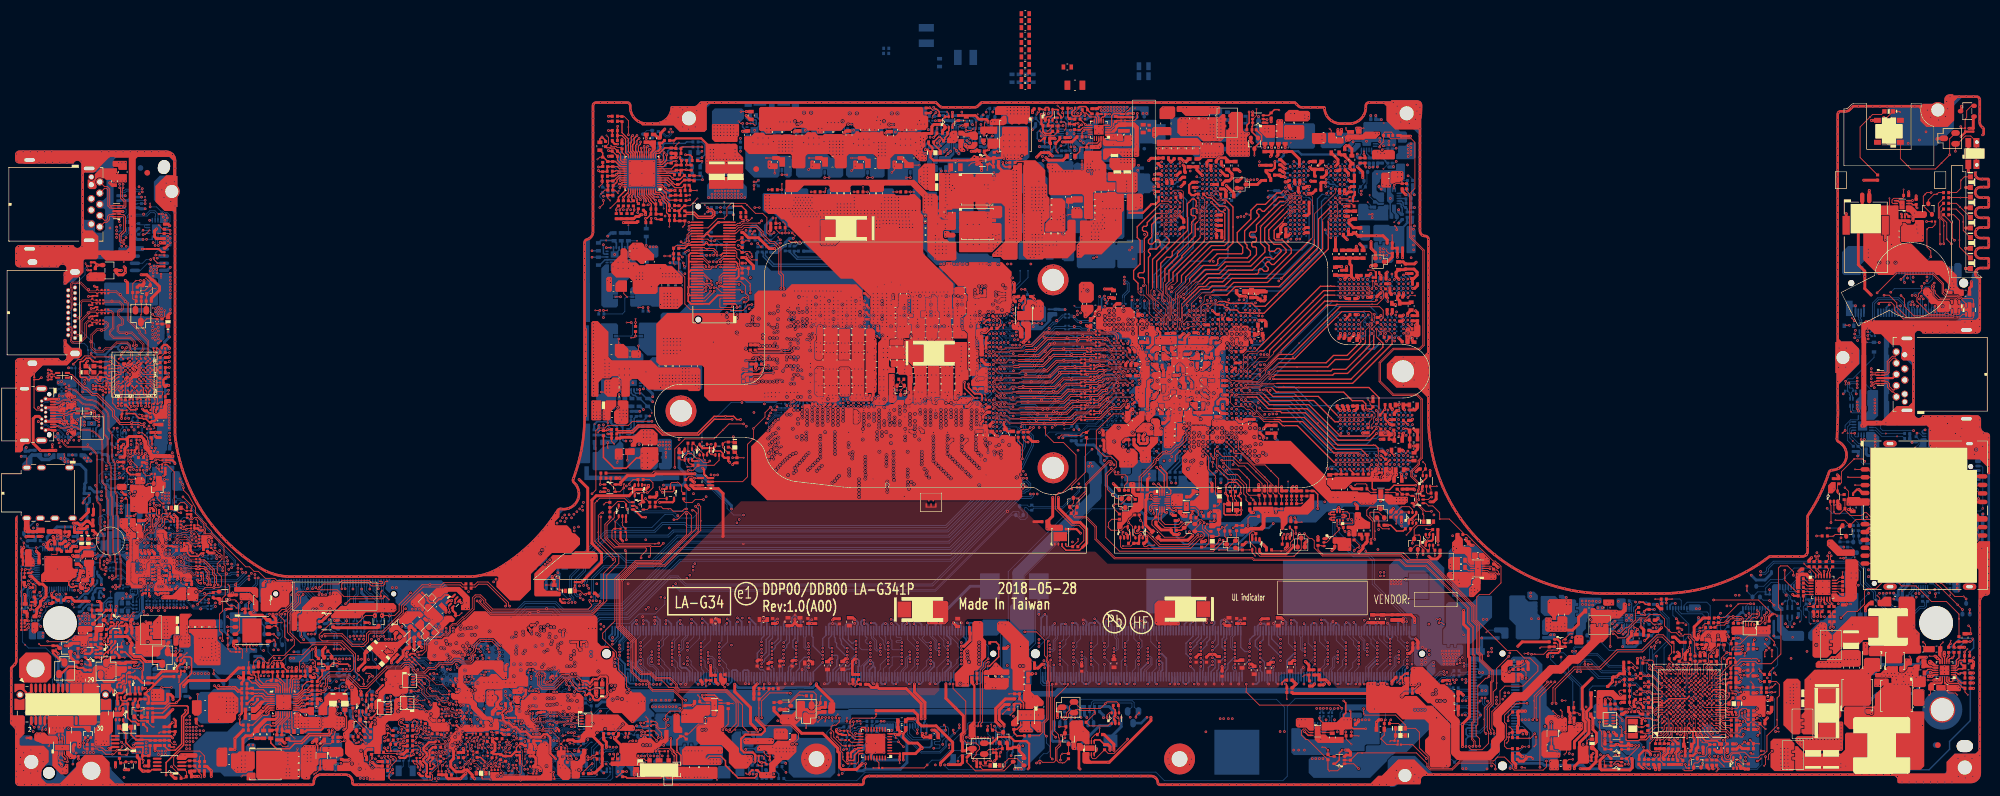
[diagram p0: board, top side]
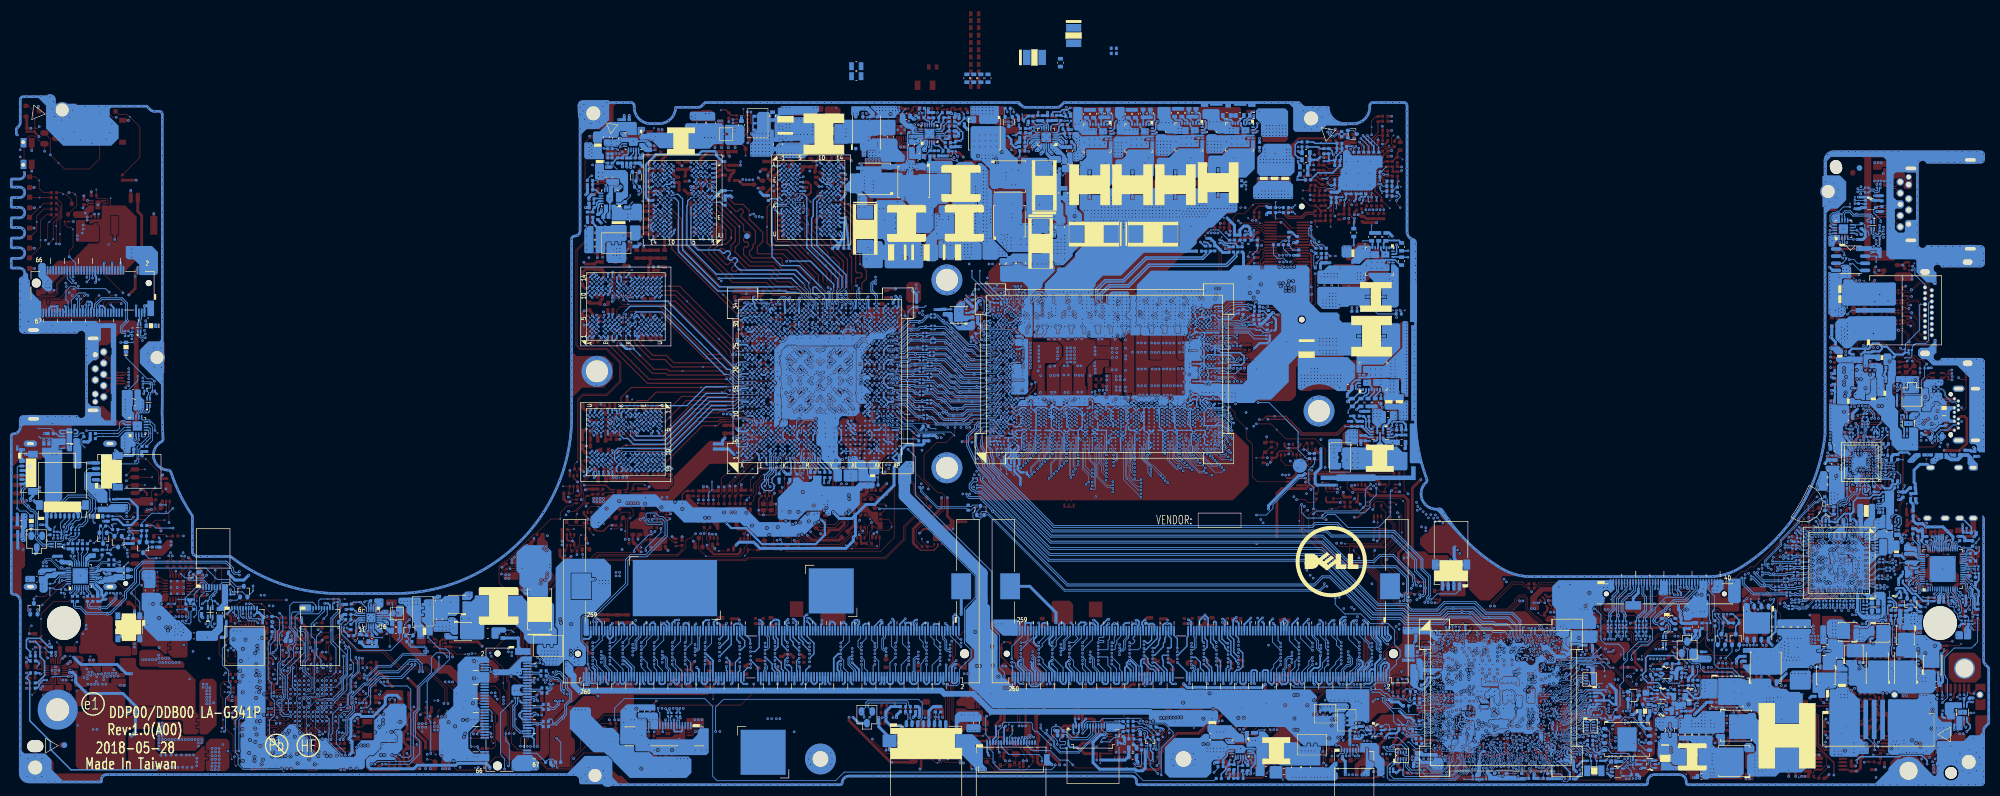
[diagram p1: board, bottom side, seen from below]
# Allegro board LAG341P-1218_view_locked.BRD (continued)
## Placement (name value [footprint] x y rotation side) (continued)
T20  -  [TPC12]  77.86 69.33 180 bottom
T39  -  [TPC12]  174.4 126.55 0 top
T40  -  [TPC12]  173.39 127.36 0 top
T41  -  [TPC12]  173.16 125.81 0 top
T42  -  [TPC12]  174.29 125.24 0 top
T43  -  [TPC12]  135.05 125.9 0 top
T44  -  [TPC12]  135.19 127.26 0 top
T45  -  [TPC12]  136.36 151.48 0 top
T46  -  [TPC12]  170.68 141.56 0 top
T47  -  [TPC12]  172.59 143.86 0 top
T48  -  [TPC12]  136.5 149.88 0 top
T49  -  [TPC12]  138.35 151.15 0 top
T50  -  [TPC12]  167.5 148.13 0 top
T51  -  [TPC12]  165.93 134.73 0 top
T52  -  [TPC12]  157.14 146.38 0 top
T53  -  [TPC12]  160.37 135.4 0 top
T57  -  [TPC12]  171.63 148.98 0 top
T58  -  [TPC12]  177.98 148.42 180 bottom
T59  -  [TPC12]  176.17 150.56 0 top
T60  -  [TPC12]  174.71 148.38 0 top
T61  -  [TPC12]  171.97 126.27 0 top
T62  -  [TPC12]  171.93 127.56 0 top
T63  -  [TPC12]  131.08 152.93 180 bottom
T64  -  [TPC12]  136.35 148.56 0 top
T65  -  [TPC12]  140.96 149.01 0 top
T66  -  [TPC12]  138.68 147.29 0 top
T67  -  [TPC12]  139.74 146.31 0 top
T82  -  [TPC12]  139.59 148.68 0 top
T83  -  [TPC12]  154.81 131.58 0 top
T84  -  [TPC12]  171.4 136.56 0 top
T85  -  [TPC12]  177.7 158.59 180 bottom
T86  -  [TPC12]  172.91 122.41 180 bottom
T87  -  [TPC12]  133.81 126.38 0 top
T88  -  [TPC12]  133.86 125.09 0 top
T89  -  [TPC12]  179.1 158.59 180 bottom
T90  -  [TPC12]  173.89 123.23 180 bottom
T91  -  [TPC12]  66.57 87.33 180 bottom
T92  -  [TPC12]  67.98 88.24 180 bottom
T94  -  [TPC12]  66.09 89.51 180 bottom
T121  -  [TPC12]  88.06 76.46 0 top
T124  -  [TPC12]  79.9 71.7 0 top
T185  -  [TPC12]  17.46 119.85 0 bottom
T191  -  [TPC12]  22.73 119.21 0 bottom
T192  -  [TPC12]  22.56 120.5 0 bottom
T193  -  [TPC12]  19.89 125.7 180 top
T194  -  [TPC12]  20.57 123.59 180 top
T196  -  [TPC12]  29.07 111.19 0 top
T197  -  [TPC12]  27.76 111.49 0 top
T198  -  [TPC12]  26.45 111.56 0 top
T199  -  [TPC12]  30.94 109.44 0 top
T201  -  [TPC12]  182.22 129.24 180 bottom
T202  -  [TPC12]  184.06 129.44 180 bottom
T203  -  [TPC12]  190.2 133.04 180 bottom
T204  -  [TPC12]  189.6 131.81 180 bottom
T205  -  [TPC12]  214.86 128.54 0 top
T210  -  [TPC12]  210.62 112.79 0 top
T4936  -  [TPC12]  25.07 135.23 0 top
T4937  -  [TPC12]  23.71 135.76 0 top
T4943  -  [TPC12]  67.22 91.56 180 bottom
T4944  -  [TPC12]  67.22 90.25 180 bottom
T4945  -  [TPC12]  82.07 72.32 0 top
T4947  -  [TPC12]  80.12 78.26 0 top
T4948  -  [TPC12]  294.32 80.37 180 bottom
T4949  -  [TPC12]  101.78 76.21 180 bottom
T4950  -  [TPC12]  90.17 87.04 0 top
T4951  -  [TPC12]  91.49 87.23 0 top
T4952  -  [TPC12]  95.61 87.41 0 top
T4953  -  [TPC12]  91.94 84.22 0 top
T4954  -  [TPC12]  90.68 84.56 0 top
T4955  -  [TPC12]  79.2 85.92 0 top
T4956  -  [TPC12]  80.49 85.97 0 top
T4957  -  [TPC12]  83.26 87.29 0 top
T4958  -  [TPC12]  81.79 86.76 0 top
T4959  -  [TPC12]  90.22 80.28 0 top
T4960  -  [TPC12]  91.08 81.26 0 top
T4961  -  [TPC12]  101.5 74.69 180 bottom
T4962  -  [TPC12]  80.39 83.29 0 top
T4963  -  [TPC12]  80.31 84.6 0 top
T4964  -  [TPC12]  90.73 85.87 0 top
T4965  -  [TPC12]  152.49 136.37 0 top
T4966  -  [TPC12]  152.65 146.61 0 top
T4967  -  [TPC12]  147.6 134.68 0 top
T4968  -  [TPC12]  145.67 135.03 0 top
T4969  -  [TPC12]  149.43 134.75 0 top
T4970  -  [TPC12]  146.82 135.74 0 top
T4971  -  [TPC12]  137.67 148.15 0 top
T4972  -  [TPC12]  134.49 149.03 0 top
T4973  -  [TPC12]  209.47 127.53 0 top
T4974  -  [TPC12]  209.03 123.04 180 bottom
T4975  -  [TPC12]  211.51 130.19 0 top
T4976  -  [TPC12]  208 124.62 0 top
T4977  -  [TPC12]  209.11 121.63 180 bottom
T4978  -  [TPC12]  209.47 129.16 0 top
T4979  -  [TPC12]  211.63 126 0 top
T4980  -  [TPC12]  205.3 124.71 0 top
T4982  -  [TPC12]  296.35 75.34 0 top
T4988  -  [TPC12]  85.55 77.73 0 top
T4989  -  [TPC12]  86.45 75.16 0 top
T4991  -  [TPC12]  197.02 146.11 0 top
T4992  -  [TPC12]  195.64 146.23 0 top
T4993  -  [TPC12]  198.12 135.17 0 top
T4994  -  [TPC12]  199.44 144.65 0 top
T4995  -  [TPC12]  208.04 126.51 0 top
T4996  -  [TPC12]  207.77 128.83 0 top
T5003  -  [TPC12]  86.86 80.18 90 top
T5004  -  [TPC12]  85.67 79.43 0 top
T5990  -  [TPC12]  74 86.84 0 top
T5991  -  [TPC12]  89.59 72.99 0 top
T5992  -  [TPC12]  89.41 78.08 0 top
T5994  -  [TPC12]  65.13 103.32 0 top
T5995  -  [TPC12]  63.8 103.32 0 top
T5996  -  [TPC12]  311.45 89.93 0 top
T5997  -  [TPC12]  310.18 89.93 0 top
T5998  -  [TPC12]  310.18 92.22 0 top
T5999  -  [TPC12]  311.71 87.9 0 top
T6000  -  [TPC12]  296.34 78.44 180 bottom
T6002  -  [TPC12]  85.52 73.81 0 top
T6003  -  [TPC12]  269.16 73.93 0 top
T6004  -  [TPC12]  273.86 80.41 0 top
TV3  -  [TPC12]  232.63 176.79 0 top
TV4  -  [TPC12]  206.13 177.12 0 top
TV5  -  [TPC12]  247.95 154.17 0 top
TV6  -  [TPC12]  246.29 126.07 0 top
U32  -  [NPCT750JAAYX_QFN32_5X5]  154.49 72.69 180 top
U33  -  [SLG4U41821VTR_STQFN20_2X3]  201.85 118.79 0 top
UA1  -  [ALC3266-CG_QFN56_7X7]  9 101.97 90 bottom
UA3  -  [APE8937GN2_DFN8_2X2]  3.6 78.93 180 bottom
UA4  -  [EM5209VF_DFN14_3X2]  6.05 72.74 0 top
UC1  -  [74AUP1G07GW_TSSOP5]  122.61 120.4 90 top
UE2  -  [AH1806-W-7_SC59-3]  345.01 186.97 90 top
UE3  -  [MEC5105_WFBGA_169P]  291.92 77.26 90 top
UE5  -  [74AUP1G07SE-7_SOT353-5]  304.58 70.06 0 top
UE6  -  [APE8937GN2_DFN8_2X2]  189.37 72.53 0 top
UE7  -  [74AUP1G07SE-7_SOT353-5]  120.69 125.81 0 top
UF1  -  [LNG2DMTR_LGA12_2X2]  235.13 114.19 180 top
UH1  -  [CFL-H_BGA_1440P-T]  175.85 126.93 270 bottom
UH2  -  [CNP-H_BGA_874P-T]  96.83 93.91 180 bottom
UH7  -  [MC74VHC1G08DFT2G_SC70-5]  65.2 70 270 bottom
UH8  -  [W25Q256FVEIG_WSON8]  66.54 77.11 270 bottom
UH14  -  [MC74VHC1G08DFT2G_SC70-5]  57.53 70.13 90 bottom
UI1  -  [TPS2546RTER_QFN16_3X3]  24.8 164.46 180 bottom
UI2  -  [TPS2546RTER_QFN16_3X3]  328.33 129.41 180 bottom
UI3  -  [PS8713BTQFN24GTR2_TQFN24_4X4]  318.44 103.48 270 top
UI4  -  [MC74VHC1G32DFT2G_SC70-5]  19.23 170.45 270 bottom
UI5  -  [MC74VHC1G32DFT2G_SC70-5]  322.48 118.45 0 top
UM1  -  [PS175HDMBGA64GTR2-A0_TFBGA_64P]  22.92 137.3 180 top
UM2  -  [W25X20CLSNIG_SO8]  25.37 162.45 270 bottom
UN3  -  [APE8937GN2_DFN8_2X2]  335.7 169.55 90 top
UR1  -  [RTS5242-GR_QFN32_4X4]  339.14 102.24 90 bottom
UT1  -  [ALPINE-RIDGE_BGA_337P]  19.74 111.65 270 bottom
UT2  -  [W25Q80DVZPIG_WSON8]  37.39 98.85 0 bottom
UT4  -  [TPS65982_BGA_96P]  18.38 122.07 0 bottom
UT5  -  [W25Q80DVZPIG_WSON8]  38.07 96.46 270 top
UV16  -  [AP2330W-7_SC59-3]  16.87 158.64 270 top
UV18  -  [N15P-GT_BGA_908P]  219.8 125.29 90 bottom
UV19  -  [MC74VHC1G08DFT2G_SC70-5]  224.38 111.02 0 top
UV20  -  [TC7SH08FU_SSOP5]  195.54 111.12 0 top
UV23  -  [H5GQ1H24AFR-T2L_BGA_170P]  225.38 164.77 0 bottom
UV24  -  [H5GQ1H24AFR-T2L_BGA_170P]  212.92 177.57 180 bottom
UV25  -  [H5GQ1H24AFR-T2L_BGA_170P]  234.28 133.3 270 bottom
UV26  -  [H5GQ1H24AFR-T2L_BGA_170P]  247.08 147.03 90 bottom
UV28  -  [MC74VHC1G08DFT2G_SC70-5]  170.02 178.8 270 top
UV29  -  [TC7SH08FU_SSOP5]  220.28 110.82 180 top
UZ1  -  [EM5209VF_DFN14_3X2]  260.15 104.41 90 top
UZ4  -  [APE8937GN2_DFN8_2X2]  54.2 73.44 180 top
UZ5  -  [APE8937GN2_DFN8_2X2]  338.56 128.11 90 bottom
UZ6  -  [MC74VHC1G32DFT2G_SC70-5]  234.49 71.52 90 top
UZ8  -  [SY6288C20AAC_SOT23-5]  53.08 97.11 270 top
UZ9  -  [TPS22961DNYR_WSON8]  180.12 149.77 90 bottom
UZ12  -  [MC74VHC1G08DFT2G_SC70-5]  116.12 119.96 180 top
UZ15  -  [TPS22961DNYR_WSON8]  179.33 151.96 180 top
UZ16  -  [TPS22961DNYR_WSON8]  183.86 109.92 0 top
UZ19  -  [MC74VHC1G08DFT2G_SC70-5]  118.02 124.93 0 top
UZ20  -  [MC74VHC1G08DFT2G_SC70-5]  110.43 120.47 180 top
UZ21  -  [MC74VHC1G08DFT2G_SC70-5]  108.77 117.4 270 top
UZ22  -  [MC74VHC1G08DFT2G_SC70-5]  123.48 125.81 0 top
UZ23  -  [MC74VHC1G08DFT2G_SC70-5]  103.75 120.56 270 top
UZ24  -  [APE8937GN2_DFN8_2X2]  206.16 117.37 270 top
UZ25  -  [APE8937GN2_DFN8_2X2]  11.75 132.51 0 bottom
UZ26  -  [MC74VHC1G08DFT2G_SC70-5]  106.28 114.92 0 top
UZ29  -  [APE8937GN2_DFN8_2X2]  124.38 80.66 90 top
UZ30  -  [APE8937GN2_DFN8_2X2]  242.96 118.14 90 top
UZ31  -  [MC74VHC1G08DFT2G_SC70-5]  249.41 117.22 90 top
UZ32  -  [APE8937GN2_DFN8_2X2]  273.22 77.38 180 top
UZ33  -  [APE8937GN2_DFN8_2X2]  229.52 77.41 270 top
YE1  -  [Y_CM7V-12520_2P]  286.69 75.86 90 top
YH1  -  [Y_CM31532768DZFT_2P]  67.13 69.61 0 bottom
YH2  -  [Y_8Y24000034_4P]  103.34 83.65 90 top
YM1  -  [Y_8Y24000034_4P]  11.5 140.51 0 top
YT1  -  [Y_8Y24000034_4P]  18.97 99.46 270 bottom
YV1  -  [Y_8Y24000034_4P]  216.21 117.08 180 top

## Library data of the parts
ADP100 = ACES_50290-00701-001_7P-T
BAT100 = ACES_50290-01201-P01_12P-T
C2 C4 C135 C280 C1031 C1080 C3003 C3004 C3319 CA1 CA3 CA5 CA8 CA10 CA12 CA16 CA17 CA19 CA23 CA24 CA26 CA28 CA32-CA38 CA40 CA120-CA122 CA124-CA127 CA130 CD3324 CD3325 CE75 CE84 CE85 CH200 CH203-CH205 CH207 CH3320-CH3324 CH3329 CH3331-CH3333 CM1 CM3-CM8 CM10-CM22 CM24-CM26 CM28-CM33 CM35 CM37-CM41 CM45 CM46 CM50 CT25 CT141-CT143 CT145 CT163 CT174-CT187 CV818-CV849 CV857 CV858 CV925 CV928 CV987 CV990 CZ100 CZ101 CZ2157 PC218 PC221 PC502 PC505 PC902 PC1601 PC2004-PC2009 PC2029-PC2038 PC2042-PC2085 = C_0201
C3 C267 C1033 C1079 C3005 C3320 C3321 CA2 CA4 CA6 CA7 CA9 CA11 CA13-CA15 CA18 CA20 CA21 CA25 CA27 CA29-CA31 CA39 CA41-CA45 CA77 CA78 CA119 CA128 CA129 CA131 CD3326-CD3328 CE2 CE72-CE74 CE77-CE82 CE1501 CE3319 CE3321-CE3323 CH92 CH201 CH202 CH206 CH3327 CH3334 CI3-CI8 CI16 CI20-CI22 CM2 CM9 CM23 CM27 CM34 CM43 CM44 CT144 CT146 CT151 CT152 CT158-CT160 CT189 CV499 CV794 CV796 CV817 CV850-CV856 CV859 CV860 CV862 CV865 CV866 CV871 CV874-CV877 CV885-CV894 CV898-CV906 CV917-CV923 CV926 CV927 CV929-CV936 CV948-CV957 CV969-CV986 CV988 CV989 CV991-CV998 CV1010-CV1019 CV1031-CV1048 CV1050 CV1051 CZ96-CZ99 CZ104-CZ106 CZ588 CZ1501 CZ2155 CZ2156 PC106-PC110 PC114 PC115 PC200 PC204-PC210 PC212-PC217 PC219 PC222 PC223 PC401-PC405 PC407 PC408 PC415 PC416 PC418 PC500 PC501 PC506 PC511 PC512 PC603 PC604 PC609 PC612-PC614 PC700 PC701 PC704-PC707 PC709-PC716 PC725 PC800 PC801 PC804-PC806 PC810 PC900 PC901 PC905 PC906 PC911 PC912 PC1003-PC1005 PC1015 PC1017 PC1018 PC1030-PC1041 PC1045 PC1046 PC1049 PC1050 PC1054 PC1055 PC1100-PC1131 PC1133-PC1137 PC1205-PC1207 PC1209 PC1222 PC1225 PC1226 PC1233 PC1234 PC1251 PC1252 PC1258 PC1262 PC1263 PC1269 PC1501 PC1504 PC1508 PC1510 PC1511 PC1515-PC1518 PC1520 PC1522 PC1531 PC1532 PC1600 PC1603 PC1605 PC1606 PC1611 PC1612 PC1701 PC1702 PC1704 PC1709 PC1710 PC1714 PC1800 PC1802 PC1804 PC1910-PC1912 PC1923-PC1925 PC1927 PC1928 PC1932-PC1945 = C_0402
CD1-CD4 CD12 CD16-CD18 CD69 CD74-CD79 = C_0402: room: DIMMA
CD5-CD10 CD13-CD15 CD70-CD73 = C_0603: room: DIMMA
CD11 = C_EEFSS0D221R: room: DIMMA
CD19-CD22 CD29-CD32 CD34 CD35 CD80-CD83 = C_0402: room: DIMMB
CD23-CD28 CD84-CD90 = C_0603: room: DIMMB
CD33 = C_EEFSS0D221R: room: DIMMB
CD36 = C_0603: room: NGFF SSD
CD37-CD46 CD51 CD53 = C_0402: room: NGFF SSD
CE11 = C_0201: room: TPM
CE15 CE16 = C_0201: room: LID
CE17 CE18 CE20 CE23-CE27 CE29-CE39 CE42 CE44 CE48 CE51 CE70 CE71 = C_0402: room: EC5085
CE19 CE22 CE40 = C_0603: room: EC5085
CE41 CE45-CE47 CE49 CE50 CE52 CE68 CE69 = C_0402: room: THERMAL
CE43 = C_0201: room: EC5085
CE65 = C_0402: room: TOUCH PAD
CE66 CE67 = C_0402: room: FAN
CE76 CE83 CT147-CT150 CT153 CT157 CT164 CT165 CT188 CV798 CV861 CV863 CV864 CV867-CV870 CV872 CV873 CV878-CV884 CV895-CV897 CV907 CV924 CV937-CV947 CV958-CV968 CV999-CV1009 CV1020-CV1030 CZ2154 PC201 PC202 PC211 PC220 PC335 PC400 PC406 PC409-PC411 PC414 PC417 PC419 PC503 PC504 PC513 PC600-PC602 PC605-PC607 PC610 PC611 PC615 PC702 PC703 PC708 PC723 PC724 PC802 PC803 PC807-PC809 PC903 PC904 PC913 PC1006-PC1014 PC1016 PC1022-PC1029 PC1047 PC1048 PC1051-PC1053 PC1056-PC1070 PC1132 PC1208 PC1210 PC1216 PC1217 PC1227-PC1230 PC1257 PC1259-PC1261 PC1268 PC1270-PC1272 PC1502 PC1503 PC1507 PC1512-PC1514 PC1519 PC1521 PC1523-PC1528 PC1602 PC1604 PC1607-PC1610 PC1613 PC1705-PC1708 PC1713 PC1715-PC1717 PC1801 PC1803 PC1900-PC1908 PC1913-PC1922 PC1926 PC1929-PC1931 PC2000 PC2003 PC2010 PC2012-PC2018 PC2021-PC2027 PC2039-PC2041 PC2086-PC2153 = C_0603
CF1 = C_0603: room: HDD FFS
CF2 = C_0402: room: HDD FFS
CH3 CH100 CH101 CH174 CH175 CH197 CZ47 CZ49 CZ82 CZ86 CZ88 = C_0402: room: CPU
CH5-CH36 = C_0201: room: CPU
CH44 CH196 = C_0201: room: RTC
CH45-CH48 CH50 CH51 CH70 CH80 CH82 CH179 CH180 CH183 CH187-CH192 = C_0201: room: PCH
CH52 CH53 CH176-CH178 CH181 CH182 CH184 CH198 = C_0402: room: PCH
CH102-CH128 = C_0402: room: CPU_DECAP
CH129-CH132 CH134 CH135 = C_0603: room: CPU_DECAP
CH133 = C_0201: room: CPU_DECAP
CH136 CH138 = C_0805: room: CPU_DECAP
CI1 CI13 = C_0402: room: USB1
CI2 CI19 = C_0402: room: USB2
CI9 CI10 = C_0201: room: USB1
CI11 = C_0805: room: USB1
CI12 = C_0603: room: USB1
CI17 = C_0805: room: USB2
CI18 = C_0603: room: USB2
CLRP1 = SHORTPADS: User Part Number: PART#; room: PCH
CN1 CN6 = C_0603: room: NGFF WLAN
CN2 CN7 CN8 CN22 = C_0402: room: NGFF WLAN
CN9 CN20 CN21 = C_0201: room: NGFF WLAN
CR1 CR2 CR5 CR8 CR11 CR15 = C_0201: room: CARD READER
CR3 CR7 CR9 CR10 CR12 CR13 CR16 CR18 = C_0402: room: CARD READER
CR4 CR6 CR14 CR17 = C_0603: room: CARD READER
CS12-CS14 = C_0402: room: HDD
CS15 = C_0603: room: HDD
CS17-CS20 = C_0201: room: HDD
CT1-CT8 CT17-CT24 CT26 CT29-CT44 CT47 CT50 CT52 CT62-CT68 CT71 CT72 CT74 CT80-CT86 CT93 CT94 CT99-CT103 CT107 CT108 = C_0201: room: THUNBERBOLT
CT53-CT56 CT95-CT98 CT120-CT123 = C_0402: room: THUNBERBOLT
CT88-CT90 = C_0603: room: THUNBERBOLT
CV156 CV168 CV169 = C_0402: room: EDP
CV157 = C_0603: room: EDP
CV158-CV167 = C_0201: room: EDP
CV178 CV180-CV182 = C_0201: room: HDMI
CV179 = C_0402: room: HDMI
CV183 CV184 = C_0402: room: CAMERA
CZ4 CZ6 CZ8 CZ9 CZ11 CZ12 = C_0603: room: 3V_5V_DC_DC
CZ18-CZ20 = C_0402: room: PCH_DC_DC
CZ26 CZ29 CZ31 = C_0402: room: CAMERA_CR_DC_DC
CZ28 = C_0402: room: CPU_DC_DC
CZ37 CZ39 = C_0603: room: HDD_DC_DC
CZ41 = C_0201: room: EDP_DC_DC
CZ43 CZ44 = C_0402: room: EDP_DC_DC
CZ45 CZ46 = C_0402: room: HDD_DC_DC
D18 D74 = ESD101-B1-02ELS_TSSLP-2-4-2
D123 D124 D323 D324 = ESD8011MUT5G_X3DFN2-2
D125 D126 DT175-DT182 = AZ5B25-01F_DFN0603P2Y2
D321 DA56 DA57 DH1 DH2 DI1 DI14-DI16 DT28 DT29 DV14 DV15 DZ59 = RB751S40T1G_SOD523-2
D322 DA7 DA14 PD100 = AZ5125-01HPR7G_SOD523-2
DA2-DA5 DA9 = AZ5123-01FPR7G_DFN1006P2X2
DE4 DE5 = PESD5V0U2BT_SOT23-3: room: TOUCH PAD
DE7 DE8 = RB751S40T1G_SOD523-2: room: FAN
DE9 PD101 PD102 = TVNST52302AB0_SOT523-3
DI3 = AZ5125-02SPR7G_SOT23-3
DI7 = AZ1045-04F_DFN2510P10E-10-9: room: USB1
DI9 = AZ1045-04F_DFN2510P10E-10-9: room: USB2
DI12 DV13 DV16 = BAT54CW-7-F_SOT323-3
DI13 DI17 DT12-DT27 MD3 MD4 = ESD108-B1-CSP0201_WLL-2-1-2
DL1 = AZ5125-02SPR7G_SOT23-3: room: BATTERY LED
DN1 DN2 = RB751S40T1G_SOD523-2: room: NGFF WLAN
DN3 = BAT54CW-7-F_SOT323-3: room: NGFF WLAN
DT10 = PESD24VS2UT_SOT23-3
DT174 = BZT52C15LP-7_DFN1006-2
DV1 DV2 = BAT54CW-7-F_SOT323-3: room: EDP
DV7 = BAT54CW-7-F_SOT323-3: room: EDP_DC_DC
DV12 = IP4220CZ6_SC-74-6
FD1-FD4 = FIDUCIAL_C40M80: room: ETY-ROOM
FD5 FD6 = FIDUCIAL_C40M80
H1 H2 = H_2P3: room: ETY-ROOM
H5 H45 H46 = H_3P9
H9 H10 = H_2P5: room: ETY-ROOM
H11 = H_2P1N: room: ETY-ROOM
H12 = H_6P0N: room: ETY-ROOM
H16 = H_3P9: room: ETY-ROOM
H17 = H_2P1X2P5N: room: ETY-ROOM
H23-H25 = EMIST_SUL-12A2M_1P: room: ETY-ROOM
H37 H38 = H_3P2
H39 H40 = H_2P5
H41 H42 = H_2P8
H43 H49 = H_2P3
H47 = H_6P0N
H48 = H_4P1
H50 = CLIP_C6-PM
H54 H55 = CLIP_C5P5-NPM
H59 = H_2P9X2P1N
JAPS = ACES_50506-01841-P01_18P: room: CPU
JAUDIO = ACES_88028-3010M_30P
JCR = T-SOL_156-1051902601_19P-T: room: CARD READER
JDEG1 JLPDE1 = ACES_50521-01041-P01_10P: room: EC5085
JDIMM1 = BELLW_SD-80886-1021_260P-T: room: DIMMA
JDIMM2 = BELLW_SD-80886-1021_260P-T: room: DIMMB
JEDP1 = ACES_59003-04006-001_40P: room: EDP
JFAN1 JFAN2 = ACES_50224-00401-001_4P: room: FAN
JFP = ACES_50521-00841-P01_8P-T
JHDD = J-L_UCNR2234B020-0_20P: room: HDD
JHDMI1 = ACON_HMRB9-AK120C_19P: room: HDMI
JHP1 = YUQIU_PJ567-F07J1BE-C_6P
JKB = E-T_6710K-Y15M-31L_15P: room: ETY-ROOM
JNGFF1 = CONCR_213AAAA32FA_67P: room: NGFF WLAN
JNGFF2 = CONCR_213MAAA32FA_67P-T: room: NGFF SSD
JRTC = E-T_3806K-F02N-03R_2P: room: RTC
JSPI1 = ACES_50521-01041-P01_10P
JTAG1 = SHORTPADS: User Part Number: PART#; room: EC5085
JTP = ACES_51524-0080N-001_8P: room: TOUCH PAD
JTS = ACES_50208-00601-P01_6P
JTS1 = ACES_50208-00801-003_8P
JUSB1 = TAIWI_USB019-107CRL-TWD_10P-T: room: USB1
JUSB2 = TAIWI_USB019-107CRL-TWD_10P-T: room: USB2
JUSBC1 = JAE_DX07S024XJ2_24P-T: room: THUNBERBOLT
JXDP = SAMTE_BSH-030-01-L-D-A_60P: room: CPU
LA1 LA3 = MURAT_BLM15PX600SN1D_2P
LA2 = MURAT_BLM21PG600SN1D_L0805_2P
LA4 = MURAT_BLM15BB220SN1D_2P
LA5-LA8 = MURAT_BLM15AX700SN1D_2P
LED1-LED5 = LED_LTW-270TLA_2P: room: BATTERY LED
LED6 = LED_HT-F196BP5_2P
LH1-LH4 = MURAT_BLM15PX221SN1D_2P
LI1 = INPAQ_MCM1012B900F06BP_4P
LI2 = INPAQ_MCM1012B900F06BP_4P: room: USB2
LI5 = INPAQ_MCM1012B900F06BP_4P: room: USB1
LM1-LM5 LT14 LV23 = CHILI_PBY160808T-300Y-N_2P
LN1 = INPAQ_MCM1012B900F06BP_4P: room: NGFF WLAN
LT1 = MAG_MLV-YT10NR68N-M1L_2P: room: THUNBERBOLT
LT12 LT13 ML17 = CHILI_CMMI21T-900Y-N_4P
LV22 = INPAQ_MCM1012B900F06BP_4P: room: CAMERA
LV24 = KC_FBMA-L11-160808300LMA25T_2P
PC203 PC507-PC510 PC717 PC719 PC721 PC722 PC907-PC910 PC1000 PC1001 PC1042 PC1043 PC1203 PC1204 PC1223 PC1224 PC1231 PC1232 PC1254 PC1256 PC1264 PC1265 PC1505 PC1509 PC1700 PC1703 PC1711 PC1712 = C_0805
PC412 PC413 PC456 PC718 PC1019-PC1021 PC1529 PC1530 PC2020 = C_B2
PC420 PC1202 PC1909 = C_D
PC608 = C_D1
PC1211 PC1214 = C_B3
PC2001 PC2002 PC2019 = C_D2E
PC2011 PC2028 = C_EEFSS0D221R
PD200 PD201 = PDS1040-13_POWERDI5-3
PD202 PD1900 PD1902 = RB751V-40_SOD323-2
PD203 PD204 = RB520SM-30T2R_EMD2-2
PD1903 = BAT54CW_SOT323-3
PD1904 = SMF22A-SOD123FL-2-S
PH1100-PH1104 PR100-PR106 PR108 PR111 PR112 PR200-PR209 PR211 PR212 PR217 PR219 PR220 PR222 PR224-PR237 PR240 PR241 PR244-PR249 PR251 PR254 PR255 PR257 PR259 PR261 PR263 PR265 PR267 PR270 PR273 PR274 PR276 PR277 PR279 PR280 PR282 PR283 PR285 PR326 PR401-PR406 PR410 PR428 PR500 PR503 PR504 PR507 PR601 PR604 PR605 PR607 PR609 PR610 PR704 PR705 PR707 PR711 PR715 PR804-PR809 PR818 PR819 PR839 PR840 PR904-PR909 PR951 PR1000-PR1002 PR1004-PR1008 PR1011 PR1013 PR1014 PR1016 PR1019 PR1022 PR1023 PR1100 PR1103-PR1107 PR1109 PR1111-PR1113 PR1115-PR1117 PR1119 PR1120 PR1122 PR1123 PR1127 PR1131 PR1134-PR1146 PR1148 PR1149 PR1153 PR1154 PR1157-PR1171 PR1174-PR1176 PR1202 PR1206 PR1253 PR1257 PR1500-PR1502 PR1505 PR1507-PR1509 PR1511 PR1514-PR1516 PR1519 PR1521 PR1522 PR1603-PR1606 PR1608 PR1643 PR1702 PR1800 PR1803 PR1804 PR1904 PR1906 PR1908 PR1911 PR1912 PR1918 PR1920 PR1923-PR1927 PR1931 PR1934-PR1936 PR1938 PR1942 PR1943 R3 R5831 R5832 R5842 R5843 RA19-RA21 RA27-RA31 RA51 RA52 RA75 RA93 RA95 RA100-RA103 RC183 RC184 RC5835 RD59 RD100 RD101 RE94-RE96 RE99 RE110 RE111 RE126 RE136 RE137 RE142 RE143 RE145 RE183 RE255 RE273-RE275 RE283-RE286 RE290-RE301 RE303 RE306 RE307 RE309-RE311 RE322 RE323 RF5 RH42 RH539 RH544 RH546-RH551 RH557 RH561-RH567 RH571-RH573 RH576 RH597 RH599 RH1943 RH1958 RH5835-RH5838 RH5842 RH5856 RH5859-RH5861 RH5864 RH5865 RH5867 RH5868 RH5875 RH5876 RH5879 RH5880 RH5884 RI15-RI24 RI26-RI28 RI30 RI31 RI34-RI36 RI46 RL1-RL5 RM1-RM4 RM11-RM13 RM19 RM20 RM27 RM1834 RT191 RT242 RT1095 RT1133-RT1136 RT1139 RT5839 RT5840 RV8 RV11 RV12 RV103 RV111 RV112 RV325 RV326 RV550-RV554 RV557 RV561-RV564 RV566 RV567 RV570-RV582 RV587 RV589-RV594 RV600-RV602 RV605-RV608 RV613-RV620 RV623-RV625 RV631-RV636 RV639-RV657 RV1080 RV1082-RV1084 RV1086 RV1112 RV1128 RV1130-RV1133 RV1350 RV1807-RV1811 RV1833-RV1842 RV1844 RZ71 RZ72 RZ81 RZ82 RZ84 RZ86 RZ87 RZ106 RZ1133 RZ1141 RZ1142 RZ1149 RZ1153 RZ1951 RZ1952 RZ1954-RZ1958 RZ1964-RZ1966 = R_0402
PJP200 PJP400 PJP402 PJP403 PJP500 PJP600 PJP603 PJP701 PJP702 PJP801 PJP1600 = JUMP_43X118
PJP601 PJP900 = JUMP_43X39
PJP602 PJP1604 = JUMP_43X79
PJP1302 PJP1303 = JUMP_43X79: room: PCH
PL104 = MURAT_BLM15AG102SN1D_2P
PL105-PL108 PL200 PL201 PL402 PL403 PL500 PL601 PL777 PL801 PL900 PL1000 PL1001 PL1200 PL1201 PL1204 PL1501 PL1502 PL1600 PL1700 PL1701 PL1703 = TAI-T_HCB2012KF-121T50_2P
PL400 = CYNTE_PCMB063T-3R3MS_2P
PL401 = CYNTE_PCMB103T-2R2MS_2P
PL501 PL800 PL901 = CYNTE_PCMB053T-1R0MS_2P
PL600 = CYNTE_PCMB063T-1R0MS_2P
PL700 = L_7X7X3_M_2P
PL1002 PL1003 PL1500 = MAG_MMD-06DZIR22MEM2L_2P
PL1202 PL1203 PL1251 PL1252 PL1702 = L_7X7X4_M
PL1601 = L_2P5X2X1P2_F_2P
PL1704 = MAG_MMD05CZR47M_4P
PL1900 = MAGLA_MMD-05CZ-1R0M-M7L_2P
PL1901 = MAG_MMD-10DZ-1R0M-X1A_2P
PQ100 = FDV301N-G_SOT23-3
PQ101 QE15 = MMBT3904WH_SOT323-3
PQ200 PQ201 PQ207-PQ209 = FDMC6679AZ_MLP8-5
PQ202 PQ210 PQ211 = AO3409_SOT23-3
PQ203 PQ212-PQ216 QE18 QV3 QZ14 QZ15 QZ17 = DMN65D8LDW-7_SOT363-6
PQ204-PQ206 PQ217 PQ224 PQ225 PQ1906 QRTC1 = DMN65D8LW-7_SOT323-3
PQ219 QH3 QH5 = 2N7002KDW_SOT363-6
PQ220 PQ221 PQ223 PQ227 Q5 = DMN66D0LDW-7_SOT363-6
PQ222 PQ226 = SI1303DL-T1-E3_SOT323-3
PQ400 = AON7408L_DFN8-5
PQ401 PQ1900 PQ1902 PQ1904 = AON6380_DFN5X6-8-5
PQ402 = AON7506_DFN3X3-8-5
PQ403 = AON6796_DFN5X6-8-5
PQ600 = AON7406L_DFN8-5
PQ601 = AON7534_DFN3X3-8-5
PQ700 = AON6962_DFN5X6D-8-7
PQ701 = 2N7002DW-7-F_SOT363-6
PQ1000-PQ1003 PQ1007 PQ1008 PQ1500 PQ1501 = Q_N_DFN56-8-5
PQ1901 PQ1903 = AON6232A_DFN5X6-8-5
PQ1905 = AON7405_DFN8-5
PR210 PR213-PR216 PR218 PR221 PR223 PR238 PR239 PR242 PR243 PR250 PR252 PR253 PR256 PR258 PR260 PR262 PR268 PR269 PR272 PR278 PR284 PR400 PR407-PR409 PR415 PR501 PR521 PR606 PR608 PR651 PR717 PR802 PR803 PR838 PR841 PR900 PR902 PR903 PR910 PR952 PR1003 PR1017 PR1018 PR1021 PR1108 PR1110 PR1118 PR1124-PR1126 PR1130 PR1132 PR1172 PR1173 PR1503 PR1517 PR1518 PR1520 PR1600 PR1602 PR1607 PR1651 PR1801 PR1851 PR1909 PR1913 PR1917 PR1919 PR1921 PR1922 PR1928-PR1930 PR1932 PR1933 PR1937 PR1939-PR1941 PR1950 RA94 RD58 RE108 RE109 RE112 RE116 RE117 RE122 RE138 RE139 RE287 RE288 RE305 RH540-RH543 RH577-RH579 RI25 RI32 RI33 RI37-RI40 RT190 RT243 RV110 RZ91 = R0402_0OHM
PR266 PR289 RI45 = R0805_0OHM
PR271 PR275 PR288 PR290 PR295 PR505 PR506 PR508 PR701 PR703 PR708-PR710 PR712 PR713 PR718 R276 R277 R5841 RA4 RA6 RA7 RA12-RA17 RA57 RA68 RA82 RA96-RA99 RE100 RE101 RE113-RE115 RE125 RE321 RH200 RH545 RH552-RH555 RH568-RH570 RH590 RH1145 RH1146 RH1152 RH5832-RH5834 RH5840 RH5841 RH5844-RH5850 RH5853-RH5855 RH5857 RH5858 RH5869-RH5871 RH5881-RH5883 RH5889-RH5895 RM5-RM7 RM9 RM10 RM14 RM16-RM18 RM21 RM24-RM26 RM28 RM102 RM103 RM1145 RR41-RR45 RT164 RT167-RT171 RT183 RT186-RT189 RT194 RT199 RT202 RT207-RT209 RT226 RT227 RT232 RT233 RT245 RT429-RT432 RT435 RT437 RT1093 RT1141-RT1145 RT5836-RT5838 RT5842 RT5843 RT5847-RT5850 RT5855-RT5857 RV530-RV541 RV621 RV622 RV626-RV630 RV637 RV638 RV1095 RV1098 RZ1150 RZ1151 RZ1953 = R_0201
PR411 PR412 PR600 PR603 PR700 PR706 PR800 PR801 PR1010 PR1012 PR1015 PR1101 PR1147 PR1150-PR1152 PR1155 PR1156 PR1200 PR1201 PR1204 PR1205 PR1251 PR1252 PR1255 PR1256 PR1510 PR1513 PR1700 PR1701 PR1704 PR1705 PR1805 PR1901 PR1902 PR1905 PR1914 R281 RA73 RE304 RH585 RH1957 RH5866 RT1092 RV597 RV658 RV1068 = R_0603
PR413 PR414 PR502 PR602 PR702 PR901 PR1009 PR1020 PR1203 PR1207 PR1254 PR1258 PR1512 PR1601 PR1703 PR1706 PR1915 PR1916 = R_1206
PR1900 PR1910 = R_1206_4P-D
PR1903 RA2 RA18 RA74 RE104 RE105 RE129 RE141 RM15 RT113 RT241 RZ1136 RZ1138 RZ1148 RZ1960 = R0603_0OHM
PR1907 RI14 = R_0805
PT201 PT202 T124 T185 T191-T194 T196-T199 T201-T205 T210 T4936 T4937 T4943-T4945 T4947-T4980 T4982 T4988 T4989 T4991-T4996 T5003 T5004 T5990-T5992 T5994-T6000 T6002-T6004 TV3-TV6 = TPC12
PU200 PU203 = LM393DGKR_VSSOP8
PU201 PU202 PU1901 UV20 UV29 = TC7SH08FU_SSOP5
PU204 = RT9069-33GB_SOT23-5
PU400 = TPS51285BRUKR_QFN20_3X3
PU500 = SY8288RAC_QFN20_3X3
PU600 = G5616ARZ1U_TQFN20_3X3
PU700 = RT8812AGQW_WQFN20_3X3-S
PU800 = NB681AGD-Z_QFN13_2X3-SVR
PU900 PU1600 = SY8286RAC_QFN20_3X3
PU1001 PU1501 = RT8816AGQW_WQFN20_3X3
PU1100 = NCP81215MNTXG_QFN52_6X6
PU1200 PU1201 PU1251 PU1252 PU1700 PU1701 = NCP302035MNTXG_PQFN33_5X5
PU1800 = RT9059GQW_WDFN10_3X3
PU1900 = ISL88738HRTZ-T_TQFN32_4X4
Q4 Q6 QE20 QI10 QR1 QR104 QR105 QV89 QZ18 = L2N7002WT1G_SC-70-3
QE2 = DMN65D8LDW-7_SOT363-6: room: TOUCH PAD
QE4 = DMN65D8LDW-7_SOT363-6: room: EC5085
QE5-QE12 = MMBT3904WH_SOT323-3: room: THERMAL
QE13 = L2N7002WT1G_SC-70-3: room: TOUCH PAD
QF1 = DMN65D8LDW-7_SOT363-6: room: HDD FFS
QH1 QRTC = LP2301ALT1G_SOT23-3
QH4 = DMN65D8LDW-7_SOT363-6: room: PCH
QV11 = SI3457BDV-T1-E3_TSOP6: room: EDP
QV12 = L2N7002WT1G_SC-70-3: room: EDP
QV21 = DMN63D8LDW-7_SOT363-6
QV91 QV98 QV101-QV103 QV105 = 2N7002W-T-R7_SOT323-3
QZ6 = DMN65D8LDW-7_SOT363-6: room: GPU
QZ9 = DMG2301U-7_SOT23-3
RC5831-RC5834 = R_0201: signal model: R_0402_15_0402_5%
RD1-RD3 RD35 = R_0402: room: DIMMA
RD4 RD6 RD39 = R_0402: room: DIMMB
RD5 RD38 RD40 = R0402_0OHM: room: DIMMB
RD7-RD10 = R_0402: room: NGFF SSD
RD28-RD31 = R0402_0OHM: room: DIMMA
RE3 = R_0402: room: PWR LED
RE7 RE9 RE87 = R_0402: room: TOUCH PAD
RE16 = R0603_0OHM: room: EC5085
RE19-RE27 RE30-RE36 RE38 RE41 RE43-RE45 RE48 RE50 RE52 RE54-RE56 RE59-RE65 RE67 RE68 RE70 RE89 RE90 = R_0402: room: EC5085
RE39 RE51 = R0402_0OHM: room: EC5085
RE58 RE66 RE69 = R_0402: room: THERMAL
RE71 RE72 = R_0402: room: EC23017
RE81-RE84 = R_0201: room: FAN
RE86 = R_0201: room: TPM
RE133 RE313 RH580 RH581 RH586 RH5872 RH5873 RT176-RT178 RT181 RT182 RT184 RT185 RT195 RT200 RT201 RT244 RT433 RT5841 RT5844-RT5846 RV520-RV529 RV1843 = R0201_0OHM
RF1 = R0603_0OHM: room: HDD FFS
RF2-RF4 = R_0402: room: HDD FFS
RH2 RH24 RH59 RH148-RH150 RH156 RH158 RH165 RZ50 = R_0201: room: CPU
RH5 RH6 RH30 RH95 RH97 RH98 RH100 RH145 RH151-RH155 RH163 RH164 RH167 RH183-RH189 RH191 RH192 RH197 RH201 RH203 RH206 RH207 RH209-RH212 RH456 RH466 RH469 RH472 RH474 RH475 RH479-RH485 RH488-RH490 RH492-RH498 RH519 RH525 RH530 RZ59 RZ61 = R_0402: room: CPU
RH8 RH12 RH190 RH198 RH202 RH204 RH465 RH470 RH471 RH477 RH478 RH491 RZ60 = R0402_0OHM: room: CPU
RH67 = R_0402: room: RTC
RH70 RH71 RH77 RH82 RH85 RH109 RH119 RH120 RH130 RH309 RH383 RH453 RH503-RH506 RH510 RH515 RH518 RH523 RH524 RH527 RH528 RH533 RH535 RH537 = R_0402: room: PCH
RH72 RH74 RH75 RH78 RH83 RH84 RH91 RH108 RH110 RH146 RH147 RH401 RH423 RH428 RH454 RH458-RH463 RH487 RH501 RH502 RH508 RH511-RH513 RH516 RH529 RH531 RH536 = R_0201: room: PCH
RH96 = R0201_0OHM: room: PCH
RH133 = R0402_0OHM: room: PCH
RH168 = R_0201: signal model: R_0402_15_0402_5%; room: PCH
RH5839 = R_0201: signal model: R_0402_0_0402_5%
RI4-RI8 = R_0402: room: USB1
RI9-RI13 = R_0402: room: USB2
RN1 = R_0201: room: NGFF WLAN
RN33 = R_0402: room: NGFF WLAN
RP1 RP2 RP4 RP8 RP15 RP22 RP23 = RP_0804_8P4R: room: PCH
RP19 RP20 = RP_0804_8P4R: room: EC5085
RR1 RR9 = R_0201: room: CARD READER
RR2-RR5 RR7 RR8 = R0402_0OHM: room: CARD READER
RR6 = R_0402: room: CARD READER
RR10 = R0201_0OHM: room: CARD READER
RT1 RT2 RT5 RT10 = R_0402: room: THUNBERBOLT
RT3 RT4 RT6-RT9 RT12 RT15-RT18 RT21-RT23 RT25 RT33-RT45 RT107 = R_0201: room: THUNBERBOLT
RT46 = R_0603: room: THUNBERBOLT
RT5832-RT5835 = R0201_0OHM: signal model: R_0201_0_0201_5%
RV107 RV109 RV114 RV119 RV120 RV135 = R_0402: room: EDP
RV113 = R0201_0OHM: room: EDP
RV399 = R_0402: room: GPU
RZ18 = R0603_0OHM: room: PCH_DC_DC
RZ28 = R0603_0OHM: room: CAMERA_CR_DC_DC
RZ32 = R_0402: room: CAMERA_CR_DC_DC
RZ37 = R0603_0OHM: room: EDP_DC_DC
RZ38-RZ40 = R_0402: room: EDP_DC_DC
RZ41 = R_0402: room: PCH_DC_DC
RZ43 = R_0402: room: AUDIO_DC_DC
RZ46 = R_0402: room: HDD_DC_DC
RZ58 = R0201_0OHM: room: CPU
SW1 = SW_SKRBAAE010_4P: room: PWR LED
SW2 = SW_NTC311-EA1T-A160T_4P: room: BATTERY LED
SW4 = SW_SSAL120100_3P: room: PCH
SW_BOT = SW_SKRBAAE010_4P
T2 T4 T8 T17 T20 T91 T92 T94 T121 = TPC12: room: PCH
T39-T53 T57-T67 T82-T90 = TPC12: room: CPU
U32 = NPCT750JAAYX_QFN32_5X5
U33 = SLG4U41821VTR_STQFN20_2X3
UA1 = ALC3266-CG_QFN56_7X7
UA3 UZ24 UZ25 UZ29 UZ30 UZ32 UZ33 = APE8937GN2_DFN8_2X2
UA4 = EM5209VF_DFN14_3X2
UC1 = 74AUP1G07GW_TSSOP5: room: CPU
UE2 = AH1806-W-7_SC59-3: room: LID
UE3 = MEC5105_WFBGA_169P: room: EC5085
UE5 UE7 = 74AUP1G07SE-7_SOT353-5
UE6 = APE8937GN2_DFN8_2X2: room: TOUCH PAD
UF1 = LNG2DMTR_LGA12_2X2: room: HDD FFS
UH1 = CFL-H_BGA_1440P-T: room: CPU
UH2 = CNP-H_BGA_874P-T: room: PCH
UH7 UH14 = MC74VHC1G08DFT2G_SC70-5: room: PCH
UH8 = W25Q256FVEIG_WSON8: room: PCH
UI1 = TPS2546RTER_QFN16_3X3: room: USB1
UI2 = TPS2546RTER_QFN16_3X3: room: USB2
UI3 = PS8713BTQFN24GTR2_TQFN24_4X4: room: USB2
UI4 UI5 UZ6 = MC74VHC1G32DFT2G_SC70-5
UM1 = PS175HDMBGA64GTR2-A0_TFBGA_64P
UM2 = W25X20CLSNIG_SO8
UN3 = APE8937GN2_DFN8_2X2: room: NGFF WLAN
UR1 = RTS5242-GR_QFN32_4X4: room: CARD READER
UT1 = ALPINE-RIDGE_BGA_337P: room: THUNBERBOLT
UT2 = W25Q80DVZPIG_WSON8
UT4 = TPS65982_BGA_96P
UT5 = W25Q80DVZPIG_WSON8: room: THUNBERBOLT
UV16 = AP2330W-7_SC59-3: room: HDMI
UV18 = N15P-GT_BGA_908P
UV19 UV28 UZ19-UZ23 UZ26 UZ31 = MC74VHC1G08DFT2G_SC70-5
UV23-UV26 = H5GQ1H24AFR-T2L_BGA_170P
UZ1 = EM5209VF_DFN14_3X2: room: 3V_5V_DC_DC
UZ4 = APE8937GN2_DFN8_2X2: room: PCH_DC_DC
UZ5 = APE8937GN2_DFN8_2X2: room: CAMERA_CR_DC_DC
UZ8 = SY6288C20AAC_SOT23-5: room: EDP_DC_DC
UZ9 UZ16 = TPS22961DNYR_WSON8: room: CPU
UZ12 = MC74VHC1G08DFT2G_SC70-5: room: CPU
UZ15 = TPS22961DNYR_WSON8: room: CPU_DC_DC
YE1 = Y_CM7V-12520_2P: room: EC5085
YH1 = Y_CM31532768DZFT_2P: room: PCH
YH2 = Y_8Y24000034_4P: room: PCH
YM1 = Y_8Y24000034_4P
YT1 = Y_8Y24000034_4P: room: THUNBERBOLT
YV1 = Y_8Y24000034_4P: room: GPU

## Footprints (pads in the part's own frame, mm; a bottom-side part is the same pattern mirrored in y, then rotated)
2N7002DW-7-F_SOT363-6
  oval 0.432x0.61 smd: 1(0,0) 2(0.65,0) 3(1.3,0) 4(1.3,1.9) 5(0.65,1.9) 6(0,1.9)
2N7002KDW_SOT363-6
  oval 0.356x0.889 smd: 1(0,0) 2(0.65,0) 3(1.3,0) 4(1.3,1.6) 5(0.65,1.6) 6(0,1.6)
2N7002W-T-R7_SOT323-3
  oval 0.813x0.914 smd: 1(0,0) 2(0.65,1.6) 3(-0.65,1.6)
74AUP1G07GW_TSSOP5
  oval 0.381x1.346 smd: 1(0,0) 2(0.65,0) 3(1.3,0) 4(1.3,1.79) 5(0,1.79)
74AUP1G07SE-7_SOT353-5
  oval 0.432x0.61 smd: 1(0,0) 2(0.65,0) 3(1.3,0) 4(1.3,1.9) 5(0,1.9)
ACES_50208-00601-P01_6P
  oval 0.508x0.991 smd: 1(0,0) 2(-0.8,0) 3(-1.6,0) 4(-2.4,0) 5(-3.2,0) 6(-4,0)
  rect 1.194x1.702 smd: 7(-5.3,-1.95) 8(1.3,-1.95)
ACES_50208-00801-003_8P
  oval 0.508x0.991 smd: 1(0,0) 2(-0.8,0) 3(-1.6,0) 4(-2.4,0) 5(-3.2,0) 6(-4,0) 7(-4.8,0) 8(-5.6,0)
  rect 1.194x1.702 smd: 9(1.3,-1.95) 10(-6.9,-1.95)
ACES_50224-00401-001_4P
  oval 0.61x1.549 smd: 1(0,0) 2(1,0) 3(2,0) 4(3,0)
  rect 1.194x1.803 smd: 5(4.3,-3.875) 6(-1.3,-3.875)
ACES_50290-00701-001_7P-T
  rect 0.838x7.01 smd: 1(0,0) 2(1.5,0) 3(3,0) 4(4.5,0) 5(6,0) 6(7.5,0) 7(9,0)
ACES_50290-01201-P01_12P-T
  rect 0.838x7.01 smd: 1(0,0) 2(1.5,0) 3(3,0) 4(4.5,0) 5(6,0) 6(7.5,0) 7(9,0) 8(10.5,0) 9(12,0) 10(13.5,0) 11(15,0) 12(16.5,0)
ACES_50506-01841-P01_18P
  oval 0.305x0.889 smd: 1(0,0) 2(0.5,0) 3(1,0) 4(1.5,0) 5(2,0) 6(2.5,0) 7(3,0) 8(3.5,0) 9(4,0) 10(4.5,0) 11(5,0) 12(5.5,0) 13(6,0) 14(6.5,0) 15(7,0) 16(7.5,0) 17(8,0) 18(8.5,0)
  rect 0.991x2.007 smd: 19(-2.1,-3.05) 20(10.6,-3.05)
ACES_50521-00841-P01_8P-T
  oval 0.305x1.092 smd: 1(0,0) 2(-0.5,0) 3(-1,0) 4(-1.5,0) 5(-2,0) 6(-2.5,0) 7(-3,0) 8(-3.5,0)
  rect 0.406x0.787 smd: 9(-4.5,-2.65) 10(1,-2.65)
ACES_50521-01041-P01_10P
  oval 0.305x0.787 smd: 1(0,0) 2(0.5,0) 3(1,0) 4(1.5,0) 5(2,0) 6(2.5,0) 7(3,0) 8(3.5,0) 9(4,0) 10(4.5,0)
  rect 0.406x0.787 smd: 11(-1,-2.5) 12(5.5,-2.5)
ACES_51524-0080N-001_8P
  oval 0.61x1.295 smd: 1(0,0) 2(1,0) 3(2,0) 4(3,0) 5(4,0) 6(5,0) 7(6,0) 8(7,0)
  rect 2.489x2.21 smd: 9(10,-3.05) 10(-3,-3.05)
ACES_59003-04006-001_40P
  round 0.889 hole 0.889 unplated: (-20.25,2.125) (0.75,2.125)
  oval 0.254x1.143 smd: 1(0,0) 2(-0.5,0) 3(-1,0) 4(-1.5,0) 5(-2,0) 6(-2.5,0) 7(-3,0) 8(-3.5,0) 9(-4,0) 10(-4.5,0) 11(-5,0) 12(-5.5,0) 13(-6,0) 14(-6.5,0) 15(-7,0) 16(-7.5,0) 17(-8,0) 18(-8.5,0) 19(-9,0) 20(-9.5,0) 21(-10,0) 22(-10.5,0) 23(-11,0) 24(-11.5,0) 25(-12,0) 26(-12.5,0) 27(-13,0) 28(-13.5,0) 29(-14,0) 30(-14.5,0) 31(-15,0) 32(-15.5,0) 33(-16,0) 34(-16.5,0) 35(-17,0) 36(-17.5,0) 37(-18,0) 38(-18.5,0) 39(-19,0) 40(-19.5,0)
  rect 1.499x2.997 smd: 41(-22,2.125) 42(2.5,2.125)
  rect 2.794x1.499 smd: 43(-15.45,4.175) 44(-4.05,4.175)
ACES_88028-3010M_30P
  oval 0.508x1.6 smd: 1(0,0) 2(0,-5.8) 3(0.8,0) 4(0.8,-5.8) 5(1.6,0) 6(1.6,-5.8) 7(2.4,0) 8(2.4,-5.8) 9(3.2,0) 10(3.2,-5.8) 11(4,0) 12(4,-5.8) 13(4.8,0) 14(4.8,-5.8) 15(5.6,0) 16(5.6,-5.8) 17(6.4,0) 18(6.4,-5.8) 19(7.2,0) 20(7.2,-5.8) 21(8,0) 22(8,-5.8) 23(8.8,0) 24(8.8,-5.8) 25(9.6,0) 26(9.6,-5.8) 27(10.4,0) 28(10.4,-5.8) 29(11.2,0) 30(11.2,-5.8)
  custom 0.375x0.375 smd: 31(-2.1,0) 32(13.3,0)
  rect 1.803x1.499 smd: 33(-2.1,-5.8) 34(13.3,-5.8)
  custom 0.451x0.451 smd: 35(-2.1,-2.9) 36(13.3,-2.9)
  round 1.245 hole 0.838: 37(-2,-1.2) 38(13.2,-1.2)
ACON_HMRB9-AK120C_19P
  round 0.762 hole 0.508: 1(0,0) 2(-0.5,-1.2) 3(-1,0) 4(-1.5,-1.2) 5(-2,0) 6(-2.5,-1.2) 7(-3,0) 8(-3.5,-1.2) 9(-4,0) 10(-4.5,-1.2) 11(-5,0) 12(-5.5,-1.2) 13(-6,0) 14(-6.5,-1.2) 15(-7,0) 16(-7.5,-1.2) 17(-8,0) 18(-8.5,-1.2) 19(-9,0)
  oval 1.6x2.311 hole 0.991x1.702: 20(-11.75,0) 21(-13.5,-7.57) 22(4.5,-7.57) 23(2.75,0)
AH1806-W-7_SC59-3
  oval 0.787x0.991 smd: 1(0,0) 2(-0.95,-2.4) 3(0.95,-2.4)
ALC3266-CG_QFN56_7X7
  oval 0.889x0.203 smd: 1(0,0) 2(0,-0.4) 3(0,-0.8) 4(0,-1.2) 5(0,-1.6) 6(0,-2) 7(0,-2.4) 8(0,-2.8) 9(0,-3.2) 10(0,-3.6) 11(0,-4) 12(0,-4.4) 13(0,-4.8) 14(0,-5.2) 29(7.1,-5.2) 30(7.1,-4.8) 31(7.1,-4.4) 32(7.1,-4) 33(7.1,-3.6) 34(7.1,-3.2) 35(7.1,-2.8) 36(7.1,-2.4) 37(7.1,-2) 38(7.1,-1.6) 39(7.1,-1.2) 40(7.1,-0.8) 41(7.1,-0.4) 42(7.1,0)
  oval 0.203x0.889 smd: 15(0.95,-6.15) 16(1.35,-6.15) 17(1.75,-6.15) 18(2.15,-6.15) 19(2.55,-6.15) 20(2.95,-6.15) 21(3.35,-6.15) 22(3.75,-6.15) 23(4.15,-6.15) 24(4.55,-6.15) 25(4.95,-6.15) 26(5.35,-6.15) 27(5.75,-6.15) 28(6.15,-6.15) 43(6.15,0.95) 44(5.75,0.95) 45(5.35,0.95) 46(4.95,0.95) 47(4.55,0.95) 48(4.15,0.95) 49(3.75,0.95) 50(3.35,0.95) 51(2.95,0.95) 52(2.55,0.95) 53(2.15,0.95) 54(1.75,0.95) 55(1.35,0.95) 56(0.95,0.95)
  rect 4.597x4.597 smd: 57(3.55,-2.6)
ALPINE-RIDGE_BGA_337P
  round 0.254 smd: A1(0,0) A23(10.12,0) AA2(0.46,-9.2) AA22(9.66,-9.2) AB2(0.46,-9.66) AB3(0.92,-9.66) AB4(1.38,-9.66) AB5(1.84,-9.66) AB6(2.3,-9.66) AB7(2.76,-9.66) AB8(3.22,-9.66) AB9(3.68,-9.66) AB10(4.14,-9.66) AB11(4.6,-9.66) AB12(5.06,-9.66) AB13(5.52,-9.66) AB14(5.98,-9.66) AB15(6.44,-9.66) AB16(6.9,-9.66) AB17(7.36,-9.66) AB18(7.82,-9.66) AB19(8.28,-9.66) AB20(8.74,-9.66) AB21(9.2,-9.66) AB22(9.66,-9.66) AC1(0,-10.12) AC23(10.12,-10.12) B2(0.46,-0.46) B3(0.92,-0.46) B4(1.38,-0.46) B5(1.84,-0.46) B6(2.3,-0.46) B7(2.76,-0.46) B8(3.22,-0.46) B9(3.68,-0.46) B10(4.14,-0.46) B11(4.6,-0.46) B12(5.06,-0.46) B13(5.52,-0.46) B14(5.98,-0.46) B15(6.44,-0.46) B16(6.9,-0.46) B17(7.36,-0.46) B18(7.82,-0.46) B19(8.28,-0.46) B20(8.74,-0.46) B21(9.2,-0.46) B22(9.66,-0.46) C2(0.46,-0.92) C22(9.66,-0.92) D2(0.46,-1.38) D4(1.16,-1.16) D5(1.81,-1.16) D6(2.46,-1.16) D8(3.11,-1.16) D9(3.76,-1.16) D11(4.41,-1.16) D12(5.06,-1.16) D13(5.71,-1.16) D15(6.36,-1.16) D16(7.01,-1.16) D18(7.66,-1.16) D19(8.31,-1.16) D20(8.96,-1.16) D22(9.66,-1.38) E2(0.46,-1.84) E4(1.16,-1.81) E5(1.81,-1.81) E6(2.46,-1.81) E8(3.11,-1.81) E9(3.76,-1.81) E11(4.41,-1.81) E12(5.06,-1.81) E13(5.71,-1.81) E15(6.36,-1.81) E16(7.01,-1.81) E18(7.66,-1.81) E19(8.31,-1.81) E20(8.96,-1.81) E22(9.66,-1.84) F2(0.46,-2.3) F4(1.16,-2.46) F5(1.81,-2.46) F6(2.46,-2.46) F8(3.11,-2.46) F9(3.76,-2.46) F11(4.41,-2.46) F12(5.06,-2.46) F13(5.71,-2.46) F15(6.36,-2.46) F16(7.01,-2.46) F18(7.66,-2.46) F19(8.31,-2.46) F20(8.96,-2.46) F22(9.66,-2.3) G2(0.46,-2.76) G22(9.66,-2.76) H2(0.46,-3.22) H4(1.16,-3.11) H5(1.81,-3.11) H6(2.46,-3.11) H8(3.11,-3.11) H9(3.76,-3.11) H11(4.41,-3.11) H12(5.06,-3.11) H13(5.71,-3.11) H15(6.36,-3.11) H16(7.01,-3.11) H18(7.66,-3.11) H19(8.31,-3.11) H20(8.96,-3.11) H22(9.66,-3.22) J2(0.46,-3.68) J4(1.16,-3.76) J5(1.81,-3.76) J6(2.46,-3.76) J8(3.11,-3.76) J9(3.76,-3.76) J11(4.41,-3.76) J12(5.06,-3.76) J13(5.71,-3.76) J15(6.36,-3.76) J16(7.01,-3.76) J18(7.66,-3.76) J19(8.31,-3.76) J20(8.96,-3.76) J22(9.66,-3.68) K2(0.46,-4.14) K22(9.66,-4.14) L2(0.46,-4.6) L4(1.16,-4.41) L5(1.81,-4.41) L6(2.46,-4.41) L8(3.11,-4.41) L9(3.76,-4.41) L11(4.41,-4.41) L12(5.06,-4.41) L13(5.71,-4.41) L15(6.36,-4.41) L16(7.01,-4.41) L18(7.66,-4.41) L19(8.31,-4.41) L20(8.96,-4.41) L22(9.66,-4.6) M2(0.46,-5.06) M4(1.16,-5.06) M5(1.81,-5.06) M6(2.46,-5.06) M8(3.11,-5.06) M9(3.76,-5.06) M11(4.41,-5.06) M12(5.06,-5.06) M13(5.71,-5.06) M15(6.36,-5.06) M16(7.01,-5.06) M18(7.66,-5.06) M19(8.31,-5.06) M20(8.96,-5.06) M22(9.66,-5.06) N2(0.46,-5.52) N4(1.16,-5.71) N5(1.81,-5.71) N6(2.46,-5.71) N8(3.11,-5.71) N9(3.76,-5.71) N11(4.41,-5.71) N12(5.06,-5.71) N13(5.71,-5.71) N15(6.36,-5.71) N16(7.01,-5.71) N18(7.66,-5.71) N19(8.31,-5.71) N20(8.96,-5.71) N22(9.66,-5.52) P2(0.46,-5.98) P22(9.66,-5.98) R2(0.46,-6.44) R4(1.16,-6.36) R5(1.81,-6.36) R6(2.46,-6.36) R8(3.11,-6.36) R9(3.76,-6.36) R11(4.41,-6.36) R12(5.06,-6.36) R13(5.71,-6.36) R15(6.36,-6.36) R16(7.01,-6.36) R18(7.66,-6.36) R19(8.31,-6.36) R20(8.96,-6.36) R22(9.66,-6.44) T2(0.46,-6.9) T4(1.16,-7.01) T5(1.81,-7.01) T6(2.46,-7.01) T8(3.11,-7.01) T9(3.76,-7.01) T11(4.41,-7.01) T12(5.06,-7.01) T13(5.71,-7.01) T15(6.36,-7.01) T16(7.01,-7.01) T18(7.66,-7.01) T19(8.31,-7.01) T20(8.96,-7.01) T22(9.66,-6.9) U2(0.46,-7.36) U22(9.66,-7.36) V2(0.46,-7.82) V4(1.16,-7.66) V5(1.81,-7.66) V6(2.46,-7.66) V8(3.11,-7.66) V9(3.76,-7.66) V11(4.41,-7.66) V12(5.06,-7.66) V13(5.71,-7.66) V15(6.36,-7.66) V16(7.01,-7.66) V18(7.66,-7.66) V19(8.31,-7.66) V20(8.96,-7.66) V22(9.66,-7.82) W2(0.46,-8.28) W4(1.16,-8.31) W5(1.81,-8.31) W6(2.46,-8.31) W8(3.11,-8.31) W9(3.76,-8.31) W11(4.41,-8.31) W12(5.06,-8.31) W13(5.71,-8.31) W15(6.36,-8.31) W16(7.01,-8.31) W18(7.66,-8.31) W19(8.31,-8.31) W20(8.96,-8.31) W22(9.66,-8.28) Y2(0.46,-8.74) Y4(1.16,-8.96) Y5(1.81,-8.96) Y6(2.46,-8.96) Y8(3.11,-8.96) Y9(3.76,-8.96) Y11(4.41,-8.96) Y12(5.06,-8.96) Y13(5.71,-8.96) Y15(6.36,-8.96) Y16(7.01,-8.96) Y18(7.66,-8.96) Y19(8.31,-8.96) Y20(8.96,-8.96) Y22(9.66,-8.74)
  oval 0.178x0.33 smd: A2(0.46,0) A3(0.92,0) A4(1.38,0) A5(1.84,0) A6(2.3,0) A7(2.76,0) A8(3.22,0) A9(3.68,0) A10(4.14,0) A11(4.6,0) A12(5.06,0) A13(5.52,0) A14(5.98,0) A15(6.44,0) A16(6.9,0) A17(7.36,0) A18(7.82,0) A19(8.28,0) A20(8.74,0) A21(9.2,0) A22(9.66,0) AC2(0.46,-10.12) AC3(0.92,-10.12) AC4(1.38,-10.12) AC5(1.84,-10.12) AC6(2.3,-10.12) AC7(2.76,-10.12) AC8(3.22,-10.12) AC9(3.68,-10.12) AC10(4.14,-10.12) AC11(4.6,-10.12) AC12(5.06,-10.12) AC13(5.52,-10.12) AC14(5.98,-10.12) AC15(6.44,-10.12) AC16(6.9,-10.12) AC17(7.36,-10.12) AC18(7.82,-10.12) AC19(8.28,-10.12) AC20(8.74,-10.12) AC21(9.2,-10.12) AC22(9.66,-10.12)
  oval 0.33x0.178 smd: AA1(0,-9.2) AA23(10.12,-9.2) AB1(0,-9.66) AB23(10.12,-9.66) B1(0,-0.46) B23(10.12,-0.46) C1(0,-0.92) C23(10.12,-0.92) D1(0,-1.38) D23(10.12,-1.38) E1(0,-1.84) E23(10.12,-1.84) F1(0,-2.3) F23(10.12,-2.3) G1(0,-2.76) G23(10.12,-2.76) H1(0,-3.22) H23(10.12,-3.22) J1(0,-3.68) J23(10.12,-3.68) K1(0,-4.14) K23(10.12,-4.14) L1(0,-4.6) L23(10.12,-4.6) M1(0,-5.06) M23(10.12,-5.06) N1(0,-5.52) N23(10.12,-5.52) P1(0,-5.98) P23(10.12,-5.98) R1(0,-6.44) R23(10.12,-6.44) T1(0,-6.9) T23(10.12,-6.9) U1(0,-7.36) U23(10.12,-7.36) V1(0,-7.82) V23(10.12,-7.82) W1(0,-8.28) W23(10.12,-8.28) Y1(0,-8.74) Y23(10.12,-8.74)
AO3409_SOT23-3
  oval 1.016x1.524 smd: 1(0,0) 2(0.965,2.083) 3(-0.965,2.083)
AON6232A_DFN5X6-8-5
  oval 0.61x1.27 smd: 1(0,0) 2(1.27,0) 3(2.54,0) 4(3.81,0)
  custom 1.105x1.105 smd: 5(1.905,3.715)
AON6380_DFN5X6-8-5
  oval 0.508x0.838 smd: 1(0,0) 2(1.27,0) 3(2.54,0) 4(3.81,0)
  custom 1.15x1.15 smd: 5(1.905,3.69)
AON6796_DFN5X6-8-5
  oval 0.508x0.66 smd: 1(0,0) 2(1.27,0) 3(2.54,0) 4(3.81,0)
  custom 1.15x1.15 smd: 5(1.905,2.755)
AON6962_DFN5X6D-8-7
  oval 0.66x0.635 smd: 1(0,0) 3(3.81,5.67) 4(2.54,5.67) 5(1.27,5.67) 6(0,5.67)
  custom 0.485x0.485 smd: 2(1.905,0.655)
  rect 3.988x2.667 smd: 7(1.905,3.63)
AON7405_DFN8-5
  oval 0.406x0.991 smd: 1(0,0) 2(0.66,0) 3(1.32,0) 4(1.98,0)
  custom 0.559x0.559 smd: 5(0.99,2.247)
AON7406L_DFN8-5
  oval 0.406x0.991 smd: 1(0,0) 2(0.66,0) 3(1.32,0) 4(1.98,0)
  custom 0.559x0.559 smd: 5(0.99,2.247)
AON7408L_DFN8-5
  oval 0.406x0.991 smd: 1(0,0) 2(0.66,0) 3(1.32,0) 4(1.98,0)
  custom 0.559x0.559 smd: 5(0.99,2.247)
AON7506_DFN3X3-8-5
  oval 0.406x0.991 smd: 1(0,0) 2(0.66,0) 3(1.32,0) 4(1.98,0)
  custom 0.559x0.559 smd: 5(0.99,2.247)
AON7534_DFN3X3-8-5
  oval 0.406x0.991 smd: 1(0,0) 2(0.66,0) 3(1.32,0) 4(1.98,0)
  custom 0.559x0.559 smd: 5(0.99,2.247)
AP2330W-7_SC59-3
  oval 0.787x0.991 smd: 1(0,0) 2(-0.95,-2.4) 3(0.95,-2.4)
APE8937GN2_DFN8_2X2
  oval 0.254x0.787 smd: 1(0,0) 2(0.5,0) 3(1,0) 4(1.5,0) 5(1.5,2.2) 6(1,2.2) 7(0.5,2.2) 8(0,2.2)
  rect 1.6x0.889 smd: 9(0.75,1.1)
AZ5B25-01F_DFN0603P2Y2
  rect 0.305x0.356 smd: 1(0,0) 2(0.4,0)
AZ1045-04F_DFN2510P10E-10-9
  oval 0.254x0.686 smd: 1(0,0) 2(0.5,0) 4(1.5,0) 5(2,0) 6(2,0.875) 7(1.5,0.875) 8(0.5,0.875) 9(0,0.875)
  oval 0.381x1.549 smd: 3(1,0.437)
AZ5123-01FPR7G_DFN1006P2X2
  rect 0.559x0.61 smd: 1(0,0) 2(0.85,0)
AZ5125-01HPR7G_SOD523-2
  rect 0.61x0.787 smd: 1(0,0) 2(1.5,0)
AZ5125-02SPR7G_SOT23-3
  oval 1.016x1.524 smd: 1(0,0) 2(0.965,2.083) 3(-0.965,2.083)
BAT54CW-7-F_SOT323-3
  oval 0.711x0.889 smd: 1(0,0) 2(-0.65,-1.9) 3(0.65,-1.9)
BAT54CW_SOT323-3
  oval 0.711x0.889 smd: 1(0,0) 2(-0.65,-1.9) 3(0.65,-1.9)
BELLW_SD-80886-1021_260P-T
  round 1.092 hole 1.092 unplated: (-67.775,-4.1)
  round 1.6 hole 1.6 unplated: (1.025,-4.1)
  oval 0.305x1.753 smd: 1(0,0) 2(-0.25,-8.2) 3(-0.5,0) 4(-0.75,-8.2) 5(-1,0) 6(-1.25,-8.2) 7(-1.5,0) 8(-1.75,-8.2) 9(-2,0) 10(-2.25,-8.2) 11(-2.5,0) 12(-2.75,-8.2) 13(-3,0) 14(-3.25,-8.2) 15(-3.5,0) 16(-3.75,-8.2) 17(-4,0) 18(-4.25,-8.2) 19(-4.5,0) 20(-4.75,-8.2) 21(-5,0) 22(-5.25,-8.2) 23(-5.5,0) 24(-5.75,-8.2) 25(-6,0) 26(-6.25,-8.2) 27(-6.5,0) 28(-6.75,-8.2) 29(-7,0) 30(-7.25,-8.2) 31(-7.5,0) 32(-7.75,-8.2) 33(-8,0) 34(-8.25,-8.2) 35(-8.5,0) 36(-8.75,-8.2) 37(-9,0) 38(-9.25,-8.2) 39(-9.5,0) 40(-9.75,-8.2) 41(-10,0) 42(-10.25,-8.2) 43(-10.5,0) 44(-10.75,-8.2) 45(-11,0) 46(-11.25,-8.2) 47(-11.5,0) 48(-11.75,-8.2) 49(-12,0) 50(-12.25,-8.2) 51(-12.5,0) 52(-12.75,-8.2) 53(-13,0) 54(-13.25,-8.2) 55(-13.5,0) 56(-13.75,-8.2) 57(-14,0) 58(-14.25,-8.2) 59(-14.5,0) 60(-14.75,-8.2) 61(-15,0) 62(-15.25,-8.2) 63(-15.5,0) 64(-15.75,-8.2) 65(-16,0) 66(-16.25,-8.2) 67(-16.5,0) 68(-16.75,-8.2) 69(-17,0) 70(-17.25,-8.2) 71(-17.5,0) 72(-17.75,-8.2) 73(-18,0) 74(-18.25,-8.2) 75(-18.5,0) 76(-18.75,-8.2) 77(-19,0) 78(-19.25,-8.2) 79(-19.5,0) 80(-19.75,-8.2) 81(-20,0) 82(-20.25,-8.2) 83(-20.5,0) 84(-20.75,-8.2) 85(-21,0) 86(-21.25,-8.2) 87(-21.5,0) 88(-21.75,-8.2) 89(-22,0) 90(-22.25,-8.2) 91(-22.5,0) 92(-22.75,-8.2) 93(-23,0) 94(-23.25,-8.2) 95(-23.5,0) 96(-23.75,-8.2) 97(-24,0) 98(-24.25,-8.2) 99(-24.5,0) 100(-24.75,-8.2) 101(-25,0) 102(-25.25,-8.2) 103(-25.5,0) 104(-25.75,-8.2) 105(-26,0) 106(-26.25,-8.2) 107(-26.5,0) 108(-26.75,-8.2) 109(-27,0) 110(-27.25,-8.2) 111(-27.5,0) 112(-27.75,-8.2) 113(-28,0) 114(-28.25,-8.2) 115(-28.5,0) 116(-28.75,-8.2) 117(-29,0) 118(-29.25,-8.2) 119(-29.5,0) 120(-29.75,-8.2) 121(-30,0) 122(-30.25,-8.2) 123(-30.5,0) 124(-30.75,-8.2) 125(-31,0) 126(-31.25,-8.2) 127(-31.5,0) 128(-31.75,-8.2) 129(-32,0) 130(-32.25,-8.2) 131(-32.5,0) 132(-32.75,-8.2) 133(-33,0) 134(-33.25,-8.2) 135(-33.5,0) 136(-33.75,-8.2) 137(-34,0) 138(-34.25,-8.2) 139(-34.5,0) 140(-34.75,-8.2) 141(-35,0) 142(-35.25,-8.2) 143(-35.5,0) 144(-35.75,-8.2) 145(-38,0) 146(-38.25,-8.2) 147(-38.5,0) 148(-38.75,-8.2) 149(-39,0) 150(-39.25,-8.2) 151(-39.5,0) 152(-39.75,-8.2) 153(-40,0) 154(-40.25,-8.2) 155(-40.5,0) 156(-40.75,-8.2) 157(-41,0) 158(-41.25,-8.2) 159(-41.5,0) 160(-41.75,-8.2) 161(-42,0) 162(-42.25,-8.2) 163(-42.5,0) 164(-42.75,-8.2) 165(-43,0) 166(-43.25,-8.2) 167(-43.5,0) 168(-43.75,-8.2) 169(-44,0) 170(-44.25,-8.2) 171(-44.5,0) 172(-44.75,-8.2) 173(-45,0) 174(-45.25,-8.2) 175(-45.5,0) 176(-45.75,-8.2) 177(-46,0) 178(-46.25,-8.2) 179(-46.5,0) 180(-46.75,-8.2) 181(-47,0) 182(-47.25,-8.2) 183(-47.5,0) 184(-47.75,-8.2) 185(-48,0) 186(-48.25,-8.2) 187(-48.5,0) 188(-48.75,-8.2) 189(-49,0) 190(-49.25,-8.2) 191(-49.5,0) 192(-49.75,-8.2) 193(-50,0) 194(-50.25,-8.2) 195(-50.5,0) 196(-50.75,-8.2) 197(-51,0) 198(-51.25,-8.2) 199(-51.5,0) 200(-51.75,-8.2) 201(-52,0) 202(-52.25,-8.2) 203(-52.5,0) 204(-52.75,-8.2) 205(-53,0) 206(-53.25,-8.2) 207(-53.5,0) 208(-53.75,-8.2) 209(-54,0) 210(-54.25,-8.2) 211(-54.5,0) 212(-54.75,-8.2) 213(-55,0) 214(-55.25,-8.2) 215(-55.5,0) 216(-55.75,-8.2) 217(-56,0) 218(-56.25,-8.2) 219(-56.5,0) 220(-56.75,-8.2) 221(-57,0) 222(-57.25,-8.2) 223(-57.5,0) 224(-57.75,-8.2) 225(-58,0) 226(-58.25,-8.2) 227(-58.5,0) 228(-58.75,-8.2) 229(-59,0) 230(-59.25,-8.2) 231(-59.5,0) 232(-59.75,-8.2) 233(-60,0) 234(-60.25,-8.2) 235(-60.5,0) 236(-60.75,-8.2) 237(-61,0) 238(-61.25,-8.2) 239(-61.5,0) 240(-61.75,-8.2) 241(-62,0) 242(-62.25,-8.2) 243(-62.5,0) 244(-62.75,-8.2) 245(-63,0) 246(-63.25,-8.2) 247(-63.5,0) 248(-63.75,-8.2) 249(-64,0) 250(-64.25,-8.2) 251(-64.5,0) 252(-64.75,-8.2) 253(-65,0) 254(-65.25,-8.2) 255(-65.5,0) 256(-65.75,-8.2) 257(-66,0) 258(-66.25,-8.2) 259(-66.5,0) 260(-66.75,-8.2)
  rect 3.505x4.597 smd: 261(0.425,7.9) 262(-67.175,7.9)
BZT52C15LP-7_DFN1006-2
  rect 0.406x0.711 smd: 1(0,0) 2(0.7,0)
C_0201
  rect 0.381x0.356 smd: 1(0,0) 2(0.584,0)
C_0402
  rect 0.508x0.584 smd: 1(0,0) 2(0.914,0)
C_0603
  rect 0.635x0.889 smd: 1(0,0) 2(1.397,0)
C_0805
  rect 0.813x1.397 smd: 1(0,0) 2(1.702,0)
C_B2
  rect 1.346x2.692 smd: 1(0,0) 2(-2.75,0)
C_B3
  rect 1.346x2.692 smd: 1(0,0) 2(2.75,0)
C_D
  rect 2.388x2.896 smd: 1(0,0) 2(6.1,0)
C_D1
  rect 1.803x2.794 smd: 1(0,0) 2(6.5,0)
C_D2E
  rect 2.388x2.896 smd: 1(0,0) 2(6.1,0)
C_EEFSS0D221R
  rect 2.388x2.794 smd: 1(0,0) 2(6.4,0)
CFL-H_BGA_1440P-T
  round 0.406 smd: A3(-1.254,0) A37(-26.054,0) B2(-0.66,0.66) B38(-26.628,0.553) BR1(0,40.062) BR38(-26.628,40.036) BT2(-0.571,40.628) BT37(-26.037,40.628) C1(0,1.267)
  round 0.381 smd: A4(-1.971,0) A34(-24.46,0) A36(-25.272,0) B3(-1.382,0.699) B37(-25.909,0.703) BN1(0,38.614) BN38(-26.628,38.599) BP1(0,39.338) BP38(-26.628,39.31) BR2(-0.719,39.934) BR37(-25.904,39.927) BT3(-1.295,40.628) BT4(-2.019,40.628) BT35(-24.498,40.628) BT36(-25.311,40.628) C2(-0.699,1.361) C38(-26.628,1.334) D1(0,1.991) D38(-26.628,2.097)
  round 0.356 smd: A5(-2.771,0) A33(-23.66,0) B4(-2.031,0.971) B36(-25.198,0.701) BM1(0,37.814) BM38(-26.628,37.888) BN2(-0.65,38.642) BN37(-25.965,38.665) BP2(-0.828,39.28) BP37(-25.689,39.257) BR3(-1.387,39.978) BR36(-25.193,39.971) BT5(-2.819,40.628) BT34(-23.698,40.628) C37(-25.908,1.402) D3(-1.233,1.822) E1(0,2.779) E2(-0.65,2.474) E38(-26.628,2.897)
  round 0.33 smd: A6(-3.546,0) A32(-22.872,0) B5(-2.743,0.65) B34(-24.443,0.67) BK1(0,37.037) BL2(-0.65,37.438) BL38(-26.628,37.176) BM2(-0.963,38.053) BM37(-25.978,37.986) BN3(-1.3,38.701) BN36(-25.314,38.638) BP3(-1.483,39.334) BP35(-24.561,39.328) BR5(-2.166,39.984) BR34(-23.774,39.978) BR35(-24.536,39.978) BT6(-3.594,40.628) BT32(-22.923,40.628) C36(-25.145,1.388) D4(-1.894,1.655) D37(-25.603,1.985) E3(-1.3,2.474) E37(-25.978,2.604) F2(-0.65,3.16) G1(0,3.581) G38(-26.628,3.671)
  round 0.305 smd: A8(-4.318,0) A9(-5.105,0) A10(-5.893,0) A11(-6.68,0) A12(-7.468,0) A13(-8.255,0) A14(-9.042,0) A15(-9.83,0) A16(-10.617,0) A17(-11.405,0) A18(-12.192,0) A19(-12.979,0) A20(-13.767,0) A21(-14.554,0) A22(-15.342,0) A23(-16.129,0) A24(-16.916,0) A25(-17.704,0) A26(-18.491,0) A27(-19.279,0) A28(-20.066,0) A29(-20.853,0) A30(-21.844,0) AA1(0,14.019) AA2(-0.65,14.019) AA3(-1.3,14.019) AA4(-1.951,14.019) AA5(-2.601,14.019) AA6(-3.251,13.968) AA7(-3.911,14.548) AA8(-4.561,14.548) AA9(-5.212,14.548) AA10(-5.862,14.548) AA11(-6.512,14.548) AA12(-7.162,14.548) AA13(-7.813,14.548) AA14(-8.463,14.548) AA29(-20.725,14.415) AA30(-21.376,14.415) AA31(-22.077,14.415) AA32(-22.727,14.415) AA33(-23.377,14.415) AA34(-24.027,14.415) AA35(-24.678,14.415) AA36(-25.328,14.415) AA37(-25.978,14.415) AA38(-26.628,14.415) AB1(0,14.756) AB2(-0.65,14.756) AB3(-1.3,14.756) AB4(-1.951,14.756) AB5(-2.601,14.756) AB6(-3.251,14.806) AB29(-20.725,15.203) AB30(-21.376,15.203) AB31(-22.077,15.203) AB32(-22.727,15.203) AB33(-23.377,15.203) AB34(-24.027,15.203) AB35(-24.678,15.203) AB36(-25.328,15.203) AB37(-25.978,15.203) AB38(-26.628,15.203) AC1(0,15.645) AC2(-0.65,15.645) AC3(-1.3,15.645) AC4(-1.951,15.645) AC5(-2.601,15.645) AC6(-3.251,15.645) AC7(-3.911,15.463) AC8(-4.561,15.463) AC9(-5.212,15.463) AC10(-5.862,15.463) AC11(-6.512,15.463) AC12(-7.162,15.463) AC13(-7.813,15.463) AC14(-8.463,15.463) AC29(-20.725,15.99) AC30(-21.376,15.99) AC31(-22.077,15.99) AC32(-22.727,15.99) AC33(-23.377,15.99) AC34(-24.027,15.99) AC35(-24.678,15.99) AC36(-25.328,15.99) AC37(-25.978,15.99) AC38(-26.628,15.99) AD1(0,16.534) AD2(-0.65,16.534) AD3(-1.3,16.534) AD4(-1.951,16.534) AD5(-2.601,16.534) AD6(-3.251,16.483) AD7(-3.911,16.377) AD8(-4.561,16.377) AD9(-5.212,16.377) AD10(-5.862,16.377) AD11(-6.512,16.377) AD12(-7.162,16.377) AD13(-7.813,16.377) AD14(-8.463,16.377) AD29(-20.725,16.777) AD30(-21.376,16.777) AD31(-22.077,16.777) AD32(-22.727,16.777) AD33(-23.377,16.777) AD34(-24.027,16.777) AD35(-24.678,16.777) AD36(-25.328,16.777) AD37(-25.978,16.777) AD38(-26.628,16.777) AE1(0,17.27) AE2(-0.65,17.27) AE3(-1.3,17.27) AE4(-1.951,17.27) AE5(-2.601,17.27) AE6(-3.251,17.321) AE7(-3.911,17.291) AE8(-4.561,17.291) AE9(-5.212,17.291) AE10(-5.862,17.291) AE11(-6.512,17.291) AE12(-7.162,17.291) AE13(-7.813,17.291) AE14(-8.463,17.291) AE29(-20.725,17.565) AE30(-21.376,17.565) AE31(-22.077,17.565) AE32(-22.727,17.565) AE33(-23.377,17.565) AE34(-24.027,17.565) AE35(-24.678,17.565) AE36(-25.328,17.565) AE37(-25.978,17.565) AE38(-26.628,17.565) AF1(0,18.159) AF2(-0.65,18.159) AF3(-1.3,18.159) AF4(-1.951,18.159) AF5(-2.601,18.159) AF6(-3.251,18.159) AF7(-3.911,18.206) AF8(-4.561,18.206) AF9(-5.212,18.206) AF10(-5.862,18.206) AF11(-6.512,18.206) AF12(-7.162,18.206) AF13(-7.813,18.206) AF14(-8.463,18.206) AF29(-20.725,18.352) AF30(-21.376,18.352) AF31(-22.077,18.352) AF32(-22.727,18.352) AF33(-23.377,18.352) AF34(-24.027,18.352) AF35(-24.678,18.352) AF36(-25.328,18.352) AF37(-25.978,18.352) AF38(-26.628,18.352) AG1(0,19.048) AG2(-0.65,19.048) AG3(-1.3,19.048) AG4(-1.951,19.048) AG5(-2.601,19.048) AG6(-3.251,18.997) AG7(-3.911,19.12) AG8(-4.561,19.12) AG9(-5.212,19.12) AG10(-5.862,19.12) AG11(-6.512,19.12) AG12(-7.162,19.12) AG13(-7.813,19.12) AG14(-8.463,19.12) AG29(-20.725,19.14) AG30(-21.376,19.14) AG31(-22.077,19.14) AG32(-22.727,19.14) AG33(-23.377,19.14) AG34(-24.027,19.14) AG35(-24.678,19.14) AG36(-25.328,19.14) AG37(-25.978,19.14) AG38(-26.628,19.14) AH1(0,19.785) AH2(-0.65,19.785) AH3(-1.3,19.785) AH4(-1.951,19.785) AH5(-2.601,19.785) AH6(-3.251,19.836) AH7(-3.911,20.035) AH8(-4.561,20.035) AH9(-5.212,20.035) AH10(-5.862,20.035) AH11(-6.512,20.035) AH12(-7.162,20.035) AH13(-7.813,20.035) AH14(-8.463,20.035) AH29(-20.725,19.927) AH30(-21.376,19.927) AH31(-22.077,19.927) AH32(-22.727,19.927) AH33(-23.377,19.927) AH34(-24.027,19.927) AH35(-24.678,19.927) AH36(-25.328,19.927) AH37(-25.978,19.927) AH38(-26.628,19.927) AJ1(0,20.674) AJ2(-0.65,20.674) AJ3(-1.3,20.674) AJ4(-1.951,20.674) AJ5(-2.601,20.674) AJ6(-3.251,20.674) AJ7(-3.911,20.949) AJ8(-4.561,20.949) AJ9(-5.212,20.949) AJ10(-5.862,20.949) AJ11(-6.512,20.949) AJ12(-7.162,20.949) AJ13(-7.813,20.949) AJ14(-8.463,20.949) AJ29(-20.725,20.714) AJ30(-21.376,20.714) AJ31(-22.077,20.714) AJ32(-22.727,20.714) AJ33(-23.377,20.714) AJ34(-24.027,20.714) AJ35(-24.678,20.714) AJ36(-25.328,20.714) AJ37(-25.978,20.714) AJ38(-26.628,20.714) AK1(0,21.563) AK2(-0.65,21.563) AK3(-1.3,21.563) AK4(-1.951,21.563) AK5(-2.601,21.563) AK6(-3.251,21.512) AK29(-20.725,21.502) AK30(-21.376,21.502) AK31(-22.077,21.502) AK32(-22.727,21.502) AK33(-23.377,21.502) AK34(-24.027,21.502) AK35(-24.678,21.502) AK36(-25.328,21.502) AK37(-25.978,21.502) AK38(-26.628,21.502) AL1(0,22.299) AL2(-0.65,22.299) AL3(-1.3,22.299) AL4(-1.951,22.299) AL5(-2.601,22.299) AL6(-3.251,22.35) AL7(-3.911,21.863) AL8(-4.561,21.863) AL9(-5.212,21.863) AL10(-5.862,21.863) AL11(-6.512,21.863) AL12(-7.162,21.863) AL13(-7.813,21.863) AL14(-8.463,21.863) AL29(-20.725,22.289) AL30(-21.376,22.289) AL31(-22.077,22.289) AL32(-22.727,22.289) AL33(-23.377,22.289) AL34(-24.027,22.289) AL35(-24.678,22.289) AL36(-25.328,22.289) AL37(-25.978,22.289) AL38(-26.628,22.289) AM1(0,23.188) AM2(-0.65,23.188) AM3(-1.3,23.188) AM4(-1.951,23.188) AM5(-2.601,23.188) AM6(-3.251,23.188) AM7(-3.911,22.778) AM8(-4.561,22.778) AM9(-5.212,22.778) AM10(-5.862,22.778) AM11(-6.512,22.778) AM12(-7.162,22.778) AM13(-7.813,22.778) AM14(-8.463,22.778) AM29(-20.725,23.077) AM30(-21.376,23.077) AM31(-22.077,23.077) AM32(-22.727,23.077) AM33(-23.377,23.077) AM34(-24.027,23.077) AM35(-24.678,23.077) AM36(-25.328,23.077) AM37(-25.978,23.077) AM38(-26.628,23.077) AN1(0,24.077) AN2(-0.65,24.077) AN3(-1.3,24.077) AN4(-1.951,24.077) AN5(-2.601,24.077) AN6(-3.251,24.027) AN7(-3.911,23.692) AN8(-4.561,23.692) AN9(-5.212,23.692) AN10(-5.862,23.692) AN11(-6.512,23.692) AN12(-7.162,23.692) AN13(-7.813,23.692) AN14(-8.463,23.692) AN29(-20.725,23.864) AN30(-21.376,23.864) AN31(-22.077,23.864) AN32(-22.727,23.864) AN33(-23.377,23.864) AN34(-24.027,23.864) AN35(-24.678,23.864) AN36(-25.328,23.864) AN37(-25.978,23.864) AN38(-26.628,23.864) AP1(0,24.814) AP2(-0.65,24.814) AP3(-1.3,24.814) AP4(-1.951,24.814) AP5(-2.601,24.814) AP6(-3.251,24.865) AP7(-3.911,24.607) AP8(-4.561,24.607) AP9(-5.212,24.607) AP10(-5.862,24.607) AP11(-6.512,24.607) AP12(-7.162,24.607) AP13(-7.813,24.607) AP14(-8.463,24.607) AP29(-20.725,24.651) AP30(-21.376,24.651) AP31(-22.077,24.651) AP32(-22.727,24.651) AP33(-23.377,24.651) AP34(-24.027,24.651) AP35(-24.678,24.651) AP36(-25.328,24.651) AP37(-25.978,24.651) AP38(-26.628,24.651) AR1(0,25.703) AR2(-0.65,25.703) AR3(-1.3,25.703) AR4(-1.951,25.703) AR5(-2.601,25.703) AR6(-3.251,25.703) AR7(-3.911,25.521) AR8(-4.561,25.521) AR9(-5.212,25.521) AR10(-5.862,25.521) AR11(-6.512,25.521) AR12(-7.162,25.521) AR13(-7.813,25.521) AR14(-8.463,25.521) AR29(-20.725,25.439) AR30(-21.376,25.439) AR31(-22.077,25.439) AR32(-22.727,25.439) AR33(-23.377,25.439) AR34(-24.027,25.439) AR35(-24.678,25.439) AR36(-25.328,25.439) AR37(-25.978,25.439) AR38(-26.628,25.439) AT1(0,26.592) AT2(-0.65,26.592) AT3(-1.3,26.592) AT4(-1.951,26.592) AT5(-2.601,26.592) AT6(-3.251,26.541) AT7(-3.911,26.435) AT8(-4.561,26.435) AT9(-5.212,26.435) AT10(-5.862,26.435) AT11(-6.512,26.435) AT12(-7.162,26.435) AT13(-7.813,26.435) AT14(-8.463,26.435) AT29(-20.725,26.226) AT30(-21.376,26.226) AT31(-22.077,26.226) AT32(-22.727,26.226) AT33(-23.377,26.226) AT34(-24.027,26.226) AT35(-24.678,26.226) AT36(-25.328,26.226) AT37(-25.978,26.226) AT38(-26.628,26.226) AU1(0,27.329) AU2(-0.65,27.329) AU3(-1.3,27.329) AU4(-1.951,27.329) AU5(-2.601,27.329) AU6(-3.251,27.379) AU7(-3.911,27.35) AU8(-4.561,27.35) AU9(-5.212,27.35) AU10(-5.862,27.35) AU11(-6.512,27.35) AU12(-7.162,27.35) AU13(-7.813,27.35) AU14(-8.463,27.35) AU29(-20.725,27.014) AU30(-21.376,27.014) AU31(-22.077,27.014) AU32(-22.727,27.014) AU33(-23.377,27.014) AU34(-24.027,27.014) AU35(-24.678,27.014) AU36(-25.328,27.014) AU37(-25.978,27.014) AU38(-26.628,27.014) AV29(-20.725,27.801) AV30(-21.376,27.801) AV31(-22.077,27.801) AV32(-22.727,27.801) AV33(-23.377,27.801) AV34(-24.027,27.801) AV35(-24.678,27.801) AV36(-25.328,27.801) AV37(-25.978,27.801) AV38(-26.628,27.801) AW1(0,28.218) AW2(-0.65,28.218) AW3(-1.3,28.218) AW4(-1.951,28.218) AW5(-2.601,28.218) AW6(-3.251,28.218) AW7(-3.911,28.264) AW8(-4.561,28.264) AW9(-5.212,28.264) AW10(-5.862,28.264) AW11(-6.512,28.264) AW12(-7.162,28.264) AW13(-7.813,28.264) AW14(-8.463,28.264) AW29(-20.725,28.588) AW30(-21.376,28.588) AW31(-22.077,28.588) AW32(-22.727,28.588) AW33(-23.377,28.588) AW34(-24.027,28.588) AW35(-24.678,28.588) AW36(-25.328,28.588) AW37(-25.978,28.588) AW38(-26.628,28.588) AY1(0,29.107) AY2(-0.65,29.107) AY3(-1.3,29.107) AY4(-1.951,29.107) AY5(-2.601,29.107) AY6(-3.251,29.056) AY7(-3.911,29.179) AY8(-4.561,29.179) AY9(-5.212,29.179) AY10(-5.862,29.179) AY11(-6.512,29.179) AY12(-7.162,29.179) AY13(-7.813,29.179) AY14(-8.463,29.179) AY29(-20.725,29.376) AY30(-21.376,29.376) AY31(-22.077,29.376) AY32(-22.727,29.376) AY33(-23.377,29.376) AY34(-24.027,29.376) AY35(-24.678,29.376) AY36(-25.328,29.376) AY37(-25.978,29.376) AY38(-26.628,29.376) B6(-3.531,0.65) B8(-4.318,0.65) B9(-5.105,0.65) B10(-5.893,0.65) B11(-6.68,0.65) B12(-7.468,0.65) B13(-8.255,0.65) B14(-9.042,0.65) B15(-9.83,0.65) B16(-10.617,0.65) B17(-11.405,0.65) B18(-12.192,0.65) B19(-12.979,0.65) B20(-13.767,0.65) B21(-14.554,0.65) B22(-15.342,0.65) B23(-16.129,0.65) B24(-16.916,0.65) B25(-17.704,0.65) B26(-18.491,0.65) B27(-19.279,0.65) B28(-20.066,0.65) B29(-20.853,0.65) B30(-21.641,0.65) B31(-22.428,0.65) B33(-23.216,0.65) BA1(0,29.843) BA2(-0.65,29.843) BA3(-1.3,29.843) BA4(-1.951,29.843) BA5(-2.601,29.843) BA6(-3.251,29.894) BA7(-3.911,30.093) BA8(-4.561,30.093) BA9(-5.212,30.093) BA10(-5.862,30.093) BA11(-6.512,30.093) BA12(-7.162,30.093) BA13(-7.813,30.093) BA14(-8.463,30.093) BA29(-20.725,30.163) BA30(-21.376,30.163) BA31(-22.077,30.163) BA32(-22.727,30.163) BA33(-23.377,30.163) BA34(-24.027,30.163) BA35(-24.678,30.163) BA36(-25.328,30.163) BA37(-25.978,30.163) BA38(-26.628,30.163) BB1(0,30.732) BB2(-0.65,30.732) BB3(-1.3,30.732) BB4(-1.951,30.732) BB5(-2.601,30.732) BB6(-3.251,30.732) BB7(-3.911,31.007) BB8(-4.561,31.007) BB9(-5.212,31.007) BB10(-5.862,31.007) BB11(-6.512,31.007) BB12(-7.162,31.007) BB13(-7.813,31.007) BB14(-8.463,31.007) BB29(-20.725,30.951) BB30(-21.376,30.951) BB31(-22.077,30.951) BB32(-22.727,30.951) BB33(-23.377,30.951) BB34(-24.027,30.951) BB35(-24.678,30.951) BB36(-25.328,30.951) BB37(-25.978,30.951) BB38(-26.628,30.951) BC1(0,31.621) BC2(-0.65,31.621) BC3(-1.3,31.621) BC4(-1.951,31.621) BC5(-2.601,31.621) BC6(-3.251,31.57) BC7(-3.911,31.922) BC8(-4.561,31.922) BC9(-5.212,31.922) BC10(-5.862,31.922) BC11(-6.512,31.922) BC12(-7.162,31.922) BC13(-7.813,31.922) BC14(-8.463,31.922) BC29(-20.725,31.738) BC30(-21.376,31.738) BC31(-22.077,31.738) BC32(-22.727,31.738) BC33(-23.377,31.738) BC34(-24.027,31.738) BC35(-24.678,31.738) BC36(-25.328,31.738) BC37(-25.978,31.738) BC38(-26.628,31.738) BD1(0,32.358) BD2(-0.65,32.358) BD3(-1.3,32.358) BD4(-1.951,32.358) BD5(-2.601,32.358) BD6(-3.251,32.409) BD7(-3.911,32.836) BD8(-4.561,32.836) BD9(-5.212,32.836) BD10(-5.862,32.836) BD11(-6.512,32.836) BD12(-7.162,32.836) BD13(-7.813,32.836) BD14(-8.463,32.836) BD29(-20.725,32.525) BD30(-21.376,32.525) BD31(-22.077,32.525) BD32(-22.727,32.525) BD33(-23.377,32.525) BD34(-24.027,32.525) BD35(-24.678,32.525) BD36(-25.328,32.525) BD37(-25.978,32.525) BD38(-26.628,32.525) BE1(0,33.247) BE2(-0.65,33.247) BE3(-1.3,33.247) BE4(-1.951,33.247) BE5(-2.601,33.247) BE6(-3.251,33.247) BE29(-20.725,33.313) BE30(-21.376,33.313) BE31(-22.077,33.313) BE32(-22.727,33.313) BE33(-23.377,33.313) BE34(-24.027,33.313) BE35(-24.678,33.313) BE36(-25.328,33.313) BE37(-25.978,33.313) BE38(-26.628,33.313) BF1(0,34.136) BF2(-0.65,34.136) BF3(-1.3,34.136) BF4(-1.951,34.136) BF5(-2.601,34.136) BF6(-3.251,34.085) BF7(-3.911,33.751) BF8(-4.561,33.751) BF9(-5.212,33.751) BF10(-5.862,33.751) BF11(-6.512,33.751) BF12(-7.162,33.751) BF13(-7.813,33.751) BF14(-8.463,33.751) BF29(-20.725,34.1) BF30(-21.376,34.1) BF31(-22.077,34.1) BF32(-22.727,34.1) BF33(-23.377,34.1) BF34(-24.027,34.1) BF35(-24.678,34.1) BF36(-25.328,34.1) BF37(-25.978,34.1) BF38(-26.628,34.1) BG1(0,34.872) BG2(-0.65,34.872) BG3(-1.3,34.872) BG4(-1.951,34.872) BG5(-2.601,34.872) BG6(-3.251,34.923) BG7(-3.911,34.665) BG8(-4.561,34.665) BG9(-5.212,34.665) BG10(-5.862,34.665) BG11(-6.512,34.665) BG12(-7.162,34.665) BG13(-7.813,34.665) BG14(-8.463,34.665) BG29(-20.725,34.888) BG30(-21.376,34.888) BG31(-22.077,34.888) BG32(-22.727,34.888) BG33(-23.377,34.888) BG34(-24.027,34.888) BG35(-24.678,34.888) BG36(-25.328,34.888) BG37(-25.978,34.888) BG38(-26.628,34.888) BH1(0,36.015) BH2(-0.65,35.761) BH3(-1.3,35.761) BH4(-1.951,35.761) BH5(-2.601,35.761) BH6(-3.251,35.761) BH7(-3.911,35.579) BH8(-4.561,35.579) BH9(-5.212,35.579) BH10(-5.862,35.579) BH11(-6.512,35.579) BH12(-7.162,35.579) BH13(-7.813,35.579) BH14(-8.463,35.541) BH29(-20.725,35.548) BH30(-21.376,35.675) BH31(-22.077,35.675) BH32(-22.727,35.675) BH33(-23.377,35.675) BH34(-24.027,35.675) BH35(-24.678,35.675) BH36(-25.328,35.675) BH37(-25.978,35.675) BH38(-26.628,35.675) BJ7(-3.911,36.494) BJ8(-4.561,36.494) BJ9(-5.212,36.494) BJ10(-5.862,36.494) BJ11(-6.512,36.494) BJ12(-7.282,36.405) BJ13(-8.171,36.126) BJ14(-8.851,36.077) BJ15(-9.601,36.077) BJ16(-10.388,36.077) BJ17(-11.175,36.077) BJ18(-11.963,36.077) BJ19(-12.75,36.077) BJ20(-13.538,36.077) BJ21(-14.325,36.077) BJ22(-15.112,36.077) BJ23(-15.9,36.077) BJ24(-16.687,36.077) BJ25(-17.475,36.077) BJ26(-18.262,36.077) BJ27(-19.049,36.077) BJ28(-19.837,36.077) BJ29(-20.497,36.158) BJ30(-21.353,36.329) BJ31(-22.077,36.462) BJ32(-22.727,36.462) BJ33(-23.377,36.462) BJ34(-24.027,36.462) BJ35(-24.678,36.462) BJ36(-25.328,36.462) BJ37(-25.978,36.462) BJ38(-26.628,36.412) BK2(-0.65,36.6) BK3(-1.3,36.6) BK4(-1.951,36.6) BK5(-2.601,36.6) BK6(-3.251,36.6) BK13(-7.899,36.727) BK14(-8.813,36.727) BK15(-9.601,36.727) BK16(-10.388,36.727) BK17(-11.175,36.727) BK18(-11.963,36.727) BK19(-12.75,36.727) BK20(-13.538,36.727) BK21(-14.325,36.727) BK22(-15.112,36.727) BK23(-15.9,36.727) BK24(-16.687,36.727) BK25(-17.475,36.727) BK26(-18.262,36.727) BK27(-19.049,36.727) BK28(-19.837,36.727) BK29(-20.833,36.735) BL3(-1.3,37.387) BL4(-1.951,37.387) BL5(-2.601,37.387) BL6(-3.251,37.438) BL7(-3.987,37.383) BL8(-4.876,37.377) BL9(-5.664,37.377) BL11(-6.451,37.377) BL12(-7.238,37.377) BL13(-8.026,37.377) BL14(-8.813,37.377) BL15(-9.601,37.377) BL16(-10.388,37.377) BL17(-11.175,37.377) BL18(-11.963,37.377) BL19(-12.75,37.377) BL20(-13.538,37.377) BL21(-14.325,37.377) BL22(-15.112,37.377) BL23(-15.9,37.377) BL24(-16.687,37.377) BL25(-17.475,37.377) BL26(-18.262,37.377) BL27(-19.049,37.377) BL28(-19.837,37.377) BL29(-20.624,37.377) BL30(-21.426,37.25) BL31(-22.077,37.25) BL32(-22.727,37.25) BL33(-23.377,37.25) BL34(-24.027,37.25) BL35(-24.678,37.25) BL36(-25.328,37.25) BL37(-25.978,37.25) BM3(-1.613,38.129) BM5(-2.525,38.129) BM6(-3.169,38.231) BM7(-4.089,38.027) BM8(-4.876,38.027) BM9(-5.664,38.027) BM11(-6.451,38.027) BM12(-7.238,38.027) BM13(-8.026,38.027) BM14(-8.813,38.027) BM15(-9.601,38.027) BM16(-10.388,38.027) BM17(-11.175,38.027) BM18(-11.963,38.027) BM19(-12.75,38.027) BM20(-13.538,38.027) BM21(-14.325,38.027) BM22(-15.112,38.027) BM23(-15.9,38.027) BM24(-16.687,38.027) BM25(-17.475,38.027) BM26(-18.262,38.027) BM27(-19.049,38.027) BM28(-19.837,38.027) BM29(-20.624,38.027) BM30(-21.412,38.027) BM31(-22.199,38.027) BM33(-22.986,38.027) BM34(-23.774,38.027) BM35(-24.561,38.027) BM36(-25.328,37.986) BN4(-2.106,38.629) BN5(-2.748,38.793) BN7(-4.089,38.678) BN8(-4.876,38.678) BN9(-5.664,38.678) BN11(-6.451,38.678) BN12(-7.238,38.678) BN13(-8.026,38.678) BN14(-8.813,38.678) BN15(-9.601,38.678) BN16(-10.388,38.678) BN17(-11.175,38.678) BN18(-11.963,38.678) BN19(-12.75,38.678) BN20(-13.538,38.678) BN21(-14.325,38.678) BN22(-15.112,38.678) BN23(-15.9,38.678) BN24(-16.687,38.678) BN25(-17.475,38.678) BN26(-18.262,38.678) BN27(-19.049,38.678) BN28(-19.837,38.678) BN29(-20.624,38.678) BN30(-21.412,38.678) BN31(-22.199,38.678) BN33(-22.986,38.678) BN34(-23.774,38.678) BN35(-24.562,38.678) BP5(-2.374,39.351) BP6(-3.294,39.288) BP7(-4.089,39.328) BP8(-4.876,39.328) BP9(-5.664,39.328) BP11(-6.451,39.328) BP12(-7.238,39.328) BP13(-8.026,39.328) BP14(-8.813,39.328) BP15(-9.601,39.328) BP16(-10.388,39.328) BP17(-11.175,39.328) BP18(-11.963,39.328) BP19(-12.75,39.328) BP20(-13.538,39.328) BP21(-14.325,39.328) BP22(-15.112,39.328) BP23(-15.9,39.328) BP24(-16.687,39.328) BP25(-17.475,39.328) BP26(-18.262,39.328) BP27(-19.049,39.328) BP28(-19.837,39.328) BP29(-20.624,39.328) BP30(-21.412,39.328) BP31(-22.199,39.328) BP33(-22.986,39.328) BP34(-23.774,39.328) BR6(-3.192,39.961) BR7(-4.089,39.978) BR8(-4.876,39.978) BR9(-5.664,39.978) BR11(-6.451,39.978) BR12(-7.238,39.978) BR13(-8.026,39.978) BR14(-8.813,39.978) BR15(-9.601,39.978) BR16(-10.388,39.978) BR17(-11.175,39.978) BR18(-11.963,39.978) BR19(-12.75,39.978) BR20(-13.538,39.978) BR21(-14.325,39.978) BR22(-15.112,39.978) BR23(-15.9,39.978) BR24(-16.687,39.978) BR25(-17.475,39.978) BR26(-18.262,39.978) BR27(-19.049,39.978) BR28(-19.837,39.978) BR29(-20.624,39.978) BR30(-21.412,39.978) BR31(-22.199,39.978) BR33(-22.986,39.978) BT8(-4.648,40.628) BT9(-5.664,40.628) BT11(-6.451,40.628) BT12(-7.238,40.628) BT13(-8.026,40.628) BT14(-8.813,40.628) BT15(-9.601,40.628) BT16(-10.388,40.628) BT17(-11.175,40.628) BT18(-11.963,40.628) BT19(-12.75,40.628) BT20(-13.538,40.628) BT21(-14.325,40.628) BT22(-15.112,40.628) BT23(-15.9,40.628) BT24(-16.687,40.628) BT25(-17.475,40.628) BT26(-18.262,40.628) BT27(-19.049,40.628) BT28(-19.837,40.628) BT29(-20.624,40.628) BT30(-21.412,40.628) BT31(-22.174,40.628) C5(-2.743,1.3) C6(-3.531,1.3) C8(-4.318,1.3) C9(-5.105,1.3) C10(-5.893,1.3) C11(-6.68,1.3) C12(-7.468,1.3) C13(-8.255,1.3) C14(-9.042,1.3) C15(-9.83,1.3) C16(-10.617,1.3) C17(-11.405,1.3) C18(-12.192,1.3) C19(-12.979,1.3) C20(-13.767,1.3) C21(-14.554,1.3) C22(-15.342,1.3) C23(-16.129,1.3) C24(-16.916,1.3) C25(-17.704,1.3) C26(-18.491,1.3) C27(-19.279,1.3) C28(-20.066,1.3) C29(-20.853,1.3) C30(-21.641,1.3) C31(-22.428,1.3) C33(-23.216,1.3) C34(-24.011,1.29) D5(-2.743,1.951) D6(-3.531,1.951) D8(-4.318,1.951) D9(-5.105,1.951) D10(-5.893,1.951) D11(-6.68,1.951) D12(-7.468,1.951) D13(-8.255,1.951) D14(-9.042,1.951) D15(-9.83,1.951) D16(-10.617,1.951) D17(-11.405,1.951) D18(-12.192,1.951) D19(-12.979,1.951) D20(-13.767,1.951) D21(-14.554,1.951) D22(-15.342,1.951) D23(-16.129,1.951) D24(-16.916,1.951) D25(-17.704,1.951) D26(-18.491,1.951) D27(-19.279,1.951) D28(-20.066,1.951) D29(-20.853,1.951) D30(-21.641,1.951) D31(-22.428,1.951) D33(-23.216,1.951) D34(-24.003,1.951) D35(-24.655,1.861) E4(-1.951,2.575) E5(-2.743,2.601) E6(-3.531,2.601) E8(-4.318,2.601) E9(-5.105,2.601) E10(-5.893,2.601) E11(-6.68,2.601) E12(-7.468,2.601) E13(-8.255,2.601) E14(-9.042,2.601) E15(-9.83,2.601) E16(-10.617,2.601) E17(-11.405,2.601) E18(-12.192,2.601) E19(-12.979,2.601) E20(-13.767,2.601) E21(-14.554,2.601) E22(-15.342,2.601) E23(-16.129,2.601) E24(-16.916,2.601) E25(-17.704,2.601) E26(-18.491,2.601) E27(-19.279,2.601) E28(-20.066,2.601) E29(-20.853,2.601) E30(-21.641,2.601) E31(-22.428,2.601) E33(-23.216,2.601) E34(-24.003,2.601) E35(-24.678,2.604) E36(-25.328,2.604) F3(-1.3,3.16) F4(-1.951,3.261) F5(-2.743,3.273) F6(-3.531,3.273) F8(-4.318,3.251) F9(-5.105,3.251) F10(-5.893,3.251) F11(-6.68,3.251) F12(-7.468,3.251) F13(-8.255,3.251) F14(-9.042,3.251) F15(-9.83,3.251) F16(-10.617,3.251) F17(-11.405,3.251) F18(-12.192,3.251) F19(-12.979,3.251) F20(-13.767,3.251) F21(-14.554,3.251) F22(-15.342,3.251) F23(-16.129,3.251) F24(-16.916,3.251) F25(-17.704,3.251) F26(-18.491,3.251) F27(-19.279,3.251) F28(-20.066,3.251) F29(-20.853,3.251) F30(-21.641,3.251) F31(-22.428,3.251) F33(-23.216,3.251) F34(-24.027,3.392) F35(-24.678,3.392) F36(-25.328,3.392) F37(-25.978,3.392) G2(-0.65,3.947) G3(-1.3,3.947) G4(-1.951,3.947) G5(-2.601,3.947) G6(-3.251,3.947) G8(-4.318,3.901) G9(-5.105,3.901) G10(-5.893,3.901) G11(-6.68,3.901) G12(-7.468,3.901) G13(-8.255,3.901) G14(-9.042,3.901) G15(-9.83,3.901) G16(-10.617,3.901) G17(-11.405,3.901) G18(-12.192,3.901) G19(-12.979,3.901) G20(-13.767,3.901) G21(-14.554,3.901) G22(-15.342,3.901) G23(-16.129,3.901) G24(-16.916,3.901) G25(-17.704,3.901) G26(-18.491,3.901) G27(-19.279,3.901) G28(-20.066,3.901) G29(-20.853,3.901) G30(-21.641,3.901) H1(0,4.443) H11(-6.68,4.552) H12(-7.468,4.552) H13(-8.255,4.602) H14(-9.042,4.602) H15(-9.83,4.602) H16(-10.617,4.602) H17(-11.405,4.602) H18(-12.192,4.602) H19(-12.979,4.602) H20(-13.767,4.602) H21(-14.554,4.602) H22(-15.342,4.602) H23(-16.129,4.602) H24(-16.916,4.602) H25(-17.704,4.602) H26(-18.491,4.602) H27(-19.279,4.602) H28(-20.066,4.602) H29(-20.853,4.552) H30(-21.603,4.552) H32(-22.727,4.179) H33(-23.377,4.179) H34(-24.027,4.179) H35(-24.678,4.179) H36(-25.328,4.179) H37(-25.978,4.179) J2(-0.65,4.748) J3(-1.3,4.748) J4(-1.951,4.748) J5(-2.601,4.748) J6(-3.251,4.748) J7(-3.893,4.619) J8(-4.541,4.716) J9(-5.212,4.693) J10(-5.893,4.628) J14(-9.042,5.253) J15(-9.83,5.253) J16(-10.617,5.253) J17(-11.405,5.253) J18(-12.192,5.253) J19(-12.979,5.253) J20(-13.767,5.253) J21(-14.554,5.253) J22(-15.342,5.253) J23(-16.129,5.253) J24(-16.916,5.253) J25(-17.704,5.253) J26(-18.491,5.253) J27(-19.279,5.253) J28(-20.066,5.253) J30(-21.061,5.168) J31(-22.077,5.005) J32(-22.727,4.966) J33(-23.377,4.966) J34(-24.027,4.966) J35(-24.678,4.966) J36(-25.328,4.966) J37(-25.978,4.966) J38(-26.628,4.712) K1(0,5.586) K2(-0.65,5.586) K3(-1.3,5.586) K4(-1.951,5.586) K5(-2.601,5.586) K6(-3.251,5.586) K7(-3.911,5.557) K8(-4.561,5.48) K9(-5.212,5.48) K10(-5.862,5.48) K11(-6.512,5.48) K12(-7.162,5.48) K13(-7.879,5.176) K14(-8.463,5.658) K29(-20.725,5.754) K30(-21.376,5.754) K31(-22.077,5.754) K32(-22.727,5.754) K33(-23.377,5.754) K34(-24.027,5.754) K35(-24.678,5.754) K36(-25.328,5.754) K37(-25.978,5.754) K38(-26.628,5.754) L1(0,6.475) L2(-0.65,6.475) L3(-1.3,6.475) L4(-1.951,6.475) L5(-2.601,6.475) L6(-3.251,6.424) L7(-3.911,6.395) L8(-4.561,6.344) L9(-5.212,6.319) L10(-5.862,6.319) L11(-6.512,6.319) L12(-7.162,6.319) L13(-7.813,6.319) L14(-8.463,6.319) L29(-20.725,6.541) L30(-21.376,6.541) L31(-22.077,6.541) L32(-22.727,6.541) L33(-23.377,6.541) L34(-24.027,6.541) L35(-24.678,6.541) L36(-25.328,6.541) L37(-25.978,6.541) L38(-26.628,6.541) M1(0,7.212) M2(-0.65,7.212) M3(-1.3,7.212) M4(-1.951,7.212) M5(-2.601,7.212) M6(-3.251,7.263) M7(-3.911,7.233) M8(-4.561,7.233) M9(-5.212,7.233) M10(-5.862,7.233) M11(-6.512,7.233) M12(-7.162,7.233) M13(-7.813,7.233) M14(-8.463,7.233) M29(-20.725,7.329) M30(-21.376,7.329) M31(-22.077,7.329) M32(-22.727,7.329) M33(-23.377,7.329) M34(-24.027,7.329) M35(-24.678,7.329) M36(-25.328,7.329) M37(-25.978,7.329) M38(-26.628,7.329) N1(0,8.101) N2(-0.65,8.101) N3(-1.3,8.101) N4(-1.951,8.101) N5(-2.601,8.101) N6(-3.251,8.101) N7(-3.911,8.147) N8(-4.561,8.147) N9(-5.212,8.147) N10(-5.862,8.147) N11(-6.512,8.147) N12(-7.162,8.147) N13(-7.813,8.147) N14(-8.463,8.147) N29(-20.725,8.116) N30(-21.376,8.116) N31(-22.077,8.116) N32(-22.727,8.116) N33(-23.377,8.116) N34(-24.027,8.116) N35(-24.678,8.116) N36(-25.328,8.116) N37(-25.978,8.116) N38(-26.628,8.116) P1(0,8.99) P2(-0.65,8.99) P3(-1.3,8.99) P4(-1.951,8.99) P5(-2.601,8.99) P6(-3.251,8.939) P7(-3.911,9.062) P8(-4.561,9.062) P9(-5.212,9.062) P10(-5.862,9.062) P11(-6.512,9.062) P12(-7.162,9.062) P13(-7.813,9.062) P14(-8.463,9.062) P29(-20.725,8.903) P30(-21.376,8.903) P31(-22.077,8.903) P32(-22.727,8.903) P33(-23.377,8.903) P34(-24.027,8.903) P35(-24.678,8.903) P36(-25.328,8.903) P37(-25.978,8.903) P38(-26.628,8.903) R1(0,9.726) R2(-0.65,9.726) R3(-1.3,9.726) R4(-1.951,9.726) R5(-2.601,9.726) R6(-3.251,9.777) R7(-3.911,9.976) R8(-4.561,9.976) R9(-5.212,9.976) R10(-5.862,9.976) R11(-6.512,9.976) R12(-7.162,9.976) R13(-7.813,9.976) R14(-8.463,9.976) R29(-20.725,9.691) R30(-21.376,9.691) R31(-22.077,9.691) R32(-22.727,9.691) R33(-23.377,9.691) R34(-24.027,9.691) R35(-24.678,9.691) R36(-25.328,9.691) R37(-25.978,9.691) R38(-26.628,9.691) T1(0,10.615) T2(-0.65,10.615) T3(-1.3,10.615) T4(-1.951,10.615) T5(-2.601,10.615) T6(-3.251,10.615) T7(-3.911,10.891) T8(-4.561,10.891) T9(-5.212,10.891) T10(-5.862,10.891) T11(-6.512,10.891) T12(-7.162,10.891) T13(-7.813,10.891) T14(-8.463,10.891) T29(-20.725,10.478) T30(-21.376,10.478) T31(-22.077,10.478) T32(-22.727,10.478) T33(-23.377,10.478) T34(-24.027,10.478) T35(-24.678,10.478) T36(-25.328,10.478) T37(-25.978,10.478) T38(-26.628,10.478) U1(0,11.504) U2(-0.65,11.504) U3(-1.3,11.504) U4(-1.951,11.504) U5(-2.601,11.504) U6(-3.251,11.454) U29(-20.725,11.266) U30(-21.376,11.266) U31(-22.077,11.266) U32(-22.727,11.266) U33(-23.377,11.266) U34(-24.027,11.266) U35(-24.678,11.266) U36(-25.328,11.266) U37(-25.978,11.266) U38(-26.628,11.266) V1(0,12.241) V2(-0.65,12.241) V3(-1.3,12.241) V4(-1.951,12.241) V5(-2.601,12.241) V6(-3.251,12.292) V7(-3.911,11.805) V8(-4.561,11.805) V9(-5.212,11.805) V10(-5.862,11.805) V11(-6.512,11.805) V12(-7.162,11.805) V13(-7.813,11.805) V14(-8.463,11.805) V29(-20.725,12.053) V30(-21.376,12.053) V31(-22.077,12.053) V32(-22.727,12.053) V33(-23.377,12.053) V34(-24.027,12.053) V35(-24.678,12.053) V36(-25.328,12.053) V37(-25.978,12.053) V38(-26.628,12.053) W1(0,13.13) W2(-0.65,13.13) W3(-1.3,13.13) W4(-1.951,13.13) W5(-2.601,13.13) W6(-3.251,13.13) W7(-3.911,12.719) W8(-4.561,12.719) W9(-5.212,12.719) W10(-5.862,12.719) W11(-6.512,12.719) W12(-7.162,12.719) W13(-7.813,12.719) W14(-8.463,12.719) W29(-20.725,12.84) W30(-21.376,12.84) W31(-22.077,12.84) W32(-22.727,12.84) W33(-23.377,12.84) W34(-24.027,12.84) W35(-24.678,12.84) W36(-25.328,12.84) W37(-25.978,12.84) W38(-26.628,12.84) Y7(-3.911,13.634) Y8(-4.561,13.634) Y9(-5.212,13.634) Y10(-5.862,13.634) Y11(-6.512,13.634) Y12(-7.162,13.634) Y13(-7.813,13.634) Y14(-8.463,13.634) Y29(-20.725,13.628) Y30(-21.376,13.628) Y31(-22.077,13.628) Y32(-22.727,13.628) Y33(-23.377,13.628) Y34(-24.027,13.628) Y35(-24.678,13.628) Y36(-25.328,13.628) Y37(-25.978,13.628) Y38(-26.628,13.628)
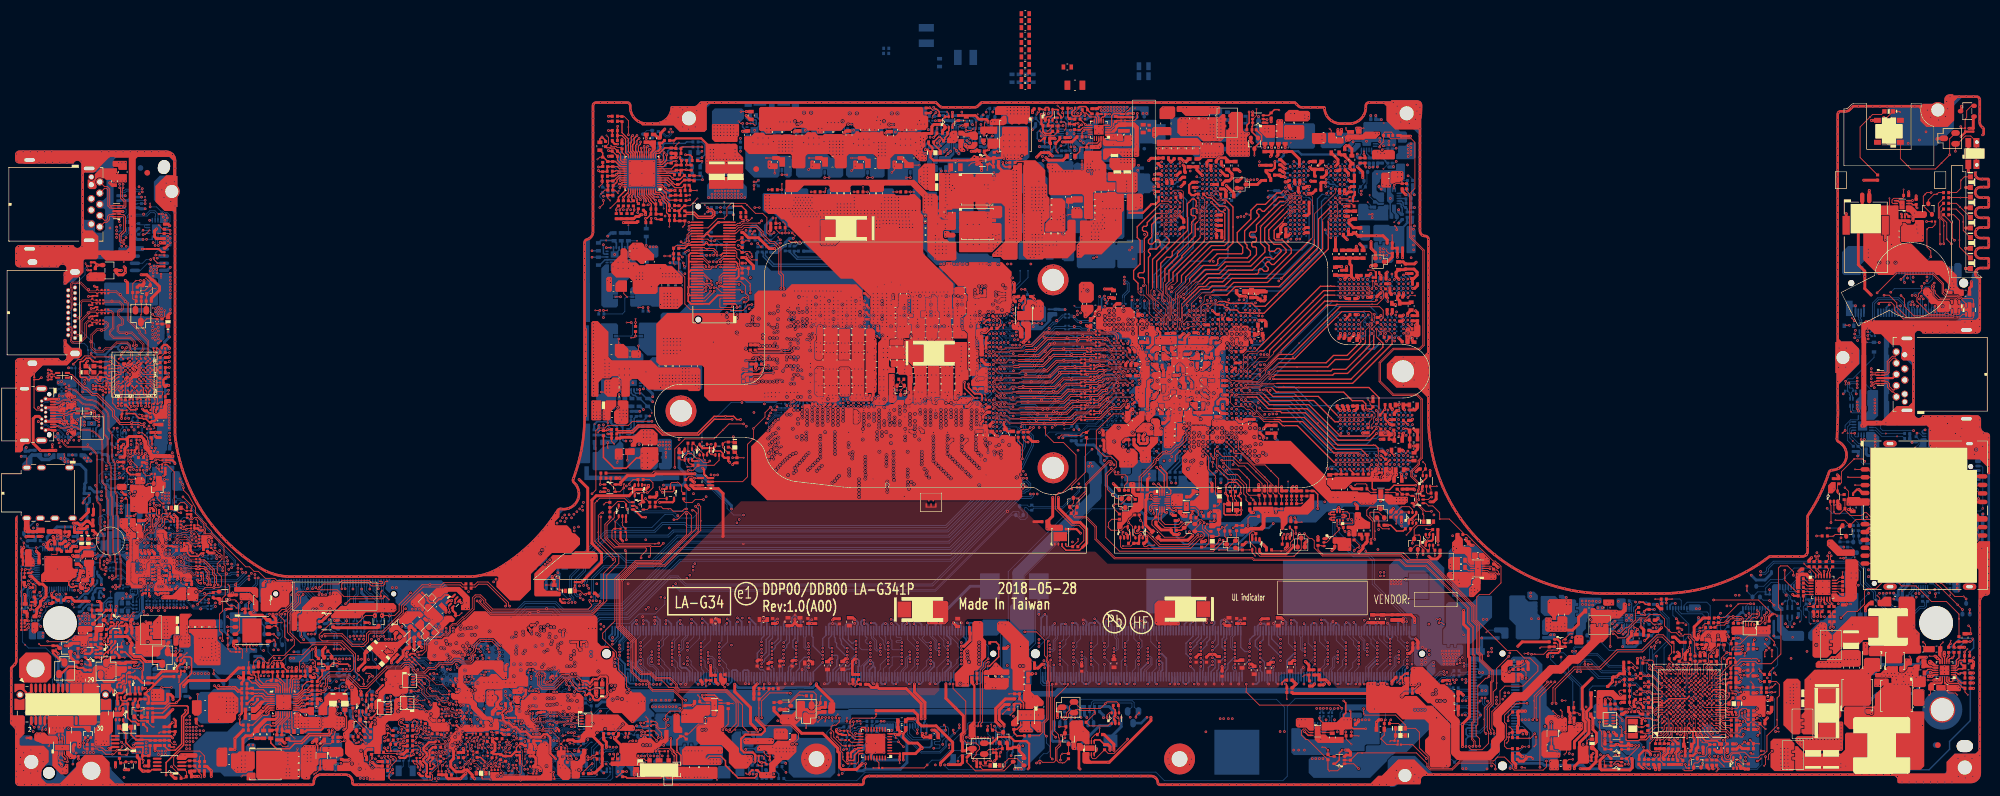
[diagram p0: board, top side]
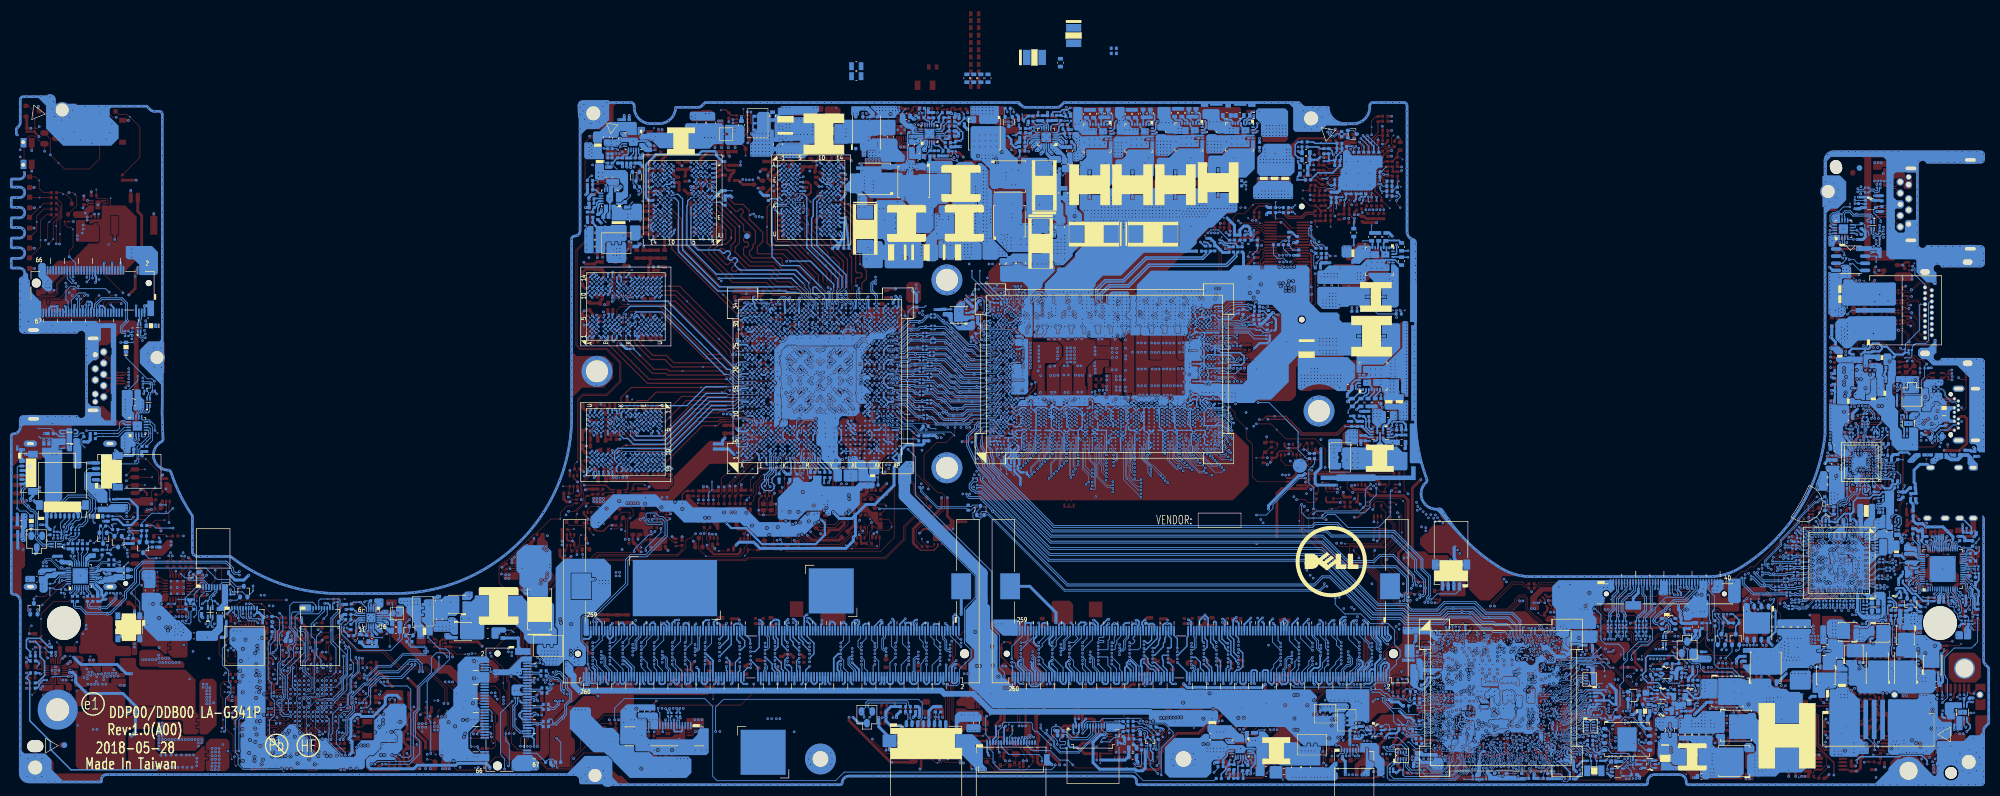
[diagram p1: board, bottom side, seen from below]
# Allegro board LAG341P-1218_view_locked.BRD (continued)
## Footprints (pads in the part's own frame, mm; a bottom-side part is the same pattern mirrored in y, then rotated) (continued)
RT9059GQW_WDFN10_3X3
  oval 0.254x0.889 smd: 1(0,0) 2(0.5,0) 3(1,0) 4(1.5,0) 5(2,0) 6(2,3.1) 7(1.5,3.1) 8(1,3.1) 9(0.5,3.1) 10(0,3.1)
  rect 2.464x1.626 smd: 11(1,1.55)
RT9069-33GB_SOT23-5
  oval 0.711x0.991 smd: 1(0,0) 2(0.95,0) 3(1.9,0) 4(1.9,2.6) 5(0,2.6)
RTS5242-GR_QFN32_4X4
  oval 0.889x0.203 smd: 1(0,0) 2(0,-0.4) 3(0,-0.8) 4(0,-1.2) 5(0,-1.6) 6(0,-2) 7(0,-2.4) 8(0,-2.8) 17(4.1,-2.8) 18(4.1,-2.4) 19(4.1,-2) 20(4.1,-1.6) 21(4.1,-1.2) 22(4.1,-0.8) 23(4.1,-0.4) 24(4.1,0)
  oval 0.203x0.889 smd: 9(0.65,-3.45) 10(1.05,-3.45) 11(1.45,-3.45) 12(1.85,-3.45) 13(2.25,-3.45) 14(2.65,-3.45) 15(3.05,-3.45) 16(3.45,-3.45) 25(3.45,0.65) 26(3.05,0.65) 27(2.65,0.65) 28(2.25,0.65) 29(1.85,0.65) 30(1.45,0.65) 31(1.05,0.65) 32(0.65,0.65)
  rect 2.692x2.692 smd: 33(2.05,-1.4)
SAMTE_BSH-030-01-L-D-A_60P
  round 1.016 hole 1.016 unplated: (-2.81,5.53) (17.316,5.53)
  oval 0.279x2.261 smd: 1(0,0) 2(0,5.728) 3(0.5,0) 4(0.5,5.728) 5(1,0) 6(1,5.728) 7(1.5,0) 8(1.5,5.728) 9(2,0) 10(2,5.728) 11(2.5,0) 12(2.5,5.728) 13(3,0) 14(3,5.728) 15(3.5,0) 16(3.5,5.728) 17(4,0) 18(4,5.728) 19(4.5,0) 20(4.5,5.728) 21(5,0) 22(5,5.728) 23(5.5,0) 24(5.5,5.728) 25(6,0) 26(6,5.728) 27(6.5,0) 28(6.5,5.728) 29(7,0) 30(7,5.728) 31(7.5,0) 32(7.5,5.728) 33(8,0) 34(8,5.728) 35(8.5,0) 36(8.5,5.728) 37(9,0) 38(9,5.728) 39(9.5,0) 40(9.5,5.728) 41(10,0) 42(10,5.728) 43(10.5,0) 44(10.5,5.728) 45(11,0) 46(11,5.728) 47(11.5,0) 48(11.5,5.728) 49(12,0) 50(12,5.728) 51(12.5,0) 52(12.5,5.728) 53(13,0) 54(13,5.728) 55(13.5,0) 56(13.5,5.728) 57(14,0) 58(14,5.728) 59(14.5,0) 60(14.5,5.728)
SHORTPADS
  custom 0.19x0.19 smd: 1(-0.483,0) 2(0.483,0)
SI1303DL-T1-E3_SOT323-3
  oval 0.813x0.914 smd: 1(0,0) 2(0.65,1.6) 3(-0.65,1.6)
SI3457BDV-T1-E3_TSOP6
  oval 0.508x1.448 smd: 1(0,0) 2(1,0) 3(2,0) 4(2,2.425) 5(1,2.425) 6(0,2.425)
SLG4U41821VTR_STQFN20_2X3
  oval 0.813x0.203 smd: 1(0,0) 2(0,-0.4) 6(0,-2) 7(0,-2.4) 11(2.175,-2.4) 12(2.175,-2) 16(2.175,-0.4) 17(2.175,0)
  oval 1.295x0.203 smd: 3(0.238,-0.8)
  oval 1.092x0.203 smd: 4(0.138,-1.2) 5(0.138,-1.6) 13(2.038,-1.6) 14(2.038,-1.2) 15(2.038,-0.8)
  oval 0.203x1.092 smd: 8(0.688,-2.65) 9(1.088,-2.65) 10(1.488,-2.65) 18(1.488,0.25) 19(1.088,0.25) 20(0.688,0.25)
SMF22A-SOD123FL-2-S
  rect 1.295x1.397 smd: 1(0,0) 2(2.9,0)
SW_NTC311-EA1T-A160T_4P
  rect 1.651x1.041 smd: 1(0,0) 2(3.85,0)
  rect 1.651x1.041 hole 0.66: 3(-0.1,-1.525) 4(3.95,-1.525)
SW_SKRBAAE010_4P
  rect 0.889x1.219 smd: 1(0,0) 2(3.9,0) 3(0,4.075) 4(3.9,4.075)
SW_SSAL120100_3P
  rect 0.787x0.787 smd: 1(0,0) 3(3.4,0)
  rect 1.194x0.787 smd: 2(1.7,0)
  rect 1.041x0.889 smd: 4(-2.375,-1.6) 5(5.775,-1.6)
SY6288C20AAC_SOT23-5
  oval 0.559x0.787 smd: 1(0,0) 2(0.95,0) 3(1.9,0) 4(1.9,2.4) 5(0,2.4)
SY8286RAC_QFN20_3X3
  oval 0.889x0.254 smd: 1(0,0) 2(0,-0.45) 3(0,-0.9) 4(0,-1.35) 5(0,-1.8) 11(3.1,-1.8) 12(3.1,-1.35) 13(3.1,-0.9) 14(3.1,-0.45) 15(3.1,0)
  oval 0.254x0.889 smd: 6(0.65,-2.45) 7(1.1,-2.45) 8(1.55,-2.45) 9(2,-2.45) 10(2.45,-2.45) 16(2.45,0.65) 17(2,0.65) 18(1.55,0.65) 19(1.1,0.65) 20(0.65,0.65)
  rect 0.991x0.991 smd: 21(1.55,-0.9)
SY8288RAC_QFN20_3X3
  oval 0.889x0.254 smd: 1(0,0) 2(0,-0.45) 3(0,-0.9) 4(0,-1.35) 5(0,-1.8) 11(3.1,-1.8) 12(3.1,-1.35) 13(3.1,-0.9) 14(3.1,-0.45) 15(3.1,0)
  oval 0.254x0.889 smd: 6(0.65,-2.45) 7(1.1,-2.45) 8(1.55,-2.45) 9(2,-2.45) 10(2.45,-2.45) 16(2.45,0.65) 17(2,0.65) 18(1.55,0.65) 19(1.1,0.65) 20(0.65,0.65)
  rect 0.991x0.991 smd: 21(1.55,-0.9)
T-SOL_156-1051902601_19P-T
  round 0.889 hole 0.889 unplated: (-20.3,-1.65) (0.5,-18.8)
  oval 0.787x1.6 smd: 1(0,0) 2(-1.4,0) 3(-2.8,0) 4(-4.2,0) 5(-5.6,0) 6(-9.75,0) 7(-11.15,0) 8(-12.55,0) 9(-13.95,0) 10(-15.35,0) 11(-16.75,0)
  oval 0.787x1.702 smd: 12(-1.25,-20.92) 13(-2.775,-20.92) 14(-4.275,-20.92) 15(-5.8,-20.92) 16(-8.75,-20.92) 17(-10.275,-20.92) 18(-11.775,-20.92) 19(-13.3,-20.92)
  oval 1.092x2.388 hole 0.559x1.194: 20(4.575,-4.45) 21(4.575,-18.6) 22(-20.875,-4.45) 23(-20.875,-18.6)
TAI-T_HCB2012KF-121T50_2P
  rect 0.813x1.397 smd: 1(0,0) 2(1.702,0)
TAIWI_USB019-107CRL-TWD_10P-T
  round 1.219 hole 0.914: 1(0,0)
  round 1.321 hole 0.914: 2(2.5,0) 3(4.5,0) 4(7,0) 5(7.5,1.5) 6(5.5,1.5) 7(3.5,1.5) 8(1.5,1.5) 9(-0.5,1.5)
  round 1.067 hole 0.762: 10(-1.37,0)
  oval 1.372x2.667 hole 0.61x1.905: 11(-2.9,-0.39) 12(-4.4,-10.98) 13(11.4,-10.98) 14(9.9,-0.39)
TC7SH08FU_SSOP5
  oval 0.406x0.787 smd: 1(0,0) 2(0.65,0) 3(1.3,0) 4(1.3,1.9) 5(0,1.9)
TPC12
  round 0.305 smd: 1(0,0)
TPS2546RTER_QFN16_3X3
  oval 0.254x0.889 smd: 1(0,0) 2(0.5,0) 3(1,0) 4(1.5,0) 9(1.5,3.1) 10(1,3.1) 11(0.5,3.1) 12(0,3.1)
  oval 0.889x0.254 smd: 5(2.3,0.8) 6(2.3,1.3) 7(2.3,1.8) 8(2.3,2.3) 13(-0.8,2.3) 14(-0.8,1.8) 15(-0.8,1.3) 16(-0.8,0.8)
  rect 1.651x1.651 smd: 17(0.75,1.55)
TPS22961DNYR_WSON8
  oval 0.305x0.508 smd: 1(0,0) 2(0.65,0) 3(1.3,0) 4(1.95,0) 5(1.95,2.7)
  oval 1.6x0.508 smd: 6(0.65,2.7)
  rect 2.388x1.6 smd: 7(0.975,1.35)
TPS51285BRUKR_QFN20_3X3
  oval 0.889x0.203 smd: 1(0,0) 2(0,-0.4) 3(0,-0.8) 4(0,-1.2) 5(0,-1.6) 11(3.1,-1.6) 12(3.1,-1.2) 13(3.1,-0.8) 14(3.1,-0.4) 15(3.1,0)
  oval 0.203x0.889 smd: 6(0.75,-2.35) 7(1.15,-2.35) 8(1.55,-2.35) 9(1.95,-2.35) 10(2.35,-2.35) 16(2.35,0.75) 17(1.95,0.75) 18(1.55,0.75) 19(1.15,0.75) 20(0.75,0.75)
  rect 1.702x1.702 smd: 21(1.55,-0.8)
TPS65982_BGA_96P
  round 0.254 smd: A1(0,0) A2(0.5,0) A3(1,0) A4(1.5,0) A5(2.001,0) A6(2.501,0) A7(3.001,0) A8(3.501,0) A9(4.001,0) A10(4.501,0) A11(5.001,0) B1(0,-0.5) B2(0.5,-0.5) B3(1,-0.5) B4(1.5,-0.5) B5(2.001,-0.5) B6(2.501,-0.5) B7(3.001,-0.5) B8(3.501,-0.5) B9(4.001,-0.5) B10(4.501,-0.5) B11(5.001,-0.5) C1(0,-1) C2(0.5,-1) C10(4.501,-1) C11(5.001,-1) D1(0,-1.5) D2(0.5,-1.5) D5(2.001,-1.5) D6(2.501,-1.5) D7(3.001,-1.5) D8(3.501,-1.5) D10(4.501,-1.5) D11(5.001,-1.5) E1(0,-2.001) E2(0.5,-2.001) E4(1.5,-2.001) E5(2.001,-2.001) E6(2.501,-2.001) E7(3.001,-2.001) E8(3.501,-2.001) E10(4.501,-2.001) E11(5.001,-2.001) F1(0,-2.501) F2(0.5,-2.501) F4(1.5,-2.501) F5(2.001,-2.501) F6(2.501,-2.501) F7(3.001,-2.501) F8(3.501,-2.501) F10(4.501,-2.501) F11(5.001,-2.501) G1(0,-3.001) G2(0.5,-3.001) G4(1.5,-3.001) G5(2.001,-3.001) G6(2.501,-3.001) G7(3.001,-3.001) G8(3.501,-3.001) G10(4.501,-3.001) G11(5.001,-3.001) H1(0,-3.501) H2(0.5,-3.501) H4(1.5,-3.501) H5(2.001,-3.501) H6(2.501,-3.501) H7(3.001,-3.501) H8(3.501,-3.501) H10(4.501,-3.501) H11(5.001,-3.501) J1(0,-4.001) J2(0.5,-4.001) J10(4.501,-4.001) J11(5.001,-4.001) K1(0,-4.501) K2(0.5,-4.501) K3(1,-4.501) K4(1.5,-4.501) K5(2.001,-4.501) K6(2.501,-4.501) K7(3.001,-4.501) K8(3.501,-4.501) K9(4.001,-4.501) K10(4.501,-4.501) K11(5.001,-4.501) L1(0,-5.001) L2(0.5,-5.001) L3(1,-5.001) L4(1.5,-5.001) L5(2.001,-5.001) L6(2.501,-5.001) L7(3.001,-5.001) L8(3.501,-5.001) L9(4.001,-5.001) L10(4.501,-5.001) L11(5.001,-5.001)
TVNST52302AB0_SOT523-3
  oval 0.508x0.559 smd: 1(0,0) 2(-0.5,-1.4) 3(0.5,-1.4)
W25Q80DVZPIG_WSON8
  oval 0.66x1.092 smd: 1(0,0) 2(1.27,0) 3(2.54,0) 4(3.81,0) 5(3.81,5.9) 6(2.54,5.9) 7(1.27,5.9) 8(0,5.9)
  rect 4.293x3.404 smd: 9(1.905,2.95)
W25Q256FVEIG_WSON8
  oval 0.66x0.991 smd: 1(0,0) 2(1.27,0) 3(2.54,0) 4(3.81,0) 5(3.81,8) 6(2.54,8) 7(1.27,8) 8(0,8)
  rect 4.293x3.404 smd: 9(1.905,4)
W25X20CLSNIG_SO8
  oval 0.635x1.854 smd: 1(0,0) 2(1.27,0) 3(2.54,0) 4(3.81,0) 5(3.81,5.165) 6(2.54,5.165) 7(1.27,5.165) 8(0,5.165)
Y_8Y24000034_4P
  rect 0.889x0.787 smd: 1(0,0) 2(1.4,0) 3(1.4,1.1) 4(0,1.1)
Y_CM7V-12520_2P
  rect 0.991x1.803 smd: 1(0,0) 2(2.5,0)
Y_CM31532768DZFT_2P
  rect 1.092x1.905 smd: 1(0,0) 2(2.5,0)
YUQIU_PJ567-F07J1BE-C_6P
  oval 0.991x1.6 hole 0.61x1.194: 1(0,0) 2(0,5) 3(0,7.6) 4(-9,7.6) 6(-9,5.2) 7(-9,2.6)
  oval 0.991x1.499 hole 0.61x1.092: 5(-9,-0.55)

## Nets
1.2V_B+: PC601.1 PC602.1 PC603.1 PC604.1 PC615.1 PJP600.2 PL601.2 PQ600.5 PR605.1
1.2V_DDR_EN: CZ2156.1 DZ59.2 PR606.1 RZ1966.2
1.2V_FB: PC612.1 PR604.1 PR607.1 PU600.6
1.8V_PRIM_PWRGD: PR503.1 PR1651.2 RT5839.2
1.8V_PRIM_PWRGD_OK: RT1139.1 RT5839.1 RT5840.1
1V8_AON_EN: CV920.1 DA57.1 QV3.2 RV1350.1 RZ1964.1 UZ31.4
1V8_MAIN_EN: DA56.1 DV16.2 PR1004.2 RH5893.2 RV562.1 RV1130.2 RZ106.1 UV18.P7
1V8_MAIN_RUN_EN: DA57.2 DV16.1 QZ17.2 RZ106.2 UZ24.3
1VS_GFX_PG: DV13.2 PR952.2 UV20.1
3.3V_CAM_EN#: QZ9.2 RZ38.1 UH2.BE41
3.3V_MSATA_EN: RH423.1 UH2.BE18
3V/5VALW_EN: PC335.1 PR326.2 PR408.1 PR409.2
5VS_FAN1: JFAN1.2 RE104.2
5VS_FAN2: JFAN2.2 RE105.2
+0.6V_A_VREFDQ: UH1.BP13
+0.6VS: CD12.1 CD13.1 CD14.1 CD15.1 CD32.1 CD88.1 CD89.1 CD90.1 JDIMM1.258 JDIMM2.258 PJP602.2
+0.6VSP: PC605.1 PC606.1 PJP602.1 PU600.2 PU600.20
+0.95VS_VCCIOP: PC807.1 PC808.1 PC809.1 PJP801.1 PL800.2 PR840.2
+1.2V_DDR: CD1.1 CD2.1 CD5.1 CD6.1 CD7.1 CD8.1 CD11.1 CD19.1 CD20.1 CD21.1 CD22.1 CD23.1 CD24.1 CD25.1 CD26.1 CD33.1 CD70.1 CD71.1 CD72.1 CD73.1 CD74.1 CD75.1 CD76.1 CD77.1 CD78.1 CD79.1 CD80.1 CD81.1 CD82.1 CD83.1 CD84.1 CD85.1 CD86.1 CD87.1 CH197.1 JDIMM1.12 JDIMM1.33 JDIMM1.54 JDIMM1.75 JDIMM1.96 JDIMM1.111 JDIMM1.112 JDIMM1.117 JDIMM1.118 JDIMM1.123 JDIMM1.124 JDIMM1.129 JDIMM1.130 JDIMM1.135 JDIMM1.136 JDIMM1.141 JDIMM1.142 JDIMM1.147 JDIMM1.148 JDIMM1.153 JDIMM1.154 JDIMM1.159 JDIMM1.160 JDIMM1.163 JDIMM1.178 JDIMM1.199 JDIMM1.220 JDIMM1.241 JDIMM2.12 JDIMM2.33 JDIMM2.54 JDIMM2.75 JDIMM2.96 JDIMM2.111 JDIMM2.112 JDIMM2.117 JDIMM2.118 JDIMM2.123 JDIMM2.124 JDIMM2.129 JDIMM2.130 JDIMM2.135 JDIMM2.136 JDIMM2.141 JDIMM2.142 JDIMM2.147 JDIMM2.148 JDIMM2.153 JDIMM2.154 JDIMM2.159 JDIMM2.160 JDIMM2.163 JDIMM2.178 JDIMM2.199 JDIMM2.220 JDIMM2.241 PJP603.2 PJP1604.2 R5843.2 RD35.1 RH206.1 RH207.1 RH530.2 UC1.5 UZ16.1 UZ16.2 UZ16.7 UZ25.1 UZ25.2
+1.2V_DDR_PG: PR651.1 RZ82.1 RZ84.2 UZ19.1
+1.2V_DTH: CM8.1 CM22.1 CM26.1 CM37.1 CZ101.2 LM2.1 LM3.1 LM4.1 LM5.1 UZ25.7 UZ25.8
+1.2V_MEN_P: PC608.1 PC612.2 PJP601.1 PJP603.1 PL600.1 PR604.2 PU600.5
+1.2V_PWROK: PR609.2 PR651.2 PU600.10
+1.2V_VCCPLL_OC: CH3332.1 CH3333.1 CZ49.1 RH530.1 UH1.BH13 UH1.BJ13 UH1.G11 UZ16.6
+1.8V_3.3V_ALW_VTR3: C3319.1 RE183.2 RZ1148.2 UE3.N5
+1.8V_GFX_AON: CV794.1 CV796.1 CV798.1 CV817.1 CV853.1 CV892.1 CV893.1 CV894.1 CV895.1 CV917.1 PR1000.1 PR1500.1 RV11.1 RV325.1 RV326.1 RV551.2 RV552.2 RV553.2 RV554.2 RV557.2 RV562.2 RV563.2 RV564.2 RV570.2 RV571.2 RV572.2 RV573.2 RV591.1 RV594.2 RV645.2 RV646.2 RV647.2 RV648.2 RV649.2 RV650.2 RV1080.1 RV1112.1 RV1834.2 RV1839.2 RV1842.1 UV18.J8 UV18.K8 UV19.5 UV20.5 UV28.5 UV29.5 UZ24.1 UZ24.2 UZ30.7 UZ30.8
+1.8V_GFX_RUN: CV904.1 CV905.1 CV906.1 CV907.1 CZ99.1 LV23.2 LV24.2 RV597.2 RV1068.2 RV1811.1 UV18.L8 UV18.M8 UZ24.7 UZ24.8
+1.8V_GFX_RUN_R: CV874.1 CV875.1 CV876.1 CV877.1 CV878.1 CV879.1 CV880.2 CV881.2 CV882.1 RV1068.1 UV18.AG13 UV18.AG15 UV18.AG16 UV18.AG18 UV18.AG25 UV18.AH15 UV18.AH18 UV18.AH26 UV18.AH27 UV18.AJ27 UV18.AK27 UV18.AL27 UV18.AM28 UV18.AN28
+1.8V_PCH: CH92.1 CH205.1 CZ106.1 RE321.2 RH599.1 RH1957.2 RH5853.1 RH5854.1 RH5855.1 RH5880.2 UH2.AN15 UH2.AR15 UH2.BB11 UZ26.5 UZ29.7 UZ29.8
+1.8V_PCH_I_LDO: RE321.1 UH2.AG19 UH2.AG20
+1.8V_PCH_LDO: RH5880.1 UH2.AF19 UH2.AF20
+1.8V_PLLVDD: CV855.1 CV856.1 LV23.1 RV574.2 RV575.2 RV576.2 RV582.2
+1.8VALW: CA121.1 CZ1501.1 PJP1600.2 RH1957.1 RZ1148.1 UA3.1 UA3.2 UZ29.1 UZ29.2 UZ30.1 UZ30.2
+1.8VS_AUDIO: CA122.1 RA2.1 UA3.7 UA3.8
+1.25V_DPHY_MAR: CA131.1 RH5879.2 T5004.1(TP-1) UH2.AJ22 UH2.AJ23 UH2.BG5
+1.25V_LDOSRAM: RH5879.1 T5003.1(TP-1) UH2.AK22 UH2.AK23
+1.35VS_B+: PC700.1 PC701.1 PC702.1 PC703.1 PC704.1 PC705.1 PL777.1 PQ700.2 PR701.2
+1.35VS_VGAP: PC714.1 PC715.1 PC716.1 PC717.1 PC718.1 PC719.1 PC721.1 PC722.1 PC723.1 PC724.1 PJP701.1 PJP702.1 PL700.2 PR711.2
+1.35VSDGPU: CV862.1 CV863.1 CV864.2 CV870.1 CV871.1 CV872.1 CV873.2 CV883.2 CV884.2 CV885.1 CV886.1 CV887.1 CV888.1 CV889.1 CV890.1 CV896.2 CV897.2 CV898.1 CV899.1 CV900.1 CV901.1 CV902.1 CV903.1 CV929.1 CV930.1 CV931.1 CV932.1 CV933.1 CV934.1 CV935.1 CV936.1 CV937.1 CV938.1 CV939.1 CV940.1 CV941.1 CV942.1 CV943.1 CV944.1 CV945.1 CV946.1 CV947.1 CV948.1 CV949.1 CV950.1 CV951.1 CV952.1 CV953.1 CV954.1 CV955.1 CV956.1 CV957.1 CV958.1 CV959.1 CV960.1 CV961.1 CV962.1 CV963.1 CV964.1 CV965.1 CV966.1 CV967.1 CV968.1 CV969.1 CV970.1 CV971.1 CV972.1 CV973.1 CV974.1 CV975.1 CV976.1 CV977.1 CV978.1 CV979.1 CV980.1 CV981.1 CV982.1 CV983.1 CV984.1 CV985.1 CV986.1 CV991.1 CV992.1 CV993.1 CV994.1 CV995.1 CV996.1 CV997.1 CV998.1 CV999.1 CV1000.1 CV1001.1 CV1002.1 CV1003.1 CV1004.1 CV1005.1 CV1006.1 CV1007.1 CV1008.1 CV1009.1 CV1010.1 CV1011.1 CV1012.1 CV1013.1 CV1014.1 CV1015.1 CV1016.1 CV1017.1 CV1018.1 CV1019.1 CV1020.1 CV1021.1 CV1022.1 CV1023.1 CV1024.1 CV1025.1 CV1026.1 CV1027.1 CV1028.1 CV1029.1 CV1030.1 CV1031.1 CV1032.1 CV1033.1 CV1034.1 CV1035.1 CV1036.1 CV1037.1 CV1038.1 CV1039.1 CV1040.1 CV1041.1 CV1042.1 CV1043.1 CV1044.1 CV1045.1 CV1046.1 CV1047.1 CV1048.1 PJP701.2 PJP702.2 RV8.1 RV600.1 RV605.1 RV606.1 RV607.1 RV608.1 RV618.2 RV623.1 RV630.2 RV634.1 UV18.AA27 UV18.AA30 UV18.AB27 UV18.AB33 UV18.AC27 UV18.AD27 UV18.AE27 UV18.AF27 UV18.AG27 UV18.B13 UV18.B16 UV18.B19 UV18.E13 UV18.E16 UV18.E19 UV18.H8 UV18.H9 UV18.H10 UV18.H11 UV18.H12 UV18.H13 UV18.H14 UV18.H15 UV18.H16 UV18.H18 UV18.H19 UV18.H20 UV18.H21 UV18.H22 UV18.H23 UV18.H24 UV18.L27 UV18.M27 UV18.N27 UV18.P27 UV18.R27 UV18.T27 UV18.T30 UV18.T33 UV18.V27 UV18.W27 UV18.W30 UV18.W33 UV18.Y27 UV23.B1 UV23.B3 UV23.B12 UV23.B14 UV23.C5 UV23.C10 UV23.D1 UV23.D3 UV23.D11 UV23.D12 UV23.D14 UV23.E5 UV23.E10 UV23.F1 UV23.F3 UV23.F12 UV23.F14 UV23.G1 UV23.G2 UV23.G4 UV23.G11 UV23.G13 UV23.G14 UV23.H3 UV23.H12 UV23.K3 UV23.K12 UV23.L1 UV23.L2 UV23.L4 UV23.L11 UV23.L13 UV23.L14 UV23.M1 UV23.M3 UV23.M12 UV23.M14 UV23.N5 UV23.N10 UV23.P1 UV23.P3 UV23.P11 UV23.P12 UV23.P14 UV23.R5 UV23.R10 UV23.T1 UV23.T3 UV23.T12 UV23.T14 UV24.B1 UV24.B3 UV24.B12 UV24.B14 UV24.C5 UV24.C10 UV24.D1 UV24.D3 UV24.D11 UV24.D12 UV24.D14 UV24.E5 UV24.E10 UV24.F1 UV24.F3 UV24.F12 UV24.F14 UV24.G1 UV24.G2 UV24.G4 UV24.G11 UV24.G13 UV24.G14 UV24.H3 UV24.H12 UV24.K3 UV24.K12 UV24.L1 UV24.L2 UV24.L4 UV24.L11 UV24.L13 UV24.L14 UV24.M1 UV24.M3 UV24.M12 UV24.M14 UV24.N5 UV24.N10 UV24.P1 UV24.P3 UV24.P11 UV24.P12 UV24.P14 UV24.R5 UV24.R10 UV24.T1 UV24.T3 UV24.T12 UV24.T14 UV25.B1 UV25.B3 UV25.B12 UV25.B14 UV25.C5 UV25.C10 UV25.D1 UV25.D3 UV25.D11 UV25.D12 UV25.D14 UV25.E5 UV25.E10 UV25.F1 UV25.F3 UV25.F12 UV25.F14 UV25.G1 UV25.G2 UV25.G4 UV25.G11 UV25.G13 UV25.G14 UV25.H3 UV25.H12 UV25.K3 UV25.K12 UV25.L1 UV25.L2 UV25.L4 UV25.L11 UV25.L13 UV25.L14 UV25.M1 UV25.M3 UV25.M12 UV25.M14 UV25.N5 UV25.N10 UV25.P1 UV25.P3 UV25.P11 UV25.P12 UV25.P14 UV25.R5 UV25.R10 UV25.T1 UV25.T3 UV25.T12 UV25.T14 UV26.B1 UV26.B3 UV26.B12 UV26.B14 UV26.C5 UV26.C10 UV26.D1 UV26.D3 UV26.D11 UV26.D12 UV26.D14 UV26.E5 UV26.E10 UV26.F1 UV26.F3 UV26.F12 UV26.F14 UV26.G1 UV26.G2 UV26.G4 UV26.G11 UV26.G13 UV26.G14 UV26.H3 UV26.H12 UV26.K3 UV26.K12 UV26.L1 UV26.L2 UV26.L4 UV26.L11 UV26.L13 UV26.L14 UV26.M1 UV26.M3 UV26.M12 UV26.M14 UV26.N5 UV26.N10 UV26.P1 UV26.P3 UV26.P11 UV26.P12 UV26.P14 UV26.R5 UV26.R10 UV26.T1 UV26.T3 UV26.T12 UV26.T14
+1V_MPHY_MPHYPLL: CH180.1 CH181.1 CH182.1 LH3.2 UH2.C49 UH2.D49 UH2.E49
+1V_PCH: CH3.1 CH183.1 CH184.1 CH201.1 CH202.1 CH207.1 CH3323.1 CH3324.1 JXDP.43 JXDP.44 LH2.1 LH3.1 LH4.1 PJP1302.2 RH492.1 RH5856.1 UH2.AD31 UH2.AF31 UH2.AG31 UH2.B1 UH2.B2 UH2.B3 UH2.C1 UH2.C2 UH2.U26 UH2.U29 UH2.V19 UH2.V25 UH2.V27 UH2.V28 UH2.V30 UH2.V31 UH2.W19 UH2.W20 UH2.W22 UH2.W23 UH2.W31
+1V_PCH_AZPLL: CH203.1 CH3322.1 LH2.2 UH2.D1 UH2.E1
+1V_PCH_CLK5: CH177.1 CH178.1 CH179.1 LH4.2 UH2.P2 UH2.P3
+1V_PCH_CNVI: RH5856.2 UH2.AE17
+1V_PCH_PRIM: CH176.1 CH206.1 PJP1303.2 UH2.AA22 UH2.AA23 UH2.AB20 UH2.AB22 UH2.AB23 UH2.AB27 UH2.AB28 UH2.AB30 UH2.AD20 UH2.AD23 UH2.AD27 UH2.AD28 UH2.AD30 UH2.AF23 UH2.AF27 UH2.AF30
+1V_VCCDSW: CH3329.1 UH2.BG45 UH2.BG46
+1VALW: CZ88.1 CZ96.1 PJP500.2 PJP1302.1 PJP1303.1 UZ9.1 UZ9.2 UZ9.7 UZ15.1 UZ15.2 UZ15.7
+1VALW_PG: PR521.2 RT5840.2
+1VS_GFX: CV859.1 CV860.1 CV861.1 CV865.1 CV866.1 CV867.1 CV868.2 CV869.1 PJP900.1 RV112.1 UV18.AG19 UV18.AG21 UV18.AG22 UV18.AG24 UV18.AH21 UV18.AH25
+1VSP: PC506.1 PC507.1 PC508.1 PC509.1 PC510.1 PJP500.1 PL501.2 PR504.1
+2.5V_MEM: CD3.1 CD4.1 CD9.1 CD10.1 CD27.1 CD28.1 CD30.1 CD31.1 JDIMM1.257 JDIMM1.259 JDIMM2.257 JDIMM2.259 PR1805.2
+2.5V_MEM_PG: PR1851.2 PT201.1(TP-1)
+2.5VSP_ON: PC1800.1 PR1801.2 PU1800.6
+3.3V_1.8V_ESPI: RH518.2 RH597.2 RH1943.2 RH5838.2 UH2.AN32
+3.3V_1.8V_PGPPA: RH597.1 RH599.2
+3.3VDX_SSD: CD36.1 CD38.1 CD39.1 CD40.1 CD41.1 CZ46.1 JNGFF2.2 JNGFF2.4 JNGFF2.12 JNGFF2.14 JNGFF2.16 JNGFF2.18 JNGFF2.62 JNGFF2.64 JNGFF2.66 RD7.1 RD8.2 UZ32.7 UZ32.8
+3V_LDOP: PQ222.1 PR289.2
+3V_PCH: CH82.1 CH187.1 CH189.1 CH190.1 CH191.1 CH192.1 CH204.1 CH3321.1 CZ19.1 DH2.2 JAPS.1 LH1.1 RE86.1 RH42.1 RH74.1 RH75.1 RH78.1 RH82.1 RH110.2 RH119.1 RH120.1 RH130.1 RH458.1 RH459.1 RH460.1 RH461.1 RH493.1 RH501.1 RH502.1 RH503.1 RH504.1 RH505.1 RH506.2 RH508.2 RH513.2 RH523.1 RH524.1 RH536.1 RH546.2 RH552.2 RH553.2 RH554.2 RH555.2 RH557.2 RH564.1 RH566.1 RH571.2 RH585.2 RH586.2 RH5857.1 RH5860.1 RH5875.1 RH5881.1 RH5889.2 RP8.5 RP8.6 RP8.7 RP8.8 RT5857.1 RZ18.2 RZ84.1 UH2.AC35 UH2.AC36 UH2.AE35 UH2.AE36 UH2.AN21 UH2.AN24 UH2.AN26 UH2.AN44 UH2.AP26 UH2.AT44 UH2.AW9 UH2.AY8 UH2.BB7 UH2.V23 UZ12.5 UZ19.5 UZ20.5 UZ21.5 UZ31.5
+3V_PCH_AZIO: CH200.1 CH3320.1 LH1.2 UH2.BB14
+3V_PCH_BR: RH5866.1 RZ18.1 UZ4.7 UZ4.8
+3V_PCH_CT: CZ20.1 UZ4.6
+3V_PCH_DSW: RH2.1 RH453.2 RH515.2 RH533.2 RH545.2 RH5837.1 RH5842.2 RH5864.2 RH5865.2 UH2.BE48 UH2.BE49
+3V_PCH_DSW_RR: QH1.1 RH5865.1
+3V_PCH_ME_SW: RH536.2 SW4.1
+3V_PS8723: CI3.1 CI4.1 RI14.2 RI15.2 RI16.2 RI17.2 RI18.2 RI19.2 RI20.2 RI21.2 RI22.2 RI24.2 RI45.2 UI3.1 UI3.13
+3V_ROM: DH2.1 JSPI1.8 JSPI1.9 RH585.1 UH8.8
+3V_TBT: CT52.1 CT53.1 CT54.1 CT55.1 CT56.1 LT14.2 RT21.1 RT46.2 RT202.1 RT241.1 UT1.A2 UT1.A3 UT1.B3 UT1.H9
+3V_TBT_S0: CT163.1 CT164.1 CT165.1 LT14.1 UT1.R13
+3V_TBT_SPI: CT47.1 RT15.1 RT16.1 RT17.1 RT18.1 RT242.2 RT243.2 UT2.8
+3V_VC: PC200.2 PC204.1 PC213.1 PC1944.2 PR206.1 PR208.1 PR212.1 PR224.2 PR231.1 PR236.1 PR244.1 PR246.2 PR248.2 PR251.1 PR259.1 PR265.2 PR266.2 PR267.2 PR270.2 PR273.2 PR274.2 PR279.2 PR282.2 PR1936.2 PU200.8 PU201.5 PU202.5 PU203.8 PU1901.5
+3VA_TBT: CT143.1 QV89.2 RT22.1 RT23.1 RT25.1 RT35.1 RT36.1 RT39.1 RT46.1 RT113.2 RT167.1 RT194.1 RT1145.1 RT5847.1 RT5848.1 UT1.F8
+3VA_TBT_LC: CT50.1 RT6.1 RT7.1 RT8.1 RT9.1 RT242.1 UT1.R6
+3VALW: C267.2 CA127.1 CE15.1 CI21.1 CI22.1 CT189.1 CZ12.1 CZ18.1 CZ26.1 CZ2157.1 JAPS.3 JAPS.7 PC512.1 PC912.1 PC1612.1 PC1801.1 PJP402.2 PQ226.1 PR101.1 PR112.2 PR222.2 PR223.2 PR257.2 PR258.2 PR500.1 PR506.1 PR715.1 PR805.1 PR806.1 PR809.2 PR818.1 PR909.1 PR1606.1 PR1643.1 PR1800.2 PR1926.1 PU500.15 PU900.15 PU1600.15 PU1800.7 PU1800.8 PU1800.9 Q4.2 QH1.3 QH3.2 QH3.5 QH5.2 QH5.5 R5832.1 RA100.1 RE3.1 RE52.1 RE56.1 RE141.1 RE275.2 RH5864.1 RH5866.2 RH5867.2 RI4.1 RI5.1 RI9.1 RI10.1 RI30.1 RI31.1 RI45.1 RT113.1 RT1095.1 RV12.1 RV103.1 RV111.1 RV1809.1 RZ38.2 RZ1136.1 RZ1138.1 RZ1960.1 UA3.4 UA4.6 UA4.7 UE2.2 UE5.5 UE6.1 UE6.2 UE7.5 UI4.5 UI5.5 UN3.1 UN3.2 UZ1.6 UZ1.7 UZ4.1 UZ4.2 UZ5.1 UZ5.2 UZ6.5 UZ8.5 UZ22.5 UZ23.5 UZ32.1 UZ32.2 UZ32.4
+3VALW_5105: CE20.1 CE22.1 CE23.1 CE24.1 CE25.1 CE26.1 CE27.1 RE19.2 RE20.2 RE21.2 RE22.2 RE23.2 RE25.2 RE41.1 RE59.1 RE60.1 RE63.1 RE64.1 RE65.1 RE66.1 RE67.2 RE68.1 RE71.1 RE72.1 RE94.2 RE95.2 RE99.2 RE142.2 RE145.1 RE283.2 RE284.2 RE293.2 RE294.2 RE295.2 RE296.2 RE298.1 RE300.1 RE301.1 RE307.2 RH5861.1 RP19.7 RP19.8 RP20.5 RP20.6 RP20.7 RP20.8 RZ1136.2 UE3.B7 UE3.G8 UE3.H1 UE3.K2 UE3.M9
+3VALW_5105_VTR_PLL: CE18.1 CE19.1 RH5861.2 UE3.F1
+3VALW_KB: JKB.3 RZ1138.2
+3VALWP: PC401.1 PC412.1 PJP402.1 PL400.1 PR401.1 PR428.1
+3VLP: D322.2 PR400.1 RE43.2 RE304.1
+3VLP_EC: RE43.1 RE44.1 UE3.B1
+3VLP_P: D322.1 RH590.2
+3VS: CD16.1 CD17.1 CD34.1 CD35.1 CH188.1 CZ9.1 CZ43.1 DV12.5 JDIMM1.255 JDIMM2.255 JKB.4 JLPDE1.1 JLPDE1.2 PR609.1 PR703.1 PR705.2 PR951.1 PR1019.2 PR1117.1 PR1522.2 QE18.2 QE18.5 QH4.2 QH4.5 QZ9.3 RD1.1 RD2.1 RD3.1 RD4.1 RD5.1 RD6.1 RD10.1 RE81.1 RE83.1 RE100.1 RE101.1 RE129.1 RE136.1 RE137.1 RF1.1 RF3.1 RH5.1 RH85.2 RH91.1 RH383.1 RH462.1 RH463.1 RH510.2 RH511.2 RH512.2 RH516.1 RH525.1 RH527.2 RH535.2 RH537.2 RH547.2 RH548.1 RH549.1 RH550.1 RH551.1 RH561.1 RH562.1 RH563.1 RH569.2 RH572.2 RH1145.2 RH1146.2 RH5840.2 RI14.1 RM15.2 RP1.5 RP1.6 RP1.7 RP1.8 RP2.1 RP2.2 RP2.3 RP2.4 RP22.1 RP22.2 RP22.3 RP22.4 RP23.1 RP23.2 RP23.3 RP23.4 RT241.2 RV658.1 RV1133.2 RZ28.1 UH14.5 UZ1.8 UZ1.9
+3VS_AUDIO: CA129.1 JAUDIO.25 JAUDIO.27 JAUDIO.29 LA4.1 RA17.1 RA18.2 RA82.1 UA4.8 UA4.9
+3VS_CAM: CV183.1 CV184.1 CZ44.1 JEDP1.22 RZ37.2
+3VS_CAM_R: QZ9.1 RZ37.1
+3VS_CR: CR1.1 CR4.1 CR11.1 CR12.1 RR1.1 RR9.2 RZ28.2 UR1.11 UR1.27
+3VS_CT2: CZ6.1 UZ1.10
+3VS_DTH: CM1.1 CM40.2 LM1.1 RM5.2 RM6.1 RM7.1 RM10.1 RM14.1 RM15.1 RM16.1 RM20.1 UM2.8
+3VS_FFS: CF1.1 CF2.1 RF1.2 RF4.1 RF5.1 UF1.2 UF1.3 UF1.9 UF1.10
+3VS_FP: C1080.1 JFP.8 Q6.2 R281.1
+3VS_FP_R: C1079.1 R281.2 RZ1960.2
+3VS_TP: CE2.1 JTP.8 QE2.2 QE2.5 QE13.2 RE7.2 RE9.2 RE24.1 RE26.1 RE87.1 UE6.7 UE6.8
+3VS_TPM_VHIO: CE75.1 CE76.1 CE84.1 CE85.1 RE129.2 U32.8 U32.22
+3VS_TPM_VSB: CE11.1 CE83.1 RE141.2 U32.1
+3VS_TS: C3003.1 C3004.1 C3005.1 CZ29.1 D18.1 JTS.1 JTS1.1 RC183.1 RC184.1 RC5835.1 RH5891.2 UZ5.7 UZ5.8
+3VS_VDD: CE3323.1 RV658.2 U33.1
+3VS_WLAN: C280.1 C1031.1 C1033.1 CN1.1 CN2.1 CN6.1 CN7.1 CN8.1 CN9.1 JNGFF1.2 JNGFF1.4 JNGFF1.64 JNGFF1.66 UN3.7 UN3.8
+5V_CHGUSB_1: CI17.1 CI18.1 CI19.1 JUSB2.1 UI2.12
+5V_CHGUSB_2: CI11.1 CI12.1 CI13.1 JUSB1.1 UI1.12
+5VALW: CA126.1 CI1.1 CI2.1 CT147.1 CT148.1 CT149.1 CT150.1 CT188.1 CZ11.1 CZ86.1 CZ97.1 JKB.1 LED1.2 LED2.2 LED3.2 LED4.2 LED5.2 PC607.2 PC1804.1 PJP403.2 PR104.2 PR603.1 PR700.2 PR1156.1 PU600.12 PU1800.10 RV657.1 UA4.1 UA4.2 UA4.4 UE6.4 UI1.1 UI2.1 UN3.4 UT4.A11 UT4.B11 UT4.C11 UT4.D11 UT4.H10 UZ1.1 UZ1.2 UZ1.4 UZ4.4 UZ5.4 UZ9.3 UZ15.3 UZ16.3 UZ24.4 UZ29.4 UZ30.4 UZ33.1 UZ33.2 UZ33.4
+5VALWP: PC402.2 PC413.1 PC456.1 PJP403.1 PL401.2 PR402.2 PU400.14
+5VS: CZ8.1 JKB.2 PC1216.1 PC1229.1 PC1260.1 PC1271.1 PC1707.1 PC1716.1 PR1012.2 PR1146.1 PR1153.2 PR1200.1 PR1204.1 PR1251.1 PR1255.1 PR1513.2 PR1700.1 PR1704.1 PU1200.2 PU1200.15 PU1201.2 PU1201.15 PU1251.2 PU1251.15 PU1252.2 PU1252.15 PU1700.2 PU1700.15 PU1701.15 RE82.1 RE84.1 RE104.1 RE105.1 RF2.1 UV16.1 UZ1.13 UZ1.14 UZ25.4
+5VS_AUDIO: CA1.1 CA2.1 CA8.1 CA9.1 CA128.1 LA1.2 LA2.1 LA3.2 UA4.13 UA4.14
+5VS_AUDIO_PVDD1: CA10.1 CA11.1 LA3.1 UA1.46
+5VS_AUDIO_PVDD2: CA3.1 CA4.1 LA1.1 UA1.51
+5VS_CT1: CZ4.1 UZ1.12
+5VS_HDD: CS12.1 CS13.1 CS14.1 CS15.1 CZ45.1 JHDD.13 JHDD.14 JHDD.15 UZ33.7 UZ33.8
+AVDD1: CA5.1 CA6.1 CA7.1 LA2.2 UA1.45
+AVDD2: CA12.1 CA13.1 CA14.1 CA17.1 RA2.2 UA1.24
+DVDD: CA32.1 CA78.1 LA4.2 RA12.1 RA13.1 RA15.1 UA1.7
+DVDDIO: CA39.1 CA40.1 RA18.1 UA1.19
+VBUS_1: CT120.2 CT121.2 CT122.1 CT123.1 CT153.1 CT157.1 DT10.2 DT10.3 DT28.1 DT174.1 JUSBC1.A4 JUSBC1.A9 JUSBC1.B4 JUSBC1.B9 PC208.1 PD204.2 PL200.1 PL201.1 UT4.A10 UT4.B10 UT4.H11 UT4.J10 UT4.J11 UT4.K11
+VBUS_DC_SS: PD201.2 PD201.3 PQ208.5 PQ209.5
+VCC0V9_CIO: CT101.1 CT102.1 CT103.1 UT1.R8 UT1.R9 UT1.R11 UT1.R12
+VCC0V9_DP: CT62.1 CT63.1 CT64.1 CT65.1 CT66.1 CT67.1 CT68.1 UT1.L6 UT1.L8 UT1.L11 UT1.L12 UT1.M6 UT1.M8 UT1.T11 UT1.T12 UT1.V11 UT1.V12 UT1.V13
+VCC0V9_PCIE: CT71.1 CT72.1 CT80.1 CT81.1 CT82.1 UT1.L18 UT1.L19 UT1.M13 UT1.M15 UT1.M16 UT1.M18 UT1.N18 UT1.N19
+VCC0V9_USB: CT93.1 CT94.1 UT1.R15 UT1.R16
+VCC_CORE: PC2001.1 PC2002.1 PC2003.1 PC2004.1 PC2005.1 PC2006.1 PC2007.1 PC2008.1 PC2009.1 PC2010.1 PC2011.1 PC2012.1 PC2013.1 PC2014.1 PC2015.1 PC2016.1 PC2017.1 PC2018.1 PC2028.1 PC2029.1 PC2030.1 PC2031.1 PC2032.1 PC2033.1 PC2034.1 PC2035.1 PC2036.1 PC2037.1 PC2038.1 PC2039.1 PC2040.1 PC2041.1 PC2042.1 PC2043.1 PC2044.1 PC2045.1 PC2046.1 PC2047.1 PC2048.1 PC2049.1 PC2050.1 PC2051.1 PC2052.1 PC2053.1 PC2054.1 PC2055.1 PC2056.1 PC2057.1 PC2058.1 PC2059.1 PC2060.1 PC2061.1 PC2062.1 PC2063.1 PC2064.1 PC2065.1 PC2066.1 PC2067.1 PC2068.1 PC2069.1 PC2070.1 PC2071.1 PC2072.1 PC2073.1 PC2086.1 PC2087.1 PC2088.1 PC2089.1 PC2090.1 PC2095.1 PC2096.1 PC2097.1 PC2098.1 PC2099.1 PC2100.1 PC2101.1 PC2102.1 PC2103.1 PC2104.1 PC2105.1 PC2106.1 PC2107.1 PC2108.1 PC2109.1 PC2110.1 PC2111.1 PC2112.1 PC2113.1 PC2114.1 PC2115.1 PC2116.1 PC2117.1 PL1202.4 PL1203.4 PL1251.4 PL1252.4 RH197.1 UH1.AA13 UH1.AA31 UH1.AA32 UH1.AA33 UH1.AA34 UH1.AA35 UH1.AA36 UH1.AA37 UH1.AA38 UH1.AB29 UH1.AB30 UH1.AB31 UH1.AB32 UH1.AB35 UH1.AB36 UH1.AB37 UH1.AB38 UH1.AC13 UH1.AC14 UH1.AC29 UH1.AC30 UH1.AC31 UH1.AC32 UH1.AC33 UH1.AC34 UH1.AC35 UH1.AC36 UH1.AD13 UH1.AD14 UH1.AD31 UH1.AD32 UH1.AD33 UH1.AD34 UH1.AD35 UH1.AD36 UH1.AD37 UH1.AD38 UH1.AE13 UH1.AE14 UH1.AE30 UH1.AE31 UH1.AE32 UH1.AE35 UH1.AE36 UH1.AE37 UH1.AE38 UH1.AF29 UH1.AF30 UH1.AF31 UH1.AF32 UH1.AF33 UH1.AF34 UH1.AF35 UH1.AF36 UH1.AF37 UH1.AF38 UH1.AG14 UH1.AG31 UH1.AG32 UH1.AG33 UH1.AG34 UH1.AG35 UH1.AG36 UH1.AH13 UH1.AH14 UH1.AH29 UH1.AH30 UH1.AH31 UH1.AH32 UH1.AJ14 UH1.AJ29 UH1.AJ30 UH1.AJ31 UH1.AJ32 UH1.AJ33 UH1.AJ34 UH1.AJ35 UH1.AJ36 UH1.AK31 UH1.AK32 UH1.AK33 UH1.AK34 UH1.AK35 UH1.AK36 UH1.AK37 UH1.AK38 UH1.AL13 UH1.AL29 UH1.AL30 UH1.AL31 UH1.AL32 UH1.AL35 UH1.AL36 UH1.AL37 UH1.AL38 UH1.AM13 UH1.AM14 UH1.AM29 UH1.AM30 UH1.AM31 UH1.AM32 UH1.AM33 UH1.AM34 UH1.AM35 UH1.AM36 UH1.AN13 UH1.AN14 UH1.AN31 UH1.AN32 UH1.AN33 UH1.AN34 UH1.AN35 UH1.AN36 UH1.AN37 UH1.AN38 UH1.AP13 UH1.AP30 UH1.AP31 UH1.AP32 UH1.AP35 UH1.AP36 UH1.AP37 UH1.AP38 UH1.K13 UH1.K14 UH1.L13 UH1.L14 UH1.N13 UH1.N14 UH1.N30 UH1.N31 UH1.N32 UH1.N35 UH1.N36 UH1.N37 UH1.N38 UH1.P13 UH1.P14 UH1.P29 UH1.P30 UH1.P31 UH1.P32 UH1.P33 UH1.P34 UH1.P35 UH1.P36 UH1.R13 UH1.R31 UH1.R32 UH1.R33 UH1.R34 UH1.R35 UH1.R36 UH1.R37 UH1.R38 UH1.T29 UH1.T30 UH1.T31 UH1.T32 UH1.T35 UH1.T36 UH1.T37 UH1.T38 UH1.U29 UH1.U30 UH1.U31 UH1.U32 UH1.U33 UH1.U34 UH1.U35 UH1.U36 UH1.V13 UH1.V14 UH1.V31 UH1.V32 UH1.V33 UH1.V34 UH1.V35 UH1.V36 UH1.V37 UH1.V38 UH1.W13 UH1.W14 UH1.W29 UH1.W30 UH1.W31 UH1.W32 UH1.W35 UH1.W36 UH1.W37 UH1.W38 UH1.Y29 UH1.Y30 UH1.Y31 UH1.Y32 UH1.Y33 UH1.Y34 UH1.Y35 UH1.Y36
+VCCGT: PC2019.1 PC2020.1 PC2021.1 PC2022.1 PC2023.1 PC2024.1 PC2025.1 PC2026.1 PC2027.1 PC2074.1 PC2075.1 PC2076.1 PC2077.1 PC2078.1 PC2079.1 PC2080.1 PC2081.1 PC2082.1 PC2083.1 PC2084.1 PC2085.1 PC2091.1 PC2092.1 PC2093.1 PC2094.1 PC2118.1 PC2119.1 PC2120.1 PC2121.1 PC2122.1 PC2123.1 PC2124.1 PC2125.1 PC2126.1 PC2127.1 PC2128.1 PC2129.1 PC2130.1 PC2131.1 PC2132.1 PC2133.1 PC2134.1 PC2135.1 PC2136.1 PC2137.1 PC2138.1 PL1702.4 RH203.1 UH1.AT14 UH1.AT31 UH1.AT32 UH1.AT33 UH1.AT34 UH1.AT35 UH1.AT36 UH1.AT37 UH1.AT38 UH1.AU14 UH1.AU29 UH1.AU30 UH1.AU31 UH1.AU32 UH1.AU35 UH1.AU36 UH1.AU37 UH1.AU38 UH1.AV29 UH1.AV30 UH1.AV31 UH1.AV32 UH1.AV33 UH1.AV34 UH1.AV35 UH1.AV36 UH1.AW14 UH1.AW31 UH1.AW32 UH1.AW33 UH1.AW34 UH1.AW35 UH1.AW36 UH1.AW37 UH1.AW38 UH1.AY29 UH1.AY30 UH1.AY31 UH1.AY32 UH1.AY35 UH1.AY36 UH1.AY37 UH1.AY38 UH1.BA13 UH1.BA14 UH1.BA29 UH1.BA30 UH1.BA31 UH1.BA32 UH1.BA33 UH1.BA34 UH1.BA35 UH1.BA36 UH1.BB13 UH1.BB14 UH1.BB31 UH1.BB32 UH1.BB33 UH1.BB34 UH1.BB35 UH1.BB36 UH1.BB37 UH1.BB38 UH1.BC29 UH1.BC30 UH1.BC31 UH1.BC32 UH1.BC35 UH1.BC36 UH1.BC37 UH1.BC38 UH1.BD13 UH1.BD14 UH1.BD29 UH1.BD30 UH1.BD31 UH1.BD32 UH1.BD33 UH1.BD34 UH1.BD35 UH1.BD36 UH1.BE31 UH1.BE32 UH1.BE33 UH1.BE34 UH1.BE35 UH1.BE36 UH1.BE37 UH1.BE38 UH1.BF13 UH1.BF14 UH1.BF29 UH1.BF30 UH1.BF31 UH1.BF32 UH1.BF35 UH1.BF36 UH1.BF37 UH1.BF38 UH1.BG29 UH1.BG30 UH1.BG31 UH1.BG32 UH1.BG33 UH1.BG34 UH1.BG35 UH1.BG36 UH1.BH33 UH1.BH34 UH1.BH35 UH1.BH36 UH1.BH37 UH1.BH38 UH1.BJ16 UH1.BJ17 UH1.BJ19 UH1.BJ20 UH1.BJ21 UH1.BJ23 UH1.BJ24 UH1.BJ26 UH1.BJ27 UH1.BJ37 UH1.BJ38 UH1.BK16 UH1.BK17 UH1.BK19 UH1.BK20 UH1.BK21 UH1.BK23 UH1.BK24 UH1.BK26 UH1.BK27 UH1.BL15 UH1.BL16 UH1.BL17 UH1.BL23 UH1.BL24 UH1.BL25 UH1.BL26 UH1.BL27 UH1.BL28 UH1.BL36 UH1.BL37 UH1.BM15 UH1.BM16 UH1.BM17 UH1.BM36 UH1.BM37 UH1.BN15 UH1.BN16 UH1.BN17 UH1.BN36 UH1.BN37 UH1.BN38 UH1.BP15 UH1.BP16 UH1.BP17 UH1.BP37 UH1.BP38 UH1.BR15 UH1.BR16 UH1.BR17 UH1.BR37 UH1.BT15 UH1.BT16 UH1.BT17 UH1.BT37
+VCCIO: CH102.1 CH103.1 CH104.1 PJP801.2 RH24.1 RH30.2 RH483.1 UH1.AG12 UH1.G15 UH1.G17 UH1.G19 UH1.G21 UH1.H15 UH1.H16 UH1.H17 UH1.H19 UH1.H20 UH1.H21 UH1.H26 UH1.H27 UH1.J15 UH1.J16 UH1.J17 UH1.J19 UH1.J20 UH1.J21 UH1.J26 UH1.J27
+VCCSA: CH111.1 CH112.1 CH113.1 CH114.1 CH115.1 CH116.1 CH117.1 CH133.1 CH134.1 CH135.1 CH136.1 CH138.1 PC2000.1 PC2139.1 PC2140.1 PC2141.1 PC2142.1 PC2143.1 PC2144.1 PC2145.1 PC2146.1 PC2147.1 PC2148.1 PC2149.1 PC2150.1 PC2151.1 PC2152.1 PC2153.1 PL1704.4 RH201.2 UH1.J30 UH1.K29 UH1.K30 UH1.K31 UH1.K32 UH1.K33 UH1.K34 UH1.K35 UH1.L31 UH1.L32 UH1.L35 UH1.L36 UH1.L37 UH1.L38 UH1.M29 UH1.M30 UH1.M31 UH1.M32 UH1.M33 UH1.M34 UH1.M35 UH1.M36
+VCCST: CH107.1 CH108.1 CH109.1 CH110.1 CH3334.1 CZ28.1 PC1102.1 PR1104.1 PR1105.2 PR1106.1 PR1107.1 RE69.1 RE292.1 RH97.1 RH98.1 RH100.1 RH151.1 RH152.1 RH156.1 RH163.1 RH164.1 RH570.1 UH1.H28 UH1.H30 UH1.J28 UZ15.6
+VCCSTG: CH105.1 CH106.1 CZ47.1 CZ82.1 RH165.1 RH494.1 RH495.1 RH496.1 UH1.G30 UH1.H29 UZ9.6
+VSS_PLL: CE18.2 CE19.2 UE3.G1
AGND: CA5.2 CA6.2 CA7.2 CA12.2 CA13.2 CA14.2 CA17.2 CA20.2 CA21.2 CA24.2 CA25.2 CA26.2 CA27.2 CA28.2 CA29.2 CA30.2 CA31.2 CA41.1 CA42.1 CA43.2 CA44.2 JHP1.5 JHP1.7 RA73.1 RA74.1 RA94.2 RA95.2 UA1.20 UA1.30 UA1.42
DV12S: CR2.1 CR5.1 CR6.1 UR1.10 UR1.14
DV33_18: CR3.1 UR1.18
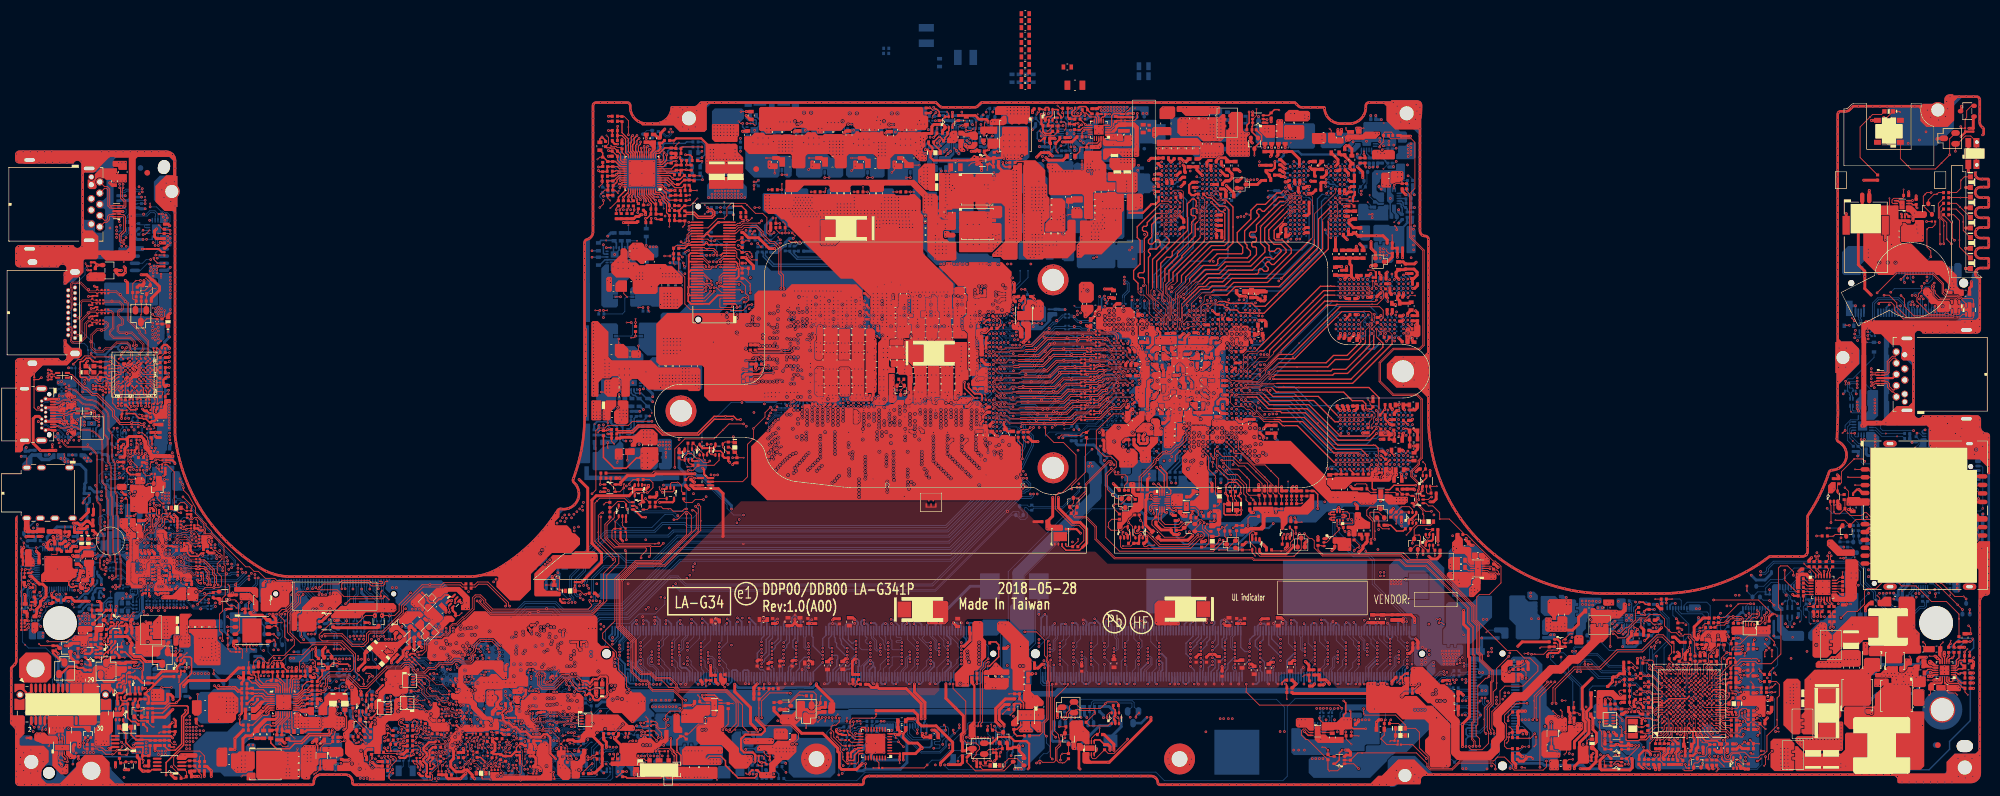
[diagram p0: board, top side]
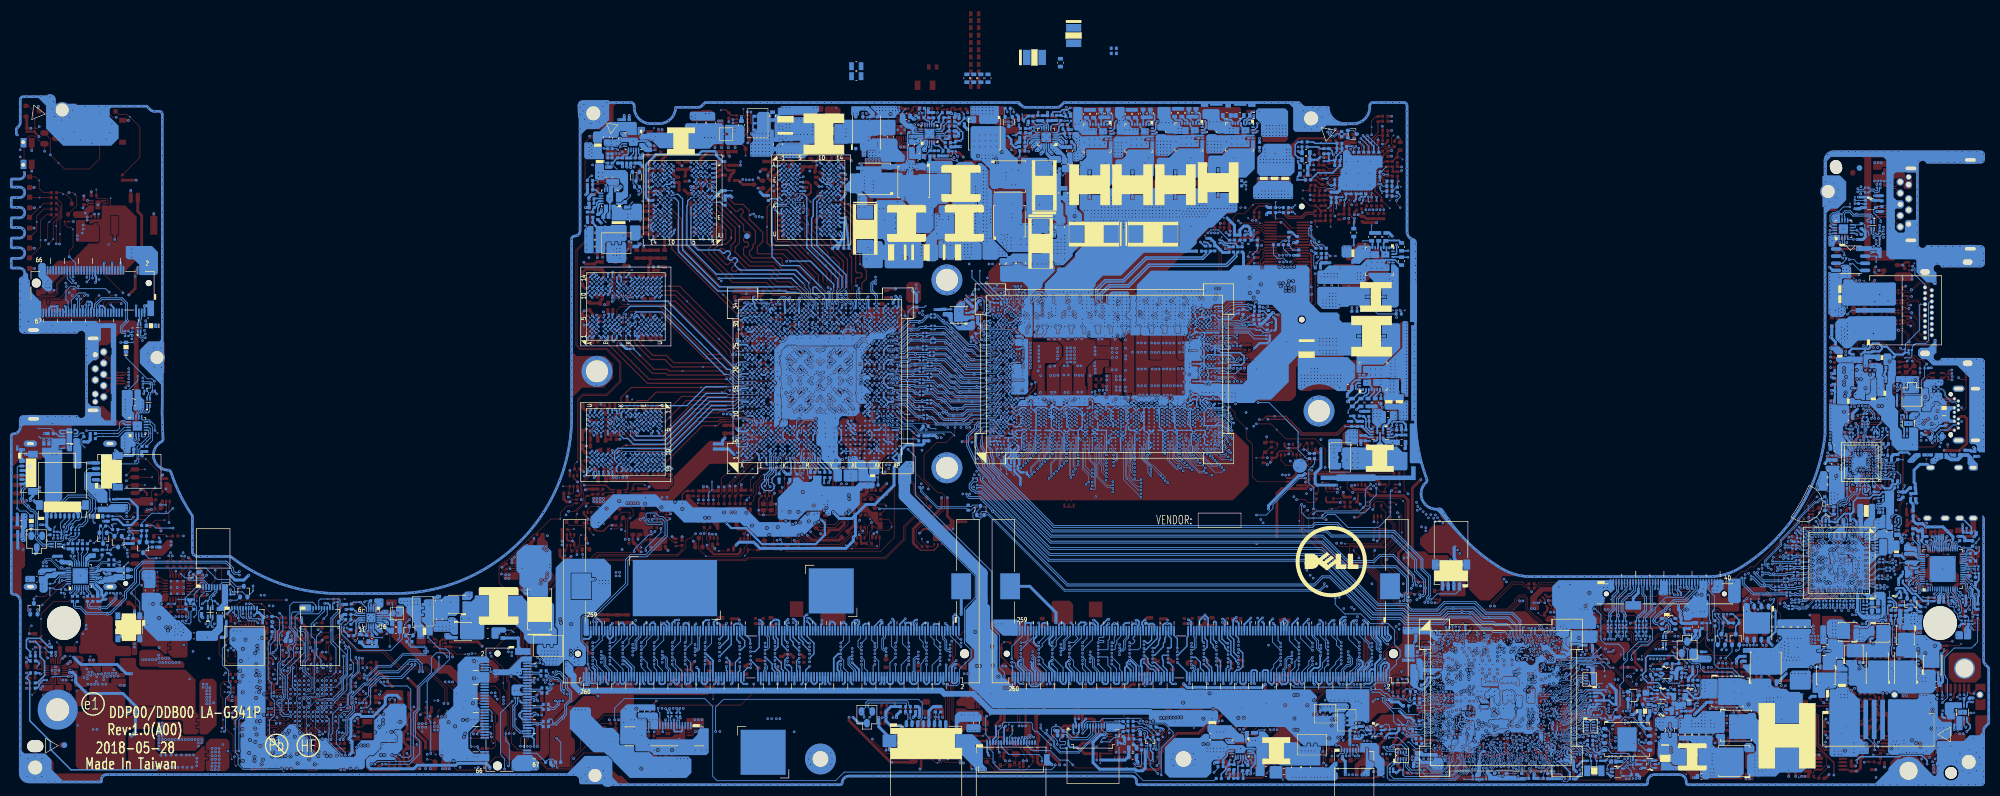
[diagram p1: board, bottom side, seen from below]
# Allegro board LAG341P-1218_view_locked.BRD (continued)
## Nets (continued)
DDR_B_D24: JDIMM2.70 UH1.BC11
DDR_B_D25: JDIMM2.71 UH1.BC8
DDR_B_D26: JDIMM2.83 UH1.BB11
DDR_B_D27: JDIMM2.84 UH1.BB7
DDR_B_D28: JDIMM2.66 UH1.BC10
DDR_B_D29: JDIMM2.67 UH1.BC7
DDR_B_D30: JDIMM2.79 UH1.BB10
DDR_B_D31: JDIMM2.80 UH1.BB8
DDR_B_D32: JDIMM2.174 UH1.AC11
DDR_B_D33: JDIMM2.173 UH1.AC7
DDR_B_D34: JDIMM2.187 UH1.AA11
DDR_B_D35: JDIMM2.186 UH1.AA7
DDR_B_D36: JDIMM2.170 UH1.AC10
DDR_B_D37: JDIMM2.169 UH1.AC8
DDR_B_D38: JDIMM2.183 UH1.AA10
DDR_B_D39: JDIMM2.182 UH1.AA8
DDR_B_D40: JDIMM2.195 UH1.W8
DDR_B_D41: JDIMM2.194 UH1.W7
DDR_B_D42: JDIMM2.207 UH1.V10
DDR_B_D43: JDIMM2.208 UH1.V11
DDR_B_D44: JDIMM2.191 UH1.W11
DDR_B_D45: JDIMM2.190 UH1.W10
DDR_B_D46: JDIMM2.203 UH1.V8
DDR_B_D47: JDIMM2.204 UH1.V7
DDR_B_D48: JDIMM2.216 UH1.R11
DDR_B_D49: JDIMM2.215 UH1.R7
DDR_B_D50: JDIMM2.228 UH1.P7
DDR_B_D51: JDIMM2.229 UH1.P11
DDR_B_D52: JDIMM2.211 UH1.R8
DDR_B_D53: JDIMM2.212 UH1.R10
DDR_B_D54: JDIMM2.224 UH1.P8
DDR_B_D55: JDIMM2.225 UH1.P10
DDR_B_D56: JDIMM2.237 UH1.M7
DDR_B_D57: JDIMM2.236 UH1.M11
DDR_B_D58: JDIMM2.249 UH1.L11
DDR_B_D59: JDIMM2.250 UH1.L7
DDR_B_D60: JDIMM2.232 UH1.M10
DDR_B_D61: JDIMM2.233 UH1.M8
DDR_B_D62: JDIMM2.245 UH1.L10
DDR_B_D63: JDIMM2.246 UH1.L8
DDR_B_DQS0: JDIMM2.13 UH1.BP9
DDR_B_DQS1: JDIMM2.34 UH1.BJ9
DDR_B_DQS2: JDIMM2.55 UH1.BF9
DDR_B_DQS3: JDIMM2.76 UH1.BB9
DDR_B_DQS4: JDIMM2.179 UH1.AA9
DDR_B_DQS5: JDIMM2.200 UH1.V9
DDR_B_DQS6: JDIMM2.221 UH1.P9
DDR_B_DQS7: JDIMM2.242 UH1.L9
DDR_B_DQS#0: JDIMM2.11 UH1.BN9
DDR_B_DQS#1: JDIMM2.32 UH1.BL9
DDR_B_DQS#2: JDIMM2.53 UH1.BG9
DDR_B_DQS#3: JDIMM2.74 UH1.BC9
DDR_B_DQS#4: JDIMM2.177 UH1.AC9
DDR_B_DQS#5: JDIMM2.198 UH1.W9
DDR_B_DQS#6: JDIMM2.219 UH1.R9
DDR_B_DQS#7: JDIMM2.240 UH1.M9
DDR_B_MA0: JDIMM2.144 UH1.AJ9
DDR_B_MA1: JDIMM2.133 UH1.AK6
DDR_B_MA2: JDIMM2.132 UH1.AK5
DDR_B_MA3: JDIMM2.131 UH1.AL5
DDR_B_MA4: JDIMM2.128 UH1.AL6
DDR_B_MA5: JDIMM2.126 UH1.AM6
DDR_B_MA6: JDIMM2.127 UH1.AN7
DDR_B_MA7: JDIMM2.122 UH1.AN10
DDR_B_MA8: JDIMM2.125 UH1.AN8
DDR_B_MA9: JDIMM2.121 UH1.AR11
DDR_B_MA10: JDIMM2.146 UH1.AH7
DDR_B_MA11: JDIMM2.120 UH1.AN11
DDR_B_MA12: JDIMM2.119 UH1.AR10
DDR_B_MA13: JDIMM2.158 UH1.AF9
DDR_B_PAR: JDIMM2.143 UH1.AJ7
DDR_B_RAS#: JDIMM2.152 UH1.AH10
DDR_B_WE#: JDIMM2.151 UH1.AH11
DDR_CKE0_DIMMA: JDIMM1.109 UH1.AT1
DDR_CKE1_DIMMA: JDIMM1.110 UH1.AT2
DDR_CKE2_DIMMB: JDIMM2.109 UH1.AT8
DDR_CKE3_DIMMB: JDIMM2.110 UH1.AT10
DDR_CS0_DIMMA#: JDIMM1.149 UH1.AD5
DDR_CS1_DIMMA#: JDIMM1.157 UH1.AE2
DDR_CS2_DIMMB#: JDIMM2.149 UH1.AF11
DDR_CS3_DIMMB#: JDIMM2.157 UH1.AE7
DDR_RCOMP0: RH148.2 UH1.G1
DDR_RCOMP1: RH149.2 UH1.H1
DDR_RCOMP2: RH150.2 UH1.J2
DDR_VTT_PG_CTRL: UC1.2 UH1.BT13
DEBUG_TX: JDEG1.9 RE298.2 RE299.1
DGPU_HOLD_RST#: RV580.2 U33.9 UH2.BB20 UV19.1
DGPU_PEX_RST#: RV577.1 RV587.2 RV589.1 RV1084.1 RV1131.2 U33.10 UV29.1
DGPU_PEX_RST#_R: RV577.2 UV18.AJ12
DGPU_PWR_EN: RH537.1 UH2.AD48 UZ31.1
DGPU_PWR_EN#: QV3.6 RV399.2 RV657.2
DGPU_PWR_EN#_R: CV499.1 QV3.5 RV399.1
DGPU_PWROK: PR705.1 PU700.13 RH516.2 UH2.AV16 UV20.2
DH1_NVVDD: PQ1000.4 PU1001.2
DH1_NVVDDS: PQ1500.4 PU1501.2
DH2_NVVDD: PQ1002.4 PU1001.14
DH_1.2V: PQ600.4 PU600.17
DIFFOUT_2PH: PR1138.1 PR1140.2 PU1100.35
DIFFOUT_4PH: PC1116.2 PR1137.2 PU1100.4
DIMM_CHA_SA0: JDIMM1.256 RD1.2 RD28.1
DIMM_CHA_SA1: JDIMM1.260 RD2.2 RD29.1
DIMM_CHA_SA2: JDIMM1.166 RD3.2 RD30.1
DIMM_CHB_SA0: JDIMM2.256 RD4.2 RD38.1
DIMM_CHB_SA1: JDIMM2.260 RD5.2 RD39.1
DIMM_CHB_SA2: JDIMM2.166 RD6.2 RD40.1
DISPOFF#: DV1.1 JEDP1.24 RV107.1
DL1_NVVDD: PQ1001.4 PQ1007.4 PU1001.19
DL1_NVVDDS: PQ1501.4 PU1501.19
DL2_NVVDD: PQ1003.4 PQ1008.4 PU1001.17
DL_1.2V: PQ601.4 PU600.15
DMI_CRX_PTX_N0: UH1.E8 UH2.C33
DMI_CRX_PTX_N1: UH1.F6 UH2.C32
DMI_CRX_PTX_N2: UH1.E5 UH2.C31
DMI_CRX_PTX_N3: UH1.J9 UH2.C29
DMI_CRX_PTX_P0: UH1.D8 UH2.B33
DMI_CRX_PTX_P1: UH1.E6 UH2.B32
DMI_CRX_PTX_P2: UH1.D5 UH2.B31
DMI_CRX_PTX_P3: UH1.J8 UH2.B29
DMI_CTX_PRX_N0: UH1.A8 UH2.K34
DMI_CTX_PRX_N1: UH1.B6 UH2.G33
DMI_CTX_PRX_N2: UH1.A5 UH2.K32
DMI_CTX_PRX_N3: UH1.B4 UH2.G30
DMI_CTX_PRX_P0: UH1.B8 UH2.J35
DMI_CTX_PRX_P1: UH1.C6 UH2.F34
DMI_CTX_PRX_P2: UH1.B5 UH2.J32
DMI_CTX_PRX_P3: UH1.D4 UH2.F30
DMIC_CLK_CODEC: CA35.1 DE9.2 RE116.1 UA1.53
DMIC_CLK_CODEC_C: CE73.1 JKB.12 RE116.2 RE310.2
DMIC_DAT_CODEC: CA36.1 DE9.3 RE117.1 UA1.54
DMIC_DAT_CODEC_C: CE74.1 JKB.11 RE117.2 RE309.2
DOCK_TNY_SMB_CLK: RE109.1 RT184.1
DOCK_TNY_SMB_DAT: RE108.1 RT185.1
DPM_REXT: RI23.1 UI3.7
DPSRC_RBIAS: RT2.1 UT1.N6
DRON: PU1100.17 PU1200.16 PU1201.16 PU1251.16 PU1252.16 PU1700.16 PU1701.16
DTH_CSCL: RM14.2 RM18.1 T4936.1(TP-1) UM1.E6
DTH_CSDA: RM16.2 RM17.1 T4937.1(TP-1) UM1.F6
DTH_PDB: RH5895.1 RM5.1 RM27.2 RV561.1 UM1.C3
DTH_PDB_R: RH5895.2 UH2.AU47
DTH_RST#: CM41.1 RM6.2 UM1.B8
DTH_SPI_CK_OUT: RM9.1 UM1.D2 UM2.6
DTH_SPI_CS: RM7.2 UM1.C1 UM2.1
DTH_SPI_D_IN: UM1.C2 UM2.2
DTH_SPI_D_OUT: UM1.D1 UM2.5
DTH_SPI_WR_PROT: RM28.1 UM1.E2 UM2.3
DTH_VDD12: CM9.1 CM10.2 CM11.2 CM12.2 CM13.1 LM2.2 UM1.D6 UM1.F5
DTH_VDD12_ON: RM21.2 UM1.G8 UZ25.3
DTH_VDD33: CM2.1 CM3.2 CM4.2 CM5.2 LM1.2 UM1.B2 UM1.G2 UM1.G4
DTH_VDDA12: CM23.1 CM24.2 CM25.1 LM3.2 UM1.F4
DTH_VDDRX12: CM27.1 CM28.2 CM29.2 CM30.2 CM31.1 CM32.1 CM33.1 LM4.2 UM1.B4 UM1.B5
DTH_VDDTX12: CM34.1 CM35.2 CM38.2 CM39.1 CM50.1 LM5.2 UM1.B7 UM1.G5 UM1.G7
DTH_XTLI: CM43.1 RM103.1 RM1834.1 YM1.1
DTH_XTLI_R: RM103.2 UM1.E8
DTH_XTLO: CM44.1 RM102.1 RM1834.2 YM1.3
DTH_XTLO_R: RM102.2 UM1.F8
EC_SLP_S0IX#: RH535.1 UH2.BC33
EC_SMB_CK2_PX: QV21.1 RV326.2 UV18.T4
EC_SMB_DA2_PX: QV21.4 RV325.2 UV18.T3
EDP_AUXN: CV166.1 UH1.B26
EDP_AUXN_C: CV166.2 RV528.1
EDP_AUXN_R: JEDP1.15 RV528.2
EDP_AUXP: CV167.1 UH1.C26
EDP_AUXP_C: CV167.2 RV529.1
EDP_AUXP_R: JEDP1.16 RV529.2
EDP_COMP: RH30.1 UH1.D37
EDP_DISP_UTIL: RH456.1 UH1.A33
EDP_HPD: RV113.1 RV114.1 UH2.AN6
EDP_HPD_S: JEDP1.23 RV113.2
EDP_PANEL_CLK: JEDP1.18 T5994.1(TP-1)
EDP_PANEL_DAT: JEDP1.26 T5995.1(TP-1)
EDP_TXN0: CV159.1 UH1.E29
EDP_TXN0_C: CV159.2 RV521.1
EDP_TXN0_R: JEDP1.12 RV521.2
EDP_TXN1: CV161.1 UH1.E28
EDP_TXN1_C: CV161.2 RV523.1
EDP_TXN1_R: JEDP1.9 RV523.2
EDP_TXN2: CV163.1 UH1.B29
EDP_TXN2_C: CV163.2 RV525.1
EDP_TXN2_R: JEDP1.6 RV525.2
EDP_TXN3: CV165.1 UH1.B28
EDP_TXN3_C: CV165.2 RV527.1
EDP_TXN3_R: JEDP1.3 RV527.2
EDP_TXP0: CV158.1 UH1.D29
EDP_TXP0_C: CV158.2 RV520.1
EDP_TXP0_R: JEDP1.13 RV520.2
EDP_TXP1: CV160.1 UH1.F28
EDP_TXP1_C: CV160.2 RV522.1
EDP_TXP1_R: JEDP1.10 RV522.2
EDP_TXP2: CV162.1 UH1.A29
EDP_TXP2_C: CV162.2 RV524.1
EDP_TXP2_R: JEDP1.7 RV524.2
EDP_TXP3: CV164.1 UH1.C28
EDP_TXP3_C: CV164.2 RV526.1
EDP_TXP3_R: JEDP1.4 RV526.2
EN_1V: PC511.1 PR503.2 PR505.1 PR1950.2 PU500.11
EN_1VS_VCCIO: PC806.1 PR803.2 PR804.1 PU800.5
EN_INVPWR: QV12.2 RV135.1 UE3.B2
EN_PD_HV_1: PQ212.5 PR247.1 PR248.1 PR250.1 PR262.2 PR277.1 RT178.2
EN_PD_HV_1#: PQ212.2 PQ212.3 PR231.2
ENVDD: DV7.1 RZ40.1 UZ8.4
ENVDD_PCH: DV7.3 UH2.AV44
ESPI_ALERT#: RH1943.1 RH5882.2 RH5883.2 UE3.H7
ESPI_ALERT#_R: RH5883.1 UH2.BA36
ESPI_CLK: RH168.1 UH2.BB36
ESPI_CLK_5105: CH198.1 RE313.2 RH168.2 UE3.G7
ESPI_CLK_5105_JLPDE: JLPDE1.10 RE62.1 RE313.1
ESPI_CS#: JLPDE1.7 UE3.H6 UH2.BE38
ESPI_IO0: JLPDE1.3 RC5831.2 UE3.K5
ESPI_IO0_R: RC5831.1 UH2.BB39
ESPI_IO1: JLPDE1.4 RC5832.2 UE3.L4
ESPI_IO1_R: RC5832.1 UH2.AW37
ESPI_IO2: JLPDE1.5 RC5833.2 UE3.G6
ESPI_IO2_R: RC5833.1 UH2.AV37
ESPI_IO3: JLPDE1.6 RC5834.2 UE3.L5
ESPI_IO3_R: RC5834.1 UH2.BA38
ESPI_RESET#: RH5838.1 RH5839.2 UE3.K6
ESPI_RESET#_R: RH5839.1 UH2.BF38
FB_2PH: PC1118.2 PC1119.1 PR1140.1 PR1141.1 PU1100.34
FB_3V: PC401.2 PR401.2 PR403.2 PU400.4
FB_4PH: PC1115.2 PC1117.2 PR1134.1 PR1137.1 PU1100.5
FB_5V: PC402.1 PR402.1 PR404.1 PU400.2
FBA_ABI#_H: UV18.Y29 UV24.J4
FBA_ABI#_L: UV18.V28 UV23.J4
FBA_CAS#_H: UV18.V31 UV24.G3
FBA_CAS#_L: UV18.Y32 UV23.L3
FBA_CKE_H: RV607.2 UV18.Y33 UV24.J3
FBA_CKE_L: RV605.2 UV18.V33 UV23.J3
FBA_CLK0: RV622.1 UV18.R30 UV23.J12
FBA_CLK0#: RV621.1 UV18.R31 UV23.J11
FBA_CLK1: RV627.1 UV18.AB31 UV24.J12
FBA_CLK1#: RV626.1 UV18.AC31 UV24.J11
FBA_CS#_H: UV18.AA31 UV24.L12
FBA_CS#_L: UV18.U30 UV23.G12
FBA_D0: UV18.L28 UV23.A4
FBA_D1: UV18.M29 UV23.A2
FBA_D2: UV18.L29 UV23.B4
FBA_D3: UV18.M28 UV23.B2
FBA_D4: UV18.N31 UV23.E4
FBA_D5: UV18.P29 UV23.E2
FBA_D6: UV18.R29 UV23.F4
FBA_D7: UV18.P28 UV23.F2
FBA_D8: UV18.J28 UV23.A11
FBA_D9: UV18.H29 UV23.A13
FBA_D10: UV18.J29 UV23.B11
FBA_D11: UV18.H28 UV23.B13
FBA_D12: UV18.G29 UV23.E11
FBA_D13: UV18.E31 UV23.E13
FBA_D14: UV18.E32 UV23.F11
FBA_D15: UV18.F30 UV23.F13
FBA_D16: UV18.C34 UV23.U11
FBA_D17: UV18.D32 UV23.U13
FBA_D18: UV18.B33 UV23.T11
FBA_D19: UV18.C33 UV23.T13
FBA_D20: UV18.F33 UV23.N11
FBA_D21: UV18.F32 UV23.N13
FBA_D22: UV18.H33 UV23.M11
FBA_D23: UV18.H32 UV23.M13
FBA_D24: UV18.P34 UV23.U4
FBA_D25: UV18.P32 UV23.U2
FBA_D26: UV18.P31 UV23.T4
FBA_D27: UV18.P33 UV23.T2
FBA_D28: UV18.L31 UV23.N4
FBA_D29: UV18.L34 UV23.N2
FBA_D30: UV18.L32 UV23.M4
FBA_D31: UV18.L33 UV23.M2
FBA_D32: UV18.AG28 UV24.U4
FBA_D33: UV18.AF29 UV24.U2
FBA_D34: UV18.AG29 UV24.T4
FBA_D35: UV18.AF28 UV24.T2
FBA_D36: UV18.AD30 UV24.N4
FBA_D37: UV18.AD29 UV24.N2
FBA_D38: UV18.AC29 UV24.M4
FBA_D39: UV18.AD28 UV24.M2
FBA_D40: UV18.AJ29 UV24.U11
FBA_D41: UV18.AK29 UV24.U13
FBA_D42: UV18.AJ30 UV24.T11
FBA_D43: UV18.AK28 UV24.T13
FBA_D44: UV18.AM29 UV24.N11
FBA_D45: UV18.AM31 UV24.N13
FBA_D46: UV18.AN29 UV24.M11
FBA_D47: UV18.AM30 UV24.M13
FBA_D48: UV18.AN31 UV24.A11
FBA_D49: UV18.AN32 UV24.A13
FBA_D50: UV18.AP30 UV24.B11
FBA_D51: UV18.AP32 UV24.B13
FBA_D52: UV18.AM33 UV24.E11
FBA_D53: UV18.AL31 UV24.E13
FBA_D54: UV18.AK33 UV24.F11
FBA_D55: UV18.AK32 UV24.F13
FBA_D56: UV18.AD34 UV24.A4
FBA_D57: UV18.AD32 UV24.A2
FBA_D58: UV18.AC30 UV24.B4
FBA_D59: UV18.AD33 UV24.B2
FBA_D60: UV18.AF31 UV24.E4
FBA_D61: UV18.AG34 UV24.E2
FBA_D62: UV18.AG32 UV24.F4
FBA_D63: UV18.AG33 UV24.F2
FBA_DBI0#: UV18.P30 UV23.D2
FBA_DBI1#: UV18.F31 UV23.D13
FBA_DBI2#: UV18.F34 UV23.P13
FBA_DBI3#: UV18.M32 UV23.P2
FBA_DBI4#: UV18.AD31 UV24.P2
FBA_DBI5#: UV18.AL29 UV24.P13
FBA_DBI6#: UV18.AM32 UV24.D13
FBA_DBI7#: UV18.AF34 UV24.D2
FBA_EDC0: UV18.M31 UV23.C2
FBA_EDC1: UV18.G31 UV23.C13
FBA_EDC2: UV18.E33 UV23.R13
FBA_EDC3: UV18.M33 UV23.R2
FBA_EDC4: UV18.AE31 UV24.R2
FBA_EDC5: UV18.AK30 UV24.R13
FBA_EDC6: UV18.AN33 UV24.C13
FBA_EDC7: UV18.AF33 UV24.C2
FBA_MA0_MA10_H: UV18.Y30 UV24.K4
FBA_MA0_MA10_L: UV18.V30 UV23.H4
FBA_MA1_MA9_H: UV18.AA34 UV24.K5
FBA_MA1_MA9_L: UV18.U34 UV23.H5
FBA_MA2_BA0_H: UV18.AA28 UV24.K11
FBA_MA2_BA0_L: UV18.U29 UV23.H11
FBA_MA3_BA3_H: UV18.AA29 UV24.K10
FBA_MA3_BA3_L: UV18.T31 UV23.H10
FBA_MA4_BA2_H: UV18.AC34 UV24.H11
FBA_MA4_BA2_L: UV18.R34 UV23.K11
FBA_MA5_BA1_H: UV18.AC33 UV24.H10
FBA_MA5_BA1_L: UV18.R33 UV23.K10
FBA_MA6_MA11_H: UV18.Y28 UV24.H5
FBA_MA6_MA11_L: UV18.U28 UV23.K5
FBA_MA7_MA8_H: UV18.AA33 UV24.H4
FBA_MA7_MA8_L: UV18.U33 UV23.K4
FBA_MA12_RFU_H: UV18.W31 UV24.J5
FBA_MA12_RFU_L: UV18.V29 UV23.J5
FBA_RAS#_H: UV18.Y31 UV24.L3
FBA_RAS#_L: UV18.U31 UV23.G3
FBA_RST#_H: RV613.1 UV18.Y34 UV24.J2
FBA_RST#_L: RV614.1 UV18.V34 UV23.J2
FBA_WCK0: UV18.K31 UV23.D4
FBA_WCK0_N: UV18.L30 UV23.D5
FBA_WCK1: UV18.H34 UV23.P4
FBA_WCK1_N: UV18.J34 UV23.P5
FBA_WCK2: UV18.AG30 UV24.P4
FBA_WCK2_N: UV18.AG31 UV24.P5
FBA_WCK3: UV18.AJ34 UV24.D4
FBA_WCK3_N: UV18.AK34 UV24.D5
FBA_WE#_H: UV18.AA32 UV24.G12
FBA_WE#_L: UV18.U32 UV23.L12
FBC_ABI#_H: UV18.G17 UV26.J4
FBC_ABI#_L: UV18.F15 UV25.J4
FBC_CAS#_H: UV18.E17 UV26.G3
FBC_CAS#_L: UV18.C17 UV25.L3
FBC_CKE_H: RV608.2 UV18.B17 UV26.J3
FBC_CKE_L: RV606.2 UV18.B15 UV25.J3
FBC_CLK0: RV629.1 UV18.D12 UV25.J12
FBC_CLK0#: RV628.1 UV18.E12 UV25.J11
FBC_CLK1: RV638.1 UV18.E20 UV26.J12
FBC_CLK1#: RV637.1 UV18.F20 UV26.J11
FBC_CS#_H: UV18.D18 UV26.L12
FBC_CS#_L: UV18.D13 UV25.G12
FBC_D0: UV18.G9 UV25.A4
FBC_D1: UV18.E9 UV25.A2
FBC_D2: UV18.G8 UV25.B4
FBC_D3: UV18.F9 UV25.B2
FBC_D4: UV18.F11 UV25.E4
FBC_D5: UV18.G11 UV25.E2
FBC_D6: UV18.F12 UV25.F4
FBC_D7: UV18.G12 UV25.F2
FBC_D8: UV18.G6 UV25.A11
FBC_D9: UV18.F5 UV25.A13
FBC_D10: UV18.E6 UV25.B11
FBC_D11: UV18.F6 UV25.B13
FBC_D12: UV18.F4 UV25.E11
FBC_D13: UV18.G4 UV25.E13
FBC_D14: UV18.E2 UV25.F11
FBC_D15: UV18.F3 UV25.F13
FBC_D16: UV18.C2 UV25.U11
FBC_D17: UV18.D4 UV25.U13
FBC_D18: UV18.D3 UV25.T11
FBC_D19: UV18.C1 UV25.T13
FBC_D20: UV18.B3 UV25.N11
FBC_D21: UV18.C4 UV25.N13
FBC_D22: UV18.B5 UV25.M11
FBC_D23: UV18.C5 UV25.M13
FBC_D24: UV18.A11 UV25.U4
FBC_D25: UV18.C11 UV25.U2
FBC_D26: UV18.D11 UV25.T4
FBC_D27: UV18.B11 UV25.T2
FBC_D28: UV18.D8 UV25.N4
FBC_D29: UV18.A8 UV25.N2
FBC_D30: UV18.C8 UV25.M4
FBC_D31: UV18.B8 UV25.M2
FBC_D32: UV18.F24 UV26.U4
FBC_D33: UV18.G23 UV26.U2
FBC_D34: UV18.E24 UV26.T4
FBC_D35: UV18.G24 UV26.T2
FBC_D36: UV18.D21 UV26.N4
FBC_D37: UV18.E21 UV26.N2
FBC_D38: UV18.G21 UV26.M4
FBC_D39: UV18.F21 UV26.M2
FBC_D40: UV18.G27 UV26.U11
FBC_D41: UV18.D27 UV26.U13
FBC_D42: UV18.G26 UV26.T11
FBC_D43: UV18.E27 UV26.T13
FBC_D44: UV18.E29 UV26.N11
FBC_D45: UV18.F29 UV26.N13
FBC_D46: UV18.E30 UV26.M11
FBC_D47: UV18.D30 UV26.M13
FBC_D48: UV18.A32 UV26.A11
FBC_D49: UV18.C31 UV26.A13
FBC_D50: UV18.C32 UV26.B11
FBC_D51: UV18.B32 UV26.B13
FBC_D52: UV18.D29 UV26.E11
FBC_D53: UV18.A29 UV26.E13
FBC_D54: UV18.C29 UV26.F11
FBC_D55: UV18.B29 UV26.F13
FBC_D56: UV18.B21 UV26.A4
FBC_D57: UV18.C23 UV26.A2
FBC_D58: UV18.A21 UV26.B4
FBC_D59: UV18.C21 UV26.B2
FBC_D60: UV18.B24 UV26.E4
FBC_D61: UV18.C24 UV26.E2
FBC_D62: UV18.B26 UV26.F4
FBC_D63: UV18.C26 UV26.F2
FBC_DBI0#: UV18.E11 UV25.D2
FBC_DBI1#: UV18.E3 UV25.D13
FBC_DBI2#: UV18.A3 UV25.P13
FBC_DBI3#: UV18.C9 UV25.P2
FBC_DBI4#: UV18.F23 UV26.P2
FBC_DBI5#: UV18.F27 UV26.P13
FBC_DBI6#: UV18.C30 UV26.D13
FBC_DBI7#: UV18.A24 UV26.D2
FBC_EDC0: UV18.D10 UV25.C2
FBC_EDC1: UV18.D5 UV25.C13
FBC_EDC2: UV18.C3 UV25.R13
FBC_EDC3: UV18.B9 UV25.R2
FBC_EDC4: UV18.E23 UV26.R2
FBC_EDC5: UV18.E28 UV26.R13
FBC_EDC6: UV18.B30 UV26.C13
FBC_EDC7: UV18.A23 UV26.C2
FBC_MA0_MA10_H: UV18.D16 UV26.K4
FBC_MA0_MA10_L: UV18.D15 UV25.H4
FBC_MA1_MA9_H: UV18.A18 UV26.K5
FBC_MA1_MA9_L: UV18.A14 UV25.H5
FBC_MA2_BA0_H: UV18.F18 UV26.K11
FBC_MA2_BA0_L: UV18.F14 UV25.H11
FBC_MA3_BA3_H: UV18.E18 UV26.K10
FBC_MA3_BA3_L: UV18.E14 UV25.H10
FBC_MA4_BA2_H: UV18.A20 UV26.H11
FBC_MA4_BA2_L: UV18.A12 UV25.K11
FBC_MA5_BA1_H: UV18.B20 UV26.H10
FBC_MA5_BA1_L: UV18.B12 UV25.K10
FBC_MA6_MA11_H: UV18.G18 UV26.H5
FBC_MA6_MA11_L: UV18.G15 UV25.K5
FBC_MA7_MA8_H: UV18.B18 UV26.H4
FBC_MA7_MA8_L: UV18.B14 UV25.K4
FBC_MA12_RFU_H: UV18.F17 UV26.J5
FBC_MA12_RFU_L: UV18.E15 UV25.J5
FBC_RAS#_H: UV18.D17 UV26.L3
FBC_RAS#_L: UV18.D14 UV25.G3
FBC_RST#_H: RV615.1 UV18.A17 UV26.J2
FBC_RST#_L: RV616.1 UV18.A15 UV25.J2
FBC_WCK0: UV18.F8 UV25.D4
FBC_WCK0_N: UV18.E8 UV25.D5
FBC_WCK1: UV18.A5 UV25.P4
FBC_WCK1_N: UV18.A6 UV25.P5
FBC_WCK2: UV18.D24 UV26.P4
FBC_WCK2_N: UV18.D25 UV26.P5
FBC_WCK3: UV18.B27 UV26.D4
FBC_WCK3_N: UV18.C27 UV26.D5
FBC_WE#_H: UV18.C18 UV26.G12
FBC_WE#_L: UV18.C14 UV25.L12
FBVDD/Q_ENP: PC710.1 PR709.2 PU700.3
FBVDD_EN: DV13.1 PR709.1 QZ6.5 RV550.1 U33.19
FBVDD_PSI: PR703.2 PR708.1 PU700.4
FBVDDQ_SENSE: PR718.2 UV18.F1
FFS_INT2: QF1.2 RF5.2 UF1.11 UH2.BE14
FFS_INT2_Q: JHDD.11 QF1.3 RF2.2
FGND: JFP.4 RE255.2
FPR_DET#: RE274.1 RE284.1 UE3.B3
FPR_GPIO_DET#: JFP.1 MD3.1 RE274.2
FPR_GPIO_SCAN#: JFP.2 MD4.1 RE273.2
FPR_SCAN#: RE273.1 RE283.1 UE3.E5
FRM_LCK: RV564.1 UV18.L7
GC5_MODE: RV1839.1 T210.1(TP-1) UV18.P4
GC6_EVENT#: DV14.1 UH2.BE9
GC6_EVENT#_D: DV14.2 RV551.1 UV18.L6
GPIO0: RM13.2 UM1.C4
GPIO2: RM12.2 UM1.E3
GPIO4: RM11.2 RM20.2 UM1.E7
GPP_H12: RH5881.2 UH2.AB47
GPP_H15: RH42.2 UH2.AC47
GPP_J4: RH5853.2 UH2.AV4
GPP_J6: RH5854.2 UH2.BA4
GPP_J9: RH5855.2 RH5890.1 UH2.AU9
GPPJ_RCOMP: RH5834.1 UH2.BD1 UH2.BE1 UH2.BE2
GPU_CORE_PG: DV16.3 PR1017.2 UV28.2
GPU_CORE_VDDS_PG: PR905.1 PR1518.2 U33.5
GPU_GC6_FB_EN: QV98.1 RV1133.1 RV1844.1 U33.7 UE3.M4 UH2.BF9
GPU_GC6_FB_EN_GPU: DV13.3 QV98.3 QV105.2 RV566.1 U33.6 UV18.M3
GPU_GC6_FB_EN_GPU#: QV105.1 RV1842.2 UV29.2
GPU_GPIO0: RV1095.1 UV18.P6
GPU_GPIO3: RV1098.1 UV18.P5
GPU_GPIO8: RV1086.1 UV18.L3
GPU_GPIO21: RV1840.1 UV18.P1
GPU_GPIO22: T4978.1(TP-1) UV18.P8
GPU_GPIO25: T4995.1(TP-1) UV18.R4
GPU_GPIO26: T4996.1(TP-1) UV18.R5
GPU_ID: CE3319.1 RE301.2 UE3.J10
GPU_JTAG_TCK: T201.1(TP-1) UV18.AM10
GPU_JTAG_TDI: T202.1(TP-1) UV18.AM11
GPU_JTAG_TDO: T203.1(TP-1) UV18.AP12
GPU_JTAG_TMS: T204.1(TP-1) UV18.AP11
GPU_JTAG_TRST#: RV593.1 UV18.AN11
GPU_LEVEL: DV15.2 RV554.1 UV18.N3
GPU_MF_BALL_A: RV617.1 UV23.J1
GPU_MF_BALL_B: RV618.1 UV24.J1
GPU_MF_BALL_C: RV631.1 UV25.J1
GPU_MF_BALL_D: RV630.1 UV26.J1
GPU_PEX_RST_HOLD#: RV563.1 UV18.T8
GPU_PSI: PR1001.2 PR1501.2 RV552.1 UV18.M7
GPU_PWR_LEVEL: DV15.1 UE3.E12
GPU_SMBCLK: QV21.6 RE296.1 UE3.F7
GPU_SMBDAT: QV21.3 RE295.1 UE3.B6
GPU_VREFD_BALL_A: TV3.1(TP-1) UV23.A10 UV23.U10
GPU_VREFD_BALL_B: TV4.1(TP-1) UV24.A10 UV24.U10
GPU_VREFD_BALL_C: TV6.1(TP-1) UV25.A10 UV25.U10
GPU_VREFD_BALL_D: TV5.1(TP-1) UV26.A10 UV26.U10
GPU_ZQ_BALL_A: RV619.1 UV23.J13
GPU_ZQ_BALL_B: RV620.1 UV24.J13
GPU_ZQ_BALL_C: RV633.1 UV25.J13
GPU_ZQ_BALL_D: RV632.1 UV26.J13
GT_B+: PC1700.1 PC1701.1 PC1702.1 PC1703.1 PC1704.2 PL1700.2 PL1701.2 PU1700.8 PU1700.9
GT_SW1: PC1708.1 PL1702.1 PU1700.11 PU1700.12
H_CATERR#: RH570.2 UH1.BM30
H_CPUPWRGD: UH1.BT31 UH2.AE3
H_DRAMRST#: CD69.1 RD31.2 RD35.2 UH2.BB46
H_PECI: RE48.2 RH190.1 RH539.2
H_PECI_R: RH190.2 RH200.1 UH1.BT34
H_PM_DOWN: RH155.1 UH2.AE2
H_PM_DOWN_R: RH155.2 UH1.BP31
H_PM_SYNC: RH189.1 UH2.AF3
H_PM_SYNC_R: RH189.2 UH1.BM34
H_PROCHOT#: PR1104.2 PR1113.2 PR1919.1 RE96.2 RH158.1 RH165.2
H_PROCHOT#_EC: RE96.1 UE3.H13
H_PROCHOT#_R: RH158.2 UH1.BR30
H_THERMTRIP#: RH191.1 UH2.AD3
H_THERMTRIP#_R: QE10.3 RH163.2 RH191.2 UH1.J31
H_VCCST_PWRGD: RH154.1 RH164.2 RH482.1 UE7.4
H_VCCST_PWRGD_GATE: RZ82.2 RZ1955.2 RZ1957.2 UE7.2 UZ19.4
HD_SOC_SEL: RA15.2 RA16.2 UA1.6
HDA_BITCLK: CH50.2 RP15.3 UH2.BD11
HDA_BITCLK_AUDIO: CA33.1 CA120.2 RP15.6 UA1.13
HDA_RST#: RP15.4 UH2.BE10
HDA_SDIN0: CD3324.1 RH96.2 UH2.BE11
HDA_SDIN0_AUDIO: RA6.1 RH96.1
HDA_SDOUT: CD3325.1 CH51.2 RH454.2 RP15.2 UH2.BF12
HDA_SDOUT_AUDIO: CA38.1 RP15.7 UA1.17
HDA_SYNC: RP15.1 UH2.BG13
HDA_SYNC_AUDIO: CA34.1 RP15.8 UA1.14
HDD_DET#: JHDD.12 RH513.1 UH2.AK47
HDD_DEVSLP: RD100.1 UH2.AH40
HDD_FALL_INT: RF4.2 UF1.12 UH2.AW26
HDMI_CEC: CV182.2 JHDMI1.13 RM19.2
HDMI_CLKN: RV532.1 UM1.H1
HDMI_CLKP: RV533.1 UM1.H2
HDMI_HPLUG: CV180.2 JHDMI1.19 RH5894.2 RM27.1 UM1.G1
HDMI_ID: RM24.1 UM1.D8
HDMI_R_CLKN: DT175.1 JHDMI1.12 RV532.2 RV539.1
HDMI_R_CLKP: DT176.1 JHDMI1.10 RV533.2 RV539.2
HDMI_R_TX_N0: DT177.1 JHDMI1.9 RV534.2 RV540.1
HDMI_R_TX_N1: DT179.1 JHDMI1.6 RV536.2 RV541.1
HDMI_R_TX_N2: DT181.1 JHDMI1.3 RV531.2 RV538.1
HDMI_R_TX_P0: DT178.1 JHDMI1.7 RV535.2 RV540.2
HDMI_R_TX_P1: DT180.1 JHDMI1.4 RV537.2 RV541.2
HDMI_R_TX_P2: DT182.1 JHDMI1.1 RV530.2 RV538.2
HDMI_RESERVED: CV181.2 JHDMI1.14
HDMI_TX_N0: RV534.1 UM1.H3
HDMI_TX_N1: RV536.1 UM1.H5
HDMI_TX_N2: RV531.1 UM1.H7
HDMI_TX_P0: RV535.1 UM1.H4
HDMI_TX_P1: RV537.1 UM1.H6
HDMI_TX_P2: RV530.1 UM1.H8
HOST_DEBUG_TX: JDEG1.8 RE64.2 RE297.1 UE3.G11
HOST_SD_WP#: QR1.2 RH563.2 UH2.BE8
HP_JD#: DA3.1 JAUDIO.8 JHP1.6 RA14.1 RA82.2
HP_LINE1_JD: CA23.1 RA13.2 RA14.2 UA1.9
HPD_IFPA: T4973.1(TP-1) UV18.N4
HPD_IFPB: T4974.1(TP-1) UV18.P2
HPD_IFPC: T4980.1(TP-1) UV18.U3
HPD_IFPD: T4975.1(TP-1) UV18.M6
HPD_IFPE: T4976.1(TP-1) UV18.R1
HPD_IFPF: T4979.1(TP-1) UV18.L2
HPOUT_D_L_C: CA42.2 DA2.1 JHP1.1 LA6.2
HPOUT_D_R_C: CA43.1 DA9.1 JHP1.2 LA7.2
HPOUT_L: RA28.2 RA30.2 RA52.1 RA75.2 UA1.32
HPOUT_L_R1: LA6.1 RA52.2
HPOUT_R: RA27.2 RA29.2 RA31.2 RA51.1 UA1.33
HPOUT_R_R2: LA7.1 RA51.2
HW_ACAVIN_NB: DI14.1 PC207.1 PR207.2 PR208.2 PR214.1 PR284.1 PR285.1 PR1939.1 PU200.1
HW_ACAVIN_NB_P: DI14.2 RE142.1 UE3.N6
I2C0_IRQ_TS_R: JTS1.4 RR41.2
I2C0_SCK_DSP: JAUDIO.5 QE18.4 RE136.2 UA1.12
I2C0_SCK_TS: RC184.2 RR45.1 UH2.BC22
I2C0_SCK_TS_R: JTS1.3 RR45.2
I2C0_SDA_DSP: JAUDIO.3 QE18.1 RE137.2 UA1.11
I2C0_SDA_TS: RC183.2 RR42.1 UH2.BF23
I2C0_SDA_TS_R: JTS1.2 RR42.2
I2C1_SCK_TP: QE2.3 RH119.2 UH2.BE21
I2C1_SCK_TP_C: CE79.1 DE5.3 JTP.6 QE2.4 RE9.1
I2C1_SDA_TP: QE2.6 RH120.2 UH2.BF21
I2C1_SDA_TP_C: CE80.1 DE5.2 JTP.7 QE2.1 RE7.1
I2C2_IRQ_TS: RH5891.1 RR41.1 UH2.AP29
I2C_EN8723: RI25.1 UI3.24
I2CB_SCL: RV570.1 UV18.R7
I2CB_SDA: RV571.1 UV18.R6
I2S_BCLK: JAUDIO.9 UA1.56
I2S_IN: JAUDIO.15 UA1.5
I2S_LRCK: JAUDIO.13 UA1.1
I2S_MCLK: JAUDIO.11 UA1.55
I2S_OUT: JAUDIO.17 UA1.3
I2S_RST_AUDIO#: CA37.1 RA17.2 RA93.1 RP15.5
I2S_RST_AUDIO#_R: RA93.2 UA1.15
I2S_SDIN0_AUDIO_R: RA6.2 UA1.16
I_ADP: PR1933.2 UE3.B11
I_BATT: PR1932.2 RE55.2
I_BATT_R: C3320.1 RE55.1 UE3.J4
I_SYS_R: C3321.1 RE126.1 UE3.J5
ILIM_1PH: PC1107.2 PR1119.2 PU1100.49
ILIM_2PH: PR1143.1 PU1100.32
ILIM_4PH: PR1142.2 PU1100.7
ILIM_HI1: RI12.1 UI2.16
ILIM_HI3: RI7.1 UI1.16
ILIM_LO1: RI11.1 UI2.15
ILIM_LO3: RI6.1 UI1.15
ILIM_SEL_L: DI12.3 RI31.2 RI33.1 RI34.2 UI1.4
ILIM_SEL_R: DI12.2 RI30.2 RI32.1 RI34.1 RI35.2 UI2.4
ILMT_1.8VSP: PR1606.2 PR1607.1 PU1600.13
ILMT_1V: PR506.2 PR508.1 PU500.13
ILMT_1VSP: PR909.2 PR910.1 PU900.13
IMON_1PH: PC1106.2 PR1112.2 PU1100.46
IMVP_VR_ON: UE3.N7 UZ21.1
IMVP_VR_PG: PR1117.2 PU1100.45 UH14.1
INTRUDER#: RH531.1 UH2.BB44
INV_PWM: DV2.1 JEDP1.25 RV109.1
IRQ_SERIRQ: RH5882.1 UH2.AW35
IST_TRIG_T: T40.1(TP-1) UH1.E3
JTAG_CLK: JDEG1.4 RP20.3 UE3.C8
JTAG_RST#: CE44.1 JTAG1.1 RE59.2 RE61.1 UE3.G13
JTAG_TDI: JDEG1.2 RP20.1 UE3.E9
JTAG_TDO: JDEG1.5 RP20.4 UE3.F6
JTAG_TMS: JDEG1.3 RP20.2 UE3.C5
KB_DET#: JKB.5 RH557.1 UH2.AW15
LAN_WAKE#: RH545.1 UE3.L3 UH2.BG44
LCD_BL_PWM: RV1834.1 RV1841.1 UV18.N8
LCD_BLEN: RV1838.1 UV18.M4
LCD_DBC: RH527.1 RH528.1 RV1843.1 UH2.AP48
LCD_DBC_R: JEDP1.27 RV1843.2
LCD_TST: RE32.2 RV110.1 UE3.M2
LCD_VCC_TEST_EN: DV7.2 UE3.E1
LCD_VDD: RV1837.1 UV18.M5
LDO1_CAP: CA30.1 UA1.44
LDO2_CAP: CA26.1 CA27.1 UA1.22
LDO3_CAP: CA77.1 CA130.1 UA1.18
LDO_3V: PC505.1 PU500.16 PU500.17
LDO_IN: PC220.1 PD203.1 PD204.1 PR276.1 PU204.1
LG1_ISL88738: PQ1903.4 PU1900.9
LG2_ISL88738: PQ1904.4 PU1900.7
LG_3V: PC415.1 PQ402.4 PU400.11
LG_5V: PC416.1 PQ403.4 PU400.15
LID_CL_SIO#: CE31.1 R5841.1 RE41.2 RE45.2 UE3.N11
LID_FPR#: D323.1 JFP.3 R5841.2
LID_SW_IN#: CE16.1 RE45.1 UE2.3
LINE1-VREFO: DA7.2 DA14.2 RA27.1 UA1.40
LINE1_L: CA45.1 UA1.35
LINE1_L_C: CA119.2 RA31.1
LINE1_R: CA119.1 UA1.34
LINE1_R_C: CA45.2 RA30.1
LPC_PD#: RE286.1 UE3.N3
LPS_PROTECT#: PR260.2 PT202.1(TP-1)
LX1_ISL88738: PC1913.2 PL1901.1 PQ1900.1 PQ1900.2 PQ1900.3 PQ1902.1 PQ1902.2 PQ1902.3 PQ1903.5 PR1915.1 PU1900.10
LX1_NVVDD: PC1022.2 PL1002.1 PQ1000.1 PQ1000.2 PQ1000.3 PQ1001.5 PQ1007.5 PR1009.1 PU1001.20
LX1_NVVDDS: PC1519.2 PL1500.1 PQ1500.1 PQ1500.2 PQ1500.3 PQ1501.5 PR1512.1 PU1501.20
LX2_ISL88738: PC1929.1 PL1901.2 PQ1901.1 PQ1901.2 PQ1901.3 PQ1904.5 PR1916.1 PU1900.6
LX2_NVVDD: PC1047.1 PL1003.1 PQ1002.1 PQ1002.2 PQ1002.3 PQ1003.5 PQ1008.5 PR1020.1 PU1001.16
LX_1.8VSP: PC1601.2 PL1601.1 PR1601.1 PU1600.6 PU1600.19 PU1600.20
LX_1V: PC502.2 PL501.1 PR502.1 PU500.6 PU500.19 PU500.20
LX_1VSP: PC902.2 PL901.1 PR901.1 PU900.6 PU900.19 PU900.20
LX_3V: PC410.1 PL400.2 PQ400.1 PQ400.2 PQ400.3 PQ402.5 PR413.1 PU400.8
LX_5V: PC411.2 PL401.1 PQ401.1 PQ401.2 PQ401.3 PQ403.5 PR414.1 PU400.18
M2280_DEVSLP: JNGFF2.38 RD7.2 UH2.AH35
M2280_PCIE_SATA#: RD58.1 RH508.1 UH2.AJ43
M_CLK_DDR0: JDIMM1.137 UH1.AG1
M_CLK_DDR1: JDIMM1.138 UH1.AK2
M_CLK_DDR2: JDIMM2.137 UH1.AM9
M_CLK_DDR3: JDIMM2.138 UH1.AM7
M_CLK_DDR#0: JDIMM1.139 UH1.AG2
M_CLK_DDR#1: JDIMM1.140 UH1.AK1
M_CLK_DDR#2: JDIMM2.139 UH1.AN9
M_CLK_DDR#3: JDIMM2.140 UH1.AM8
M_ODT0: JDIMM1.155 UH1.AD3
M_ODT1: JDIMM1.161 UH1.AE4
M_ODT2: JDIMM2.155 UH1.AF7
M_ODT3: JDIMM2.161 UH1.AE8
ME_EN: RH454.1 RH487.1 SW4.2
ME_FWP: RE68.2 RE70.2 RH487.2 SW4.3 UE3.G12
ME_SUS_PWR_ACK: RH506.1 RH5873.1 UE3.B13
ME_SUS_PWR_ACK_R: RH5873.2 UH2.BC37
MEC_XTAL1: CE42.1 UE3.A1 YE1.1
MEC_XTAL2: CE43.1 RE51.2 YE1.2
MEC_XTAL2_R: RE51.1 UE3.A3
MEDIACARD_IRQ#: RH546.1 RR10.1 UH2.BB26
MEM_SMBCLK: QH4.6 RH458.2 UH2.BE26
MEM_SMBDATA: QH4.3 RH459.2 UH2.BF26
MEM_VDD_CTL: PR717.1 RV1086.2 RV1836.1
MEM_VREF: QV101.2 QV102.2 RV567.1 UV18.L1
MIC1-VREFO_L: RA20.1 RA21.1 UA1.38
MIC1-VREFO_R: RA19.1 RA75.1 UA1.39
MONO_IN: CA16.2 UA1.23
MONO_IN_R: CA16.1 CA19.1 RA4.2 RA7.2 RA57.1
MSCLK: JDEG1.6 RE63.2 RE288.2 RE299.2
MSCLK_R: RE288.1 UE3.H10
MSDATA: JDEG1.7 RE27.1 RE65.2 RE287.2
MSDATA_R: RE287.1 UE3.G9
NB_MUTE#: JAUDIO.4 RA12.2 RA68.1 UA1.52 UE3.A4
NRB_BIT: RH524.2 UH2.BE30
NVVDD_EN: CV919.1 DA56.2 PC1015.1 PR1004.1 PU1001.3 QZ15.2 RV1130.1 U33.18
NVVDD_PGOOD: PR1017.1 PR1019.1 PU1001.13
NVVDD_PWM_VID: PR1003.1 RV1095.2
NVVDD_VID: PR1003.2 PU1001.5
NVVDDS_EN: PR902.1 PU1501.3 QZ14.2 RV1807.1 U33.17
NVVDDS_PGOOD: PR1518.1 PR1522.1 PU1501.13
NVVDDS_PSI: PR1500.2 PR1501.1 PR1502.1 PU1501.4
NVVDDS_PWM_VID: PR1503.1 RV1098.2 RV1835.1
NVVDDS_VID: PR1503.2 PU1501.5
OTGEN/CMIN: PR1909.2 PR1912.2 PU1900.20
P_SYS: PR1157.1 PR1929.2 PU1100.24 RE126.2
PANEL_BKEN_EC: DV1.2 UE3.J9
PANEL_BKEN_PCH: DV1.3 UH2.AU46 UH2.AV46
PARSVD1: T4951.1(TP-1) UH2.R13
PARSVD2: T4950.1(TP-1) UH2.R15
PBAT_CHARGER_SMBCLK: PD101.2 PR106.2 PR1917.1 RE23.1 UE3.N2
PBAT_CHARGER_SMBDAT: PD101.3 PR108.2 PR1913.1 RE22.1 UE3.M3
PBAT_PRES#: PD102.2 PD102.3 PR111.2 PR112.1 PR1924.1 UE3.F9
PBRSVD1: T4964.1(TP-1) UH2.U13
PBTN_SW#: CE29.1 DL1.3 JAPS.11 Q6.1 RE36.2 SW1.1 SW_BOT.1
PBTN_SW#_R: D324.1 JFP.7 Q6.3
PCH_3.3V_TS_EN: RZ39.1 UH2.BD30 UZ5.3
PCH_ALW_ON: UE3.M8 UZ23.2
PCH_ALW_ON_R: RZ46.2 RZ1133.2 UZ4.3
PCH_BATLOW#: RH515.1 UH2.BF44
PCH_CPU_BCLK_N: UH1.A32 UH2.C8
PCH_CPU_BCLK_P: UH1.B31 UH2.B8
PCH_CPU_PCIBCLK_N: UH1.C36 UH2.B6
PCH_CPU_PCIBCLK_P: UH1.D35 UH2.A6
PCH_DMIC_CLK: RA103.2 UH2.BD16
PCH_DMIC_CLK_R: CE3321.1 RA103.1 RE310.1
PCH_DMIC_DAT: RA102.2 UH2.BF15
PCH_DMIC_DAT_R: CE3322.1 RA102.1 RE309.1
PCH_DP1_HPD: RT41.2 UH2.AT6 UT1.AA2
PCH_DP2_HPD: RT42.2 UH2.AN10 UT1.Y6
PCH_DP3_HPD: RM3.2 RM1145.2 UH2.AP9
PCH_DP3_HPD_R: RM3.1 UM1.B1
PCH_DPWROK_EC: RH309.1 UE3.F8
PCH_DPWROK_R: RH309.2 RH401.2 RH5859.2 UH2.AW41
PCH_GPP_A11_BALL: T17.1(TP-1) UH2.BE36
PCH_GPP_A18: T124.1(TP-1) UH2.BF35
PCH_GPP_C10: T4989.1(TP-1) UH2.BA24
PCH_GPP_C11: T4988.1(TP-1) UH2.AP24
PCH_GPP_D7_BALL: T121.1(TP-1) UH2.AW18
PCH_GPP_H23_BALL: T8.1(TP-1) UH2.AJ47
PCH_GPP_K2_BALL: T94.1(TP-1) UH2.L46
PCH_GPP_K8_BALL: T91.1(TP-1) UH2.P48
PCH_GPP_K9_BALL: T92.1(TP-1) UH2.V47
PCH_GPP_K23_BALL: T4.1(TP-1) UH2.M45
PCH_ITP_PMODE: RH479.1 UH2.AL3
PCH_JTAG_TCK: JXDP.55 RH95.2 UH2.AJ3
PCH_JTAG_TDI: RH100.2 RH477.2 UH2.AH2
PCH_JTAG_TDO: RH97.2 RH478.2 UH2.AH3
PCH_JTAG_TMS: RH12.2 RH98.2 UH2.AJ4
PCH_JTAGX: RH491.1 UH2.AH4
PCH_PCIE_WAKE#: RE322.1 RH453.1 RT5843.1 UE3.L1 UH2.BB47
PCH_PECI: RH539.1 RH5836.1 UH2.AF2
PCH_PLTRST#: CH3327.1 UH2.AV29 UH7.1 UH7.2
PCH_PLTRST#_5105: RE183.1 UE3.K1 UE5.4
PCH_PLTRST#_EC: JNGFF1.44 JNGFF2.50 RE31.2 RH77.1 RR43.1 RT435.1 RT1135.2 U32.17 U33.8 UE5.2 UH7.4 UR1.1 UV19.2
PCH_PLTRST#_EC_AR: RT5855.1 RT5857.2 UH2.BE23
PCH_PLTRST#_EC_R: JLPDE1.8 RT1135.1
PCH_PRIM_EN: CZ2154.1 PR1602.1 PR1950.1 RH5870.1 RH5871.1 RZ1951.2
PCH_PWROK: RH529.1 UH2.AY42 UH14.4
PCH_RSMRST#: RT1136.1 UE3.M5
PCH_RSMRST#_EC: RH133.1 RH481.1 RH5859.1 RT1136.2
PCH_RSMRST#_R: RH133.2 RH5841.2 UH2.BA47
PCH_RTCRST#: CH53.1 CLRP1.1 JAPS.9 RH84.2 RT1133.1 UH2.BE47
PCH_RTCRST#_R: QR104.1 RT1133.2
PCH_RTCX1: CH45.1 RH70.1 UH2.BA49 YH1.1
PCH_RTCX2: CH46.1 RH70.2 UH2.BA48 YH1.2
PCH_RTD3_USB_PWR_EN: RT5841.1 UH2.BC17
PCH_SLP_LAN#: T20.1(TP-1) UH2.BF40
PCH_SMB_ALERT#: RH505.2 UH2.BE25
PCH_SMBCLK: JDIMM1.253 JDIMM2.253 JXDP.53 QH4.1 RH463.2 UF1.1
PCH_SMBDATA: JDIMM1.254 JDIMM2.254 JXDP.51 QH4.4 RH462.2 UF1.4
PCH_SPI_CLK: JSPI1.4 RH577.2 RH5892.1 RP4.1 UH2.AW47
PCH_SPI_CLK_R: RP4.8 UH8.6
PCH_SPI_CLK_TPM: RE115.1 RH577.1
PCH_SPI_CLK_TPM_R: C135.1 RE115.2 U32.19
PCH_SPI_CS#0: JSPI1.5 RH74.2 UH2.AY47 UH8.1
PCH_SPI_CS#1: JSPI1.1 UH2.AW48
PCH_SPI_CS#2: RE133.1 UH2.AT40
PCH_SPI_CS#2_R: RE133.2 U32.20
PCH_SPI_HOLD#: JSPI1.7 RH78.2 RH576.2 UH2.BA46
PCH_SPI_HOLD#_R: RH576.1 UH8.7
PCH_SPI_SI: JSPI1.2 RH489.1 RH578.2 RH5860.2 RP4.2 UH2.AU41
PCH_SPI_SI_R: RP4.7 UH8.5
PCH_SPI_SI_TPM: RE114.1 RH578.1
PCH_SPI_SI_TPM_R: RE114.2 U32.21
PCH_SPI_SO: JSPI1.3 RH579.2 RP4.3 UH2.BA45
PCH_SPI_SO_R: RP4.6 UH8.2
PCH_SPI_SO_TPM: RE113.1 RH579.1
PCH_SPI_SO_TPM_R: RE113.2 U32.24
PCH_SPI_WP#: JSPI1.6 RH75.2 RH573.2 RP4.4 UH2.AY48
PCH_SPI_WP#_R: RP4.5 UH8.3
PCH_SPI_WP#_XDP: JXDP.60 RH573.1
PCH_SRTCRST#: CH52.1 RH83.2 UH2.BD46
PCH_SYS_PWROK_XDP: JXDP.47 RH489.2 RH490.2 RH493.2
PCH_TBT_PERST#: RT435.2 RT5855.2 UT1.L4
PCH_TP_BALL: T4947.1(TP-1) UH2.AL35
PCH_TRIGGER: RH167.1 UH2.AK3
PCH_TRIGGER_R: RH167.2 UH1.H23
PCH_XDP_CLK_N: JXDP.42 UH2.Y3
PCH_XDP_CLK_P: JXDP.40 UH2.Y4
PCI_CLK_LPC1: RH428.1 UH2.BB34
PCI_CLK_LPC1_R: RH428.2 T4945.1(TP-1)
PCIE_PRX_C_DTX_N5: CR13.2 UR1.8
PCIE_PRX_C_DTX_P5: CR10.2 UR1.7
PCIE_PRX_C_TTX_N17: CT181.2 UT1.V22
PCIE_PRX_C_TTX_N18: CT180.2 UT1.P22
PCIE_PRX_C_TTX_N19: CT7.2 UT1.K22
PCIE_PRX_C_TTX_N20: CT3.2 UT1.F22
PCIE_PRX_C_TTX_P17: CT179.2 UT1.V23
PCIE_PRX_C_TTX_P18: CT178.2 UT1.P23
PCIE_PRX_C_TTX_P19: CT5.2 UT1.K23
PCIE_PRX_C_TTX_P20: CT1.2 UT1.F23
PCIE_PRX_DTX_N1: JNGFF1.35 UH2.G17
PCIE_PRX_DTX_N5: CR13.1 UH2.F20
PCIE_PRX_DTX_N09: JNGFF2.5 UH2.G36
PCIE_PRX_DTX_N10: JNGFF2.17 UH2.K37
PCIE_PRX_DTX_N11: JNGFF2.29 UH2.G38
PCIE_PRX_DTX_P1: JNGFF1.33 UH2.F16
PCIE_PRX_DTX_P5: CR10.1 UH2.G20
PCIE_PRX_DTX_P09: JNGFF2.7 UH2.F36
PCIE_PRX_DTX_P10: JNGFF2.19 UH2.J37
PCIE_PRX_DTX_P11: JNGFF2.31 UH2.F39
PCIE_PRX_TTX_N17: CT181.1 UH2.K43
PCIE_PRX_TTX_N18: CT180.1 UH2.P41
PCIE_PRX_TTX_N19: CT7.1 UH2.M44
PCIE_PRX_TTX_N20: CT3.1 UH2.R35
PCIE_PRX_TTX_P17: CT179.1 UH2.K44
PCIE_PRX_TTX_P18: CT178.1 UH2.R40
PCIE_PRX_TTX_P19: CT5.1 UH2.N42
PCIE_PRX_TTX_P20: CT1.1 UH2.R37
PCIE_PTX_C_DRX_N1: CN20.2 JNGFF1.29
PCIE_PTX_C_DRX_N5: CR9.2 UR1.4
PCIE_PTX_C_DRX_N09: CD43.2 JNGFF2.11
PCIE_PTX_C_DRX_N10: CD45.2 JNGFF2.23
PCIE_PTX_C_DRX_N11: CD53.2 JNGFF2.35
PCIE_PTX_C_DRX_P1: CN21.2 JNGFF1.27
PCIE_PTX_C_DRX_P5: CR7.2 UR1.3
PCIE_PTX_C_DRX_P09: CD44.2 JNGFF2.13
PCIE_PTX_C_DRX_P10: CD46.2 JNGFF2.25
PCIE_PTX_C_DRX_P11: CD51.2 JNGFF2.37
PCIE_PTX_C_TRX_N17: CT177.1 UT1.Y22
PCIE_PTX_C_TRX_N18: CT174.1 UT1.T22
PCIE_PTX_C_TRX_N19: CT8.1 UT1.M22
PCIE_PTX_C_TRX_N20: CT4.1 UT1.H22
PCIE_PTX_C_TRX_P17: CT176.1 UT1.Y23
PCIE_PTX_C_TRX_P18: CT175.1 UT1.T23
PCIE_PTX_C_TRX_P19: CT6.1 UT1.M23
PCIE_PTX_C_TRX_P20: CT2.1 UT1.H23
PCIE_PTX_DRX_N1: CN20.1 UH2.A17
PCIE_PTX_DRX_N5: CR9.1 UH2.B21
PCIE_PTX_DRX_N09: CD43.1 UH2.C34
PCIE_PTX_DRX_N10: CD45.1 UH2.C35
PCIE_PTX_DRX_N11: CD53.1 UH2.B36
PCIE_PTX_DRX_P1: CN21.1 UH2.B17
PCIE_PTX_DRX_P5: CR7.1 UH2.A22
PCIE_PTX_DRX_P09: CD44.1 UH2.D34
PCIE_PTX_DRX_P10: CD46.1 UH2.B35
PCIE_PTX_DRX_P11: CD51.1 UH2.C36
PCIE_PTX_TRX_N17: CT177.2 UH2.A42
PCIE_PTX_TRX_N18: CT174.2 UH2.C42
PCIE_PTX_TRX_N19: CT8.2 UH2.C44
PCIE_PTX_TRX_N20: CT4.2 UH2.A44
PCIE_PTX_TRX_P17: CT176.2 UH2.B42
PCIE_PTX_TRX_P18: CT175.2 UH2.D42
PCIE_PTX_TRX_P19: CT6.2 UH2.D43
PCIE_PTX_TRX_P20: CT2.2 UH2.B44
PCIE_RCOMPN: RH108.1 UH2.B12
PCIE_RCOMPP: RH108.2 UH2.A13
PCIE_WAKE#: JNGFF1.47 RD59.2 RE322.2 RE323.1 RT5849.1
PCIE_WAKE#_R: RE19.1 RE323.2 UE3.N13
PD_DEBUG_CTRL1: RT226.2 UT4.E4
PD_DEBUG_CTRL2: RT227.2 UT4.D5
PD_EE_CLK: UT4.A3 UT5.6
PD_EE_CS#: RT168.2 UT4.B3 UT5.1
PD_EE_DI: UT4.B4 UT5.5
PD_EE_DO: RT169.2 UT4.A4 UT5.2
PD_EE_WP#: RT170.2 UT5.3
PD_GPIO2: RT437.1 UT4.D10
PD_HOLD#: RT171.2 UT5.7
PD_PGPIO7: RT182.1 UT4.D7
PD_PMRESET: RT186.1 RT245.1 UT4.E11
PD_SS: CT158.1 UT4.H7
PD_VDDIO_VIN_3V3: RT1095.2 UT4.B1 UT4.H1
PECI_EC_R: CE39.1 RE48.1 UE3.K13
PEG_GTX_C_HRX_N0: CV819.2 UH1.E10
PEG_GTX_C_HRX_N1: CV821.2 UH1.E11
PEG_GTX_C_HRX_N2: CV823.2 UH1.E12
PEG_GTX_C_HRX_N3: CV825.2 UH1.E13
PEG_GTX_C_HRX_N4: CV827.2 UH1.E14
PEG_GTX_C_HRX_N5: CV829.2 UH1.E15
PEG_GTX_C_HRX_N6: CV831.2 UH1.E16
PEG_GTX_C_HRX_N7: CV833.2 UH1.E17
PEG_GTX_C_HRX_N8: CV835.2 UH1.F18
PEG_GTX_C_HRX_N9: CV837.2 UH1.D19
PEG_GTX_C_HRX_N10: CV839.2 UH1.F20
PEG_GTX_C_HRX_N11: CV841.2 UH1.D21
PEG_GTX_C_HRX_N12: CV843.2 UH1.F22
PEG_GTX_C_HRX_N13: CV845.2 UH1.D23
PEG_GTX_C_HRX_N14: CV847.2 UH1.F24
PEG_GTX_C_HRX_N15: CV849.2 UH1.D25
PEG_GTX_C_HRX_P0: CV818.2 UH1.F10
PEG_GTX_C_HRX_P1: CV820.2 UH1.D11
PEG_GTX_C_HRX_P2: CV822.2 UH1.F12
PEG_GTX_C_HRX_P3: CV824.2 UH1.D13
PEG_GTX_C_HRX_P4: CV826.2 UH1.F14
PEG_GTX_C_HRX_P5: CV828.2 UH1.D15
PEG_GTX_C_HRX_P6: CV830.2 UH1.F16
PEG_GTX_C_HRX_P7: CV832.2 UH1.D17
PEG_GTX_C_HRX_P8: CV834.2 UH1.E18
PEG_GTX_C_HRX_P9: CV836.2 UH1.E19
PEG_GTX_C_HRX_P10: CV838.2 UH1.E20
PEG_GTX_C_HRX_P11: CV840.2 UH1.E21
PEG_GTX_C_HRX_P12: CV842.2 UH1.E22
PEG_GTX_C_HRX_P13: CV844.2 UH1.E23
PEG_GTX_C_HRX_P14: CV846.2 UH1.E24
PEG_GTX_C_HRX_P15: CV848.2 UH1.E25
PEG_GTX_HRX_N0: CV819.1 UV18.AJ14
PEG_GTX_HRX_N1: CV821.1 UV18.AG14
PEG_GTX_HRX_N2: CV823.1 UV18.AJ15
PEG_GTX_HRX_N3: CV825.1 UV18.AK16
PEG_GTX_HRX_N4: CV827.1 UV18.AJ17
PEG_GTX_HRX_N5: CV829.1 UV18.AG17
PEG_GTX_HRX_N6: CV831.1 UV18.AJ18
PEG_GTX_HRX_N7: CV833.1 UV18.AK19
PEG_GTX_HRX_N8: CV835.1 UV18.AJ20
PEG_GTX_HRX_N9: CV837.1 UV18.AG20
PEG_GTX_HRX_N10: CV839.1 UV18.AJ21
PEG_GTX_HRX_N11: CV841.1 UV18.AK22
PEG_GTX_HRX_N12: CV843.1 UV18.AJ23
PEG_GTX_HRX_N13: CV845.1 UV18.AG23
PEG_GTX_HRX_N14: CV847.1 UV18.AJ24
PEG_GTX_HRX_N15: CV849.1 UV18.AK25
PEG_GTX_HRX_P0: CV818.1 UV18.AK14
PEG_GTX_HRX_P1: CV820.1 UV18.AH14
PEG_GTX_HRX_P2: CV822.1 UV18.AK15
PEG_GTX_HRX_P3: CV824.1 UV18.AL16
PEG_GTX_HRX_P4: CV826.1 UV18.AK17
PEG_GTX_HRX_P5: CV828.1 UV18.AH17
PEG_GTX_HRX_P6: CV830.1 UV18.AK18
PEG_GTX_HRX_P7: CV832.1 UV18.AL19
PEG_GTX_HRX_P8: CV834.1 UV18.AK20
PEG_GTX_HRX_P9: CV836.1 UV18.AH20
PEG_GTX_HRX_P10: CV838.1 UV18.AK21
PEG_GTX_HRX_P11: CV840.1 UV18.AL22
PEG_GTX_HRX_P12: CV842.1 UV18.AK23
PEG_GTX_HRX_P13: CV844.1 UV18.AH23
PEG_GTX_HRX_P14: CV846.1 UV18.AK24
PEG_GTX_HRX_P15: CV848.1 UV18.AL25
PEG_HTX_C_GRX_N0: CH36.2 UV18.AM12
PEG_HTX_C_GRX_N1: CH34.2 UV18.AM14
PEG_HTX_C_GRX_N2: CH32.2 UV18.AP15
PEG_HTX_C_GRX_N3: CH30.2 UV18.AM15
PEG_HTX_C_GRX_N4: CH28.2 UV18.AM17
PEG_HTX_C_GRX_N5: CH26.2 UV18.AP18
PEG_HTX_C_GRX_N6: CH24.2 UV18.AM18
PEG_HTX_C_GRX_N7: CH22.2 UV18.AM20
PEG_HTX_C_GRX_N8: CH20.2 UV18.AP21
PEG_HTX_C_GRX_N9: CH18.2 UV18.AM21
PEG_HTX_C_GRX_N10: CH16.2 UV18.AM23
PEG_HTX_C_GRX_N11: CH14.2 UV18.AP24
PEG_HTX_C_GRX_N12: CH12.2 UV18.AM24
PEG_HTX_C_GRX_N13: CH10.2 UV18.AM26
PEG_HTX_C_GRX_N14: CH8.2 UV18.AP27
PEG_HTX_C_GRX_N15: CH6.2 UV18.AM27
PEG_HTX_C_GRX_P0: CH35.2 UV18.AN12
PEG_HTX_C_GRX_P1: CH33.2 UV18.AN14
PEG_HTX_C_GRX_P2: CH31.2 UV18.AP14
PEG_HTX_C_GRX_P3: CH29.2 UV18.AN15
PEG_HTX_C_GRX_P4: CH27.2 UV18.AN17
PEG_HTX_C_GRX_P5: CH25.2 UV18.AP17
PEG_HTX_C_GRX_P6: CH23.2 UV18.AN18
PEG_HTX_C_GRX_P7: CH21.2 UV18.AN20
PEG_HTX_C_GRX_P8: CH19.2 UV18.AP20
PEG_HTX_C_GRX_P9: CH17.2 UV18.AN21
PEG_HTX_C_GRX_P10: CH15.2 UV18.AN23
PEG_HTX_C_GRX_P11: CH13.2 UV18.AP23
PEG_HTX_C_GRX_P12: CH11.2 UV18.AN24
PEG_HTX_C_GRX_P13: CH9.2 UV18.AN26
PEG_HTX_C_GRX_P14: CH7.2 UV18.AP26
PEG_HTX_C_GRX_P15: CH5.2 UV18.AN27
PEG_HTX_GRX_N0: CH36.1 UH1.B10
PEG_HTX_GRX_N1: CH34.1 UH1.B11
PEG_HTX_GRX_N2: CH32.1 UH1.B12
PEG_HTX_GRX_N3: CH30.1 UH1.B13
PEG_HTX_GRX_N4: CH28.1 UH1.B14
PEG_HTX_GRX_N5: CH26.1 UH1.B15
PEG_HTX_GRX_N6: CH24.1 UH1.B16
PEG_HTX_GRX_N7: CH22.1 UH1.B17
PEG_HTX_GRX_N8: CH20.1 UH1.C18
PEG_HTX_GRX_N9: CH18.1 UH1.A19
PEG_HTX_GRX_N10: CH16.1 UH1.C20
PEG_HTX_GRX_N11: CH14.1 UH1.A21
PEG_HTX_GRX_N12: CH12.1 UH1.C22
PEG_HTX_GRX_N13: CH10.1 UH1.A23
PEG_HTX_GRX_N14: CH8.1 UH1.C24
PEG_HTX_GRX_N15: CH6.1 UH1.A25
PEG_HTX_GRX_P0: CH35.1 UH1.C10
PEG_HTX_GRX_P1: CH33.1 UH1.A11
PEG_HTX_GRX_P2: CH31.1 UH1.C12
PEG_HTX_GRX_P3: CH29.1 UH1.A13
PEG_HTX_GRX_P4: CH27.1 UH1.C14
PEG_HTX_GRX_P5: CH25.1 UH1.A15
PEG_HTX_GRX_P6: CH23.1 UH1.C16
PEG_HTX_GRX_P7: CH21.1 UH1.A17
PEG_HTX_GRX_P8: CH19.1 UH1.B18
PEG_HTX_GRX_P9: CH17.1 UH1.B19
PEG_HTX_GRX_P10: CH15.1 UH1.B20
PEG_HTX_GRX_P11: CH13.1 UH1.B21
PEG_HTX_GRX_P12: CH11.1 UH1.B22
PEG_HTX_GRX_P13: CH9.1 UH1.B23
PEG_HTX_GRX_P14: CH7.1 UH1.B24
PEG_HTX_GRX_P15: CH5.1 UH1.B25
PEG_RCOMP: RH24.2 UH1.G2
PEX_TERMP: RV578.2 UV18.AP29
PEX_TSTCLK_OUT: T4991.1(TP-1) UV18.AJ26
PEX_TSTCLK_OUT#: T4992.1(TP-1) UV18.AK26
PEX_VDD_EN: PR907.1 U33.20
PIN5_PD#: RI36.1 UI3.5
PJRSVD1: T4960.1(TP-1) UH2.AH14
PJRSVD2: T4959.1(TP-1) UH2.AH15
PJRSVD3: T4957.1(TP-1) UH2.N32
PJRSVD4: T4958.1(TP-1) UH2.R32
PJRSVD5: T4956.1(TP-1) UH2.U35
PJRSVD6: T4955.1(TP-1) UH2.U37
PJRSVD7: T4953.1(TP-1) UH2.Y14
PJRSVD8: T4954.1(TP-1) UH2.Y15
PLTRST_CPU#: RH480.1 UH1.BP35 UH2.AG5
PM_LANPHY_ENABLE: RH5842.1 UH2.BF41
PMRSVD1: T4961.1(TP-1) UH2.BC1
PMRSVD2: T4963.1(TP-1) UH2.Y35
PMRSVD3: T4962.1(TP-1) UH2.Y36
POWER_SW_IN#: CE30.1 RE34.2 RE36.1 RE110.1 UE3.D5
PP_HV: RT1092.2 UT4.A6 UT4.A7 UT4.A8 UT4.B7
PROC_DETECT#: RH519.1 UH2.AP41
PROC_DETECT#_R: RH519.2 RH1958.2 UH1.BR33
PROCHOT#_ISL88738: PQ224.1 PR1919.2 PU1900.23
PS8713_PD#: RI36.2 RI46.2
PS8713_PD#_R: QI10.1 RI46.1
PS_ID: PQ100.3 PR100.2 PR101.2 UE3.J6
PSID: ADP100.4 PR102.1
PSID-1: PQ101.2 PR103.2 PR105.1
PSID-2: PQ100.2 PQ101.1 PR104.1
PTP_DIS#: JTP.3 UE3.F4
PTP_INT#: DH1.1 QE13.1 RE138.1
PTP_INT#_R: JTP.4 QE13.3 RE87.2
PWM1_1PH/ICCMAX1: PR1123.1 PU1100.44 PU1701.1
PWM1_2PH/ICCMAX2: PR1158.1 PU1100.23 PU1700.1
PWM1_4PH/ICCMAX4: PR1161.1 PU1100.18 PU1200.1
PWM2_2PH/ROSC1: PR1165.1 PU1100.22
PWM2_4PH/ADDR: PR1162.1 PU1100.19 PU1201.1
PWM3_4PH/VBOOT: PR1163.1 PU1100.20 PU1251.1
PWM4_4PH/ROSCM: PR1164.1 PU1100.21 PU1252.1
PWM_FAN1: JFAN1.1 RE100.2 UE3.L10
PWM_FAN2: JFAN2.1 RE101.2 UE3.L11
PWR_BTN_DOCK1#: QV89.3 RT182.2 RT194.2
PWR_DEBUG#_XDP: JXDP.45 RH483.2 RH488.1
PWR_TB_DOCK#: RE110.2 RT195.2
PWR_VGA_CORE_BOOT1: PR706.2 PU700.1
PWR_VGA_CORE_BOOT1_1: PC708.2 PR706.1
PWR_VGA_CORE_LGATE1: PQ700.6 PR707.2 PU700.19
PWR_VGA_CORE_PHASE1: PC708.1 PL700.1 PQ700.7 PR702.1 PU700.20
PWR_VGA_CORE_SS: PC713.1 PU700.11
PWR_VGA_CORE_TON: PR704.1 PU700.9
PWR_VGA_CORE_TON_1: PC707.2 PR701.1 PR704.2
PWR_VGA_CORE_UGATE1: PQ700.1 PU700.2
PWRBTN#_XDP: CH174.1 JXDP.41 RH2.2 RH6.1
RC_ID0: T4982.1(TP-1) UE3.F2
REFADJ_NVVDD: PR1007.2 PU1001.6
REFADJ_NVVDDS: PR1507.2 PU1501.6
REFIN_NVVDD: PC1017.1 PR1006.1 PR1008.1 PU1001.7
REFIN_NVVDDS: PC1518.1 PR1508.1 PR1509.1 PU1501.7
REM_DIODE1_N: CE32.1 CE45.1 CE69.1 QE7.1 QE7.2 QE15.3 UE3.A8
REM_DIODE1_P: CE32.2 CE45.2 CE69.2 QE7.3 QE15.1 QE15.2 UE3.A7
REM_DIODE2_N: CE33.1 CE46.2 CE47.2 QE5.1 QE5.2 QE6.3 UE3.A10
REM_DIODE2_P: CE33.2 CE46.1 CE47.1 QE5.3 QE6.1 QE6.2 UE3.A9
REM_DIODE3_N: CE35.1 CE49.2 CE68.2 QE8.1 QE8.2 QE11.3 UE3.B9
REM_DIODE3_P: CE35.2 CE49.1 CE68.1 QE8.3 QE11.1 QE11.2 UE3.B8
REM_DIODE4_N: CE36.1 CE50.1 CE72.1 QE9.3 QE12.1 QE12.2 UE3.A11
REM_DIODE4_P: CE36.2 CE50.2 CE72.2 QE9.1 QE9.2 QE12.3 UE3.B10
RESET_IN#: RE145.2 RE311.2 UE3.C1
RING2: LA5.1 RA21.2 UA1.36
RING2_L: CA41.2 DA5.1 JHP1.3 LA5.2
ROM_CS: T205.1(TP-1) UV18.H6
ROM_SCLK: RV641.1 RV644.2 UV18.H4
ROM_SI: RV639.1 RV642.2 UV18.H5
ROM_SO: RV640.1 RV643.2 UV18.H7
RREF: RR6.2 UR1.9
RT8812_PVCC: PC706.1 PR700.1 PU700.18
RTCRST_ON: C4.1 D321.1 QR104.2 QRTC.2 R3.2 R277.1 RE143.2 UE3.F11
RTCRST_ON_R: C2.1 D321.2 QRTC1.2 R3.1
RTD3_CIO_PWR_EN: RT39.2 RT5842.2 RT5850.2 UH2.AP21
RTD3_CIO_PWR_EN_AR: RT5842.1 UT1.F1
RTD3_USB_PWR_EN: RT40.2 RT5841.2 UT1.D4
RUN_ON#: QE4.5 QE4.6 RE56.2
RUN_ON_EC: QE4.2 RE35.1 RZ43.2 RZ1956.1 UE3.E8 UZ1.3 UZ1.5 UZ6.1 UZ20.1 UZ33.3
RUN_ON_EC_GATE: RZ58.1 RZ59.2 UZ20.4
RUN_ON_P: PR610.2 PR803.1 RZ50.1 RZ58.2 UZ26.1
RUNPWROK: QE4.3 RE52.2 UE3.G3 UH14.2
S5_1.2V: PC613.1 PR606.2 PU600.8
SA_B+: PC1709.1 PC1710.1 PC1711.1 PC1712.1 PC1714.2 PL1703.2 PU1701.8 PU1701.9
SA_SW: PC1717.1 PL1704.1 PU1701.11 PU1701.12
SATA_PRX_C_DTX_N2: CS20.2 JHDD.8
SATA_PRX_C_DTX_P2: CS19.2 JHDD.9
SATA_PRX_DTX_N1A: JNGFF2.43 UH2.H42
SATA_PRX_DTX_N2: CS20.1 UH2.F44
SATA_PRX_DTX_P1A: JNGFF2.41 UH2.J41
SATA_PRX_DTX_P2: CS19.1 UH2.E45
SATA_PTX_C_DRX_N1A: CD37.2 JNGFF2.47
SATA_PTX_C_DRX_N2: CS18.2 JHDD.6
SATA_PTX_C_DRX_P1A: CD42.2 JNGFF2.49
SATA_PTX_C_DRX_P2: CS17.2 JHDD.5
SATA_PTX_DRX_N1A: CD37.1 UH2.D38
SATA_PTX_DRX_N2: CS18.1 UH2.B40
SATA_PTX_DRX_P1A: CD42.1 UH2.E37
SATA_PTX_DRX_P2: CS17.1 UH2.C40
SATAGP0: RH5844.1 RH5894.1 UH2.AH41
SATAGP3: RH5845.1 UH2.AN47
SATAGP4: RH5846.1 UH2.AM46
SATAGP5: RH5847.1 UH2.AM43
SATAGP6: RH5848.1 UH2.AM47
SATALED#: RH512.1 UH2.AK48
SBIOS_TX: RE297.2 UH2.BB24
SD_1P8_RCOMP: RH5832.1 UH2.BE5
SD_3P3_RCOMP: RH5833.1 UH2.BE4
SD_CD#: JCR.8 UR1.30
SD_CLK: CR8.1 JCR.6 RR4.2
SD_CLK_R: RR4.1 UR1.17
SD_CMD: JCR.3 RR5.2
SD_CMD_R: RR5.1 UR1.19
SD_D2: JCR.1 RR8.2
SD_D2_R: RR8.1 UR1.21
SD_D3: JCR.2 RR7.2
SD_D3_R: RR7.1 UR1.20
SD_LN0_M: JCR.14 UR1.25
SD_LN0_P: JCR.13 UR1.26
SD_LN1_M: JCR.17 UR1.23
SD_LN1_P: JCR.18 UR1.22
SD_RCLK_M: JCR.10 RR2.2
SD_RCLK_M_R: RR2.1 UR1.15
SD_RCLK_P: JCR.9 RR3.2
SD_RCLK_P_R: RR3.1 UR1.16
SD_REG2: CR16.1 UR1.24
SHD_CLK: R5831.1 UE3.J8
SHD_CLK_R1: R5831.2 T5999.1(TP-1)
SHD_IO0: T5997.1(TP-1) UE3.J7
SHD_IO1: T5998.1(TP-1) UE3.L6
SHD_IO3: T5996.1(TP-1) UE3.M6
SIO_EXT_SCI#: RE291.2 RH383.2 UH2.AU26
SIO_EXT_SCI#_R: RE291.1 UE3.M1
SIO_EXT_SMI#: RE285.1 UE3.K7
SIO_EXT_SMI#_R: RE285.2 RH110.1 UH2.BF18
SIO_EXT_WAKE#: RH523.2 UE3.M12 UH2.AU24
SIO_PWRBTN#: RH6.2 UE3.K11 UH2.BE46
SIO_RCIN#: RE286.2 RH518.1 UH2.BE39
SIO_SLP_A#: JAPS.6 RE290.1 RH1152.2 UH2.BE40
SIO_SLP_A#_R: RE290.2 UE3.M11
SIO_SLP_S0#: JAPS.15 RE125.1 RZ61.1 UH2.BC28
SIO_SLP_S0#_TPM: RE125.2 U32.29
SIO_SLP_S3#: JAPS.2 RE35.2 RT433.1 RZ59.1 RZ1150.2 UE3.K9 UH2.BF42 UZ20.2 UZ21.2 UZ31.2
SIO_SLP_S3#_AR: RT433.2 UT1.D2
SIO_SLP_S4#: JAPS.5 RE38.2 RZ81.1 RZ1151.2 RZ1954.1 UE3.N12 UH2.BE42 UZ22.2
SIO_SLP_S5#: JAPS.4 UE3.N8 UH2.BC42
SIO_SLP_SUS#: RE111.2 RH5871.2 RZ1133.1 RZ1952.1 UH2.BD39
SIO_SLP_SUS#_R: RE111.1 RE300.2 UE3.N4
SIO_SLP_WLAN#: QR105.1 RZ1149.2 UE3.D9 UH2.BD42
SIO_SLP_WLAN#_R: DN3.2 QR105.3 RZ1141.1
SLEEVE: LA8.1 RA19.2 RA20.2 UA1.37
SLEEVE_L: CA44.1 DA4.1 JHP1.4 LA8.2
SLP_WLAN#_GATE: QR105.2 RE275.1 RE305.2
SLP_WLAN#_GATE_R: RE305.1 RE306.1 UE3.K10
SM_PG_CTRL: PR608.1 RH525.2 UC1.4
SML0_SMBCLK: RH501.2 UH2.BF25
SML0_SMBDATA: RH502.2 UH2.BE24
SML0ALERT#: RH503.2 UH2.BF24
SML1_SMBCLK: RH460.2 UE3.D8 UH2.BF27
SML1_SMBDAT: RH461.2 UE3.E11 UH2.BE27
SML1ALERT#: RH504.2 UH2.BD33
SNB_1.8VSP: PC1604.1 PR1601.2
SNB_1V: PC504.1 PR502.2
SNB_1VSP: PC904.1 PR901.2
SNUB_1.2V: PC611.1 PR602.2
SNUB_1VS_VCCIO: PC805.1 PR801.2
SNUB_3V: PC414.1 PR413.2
SNUB_5V: PC417.1 PR414.2
SNUB_CHG1: PC1936.1 PR1915.2
SNUB_CHG2: PC1937.1 PR1916.2
SP7_SDWP: QR1.1 UR1.29
SP7_SDWP_C: JCR.11 QR1.3
SPK_DET#: JAUDIO.6 RE139.1 RH572.1 UH2.AV21
SPK_DET#_EC: RE139.2 UE3.N9
SPKR: RA7.1 RH82.2 UH2.AW29
SRCCLKREQ1#: RH549.2 RT5856.1 UH2.BE31
SRCCLKREQ2#: RH550.2 UH2.AR32
SRCCLKREQ8#: RP22.7 UH2.AE41
SRCCLKREQ9#: RP22.5 UH2.AF48
SRCCLKREQ10#: RP22.8 UH2.AC41
SRCCLKREQ11#: RP23.5 UH2.AC39
SRCCLKREQ12#: RP23.8 UH2.AE39
SRCCLKREQ13#: RP23.6 UH2.AB48
SRCCLKREQ14#: RP23.7 UH2.AC44
SRCCLKREQ15#: RP22.6 UH2.AC43
SSD_EN: RZ1956.2 UZ6.4 UZ32.3
SSD_PCIE_WAKE#: JNGFF2.54 RD8.1 RD59.1
SSD_SCP#: RD101.2 RE307.1 UE3.H5
SSD_SCP#_R: JNGFF2.8 RD101.1
SSD_SCP_PWR_EN: RZ1958.1 UE3.H8 UZ6.2
SSD_SUSCLK: JNGFF2.60 RD9.1
STRAP0: RV645.1 RV651.2 UV18.J2
STRAP1: RV646.1 RV652.2 UV18.J7
STRAP2: RV647.1 RV653.2 UV18.J6
STRAP3: RV648.1 RV654.2 UV18.J5
STRAP4: RV649.1 RV655.2 UV18.J3
STRAP5: RV650.1 RV656.2 UV18.J1
SUS_ON_EC: RE39.2 UE3.D2
SUS_ON_EC_P: DZ59.1 PR1801.1 Q5.2 RZ87.1 RZ91.1 RZ1954.2 RZ1966.1 UZ22.4 UZ23.1
SUS_ON_EC_R: RE30.1 RE38.1 RE39.1 UZ22.1
SUS_ON_EC_ST: CZ588.1 RZ91.2 UZ15.4 UZ23.4
SUSACK#: RH5872.1 UE3.K12
SUSACK#_R: RH5872.2 UH2.BE35
SUSCLK: RD9.2 RN1.2 UH2.BE45
SUSCLK_R: JNGFF1.42 RN1.1
SW1_2PH: PL1702.2 PR1151.2 PR1166.2
SW1_4PH: PL1202.2 PR1147.1 PR1159.1
SW2_4PH: PL1203.2 PR1150.1 PR1167.1
SW3_4PH: PL1251.2 PR1152.1 PR1169.1
SW4_4PH: PL1252.2 PR1155.1 PR1171.1
SW_1.2V: PC600.1 PL600.2 PQ600.1 PQ600.2 PQ600.3 PQ601.5 PR602.1 PU600.16
SW_1PH: PL1704.2 PR1101.2
SYS_PEX_RST_MON#: RV557.1 UV18.R8
SYS_PEX_RST_MON#_L: RV587.1 UV19.4
SYS_PWROK: RE33.2 RE303.2 RH91.2 RH490.1 UH2.AU3
SYS_PWROK_R: RE303.1 UE3.G4
SYS_RESET#: JAPS.13 RH8.2 RH571.1 UH2.AU2
TACH_FAN1: CE66.1 DE7.2 RE81.2 UE3.E3
TACH_FAN2: CE67.1 DE8.2 RE83.2 UE3.D1
TB_HDMI_HPLUG: RT1134.1 UT1.G1
TBT_BATLOW#: RT25.2 UT1.F2
TBT_CIO_PLUG_EVENT#: RH5889.1 RT23.2 UH2.BF8 UT1.W2
TBT_CONFIG: RT183.1 RT1093.2 UT4.H6
TBT_DDC_CLK: RT33.2 RT5848.2 UT1.Y2
TBT_DDC_DATA: RT34.2 RT5847.2 UT1.Y1
TBT_FORCE_PWR: RT38.2 RT5846.1 UH2.BE15
TBT_FORCE_PWR_R: RT5846.2 UT1.H4
TBT_I2C_CLK: RT36.2 RT5837.1 UT1.U2
TBT_I2C_CLK_R: RT5837.2 UT4.D2
TBT_I2C_DATA: RT35.2 RT5836.1 UT1.U1
TBT_I2C_DATA_R: RT5836.2 UT4.D1
TBT_JTAG_TCK: RT7.2 T198.1(TP-1) UT1.T4
TBT_JTAG_TDI: RT9.2 T196.1(TP-1) UT1.Y4
TBT_JTAG_TDO: RT6.2 T199.1(TP-1) UT1.W4
TBT_JTAG_TMS: RT8.2 T197.1(TP-1) UT1.V4
TBT_LSRX: RT45.2 RT232.1 UT1.A4 UT4.K4
TBT_LSTX: RT44.2 RT233.1 UT1.A5 UT4.L4
TBT_PCIE_RBIAS: RT1.1 UT1.N16
TBT_PCIE_WAKE#: RT22.2 RT5843.2 RT5849.2 RT5856.2 UT1.W1
TBT_POC_RST#: DT29.2 RT202.2 RT244.2 UT1.F4
TBT_PWR_EN: T5990.1(TP-1) UH2.T48
TBT_RBIAS: RT10.1 UT1.H6
TBT_RESET_N_EC: RT244.1 RT245.2 RZ41.1 UE3.L8
TBT_ROM_CLK: UT1.AB4 UT2.6
TBT_ROM_CS#: RT18.2 UT1.AC3 UT2.1
TBT_ROM_DI: UT1.AB3 UT2.5
TBT_ROM_DO: RT16.2 UT1.AC4 UT2.2
TBT_ROM_HOLD#: RT15.2 UT2.7
TBT_ROM_WP#: RT17.2 UT1.V1 UT2.3
TBT_RSENSE: RT10.2 UT1.J6
TBT_SRC_CFG1: RT107.2 UT1.AA1
TBT_SVR_IND: CT186.1 CT187.1 LT1.1 UT1.C1 UT1.C2 UT1.D1
TBT_TEST_EN: RT3.2 UT1.E1
TBT_TEST_PWRG: RT4.2 UT1.AB5
TBT_TMU_CLK_OUT: RT37.2 UT1.V2
TBT_USB2_D+: RT1141.1 UT1.E20
TBT_USB2_D-: RT1142.1 UT1.D20
TBT_USB3_RX0_N: DT21.1 JUSBC1.B10 RT5835.1
TBT_USB3_RX0_N_R: RT5835.2 UT1.A21
TBT_USB3_RX0_P: DT20.1 JUSBC1.B11 RT5834.1
TBT_USB3_RX0_P_R: RT5834.2 UT1.B21
TBT_USB3_RX1_N: DT18.1 JUSBC1.A10 RT5833.1
TBT_USB3_RX1_N_R: RT5833.2 UT1.B15
TBT_USB3_RX1_P: DT19.1 JUSBC1.A11 RT5832.1
TBT_USB3_RX1_P_R: RT5832.2 UT1.A15
TBT_USB3_TX0_N: CT40.2 DT13.1 JUSBC1.A3
TBT_USB3_TX0_N_C: CT40.1 UT1.B19
TBT_USB3_TX0_P: CT39.2 DT12.1 JUSBC1.A2
TBT_USB3_TX0_P_C: CT39.1 UT1.A19
TBT_USB3_TX1_N: CT38.2 DT26.1 JUSBC1.B3
TBT_USB3_TX1_N_C: CT38.1 UT1.B17
TBT_USB3_TX1_P: CT37.2 DT27.1 JUSBC1.B2
TBT_USB3_TX1_P_C: CT37.1 UT1.A17
TBTA_AUX_N: CT42.2 RT432.2 UT4.J2
TBTA_AUX_N_C: CT42.1 UT1.W15
TBTA_AUX_P: CT41.2 RT431.2 UT4.J1
TBTA_AUX_P_C: CT41.1 UT1.Y15
TBTA_BOT_C_N: DT23.1 JUSBC1.B7 LT13.3
TBTA_BOT_C_P: DT24.1 JUSBC1.B6 LT13.2
TBTA_BOT_N: LT13.4 UT4.L7
TBTA_BOT_P: LT13.1 UT4.K7
TBTA_CC1: CT160.1 DT14.1 JUSBC1.A5 UT4.K9 UT4.L9
TBTA_CC2: CT159.1 DT25.1 JUSBC1.B5 UT4.K10 UT4.L10
TBTA_DEBUG1: RT184.2 UT4.L2
TBTA_DEBUG2: RT185.2 UT4.K2
TBTA_DEBUG3_LSTX: RT187.2 RT233.2 UT4.L3
TBTA_DEBUG4_LSRX: RT188.2 RT232.2 UT4.K3
TBTA_HPD: RT43.2 RT181.2 UT1.M4
TBTA_HRESET: RT429.1 UT4.D6
TBTA_I2C_INT#: RT167.2 RT5838.1 UT1.J4
TBTA_I2C_INT#_R: RT5838.2 UT4.C1
TBTA_LDO_BMC: CT144.1 UT4.E1
TBTA_PD_SBU1: RT176.1 UT4.K8
TBTA_PD_SBU2: RT177.1 UT4.L8
TBTA_RESET_N: DT29.1 UT4.F11
TBTA_SBU1: DT17.1 JUSBC1.A8 RT176.2
TBTA_SBU2: DT22.1 JUSBC1.B8 RT177.2
TBTA_TOP_C_N: DT16.1 JUSBC1.A7 LT12.2
TBTA_TOP_C_P: DT15.1 JUSBC1.A6 LT12.3
TBTA_TOP_N: LT12.1 UT4.L6
TBTA_TOP_P: LT12.4 UT4.K6
TBTB_HPD: RT209.2 UT1.G2
TBTB_I2C_INT#: RT1145.2 UT1.E2
TBTB_LSRX: RT208.2 UT1.B5
TBTB_LSTX: RT207.2 UT1.B4
TESTMODE: RV592.1 UV18.AK11
THERMAL_ALERT#: RV553.1 UV18.M2
THERMATRIP_GPU#: RV594.1 RV1082.1 U33.3 UV18.M1
THERMATRIP_GPU#_R: QV91.3 RV1082.2
THERMDA: UT1.AB23 UT1.AC23
THERMTRIP1#: RE25.1 RV1083.2 U33.4 UE3.B12
THERMTRIP2#: CE52.1 QE10.1 RE66.2 UE3.H3
TOUCH_SCREEN_PD#: DI1.1 JTS1.6 RH510.1 UH2.AM45
TOUCHPAD_INTR#: DH1.2 RH547.1 UH2.BF32
TOUCHPAD_INTR#_EC: RE138.2 RP19.2 UE3.G2
TP_PWR_EN: RZ32.2 UE3.H9 UE6.3
TPM_PIRQ#: RE86.2 U32.18 UH2.BD29
TS_DETECT#: JTS1.7 RC5835.2 RH5849.1 UH2.AM48
TS_I2C_RST#: RR44.1 UH2.BE29
TSENSE_2PH: PC1131.1 PR1173.1 PU1100.25
TSENSE_4PH: PC1129.1 PR1172.1 PU1100.14
UART2_RXD: RH562.2 UH2.BD20
UART2_TXD: RH561.2 UH2.BE20
UG1_ISL88738: PQ1900.4 PQ1902.4 PU1900.11
UG2_ISL88738: PQ1901.4 PU1900.5
UG_3V: PQ400.4 PU400.10
UG_5V: PQ401.4 PU400.16
UPD1_ALERT#: RE99.1 UE3.F10 UT4.B6
UPD_SMBCLK: RE294.1 RT201.1 UE3.C3
UPD_SMBCLK_R: RT201.2 UT4.B5
UPD_SMBDAT: RE293.1 RT200.1 UE3.B4
UPD_SMBDAT_R: RT200.2 UT4.A5
USB2_COMP: RH109.1 UH2.F4
USB2_VBUSSENSE: RH580.1 UH2.F3
USB3_PRX_C_RD_DTX_N1: CI8.2 UI3.23
USB3_PRX_C_RD_DTX_P1: CI7.2 UI3.22
USB3_PRX_DTX_N1: CI8.1 UH2.D11
USB3_PRX_DTX_N2: DI7.1 DI7.9 JUSB1.5 UH2.B9
USB3_PRX_DTX_P1: CI7.1 UH2.C11
USB3_PRX_DTX_P2: DI7.2 DI7.8 JUSB1.6 UH2.C9
USB3_PRX_L_DTX_N1: DI9.1 DI9.9 JUSB2.5 RI40.2
USB3_PRX_L_DTX_P1: DI9.2 DI9.8 JUSB2.6 RI39.2
USB3_PRX_RD_DTX_N1: RI40.1 UI3.8
USB3_PRX_RD_DTX_P1: RI39.1 UI3.9
USB3_PTX_C_DRX_N1: CI16.2 RI37.1
USB3_PTX_C_DRX_N2: CI9.2 DI7.4 DI7.7 JUSB1.8
USB3_PTX_C_DRX_P1: CI20.2 RI38.1
USB3_PTX_C_DRX_P2: CI10.2 DI7.5 DI7.6 JUSB1.9
USB3_PTX_C_RD_DRX_N1: CI6.2 UI3.20
USB3_PTX_C_RD_DRX_P1: CI5.2 UI3.19
USB3_PTX_DRX_N1: CI6.1 UH2.F9
USB3_PTX_DRX_N2: CI9.1 UH2.C3
USB3_PTX_DRX_P1: CI5.1 UH2.F7
USB3_PTX_DRX_P2: CI10.1 UH2.D4
USB3_PTX_L_DRX_N1: DI9.4 DI9.7 JUSB2.8 RI37.2
USB3_PTX_L_DRX_P1: DI9.5 DI9.6 JUSB2.9 RI38.2
USB3_PTX_RD_DRX_N1: CI16.1 UI3.11
USB3_PTX_RD_DRX_P1: CI20.1 UI3.12
USB20_FP_N7_CONN: DI17.1 JFP.6 ML17.3
USB20_FP_P7_CONN: DI13.1 JFP.5 ML17.2
USB20_N1: UH2.J3 UI2.2
USB20_N2: UH2.N13 UI1.2
USB20_N4: LN1.1 UH2.M10
USB20_N4_R: JNGFF1.5 LN1.2
USB20_N5: RT1143.1 UH2.M1
USB20_N5_R: RT1142.2 RT1143.2 UT4.K5
USB20_N7: ML17.4 UH2.L4
USB20_N9: LI1.4 UH2.M6
USB20_N9_R: DI3.2 JTS.4 LI1.3
USB20_N12: LV22.1 UH2.G1
USB20_N12_R: DV12.3 JEDP1.31 LV22.2
USB20_P1: UH2.J2 UI2.3
USB20_P2: UH2.N15 UI1.3
USB20_P4: LN1.4 UH2.L9
USB20_P4_R: JNGFF1.3 LN1.3
USB20_P5: RT1144.1 UH2.L2
USB20_P5_R: RT1141.2 RT1144.2 UT4.L5
USB20_P7: ML17.1 UH2.L3
USB20_P9: LI1.1 UH2.N8
USB20_P9_R: DI3.3 JTS.5 LI1.2
USB20_P12: LV22.4 UH2.G2
USB20_P12_R: DV12.1 JEDP1.32 LV22.3
USB8723_TEST: RI24.1 UI3.14
USB_DET#_L: CE71.1 JUSB1.10 RE89.2
USB_DET#_R: CE37.1 JUSB2.10 QI10.2 RE54.2
USB_DET_EC#_L: CE70.1 RE89.1 RE90.2 UE3.E4
USB_DET_EC#_R: CE38.1 RE50.2 RE54.1 UE3.D4
USB_ILIM_SEL: DI12.1 RI35.1 UE3.M10
USB_L_CTL: RI4.2 UI1.7 UI1.8
USB_OC0#: RH552.1 UH2.AH36 UI2.13
USB_OC1#: RH553.1 UH2.AL40 UI1.13
USB_OC2#: RH554.1 UH2.AJ44
USB_OC3#: RH555.1 UH2.AL41
USB_OC4#: RP8.3 UH2.AV47
USB_OC5#: RP8.4 UH2.AR35
USB_OC6#: RP8.2 UH2.AR37
USB_OC7#: RP8.1 UH2.AV43
USB_POWERSHARE_EN_L#: RI5.2 UE3.J3 UI1.6
USB_POWERSHARE_EN_R#: RI10.2 UE3.K3 UI2.6
USB_POWERSHARE_VBUS_EN_L: RI8.2 UE3.J2 UI4.2
USB_POWERSHARE_VBUS_EN_R: RI13.2 RI28.1 UE3.G5 UI5.2
USB_PWR_EN: RH544.1 UH2.BD17 UI4.1 UI5.1
USB_PWR_EN_L: RI26.1 UI1.5 UI4.4
USB_PWR_EN_R: RI27.1 RI28.2 UI2.5 UI5.4
USB_R_CTL: RI9.2 UI2.7 UI2.8
USB_STATUS#_L: RI32.2 UI1.9
USB_STATUS#_R: RI33.2 UI2.9
USBC_MCP23008_SMBCLK: RE21.1 RE109.2 UE3.A12
USBC_MCP23008_SMBDAT: RE20.1 RE108.2 UE3.N10
VCORE_B+: PC1202.1 PC1203.1 PC1204.1 PC1205.1 PC1206.1 PC1207.1 PC1209.2 PC1211.1 PC1214.1 PC1222.2 PC1223.1 PC1224.1 PC1225.1 PC1226.1 PC1231.1 PC1232.1 PC1233.1 PC1234.1 PC1251.1 PC1252.1 PC1254.1 PC1256.1 PC1258.2 PC1262.1 PC1263.1 PC1264.1 PC1265.1 PC1269.2 PL1200.2 PL1201.2 PL1204.2 PR1154.1 PU1200.8 PU1200.9 PU1201.8 PU1201.9 PU1251.8 PU1251.9 PU1252.8 PU1252.9
VGA_EDID_CLK: RV572.1 UV18.R2
VGA_EDID_DATA: RV573.1 UV18.R3
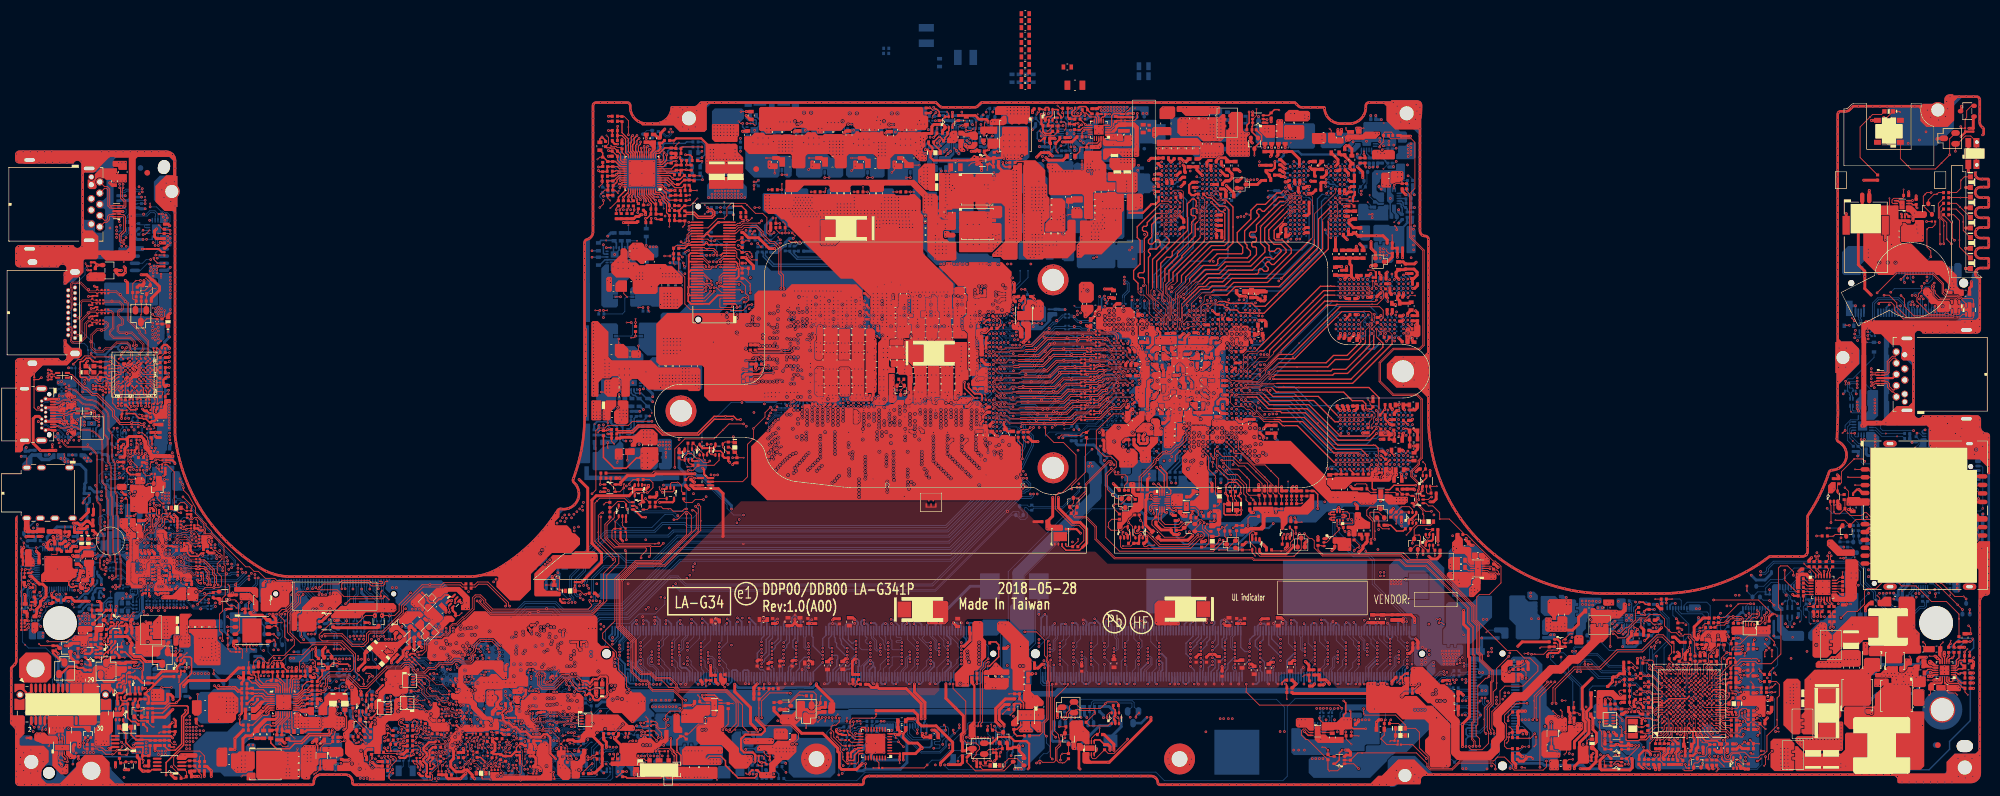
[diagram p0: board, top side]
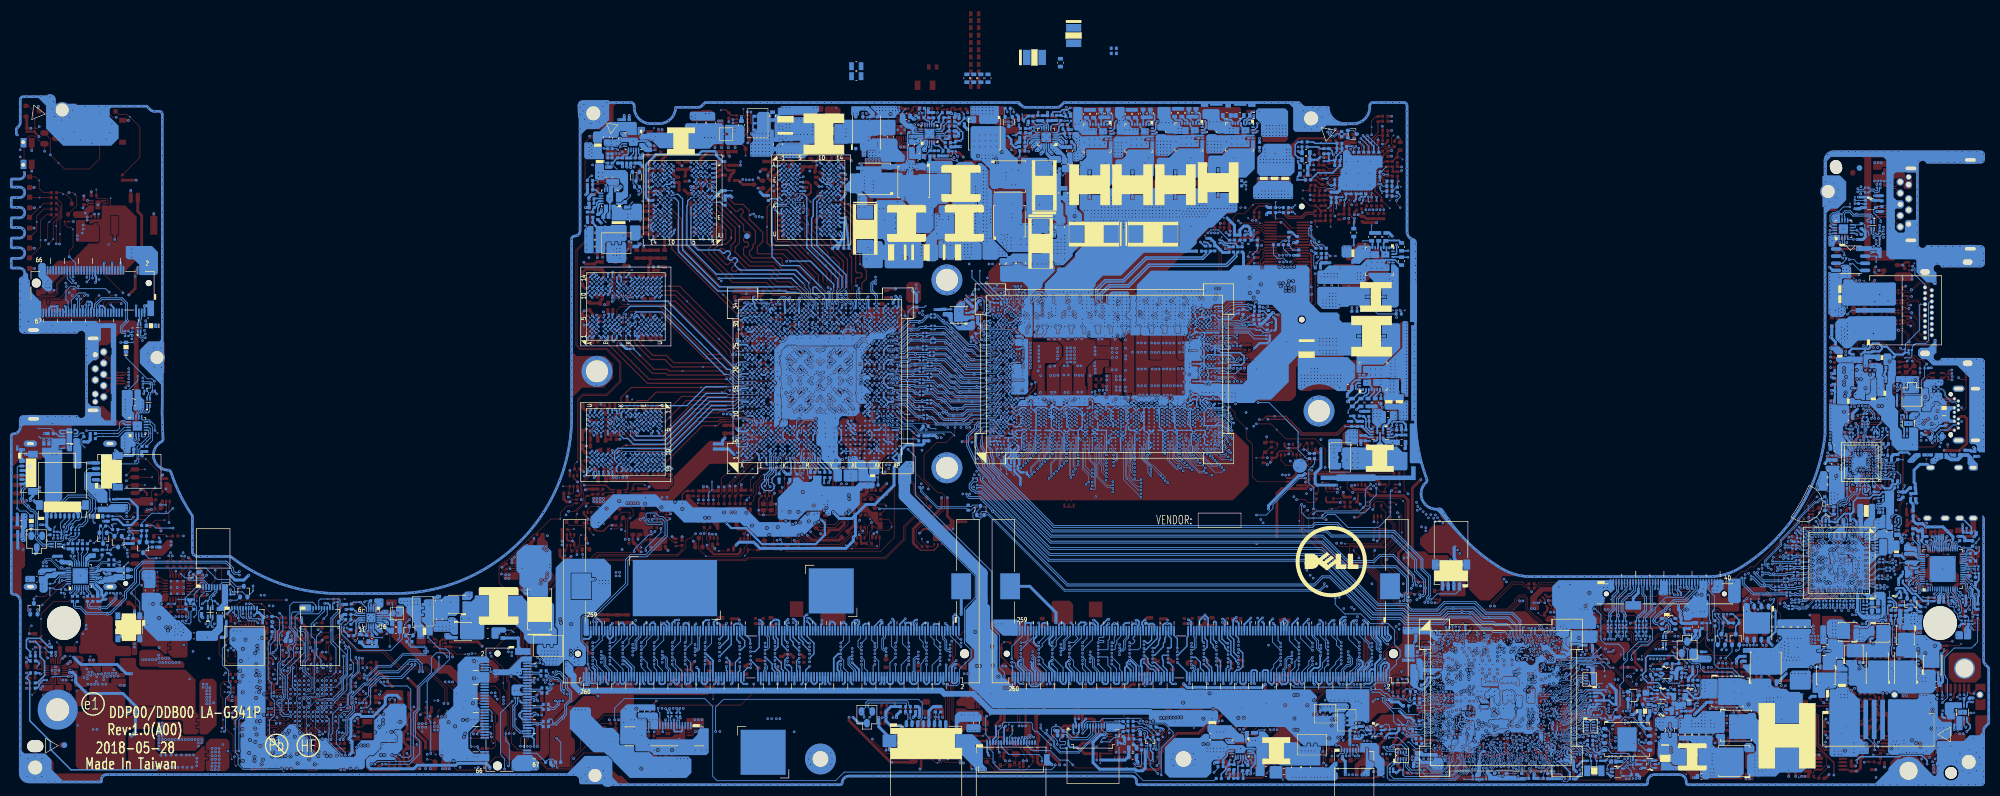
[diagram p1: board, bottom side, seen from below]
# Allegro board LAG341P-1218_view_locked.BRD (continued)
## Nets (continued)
VGA_IDENTIFY: RE112.1 UE3.L9
VID0_VCCIO: PR806.2 PR808.1 PU800.4
VID1_VCCIO: PR805.2 PR807.1 PU800.3
VR_ON: PR1125.2 RZ60.2 RZ71.1 RZ1955.1 UZ12.4
VR_SVID_ALERT#: PR1106.2 PR1118.2 RH152.2 RH153.1
VR_SVID_ALERT#_R: RH153.2 UH1.BH31
VR_SVID_CLK: PR1107.2 PR1116.2 UH1.BH32
VR_SVID_DATA: PR1105.1 PR1120.2 RH151.2 UH1.BH29
VRALERT#: RH5837.2 UH2.BE32
VREF_NVVDD: PC1005.1 PR1005.1 PU1001.8
VREF_NVVDDS: PC1501.1 PR1505.1 PU1501.8
VSET_5085: CE41.1 RE58.1 UE3.C9
VSN_1PH: PC1100.2 PR1109.2 PU1100.51
VSN_2PH: PC1114.1 PR1131.1 PU1100.37
VSN_4PH: PC1112.2 PR1127.2 PU1100.2
VSP_1PH: PC1108.2 PR1111.2 PU1100.52
VSP_2PH: PC1113.1 PR1130.1 PU1100.38
VSP_4PH: PC1111.2 PR1124.2 PU1100.1
WLAN_PWR_EN: DN3.1 RN33.2 RZ1141.2 RZ1142.2 UN3.3
WLAN_WIGIG60GHZ_DIS#: DN1.1 RE71.2 UE3.L13
WLAN_WIGIG60GHZ_DIS#_R: DN1.2 JNGFF1.48
XCLK_BIASREF: RH71.2 UH2.T3
XDP_BPM#0: JXDP.21 UH1.BR27
XDP_BPM#1: JXDP.23 UH1.BT27
XDP_DBRESET#: CH175.1 JXDP.48 RH5.2 RH8.1
XDP_PLTRST#: JXDP.46 RH479.2 RH480.2 RH492.2
XDP_PRDY#: JXDP.5 UH1.BP27 UH2.AM5
XDP_PREQ#: JXDP.3 RH156.2 UH1.BL30 UH2.AL2
XDP_PWRGOOD: CD3328.1 JXDP.39 RH481.2 RH482.2
XDP_TDI: JXDP.56 RH477.1 RH541.1
XDP_TDO: JXDP.52 RH478.1 RH540.1
XDP_TMS: JXDP.58 RH12.1 RH542.1
XDP_TRST#: JXDP.54 RH543.1
XTAL24_IN: RA96.2 UH2.U10
XTAL24_IN_R: CH47.1 RA96.1 RH72.1 YH2.1
XTAL24_OUT: RA97.2 UH2.U9
XTAL24_OUT_R: CH48.1 RA97.1 RH72.2 YH2.3
XTAL_25_IN: CT43.1 RA98.2 YT1.1
XTAL_25_IN_R: RA98.1 UT1.D22
XTAL_25_OUT: CT44.1 RA99.2 YT1.3
XTAL_25_OUT_R: RA99.1 UT1.D23
XTAL_OUT: CV858.1 RV1833.2 UV18.H2 YV1.3
XTALIN: CV857.1 RV1833.1 UV18.H3 YV1.1
XTALOUT: RV581.1 UV18.J4
XTALSSIN: RV579.1 UV18.H1
N01897: PC800.1 PC801.1 PC802.1 PC803.1 PL801.2 PU800.1
N02057: PC810.1 PR809.1 PR819.2 PU800.10
N02113: PR839.1 PR841.1 PU800.11
N02121: PR802.2 PR818.2 PU800.6
N02167: PR800.1 PU800.9
N02175: PC804.1 PR800.2
N02213: PC804.2 PL800.1 PR801.1 PU800.8
N02305: PR838.1 PR840.1 PU800.12
N04748: PC1935.1 PR1922.1 PU1900.3
N16357: CA20.1 UA1.29
N16361: CA21.1 UA1.31
N16389: CA15.1 UA1.25
N16393: CA18.1 UA1.27
N35186: DA14.1 RA29.1
N35194: DA7.1 RA28.1
N3514407: PR405.2 PU400.5
N3514423: PC400.1 PR400.2 PU400.3
N3514453: PC419.1 PU400.13
N16399093: PD1900.1 PD1902.1 PR1907.2
N16404606: PD1903.3 PR1936.1 PR1937.2
N16404788: PD1903.1 PR1943.2 PU1901.1
N17034077: PR406.1 PU400.1
N17034092: PC418.1 PR415.1 PU400.12
N17509431: PC1940.1 PR1927.2 PR1932.1 PR1933.1
N17509921: PD1903.2 PR1939.2
N17522701: PR1941.2 PU1901.2
N17670003: PR1929.1 PR1934.1 PU1900.30
N17765266: PR1926.2 PR1928.2 PU1900.26
N18278782: PC1913.1 PR1905.1
N18278998: PR1917.2 PU1900.22
N18290168: PR1927.1 PU1900.29
N19473413: PC1802.2 PR1803.2 PR1804.1 PU1800.4
N19473637: PC1802.1 PC1803.1 PR1803.1 PR1805.1 PU1800.1 PU1800.2 PU1800.3
N20816750: PR1701.1 PU1700.5
N20816752: PC1706.2 PU1700.7
N20816771: PC1706.1 PR1701.2
N20816775: PC1705.2 PR1700.2 PU1700.3
N20816793: PL1702.3 PR1702.1
N20816800: PC1708.2 PR1703.1
N20816821: PC1715.2 PU1701.7
N20816822: PR1705.1 PU1701.5
N20816832: PC1713.2 PR1704.2 PU1701.3
N20816859: PC1715.1 PR1705.2
N20816888: PC1717.2 PR1706.1
N20820556: PL1202.3 PR1202.1
N20820665: PL1203.3 PR1206.1
N20820729: PL1251.3 PR1253.1
N20820776: PL1252.3 PR1257.1
N26813293: RV639.2 RV640.2 RV641.2 RV1080.2
N27076067: PC1941.1 PR1930.2
N27182711: PC1121.1 PR1141.2
N27933518: PC1270.2 PU1252.7
N27933520: PR1256.1 PU1252.5
N27933540: PC1268.2 PR1255.2 PU1252.3
N27933602: PC1270.1 PR1256.2
N27933660: PC1272.2 PR1258.1
N28152235: PC1113.2 PC1114.2 PR1131.2 PR1132.1
N28152401: PC1130.2 PR1154.2 PU1100.15
N28152437: PC1120.2 PR1135.2 PU1100.3
N28152465: PC1122.1 PR1139.1 PU1100.36
N28152729: PC1103.1 PR1110.2 PR1111.1 PR1115.1
N28152747: PC1100.1 PC1103.2 PR1108.2 PR1109.1
N28152784: PC1132.1 PR1156.2 PU1100.16
N28152844: PH1104.1 PR1173.2 PR1176.1
N28152958: PH1102.2 PR1145.2 PR1149.1
N28153073: PH1100.2 PR1100.1
N28153459: PH1103.1 PR1172.2 PR1175.1
N28153589: PR1125.1 PU1100.43
N28153954: PC1117.1 PR1136.2
N28154016: PC1111.1 PC1112.1 PR1126.2 PR1127.1
N28154283: PH1101.2 PR1144.2 PR1148.1
N28180064: PC1109.1 PR1122.2
N28185893: PC1118.1 PR1138.2
N28185971: PC1116.1 PR1134.2
N31483113: PC725.1 PQ701.2 PR717.2
N31483116: PQ701.3 PR713.2
N31483118: PQ701.5 PQ701.6 PR715.2
N32073814: PC711.1 PR710.1 PU700.8
N32073817: PC712.1 PR710.2 PR712.1 PR713.1 PU700.7
N32074224: PC709.1 PR702.2
N32086652: PR711.1 PR718.1 PU700.12
N35924928: RV600.2 UV18.J27
N35928308: RV601.2 UV18.H27
N35950826: RV602.2 UV18.H25
N42077965: PC1210.2 PU1200.7
N42077969: PR1201.1 PU1200.5
N42077993: PC1208.2 PR1200.2 PU1200.3
N42078041: PC1228.2 PU1201.7
N42078055: PR1205.1 PU1201.5
N42078421: PC1210.1 PR1201.2
N42078543: PC1217.2 PR1203.1
N42078657: PC1228.1 PR1205.2
N42078671: PC1227.2 PR1204.2 PU1201.3
N42078715: PC1230.2 PR1207.1
N42079748: PR1252.1 PU1251.5
N42079752: PC1259.2 PU1251.7
N42079902: PC1259.1 PR1252.2
N42079910: PC1257.2 PR1251.2 PU1251.3
N42079960: PC1261.2 PR1254.1
N48708347: PC600.2 PR600.1
N48708367: PC614.1 PR608.2 PR610.1 PU600.7
N48708425: PR605.2 PU600.9
N49570918: PC506.2 PR504.2 PR507.1 PU500.14
N52218840: PR1146.2 PU1100.27
N52997531: PD100.1 PL104.1 PR102.2
N52999986: PL104.2 PQ100.1 PR100.1 PR103.1
N55155823: CV168.2 QV11.3 RV119.2 RV120.1
N55155843: QV12.1 RV120.2
N108873638: PR409.1 PU400.20
N109970739: PR410.1 PU400.19
N110703687: PC1024.1 PR1009.2
N116496514: PC1056.1 PR1020.2
N119328643: PC1934.1 PR1923.1 PR1924.2 PU1900.25
N119942216: ADP100.5 ADP100.6 ADP100.7 PC106.1 PL105.1 PL106.1
N121033373: PR408.2 PU400.6
N121033408: PR407.2 PR428.2 PU400.7
N121616283: CE65.1 UE6.6
N121617744: CZ37.1 UZ33.6
N121718437: DE7.1 JFAN1.3 RE82.2
N121718548: DE8.1 JFAN2.3 RE84.2
N122282431: RR9.1 UR1.28
N122463812: JXDP.1 RH474.1 RH475.1
N122528028: QF1.5 QF1.6 RF3.2
N122712620: JNGFF2.61 RD10.2 RD58.2
N122739099: RZ60.1 RZ86.1 UZ12.1 UZ21.4
N122739340: RZ61.2 UZ12.2
N123360127: RT12.1 UT1.H19
N123360144: RT5.1 UT1.Y18
N124211085: RT164.2 UT1.F19
N124494273: RT181.1 UT4.C10
N124494892: RT191.1 UT4.G2
N124539694: RT5844.1 UT4.G11
N124607348: QV89.1 RT195.1
N124730498: RT178.1 UT4.C2
N124730527: T185.1(TP-1) UT4.B2
N124752685: CH101.2 RH211.1
N124753277: CH100.2 RH212.1
N124754324: RT189.1 RT199.1 UT4.F10
N124755351: T193.1(TP-1) UT4.G4
N124755352: T194.1(TP-1) UT4.F4
N124817429: RH581.1 UH2.G3
N125173025: RT190.1 UT4.F1
N125742089: RH586.1 UH7.5
N125814346: CN22.1 UN3.6
N125960908: RZ81.2 UZ19.2
N126843005: LED6.2 RE3.2
N127291407: CZ31.1 UZ5.6
N128723349: PC1521.1 PR1512.2
N128725561: PC1054.1 PR1016.2 PR1018.2 PU1001.10
N128725563: PC1022.1 PR1010.2
N128725569: PC1047.2 PR1015.2
N128725595: PC1055.1 PR1022.1 PU1001.12
N128725605: PC1041.1 PR1013.1 PR1014.2
N128725802: PR1000.2 PR1001.1 PR1002.1 PU1001.4
N128726001: PC1018.1 PR1005.2 PR1006.2 PR1007.1
N128726023: PR1013.2 PU1001.9
N128726031: PC1030.1 PR1012.1 PU1001.18
N128726049: PR1008.2 PR1011.1
N128726112: PC1054.2 PR1021.2 PR1023.2 PU1001.11
N128727405: PC1519.1 PR1510.2
N128727409: PC1532.1 PR1519.1 PU1501.12
N128727430: PC1517.1 PR1505.2 PR1507.1 PR1508.2
N128727456: PR1509.2 PR1511.1
N128727528: PC1522.1 PR1514.2 PR1515.1
N128727776: PC1531.1 PR1516.2 PR1517.2 PU1501.10
N128727796: PC1531.2 PR1520.2 PR1521.2 PU1501.11
N128727911: PR1515.2 PU1501.9
N128727995: PC1520.1 PR1513.1 PU1501.18
N128735760: CA125.1 UA4.10
N128735764: CA124.1 UA4.12
N128958711: PC906.2 PR904.2 PR908.1 PU900.14
N128958713: PC906.1 PC907.1 PC908.1 PC909.1 PC910.1 PJP900.2 PL901.2 PR904.1
N128967490: BAT100.5 PR106.1
N128967591: BAT100.6 PR108.1
N128967644: BAT100.7 PR111.1
N130300854: CZ98.1 UZ24.6
N130500830: QV21.2 QV21.5 RV1131.1 RV1132.1
N130775721: RT430.2 UT4.E2 UT4.F2
N130798734: QV91.1 RV1083.1
N132000604: PC1929.2 PR1914.1
N132009758: PR1910.2 PR1931.2
N132009765: PR1910.3 PR1935.2
N132121209: CV925.1 RV621.2 RV622.2
N132122697: CV928.1 RV626.2 RV627.2
N132123770: CV987.1 RV628.2 RV629.2
N132124417: CV990.1 RV637.2 RV638.2
N132190190: PR1800.1 PR1851.1 PU1800.5
N132908405: QZ14.5 QZ14.6 QZ18.2 RV103.2
N132908425: QZ14.3 RV1808.2
N132908471: QZ15.5 QZ15.6 RV1809.2
N132908541: QZ17.5 QZ17.6 RV111.2
N132908575: QZ15.3 RV1810.2
N132908582: QZ18.1 RV112.2
N132908588: QZ17.3 RV1811.2
N132951149: QZ6.6 RV8.2
N132951151: QZ6.2 QZ6.3 RV12.2
N132951302: QV3.3 RV11.2
N132958139: RH5893.1 UV28.1
N132958145: CV918.1 RV1128.1 RV1807.2 UV28.4
N132961365: QV103.2 RV590.1
N134346262: QV98.2 RV1112.2
N134965433: CZ100.1 UZ25.6
N134966636: RM4.1 UM1.C6
N134966683: RM19.1 UM1.F2
N134967484: RM10.2 UM2.7
N135073509: T2.1(TP-1) UH2.AN40
N135670058: PR500.2 PR521.1 PU500.9
N135676145: PC911.1 PR903.2 PR906.1 PU900.11
N135676149: PR902.2 PR903.1 PR905.2 PR907.2
N135676155: PC905.1 PU900.16 PU900.17
N135689071: PR1603.2 PR1605.2
N135689238: PC1606.2 PR1605.1 PR1608.1 PU1600.14
N135689294: PC1611.1 PR1602.2 PR1604.1 PU1600.11
N135689304: PC1605.1 PU1600.16 PU1600.17
N135767612: PC202.2 PQ201.4 PQ202.1 PR201.2 PR205.1
N135767628: PQ202.2 PR200.2 PR204.1
N135767648: PQ203.6 PR204.2
N135767654: PQ204.1 PR205.2
N135767682: PQ203.3 PR206.2 PR210.2
N135767749: PQ204.2 PR213.1
N135767755: PC201.1 PQ200.4 PR202.2 PR209.1
N135767765: PQ205.1 PR209.2
N135767870: PR216.1 PU201.4
N135767884: PQ206.1 PR215.1 PR224.1
N135767963: PQ203.5 PR218.1
N135767967: PQ206.3 PR221.2 PR222.1
N135767977: PQ206.2 PR223.1
N135768200: PQ203.2 PR210.1
N135770596: PQ223.2 PQ223.3 PR274.1
N135770632: PQ220.4 PQ223.6 PR273.1 PR283.2
N135770638: PQ223.5 PR277.2 PR278.2 PR283.1
N135770664: PQ221.2 PR267.1 PR268.2
N135770666: PQ220.5 PR265.1 PR269.2
N135770716: PQ213.2 PR242.1
N135770748: PQ213.5 PR239.2
N135770768: PC206.1 PR207.1 PR211.2 PR219.1 PU200.3
N135770796: PC216.1 PD202.2 PR245.2 PR251.2 PR253.1 PU203.1
N135770798: PR242.2 PU202.4
N135770815: PC211.2 PQ208.4 PQ210.1 PR229.2 PR237.1
N135770837: PC217.1 PQ215.5 PR253.2
N135770888: PC210.1 PQ207.4 PR228.2 PR240.1
N135770896: PQ216.2 PR260.1 PR261.1 PR262.1
N135770915: PQ210.2 PR225.2 PR232.1
N135770919: PQ212.6 PR232.2
N135770992: PQ217.2 PR258.1
N135771010: PC214.1 PD202.1 PQ216.6 PR234.2 PR245.1 PR249.2 PR254.1 PU203.3
N135771120: PC212.2 PQ209.4 PQ211.1 PR230.2 PR235.1
N135771130: PQ217.1 PR252.1 PR259.2
N135771134: PQ217.3 PR256.2 PR257.1
N135771193: PQ215.2 PQ215.3 PR246.1
N135771203: PQ215.6 PR240.2
N135771219: PC215.1 PR244.2 PR255.1 PU203.2
N135771268: PC205.1 PR212.2 PR220.1 PU200.2
N135771321: PQ213.6 PR237.2
N135771386: PQ211.2 PR226.2 PR233.1
N135771412: PQ214.6 PR233.2
N135771419: PQ213.3 PR235.2
N135771459: PQ214.3 PR236.2 PR238.2
N135771494: PQ220.2 PR272.2
N135771851: PQ221.1 PQ227.6 PR279.1 PR285.2
N135772460: PQ227.2 PQ227.3 PR282.1
N135772468: PR250.2 PU202.1
N135772472: PQ214.2 PR238.1
N135772484: PQ214.5 PR243.1
N135772492: PR252.2 PU202.2
N135776099: PR214.2 PU201.1
N135776158: PR215.2 PU201.2
N135776395: PQ205.2 PR216.2
N135782958: PQ227.5 PR284.2
N135788915: PR1913.2 PU1900.21
N135795991: PR1900.3 PR1902.1
N135796052: PR1900.2 PR1901.1
N135896425: QRTC1.1 R276.2
N137529606: QE10.2 RE69.2
N137781553: D74.1 JTS1.5 RR43.2 RR44.2
N137787212: DI1.2 JTS.2
N137827497: T6004.1(TP-1) UE3.H2
N137853671: CZ104.1 UA3.6
N138188578: JEDP1.36 RV110.2
N138408347: T4948.1(TP-1) UE3.D6
N138608845: PR1643.2 PR1651.1 PU1600.9
N138923567: T6000.1(TP-1) UE3.F5
N139113922: T6002.1(TP-1) UH2.BD21
N139274499: PR1940.1 PU1901.4
N139308180: PR951.2 PR952.1 PU900.9
N139527854: CZ105.1 UZ29.6
N139871071: QH1.2 R5832.2 RH5868.2
N139871074: QE20.1 RH5868.1
N140262314: RZ1952.2 UZ29.3
N140286428: PC218.1 PQ222.2 PR263.1 PR288.1
N140286440: PQ219.3 PR263.2
N140286558: PQ225.2 PR295.1
N140286564: PC222.1 PQ225.1 PR276.2 PR280.1 PU204.4
N140286576: PC223.1 PR289.1 PU204.5
N140286584: PC218.2 PQ222.3 PQ226.3 PR266.1 PR275.2 PR288.2
N140286624: PC221.1 PQ219.2 PR271.2
N140286634: PQ219.5 PQ226.2 PR275.1 PR290.1
N140583188: QV91.2 RV1084.2 UV29.4
N140796616: T6003.1(TP-1) UE3.L2
N141287628: PQ219.6 PR290.2
N141348246: PC1601.1 PR1600.2
N142820714: JHDD.16 RD100.2
N143232395: CE48.1 RE62.2
N143234416: CZ2155.1 UZ30.6
N143234582: RZ1964.2 UZ30.3
N143441212: PC1108.1 PR1115.2
N143489306: Q5.5 Q5.6 R5842.2
N143489317: Q5.3 R5843.1
N143674886: RZ1953.2 UZ26.2
N144550342: RZ72.2 UZ16.4
N144805281: CZ39.1 UZ32.6
N146950564: PR819.1 PU800.13
N12449474450: T191.1(TP-1) UT4.B9
N12449474451: T192.1(TP-1) UT4.A9
N14929602318: PR1925.1 PU1900.27

Pads without a net: DV12 4 6; FD1 1; FD2 1; FD3 1; FD4 1; FD5 1; FD6 1; JAPS 16 17 18; JAUDIO 22 35 36 37 38; JDIMM1 87 88 91 92 95 97 100 101 104 105 134 162 165; JDIMM2 87 88 91 92 95 97 100 101 104 105 134 162 165; JEDP1 37; JHDD 1 2 3; JNGFF1 6 8 9 11 12 13 14 17 18 19 20 23 24 26 36 38 40 50 51 52 53 54 56 57 58 59 60 62 63 65; JNGFF2 6 10 20 22 24 26 28 30 32 34 36 40 42 44 46 48 56 58 59; PQ216 3 4 5; PU200 5 6 7; PU203 5 6 7; PU204 3; PU500 10 12; PU700 6 14 15 16 17; PU900 10 12; PU1200 6 13 17 19; PU1201 6 13 17 19; PU1251 6 13 17 19; PU1252 6 13 17 19; PU1501 14 15 16 17; PU1600 10 12; PU1700 6 13 17 19; PU1701 6 13 17 19; PU1900 13; RP19 3; SW1 2 3; SW_BOT 2 3; U32 2 3 4 5 6 7 9 10 11 12 13 14 15 25 26 28 30 31 32; U33 2 12 13 14 15 16; UA1 2 4 8 47 48 49 50; UC1 1; UE5 1; UE7 1; UH1 AD2 AD4 AE1 AE5 AE9 AE10 AE11 AF10 AJ10 AJ11 AK3 AL1 AL2 AL3 AM10 AM11 AT3 AT5 AT7 AT11 AW7 AW8 AW9 AW10 AW11 AY1 AY2 AY3 AY4 AY5 AY7 AY8 AY9 AY10 AY11 BA1 BA2 BA3 BA4 BA5 BN1; UH2 A25 AA1 AA45 AC6 AC7 AC9 AC11 AC14 AC15 AD47 AE9 AE11 AE14 AE15 AE43 AE44 AE48 AF47 AG45 AH9 AH10 AH46 AH47 AH48 AJ6 AJ7 AJ46 AL15 AL37 AL48 AM7 AN4 AN35 AN37 AN46 AP2 AP3 AP47 AR13 AR47 AR48 AT10 AT49 AV3 AV6 AV7 AV13 AV18 AV34 AW2 AW3 AW21 AW32 AY2 B10 B14 B15 B18 B19 B23 B24 B25 B26 B27 B38 B41 BA1 BA2 BA3 BA17 BA20 BA33 BB3 BB4 BB6 BC5 BD4 BD7 BD12 BD34 BD38 BE3 BE6 BE12 BE16 BE17 BE19 BE33 BE34 BF6 BF10 BF17 BF19 BF29 BF33 BF36 BG6 BG8 C10 C14 C15 C16 C17 C18 C19 C20 C21 C23 C24 C26 C27 C38 C39 C41 C45 C46 C47 D20 D21 D29 D39 D46 E5 E28 F6 F11 F14 F24 F26 F46 G4 G5 G12 G14 G24 G26 G45 G46 G47 G48 G49 H2 H3 H47 H48 J13 J15 J18 J21 J24 K3 K4 K6 K7 K13 K16 K18 K21 K29 L24 L26 L41 L47 L48 M26 M29 M40 N2 N3 N18 N47 N48 P9 P21 P24 P47 R10 R18 R21 R24 R44 R46 R47 T1 T2 T43 T45 T46 T47 U2 U3 U40 U41 U47 U48 V2 V3 V48 W43 W44 W46 W47 Y2 Y40 Y41 Y46 Y47 Y48; UH8 9; UM1 C5 D3 D7 F3 F7; UR1 31; UT1 A7 A9 A11 A13 A23 B7 B9 B11 B13 B23 D19 E18 E19 J1 J2 L1 L2 N1 N2 R1 R2 V18 W16 W19 Y16 Y19; UT4 E10 G10 L11; UT5 9; UV18 A9 A26 A27 A30 AB3 AB4 AB8 AC1 AC2 AC3 AC4 AC5 AC6 AC7 AC8 AC28 AC32 AD1 AD2 AD3 AD4 AD5 AD6 AE3 AE4 AF1 AF2 AF3 AF4 AF5 AF6 AF7 AF8 AF30 AF32 AG1 AG2 AG3 AG4 AG5 AG6 AG7 AG8 AG9 AG10 AH3 AH4 AH6 AH8 AH9 AH31 AJ1 AJ2 AJ3 AJ4 AJ5 AJ6 AJ8 AJ9 AJ11 AJ28 AJ31 AJ32 AJ33 AK1 AK2 AK3 AK4 AK5 AK6 AK8 AK9 AK31 AL3 AL4 AL6 AL7 AL8 AL9 AL10 AL11 AM1 AM2 AM3 AM4 AM5 AM6 AM7 AM8 AM9 AM34 AN2 AN3 AN5 AN6 AN8 AN9 AP3 AP5 AP6 AP8 AP9 B2 B6 B23 C6 C12 C15 C20 D6 D7 D9 D19 D20 D22 D23 D26 D28 E1 E4 E26 E34 F2 F26 G14 G20 H30 H31 J30 J31 J32 J33 K3 K4 M30 M34 R28 R32 V32; UV23 A5 U5; UV24 A5 U5; UV25 A5 U5; UV26 A5 U5; UZ8 3

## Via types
v1: diameter 0.305, hole 0.152, TOP to BOTTOM, 959 vias
v2: diameter 0.457, hole 0.203, TOP to BOTTOM, 9726 vias
v3: diameter 0.432, hole 0.178, TOP to BOTTOM, 42 vias
v4: diameter 0.406, hole 0.203, TOP to BOTTOM, 232 vias
v5: diameter 0.508, hole 0.254, TOP to BOTTOM, 160 vias
v6: diameter 0.432, hole 0.203, TOP to BOTTOM, 21 vias

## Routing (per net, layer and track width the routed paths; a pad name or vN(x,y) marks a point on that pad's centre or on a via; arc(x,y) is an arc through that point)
1.2V_B+: length 1.8
  BOTTOM w0.254: v2(290.86,95.09) 290.86,94.52 PR605.1
  vias: v2(274.89,99.8) v2(274.89,99.17) v2(275.53,99.8) v2(275.53,99.17) v4(271.86,99.59)
1.2V_DDR_EN: length 5.4
  TOP w0.14: CZ2156.1 v1(128.51,125.32) ; CZ2156.1 v2(126.54,125.32) ; CZ2156.1 127.3,125.91 DZ59.2 126.02,127.2 RZ1966.2
  BOTTOM w0.14: PR606.1 290.01,94.75 v2(290.28,95.02)
1.2V_FB: length 5.2
  TOP w0.14: PR604.1 v4(290.56,98.32)
  TOP w0.254: PR604.1 289.07,98.32 v2(288.72,97.96)
  BOTTOM w0.203: PR607.1 290.31,98.38 PC612.1 289.14,98.38 v2(288.72,97.96) 288.39,97.63 PU600.6
1.8V_PRIM_PWRGD: length 76.3
  TOP w0.14: PR1651.2 246.43,172.8 247.01,172.23 247.01,164.49 249.34,162.16 249.34,145.38 248.74,144.79 244.06,144.79 241.56,142.29 241.56,138.85 244.02,136.39 248.26,136.39 249,135.64 249,125.32 248.5,124.81 248.5,124.22 247.21,122.93 247.21,121.96 248.54,120.62 248.54,119.75 248.37,119.58 248.37,119.18 248.17,118.99 248.17,117.62 248.37,117.42 248.37,117.21 249.8,115.78 v2(250.88,115.78) ; v1(312.08,85.06) 311.54,84.52 v2(311.38,84.52) 311.2,84.35 RT5839.2
  BOTTOM w0.14: v2(133.86,69.03) 133.86,69.35 PR503.1
  vias: v2(308.23,99.32)
1.8V_PRIM_PWRGD_OK: length 3.5
  TOP w0.14: RT5840.1 RT5839.1 309.42,84.47 RT1139.1 308.1,85.03 v1(307.64,85.49)
1V8_AON_EN: length 11.3
  TOP w0.14: RZ1964.1 245.67,118.84 CV920.1 RV1350.1 246.82,118.81 247.11,118.52 UZ31.4 247.73,118.52 247.93,118.32 247.93,117.52 248.13,117.32 248.13,117.11 249.35,115.89 v1(249.35,115.33) 249.35,115.21 249.52,115.04 DA57.1 249.31,113.94 248.87,114.38 248.07,114.38 247.51,113.82 QV3.2
1V8_MAIN_EN: length 46.3
  TOP w0.14: v2(249.38,108.07) RZ106.1 249.38,109.06 248.69,109.75 248.08,109.75 247.32,108.99 DV16.2
  TOP w0.381: DA56.1 162.09,179.93 162.09,180.43 161.4,181.12 RV1130.2 ; DA56.1 161.76,178.73 162.29,178.2 v1(166.55,178.2) 168.29,178.2 RH5893.2 ; DA56.1 161.23,180.13 v2(160.83,180.13) ; v2(205.93,114.28) 205.76,114.11 RV562.1
  BOTTOM w0.254: UV18.P7 209,130.15 208.64,129.79 v2(208.64,129.76)
  BOTTOM w0.381: PR1004.2 160.83,180.96 v2(160.83,180.13) ; v2(222.73,113.61) 221.92,112.79 219.3,112.79 216.45,109.94 206.91,109.94 205.27,111.58 205.27,113.62 v2(205.93,114.28)
  vias: v2(181.57,149.17) v2(191.97,127.38)
1V8_MAIN_RUN_EN: length 13.5
  TOP w0.14: 247.8,111.33 248.02,111.55 v1(248.7,111.55) 248.92,111.33 248.92,109.97 249.62,109.28 249.67,109.28 250.22,108.73 RZ106.2 250.51,108.95 QZ17.2 ; 247.8,111.33 247.8,112.59 248.5,113.29 250.73,113.29 251.22,113.78 DA57.2 ; 247.8,111.33 DV16.1 247.47,110.56 v2(247.47,110.1)
  TOP w0.254: UZ24.3 205.83,116.37 205.79,116.41 v2(204.99,116.41)
1VS_GFX_PG: length 104.9
  TOP w0.14: PR952.2 243.25,182.45 243.63,182.07 247.28,182.07 247.93,181.42 247.93,173.22 247.25,172.54 247.25,164.59 249.58,162.26 249.58,145.28 248.84,144.54 244.16,144.54 241.8,142.19 241.8,138.95 244.12,136.63 248.36,136.63 249.24,135.74 249.24,125.22 248.74,124.71 248.74,124.12 247.45,122.83 247.45,122.06 248.78,120.72 248.78,119.65 248.61,119.48 248.61,118.43 248.61,118.43 v2(248.61,117.86) ; v2(209.73,113.78) 209.73,113.56 208.77,112.6 DV13.2 210.03,112.21 210.44,111.8 210.44,111.24 210.03,110.84 209.66,110.84 207.98,109.16 v1(200.46,109.16) 195.87,109.16 195.54,109.49 UV20.1
3.3V_CAM_EN#: length 11.1
  BOTTOM w0.089: UH2.BE41 77.17,72.41 76.97,72.2 76.97,71.17 76.92,71.12 76.92,71.12 76.38,70.58 76.38,70.12 76.7,69.8 RZ38.1
  BOTTOM w0.14: v2(51.89,88.77) 52.83,89.71 QZ9.2 54.24,90.54 v1(54.38,90.68) ; v2(73.58,68.23) 74.41,69.06 76.19,69.06 76.26,69.12 RZ38.1
3.3V_MSATA_EN: length 4.5
  TOP w0.089: v1(96.95,74.11) 97.21,73.86 RH423.1 97.69,73.04 98.35,72.38 98.35,72.15 v2(98.75,71.76)
  BOTTOM w0.089: v2(88.13,71.42) 88.06,71.49 88.06,72.07 UH2.BE18
3V/5VALW_EN: length 14.2
  TOP w0.14: v2(346.7,92.6) 346.91,92.6 347.15,92.84 v4(347.15,93.11)
  TOP w0.254: v2(346.7,92.6) PC335.1 345.78,92.58 PR326.2 344.32,92.58 343.84,92.09 PR408.1
  BOTTOM w0.254: v2(346.7,92.6) 345.74,92.6 344.92,91.78 344.92,89.92 344.09,89.1 344.09,86.59 345.44,85.25 PR409.2
5VS_FAN1: length 5.6
  TOP w0.127: v4(93.34,102.66) RE104.2
  TOP w0.508: v2(94.44,104.18) 94.44,103.85 94.79,103.5 RE104.2
  BOTTOM w0.508: JFAN1.2 93.36,103.6 93.95,104.18 v2(94.44,104.18)
5VS_FAN2:
  vias: v4(335.11,118.76)
+0.6VS: length 49.1
  TOP w1.524: 254.14,79.37 255.13,78.38 255.13,72.92 255.74,72.3 261.19,72.3 262.25,73.37 262.25,74.77 263.14,75.66 263.14,77.53 262.62,78.06 262.62,79.7 265.73,82.82 267.33,82.82 272.17,87.66 273.82,87.66 275.61,89.45 276.81,89.45 280.32,92.96
  BOTTOM w0.305: v2(171.48,85.07) 171.48,85.31 171.39,85.39 JDIMM1.258 ; v2(247.34,84.99) 247.34,85.12 247.41,85.2 247.69,85.47 JDIMM2.258 247.69,87.7 v2(247.79,87.8)
  vias: v2(172.74,84.39) v2(173.33,84.39) v2(247.95,84.98) v4(248.92,83.33)
+0.6VSP: length 0.9
  BOTTOM w0.203: PU600.2 285.63,98.92 v2(285.39,99.15)
  vias: v2(283.17,98) v2(283.77,98) v4(283.82,97.35)
+0.95VS_VCCIOP: length 12.3
  TOP w0.254: PR840.2 103.56,125.37 105.46,123.46 107.62,123.46 109.42,125.27 v2(110.44,125.27)
  vias: v2(110.44,126.1) v2(110.44,124.43) v2(110.44,123.59) v2(111.4,126.1) v2(111.4,125.27) v2(111.4,124.43) v2(111.4,123.59) v4(112.4,124.86)
+1.2V_DDR: length 123.2
  TOP w0.381: UC1.5 119.16,120.4 CH197.1
  TOP w0.508: RH530.2 180.14,113.94 ; v2(266.24,91.78) 267.02,92.55 R5843.2 ; CH197.1 119.7,119.82 123.98,119.82 124.85,118.95 124.85,111.35 124.79,111.3
  BOTTOM w0.305: JDIMM1.124 v2(135.89,85.09) ; v2(147.31,85.07) 146.89,85.49 JDIMM1.160 ; JDIMM1.118 v2(134.39,85.09) ; v2(184.1,85.05) 184.19,85.14 JDIMM2.12 ; v2(209.41,85.04) 209.19,85.27 JDIMM2.112 ; v2(123.47,95.88) 123.64,95.71 JDIMM1.75 ; v2(133.11,85.09) 132.89,85.31 JDIMM1.112 ; JDIMM1.33 113.14,95.57 113.21,95.64 113.21,96.12 112.95,96.38 v2(112.68,96.38) ; JDIMM1.147 143.64,95.65 143.8,95.81 v2(144.32,95.81) 144.84,95.81 145.14,95.51 JDIMM1.153 ; v2(222.78,95.83) 222.94,95.68 JDIMM2.159 ; JDIMM2.147 219.94,95.39 220.35,95.8 v2(220.48,95.8) 221.16,95.8 221.44,95.51 JDIMM2.153 ; JDIMM2.160 223.19,85.37 223.5,85.05 v2(223.6,85.05) ; v2(148.26,95.84) 148.31,95.84 148.31,95.86 148.31,95.86 147.92,95.86 147.64,95.57 ; v2(208.43,97.38) 208.58,97.38 208.94,97.02 JDIMM2.111 ; 147.64,95.57 147.42,95.8 146.89,95.8 146.64,95.55 JDIMM1.159 ; 147.64,95.57 JDIMM1.163 ; JDIMM1.220 161.89,85.43 161.64,85.18 v2(161.64,85.09) ; v2(145.6,85.09) 145.39,85.3 JDIMM1.154 ; JDIMM2.96 205.2,85.07 v2(205.22,85.05) ; JDIMM1.135 138.64,96.35 v2(137.64,97.34) 137.08,96.79 137.08,95.63 137.14,95.58 JDIMM1.129 ; v2(138.9,87.62) 138.89,87.61 JDIMM1.136 ; v2(233.36,96.16) 232.94,95.74 JDIMM2.199 ; v2(238.11,85.05) 238.11,85.12 238.19,85.2 JDIMM2.220 ; v2(221.92,85.05) 221.69,85.29 JDIMM2.154 ; JDIMM1.123 135.64,95.94 v2(135.84,96.14) ; v2(151.61,85.08) 151.39,85.31 JDIMM1.178 ; JDIMM2.241 243.44,95.49 v2(243.05,95.87) ; v2(137.16,85.09) 137.39,85.32 JDIMM1.130 ; JDIMM1.54 118.37,86.32 118.37,85.17 v2(118.17,84.97) ; v2(224.45,95.84) 224.1,95.84 223.94,95.68 JDIMM2.163 ; JDIMM1.141 140.14,95.55 140.07,95.62 140.07,96.07 140.48,96.49 v2(140.62,96.49) ; JDIMM2.124 212.19,85.06 v2(212.2,85.05) ; v2(142.88,85.09) 142.91,85.06 143.47,85.06 143.89,85.48 JDIMM1.148 ; v2(109.38,84.98) 109.23,85.13 108.27,85.13 107.89,85.51 JDIMM1.12 ; v2(213.69,85.05) JDIMM2.130 ; JDIMM2.129 213.44,95.58 213.38,95.63 213.38,96.25 213.62,96.49 v2(214.05,96.49) 214.3,96.49 214.94,95.85 JDIMM2.135 ; v2(199.73,95.9) 199.94,95.69 JDIMM2.75 ; v2(228.08,87.99) 227.69,87.6 JDIMM2.178 ; JDIMM2.33 189.44,95.49 189.51,95.56 189.51,96.12 189.17,96.45 v2(188.92,96.45) ; v2(128.81,85.11) 128.89,85.18 JDIMM1.96 ; JDIMM2.117 210.44,95.51 210.32,95.63 210.32,96.17 210.74,96.6 v2(210.92,96.6) ; v2(216.58,85.05) 216.69,85.16 JDIMM2.142 ; v2(167.24,95.94) 167.14,95.83 JDIMM1.241 ; v2(215.19,85.05) 215.19,86.34 ; JDIMM2.118 210.69,86.34 210.69,85.06 v2(210.7,85.05) ; v2(134.54,96.63) 134.37,96.63 134.02,96.28 134.02,95.63 134.15,95.49 134.15,94.56 JDIMM1.117 ; v2(132.05,96.9) 132.16,96.9 132.64,96.42 JDIMM1.111 ; JDIMM2.141 216.44,95.55 216.37,95.62 216.37,96.06 216.73,96.42 v2(216.92,96.42) ; JDIMM1.199 156.65,95.77 157.31,96.43 v2(157.48,96.43) ; JDIMM2.123 211.94,95.41 212.29,95.75 212.29,96.14 211.87,96.56 v2(211.82,96.56) ; JDIMM2.148 220.19,85.48 219.76,85.05 v2(219.12,85.05) ; JDIMM2.54 194.69,85.11 v2(194.74,85.05) ; JDIMM1.142 v2(140.39,85.07)
  vias: v2(10.82,133.1) v2(11.25,139.1) v2(11.25,132.66) v2(26.38,129.7) v2(26.38,129.11) v2(26.42,128.5) v2(35.29,108.81) v2(93.19,106.36) v2(93.59,106.78) v2(94.01,107.17) v2(107.94,102.88) v2(110.53,97.03) v2(243.7,103.46) v2(243.7,102.89) v2(244.27,103.46) v2(244.27,102.89) v2(244.84,103.46) v2(244.84,102.89) v2(245.41,103.46) v2(245.41,102.89) v2(249.15,89.24) v2(249.14,88.56) v2(249.29,91.59) v2(249.81,88.91) v2(249.86,91.27) v2(249.82,89.58) v2(252.83,90.92) v2(252.83,90.34) v2(252.96,89.76) v2(253.09,89.17) v2(253.09,88.59) v2(253.42,90.92) v2(253.42,90.34) v2(253.54,89.76) v2(253.67,89.17) v2(253.67,88.59) v2(254,90.92) v2(254,90.34) v2(254.13,89.76) v2(254.25,89.17) v2(254.25,88.59) v2(254.58,90.92) v2(254.58,90.34) v2(254.71,89.76) v2(254.84,89.17) v2(254.84,88.59) v2(255.17,90.92) v2(255.17,90.34) v2(255.3,89.76) v2(255.75,90.92) v2(255.75,90.34) v4(128.45,109.97)
+1.2V_DDR_PG: length 10.3
  TOP w0.14: v2(122.48,124.73) 122.19,124.44 121.37,124.44 120.57,125.24 120.07,125.24 119.25,126.05 118.59,126.05 ; 118.59,126.05 118.02,125.48 UZ19.1 117.38,124.93 RZ84.2 ; 118.59,126.05 RZ82.1
  TOP w0.254: PR651.1 289.51,93.43 288.87,92.79 v2(288.79,92.79)
  vias: v2(175.41,88.35)
+1.2V_DTH:
  vias: v4(11.81,127.64)
+1.2V_MEN_P: length 5.3
  TOP w0.254: PR604.2 288.95,99.23 288.57,99.61 v2(287.91,99.61)
  BOTTOM w0.203: PU600.5 286.83,98.58 287.86,99.61 v2(287.91,99.61) 289.17,99.61 PC612.2
  vias: v2(256.59,93.81) v2(260.08,96.54) v2(260.72,96.54) v2(280.49,98.63) v2(281.28,98.62)
+1.2V_PWROK: length 4.2
  TOP w0.127: v2(288.15,95.2) v4(288.15,96.4)
  TOP w0.508: v2(288.15,95.2) 288.65,94.71 PR609.2 288.65,94.13 288.59,94.07 288.59,93.74
  BOTTOM w0.203: v2(288.15,95.2) 288.15,95.84 287.96,96.03 PU600.10
+1.2V_VCCPLL_OC: length 8.7
  TOP w0.381: CH3332.1 171.11,132.7 v2(171.62,133.21) ; v2(140.72,134.44) 140.72,134.82 140.73,134.83 CH3333.1
  TOP w0.508: v2(171.62,133.21) 171.83,133.42 CZ49.1 ; RH530.1 183.49,114.93 v2(183.49,118.22)
  BOTTOM w0.203: v2(140.72,134.44) 140.59,134.44 UH1.BH13
  BOTTOM w0.229: v2(171.62,133.21) 171.94,133.54 UH1.G11
  BOTTOM w0.254: UH1.BH13 140.08,134.74 UH1.BJ13
  vias: v4(182.46,112.67)
+1.8V_3.3V_ALW_VTR3: length 6
  TOP w0.14: RZ1148.2 275.32,71.65 v4(276.02,71.65)
  TOP w0.305: UE3.N5 301.57,80.45 303.21,80.45 303.55,80.11 C3319.1 304.29,80.06 304.29,79.75 v2(304.48,79.55)
  TOP w0.508: RE183.2 303.52,72.95 v2(303.43,72.87)
  vias: v2(275.44,69.99)
+1.8V_GFX_AON: length 20.4
  TOP w0.254: v2(243.14,113.3) 243.64,113.3 244.65,112.29 245.85,112.29 RV11.1
  TOP w0.381: v2(226.24,109.77) 226.24,109.37 225.02,108.15 220.7,108.15 220.28,108.56 UV29.5 ; UV28.5 171.25,179.65 CV917.1 v2(172.11,180.1)
  TOP w0.508: v2(204.62,115.33) 204.93,115.03 RV562.2 ; v2(180.64,178.8) 181.44,179.6 182.82,179.6 v2(183.4,179.02) ; RV1112.1 v2(243.14,113.3)
  BOTTOM w0.457: PR1000.1 161.91,183.7 v2(161.33,183.7)
  BOTTOM w0.508: PR1500.1 v2(183.4,179.02)
  vias: v2(197.66,120.67) v2(198.75,177.35) v2(204.8,117.58) v2(204.8,117.01) v2(205.41,117.01) v2(205.79,118.57) v2(212.12,131.89) v2(212.7,131.82) v2(212.77,128.12) v2(212.9,115.83) v2(213.63,128.12) v2(221.23,115.6) v2(221.91,115.59) v2(233.37,118.25) v2(234.23,118.24) v2(238.49,117.23) v2(239.13,117.23) v2(239.76,117.23) v2(240.4,117.23) v2(244.11,177.11) v2(251.32,115.14) v4(237.19,118.22)
+1.8V_GFX_RUN: length 4.5
  TOP w0.508: v2(250.42,107.78) 250.88,107.32 251.87,107.32 252.4,107.85 RV1811.1
  BOTTOM w0.254: UV18.L8 211.5,130.98 v2(211.1,130.58) 211.1,130.6 UV18.M8
  vias: v2(189.01,156.08) v2(189.01,155.44) v2(196.27,124.61) v2(196.9,124.61) v2(196.9,124.02) v2(197.47,124.03) v2(207.95,123.79) v2(208.36,124.22) v2(209.27,122.52) v2(209.7,123.79) v4(188.62,154.83)
+1.8V_GFX_RUN_R:
  vias: v1(196.48,147.76) v2(192.84,148.16) v2(193.58,148.18) v2(197.7,145.67) v2(198.6,144.99) v2(198.73,143.95) v2(198.8,137.59) v2(198.8,136.96) v2(198.74,135.72) v2(198.95,144.51) v2(199.35,140.7) v2(199.35,139.36) v2(199.5,136.8)
+1.8V_PCH: length 16.9
  TOP w0.14: v2(111.7,107.7) 111.94,107.94 111.94,109.37 111.78,109.52 105.68,109.52 104.19,111.02 104.19,113.34 105.47,114.62 105.47,115.53 106.28,116.35 UZ26.5
  vias: v2(90.15,77.69) v2(91.27,77.63) v2(99.17,80.79) v2(99.76,80.79) v2(117.72,79.64) v2(118.29,79.64) v4(96.02,81.23)
+1.8V_PCH_I_LDO: length 3
  TOP w0.089: v1(86.4,82.57) 86.96,82.01 87.31,82.01 87.49,81.83 87.49,81.6 RE321.1
  TOP w0.356: v2(88.59,81.01) 88.52,81.07 RE321.1
+1.8V_PCH_LDO:
  vias: v1(87.67,82.76) v2(87.74,82.21) v2(88.61,82.62)
+1.8V_PLLVDD: length 0.9
  TOP w0.508: v2(210.38,149.05) 210.48,148.95 RV574.2
  vias: v2(187.88,151.4) v2(187.88,150.77) v2(188.46,151.08) v2(199.53,124.73) v2(200.14,125.37) v2(200.13,124.73) v2(200.71,124.73) v4(199.58,126.56)
+1.8VALW: length 5.4
  BOTTOM w0.508: v2(109.46,77.62) 109.58,77.5 110.43,77.5 110.65,77.28 111.5,77.28 111.86,76.92 v2(111.86,74.17)
  vias: v2(3.1,77.4) v2(27.22,74.73) v2(45.87,89.68) v2(73.34,85.99) v2(129.26,72.1) v2(129.24,71.04) v2(129.51,71.57) v2(129.87,72.18) v2(229.67,71.77) v2(230.3,71.77) v2(230.94,71.77) v2(231.57,71.77) v2(241.73,162.55) v2(241.76,161.98) v2(241.76,161.39) v2(241.76,160.81) v2(242.34,162.49) v2(242.34,161.9) v2(242.34,161.32) v2(242.92,161.32) v2(244.67,118.08) v2(244.67,117.51) v2(245.24,118.07) v2(245.24,117.5) v2(245.82,118.05) v2(245.82,117.48) v2(246.41,118.05) v2(246.41,117.48) v2(247.93,80.46) v2(248.51,80.46) v2(249.09,80.46) v2(249.68,80.46) v2(272.08,69.97) v2(272.72,70) v2(273.32,69.96) v4(272.08,71.27)
+1.8VS_AUDIO: length 1.1
  TOP w0.508: RA2.1 1.03,97.55 v2(1.03,96.94)
  vias: v1(5.23,80.54) v2(4.55,79.92)
+1.25V_DPHY_MAR: length 19.9
  TOP w0.381: v2(85.43,79.88) 86.21,80.66 v2(86.21,80.67) 86.21,81.09 86.13,81.16 RH5879.2 ; v2(85.43,79.88) 85.5,79.81 85.5,79.65 85.67,79.47 T5004.1 85.67,78.91 85.72,78.86 85.72,78.68 86.23,78.17 86.7,78.17 87.47,77.4 88.01,77.4 88.82,76.59 89.78,76.59 90.7,75.66 92.49,75.66 92.94,76.1 93.54,76.1 94.11,75.53 94.11,72.71 v2(95.1,71.72) ; v2(85.43,79.88) 84.89,79.88 CA131.1
  BOTTOM w0.254: UH2.AJ23 85.79,80.27 85.43,79.91 v2(85.43,79.88) ; v2(86.21,80.67) 86.21,80.63 UH2.AJ22 ; v2(95.1,71.72) 94.97,71.6 UH2.BG5
+1.25V_LDOSRAM: length 3.7
  TOP w0.254: v2(86.19,79.88) 86.48,80.17 86.84,80.17 T5003.1 87.06,80.18 87.33,80.45 87.33,80.89 87.05,81.17 RH5879.1
  BOTTOM w0.254: UH2.AK22 86.56,79.51 v2(86.19,79.88) 85.81,79.49 UH2.AK23
+1.35VS_B+: length 3.5
  TOP w0.254: PR701.2 187.46,187.37 186.88,186.78 186.88,186.37 187.13,186.11 188.24,186.11 188.52,186.39 v2(188.52,186.58)
  vias: v1(197.09,180.17) v2(195.64,179.69) v2(196.22,179.69) v2(196.22,179.09) v2(196.79,179.66) v2(196.79,179.09) v2(197.36,179.66) v2(197.36,179.09)
+1.35VS_VGAP: length 1.6
  TOP w0.254: v2(188.01,184.8) 187.55,184.8 PR711.2 186.59,184.63 PC714.1
  vias: v1(206.3,185.06) v2(206.43,185.63) v2(207.06,185.63) v2(207.44,184.74) v2(207.44,184.1) v2(207.44,183.47) v2(207.44,182.83) v2(207.7,185.63) v2(208.33,185.63) v2(208.33,182.83) v2(208.97,185.63) v2(208.97,182.83) v2(209.6,185.63) v2(209.6,182.83) v2(210.24,185.63) v2(210.24,182.83) v2(210.87,185.63) v2(210.87,182.83) v2(211.51,184.59) v2(211.51,184) v2(211.51,183.42) v2(211.51,182.83) v2(212.14,184.59) v2(212.14,184) v2(212.14,183.42) v2(212.14,182.83) v2(212.14,182.25) v2(212.78,185.6) v2(212.78,184.97) v2(212.78,184.33) v2(212.78,183.75) v2(212.78,183.16) v2(212.78,182.58) v2(212.78,182) v2(213.41,185.6) v2(213.41,184.97) v2(213.41,184.33) v2(213.41,183.75) v2(213.41,183.16) v2(213.41,182.58) v2(213.41,182)
+1.35VSDGPU: length 309.9
  TOP w0.102: 214.43,136.48 214.55,136.48 CV885.1
  TOP w0.254: RV608.1 243.4,146.58 v2(242.85,146.03) ; CV1045.1 238.75,123.23 v2(238.68,123.3) ; v2(246.68,124.9) 246.78,124.8 CV1004.1 ; v2(241.88,125.7) 241.97,125.7 242.63,125.04 CV1041.1 ; CV1007.1 243.76,126.21 v2(244.28,125.7) ; CV1017.1 234.81,123.17 v2(234.69,123.29) ; CV1017.1 CV1016.1 ; CV1017.1 CV1011.1 233.91,122.38 232.91,122.38 CV1001.1 ; v2(243.88,129.53) 243.33,128.98 CV1010.1 243.7,128.61 243.88,128.43 CV1000.1 244.27,129.15 244.4,129.28 244.4,129.73 244.17,129.96 CV1044.1 ; CV873.2 220.09,155.01 219.08,155.01 CV863.1 218.55,154.89 CV864.2 ; v2(236.28,123.3) 236.91,122.67 CV1012.1 CV1014.1 ; CV1009.1 CV1006.1 CV1005.1 246.57,130.5 v2(245.88,130.5) ; CV1018.1 241.73,132.95 242.15,133.36 242.15,133.47 v2(242.54,133.86) ; CV1015.1 246.62,131.23 v2(246.71,131.23) ; CV1047.1 242.82,124.24 v2(243.48,124.9)
  TOP w0.381: CV931.1 208.28,174.34 207.76,173.82 207.76,172.48 208.2,172.04 208.75,172.04 208.94,172.23 RV607.1 ; v2(220.08,147.34) 220.08,148.86 CV872.1 ; v2(211.89,151.53) 212.59,150.83 RV600.1 ; v2(202.67,146.52) 202.62,146.57 202.62,147.57 202.13,148.05 CV886.1 ; v2(242.54,133.86) 242.62,133.94 CV1042.1
  TOP w0.457: CV900.1 215.9,141.27 215.36,140.73 v2(215.36,140.59)
  TOP w0.508: CV884.2 213.35,132.59 v2(213.46,132.48) ; v2(232.08,174.2) 231.95,174.2 231.84,174.31 CV979.1 231.2,174.2 CV948.1 ; v2(246.08,133.84) 245.86,134.06 CV1002.1 CV1003.1 ; v2(211.72,173.97) 211.74,173.94 CV972.1 ; CV1026.1 CV1028.1 CV1029.1 236.35,160.83 ; CV971.1 213.58,165.64 CV974.1 212.75,165.74 v2(212.52,165.97) ; v2(235.48,133.7) 235.27,133.91 235.27,134.28 CV1046.1 ; v2(228.18,168.37) 228.23,168.42 228.78,168.42 229.11,168.75 RV605.1 ; CV896.2 CV897.2 v2(223.06,128.8) ; CV1039.1 243.48,154.66 v2(243.48,155.52) ; CV961.1 214.3,172.71 v2(214.36,172.78) 214,173.14 RV618.2 ; v2(234.59,172.36) 234.54,172.41 CV957.1 ; v2(224.85,175.18) 224.69,175.34 224.13,175.34 CV981.1 223.88,175.6 RV623.1 ; v2(200.33,146.47) 200.38,146.42 CV898.1 199.38,145.81 CV883.2 ; CV888.1 213.73,134.15 v2(213.73,134.79) ; CV954.1 236.57,173.55 v2(236.3,173.28) ; CV978.1 214.22,175.49 213.36,176.35 v2(213.34,176.35) ; v2(222.22,178.94) 222.44,179.15 CV944.1 CV945.1 ; v2(227.4,172.39) 227.19,172.61 CV949.1 ; CV984.1 234.43,176.37 v2(233.78,176.37) ; v2(237.08,133.7) 237.3,133.7 237.72,134.12 CV1019.1 CV1043.1 ; CV991.1 245.66,149.61 v2(245.88,149.83) ; CV970.1 211.63,176.45 v2(211.72,176.37) ; v2(241.88,154.63) 241.79,154.63 CV1036.1 ; CV936.1 204.72,174.59 v2(204.52,174.8) ; v2(243.72,150.87) 243.9,151.06 CV1035.1 ; CV1030.1 CV1027.1 236.35,160.83 ; CV1034.1 CV1013.1 248.4,149.23 v2(248.08,148.91) ; CV975.1 205.09,178.45 204.58,177.95 v2(204.52,177.95) 204.08,178.39 CV976.1 ; CV996.1 247.5,157.05 CV1031.1 247.69,157.17 248.33,157.81 248.33,158.32 247.76,158.88 CV1037.1 246.13,158.77 CV1020.1 244.57,158.3 244.57,157.58 245.08,157.07 v2(245.08,157.03) ; v2(206.12,168.37) 206.81,167.68 CV929.1 ; CV1048.1 243.49,132.09 v2(243.48,132.1) ; v2(205.32,175.57) 205.62,175.57 CV930.1 ; v2(225.78,165.2) 225.38,164.8 CV940.1 224.98,164.81 CV986.1 ; CV994.1 236.63,157.55 237.08,157.09 v2(237.08,157.03) ; CV994.1 236.63,159.5 236.35,159.78 236.35,160.83 ; CV994.1 235.78,157.75 CV997.1 ; v2(228.17,165.96) 228.47,166.26 CV983.1 ; 214.43,136.48 v2(213.72,136.48) ; CV999.1 244.53,122.5 v2(244.68,122.35) 244.21,121.87 CV1008.1 ; CV1032.1 242.8,158.13 v2(243.01,158.34) ; CV950.1 230.05,175.54 CV942.1 ; CV942.1 231.34,176.62 CV943.1 ; CV942.1 229.6,176.62 v2(229.19,177.03) ; CV982.1 224.09,177.42 224.72,176.8 v2(224.88,176.8) ; CV935.1 206.58,175.23 v2(206.12,174.76) ; v2(223.37,178.96) 223.57,179.16 223.57,179.79 CV946.1 CV947.1 226.05,179.79 227.38,178.46 v2(227.38,177.17) ; CV997.1 CV1038.1 233.85,157.76 CV1021.1 ; CV997.1 235.74,157.74 235.74,157.47 235.48,157.22 v2(235.48,157.03) ; v2(220.08,147.34) 220,147.26 CV870.1 ; v2(237.08,147.43) 237.08,147.14 236.32,146.37 CV1022.1 ; RV8.1 248.63,123.31 v2(248.15,122.83) ; v2(210.12,175.57) 210.09,175.57 209.15,176.51 CV962.1 CV965.1 ; CV980.1 225.55,173.46 v2(225.86,173.16) ; v2(245.09,154.66) 245.09,154.19 CV993.1 244.83,153.6 245.22,153.21 CV1024.1 247.07,152.8 CV1025.1 ; v2(235.48,147.43) 235.48,146.74 CV995.1 ; CV938.1 234.83,179.17 235.42,179.17 CV951.1 235.45,178.99 236.72,177.72 CV937.1 236.38,177.29 v2(236.38,176.77) 236.65,176.5 CV956.1 ; RV634.1 242.99,164.07 242.25,164.81 v4(241.07,164.81) CV939.1 237.79,164.81 237.29,165.32 CV955.1 236.73,165.04 CV985.1 236.12,165.96 v2(236.13,165.97) ; v2(237.88,153.83) 237.68,153.62 CV1033.1 ; v2(212.52,167.57) 212.53,167.58 CV973.1 ; CV931.1 209.17,174.34 v2(209.17,174.34) ; CV958.1 CV960.1 214.62,178.26 214.2,178.68 v2(213.09,178.68) 213.08,178.68 212.57,178.17 CV969.1 ; CV932.1 202.23,177.64 202.74,177.13 v2(202.9,177.13) ; CV952.1 226.54,174.08 v2(226.62,174.01) ; v2(235.38,169.17) 235.4,169.19 CV953.1 236.09,169.18 CV941.1 ; CV1040.1 v2(237.88,150.77) ; CV977.1 202.69,175.8 v2(202.92,175.57)
  BOTTOM w0.254: UV23.K3 v2(226.58,171.57) ; UV23.K12 234.57,172.36 v2(234.59,172.36) 234.62,172.38 234.62,172.4 234.98,172.75 UV23.L13 235.05,172.85 235.54,172.85 235.61,172.77 UV23.L14 ; UV26.M3 v2(238.68,148.23) ; UV23.D1 225.77,167.56 225.8,167.56 v2(225.81,167.57) ; UV23.F12 v2(234.58,169.17) UV23.G13 ; v2(202.19,152.41) 202.19,152.06 UV18.AB33 ; UV26.H3 v2(241.88,148.23) UV26.G2 v2(242.68,148.23) ; UV23.G14 v2(235.38,169.17) UV23.F14 ; UV26.P14 v2(237.08,157.03) ; v2(232.98,172.37) 232.98,172.51 233.23,172.77 UV23.L11 ; UV23.M3 226.62,173.93 v2(226.62,174.01) ; 241.9,124.13 242.28,123.75 UV25.L13 242.36,123.62 242.36,122.97 UV25.L14 ; 241.9,124.13 241.53,124.5 UV25.K12 ; 241.9,124.13 v2(241.9,124.15) ; v2(210.12,169.97) UV24.L4 UV24.K3 ; UV23.P12 v2(233.78,174.77) UV23.P11 ; UV26.M14 v2(238.68,157.03) UV26.L14 ; 238.69,124.09 UV25.G13 ; 238.69,124.09 UV25.F12 ; 238.69,124.09 v2(238.69,124.06) ; UV24.B14 v2(202.9,177.13) ; UV24.L2 v2(211.72,169.17) UV24.M3 ; UV25.G2 v2(238.68,132.9) ; v2(238.68,132.9) UV25.F1 ; v2(238.68,132.9) UV25.G1 ; UV24.D1 v2(213.36,174.72) ; v2(224.85,175.18) 225.06,175.18 225.07,175.17 UV23.P1 ; UV26.G4 v2(242.68,149.03) UV26.F3 243.08,148.56 v2(243.48,148.17) ; 242.87,146.06 242.82,146.06 242.28,146.6 UV26.G1 ; 242.87,146.06 v2(242.85,146.03) ; 242.87,146.06 243.08,146.27 UV26.F1 ; v2(235.49,124.93) 235.49,124.9 UV25.B12 ; v2(232.08,174.2) 232.25,174.37 UV23.N10 232.58,174.22 232.83,173.97 233.63,173.97 234.03,173.57 UV23.M12 ; UV24.B1 v2(213.34,176.35) ; v2(225.78,169.17) UV23.G1 ; v2(225.78,169.17) UV23.G2 ; v2(225.78,169.17) UV23.F1 ; UV25.B1 v2(235.48,133.7) ; v2(236.3,173.28) 236.3,173.32 236.04,173.57 UV23.M14 ; UV24.D12 204.14,175.17 v2(204.52,174.8) 204.89,175.17 UV24.D11 ; UV24.G2 v2(211.72,172.37) UV24.H3 ; UV24.G2 v2(211.72,173.17) ; UV24.G2 UV24.G1 ; UV25.N10 v2(244.28,125.7) ; UV24.D14 v2(202.92,175.57) ; UV26.E10 243.88,154.38 243.48,154.78 v2(243.48,155.52) 243.35,155.52 243.08,155.79 UV26.F12 ; UV24.M14 v2(202.92,169.17) UV24.L14 ; UV24.G13 v2(203.72,172.37) UV24.H12 ; UV25.F14 v2(238.68,123.3) UV25.G14 ; UV23.H12 v2(233.78,169.97) UV23.G11 ; UV23.C5 v2(228.17,165.96) ; UV23.C10 v2(232.98,165.97) ; UV26.T1 v2(235.48,147.43) ; UV26.L11 v2(238.68,155.43) UV26.M12 ; UV24.L13 v2(203.72,169.97) UV24.K12 ; UV23.B12 v2(233.78,165.97) ; UV25.C10 v2(235.48,125.7) ; UV25.D12 237.06,124.88 237.06,124.9 ; UV23.F3 v2(226.58,168.37) ; UV25.N5 v2(243.88,129.53) ; UV26.B1 246.67,146.64 v2(246.67,146.64) ; UV23.P14 v2(235.4,175.55) ; UV24.N5 v2(210.12,168.37) ; UV24.B3 v2(211.72,176.37) ; UV18.T33 207.44,151.98 207.44,152.39 v2(207.45,152.4) ; UV24.F1 212.92,173.61 212.56,173.97 v2(211.72,173.97) UV24.F3 v2(210.92,173.17) UV24.G4 ; UV18.B13 219.94,135.24 v2(220.06,135.13) ; UV23.D11 v2(233.78,167.57) UV23.D12 ; UV23.R10 v2(232.98,176.37) ; UV25.L1 242.28,133.6 242.54,133.86 v2(242.54,133.86) ; UV26.B3 v2(246.68,148.23) ; v2(224.88,176.8) 224.9,176.77 UV23.T1 ; v2(238.68,146.49) 238.66,146.51 238.62,146.51 238.28,146.85 UV26.M1 238.34,146.97 239.03,146.97 UV26.L1 239.14,147.08 239.14,147.77 UV26.L2 ; UV24.P3 v2(210.92,167.57) ; UV24.P12 v2(204.52,167.57) UV24.P11 ; UV23.T3 v2(227.38,177.17) ; UV23.L4 v2(227.4,172.39) ; UV26.D14 v2(245.08,157.03) ; UV24.F14 v2(202.93,173.16) 202.9,173.16 UV24.G14 ; UV26.T12 v2(235.48,155.43) ; UV25.D14 v2(236.28,123.3) ; v2(228.18,174.83) 228.18,174.62 228.43,174.37 UV23.N5 ; UV26.D12 v2(245.08,155.43) UV26.D11 ; UV23.P3 v2(227.38,175.57) ; UV26.L13 v2(239.48,156.23) UV26.K12 ; UV26.B14 v2(245.88,157.83) ; v2(243.01,158.34) 243.08,158.27 UV26.F14 ; UV26.G14 UV26.G13 v2(241.88,156.23) UV26.H12 ; UV26.P11 v2(237.08,155.43) UV26.P12 ; v2(235.48,150.63) UV26.R5 ; UV24.R10 v2(205.32,166.77) ; UV26.T3 v2(235.48,149.03) ; UV25.B14 v2(234.69,123.29) ; UV24.T14 202.14,165.19 v2(202.14,165.17) ; UV24.T12 v2(204.52,165.97) ; UV25.M14 v2(243.08,122.36) ; UV25.D11 237.06,124.92 237.06,124.9 ; UV24.E5 209.25,174.37 209.22,174.34 v2(209.17,174.34) ; UV26.L4 v2(239.48,149.03) UV26.K3 ; UV26.R10 v2(236.28,154.63) ; UV25.R5 v2(245.88,130.5) ; UV26.P1 v2(237.08,147.43) ; UV25.L11 v2(241.88,125.7) ; UV23.E5 v2(228.18,168.37) ; UV26.B12 v2(246.68,155.43) ; 239.47,124.91 v2(239.47,124.93) ; 239.47,124.91 UV25.G11 ; 239.47,124.91 UV25.H12 ; v2(237.07,124.9) 237.06,124.9 ; UV24.C10 v2(205.32,175.57) ; UV25.E10 v2(237.86,125.72) ; UV23.E10 v2(232.98,168.37) ; UV24.B12 v2(204.52,176.37) ; UV25.M1 243.08,133.77 v2(243.13,133.81) ; v2(246.08,133.84) 246.16,133.76 246.16,133.42 UV25.T1 ; UV23.B3 v2(226.58,165.97) ; UV24.F12 204.15,173.57 204.55,173.97 205.16,173.97 205.56,174.37 UV24.E10 205.72,174.37 v2(206.12,174.76) ; v2(225.78,165.2) 225.74,165.2 UV23.B1 ; UV25.L2 v2(241.88,132.1) ; UV23.D14 236.22,166.72 236.22,166.06 v2(236.13,165.97) 235.78,165.62 UV23.B14 ; UV25.P12 v2(245.08,124.9) UV25.P11 ; UV23.T14 v2(236.38,176.77) ; UV25.P14 v2(244.68,122.35) ; v2(237.88,150.77) 237.48,150.36 UV26.N5 ; UV25.G4 v2(239.48,131.3) UV25.H3 ; UV23.M1 UV23.L1 225.13,172.77 v2(224.9,172.55) ; v2(236.15,129.61) 235.88,129.88 UV25.C5 ; UV26.D3 v2(244.33,148.98) ; v2(245.09,154.66) 245.48,154.27 UV26.C10 ; UV26.T14 v2(235.48,157.03) ; UV26.G11 v2(241.88,154.63) ; UV23.G4 v2(227.38,169.97) UV23.H3 ; UV24.N10 v2(206.12,168.37) ; UV24.R5 209.34,165.99 v2(209.32,165.99) ; UV25.B3 v2(235.48,132.1) ; UV26.P3 v2(237.08,149.03) ; UV24.G11 v2(205.32,172.37) ; UV25.K3 v2(241.08,132.1) ; UV25.P3 v2(245.08,131.3) ; UV25.M12 v2(243.48,124.9) ; UV24.T1 v2(212.52,165.97) ; UV25.D3 v2(236.28,131.3) ; UV25.F3 v2(237.88,132.1) ; UV25.T14 246.45,122.73 v2(246.45,122.37) ; UV23.R5 v2(228.18,176.37) ; v2(243.72,150.87) 243.72,150.39 UV26.E5 ; UV23.D3 v2(227.38,166.77) ; UV24.T3 v2(210.92,165.97) ; UV26.D1 v2(244.32,146.66) ; UV23.L2 225.86,173.09 v2(225.86,173.16) ; UV24.C5 v2(210.12,175.57) ; UV24.P1 v2(212.52,167.57) ; UV26.N10 v2(237.88,153.83) ; UV24.P14 v2(202.92,167.57) ; UV26.C5 v2(245.88,149.83) ; UV25.P1 v2(245.08,132.9) ; v2(214.11,169.44) 213.44,168.77 UV24.M1 213.01,168.86 213.01,169.48 UV24.L1 ; UV23.T12 v2(233.78,176.37) ; UV25.D1 v2(237.08,133.7) ; UV25.E5 v2(237.88,130.5) ; UV25.L4 v2(241.88,131.3) ; UV18.B19 220.08,140.24 v2(220.37,139.95) ; UV24.D3 v2(210.92,174.77) ; UV25.R10 v2(245.88,125.7) ; UV25.T12 v2(246.68,124.9) ; UV25.M3 v2(243.48,132.1)
  BOTTOM w0.3: v2(220.39,137.37) 220.11,137.65 219.09,137.65 UV18.B16
  BOTTOM w0.305: UV18.T30 207.35,149.49 207.35,149.43 207.59,149.19 v2(207.59,149.01) ; UV18.AA30 203.2,149.49 v2(202.78,149.07) ; UV25.T3 246.28,131.65 v2(246.71,131.23) ; v2(216.17,137.31) 216.17,137.31 UV18.E16 ; UV24.M12 204.17,168.77 v2(204.52,169.11) 204.92,169.51 UV24.L11 ; v2(205.27,149.14) 205.26,149.14 204.91,149.49 UV18.W30 ; UV18.E13 216.59,135.24 216.24,135.59 v2(216.13,135.59) ; UV18.W33 204.97,152.01 204.97,153.47 v2(204.99,153.44) ; v2(215.36,140.59) 215.4,140.59 215.96,140.03 216.39,140.03 UV18.E19
  BOTTOM w0.381: RV630.2 240.65,144.67 v2(241.6,145.62) ; UV24.P14 201.89,167.17 201.85,167.2 CV933.1
  BOTTOM w0.508: v2(223.06,128.8) 223.51,128.35 CV871.1 CV862.1 ; CV934.1 201.9,164.93 v2(202.14,165.17)
  vias: v2(201.92,146.56) v2(202.51,180.33) v2(203.78,180.33) v2(204.43,146.56) v2(204.65,145.93) v2(205.05,180.33) v2(206.33,180.37) v2(207.05,180.36) v2(207.74,180.37) v2(207.84,146.56) v2(209.39,146.58) v2(210.23,146.52) v2(213.63,144.01) v2(213.7,142.3) v2(213.7,139.79) v2(213.73,140.67) v2(215.13,182.96) v2(215.13,182.33) v2(215.13,181.69) v2(215.13,181.06) v2(215.13,180.42) v2(215.13,179.79) v2(215.14,179.15) v2(215.76,182.96) v2(215.76,182.33) v2(215.76,181.69) v2(215.76,181.06) v2(215.76,180.42) v2(215.76,179.79) v2(215.77,179.15) v2(216.4,182.96) v2(216.4,182.33) v2(216.4,181.69) v2(216.4,181.06) v2(216.4,180.42) v2(216.4,179.79) v2(216.41,179.15) v2(217.03,182.96) v2(217.03,182.33) v2(217.03,181.69) v2(217.03,181.06) v2(217.03,180.42) v2(217.03,179.79) v2(217.04,179.15) v2(217.67,182.96) v2(217.67,182.33) v2(217.67,181.69) v2(217.67,181.06) v2(217.67,180.42) v2(217.67,179.79) v2(217.68,179.15) v2(218.3,182.96) v2(218.3,181.06) v2(218.3,180.42) v2(218.3,179.79) v2(218.31,179.15) v2(219.25,154.51)
+1V_MPHY_MPHYPLL:
  vias: v1(68.01,93.31)
+1V_PCH: length 14.9
  TOP w0.279: RH492.1 117.42,162.59 118.04,162.59 118.57,163.12 119.09,163.12 119.16,163.2 JXDP.44 121.48,163.2 v2(121.87,163.59) 122.26,163.2 JXDP.43
  BOTTOM w0.457: LH3.1 70.8,91.97 71.02,92.19 72.38,92.19 72.5,92.06 v2(72.5,92.05)
  BOTTOM w0.508: LH4.1 102.35,89.29 v2(102.36,89.3) ; CH3.1 121.39,163.59 v2(121.87,163.59)
  vias: v2(81.43,82.58) v2(82.31,85.34) v2(82.23,82.95) v2(82.24,82.2) v2(83.08,85.39) v2(83.85,85.35) v2(84.62,85.35) v2(86.17,85.26) v2(86.94,85.23) v2(87.72,85.28) v2(97.07,94.15) v2(100.93,94.94) v2(101.57,94.96) v2(102.16,94.95) v2(108.75,78.43) v2(109.79,81.65) v2(110.29,82) v2(110.86,82) v2(112.17,82.19) v2(112.85,82.19) v2(113.82,82.19) v2(114.66,82.19) v2(115.28,82.19) v4(87.12,96.94)
+1V_PCH_AZPLL: length 4.5
  TOP w0.356: v2(97.75,92.56) 97.79,92.52 CH203.1 CH3322.1 99.02,91.6 LH2.2
  BOTTOM w0.254: UH2.D1 UH2.E1 97.24,92.05 v2(97.75,92.56)
+1V_PCH_CLK5:
  vias: v1(98.92,88.78)
+1V_PCH_CNVI: length 2.2
  TOP w0.381: RH5856.2 89.74,83.15 v1(89.62,83.04) v2(89.2,82.62)
  BOTTOM w0.203: v2(89.2,82.62) 89.2,82.34 89.05,82.19 UH2.AE17
+1V_PCH_PRIM:
  vias: v2(83.06,82.96) v2(83.03,82.24) v2(83.76,82.21) v2(83.82,82.99) v2(85.4,81.51) v2(86.13,83.72) v2(86.15,83.01) v2(86.97,83.03) v2(112.28,81.01) v2(112.86,81.01) v2(113.5,81.01) v2(114.1,81.01) v2(114.68,81.02) v2(115.32,81.02) v2(115.89,81.02) v2(116.48,81.02) v4(83.13,83.67)
+1V_VCCDSW: length 5.7
  BOTTOM w0.127: CH3329.1 73.13,67.76 v1(73.88,67.76)
  BOTTOM w0.254: UH2.BG45 UH2.BG46 74.56,71.19 72.72,69.36
  BOTTOM w0.381: 72.72,69.36 CH3329.1
+1VALW: length 29.3
  BOTTOM w2.032: 178.22,98.91 177.33,99.8 177.33,104.77 191.12,118.56 191.12,122.13
  vias: v2(180.57,152.88) v2(180.57,152.29) v2(181.15,152.29) v2(181.74,152.29) v2(189.9,123.79) v2(190.2,124.34) v2(190.53,123.8) v4(181.39,151.39)
+1VALW_PG: length 3
  TOP w0.14: v1(312.08,83.66) 312,83.58 v2(311.38,83.58) RT5840.2
  BOTTOM w0.14: v2(136.03,69.33) 135.33,70.03 PR521.2
+1VS_GFX: length 10.2
  TOP w0.14: v4(192.96,152.87) 193.41,153.32 v2(193.41,153.82)
  TOP w0.457: CV859.1 197.41,142.1 v2(197.62,142.31)
  TOP w0.508: v2(192.81,126.48) 192.62,126.68 192.62,128.3 CV866.1 ; CV865.1 198.12,144.36 197.92,144.56 197.92,144.59 v2(197.7,144.82) ; CV860.1 198.73,139.91 v2(198.79,139.97) ; v2(193.41,153.82) 194.17,153.82 CV869.1
  BOTTOM w0.254: UV18.AH21 197.3,141.99 v2(197.62,142.31) ; v2(197.62,142.31) 198.05,142.74 UV18.AG22 ; v2(197.62,142.31) 198.04,141.89 UV18.AG21 ; v2(198.79,139.97) 198.62,139.97 198.35,140.24 UV18.AG19 ; UV18.AH25 197.3,145.22 v2(197.7,144.82) 198.1,144.42 UV18.AG24
  vias: v2(221.26,183.93) v2(221.26,183.29) v2(221.86,183.93) v2(221.86,183.29)
+1VSP: length 13.9
  TOP w0.254: PC510.1 121.46,71.29 122.4,72.23 124.43,72.23 125.27,71.39 125.27,70.58 v1(126.65,69.2) 127.51,68.34 130.48,68.34 130.8,68.67 v2(130.8,69.01)
  BOTTOM w0.254: PR504.1 130.86,68.95 v2(130.8,69.01) 130.96,69.17 PC506.1
  vias: v2(118.07,73.16) v2(118.66,73.16) v2(119.24,73.16) v2(119.85,73.16) v2(120.46,73.16) v2(121.09,73.16) v2(122.54,71.56) v2(122.54,70.97) v2(123.13,71.56) v2(123.13,70.97) v2(123.71,71.56) v2(123.71,70.97) v2(124,73.14) v2(124.29,71.56) v2(124.29,70.97) v2(124.59,73.14)
+2.5V_MEM: length 8.5
  TOP w0.508: v2(247.89,95.97) v2(247.89,96.6) 247.89,96.74 247.26,97.38 CD31.1 CD30.1 243.88,97.36 CD27.1 CD28.1
  vias: v2(173.86,95.75) v2(174.47,95.78) v2(175.03,95.57) v4(177.76,91.72)
+2.5V_MEM_PG: length 1.4
  TOP w0.14: PT201.1 175.4,80.54 PR1851.2
+2.5VSP_ON: length 4.5
  TOP w0.254: PU1800.6 177.79,77.66 177.11,76.98 PC1800.1 176.58,76.38 v1(177.13,75.84) PR1801.2
+3.3V_1.8V_ESPI: length 20.9
  TOP w0.254: v2(82.51,71.2) 82.51,71.2 81.71,72 RH5838.2 ; RH518.2 107.51,68.56 107.75,68.32 113.78,68.32 115.53,70.07 116.38,70.07 116.91,70.6 117.23,70.6 117.35,70.73 117.35,72.33 v2(116.64,73.04) v1(116.64,74.39) 116.64,75.11 RH597.2 117.79,75.75 RH1943.2
  BOTTOM w0.254: v2(81.15,78.78) 81.73,78.2 UH2.AN32
  vias: v2(62.69,80.26) v2(67.51,84.54)
+3.3V_1.8V_PGPPA:
  vias: v1(116.54,79.62)
+3.3VDX_SSD: length 17
  TOP w0.14: 274.88,74.22 274.88,72.85 v1(274.54,72.51)
  TOP w0.254: v2(267.71,72.12) 268.57,72.12 v4(268.91,71.77)
  TOP w0.508: v2(267.08,89.12) 266.75,88.79 CD36.1 ; v2(267.1,72.12) 266.98,72.12 266.44,72.66 CD41.1 ; v2(267.71,72.12) 267.71,71.79 267.26,71.33 266.51,71.33 CD40.1 ; CD39.1 CD38.1 266.75,86.76 267,86.51 v2(267,86.06) ; v2(267.81,76.16) 267.81,76.44 267.5,76.75 266.84,76.75 266.56,76.47 RD8.2 266.19,77.58 v4(266.36,77.74) 266.36,79.35 266.24,79.47 RD7.1 266.4,80.23 v2(266.97,80.23) 267.6,80.23 v2(267.6,80.24)
  vias: v2(267,78.69) v2(267.6,78.69) v2(268.21,78.69) v2(276.28,77.36) v2(276.91,78) v2(276.91,77.36) v2(277.55,78) v2(277.55,77.36) v4(276.91,76.6)
+3V_PCH: length 97.7
  TOP w0.254: RH546.2 83.88,75.33 v2(83.8,75.41) ; CH204.1 CH82.1 88.06,73.75 88.73,74.42 RH5875.1
  TOP w0.356: v2(110.02,117.05) 110.37,117.4 UZ21.5 110.67,117.64 110.43,117.88 UZ20.5
  TOP w0.381: CH82.1 87.85,72.95 87.12,72.23 86.91,72.23 ; 86.91,72.23 RH503.1 85.7,72.23 85.45,72.48 RH505.1 85.18,72.57 RH501.1 84.04,72.57 RH504.1 ; 86.91,72.23 RT5857.1 ; UZ12.5 116.12,117.64 115.87,117.39 113.58,117.39 v2(113.56,117.37) ; UZ31.5 247.57,117.22 247.76,117.03 v2(247.76,116.68) ; CH3321.1 85.62,76.94 85.72,76.84 v2(86.08,76.84) 86.57,76.84 RH523.1 ; RH5875.1 89.14,74.42 89.47,74.08 LH1.1
  TOP w0.457: RH566.1 106.25,75.93 105.82,75.51 105.53,75.51 v2(105.52,75.5)
  TOP w0.508: v2(163.53,70.66) 163.53,71.01 165.7,73.18 165.7,74.66 162.75,77.6 160.13,77.6 159.49,78.25 159.49,79.53 158.71,80.31 152.08,80.31 RE86.1 ; v2(256.41,73.94) 256.41,77.94 257.66,79.19 257.66,89.75 257.44,89.97 257.44,94.82 256.6,95.67 v2(256.6,98.13) ; v2(83.8,75.41) 83.8,74.82 RH130.1 83.95,74.81 84.25,74.5 84.25,73.3 83.82,72.87 RH504.1 ; 107.03,73.72 107.03,73.83 105.52,75.34 v2(105.52,75.5) ; UZ19.5 118.02,126.62 117.6,126.21 RZ84.1 v2(117.02,126.89)
  BOTTOM w0.254: 85.14,77.36 85.34,77.16 85.79,77.16 86.08,76.87 v2(86.08,76.84) ; UH2.AT44 75.87,77.08 v2(75.87,77.62) 75.72,77.77 UH2.AN44
  BOTTOM w0.305: v2(86.14,86.19) 86.14,86.16 85.79,85.81 UH2.V23 ; JAPS.1 176.39,72.93 176.24,72.78 176.24,72.46 v2(176.09,72.31) ; v2(68.04,75.72) 68.65,75.72 RH74.1
  BOTTOM w0.33: v2(88.82,67.94) 88.67,68.09 RH110.2
  BOTTOM w0.356: RH513.2 67.98,82.82 v2(67.86,82.95) ; v2(105.52,75.5) 105.52,75.66 104.91,76.27 RH458.1 103.62,76.27 103.12,76.77 RH571.2
  BOTTOM w0.381: RH586.2 60.11,70.74 v2(60.03,70.82) ; v2(88.82,67.94) 88.97,68.09 RH5857.1
  BOTTOM w0.508: v2(114.22,120.44) 117.68,120.44 118.04,120.8 118.04,122.54 117.02,123.56 v2(117.02,126.89) ; v2(58.97,78.05) 58.9,78.11 58.9,78.99 RH585.2 58.51,79.38 DH2.2
  vias: v2(62.14,68.19) v2(62.72,68.19) v2(79.06,82.59) v2(79.35,83.93) v2(80.05,82.64) v2(83.67,78.48) v2(93.01,74.57) v2(93.46,74.12) v2(94.08,69.32) v2(98.61,69.74) v2(110.71,68.9) v2(110.86,75.61) v4(57.49,76.14)
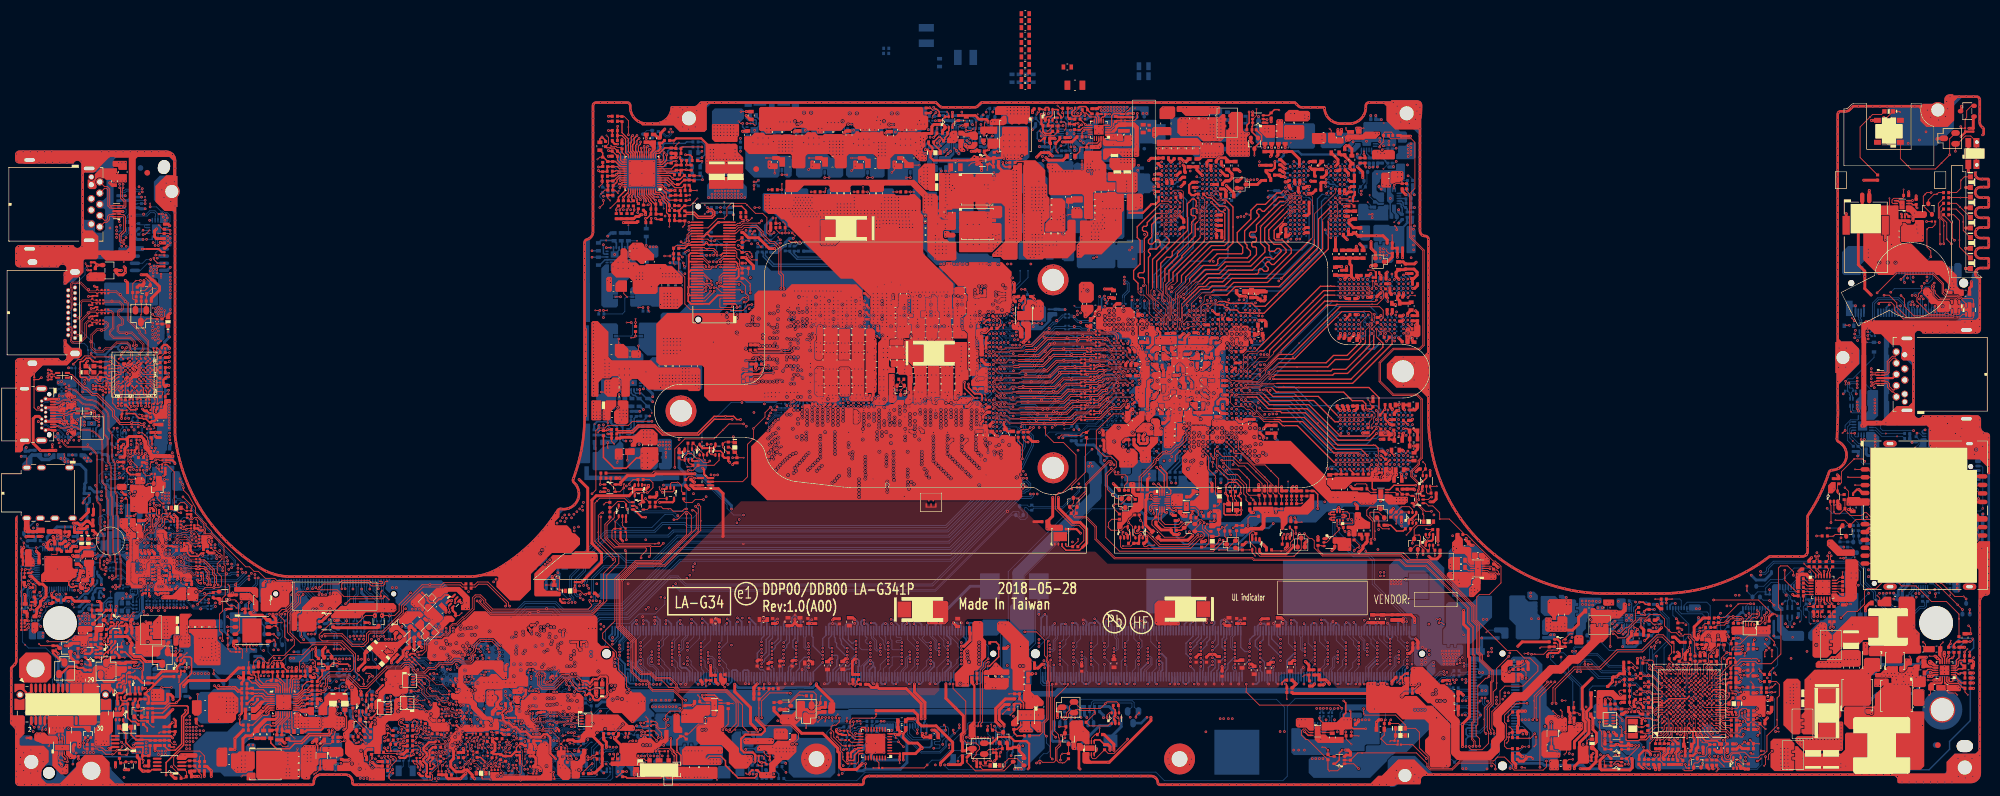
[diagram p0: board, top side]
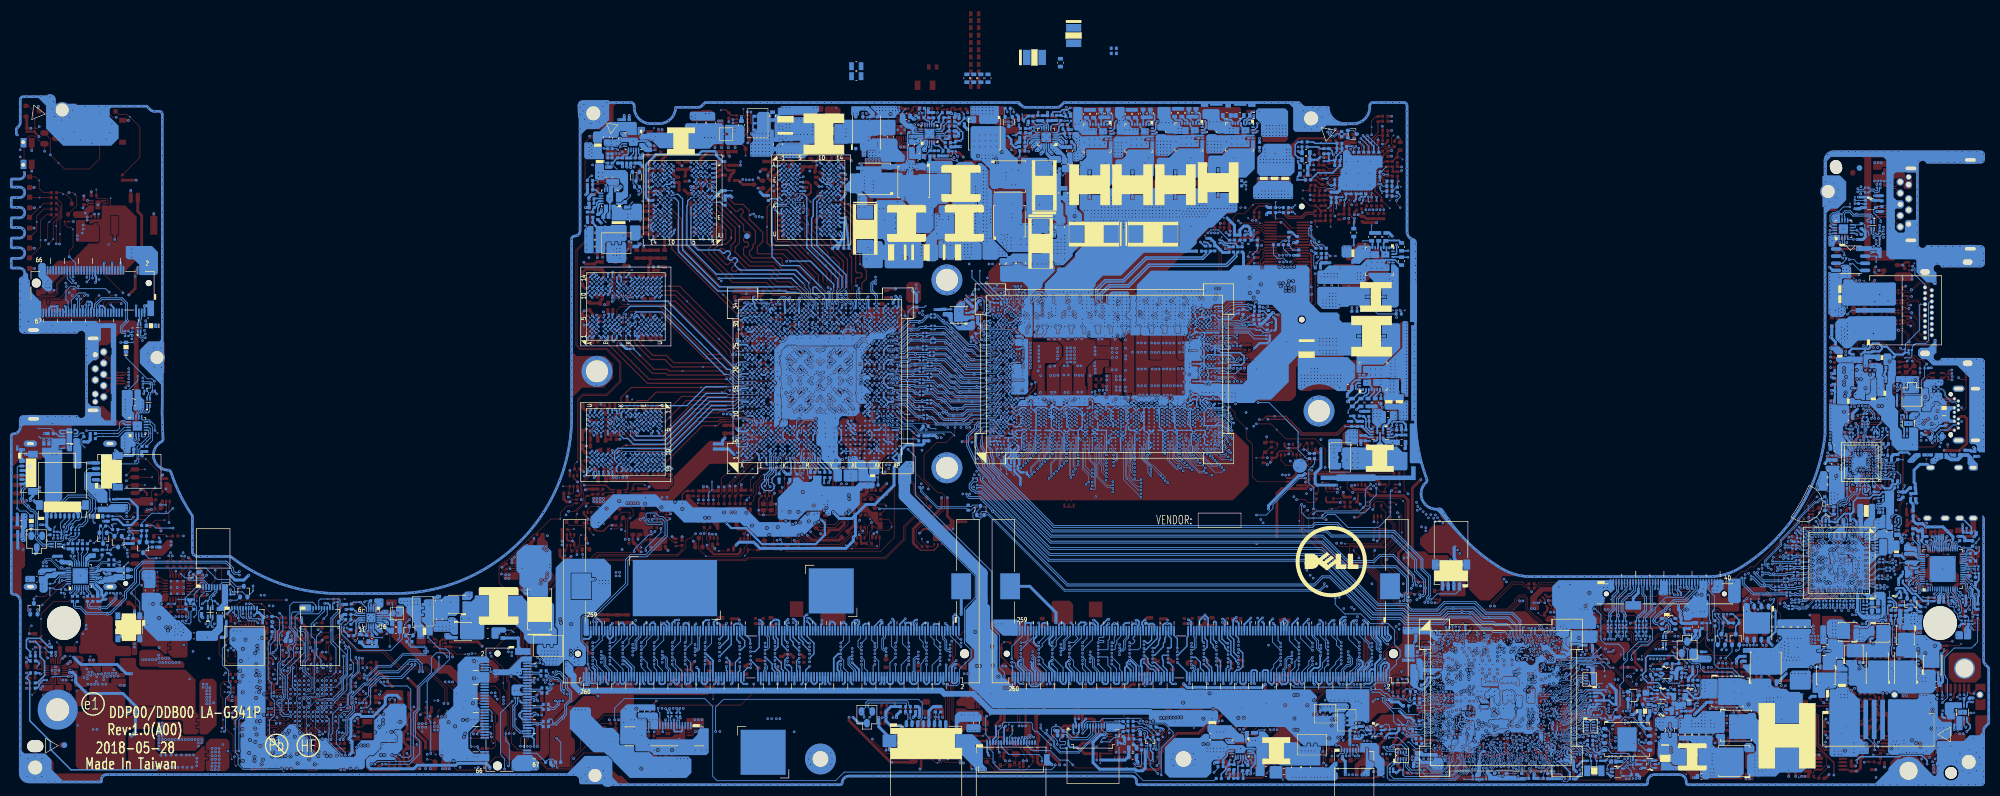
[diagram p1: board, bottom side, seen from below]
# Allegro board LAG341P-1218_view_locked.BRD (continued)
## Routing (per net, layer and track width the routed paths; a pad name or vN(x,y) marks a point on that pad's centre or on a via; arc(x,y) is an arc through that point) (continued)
+3V_PCH_AZIO: length 1.8
  TOP w0.089: v1(89.59,71.71) 89.59,72.27 90.11,72.79
  BOTTOM w0.254: v2(90.49,73.34) 90.63,73.49 UH2.BB14
+3V_PCH_BR:
  vias: v1(54.06,69.96)
+3V_PCH_CT: length 2.9
  TOP w0.14: CZ20.1 53.14,69.88 52.46,69.21 52.26,69.21 v1(52.02,68.97)
  TOP w0.254: UZ4.6 53.2,70.52 53.14,70.45 CZ20.1
+3V_PCH_DSW: length 48.4
  TOP w0.381: RH453.2 68.62,73.99 v2(67.89,73.99) ; RH515.2 73.2,73.81 72.62,73.22 72.62,71.93 v2(72.22,71.53)
  TOP w0.508: v2(126.92,85.02) 126.92,83.67 129.72,80.87 129.72,78.07 v2(130.78,77.01) ; 144.25,81.68 144.25,81.98 141.45,84.78 v2(141.45,85.08) ; RH2.1 RH545.2 74.83,68.88 75.56,68.88 RH533.2 75.6,68.52 75.93,68.19 v4(78.1,68.19) v2(79.06,69.15)
  BOTTOM w0.254: UH2.BE48 73.38,72.13 UH2.BE49 73.1,72.04 72.83,72.04 72.32,71.53 v2(72.22,71.53)
  BOTTOM w0.508: RH5842.2 RH5837.1 79.11,69.1 v2(79.06,69.15) ; v2(112.69,68.92) 112.69,71.29 113.16,71.76 v2(113.16,72.23) ; v2(126.92,85.02) 127.53,84.41 137.66,84.41 137.71,84.47 139.44,84.47 139.5,84.41 140.78,84.41 v2(141.45,85.08) ; v2(71.52,69.41) 72.06,69.95 72.06,71.37 v2(72.22,71.53)
+3V_PCH_DSW_RR: length 1.9
  TOP w0.14: QH1.1 v1(139.62,77.22)
+3V_PCH_ME_SW: length 3.7
  TOP w0.14: v1(111.4,72.51) 111.4,72.13 111.76,71.77 SW4.1 111.09,71.46 110.78,71.76 110.16,71.76 109.74,72.18 RH536.2
+3V_PS8723: length 1.1
  TOP w0.381: v2(315.14,100.98) 315.39,100.73 RI22.2
  vias: v1(326.24,100.91) v2(315.95,104.44) v2(325.55,104.79) v2(325.55,103.9) v2(326.44,104.79) v2(326.44,103.9)
+3V_ROM: length 6.2
  BOTTOM w0.508: v2(61.84,79.61) 61.38,79.61 60.77,80.22 DH2.1 60.21,79.08 RH585.1 60.06,78.8 60.06,77.91 59.26,77.11 UH8.8
  vias: v1(106.17,70.4) v2(106.16,69.46)
+3V_TBT: length 2.9
  TOP w0.356: RT21.1 30.16,115.25 RT202.1 30.21,114.72 v2(30.22,114.71)
  BOTTOM w0.127: v1(15.85,107.65) 15.76,107.74 CT54.1
  BOTTOM w0.254: v2(22.52,107.57) UT1.H9
  vias: v2(18.34,110.99) v2(18.93,110.99)
+3V_TBT_S0: length 3.2
  TOP w0.089: v2(18.69,101.1) v1(18.69,100.56)
  TOP w0.254: CT163.1 26.42,105.89 v2(26.42,105.61)
  BOTTOM w0.254: UT1.R13 26.42,105.62 v2(26.42,105.61)
  BOTTOM w0.508: v2(13.22,107.37) 13.76,107.91 LT14.1
  vias: v2(25.17,100.45)
+3V_TBT_SPI: length 15.3
  TOP w0.14: RT15.1 CT47.1 37.29,90.76 v1(37.06,90.98) 36.74,91.31 v2(36.74,91.95) 36.74,93.2 RT16.1
  TOP w0.381: v2(39.24,98.27) 39.42,98.44 RT17.1 39.84,97.8 RT243.2 ; RT18.1 36.59,98.4 36.51,98.33 v2(36.36,98.33)
  TOP w0.508: v2(34.29,108.37) 33.38,108.37 RT242.2
  BOTTOM w0.381: v2(36.36,98.33) 36.12,98.09 36.12,94.37 37.39,93.11 UT2.8
  BOTTOM w0.508: UT2.8 37.39,92.6 v2(36.74,91.95)
+3V_VC: length 36.7
  TOP w0.254: PC200.2 22.97,69.56 23.23,69.82 PU200.8
  TOP w0.381: 23.67,84.92 23.35,85.24 PC213.1 21.56,85.24 21.32,85.47 21.31,85.47 20.6,86.18 PU202.5 19.83,86.18 19.69,86.33 PR236.1 ; 23.67,84.92 v4(25.02,86.26) 25.13,86.38 PR231.1 ; 23.67,84.92 22.67,83.91 v2(22.61,83.91) 22.02,83.33 PR259.1 22.15,83.28 22.66,82.77 22.66,81.76 PR248.2 ; PR244.1 27.44,77.6 27.44,78.53 v2(27.15,78.83) ; PU203.8 16.14,73.85 15.89,73.6 v2(15.54,73.6)
  TOP w0.508: v2(26.63,68.93) 27.27,68.29 PR208.1 ; PC200.2 v2(21.77,69.56) 21.57,69.56 21.01,70.12 21.01,71.65 20.62,72.03 PR251.1 ; PR266.2 75.54,98.25 v2(75.54,97.83) ; PR212.1 v2(32.55,68.62)
  BOTTOM w0.254: v2(20.08,95.78) 20.08,96.06 19.88,96.26 17.61,96.26 17.33,96.55 16.64,96.55 PR224.2
  BOTTOM w0.381: PR274.2 58.37,86.48 58.03,86.14 58.03,85.85 v2(57.98,85.8) ; v2(56.18,88.23) 55.75,88.66 PR273.2 ; v2(14.67,100.64) 14.67,100.84 PC204.1 13.79,101.26 13.79,100.53 PU201.5
  BOTTOM w0.508: v2(50.87,88.15) 50.87,86.79 51.63,86.04 PR279.2
  vias: v2(14.57,95.4) v2(52.52,80.87) v2(58.85,83.84) v2(67.71,95.3)
+3VA_TBT: length 23
  TOP w0.381: CT143.1 21.95,108.34 21.95,108.78 v2(21.86,108.87) ; v2(27.17,115.21) 27.55,114.82 27.55,114.82 27.76,114.6 RT23.1 RT5847.1 RT5848.1
  BOTTOM w0.203: v2(21.86,108.87) 22.18,108.54 UT1.F8
  BOTTOM w0.254: 22.28,116.2 22.28,117.49 21.64,118.13 19.35,118.13 18.78,118.7 17.61,118.7 17.11,119.21 16.37,119.21
  BOTTOM w0.305: RT22.1 27.86,114.57 27.23,115.21 v2(27.17,115.21) 27.04,115.21 26.59,114.76 RT36.1 25.83,113.94 25.7,113.81 25.2,113.81 RT35.1 25.1,114.16 23.88,115.37 23.02,115.37 22.82,115.17
  BOTTOM w0.381: 22.28,116.2 22.28,115.72 22.82,115.17 22.82,114.29 22.78,114.26 RT1145.1 ; RT167.1 14.95,119.87 15.54,119.27
  vias: v1(21.55,118.45) v2(17.76,116.71) v2(17.83,115.52) v2(20.07,116.6) v2(20.07,115.97)
+3VA_TBT_LC: length 0.5
  BOTTOM w0.203: UT1.R6 v2(26.42,108.87)
  vias: v2(33.21,111.28) v4(33.76,111.17)
+3VALW: length 182.9
  TOP w0.254: v2(162.31,187.67) 162.65,187.32 162.85,187.32 163.31,186.86 RV1809.1 ; v2(302.53,72.13) 302.53,71.68 302.96,71.25 304.32,71.25 304.58,71.5 UE5.5 ; UZ6.5 233.78,70.87 234.49,71.58 234.49,72.79 v2(235,73.3) ; RV103.1 218.03,184.47 218.44,184.88 218.44,186.82 v2(218.43,186.84)
  TOP w0.381: v2(106.65,120.58) 106.63,120.56 UZ23.5 ; UE7.5 120.69,127.54 121.21,127.02 v2(122.73,127.02) 123.11,127.02 123.48,127.38 UZ22.5 ; v2(130.48,71.19) 130.57,71.28 PR506.1 130.57,72.45 130.14,72.87 128.59,72.87 128.04,73.41 128.04,75.31 128.79,76.05 131.64,76.05 132.28,76.7 132.28,77.14 130.76,78.67 v2(130.76,79.04)
  TOP w0.508: v2(4.98,99.36) 5.42,99.36 RA100.1 ; PR1800.2 174.95,81.4 173.98,80.42 173.98,78.72 174.83,77.87 v2(174.83,77.54) ; v2(310.69,79.9) 311.11,79.9 311.39,80.18 RZ1136.1 ; v2(106.65,120.58) 106.65,120.96 107.82,122.13 112.51,122.13 112.83,122.45 v2(119.81,122.45) ; v2(250.62,117.47) 251.23,117.47 251.71,117.95 RV12.1 ; v2(161.99,76.85) 162.5,76.85 163.13,76.22 RZ1138.1 ; v2(13.55,99.75) 13.86,99.75 14.2,99.41 PR222.2 PR223.2 ; v2(252.03,110.46) 252.02,110.47 RV111.1 ; R5832.1 143.05,81 RH5864.1 142.25,80.91 142.01,80.66 141.54,80.66 140.96,80.08 140.21,80.08 139.81,80.47 139.41,80.47 QH1.3 ; 134.99,79.2 133.91,80.28 RH5867.2 ; v2(16.74,70.27) PR112.2 ; v2(281.61,72.23) 280.86,71.48 RE56.1 280.86,70.03 281.13,69.77 286.21,69.77 286.6,70.16 286.6,71.68 RE52.1 ; PR1926.1 48.88,87.91 v2(48.97,88) ; v2(346.51,183.93) CE15.1 347.27,185.88 UE2.2 ; PR715.1 179.88,187.08 v2(179.88,186.71) ; v2(200.96,79.14) 200.96,78.54 193.56,71.14 v4(193.32,71.14) 189.53,71.14 ; RE3.1 330.24,174.69 v2(327.79,174.69) ; v2(149.58,70.88) 148.54,69.85 145.96,69.85 145.54,70.26 145.54,72.74 145.26,73.03 145.26,73.6 142.57,76.28 138.82,76.28 137.08,78.03 137.08,78.39 ; PR1643.1 245.67,172.76 v2(246.33,172.1) ; PR258.2 PR257.2 25.53,79.14 v2(26.95,80.56) ; v2(18.49,156.86) 18.9,156.46 PR101.1
  BOTTOM w0.203: PU900.15 238.42,179.46 238.18,179.22 PC912.1
  BOTTOM w0.254: UA3.4 2.1,78.33 1.49,77.72 1.49,77.22 v2(2.1,76.6) ; PC1612.1 245.67,169.78 245.48,169.97 245.48,170.38 245.32,170.54 PU1600.15 ; PU500.15 130.41,71.8 129.97,71.37 129.97,70.62 PC512.1 130.48,71.05 v2(130.48,71.19)
  BOTTOM w0.305: v2(174.83,77.54) 174.83,75.68 175.39,75.12 JAPS.3 ; JAPS.7 173.39,77.3 v2(173.13,77.56)
  BOTTOM w0.381: v2(17.2,120.31) 16.74,119.86 15.75,119.86 15.53,120.07 15.53,120.38 15.32,120.59 14.73,120.59 14.4,120.93 RT1095.1
  BOTTOM w0.457: v2(21.39,171.69) 19.57,171.69 18.99,171.1 UI4.5 17.59,171.1 17.5,171.01 CI21.1 ; v2(14.26,117.83) 13.93,117.83 CT189.1
  BOTTOM w0.508: v2(119.81,122.45) 119.92,122.45 120.23,122.14 120.98,122.14 126.33,116.79 v2(126.33,116.18) ; v2(110.03,133.57) PR806.1 PR805.1 ; PC1612.1 245.49,168.62 245.03,169.08 v2(245.03,169.44) ; PR818.1 v2(109.91,127.65) ; v2(237.67,179.34) 237.67,178.83 237.85,178.66 PC912.1 ; RI9.1 RI10.1 326.82,126.43 326.82,125.72 v2(326.72,125.62) ; v2(246.33,172.1) 246.79,172.1 247.27,171.62 PR1606.1 ; PR909.1 240.54,177.11 v2(240.46,177.03) ; v2(324.24,109.42) RI30.1 ; PR500.1 135.79,71.14 v2(135.99,70.94) ; v2(21.64,164.15) RI5.1 20.6,164.15 20.18,164.57 20.18,165.46 20.78,166.06 RI4.1 ; v2(74.2,68.23) 74.22,68.2 RZ38.2 ; RE141.1 149.81,71.47 149.58,71.24 v2(149.58,70.88) ; RI31.1 RE275.2 v2(330.02,110.05) ; PR809.2 102.67,130.96 v2(102.79,131.08)
  vias: v2(8.72,71.98) v2(14.26,118.55) v2(54.7,73.61) v2(54.7,73.02) v2(64.09,71.9) v2(64.15,85.85) v2(64.73,85.85) v2(65.89,98.31) v2(66.48,98.31) v2(79,98.47) v2(79.58,98.48) v2(126.33,91.97) v2(135.17,78.48) v2(177.84,76.75) v2(178.44,76.75) v2(179.04,76.75) v2(179.63,76.75) v2(252.06,109.81) v2(254.72,85.81) v2(255.02,85.31) v2(255.31,85.81) v2(260.5,107.61) v2(260.96,107.21) v2(260.96,106.62) v2(272.85,79.27) v2(274.12,77.49) v2(274.12,76.85) v2(274.75,78.12) v2(274.75,77.49) v2(274.75,76.85) v2(319.34,94.79) v2(319.41,94.2) v2(319.69,95.33) v2(319.71,93.69) v2(319.99,94.36) v2(320.17,94.99) v2(320.3,95.75) v2(320.41,93.89) v2(320.77,94.96) v2(320.91,94.34) v2(320.92,95.54) v2(320.98,93.74) v2(322.5,119.78) v2(336.52,168.17) v2(336.52,167.58) v2(336.84,168.84) v2(338.12,124.43) v2(338.12,123.82) v2(338.86,155.34) v2(339.16,154.17) v2(339.72,154.69) v4(64.57,98.44) v4(136.45,78.89)
+3VALW_5105: length 53.5
  TOP w0.254: UE3.G8 296.3,82.44 293.19,82.44 292.81,82.06 UE3.B7 292.32,81.66 291.79,81.66 291.59,81.86 290.48,81.86 290.16,81.53 290.16,80.83 v2(290.25,80.74) ; UE3.M9 300.74,83.66 301.11,84.03 302.8,84.03 v2(303.31,83.53) ; RP19.8 281.66,78.01 v2(281.42,78.25) 281.68,78.51 RP19.7
  TOP w0.305: v2(299.54,77.65) UE3.K2 ; UE3.H1 297.52,76.87 297.92,76.47 297.92,75.95 298.28,75.59 298.28,73.81 CE20.1
  TOP w0.381: CE24.1 303.64,85.3 303.34,84.99 303.34,84.88 303.31,84.85 v2(303.31,83.53) ; RH5861.1 297.41,72.28 v2(297.97,72.84) ; CE26.1 289.97,80.87 290.09,80.74 v2(290.25,80.74) ; v2(287.53,89.63) 287.55,89.6 RE25.2
  TOP w0.406: v2(294,75.12) 294.05,75.12 294.74,74.43 CE25.1
  TOP w0.457: v2(293.49,72.78) 293.49,72.81 293.69,73.01 293.69,73.31 RE72.1 ; RE295.2 286.89,81.2 v2(286.89,81.65) 286.89,82.03 RE296.2 ; RE66.1 v2(300.38,72.75)
  TOP w0.508: RE307.2 268.07,88.81 v2(267.74,89.14) ; RE41.1 305.56,87.84 305.75,87.65 v2(305.75,87.22) ; RE59.1 295.1,92.47 v2(294.73,92.84) 294.18,93.39 RE20.2 ; RE293.2 RE294.2 RE145.1 v2(292.28,72.89) ; RE19.2 305.82,90.44 v2(305.97,90.59) ; v2(281.74,75.14) RE94.2 ; RE301.1 v2(276.25,78) ; RE21.2 294.54,90.01 RE99.2 294.94,90.46 v2(294.68,90.73) ; v2(295.43,70.74) 293.84,70.74 RE283.2 RE284.2 ; v2(305.88,77.86) 305.86,77.86 305.74,77.74 RE22.2 RE23.2 ; RE298.1 v1(299.2,96.79) 297.61,95.2 297.61,93.49 RE68.1 298.34,93.2 298.34,93.79 v2(298.37,93.82) ; CE20.1 297.97,73.5 v2(297.97,72.84) ; RE67.2 299.52,90.49 v2(299.31,90.7) ; RE71.1 301.71,90.17 v2(301.71,91.08) ; v2(283.26,76.47) 283.82,75.91 RE95.2 ; v2(305.12,74.39) CE27.1
  vias: v2(306.57,83.58) v2(308.79,79.82) v2(309.18,94.47) v2(309.88,94.48) v2(310.48,94.51)
+3VALW_5105_VTR_PLL: length 5.1
  TOP w0.254: 295.78,75.71 295.92,75.85 UE3.F1
  TOP w0.381: 295.78,75.71 CE19.1 296.01,73.93 CE18.1 RH5861.2
+3VALW_KB: length 3.4
  TOP w0.508: v2(160.29,76.27) 160.29,75.86 160.47,75.68 v4(160.5,75.68) 160.55,75.62 161.67,75.62 RZ1138.2
  BOTTOM w0.305: v2(160.29,76.27) 160.06,76.49 JKB.3
+3VALWP: length 9
  TOP w0.254: v2(346.63,90.76) PR401.1
  BOTTOM w0.254: PC401.1 346.65,90.75 v2(346.63,90.76) 347.33,91.46 347.33,92.86 347.01,93.17 344.84,93.17 343.27,91.6 PR428.1
  vias: v2(323.71,91.52) v4(325.76,95.58)
+3VLP: length 14.9
  TOP w0.508: RE43.2 291.39,70.71 v2(291.39,69.79) ; RE304.1 279.2,79.35 279.6,78.96 v1(279.6,77.7) 279.6,76.96 280.23,76.33 280.23,74.76 280,74.54 280,74.54 279.45,74 D322.2 279.45,73.53 279.79,73.53 280.28,73.04 280.28,72.22 280.16,72.1 280.16,71.2 278.94,69.98 v2(277.33,69.98)
  BOTTOM w0.254: v2(347.33,89.74) 346.76,89.17 PR400.1
+3VLP_EC: length 10.3
  TOP w0.14: RE44.1 292.25,70.76 RE43.1 291.36,71.8 291.65,72.08 291.65,72.81 291.45,73.01 290.03,73.01 289.73,73.31 v1(289.73,74.53) 291.12,75.92 291.79,75.92 292.72,76.85 UE3.B1
+3VLP_P: length 2.5
  TOP w0.14: v1(279.48,76.24) 279.45,76.22 D322.1 278.84,75.23 278.56,74.95 RH590.2
+3VS: length 176.4
  TOP w0.356: RH5840.2 77.46,77.68 78.09,77.04
  TOP w0.381: RE81.1 v2(99.68,103.18) ; v2(197.9,186.58) 196.94,186.58 PR703.1 ; RE100.1 95.85,99.89 96.23,99.51 v2(96.73,99.51) ; RE137.1 285.6,74.06 QE18.2 284.41,74.06 284.16,74.31 v2(283.94,74.31) 283.7,74.31 283.44,74.06 QE18.5
  TOP w0.457: RE136.1 281.76,75.86 281.76,76.32 v2(281.58,76.5)
  TOP w0.508: 152.23,84.66 151.99,84.42 151.28,84.42 150.7,85.01 RD3.1 ; 152.23,84.66 152.23,84.6 152.6,84.23 157.43,84.23 160.1,81.57 v2(160.1,78.86) ; 152.23,84.66 v2(152.23,85.07) ; v2(80.63,68.19) 80.2,68.63 80.2,68.89 79.35,69.74 79.31,69.74 79.31,69.75 78.81,69.75 78.81,69.74 78.77,69.74 78.46,69.44 77.3,69.44 76.39,70.35 76.39,71.27 76.89,71.76 76.89,73.07 ; RE129.1 157.7,78.86 v2(158.88,78.86) ; 240,83.37 226.25,83.37 RD6.1 ; v2(208.41,111.5) 207.56,110.65 202.73,110.65 RV658.1 ; v2(111.05,168.55) 111.05,168.98 PR1117.1 ; v2(62.37,71.09) 62.37,71.08 62.48,71.08 63.11,70.45 RH572.2 ; v2(185.22,181.5) 186.92,181.5 PR705.2 ; v2(237.95,108.56) 238.09,108.56 238.68,109.16 238.68,109.59 RV1133.2 239.43,110.34 239.43,111.65 RF1.1 ; 99.65,75.05 99.46,74.85 98.38,74.85 98.13,75.1 97.26,75.1 RH569.2 ; v2(119.76,120.98) 119.61,120.98 119.16,121.43 RH525.1 ; v2(23.57,131.11) 23.67,131.21 RM15.2 ; v2(286.56,74.13) 286.54,74.15 286.16,74.15 285.93,74.38 RE137.1 ; CD34.1 CD35.1 248.48,92.68 v2(248.07,93.09) ; PR609.1 289.8,94.57 289.99,94.38 291.11,94.38 v2(291.81,95.07) ; PR951.1 245.34,182.65 245.47,182.52 v2(247.14,182.52) ; 101.59,75.85 103.34,74.1 RH562.1 RH561.1 103.34,70.52 102.06,69.24 v2(101.59,69.24) 101.46,69.11 RH563.1 ; RF3.1 v2(236.21,112.21) ; v2(99.68,103.18) 103.23,106.72 103.23,108.36 101.51,110.08 101.51,117.77 102.28,118.54 108.11,118.54 109.25,119.68 111.08,119.68 111.58,120.19 v2(111.58,120.38)
  BOTTOM w0.305: v2(158.88,78.86) 158.88,78.75 159.56,78.06 JKB.4 ; JDIMM1.255 170.65,95.56 170.65,95.81 v2(170.52,95.94) ; 246.94,94.54 246.94,93.43 247.28,93.09 v2(248.07,93.09)
  BOTTOM w0.356: v2(331.25,117.98) 331.3,117.92 RE101.1 ; v2(101.4,77.11) 100.75,77.11 RH1146.2 RH91.1
  BOTTOM w0.381: 66.66,82.12 65.74,82.12 65.05,81.44 RH527.2 ; 66.66,82.12 66.66,82.92 67.23,83.5 68.39,83.5 RH512.2 ; 66.66,82.12 RH510.2 ; PR1522.2 188.95,186.17 v2(189.22,186.17) ; PR1019.2 170.91,180.7 171.09,180.51 171.48,180.51 172.11,181.15 172.11,181.93 v2(172.75,182.58) ; v2(331.25,117.98) 328.98,117.98 327.53,116.53 327.53,114.47 328.68,113.33 330.06,113.33 331.06,114.33 RE83.1 ; v2(105.48,77.05) 105.68,76.85 QH4.5 ; UH14.5 59.86,70.13 60,69.98 60.17,69.98 v2(60.18,69.97)
  BOTTOM w0.457: DV12.5 54.27,95.77 54.76,96.26 v2(54.76,96.49) ; v2(121.91,161.34) 120.98,161.34 RH5.1
  BOTTOM w0.508: v2(264.87,70.04) 264.87,70.28 265.52,70.93 270.59,70.93 270.91,70.6 277.8,70.6 278.43,69.97 286.09,69.97 286.55,70.43 286.55,70.76 ; v2(253.55,70.5) 253.77,70.5 254.04,70.77 RD10.1 ; RH527.2 64.5,83.92 v2(65.61,85.02)
  vias: v2(13.65,110.97) v2(13.65,110.28) v2(47.87,89.64) v2(48.46,89.64) v2(66.12,84.58) v2(68.8,88.02) v2(85.39,68.66) v2(87.27,69.6) v2(92.38,95.15) v2(93.03,95.26) v2(103.09,95.7) v2(103.11,94.81) v2(103.64,95.28) v2(108.93,77.2) v2(118.05,158.05) v2(167.69,85.11) v2(168.31,85.1) v2(239.81,85.04) v2(240.39,85.04) v2(241.35,108.98) v2(242.11,85.03) v2(250.48,90.98) v2(250.48,90.29) v2(254.81,109.49) v2(254.81,108.86) v2(255.32,109.17) v2(297.99,98.44) v2(298.59,98.46) v2(304.98,100.86) v2(305.61,100.86) v2(321.61,110.38) v2(321.61,109.75) v2(347.01,104.06) v2(347.01,103.46) v4(66.5,86.43)
+3VS_AUDIO: length 1.5
  BOTTOM w0.381: RA82.1 2.73,112.22 2.84,112.34 v1(2.84,112.87) v2(2.84,113.43)
  vias: v2(2.2,94.89) v2(2.2,94.3) v2(10.34,74.49) v2(10.34,73.91) v2(12.83,83) v2(13.41,83)
+3VS_CAM: length 8.1
  BOTTOM w0.254: JEDP1.22 54.99,101.24 v2(54.91,101.16)
  BOTTOM w0.508: v2(53.39,99.08) 53.39,98.3 v1(53.09,98) 53.09,96.92 CV183.1 52.93,95.98 52.81,95.85 CZ44.1 51.47,95.85 CV184.1 50.99,95.84 50.9,95.93 RZ37.2
+3VS_CAM_R: length 5.4
  BOTTOM w0.14: v1(54.46,92.69) 54.39,92.63 QZ9.1
  BOTTOM w0.508: RZ37.1 50.34,93.75 51.46,92.63 QZ9.1
+3VS_CR: length 2.2
  BOTTOM w0.203: 334.51,103.14 334.71,103.14 335.25,103.69 UR1.11
  BOTTOM w0.457: 334.51,103.14 333.68,103.14
  vias: v1(344.67,101.62) v2(330.02,104.41) v2(330.02,103.83) v2(344.41,102.82) v2(344.41,102.13)
+3VS_CT2: length 1.8
  TOP w0.14: UZ1.10 257.78,106.01 256.84,106.95 CZ6.1
+3VS_DTH: length 14.5
  TOP w0.254: RM16.1 23.47,134.23 23.47,133.19 23.8,132.86 ; RM20.1 22.77,131.62 22.19,132.2 21.73,132.2 21.59,132.34 20.97,132.34 20.14,133.17 RM6.1
  TOP w0.356: RM7.1 24.99,161.89 24.43,162.45 v1(22.12,162.45) v2(21.51,162.45)
  TOP w0.381: v2(26.36,144.77) 26.36,144.89 25.86,145.39 25.35,145.39 24.99,145.03 RM5.2 ; RM20.1 23.2,131.82 23.65,131.82 24.05,132.23 24.05,132.61
  vias: v2(26.26,135.4)
+3VS_FFS: length 3
  TOP w0.254: UF1.9 233.09,114.69 v2(232.84,114.45) 233.1,114.19 UF1.10 ; UF1.2 235.37,114.69 v2(235.64,114.95) 235.4,115.19 UF1.3
  vias: v1(237.35,114.09) v2(237.54,114.57) v2(238.09,114.34)
+3VS_FP: length 3.9
  TOP w0.14: v2(311.84,99.08) v4(311.01,99.9)
  BOTTOM w0.14: Q6.2 309.88,99.97 311.84,99.97
+3VS_FP_R:
  vias: v4(315.14,93.36)
+3VS_TP: length 27.6
  TOP w0.254: RE9.2 194.26,80.77 194.63,80.4 QE2.5
  TOP w0.381: QE2.2 194.63,78.49 194.4,78.72 v2(194.4,79.1) 194.4,79.21 194.63,79.44 QE2.5
  BOTTOM w0.508: JTP.8 183.76,76.95 183.27,76.46 183.27,75.13 183.54,74.86 186.07,74.86 v2(187.38,73.55) 187.73,73.55 191.82,77.64 193.56,77.64 194.4,78.48 v2(194.4,79.1) 194.4,80.17 193.52,81.04 RE24.1 ; RE26.1 188.7,81.04 188.42,80.76 188.42,79.22 v2(188.52,79.11)
  vias: v1(188.9,76.6)
+3VS_TPM_VHIO: length 27.7
  TOP w0.14: v2(155.52,76.01) 155.52,75.51 v1(155.63,75.41)
  TOP w0.254: U32.22 148.84,73.69 148.56,73.41 v2(148.28,73.41) ; U32.8 155.4,76.19 155.52,76.06 v2(155.52,76.01)
  TOP w0.381: v2(148.28,73.41) 147.91,73.04 147.83,73.04 CE85.1 147.57,72.79 CE84.1
  TOP w0.508: v2(155.52,76.01) 156.11,76.01 CE75.1 156.32,76.23 156.32,76.61 155.94,76.99 CE76.1 RE129.2
  BOTTOM w0.508: v2(155.52,76.01) 156.24,76.01 157.56,74.7 157.56,71.06 156.39,69.89 150.07,69.89 149.79,69.61 148.75,69.61 148.28,70.09 v2(148.28,73.41)
+3VS_TPM_VSB: length 10.4
  TOP w0.127: v2(156.26,71.52) v1(156.26,70.95)
  TOP w0.254: U32.1 156.28,72.69 CE11.1
  TOP w0.381: v2(156.26,71.52) 156.26,72.14 156.31,72.19 CE11.1
  BOTTOM w0.508: v2(156.26,71.52) 151.87,71.52 RE141.2 CE83.1
+3VS_TS: length 8
  BOTTOM w0.14: 342.25,128.1 342.95,128.8 344.79,128.8 v1(345.05,129.05)
  BOTTOM w0.381: v2(339.14,113.05) 339.39,112.79 RH5891.2
  BOTTOM w0.508: RC184.1 RC183.1 v2(339.08,108.48) ; JTS1.1 C3004.1 343.71,113.1 RC5835.1
  vias: v2(342.04,125.88) v2(342.75,125.9) v2(347.78,126.76)
+3VS_VDD: length 8.7
  TOP w0.203: 201.6,119.21 200.84,119.21 200.33,118.7 CE3323.1
  TOP w0.508: RV658.2 200.03,113.34 200.03,115.38 v1(200.05,115.4) 200.05,117.79 200.27,118 200.27,118.62 CE3323.1
+3VS_WLAN: length 2.7
  TOP w0.14: 333.17,169.12 332.36,169.93 v1(332.36,171.48)
  vias: v2(328.6,162.41) v2(328.6,161.75) v2(328.6,160.98) v2(343.13,156.21) v2(343.23,155.58) v2(343.81,156.22) v2(343.83,155.6) v4(332.71,163.26) v4(343.12,158.7) v4(343.52,156.74)
+5V_CHGUSB_1: length 3.8
  BOTTOM w0.127: CI17.1 329.2,137.32 327.52,138.99 v4(327.52,139.82)
  vias: v2(329.77,135.65) v2(329.77,135.06) v2(329.76,134.47) v2(329.76,133.89) v2(329.76,133.31)
+5V_CHGUSB_2: length 0.6
  TOP w0.127: v2(25.1,168.68) v4(24.49,168.68)
  vias: v2(16.78,174.52) v2(16.97,175.89) v2(17.36,174.55) v2(17.94,174.54) v2(18.52,174.54) v2(25.25,168.11) v2(25.54,167.56) v2(25.71,168.52) v2(25.96,167.99)
+5VALW: length 69.8
  TOP w0.127: v2(313.04,73.57) 312.38,74.23 v4(312.38,74.29) ; v2(25.45,121.43) v1(26.06,121.43)
  TOP w0.203: UA4.4 7.25,72.3 7.76,71.79 v2(7.76,71.72) ; v2(261.29,105.56) 261.23,105.61 UZ1.4
  TOP w0.254: UZ29.4 124.25,82.16 123.33,83.09 v2(121.74,83.09) ; v2(336.47,171.09) 336.43,171.05 UN3.4 ; v2(191.33,73.54) 191.33,73.19 190.87,72.73 UE6.4 ; CZ11.1 52.5,74.31 52.7,74.11 UZ4.4 ; UZ30.4 243.43,119.64 244.21,120.41 v2(248.08,120.41) ; v2(228.27,76.6) 228.96,75.91 UZ33.4 ; 188.77,109.37 188.26,108.86 185.85,108.86 185.16,109.55 UZ16.3
  TOP w0.305: UZ15.3 178.03,152.22 178.59,152.78 178.59,153.77 CZ97.1
  TOP w0.457: v2(26.11,163.11) 25.61,162.61 CI1.1
  TOP w0.508: v2(51.74,74.62) 52.2,75.08 CZ11.1 ; v2(286.56,94.44) 286.46,94.34 286.46,93.66 285.8,93 285.8,92.37 ; v2(177.63,153.24) 177.79,153.24 178.13,153.59 178.13,153.78 CZ97.1 ; PR700.2 185.33,178.25 182.76,178.25 v2(182.3,178.71) ; PR104.2 23.11,153.65 24.59,155.12 24.59,155.76 23.39,156.95 23.24,156.95 22.33,157.87 v2(21.31,157.87) ; LED3.2 v2(345.96,166.18) ; LED1.2 345.97,173.38 v2(345.95,173.41) ; LED2.2 v2(345.88,169.78) ; PR603.1 286.78,92.46 286.69,92.37 285.8,92.37 ; 188.77,109.37 189.53,110.13 189.53,112.63 188.36,113.81 187.09,113.81 184.51,116.39 v2(184.51,118.22) ; v2(285.81,92.36) 285.8,92.37 ; LED5.2 v2(345.87,158.98) ; PR1156.1 v2(111.18,182.14) ; LED4.2 v2(345.89,162.58) ; RV657.1 v2(245.52,113.81)
  BOTTOM w0.203: PU600.12 286.43,94.58 v2(286.56,94.44)
  BOTTOM w0.229: v2(22.38,125.52) 22.42,125.57 UT4.H10
  BOTTOM w0.254: UZ5.4 338.4,129.61 338.2,129.81 338.2,130.02 338.45,130.27 v2(338.71,130.27)
  BOTTOM w0.305: JKB.1 161.06,76.4 v2(160.94,76.28) ; CZ86.1 179.39,151.26 179.58,151.07 UZ9.3
  BOTTOM w0.508: v2(285.81,92.36) 285.81,92.47 285.93,92.6 PC607.2 ; v2(177.63,153.24) 177.79,153.24 178.32,152.71 178.32,151.75 178.8,151.26 CZ86.1
  vias: v2(8.01,70.61) v2(7.95,69.36) v2(8.02,69.99) v2(25.06,118.75) v2(25.06,118.13) v2(25.6,119.06) v2(25.6,118.48) v2(25.6,117.91) v2(26.03,164.72) v2(26.06,163.95) v2(26.2,119.06) v2(26.19,118.48) v2(26.2,117.91) v2(26.2,117.26) v2(26.48,164.36) v2(26.49,163.56) v2(29.38,78.64) v2(29.38,78) v2(29.38,77.37) v2(29.38,76.73) v2(29.38,76.08) v2(29.38,75.45) v2(29.38,74.82) v2(29.38,74.18) v2(29.38,73.55) v2(29.96,79.27) v2(29.96,78.64) v2(29.96,78) v2(29.96,77.37) v2(29.96,76.73) v2(29.96,76.08) v2(29.96,75.45) v2(29.96,74.82) v2(29.96,74.18) v2(29.96,73.55) v2(30.55,77.37) v2(30.55,76.73) v2(30.55,76.08) v2(30.55,75.45) v2(30.55,74.82) v2(31.13,77.37) v2(31.13,76.73) v2(31.13,76.08) v2(31.13,75.45) v2(31.77,76.73) v2(31.77,76.08) v2(32.4,76.73) v2(180.91,76.76) v2(188,126.65) v2(206.58,115.41) v2(207.18,115.21) v2(227.13,78.69) v2(227.76,78.69) v2(228.4,78.69) v2(245.54,113.18) v2(246.61,177.41) v2(247.26,160.9) v2(261.46,104.48) v2(261.49,103.85) v2(262.05,104.5) v2(262.08,103.87) v2(313.04,72.93) v2(313.04,72.27) v2(313.04,71.64) v2(313.04,70.98) v2(313.09,70.39) v2(313.14,69.8) v2(313.68,73.59) v2(313.68,72.96) v2(313.68,72.3) v2(313.68,71.66) v2(313.68,71) v2(313.72,70.41) v2(313.78,69.83) v2(314.29,73.58) v2(314.29,72.95) v2(314.29,72.29) v2(314.29,71.65) v2(314.29,70.99) v2(314.34,70.4) v2(314.39,69.82) v2(329.79,129.25) v2(329.78,126.31) v2(329.82,128.67) v2(329.82,128.08) v2(329.82,127.5) v2(329.84,126.9) v4(7.37,69.56) v4(227.38,77.74)
+5VALWP: length 58.5
  TOP w0.508: v2(347.32,86.12) PR402.2
  BOTTOM w0.254: v2(323.72,70.86) v2(323.72,70.25) 323.72,70.25 324.18,69.79 339.4,69.79 343.05,73.44 343.05,74.84 346.75,78.54 346.75,85.55 v2(347.32,86.12) 347.32,86.28 PC402.2
  BOTTOM w0.508: v2(339.65,87.14) 339.12,87.14 338.55,86.57 338.55,85.33 336.6,83.38 330.18,83.38 327.94,81.14 327.94,76.52 v2(328.67,75.79)
  vias: v1(324.58,70.45) v2(316.99,71.85) v2(317.02,71.19) v2(317.02,70.51) v2(317.58,72.41) v2(317.88,70.23) v2(318.31,72.41) v2(318.74,70.23) v2(318.9,72.41) v2(319.51,70.25) v2(319.76,72.41) v2(320.34,70.23) v2(320.68,72.41) v2(321.08,70.23) v2(321.56,72.41) v2(321.94,70.23) v2(322.53,72.41) v2(322.83,70.25) v2(323.42,72.38)
+5VS: length 67.8
  TOP w0.381: v2(106.1,181.12) 105.58,181.12 105.13,181.56 PR1153.2
  TOP w0.508: PR1146.1 v2(106.86,181.88) ; PR1200.1 129.65,185.5 v2(128.96,186.2) ; v2(230.67,111.25) 230.7,111.23 RF2.1 ; v2(101.57,107.57) 100.76,108.38 100.76,119.91 v2(99.24,121.43) ; v2(18.29,159.28) 18.49,159.07 v4(18.49,158.29) 18.06,157.85 17.25,157.85 16.87,158.23 UV16.1 v2(17.78,158.64) ; PC1216.1 129.15,183.41 v2(128.32,183.41) ; PC1229.1 137.66,183.47 v2(137.46,183.28) ; PC1271.1 154.04,183.34 v2(153.78,183.09) ; v2(160.76,78.87) 160.76,81.77 158.89,83.63 v2(158.89,85.06) ; PC1260.1 146.74,183.47 v2(146.35,183.09)
  BOTTOM w0.254: v2(128.96,186.2) 128.96,185.72 129.24,185.44 129.84,185.44 130.25,185.04 PU1200.2 ; v2(13.78,132.86) 13.68,132.96 13.41,132.96 13.25,132.8 UZ25.4 ; v2(101.52,160.99) PC1716.1 102.72,161.04 PU1701.15 ; PU1252.2 155.58,184.97 155.33,185.23 154.31,185.23 154.1,185.44 154.1,186.33 154.36,186.58 v2(154.86,186.58) ; PU1252.15 153.92,182.95 v2(153.78,183.09) ; PR1704.1 v2(101.52,162.13) ; v2(128.32,183.41) 128.59,183.14 PU1200.15 ; PU1251.15 146.49,182.95 v2(146.35,183.09) ; PU1201.2 139.26,185.04 138.93,185.37 138.67,185.37 138.48,185.57 138.48,186.45 138.73,186.71 v2(139.24,186.71) ; v2(147.37,186.58) 146.86,186.58 146.61,186.33 146.61,185.44 146.86,185.18 147.88,185.18 148.15,184.91 PU1251.2 ; PC1707.1 111.49,138.51 110.91,139.09 PU1700.15 ; PU1700.2 109,137.07 109.27,136.8 110.29,136.8 111.24,135.84 PR1700.1
  BOTTOM w0.305: v2(137.46,183.28) 137.6,183.14 PU1201.15 ; JKB.2 160.56,78.16 160.76,78.35 v2(160.76,78.87)
  BOTTOM w0.508: PC1707.1 111.49,137.5 112.32,136.67 v2(112.32,136.16) ; PR1255.1 v2(154.86,186.58) ; v2(189.23,185.57) 189.55,185.57 190.06,186.07 190.11,186.07 ; PR1204.1 v2(139.24,186.71) ; PR1700.1 111.75,135.84 v2(112.32,135.27) ; PR1251.1 v2(147.37,186.58)
  vias: v2(10.23,129.03) v2(10.25,128.4) v2(21.86,97.36) v2(22.45,97.36) v2(51.93,98.32) v2(52.5,98.32) v2(84.02,103.23) v2(84.45,103.71) v2(102.25,107.46) v2(118.39,103.9) v2(128.27,96.79) v2(164.44,176.32) v2(165.07,176.32) v2(241.8,104.92) v2(241.8,104.29) v2(242.43,104.92) v2(242.43,104.29) v2(254.66,104.72) v2(254.71,104.13) v2(255.02,103.55) v2(255.44,88.64) v2(255.72,103.54) v2(255.82,102.94) v2(255.92,89.41) v2(256.37,89.77) v2(303.45,98.94) v2(304.13,98.97) v2(329.53,116.68) v2(329.53,116.09)
+5VS_AUDIO: length 1.1
  TOP w0.14: v4(4.89,74.03) 4.99,74.14 4.99,75.09
  vias: v2(2.75,76.18) v2(3.36,76.18) v2(12.01,105.1) v2(12.12,104.4)
+5VS_AUDIO_PVDD1: length 1.1
  BOTTOM w0.14: LA3.1 v1(14.03,106.61)
+5VS_AUDIO_PVDD2: length 0.9
  TOP w0.14: v1(9.22,103.37) 9.37,103.52 LA1.1
  vias: v2(11.1,104.92)
+5VS_CT1: length 1.6
  TOP w0.14: UZ1.12 257.43,105.21 257.43,105.22 CZ4.1
+5VS_HDD: length 10.1
  TOP w0.203: v4(230.94,79.01) 230.94,78.76 231.83,77.87 ; v2(236.52,78.68) 236.52,80.16 v4(236.4,80.28)
  TOP w0.254: v4(235.25,82.06) 235.64,81.68 235.64,79.9 235.25,79.52 235.25,78.74 v2(235.31,78.68) ; CS14.1 236.45,77.56 236.91,77.11 v4(239.19,77.11)
  vias: v2(235.91,78.68)
+AVDD1: length 1.7
  TOP w0.14: LA2.2 12.18,107.96 13.23,107.96 v1(13.58,108.3)
  vias: v2(10.73,107.44)
+AVDD2: length 1.7
  TOP w0.508: v2(0.56,100.98) 0.67,100.87 RA2.2
  vias: v1(1.93,107.1) v2(2.08,106.32)
+DVDD: length 8
  BOTTOM w0.305: RA15.1 8.94,99.38 v2(9.09,99.23)
  BOTTOM w0.356: RA12.1 13.49,103.01 v1(12.96,102.49) 12.52,102.04 12.52,101.83 11.8,101.11 11.18,101.11 9.92,99.85 RA15.1
  BOTTOM w0.381: RA13.1 4.76,99.93 4.31,99.48 v2(4.31,99.35)
  vias: v2(3.85,94.11) v2(3.82,93.52) v2(6.82,101)
+DVDDIO: length 9.7
  TOP w0.508: v2(1.51,104.22) 1.8,104.22 3.19,102.84 CA40.1 4.39,102.24 v1(4.39,100.64) CA39.1 3.4,99.05 2.73,98.38 2.73,97.56 2.41,97.25 RA18.1
+VBUS_1: length 5
  TOP w0.508: v2(59.94,87.51) 59.94,87.75 61.11,88.92 61.11,90.54 PD204.2
  BOTTOM w0.229: UT4.B10 UT4.A10 22.88,121.68 v2(23.03,121.53)
  vias: v2(6.51,131.8) v2(6.6,134.33) v2(7.13,134.64) v2(7.12,131.58) v2(7.59,135.02) v2(7.65,131.26) v2(10.02,132.1) v2(10.59,132.35) v2(10.59,131.78) v2(10.59,131.21) v2(11.23,131.65) v2(11.23,131.08) v2(24.26,126.28) v2(26.29,134.66) v2(26.29,134.08) v2(26.29,133.5) v2(26.29,132.91) v2(26.29,132.33) v2(26.29,131.76) v2(26.3,131.18) v2(26.3,130.6) v2(28.51,92.92) v2(28.54,93.58) v2(29.1,92.34) v2(29.13,93.56) v2(29.12,92.93) v2(29.41,95.4) v2(29.41,94.79) v2(29.4,94.15) v2(29.71,92.42) v2(29.72,93.6) v2(29.72,93) v4(30.05,97.34)
+VBUS_DC_SS:
  vias: v1(19.88,92.07)
+VCC0V9_CIO: length 3
  TOP w0.089: v1(31.23,108.16) 31,108.39 v2(30.49,108.39)
  TOP w0.381: CT101.1 29.64,110.13 30.09,109.68 CT103.1 30.09,108.88 CT102.1 30.06,108.82 v2(30.49,108.39)
  vias: v2(25.77,106.92) v2(26.42,108.22)
+VCC0V9_DP:
  vias: v1(24.88,108.29) v2(24.49,108.87) v2(24.47,106.92) v2(25.12,108.87) v2(27.07,106.92) v2(27.07,106.27)
+VCC0V9_PCIE:
  vias: v1(24.9,102.96) v2(24.47,105.62) v2(24.47,104.97) v2(24.47,104.32) v2(24.47,103.67) v2(25.12,103.67)
+VCC0V9_USB: length 1.6
  TOP w0.381: v2(26.42,104.97) 26.42,104.29 CT94.1 26.31,103.92 CT93.1
+VCC_CORE: length 4
  BOTTOM w0.508: RH197.1 141.69,162.07 142.2,162.58 142.92,162.58
  vias: v2(132.46,171.96) v2(132.46,171.38) v2(132.46,170.79) v2(132.46,170.21) v2(132.46,169.63) v2(133.07,171.96) v2(133.07,171.38) v2(133.07,170.79) v2(133.07,170.21) v2(133.07,169.63) v2(133.65,169.66) v2(134.24,169.66) v2(134.82,169.66) v2(135.41,169.66) v2(135.99,169.66) v2(136.58,169.66) v2(136.87,169.17) v2(137.16,169.66) v2(137.16,168.67) v2(137.45,171.15) v2(137.45,170.16) v2(137.45,169.17) v2(137.45,168.18) v2(137.74,171.65) v2(137.74,170.66) v2(137.74,169.66) v2(137.74,168.67) v2(138.04,171.15) v2(138.04,170.16) v2(138.04,169.17) v2(138.04,168.18) v2(138.33,171.65) v2(138.33,170.66) v2(138.33,169.66) v2(138.33,168.67) v2(138.62,171.15) v2(138.62,170.16) v2(138.62,169.17) v2(138.62,168.18) v2(138.91,171.65) v2(138.91,170.66) v2(138.91,169.66) v2(138.91,168.67) v2(139.2,171.15) v2(139.2,170.16) v2(139.2,169.17) v2(139.2,168.18) v2(139.5,171.65) v2(139.5,170.66) v2(139.5,169.66) v2(139.5,168.67) v2(139.79,171.15) v2(139.79,170.16) v2(139.79,169.17) v2(139.79,168.18) v2(140.08,171.65) v2(140.08,170.66) v2(140.08,169.66) v2(140.08,168.67) v2(140.37,171.15) v2(140.37,170.16) v2(140.37,169.17) v2(140.37,168.18) v2(140.67,171.65) v2(140.67,170.66) v2(140.67,169.66) v2(140.67,168.67) v2(140.96,169.17) v2(140.96,168.18) v2(141.25,168.67) v2(141.54,169.17) v2(141.54,168.18) v2(141.83,168.67) v2(142.19,169.31) v2(142.19,168.14) v2(142.77,169.31) v2(142.77,168.72) v2(142.77,168.14) v2(143.36,169.31) v2(143.36,168.72) v2(143.36,168.14) v2(143.97,169.31) v2(143.97,168.72) v2(143.97,168.14) v2(144.58,169.31) v2(144.58,168.72) v2(144.58,168.14) v2(145.16,170.48) v2(145.16,169.89) v2(145.16,169.31) v2(145.16,168.72) v2(145.16,168.14) v2(145.77,170.48) v2(145.77,169.89) v2(145.77,169.31) v2(145.77,168.72) v2(145.77,168.14) v2(146.38,170.48) v2(146.38,169.89) v2(146.38,169.31) v2(146.38,168.72) v2(146.38,168.14) v2(146.96,170.48) v2(146.96,169.89) v2(146.96,169.31) v2(146.96,168.72) v2(146.96,168.14) v2(147.57,170.48) v2(147.57,169.89) v2(147.57,169.31) v2(147.57,168.72) v2(147.57,168.14) v2(148.18,171.65) v2(148.18,171.06) v2(148.18,170.48) v2(148.18,169.89) v2(148.18,169.31) v2(148.18,168.72) v2(148.18,168.14) v2(148.77,169.31) v2(148.77,168.72) v2(148.77,168.14) v2(149.38,169.31) v2(149.38,168.72) v2(149.38,168.14) v2(149.99,169.31) v2(149.99,168.72) v2(149.99,168.14) v2(150.57,169.31) v2(150.57,168.72) v2(150.57,168.14) v2(151.18,169.31) v2(151.18,168.72) v2(151.18,168.14) v2(151.56,167.45) v2(151.56,166.87) v2(151.56,166.29) v2(151.55,154.5) v2(151.57,153.86) v2(151.59,153.23) v2(151.6,152.57) v2(151.59,151.93) v2(151.59,151.28) v2(151.59,149.98) v2(151.57,149.31) v2(151.7,135.07) v2(151.79,169.31) v2(151.79,168.72) v2(151.79,168.14) v2(152.15,167.45) v2(152.15,166.87) v2(152.15,166.29) v2(152.4,169.31) v2(152.4,168.72) v2(152.4,168.14) v2(152.33,154.5) v2(152.35,153.87) v2(152.39,153.26) v2(152.38,152.58) v2(152.39,151.92) v2(152.38,151.28) v2(152.37,150.62) v2(152.38,149.98) v2(152.36,149.34) v2(152.61,135.07) v2(152.63,135.78) v2(152.73,167.45) v2(152.73,166.87) v2(152.73,166.29) v2(152.74,139.78) v2(152.72,139.17) v2(152.78,137.9) v2(152.76,137.32) v2(153.01,170.48) v2(153.01,169.89) v2(153.01,169.31) v2(153.01,168.72) v2(153.01,168.14) v2(153.15,154.47) v2(153.17,153.84) v2(153.16,151.93) v2(153.15,151.3) v2(153.16,149.33) v2(153.16,148.69) v2(153.31,167.54) v2(153.31,166.96) v2(153.36,144.76) v2(153.34,144) v2(153.37,143.16) v2(153.42,140.97) v2(153.45,139.78) v2(153.44,139.17) v2(153.45,137.91) v2(153.43,137.33) v2(153.51,135.06) v2(153.62,171.65) v2(153.62,171.06) v2(153.62,170.48) v2(153.62,169.89) v2(153.62,169.31) v2(153.62,168.72) v2(153.62,168.14) v2(153.65,146.41) v2(153.9,167.54) v2(153.9,166.96) v2(153.94,154.48) v2(153.96,153.85) v2(153.94,153.24) v2(153.94,152.59) v2(153.94,151.94) v2(153.97,151.29) v2(153.97,150.63) v2(153.92,149.97) v2(153.94,149.34) v2(153.96,148.66) v2(154.11,146.88) v2(154.11,143.15) v2(154.14,144.79) v2(154.12,144.03) v2(154.13,140.97) v2(154.23,171.65) v2(154.23,171.06) v2(154.23,170.48) v2(154.23,169.89) v2(154.23,169.31) v2(154.23,168.72) v2(154.23,168.14) v2(154.48,167.54) v2(154.48,166.96) v2(154.71,153.23) v2(154.75,152.57) v2(154.73,150.61) v2(154.84,171.65) v2(154.84,171.06) v2(154.84,170.48) v2(154.84,169.89) v2(154.84,169.31) v2(154.84,168.72) v2(154.84,168.14) v2(155.07,167.54) v2(155.07,166.96) v2(155.45,171.65) v2(155.45,171.06) v2(155.45,170.48) v2(155.45,169.89) v2(155.45,169.31) v2(155.45,168.72) v2(155.45,168.14) v2(155.51,151.92) v2(155.51,151.27) v2(155.51,150.62) v2(155.47,146.98) v2(155.45,136.75) v2(155.52,149.96) v2(155.52,149.31) v2(155.52,148.7) v2(155.65,167.54) v2(155.65,166.96) v2(156.06,171.65) v2(156.06,171.06) v2(156.06,170.48) v2(156.06,169.89) v2(156.06,169.31) v2(156.06,168.72) v2(156.06,168.14) v2(156.24,167.45) v2(156.24,166.87) v2(156.24,166.29) v2(156.67,169.31) v2(156.67,168.72) v2(156.67,168.14) v2(156.82,167.45) v2(156.82,166.87) v2(156.82,166.29) v2(157.1,151.93) v2(157.1,150.62) v2(157.2,143.68) v2(157.2,137.13) v2(157.15,136.54) v2(157.28,169.31) v2(157.28,168.72) v2(157.28,168.14) v2(157.23,144.95) v2(157.21,144.31) v2(157.4,167.45) v2(157.4,166.87) v2(157.4,166.29) v2(157.79,154.97) v2(157.76,136.95) v2(157.89,169.31) v2(157.89,168.72) v2(157.89,168.14) v2(157.89,153.23) v2(157.89,152.58) v2(157.89,151.93) v2(157.89,151.28) v2(157.88,149.96) v2(157.88,149.31) v2(157.99,167.45) v2(157.99,166.87) v2(157.99,166.29) v2(158.38,154.73) v2(158.5,169.31) v2(158.57,166.87) v2(158.57,166.29) v2(158.67,153.94) v2(158.67,153.23) v2(158.67,152.58) v2(158.67,151.93) v2(158.67,151.28) v2(159,154.77) v2(159.11,169.31) v2(159.03,135.76) v2(159.03,135.05) v2(159.23,154.2) v2(159.44,153.23) v2(159.48,152.56) v2(159.47,151.91) v2(159.45,149.96) v2(159.45,149.33) v2(159.45,139.97) v2(159.57,146.46) v2(159.56,137) v2(159.64,154.77) v2(159.71,141.67) v2(159.89,135.07) v2(160,135.85) v2(160.05,139.98) v2(160.27,154.77) v2(160.3,141.68) v2(160.24,136.98) v2(160.63,154.14) v2(160.67,146.47) v2(160.68,140) v2(160.91,154.77) v2(160.85,144.86) v2(160.85,144.22) v2(160.85,143.59) v2(160.85,142.95) v2(160.82,142.32) v2(160.84,135.07) v2(161.54,154.77) v2(161.55,144.88) v2(161.55,144.24) v2(161.55,143.61) v2(161.55,142.97) v2(161.53,142.34) v2(161.63,154.01) v2(161.81,152.56) v2(161.81,151.3) v2(161.72,135.82) v2(161.83,150.62) v2(162.18,154.77) v2(162.19,144.84) v2(162.19,144.2) v2(162.19,143.57) v2(162.19,142.93) v2(162.16,142.3) v2(162.61,148.69) v2(162.69,135.73) v2(162.81,154.77) v2(163.12,154.09) v2(163.45,154.78) v2(163.47,146.44) v2(163.78,154.09) v2(163.8,139.98) v2(164.13,154.81) v2(164.19,153.21) v2(164.19,152.54) v2(164.18,151.91) v2(164.19,151.27) v2(164.21,150.62) v2(164.38,141.65) v2(164.34,136.97) v2(164.44,146.44) v2(164.45,139.95) v2(164.52,135.73) v2(164.76,136.37) v2(164.82,154.81) v2(164.96,151.94) v2(164.95,151.28) v2(164.98,148.68) v2(164.96,136.98) v2(165.09,139.95) v2(165.18,154.08) v2(165.21,141.55) v2(165.35,135.73) v2(165.5,146.47) v2(166.33,135.07) v2(166.7,136.31) v2(167.29,135.86) v2(167.22,135.05) v2(167.34,153.89) v2(167.35,152.58) v2(167.32,149.98) v2(167.35,149.33) v2(167.84,136.64) v2(168.06,135.84) v2(168.1,135.07) v2(169.08,135.79) v2(170.08,134.86) v4(140.16,166.48)
+VCCGT: length 2.9
  BOTTOM w0.508: 130.8,159.12 130.8,161.69 RH203.1
  vias: v2(114.3,146.53) v2(114.3,145.94) v2(114.3,145.36) v2(114.3,144.42) v2(114.3,143.83) v2(114.88,146.53) v2(114.88,145.94) v2(114.88,145.36) v2(114.88,144.42) v2(114.88,143.83) v2(115.47,146.53) v2(115.47,145.94) v2(115.47,145.36) v2(115.47,144.42) v2(115.47,143.83) v2(116.05,146.53) v2(116.05,145.94) v2(116.05,145.36) v2(116.05,144.42) v2(116.05,143.83) v2(116.64,146.53) v2(116.64,145.94) v2(116.64,145.36) v2(116.64,144.42) v2(116.64,143.83) v2(117.22,146.53) v2(117.22,145.94) v2(117.22,145.36) v2(117.22,144.42) v2(132.25,136.8) v2(132.27,136.12) v2(132.85,136.85) v2(132.86,136.17) v2(133.48,136.87) v2(133.47,136.18) v2(134.16,136.89) v2(134.14,136.14) v2(134.82,136.9) v2(136.18,136.9) v2(136.68,152.08) v2(136.83,136.9) v2(137.49,136.92) v2(137.54,154.97) v2(138.17,154.97) v2(138.13,136.94) v2(138.24,152.58) v2(138.81,154.97) v2(139.08,154.02) v2(139.44,154.97) v2(139.78,153.9) v2(139.79,153.22) v2(139.78,152.61) v2(140.08,154.97) v2(140.39,145.69) v2(140.39,145.05) v2(140.39,142.07) v2(140.39,141.43) v2(140.36,138.74) v2(140.56,153.23) v2(140.57,152.57) v2(140.56,151.93) v2(140.56,151.28) v2(140.54,150.63) v2(140.55,149.95) v2(140.56,149.33) v2(140.71,154.97) v2(141.27,147.21) v2(141.35,154.97) v2(141.35,151.89) v2(141.35,151.28) v2(141.33,150.64) v2(141.35,149.98) v2(141.36,149.32) v2(141.35,148.68) v2(141.98,154.97) v2(142.14,154.05) v2(142.14,153.23) v2(142.12,152.56) v2(142.14,151.93) v2(142.16,151.27) v2(142.14,149.33) v2(142.47,135.79) v2(142.51,135.07) v2(142.62,154.97) v2(142.93,153.88) v2(142.93,152.58) v2(142.92,151.89) v2(142.93,151.28) v2(142.93,150.63) v2(142.93,149.98) v2(142.92,149.31) v2(143.21,145.72) v2(143.21,144.03) v2(143.15,141.11) v2(143.12,138.16) v2(143.25,154.97) v2(143.71,151.93) v2(143.7,151.28) v2(143.71,150.63) v2(143.71,149.96) v2(143.71,149.33) v2(143.71,148.68) v2(143.64,136.42) v2(143.72,152.56) v2(143.81,141.08) v2(143.78,138.13) v2(143.89,154.96) v2(143.87,145.7) v2(143.87,144.01) v2(144.31,136.46) v2(144.41,138.16) v2(144.4,135.86) v2(144.5,153.88) v2(144.5,152.58) v2(144.51,151.92) v2(144.5,145.72) v2(144.5,144.03) v2(144.44,141.11) v2(144.55,154.95) v2(144.51,153.21) v2(144.51,149.34) v2(144.93,136.42) v2(145.11,145.71) v2(145.11,144.01) v2(145.05,141.09) v2(145.02,138.14) v2(145.2,154.95) v2(145.29,153.23) v2(145.3,152.57) v2(145.29,151.93) v2(145.29,151.27) v2(145.29,150.63) v2(145.28,149.97) v2(145.29,149.33) v2(145.34,135.8) v2(145.83,154.95) v2(146.07,151.89) v2(146.08,151.28) v2(146.07,150.61) v2(146.08,149.98) v2(146.08,149.32) v2(146.08,148.68) v2(146.86,153.23) v2(146.86,152.56) v2(146.86,151.93) v2(146.88,151.27) v2(146.87,149.96) v2(146.86,149.33) v2(147.47,135.91) v2(147.65,153.88) v2(147.63,153.24) v2(147.65,152.58) v2(147.65,151.93) v2(147.65,151.28) v2(147.64,150.63) v2(147.65,149.98) v2(147.65,149.32) v2(147.96,136.49) v2(148.3,145.72) v2(148.28,144.09) v2(148.25,141.11) v2(148.25,138.14) v2(148.45,152.55) v2(148.44,151.93) v2(148.43,151.28) v2(148.44,150.63) v2(148.44,150) v2(148.44,149.33) v2(148.45,148.7) v2(148.5,135.92) v2(148.64,136.49) v2(148.95,145.73) v2(148.94,144.06) v2(148.92,141.09) v2(148.92,138.12) v2(149.23,153.88) v2(149.23,153.24) v2(149.23,152.58) v2(149.25,136.49) v2(149.57,145.74) v2(149.57,144.09) v2(149.54,141.11) v2(149.54,138.14) v2(149.59,135.91) v2(150.22,135.91) v4(123.13,145.88)
+VCCIO: length 12.7
  TOP w0.127: v2(114.67,126.26) v4(114.67,125.37)
  TOP w0.508: v2(173.92,154.62) 174.1,154.44 RH30.2 ; v2(134.02,162.52) 133.07,162.52 131.14,164.46 129.34,164.46 128.4,165.4 RH483.1
  BOTTOM w0.203: UH1.AG12 156.83,134.09 v2(157.18,134.44)
  BOTTOM w0.381: v2(170.43,120.41) 170.48,120.47 170.48,121.77 171.57,122.86 RH24.1
  vias: v2(113.55,128.11) v2(113.55,127.53) v2(114.13,128.11) v2(114.13,127.53) v2(114.67,126.89) v2(114.72,128.11) v2(114.72,127.53) v2(115.3,128.11) v2(115.3,127.53) v2(115.3,126.89) v2(140.42,140.11) v2(170.05,145.99) v2(170.05,145.41) v2(170.08,140.59) v2(170.08,140.01) v2(171.62,141.12) v2(171.62,140.33) v2(171.62,139.53) v2(171.62,137.9) v2(171.67,137.15)
+VCCSA: length 0.9
  BOTTOM w0.508: v2(126.67,168.55) 126.67,168.67 126.42,168.93 RH201.2
  vias: v2(114.35,154.58) v2(114.35,153.99) v2(114.35,153.41) v2(114.35,152.82) v2(114.35,152.24) v2(114.94,154.58) v2(114.94,153.99) v2(114.94,153.41) v2(114.94,152.82) v2(114.94,152.24) v2(115.52,154.58) v2(115.52,153.99) v2(115.52,153.41) v2(115.52,152.82) v2(115.52,152.24) v2(116.1,153.41) v2(116.1,152.82) v2(116.1,152.24) v2(116.69,153.41) v2(116.69,152.82) v2(116.69,152.24) v2(164.73,159.8) v2(165.35,159.77) v2(166.55,152.55) v2(168.69,145.67) v2(168.69,145.09) v2(168.69,144.48) v2(168.69,143.89) v2(168.69,143.21) v2(168.69,142.62) v2(168.69,141.94) v2(168.69,141.35) v2(168.89,150.63) v2(168.9,149.97) v2(168.91,149.33) v2(169.7,152.58) v2(169.7,149.98) v2(169.7,149.33) v2(169.73,151.29) v2(170,143.53) v2(170.01,141.92) v2(170.01,141.34) v2(170.03,144.2) v2(170.43,159.77) v2(170.49,149.98) v2(171.06,159.77) v2(171.64,159.77) v4(113.7,152.58)
+VCCST: length 19.9
  TOP w0.127: v2(130.48,169.82) v4(131.31,169.82)
  TOP w0.508: RE292.1 299.68,91.96 299.68,91.64 299.41,91.37 v2(299.12,91.37) ; v2(110.41,168.55) 110.16,168.55 109.85,168.24 PC1102.1 109.35,168.24 108.94,167.84 PR1107.1 PR1106.1 PR1105.2 PR1104.1 ; RH152.1 RH151.1 133.32,165.8 v2(133.15,165.63) ; v2(180.86,128.19) 179.88,128.19 RH164.1 ; RE69.1 299.9,70.3 v2(300.26,69.94)
  BOTTOM w0.203: v2(171.65,148.2) 171.32,148.53 UH1.H30
  BOTTOM w0.381: v2(128.9,144.73) 127.94,145.69 126.54,145.69 126.12,146.11 RH156.1 RH570.1 ; UH1.H28 171.15,146.91 170.68,146.91 UH1.J28 170.41,146.99 v2(170.05,146.64)
  BOTTOM w0.508: v2(115.4,160) RH100.1 116.5,160 116.54,159.97 RH98.1 117.1,159.8 RH97.1
  vias: v2(129.91,163.37) v2(177.87,130.84) v2(178.33,145.74) v2(178.71,146.18) v2(264.83,90.58) v2(319.35,92.01)
+VCCSTG: length 17.3
  TOP w0.127: v4(180.95,149.24) v2(180.19,149.24)
  TOP w0.254: CH105.1 172.5,148.34 171.61,147.45 170.88,147.45 v2(170.88,147.45) ; CH106.1 171.81,149.84 171.28,149.31 v2(171.24,149.31)
  BOTTOM w0.203: v2(171.24,149.31) 171.24,149.28 UH1.G30
  BOTTOM w0.254: v2(170.88,147.45) 170.96,147.45 UH1.H29
  BOTTOM w0.381: v2(125.5,150.37) 125.02,149.89 125.02,148.19 RH165.1
  BOTTOM w0.508: v2(133.72,167.98) 132.38,166.64 RH495.1 RH496.1 131.43,165.82 130.71,166.55 130.04,166.55 129.66,166.16 v2(129.66,165.64) 129.46,165.44 RH494.1
  vias: v2(180.02,148.63)
+VSS_PLL: length 4.8
  TOP w0.305: 297.41,75.71 297.41,76.44 296.72,77.13 UE3.G1
  TOP w0.381: 297.41,75.71 297.41,75.57 v1(297.64,75.34) 297.64,74.62 CE19.2 297.18,73.37 CE18.2
AGND: length 34.7
  TOP w0.127: v4(12.03,118.64) 10.97,117.58 v2(10.97,117.25) ; v2(0.43,109.33) v4(0.43,110.18) ; v2(2.65,108.69) v4(2.65,109.34)
  TOP w0.356: CA26.2 1.71,104.79 v2(1.91,104.99) ; CA17.2 0.27,106.94 CA12.2 0.26,107.56 CA14.2
  TOP w0.508: RA73.1 3.15,108.2 v2(2.65,108.69) ; v2(0.78,102.38) 0.5,102.67 CA27.2 ; CA43.2 11.71,113.1 11.31,112.71 10.17,112.71 v2(10.1,112.63) ; RA74.1 9.3,107.76 v2(9.12,107.94) ; CA14.2 CA13.2 0.1,109 v2(0.43,109.33) ; CA44.2 v2(3.7,111.32)
  BOTTOM w0.203: CA24.2 10.13,110.35 9.68,109.9 9.36,109.9 9,109.54 UA1.42 ; UA1.20 1.98,104.92 v2(1.91,104.99) ; v2(3.94,109.89) 4.11,109.71 4.11,109.53 4.2,109.44 UA1.30
  BOTTOM w0.305: CA28.2 -0.01,104.77 -0.01,103.51 0.37,103.13 CA29.2
  BOTTOM w0.356: 9.96,111.31 9.96,110.91 10.21,110.66 10.21,110.53 CA24.2
  BOTTOM w0.381: RA94.2 0.13,100.55 0,100.68 0,101.6 v2(0.78,102.38)
  BOTTOM w0.508: CA30.2 11.19,112.67 CA25.2 10.42,112.3 v2(10.1,112.63) 10,112.53 10,111.35 9.96,111.31 CA31.2 ; RA95.2 v2(-0.04,125.56) ; v2(3.7,111.32) 2.76,111.32 2.44,111 CA21.2 1.16,110.57 CA20.2 ; v2(0.78,102.38) 0.56,102.6 CA29.2 ; v2(10.97,117.25) 11.19,117.47 CA42.1 ; v2(4.97,125.94) 4.81,125.79 CA41.1
  vias: v2(12.56,110)
DV12S: length 4.8
  BOTTOM w0.14: v1(329.2,106.71) 330.02,105.89 v2(330.02,105.36)
  BOTTOM w0.508: v2(333.11,101.23) 333.11,101.18 333.61,100.68 CR5.1 333.93,100.87 333.93,101.71 334.74,102.51
DV33_18:
  vias: v1(336.27,107.63)
GND: length 2748.9
  TOP w0.102: v4(340.47,151.26) v2(340.47,152.29) ; v2(24.84,157.97) v4(24.84,157.38) ; CV1000.2 245.67,128.48
  TOP w0.127: v4(32.18,77.58) 31.64,77.58 v2(31.1,78.11) ; v4(164.17,77.77) 164.44,77.5 v2(164.44,76.85) ; v4(346.43,95.42) 346.82,95.03 v2(346.82,94) ; v2(324.76,99.28) v4(325.48,99.28)
  TOP w0.152: CH106.2 173.2,150.15 173.85,150.15 174.21,149.79 v2(174.21,148.96) ; v2(99.9,85.49) 98.95,86.44 97.7,86.44 97.37,86.77 96.2,86.77 94.47,85.03 93.34,85.03 v2(93,85.37) 93,85.9 93.19,86.1 93.19,86.73 v2(93.18,86.75) 93.18,86.93 92.91,87.19 92,87.19 91.63,86.82 v2(91.63,86.5) 91.87,86.26 91.87,84.87 92.6,84.14 95.03,84.14 96.84,85.95 97.28,85.95 v2(97.54,85.69) 98.08,85.15 v2(98.08,84.9) 98.12,84.9 98.69,84.32 v2(98.69,84.19) 98.7,84.18 98.7,84.13 99.07,83.76 100.08,83.76 100.33,83.51 v2(100.33,83.08)
  TOP w0.178: CM44.2 15.77,142.37 v2(15.83,142.44) 16.57,141.71 17.5,141.71 17.72,141.49 17.72,140.2 17.63,140.11 16.9,140.11 v2(16.87,140.07)
  TOP w0.203: v2(205.41,115.92) 204.77,115.92 204.3,116.39 U33.11 ; v2(214.22,118.99) 214.3,119.07 v2(214.3,120.35) 214.87,120.92 216.16,120.92 216.93,120.15 216.93,119 v2(216.92,118.99) ; PU700.5 192.49,184.46 PU700.21 ; PU700.10 v2(190.32,185.21) ; v2(291.11,76.36) 290.64,76.36 290.12,75.84 289.76,75.84 289.05,75.12 287.88,75.12 287.75,74.99 285.63,74.99 285.48,75.14 285.48,76.25 v2(285.29,76.44) 285.48,76.63 285.48,79 285.63,79.14 287.83,79.14 288.02,78.95 v2(288.48,78.95) 289.86,78.95 290.18,78.63 v2(290.93,78.63) ; v2(21.88,136.56) 21.72,136.73 21.72,137.13 21.72,137.46 21.72,137.47 21.72,137.7 UM1.B3 ; v2(7.25,75.46) UA4.11
  TOP w0.254: RM4.2 18.59,134.69 19.44,133.84 20.35,133.84 v2(20.52,134) ; v2(16.87,140.07) 16.13,139.34 15.38,139.34 15.08,139.63 CM43.2 ; v2(246.68,149.03) 246.68,148.98 CV992.2 ; RH498.1 128.91,169.31 128.14,170.07 v2(126.67,170.07) ; v2(149.3,76.69) 149.3,77.04 149.57,77.3 150.07,77.3 150.19,77.17 U32.16 ; DT180.2 12.21,148.91 v2(12.06,148.76) ; v2(294.26,72.76) 294.48,72.55 294.48,71.84 294.69,71.62 CE1501.1 ; v2(186.87,187.47) PC712.2 186.18,185.95 PC714.2 186.56,185.57 187.43,185.57 ; UI3.10 320.74,99.53 v2(320.96,99.31) ; v2(291.52,87.27) UE3.A13 ; RT1.2 25.49,105.25 v2(25.12,105.62) 25.62,106.11 CT163.2 ; CH3331.2 72.67,70.58 v2(72.67,71.11) 73.2,71.65 CH53.2 ; RT3.1 22.86,116.27 v2(22.91,116.32) ; v2(12.96,155.86) 13.14,155.68 DT175.2 ; PQ203.4 11.2,90.92 11.1,90.92 10.8,90.63 v2(10.72,90.63) ; UF1.6 234.08,116.19 v2(234.37,116.48) 234.58,116.27 UF1.5 ; v2(11.98,102.08) 11.98,101.85 11.67,101.54 CA35.2 ; v2(12.07,152.48) 12.09,152.46 DT178.2 ; v2(155.13,154.25) 155.11,154.22 PC2045.2 ; v2(151.94,72.92) 151.66,72.92 151.19,72.45 U32.27 ; UN3.5 333.85,171.05 v2(334.6,170.3) ; RH5844.2 78.16,80.41 78.47,80.09 v2(78.47,79.89) ; v2(64.61,73.7) 64.61,73.64 65.13,73.13 RH401.1 ; CT102.2 29.58,108.76 29.58,108.29 30.07,107.79 31.43,107.79 31.99,108.35 32.4,108.35 ; v2(14.12,89.58) 14.38,89.58 14.68,89.88 14.68,90.32 15.08,90.71 PQ213.1 15.4,90.84 15.98,91.42 15.98,91.61 16.7,92.34 PQ213.4 ; 8.43,103.61 8.43,102.68 8.84,102.28 9.35,102.28 9.54,102.47 CA1.2 ; v2(216.21,115.14) 214.18,115.14 213.96,115.36 v2(213.96,117.08) YV1.2 214.81,117.56 214.64,117.72 CV858.2 214.52,118.64 214.52,118.7 v2(214.22,118.99) ; v2(216.21,115.14) 216.89,115.14 217.04,115.3 v2(217.04,115.98) ; v2(216.21,115.14) YV1.4 v2(217.04,115.98) ; v2(121.15,83.09) 121.15,82.62 121.61,82.16 UZ29.5 ; DT176.2 12.71,154.11 DT177.2 11.95,154.03 v2(11.93,154.01) ; v2(33.34,110.64) 33.34,110.28 RT42.1 ; CH105.2 173.72,148.34 174.21,148.83 v2(174.21,148.96) ; v2(2.25,140.43) 2.29,140.39 DT22.2 ; UZ30.5 240.54,119.64 240.33,119.84 240.33,121.62 v2(240.53,121.81) ; v2(217.04,115.98) 217.04,117.96 CV857.2 216.92,118.93 v2(216.92,118.99) ; v2(12.4,151.87) 12.92,151.87 13.17,152.12 DT181.2 ; DT17.2 8.12,131.51 v2(8.34,131.29) ; UE7.3 121.99,126.14 122.35,126.51 124.38,126.51 124.78,126.11 UZ22.3 ; PR241.2 15.11,93.5 v2(14.83,93.22) ; JXDP.37 124.8,161.7 v2(124.44,161.34) ; v2(146.94,71.45) 148.05,71.45 148.21,71.61 148.21,72.36 149.04,73.19 U32.23 ; CM44.2 13.5,142.37 13.47,142.4 12.82,142.4 v2(12.71,142.52) 12.19,143.03 11.55,143.03 10.96,142.44 10.57,142.44 10.44,142.31 v2(10.44,141.18) v2(10.44,140.47) 10.44,139.76 10.59,139.6 11.49,139.6 v2(11.98,139.11) 12.35,139.48 13.32,139.48 13.67,139.12 13.79,139.12 v2(13.9,139.02) ; DT23.2 5.14,140.91 4.79,140.91 v2(4.77,140.93) ; RT430.1 19.11,123.69 v2(19.58,123.69) ; DT24.2 4.81,139.25 v2(4.73,139.16) ; PC1941.2 47.35,87.34 PR1925.2 ; DT182.2 13.08,150.56 12.99,150.47 DT179.2 12.3,150.47 v2(12.05,150.22) ; CT158.2 21.74,125.62 22.07,125.95 v2(22.07,126.07) ; DT25.2 v2(5.51,127.65) ; v2(120.45,124.73) 119.51,124.73 UZ19.3 ; UF1.8 232.86,115.19 v2(232.71,115.33) 233.07,115.69 UF1.7 ; PQ215.1 15.99,97.34 v2(16.18,97.53) ; v2(208.32,115.35) 208.32,115.41 208.36,115.45 UZ24.5 ; PR712.2 184.34,187.26 PQ701.4 183.45,186.34 183.12,186.01 182.54,186.01 182.31,185.78 182.31,185.52 PQ701.1 181.94,185.58 181.94,186.17 182.09,186.32 v2(182.09,186.53) ; UM1.G6 v2(19.32,142.5) ; UE6.5 190.87,74.97 191,75.1 191.88,75.1 RZ32.1 ; UI3.21 v2(320.74,105.13)
  TOP w0.279: JXDP.31 127.08,160.2 127.41,159.87 127.41,159.2 v2(127.45,159.16) ; JXDP.59 v2(124.13,167.2)
  TOP w0.305: JXDP.7 123.86,154.2 122.36,152.7 JXDP.2 119.12,152.7 118.65,153.17 118.65,154.38 v2(118.67,154.4) ; 118.74,160.18 118.74,158.3 ; 118.74,160.18 118.76,160.2 JXDP.32 ; 118.74,160.18 118.74,161.17 118.73,161.18 118.73,161.37 119.06,161.7 JXDP.38 ; 118.74,158.3 118.74,157.2 ; 118.74,158.3 119.14,158.7 JXDP.26 ; v2(293.12,80.06) UE3.C4 ; JXDP.49 122.52,164.7 121.97,165.25 ; JXDP.14 v2(118.74,155.7) ; v2(118.74,155.7) 118.74,157.2 ; v2(118.74,155.7) 118.67,155.63 v2(118.67,154.4) ; v2(11.77,158.73) 11.85,158.65 CV178.2 ; v2(118.67,154.4) 118.87,154.2 JXDP.8 ; UZ31.3 249.15,118.52 248.93,118.74 248.93,119.17 249.18,119.42 v2(249.22,119.42) ; 118.74,157.2 118.74,157.2 JXDP.20 ; v2(5,82.25) 4.94,82.25 4.43,82.76 4.43,83.32 4.16,83.58 JAUDIO.7 ; JXDP.13 124.87,155.7 124.76,155.82 v2(124.13,155.82) ; 121.97,165.25 v2(121.97,165.25) 121.43,164.7 JXDP.50 ; 121.97,165.25 123.93,167.2 v2(124.13,167.2) ; RT1092.1 19.36,122.31 18.75,122.92 18.75,123.33 RT430.1 ; UZ26.3 v2(107.58,113.9) ; YM1.2 12.78,140.51 12.35,140.94 12.34,140.94 12.17,141.1 12.17,141.12 11.68,141.61 YM1.4 11.5,142.2 v2(11.81,142.52) ; v2(15.02,138.06) 15.15,138.19 RM24.2 ; C3319.2 305.11,79.92 v2(305.11,79.57) ; JXDP.25 127.06,158.7 127.45,159.09 v2(127.45,159.16) 127.62,158.99 127.62,157.59 127.24,157.2 JXDP.19 ; UZ12.3 114.62,119.76 v2(114.04,119.76) ; PC725.2 181.76,183.37 182.14,182.99 183.07,182.99 RV1836.2 ; v2(24.5,115.97) RT40.1
  TOP w0.33: v2(334.46,168.68) 334.55,168.59 C280.2 ; v2(111.07,114.72) 110.4,114.72 109.03,116.1 UZ21.3 ; C1031.2 335.11,168.57 v2(335.22,168.68) 335.4,168.68 C1033.2
  TOP w0.356: CA127.2 v2(10.15,71.68) ; CA130.2 1.53,102.21 v2(1.51,102.23) ; CT80.2 23.96,101.2 24.24,100.92 v2(24.4,100.92) ; 292.93,72.78 292.46,72.31 v2(292.1,72.31) ; v2(27.32,124.25) 27.32,124.44 26.9,124.86 RT199.2 ; CH3323.2 100.56,92.32 v2(100.41,92.47) 100.36,92.52 CH203.2 CH3322.2 ; v2(279.64,72.73) 279.34,72.42 CH44.2 CH196.2 ; v2(25.77,103.02) 25.73,103.06 CT93.2 ; v2(37.76,91.93) 37.76,91.76 CT47.2 ; RT12.2 22.72,100.79 v2(22.86,100.65) ; RM28.2 24.23,159.36 v2(24.23,159.37) ; RH5890.2 86.26,79.02 v2(86.19,79.1) ; v2(326.95,119.65) 326.57,119.65 325.89,118.97 CR15.2 ; v2(145.05,76.97) 144.95,76.87 144.95,76.61 145.43,76.12 145.9,76.12 146.05,75.96 C135.2 ; CT63.2 26.85,109.62 26.97,109.49 v6(27.72,109.49) ; CM41.2 17.82,133.03 v2(17.82,132.29) ; RA57.2 CA19.2 0.95,96.4 1.07,96.28 v2(1.24,96.28) ; v2(21.48,100.94) 21.74,101.2 RT164.1 ; v2(23.82,105.62) 23.65,105.44 CT100.2 ; RM18.2 24.19,134.04 23.95,133.8 v2(23.95,133.5) ; v2(23.82,103.67) 23.8,103.65 CT99.2 ; v2(77.38,85.52) 77.2,85.7 CH189.2 ; CH188.2 63.22,83.76 v2(63.22,83.51)
  TOP w0.381: RZ1150.1 18.35,118.75 v2(17.84,119.26) ; CA126.2 7.15,70.73 7.15,70.63 7.19,70.59 v2(7.19,70.55) ; 250.64,123.04 v2(250.62,123.06) ; v2(143.48,134.44) 143.83,134.78 PC2081.2 ; CH3333.2 141.31,134.76 v2(141.68,134.39) ; v2(96.56,94.57) 96.35,94.36 CH207.2 ; v2(20.27,126.08) 20.18,126.17 CT145.2 20.2,126.66 20.51,126.97 RT183.2 ; CE76.2 157.34,76.66 CE75.2 156.9,75.48 ; v2(100.33,83.08) 100.63,83.08 100.94,83.38 CH47.2 101.7,82.83 101.7,82.52 102.04,82.17 102.63,82.17 v2(103.31,82.85) 103.45,82.7 103.97,82.7 104.14,82.87 v2(104.14,82.9) 104.25,83.01 v2(104.25,83.58) 104.24,83.6 v2(104.24,85.05) 104.24,86.16 104,86.39 103,86.39 v2(102.55,85.94) 102.53,85.92 101.79,85.92 v2(101.76,85.94) 101.5,85.68 101.5,85.5 CH48.2 100.71,85.58 99.99,85.58 v2(99.9,85.49) ; v2(18.21,127.72) 18.15,127.72 17.75,127.32 RT431.1 ; v2(235.38,169.97) 235.48,170.07 RV619.2 ; PQ219.1 76.07,99.9 76.57,99.9 v2(76.58,99.92) ; v2(126.54,124.1) 126.85,124.4 CZ2156.2 ; R277.2 C4.2 173.48,72.79 RZ1151.1 173.48,71.72 v2(173.15,71.39) ; QE4.1 284.7,70.51 284.3,70.51 v2(284.03,70.79) ; v2(21.22,108.87) 21.22,108.48 CT143.2 ; PC221.2 68.5,89.91 68.5,90.55 68.69,90.73 v2(68.69,90.73) ; v2(32.32,112.45) 32.26,112.39 31.71,112.39 RT107.1 RT33.1 RT34.1 ; v2(71.45,70.4) 71.45,70.59 71.02,71.02 71.02,71.25 CH70.2 ; v2(297.92,79.27) UE3.H4 ; v2(26.21,139.72) 25.83,139.72 RM12.1 25.55,139.46 25.27,139.18 RM9.2 25.27,138.31 RM13.1 ; RT186.2 RT437.2 25.62,122.36 v2(25.32,122.07) ; JUSB2.7 332.93,139.49 DI9.3 ; PU202.3 v2(22.09,84.29) ; QZ17.4 251.16,110.79 250.88,110.51 v2(250.16,110.51) ; CH187.2 92.39,74.92 RH5876.2 ; v2(288.48,78.95) 288.48,78.8 288.28,78.59 CE43.2 ; CH190.2 77.62,83.61 77.9,83.89 v2(77.9,83.96) ; Q5.1 273.34,93 273.74,92.6 273.74,91.54 ; v2(150.79,151.94) 150.43,152.3 PC2074.2 ; QV3.4 248.16,115.29 247.43,114.56 v2(247.43,114.35) 247.09,114.35 246.86,114.11 QV3.1 ; PQ215.4 18.25,95.38 v2(18.59,95.73) ; UZ20.3 109.13,120.34 108.57,119.78 v2(108.13,119.78) ; v2(86.08,76.04) 85.71,76.04 CH3321.2 ; v2(103,119.25) 103,119.26 UZ23.3 ; CE29.2 v2(286.74,85.87) ; PC2079.2 150.12,154.56 v2(150.8,153.88) ; v2(23.82,106.27) 23.92,106.17 CT65.2 ; UC1.3 122.15,121.7 121.46,122.38 121.46,123.21 v2(121.21,123.46) ; RT43.1 27.14,114.45 v2(27.1,114.49) 26.93,114.49 26.59,114.83 RT38.1 ; RH568.2 96.04,73.02 96.05,73 ; v2(204.13,143.96) 203.96,143.96 203.24,144.68 PC1012.2 ; PC2084.2 144.82,134.8 v2(144.38,134.36) ; 105.13,186.07 v2(104.44,186.07) ; v2(174.87,131.64) 174.79,131.56 174.79,131.09 175.06,130.82 CH130.2 175.44,130 CH131.2 ; v2(235.54,149.83) 235.92,150.22 235.92,150.27 236.39,150.73 CV1040.2 ; UE3.A6 291.49,81.26 v2(291.39,81.36) ; v2(221.63,184.88) 221.42,184.88 221.38,184.93 QZ14.1 ; CA39.2 2.49,100.31 CA77.2 ; CA39.2 2.48,99.64 CA38.2 ; CA39.2 2.49,99.08 v2(2.39,98.98) ; RT1134.2 23.53,116.08 23.29,116.33 22.91,116.33 v2(22.91,116.32) ; 13.79,139.12 14.07,139.4 CM43.2 ; CH110.2 CH107.2 ; CH107.2 172.24,145.74 v2(172.28,145.79) ; CH107.2 171.63,146.5 CH108.2 ; 273.74,91.54 273.89,91.7 Q5.4 ; 273.74,91.54 273.74,90.91 273.4,90.57 271.83,90.57 271.51,90.25 v2(271.51,89.87) ; CH82.2 CH204.2 88.7,70.84 v2(88.76,70.78) ; JAUDIO.1 1.76,83.69 1.42,83.34 v2(0.82,83.34) 0.82,83.58 0.06,84.34 JAUDIO.31 ; v2(62.34,80.75) PR1942.2 62.22,81.41 61.34,80.54 PU1901.3 ; PR1943.1 62.13,77.84 62.39,78.11 v2(62.39,78.24) ; v2(181.48,186.42) 181.48,184.69 PC725.2 ; CZ2157.2 56.18,96.37 56.17,96.36 v2(55.7,96.36) ; RM1145.1 95.66,76.85 95.32,77.19 v3(95.22,77.19) ; PQ212.4 29.02,88.98 28.63,88.59 28.24,88.59 27.72,88.06 PQ212.1 ; v2(17.09,124.63) 17.2,124.53 CT146.2 ; CH205.2 92.44,80.09 CH92.2 91.89,80 v2(91.71,79.83) ; CT71.2 CT82.2 CT81.2 24.68,101.2 v2(24.4,100.92) ; CE15.2 CE16.2 345.82,183.18 v2(345.08,182.44) ; RZ40.2 61.85,95.98 v2(61.98,95.85) ; v2(16.36,83.41) 16.36,83.86 15.88,84.34 JAUDIO.32 ; v2(14.12,89.58) 13.91,89.79 PQ203.1 ; v2(78.3,99.5) 78.25,99.5 PQ219.4 ; v2(287.69,80.21) 287.69,80.1 288.09,79.71 RH5884.1 ; v2(303.44,88.66) 303.44,89.29 303.83,89.68 RH1152.1 ; v2(282.22,72.38) QE4.4 ; PC1508.2 210.71,137.38 v2(211.19,136.9) ; v2(150.83,149.97) 150.82,149.95 PC2078.2 ; RV135.2 34.28,100.27 35.08,100.27 QV12.3 ; RT429.2 21.93,124.48 22.12,124.29 v2(22.35,124.29) ; v6(28.99,103.66) 29.17,103.48 CT67.2 CT68.2 30.3,103.33 RT5.2 ; v2(188.44,111.88) 187.7,112.62 UZ16.5 ; v2(196.88,144.82) 197.21,144.49 CV865.2 ; v2(192.14,187.66) 191.68,187.66 PC711.2 ; v2(107.01,110.48) 106.6,110.89 RZ50.2 ; v2(38.84,79.47) 39.22,79.85 PC1935.2 PC1938.2 ; v2(156.9,71.52) CE11.2 ; RH188.2 131.32,140.18 131.9,140.76 v2(131.9,141.23) ; v2(142.55,134.42) 142.64,134.42 143.01,134.79 PC2080.2 ; v2(104.44,185.18) PC1131.2 ; v2(27.72,103.67) 27.83,103.77 CT66.2 27.17,104.18 CT94.2 ; PQ214.4 18.35,83.86 17.92,83.43 17.08,83.43 v2(17.05,83.41) PQ214.1 17.05,82.13 17.15,82.03 PR261.2 ; CE37.2 287.77,70.69 288.34,70.12 288.45,70.12 v2(288.58,69.99) ; CT72.2 27.39,102.06 v6(27.72,102.39) ; v2(113.53,171.15) 113.53,170.93 113.79,170.67 PC1104.2 ; PC505.2 130.95,69.72 131.66,69 v2(132.55,69) ; PC1515.2 207.58,139.38 v2(208.05,138.91) 208.2,138.76 PC1512.2 ; CA128.2 v2(0.97,75.46) ; v2(288.09,81.67) 288.09,81.58 288.57,81.09 CE26.2 ; RM17.2 22.75,133.23 22.33,133.65 RM11.1 21.89,133.65 v2(21.56,133.98) ; YH2.2 v2(103.34,85.85) ; UZ22.3 124.78,125.61 125.09,125.29 RZ87.2 125.78,124.73 v2(126.03,124.48) ; PU203.4 26.58,75.8 v2(26.92,75.45) ; CT62.2 CT64.2 ; PC2077.2 150.36,151.1 v2(150.81,150.65) ; PR1011.2 161.7,186.63 v2(161.82,186.76) ; RH5850.2 94.41,86.51 94.09,86.18 v2(94.09,86.11) ; v2(146.94,71.45) 146.99,71.5 CE84.2 146.99,72.79 CE85.2 ; CV180.1 13.03,160.08 v2(13.51,159.59) ; v2(70.66,69.17) 70.87,68.97 70.87,68.9 71.07,68.7 CH80.2 ; v2(241.88,157.76) 241.58,158.07 CV990.2 ; v2(119.43,81.27) 118.15,81.27 CZ106.2 ; RH5847.2 78.79,79.17 78.48,78.86 v2(78.48,78.79) ; v2(52.37,91.53) v4(52.37,90.76) 52.37,90.08 PR1918.2 ; v2(241.88,150.63) 241.53,150.27 RV615.2 ; CH3332.2 170.74,131.51 v2(170.74,131.07) ; PC1943.2 39.22,85.36 39.52,85.67 PC1933.2 ; CZ98.2 208.06,115.1 v2(208.32,115.35) ; QZ15.4 165.65,186.8 v2(165.65,186.8) ; v2(238.89,133.77) 238.63,134.02 CV1019.2 ; v2(26.86,78.19) 26.36,77.68 PR255.2 26.34,77.43 PC215.2 ; CH102.2 170.44,137.6 v2(170.14,137.3) 169.77,137.67 CH104.2 ; v2(294.72,80.86) UE3.E6 ; v2(243.45,131.34) 242.65,132.14 CV1018.2 ; v2(197.79,185.91) PR708.2 194.98,185.91 194.87,186.02 PC710.2 ; UV29.3 v2(218.98,111.57) ; QZ14.4 v2(219.05,186.87)
  TOP w0.406: v2(250.16,110.51) 249.86,110.2 QZ17.1 ; v2(196.55,111.82) 196.84,111.53 UV20.3 ; QZ6.4 250.64,123.04 ; 66.64,94.09 66.49,93.94 66.49,93.06 v2(66.53,93.02) ; v2(18.07,169.12) 18.07,169.12 18.01,169.18 DI7.3 ; UV19.3 225.68,111.3 225.87,111.49 v2(225.87,111.79) ; RE311.1 292.93,73.41 292.93,72.78
  TOP w0.432: QZ6.1 249.22,120.11 v2(249.22,119.42)
  TOP w0.457: v2(137.84,89.27) 137.24,89.27 CD74.2 ; v2(220.97,128.8) 220.97,129.11 CV893.2 ; v2(204.3,133.93) 204.3,133.85 204.01,133.56 PC1010.2 ; v2(216.99,142.31) 216.86,142.18 CV900.2 ; CV881.1 198.37,141.97 v2(198.96,141.97) ; CD32.2 253,85.72 254.05,85.72 v2(254.11,85.65) ; CV1044.2 243.71,131.16 243.61,131.26 243.52,131.26 243.45,131.34 v2(243.45,131.34) ; CV924.2 191.03,151.17 191.03,150.59 v2(191.02,150.58) 190.35,149.9 CV878.2 ; CV885.2 214.33,135.78 213.35,135.78 ; v2(132.04,96.27) 132.47,96.27 CD73.2 ; v2(123.48,96.63) 123.82,96.63 CD7.2 ; v2(211.94,143.03) 211.43,143.03 211.25,143.21 PC1507.2 ; RZ1958.2 235.67,72.42 UZ6.3 ; v2(210.06,133.96) 210.24,134.13 PC1503.2 ; v2(196.83,142.37) 196.49,142.03 CV859.2 ; v2(169.99,71.41) 169.96,71.38 169.96,70.34 C2.2 ; v2(218.59,146.51) 218.59,146.4 218.91,146.08 CV850.2 ; CE2.2 188.15,70.12 v2(188.35,69.92) ; v2(288.98,75.84) 288.75,75.61 CE42.2 ; v2(215.91,89.17) 216.64,89.17 216.78,89.31 CD24.2 ; v2(203.11,140.98) 203.11,141.13 202.95,141.29 PC1516.2 ; CV995.2 234.66,146.83 234.66,147.4 v2(234.68,147.43) ; PC1944.1 60.45,83.69 v2(60.32,83.82) ; CD6.2 140.41,89.15 v2(140.08,89.15) ; CV880.1 189.66,148.7 v2(189.48,148.87) ; v2(135.62,89.13) 134.94,89.13 CD75.2 ; v2(211.33,139.01) 211.39,139.07 PC1031.2
  TOP w0.508: CV1050.2 211.75,143.23 v2(211.94,143.03) ; v2(337.24,166.72) C267.1 ; v2(109.68,68.87) 109.68,69.56 SW4.4 109.04,69.51 v2(109.04,68.87) ; RV655.1 v2(222.18,120.28) ; v2(305.8,85.49) 305.61,85.3 CE24.2 CE31.2 ; CD76.2 133.09,88.93 v2(133.55,88.93) ; QV105.3 228.36,110.14 v2(228.7,110.49) ; v2(218,153.9) 217.82,154.07 216.71,154.07 216.2,154.58 CV864.1 ; v2(165.81,95.95) 166.48,95.28 CD25.2 ; CD3.2 CD4.2 180.89,87.89 181.58,88.58 v2(181.92,88.58) ; CV1048.2 244.27,133.29 244.68,133.7 v2(245.08,133.7) ; v2(205.33,144.99) 205.14,144.8 PC1009.2 204.65,144.29 205.09,143.85 PC1027.2 ; v2(220.27,177.35) RV625.2 222.34,177.35 CV927.2 ; CV943.2 231.36,177.92 v2(230.7,177.26) ; CD70.2 143.92,89.53 v2(144.23,89.53) ; CD85.2 224.16,96.84 v2(224.49,96.51) ; CD69.2 CD3327.2 CD3326.2 130.33,84.48 v2(130.93,85.09) ; v2(337.11,171.9) RN33.1 ; CV957.2 235.38,172.92 v2(235.38,172.29) 235.83,172.29 236.14,172.61 CV925.2 ; CZ46.2 275.51,79.32 v2(275.54,79.34) 275.54,79.88 275.28,80.13 CE3319.2 ; v2(245.15,134.81) 245.03,134.7 CV1002.2 ; CV1006.2 CV1005.2 248.08,130.07 v2(247.7,130.45) ; v2(37.76,91.93) 37.76,92.34 UT5.4 ; RV601.1 214.73,149.89 v2(215.28,149.89) ; v2(291.19,96.74) 290.86,96.41 PC613.2 ; 329.23,99.46 328.85,99.46 328.09,98.7 v2(328.09,98.06) ; CA2.2 12.7,103 12.36,102.66 v2(12.32,102.66) ; PC1936.2 v2(38,73.42) v4(38,75.38) PC1927.1 ; v2(230.07,85.05) 230.07,85.04 229.72,84.7 RH212.2 ; v2(247.7,127.4) CV1009.2 248.4,126.83 CV1004.2 ; v2(194.37,90.13) 194.39,90.11 CD26.2 ; v2(31.52,68.63) v2(30.91,68.63) 30.3,68.63 PC207.2 30.25,69.02 29.96,69.31 PC205.2 30.19,69.53 30.23,69.57 PR220.2 ; v2(24.71,163.62) 24.71,163.61 24.8,163.53 CI1.2 ; CH109.2 170.87,142.6 171.59,141.88 v2(172.27,141.88) ; CV882.2 199.35,150.73 199.44,150.64 199.44,150.63 v2(199.45,150.63) ; CE51.2 v2(298.68,90.7) ; v2(213.63,88.14) 213.63,88.14 CD22.2 ; v2(45.54,88.8) 45.54,88.22 PC1939.2 ; PC1912.2 PC1911.2 46.34,75 46.77,74.57 v2(46.91,74.57) ; CE22.2 311.07,82.12 v2(310.71,82.12) ; v2(244.11,116.26) 243.65,115.8 CV499.2 ; v2(214.38,173.73) 215.7,172.41 CV961.2 ; PC711.2 PC707.1 ; v2(194.43,152.29) 194.85,152.71 CV879.2 ; RH186.2 128.83,140.18 RH188.2 ; v2(310.65,79.02) 310.21,78.58 C3321.2 ; CN7.2 342.8,154.75 v2(342.42,155.13) ; CD35.2 CD34.2 247.56,91.06 247,90.5 v2(246.58,90.5) ; CF2.2 237.67,116.73 v2(237.29,117.11) ; CV972.2 213.7,174.06 214.22,174.58 CV978.2 214.9,174.58 215.4,175.08 v2(215.4,175.51) 215.4,175.83 CV960.2 ; v2(233.17,108.8) 233.66,109.29 QF1.4 ; CV985.2 235.2,164.8 v2(235.89,164.11) ; v2(174.15,77.58) 173.36,78.37 173.36,80.69 175.06,82.39 PR1804.2 ; PR105.2 20.97,156.01 PQ101.3 21.63,156.11 21.81,156.3 v2(21.81,156.82) ; v2(241.88,126.5) 242.2,126.5 CV1041.2 ; CV1036.2 240.1,153.85 v2(239.48,153.85) ; CE11.2 159.07,72.66 160,73.59 v2(160.22,73.59) 160.22,73.74 159.42,74.54 157.84,74.54 156.9,75.48 ; CV817.2 207.9,118.36 208.52,118.98 CV907.2 209.14,119.27 v2(209.19,119.22) ; CZ588.2 106.46,121.68 v2(106.48,121.7) ; CD88.2 v2(255.64,79.52) ; v2(235.38,168.37) 235.47,168.28 CV953.2 ; RV654.1 RV652.1 225.99,119.91 v2(226.24,120.16) ; RV654.1 RV644.1 ; RV654.1 v2(226.88,120.18) ; CE48.2 291.59,98.43 291.04,98.98 v2(291.04,99.21) ; v2(222.79,88.94) 222.28,88.94 CD86.2 ; v2(245.9,150.7) 245.72,150.53 CV991.2 ; CV1024.2 244.08,152.55 v2(244.47,152.55) ; v2(43.4,103.32) 43.03,102.95 CV169.2 ; CV1026.2 v2(233.79,164.44) ; RE33.1 300.85,70.55 300.85,70.09 v2(300.98,69.96) ; PR1934.2 42.15,88.66 42.24,88.75 v2(42.24,88.99) ; CI22.2 RI27.2 323.35,121.98 v2(323.08,122.26) ; v2(164.79,127.92) 164.98,127.92 CH126.2 ; v2(13.49,111.62) 12.75,112.36 DA9.2 ; v2(15.75,174.22) 16.15,173.82 CI12.2 ; v2(238.52,110.83) 238.52,111.35 CF1.2 ; v2(0.83,111.23) 0.92,111.31 DA4.2 ; CH3327.2 61.62,73.45 61.18,73.01 v2(61.18,72.34) 61.43,72.09 CZ19.2 ; CD84.2 226.25,89.22 v2(226.59,89.22) ; v2(210.71,110.6) 210.52,110.41 210.06,110.41 RV566.2 ; CH117.2 176.58,153.36 v2(176.58,153.94) 177.33,153.94 177.39,154.01 CZ97.2 ; PC606.2 278.16,98.04 277.05,96.93 277.05,95.71 275.97,94.63 v2(274.62,94.63) ; PQ225.3 69.89,91.27 69.75,91.13 v2(69.75,91.03) ; UE2.1 345.2,187.16 v2(345.2,187.85) ; v2(214.5,134.82) 214.56,134.87 CV885.2 ; CR14.2 325.62,115.77 325.3,116.1 v2(325.09,116.1) ; CV1032.2 v2(241.88,157.76) ; UV16.2 v2(13.51,159.59) 13.16,159.24 CV179.2 ; CD77.2 131.1,89.33 v2(131.7,89.33) ; CV852.2 198.8,128.55 CV854.2 198.75,128.17 199.1,127.82 200.09,127.82 200.32,128.05 200.32,128.87 v2(200.27,128.91) ; CV1034.2 CV1013.2 248.4,151.11 v2(248.06,151.45) ; v2(224.83,177.57) 224.06,178.34 CV982.2 ; PC1025.2 205.73,141.62 v2(206.11,142) 206.69,141.42 PC1029.2 ; PC1937.2 v2(31.1,78.11) ; CE25.2 294.74,73.24 v2(294.26,72.76) ; PC2009.2 152.36,147.99 v2(152.36,148.67) ; QV101.3 v2(217.17,173.28) ; v2(308.83,83.55) 308.74,83.46 CE23.2 ; CD81.2 217.6,95.78 v2(216.92,95.78) 216.25,95.78 CD82.2 ; v2(284.53,81.68) 284.66,81.81 CE30.2 ; v2(305.49,70.76) 305.88,70.36 UE5.3 306.48,70.06 306.62,69.92 RE31.1 ; v2(123.95,85.02) 123.48,85.49 RH209.2 ; v2(214.5,140.67) 214.4,140.77 PC1038.2 ; v2(104.44,178.96) PC1128.2 ; CH120.2 168.1,128.4 167.6,127.9 v2(167.3,127.9) ; v2(220.51,96.45) 220.72,96.66 CD80.2 ; v2(246.7,123.29) 246.05,123.29 CV999.2 ; PC1123.1 115.67,178.71 v2(116.51,178.71) 116.43,178.78 PR1175.2 115.67,179.47 PC1129.2 ; CV1043.2 236.09,134.36 236.09,133.89 v2(236.28,133.7) ; v2(245.89,154.66) 245.89,154.08 CV993.2 ; v2(335.79,172.62) CN22.2 ; PC1941.2 46.52,88.49 v2(46.22,88.79) ; v2(245.03,146.64) 245.66,146.02 CV998.2 ; v2(26.97,82.26) 26.97,82.75 26.52,83.2 PC110.2 PC109.2 26.03,82.01 25.65,81.63 PR247.2 ; CI3.2 324.61,99.13 v2(324.76,99.28) ; v2(196.71,139.89) 196.73,139.91 CV860.2 ; PC1513.2 209.22,141.11 v2(209.1,140.99) ; v2(246.39,158.12) 246.43,158.08 CV1031.2 ; v2(196.93,134.8) 196.93,134.42 CV891.2 ; CV898.2 200.61,144.9 201.28,145.57 CV890.2 201.28,146.93 201.74,147.39 v2(201.93,147.39) ; RH183.2 RH184.2 131.12,145.39 v2(131.31,145.2) ; PC1056.2 171.12,181.35 v2(171.3,181.17) ; v2(91.45,73.51) 91.45,74.16 91.17,74.44 RH5876.2 ; v2(219,181.32) 218.73,181.59 QZ18.3 ; v2(169.82,129.88) 169.95,130.02 CH132.2 ; CD89.2 CD90.2 256.08,83.51 256.5,83.09 v2(256.53,83.09) ; v2(247.89,119.59) 247.75,119.73 RV1350.2 CV920.2 ; QRTC1.3 178.36,72.34 177.53,73.18 177.53,73.9 v2(177.42,74.01) 177.22,73.81 176.44,73.81 176.19,73.55 RE143.1 175.44,74.46 QR104.3 ; v2(318.5,107.52) 318.06,107.08 RI25.2 ; 137.63,95.95 138.14,95.44 CD72.2 ; 137.63,95.95 137.63,96.62 v2(137.64,96.62) ; 137.63,95.95 137.63,95.94 137.13,95.44 CD8.2 ; v2(247.55,155.45) 247.9,155.45 248.41,155.96 CV996.2 ; v2(238.12,163.37) 238.72,162.77 CV1030.2 ; v2(243.89,133.88) 243.89,134 243.54,134.36 CV1042.2 ; v2(220.19,149.77) 221.14,149.77 221.41,149.5 CV872.2 ; v2(210.01,178.87) 209.64,178.49 209.17,178.49 CV962.2 ; v2(92.35,69.64) 92.35,69.64 92.35,69.88 91.97,70.27 91.22,70.27 CD3324.2 91.54,70.81 91.54,71.85 CH200.2 91.08,72.26 90.5,72.26 CH3320.2 ; JRTC.3 v2(324.66,168.74) ; UV28.3 170.47,177.74 170.83,177.38 v2(170.83,176.44) ; v2(234.24,183.71) 234.24,183.22 PC904.2 234.61,182.96 234.87,183.23 v2(234.87,183.74) ; CH174.2 v2(128.91,160.93) 128.91,160.81 130.25,159.47 CD3328.2 ; v2(237.68,177.1) 238.65,176.13 v4(238.65,175.14) ; PC216.2 22.66,70.49 PC200.1 v2(21.86,70.47) ; v2(235.48,153.83) 235.68,153.62 CV1033.2 ; CV937.2 236.72,180.24 236.14,180.82 v2(235.66,180.82) 235.45,180.6 CV951.2 ; RZ86.2 RZ71.2 113.05,118.56 v2(113.05,119.16) ; v2(104.08,73.81) 104.08,73.81 104.08,74.72 103.58,75.21 RH567.2 ; v2(329.1,112.77) 328.77,112.77 328.09,112.09 JCR.7 ; CE52.2 301.64,72.98 CE40.2 302.44,73.11 v2(302.44,73.68) ; v2(224.21,120.13) RV643.1 RV653.1 ; JCR.15 347.87,117.44 347.62,117.69 v2(347.28,117.69) ; v2(26.21,138.19) 25.83,138.19 25.67,138.03 RM13.1 ; v2(203.11,137) 203.25,137.14 PC1014.2 ; v2(308.87,77.03) 308.82,76.98 RE32.1 ; RV651.1 v2(221.21,120.29) ; RZ1149.1 CH198.2 78.66,73.51 78.6,73.57 v2(78.6,73.58) ; CD16.2 168.67,94.32 168.78,94.21 CD17.2 168.78,92.83 167.74,91.79 v2(167.23,91.79) ; CZ96.2 179.74,154.02 v2(180.26,153.5) ; v2(258.29,109.75) 257.92,109.75 CZ9.2 257.05,110.62 v2(257.05,110.97) ; RE44.2 292.1,71.8 v2(292.1,72.31) ; CV980.2 225.29,174.39 224.86,174.39 v2(224.85,174.39) ; RZ43.1 262.1,106.41 262.67,105.83 v2(262.74,105.83) ; CD29.2 226.11,85.74 v2(226.8,85.05) 226.12,84.37 RD40.2 ; v2(26.47,151.05) 26.09,150.67 PD100.2 ; CV981.2 224.05,176.5 224.36,176.19 224.54,176.19 v2(224.78,175.95) ; v2(231.81,85.05) 231.65,84.89 RH210.2 ; CV948.2 229.72,172.36 v2(228.93,172.36) ; CD41.2 CD40.2 265.28,71.37 265.87,70.77 v2(265.87,70.16) ; v2(245.74,160.89) RV636.2 245.74,162.58 CV989.2 ; v2(212.52,168.37) 212.65,168.5 CV973.2 ; v2(24.05,166.01) 23.7,165.65 23.7,164.66 24.06,164.3 RI7.2 ; CA129.2 9.22,74.01 v2(9.22,73.12) ; RZ1958.2 236.46,72.92 236.08,73.3 v2(235.64,73.3) ; v2(212.85,146.59) 212.8,146.64 CV902.2 211.62,146.42 CV923.2 ; 213.35,135.78 212.88,135.31 PC1036.2 ; RV581.2 218.55,115.87 218.88,115.54 v2(219.23,115.54) ; CV875.2 201.15,143.05 v2(201.15,142.85) ; v2(194.37,73.27) 194.37,74.34 192.64,76.07 CE65.2 ; CV956.2 CV954.2 236.43,174.47 v2(236.13,174.76) ; v2(326.95,119.65) 327.56,119.04 JCR.4 ; v2(209.85,90.3) 209.46,90.3 CD19.2 ; v2(26.34,143.27) 26.21,143.15 RV561.2 ; v2(237.89,78.68) 237.89,78.4 CS14.2 ; v2(86.43,88.54) 86.19,88.3 CH192.2 ; RV631.2 v2(240.46,136.25) ; RZ32.1 193.29,74.27 193.68,73.88 v2(193.68,73.29) ; CD27.2 241.32,95.97 v2(241.3,95.94) 241.27,95.97 CD28.2 v2(239.54,95.97) ; RD30.2 CD18.2 147.84,86.87 147.84,89.1 148.25,89.5 v2(148.5,89.5) ; v2(107.11,167.15) 109.47,167.15 PC1102.2 ; v2(206.11,140.1) 205.98,139.97 PC1006.2 ; CV889.2 204.48,147.48 v2(204.44,147.43) 204.42,147.41 CV887.2 ; PC1934.2 51.65,86.22 52.12,86.22 v2(52.21,86.31) ; C3.2 167.44,71.09 167.05,70.7 v2(164.88,70.7) ; CV946.2 v2(223.65,180.49) ; v2(232.46,111.27) 232.09,110.9 QF1.1 ; CV970.2 211.24,178.21 210.92,177.89 v2(210.92,177.17) ; PC1033.2 207.9,135.6 v2(208.19,135.9) ; CH197.2 118.22,120.2 118.74,119.68 v2(118.81,119.68) ; CH103.2 170.35,139.4 v2(170.07,139.12) ; v2(119.43,81.27) 119.79,81.62 CZ105.2 ; CV1015.2 247.31,131.96 v2(247.51,132.16) ; v2(67.51,72.59) 67.97,72.59 68.55,73.17 CH52.2 ; RD29.2 175.23,91.41 v2(175.54,91.71) ; PC213.2 23.88,86.15 v2(25.22,87.5) 25.38,87.33 PQ212.1 ; v2(176.52,156.47) 176.66,156.33 176.66,154.89 CH114.2 ; CV938.2 234.25,178.36 234.25,177.64 v2(233.78,177.17) ; v2(242.01,78.68) 241.51,78.68 v4(241.08,78.25) CZ2154.2 ; v2(192.69,155.33) 194.05,155.33 CV869.2 ; CV884.1 212.72,133.99 213.5,133.22 CV888.2 213.79,133.17 v2(214.5,133.17) ; CV1039.2 242.81,153.97 v2(243.08,153.7) ; v2(237.88,147.43) 237.88,146.6 CV1022.2 ; CE17.2 282.25,84.63 v2(283.06,85.44) 283.06,86.17 283.22,86.32 v4(283.77,86.32) 284.34,86.89 RE58.2 285.22,87.28 285.09,87.41 CE41.2 RZ41.2 ; v2(235.76,159.31) CV997.2 CV1038.2 ; v2(323.39,112.29) 323.39,112.62 QI10.3 ; CV947.2 v2(224.84,180.49) ; CV975.2 206.36,178.52 v2(206.81,178.07) 207.35,178.07 CV965.2 ; CE44.2 RE61.2 296.01,90.47 296.47,90.92 v2(296.47,91) ; CE20.2 299.21,73.78 v2(299.21,72.61) ; CN6.2 346.59,155.48 346.93,155.82 v2(346.93,156.6) ; RV602.1 217.3,144.18 217.73,144.61 v2(217.73,144.81) ; PC1514.2 201.92,143.66 v2(202.18,143.91) ; CD79.2 v2(140.62,95.8) CD78.2 ; v2(214.5,138.17) 214.46,138.12 CV922.2 ; PC1945.1 39.54,86.14 PC1933.2 38.9,86.12 v2(38.65,86.38) ; v2(220.14,120.54) 220.14,119.68 220.21,119.62 RV656.1 220.14,119.55 220.12,119.53 RV579.2 ; v2(102.37,82.85) 102.24,82.98 YH2.4 ; CV917.2 170.03,180.1 169.77,179.85 v2(168.99,179.85) ; RI23.2 318.92,97.81 v2(318.92,97.04) ; PQ1906.3 53.62,90.07 PR1920.2 53.62,91.13 v2(54.11,91.62) ; CV949.2 228.4,173.31 228.69,173.6 229.13,173.6 v2(229.16,173.57) ; v2(234.91,159.33) 233.91,159.33 CV1021.2 ; v2(218.48,88.59) 218.94,88.59 CD87.2 ; v2(63.43,71.27) 64.21,71.27 RH544.2 ; JRTC.2 v2(328.76,172.87) ; v2(53.37,82.11) 53.11,82.38 PR1909.1 PC1928.2 ; CD1.2 144.55,96.66 v2(144.32,96.44) ; CV935.2 206.93,174.18 v2(206.32,173.57) ; RV632.2 243.46,156.27 v2(243.48,156.25) ; CV979.2 231.67,175.23 232.18,175.73 v2(232.18,176.37) ; CD20.2 211.36,90.35 v2(211.88,90.35) 212.35,90.35 212.75,89.95 CD83.2 ; QV12.3 35.33,100.02 v2(35.33,99.38) ; PR254.2 24.68,74.1 PC214.2 v2(23.8,73.22) ; v2(202.2,133.96) 202.82,133.34 PC1502.2 ; QE20.3 135.89,80.52 135.97,80.6 v2(136.22,80.6) ; v2(130.63,141.23) 130.63,141.5 130.75,141.62 RH185.2 RH187.2 ; CV988.2 237.55,157.74 CV994.2 237.54,157.52 237.88,157.18 v2(237.88,157.03) ; v2(213.94,95.77) 214.27,95.44 CD23.2 ; CZ2155.2 236.91,119.78 v2(236.52,120.16) ; v2(186.66,182.36) 186.57,182.26 PR1511.2 ; v2(212.52,165.17) 212.66,165.02 CV971.2 ; v2(229.07,177.87) 229.22,178.02 CV942.2 ; v2(72.77,78.97) 73.18,78.57 RH565.2 ; v2(134.53,96.01) 134.33,95.81 CD2.2 ; v2(245.88,126.5) 245.72,126.66 CV1007.2 ; CV950.2 229.46,174.5 v2(229.39,174.57) ; v2(184.33,79.1) 184.33,79.15 184.32,79.16 184.32,80.53 184.71,80.92 DE5.1 ; v2(192.27,130.26) 192.47,130.05 CV866.2 ; CV926.2 202.3,173.9 v2(202.03,174.17) ; v2(245.88,129.7) 245.78,129.6 245.78,129.1 245.67,128.99 245.67,128.48 ; v2(347.32,84.28) PR410.2 ; CV1028.2 CV1029.2 CV1027.2 v2(237.5,162.95) ; v2(209.16,173.43) 209.16,173.42 CV931.2 ; v2(65.84,88.82) 65.84,89.21 PR280.2 66.86,90.22 PC222.2 ; v2(346.39,179.97) SW2.2 ; v2(169.05,135.08) 168.39,134.43 CH127.2 ; v2(201.43,174.86) 201.46,174.88 CV977.2 ; CV901.2 209.26,147.55 v2(209.43,147.39) ; RV620.2 206.31,172.17 v2(206.12,172.37) ; CE66.2 102.1,101.2 v2(102.6,100.7) ; CV974.2 212.63,166.65 v2(212.52,166.77) ; v2(346.82,94) PC335.2 ; v2(10.73,105.87) 10.24,106.37 RA74.2 ; v2(340.83,182.01) 340.96,182.14 DL1.1 ; PC220.2 65.15,90.77 v2(65.87,90.77) ; v2(216.16,145.58) 216.16,146.22 CV1051.2 ; v2(207.78,147.39) 206.98,146.6 CV903.2 206.2,145.79 CV921.2 ; PC1263.2 161.91,183.01 PR1002.2 161.99,184.22 162.38,184.61 163.94,184.61 164.35,184.21 QZ15.1 164.35,183.95 163.87,183.47 CV919.2 ; v2(211.54,115.66) 211.24,115.36 RV1838.2 ; v2(158.94,129.85) 158.49,129.85 CH119.2 ; v2(203.71,174.8) 203.8,174.7 203.8,174.16 CV936.2 ; v2(316.27,105.14) 316.64,105.5 CI4.2 ; v2(290.74,69.8) 290.74,70.02 290.61,70.16 290.61,70.52 CE38.2 ; CD71.2 146.6,89.53 v2(146.94,89.53) ; CV851.2 203.42,131.49 204.04,132.11 PC1032.2 204.01,132.24 PC1010.2 ; v2(203.11,140.98) 203.19,140.9 PC1023.2 ; CV906.2 211.84,120.71 v2(211.71,120.83) ; v2(238.63,129.68) 238.68,129.74 RV616.2 ; v2(213.84,177.17) 213.49,177.53 CV969.2 ; CV899.2 221.28,153.41 v2(221.09,153.22) 220.48,153.22 CV873.1 219.89,153.82 CV863.2 ; CV983.2 228.36,165.35 v2(228.19,165.18) ; CV1008.2 245.56,121.35 v2(245.56,122.31) ; CV976.2 202.29,178.64 CV932.2 200.98,178.59 v2(200.57,178.18) ; v2(114.48,183.79) 113.72,183.03 113.72,182.34 PC1130.1 113.26,182.21 112.64,182.83 PC1132.2 ; v2(26.4,166.58) 26.1,166.88 RI6.2 ; v2(285.75,80.07) 285.35,80.07 284.98,79.7 CE70.2 ; RV1841.2 195.33,119.64 v2(194.27,120.7) ; CH123.2 160.36,129.98 v2(159.83,130.5) ; v2(216.81,176.23) 216.42,176.61 CV958.2 ; v2(247.45,146.57) 247.45,146.2 CV1023.2 ; CV1046.2 234.1,134.28 v2(234.68,133.7) ; v2(121.12,85.01) 121.12,85.38 120.88,85.63 RH211.2 ; CV939.2 238.1,166.24 CV955.2 236.21,167.04 v2(236.21,167.59) 236.51,167.59 236.7,167.79 CV941.2 ; v2(240.02,159.35) 240.21,159.54 QV102.3 ; CT89.2 21.98,114.13 v2(22.25,114.4) ; v2(245.62,82.88) 245.62,82.93 246.11,83.42 RD39.2 ; CV930.2 206.95,176.22 206.95,177.12 v2(206.69,177.38) ; v2(171.62,134) 171.95,134.34 CZ49.2 ; CV894.2 217.92,132.15 CV895.2 217.49,131.72 216.73,131.72 216.18,132.26 v2(216.18,132.34) ; RZ46.1 v2(56.92,75.58) ; CV1010.2 v2(241.73,128.61) ; v2(206.01,111.81) 205.85,111.65 205.03,111.65 204.57,112.11 RV550.2 204.51,112.48 202.81,112.48 201.85,113.43 RV1844.2 ; CH112.2 171.41,154.16 CH113.2 170.48,154.12 CH116.2 170.33,153.98 v2(169.64,153.98) ; CD10.2 CD9.2 179.79,86.82 v2(179.87,86.9) ; PC1039.2 204.02,135.91 v2(204.1,135.99) 204.1,136.04 204.98,136.92 PC1011.2 ; UZ8.2 53.39,96.16 54.91,97.68 v2(54.91,98.32) ; v2(347.32,85.24) PR406.2 ; JCR.12 347.21,121.99 v2(346.51,122.7) ; PC400.2 347.33,88.32 v2(347.33,88.94) 347.1,89.17 PR403.1 ; CV1020.2 245.87,160.17 CV1037.2 247.84,159.8 v2(248.15,160.1) ; v2(208.08,143.97) 207.83,143.72 PC1007.2 ; CT159.2 23.8,129.82 v2(23.83,129.85) 23.85,129.82 CT160.2 ; v2(227.38,173.97) 227.46,174.05 CV952.2 ; 235.51,176.53 236.1,175.94 v2(236.1,175.56) ; v2(246.89,133.81) 247.95,133.81 248.34,134.19 CV1003.2 ; PR217.2 8.92,92.3 PQ204.3 8.46,91.84 v2(7.77,91.84) ; CE27.2 305.17,73.47 v2(305.71,74.01) 306.17,73.55 C3320.2 ; PC1940.2 43.06,88.13 v2(43.06,88.77) ; v2(220.93,146.39) 220.93,147.14 CV870.2 ; JRTC.4 v2(331.61,164.15) ; v2(243.85,85.05) 243.85,85.52 RD38.2 ; PR839.2 106.55,128.8 106.71,128.95 109.78,128.95 ; CV897.1 CV896.1 221.57,131.07 v2(220.97,130.47) ; v2(58.31,71.62) 58.21,71.52 57.2,71.52 57.07,71.65 CZ18.2 ; CH128.2 172.34,131.18 172.8,131.64 v2(172.92,131.64) ; v2(173.72,129.18) 173.44,129.18 CH129.2 ; CZ11.2 53.8,75.08 v2(53.14,74.41) ; CE71.2 v2(281.79,82.26) ; PC217.2 18.8,94.51 18.8,95.52 v2(18.59,95.73) ; CV940.2 224.07,165.3 CV986.2 224.07,166.29 224.63,166.85 v2(224.98,166.85) ; v2(308.85,86.51) RE30.2 ; v2(329.17,185.34) SW1.4 ; v2(346.39,176.3) SW2.1 ; RV1128.2 173.79,177.36 CV918.2 173.81,177.05 175.02,175.84 ; UZ30.9 v2(241.86,117.62) ; v2(345.74,91.6) PR405.1 ; CD21.2 188.66,88.86 v2(188.66,88.86) ; v2(225.86,114.62) CV853.2 ; CV929.2 206.45,166.31 v2(206.1,165.96) ; CV1025.2 246.65,150.98 v2(246.65,150.59) ; v2(224.85,109.16) 225.23,109.54 RV580.1 ; v2(347.32,87.01) PR404.2 ; v2(200.65,121.75) 200.33,121.43 CE3323.2 ; PD102.1 v2(18.3,69.8) ; v2(51.49,88.13) 51.49,87.91 51.37,87.79 PR1923.2 ; v2(243.02,150.87) 242.99,150.9 CV1035.2 ; CV945.2 v2(221.23,180.49) ; v2(148.29,96.47) 147.93,96.84 CD5.2 ; v2(72.41,96.43) 72.02,96.43 71.77,96.68 ; RV642.1 v2(223.2,120.13) ; CV944.2 v2(222.44,180.49)
  BOTTOM w0.102: v2(72.77,78.97) 72.83,78.91 73,78.91 UH2.AM49 ; 238.21,177.74 PC912.2 ; 94.01,84.28 94.01,83.12 94.26,82.87 94.38,82.87 v2(94.75,82.51) ; v4(12.88,111.52) 12.98,111.62 v2(13.49,111.62) ; v2(217.92,168.68) 218.37,168.68 v4(218.54,168.51) ; v2(83.08,70.53) 83.16,70.61 83.16,71.1 UH2.BG28 83.38,71.32 83.38,72.33 83.84,72.79 84.19,72.79 UH2.BC26 ; v2(239.48,153.85) 239.5,153.87 240.33,153.87 UV26.J10 ; UH2.BC31 81.99,72.79 81.58,72.79 81.18,72.39 81.18,71.55 81.14,71.51 UH2.BG33
  BOTTOM w0.107: UV23.J10 v2(232.98,170.77)
  BOTTOM w0.127: v2(320.96,99.31) 320.97,99.3 v4(322.19,99.3) ; UH1.BR9 135.75,132.59 135.44,132.9 134.91,132.9 134.88,132.86 134.04,132.86 132.77,131.59 132.64,131.59 132.53,131.49 132.53,131.49 v2(132.52,131.49) ; v4(13.16,120.4) 13.16,120.11 13.45,119.82 CT189.2 ; v2(65.87,90.77) 65.24,90.77 v4(64.92,91.09) ; v2(106.86,82.38) 107.3,82.38 v4(107.76,81.92) ; v4(124.59,150.74) 125.12,150.74 v2(125.49,151.11) ; v2(220.27,177.35) v4(220.27,178) ; v2(93.65,95.52) 93.62,95.5 93.62,94.57 93.31,94.25 UH2.A8 ; v2(325.09,116.1) v4(325.82,116.1) ; v2(323.49,116.93) v4(322.55,116.93) ; v2(78.3,99.5) v4(79.16,99.5)
  BOTTOM w0.152: v2(164.78,125.97) 165.23,126.42 UH1.T1 UH1.T2 UH1.T3 ; UH1.T3 UH1.T4 UH1.T5 ; UH1.T3 165.1,128.23 v2(164.79,127.92) ; UH1.AF4 UH1.AF3 UH1.AF2 UH1.AF1 v2(157.69,126.38) ; UH1.BB3 145.14,128.21 145.14,127.6 UH1.BB2 145.14,127.56 145.14,126.95 UH1.BB1 145.16,126.88 145.16,126.39 v2(144.76,125.99) ; UH1.BB3 145.14,128.25 145.14,128.86 UH1.BB4 145.14,128.9 145.14,129.51 UH1.BB5 145.14,129.55 145.14,130.16 UH1.BB6 ; UH1.BB3 145.02,128.23 144.73,127.94 v2(144.73,127.9) ; v2(97.44,80.79) 97.31,80.91 UH2.AG1 ; UT1.H1 UT1.H2 ; UH2.A28 83.34,94.28 83.3,94.31 v2(83.3,94.41) ; UT1.AB1 UT1.AC1 29.94,111.56 30.14,111.56 v2(30.28,111.42) 30.18,111.32 29.99,111.32 UT1.AC2 UT1.AB2 ; v3(86.7,70.75) 86.7,70.76 86.69,70.77 UH2.BG22 ; UT1.AB6 UT1.AC6 ; UH2.BG37 78.94,70.85 v2(79.02,70.78) ; UH1.N5 UH1.N4 UH1.N3 ; UH2.AG49 72.93,80.91 72.8,81.04 v2(72.8,81.35) ; UT1.N23 UT1.N22 ; UH1.N3 UH1.N2 UH1.N1 v2(167.74,126.15) ; UH1.N3 167.63,128.23 v2(167.3,127.9) ; UH1.BE3 UH1.BE2 UH1.BE1 142.6,126.41 v2(142.16,125.97) ; UH1.BE3 UH1.BE4 UH1.BE5 ; UH1.BE3 142.56,128.23 v2(142.14,127.81) ; v2(72.76,84.27) UH2.AA49 ; UH1.BJ31 UH1.BJ32 ; UH2.BC24 85.28,72.72 85.28,71.58 85.01,71.32 UH2.BG25 ; v2(97.2,82.89) 97.13,82.89 UH2.AD1 UH2.AD2 ; UT1.R23 UT1.R22 ; v2(72.71,86.83) 73.08,86.47 UH2.T49 73.43,86.47 73.61,86.29 74.68,86.29 ; UT1.K1 UT1.K2 ; 171.94,145.45 171.62,145.78 171.62,146.39 171.94,146.72 UH1.G28 ; UH2.M49 72.85,88.69 v2(72.74,88.8) ; UH2.AM1 96.99,78.88 97.44,78.88 v2(97.79,78.53)
  BOTTOM w0.165: UH2.AE46 74.86,82.01 74.55,82.33 73.47,82.33 UH2.AD49
  BOTTOM w0.178: UT1.AB10 UT1.AC10 ; UT1.AB20 UT1.AC20 ; 19.66,100.86 v2(19.4,100.6) 19.48,100.51 19.86,100.51 ; 19.66,100.86 19.38,101.14 19.38,101.78 19.59,101.99 UT1.A22 ; 19.66,100.86 20.4,100.86 20.66,101.12 UT1.C23 UT1.C22 ; UT1.AB12 UT1.AC12 ; UT1.A8 UT1.B8 ; UT1.A10 UT1.B10 ; v2(18.81,102.92) 18.82,102.91 UT1.A20 UT1.B20 ; UT1.AA23 UT1.AA22 ; UT1.G23 UT1.G22 ; UT1.AB22 UT1.AC22 ; UT1.L22 UT1.L23 24.34,100.98 v2(24.4,100.92) ; v2(21.48,100.94) 21.58,101.03 UT1.E23 UT1.E22 ; UT1.AB8 UT1.AC8 ; UT1.A18 UT1.B18 ; UT1.U23 UT1.U22 ; UT1.A14 UT1.B14 ; UT1.A16 UT1.B16 ; UT1.B6 UT1.A6 ; UT1.AC14 UT1.AB14 ; UT1.AB16 UT1.AC16 ; UT1.B12 UT1.A12 ; UT1.AB18 UT1.AC18 ; UT1.M2 UT1.M1 ; UT1.W22 UT1.W23 ; UT1.J23 UT1.J22
  BOTTOM w0.203: UH1.BJ31 139.32,149 v2(138.99,148.68) 139.18,148.48 139.32,148.48 UH1.BJ30 139.52,147.89 139.39,147.76 UH1.BK29 138.9,147.55 UH1.BL29 138.44,147.58 137.85,147.58 UH1.BM29 ; v2(134.48,145.05) 134.62,145.19 UH1.BT26 UH1.BR26 UH1.BP26 ; UH1.AV37 148.12,152.91 v2(148.44,153.23) 148.11,153.56 UH1.AV38 ; UH1.BN14 UH1.BP14 136.52,135.81 v2(136.19,136.13) 135.87,135.81 UH1.BR14 UH1.BT14 ; v2(8.88,128.97) 8.8,129.05 DT26.2 ; UH1.AU9 148.74,131.9 v2(148.95,131.9) v2(148.95,132.53) ; UH1.AU9 UH1.AU10 ; UH1.AU9 UH1.AU8 UH1.AU7 ; UH1.BH6 140.08,130.66 UH1.BH7 ; UH1.BH6 UH1.BG6 UH1.BF6 UH1.BE6 ; UH1.BH6 140.04,130.18 v2(139.66,129.8) ; UH1.BM29 UH1.BN29 ; UH1.BM29 137.69,147.43 137.69,146.89 UH1.BM28 137.82,146.7 v2(138.14,146.37) 137.82,146.05 UH1.BM27 ; v2(78.6,73.58) 78.57,73.55 78.45,73.42 78.24,73.42 UH2.BC40 ; v2(154.44,132.53) 154.44,132.54 v2(154.44,133.17) 154.07,132.79 UH1.AL10 ; v2(154.44,132.53) v2(154.44,131.9) 154.03,131.49 UH1.AL8 UH1.AL7 ; v2(154.44,132.53) 154.05,132.14 UH1.AL9 ; UH1.BL13 138.47,134.88 v2(138.14,134.56) 138.14,134.49 UH1.BM12 137.82,134.12 v2(137.49,133.8) ; UH1.G5 171.95,129.58 171.95,130.13 UH1.G6 ; UH1.G5 171.83,129.53 171.5,129.2 ; UH1.G5 172.43,129.53 UH1.F5 ; UH1.K7 170.5,130.84 v2(170.74,131.07) ; v2(174.93,133.22) 174.93,133.23 UH1.C11 174.54,133.86 174,134.4 UH1.D12 ; DT26.2 8.24,129.58 v2(8.2,129.62) ; DT26.2 8.24,128.73 v2(8.53,128.44) ; v2(171.28,149.97) 171.35,149.97 UH1.H32 171.91,149.41 172.54,149.41 UH1.F31 ; v2(171.28,149.97) 170.94,150.31 UH1.J33 ; v2(171.28,149.97) 170.96,149.65 UH1.J32 ; v2(170.07,139.12) UH1.J18 UH1.H18 171.27,139.1 171.92,139.1 UH1.G18 ; 151.7,133.8 151.6,133.8 UH1.AP11 151.51,133.17 v2(151.7,133.17) ; 151.7,133.8 151.7,133.8 v2(151.7,133.17) ; 151.7,133.8 151.98,134.09 UH1.AN12 ; 151.7,133.8 151.41,134.09 UH1.AP12 ; UH1.D33 174.54,149.49 UH1.C31 174.21,149.02 v2(174.21,148.96) 174.21,148.88 UH1.D30 ; v2(213.86,123.72) 213.97,123.61 213.97,122.36 214.66,121.66 214.66,120.9 214.3,120.54 v2(214.3,120.35) 214.3,119.87 214.7,119.47 215.96,119.47 216.52,120.03 216.52,120.6 216.02,121.1 216.02,122.11 215.06,123.07 215.06,125.88 214.85,126.09 UV18.G2 ; 7.16,136.78 7.16,136.44 v2(7.35,136.26) ; 7.16,136.78 DT21.2 7.64,136.8 v2(7.95,136.49) ; 7.16,136.78 v2(6.73,136.34) ; v2(156.27,134.4) 155.96,134.09 UH1.AH12 ; UH1.BC34 144.18,150.96 v2(144.5,151.28) ; UH1.W33 162.9,150.31 v2(162.6,150.61) ; v2(174.59,128.26) 174.64,128.31 UH1.B3 175.27,128.18 UH1.A3 ; v2(174.59,128.26) 174.59,127.73 UH1.C2 ; v2(174.59,128.26) 174.12,128.26 UH1.D3 ; 171.5,129.2 171.42,129.2 UH1.J4 UH1.K4 ; 171.5,129.2 171.83,128.88 UH1.G4 UH1.F4 ; UH1.T10 UH1.T9 UH1.T8 UH1.T7 164.95,130.74 UH1.U6 UH1.V6 163.37,130.18 UH1.W5 UH1.W4 UH1.W3 ; UH1.T10 165.21,132.53 v2(165.42,132.53) ; UH1.T10 165.33,133.17 v2(165.42,133.17) 165.14,133.44 UH1.T11 ; UH1.T10 UH1.T11 ; UH1.AC6 UH1.AC5 UH1.AC4 ; UH1.AC6 UH1.AB6 161.38,130.18 162.04,130.84 UH1.Y7 UH1.Y8 UH1.Y9 UH1.Y10 ; UH1.AC6 160.16,130.18 v2(159.83,130.5) ; v2(159.83,130.5) 159.51,130.18 UH1.AD6 159.03,129.85 v2(158.94,129.85) 158.86,129.85 UH1.AE6 ; v2(159.83,130.5) 159.5,130.84 UH1.AD7 UH1.AD8 UH1.AD9 ; UH1.BL35 138.36,151.85 v2(138.16,151.85) 137.82,151.5 UH1.BM35 ; v2(136.84,150.31) 136.84,150.38 UH1.BN34 ; v2(136.84,150.31) 136.52,150.63 UH1.BP34 UH1.BR34 135.87,150.5 UH1.BT32 134.73,149.85 v2(134.63,149.95) ; v2(136.84,150.31) 136.52,149.98 UH1.BP33 136.52,149.78 UH1.BN31 137.48,148.81 v2(137.48,148.76) 137.48,148.65 UH1.BN30 ; UH1.BT24 UH1.BR24 135.89,143.64 136.49,143.64 UH1.BP24 136.57,143.67 137.12,143.67 UH1.BN24 137.17,143.55 v2(137.49,143.22) 137.82,142.9 UH1.BM23 ; UH1.AR5 UH1.AR4 UH1.AR3 UH1.AR2 UH1.AR1 150.14,125.48 v2(150.16,125.46) ; UH1.AL4 UH1.AK4 154.73,128.43 v2(154.73,127.9) 154.85,127.9 UH1.AJ3 ; UH1.G20 172.27,140.37 v2(172.27,140.3) 172.59,139.98 UH1.F19 172.59,139.83 v2(172.28,139.51) ; v2(159.93,133.8) 160.21,134.09 160.38,134.09 UH1.AC12 ; v2(159.93,133.8) 159.83,133.8 UH1.AD11 UH1.AD10 ; v2(159.93,133.8) 159.64,134.09 UH1.AD12 ; UH1.H25 UH1.J25 170.47,144.63 170.25,144.85 v2(170.09,144.85) ; UH1.BM25 138.14,144.73 v2(138.14,144.8) 138.14,144.86 UH1.BM26 ; v2(216.18,132.34) 216.18,132.34 216.18,131.62 216.31,131.49 217.52,131.49 217.53,131.5 217.56,131.5 217.8,131.73 217.8,132.44 218.1,132.74 UV18.C10 UV18.B10 ; v2(176.35,145.35) 176.3,145.4 175.86,145.4 UH1.A26 ; UH1.J22 UH1.H22 171.29,142.22 171.89,142.22 UH1.G22 172.27,141.94 v2(172.27,141.88) 172.59,141.55 UH1.F21 172.59,141.41 v2(172.28,141.09) ; v2(174.9,134.82) 174.9,134.82 174.9,134.83 UH1.C13 174.54,135.32 UH1.D14 ; v2(138.95,134.36) 139.12,134.53 UH1.BK13 ; UH1.A3 175.85,127.66 v2(175.76,127.58) ; UH1.A3 UH1.A4 ; UH1.BA11 UH1.BA10 UH1.BA9 UH1.BA8 UH1.BA7 145.75,130.82 UH1.BB6 ; UH1.BA11 UH1.BA12 ; UH1.BA11 145.85,133.44 v2(146.21,133.8) 146.04,133.8 UH1.BA12 ; UH1.BA11 146.03,133.17 v2(146.22,133.17) ; v2(141.35,152.58) 141.02,152.91 UH1.BG37 ; UH1.BA12 146.1,134.43 v2(146.21,134.43) 146.32,134.43 UH1.AY12 147.03,134.46 v2(147.13,134.46) 147.21,134.46 UH1.AW12 147.91,134.42 v2(148.06,134.42) 148.16,134.42 UH1.AU12 ; UH1.BA12 145.43,134.42 v2(145.3,134.42) 145.16,134.42 UH1.BB12 144.57,134.36 v2(144.38,134.36) ; UH2.AT1 97.21,76.49 v2(97.31,76.39) ; 167.31,150.63 167.7,150.96 UH1.N34 ; 167.31,150.63 v2(167.3,150.63) ; 167.31,150.63 167.7,150.31 UH1.N33 ; UH1.BH10 140.64,133.17 v2(140.73,133.17) 140.45,133.44 UH1.BH11 ; UH1.BH10 140.46,132.79 v2(140.72,132.53) 140.33,132.14 UH1.BH9 ; UH1.BH10 UH1.BH9 ; UH1.BH10 UH1.BH11 ; v2(141.68,134.39) 141.38,134.09 UH1.BG12 ; v2(141.68,134.39) 141.8,134.39 UH1.BF12 142.42,134.42 v2(142.55,134.42) 142.88,134.09 UH1.BD12 143.18,134.09 v2(143.47,133.8) 143.37,133.8 UH1.BD11 ; v2(141.68,134.39) 141.33,134.74 UH1.BG13 ; v2(168.95,148.69) 169.3,148.33 UH1.L30 UH1.L29 ; v2(170.8,133.16) 170.65,133.16 UH1.K11 ; v2(170.8,133.16) 170.43,132.79 UH1.K10 170.31,132.79 v2(169.96,132.44) 170.26,132.14 UH1.K9 170.42,132.08 170.42,131.55 UH1.K8 170.37,131.45 v2(170.74,131.07) ; v2(170.8,133.16) 171.14,132.82 UH1.J10 ; v2(144.5,149.98) 144.17,150.31 UH1.BC33 ; UH1.BN12 137.12,134.12 136.57,134.12 UH1.BP12 UH1.BR12 UH1.BT12 134.64,134.17 v2(134.44,134.37) ; UH1.BN12 137.17,134.12 v2(137.49,133.8) ; UH1.BN12 137.49,134.48 137.49,134.55 v2(137.49,134.55) 137.49,134.62 UH1.BM13 ; UH1.D10 174.02,132.7 174.02,132.15 173.95,132.09 ; v2(172.92,131.64) 173.24,131.97 UH1.E9 ; v2(172.92,131.64) 172.59,131.32 UH1.F8 UH1.G8 171.52,130.82 UH1.J7 170.99,130.82 v2(170.74,131.07) ; v2(172.92,131.64) 172.59,131.97 UH1.F9 172.59,132.1 v2(172.27,132.43) ; UH1.BF34 141.81,150.96 v2(142.14,150.63) 141.82,150.31 UH1.BF33 ; UH1.BN21 137.17,141.32 v2(137.49,141.65) 137.82,141.32 UH1.BM21 137.82,141.17 v2(138.12,140.86) ; UH1.BN21 137.11,141.19 136.58,141.19 UH1.BP21 136.48,141.22 135.9,141.22 UH1.BR21 UH1.BT21 v2(134.35,141.25) ; UH1.BN21 UH1.BN20 137.01,140.31 137.01,139.84 UH1.BN19 UH1.BN18 ; UH1.AU11 148.68,133.44 v2(148.96,133.17) 148.96,132.54 v2(148.95,132.53) ; UH1.AU11 UH1.AU12 ; UH1.AU11 UH1.AU10 ; UH1.BH11 UH1.BH12 ; UH1.Y10 162.59,133.17 v2(162.67,133.17) 162.4,133.44 UH1.Y11 UH1.Y10 ; UH1.A6 175.7,130.47 175.25,130.03 174.9,130.03 UH1.C5 174.05,129.18 v2(173.72,129.18) ; v2(137.49,133.8) 137.49,133.7 UH1.BM11 UH1.BM9 137.72,132.49 137.72,131.9 UH1.BM8 137.74,131.73 137.74,131.09 UH1.BM7 UH1.BN7 ; UH1.AL14 153.67,135.7 v2(153.53,135.7) ; UH1.BM5 137.64,129.45 UH1.BN4 ; UH1.BM5 137.61,129.55 UH1.BM6 137.7,130.18 UH1.BL6 UH1.BK6 139.29,130.18 v2(139.66,129.8) ; UH1.BM5 137.95,129.22 v2(137.95,129.01) 137.72,128.77 UH1.BM3 137.72,127.97 UH1.BM2 137.48,127.58 UH1.BN2 ; UH1.T11 UH1.T12 165.13,134.09 v2(165.41,133.8) 165.7,134.09 UH1.R12 ; v2(340.66,127.08) 340.79,126.95 D18.2 ; v2(6.56,128.51) 6.78,128.73 DT27.2 ; UH1.AR13 150.21,134.74 v2(149.88,134.41) ; UH1.AR13 150.65,135.07 v2(150.78,135.07) 150.46,135.39 UH1.AR14 150.19,135.39 v2(149.87,135.07) ; UH1.AR13 150.64,134.42 v2(150.78,134.42) 150.91,134.42 UH1.AP12 ; UH1.AW3 147.51,128.23 v2(147.19,127.9) ; UH1.AW3 UH1.AW4 UH1.AW5 148.03,129.93 148.21,129.93 UH1.AU6 148.47,130.81 UH1.AU7 ; UH1.AW3 UH1.AW2 UH1.AW1 147.51,126.93 v2(147.19,127.25) ; UH1.N11 UH1.N10 UH1.N9 UH1.N8 UH1.N7 167.7,130.23 UH1.N6 ; UH1.N11 UH1.N12 167.84,134.09 168.16,133.77 ; UH1.N11 167.82,133.44 168.16,133.77 ; v2(158.99,131.88) 159.26,132.14 UH1.AD9 ; UH1.F25 172.92,144.31 v2(172.92,144.24) ; UH1.BA6 UH1.BB6 ; UH1.BB6 144.79,129.85 v2(144.73,129.85) 144.6,129.85 UH1.BC6 UH1.BD6 143.32,130.18 v2(142.99,129.85) ; v2(162.27,127.93) 162.57,128.23 UH1.W3 ; v2(142.99,129.85) 142.67,130.18 UH1.BE6 ; v2(142.99,129.85) 142.92,129.85 UH1.BE5 142.56,129.57 142.56,130.14 UH1.BE6 ; UH2.A37 78.93,93.92 v2(78.93,94.92) ; UH1.BG13 UH1.BG12 ; UH1.BG13 UH1.BG14 141.05,135.39 140.72,135.07 ; UH1.BG12 141.01,134.09 v2(140.72,133.8) 140.44,134.09 UH1.BH12 ; v2(149.23,151.28) 148.9,150.96 UH1.AU34 ; UH1.AJ37 UH1.AJ38 v2(155.13,154.25) ; v2(151.7,133.17) 151.7,133.16 v2(151.7,132.53) ; v2(135.66,154.21) 135.66,153.7 UH1.BR38 ; v2(174.87,131.64) 175.2,131.97 UH1.B9 UH1.A9 ; v2(174.87,131.64) 174.54,131.32 UH1.C8 174.54,131.11 UH1.D6 ; v2(174.87,131.64) 174.54,131.97 UH1.C9 174.49,132.09 173.95,132.09 ; v2(172.27,132.43) 172.27,132.36 UH1.G9 ; v2(172.27,132.43) 172.27,132.5 UH1.G10 ; UH1.AN12 152.41,134.35 152.81,134.35 UH1.AM12 153.33,134.09 v2(153.53,134.3) 153.78,134.3 UH1.AL12 ; UH1.AN12 151.8,134.45 v2(151.71,134.45) 151.6,134.45 UH1.AP12 ; UH1.AU10 148.76,132.53 v2(148.95,132.53) ; UH1.W3 UH1.W2 UH1.W1 162.72,126.44 v2(162.27,126) ; UH1.BE6 143.01,130.59 UH1.BD7 UH1.BD8 ; UH1.K3 UH1.K2 UH1.K1 ; UH1.K3 170.21,128.23 v2(169.82,127.84) ; UH1.K3 UH1.K4 ; UH1.AU33 148.89,150.31 v2(149.21,150.63) ; v2(134.69,128.88) 134.75,128.95 UH1.BT4 ; UH1.AH33 156.04,150.31 v2(156.34,150.6) 155.98,150.96 UH1.AH34 155.96,150.99 155.96,151.57 UH1.AH35 155.96,151.64 155.96,152.22 UH1.AH36 ; UH1.BN18 137.2,138.93 137.78,138.93 UH1.BM18 137.82,138.82 v2(137.49,138.5) 137.17,138.82 UH1.BN18 ; UH1.BN18 137.13,138.93 136.56,138.93 UH1.BP18 UH1.BR18 UH1.BT18 134.49,138.89 v2(134.46,138.85) ; v2(201.96,126.48) 200.24,126.48 UV18.AE2 ; DT27.2 6.78,129.35 v2(6.49,129.65) ; DT27.2 v2(6.05,129.05) ; UH1.D20 174.54,140.04 UH1.C19 174.54,139.84 174.24,139.54 v2(174.24,139.53) ; UH1.BL38 138.67,153.59 v2(138.33,153.93) 137.96,153.56 UH1.BM38 ; v2(7.15,138.86) 7.16,138.85 DT20.2 ; UH1.AE34 158.21,150.96 v2(157.86,150.61) 157.98,150.61 UH1.AE33 ; UH1.G24 172.27,143.52 v2(172.27,143.45) ; UH2.A5 94.97,93.51 v2(95.06,93.43) UH2.C4 95.13,92.8 UH2.C5 ; UH1.A10 176.38,132.82 v2(176.46,132.74) ; UH1.BG38 v2(141.35,153.88) ; UH1.AC4 UH1.AC3 UH1.AC2 UH1.AC1 v2(160.2,126.38) ; UH1.AC4 160.08,128.88 v2(159.75,128.55) ; UH1.BN7 137.17,130.55 v2(137.24,130.48) ; UH1.BN7 UH1.BP7 UH1.BR7 ; UH1.AG6 UH1.AH6 UH1.AJ6 UH1.AJ5 UH1.AJ4 UH1.AJ3 ; UH1.AG6 156.73,130.3 UH1.AG7 UH1.AG8 ; UH1.AG6 157.11,130.44 v2(157.26,130.44) ; v2(220.97,128.8) 220.97,127.5 220.74,127.27 219.2,127.27 219,127.47 UV18.B4 ; UH1.F36 172.86,151.85 173,151.85 UH1.E35 173.29,151.56 173.29,150.98 UH1.E34 ; UH1.F36 172.32,152.26 UH1.H35 171.53,151.61 UH1.J36 ; UH1.F36 172.53,152.26 v2(172.85,152.58) 172.85,153.45 UH1.E38 ; UH1.N6 UH1.N5 ; UH1.N6 UH1.M6 ; UH1.N6 UH1.P6 ; v2(172.27,143.45) 172.59,143.13 UH1.F23 ; v2(172.27,143.45) 172.27,143.38 UH1.G23 ; UH1.F17 172.59,138.22 v2(172.27,137.9) ; UH1.A28 v2(176.35,146.99) ; UH1.C37 174.51,152.9 175.08,152.9 UH1.B37 175.29,152.98 UH1.A37 176.58,153.71 v2(176.58,153.94) ; UH1.BR29 UH1.BP29 ; v2(313.27,99.29) DI17.2 ; UH1.A24 v2(176.48,143.84) ; v2(140.72,131.9) 140.72,131.3 UH1.BH7 ; UH1.H12 171.29,134.33 v2(171.62,134) ; UH1.D18 174.54,138.47 UH1.C17 v2(174.94,137.94) ; UH1.AP10 151.5,132.53 v2(151.7,132.53) ; UH2.AP46 74.95,76.8 UH2.AT45 ; UH1.D26 173.89,145.45 v2(174.23,145.79) 174.23,145.91 174.53,146.21 UH1.C27 174.54,146.34 UH1.D28 ; v2(176.52,139.14) 175.86,139.14 UH1.A18 ; UH1.BH12 140.13,134.09 v2(139.81,133.77) 139.44,134.13 UH1.BJ12 ; UH1.AL34 153.49,150.96 v2(153.16,150.63) ; UH1.AD10 UH1.AD9 ; UH1.AD10 159.84,133.17 v2(159.93,133.17) ; v2(158.1,135.7) 157.95,135.7 UH1.AF14 UH1.AF13 UH1.AF12 ; UH1.AJ3 UH1.AJ2 UH1.AJ1 v2(155.17,126.38) ; 168.16,133.77 168.47,134.09 UH1.M12 UH1.M13 UH1.M14 ; UH1.BD9 143.08,132.14 v2(143.47,132.53) 143.27,132.53 UH1.BD10 ; UH1.BD9 UH1.BD10 ; UH1.BD9 143.25,131.9 143.42,131.9 ; UH1.BD9 UH1.BD8 ; UH1.F29 172.62,147.78 172.92,147.49 v2(172.92,147.39) ; v2(151.7,131.9) 151.29,131.49 UH1.AP8 151.68,131.05 151.68,130.32 UH1.AN6 151.77,130.13 UH1.AN5 152.09,129.2 v2(152.27,129.2) ; v2(151.7,131.9) v2(151.7,132.53) ; v2(151.7,131.9) 151.48,131.9 UH1.AP9 ; v2(176.71,148.99) 176.4,148.99 176.18,148.77 UH1.A30 ; v2(96.56,94.57) 96.3,94.3 96.3,94.08 UH2.A2 ; UV18.AH32 196.92,150.66 196.92,149.95 v2(196.96,149.9) ; v2(157.17,133.66) 157.17,133.24 UH1.AG10 ; UH2.BC45 75.38,73.9 v2(75.4,73.92) ; UH2.AE46 75.15,82.01 75.65,82.51 ; UH1.F13 172.06,134.64 172.06,134.64 171.94,134.53 UH1.G12 171.94,134.33 v2(171.62,134) ; v2(174.86,147.41) 174.86,147.46 UH1.C29 ; UH1.BD38 143.38,153.56 v2(143.71,153.23) 143.39,152.91 UH1.BD37 ; UH1.BC13 UH1.BC12 143.83,134.09 v2(143.48,134.44) 143.48,134.49 143.74,134.74 UH1.BC13 ; UH1.BC13 UH1.BC14 143.79,135.39 143.49,135.69 v2(143.49,135.74) ; UH1.F4 UH1.E4 ; UH1.F4 172.58,128.57 172.69,128.47 UH1.F3 172.61,128.23 172.3,127.92 v2(172.3,127.89) 172.3,127.89 172.61,127.58 UH1.F2 ; UH1.BK25 UH1.BJ25 v2(140.34,144.4) ; UH1.A22 v2(176.48,142.27) ; v2(95.83,94.46) 95.97,94.32 UH2.A3 UH2.A4 ; UH1.BH7 UH1.BH8 UH1.BH9 ; v2(174.87,142.66) 174.87,142.67 174.87,142.89 174.7,143.06 UH1.C23 174.54,143.19 UH1.D24 UH1.C25 ; UH1.F27 172.28,145.9 v2(172.28,145.79) 171.94,145.45 UH1.G26 ; UH1.BD11 143.2,133.44 v2(143.47,133.17) 143.38,133.17 UH1.BD10 ; UH1.BD11 UH1.BD10 ; UH1.AU12 148.85,134.45 v2(148.94,134.45) ; UH1.A12 v2(176.42,134.4) ; UH1.BT3 135.12,128.12 134.7,128.12 v2(134.61,128.03) ; v2(152.66,126.38) UH1.AM1 UH1.AM2 UH1.AM3 152.69,128.26 152.69,128.84 UH1.AM4 152.59,128.88 v2(152.27,129.2) ; UH1.K38 170.06,153.56 v2(169.64,153.98) ; 173.95,132.09 UH1.D9 ; UH1.AU7 149.16,130.18 UH1.AT6 ; UH1.BJ22 UH1.BK22 ; v2(139.66,129.8) 139.94,129.53 UH1.BH5 UH1.BH4 UH1.BH3 UH1.BH2 139.83,127.32 UH1.BH1 139.83,126.38 v2(140.05,126.16) ; DT20.2 7.51,138.26 v2(7.7,138.45) ; DT20.2 6.98,138.26 v2(6.55,138.69) ; UH1.BR7 135.31,131.58 UH1.BT8 ; UH1.BR7 135.73,131.02 135.64,131.11 134.45,131.11 133.99,130.64 133.65,130.64 133.17,130.16 v2(132.84,130.16) ; UH1.T34 165.26,150.96 v2(164.93,150.62) 165.25,150.31 UH1.T33 ; UH1.BA38 145.68,153.48 145.75,153.42 145.75,153.04 145.68,152.97 UH1.BA37 145.75,152.91 v2(146.08,152.58) ; v2(172.92,133.22) 172.59,133.54 UH1.F11 ; UH1.BJ29 140.01,147.1 v2(140.2,147.1) ; v2(171.62,134) 171.62,133.93 UH1.H11 ; v2(152.27,129.2) 152.59,129.53 UH1.AM5 ; UH1.D22 174.54,141.62 UH1.C21 174.67,141.48 174.87,141.28 174.87,141.15 v2(174.91,141.11) ; UH1.AM38 152.83,153.56 v2(153.16,153.23) ; v2(194.43,128.2) 194.43,128.22 UV18.AL5 ; UH2.AR12 91.47,77.16 92.11,77.16 92.56,77.6 92.56,78.11 92.34,78.33 91.54,78.33 UH2.AN12 91.19,78.24 90.84,77.89 90.54,77.89 90.35,78.09 90.35,78.84 ; UH1.BJ33 139.32,150.31 v2(138.99,149.98) 139.31,149.65 UH1.BJ32 ; v2(159.86,154.08) UH1.AC38 159.91,153.5 159.91,152.96 UH1.AC37 ; UV18.AL2 195.27,126.51 196.04,126.51 196.11,126.58 196.11,127.25 v2(196.06,127.3) ; UH1.AB33 v2(161.04,150.63) ; UH1.Y38 v2(162.22,154.08) ; UV18.AH7 196.9,129.79 196.9,128.94 UV18.AH5 ; UH1.Y13 162.32,134.74 v2(162.64,135.07) 162.32,135.39 UH1.Y14 ; v2(80.94,95.15) 81.14,94.95 UH2.A33 ; 75.65,82.51 v2(75.87,82.51) ; 75.65,82.51 75.54,82.51 74.95,83.09 UH2.AC46 ; UH1.T14 164.86,135.39 v2(164.51,135.04) 164.82,134.74 UH1.T13 ; UH1.AY34 146.53,150.96 v2(146.86,150.63) 146.54,150.31 UH1.AY33 ; UH1.G14 172.59,136.62 UH1.F15 172.59,136.83 v2(172.27,137.15) 172.27,137.22 UH1.G16 ; v2(134.22,129.7) 134.27,129.75 UH1.BT5 ; UH1.BR36 135.76,152.24 UH1.BT36 v2(134.62,152.24) ; v2(174.89,136.4) 174.84,136.4 174.54,136.69 UH1.C15 174.54,136.89 UH1.D16 ; v2(176.53,140.8) 176.43,140.69 UH1.A20 ; v2(176.44,136.06) 176.35,135.97 UH1.A14 ; v2(209.74,153.17) 209.74,153.14 209.85,153.03 UV18.N33 ; v2(167.34,153.23) UH1.P38 ; UH1.K4 UH1.K5 169.91,129.88 v2(169.82,129.88) ; UH1.L33 169.38,150.31 v2(169.7,150.63) 169.37,150.96 UH1.L34 ; v2(286.03,99.18) PU600.3 ; UH1.BD8 143.42,131.9 ; UH1.A16 v2(176.48,137.55) ; 143.42,131.9 v2(143.47,131.9) ; v2(316.03,99.33) 315.95,99.33 DI13.2 ; UH1.BJ18 UH1.BK18
  BOTTOM w0.229: UV18.AE7 199.9,130.19 200.3,130.59 201.04,130.59 v2(201.09,130.55) ; v2(18.07,121.69) 18.38,122 UT4.A1
  BOTTOM w0.254: v2(241.88,157.76) 241.81,157.76 241.48,157.44 UV26.H14 UV26.H13 ; v2(218.62,140.67) 218.62,140.66 UV18.C19 217.8,140.64 v2(217.8,140.67) ; JDIMM1.61 120.14,95.66 v2(119.22,96.58) ; v2(214.11,170.71) 213.93,170.71 213.76,170.53 213.75,170.53 213.58,170.37 UV24.K1 UV24.K2 ; v2(202.78,128.07) UV18.AB5 UV18.AB7 202.73,130.57 v2(202.84,130.57) ; v2(243.84,157.99) 243.88,157.95 UV26.E14 ; v2(194.4,146.47) 194.78,146.09 UV18.AL26 ; UH1.BP29 UH1.BN29 ; v2(194.43,128.2) 194.39,128.16 193.62,128.16 UV18.AN4 ; v2(18.21,127.72) 18.21,127.65 18.38,127.49 UT4.L1 ; v2(130.45,183.58) 131.25,184.38 PU1200.4 ; UV24.L10 v2(206.12,169.17) UV24.M10 ; v2(246.39,158.12) 246.39,158.12 UV26.A14 ; UV24.U14 v2(202.92,165.17) ; v2(57.6,101.99) 57.6,102.11 57.5,102.21 57.5,103.21 JEDP1.17 ; UV26.N3 v2(237.08,148.23) ; UV24.H14 202.55,171.97 v2(202.93,172.35) UV24.H13 ; v2(155.31,133.84) 155.31,134.33 UH1.AJ13 ; UH1.BP18 136.52,138.83 v2(136.86,138.49) ; v2(243.72,122.37) 243.72,122.73 UV25.N14 ; v2(330.12,131.53) 329.8,131.21 UI2.14 ; v2(237.11,124.09) 237.11,124.13 UV25.E12 ; UV26.C14 v2(245.88,157.03) ; UI1.14 26.08,166.26 v2(26.4,166.58) ; 164.54,134.33 164.54,134.3 164.25,134.3 164.04,134.09 UH1.V12 163.86,134.09 v2(163.61,133.84) 163.38,133.84 UH1.W12 163.05,134.09 162.62,134.51 162.44,134.51 UH1.Y13 161.72,134.25 161.59,134.25 161.43,134.09 UH1.AA12 161.15,134.24 160.53,134.24 UH1.AC12 ; 164.54,134.33 UH1.T13 UH1.T12 164.72,134.33 164.54,134.33 ; 138.74,136.15 v2(138.75,136.15) ; 138.74,136.15 138.74,136.15 UH1.BK15 UH1.BJ15 ; 138.74,136.15 138.74,136.12 139.12,135.74 UH1.BK14 ; UV23.N14 236.08,174.67 236.08,174.67 236.1,174.69 236.1,174.73 v2(236.13,174.76) ; UV23.E3 v2(227.38,168.37) ; UV25.C12 236.27,124.89 236.27,124.91 ; PU1251.4 149.15,184.18 PU1251.18 ; v2(218.62,134.83) 218.21,135.24 UV18.C13 218.2,135.27 v2(217.8,135.67) ; UV18.U16 206.6,137.51 v2(206.11,138) 205.6,137.5 UV18.V16 ; 202.17,139.02 202.6,138.59 UV18.AA17 ; 202.17,139.02 v2(202.13,139.02) ; 202.17,139.02 202.6,139.45 UV18.AA18 ; v2(232.12,78.69) JHDD.7 232.12,76.77 231.95,76.6 230.81,76.6 230.62,76.78 JHDD.4 ; JDIMM1.238 166.39,85.52 166.8,85.11 v2(167.06,85.11) 167.06,85.01 167.46,84.61 168.5,84.61 168.89,84.99 JDIMM1.248 ; v2(161.8,153.21) 161.91,153.21 UH1.Y37 ; UV23.R14 236.1,175.65 v2(236.1,175.56) ; UV23.L5 228.93,172.41 v2(228.93,172.36) ; UH1.BM33 137.82,149.92 137.48,150.26 v2(137.48,150.27) ; UV25.U12 247.04,124.5 v2(246.69,124.14) ; UH1.BR26 135.85,145.17 135.85,144.78 ; UV23.U1 v2(224.83,177.57) ; UV25.E3 v2(237.88,131.3) ; UV23.C12 v2(233.78,166.77) UV23.C11 ; UV24.C4 v2(210.92,175.57) UV24.C3 ; PQ220.1 57.81,83.94 58.35,84.48 v2(58.8,84.48) ; UV25.C14 v2(235.48,123.3) ; v2(232.05,173.57) 232.12,173.57 232.12,173.57 UV23.M10 ; UV23.M5 v2(229.16,173.57) ; UH1.AG11 156.73,133.51 156.88,133.66 v2(157.17,133.66) ; UV25.R4 v2(245.88,131.3) UV25.R3 ; RH5892.2 66.15,78.57 65.07,78.57 64.67,78.97 RH528.2 ; UV26.T5 235.48,149.83 v2(235.54,149.83) ; v2(146.94,71.45) 146.94,72.84 147.35,73.25 147.35,74.16 DE9.1 ; UV18.W28 204.84,147.8 204.84,147.79 204.49,147.43 v2(204.44,147.43) ; UV26.R1 v2(236.28,147.43) ; UV18.AB12 202.07,133.96 v2(202.2,133.96) 202.2,134.09 UV18.AA13 ; v2(246.65,150.59) UV26.B5 ; CA36.2 11.21,101.65 11.55,101.65 v2(11.98,102.08) ; CZ100.2 13.25,129.19 UZ25.5 13.25,130.53 v2(13.79,131.07) ; UV24.A1 213.32,177.17 v2(213.84,177.17) ; UV23.A1 225.35,164.74 v2(225.35,163.8) ; UV26.N1 v2(237.88,147.43) ; UV26.K1 v2(240.28,147.43) UV26.K2 ; UV18.U14 206.6,135.63 v2(206.09,136.14) 205.6,135.65 UV18.V14 ; UV25.A3 v2(234.68,132.1) ; v2(233.79,164.44) 233.85,164.44 234.18,164.77 UV23.A12 ; UH1.BM22 137.82,141.97 v2(137.49,141.65) 138.11,141.65 v2(138.14,141.62) ; UH1.BM22 137.87,142.09 138.42,142.09 UH1.BL22 ; UH1.BM22 UH1.BM23 ; UV18.V21 205.62,142.49 v2(206.11,142) 206.59,142.49 UV18.U21 ; UH1.BH14 140.63,135.07 140.72,135.07 ; UH1.BH14 140.28,135.41 v2(140.28,136.11) 140.19,136.11 UH1.BJ15 ; UH1.BH14 140.16,135.39 UH1.BJ14 139.73,135.74 UH1.BK14 ; UV26.E1 243.88,146.87 243.86,146.85 243.86,146.47 244.25,146.08 v2(244.34,146.08) ; 135.85,144.78 135.87,144.76 UH1.BR25 UH1.BR24 ; 135.85,144.78 136.14,144.78 UH1.BP25 ; 135.85,144.78 135.08,144.78 134.89,144.6 133.41,144.6 133.17,144.84 v2(133.17,145.19) ; UV26.N14 v2(237.88,157.03) ; v2(145.05,76.97) 145.1,76.97 145.37,77.25 145.95,77.25 146.12,77.41 CE3321.2 ; v2(138.14,141.62) 138.47,141.29 UH1.BL21 138.77,140.95 v2(138.77,140.86) ; v2(138.14,141.62) 138.47,141.95 UH1.BL22 ; UZ5.5 341.25,129.61 341.43,129.79 341.43,130.04 341.31,130.17 v2(339.62,130.17) ; UV24.R12 v2(204.52,166.77) UV24.R11 ; v2(238.69,150.64) 238.69,150.63 ; 238.69,150.63 239.08,150.24 UV26.L5 ; 238.69,150.63 UV26.M5 ; v2(176.57,151) 176.23,151 UH1.A34 ; UH2.AC4 95.07,82.83 v2(94.75,82.51) 95.07,82.18 UH2.AE4 ; UH1.AM37 152.86,152.91 152.98,152.78 152.99,152.78 v2(153.18,152.6) ; UV23.P10 v2(232.98,175.57) ; v2(226.4,178.02) 226.53,178.02 UV23.U3 ; v2(32.32,112.45) 32,112.13 32,112.03 31.78,111.8 RT41.1 ; UH1.BJ15 139.77,136.61 v2(140.22,137.06) ; D126.2 v2(17.61,166.68) ; UV18.W13 204.6,134.34 204.33,134.07 204.33,133.96 v2(204.3,133.93) ; UV23.C1 v2(225.78,165.96) ; v2(326.46,136.67) 326.46,136.68 326.34,136.8 D124.2 ; v2(67.51,72.59) 67.81,72.89 68.12,72.89 68.5,73.27 RH5841.1 ; v2(209.83,148.64) 209.92,148.73 209.92,149.42 UV18.N30 ; UV24.N1 v2(212.52,168.37) ; 138.2,150.31 UH1.BL33 138.66,150.31 v2(138.99,149.98) ; 138.2,150.31 137.51,150.31 v2(137.48,150.27) ; 138.2,150.31 138.2,151.1 UH1.BM35 ; UV25.C11 236.27,124.91 ; 236.27,124.91 v2(236.27,124.93) ; UV25.U14 247.08,122.9 v2(246.7,123.29) ; UH1.BM13 138.1,135.24 138.1,135.46 UH1.BM14 137.65,135.91 137.33,135.91 UH1.BN14 ; UV23.A14 235.78,164.22 v2(235.89,164.11) ; UV18.B31 219.03,150.27 219.61,150.27 220.08,149.8 220.12,149.8 220.14,149.77 v2(220.19,149.77) ; UV23.C3 v2(227.38,165.97) UV23.C4 ; v2(50.9,102) 50.99,102.1 JEDP1.30 ; UV26.K14 v2(239.48,157.03) UV26.K13 ; UH1.AD10 159.31,132.79 v2(158.99,133.11) ; v2(209.16,173.43) 209.3,173.57 UV24.F5 ; v2(324.13,136.67) 324.45,136.98 D123.2 ; UV25.B5 234.78,129.79 v2(234.78,129.65) ; UH1.AG13 156.61,134.74 v2(156.27,134.4) ; UH1.BK18 UH1.BL18 ; UH1.BL18 UH1.BL19 138.47,139.71 138.65,139.89 138.65,140.29 UH1.BL20 138.77,140.77 v2(138.77,140.86) ; UH1.BL18 UH1.BM18 ; v2(206.1,165.96) 206.1,165.95 UV24.T10 ; UH2.AW46 75.37,75.84 v2(75.37,75.91) 75.37,75.98 75.16,76.19 UH2.AT45 ; UV25.C3 v2(235.48,131.3) UV25.C4 ; UV18.V19 205.65,140.49 206.04,140.1 v2(206.11,140.1) 206.17,140.1 206.56,140.49 UV18.U19 ; v2(205.33,144.99) 205.33,144.77 205.6,144.51 UV18.V23 UV18.U23 ; UV25.H2 v2(239.48,132.9) UV25.H1 ; UV26.R14 v2(236.28,157.03) ; v2(226.85,164.18) 226.85,164.26 226.98,164.39 UV23.A3 ; v2(247.45,146.57) 247.45,146.66 UV26.A1 ; UV18.T7 207.19,130.19 206.94,129.95 v2(206.94,129.77) ; v2(234.53,174.76) 234.47,174.71 234.47,174.66 UV23.N12 ; 257.5,75.74 257.02,75.25 v2(257.02,73.94) ; UV23.L10 232.23,172.43 v2(232.23,172.36) ; UV26.T10 v2(235.48,153.83) ; v2(212.79,125.72) 212.75,125.72 212.39,126.09 UV18.K2 ; UV25.R11 v2(245.88,124.9) UV25.R12 ; UH2.BA44 75.87,74.39 v2(75.4,73.92) ; UV18.AN10 193.23,132.74 v2(193.6,133.11) ; UV24.K13 v2(202.92,169.97) UV24.K14 ; v2(200.28,134.01) 200.28,134.17 UV18.AC13 ; UV23.K2 v2(225.78,171.57) UV23.K1 ; v2(80.08,73.59) 80.06,73.58 80.06,73.05 UH2.BC35 ; v2(166.51,153.21) 166.64,153.21 UH1.P37 ; UV18.W18 204.6,139.48 204.27,139.15 v2(204.27,139.02) 204.27,138.82 UV18.W17 ; v2(197.71,129.78) UV18.AH7 ; v2(233,165.1) 233,165.14 UV23.B10 ; v2(245.89,154.66) 246.28,154.26 UV26.B10 ; UH1.BT29 UH1.BR29 ; UV26.U14 v2(234.68,157.03) ; UV26.H1 v2(241.86,147.4) 241.86,147.45 UV26.H2 ; UV23.E14 v2(235.38,168.37) ; v2(247.55,155.45) 247.17,155.83 UV26.A12 ; v2(194.43,152.29) 194.83,151.89 UV18.AL33 UV18.AL32 ; v2(137.48,150.27) 137.44,150.31 v2(136.84,150.31) ; v2(201.99,176.82) 201.99,177.04 UV24.A14 ; 137.82,145.55 137.81,145.56 v2(136.83,145.56) 136.83,145.5 UH1.BP26 ; 137.82,145.55 UH1.BM27 ; 137.82,145.55 UH1.BM26 ; PR808.2 111.12,132.38 PR804.2 ; v2(153.14,149.95) 153.2,149.95 UH1.AL33 ; v2(138.12,140.86) 138.77,140.86 v2(138.77,140.86) ; v2(107.56,128.29) 107.2,128.29 106.98,128.51 PU800.7 ; UV24.R3 v2(210.92,166.77) UV24.R4 ; UV18.T18 207.6,139.41 208.04,138.97 208.04,138.92 v2(208.05,138.91) 207.63,138.49 UV18.T17 ; UH1.BK14 UH1.BK13 ; v2(247.51,132.16) 247.51,132.12 UV25.U3 ; UH1.BL13 UH1.BL14 ; UV23.H1 v2(225.78,169.97) UV23.H2 ; UH1.N12 167.53,134.26 166.96,134.26 UH1.P12 166.62,134.25 166.03,134.25 UH1.R12 ; v2(172.86,75.46) 172.89,75.44 JAPS.8 ; v2(203.71,174.8) 204.12,174.39 UV24.E12 ; UV23.R11 v2(233.78,175.57) UV23.R12 ; v2(51.79,102) 51.79,102.31 51.99,102.51 JEDP1.28 ; UH1.BL22 UH1.BK22 ; UV25.N1 243.88,133.74 243.89,133.75 v2(243.89,133.88) ; UV25.C1 v2(236.28,133.7) ; UV24.N12 v2(204.52,168.37) ; v2(133.2,69.03) 133.2,68.55 PR507.2 ; RH200.2 132.04,150.98 133.03,149.99 134.59,149.99 v2(134.63,149.95) ; v2(75.43,80.64) 75.3,80.5 75.3,80.21 74.95,79.87 UH2.AK46 ; UV25.R1 v2(245.08,133.7) ; v2(60.55,101.95) 60.49,102.01 JEDP1.11 ; UV25.G10 238.74,125.75 v2(238.74,125.69) 238.7,125.72 238.66,125.72 UV25.F10 ; v2(139.46,183.58) 140.26,184.38 PU1201.4 ; UV25.A1 v2(234.68,133.7) ; v2(218.62,143.18) 219,142.8 UV18.B22 ; v2(238.63,129.68) 238.66,129.68 UV25.G5 ; UV24.B5 v2(210.12,176.37) ; UV26.C3 245.52,148.63 245.88,148.98 v2(245.88,149.03) 245.88,149.09 245.55,149.43 UV26.C4 ; RH475.2 127.15,151.4 RH1958.1 ; D74.2 341.11,111.03 v2(341.15,110.99) ; UV26.U1 v2(234.68,147.43) ; v2(134.61,151.44) 134.62,151.43 UH1.BT35 ; UV26.A3 v2(246.68,149.03) ; UV18.B1 219.11,125.29 219.44,125.61 219.44,125.68 v2(219.44,125.69) ; v2(244.33,154.58) 244.33,154.58 UV26.D10 ; UV26.U12 234.65,155.46 v2(234.65,155.44) ; PU1701.14 103.84,160.54 102.9,159.59 PC1716.2 ; UV26.F10 v2(243.08,153.7) ; UV25.K2 UV25.K1 v2(241.06,133.72) ; 139.75,151.91 139.69,151.91 UH1.BJ35 139.71,151.28 v2(139.78,151.28) 139.46,150.96 UH1.BJ34 139.38,150.86 139.33,150.81 139.33,150.44 139.38,150.39 UH1.BJ33 ; 139.75,151.91 139.41,152.26 UH1.BJ36 ; 139.75,151.91 v2(139.75,151.91) ; UV25.A14 233.85,123.33 v2(233.13,123.33) ; UH1.M13 168.71,134.74 v2(169.05,135.08) ; UV24.R14 v2(202.92,166.77) ; UV18.P17 209.6,138.71 v2(209.93,139.04) 209.6,139.37 UV18.P18 ; UH2.BC45 75.7,73.34 75.85,73.19 ; UV24.M5 v2(210.12,169.17) UV24.L5 ; UH1.T10 164.78,132.79 v2(164.46,132.47) 164.59,132.47 164.92,132.14 UH1.T9 ; v2(161.04,151.23) 160.91,151.23 UH1.AB34 ; UV24.C1 v2(213.32,175.57) ; 12.46,143.91 12.58,144.03 CV182.1 ; 12.46,143.91 CV181.1 ; 12.46,143.91 v2(12.41,143.86) ; UV25.R14 245.48,122.38 v2(245.56,122.31) ; PH1104.2 v2(106.35,136.54) ; v2(211.33,139.01) 211.3,139.04 211.3,139.19 UV18.M18 ; UV18.AG11 v2(198.47,133.22) ; UV25.U1 247.08,133.61 v2(246.89,133.81) ; v2(108.8,138.66) 108,137.86 PU1700.4 ; UV26.U3 v2(233.88,149.03) ; UV24.C11 v2(204.52,175.57) UV24.C12 ; UV23.E12 v2(234.58,167.57) ; UV26.L10 v2(238.68,153.83) UV26.M10 ; 75.85,73.19 75.85,72.94 76.07,72.72 UH2.BD43 76.1,72.46 75.92,72.28 UH2.BE44 ; 75.85,73.19 75.85,73.3 76.11,73.57 76.4,73.57 UH2.BB43 76.42,73.93 v2(76.69,74.2) 76.99,73.9 UH2.BB41 ; UV25.K14 241.43,122.9 v2(241.02,123.31) 241.41,123.7 UV25.K13 ; UV23.B5 v2(228.19,165.18) ; UV24.P10 v2(205.32,167.57) ; UV26.E3 v2(243.48,149.03) ; UV25.P10 v2(245.08,125.7) ; UV23.T10 v2(232.18,176.37) ; UV25.H13 v2(239.48,123.3) UV25.H14 ; v2(137.49,143.22) 138.17,143.22 v2(138.18,143.2) 138.18,143.25 UH1.BM24 UH1.BM25 ; UV23.C14 v2(235.38,166.77) ; D324.2 310.35,100.98 C1080.2 v2(311.03,101.83) ; UV25.T10 v2(245.88,126.5) ; v2(210.11,166.01) 210.11,165.96 UV24.T5 ; UV24.N14 v2(202.92,168.37) ; v2(318.19,105.05) 318.44,104.79 D323.2 ; v2(16.66,127.13) 16.04,127.75 CT151.2 ; UV25.M10 243.08,126.55 v2(243.08,126.62) ; JHDD.10 v2(233.62,78.69) ; UV26.R12 v2(236.28,155.43) UV26.R11 ; v2(201.55,175.71) 201.8,175.97 UV24.C14 ; UH1.AY14 146.53,135.39 v2(146.21,135.72) ; UV25.E14 v2(237.88,123.3) ; UV26.C1 245.42,147.03 v2(245.03,146.64) ; PH1103.2 v2(127.94,182.14) ; v2(201.12,139.05) 200.69,139.49 UV18.AC18 ; PC1520.2 190.31,183.2 190.55,182.96 v2(190.55,178.07) ; UV23.T5 v2(228.98,176.37) ; UV24.H2 212.44,172.29 v2(212.52,172.29) 212.59,172.29 UV24.H1 ; v2(162.58,151.25) 162.88,150.96 UH1.W34 ; UV26.P10 v2(237.08,154.63) ; UV26.C12 v2(245.88,155.43) UV26.C11 ; UV23.R3 227.28,176.28 v2(227.38,176.28) 227.47,176.28 UV23.R4 ; v2(16.18,97.53) 16.18,98.9 16.01,99.06 PU201.3 ; UV24.U12 v2(204.52,165.17) ; v2(196.89,137.33) UV18.AH16 ; PU1252.4 156.58,184.18 PU1252.18 ; UV24.G10 v2(206.12,172.37) ; UV23.G5 v2(228.18,169.17) UV23.F5 ; v2(224.85,174.39) 224.87,174.37 UV23.N1 ; UV18.K7 212.74,129.8 212.74,128.94 v2(212.77,128.91) ; UV24.E14 202.23,174.37 v2(202.03,174.17) ; v2(208.79,172.79) 208.81,172.77 UV24.G5 ; UV26.R3 v2(236.28,149.03) UV26.R4 ; UV24.R1 v2(212.52,166.77) ; UV23.H14 v2(235.38,169.97) UV23.H13 ; v2(176.52,156.47) 176.52,156.33 173.75,153.56 UH1.D38 ; v2(103.56,131.18) PC810.2 ; UA3.5 2.1,81.68 1.92,81.86 v2(1.07,81.86) ; UV24.U1 v2(212.52,165.17) ; UH2.BC24 85.59,73.08 86.15,73.63 v2(86.15,73.75) ; UV26.F5 243.08,150.69 243.02,150.75 v2(243.02,150.87) ; UV25.F5 v2(238.68,130.5) ; UH2.BC31 82.24,73.25 81.97,73.52 81.97,73.62 v2(81.95,73.63) ; UV25.J10 v2(241.08,125.7) ; UV24.N3 v2(211.72,167.57) ; UV23.F10 v2(232.98,169.17) UV23.G10 ; UV25.D10 v2(236.28,125.7) ; UV18.AH22 197.28,142.74 196.9,142.37 v2(196.83,142.37) ; UV24.J10 v2(205.32,170.77) ; UV23.K14 235.45,172.29 v2(235.38,172.29) 235.3,172.29 UV23.K13 ; PU1701.2 105.35,161.68 v2(105.55,161.48) 106.35,162.28 PU1701.4 ; UV24.A12 v2(203.72,177.17) ; v2(164.58,154.07) UH1.U38 164.64,153.49 164.64,152.97 UH1.U37 ; UV24.E1 v2(212.52,174.77) ; UV24.D10 v2(205.32,174.77) ; v2(241.88,150.63) UV26.G5 ; RH59.2 133.12,141.25 v2(133.15,141.23) ; UV24.E3 v2(210.92,173.97) ; UV25.A12 233.89,124.1 v2(233.89,124.09) ; UV18.R16 209.09,137 209.09,136.99 v2(209.16,136.92) 209.59,136.49 UV18.P15 ; UV18.AE28 200.06,148 200.33,148 200.53,148.2 201.67,148.2 201.93,147.94 v2(201.93,147.39) ; UV25.L5 v2(242.68,129.7) UV25.M5 ; UH1.A36 UH1.A37 ; UV24.A3 v2(210.92,177.17) ; v2(63.51,102.01) 63.51,102.16 63.49,102.18 JEDP1.5 ; v2(132.54,142.83) 132.54,143.01 133.11,143.58 135.18,143.58 UH1.BT24 ; UV24.F10 v2(206.32,173.57) ; v2(243.48,156.25) 243.48,156.23 UV26.E12 ; UV26.N12 v2(237.88,155.43) ; UV23.U14 v2(235.53,178.02) ; UV23.N3 v2(227.38,173.97) ; UV24.B10 v2(205.32,176.37) ; D125.2 17.61,163.18 v2(17.86,162.94) ; 19.86,100.51 CT43.2 ; RH529.2 61.52,72 v2(61.18,72.34) ; UV25.E1 v2(237.08,132.9) ; v2(61.99,101.95) 61.99,101.95 JEDP1.8 ; UH1.BK29 139.45,147.43 UH1.BJ29 ; JEDP1.14 v2(58.99,101.95) ; UV26.G10 v2(241.88,153.83) ; v2(195.21,130.66) 195.6,130.27 UV18.AK7 UV18.AJ7 ; UV23.D10 v2(232.98,166.77) ; UV23.U12 v2(233.78,177.17) ; v2(207.76,151.53) 207.35,151.12 UV18.T32 207.34,151.09 v2(206.95,150.7) ; JDIMM2.61 196.44,95.34 195.4,96.38 v2(195.24,96.38) ; UV25.T5 v2(245.88,129.7) ; UV18.AB32 v2(202.77,151.51) ; UV25.B10 v2(234.68,125.7) ; UV25.N12 v2(243.48,124.1) ; v2(224.78,175.95) 225.36,175.95 UV23.R1 ; UV24.U3 v2(210.88,164.33) ; UV23.E1 v2(225.78,168.37) ; UV25.L10 v2(241.88,126.5)
  BOTTOM w0.279: UV18.AL23 UV18.AL24 194.8,144.48 194.48,144.8 v2(194.43,144.8) 194.43,144.85 194.04,145.24 UV18.AM25 UV18.AN25 ; v2(196.88,144.82) UV18.AH24
  BOTTOM w0.3: v2(212.74,149.12) 212.74,149.12 212.65,149.12 212.35,149.42 UV18.K30 ; 214.9,135.24 214.9,135.22
  BOTTOM w0.305: JDIMM1.15 108.64,95.66 108.94,95.96 108.94,95.96 109.23,96.26 109.24,96.26 109.36,96.39 v2(109.44,96.39) ; JDIMM1.93 128.14,96.15 127.45,96.83 v2(127.4,96.83) ; UV18.A2 220.21,125.69 220.21,125.64 v2(220.22,125.63) ; UV18.M17 211.6,138.7 211.33,138.97 v2(211.33,139.01) ; UV18.AH28 197.26,147.79 v2(196.89,148.16) 197.35,148.62 UV18.AH29 ; UV18.P22 209.6,143.53 210.05,143.97 v2(210.11,143.97) 210.6,144.46 UV18.N23 ; v2(164.82,89.25) 165,89.25 165.39,88.86 165.39,88.21 164.39,87.21 164.39,86.34 ; JDIMM2.90 203.69,89.63 202.87,90.44 v2(202.44,90.44) ; v2(183.84,95.83) 183.44,95.43 JDIMM2.9 ; JDIMM1.206 158.39,85.36 158.1,85.08 157.96,85.08 ; v2(238.92,85.06) 238.69,85.28 238.69,86.34 JDIMM2.222 ; JDIMM2.223 238.94,95.47 239.44,95.97 v2(239.54,95.97) 239.94,95.52 JDIMM2.227 ; UV18.AE32 199.85,151.04 199.45,150.64 v2(199.45,150.63) ; v2(117.23,96.41) 117.1,96.41 116.64,95.95 JDIMM1.47 ; v2(231.27,96.47) 231.87,96.47 232.44,95.9 JDIMM2.197 ; v2(337.36,152.27) 337.32,152.22 JNGFF1.37 ; v2(259.4,87.1) 259.4,87.44 259.11,87.74 JNGFF2.9 ; UV18.N7 210.16,129.88 210.16,129.14 v2(210.27,129.02) ; JDIMM1.69 122.14,95.67 v2(121.13,96.68) ; v2(161.5,95.95) 161.14,95.59 JDIMM1.217 ; UV18.E22 216.99,142.35 v2(216.99,142.31) ; v2(148.5,89.5) 148.74,89.5 149.06,89.18 149.06,88.33 148.89,88.16 JDIMM1.168 ; v2(215.27,128.91) 215.27,128.91 UV18.G5 ; JDIMM1.243 167.64,93.47 168.11,92.99 168.11,92.46 167.44,91.79 v2(167.23,91.79) ; JDIMM2.47 192.94,96.32 v2(193.24,96.62) ; JNGFF1.21 333.32,151.9 333.76,152.35 v2(334.32,152.35) JNGFF1.25 ; JDIMM2.103 206.94,95.72 208.01,96.78 v2(208.35,96.78) ; UV18.AH2 196.99,126.45 196.99,126.5 196.97,126.53 v2(196.94,126.53) ; JNGFF1.15 331.82,152.02 v2(332.32,152.52) ; UV18.Y19 v2(203.11,140.98) UV18.AA20 ; JDEG1.10 306.28,97.77 v2(306.82,97.23) ; UV18.G32 215.04,151.27 215.04,151.71 UV18.G33 214.73,151.89 214.43,151.59 v2(214.43,151.57) ; UV18.AB28 202.33,147.79 v2(201.93,147.39) ; v2(212.51,148.32) 212.51,147.95 UV18.K28 ; v2(220.97,130.47) 220.97,130.33 220.66,130.03 219.22,130.03 UV18.B7 ; UV18.E7 216.6,130.19 v2(216.2,129.79) UV18.F7 ; JDIMM2.15 184.94,95.63 185.07,95.75 v2(185.74,95.75) 185.94,95.56 JDIMM2.19 ; UV18.P20 v2(209.1,140.99) UV18.R19 ; JNGFF1.31 335.82,151.93 335.66,152.09 335.66,152.82 335.92,153.08 336.43,153.08 v2(336.46,153.05) ; JDIMM2.192 231.19,85.4 231.54,85.05 v2(231.81,85.05) 232.19,85.42 JDIMM2.196 ; JDIMM1.252 169.89,87.3 170.93,88.34 170.93,88.95 170.63,89.25 v2(170.41,89.25) ; UV18.G7 214.9,130.15 214.52,129.77 v2(214.47,129.77) ; UV18.T15 v2(208.19,135.9) UV18.R14 ; JDIMM2.209 235.44,95.7 v2(235.73,95.99) 236.05,95.99 236.44,95.61 JDIMM2.213 ; v2(132.04,96.27) 131.64,95.86 JDIMM1.107 ; v2(169.6,75.56) 169.6,75.44 169.89,75.15 JAPS.14 ; UV18.P13 210,134.09 210,133.97 210.06,133.91 v2(210.06,133.96) 210.53,133.49 UV18.N12 ; v2(204.34,85.05) 204.69,85.4 JDIMM2.94 ; UV18.AA22 v2(202.18,143.91) UV18.AB23 ; JDIMM2.214 236.69,85.24 236.49,85.05 v2(236.05,85.05) 235.94,85.05 235.69,85.3 JDIMM2.210 ; v2(117.23,95.79) 117.37,95.79 117.64,95.52 JDIMM1.51 ; v2(55.7,96.36) 56.3,95.77 DV12.2 ; UV18.AK10 195.96,132.38 v2(196.05,132.38) ; JDIMM2.205 234.44,95.47 234.01,95.89 v2(233.9,95.89) 233.44,95.43 JDIMM2.201 ; JAPS.10 171.89,75.38 v2(171.96,75.46) ; UV18.W32 204.87,151.09 205.28,151.5 v2(205.28,151.52) ; v2(243.85,85.05) 244.19,85.39 JDIMM2.244 ; 151.57,88.26 151.57,88.82 151.15,89.25 v2(151.05,89.25) 150.88,89.25 149.89,88.26 JDIMM1.172 ; 151.57,88.26 151.89,87.95 JDIMM1.180 ; 151.57,88.26 150.89,87.58 JDIMM1.176 ; JDIMM2.60 196.19,85.39 196.53,85.05 v2(196.69,85.05) 196.89,85.05 197.19,85.35 JDIMM2.64 ; 189.42,85.04 189.16,85.04 188.69,85.51 JDIMM2.30 ; 189.42,85.04 v2(189.42,85.05) ; 189.42,85.04 189.73,85.04 190.19,85.5 JDIMM2.36 ; UV18.AH13 197.3,135.18 196.93,134.81 v2(196.93,134.8) ; UV18.G22 214.59,143.05 214.59,143.12 v2(214.56,143.15) ; UV18.T5 207.35,129.36 v2(206.94,129.77) ; 230.07,85.04 229.97,85.14 229.39,85.14 229.19,85.34 JDIMM2.184 ; 230.07,85.04 v2(230.07,85.05) ; 230.07,85.04 230.19,85.17 JDIMM2.188 ; v2(215.28,149.89) 214.88,149.49 UV18.G30 ; JDIMM1.40 114.89,85.47 115.35,85 v2(115.6,85) 115.89,85.29 JDIMM1.44 ; JDIMM1.239 166.64,95.69 166.4,95.93 165.82,95.93 v2(165.81,95.95) 165.64,95.78 JDIMM1.235 ; 214.9,135.22 v2(214.5,134.82) ; JDIMM1.205 158.14,95.66 157.9,95.89 157.6,95.89 v2(157.53,95.83) 157.47,95.83 157.14,95.49 JDIMM1.201 ; v2(121.15,95.92) 121.14,95.9 JDIMM1.65 ; v2(216.88,124.89) 217,125 217,125.74 UV18.D2 ; v2(245.86,96.67) 245.66,96.67 244.94,95.94 JDIMM2.247 ; UV18.R21 208.6,142.4 208.13,141.93 v2(208.13,141.9) 208.01,141.9 UV18.T20 ; v2(129.49,96.8) 130.58,95.72 130.64,95.72 JDIMM1.103 ; JDIMM2.1 181.44,96.79 v2(182.09,97.45) 182.44,97.1 JDIMM2.5 ; v2(125.53,95.86) 125.41,95.74 125.14,95.47 JDIMM1.81 ; UV18.C25 217.77,144.81 v2(217.73,144.81) ; JDIMM2.86 202.69,87.23 203.03,87.57 203.03,88.8 202.65,89.17 v2(202.44,89.17) ; JNGFF1.1 v2(326.32,152.35) ; JDIMM2.252 246.19,87.62 v2(246.57,88) ; UV18.AN19 UV18.AM19 194,140.19 UV18.AL18 UV18.AL17 194.78,138.59 v2(194.39,138.2) 194,137.81 UV18.AM16 UV18.AN16 ; JDIMM1.57 119.14,95.8 v2(119.22,95.88) ; v2(149.94,95.81) 150.37,95.81 150.64,95.54 JDIMM1.175 ; UV18.T2 207.05,125.79 207.05,124.85 v2(207.1,124.8) ; UV18.T28 207.38,147.79 v2(207.78,147.39) ; JDIMM2.230 240.69,85.5 241.15,85.05 v2(241.32,85.05) 241.41,85.05 241.69,85.32 JDIMM2.234 ; UV18.N28 209.83,147.79 v2(209.43,147.39) ; JDIMM2.52 194.19,85.34 193.9,85.05 193.68,85.05 v2(193.68,85.05) 193.68,85.05 193.41,85.05 193.19,85.28 JDIMM2.48 ; v2(197.6,153.37) 197.51,153.28 197.51,152.05 UV18.AH33 ; JDIMM2.107 207.94,95.7 v2(208.42,96.18) ; JDIMM1.171 149.64,95.39 149.39,95.64 149.39,96.16 149.62,96.39 v2(149.94,96.39) ; JDIMM1.196 155.89,85.37 v2(155.61,85.09) 155.13,85.09 154.89,85.33 JDIMM1.192 ; v2(216.16,145.58) 216.26,145.58 UV18.E25 ; UV18.Y12 203.73,133.49 204.11,133.88 204.24,133.88 v2(204.3,133.93) ; v2(237.42,85.05) 237.42,85.13 237.69,85.39 JDIMM2.218 ; UV18.N21 UV18.M22 211.6,143.42 211.99,143.03 v2(211.94,143.03) ; CT152.2 18.58,119.26 v2(17.84,119.26) ; JDIMM2.98 205.69,85.25 v2(205.89,85.05) ; v2(148.29,96.47) 148.39,96.47 148.87,95.99 148.87,95.65 148.64,95.42 JDIMM1.167 ; UV18.Y21 v2(204.15,141.95) UV18.W20 ; JDIMM1.193 155.15,95.52 154.85,95.82 v2(154.8,95.82) ; v2(198.03,85.05) 198.19,85.21 JDIMM2.68 ; UV18.Y14 v2(204.1,135.99) UV18.W15 ; v2(129.49,96.08) 129.64,95.93 JDIMM1.99 ; v2(109.44,95.75) 109.64,95.56 JDIMM1.19 ; v2(228.19,85.05) 228.19,86.34 JDIMM2.180 ; v2(160.22,73.59) 160.41,73.78 161.63,73.78 161.95,74.1 JKB.17 ; JDIMM1.214 160.39,85.5 159.98,85.09 v2(159.74,85.09) 159.39,85.43 JDIMM1.210 ; UV18.D31 217.51,150.29 217.81,150.6 v2(217.82,150.6) ; v2(201.12,139.05) 200.6,138.53 UV18.AC17 ; JDIMM1.23 110.64,95.76 v2(110.65,95.77) ; JDIMM1.82 125.39,85.27 v2(125.68,84.98) 125.9,84.98 126.39,85.47 JDIMM1.86 126.39,87.33 126.59,87.53 127.17,87.53 127.39,87.32 JDIMM1.90 ; JDIMM1.102 130.39,85.29 130.59,85.09 v2(130.93,85.09) 131.17,85.09 131.39,85.3 JDIMM1.106 ; JNGFF1.22 333.57,159.9 v2(333.44,160.03) ; UV18.AB30 202.34,149.49 v2(201.93,149.08) ; JDIMM1.52 117.89,85.44 117.47,85.02 v2(117.29,85.02) 117.16,85.02 116.89,85.3 JDIMM1.48 ; UV18.G28 214.9,147.79 v2(215.33,148.22) 215.75,147.79 UV18.F28 ; UV18.AB14 UV18.AC13 ; JDIMM2.89 203.44,95.78 203.8,96.14 v2(204.32,96.14) 204.32,95.85 204.44,95.73 JDIMM2.93 ; JDIMM2.82 201.69,85.34 v2(201.98,85.04) ; UV18.AE5 v2(200.27,128.91) ; UV18.AH11 197.3,133.56 v2(197.72,133.15) 197.31,132.74 UV18.AH10 ; JDIMM2.243 243.94,93.42 v2(243.53,93.01) 242.94,93.61 JDIMM2.239 ; v2(338.76,152.47) 338.76,152.15 338.82,152.09 JNGFF1.43 ; v2(225.92,95.84) 225.94,95.82 JDIMM2.171 ; v2(190.95,96.66) 191.94,95.67 JDIMM2.43 ; JDIMM2.27 187.94,95.59 187.63,95.91 v2(187.03,95.91) 186.95,95.83 186.95,95.78 186.94,95.76 JDIMM2.23 ; v2(226.59,90.49) 226.45,90.49 225.19,89.23 JDIMM2.168 ; JDIMM1.184 152.89,85.29 153.11,85.08 v2(153.63,85.08) 153.89,85.33 JDIMM1.188 ; JDIMM2.175 226.94,95.95 226.47,96.42 v2(225.92,96.42) ; JDIMM1.218 161.39,87.18 162.39,88.19 162.39,88.75 161.89,89.25 v2(161.77,89.25) ; UV18.AH30 197.35,149.52 v2(196.96,149.9) ; v2(170.79,75.46) 170.79,75.27 170.89,75.17 JAPS.12 ; UV18.AP2 UV18.AN1 192.72,124.81 v2(192.66,124.81) ; v2(212.47,153.32) 212.46,153.3 212.46,153.24 212.42,153.2 212.42,151.96 UV18.K33 212.39,151.85 212.39,151.13 UV18.K32 ; UV18.V12 205.63,133.49 v2(206.1,133.96) 206.57,133.49 UV18.U12 ; UV18.T13 208.09,134 v2(208.09,133.96) 208.56,133.49 UV18.R12 ; JDIMM2.77 200.44,95.92 199.89,96.46 199.44,96.46 v2(199.3,96.32) 199.15,96.17 199.15,95.74 199.44,95.46 JDIMM2.73 ; v2(114.67,96.38) 115,96.38 115.64,95.74 JDIMM1.43 ; UV18.AN34 193.2,153.07 v2(192.77,153.5) ; JDIMM1.31 112.64,95.75 v2(112.68,95.79) ; v2(165.18,85.06) 165.18,85.26 165.39,85.47 JDIMM1.234 ; JDIMM1.5 106.14,93.54 105.32,92.72 v2(105.17,92.72) 105.02,92.72 104.57,93.17 104.57,93.49 105.14,94.06 JDIMM1.1 ; JNGFF2.15 259.56,86.24 259.99,86.67 v2(259.99,87.1) ; UV18.G16 214.9,137.77 v2(214.5,138.17) ; v2(332.07,160.04) JNGFF1.16 ; UV18.AN22 UV18.AM22 194.05,142.74 v2(194.42,142.37) 194.8,141.99 UV18.AL21 UV18.AL20 ; v2(216.18,132.34) 216.58,132.74 UV18.E10 ; UV18.M20 211.6,141.49 211.33,141.22 v2(211.33,140.99) 211.1,140.99 UV18.N19 ; JDIMM1.223 162.65,95.49 162.65,95.67 162.93,95.95 v2(163.15,95.95) 163.31,95.95 163.64,95.58 JDIMM1.227 ; JDIMM1.197 156.15,94.54 156.15,95.38 154.98,96.56 v2(154.73,96.56) ; v2(335.05,156.49) 334.91,156.63 334.91,157.52 335.07,157.68 JNGFF1.28 ; v2(237.05,96.01) 237.44,95.62 JDIMM2.217 ; UV18.AM13 UV18.AN13 ; UV18.AM13 194.8,136.04 UV18.AL14 UV18.AL15 ; UV18.AM13 194,135.14 v2(194.33,134.8) 194.75,134.39 UV18.AL12 ; UV18.K5 v2(212.77,128.91) ; 157.96,85.08 v2(157.96,85.09) ; 157.96,85.08 157.77,85.08 157.39,85.46 JDIMM1.202 ; v2(168.61,88.97) 168.47,88.84 168.47,87.88 167.89,87.3 JDIMM1.244 ; v2(220.23,151.54) 220.15,151.54 UV18.A33 UV18.B34 ; v2(117.1,90.16) 117.1,90.04 117.14,90 117.14,88.27 117.49,87.92 118.25,87.92 118.89,87.28 JDIMM1.56 ; UV18.E5 v2(217,128.09) ; UV18.R23 v2(208.08,143.97) UV18.T22 ; v2(164.82,91.79) 164.93,91.79 165.33,92.19 165.33,93.01 164.64,93.7 JDIMM1.231 ; JNGFF2.33 259.28,81.74 259.46,81.92 259.46,81.96 v2(259.55,82.04) ; JNGFF2.57 257.44,75.74 257.05,76.13 257.05,77.02 257.27,77.24 JNGFF2.51 ; JDIMM2.56 195.19,85.3 v2(195.43,85.05) ; JDIMM2.231 240.94,95.58 v2(241.3,95.94) 241.57,95.94 241.94,95.57 JDIMM2.235 ; UV18.G25 214.91,145.25 214.91,145.24 v2(215.32,144.82) ; v2(188.95,95.82) 188.94,95.8 JDIMM2.31 ; v2(192.8,149.82) 193.2,149.42 UV18.AN30 ; v2(205.79,95.78) 205.94,95.64 JDIMM2.99 ; JDIMM2.238 242.69,85.36 v2(243,85.05) ; JDIMM2.181 228.44,95.55 v2(228.2,95.79) ; v2(214.5,133.17) 214.9,132.77 UV18.G10 ; JDIMM2.18 185.69,85.15 185.57,85.03 ; JDIMM2.106 207.71,85.45 207.29,85.04 v2(207.16,85.04) 207,85.04 206.69,85.36 JDIMM2.102 ; UV18.AB16 201.54,137.49 v2(201.15,137.11) 200.6,136.55 UV18.AC15 ; UV18.G3 214.85,126.87 v2(215.22,126.5) 215.21,126.5 214.85,126.15 UV18.G2 ; JDIMM1.209 159.14,95.43 v2(158.79,95.78) 159.02,96.01 159.78,96.01 160.14,95.65 JDIMM1.213 ; JDIMM1.226 163.39,85.51 162.97,85.09 v2(162.62,85.09) 162.39,85.32 JDIMM1.222 ; v2(110.65,96.36) 111.25,96.36 111.64,95.97 JDIMM1.27 ; JDIMM2.206 234.71,85.2 234.56,85.05 234.26,85.05 v2(234.26,85.05) 234.26,85.05 233.95,85.05 233.69,85.31 JDIMM2.202 ; JDIMM1.64 120.89,85.5 120.41,85.02 v2(120.41,85) 120.33,85 119.89,85.44 JDIMM1.60 ; JDIMM1.36 113.89,85.27 113.64,85.02 v2(113.64,85) ; UV18.AP33 192.17,152.12 192.17,153.59 192.66,154.08 v2(192.71,154.08) ; UV18.Y23 v2(204.13,143.96) UV18.W22 ; v2(181.92,88.58) 182.18,88.58 182.69,88.07 JDIMM2.6 182.69,85.39 182.48,85.19 182.01,85.19 181.69,85.51 JDIMM2.2 ; UV18.C7 218.2,130.2 v2(217.8,129.8) ; v2(192.27,130.26) 192.28,130.24 UV18.AN7 ; v2(194.4,149.84) 194.8,149.44 UV18.AL30 ; UV18.AA15 v2(203.11,137) UV18.Y16 ; UV18.G13 214.9,135.24 ; JDIMM1.85 126.14,96.08 v2(125.57,96.64) ; JDIMM1.185 153.14,95.56 153.4,95.82 v2(153.74,95.82) 153.96,95.82 154.15,95.62 154.15,94.54 JDIMM1.189 ; UV18.AC20 200.6,141.49 v2(201.18,140.91) 201.6,140.49 UV18.AB19 ; JDIMM2.226 239.69,87.94 240.99,89.23 v2(241.24,89.23) ; UV18.AE33 199.77,151.97 199.77,153.19 v2(199.82,153.24) ; v2(185.57,85.05) 185.57,85.03 ; 185.57,85.03 185.08,85.03 184.69,85.42 JDIMM2.14 ; v2(12.32,102.66) 12.39,102.74 12.39,103.18 RA68.2 ; JDIMM2.251 245.94,96.01 v2(245.86,96.09) ; JDIMM1.247 168.65,95.86 168.39,95.86 v2(168.32,95.93) 169.59,95.93 169.65,95.87 169.65,94.54 JDIMM1.251 ; v2(245.28,85.14) 245.19,85.23 JDIMM2.248 ; v2(127.41,96.1) 127.15,95.82 127.14,95.8 JDIMM1.89 ; UV18.N14 v2(211.15,134.94) UV18.M13 ; JDIMM2.51 193.94,95.62 v2(193.49,96.07) ; v2(224.49,96.51) 224.58,96.51 225.07,96.02 225.07,95.63 224.94,95.5 JDIMM2.167 ; JDIMM2.44 192.19,85.41 191.83,85.05 191.71,85.05 v2(191.71,85.05) 191.7,85.05 191.52,85.05 191.19,85.39 JDIMM2.40 ; JDIMM2.26 187.69,85.46 187.28,85.05 187.26,85.05 v2(187.26,85.05) 187.26,85.05 187.06,85.05 186.69,85.42 JDIMM2.22 ; UV18.AC22 200.6,143.43 201.15,142.88 v2(201.15,142.85) 201.18,142.85 201.54,142.49 UV18.AB21 ; CZ82.2 183.93,151.72 UZ9.5 ; JDIMM1.35 113.64,96.41 113.08,96.97 v2(112.68,96.97) ; JDIMM2.69 198.44,95.5 198.16,95.78 v2(197.44,95.78) JDIMM2.65 ; v2(19.93,97.17) 19.86,97.24 CT44.2 ; UV18.N16 v2(211.19,136.9) 211.19,136.92 211.6,136.51 UV18.M15 211.83,136.49 v2(212.14,136.8) ; JNGFF1.55 v2(341.82,152.29) 341.88,152.23 342.95,152.23 343.32,151.86 JNGFF1.61 ; UV18.AE30 199.75,149.49 v2(199.34,149.9) ; v2(114.65,95.78) 114.65,95.77 114.64,95.76 JDIMM1.39 ; v2(231.32,95.88) 231.44,95.77 JDIMM2.193 ; v2(200.39,85.04) 200.7,85.35 200.7,86.34 JDIMM2.78 ; v2(195.24,96.38) 195.22,96.37 195.22,95.81 195.44,95.59 JDIMM2.57 ; JDIMM1.77 124.14,95.97 v2(123.48,96.63) 122.95,96.1 122.95,95.65 123.14,95.46 JDIMM1.73 ; UV18.B28 UV18.C28 218.2,147.76 217.8,148.16 v2(217.73,148.16) ; JDIMM1.181 152.14,95.6 151.82,95.92 v2(151.2,95.92) ; JDIMM2.172 226.19,85.36 226.49,85.05 v2(226.8,85.05) 226.96,85.05 227.21,85.3 JDIMM2.176 ; v2(294.26,99.39) 293.65,99.39 293.32,99.07 JLPDE1.9 ; JDIMM1.78 124.39,85.46 v2(123.95,85.02) 123.27,85.02 122.89,85.4 JDIMM1.72 ; v2(220.93,146.39) 220.93,146.39 220.93,145.75 220.61,145.43 219.19,145.43 UV18.B25 ; JKB.16 152.75,74.63 152.57,74.44 v2(151.94,74.44) ; JNGFF2.45 259.03,78.74 259.6,79.3 v2(259.6,79.52) 259.6,79.77 259.14,80.24 JNGFF2.39 ; v2(217.8,143.18) 218.2,142.78 UV18.C22 ; UV18.AB2 v2(201.96,126.48) ; v2(214.5,140.67) 214.9,140.27 UV18.G19 ; JDIMM1.94 128.39,87.3 128.6,87.52 129.23,87.52 129.39,87.36 JDIMM1.98 129.39,85.34 129.44,85.29 v2(129.44,85.09) ; JDIMM2.39 190.93,94.55 190.93,95.93 190.95,95.94 v2(190.95,95.94) 190.11,95.94 189.94,95.78 JDIMM2.35 ; JDIMM2.10 v2(183.69,88.46) ; JDIMM2.85 202.44,95.65 202.07,96.02 v2(201.93,96.02) 201.79,96.02 201.44,95.67 JDIMM2.81 ; JNGFF1.49 340.32,152.13 v2(340.47,152.29) ; UV18.C16 218.2,137.69 218.57,137.32 v2(218.57,137.3) ; UV18.AL28 194.8,147.77 v2(195.2,148.17) ; JDIMM2.72 199.19,87.63 v2(200.41,88.86) ; JDIMM1.30 112.45,86.28 v2(112.45,84.98) 111.92,84.98 111.39,85.51 JDIMM1.26 ; UV25.N3 243.52,131.34 243.45,131.34 v2(243.45,131.34) ; UV18.AH19 196.95,139.89 v2(196.71,139.89) ; v2(121.12,85.01) 121.42,85.01 121.89,85.49 JDIMM1.68 ; v2(210.22,125.66) 209.85,126.04 UV18.N2 ; JDIMM2.185 229.44,95.56 229.76,95.88 v2(230,95.88) 230.26,95.88 230.44,95.7 JDIMM2.189 ; v2(330.57,160.04) JNGFF1.10 ; UV18.D33 217.77,152.31 217.77,152.87 218.07,153.17 218.07,153.82 v2(218,153.9) ; UV18.N32 UV18.N33 ; v2(327.82,152.35) JNGFF1.7
  BOTTOM w0.356: CA23.2 2.46,95.76 CA37.2 ; 107.39,87.69 107.39,88.61 106.44,89.55 v2(106.44,90.15) ; 107.39,87.69 107.4,87.68 108.08,87.68 108.39,87.37 JDIMM1.14 ; 107.39,87.69 JDIMM1.10 ; v2(20.21,144.77) 20.21,144.09 CM24.1 ; v2(19.1,161.82) 18.97,161.94 CM40.1 ; JDIMM1.2 105.39,87.53 104.95,87.96 104.95,88.54 105.28,88.86 v2(105.54,88.86) 105.81,88.86 106.39,88.28 JDIMM1.6 ; RH5845.2 RH5846.2 69.2,80.79 RH5848.2 69.08,81.09 68.94,80.96 68.28,80.96 68.01,81.22 RH5849.2 67.93,81.51 v2(67.28,81.51) ; CT144.2 14.05,126.26 CZ101.1 12.57,126.26 v2(12.29,125.98) ; CM24.1 20.5,144.07 CM5.1 ; CM24.1 CM25.2 ; v2(33.34,110.64) 33.08,110.38 RT4.1 ; v2(27.1,114.49) 27.11,114.49 27.23,114.37 RT37.1 ; v2(10.73,105.87) 10.96,105.64 CA10.2 11.93,105.64 CA11.2 ; v2(26.21,138.19) 25.96,138.45 CM32.2 ; RT188.1 18,129.83 v2(18.36,130.19) 18.36,130.07 18.63,129.8 RT187.1 ; v2(110.18,89.28) 109.95,89.28 109.58,88.9 109.58,88.29 110.39,87.48 JDIMM1.22 ; C3003.2 v2(348.96,127.34) ; v2(107.95,89.15) 108.09,89.15 108.52,88.71 108.52,88.36 109.39,87.49 JDIMM1.18 ; CA8.2 13.49,104.58 CA9.2 ; v2(106.41,91.96) 106.42,91.97 106.42,92.65 107.14,93.36 JDIMM1.9 ; v2(14.52,136.51) 14.52,135.22 CM37.2 CM8.2 ; UV18.N5 210.27,128.91 v2(210.27,129.02) ; C3004.2 v2(344.88,113.39) ; CM31.2 CM29.1
  BOTTOM w0.381: v2(103.04,80.24) 101.87,79.06 101.04,79.06 RH95.1 ; CV933.2 201.63,168.12 201.77,167.97 UV24.N14 ; v2(8.4,130.18) 7.68,130.18 6.9,130.97 6,130.97 CT122.2 ; 49.09,83.12 49.66,82.56 PQ227.4 50.58,82.56 51.88,83.86 PQ227.1 ; CM3.1 22.69,143.69 CM2.2 22.99,144.26 22.53,144.72 20.26,144.72 v2(20.21,144.77) 20.14,144.7 19.58,144.7 19.28,145 19.28,145.18 18.82,145.64 17.78,145.64 17.2,145.05 ; CV934.2 202.82,163.47 UV24.U12 ; CA34.2 2.3,100.55 2.22,100.48 CA33.2 CA120.1 2.22,99.14 v2(2.39,98.98) ; PQ223.1 56.55,87.68 v2(57.23,87.68) ; v2(6.24,100.98) CA32.2 6.2,100.4 CA78.2 ; v2(332.27,108.02) 332.6,108.35 332.92,108.35 ; v2(26.2,137.32) 25.88,137.32 CM31.2 CM32.2 ; v2(67.51,72.59) 67.49,72.61 67.49,72.81 67.12,73.18 66.66,73.18 UH8.4 ; CH175.2 122.17,165.45 v2(121.97,165.25) 121.41,164.69 CH3.2 ; v2(26.21,139.72) 25.96,139.46 CM30.1 ; RH5833.2 RH5832.2 ; UH7.3 65.58,68.7 v2(66.09,69.21) ; JTS.6 347.77,120.64 v2(347.38,121.02) ; v2(50.72,68.39) 50.23,68.39 PC1908.2 ; 14.94,143.68 16.31,145.05 17.2,145.05 ; 14.94,143.68 14.94,143.34 CM22.2 ; 14.94,143.68 13.46,143.68 CV182.1 ; CV184.2 51.47,94.94 CZ44.2 52.37,94.11 v2(52.21,93.94) ; 17.2,145.05 17.2,144.7 17.65,144.24 CM23.2 19.01,144.07 CM25.2 ; v2(26.21,140.35) 26.09,140.35 25.96,140.23 CM28.1 CM33.2 ; CH50.1 103.57,69.22 v2(103.62,69.22) 103.8,69.4 CD3325.2 CH51.1 ; RV109.2 RV107.2 44.55,96.1 45.4,96.95 v2(45.4,97.48) ; v2(66.12,71.66) 66.38,71.39 CH45.2 ; CZ43.2 v2(48.48,90.77) ; YT1.2 v2(18.97,97.26) ; v2(14.7,101.87) 14.7,101.99 14.57,102.12 13.43,102.12 13.11,101.8 PC204.2 12.71,101.1 PQ205.3 ; v2(22.25,114.4) 21.72,113.87 CT187.2 CT186.2 ; RV1840.2 207.85,123.07 v2(207.58,123.33) ; CM27.2 25.65,135.7 25.55,135.81 CM29.1 ; CA121.2 v2(4.33,76.95) ; RR6.1 334.07,99.76 CR5.2 333.23,100.09 v2(333.14,100.19) ; RM21.1 8.97,141.31 v2(8.39,141.31) ; UH14.3 58.12,71.43 v2(58.31,71.62) ; v2(8.41,99.77) 8.37,99.8 RA16.1 ; CM38.1 CM50.2 16.52,139.73 v2(16.87,140.07) 16.65,140.29 CM35.1 16.48,140.77 CM34.2 ; v2(9.32,129.36) 9.77,129.36 10.08,129.67 CT123.2 ; v2(98.69,84.19) 98.55,84.33 98.5,84.33 98.09,84.74 98.09,84.85 98.08,84.87 v2(98.08,84.9) 97.64,85.34 97.64,85.59 v2(97.54,85.69) ; v2(6.5,79.72) 6.5,79.33 6.19,79.01 CA122.2 ; CA23.2 3.43,95.35 v2(3.43,95.29) ; CR1.2 332.88,104.7 v2(332.99,104.59) 333.26,104.59 CR2.2 ; RV114.2 49.57,94.61 49.57,93.66 50.23,93 v2(50.23,92.94) ; RH150.1 169.34,122.44 v2(168.87,121.97) ; PC1257.1 v2(148.64,186.58) ; CH46.2 70.46,71.39 v2(71.45,70.4) ; PQ221.4 57.97,81.18 v2(58.15,81.36) 58.22,81.43 PC219.2 ; RH148.1 RH149.1 171.57,124.82 v2(171.48,124.91) ; v2(110.67,133.88) 110.1,134.45 PC1705.1 ; RA94.1 0.53,98.37 0.72,98.56 0.72,100.36 1.1,100.74 1.1,101.83 v2(1.51,102.23) ; v2(111.81,132.73) PR808.2
  BOTTOM w0.406: JLPDE1.12 291.19,96.71 v2(291.19,96.74) ; v2(298.39,96.87) 298.39,96.44 298.32,96.37 JLPDE1.11
  BOTTOM w0.457: v2(311.78,93.62) JDEG1.11 ; 306.28,97.77 305.97,97.77 305.28,97.09 JDEG1.12 ; v2(14.27,119.27) 14.23,119.22 CT189.2 ; v2(165.65,186.8) 165.66,186.79 PC1017.2 PC1005.2 ; UM2.4 25.93,158.64 v2(26.49,159.2) ; v2(18.03,100.27) 17.87,100.11 YT1.4 ; v2(62.34,80.75) 62.38,80.79 PQ224.3 ; DE4.1 199.22,78.1 v2(200.27,79.14)
  BOTTOM w0.508: RI11.2 RI12.2 335.98,128.45 v2(336.38,128.05) 336.47,128.14 RZ39.2 ; v2(0.88,127.15) 0.69,126.95 RA95.1 1.35,126.48 1.52,126.64 DA5.2 ; v2(347.27,122.83) 347.48,123.04 JTS.3 ; CE83.2 149.81,73.83 v2(150.42,74.44) ; v2(193.68,73.29) 193.76,73.38 JTP.10 193.76,75.53 195.67,77.44 v2(195.67,79.09) ; JDIMM2.262 247.37,103.69 v2(246.26,103.69) ; PC912.2 238.18,177.6 v2(237.68,177.1) ; v2(349,115.31) 348.93,115.24 CR17.2 ; RH472.2 133.44,161.83 134.47,161.83 135.67,163.03 RH466.2 135.9,163.56 136.69,164.36 v2(137.34,164.36) ; v2(60.55,101.95) 60.55,101.24 61.44,100.35 JEDP1.44 ; JFP.10 316.47,104.93 v2(316.27,105.14) ; JNGFF1.68 325.67,152.35 v2(326.32,152.35) ; v2(185.69,151.67) 184.67,151.67 184.61,151.73 CZ82.2 ; PC1932.2 29.72,82.87 v2(30.02,82.57) ; v2(181.03,97.46) 181.01,97.47 JDIMM2.261 ; v2(346.63,117.69) 346.63,118.09 346.17,118.56 JTS.7 ; C1079.2 312.04,93.36 v2(311.78,93.62) ; v2(161.82,186.76) 161.54,186.47 PC1018.2 ; v2(132.55,69) 132.55,69.72 PC511.2 ; v2(68.69,90.73) 68.69,91.92 CH180.2 ; JTS1.8 338.11,115.34 v2(338.5,115.73) ; RV1837.2 v2(213.41,120.85) ; v2(186.87,187.47) 186.87,186.75 186.84,186.72 PR1519.2 PC1532.2 ; CZ104.2 1.55,82.57 v2(0.99,82.57) ; CE3322.2 149.14,76.53 v2(149.3,76.69) ; JFAN2.4 v2(336.47,124.39) ; CI2.2 328.22,125.98 328.5,125.69 JFAN2.5 ; v2(155.88,186.58) 156.13,186.84 PC1268.1 ; v2(102.6,100.7) 104.34,102.44 JDIMM1.261 ; PC610.2 287.12,91.7 v2(284.9,91.7) 285.12,91.92 285.12,92.59 PC607.1 ; v2(18.07,169.12) 18.06,169.12 18.05,169.11 RI26.2 ; v2(21.56,133.98) 22.43,133.11 CT153.2 ; RH497.1 127.52,149.12 126.98,149.66 126.95,149.66 126.34,150.27 RH475.2 126.15,150.59 125.62,151.11 v2(125.49,151.11) ; JFAN2.5 331.08,126.21 v2(331.51,126.64) ; JFAN2.5 331.85,124.92 331.85,120.86 JFAN2.6 ; CH202.2 100.13,92.75 v2(100.41,92.47) ; v2(328.09,98.06) 328.09,96.07 SW_BOT.4 ; CE74.2 151.94,75.43 v2(151.94,74.44) ; CR18.2 348.87,109.27 v2(348.79,109.19) ; JFAN1.6 92.23,106.29 93.31,107.37 93.31,109.34 v2(93.2,109.45) ; v2(63.82,79.34) 63.82,79.26 63.94,79.14 RH528.2 ; PR908.2 238.21,177.74 ; PR1604.2 PC1611.2 247.52,172.41 v2(247.83,172.1) ; CT144.2 15.11,125.9 RT191.2 15.52,125.49 RT190.2 ; PC1604.2 238.59,162.9 v2(238.12,163.37) ; v2(130.18,69.03) 130.18,69.5 PC512.2 ; JTS1.9 345.22,116.9 v2(345.98,117.67) ; CA9.2 13.78,104.22 14.23,103.77 v2(14.23,102.72) ; v2(337.81,116.44) 337.28,116.44 JTS1.10 ; v2(22.02,169.61) RI8.1 21.08,169.61 20.89,169.8 UI4.3 ; C3005.2 v2(344.22,128.35) ; PC1522.2 181.41,186.35 v2(181.48,186.42) ; CZ29.2 v2(343.33,128.35) ; RV1835.2 182.06,180.62 PC1517.2 v2(181.13,180.67) ; v2(241.96,185.46) PC901.2 v2(240.97,186.2) ; v2(164.16,95.95) 164.16,97.78 168.82,102.44 JDIMM1.262 ; v2(171.3,181.17) 171.01,181.46 PR1022.2 PC1055.2 ; v2(70.66,69.17) 71.67,68.17 CH3329.2 ; RV592.2 186.82,129.22 RV589.2 185.66,129.24 v2(185.28,128.86) ; v2(54.9,85.63) 54.9,85.89 54.63,86.15 PQ223.4 ; PR1502.2 186.59,177.21 PQ1501.3 ; PC1612.2 245.67,167.68 v2(245.06,167.07) ; CT157.2 26.37,127.42 26.52,127.58 v2(26.52,127.9) ; JFAN1.5 95.73,106.29 95.46,106.02 v2(95.46,104.86) 95.66,104.66 95.66,103.83 95.36,103.54 JFAN1.4 ; CT150.2 25.54,124.91 CT149.2 27.32,124.34 v2(27.32,124.25) ; CT189.2 12.99,119.22 12.28,119.93 DA2.2 ; v2(274.86,100.45) 274.14,100.45 PC615.2 ; PC911.2 PR906.2 241.3,177.11 v2(241.25,177.06) ; v2(42.24,88.99) 42.11,89.12 PC1924.2 ; CV862.2 CV871.2 222.4,126.87 v2(221.41,125.88) ; RH5836.2 102.53,81.17 103.23,81.87 104.47,81.87 104.88,82.28 v2(105.2,82.28) ; JTS.8 v2(347.47,125.94) ; PC1030.2 163.63,176.4 v2(163.68,176.34) ; v2(334.62,108.82) 334.71,108.91 CR3.2 ; RV613.2 216.19,171.99 v2(216.81,172.61) ; CR16.2 342.44,107.79 v2(342.57,107.66) ; DA3.2 0.44,111.62 v2(0.83,111.23) ; CLRP1.2 v2(63.43,71.27) ; v2(60.3,68.28) 60.3,68.51 60.71,68.92 RH77.2 ; CZ86.2 178.99,152.23 v2(180.26,153.5) ; CE81.2 CE82.2 164.31,76.73 v2(164.44,76.85) ; PR607.2 291.02,99.23 v2(291.04,99.21) ; PC1713.1 104.89,165.31 v2(104.32,164.74) ; RH469.2 126.42,169.82 v2(126.67,170.07) ; PC1518.2 181.48,182.55 v2(181.46,182.57) 181.46,183.01 181.88,183.44 PC1501.2 ; PC1227.1 v2(140.51,186.71) ; PR910.2 239.83,177.69 v2(239.83,176.95) ; PC611.2 259.82,93.24 v2(259.82,93.24) 259.82,91.63 JNGFF2.68 ; PR1122.1 114.29,172.57 PC1110.1 113.98,172.56 113.64,172.9 PC1120.1 ; v2(164.88,70.7) 164.91,70.7 JAPS.20 ; v2(221.8,171.66) 222.06,171.91 RV617.2 RV614.2 ; CE80.2 CE79.2 186.01,81.01 186.76,80.26 v2(186.76,79.11) JTP.5 ; JTAG1.2 301.27,93.06 300.89,93.44 300.89,94.03 v2(300.6,94.32) ; CE78.2 189.13,79.52 v2(189.56,79.09) ; v2(247.84,169.82) PR1608.2 247.22,170.54 PR1607.2 ; CE67.2 v2(333.6,114.01) ; v2(192.53,79.06) 192.53,79.08 192.54,79.1 192.54,79.46 CE77.2 ; v2(106.48,121.7) 106.52,121.74 H25.1 ; v2(328.63,105.36) CR6.2 ; JFP.9 311.36,104.7 310.21,103.55 308.64,103.55 v2(307.77,104.41) ; PC614.2 290.92,97.43 291.19,97.16 v2(291.19,96.74) ; RE255.1 316.15,97.05 v2(315.95,96.84) ; CV868.1 v2(220.12,186.01) ; CZ31.2 v2(344.09,129.62) ; PC1923.2 42.55,89.98 v4(43,89.53) 43.06,89.47 v2(43.06,88.77) ; RV567.2 211.51,121.04 v2(211.71,120.83) ; CM1.2 25.45,145.9 v2(26.35,146.8) 26.12,147.03 PC114.2 PC115.2 ; v2(188.16,130.31) 187.79,130.68 RV593.2 ; PC806.2 PR804.2 ; RV578.1 188.96,154.36 v2(189.66,155.06) ; CZ88.2 CZ47.2 178.08,149.28 v2(177.42,148.62) ; v2(169.23,184.58) 169.08,184.73 PC1041.2 ; v2(18.49,171.93) CI21.2 ; PR1516.1 182.09,185.99 v2(182.09,186.53) ; v2(345.74,108.22) 345.49,108.48 DI3.1 ; PC900.2 v2(240.08,186.2) ; v2(328.63,104.16) CR4.2
  vias: v2(-1.8,87.37) v2(-1.8,86.1) v2(-1.8,84.83) v2(-1.8,83.56) v2(-1.8,82.29) v2(-1.8,81.02) v2(-1.8,79.75) v2(-1.8,78.48) v2(-1.22,88.5) v2(-1.13,77.4) v2(-0.9,161.68) v2(-0.9,160.41) v2(-0.9,141.22) v2(-0.9,139.95) v2(-0.9,138.68) v2(-0.9,137.41) v2(-0.9,136.14) v2(-0.9,134.87) v2(-0.9,133.6) v2(-0.9,132.33) v2(-0.9,131.06) v2(-0.9,129.79) v2(-0.9,128.52) v2(-0.9,127.25) v2(-0.9,113.86) v2(-0.9,112.59) v2(-0.9,111.32) v2(-0.9,110.05) v2(-0.9,108.78) v2(-0.9,107.51) v2(-0.9,106.24) v2(-0.9,104.97) v2(-0.9,103.7) v2(-0.9,102.43) v2(-0.9,101.16) v2(-0.9,99.89) v2(-0.9,98.62) v2(-0.9,97.35) v2(-0.9,96.08) v2(-0.9,94.81) v2(-0.9,93.54) v2(-0.9,92.27) v2(-0.9,91) v2(-0.9,89.73) v2(-0.9,76.15) v2(-0.9,73.61) v2(-0.9,69.55) v2(-0.9,68.53) v2(-0.88,179.35) v2(-0.86,142.49) v2(-0.77,178.08) v2(-0.72,67.27) v2(-0.49,162.89) v2(-0.24,70.76) v2(-0.13,159.41) v2(-0.15,72) v2(0.32,179.76) v2(0.37,142.84) v2(0.4,72.8) v2(0.41,69.64) v2(0.54,67.13) v2(1.59,179.76) v2(1.7,73.31) v2(1.65,69.21) v2(1.81,67.13) v2(2.86,179.76) v2(2.85,80.03) v2(2.92,69.56) v2(3.04,134.23) v2(3.02,131.76) v2(3.08,67.13) v2(3.15,177.88) v2(3.32,162.91) v2(3.32,72.68) v2(3.68,159.41) v2(3.88,71.23) v2(4.13,179.76) v2(4.18,142.84) v2(4.29,177.88) v2(4.33,107.59) v2(4.33,103.45) v2(4.35,67.13) v2(4.59,162.91) v2(4.95,159.41) v2(4.95,77.23) v2(5.4,179.76) v2(5.45,142.84) v2(5.56,177.88) v2(5.59,77.23) v2(5.62,67.13) v2(5.86,162.91) v2(6.02,76.64) v2(6.22,159.41) v2(6.22,77.23) v2(6.4,105.52) v2(6.69,142.58) v2(6.62,135.75) v2(6.71,127.96) v2(6.83,177.88) v2(6.91,127.27) v2(6.86,77.23) v2(6.89,67.13) v2(7.13,162.91) v2(7.25,73.74) v2(7.39,159.9) v2(7.49,77.23) v2(7.75,157.8) v2(7.75,156.53) v2(7.75,146.12) v2(7.75,145.1) v2(7.96,142.6) v2(8.1,177.88) v2(8.16,67.13) v2(8.22,135.02) v2(8.25,127.96) v2(8.4,162.91) v2(8.38,136.07) v2(8.48,138.12) v2(8.48,136.87) v2(8.48,134.5) v2(8.47,107.59) v2(8.47,103.45) v2(8.5,81.76) v2(8.94,132.18) v2(9.25,82.99) v2(9.32,128.44) v2(9.47,136.15) v2(9.51,134.56) v2(9.45,131.82) v2(9.5,130.09) v2(9.43,67.13) v2(9.54,135.14) v2(9.74,72.78) v2(9.86,131.39) v2(9.83,82.99) v2(10.34,94.17) v2(10.44,82.96) v2(10.61,178.11) v2(10.7,67.13) v2(10.79,162.91) v2(10.9,175.61) v2(10.9,174.34) v2(10.9,173.07) v2(10.9,171.8) v2(10.9,170.53) v2(10.9,169.26) v2(10.9,167.99) v2(10.9,166.72) v2(10.9,165.45) v2(10.91,137.01) v2(10.92,94.17) v2(11.08,72.87) v2(11.66,72.87) v2(12.25,72.87) v2(12.5,131.41) v2(12.84,72.87) v2(13.28,75) v2(13.31,74.41) v2(14.21,74.32) v2(14.29,179.76) v2(14.58,74.9) v2(14.51,67.13) v2(14.67,106.24) v2(14.76,106.88) v2(14.81,74.31) v2(14.87,104.58) v2(15.17,74.89) v2(15.42,74.33) v2(15.56,179.76) v2(15.62,104.02) v2(15.76,166.18) v2(15.78,67.13) v2(16.26,102.33) v2(16.83,179.76) v2(16.91,98.87) v2(16.94,166.35) v2(16.94,164.52) v2(17.05,67.13) v2(17.31,177.81) v2(17.48,173.96) v2(17.46,97.15) v2(17.77,114.2) v2(17.77,113.62) v2(17.88,177.81) v2(18.1,179.76) v2(18.09,173.96) v2(18.39,97.19) v2(18.32,67.13) v2(18.49,177.82) v2(18.62,164.48) v2(18.64,162.93) v2(18.77,108.32) v2(18.88,112.04) v2(18.86,107.57) v2(19.03,112.67) v2(19.29,111.63) v2(19.37,179.76) v2(19.34,139.3) v2(19.45,112.24) v2(19.59,67.13) v2(19.67,166.48) v2(20.12,136.85) v2(20.59,104.97) v2(20.64,179.76) v2(20.86,67.13) v2(20.93,173.53) v2(20.98,172.28) v2(20.94,141.72) v2(20.92,140.9) v2(20.92,140.1) v2(21.22,107.57) v2(21.22,106.27) v2(21.22,105.62) v2(21.22,104.97) v2(21.76,97.96) v2(21.91,179.76) v2(21.87,107.57) v2(21.87,103.67) v2(22.13,67.13) v2(22.31,123.09) v2(22.35,124.91) v2(22.38,123.68) v2(22.71,130.96) v2(22.94,158.56) v2(23.04,159.2) v2(23.18,179.76) v2(23.17,106.27) v2(23.15,98.13) v2(23.4,67.13) v2(23.44,163.59) v2(23.5,158.82) v2(23.44,158.23) v2(23.42,157.65) v2(23.62,159.43) v2(23.88,151.85) v2(23.89,151.28) v2(23.82,109.54) v2(23.98,114.36) v2(24.08,158.79) v2(24.13,158.21) v2(24.16,88.28) v2(24.4,152.09) v2(24.4,150.93) v2(24.38,98.11) v2(24.45,179.76) v2(24.42,151.52) v2(24.67,67.13) v2(25.01,172.98) v2(24.93,151.82) v2(24.93,151.24) v2(24.93,150.65) v2(25.12,106.92) v2(25.37,171.6) v2(25.53,98.11) v2(25.72,179.76) v2(25.76,174.17) v2(25.76,108.23) v2(25.94,67.13) v2(26.49,158.13) v2(26.49,157.45) v2(26.49,156.85) v2(26.49,156.23) v2(26.49,155.64) v2(26.49,155.07) v2(26.49,154.39) v2(26.48,153.79) v2(26.49,151.67) v2(26.58,170.91) v2(26.9,179.27) v2(27.22,174.41) v2(27.21,67.13) v2(27.33,178.08) v2(27.33,176.81) v2(27.33,170.11) v2(27.33,168.84) v2(27.33,167.57) v2(27.33,166.3) v2(27.33,165.03) v2(27.33,163.76) v2(27.33,162.49) v2(27.33,161.22) v2(27.33,159.95) v2(27.33,158.68) v2(27.33,157.41) v2(27.33,156.14) v2(27.33,154.87) v2(27.33,153.6) v2(27.33,152.33) v2(27.33,151.06) v2(27.33,149.79) v2(27.33,148.52) v2(27.33,147.25) v2(27.33,145.98) v2(27.33,144.71) v2(27.33,143.44) v2(27.33,142.17) v2(27.33,140.9) v2(27.33,139.63) v2(27.33,138.36) v2(27.33,137.09) v2(27.33,135.82) v2(27.33,134.55) v2(27.33,133.28) v2(27.33,132.01) v2(27.33,130.74) v2(27.33,129.47) v2(27.38,93.43) v2(27.48,128.21) v2(27.69,126.96) v2(27.7,106.27) v2(27.95,125.71) v2(27.97,93.43) v2(28.27,124.48) v2(28.23,121.57) v2(28.3,121.01) v2(28.25,98.58) v2(28.39,72.43) v2(28.48,67.13) v2(28.63,123.27) v2(28.68,120.56) v2(29.04,122.06) v2(29.13,72.4) v2(29.5,120.88) v2(29.73,101.1) v2(29.75,67.13) v2(30,119.72) v2(30.14,95.21) v2(30.55,118.57) v2(30.73,95.22) v2(30.8,86.91) v2(31.02,67.13) v2(31.15,117.45) v2(31.32,95.21) v2(31.44,86.91) v2(31.79,116.35) v2(32.06,86.91) v2(32.2,95.23) v2(32.29,67.13) v2(32.48,115.29) v2(32.71,86.91) v2(32.81,95.23) v2(33.21,114.24) v2(33.31,86.91) v2(33.56,67.13) v2(33.64,95.21) v2(33.98,113.23) v2(34.25,95.21) v2(34.77,112.26) v2(34.83,67.13) v2(35.27,107.71) v2(35.31,106.11) v2(35.63,111.31) v2(36.1,67.13) v2(36.51,110.39) v2(36.51,107.6) v2(36.89,105.44) v2(37.37,67.13) v2(37.43,109.51) v2(38.37,108.67) v2(38.54,105.63) v2(38.64,67.13) v2(39.14,105.5) v2(39.36,107.86) v2(39.91,67.13) v2(40.37,107.1) v2(40.92,104.74) v2(41.18,67.13) v2(41.32,97.96) v2(41.42,106.38) v2(41.55,104.54) v2(42.49,105.7) v2(42.45,67.13) v2(43.61,105.1) v2(43.72,67.13) v2(44.07,103.32) v2(44.8,104.64) v2(44.99,67.13) v2(45.56,80.69) v2(46.03,104.34) v2(46.26,67.13) v2(46.68,82.92) v2(46.68,81.8) v2(46.68,80.69) v2(47.03,77.95) v2(47.03,77.36) v2(47.29,104.18) v2(47.53,67.13) v2(47.68,78.61) v2(47.65,78) v2(47.64,77.41) v2(47.8,80.69) v2(48.56,104.16) v2(48.69,85.44) v2(48.69,84.85) v2(48.69,84.27) v2(48.69,83.69) v2(48.69,79.77) v2(48.69,79.19) v2(48.69,78.61) v2(48.69,78.02) v2(48.68,77.41) v2(48.8,67.13) v2(48.82,97.94) v2(49,102) v2(49.28,85.44) v2(49.28,84.85) v2(49.28,84.27) v2(49.28,79.77) v2(49.28,79.19) v2(49.28,78.61) v2(49.28,78.02) v2(49.28,77.44) v2(49.45,97.94) v2(49.83,104.16) v2(49.86,78.02) v2(49.86,77.44) v2(50.07,67.13) v2(50.28,72.51) v2(50.41,73.91) v2(50.44,78.02) v2(50.44,77.44) v2(50.86,73.04) v2(50.88,72.47) v2(50.88,71.88) v2(50.87,71.29) v2(51,73.88) v2(51.1,104.16) v2(51.02,78.61) v2(51.02,78.02) v2(51.02,77.44) v2(51.34,67.13) v2(51.51,73.06) v2(51.51,72.48) v2(51.51,71.91) v2(51.51,71.31) v2(51.61,73.87) v2(52.11,68.14) v2(52.18,73.87) v2(52.37,104.16) v2(53.04,78.61) v2(53.04,78.02) v2(53.04,77.44) v2(53.11,68.92) v2(53.64,104.16) v2(54.38,68.93) v2(54.91,104.16) v2(55.65,68.93) v2(56.18,104.16) v2(56.82,91.27) v2(56.92,68.93) v2(57.45,104.16) v2(58.19,68.81) v2(58.72,104.16) v2(58.9,67.75) v2(59.32,93.03) v2(59.99,104.16) v2(60,67.13) v2(60.1,93.05) v2(60.88,93.01) v2(61.26,104.16) v2(61.27,67.13) v2(62.29,93.01) v2(62.53,104.16) v2(62.54,67.13) v2(63.55,93.01) v2(63.8,104.16) v2(63.81,67.13) v2(64.76,93.01) v2(65.07,104.16) v2(65.08,67.13) v2(65.15,77.01) v2(66,102.2) v2(66.34,104.16) v2(66.35,67.13) v2(66.71,102.2) v2(67.61,104.16) v2(67.62,67.13) v2(68.88,104.16) v2(68.89,67.13) v2(69.54,98.36) v2(70.15,104.16) v2(70.17,98.36) v2(70.16,67.13) v2(70.81,98.36) v2(71.42,104.16) v2(71.43,67.13) v2(72.69,104.16) v2(72.7,67.13) v2(73.33,94.96) v2(73.49,90.08) v2(73.79,95.43) v2(73.81,92.35) v2(73.96,104.16) v2(73.91,94.86) v2(73.97,67.13) v2(74.35,95.26) v2(74.83,94.38) v2(74.9,88.08) v2(74.85,85.94) v2(75.23,104.16) v2(75.24,67.13) v2(75.77,90.3) v2(76.5,104.16) v2(76.51,67.13) v2(77.77,104.16) v2(77.72,76.24) v2(77.78,67.13) v2(78.56,89.57) v2(78.69,81.27) v2(78.92,87.46) v2(79.04,104.16) v2(79.05,67.13) v2(80.16,86.37) v2(80.21,85.21) v2(80.31,104.18) v2(80.26,91.75) v2(80.32,67.13) v2(81.17,85.21) v2(81.22,77.6) v2(81.57,104.35) v2(81.59,67.13) v2(81.77,91.76) v2(82.8,104.67) v2(82.86,67.13) v2(82.98,91.81) v2(83.19,89.7) v2(83.98,105.13) v2(84.13,67.13) v2(84.59,80.71) v2(84.81,89.58) v2(85.1,105.73) v2(85.06,90.7) v2(85.05,90.12) v2(85.41,80.71) v2(85.4,67.13) v2(86.17,106.42) v2(86.67,67.13) v2(86.87,80.68) v2(87.21,107.14) v2(87.33,93.34) v2(87.65,88.57) v2(87.94,67.13) v2(88.12,91.76) v2(88.22,107.91) v2(88.51,83.75) v2(88.62,80.26) v2(88.81,88.56) v2(88.86,87.51) v2(89.21,108.71) v2(89.14,83.78) v2(89.21,67.13) v2(90.15,109.56) v2(90.48,67.13) v2(91.07,110.44) v2(91.41,88.59) v2(91.34,82.51) v2(91.48,91.78) v2(91.55,81.08) v2(91.63,76.17) v2(91.75,67.13) v2(91.94,111.36) v2(92.68,92.03) v2(92.78,112.31) v2(93.02,67.13) v2(93.58,113.3) v2(94.29,67.13) v2(94.34,114.32) v2(94.7,74.98) v2(94.81,87.99) v2(94.72,79.33) v2(95.06,115.37) v2(95.56,67.13) v2(95.71,70.72) v2(95.88,70.12) v2(96.02,116.19) v2(96.32,70.62) v2(96.75,70.07) v2(96.83,67.13) v2(97.29,116.28) v2(97.34,99.52) v2(98.1,67.13) v2(98.23,121.64) v2(98.38,116.94) v2(98.65,122.83) v2(98.71,120.46) v2(99.02,124.05) v2(99.05,118.01) v2(99.17,119.28) v2(99.29,102.51) v2(99.34,125.28) v2(99.37,67.13) v2(99.61,126.52) v2(99.94,100.05) v2(100.2,163.31) v2(100.2,162.04) v2(100.2,160.77) v2(100.2,159.5) v2(100.2,158.23) v2(100.2,156.96) v2(100.4,148.06) v2(100.4,146.79) v2(100.4,145.52) v2(100.4,144.25) v2(100.4,142.98) v2(100.4,141.71) v2(100.4,140.44) v2(100.4,139.17) v2(100.4,137.9) v2(100.4,136.63) v2(100.4,135.36) v2(100.4,134.09) v2(100.4,132.82) v2(100.64,67.13) v2(101,164.3) v2(100.94,102.08) v2(101.37,100.55) v2(101.38,90.76) v2(101.38,90.06) v2(101.7,186.95) v2(101.7,185.68) v2(101.7,184.41) v2(101.7,183.14) v2(101.7,181.87) v2(101.7,180.6) v2(101.7,179.33) v2(101.7,178.06) v2(101.7,176.79) v2(101.7,175.52) v2(101.7,174.25) v2(101.7,172.98) v2(101.7,171.71) v2(101.7,170.44) v2(101.7,169.17) v2(101.7,167.9) v2(101.7,166.63) v2(101.69,165.36) v2(101.77,188.22) v2(101.75,149.17) v2(101.75,148.58) v2(101.78,147.97) v2(101.78,147.39) v2(101.78,146.8) v2(101.75,146.12) v2(101.75,145.53) v2(101.78,144.87) v2(101.78,144.29) v2(101.8,143.68) v2(101.8,143.1) v2(101.78,142.46) v2(101.78,141.88) v2(101.8,141.27) v2(101.8,140.68) v2(101.8,140.1) v2(101.78,139.41) v2(101.78,138.83) v2(101.8,138.22) v2(101.8,137.64) v2(101.8,137.05) v2(101.8,136.47) v2(101.91,67.13) v2(103.01,188.51) v2(103.18,67.13) v2(103.56,150.26) v2(103.81,142.74) v2(103.81,142.13) v2(103.84,141.52) v2(103.84,140.94) v2(103.84,140.35) v2(103.84,139.77) v2(104.28,188.51) v2(104.45,67.13) v2(104.57,142.13) v2(104.57,141.55) v2(104.57,140.96) v2(104.55,140.28) v2(104.55,139.69) v2(105.27,159.28) v2(105.55,188.51) v2(105.72,67.13) v2(106.16,160.1) v2(106.16,159.02) v2(106.35,141.12) v2(106.35,140.04) v2(106.48,133.77) v2(106.48,133.19) v2(106.48,132.61) v2(106.48,131.53) v2(106.79,132.03) v2(106.82,188.51) v2(106.99,67.13) v2(107.11,169.44) v2(107.05,160.1) v2(107.05,159.02) v2(107.06,133.77) v2(107.06,133.19) v2(107.06,132.61) v2(107.3,141.12) v2(107.3,140.04) v2(107.65,133.77) v2(107.65,133.19) v2(107.65,132.61) v2(107.64,120.29) v2(108,160.1) v2(108,159.02) v2(107.95,91.69) v2(107.95,90.42) v2(108.08,188.41) v2(108.19,141.12) v2(108.19,140.04) v2(108.29,178.03) v2(108.29,175.91) v2(108.29,173.79) v2(108.26,67.13) v2(108.38,187.17) v2(108.38,169.44) v2(108.87,186) v2(108.89,159.47) v2(109.4,157.63) v2(109.4,157.05) v2(109.53,67.13) v2(109.81,185.15) v2(109.97,158.2) v2(109.97,157.63) v2(109.97,157.05) v2(110.18,91.82) v2(110.18,90.55) v2(110.41,178.03) v2(110.41,175.91) v2(110.41,173.79) v2(110.54,158.2) v2(110.54,157.63) v2(110.54,157.05) v2(110.69,130.12) v2(110.69,129.53) v2(110.69,128.95) v2(110.8,67.13) v2(111.02,184.77) v2(111.28,130.12) v2(111.28,129.53) v2(111.28,128.95) v2(111.86,130.12) v2(111.86,129.53) v2(111.86,128.95) v2(111.86,128.36) v2(111.86,127.78) v2(112.07,67.13) v2(112.16,90.81) v2(112.13,89.01) v2(112.29,184.76) v2(112.45,129.53) v2(112.53,178.03) v2(112.53,175.91) v2(112.53,173.79) v2(113.41,91.82) v2(113.41,90.55) v2(113.41,89.28) v2(113.34,67.13) v2(113.51,140) v2(113.51,139.41) v2(113.51,138.83) v2(113.55,184.87) v2(113.72,137.82) v2(114.1,158.07) v2(114.1,157.5) v2(114.1,140) v2(114.1,139.41) v2(114.1,138.83) v2(114.1,138.24) v2(114.53,168.32) v2(114.61,67.13) v2(114.67,185.46) v2(114.67,158.07) v2(114.67,157.5) v2(114.68,140) v2(114.68,139.41) v2(114.68,138.83) v2(114.68,138.24) v2(115.24,158.07) v2(115.24,157.5) v2(115.27,140) v2(115.27,139.41) v2(115.27,138.83) v2(115.27,138.24) v2(115.24,68.47) v2(115.44,186.48) v2(115.54,183.77) v2(115.81,157.5) v2(115.77,91.69) v2(115.77,90.42) v2(115.77,89.15) v2(115.91,187.66) v2(115.82,158.07) v2(115.85,140) v2(115.85,139.41) v2(115.85,138.83) v2(115.84,68.47) v2(115.88,67.13) v2(116.28,135.92) v2(116.38,157.5) v2(116.4,131.31) v2(116.42,158.07) v2(116.43,140) v2(116.43,139.41) v2(116.43,138.83) v2(116.43,68.47) v2(116.84,185.9) v2(117.02,157.5) v2(117.02,140) v2(117.02,139.41) v2(117.02,138.83) v2(117.03,91.96) v2(117.02,68.47) v2(117.18,187.66) v2(117.15,67.13) v2(117.34,136.15) v2(117.41,131.12) v2(117.6,141.17) v2(117.6,140.58) v2(117.6,140) v2(117.6,139.41) v2(117.6,138.83) v2(117.65,187.22) v2(117.65,184.17) v2(117.62,68.47) v2(117.84,88.66) v2(118.19,141.17) v2(118.19,140.58) v2(118.19,140) v2(118.19,139.41) v2(118.19,138.83) v2(118.21,68.47) v2(118.45,187.66) v2(118.51,135.88) v2(118.42,131.36) v2(118.51,91.69) v2(118.51,89.15) v2(118.42,67.13) v2(118.71,183.79) v2(118.77,141.17) v2(118.77,140.58) v2(118.77,140) v2(118.77,139.41) v2(118.77,138.83) v2(118.79,68.47) v2(119.35,140) v2(119.35,139.41) v2(119.35,138.83) v2(119.69,67.13) v2(119.75,68.47) v2(119.89,184.17) v2(119.94,140) v2(119.94,139.41) v2(119.94,138.83) v2(119.94,138.24) v2(120.17,187.06) v2(120.32,68.47) v2(120.52,140) v2(120.52,139.41) v2(120.52,138.83) v2(120.52,138.24) v2(120.52,137.66) v2(120.79,188.35) v2(120.89,68.47) v2(120.92,91.69) v2(120.92,90.42) v2(120.92,89.15) v2(120.96,67.13) v2(121.46,68.47) v2(121.83,118.38) v2(122.05,188.51) v2(122.03,68.47) v2(122.17,90.69) v2(122.21,88.88) v2(122.23,67.13) v2(122.81,175.02) v2(123.24,184.4) v2(123.24,183.81) v2(123.24,183.23) v2(123.24,182.64) v2(123.32,188.51) v2(123.39,175.02) v2(123.37,81.27) v2(123.5,67.13) v2(123.83,184.4) v2(123.83,183.81) v2(123.83,183.23) v2(123.83,182.64) v2(123.98,175.02) v2(124.18,91.69) v2(124.18,90.42) v2(124.18,89.15) v2(124.41,184.4) v2(124.41,183.81) v2(124.41,183.23) v2(124.41,182.64) v2(124.59,188.51) v2(124.56,175.02) v2(124.77,67.13) v2(124.99,184.4) v2(124.99,183.81) v2(124.99,183.23) v2(124.99,182.64) v2(125.15,175.02) v2(125.58,184.4) v2(125.58,183.81) v2(125.58,183.23) v2(125.58,182.64) v2(125.73,175.02) v2(125.86,188.51) v2(126.04,67.13) v2(126.16,184.4) v2(126.16,183.81) v2(126.16,183.23) v2(126.16,182.64) v2(126.31,175.02) v2(126.75,184.4) v2(126.75,183.81) v2(126.75,183.23) v2(126.75,182.64) v2(126.9,175.02) v2(127.13,188.51) v2(127.31,67.13) v2(127.33,183.23) v2(127.33,182.64) v2(127.48,175.02) v2(128.07,175.02) v2(128.58,67.13) v2(128.87,73.42) v2(129.85,67.13) v2(130.16,181.37) v2(131.05,182.2) v2(131.05,181.12) v2(131.12,67.13) v2(131.31,73.59) v2(131.69,91.94) v2(131.7,90.62) v2(131.7,88.09) v2(131.94,182.2) v2(131.94,181.12) v2(132.39,67.13) v2(132.51,138.85) v2(132.89,182.2) v2(132.89,181.12) v2(133.04,132.79) v2(133.13,127.66) v2(133.39,126.64) v2(133.55,91.59) v2(133.55,90.3) v2(133.67,73.81) v2(133.66,67.13) v2(133.78,181.56) v2(133.79,131.5) v2(134.29,73.63) v2(134.29,72.99) v2(134.44,146.57) v2(134.44,142.83) v2(134.64,123.57) v2(134.8,181.63) v2(134.8,181.04) v2(134.8,180.46) v2(134.8,179.88) v2(134.92,73.63) v2(134.92,72.99) v2(134.93,67.13) v2(135.38,181.63) v2(135.38,181.04) v2(135.38,180.46) v2(135.38,179.88) v2(135.61,91.73) v2(135.58,90.35) v2(135.52,73.63) v2(135.52,72.99) v2(135.85,124.84) v2(135.97,181.63) v2(135.97,181.04) v2(135.97,180.46) v2(135.97,179.88) v2(136.12,73.63) v2(136.12,72.99) v2(136.2,67.13) v2(136.42,122.22) v2(136.55,181.63) v2(136.55,181.04) v2(136.55,180.46) v2(136.55,179.88) v2(136.72,73.63) v2(136.72,72.99) v2(137.13,181.63) v2(137.13,181.04) v2(137.13,180.46) v2(137.13,179.88) v2(137.25,125.97) v2(137.3,73.63) v2(137.3,72.99) v2(137.47,67.13) v2(137.58,123.5) v2(137.84,91.77) v2(137.84,90.5) v2(138.74,67.13) v2(138.93,124.85) v2(139.18,181.37) v2(139.41,71.61) v2(139.66,72.66) v2(139.61,70.62) v2(139.83,188.51) v2(139.95,123.15) v2(140.01,67.13) v2(140.07,182.2) v2(140.07,181.12) v2(140.01,92.29) v2(140.06,90.49) v2(140.96,182.2) v2(140.96,181.12) v2(141.1,188.51) v2(141.26,124.43) v2(141.28,67.13) v2(141.38,140.34) v2(141.38,138.82) v2(141.5,145.78) v2(141.42,144.92) v2(141.47,144.16) v2(141.5,122.99) v2(141.52,136.98) v2(141.7,141.17) v2(141.91,182.2) v2(141.91,181.12) v2(141.87,138.12) v2(142.16,148.67) v2(142.21,145.72) v2(142.15,144.11) v2(142.37,188.51) v2(142.39,141.16) v2(142.46,138.13) v2(142.57,90.8) v2(142.57,89.53) v2(142.55,67.13) v2(142.62,163.31) v2(142.8,181.56) v2(142.93,148.68) v2(143.26,163.31) v2(143.31,72.65) v2(143.26,70.58) v2(143.58,71.56) v2(143.64,188.51) v2(143.81,181.63) v2(143.81,181.04) v2(143.81,180.46) v2(143.81,179.88) v2(143.89,163.31) v2(143.82,67.13) v2(144.3,120.87) v2(144.23,90.8) v2(144.4,181.63) v2(144.4,181.04) v2(144.4,180.46) v2(144.4,179.88) v2(144.4,179.29) v2(144.5,148.68) v2(144.53,163.31) v2(144.91,188.51) v2(144.98,181.63) v2(144.98,181.04) v2(144.98,180.46) v2(144.98,179.88) v2(144.98,179.29) v2(145.09,67.13) v2(145.12,121.68) v2(145.26,148.7) v2(145.39,166.12) v2(145.39,165.49) v2(145.39,164.85) v2(145.39,164.22) v2(145.57,181.63) v2(145.57,181.04) v2(145.57,180.46) v2(145.57,179.88) v2(145.57,179.29) v2(145.81,141.09) v2(145.92,145.72) v2(145.92,144.06) v2(145.92,138.15) v2(145.92,136.49) v2(146.18,188.51) v2(146.15,181.63) v2(146.15,181.04) v2(146.15,180.46) v2(146.15,179.88) v2(146.15,179.29) v2(146.21,132.53) v2(146.21,131.9) v2(146.41,141.08) v2(146.36,67.13) v2(146.51,144.04) v2(146.51,138.13) v2(146.51,136.47) v2(146.52,145.7) v2(146.83,148.68) v2(146.94,90.8) v2(147.04,141.11) v2(147.15,145.73) v2(147.14,144.07) v2(147.14,138.16) v2(147.14,136.5) v2(147.29,122.7) v2(147.45,188.51) v2(147.65,148.68) v2(147.63,67.13) v2(147.85,125.75) v2(148.07,183.6) v2(148.07,181.18) v2(148.5,92.04) v2(148.5,90.77) v2(148.72,188.51) v2(148.9,67.13) v2(148.96,182.01) v2(148.96,180.93) v2(149.02,120.83) v2(149.05,118.9) v2(149.26,148.68) v2(149.85,182.01) v2(149.85,180.93) v2(149.86,67.96) v2(149.99,188.51) v2(150.01,153.23) v2(150.01,151.93) v2(150.01,150.63) v2(150.01,149.33) v2(150,148.7) v2(150.16,123.56) v2(150.16,121.59) v2(150.42,75.96) v2(150.42,72.92) v2(150.56,144.09) v2(150.8,182.01) v2(150.8,180.93) v2(150.8,148.68) v2(150.91,68.68) v2(151.05,91.79) v2(151.05,90.52) v2(151.26,188.51) v2(151.59,150.63) v2(151.59,148.68) v2(151.69,181.37) v2(151.79,146.32) v2(151.76,144.8) v2(151.74,143.45) v2(151.76,142.87) v2(151.78,140.86) v2(151.79,137.85) v2(151.82,137.19) v2(151.92,139.19) v2(152.18,68.68) v2(152.53,188.51) v2(152.51,181.37) v2(152.51,180.79) v2(152.51,180.21) v2(152.51,179.62) v2(152.51,179.04) v2(152.83,92.06) v2(152.85,90.25) v2(153.1,181.37) v2(153.1,180.79) v2(153.1,180.21) v2(153.1,179.62) v2(153.1,179.04) v2(153.21,147.08) v2(153.47,75.96) v2(153.47,72.92) v2(153.45,68.68) v2(153.68,181.37) v2(153.68,180.79) v2(153.68,180.21) v2(153.68,179.62) v2(153.68,179.04) v2(153.8,188.51) v2(153.91,123.87) v2(153.92,125.76) v2(154.06,121.06) v2(154.07,119.26) v2(154.23,91.79) v2(154.23,90.52) v2(154.23,89.25) v2(154.23,76.78) v2(154.71,148.68) v2(154.72,68.68) v2(154.86,76.79) v2(155.07,188.51) v2(155.11,139.85) v2(155.13,139.14) v2(155.15,138) v2(155.17,137.39) v2(155.2,136.1) v2(155.16,125.04) v2(155.16,123.21) v2(155.26,121.31) v2(155.5,183.28) v2(155.5,181.18) v2(155.97,146.44) v2(155.99,68.68) v2(156.34,188.51) v2(156.39,182.01) v2(156.39,180.93) v2(156.33,148.67) v2(156.61,146.43) v2(156.64,91.79) v2(156.64,90.52) v2(156.64,89.25) v2(157.1,152.57) v2(157.11,151.29) v2(157.11,148.68) v2(157.18,141.05) v2(157.15,140.43) v2(157.28,182.01) v2(157.28,180.93) v2(157.27,142.25) v2(157.26,141.65) v2(157.26,68.68) v2(157.61,188.51) v2(157.69,123.21) v2(157.7,120.99) v2(157.84,154) v2(158.04,90.79) v2(158.09,88.98) v2(158.12,139.94) v2(158.23,182.01) v2(158.23,180.93) v2(158.53,68.68) v2(158.78,120.59) v2(158.88,188.51) v2(159.12,181.37) v2(159.23,179.93) v2(159.23,179.09) v2(159.44,148.7) v2(159.43,91.79) v2(159.43,90.52) v2(159.43,89.25) v2(159.61,178.63) v2(159.64,179.49) v2(159.8,68.68) v2(159.89,180.03) v2(159.97,182.36) v2(159.97,181.78) v2(159.94,181.12) v2(160.15,188.51) v2(160.17,180.56) v2(160.19,124.68) v2(160.25,179.49) v2(160.25,178.91) v2(160.25,178.33) v2(160.5,182.09) v2(160.5,181.5) v2(160.71,172.05) v2(160.71,171.47) v2(160.71,170.88) v2(160.71,170.3) v2(160.71,169.69) v2(160.71,169.06) v2(160.83,179.49) v2(160.83,178.91) v2(160.83,178.33) v2(161.01,182.36) v2(161.07,148.69) v2(161.06,122.88) v2(161.07,68.68) v2(161.34,172.05) v2(161.34,171.47) v2(161.34,170.88) v2(161.34,170.3) v2(161.42,188.51) v2(161.8,151.92) v2(161.79,148.69) v2(161.77,91.79) v2(161.77,90.52) v2(161.98,172.05) v2(161.98,171.47) v2(161.98,170.88) v2(161.98,170.3) v2(162,146.44) v2(161.95,140.03) v2(161.97,136.92) v2(162.07,141.69) v2(162.34,68.68) v2(162.61,164.86) v2(162.61,164.23) v2(162.61,163.59) v2(162.61,162.96) v2(162.61,162.32) v2(162.61,161.69) v2(162.56,136.95) v2(162.69,188.51) v2(162.69,141.69) v2(162.74,140.03) v2(162.72,124.28) v2(163.25,164.23) v2(163.25,163.59) v2(163.25,162.96) v2(163.25,162.32) v2(163.25,161.69) v2(163.29,92.12) v2(163.28,90.25) v2(163.43,148.69) v2(163.56,159.78) v2(163.61,68.68) v2(163.67,187.71) v2(163.88,163.59) v2(163.88,162.96) v2(163.88,162.32) v2(163.88,161.69) v2(163.87,144.77) v2(163.87,144.13) v2(163.87,143.5) v2(163.87,142.86) v2(164.07,122.93) v2(164.13,159.83) v2(164.17,148.7) v2(164.39,166.77) v2(164.39,166.13) v2(164.52,163.59) v2(164.52,162.96) v2(164.52,162.32) v2(164.52,161.69) v2(164.82,90.52) v2(164.88,68.68) v2(164.94,187.66) v2(165.27,182.35) v2(165.37,121.64) v2(165.79,148.71) v2(165.89,182.97) v2(165.89,181.73) v2(166.21,187.66) v2(166.13,124.62) v2(166.15,68.68) v2(166.32,135.73) v2(166.51,182.35) v2(166.56,151.94) v2(166.58,151.28) v2(166.57,150.59) v2(166.56,148.72) v2(166.88,139.93) v2(166.94,136.92) v2(167.06,141.54) v2(167.21,145.12) v2(167.21,144.42) v2(167.21,143.78) v2(167.21,143.15) v2(167.21,142.51) v2(167.23,90.52) v2(167.23,89.25) v2(167.34,146.98) v2(167.32,140.75) v2(167.41,123.37) v2(167.48,187.66) v2(167.42,68.68) v2(168.3,90.82) v2(168.69,68.68) v2(168.75,187.66) v2(168.73,75.56) v2(169.09,124.8) v2(169.55,77.58) v2(169.96,68.68) v2(170.02,187.78) v2(170.37,155.81) v2(170.41,91.79) v2(170.41,90.52) v2(170.44,123.45) v2(171.06,188.51) v2(171.23,68.68) v2(172.24,159.76) v2(172.33,188.51) v2(172.5,68.68) v2(173.06,88.23) v2(173.18,161.7) v2(173.6,188.51) v2(173.71,162.03) v2(173.71,161.42) v2(173.66,88.24) v2(173.81,159.76) v2(173.77,68.68) v2(174.32,162.64) v2(174.32,162.03) v2(174.32,161.42) v2(174.87,188.51) v2(175.04,68.68) v2(175.38,187.65) v2(175.38,187.07) v2(175.38,186.49) v2(175.78,169.55) v2(175.78,168.91) v2(175.79,168.31) v2(175.78,167.71) v2(175.78,167.12) v2(175.87,164.33) v2(175.97,187.65) v2(175.97,187.07) v2(175.97,186.49) v2(176.14,188.51) v2(176.31,68.68) v2(176.45,176.4) v2(176.45,175.76) v2(176.45,175.13) v2(176.45,174.49) v2(176.45,173.86) v2(176.45,173.22) v2(176.45,172.59) v2(176.45,171.95) v2(176.45,171.32) v2(176.45,170.68) v2(176.45,170.05) v2(176.45,169.41) v2(176.45,168.78) v2(176.45,168.14) v2(176.45,167.51) v2(176.45,166.87) v2(176.45,166.24) v2(176.45,165.6) v2(176.45,164.97) v2(176.45,164.33) v2(176.45,163.75) v2(176.6,187.65) v2(176.6,187.07) v2(176.6,186.49) v2(176.71,69.94) v2(177.04,176.4) v2(177.04,175.76) v2(177.04,175.13) v2(177.04,174.49) v2(177.04,173.86) v2(177.04,173.22) v2(177.04,172.59) v2(177.04,171.95) v2(177.04,171.32) v2(177.04,170.68) v2(177.04,170.05) v2(177.04,169.41) v2(177.04,168.78) v2(177.04,168.14) v2(177.04,167.51) v2(177.04,166.87) v2(177.04,166.24) v2(177.04,165.6) v2(177.04,164.97) v2(177.04,164.33) v2(177.04,163.75) v2(177.24,187.65) v2(177.24,187.07) v2(177.24,186.49) v2(177.41,188.51) v2(177.33,69.94) v2(177.58,68.68) v2(177.87,187.65) v2(177.87,187.07) v2(177.87,186.49) v2(177.95,79.55) v2(177.95,69.92) v2(178.26,122.9) v2(178.51,187.65) v2(178.51,187.07) v2(178.51,186.49) v2(178.68,188.51) v2(178.69,122.29) v2(178.79,120.13) v2(178.77,79.55) v2(178.85,68.68) v2(179.09,187.65) v2(179.09,187.07) v2(179.09,186.49) v2(179.6,79.55) v2(179.95,188.51) v2(180.12,68.68) v2(180.38,79.55) v2(180.73,118.87) v2(180.97,79.55) v2(181.04,92.36) v2(181.22,188.51) v2(181.39,68.68) v2(182.13,125.6) v2(182.29,121.34) v2(182.38,159.2) v2(182.39,154.72) v2(182.49,188.51) v2(182.66,68.68) v2(182.8,177.31) v2(182.99,92.03) v2(182.99,90.13) v2(183.29,168.28) v2(183.26,167.68) v2(183.41,177.36) v2(183.41,176.78) v2(183.41,176.19) v2(183.6,159.48) v2(183.55,154.44) v2(183.55,121) v2(183.67,126.04) v2(183.76,188.51) v2(184,176.19) v2(183.93,68.68) v2(184.3,167.66) v2(184.58,176.19) v2(184.75,154.74) v2(184.77,91.71) v2(184.77,90.44) v2(184.77,89.17) v2(184.91,168.25) v2(184.9,167.66) v2(184.88,159.1) v2(184.88,121.38) v2(185.03,188.51) v2(185.07,125.53) v2(185.17,176.19) v2(185.2,68.68) v2(185.34,167.21) v2(185.34,166.63) v2(185.37,165.19) v2(185.44,168.55) v2(185.44,167.91) v2(185.75,176.19) v2(186.04,182.98) v2(186.3,188.51) v2(186.33,176.19) v2(186.47,68.68) v2(186.66,183.6) v2(186.92,176.19) v2(186.99,110.32) v2(187.18,91.71) v2(187.18,90.44) v2(187.18,89.17) v2(187.28,182.98) v2(187.57,188.51) v2(187.74,68.68) v2(188.14,120.67) v2(188.66,90.76) v2(188.84,188.51) v2(189.01,68.68) v2(189.64,177.56) v2(189.64,176.96) v2(190.11,188.51) v2(190.21,177.55) v2(190.22,176.98) v2(190.28,68.68) v2(190.33,91.71) v2(190.33,90.44) v2(190.33,89.17) v2(191.07,183.66) v2(191.12,176.51) v2(191.38,188.51) v2(191.55,68.68) v2(191.69,184.28) v2(191.69,183.04) v2(191.76,176.55) v2(192.14,187.09) v2(192.32,183.66) v2(192.65,188.51) v2(192.71,187.66) v2(192.71,187.09) v2(192.7,91.71) v2(192.7,90.44) v2(192.82,68.68) v2(193.28,187.66) v2(193.28,187.09) v2(193.85,187.66) v2(193.85,187.09) v2(193.92,188.51) v2(194.09,68.68) v2(194.42,187.66) v2(194.42,187.09) v2(195,187.66) v2(195,187.09) v2(195.19,188.51) v2(195.36,68.68) v2(195.57,187.66) v2(195.57,187.09) v2(196.14,187.66) v2(196.14,187.09) v2(196.24,157.46) v2(196.38,91.71) v2(196.38,90.44) v2(196.38,89.17) v2(196.46,188.51) v2(196.71,187.66) v2(196.63,68.68) v2(197.18,162.27) v2(197.6,162.72) v2(197.73,188.51) v2(197.9,68.68) v2(198.77,91.71) v2(198.77,90.44) v2(198.77,89.17) v2(199,188.51) v2(199.16,171.62) v2(199.16,171.04) v2(199.16,170.45) v2(199.16,169.87) v2(199.17,68.68) v2(199.63,155.91) v2(200.27,188.51) v2(200.41,91.4) v2(200.41,90.76) v2(200.44,68.68) v2(200.65,122.38) v2(201.47,173.53) v2(201.47,172.94) v2(201.54,188.51) v2(201.6,154.32) v2(201.69,68.44) v2(202.25,67.31) v2(202.44,91.71) v2(202.81,188.51) v2(203.51,67.13) v2(204,71.73) v2(204.08,188.51) v2(204.21,70.75) v2(204.26,72.79) v2(204.72,155.62) v2(204.78,67.13) v2(205.35,188.51) v2(205.79,96.38) v2(206.05,67.13) v2(206.3,153.99) v2(206.62,188.51) v2(206.68,187.6) v2(206.87,132.21) v2(207.25,116.79) v2(207.31,187.6) v2(207.32,67.13) v2(207.89,188.51) v2(207.9,72.78) v2(207.85,70.71) v2(208,91.67) v2(208,90.38) v2(208,89.01) v2(208.17,71.68) v2(208.59,67.13) v2(209.16,188.51) v2(209.85,91.59) v2(209.85,88.93) v2(209.86,67.13) v2(210.05,179.51) v2(210.24,181.14) v2(210.43,188.51) v2(210.65,179.5) v2(210.63,178.92) v2(210.82,181.14) v2(210.88,95.98) v2(211.13,67.13) v2(211.24,179.5) v2(211.22,178.91) v2(211.41,181.14) v2(211.51,187.6) v2(211.7,188.51) v2(211.76,95.95) v2(211.82,179.5) v2(211.82,178.91) v2(211.91,91.73) v2(211.99,181.14) v2(211.92,89.08) v2(212.06,160.25) v2(212.14,187.6) v2(212.4,179.5) v2(212.4,178.91) v2(212.4,67.13) v2(212.78,187.6) v2(212.97,188.51) v2(213.05,179.51) v2(213.28,78.89) v2(213.67,179.5) v2(213.67,67.13) v2(214.14,91.77) v2(214.14,90.5) v2(214.14,89.27) v2(214.24,188.51) v2(214.94,67.13) v2(215.51,188.51) v2(215.44,78.89) v2(215.91,92.35) v2(215.91,90.44) v2(216.21,67.13) v2(216.4,168.1) v2(216.78,188.51) v2(217.48,67.13) v2(218.05,188.51) v2(218.08,174.76) v2(218.51,91.57) v2(218.49,90.03) v2(218.75,67.13) v2(219.32,188.51) v2(219.89,174.83) v2(220.02,67.13) v2(220.41,88.94) v2(220.42,91.77) v2(220.42,90.4) v2(220.59,188.51) v2(221.09,143.66) v2(221.29,67.13) v2(221.86,188.51) v2(222.17,137.31) v2(222.56,67.13) v2(223.13,188.51) v2(223.32,133.11) v2(223.63,185.25) v2(223.72,156.77) v2(223.83,67.13) v2(224.02,92.27) v2(224.02,90.74) v2(224.02,89.22) v2(224.22,185.25) v2(224.4,188.51) v2(225.1,67.13) v2(225.67,188.51) v2(225.86,186.55) v2(226.36,73.3) v2(226.37,67.13) v2(226.5,186.55) v2(226.59,91.76) v2(226.9,188.2) v2(227.25,73.3) v2(227.64,67.13) v2(228.05,187.66) v2(228.27,73.3) v2(228.33,186.29) v2(228.35,185.7) v2(228.37,92.08) v2(228.37,90.17) v2(228.91,67.13) v2(229.32,187.66) v2(230.14,91.77) v2(230.14,90.5) v2(230.14,89.23) v2(230.18,67.13) v2(230.46,80.71) v2(230.59,187.66) v2(231.19,75.2) v2(231.45,67.13) v2(231.84,187.45) v2(232.22,186.24) v2(232.27,80.73) v2(232.42,91.77) v2(232.42,90.5) v2(232.42,89.23) v2(232.72,67.13) v2(233.07,185.3) v2(233.99,67.13) v2(234.2,90.82) v2(234.2,88.92) v2(234.24,184.8) v2(234.24,80.73) v2(235.26,67.13) v2(235.51,184.76) v2(235.66,91.77) v2(235.66,90.5) v2(235.66,89.23) v2(236.53,67.13) v2(236.78,184.8) v2(236.93,181.53) v2(237.26,78.68) v2(237.8,67.13) v2(237.95,185.29) v2(237.94,91.77) v2(237.94,90.5) v2(237.94,89.23) v2(238.53,78.68) v2(238.81,186.23) v2(238.94,96.38) v2(239.07,67.13) v2(239.19,187.44) v2(239.14,78.68) v2(239.32,181.63) v2(239.47,92.09) v2(239.47,90.19) v2(239.77,78.68) v2(239.88,188.51) v2(240.34,67.13) v2(241.15,188.51) v2(241.21,121.81) v2(241.24,91.77) v2(241.24,90.5) v2(241.33,179.72) v2(241.48,112.54) v2(241.61,67.13) v2(241.68,182.19) v2(241.68,181.58) v2(241.86,179.42) v2(242.21,173.98) v2(242.34,180.82) v2(242.37,121.79) v2(242.42,188.51) v2(242.47,179.44) v2(242.84,173.78) v2(242.88,67.13) v2(242.94,121.78) v2(243.31,181.6) v2(243.31,180.99) v2(243.42,173.79) v2(243.54,171.44) v2(243.53,91.77) v2(243.53,90.5) v2(243.53,89.23) v2(243.85,142.25) v2(243.88,139.1) v2(244.07,188.51) v2(244.17,180.94) v2(244.46,68.32) v2(244.6,186.49) v2(244.67,151.27) v2(244.63,69.68) v2(244.78,187.86) v2(245.08,129.11) v2(245.05,90.82) v2(245.05,88.92) v2(245.41,185.04) v2(245.83,143.2) v2(245.87,138.19) v2(246.58,91.77) v2(246.58,89.23) v2(246.91,184.79) v2(247.29,70.17) v2(247.67,165.96) v2(247.7,164.74) v2(247.66,163.18) v2(247.7,162.31) v2(247.79,139.15) v2(247.75,67.75) v2(247.83,142.18) v2(247.93,68.97) v2(248.02,185.54) v2(248.15,188.14) v2(248.3,186.99) v2(248.63,68.37) v2(248.83,187.66) v2(248.83,186.39) v2(248.83,183.85) v2(248.83,182.58) v2(248.83,181.31) v2(248.83,180.04) v2(248.83,178.77) v2(248.83,177.5) v2(248.83,176.23) v2(248.83,174.96) v2(248.83,173.69) v2(248.83,172.42) v2(248.83,171.15) v2(248.83,169.88) v2(248.83,168.61) v2(248.83,167.34) v2(248.83,166.07) v2(249.29,164.89) v2(250,68.93) v2(250.33,164.15) v2(250.33,162.88) v2(250.33,161.61) v2(250.33,160.34) v2(250.33,159.07) v2(250.33,157.8) v2(250.33,156.53) v2(250.33,155.26) v2(250.33,153.99) v2(250.33,152.72) v2(250.33,151.45) v2(250.33,150.18) v2(250.33,148.91) v2(250.33,147.64) v2(250.33,146.37) v2(250.33,145.1) v2(250.33,143.83) v2(250.33,142.56) v2(250.33,141.29) v2(250.33,140.02) v2(250.33,138.75) v2(250.33,137.48) v2(250.33,136.21) v2(250.33,134.94) v2(250.33,133.67) v2(250.33,132.4) v2(250.36,131.13) v2(250.45,129.87) v2(250.58,128.6) v2(250.77,127.35) v2(251.01,126.1) v2(251.08,83.24) v2(251.29,124.86) v2(251.27,68.93) v2(251.63,123.64) v2(251.87,82.06) v2(252.02,122.43) v2(252.45,121.23) v2(252.54,68.93) v2(252.94,120.06) v2(253.47,118.91) v2(253.63,87.13) v2(253.81,68.93) v2(254.04,117.77) v2(254.22,106.33) v2(254.24,105.75) v2(254.66,116.67) v2(254.64,111.44) v2(255.08,68.93) v2(255.33,115.58) v2(255.99,88.83) v2(256.04,114.53) v2(256.34,85.87) v2(256.35,68.93) v2(256.45,69.99) v2(256.79,113.51) v2(257.05,70.01) v2(257.58,112.51) v2(257.62,68.93) v2(257.91,100.88) v2(257.94,102.08) v2(257.94,101.47) v2(258.41,111.55) v2(258.57,102.08) v2(258.57,101.49) v2(258.89,68.93) v2(259.15,105.61) v2(259.28,110.63) v2(259.88,83.88) v2(260.18,109.74) v2(260.16,68.93) v2(260.52,83.87) v2(260.76,69.96) v2(261.12,108.88) v2(261.43,68.93) v2(262.1,108.07) v2(262.44,82.73) v2(262.7,68.93) v2(263.11,107.29) v2(263.57,87.2) v2(263.58,82.36) v2(263.97,68.93) v2(264.14,106.56) v2(264.15,87.1) v2(264.59,83.48) v2(265.21,105.87) v2(265.24,68.93) v2(266.3,105.22) v2(266.51,68.93) v2(267.42,104.62) v2(267.78,68.93) v2(268.56,104.06) v2(269.05,68.93) v2(269.72,103.55) v2(270.32,68.93) v2(270.91,103.09) v2(271.42,96.61) v2(271.42,96.03) v2(271.59,68.93) v2(272.11,102.68) v2(272.02,96.61) v2(272.02,96.03) v2(272.02,95.4) v2(272.02,94.76) v2(272.66,95.22) v2(272.66,94.63) v2(272.86,68.93) v2(273.3,95.22) v2(273.29,94.63) v2(273.32,102.31) v2(273.47,72.26) v2(273.99,95.22) v2(273.93,94.63) v2(274.13,68.93) v2(274.55,102) v2(274.6,95.85) v2(274.62,95.24) v2(275.4,68.93) v2(275.8,101.73) v2(276.02,72.54) v2(276.67,68.93) v2(277.05,101.51) v2(277.94,68.93) v2(278.31,101.35) v2(279.21,68.93) v2(279.57,101.23) v2(280.48,68.93) v2(280.84,101.17) v2(281.75,68.93) v2(282.11,101.16) v2(282.93,99.41) v2(283.02,68.93) v2(283.38,101.16) v2(284.12,99.76) v2(284.29,68.93) v2(284.65,101.16) v2(284.97,93.93) v2(285.42,94.32) v2(285.58,97.27) v2(285.58,96.38) v2(285.56,68.93) v2(285.92,101.16) v2(286.05,96.79) v2(286.47,97.27) v2(286.47,96.38) v2(286.83,68.93) v2(287.19,101.16) v2(288.1,68.93) v2(288.46,101.16) v2(289.37,68.93) v2(289.73,101.16) v2(290.64,68.93) v2(291,101.16) v2(291.52,92.47) v2(291.91,68.93) v2(292.27,101.16) v2(293.18,68.93) v2(293.54,101.21) v2(294.45,68.93) v2(294.81,101.31) v2(295.72,68.93) v2(296.07,101.45) v2(296.99,68.93) v2(297.32,101.65) v2(298.26,68.93) v2(298.57,101.9) v2(299.53,68.93) v2(299.8,102.2) v2(300.8,68.93) v2(301.02,102.55) v2(302.07,68.93) v2(302.23,102.95) v2(303.34,68.93) v2(303.42,103.4) v2(304.59,103.89) v2(304.61,68.93) v2(305.73,104.43) v2(305.88,68.93) v2(306.97,105.08) v2(307.15,68.93) v2(308.07,105.72) v2(308.42,68.93) v2(309.14,106.4) v2(309.69,68.93) v2(310.19,107.12) v2(310.96,68.93) v2(311.29,107.75) v2(312.23,68.93) v2(312.56,107.75) v2(313.5,68.93) v2(313.83,107.75) v2(313.88,95.78) v2(314.77,68.93) v2(315.1,107.75) v2(315.41,95.78) v2(316.04,68.93) v2(316.15,75.18) v2(316.15,74.59) v2(316.37,107.75) v2(316.74,75.18) v2(316.74,74.59) v2(316.74,74.01) v2(317.31,68.93) v2(317.32,75.18) v2(317.6,108.09) v2(317.81,114.42) v2(317.81,113.15) v2(317.81,111.88) v2(317.81,110.61) v2(317.81,109.34) v2(317.91,75.18) v2(318.19,99.33) v2(318.22,115.62) v2(318.49,75.18) v2(318.58,68.93) v2(318.89,116.7) v2(319.07,75.18) v2(319.37,103.35) v2(319.37,102.24) v2(319.37,101.12) v2(319.51,117.81) v2(319.46,108.41) v2(319.66,75.18) v2(319.88,118.53) v2(319.85,68.93) v2(320.14,88.87) v2(320.24,75.18) v2(320.42,119.68) v2(320.49,103.35) v2(320.49,102.24) v2(320.49,101.12) v2(320.8,97.04) v2(320.73,88.87) v2(320.83,75.18) v2(320.92,120.85) v2(321.12,68.93) v2(321.31,88.87) v2(321.37,122.03) v2(321.41,75.18) v2(321.61,103.35) v2(321.61,102.24) v2(321.61,101.12) v2(321.68,108.41) v2(321.89,88.87) v2(322,89.6) v2(322,75.18) v2(322.06,123.1) v2(322.13,94.6) v2(322.39,68.93) v2(322.48,88.87) v2(322.58,89.6) v2(322.58,75.18) v2(323.07,129.97) v2(323.02,128.7) v2(323.06,88.87) v2(323.16,185.45) v2(323.16,184.18) v2(323.16,182.91) v2(323.16,181.64) v2(323.16,180.37) v2(323.16,179.1) v2(323.16,177.83) v2(323.16,176.56) v2(323.16,175.29) v2(323.16,174.02) v2(323.16,172.75) v2(323.16,171.48) v2(323.16,170.21) v2(323.16,168.94) v2(323.16,167.67) v2(323.16,166.4) v2(323.16,165.13) v2(323.16,163.86) v2(323.16,162.59) v2(323.16,161.32) v2(323.16,160.05) v2(323.16,158.78) v2(323.16,157.51) v2(323.16,156.24) v2(323.16,154.97) v2(323.16,153.7) v2(323.16,152.43) v2(323.16,151.16) v2(323.16,149.89) v2(323.16,148.62) v2(323.16,147.35) v2(323.16,138.86) v2(323.17,137.59) v2(323.17,136.32) v2(323.17,135.05) v2(323.19,133.78) v2(323.17,132.51) v2(323.12,131.24) v2(323.16,89.6) v2(323.16,78.1) v2(323.16,77.52) v2(323.16,76.93) v2(323.16,76.35) v2(323.16,75.76) v2(323.16,75.18) v2(323.26,186.71) v2(323.29,123.41) v2(323.4,144.83) v2(323.32,141.39) v2(323.65,88.87) v2(323.66,68.93) v2(323.8,90.19) v2(323.8,89.6) v2(323.75,78.1) v2(323.75,77.52) v2(323.75,76.93) v2(323.75,76.35) v2(323.75,75.76) v2(323.75,75.18) v2(323.75,74.59) v2(323.75,74.01) v2(323.75,73.43) v2(323.87,127.76) v2(324.24,124.25) v2(324.33,89.39) v2(324.51,186.96) v2(324.59,141.43) v2(324.57,126.7) v2(324.68,144.82) v2(324.7,125.44) v2(324.92,89.39) v2(324.93,68.93) v2(325.5,89.39) v2(325.62,187.57) v2(325.7,143.88) v2(325.69,142.35) v2(326.09,89.39) v2(326.2,68.93) v2(326.31,147.97) v2(326.69,146.17) v2(326.62,139.53) v2(326.62,137.78) v2(326.63,135.23) v2(326.63,134.65) v2(326.63,134.07) v2(326.67,89.39) v2(326.86,187.86) v2(327.47,68.93) v2(327.58,130.96) v2(327.56,127.98) v2(328.13,187.86) v2(328.45,148.38) v2(328.57,146.45) v2(328.74,68.93) v2(329.13,141.17) v2(329.12,139.39) v2(329.29,107.74) v2(329.4,187.86) v2(329.67,137.79) v2(329.87,109.37) v2(330.01,68.93) v2(330.6,101.19) v2(330.67,187.86) v2(331.01,86.47) v2(331.28,68.93) v2(331.41,86.96) v2(331.69,86.45) v2(331.72,131.53) v2(331.76,87.59) v2(331.94,187.86) v2(332.02,86.96) v2(332.13,184.75) v2(332.3,86.45) v2(332.49,183.15) v2(332.45,101.24) v2(332.55,68.93) v2(332.7,86.94) v2(332.93,86.39) v2(333.11,182.01) v2(333.21,187.86) v2(333.2,85.01) v2(333.31,86.94) v2(333.53,86.39) v2(333.6,85.81) v2(333.77,68.6) v2(333.82,85.02) v2(333.96,86.84) v2(334.48,187.86) v2(334.57,86.84) v2(334.6,85.02) v2(334.59,67.63) v2(334.81,86.31) v2(334.91,85.5) v2(335.2,86.75) v2(335.19,85) v2(335.69,181.25) v2(335.64,87.15) v2(335.79,85.01) v2(335.86,86.59) v2(335.86,67.63) v2(336.25,87.16) v2(336.4,85.03) v2(336.47,86.59) v2(336.48,86) v2(336.6,148.8) v2(336.58,87.74) v2(336.63,144.77) v2(336.63,143.5) v2(336.63,142.23) v2(336.63,140.96) v2(336.63,139.69) v2(336.63,138.42) v2(336.63,137.15) v2(336.63,135.88) v2(336.63,105.4) v2(336.63,103.17) v2(336.89,187.86) v2(337.01,154.17) v2(337.1,86.22) v2(337.12,100.51) v2(337.13,67.63) v2(337.24,166.01) v2(337.41,165.3) v2(337.68,181.84) v2(337.74,104.29) v2(338.02,154.05) v2(338.28,164.81) v2(338.28,164.18) v2(338.4,67.63) v2(338.42,132.66) v2(338.78,147.63) v2(338.86,183.29) v2(338.86,105.4) v2(338.86,103.17) v2(339.12,187.17) v2(339.7,185.9) v2(339.69,132.66) v2(339.65,127.53) v2(339.67,67.63) v2(340.05,147.63) v2(340.96,132.66) v2(340.94,67.63) v2(341.11,185.4) v2(341.32,147.63) v2(341.54,87.5) v2(342.16,88.12) v2(342.16,87.5) v2(342.16,86.87) v2(342.21,67.63) v2(342.23,132.66) v2(342.32,186.05) v2(342.55,188.69) v2(342.59,147.63) v2(342.7,148.8) v2(342.7,131.39) v2(342.72,187.41) v2(342.78,87.5) v2(343.14,189.55) v2(343.5,132.66) v2(343.48,67.63) v2(343.73,106.03) v2(343.86,147.63) v2(344.37,106.06) v2(344.35,104.73) v2(344.55,71.8) v2(344.6,68.6) v2(344.74,189.56) v2(344.98,104.73) v2(345.8,149.44) v2(345.8,72.23) v2(345.87,68.34) v2(346.01,189.56) v2(346.97,149.55) v2(347.04,71.8) v2(347.19,68.62) v2(347.28,189.56) v2(347.67,147.63) v2(347.73,175.42) v2(347.88,173.17) v2(347.88,171.9) v2(347.86,169.55) v2(347.9,168.28) v2(347.84,165.93) v2(347.83,162.31) v2(347.82,158.7) v2(347.9,108.98) v2(347.91,164.66) v2(347.93,161.05) v2(347.94,157.43) v2(348.43,189.01) v2(348.43,187.74) v2(348.43,186.47) v2(348.43,185.2) v2(348.43,180.11) v2(348.43,178.84) v2(348.43,156.26) v2(348.43,154.99) v2(348.43,153.72) v2(348.43,152.45) v2(348.43,151.18) v2(348.43,149.91) v2(348.43,148.64) v2(348.43,132.05) v2(348.43,130.78) v2(348.51,100.23) v2(348.43,98.96) v2(348.43,97.69) v2(348.43,96.42) v2(348.43,95.15) v2(348.43,93.88) v2(348.43,92.61) v2(348.43,91.34) v2(348.43,90.07) v2(348.43,88.8) v2(348.43,87.53) v2(348.43,86.26) v2(348.43,84.99) v2(348.43,83.72) v2(348.43,82.45) v2(348.43,81.18) v2(348.43,79.91) v2(348.43,78.64) v2(348.43,77.37) v2(348.43,76.1) v2(348.43,74.83) v2(348.43,73.56) v2(348.43,72.29) v2(348.89,174.9) v2(348.95,184.04) v2(348.98,182.77) v2(349.11,171.6) v2(349.09,169.87) v2(349.07,166.27) v2(349.05,162.67) v2(349.04,159.07) v2(349.09,129.7) v2(349.11,173.47) v2(349.14,168) v2(349.16,164.4) v2(349.18,160.8) v2(349.51,101.02) v2(350.03,174.35) v2(350.03,170.72) v2(350.03,167.1) v2(350.03,163.47) v2(350.03,159.86) v2(350.03,128.85) v2(350.03,127.58) v2(350.03,126.31) v2(350.03,125.04) v2(350.03,123.77) v2(350.03,122.62) v2(350.03,108.53) v2(350.03,107.26) v2(350.03,105.99) v2(350.03,104.72) v2(350.03,103.45) v2(350.03,102.18) v4(13.03,139.65) v4(18.44,112.57) v4(111.12,140.58) v4(112.06,155.76) v4(113.68,159.02) v4(135.2,72.04) v4(162.64,160.67) v4(163.03,166.91) v4(197.87,160.67) v4(198.3,169.87) v4(213.17,180.64) v4(228.9,185.58) v4(228.98,186) v4(240.73,80.6) v4(259.09,101.75) v4(263.87,86.37) v4(271.37,95.03) v6(20.61,106.91) v6(23.16,102.38) v6(24.47,102.4) v6(25.12,102.4) v6(25.77,110.77) v6(26.41,102.36) v6(27.07,107.6) v6(29,109.52) v6(29.01,104.97)
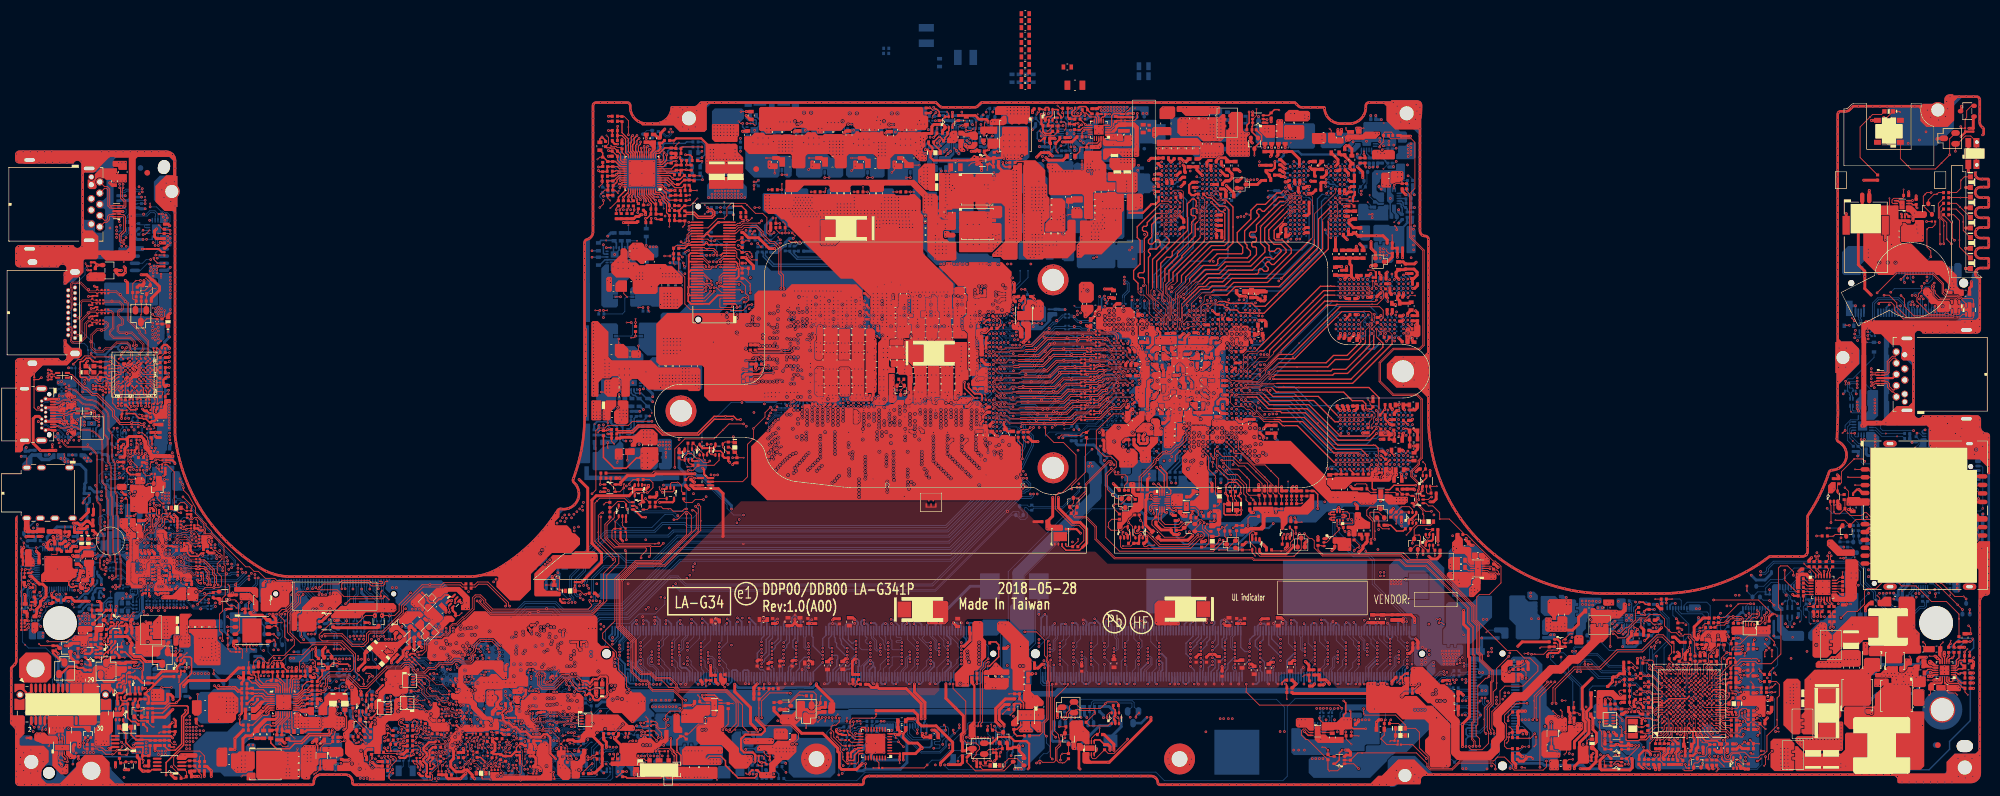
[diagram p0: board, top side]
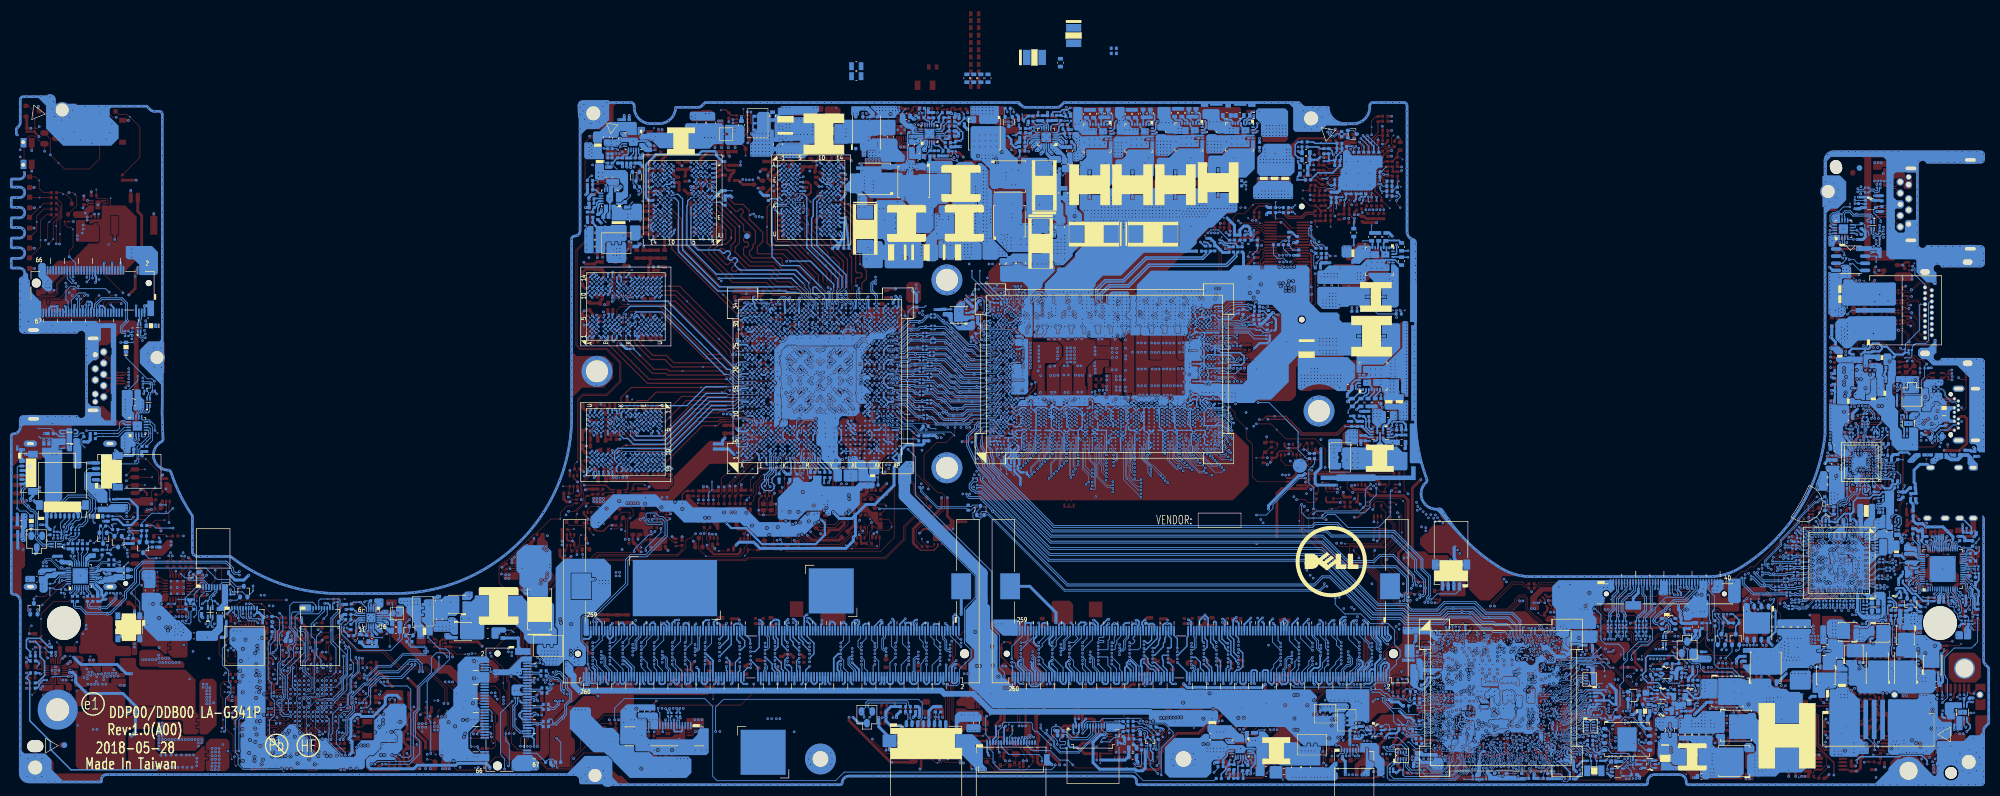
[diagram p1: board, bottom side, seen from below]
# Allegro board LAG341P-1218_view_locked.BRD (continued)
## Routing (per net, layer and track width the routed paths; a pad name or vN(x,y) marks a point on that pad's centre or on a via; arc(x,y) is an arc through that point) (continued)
GNDS_SENSE_VGA: length 4.3
  BOTTOM w0.203: 206.11,125.12 206.11,125.7 UV18.U2
  BOTTOM w0.254: PR1517.1 204.33,122.92 206.11,124.7 206.11,125.12
VBAT1_ISL88738: length 9.3
  TOP w0.14: PR1938.2 v1(40.45,88.99)
  TOP w0.203: PR1938.2 PC1945.2 40.87,86.66 41.48,86.66 41.71,86.43 41.71,85.69 42.64,84.76 45.49,84.76 45.68,84.58 PU1900.31
VBATT: length 12.2
  TOP w0.508: PR1938.1 38.62,87.9 v1(37.31,86.59) 36.39,85.67 29.74,85.67 28.91,84.83 v2(28.91,84.57)
VBUS1_ECOK: length 3.7
  TOP w0.076: 295.92,87.52 296.02,87.42 296.02,87.15 295.92,87.05 UE3.F13
  TOP w0.14: PR241.1 14.15,93.82 PR239.1 14.3,93.11 v2(14.8,92.61) ; v2(295.61,87.88) 295.61,87.84 295.92,87.53 295.92,87.52
  BOTTOM w0.14: PR269.1 54.49,84.09 v2(54.82,84.42)
VBUS2_ECOK: length 8.9
  TOP w0.076: 292.79,87.52 292.79,87.28 293.2,86.86 UE3.C13
  TOP w0.14: PR217.1 10.08,89.89 PR213.2 9.48,90.46 v2(9.48,90.53) ; v2(293.2,88.59) 292.79,88.18 292.79,87.52
  BOTTOM w0.14: PR268.1 53.64,79.57 53.95,79.27 55.83,79.27 55.88,79.32 56.64,79.32 56.82,79.5 v2(56.82,79.85)
  vias: v2(43.98,86.48)
VCC0V9_LVR_OUT: length 0.9
  BOTTOM w0.203: UT1.F18 22.16,103.99 21.87,104.29 v2(21.87,104.3) ; v2(22.52,104.3) 22.83,103.99 UT1.H18
  vias: v1(22.15,104.97) v2(23.16,106.91) v2(23.81,106.93)
VCC0V9_SVR:
  vias: v1(21.17,106.99) v2(19.66,112.9) v2(20.24,113.05) v2(20.23,112.46) v2(21.87,106.92) v2(21.87,106.27) v2(21.87,105.62) v2(23.82,107.57) v2(24.47,107.57)
VCC1V8A_TBTA_LDO: length 2
  BOTTOM w0.203: CT151.1 17.49,127.25 17.74,127.25 18.38,126.61 UT4.K1
VCC1V8D_TBTA_LDO: length 2
  BOTTOM w0.14: 18.88,121.4 18.88,120.45 CT152.1
  BOTTOM w0.152: UT4.A2 18.88,121.4
VCC3V3_FLASH: length 20.8
  TOP w0.127: v1(46.33,95.99) RT171.1
  TOP w0.356: 18.7,128.61 17.52,128.61 17.18,128.28 RT432.1
  TOP w0.508: RT243.1 40.7,97.66 41.06,97.3 42.85,97.3 43.69,96.46 UT5.8 44.44,95.99 RT171.1 45.26,96.64 44.77,97.13 v2(44.77,97.48) ; 22.01,128.06 21.79,128.28 21.79,128.62 21.32,129.09 RT1093.1 19.17,129.09 18.7,128.61 18.91,128.4 18.91,127.46 18.43,126.98 RT226.1 18.43,125.66 CT146.1 17.58,125.44 v2(17.55,125.42)
  BOTTOM w0.254: v2(17.55,125.42) 17.59,125.42 17.79,125.21 18.23,125.21 UT4.G1 ; RT168.1 19.61,119.55 19.94,119.22 v2(20.22,119.22) 20.22,119.5 20.24,119.53 RT169.1
  vias: v2(26.91,125.59)
VCC3V3_TBT_SX: length 1.4
  TOP w0.152: v2(19.43,126.03) 19.6,126.2 CT145.1
  BOTTOM w0.152: UT4.H2 18.97,125.57 v2(19.43,126.03)
VCC_3V3_PCIE: length 2.1
  TOP w0.089: v1(22.42,103.71) 22.73,103.71 CT99.1
  TOP w0.254: v2(23.82,104.32) 23.74,104.23 CT99.1
  BOTTOM w0.254: UT1.L16 v2(23.82,104.32)
VCC_3V3_USB2: length 1.1
  TOP w0.254: v2(23.82,104.97) 23.71,104.86 CT100.1
  BOTTOM w0.254: UT1.J16 v2(23.82,104.97)
VCC_SENSE: length 2
  TOP w0.14: PR1124.1 118.8,171.09 v2(118.92,171.21)
  BOTTOM w0.254: v2(138.48,163.69) 137.76,162.97 RH198.2
VCC_SENSE_R: length 26
  BOTTOM w0.254: RH197.2 137.5,162.07 RH198.1 137.49,161.67 138.14,161.02 148.21,161.02 152.25,156.98 155.46,156.98 v1(156.39,156.05) 157.09,155.35 157.09,153.29 UH1.AG37
VCCDSW_EN: length 4
  TOP w0.076: UE3.M7 301.01,82.35 302.06,82.35
  TOP w0.14: 302.06,82.35 303.42,82.35 303.86,82.78 RH5869.2
VCCDSW_EN_GPIO: length 54.5
  TOP w0.14: v2(305.01,83.21) 304.83,83.39 RH5869.1 ; v2(271.33,71.36) 271.33,70.31 270.76,69.73 265.59,69.73 265.34,69.98 265.34,70.59 263.88,72.06 262.64,72.06 261.95,71.37 255.87,71.37 254.51,70.01 250.75,70.01 250.42,70.34 250.42,71.99 248.72,73.69 248.72,76.47 248.02,77.17 DI16.2 246.2,77.81 244.49,79.52 239.06,79.52 v1(238.94,79.65) 238.81,79.77 v2(238.81,80.66) ; RH5867.1 133.97,81.82 QE20.2 136.63,81.82 138.46,83.65 140.96,83.65 141.4,83.2 141.4,81.87 v2(141.53,81.74)
VCCDSW_EN_Q: length 3.2
  TOP w0.14: v1(243.48,74.82) 243.61,74.95 RH5870.2 244.32,75.19 244.5,75.37 DI15.2 DI16.1
VCCGT_SENSE: length 6.1
  TOP w0.14: v2(135.04,164.08) 134.67,164.45 v1(134.67,164.58)
  BOTTOM w0.14: v2(103.56,171.85) PR1130.2
  BOTTOM w0.254: RH203.2 RH471.2 131.8,163 132.26,163.46 134.06,163.46 134.57,163.98 134.94,163.98 v2(135.04,164.08)
VCCGT_SENSE_R: length 28.5
  BOTTOM w0.254: UH1.AH38 155.92,154.41 154.62,155.7 v1(152.29,155.7) 151.19,155.7 147.53,159.36 133.72,159.36 131.98,161.1 131.98,161.74 RH471.1
VCCIO_EN: length 1.3
  TOP w0.14: v1(103.61,116.99) 104,117.38 RZ1965.2
VCCIO_SENSE: length 29.7
  TOP w0.254: v2(127.96,132.12) 127.95,132.1 127.29,132.1 126.71,132.68 v4(125.27,132.68) 123.26,132.68 120.29,129.71 114.19,129.71 112.77,131.13 109.71,131.13 108.69,130.12 106.12,130.12 PR838.2
  TOP w0.305: v2(168.52,138.44) 168.52,137.79 169.61,136.7 170.62,136.7 170.92,136.39 170.92,135.59 v2(170.89,135.55)
  BOTTOM w0.254: UH1.H14 171.24,135.91 v2(170.89,135.55)
VCCMPHY_SENSE: length 8.1
  BOTTOM w0.089: 72.82,89.76 73,89.76 73.33,89.43 74.09,89.43 74.17,89.35 UH2.K47
  BOTTOM w0.14: 72.82,89.76 72.39,89.76 72.36,89.78 69.1,89.78 68.59,90.29 68.49,90.29 T4943.1
VCCSA_SENSE: length 8.4
  TOP w0.254: PR1110.1 118.29,168.98 119.76,168.98 120.47,168.27 122.71,168.27 123.01,168.57 123.01,168.93 122.76,169.18 122.22,169.18 v2(122.1,169.06)
  BOTTOM w0.14: RH202.2 122.22,168.93 v2(122.1,169.06) 121.97,169.06 v1(121.56,168.65)
VCCSA_SENSE_R: length 6.2
  BOTTOM w0.14: v1(125.07,167.85) RH201.1 124.51,168.93 v2(124.38,169.06) 124.26,168.93 RH202.1
  BOTTOM w0.254: UH1.M38 168.52,153.93 167.61,154.83 166.61,154.83 165.96,154.18 v2(165.96,154.14)
  vias: v2(165.95,159.8)
VCCSENSE_VGA: length 2.2
  BOTTOM w0.152: v2(171.27,182.69) v1(171.86,182.69)
  BOTTOM w0.203: UV18.L4 211.55,127.69 v2(211.95,128.09)
  BOTTOM w0.254: v2(171.27,182.69) 170.83,183.14 PR1021.1
  vias: v2(167.44,159.79) v2(175.44,159.78)
VCCST_PWRGD: length 29.2
  TOP w0.14: RE306.2 v2(308.81,91.3) ; v2(301.07,100) 309.04,100 311.09,97.96 311.09,97.62 310.41,96.94 310.41,96.06 v2(310.21,95.85)
  BOTTOM w0.14: RZ1957.1 119.53,125.16 121.08,126.72 v1(121.08,128.16) 121.08,129.96 126.27,135.15 v2(128.2,135.15)
  vias: v2(181.08,130.7)
VCCST_PWRGD_CPU: length 2.8
  TOP w0.089: v4(170.95,134.45) 171.34,134.83 171.62,134.83 v2(171.64,134.82)
  TOP w0.14: RH154.2 178.28,128.53 178.73,128.08 v2(179.11,128.08)
  BOTTOM w0.076: v2(171.64,134.82) 171.27,135.18 UH1.H13
VCCSTG_EN: length 52.5
  TOP w0.14: v2(107.8,116.11) 107.58,116.32 UZ26.4 107.58,117.13 107.18,117.54 106.09,117.54 105.02,116.46 RZ1965.1 RZ1153.1 ; v2(116.26,123.59) 116.26,126.89 118.03,128.67 123.24,128.67 v1(124.89,130.32) 125.91,131.34 v2(128.5,131.34) ; RZ72.1 189.03,110.56 189.03,112.41 188.14,113.3 186.87,113.3 184,116.17 184,118.56 184.52,119.08 185.18,119.08 187.63,121.53 187.63,125.8 185.4,128.03 183.69,128.03 182.23,129.49 182.23,130.6 v2(182.12,130.71)
VCCSTG_EN_R: length 15
  TOP w0.14: RZ1153.2 104.7,114.35 103.83,113.48 103.83,110.93 105.48,109.28 111.09,109.28 111.19,109.18 v1(111.19,108.79) 110.26,107.87 v2(110.26,107.49)
  BOTTOM w0.14: UZ9.4 180.12,152.11 180.01,152.22 179.97,152.22 v2(179.95,152.24)
  vias: v2(187.25,130.29)
VDD33STB: length 3.5
  TOP w0.14: v2(5.38,101.16) 5.47,101.16 v1(5.91,101.59)
  TOP w0.381: RA101.2 6.36,99.97 5.86,100.47 RA100.2 5.38,100.7 v2(5.38,101.16)
  BOTTOM w0.203: v2(5.38,101.16) 5.4,101.18 UA1.10
VDD_1.2V: length 5.9
  TOP w0.14: v2(287.57,94.75) 287.23,95.09 v4(286.89,95.09)
  TOP w0.254: PR603.2 287.28,94.46 v2(287.57,94.75)
  BOTTOM w0.203: PU600.11 286.83,94.94 287.07,94.7 287.07,94.24 286.75,93.92 PR601.1 287.71,93.68 PC610.1
  BOTTOM w0.254: v2(287.57,94.75) 287.9,94.42 PC610.1
VDD_ISL88738: length 7.8
  TOP w0.14: v2(52.18,88.14) 52.32,88.29 52.32,89.01 51.95,89.38 v1(51.38,89.38)
  TOP w0.203: PU1900.18 49.47,80.8 49.79,81.13 v2(50.02,81.13) 50.43,81.13 50.85,81.55 PR1912.1 PC1928.1
  TOP w0.254: PR1911.2 52.62,87.71 v2(52.18,88.14) ; PR1908.2 39.04,77.74 38.84,77.94 v2(38.84,78.88)
VDDP_ISL88738: length 6.5
  TOP w0.203: PU1900.8 44.29,80.4 44.05,80.17 44.05,79.76 43.76,79.46 v1(42.89,79.46) 41.17,77.74 PR1908.1
  TOP w0.254: PR1908.1 PC1927.2
VDDQ_DDR: length 16.2
  BOTTOM w0.203: UH1.L6 169.42,130.18 169.62,130.37 170.07,130.37 UH1.K6
  BOTTOM w0.254: UH1.AR12 150.24,134.09 v2(149.87,133.72) 149.5,134.09 UH1.AT12 ; v2(170.81,133.78) 170.5,134.09 UH1.K12 170.24,134.22 169.65,134.22 UH1.L12 ; UH1.Y12 162.38,134.09 v2(162.67,133.8) ; v2(157.24,129.84) 157.56,129.53 UH1.AF5 ; v2(157.24,129.84) 156.93,129.53 UH1.AG5 ; v2(157.24,129.84) 157.35,129.84 UH1.AF6 ; v2(164.79,129.85) 165.11,130.18 UH1.T6 UH1.R6 ; UH1.AG9 156.75,132.14 v2(157.19,132.57) ; v2(158.08,134.34) 158.33,134.09 UH1.AE12 ; UH1.W6 162.65,130.18 v2(162.26,129.79) 161.88,130.18 UH1.AA6 ; UH1.AL11 154.08,133.44 v2(154.46,133.82) 154.73,134.09 UH1.AJ12 ; UH1.AP7 151.24,130.44 UH1.AP6 UH1.AR6 ; UH1.J5 171.14,129.53 v2(171.48,129.87) 171.16,130.18 UH1.J6 UH1.K6
  BOTTOM w0.305: UH1.AW6 147.53,130.18 v2(147.19,129.84) 146.85,130.18 UH1.AY6 ; UH1.AR6 149.78,129.82 v2(149.7,129.82)
  vias: v4(157.09,118.42)
VDDS_SENSE_VGA: length 3.1
  BOTTOM w0.254: PR1520.1 205.28,123.08 206.52,124.32 206.52,125.27 UV18.U1
VSS_SENSE: length 3.3
  TOP w0.14: PR1126.1 118.85,171.98 v2(118.92,172.05) ; v1(136.61,163.92) 136.84,163.69 v2(137.75,163.69)
  BOTTOM w0.254: v2(137.75,163.69) 137.65,163.59 137.21,163.59 136.71,163.09 RH465.2
VSS_SENSE_R: length 25.4
  BOTTOM w0.254: RH466.1 136.68,162.11 RH465.1 136.71,161.9 137.98,160.63 148.06,160.63 152.09,156.6 154.74,156.6 v1(154.77,156.56) 155.28,156.56 156.71,155.14 UH1.AG38
VSSGT_SENSE: length 6.3
  TOP w0.14: v2(103.56,171.09) 103.56,170.48 v4(102.91,169.83)
  BOTTOM w0.14: PR1132.2 102.92,172.03 102.92,171.72 v2(103.56,171.09)
  BOTTOM w0.254: RH204.2 RH472.1 133.6,163.08 134.21,163.08 134.73,163.59 134.94,163.59 v2(135.04,163.49)
VSSGT_SENSE_R: length 29.3
  BOTTOM w0.254: UH1.AH37 156.31,153.3 156.31,154.55 154.76,156.11 v1(153.52,156.11) 151.33,156.11 147.69,159.75 133.91,159.75 132.37,161.28 132.37,161.71 RH204.1
VSSIO_SENSE: length 27.4
  TOP w0.254: v2(170.05,135.95) 169.56,135.95 v1(169.53,135.97) 167.82,137.69 v2(167.82,138.74) ; PR841.2 106.12,129.76 108.84,129.76 109.86,130.78 112.62,130.78 114.04,129.36 120.49,129.36 123.28,132.15 v2(126.47,132.15)
  BOTTOM w0.254: UH1.J14 170.57,135.95 v2(170.05,135.95)
VSSMPHY_SENSE: length 8.2
  BOTTOM w0.089: UH2.K46 74.82,89.26 74.67,89.11 74.15,89.11 74.02,89.25 72.86,89.25 72.82,89.29
  BOTTOM w0.14: T4944.1 67.42,90.05 68.49,90.05 69.03,89.51 72.06,89.51 72.29,89.29 72.82,89.29
VSSSA_SENSE: length 9.6
  TOP w0.254: v2(122.1,169.82) 122.35,169.56 122.88,169.56 123.37,169.07 123.37,168.42 122.86,167.91 120.32,167.91 119.61,168.62 118.29,168.62 PR1108.1
  BOTTOM w0.14: v1(121.56,170.3) 122.05,169.82 v2(122.1,169.82) RH470.2
VSSSA_SENSE_R: length 5.3
  BOTTOM w0.14: RH470.1 v2(124.38,169.82) RH469.1 v1(125.07,170.85)
  BOTTOM w0.254: UH1.M37 168.12,153.3 168.12,153.79 167.47,154.44 167.01,154.44 v2(166.64,154.07)
  vias: v2(166.54,159.78)
VSSSENSE_VGA: length 1.4
  BOTTOM w0.254: UV18.L5 211.5,128.48 v2(211.1,128.07) ; v2(170.71,184.6) 170.71,184.14 PR1018.1
  vias: v2(168.26,159.78) v2(176.07,159.78)
1.8V_PRIM_PWRGD/SHD_IO2: length 1.7
  TOP w0.076: v2(300.37,82.47) 299.96,82.06 UE3.L7
  TOP w0.14: v2(306.25,84.52) 306.41,84.36 307.07,84.36 RT1139.2
3D VISION/STEREO: length 6.1
  BOTTOM w0.14: T4977.1 209.72,122.24 209.72,123.14 209.27,123.59 209.27,124.28 209.63,124.64 209.63,125.56 209.42,125.77 209.42,126.49 209.02,126.89 UV18.P3
3S_BATT+:
  vias: v1(27.55,89.32)
32KHZ_OUT: length 2.7
  TOP w0.14: v2(295.37,73.05) 295.36,73.05 294.92,72.61 v1(294.92,72.48) 294.92,72.08 295.27,71.72 295.33,71.72 CE1501.2 ; v2(295.52,78.44) UE3.F3
81215_ALERT: length 2.7
  TOP w0.203: PU1100.41 108.41,172.29
  TOP w0.254: PR1118.1 v2(108,171.67) 108,171.87 108.41,172.29
  BOTTOM w0.14: v2(108,171.67) v1(108,172.45)
81215_SCLK: length 2.9
  TOP w0.203: PU1100.42 108.81,172.18 108.59,171.95 v2(108.59,171.67) 108.59,171.34 PR1116.1
  BOTTOM w0.14: v2(108.59,171.67) 108.59,170.99 v1(108.46,170.86)
81215_SDIO: length 2.9
  TOP w0.203: PU1100.40 108.01,172.56
  TOP w0.254: PR1120.1 v2(107.11,171.66) 108.01,172.56
  BOTTOM w0.14: v2(107.11,171.66) v1(107.11,170.93)
81215_VR_HOT: length 4.9
  TOP w0.14: PR1113.1 106.11,171.04 v1(104.79,169.72)
  TOP w0.203: PU1100.39 107.37,173.49
  TOP w0.254: 107.37,173.49 107.37,172.79 106.22,171.65 PR1113.1
+1.8ALWP: length 3.4
  TOP w0.14: v1(244.36,166.57) 244.7,166.23 v2(244.7,165.88)
  BOTTOM w0.381: PC1606.1 PR1603.1 246.56,167.09 PC1608.1
+AC_IN: length 0.9
  TOP w0.254: v2(27.16,73.83) 26.61,73.83 PR234.1
  vias: v1(22.36,90.89) v2(20.58,93.44) v2(20.57,92.8) v2(21.18,94.63) v2(21.18,94.04) v2(21.18,93.44) v2(21.19,92.79)
+CHG_SRC_20V: length 1
  TOP w0.14: v4(49.12,73.53) 49.12,73.23 48.62,72.73
  vias: v2(47.13,69.94) v2(47.13,69.29) v2(47.12,68.71) v2(47.42,72.66) v2(47.42,72.03) v2(47.42,71.39) v2(47.42,70.76) v2(47.75,69.95) v2(47.75,69.3) v2(47.74,68.72) v2(49.3,69.4) v2(49.3,68.76)
+DC_IN: length 6
  TOP w0.127: v4(24.8,146.11) 24.43,145.74 v2(24.37,145.74)
  TOP w0.508: v2(33.78,68.62) v4(33.78,69.61) 33,70.4 PR211.1 ; v2(60.83,87.52) 61.35,88.03 v4(62.41,88.03) PD203.2
  vias: v2(10.18,97.13) v2(10.46,96.61) v2(10.43,95.77) v2(10.78,97.16) v2(10.87,96.17) v2(11.15,97.65) v2(11.41,96.53) v2(11.4,95.83) v2(11.42,97.12) v2(11.76,97.61) v2(12.01,97.08) v2(11.99,95.85) v2(12.06,96.49) v2(23.36,149.28) v2(23.36,148.65) v2(23.33,147.96) v2(23.36,147.24) v2(23.36,146.59) v2(23.86,148.19) v2(23.88,147.5) v2(23.85,146.88) v2(23.83,146.26) v2(24.36,148.51) v2(24.37,147.86) v2(24.4,147.14) v2(24.38,146.49) v2(44.89,91.13)
+DC_IN_SS: length 4.8
  TOP w0.127: v2(9.25,93.01) 8.55,93.01 8.12,92.58 4.75,92.58 v4(4.67,92.66)
  vias: v2(9.68,93.44) v2(10.88,92.05) v2(11.46,92.09)
+DCPRTC: length 3.1
  TOP w0.254: CH3331.1 73.06,69.94 v1(73.53,70.41) 73.53,70.59 v2(73.25,70.88)
  BOTTOM w0.127: v2(73.25,70.88) 73.66,70.88 UH2.BG47
  BOTTOM w0.254: UH2.BG47 74.05,71.3 74.3,71.55 UH2.BF47
+EC_DEBUG_VCC: length 3.9
  TOP w0.14: v4(312.34,97.2) 312.03,97.51 v2(311.65,97.51)
  TOP w0.381: RE60.2 310.95,96.95 311.51,97.51 v2(311.65,97.51)
  BOTTOM w0.305: JDEG1.1 310.78,98.38 v2(311.65,97.51)
+EDPVDD: length 1.6
  TOP w0.14: v4(49.83,93.49) 49.83,94.95 CV157.1
  vias: v2(55.53,101.03) v2(56.11,101.03) v4(50.85,97.68) v4(55.92,99.66)
+FB_PLLAVDD: length 6.4
  TOP w0.102: v1(215.24,138.68) 214.93,138.99 v2(214.5,138.99)
  TOP w0.381: CV923.1 212.54,145.75 213.02,145.75 v2(213.28,146.01)
  TOP w0.508: CV921.1 206.7,147.37 v2(206.88,147.37) ; CV922.1 214.45,139.04 v2(214.5,138.99)
  BOTTOM w0.254: UV18.H17 v2(214.5,138.99) ; v2(206.88,147.37) 206.88,147.37 UV18.U27
  BOTTOM w0.305: UV18.K27 212.24,146.88 212.24,146.45 212.68,146.01 v2(213.28,146.01)
  vias: v2(189.4,151.07) v2(189.37,150.41)
+FBA_VREFC0: length 30.9
  TOP w0.381: CV926.1 201.96,172.66 v2(201.63,172.33)
  TOP w0.406: v2(223.01,178.01) 223.01,176.91 222.55,176.45 CV927.1 221.47,176.45 RV625.1
  TOP w0.508: RV624.2 222.29,175.04 222.02,175.3 RV623.2 221.46,176.15 RV625.1
  BOTTOM w0.406: UV24.J14 201.85,171.83 201.85,172 201.63,172.23 v2(201.63,172.33) ; UV23.J14 235.86,171.09 236.65,171.09 237.1,171.53 237.1,177.44 235.27,179.27 227.74,179.27 227.16,179.85 224.86,179.85 v1(224.58,179.58) 224.58,179.08 223.51,178.01 v2(223.01,178.01)
+FBA_VREFC0_R: length 3.8
  TOP w0.508: RV624.1 220.62,174.65 v1(220.36,174.4) 219.9,173.93 QV101.1
+FBC_VREFC1: length 7.3
  TOP w0.14: v1(243.9,164.91) RV634.2
  TOP w0.406: v2(244.82,160.97) RV636.1 244.81,161.65 CV989.1 243.91,162.59 RV635.2 243.91,163.53 RV634.2
  TOP w0.508: CV988.1 239.74,157.74 v2(240.09,158.09)
  BOTTOM w0.254: UV26.J14 240.09,158.02 v2(240.09,158.09) ; UV25.J14 v2(240.28,123.3)
+FBC_VREFC1_R: length 3.9
  TOP w0.14: RV635.1 243.29,161.68 242.86,162.11 v1(242.86,162.37)
  TOP w0.508: RV635.1 243.91,161.03 243.07,160.19 QV102.1
+GPCPLL_AVDD: length 1.3
  TOP w0.508: RV574.1 211.21,147.49 v2(211.14,147.41)
  BOTTOM w0.381: v2(213.66,146.58) 214.1,146.14 UV18.H26
  vias: v1(214.57,146.79)
+GPU_CORE: length 7.9
  TOP w0.254: 178.66,177.81 178.43,178.04 177,178.04 PR1023.1
  TOP w0.457: v2(171.98,185.01) 171.98,185.22 171.68,185.53 170.4,185.53 169.71,186.21 RV1810.1
  vias: v2(174.8,178.55) v2(178.45,173.55) v2(178.45,172.95) v2(178.45,172.34) v2(178.45,171.75) v2(178.45,171.14) v2(178.42,170.55) v2(178.44,169.96) v2(178.44,169.37) v2(178.43,168.78) v2(178.44,168.18) v2(178.43,167.58) v2(178.44,166.99) v2(178.44,166.38) v2(178.43,165.77) v2(178.44,165.17) v2(178.45,164.58) v2(178.45,163.99) v2(179.23,163.33) v2(179.23,162.71) v2(179.24,162.1) v2(179.24,161.5) v2(179.5,160.91) v2(179.8,173.44) v2(179.81,172.81) v2(179.81,172.21) v2(179.79,171.61) v2(179.81,171.02) v2(179.8,170.42) v2(179.8,169.8) v2(179.82,165.04) v2(179.84,164.43) v2(179.84,163.85) v2(179.84,163.26) v2(179.85,162.68) v2(179.85,162.09) v2(179.84,161.5) v2(180.03,169.26) v2(180.16,160.93) v2(180.39,169.8) v2(180.43,173.44) v2(180.45,172.81) v2(180.44,172.21) v2(180.42,171.61) v2(180.44,171) v2(180.43,170.41) v2(180.43,165.04) v2(180.43,164.43) v2(180.43,163.85) v2(180.43,163.26) v2(180.45,162.67) v2(180.44,162.08) v2(180.44,161.48) v2(180.65,169.26) v2(181,169.83) v2(181.01,164.43) v2(181.01,163.85) v2(181.01,163.26) v2(181.06,173.44) v2(181.05,172.81) v2(181.08,172.21) v2(181.06,171.61) v2(181.07,171) v2(181.06,170.42) v2(181.04,165.04) v2(181.04,162.68) v2(181.07,162.08) v2(181.07,161.48) v2(181.24,169.29) v2(181.59,169.83) v2(181.52,168.77) v2(181.52,168.15) v2(181.52,167.56) v2(181.52,166.98) v2(181.52,166.39) v2(181.54,165.8) v2(181.6,164.43) v2(181.6,163.85) v2(181.6,163.26) v2(181.66,173.45) v2(181.64,172.82) v2(181.66,172.23) v2(181.65,171.63) v2(181.66,171.02) v2(181.65,170.42) v2(181.62,165.04) v2(181.66,162.64) v2(181.68,162.06) v2(181.87,169.27) v2(182.24,173.47) v2(182.23,172.88) v2(182.25,172.29) v2(182.26,171.7) v2(182.3,163.71) v2(182.3,163.13) v2(182.89,163.71) v2(182.89,163.12) v2(183.54,163.75) v2(183.56,163.17) v2(184.17,163.74) v2(184.19,163.15) v2(197.8,147.41) v2(198.79,139.13) v2(198.89,138.51) v2(200.16,144.12) v2(200.25,142.91) v2(200.22,133.1) v2(200.37,141.99) v2(200.59,131.86) v2(201.1,140.02) v2(201.04,133.93) v2(201.05,133.12) v2(201.12,144.13) v2(201.15,138.04) v2(202.11,135.2) v2(202.54,145.08) v2(203.39,132.34) v2(203.61,130.58) v2(203.61,129.77) v2(203.61,128.9) v2(203.62,127.25) v2(204.21,140.1) v2(204.13,137.9) v2(204.11,137) v2(204.33,124.84) v2(204.46,127.27) v2(204.67,125.53) v2(205.03,137.81) v2(205.09,134.93) v2(205.1,133.96) v2(205.08,133.18) v2(205.17,128.99) v2(205.28,131.51) v2(205.26,130.57) v2(205.21,129.6) v2(206.11,143.97) v2(206.1,143.01) v2(206.1,134.85) v2(206.11,133.2) v2(206.13,137.01) v2(207.11,145.02) v2(207.11,137.01) v2(207.11,136.24) v2(207.05,133.98) v2(207.12,140.1) v2(208.05,144.86) v2(208.03,137.05) v2(208.25,139.97) v2(209.09,144.86) v2(209.08,139.97) v2(209.07,137.76) v2(209.12,136.07) v2(209.49,132.9) v2(209.96,135.97) v2(210.07,144.87) v2(210.03,142.97) v2(210.03,137.95) v2(210.16,139.87) v2(211,133.96) v2(211.12,144.99) v2(211.12,144.1) v2(211.23,137.92) v2(211.33,139.98) v2(211.94,145.03) v2(211.94,135.98) v2(212.08,141.99) v2(212.08,141) v2(212.08,140.01) v2(212.84,137.65) v2(212.85,136.28) v2(213.07,142) v2(213.08,139.39) v2(213.12,143.08) v4(181.03,174.52)
+GPU_CORE_VDDS: length 16.5
  TOP w0.508: RV1808.1 v2(222.35,185.08) ; PC1502.1 202.82,134.34 v2(203.23,133.93)
  BOTTOM w0.203: 204.02,134.39 204.02,134.35 203.6,133.93 v2(203.23,133.93)
  BOTTOM w0.254: UV18.P23 209.6,144.48 v2(209.16,144.04) ; v2(206.11,139) 205.62,139.49 UV18.V18 ; v2(204.2,142.96) 204.6,142.56 UV18.W21 ; UV18.AA23 202.6,144.43 v2(203.12,143.91) ; 204.02,134.39 204.14,134.51 204.14,135.03 UV18.W14 ; v2(202.23,140.92) 202.6,140.56 UV18.AA19 ; v2(201.21,141.97) 201.21,142.06 200.77,142.49 UV18.AC21
  BOTTOM w0.305: UV18.AC14 200.8,135.49 v2(201.16,135.84) ; v2(203.23,133.93) 203.17,133.93 202.73,133.49 UV18.AA12 ; UV18.M21 211.3,142.19 v2(211.3,141.98) ; v2(208.07,142.96) UV18.T21 ; v2(209.89,137.03) 209.6,137.33 UV18.P16 ; UV18.P19 209.6,140.66 v2(209.93,140.99) ; UV18.U17 206.6,138.51 v2(206.11,139) ; v2(202.17,137.06) UV18.AA16 ; v2(209,133.96) 209.47,133.49 UV18.P12 ; UV18.M14 v2(211.13,135.96) ; UV18.T14 v2(208.12,134.97)
  BOTTOM w0.508: v2(182.73,186.54) 182.9,186.71 PR1521.1
  vias: v2(188.11,161.85) v2(188.11,161.26) v2(188.12,163.08) v2(188.12,162.48) v2(188.66,164.67) v2(188.67,164.07) v2(190.41,164.74) v2(190.41,164.15) v2(190.42,166.55) v2(190.42,165.44) v2(190.72,167.06) v2(190.84,165.99) v2(190.98,167.59) v2(191.01,164.14) v2(191.02,169.46) v2(191.02,168.82) v2(191.02,168.19) v2(191.06,166.55) v2(191.05,165.44) v2(191.04,164.73) v2(191.42,167.07) v2(191.48,165.99) v2(191.69,166.55) v2(191.69,165.44) v2(191.67,164.73) v2(191.62,164.15) v2(192.05,167.1) v2(192.11,165.99) v2(192.31,167.64) v2(192.38,170.92) v2(192.4,168.51) v2(192.32,166.58) v2(192.43,169.61) v2(192.68,167.1) v2(192.7,166.13) v2(192.75,168.04) v2(193.03,169.61) v2(193.62,169.61) v2(194.22,169.61) v2(194.87,169.61) v2(195.5,169.64) v2(199.83,165.05) v2(207.95,176.33) v4(194.68,167.59)
+INV_PWR_SRC:
  vias: v2(46.57,101.75) v2(47.18,101.75) v4(44.92,103.26) v4(46.41,102.35) v4(48.03,102.96)
+NVVDDS_B+: length 1.3
  BOTTOM w0.508: PR1514.1 180.46,184.29 v2(179.86,183.69)
  vias: v1(198.23,175.41) v2(196.65,174.53) v2(196.65,173.91) v2(196.65,173.32) v2(196.65,172.74) v2(198.26,174.69) v2(198.26,174.1) v2(198.26,173.52) v2(198.26,172.93)
+ODR_PWR: length 3.3
  TOP w0.127: v4(324.43,119.98) 325.06,119.36 325.06,118.08
  BOTTOM w0.203: UR1.12 335.2,104.08
  BOTTOM w0.305: 335.2,104.08 334.98,104.08 v2(334.67,103.78)
  vias: v2(325.07,117.09) v2(334.04,103.98)
+PECI_VREF: length 1.1
  TOP w0.14: v1(299.89,91.03) 300,91.03 v2(300.31,91.34)
  TOP w0.305: UE3.J11 v2(298.72,85.66)
+PEX_PLL_HVDD: length 1.2
  TOP w0.14: v1(198.06,133.52) 198.06,133.58 v2(197.7,133.94)
  BOTTOM w0.381: v2(197.7,133.94) 197.3,134.34 UV18.AH12
+PEX_PLL_VDD: length 2.3
  TOP w0.14: T4994.1 199.44,145.18 v2(199.42,145.2)
  BOTTOM w0.254: UV18.AG26 198.53,146.09 v2(199.42,145.2)
+PEX_SVDD_3V3: length 1.2
  TOP w0.381: T4993.1 198.01,135.17 v2(197.66,134.83)
  BOTTOM w0.381: UV18.AG12 198.1,134.39 v2(197.66,134.83)
+PWR_SRC_AC:
  vias: v4(56.78,74.81)
+RTC_CELL_VBAT: length 23
  TOP w0.254: v2(292.32,78.46) UE3.A2
  TOP w0.381: RE50.1 287.83,72.39 288.66,73.22 289.3,73.22 289.85,72.67 v2(289.85,72.41)
  BOTTOM w0.508: v2(289.85,72.41) 289.38,72.88 289.38,74.8 v2(289.97,75.38) 289.6,75.75 289.6,78.8 288.75,79.65 288.06,79.65 287.7,79.29 285.6,79.29 283.49,81.4 283.49,82.62 283.06,83.05 281.43,83.05 v2(280.81,82.43)
  vias: v1(280.57,81.36)
+RTCBATT: length 32.6
  TOP w0.508: v2(329.11,154.27) 327.97,155.41 v4(327.97,157.57) 327.97,158.51 326.82,159.66 326.82,168.42 327.51,169.11 JRTC.1 ; RH67.2 276.3,74.78 278.22,76.7 278.22,78.3 277.88,78.64 277.88,80.49 277.7,80.66 277.7,84.35 v2(279.45,86.1)
+RTCVCC: length 30.3
  TOP w0.356: v2(67.21,72.06) 67.37,71.9 68.3,71.9 RH83.1
  TOP w0.381: RH531.2 73.57,74.68 72.52,74.68 71.55,73.72 71.55,73.29 72.14,72.71 72.14,72.31 v2(71.87,72.04) 71.53,71.7 CH70.1 72.15,70.71 72.15,69.19 71.98,69.03 CH80.1 72.05,68.7 72.19,68.56 RH84.1
  TOP w0.508: R276.1 169.21,73 QRTC.1 168.38,73.55 168,73.17 C3.1 167.44,74.72 167.21,74.94 167.21,76.04 167.6,76.42 167.6,79.39 v1(166.18,80.8) 164.49,82.49 v2(164.49,85.08)
  BOTTOM w0.254: UH2.BC49 UH2.BD49 73.04,72.48 72.74,72.48 72.3,72.04 v2(71.87,72.04)
  vias: v2(59.59,79.39)
+RTCVCC_R: length 31
  TOP w0.381: v2(179.1,69.93) 179.3,70.13 179.3,74.41 178.82,74.9 176.68,74.9 175.95,75.63 173.81,75.63 172.69,74.52 QRTC.3
  TOP w0.508: v2(12.08,99.78) v1(10.93,99.78) 9.46,99.78 8.82,100.42 7.96,100.42 RA101.1 ; v2(276.29,69.98) 276.29,70.37 277.19,71.27 ; RE16.1 279.27,80.94 278.49,80.16 278.49,78.94 278.89,78.53 278.89,76.3 277.22,74.62 RH67.1
  vias: v2(18.26,68.43)
+SD_VDD2: length 1.2
  BOTTOM w0.203: UR1.13 334.61,104.48 v2(334.49,104.6)
  vias: v1(348.21,110.95) v2(347.48,115.08) v2(347.48,114.49) v2(347.74,111.14) v2(347.86,110.57)
+SDC_IN: length 5.4
  TOP w0.381: v2(53.64,77.64) 53.64,77.18 53.33,76.87 50.79,76.87 50.52,76.6 PR1903.1
  BOTTOM w0.254: PR1904.1 53.18,79.32 v2(53.63,78.86)
  vias: v2(9.39,85.53) v2(9.5,86.15) v2(9.88,86.68) v2(9.97,85.53) v2(10.11,86.12) v2(10.36,87.04) v2(10.57,85.54) v2(10.64,86.45) v2(10.97,85.97) v2(15.08,87.34) v2(15.07,86.75) v2(15.06,86.14) v2(15.47,87.79) v2(15.96,88.14) v2(53.63,78.25) v2(56.16,78.83) v2(56.17,78.22) v2(56.16,77.61) v2(56.15,77.01) v2(56.75,78.82) v2(56.76,78.21) v2(56.76,77.6) v2(57.35,78.22) v2(57.34,77.61) v4(57.33,78.82)
+SP_PLLVDD: length 0.5
  BOTTOM w0.254: v2(200.26,131.31) 200.26,131.31 200.17,131.31 UV18.AE8
  vias: v1(200.03,130.65)
+TBTA_VBUS_1: length 10.2
  TOP w0.254: v2(29.19,80.38) 29.19,80.01 28.51,79.33 28.51,74.41 27.39,73.28 26.15,73.28 25.44,73.99 PR249.1
  vias: v1(25.82,96.55) v2(22.48,92.53) v2(24.23,95.94) v2(24.82,95.94) v2(25.4,95.94) v2(25.43,95.36) v2(25.43,94.72) v2(25.43,94.09) v2(25.43,93.45) v2(25.98,95.94) v2(26.01,95.36) v2(26.01,94.72) v2(26.01,94.09) v2(26.03,93.45)
+V_DDR_REF: length 3
  BOTTOM w0.127: PC609.1 286.99,99.84 v2(287.2,99.64)
  BOTTOM w0.203: PC609.1 286.5,99.4 286.5,98.89 286.43,98.82 PU600.4
+V_DDR_REFA: length 2.7
  TOP w0.127: v2(124.83,85.01) 124.83,84.79 v4(125.13,84.49)
  TOP w0.508: v2(147.96,85.06) 147.95,85.07 CD18.1
  BOTTOM w0.305: JDIMM1.164 147.89,85.13 v2(147.96,85.06)
+V_DDR_REFA_R: length 3.3
  TOP w0.127: v2(137.49,135.39) 137.26,135.16 v4(136.9,135.16)
  TOP w0.508: v2(122.62,88.36) 122.64,88.33 CH101.1 RH484.1
+V_DDR_REFB: length 6.6
  TOP w0.254: CD29.1 224.75,85.74 224.26,85.25 v2(224.26,85.05)
  TOP w0.508: v2(232.72,85.04) 232.69,85.07 232.69,85.08 232.66,85.12 232.66,85.21 v4(232.32,85.55) 232.07,85.8 RH210.1 RH207.2 RH485.2
  BOTTOM w0.305: JDIMM2.164 224.19,85.14 224.26,85.06 v2(224.26,85.05)
+V_DDR_REFB_R: length 2.7
  TOP w0.508: v2(228.42,89.08) 229.07,88.43 CH100.1 RH485.1
  vias: v2(136.19,134.59)
+VDISPLAY_VCC: length 1.6
  TOP w0.254: v2(26.34,141.37) RM2.2 RM1.2
  vias: v1(13.47,157.12) v2(11.86,157.69) v2(11.87,157.09)
+VGA_B+: length 1.1
  BOTTOM w0.508: PR1014.1 170.81,186.02 v2(171.11,186.31)
  vias: v1(163.45,173.83) v2(164.34,169.79) v2(164.39,168.8) v2(164.39,168.17) v2(164.48,175.69) v2(164.48,175.11) v2(164.48,174.52) v2(164.48,173.94) v2(164.48,173.36) v2(164.48,172.77) v2(164.48,172.19) v2(164.48,171.6) v2(164.48,171.02) v2(164.69,170.35) v2(165.11,175.69) v2(165.11,175.11) v2(165.11,174.52) v2(165.11,173.94) v2(165.11,173.36) v2(165.51,172.89) v2(165.66,173.73) v2(165.99,173.25) v2(167.06,170.32) v2(168.11,170.31) v2(178.04,179.02)
+VID_PLLVDD: length 4.6
  TOP w0.14: RV582.1 v1(197.03,127.45)
  TOP w0.508: v2(199.81,129.58) 199.81,129.44 199.53,129.16 199.53,128.62 CV854.1 ; RV582.1 196.42,128.52 v2(196.03,128.14)
  BOTTOM w0.305: v2(199.81,129.58) 200.09,129.58 UV18.AD7
+VLDOIN_1.2V: length 1.5
  BOTTOM w0.127: 282.23,98.05 v1(282.23,99.55)
+VR_CAP: length 6.3
  TOP w0.254: CE40.1 302.22,74.38 301.66,74.94 299.65,74.94 299.1,75.49 299.1,75.94 v2(298.69,76.35) 298.69,76.89 UE3.J1 ; UE3.C10 v2(293.12,84.86)
  vias: v2(288.93,78.49)
+XS_PLLVDD: length 1
  BOTTOM w0.305: v2(201.2,131.83) 201.2,131.49 UV18.AD8
  vias: v1(202.91,129.67)
A_DE0: length 1.5
  TOP w0.14: RI19.1 324.01,102.48 UI3.16
A_DE1: length 2.7
  TOP w0.14: v1(324.03,104.98) RI20.1 323.51,104.03 322.96,103.48 UI3.18
A_EQ0: length 1.6
  TOP w0.14: UI3.17 323.08,102.98 323.36,103.27 RI15.1
A_EQ1: length 1.6
  TOP w0.14: RI16.1 323.79,101.98 UI3.15
AC1_DISC#: length 10.6
  TOP w0.14: v2(21.2,87.84) 19.8,87.84 19.66,87.98 PR243.2 ; v2(57.38,85.78) v1(56.82,85.78) ; PR1937.1 60.97,75.54 v2(60.22,76.29)
  BOTTOM w0.14: v2(57.38,85.78) 57.21,85.95 55.9,85.95 55.14,85.2 53.3,85.2 52.84,85.66 PR278.1 ; v2(26.86,126.21) 26.34,125.68 RT5844.2
  vias: v2(33.9,110.43)
AC_DIS: length 3.8
  TOP w0.14: PR1920.1 55.18,90.26 PQ1906.2 55.46,89.53 v2(55.96,89.53) 56.45,89.05 v1(56.77,89.05) ; v2(297.92,86.46) UE3.H12
  vias: v2(137.93,78.89)
AC_DISC#: length 21.3
  TOP w0.14: v1(20.98,88.56) 20.71,88.29 v2(20.09,88.29) ; PR218.2 12.29,92.98 11.89,92.58 11.89,91.69 11.7,91.5 11.11,91.5 10.85,91.24 v2(10.73,91.24) ; UE3.E13 295.12,87.87 v2(294.49,88.5)
  BOTTOM w0.14: v2(59.48,80.21) 59.48,80.59 59.75,80.87 PC219.1 59.25,80.92 58.22,80.92 57.99,80.69 57.99,80.13 57.75,79.88 PQ221.6 57.45,79.88 56.97,80.36 56.97,80.68 56.73,80.92 56.73,81.31 56.54,81.5 55.9,81.5 PQ221.3 55.4,81.37 55.4,81.7 56.11,82.42 56.69,82.42 56.9,82.21 57.4,82.21 57.64,81.98 59.28,81.98 59.42,82.12 PR270.1 PR272.1 58.02,82.43 57.81,82.64 PQ220.3
AC_PRESENT: length 4
  TOP w0.089: v1(75.84,69.98) 76.09,69.73 v2(76.09,69.49) 76.52,69.07 RH533.1
  TOP w0.14: UE3.K8 v3(298.72,83.26)
  BOTTOM w0.089: UH2.BG42 76.72,71.17 76.21,70.66 76.21,69.61 v2(76.09,69.49)
ACAV_IN: length 3
  TOP w0.14: v2(63.17,82.89) 62.98,83.08 PR1940.2 62.34,83.06 PR1942.1 ; v2(293.12,81.66) UE3.C7 ; v2(144.9,78.99) 144.9,79.3 v1(145.26,79.66)
ACAV_IN1: length 11.7
  TOP w0.254: PR1921.1 52.64,85.67 53.53,86.56 PR1911.1 54.09,87.46 PQ1906.1 ; v2(63.3,80.24) 63.3,79.98 62.31,78.99 PR1941.1 ; PQ1906.1 53.79,88.65 PR1918.1 ; PQ1906.1 55.37,88.74 56.38,88.74 56.53,88.59 v1(57.99,88.59) 58.06,88.59 v2(58.39,88.26)
ACIN_ISL88738: length 5.4
  TOP w0.203: PU1900.19 49.35,81.2 49.86,81.72 v2(50.01,81.72)
  BOTTOM w0.254: v2(50.01,81.72) 50.3,81.72 v1(50.52,81.5) 50.52,80.74 51.03,80.23 PC1925.1 PR1906.1 PR1904.2
ACOK_ISL88738: length 4.3
  TOP w0.203: PU1900.24 49.11,83.2 50,84.09 50,84.64 v1(50.79,85.43) 50.85,85.49 PR1921.2
ADP_ISL88738: length 3.3
  TOP w0.203: PU1900.16 48.08,79.22 48.15,79.15 v1(48.15,78.36) 48.15,77.17 48.5,76.81 PR1903.2
ALL_GPWRGD: length 10.3
  TOP w0.14: RV590.2 194.01,114.37 193.4,113.76 v1(193.4,113.04) 193.4,112.9 193.88,112.41 195.71,112.41 196.31,113.02 UV20.4 196.84,112.5 197.35,111.99 197.35,110.46 RV1132.2
ALW_PWRGD_3V_5V: length 4.2
  TOP w0.14: v2(343.2,92.22) 343.2,92.72 v1(343.26,92.77) ; v2(71.54,87.87) 71.44,87.87 PR271.1 69.92,89.4 PR295.2
  TOP w0.254: PR407.1 342.89,91.9 v2(343.2,92.22)
  vias: v2(317.69,90.86)
ALWON: length 39.6
  TOP w0.076: v2(291.39,80.46) 291.39,80.46 UE3.A5
  TOP w0.14: PR326.1 v1(344.73,96.67) 344.73,97.49 342.48,99.74 339.83,99.74 337.06,102.51 334.53,102.51 333.72,103.31 331.26,103.31 330.02,102.07 328.41,102.07 327.92,101.58 327.92,99.25 326.64,97.98 324.9,97.98 v2(323.73,96.82) ; v2(291.39,80.46) 290.96,80.46 290.39,79.89 289.57,79.89 RH5884.2 ; v2(243.64,78.68) 243.4,78.43 RZ1951.1 245.01,78.02 245.35,77.68 245.35,76.22 245.67,75.9 DI15.1
  vias: v2(310.47,93)
AUD_AZA_CPU_SCLK: length 7.5
  BOTTOM w0.076: UH1.G27 172.28,146.55 v2(172.28,147.36)
  BOTTOM w0.14: v2(106.05,82.55) 106.05,81.95 104.78,80.68 104.78,80.63 104.11,79.96 104.11,78.42 103.48,77.79 RH147.1
AUD_AZA_CPU_SCLK_R: length 8.7
  BOTTOM w0.089: 99.75,77.44 99.25,77.44 98.71,77.99 97.59,77.99 97.4,77.8 97.02,77.8 96.7,78.12 96.38,78.12 96.07,78.43 96.07,78.43 96.01,78.49 UH2.AM3
  BOTTOM w0.14: 99.75,77.44 100.35,77.44 100.48,77.58 101.83,77.58 102.04,77.79 RH147.2 102.51,77.93 v1(103.34,78.76)
AUD_AZA_CPU_SDI: length 8.7
  BOTTOM w0.14: UH1.G29 171.95,147.78 172.26,148.09 177.15,148.09 177.2,148.04 177.27,148.04 177.91,147.41 RH145.1 178.42,146.74 177.76,146.08 v1(177.76,145.9)
AUD_AZA_CPU_SDI_R: length 2
  BOTTOM w0.089: v2(96.58,77.7) 96.46,77.7 96.13,78.03 UH2.AN3
  BOTTOM w0.14: RH145.2 179.3,146.53 179.3,145.93 v2(179.28,145.92)
  vias: v2(177.68,88.26)
AUD_AZA_CPU_SDO: length 2.9
  BOTTOM w0.076: v2(172.27,144.24) 171.94,144.56 UH1.G25
  BOTTOM w0.14: RH146.1 100.23,77.97 100.83,77.97 101.41,78.55 v1(101.54,78.55) 101.62,78.47 v2(101.62,78)
  vias: v2(178.26,88.26)
AUD_AZA_CPU_SDO_R: length 3.7
  BOTTOM w0.089: UH2.AM2 96.33,78.44 96.46,78.31 96.78,78.31 97.12,77.97 97.32,77.97 97.51,78.16 98.78,78.16 99.13,77.82 RH146.2
AUD_PWR_EN: length 13.6
  TOP w0.089: v2(96.72,73.63) 96.72,73.7 RH568.1 96.04,74.47 RH569.1
  TOP w0.14: UA4.3 6.85,72.35 6.65,72.15 6.65,71.71 6.84,71.52 7.31,71.52 7.62,71.21 8.11,71.21 8.15,71.25 ; 8.15,71.25 8.25,71.35 8.25,71.87 7.65,72.46 UA4.5 ; 8.15,71.25 v2(8.18,71.22) ; v2(2.28,77.34) 1.76,77.86 JAUDIO.2
  BOTTOM w0.089: UH2.BD8 93.6,72.78 93.84,73.03 95.41,73.03 95.58,73.19 95.58,73.53 95.61,73.6 95.73,73.73 96.63,73.73 v2(96.72,73.63)
  BOTTOM w0.14: v2(2.28,77.34) 2.6,77.67 UA3.3
  vias: v2(62.98,71.73)
AUDIO_AMP_SMBCLK: length 3.8
  TOP w0.076: UE3.D7 294.29,82.06 v2(293.88,81.65)
  TOP w0.14: v2(284.52,77.45) 284.73,77.23 v1(284.73,76.92) RE95.1 284.4,75.57 284.4,74.82 284.52,74.71 QE18.3
AUDIO_AMP_SMBDAT: length 6.9
  TOP w0.076: UE3.E7 295.07,82.06 v2(294.69,81.68)
  TOP w0.14: v2(280.81,78.31) v1(280.81,76.92) 281.14,76.58 281.14,76.23 281.19,76.18 281.19,74.02 RE94.1 282.26,73.47 282.32,73.41 QE18.6
AUX_EN_WOWL: length 4.2
  TOP w0.14: v2(293.92,78.46) UE3.D3
  BOTTOM w0.14: RZ1142.1 334.33,112.98 DN3.3 v2(334.33,111.06) 335.23,110.15 v1(335.39,110.15)
  vias: v2(326.82,102.63)
B+: length 112.7
  TOP w0.254: PD1902.2 57.55,79.55 57.84,79.27 57.84,77.27 57.57,77.01 57.44,77.01 v2(57.35,76.91) ; PR1922.2 42.02,82.12 41.33,81.43 v2(40.94,81.43)
  BOTTOM w1.016: 250.62,87.14 249.99,86.51 249.99,84.92 248.95,83.88 184.56,83.88 183.99,83.31 178.85,83.31 175.65,80.12 147.49,80.12 147.32,79.95
  vias: v2(8.2,80.51) v2(8.2,79.93) v2(31.63,93.18) v2(31.8,89.35) v2(32.11,89.86) v2(32.21,93.18) v2(32.39,89.28) v2(32.69,89.83) v2(32.79,93.18) v2(33.02,89.27) v2(33.3,89.81) v2(33.38,93.18) v2(33.6,89.27) v2(33.87,92.31) v2(33.88,91.73) v2(33.87,91.13) v2(33.88,90.53) v2(33.88,89.93) v2(33.98,93.16) v2(34.19,89.3) v2(34.54,92.53) v2(34.57,91.89) v2(34.57,91.31) v2(34.57,90.72) v2(34.58,90.06) v2(34.79,89.3) v2(35.13,92.15) v2(35.16,91.54) v2(35.17,90.95) v2(35.18,90.36) v2(35.18,89.76) v2(41.29,100.26) v2(41.72,99.83) v2(95.3,113.68) v2(95.94,114.06) v2(96.26,114.65) v2(96.68,115.13) v2(96.7,113.94) v2(96.95,114.55) v2(97.45,115.17) v2(97.89,114.62) v2(98.3,115.25) v2(98.83,115.71) v2(99.33,116.21) v2(99.77,116.65) v2(99.87,115.97) v2(100,117.37) v2(101.78,135.2) v2(101.78,134.61) v2(101.78,134.03) v2(101.78,133.44) v2(101.78,132.86) v2(101.78,132.28) v2(102.36,133.44) v2(102.36,132.86) v2(102.36,132.28) v2(102.95,133.44) v2(102.95,132.86) v2(102.95,132.28) v2(111.83,162.83) v2(112.4,162.83) v2(112.97,162.83) v2(122.28,171.6) v2(122.86,172.18) v2(122.86,171.6) v2(123.44,172.76) v2(123.44,172.18) v2(123.44,171.6) v2(124.03,172.76) v2(124.03,172.18) v2(124.03,171.6) v2(124.61,172.76) v2(124.61,172.18) v2(124.61,171.6) v2(125.2,172.76) v2(125.2,172.18) v2(125.2,171.6) v2(125.78,172.76) v2(125.78,172.18) v2(125.78,171.6) v2(126.37,172.76) v2(126.37,172.18) v2(126.37,171.6) v2(126.95,172.76) v2(126.95,172.18) v2(126.95,171.6) v2(127.53,172.76) v2(127.53,172.18) v2(127.53,171.6) v2(128.12,172.18) v2(128.12,171.6) v2(128.7,171.6) v2(160.01,175.34) v2(160.01,174.76) v2(159.99,174.19) v2(160.58,176.9) v2(160.58,176.29) v2(160.58,175.68) v2(160.58,175.07) v2(160.58,174.47) v2(160.58,173.88) v2(161.19,176.9) v2(161.19,176.29) v2(161.19,175.68) v2(161.19,175.07) v2(161.19,174.47) v2(161.19,173.88) v2(161.19,173.3) v2(195.63,178.39) v2(195.64,177.82) v2(196.2,178.39) v2(196.21,177.82) v2(196.77,178.39) v2(196.79,177.82) v2(197.35,178.39) v2(197.36,177.82) v2(197.92,178.39) v2(197.94,177.82) v2(246.75,180.84) v2(246.74,180.17) v2(246.72,179.55) v2(246.74,178.91) v2(247.21,180.5) v2(247.23,181.17) v2(247.22,179.84) v2(247.22,179.24) v2(251.25,88.87) v2(251.25,88.25) v2(276.85,93.36) v2(277.48,93.36) v2(277.68,99.82) v2(277.74,99.22) v2(278.36,99.83) v2(278.35,99.19) v2(278.95,99.79) v2(278.95,99.15) v2(279.56,99.81) v2(279.56,99.11) v2(280.19,99.75) v2(280.82,99.73) v2(314.02,81.7) v2(314.69,84.41) v2(314.69,83.84) v2(314.69,83.27) v2(314.69,82.7) v2(314.69,82.12) v2(314.69,81.55) v2(315.24,85.01) v2(315.26,84.41) v2(315.26,83.84) v2(315.26,83.27) v2(315.26,82.7) v2(315.26,82.12) v2(315.26,81.55) v2(315.89,85.04) v2(315.89,84.47) v4(32.21,91.53)
B++: length 13.5
  TOP w0.508: PR415.2 337.43,89.58 337.67,89.82 v2(338.91,89.82)
  BOTTOM w0.508: v2(328.6,86.89) 329.55,86.89 331.19,88.53 337.62,88.53 337.75,88.65 v2(338.91,89.82)
  vias: v4(318.3,85.93)
B+_1.8VSP:
  vias: v1(241.21,175.82) v2(244.83,176.02) v2(244.89,175.27) v2(245.56,176.04) v2(245.55,175.34)
B+_1V:
  vias: v1(134.1,76.95) v2(134.43,76.5) v2(135.01,76.5) v2(135.6,76.5)
B+_1VSP:
  vias: v1(242.37,184.87)
B_DE0: length 1.6
  TOP w0.14: RI21.1 317.23,103.02 317.76,102.48 UI3.3
B_DE1: length 2.4
  TOP w0.14: v1(317.04,99.84) RI22.1 317.3,100.98 UI3.6
B_EQ0: length 1.7
  TOP w0.14: RI17.1 317.17,103.78 317.96,102.98 UI3.2
B_EQ1: length 1.5
  TOP w0.14: RI18.1 317.31,101.98 UI3.4
BAT1_LED#: length 16.7
  TOP w0.14: v2(166.88,77.26) v4(166.88,77.82) ; v2(293.92,84.86) UE3.D10
  BOTTOM w0.14: v2(166.88,77.26) 166.88,77.05 164.63,74.8 164.63,73.93 163.47,72.78 160.08,72.78 156.56,76.3 JKB.10
BAT2_LED#: length 15.1
  TOP w0.14: v2(294.72,85.67) 294.32,85.28 UE3.D11 ; v4(166.04,76.28) 165.79,76.54 v2(165.79,76.85)
  BOTTOM w0.14: v2(165.79,76.85) 165.79,76.29 164.39,74.9 164.39,74.03 163.37,73.02 160.18,73.02 157.06,76.14 JKB.9
BAT_LED#_LV1: length 5.8
  TOP w0.14: RL5.2 344.28,172.48 345.05,173.25 v1(345.05,174.64) 345.69,175.28 LED1.1
BAT_LED#_LV1_D: length 3.9
  TOP w0.14: Q4.1 339.27,171.15 340.31,172.19 v1(340.79,172.19) 341.08,172.48 RL5.1
BAT_LED#_LV2: length 3.9
  TOP w0.14: RL4.2 v1(344.98,171.6) 346.68,171.6 LED2.1
BAT_LED#_LV2_D: length 15.1
  TOP w0.14: v2(340.33,156.39) 340.25,156.39 339.81,155.95 339.81,155.35 340.23,154.93 340.23,154.28 341.05,153.46 343.03,153.46 QH5.3 ; v2(341.44,163.34) 341.34,163.44 v1(341.34,165.08) 341.34,167.7 341.05,167.99 341.05,170.56 341.99,171.5 RL4.1
BAT_LED#_LV3: length 4.9
  TOP w0.14: LED3.1 v1(344.91,169.94) 344.27,170.58 RL3.2
BAT_LED#_LV3_D: length 21.1
  TOP w0.14: RL3.1 341.29,169.89 341.29,168.09 342.02,167.36 v1(342.02,166.59) v2(342.02,163.38) ; v3(334.41,154.19) 335.01,153.59 335.01,152.26 336.73,150.55 343.61,150.55 343.83,150.77 344.63,150.77 344.78,150.92 QH5.6
BAT_LED#_LV4: length 7.5
  TOP w0.14: LED4.1 345.49,165.76 v1(345.49,167.28) 345.49,168.29 344.22,169.56 RL2.2
BAT_LED#_LV4_D: length 26.5
  TOP w0.14: v2(343.37,163.36) 342.56,164.17 v1(342.56,164.2) 342.56,167.16 341.53,168.19 341.53,169.11 RL2.1 ; QH3.3 347.29,150.28 347.07,150.05 345.06,150.05 345.01,150.01 334.83,150.01 333.21,151.63 333.21,152.43 332.66,152.97 330.71,152.97 v2(330.46,152.72)
BAT_LED#_LV5: length 9.8
  TOP w0.14: RL1.2 343.79,168.55 344.81,167.53 v1(344.81,164.04) 344.81,162.84 LED5.1
BAT_LED#_LV5_D: length 20.7
  TOP w0.14: v2(334.4,157.05) 335.29,157.93 340.02,157.93 341.75,156.21 341.75,154.56 342.32,153.98 344.39,153.98 344.69,153.68 345.02,153.68 345.99,152.71 QH3.6 ; RL1.1 v1(343.24,167.3) 343.53,167 343.53,164.41 v2(343.93,164.02)
BATBTN#: length 15
  TOP w0.14: v2(290.72,79.62) 291.13,80.03 292.29,80.03 UE3.B5 ; RP19.4 283.72,79.51 v2(283.87,79.65) 284.85,78.67 v4(284.85,78.49) ; v2(344.09,179.85) 344.12,179.87 344.12,181.11 DL1.2 344.47,181.17 345.86,182.56 346.83,182.56 SW2.4 347.91,180.62 347.75,180.46 347.75,178.45 347.91,178.29 SW2.3
BATT++: length 2.5
  TOP w0.14: 24.47,83.88 24.47,83.98 v4(24.94,84.45) v4(26.7,84.45)
  vias: v2(19.84,72.97) v2(20.42,72.97) v2(21.06,72.97) v2(22.2,74.62) v2(22.2,74.03) v2(22.2,73.45) v2(22.2,72.87) v2(23.29,83.2) v2(23.29,82.62) v2(23.88,83.2) v2(23.88,82.62) v2(24.41,73.12) v2(24.41,72.51) v2(24.51,83.2) v2(24.51,82.62) v2(24.99,73.12) v2(24.99,72.51) v2(25.63,73.12) v2(25.63,72.51) v4(23.3,83.8)
BATT_LED#_LV1: length 6.9
  TOP w0.14: v2(339.78,172.48) 339.01,172.48 v1(338.7,172.17) 338.38,171.85 338.38,170.15 Q4.3 ; v2(295.58,87.27) 295.58,86.4 UE3.F12
BATT_LED#_LV2: length 11.5
  TOP w0.14: v2(338.1,155.84) 338.1,155.04 337.49,154.43 337.49,153.99 337.25,153.75 337.25,153.13 339.55,150.83 342.11,150.83 v1(342.32,151.03) 342.75,151.03 342.95,150.83 343.34,150.83 343.48,150.97 QH5.4 ; UE3.G10 297.14,84.88 v2(297.14,84.9)
BATT_LED#_LV3: length 6.9
  TOP w0.14: QH5.1 344.78,153.18 344.25,153.71 341.4,153.71 340.51,154.59 340.51,154.99 340.24,155.27 v2(340.24,155.77) ; v2(293.12,80.86) UE3.C6
BATT_LED#_LV4: length 24.5
  TOP w0.076: UE3.J12 298.32,86.07 298.73,86.48 298.73,87.52
  TOP w0.14: v2(298.58,87.84) 298.63,87.84 298.73,87.74 298.73,87.52 ; v2(330.16,154.65) 333.69,158.18 340.12,158.18 341.99,156.31 341.99,154.74 342.48,154.25 344.47,154.25 344.79,153.93 345.12,153.93 345.41,153.63 347.09,153.63 347.29,153.42 QH3.4
BATT_LED#_LV5: length 17.5
  TOP w0.14: QH3.1 345.39,150.85 344.91,150.36 v1(344.46,150.36) 343.78,150.36 343.7,150.28 335.53,150.28 333.67,152.14 333.67,152.86 332.3,154.23 v2(331.4,154.23) ; v2(300.89,87.36) 300.89,87.03 UE3.M13
BBS_BIT6: length 1.9
  TOP w0.089: v2(83.6,74.21) 83.59,74.21 83,74.81 RH130.2
  BOTTOM w0.089: v2(83.6,74.21) 83.62,74.21 83.89,74.48 UH2.BA26
BC_CLK_ECE1117: length 14.2
  TOP w0.076: UE3.D13 294.14,86.86 293.61,87.39 v2(293.24,87.39)
  BOTTOM w0.14: v2(162.32,73.63) 163.33,73.63 163.44,73.73 163.44,74.15 163.33,74.25 162.61,74.25 162.47,74.39 162.47,74.74 162.55,74.82 163.33,74.82 163.49,74.99 163.49,75.26 CE81.1 162.66,76.09 162.41,76.09 161.44,75.13 158.56,75.13 157.6,76.08 157.6,77.02 157.56,77.06 JKB.8
BC_DAT_ECE1117: length 16.4
  TOP w0.076: 293.95,87.52 294.26,87.21 294.41,87.21 294.63,86.99 294.63,86.37 UE3.D12
  TOP w0.14: 293.95,87.52 293.49,87.98 v2(293.24,87.98) ; v2(283.9,78.01) RP19.1
  BOTTOM w0.14: JKB.7 158.06,77.08 158,77.02 158,76.24 158.72,75.52 161.28,75.52 162.25,76.48 162.67,76.48 CE82.1 162.92,76.81 163.56,77.46 164.67,77.46 164.95,77.19 164.95,76.01 163.92,74.99 v2(163.92,74.31)
BC_INT#_ECE1117: length 4.9
  TOP w0.14: UE3.E2 295.45,77.73 295.45,77.01 295.62,76.84 295.62,76.28 295.31,75.97 v2(295.18,75.97) ; v2(159.41,76.28) v4(159.41,76.94)
  BOTTOM w0.14: JKB.6 158.56,77.12 v2(159.41,76.28)
BEEP: length 2.1
  TOP w0.14: v2(1.27,95.7) 1.1,95.7 0.66,95.26 RA4.1 ; UE3.H11 297.55,85.26 v2(297.92,85.64)
  BOTTOM w0.14: v2(1.27,95.7) 0.95,95.7 v1(0.71,95.94)
  vias: v2(3.78,82.74) v2(62.92,77.99) v2(271.07,77.53)
BIA_PWM_EC: length 3.3
  TOP w0.14: UE3.N1 301.65,77.26 302.35,76.56 v1(303.25,76.56) 303.98,75.84 RE122.2
BIA_PWM_EC_R: length 3
  TOP w0.14: v2(306.37,76.09) 306.37,75.82 v1(306.17,75.62) 305.79,75.62 305.57,75.84 RE122.1
  BOTTOM w0.14: DV2.3 42.58,91.22 42.79,91.01 v2(43.1,91.01)
  vias: v2(137.91,74.36)
BIA_PWM_PCH: length 47.4
  TOP w0.127: 80.91,100.56 80.55,100.21 80.55,98.37 78.83,96.64 78.64,96.64 77.55,95.55 76.73,95.55 76.37,95.19 76.37,94.42 76.37,94.24 75.88,93.76 75.16,93.76 74.69,93.3 72.94,93.3 72.03,92.39 72.03,90.97 71.28,90.21 v2(70.74,90.21)
  TOP w0.14: v2(102.97,99.76) 102.97,99.55 101.46,98.03 83.71,98.03 82.28,99.46 82.28,99.86 81.58,100.56 80.91,100.56 ; v4(177.91,155.28) v2(178.56,155.28)
  BOTTOM w0.089: v2(72.52,77.25) 72.66,77.25 72.83,77.08 73.03,77.08 73.7,76.41 UH2.AU48
  BOTTOM w0.127: DV2.2 43.88,90.78 v2(45.01,89.65)
  BOTTOM w0.14: v2(178.56,155.28) 179.01,154.83 RH456.2
  vias: v2(129.71,157.34)
BID_BC: length 4.1
  TOP w0.14: v2(106.99,77.86) 106.99,77.79 v1(106.55,77.35) 105.42,76.22 RH566.2 RH567.1
  BOTTOM w0.089: UH2.AR18 88.4,77.44 v2(88.93,77.97)
BID_DIS: length 24.8
  TOP w0.089: RH565.1 75.1,78.57 RH564.2 75.11,78.87 v2(74.78,79.2)
  TOP w0.14: v2(303.58,72.15) 304.34,72.92 306.63,72.92 307.56,71.99 309.03,71.99 309.51,72.47 309.93,72.47 310.57,73.11 310.57,75.85 312.37,77.66 v1(312.37,78.71) 312.37,82.58 312.76,82.97 312.76,84.98 312.25,85.49 RE112.2
  BOTTOM w0.089: UH2.AL47 v2(74.78,79.2)
  vias: v2(115.11,77.68) v2(121.17,76.88)
BID_GPU: length 5.8
  BOTTOM w0.089: 90,68.6 RH5858.1 90,68.95 90.51,69.46 90.51,70.38 90.35,70.54 90.35,71.65 UH2.BF14
  BOTTOM w0.14: v1(91.61,68.15) 91.54,68.09 RH5857.2 90,68.6
BIOS_REC: length 2.5
  TOP w0.089: v1(76.15,78.63) 76.15,78.15 v2(76.17,78.12) 76.62,77.68 RH5840.1
  BOTTOM w0.089: UH2.AR42 76.51,77.84 76.22,78.12 v2(76.17,78.12)
BOARD_ID: length 3.4
  TOP w0.14: RE67.1 298.73,89.17 CE51.1 298.15,88.59 298.15,87.04 UE3.J13
BOOT1_ISL88738: length 5.6
  TOP w0.203: PR1905.2 43.1,77.37 43.57,77.84 v1(44.2,77.84) 44.45,77.59 45.09,77.59 46.48,78.98 PU1900.12
BOOT2_ISL88738:
  vias: v1(42.41,81.23)
BOOT_1.2V:
  vias: v1(283.35,96.82)
BREATH_LED#: length 4.1
  TOP w0.14: v2(331.34,185.88) 331.95,185.88 332.97,186.9 LED6.1 334.14,186.94 v1(334.28,186.81) ; UE3.C11 293.52,85.29 293.12,85.69 v2(293.12,85.68)
BST1_3V: length 1.4
  TOP w0.14: 338.76,91.27 338.76,92.11 v4(338.35,92.52)
BST1_5V: length 3
  TOP w0.14: PC411.1 342,84.38 342.93,83.46 344.12,83.46 v1(344.44,83.14)
BST1_NVVDD:
  vias: v1(163.23,180.51)
BST1_NVVDDS:
  vias: v1(188.37,180.27)
BST2_NVVDD: length 0.5
  TOP w0.14: v2(168.34,180.61) v1(168.34,180.09)
  vias: v2(167.93,181.06)
BST_1.8VSP: length 1.6
  BOTTOM w0.14: PR1600.1 240.74,170.93 239.88,171.8 v1(239.88,172.05)
BST_1V: length 1
  BOTTOM w0.14: v1(131.03,76.47) 130.95,76.4 PR501.1
BST_1V_R: length 1.7
  BOTTOM w0.14: PC502.1 128.45,76.51 128.08,76.88 v1(127.01,76.88)
BST_1VSP: length 0.6
  TOP w0.14: v2(238.18,183.94) v1(238.8,183.94)
  vias: v2(237.59,183.94)
BST_1VSP_R: length 1
  TOP w0.14: v1(235.67,183.98) 235.67,183.66 PC902.1
BST_3V: length 1.4
  TOP w0.14: PR411.2 341.43,92 v1(341.9,92.47)
BST_5V: length 1.4
  TOP w0.14: v1(339.41,83.06) 339.65,83.3 PR412.1
BT_RADIO_DIS#: length 30.2
  TOP w0.14: RE72.2 293.81,74.65 293.45,75.01 293.27,75.01 v2(293.13,75.15) 293.7,75.72 293.7,76.8 293.87,76.97 293.87,77.72 UE3.C2 ; v2(324.56,138.91) v1(324.56,138.34)
  BOTTOM w0.127: v2(293.13,75.15) 293.13,76.05 292.82,76.36 292.82,79.74 291.67,80.89 290.8,80.89 290.25,81.45 290.25,83.1 289.76,83.59 289.76,85.94 288.37,87.32 288.37,89.21 288.73,89.57 288.73,89.77 v2(288.72,89.78)
  BOTTOM w0.14: DN2.1 329.62,143.15 325.83,139.36 325.01,139.36 v2(324.56,138.91)
BT_RADIO_DIS#_R: length 4.3
  BOTTOM w0.14: v1(328.31,145.84) DN2.2 329.64,145.82 v2(330.56,145.82) ; v2(339.03,156.81) 339.57,157.35 JNGFF1.46
CAM_CBL_DET#: length 23.1
  BOTTOM w0.089: v2(91.07,76.19) 91.07,75.15 UH2.AW13
  BOTTOM w0.14: v2(61.74,89.4) 61.74,90.28 60.03,91.99 58.82,91.99 58.03,92.79 58.03,94.7 58.39,95.06 58.39,96.93 57.55,97.77 57.55,98.59 55.64,100.49 52.49,100.49 51.37,101.61 51.37,102.29 51.49,102.41 JEDP1.29 ; v2(70.52,87.62) 69.66,87.62 RH511.1
CD_WAKE#: length 5.2
  BOTTOM w0.14: v1(343.17,100.86) RR1.2 342.53,102.13 342.28,101.87 RR10.2 340.16,102.88 UR1.32
CEMSM#: length 1.4
  TOP w0.089: v2(147.12,135.13) 146.82,135.42 T4970.1
  BOTTOM w0.076: UH1.AW13 147.51,134.74 v2(147.12,135.13)
CERSVD1: length 1.2
  TOP w0.089: T4967.1 147.68,134.68 v2(148.06,135.05)
  BOTTOM w0.076: v2(148.06,135.05) 148.36,134.74 UH1.AU13
CERSVD2: length 1.1
  TOP w0.089: T4968.1 146.19,135.03 v2(146.21,135.05)
  BOTTOM w0.076: v2(146.21,135.05) 146.52,134.74 UH1.AY13
CEZVM#: length 1.2
  TOP w0.089: v2(148.97,135.12) 149.33,134.75 T4969.1
  BOTTOM w0.076: UH1.AT13 149.34,134.74 v2(148.97,135.12)
CFG0: length 12.8
  TOP w0.14: RH488.2 127.85,163.09 v2(127.56,163.09) ; RH183.1 130.18,144 136.8,144 v4(137.15,144.34) 137.49,144.69 v2(137.49,144.8) ; JXDP.9 124.58,154.7 123.72,155.56 v2(123.24,155.56)
  BOTTOM w0.076: v2(137.49,144.8) 137.17,144.47 UH1.BN25
CFG1: length 4
  TOP w0.089: v2(137.49,146.37) 137.59,146.37 v4(138.21,145.75)
  TOP w0.14: JXDP.11 127.87,155.2 v2(128.26,154.82)
  BOTTOM w0.076: v2(137.49,146.37) 137.17,146.05 UH1.BN27
CFG2: length 8.9
  TOP w0.14: JXDP.15 127.63,156.2 v2(127.68,156.15) ; v2(136.84,144.8) 136.45,144.4 v4(135.37,144.4) 135.23,144.26 130.77,144.26 RH184.1
  BOTTOM w0.076: v2(136.84,144.8) 137.17,145.12 UH1.BN26
CFG3: length 9.1
  TOP w0.089: v4(136.25,146.5) 136.37,146.37 v2(136.84,146.37)
  TOP w0.14: JXDP.17 127.97,156.7 128.83,155.85 128.83,154.58 129.41,154 129.41,153.38 129.04,153.01 v2(128.57,153.01)
  BOTTOM w0.076: v2(136.84,146.37) 137.17,146.7 UH1.BN28
  BOTTOM w0.14: RH474.2 128.85,152.74 v2(128.57,153.01)
CFG4: length 7.2
  TOP w0.089: 132.38,141.38 v2(132.54,141.23) 132.89,141.58 v1(132.89,141.74)
  TOP w0.14: JXDP.27 124.46,159.2 v2(124.4,159.26) ; 132.38,141.38 132.07,141.7 131.94,141.7 RH185.1
  BOTTOM w0.076: UH1.BR20 135.58,140.76 135.1,140.76 134.96,140.62 133.15,140.62 v2(132.54,141.23)
CFG5: length 7.2
  TOP w0.089: v4(138.98,139.5) 138.41,140.07 v2(138.14,140.07)
  TOP w0.14: v2(131.18,138.87) 130.83,138.52 128.81,138.52 RH186.1 ; JXDP.29 123.98,159.7 v2(123.55,159.26)
  BOTTOM w0.076: v2(138.14,140.07) 137.82,140.39 UH1.BM20
CFG6: length 9.4
  TOP w0.14: v4(128.44,141.06) RH187.1 130.16,140.75 130.8,140.75 v2(131.27,141.21) ; v2(124.36,160.15) 124.91,160.7 JXDP.33
  BOTTOM w0.14: UH1.BT20 135.04,140.29 132.19,140.29 v2(131.27,141.21)
CFG7: length 11.1
  TOP w0.14: v2(123.71,160.14) 124.18,160.61 124.32,160.61 124.91,161.2 JXDP.35 ; v2(133.77,141.24) 133.77,140.47 v4(133.74,140.44) 132.21,140.44 131.5,139.72 130.3,139.72 RH188.1
  BOTTOM w0.076: UH1.BP20 136.2,140.78 135.96,140.78 135.79,140.96 134.96,140.96 134.84,140.83 134.18,140.83 v2(133.77,141.24)
CFG8: length 5.3
  TOP w0.089: v2(133.17,142.83) 133.17,143.13 v1(132.99,143.31)
  TOP w0.14: JXDP.10 121.45,154.7 v2(121.79,155.05)
  BOTTOM w0.076: v2(133.17,142.83) 133.57,143.22 135.47,143.22 UH1.BR23
CFG9: length 6.7
  TOP w0.14: JXDP.12 121.21,155.2 121.64,155.63 v2(121.82,155.63) ; v1(131.57,143.24) 131.9,142.91 v2(131.9,142.83)
  BOTTOM w0.076: UH1.BR22 135.58,142.33 135.1,142.33 134.96,142.19 133.97,142.19 133.7,142.47 132.38,142.47
  BOTTOM w0.14: 132.38,142.47 132.26,142.47 v2(131.9,142.83)
CFG10: length 5.4
  TOP w0.089: v2(133.81,142.83) 134.42,142.22 v4(134.54,142.22)
  TOP w0.14: v2(122.61,155.54) 122.09,156.06 121.51,156.06 121.36,156.2 JXDP.16
  BOTTOM w0.076: v2(133.81,142.83) 134.2,142.43 134.82,142.43 UH1.BT23
CFG11: length 8.6
  TOP w0.14: v1(130.15,142.98) 130.41,143.24 130.97,143.24 131.27,142.94 v2(131.27,142.82) ; v2(122.86,156.07) 122.63,156.3 121.65,156.3 121.24,156.7 JXDP.18
  BOTTOM w0.076: 132.79,142.23 133.68,142.23 133.89,142.03 135.2,142.03 UH1.BT22
  BOTTOM w0.127: 131.68,142.4 v2(131.27,142.82)
  BOTTOM w0.14: 132.79,142.23 131.85,142.23 131.68,142.4
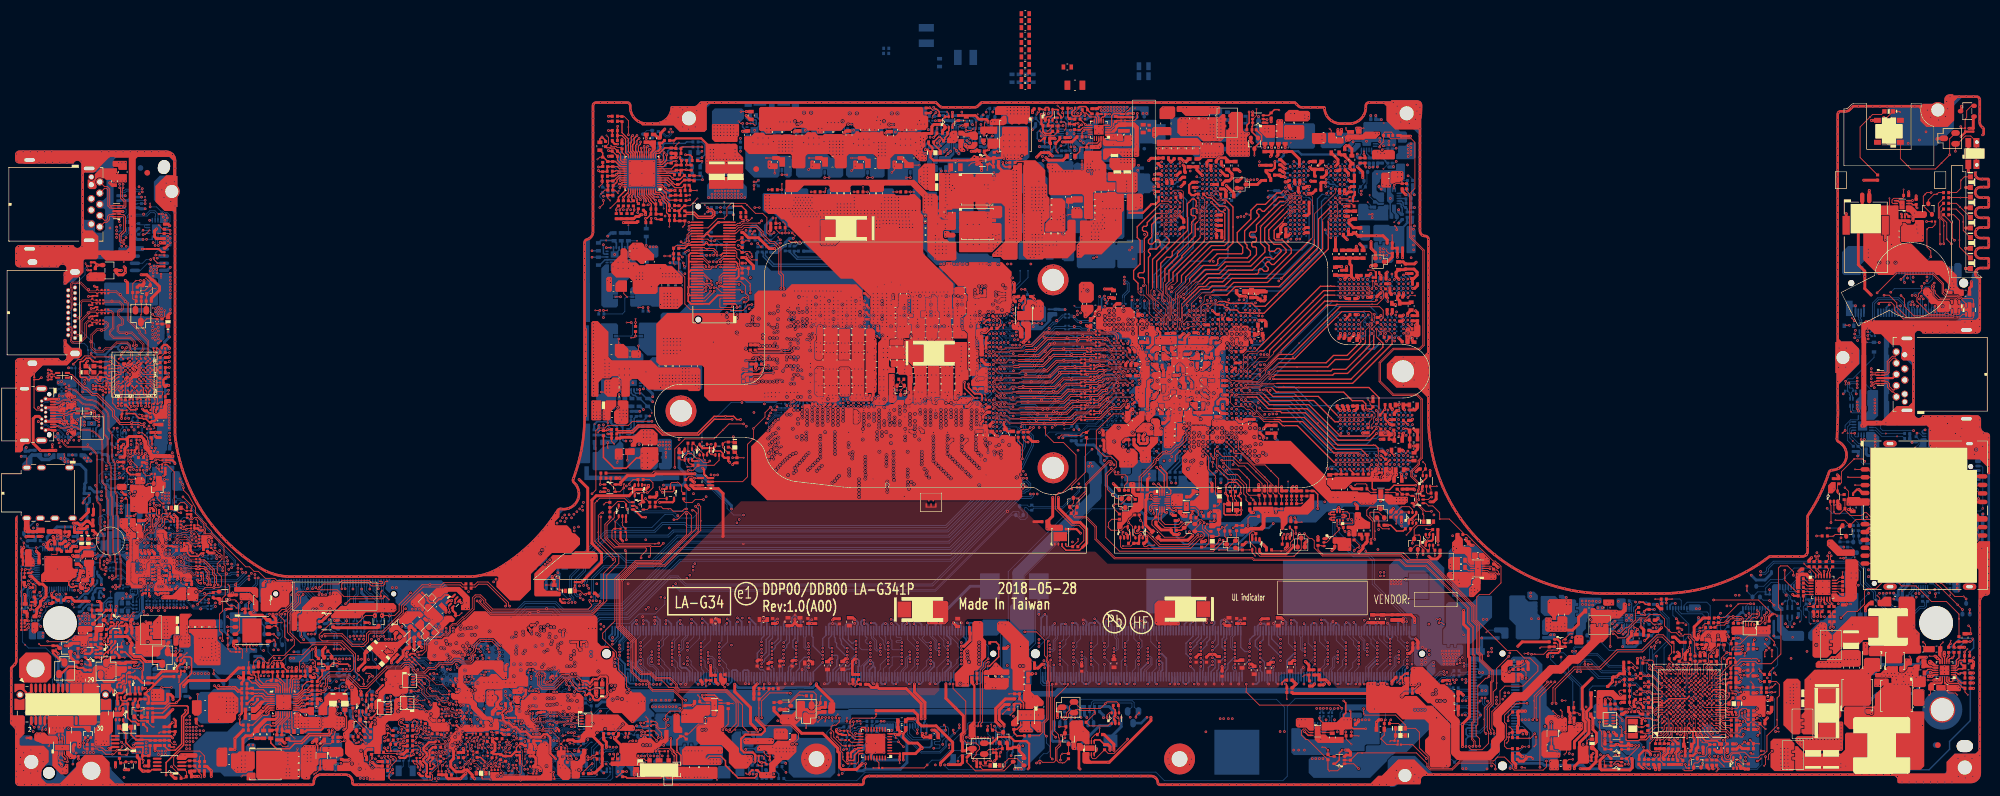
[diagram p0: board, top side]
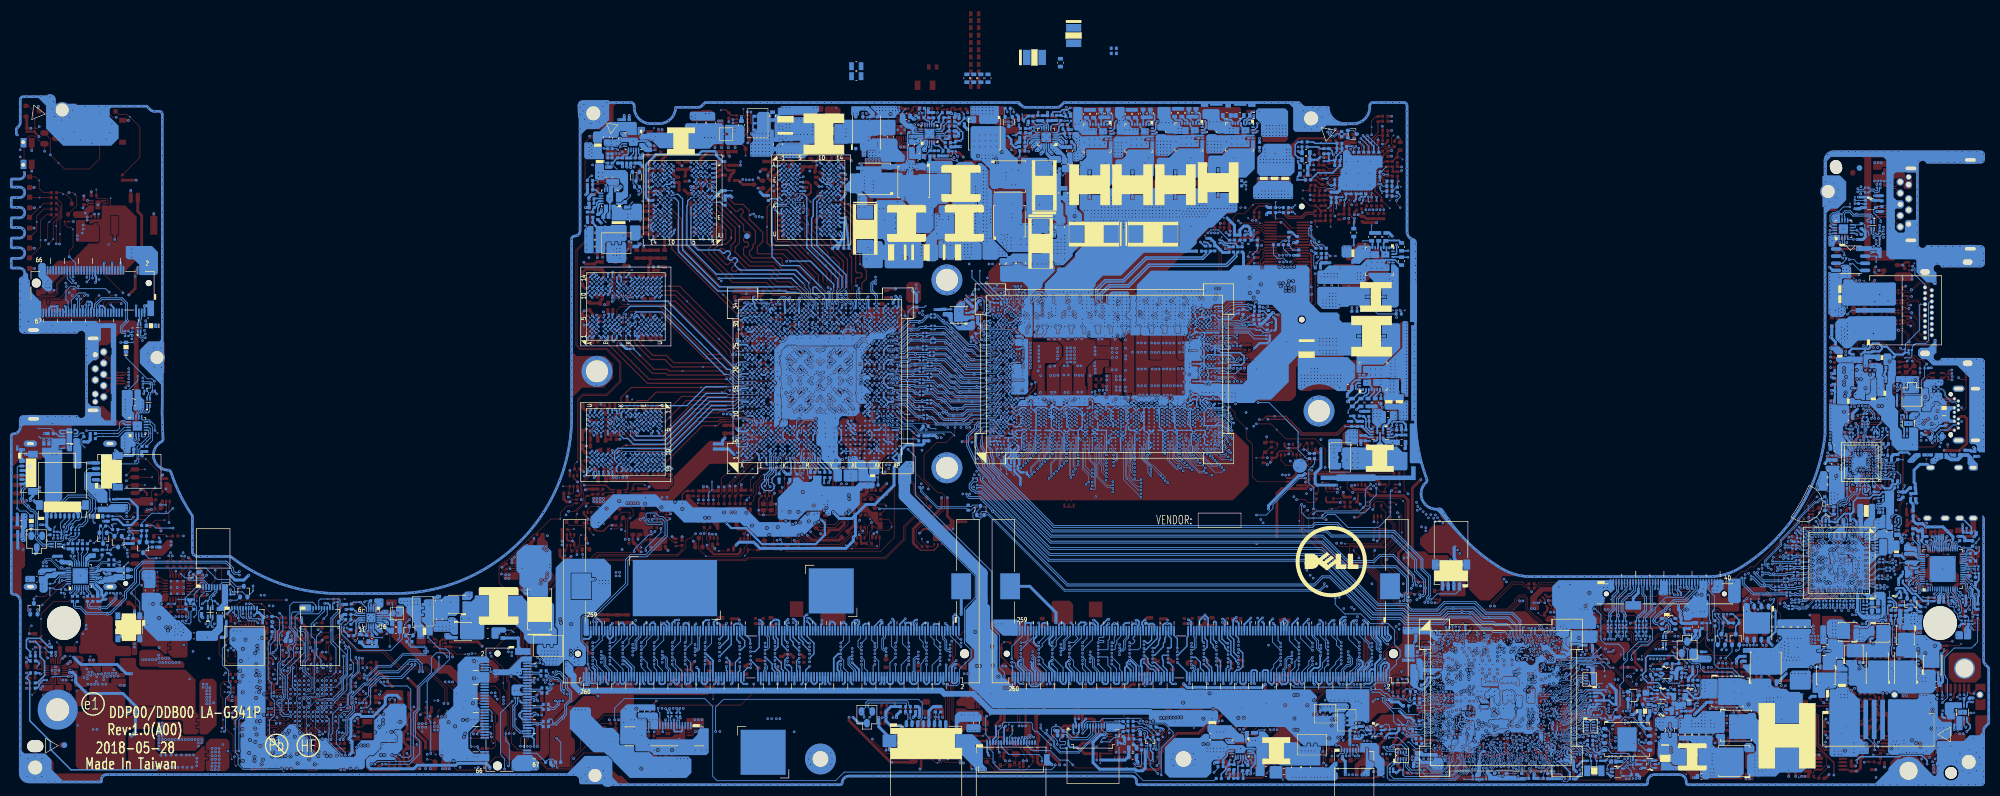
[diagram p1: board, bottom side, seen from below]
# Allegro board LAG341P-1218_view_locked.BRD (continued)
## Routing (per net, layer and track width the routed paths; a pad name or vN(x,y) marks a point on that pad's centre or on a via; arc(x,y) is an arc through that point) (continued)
CFG12: length 4.5
  TOP w0.089: v2(137.49,140.07) 137.49,139.61 v4(137.19,139.3)
  TOP w0.14: JXDP.28 121.23,159.2 121.6,158.83 122.59,158.83 122.96,159.2 v2(122.96,159.28)
  BOTTOM w0.076: UH1.BM19 137.82,139.75 v2(137.49,140.07)
CFG13: length 6.3
  TOP w0.089: v2(133.82,138.85) 134.19,139.22 135.09,139.22 v4(135.39,138.92)
  TOP w0.14: v2(121.79,159.26) 121.79,159.47 121.56,159.7 JXDP.30
  BOTTOM w0.076: UH1.BR19 135.87,139.47 135.58,139.18 134.96,139.18 134.9,139.25 134.21,139.25 v2(133.82,138.85)
CFG14: length 7.1
  TOP w0.14: JXDP.34 121.26,160.7 122.38,159.58 v2(122.38,159.28)
  BOTTOM w0.076: UH1.BP19 136.2,140 135.74,140 135.52,139.77 135.52,139.51 135.39,139.39 135.1,139.39 135.03,139.45 133.78,139.45 v2(133.19,138.85)
CFG15: length 6.3
  TOP w0.14: v2(122.43,160.17) 122.24,160.17 121.2,161.2 JXDP.36
  BOTTOM w0.14: UH1.BT19 132.64,139.68 v2(131.85,138.89)
CFG16: length 4
  TOP w0.089: v1(136.16,142.69) 136.19,142.73 v2(136.19,143.22)
  TOP w0.14: v2(122.61,154.96) 122.61,154.84 121.46,153.7 JXDP.6
  BOTTOM w0.076: v2(136.19,143.22) 136.52,142.9 UH1.BP23
CFG17: length 5.6
  TOP w0.089: v4(137.87,142.73) 137.34,142.73 v2(136.84,143.22)
  TOP w0.14: JXDP.4 121.64,153.2 123.27,154.84 v2(123.27,154.96)
  BOTTOM w0.076: v2(136.84,143.22) 137.17,142.9 UH1.BN23
CFG18: length 4.4
  TOP w0.089: v4(137.24,141.09) 136.84,141.48 v2(136.84,141.65)
  TOP w0.14: v2(122.73,156.71) 122.73,156.79 121.32,158.2 JXDP.24
  BOTTOM w0.076: v2(136.84,141.65) 137.17,141.97 UH1.BN22
CFG19: length 4.2
  TOP w0.089: v2(136.19,141.65) 135.5,140.95 v4(135.5,140.72)
  TOP w0.14: v2(121.97,156.72) 121.97,157.21 121.48,157.7 JXDP.22
  BOTTOM w0.076: UH1.BP22 136.52,141.97 v2(136.19,141.65)
CFG_RCOMP: length 10
  TOP w0.14: v2(130.68,142.82) 130.44,142.58 v1(128.88,142.58)
  BOTTOM w0.254: UH1.BT25 134.82,144.01 131.37,144.01 130.68,143.32 v2(130.68,142.82) 130.68,142.31 131.18,141.81 RH59.1
CHG_BGATE: length 7.8
  TOP w0.203: PC1933.1 40.44,85.87 41.07,85.24 v1(41.14,85.24) 41.68,85.24 42.46,84.46 45.15,84.46 45.28,84.33 PU1900.32
  TOP w0.381: v2(41.07,86.12) PC1933.1
  BOTTOM w0.381: PQ1905.4 29.1,88.07 v2(29.13,88.03)
CHR_USB20_N1: length 3.8
  BOTTOM w0.152: LI2.1 325.86,134.29 325.78,134.21 325.78,133.8 325.94,133.63 v5(326.86,133.63) 327.37,133.63 327.66,133.34 327.66,133.08 327.83,132.91 UI2.11
CHR_USB20_N1_R: length 4.8
  BOTTOM w0.152: v2(326.62,138.36) 326.49,138.49 325.48,138.49 325.35,138.36 325.22,138.23 325.22,137.77 325.28,137.71 325.73,137.71 325.91,137.53 D124.1 325.55,136.88 325.55,136.65 325.77,136.43 325.77,136.17 325.86,136.08 LI2.2
CHR_USB20_N2: length 8.4
  BOTTOM w0.152: UI1.11 24.3,168.72 23.77,169.25 22.82,169.25 22.21,168.65 v5(21.76,168.65) 19.15,168.65 18.84,168.34 18.84,168.03 18.6,167.79 LI5.1
CHR_USB20_N2_R: length 3.4
  BOTTOM w0.152: LI5.2 18.6,165.72 18.77,165.55 18.77,165.37 18.66,165.26 18.29,165.26 18.08,165.06 17.86,165.06 17.75,165.17 17.75,165.6 D126.1 17.38,165.49 17.2,165.49 v2(16.94,165.75)
CHR_USB20_P1: length 3.8
  BOTTOM w0.152: LI2.4 325.36,134.27 325.45,134.18 325.45,133.56 v1(325.49,133.52) 325.71,133.3 327.23,133.3 327.33,133.2 UI2.10
CHR_USB20_P1_R: length 4.8
  BOTTOM w0.152: LI2.3 325.36,136.08 325.44,136.16 325.44,136.29 325.22,136.51 325.22,136.89 324.88,137.23 D123.1 324.89,137.25 324.89,138.36 v5(325.11,138.59) 325.34,138.82 326.49,138.82 v2(326.62,138.95)
CHR_USB20_P2: length 8.4
  BOTTOM w0.152: LI5.4 19.74,167.27 19.87,167.4 19.87,167.65 19.75,167.77 19.41,167.77 19.17,168.01 19.17,168.2 19.28,168.32 v5(19.55,168.32) 22.35,168.32 22.96,168.92 23.64,168.92 23.89,168.68 23.89,168.31 23.8,168.23 UI1.10
CHR_USB20_P2_R: length 3.4
  BOTTOM w0.152: LI5.3 19.1,165.23 18.8,164.93 18.43,164.93 18.22,164.73 17.71,164.73 D125.1 17.13,165.12 v2(16.94,165.12)
CLINK_CLK: length 3.1
  BOTTOM w0.089: v2(97.87,77.45) 97.56,77.14 96.37,77.14 96.23,77 UH2.AR2
  BOTTOM w0.14: v2(336.57,157.4) JNGFF1.34
CLINK_DATA: length 6.2
  BOTTOM w0.089: v2(98.47,77.45) 98.24,77.22 98.24,77.19 98.01,76.97 96.56,76.97 96.37,76.78 95.87,76.78 95.79,76.7 94.98,76.7 UH2.AT5
  BOTTOM w0.14: v2(336.58,156.6) 336.07,157.1 JNGFF1.32
CLINK_RST#: length 5.4
  TOP w0.14: v1(310.82,71.65) 310.82,72.47 v2(311.48,73.13)
  BOTTOM w0.076: v2(95.28,74.96) 95.4,75.07 95.72,75.07 95.83,75.18 95.83,75.65 95.93,75.75 95.93,75.94 95.81,76.06 95.64,76.06 UH2.AU4
  BOTTOM w0.14: v2(335.57,157.29) JNGFF1.30
CLK_PCIE_N3: length 3.1
  BOTTOM w0.089: v2(94.19,82.5) 94.19,82.21 UH2.AE6
  BOTTOM w0.152: JNGFF1.41 338.32,151.84 338.24,151.92 338.24,153.45 v2(338.38,153.59)
CLK_PCIE_N4: length 4.2
  BOTTOM w0.089: v2(98.4,83.71) 98.4,83.65 98.15,83.4 97.61,83.4 97.48,83.53 96.94,83.53 96.56,83.15 96.47,83.15 96.28,83.34 96.09,83.34 96.03,83.29 96.03,83.21 UH2.AC2
  BOTTOM w0.152: UR1.6 337.14,101.79 337.21,101.72 337.21,101.31 337.06,101.16 v2(337.06,101.16)
CLK_PCIE_N5: length 2.2
  BOTTOM w0.089: v2(97.5,84.64) 97.13,84.27 97.13,84.19 96.98,84.04 96.46,84.04 UH2.AB2
  BOTTOM w0.102: UT1.T19 v2(26.42,103.02)
CLK_PCIE_N6: length 10
  BOTTOM w0.089: UH2.W4 95.26,84.72 96.27,84.72 96.67,85.12 96.84,85.12 v2(97.01,84.95)
  BOTTOM w0.152: JNGFF2.53 258.97,76.74 259.05,76.66 259.44,76.66 260.44,77.66 260.44,81.05 259.98,81.51 259.98,82.43 v2(259.85,82.56)
CLK_PCIE_N7: length 1.1
  BOTTOM w0.089: UH2.W7 93.77,85.09 93.77,85.27 v2(93.59,85.45)
  BOTTOM w0.102: UV18.AK13 v2(195.2,134.84)
CLK_PCIE_P3: length 3
  BOTTOM w0.089: v2(93.62,82.49) 93.62,82.02 UH2.AE7
  BOTTOM w0.152: v2(337.69,153.56) 337.91,153.35 337.91,151.92 337.82,151.83 JNGFF1.39
CLK_PCIE_P4: length 4.3
  BOTTOM w0.089: v2(98.4,83.13) 97.5,83.13 97.37,83.26 97.05,83.26 96.67,82.88 95.98,82.88 95.58,83.28 UH2.AC3
  BOTTOM w0.152: v2(337.64,101.16) 337.54,101.26 UR1.5
CLK_PCIE_P5: length 2.6
  BOTTOM w0.089: UH2.AB3 95.82,83.78 96.09,83.52 96.31,83.52 96.57,83.78 97.09,83.78 97.37,84.05 v2(97.5,84.05)
  BOTTOM w0.102: UT1.V19 v2(27.07,103.02)
CLK_PCIE_P6: length 9.9
  BOTTOM w0.089: v2(96.96,85.51) 96.83,85.38 96.55,85.38 96.16,84.99 95.66,84.99 UH2.W3
  BOTTOM w0.152: v2(260.43,82.56) 260.31,82.44 260.31,81.65 260.77,81.19 260.77,77.52 259.58,76.33 259.04,76.33 258.95,76.24 JNGFF2.55
CLK_PCIE_P7: length 1.2
  BOTTOM w0.089: UH2.W6 94.21,85.18 94.08,85.3 94.08,85.5 v2(94.15,85.57)
  BOTTOM w0.102: v2(195.22,135.61) 194.85,135.24 UV18.AL13
CLK_TP_SIO: length 14.4
  TOP w0.076: UE3.E10 v2(294.72,84.86)
  BOTTOM w0.14: JTP.1 190.76,78.52 190.5,78.78 190.5,79.72 CE77.1 190.93,80.54 190.91,80.56 RE24.2 190.75,81.2 190.75,81.58 190.85,81.67 197.5,81.67 197.59,81.58 197.59,80.95 DE4.2 196.82,79.62 197.23,79.19 v2(197.28,79.14)
CLKIN_XTAL: length 2.8
  TOP w0.089: v2(94.64,85.99) 95.16,86.51 RH5850.1 95.17,86.97 T4952.1
  BOTTOM w0.089: UH2.R6 94.6,86.52 94.6,86.03 v2(94.64,85.99)
CLKREQ_PCIE#0: length 7.3
  BOTTOM w0.089: RH548.2 86.14,69.37 85.78,69.74 82.99,69.74 82.76,69.51 82.05,69.51 81.81,69.74 81.81,70.23 81.95,70.37 81.95,71.46 82.28,71.79 UH2.BF31
CLKREQ_PCIE#3: length 7.4
  TOP w0.14: v2(65.82,80.14) 65.72,80.04 RP2.5
  BOTTOM w0.089: UH2.BB30 82.43,73.99 82.12,74.3 v2(82.12,74.35)
  BOTTOM w0.14: v2(336.4,154.2) 336.84,154.63 338.04,154.63 339.32,153.36 JNGFF1.45
CLKREQ_PCIE#4: length 2.7
  TOP w0.14: v2(65.81,80.73) 65.62,80.54 RP2.6
  BOTTOM w0.089: UH2.BA30 82.62,74.54 82.28,74.88 v2(82.27,74.88)
  BOTTOM w0.14: v2(339.52,101.3) 339.29,101.3 338.74,101.85 UR1.2
  vias: v2(117.13,80.75)
CLKREQ_PCIE#5: length 32
  TOP w0.14: v2(35.79,92.75) 35.79,93.97 35.27,94.49 35.27,97.49 35.81,98.04 35.81,100.37 36.27,100.83 36.27,106.08 36.05,106.31 36.05,109.45 33.72,111.78 32.76,111.78 v2(32.61,111.93) 32.61,112.14 32.75,112.27 32.75,112.63 32.46,112.91 32.46,113.57 31.33,114.7 30.82,114.7 30.4,114.29 30.05,114.29 29.67,114.66 RT21.2 ; RP2.7 65.41,81.04 65.71,81.34 v2(65.79,81.34)
  BOTTOM w0.089: v2(82.33,80.65) 82.31,80.63 82.31,79.3 83,78.61 UH2.AN29
  BOTTOM w0.14: v2(32.61,111.93) 32.28,111.6 RT5845.1
CLKREQ_PCIE#5_AR: length 2.6
  BOTTOM w0.089: 31.42,110.27 30.97,109.81 UT1.AC5
  BOTTOM w0.14: 31.42,110.27 31.7,110.54 RT5845.2
CLKREQ_PCIE#6: length 14.4
  TOP w0.14: v2(65.72,82.89) 65.72,81.88 65.38,81.54 RP2.8
  BOTTOM w0.089: UH2.AE47 74.31,81.9 74.22,81.81 73.39,81.81
  BOTTOM w0.14: JNGFF2.52 266.46,76.99 267.14,76.31 v2(267.14,76.14) ; 73.39,81.81 72.73,82.46 72.28,82.46 71.21,83.53 70.47,83.53 69.89,84.1 66.08,84.1 65.61,83.64 65.61,83 v2(65.72,82.89)
CLKREQ_PCIE#7: length 61.4
  TOP w0.14: v2(183.41,85.03) 183.39,85.02 v1(183.39,83.69) 183.39,76.22 v2(184.02,75.58) ; QV103.1 195.8,116.44 v2(195.58,116.22) ; RH551.2 70.55,83.77 v2(70.7,83.93)
  BOTTOM w0.089: 70.78,83.93 71.11,83.93 72.16,82.87 73.66,82.87 UH2.AC48
  BOTTOM w0.14: 70.78,83.93 v2(70.7,83.93) ; v2(195.58,116.22) 190.46,116.22 178.52,104.28 178.52,100.42 180.44,98.5 180.44,92.29 179.26,91.11 179.26,89.74 181.31,87.69 181.31,85.23 181.79,84.75 183.18,84.75 183.41,84.98 v2(183.41,85.03)
CLKREQ_PCIE#7_GPU: length 27
  TOP w0.14: v2(196,133.12) 194.26,133.12 191.24,130.1 191.24,126.99 192.65,125.59 193.84,125.59 194.8,124.62 194.8,123.69 193.22,122.1 193.22,119.65 v1(194.16,118.71) 194.83,118.04 QV103.3 196.47,118.76 197.28,118.76 198.15,117.9 RV591.2
  BOTTOM w0.102: UV18.AK12 195.6,134.24 196,133.84 v2(196,133.12)
CLKRUN#: length 2.7
  TOP w0.089: RH85.1 81.71,76.06 v3(81.2,75.55)
  TOP w0.14: v1(264.25,74.57) 264.61,74.94 v2(264.61,75.63)
  BOTTOM w0.089: UH2.AV32 81.56,75.91 v3(81.2,75.55)
CMOUT: length 8.1
  TOP w0.14: PR1928.1 v2(48.12,88.01) ; v2(55.9,84.28) v1(56.51,84.28)
  BOTTOM w0.14: PQ224.2 61.98,83.68 61.72,83.42 61.72,81.43 61.87,81.27 61.87,80.43 v2(62.09,80.22) ; PQ221.5 57.46,80.53 56.97,81.02 56.97,81.53 v2(56.52,81.98) ; PQ220.6 55.56,83.94 v2(55.9,84.28)
CMRSVD1: length 1.2
  TOP w0.089: T53.1 160.48,135.4 v2(160.79,135.72)
  BOTTOM w0.076: v2(160.79,135.72) 161.12,135.39 UH1.AA14
CMRSVD2: length 2.3
  TOP w0.089: v2(158.35,147.01) 158.35,146.74 157.99,146.38 T52.1
  BOTTOM w0.076: UH1.AE29 158.28,147.43 158.35,147.36 v2(158.35,147.01)
CMRSVD3: length 1.1
  TOP w0.089: v2(154.5,131.16) 154.81,131.47 T83.1
  BOTTOM w0.076: UH1.AJ8 154.83,131.49 v2(154.5,131.16)
CMRSVD4: length 1.7
  TOP w0.089: T4965.1 152.31,136.37 v2(151.83,135.88)
  BOTTOM w0.076: UH1.AP14 151.34,135.39 v2(151.83,135.88)
CMRSVD5: length 1.9
  TOP w0.089: v2(152.19,146.93) 152.34,146.93 T4966.1
  BOTTOM w0.076: UH1.AP29 151.92,146.93 v2(152.19,146.93)
CMRSVD6: length 4.9
  BOTTOM w0.076: T90.1 173.97,123.31 173.97,124.78 174.8,125.61 174.8,126.63 174.93,126.76 174.93,127.33 UH1.B2
CMRSVD7: length 4.3
  TOP w0.089: T59.1 176.92,149.82 v2(176.92,149.57)
  BOTTOM w0.076: UH1.B30 175.27,148.49 176.75,148.49 177.24,148.99 177.24,149.25 v2(176.92,149.57)
CMRSVD8: length 6.6
  BOTTOM w0.14: T89.1 179.1,157.36 UH1.B38
CMRSVD9: length 1.1
  TOP w0.089: T65.1 140.63,148.68 v2(140.56,148.68)
  BOTTOM w0.076: UH1.BH30 140.18,148.3 v2(140.56,148.68)
CMRSVD10: length 1.2
  TOP w0.089: v2(140.25,146.31) T67.1
  BOTTOM w0.076: v2(140.25,146.31) 140.22,146.31 UH1.BJ28
CMRSVD11: length 1.7
  TOP w0.089: v2(138.18,147.15) 138.32,147.29 T66.1
  BOTTOM w0.076: v2(138.18,147.15) 138.8,147.15 139.12,146.83 UH1.BK28
CMRSVD12: length 1.5
  TOP w0.089: v2(138.99,149.37) 139.59,148.77 T82.1
  BOTTOM w0.076: UH1.BL31 138.62,149 v2(138.99,149.37)
CMRSVD13: length 1.2
  TOP w0.089: T49.1 138.86,151.15 v2(138.99,151.28)
  BOTTOM w0.076: UH1.BL34 138.67,150.96 v2(138.99,151.28)
CMRSVD14: length 1.7
  TOP w0.089: v2(137.49,149.52) 136.86,149.52 T48.1
  BOTTOM w0.076: UH1.BN33 137.17,149.85 v2(137.49,149.52)
CMRSVD15: length 1.1
  TOP w0.089: v2(136.84,151.12) 136.49,151.48 T45.1
  BOTTOM w0.076: v2(136.84,151.12) 136.84,151.16 UH1.BN35
CMRSVD16: length 4.1
  TOP w0.089: v2(133.51,125.46) 133.86,125.12 T88.1
  BOTTOM w0.076: UH1.BP1 135.84,126.26 135.42,126.26 134.63,125.46 v2(133.51,125.46)
CMRSVD17: length 4.2
  TOP w0.089: T87.1 133.81,126.04 v2(133.97,125.88)
  BOTTOM w0.076: UH1.BR2 136.07,127.65 136.19,127.53 136.19,127.06 136.19,127.06 136.19,126.84 135.77,126.42 135.36,126.42 134.81,125.88 v2(133.97,125.88)
CMRSVD18: length 1.7
  TOP w0.089: T64.1 136.66,148.56 v2(136.85,148.75)
  BOTTOM w0.076: UH1.BR31 136.25,148.75 v2(136.85,148.75)
CMRSVD19: length 5.4
  BOTTOM w0.076: UH1.BR35 135.51,151.82 134.42,151.82 133.31,152.93 132.38,152.93
  BOTTOM w0.14: T63.1 132.38,152.93
CMRSVD20: length 5.3
  BOTTOM w0.076: UH1.C1 174.63,126.87 174.63,125.68 173.8,124.85 173.8,124.01 172.91,123.12 T86.1
CMRSVD21: length 1.1
  TOP w0.089: T60.1 174.71,148.82 v2(174.85,148.95)
  BOTTOM w0.076: v2(174.85,148.95) 174.54,148.65 UH1.C30
CMRSVD22: length 6.4
  BOTTOM w0.14: UH1.C38 174.59,153.56 177.7,156.66 T85.1
CMRSVD23: length 5.1
  BOTTOM w0.076: 177.67,148.23 177.65,148.24 177.28,148.24 177.23,148.29 173.32,148.29 173.24,148.36 UH1.E30
  BOTTOM w0.14: T58.1 177.79,148.23 177.67,148.23
CMRSVD24: length 1.2
  TOP w0.089: v2(172.3,148.98) 172.29,148.98 T57.1
  BOTTOM w0.076: v2(172.3,148.98) 172.59,148.69 UH1.F30
CMRSVD25: length 1.6
  TOP w0.089: v2(171.6,135.6) 171.6,136.36 T84.1
  BOTTOM w0.076: UH1.G13 171.94,135.26 v2(171.6,135.6)
CMRSVD26: length 2.3
  TOP w0.089: T61.1 171.97,126.99 171.52,127.44 v2(171.52,127.92)
  BOTTOM w0.076: v2(171.52,127.92) 171.83,128.23 UH1.G3
CMRSVD27: length 1.6
  TOP w0.089: T47.1 171.99,143.86 v2(171.64,144.2)
  BOTTOM w0.076: v2(171.64,144.2) 171.28,143.84 UH1.H24
CMRSVD28: length 2.7
  TOP w0.089: T46.1 170.68,142.07 170.18,142.57 v2(170.18,142.68)
  BOTTOM w0.076: UH1.J24 170.59,143.59 170.18,143.18 v2(170.18,142.68)
CMRSVD29: length 1.8
  TOP w0.089: T62.1 171.93,128.16 v2(171.48,128.61)
  BOTTOM w0.076: v2(171.48,128.61) 171.11,128.23 UH1.J3
CMRSVD30: length 1.8
  TOP w0.089: v2(167.36,148.67) 167.5,148.53 T50.1
  BOTTOM w0.076: UH1.N29 167.36,148.03 v2(167.36,148.67)
CMRSVD31: length 1.2
  TOP w0.089: v2(165.43,135.08) 165.78,134.73 T51.1
  BOTTOM w0.076: v2(165.43,135.08) 165.73,135.39 UH1.R14
CMRSVD_TP1: length 2.4
  TOP w0.089: v2(134.41,126.34) 134.85,125.9 T43.1
  BOTTOM w0.076: UH1.BR1 135.48,126.93 134.88,126.34 v2(134.41,126.34)
CMRSVD_TP2: length 1.2
  TOP w0.089: T44.1 134.86,127.26 v2(134.7,127.1)
  BOTTOM w0.076: v2(134.7,127.1) 135.1,127.5 UH1.BT2
CMRSVD_TP3: length 1.9
  TOP w0.089: T42.1 174.28,125.26 v2(174.28,125.82)
  BOTTOM w0.076: v2(174.28,125.82) 174.28,126.53 173.88,126.93 UH1.D1
CMRSVD_TP4: length 1.2
  TOP w0.089: v2(173.1,126.41) 173.1,125.88 T41.1
  BOTTOM w0.076: v2(173.1,126.41) 173.07,126.44 UH1.E1
CMRSVD_TP5: length 2.3
  TOP w0.089: v2(173.78,126.23) 174.1,126.55 T39.1
  BOTTOM w0.076: v2(173.78,126.23) 173.37,126.64 UH1.E2
CODE_CBN1: length 4.7
  BOTTOM w0.14: CA18.2 0.28,108.29 -0.11,108.68 -0.11,109.43 v1(-0.05,109.5)
  BOTTOM w0.203: UA1.28 2.47,108.12 2.11,108.48 2.11,108.71 1.9,108.92 1.89,108.92 1.86,108.96 1.21,108.96 CA18.2
CODE_CBP2: length 2.7
  BOTTOM w0.203: UA1.26 2.35,107.32 2.06,107.61 1.21,107.61 CA15.2
CODE_MIC1_CAP: length 1.6
  BOTTOM w0.14: CA31.1 9.24,110.16 8.6,109.52 UA1.41
CODE_VREF: length 3.8
  BOTTOM w0.203: UA1.43 10.3,108.12 10.44,108.26 10.44,110.04 10.71,110.31 CA24.1
  BOTTOM w0.254: CA24.1 10.71,111.28 CA25.1
CODE_VREF1: length 3.3
  BOTTOM w0.14: CA29.1 0.56,104.11 0.6,104.15 CA28.1 1,104.79 v1(1.44,105.23) 1.63,105.42 2.25,105.42 2.35,105.32 UA1.21
COMP_1PH: length 5.1
  TOP w0.203: v2(113.21,171.72) 112.57,171.72 112.01,172.28 PU1100.50
  BOTTOM w0.14: PC1109.2 v1(114.27,169.65)
  BOTTOM w0.254: PC1109.2 PC1110.2 113.28,171.65 v2(113.21,171.72)
COMP_2PH: length 4.1
  TOP w0.203: PU1100.33 106.54,175.91
  TOP w0.254: PC1121.2 104.34,175.48 PC1119.2 105.61,175.48 v2(105.87,175.74) 106.05,175.92 106.54,175.92 106.54,175.91
  BOTTOM w0.14: v2(105.87,175.74) v1(105.07,175.74)
COMP_4PH: length 5.9
  TOP w0.203: PC1115.1 116.05,174.85 v2(115.91,174.99) 115.39,175.51 PU1100.6
  TOP w0.254: PC1115.1 117.2,174.85 117.88,175.53 PR1136.1
  BOTTOM w0.14: v2(115.91,174.99) v1(116.78,174.99)
COMP_ISL88738: length 4
  TOP w0.203: PU1900.28 46.88,85.13 46.09,85.92 45.96,85.92 45.59,86.29 PR1930.1 PC1939.1
CORE_SW1: length 1.3
  TOP w0.14: PC1217.1 v4(134.04,175.93)
  vias: v2(133.1,177.77) v2(133.1,177.18)
CORE_SW2: length 0.9
  TOP w0.14: v4(140.04,176.57) 140.65,177.18 v2(140.72,177.18)
  vias: v2(140.72,177.77)
CORE_SW3: length 1.1
  TOP w0.14: v2(148.34,177.18) 148.34,177.02 v4(147.7,176.38)
  vias: v2(148.34,177.77)
CORE_SW4: length 1.3
  TOP w0.14: v2(155.32,177.18) 155.32,176.54 v4(154.86,176.08)
  vias: v2(155.32,177.77)
CPU_24MHZ_N: length 1
  BOTTOM w0.076: UH1.D31 173.58,149.05 v2(173.58,148.96)
  BOTTOM w0.089: v2(94.44,92.66) 94.39,92.66 UH2.C6
CPU_24MHZ_P: length 1
  BOTTOM w0.076: UH1.E31 172.93,149.05 v2(172.93,148.96)
  BOTTOM w0.089: UH2.D7 94.25,92.14 v2(94.27,92.14)
CPU_BPM#2: length 1.3
  TOP w0.089: v2(138.17,148.68) 137.67,148.18 T4971.1
  BOTTOM w0.076: v2(138.17,148.68) 138.17,148.74 137.82,149.1 UH1.BM31
CPU_BPM#3: length 1.4
  TOP w0.089: T4972.1 134.49,148.58 v2(134.44,148.52)
  BOTTOM w0.076: v2(134.44,148.52) 134.54,148.41 135.14,148.41 UH1.BT30
CPU_C10_GATE#: length 5
  TOP w0.14: v2(107.63,110.71) 107.63,111.98 RZ1953.1
  BOTTOM w0.14: v2(102.45,76.37) 101.69,75.61 100.41,75.61 RH5835.1
  BOTTOM w0.254: PR802.1 108.43,128.34 v2(108.38,128.29)
  vias: v2(87.6,86.43)
CPU_DP1_AUXN: length 7.1
  TOP w0.152: CT26.2 31.86,107.12 32.61,107.12 34.32,105.41 34.32,104.71 34.7,104.32 34.7,102.97 v2(35.01,102.67)
  BOTTOM w0.076: v2(172.9,145.78) 172.9,146.03 173.07,146.21 UH1.E27
CPU_DP1_AUXN_C: length 4.3
  TOP w0.089: CT26.1 29.9,107.27 29.32,107.85 28.71,107.85 28.55,108.01 28.18,108.01 v2(27.74,107.57)
  BOTTOM w0.102: v2(27.74,107.57) 27.84,107.47 27.84,107.45 UT1.W11
CPU_DP1_AUXP: length 6.3
  TOP w0.152: CT25.2 31.8,106.79 32.47,106.79 33.99,105.28 33.99,104.57 34.37,104.19 v2(34.37,102.67)
  BOTTOM w0.076: UH1.D27 173.55,145.86 v2(173.55,145.78)
CPU_DP1_AUXP_C: length 4.3
  TOP w0.089: CT25.1 30.91,106.92 v1(30.21,106.92) 29.81,106.92 29.64,107.1 29.44,107.1 29.35,107.19 29.35,107.38 29.24,107.5 29.06,107.5 28.99,107.43 28.99,107.21 28.9,107.12 28.76,107.12 28.66,107.21 28.66,107.5 28.6,107.57 v2(28.37,107.57)
  BOTTOM w0.102: UT1.Y11 v2(28.37,107.57)
CPU_DP1_N0: length 5
  BOTTOM w0.076: UH1.K37 170.09,152.59 170.15,152.53 170.33,152.53 170.41,152.62 170.41,153.66 170.07,154 170.07,154.67 169.97,154.77 169.85,154.77 v2(169.64,154.56)
  BOTTOM w0.152: CT18.2 33.28,109.29 33.97,109.29 34.12,109.44 34.3,109.44 v2(34.47,109.26)
CPU_DP1_N0_C: length 3.6
  BOTTOM w0.089: 31.82,109.01 31.72,109.01 31.51,108.81 30.32,108.81 30.16,108.65 29.72,108.65 29.66,108.72 29.66,108.77 29.77,108.89 UT1.AC7
  BOTTOM w0.152: CT18.1 32.31,109.33 32.13,109.33 31.82,109.01
CPU_DP1_N1: length 1.6
  BOTTOM w0.076: v2(170.5,150.64) 170.81,150.96 UH1.J34
  BOTTOM w0.152: v2(34.73,107.95) 34.59,107.81 33.96,107.81 CT20.2
CPU_DP1_N1_C: length 4.1
  BOTTOM w0.089: UT1.AC9 29.75,107.97 29.68,108.04 29.68,108.13 29.76,108.21 30.04,108.21 30.32,107.92 31.5,107.92 31.53,107.95
  BOTTOM w0.152: CT20.1 33.08,107.83 32.84,107.83 32.71,107.95 v5(32.27,107.95) 31.53,107.95
CPU_DP1_N2: length 8.4
  BOTTOM w0.076: v2(171.53,155.82) 171.37,155.67 171.37,155.47 171.67,155.17 171.67,153.35 171.98,153.04 171.98,152.57 UH1.H36
  BOTTOM w0.152: CT22.2 32.68,106.88 36.58,106.88 v2(36.7,107)
CPU_DP1_N2_C: length 2.8
  BOTTOM w0.089: 31.24,106.93 31.22,106.93 31.19,106.9 30.33,106.9 30.18,107.05 30.18,107.16 30.05,107.28 29.78,107.28 29.71,107.21 29.71,107.12 29.77,107.05 UT1.AC11
  BOTTOM w0.152: CT22.1 31.74,106.93 31.24,106.93
CPU_DP1_N3: length 4.1
  BOTTOM w0.076: v2(170.7,155.31) 170.8,155.31 170.98,155.13 170.98,154.95 171.15,154.78 171.15,154.27 170.98,154.1 170.98,153.61 171.03,153.56 UH1.J38
  BOTTOM w0.152: v2(35.82,105.79) 35.7,105.67 35.05,105.67 34.78,105.94 34.25,105.94 CT24.2
CPU_DP1_N3_C: length 4.4
  BOTTOM w0.089: 30.88,105.94 30.74,105.94 30.71,105.9 30.44,105.9 30.22,106.12 30.22,106.24 30.09,106.37 29.8,106.37 29.74,106.31 29.74,106.25 UT1.AC13 ; 31.4,105.94 31.42,105.94
  BOTTOM w0.152: 30.88,105.94 31.4,105.94 ; CT24.1 33.41,105.94 31.42,105.94
CPU_DP1_P0: length 5.2
  BOTTOM w0.076: UH1.K36 170.18,152.34 170.39,152.34 170.59,152.54 170.59,153.74 170.25,154.08 170.25,154.74 170.04,154.95 169.84,154.95 v2(169.64,155.14)
  BOTTOM w0.152: CT17.2 33.24,109.62 33.84,109.62 33.99,109.77 34.39,109.77 v2(34.47,109.85)
CPU_DP1_P0_C: length 3.6
  BOTTOM w0.089: UT1.AB7 29.63,109.12 30.18,109.12 30.29,109.01 31.42,109.01 31.58,109.17 31.58,109.25
  BOTTOM w0.152: 31.58,109.25 31.7,109.36 31.99,109.66 32.23,109.66 CT17.1
CPU_DP1_P1: length 2.5
  BOTTOM w0.076: UH1.J35 170.98,151.71 171.09,151.71 171.24,151.56 171.24,151.3 171.18,151.24 170.55,151.24 v2(170.5,151.29)
  BOTTOM w0.152: v2(34.73,107.37) 34.62,107.48 33.95,107.48 CT19.2
CPU_DP1_P1_C: length 4.1
  BOTTOM w0.089: 31.53,107.62 31.49,107.66 30.21,107.66 30.12,107.74 29.63,107.74 UT1.AB9
  BOTTOM w0.152: CT19.1 33.15,107.41 33.06,107.5 32.7,107.5 32.58,107.62 31.53,107.62
CPU_DP1_P2: length 8.5
  BOTTOM w0.076: v2(170.95,155.81) 171.12,155.65 171.12,155.37 171.42,155.06 171.42,153.13 171.27,152.98 171.27,152.58 171.33,152.53 171.55,152.53 171.67,152.65 UH1.H37
  BOTTOM w0.152: v2(36.7,106.42) 36.58,106.55 32.58,106.55 CT21.2
CPU_DP1_P2_C: length 2.7
  BOTTOM w0.089: 31.24,106.6 31.2,106.63 30.22,106.63 30.02,106.83 29.62,106.83 UT1.AB11
  BOTTOM w0.152: 31.24,106.6 31.74,106.6 CT21.1
CPU_DP1_P3: length 4
  BOTTOM w0.076: v2(170.69,154.74) 170.83,154.74 170.97,154.59 170.97,154.34 170.8,154.17 170.8,153.47 170.88,153.4 UH1.J37
  BOTTOM w0.152: CT23.2 34.25,105.61 34.65,105.61 34.91,105.34 35.68,105.34 v2(35.82,105.21)
CPU_DP1_P3_C: length 4.4
  BOTTOM w0.089: UT1.AB13 29.62,105.91 30.05,105.91 30.33,105.64 30.63,105.64 30.66,105.61 30.79,105.61
  BOTTOM w0.152: 30.79,105.61 v5(31.45,105.61) 33.41,105.61 CT23.1
CPU_DP2_AUXN: length 4.6
  TOP w0.152: v2(33.11,102.68) 33.25,102.83 33.25,103.58 33.07,103.76 v5(33.07,103.98) 33.07,104.92 32.37,105.62 31.84,105.62 CT107.2
  BOTTOM w0.076: UH1.E26 172.92,145.09 v2(172.92,145.04)
CPU_DP2_AUXN_C: length 4.5
  TOP w0.089: v2(27.72,106.92) 27.72,106.76 28.32,106.16 28.59,106.16 28.93,105.82 29.48,105.82 29.67,105.63 v1(30.23,105.63) 30.99,105.63 CT107.1
  BOTTOM w0.102: UT1.W12 v2(27.72,106.92)
CPU_DP2_AUXP: length 5.1
  TOP w0.152: v2(33.69,102.68) 33.58,102.8 33.58,103.71 33.4,103.89 33.4,105.06 v5(32.83,105.63) 32.51,105.95 31.83,105.95 CT108.2
  BOTTOM w0.076: UH1.F26 172.59,145.33 v2(172.28,145.01)
CPU_DP2_AUXP_C: length 4.6
  TOP w0.089: v2(28.37,106.92) 28.26,106.8 28.26,106.71 28.46,106.51 28.55,106.51 28.85,106.81 28.96,106.81 29.06,106.71 29.06,106.58 28.92,106.44 v1(28.92,106.32) 29.07,106.17 29.6,106.17 29.79,105.98 31.05,105.98 CT108.1
  BOTTOM w0.102: UT1.Y12 v2(28.37,106.92)
CPU_DP2_N0: length 6.5
  BOTTOM w0.076: UH1.H33 171.81,150.31 v2(172.11,150.61)
  BOTTOM w0.152: v2(38.51,104.98) 38.45,104.93 37.29,104.93 37.02,104.66 v5(36.5,104.66) 34.37,104.66 34.18,104.85 32.99,104.85 CT30.2
CPU_DP2_N0_C: length 3.2
  BOTTOM w0.102: 30.86,104.84 30.67,104.84 30.25,105.26 30.25,105.33 30.14,105.44 29.78,105.44 29.71,105.37 29.71,105.28 29.77,105.21 UT1.AC15
  BOTTOM w0.152: 30.86,104.84 32.13,104.84 CT30.1
CPU_DP2_N1: length 10.6
  BOTTOM w0.076: v2(174.65,156.01) 174.65,155.45 174.59,155.39 172.89,155.39 172.38,154.89 172.38,154.03 172.31,153.95 172.07,153.95 171.96,153.84 171.96,153.68 172.09,153.56 UH1.G38
  BOTTOM w0.152: CT32.2 34.85,103.58 38.36,103.58 39.46,104.69 39.46,104.8 39.39,104.87 v2(39.35,104.91)
CPU_DP2_N1_C: length 5.1
  BOTTOM w0.102: 31.16,103.91 31.03,104.04 30.49,104.04 30.25,104.28 30.25,104.41 30.14,104.52 29.78,104.52 29.71,104.45 29.71,104.36 29.77,104.29 UT1.AC17
  BOTTOM w0.152: 31.16,103.91 31.19,103.87 32.98,103.87 33.14,103.71 33.85,103.71 CT32.1
CPU_DP2_N2: length 5.7
  BOTTOM w0.076: v2(172.85,151.3) 172.76,151.3 UH1.F35
  BOTTOM w0.152: v2(40.49,104.25) 40.4,104.15 40.08,104.15 38.63,102.7 v5(38.06,102.7) 37.15,102.7 36.69,102.24 36.3,102.24 CT34.2
CPU_DP2_N2_C: length 6.8
  BOTTOM w0.089: UT1.AC19 29.77,103.37 29.7,103.45 29.7,103.53 29.78,103.61 30.05,103.61 30.25,103.41 30.61,103.41 31.5,102.52 31.56,102.52
  BOTTOM w0.152: CT34.1 35.42,102.23 v5(34.26,102.23) 32.56,102.23 32.41,102.38 31.7,102.38 31.56,102.52
CPU_DP2_N3: length 11.5
  BOTTOM w0.076: UH1.E36 173.24,152.46 173.56,152.77 173.56,153.1 173.43,153.23 173.43,154.12 v2(173.39,154.16)
  BOTTOM w0.152: CT36.2 34.23,101.26 v5(37.59,101.26) 40.04,101.26 41.71,102.93 41.71,103.79 v2(41.57,103.93)
CPU_DP2_N3_C: length 5.3
  BOTTOM w0.089: UT1.AC21 29.8,102.51 29.8,102.62 29.87,102.69 30.13,102.69 30.23,102.59 30.23,102.42 30.47,102.18 30.47,101.4 30.82,101.06 31.37,101.06 31.4,101.09 31.42,101.09
  BOTTOM w0.152: CT36.1 33.34,101.17 v5(32.6,101.17) 32.15,101.17 32.07,101.09 31.42,101.09
CPU_DP2_P0: length 6.5
  BOTTOM w0.076: UH1.H34 171.31,150.6 v2(171.29,150.6)
  BOTTOM w0.152: CT29.2 33.03,104.52 34.04,104.52 34.24,104.33 37.15,104.33 37.43,104.6 38.3,104.6 v2(38.51,104.4)
CPU_DP2_P0_C: length 3.2
  BOTTOM w0.102: 30.82,104.51 30.59,104.51 30.12,104.98 29.63,104.98 UT1.AB15
  BOTTOM w0.152: 30.82,104.51 32.11,104.51 CT29.1
CPU_DP2_P1: length 10.9
  BOTTOM w0.076: v2(175.08,155.53) 174.69,155.14 172.99,155.14 172.64,154.78 172.64,153.58 172.45,153.4 UH1.F37
  BOTTOM w0.152: v2(39.93,104.9) 39.79,104.76 39.79,104.55 38.5,103.25 34.89,103.25 CT31.2
CPU_DP2_P1_C: length 5
  BOTTOM w0.089: 31.42,103.54 v5(31.33,103.54)
  BOTTOM w0.102: UT1.AB17 29.63,104.06 30.07,104.06 30.38,103.76 30.91,103.76 31.09,103.58
  BOTTOM w0.152: 31.42,103.54 32.84,103.54 33.01,103.38 33.84,103.38 CT31.1 ; 31.09,103.58 31.12,103.54 v5(31.33,103.54)
CPU_DP2_P2: length 5.8
  BOTTOM w0.076: v2(172.06,151.28) 172.13,151.28 UH1.F34
  BOTTOM w0.152: CT33.2 36.32,101.91 36.82,101.91 37.29,102.37 38.77,102.37 40.22,103.82 40.34,103.82 v2(40.49,103.66)
CPU_DP2_P2_C: length 6.9
  BOTTOM w0.089: 31.33,102.29 31.33,102.32 30.5,103.14 29.62,103.14 UT1.AB19
  BOTTOM w0.152: 31.33,102.29 31.57,102.05 32.27,102.05 32.43,101.9 35.42,101.9 CT33.1
CPU_DP2_P3: length 12
  BOTTOM w0.076: UH1.E37 173.25,152.92 173.25,153.76 172.98,154.04 172.98,154.37 v2(173.35,154.74)
  BOTTOM w0.152: CT35.2 34.27,100.92 40.18,100.92 42.04,102.79 42.04,103.82 v2(42.15,103.93)
CPU_DP2_P3_C: length 5.3
  BOTTOM w0.089: 31.42,100.76 31.4,100.76 31.37,100.79 30.7,100.79 30.29,101.2 30.29,101.21 30.21,101.29 30.21,102.07 30.05,102.23 29.62,102.23 UT1.AB21
  BOTTOM w0.152: CT35.1 33.26,100.84 32.29,100.84 32.21,100.76 31.42,100.76
CPU_DP3_AUXN: length 1.7
  TOP w0.152: v2(12.74,138.2) 12.74,138.06 12.82,137.99 13.22,137.99 CM46.2
  BOTTOM w0.076: v2(174.84,145.84) 174.84,145.72 174.88,145.68 175.08,145.68 175.21,145.81 175.21,146.2 UH1.B27
CPU_DP3_AUXN_C: length 3.5
  TOP w0.152: CM21.1 15.4,137.73 15.4,137.93 15.69,138.22 15.86,138.22 15.96,138.12 15.96,137.91 16.08,137.79 16.24,137.79 16.55,138.1 16.55,138.36 16.99,138.8 17.22,138.8 UM1.C8
CPU_DP3_AUXN_R: length 1.9
  TOP w0.152: CM46.1 14.14,137.87 v2(14.47,137.87) 14.6,137.87 14.96,137.51 CM21.2
  BOTTOM w0.152: RM26.2 14.48,137.88 v2(14.47,137.87)
CPU_DP3_AUXP: length 1.2
  TOP w0.152: v2(12.74,137.56) 12.84,137.66 13.13,137.66 CM45.2
  BOTTOM w0.076: UH1.A27 v2(175.56,145.81)
CPU_DP3_AUXP_C: length 3.5
  TOP w0.152: CM20.1 15.64,136.92 16.18,137.46 16.38,137.46 16.88,137.96 16.88,138.22 17.18,138.52 17.74,138.52 UM1.C7
CPU_DP3_AUXP_R: length 2.6
  TOP w0.152: CM45.1 14.27,137.46 v2(14.48,137.25) 14.8,136.92 CM20.2
  BOTTOM w0.152: RM25.2 13.88,137.76 14.18,137.45 14.28,137.45 v2(14.48,137.25)
CPU_DP3_N0: length 1.2
  TOP w0.152: v2(17.83,134.51) 17.68,134.67 17.68,134.91 CM7.2
  BOTTOM w0.076: UH1.D34 173.89,150.88 v2(173.56,150.54)
CPU_DP3_N0_C: length 1.8
  TOP w0.152: UM1.A7 17.91,137.09 17.91,136.28 17.73,136.1 17.73,135.76 CM7.1
CPU_DP3_N1: length 2.1
  TOP w0.152: v2(20.13,134.47) 19.86,134.74 CM15.2
  BOTTOM w0.076: v2(176.39,151.69) 176.37,151.71 176.11,151.71 176.11,151.71 175.51,151.71 175.37,151.57 175.37,151.57 UH1.B34
CPU_DP3_N1_C: length 1.9
  TOP w0.152: UM1.A5 19.48,137.06 19.48,136.42 19.71,136.19 19.71,135.81 CM15.1
CPU_DP3_N2: length 1.1
  TOP w0.152: CM17.2 21.26,134.65 v2(21.35,134.56)
  BOTTOM w0.076: UH1.E33 173.24,150.08 v2(173.59,149.74)
CPU_DP3_N2_C: length 1.8
  TOP w0.152: CM17.1 21.08,135.87 21.08,137.06 UM1.A3
CPU_DP3_N3: length 1.6
  TOP w0.152: CM19.2 22.61,134.9 22.61,134.47 v2(22.7,134.38)
  BOTTOM w0.076: v2(175.39,150.87) 175.39,150.34 UH1.B33
CPU_DP3_N3_C: length 1.8
  TOP w0.152: UM1.A1 22.76,137.14 22.76,137.14 22.65,137.03 22.65,135.79 CM19.1
CPU_DP3_P0: length 1.6
  TOP w0.152: CM6.2 17.35,134.92 17.35,134.66 v2(17.2,134.51)
  BOTTOM w0.076: v2(174.22,150.55) 174.22,151.02 174.27,151.07 174.42,151.07 UH1.C34
CPU_DP3_P0_C: length 1.9
  TOP w0.152: UM1.A8 17.58,137.04 17.58,136.42 17.4,136.24 17.4,135.86 CM6.1
CPU_DP3_P1: length 2.8
  TOP w0.152: CM14.2 19.23,134.74 v2(19.54,134.42)
  BOTTOM w0.076: UH1.B36 175.14,151.78 175.19,151.73 175.28,151.73 175.44,151.89 176.03,151.89 176.36,152.22 v2(176.36,152.43)
CPU_DP3_P1_C: length 1.9
  TOP w0.152: UM1.A6 19.15,137.06 19.15,136.28 19.38,136.05 19.38,135.81 CM14.1
CPU_DP3_P2: length 1.2
  TOP w0.152: v2(20.71,134.56) 20.79,134.63 20.79,134.95 CM16.2
  BOTTOM w0.076: v2(172.96,149.73) 172.96,149.78 UH1.F33
CPU_DP3_P2_C: length 1.8
  TOP w0.152: CM16.1 20.75,135.82 20.75,137.06 UM1.A4
CPU_DP3_P3: length 1.4
  TOP w0.152: v2(22.06,134.38) 22.28,134.6 22.28,134.94 CM18.2
  BOTTOM w0.076: UH1.C33 174.88,150.48 v2(174.88,150.59)
CPU_DP3_P3_C: length 1.8
  TOP w0.152: CM18.1 22.32,135.83 22.32,137.1 UM1.A2
CPU_ID: length 5.5
  TOP w0.089: RH5876.1 89.87,75.32 88.86,75.32 RH5875.2 88.62,75.11 87.73,75.11 v1(87.72,75.13) 87.49,75.13 86.97,74.6 86.82,74.6 v2(86.79,74.63)
  BOTTOM w0.089: v2(86.79,74.63) 86.8,74.64 86.8,74.82 86.37,75.24 UH2.AW24
CPU_TRIGGER: length 10.9
  TOP w0.14: v2(186.87,119.75) 186.87,120.29 189.34,122.76 189.34,127.65 189.48,127.79 RH192.1
  BOTTOM w0.089: UH2.AK2 96.28,79.7 96.66,79.7 v2(96.7,79.65)
  vias: v2(104.88,83.89)
CPU_TRIGGER_R: length 6.5
  TOP w0.14: v2(184.57,128.88) 185.04,129.35 186.32,129.35 v1(186.41,129.27) 188.35,129.27 188.9,129.81 RH192.2
  BOTTOM w0.076: UH1.J23 170.97,143.43 v2(171.6,143.43)
CPU_VCCIO_PWR_GATE#: length 6.9
  BOTTOM w0.089: UH2.AY3 95.73,74.81 96,75.08 98.34,75.08 98.6,75.33 RH5835.2 99.21,75.67 99.39,75.85 99.75,75.85
  BOTTOM w0.14: 99.75,75.85 101.42,75.85 T4949.1
CPU_XDP_TCK: length 7.8
  TOP w0.14: JXDP.57 127.11,166.7 127.43,167.02 127.81,167.02 v1(127.91,167.12) 128.17,167.38 128.42,167.38 v2(128.57,167.53) 128.44,167.67 128.17,167.67 127.99,167.85 RH491.2 RH498.2
  BOTTOM w0.076: v2(133.17,146.59) 133.54,146.22 134.98,146.22 135.23,146.47 135.58,146.47 UH1.BR28
CPU_XDP_TDI: length 6.9
  TOP w0.14: v2(137.13,165.32) 137.13,165.32 v1(137.62,164.83)
  BOTTOM w0.076: UH1.BL32 138.34,149.65 v2(138.15,149.46)
  BOTTOM w0.14: v2(137.13,165.32) 136.6,165.84 135.23,165.84 133.41,164.03 RH541.2 RH495.2
CPU_XDP_TDO: length 4.2
  TOP w0.14: v4(131.62,162.81) v2(130.99,163.44)
  BOTTOM w0.076: UH1.BT28 135.05,146.93 134.15,146.93 133.81,146.59 v2(133.81,146.59)
  BOTTOM w0.14: v2(130.99,163.44) 131.43,163.89 RH496.2 RH540.2
CPU_XDP_TMS: length 8.6
  TOP w0.14: v2(131.97,146.59) v4(131.97,147.2)
  BOTTOM w0.076: UH1.BP28 136.18,147.1 132.78,147.1 132.67,146.98 132.41,146.98 132.38,146.96
  BOTTOM w0.127: 132.36,146.96 132.34,146.96 v2(131.97,146.59)
  BOTTOM w0.14: 129.44,164.05 128.93,164.56 v2(128.93,165.78) ; 129.44,164.05 RH542.2 ; 129.44,164.05 RH494.2 ; 132.36,146.96 132.36,146.96 132.38,146.96
CPU_XDP_TRST#: length 13.9
  TOP w0.14: v2(129.71,148.95) v4(129.13,148.95)
  BOTTOM w0.076: UH1.BP30 136.3,148.34 136.01,148.63 135.66,148.63 135.47,148.82 135.01,148.82 134.79,149.05 134.16,149.05 133.91,148.8 132.68,148.8 132.43,148.55 132.38,148.55
  BOTTOM w0.089: v2(97.22,78.48) 97.17,78.53 96.99,78.53 96.96,78.5 96.7,78.5 96.57,78.62 96.57,78.65 96.33,78.89 95.81,78.89 95.5,78.57 UH2.AM4
  BOTTOM w0.14: 132.38,148.55 130.27,148.55 129.87,148.95 v2(129.71,148.95) 129.34,148.95 129.17,149.12 RH497.2 128.3,148.6 127.48,148.6 126.94,148.06 RH543.2
  vias: v2(102.68,87.28)
CS_1.2V: length 3.7
  BOTTOM w0.14: PR601.2 285.47,93.31 v1(284.02,93.31)
  BOTTOM w0.203: PR601.2 285.84,94 286.03,94.19 PU600.13
CSCOMP_2PH: length 7.2
  TOP w0.14: v2(110.59,152.04) v1(109.75,152.04)
  TOP w0.203: PU1100.31 106.43,176.71 106.03,177.11 PC1126.1
  TOP w0.254: PC1126.1 PC1127.1 104.23,177.02 PR1143.2 104.17,176.22 PR1145.1 102.87,176.22 v2(102.67,176.42)
  BOTTOM w0.14: PH1102.1 v2(110.59,152.04)
CSCOMP_4PH: length 8.5
  TOP w0.14: v2(130.35,173.75) v4(130.35,173.08)
  TOP w0.203: PU1100.8 116.35,176.31 PC1125.2
  TOP w0.254: PC1124.1 117.48,176.55 v2(118.29,176.55) 118.37,176.47 PR1144.1 ; PC1124.1 117.27,176.34 117.27,175.84 PR1142.1 ; PC1124.1 PC1125.2
  BOTTOM w0.14: PH1101.1 131.11,173.73 130.84,174.01 130.61,174.01 v2(130.35,173.75)
CSIN_ISL88738: length 5.6
  TOP w0.203: 45.62,77.54 v1(45.98,77.9) 45.98,78.02 47.28,79.31 PU1900.14
  TOP w0.254: PC1912.1 45.47,76.03 PC1910.2 ; PC1910.2 45.62,77.06 45.62,77.54 ; PC1910.2 44.88,76.9 44.77,76.79 PR1902.2
CSIP_ISL88738: length 7.2
  TOP w0.14: v1(48.63,75.35) 47.42,76.56 PR1901.2
  TOP w0.203: PU1900.15 47.68,79.27 46.38,77.97 46.38,77.34
  TOP w0.254: PR1901.2 46.62,76.66 PC1910.1 ; 46.38,77.34 PC1910.1 ; PC1910.1 46.38,76.51 46.34,76.47 PC1911.1
CSN_1PH: length 10.2
  TOP w0.14: v2(103.56,151.53) v1(104.23,151.53)
  TOP w0.254: v2(112.83,167.91) 113.03,167.71 PR1103.1
  BOTTOM w0.14: v2(103.56,151.53) 103.63,151.45 PH1100.1 106.92,150.89 107.37,151.34 107.37,153.69 107.62,153.94 PL1704.3
CSN_1PH_R: length 6
  TOP w0.203: PU1100.48 111.21,172.13 111.96,171.38 v1(111.96,171.15) 112.66,170.45 PC1104.1
  TOP w0.254: PC1104.1 112.88,169.59 PC1105.1 PC1101.1 113.79,168.67 PR1103.2
CSON_ISL88738: length 5.9
  TOP w0.203: PC1942.1 41.33,84.04 43.08,84.04 v1(43.43,83.69) 43.92,83.2 PU1900.1
  TOP w0.254: PC1943.1 PR1935.1 40.59,84.22 40.67,84.3 PC1942.1
CSOP_ISL88738: length 5.7
  TOP w0.203: PU1900.2 43.5,82.8 42.93,83.38 v1(42.16,83.38) PC1942.2
  TOP w0.254: PC1942.2 40.44,83.38 40.36,83.46 PR1931.1 PC1938.1
CSP1_2PH: length 7.5
  TOP w0.14: 103.95,180.66 104.47,181.18 104.47,182.29 v1(104.1,182.66)
  TOP w0.203: PU1100.28 106.94,177.91 106.6,178.25 106.6,179.32 PC1134.2 105.51,180.41 104.76,180.41 104.71,180.46 104.15,180.46 103.95,180.66 PR1166.1
CSP1_4PH: length 8.1
  TOP w0.203: PU1100.11 114.05,177.51 114.8,178.26 v2(114.8,179.22)
  BOTTOM w0.254: PR1159.2 v1(117.7,180.61) 117.45,180.61 117.14,180.31 PR1160.2 PC1133.2 115.44,180.31 114.99,179.85 114.99,179.41 v2(114.8,179.22)
CSP2_4PH: length 9.4
  TOP w0.203: v2(114.35,179.6) 114.22,179.47 114.22,178.2 113.94,177.91 PU1100.12
  BOTTOM w0.254: PR1167.2 118.34,181.5 118.08,181.25 v1(116.05,181.25) PR1168.2 PC1135.2 114.17,179.77 v2(114.35,179.6)
CSP3_4PH: length 8.7
  TOP w0.203: PU1100.13 113.46,178.34 v2(113.46,178.96)
  BOTTOM w0.254: PR1169.2 117.61,176.01 v1(114.92,176.01) 113.64,177.28 PR1170.2 PC1136.2 113.46,178.38 v2(113.46,178.96)
CSP4_4PH: length 9.5
  TOP w0.14: v2(106.1,184.3) 106.05,184.24
  TOP w0.203: PC1137.2 106.86,182.64 107.49,182.01 107.49,179.6 108.01,179.08 PU1100.26
  TOP w0.254: PR1153.1 PC1137.2 PR1174.2 106.05,184.24 ; PR1171.2 119.35,178.83 v1(118.97,179.22) v2(118.16,179.22)
CSP_1PH: length 8.7
  TOP w0.203: PC1105.2 111.99,169.86 112.06,169.93 112.06,170.48 111.57,170.97 111.57,171.25 110.81,172.01 PU1100.47
  TOP w0.254: PC1105.2 PC1101.2 111.99,168.6 111.3,167.91 v2(111.05,167.91) 111.05,167.91 111.05,167.53 111.1,167.48 PR1100.2
  BOTTOM w0.254: PR1101.1 111.18,167.15 v1(111.05,167.28) v2(111.05,167.91)
CSREF_2PH: length 5.7
  TOP w0.14: PR1702.2 v2(109.27,149.37) v1(109.27,150.04)
  TOP w0.203: PC1134.1 PC1128.1 106.05,178.25 106.78,177.51 PU1100.29
  TOP w0.254: v2(104.44,179.98) 104.55,179.88 PC1134.1
CSREF_4PH: length 17
  TOP w0.14: PR1253.2 v2(148.13,172.61) ; PR1257.2 v2(155.75,172.61) v1(155.09,172.61) ; v2(132.89,172.99) PR1202.2 ; v2(140.51,172.61) PR1206.2
  TOP w0.203: PU1100.10 114.28,177.11 114.91,177.74 PC1123.2 115.95,178.07 v2(116.51,178.07)
  TOP w0.254: PC1137.1 PR1174.1 v2(104.44,183.53)
  BOTTOM w0.254: PR1160.1 PC1133.1 115.62,178.33 115.49,178.2 ; PC1136.1 115.49,178.2 ; PC1136.1 PR1170.1 ; PC1136.1 114.35,178.4 114.35,178.83 113.26,179.93 PC1135.1 PR1168.1 ; 115.49,178.2 115.62,178.07 v2(116.51,178.07)
CSSUM_2PH: length 7.2
  TOP w0.14: PR1149.2 102.88,178.78 v1(102.49,178.39)
  TOP w0.203: PU1100.30 106.6,177.11
  TOP w0.254: 106.6,177.11 105.69,178.02 PC1126.2 PC1127.2 103.56,178.78 PR1149.2 103.43,179.53 PR1151.1
CSSUM_4PH: length 11.8
  TOP w0.203: PC1125.1 116.33,177.39 115.66,176.71 PU1100.9
  TOP w0.254: PC1125.1 PC1124.2 117.4,178.15 PR1148.2 117.14,178.5 v2(117.14,178.83)
  BOTTOM w0.381: PR1150.2 v1(117.65,178.33) v2(117.14,178.83) ; PR1150.2 118.99,177.44 PR1155.2 PR1152.2 ; PR1150.2 PR1147.2
DAT_TP_SIO: length 16.6
  TOP w0.076: v2(293.93,85.68) 293.55,86.06 UE3.C12
  TOP w0.14: v4(198.84,79.93) 198.3,79.38 v2(198.3,79.14)
  BOTTOM w0.14: JTP.2 189.76,78.53 190.11,78.87 190.11,80.09 CE78.1 190.04,81.02 RE26.2 190.36,81.34 190.36,81.74 190.68,82.07 197.66,82.07 197.99,81.74 197.99,80.95 DE4.3 198.75,80.1 198.3,79.65 v2(198.3,79.14)
DCI_CLK: length 1.2
  TOP w0.089: v2(89.71,73.5) 89.59,73.38 T5991.1
  BOTTOM w0.089: UH2.BB16 89.38,73.8 89.67,73.5 v2(89.71,73.5)
DCI_DATA: length 1.5
  TOP w0.089: T5992.1 89.41,78.16 v2(89.04,78.53)
  BOTTOM w0.089: v2(89.04,78.53) 88.88,78.53 88.54,78.2 UH2.AN18
DCIN1_EN: length 26
  TOP w0.254: v2(25.76,68.85) 25.76,71.08 28.88,74.2 28.88,79.14 29.68,79.93 29.68,80.97 v1(29.48,81.17) 26.38,81.17 25.11,79.9 PR256.1 ; v2(115.53,75.37) 115.53,73.72 116.08,73.17 116.08,72.91 116.56,72.42 v2(116.56,70.98) ; v2(299.52,79.27) UE3.K4
DCIN2_EN: length 1.8
  TOP w0.076: v2(299.52,86.44) 299.9,86.06 UE3.L12
  TOP w0.14: PR221.1 16.76,97.29 v2(16.53,97.05)
  vias: v2(134.57,78.5)
DDC_CLK_HDMI: length 2.2
  TOP w0.14: RM1.1 24.38,140.79 24.11,140.79 v2(23.93,140.61) 23.74,140.79 23.21,140.79 UM1.E1
DDC_DAT_HDMI: length 2.2
  TOP w0.14: UM1.F1 23.16,141.06 23.74,141.06 v2(23.93,141.24) 24.11,141.06 24.38,141.06 RM2.1
DDI1_DDPB_CTRLCLK: length 11.6
  TOP w0.089: v2(91,79.82) 90.9,79.72 90.9,78.94 v5(91.1,78.75) 91.45,78.39 93.08,78.39 93.32,78.62 94.79,78.62 95,78.42 96.76,78.42 97.07,78.11 98.13,78.11 98.27,78.25 99.2,78.25 99.39,78.44 RP1.3
  BOTTOM w0.089: UH2.AL13 90.87,79.53 90.87,79.79 90.89,79.82 v2(91,79.82)
  BOTTOM w0.102: UT1.Y5 28.66,109.84 28.36,110.14 v2(28.36,110.15)
DDI1_DDPB_CTRLDAT: length 16.9
  TOP w0.089: v2(90.45,79.84) 90.63,79.66 90.63,78.83 91.34,78.12 93.19,78.12 93.43,78.36 94.68,78.36 94.89,78.15 v5(95.26,78.15) 96.65,78.15 96.96,77.84 98.24,77.84 98.38,77.98 99.35,77.98 99.39,77.94 RP1.4
  BOTTOM w0.089: v2(90.45,79.84) 90.45,79.95 90.73,80.22 91.87,80.22 92.62,79.47 92.96,79.47 93.22,79.21 93.22,77.99 93.4,77.81 93.4,77.25 UH2.AR8
  BOTTOM w0.102: v2(25.77,110.17) UT1.R4
DDI2_DDPC_CTRLCLK: length 10.8
  TOP w0.089: RP1.1 99.3,79.44 99.19,79.33 98.54,79.33 98.45,79.24 96.33,79.24 95.5,80.07 v5(94.15,80.07) 93.82,80.07 93.16,79.41 92.14,79.41 91.86,79.12 91.86,78.97 v2(91.66,78.77)
  BOTTOM w0.089: v2(91.66,78.77) 91.43,78.54 91.1,78.54 90.8,78.24 UH2.AN13
  BOTTOM w0.102: v6(29.01,108.21) 29.01,108.23 28.7,108.54 UT1.Y8
DDI2_DDPC_CTRLDAT: length 10.4
  TOP w0.089: RP1.2 99.3,78.94 99.19,79.06 98.65,79.06 98.56,78.97 v5(98.01,78.97) 96.22,78.97 95.39,79.8 93.93,79.8 93.27,79.14 92.25,79.14 92.13,79.01 92.13,78.94 v2(92.3,78.76)
  BOTTOM w0.089: UH2.AL10 92.19,78.87 v2(92.3,78.76)
  BOTTOM w0.102: v2(25.13,109.53) 25.12,109.54 25.12,110.17 UT1.N4
DDI3_DDPD_CTRLCLK: length 13
  TOP w0.089: v2(93.16,75.59) 92.9,75.34 90.54,75.34 89.92,75.96 v1(89.7,75.96) 88.99,75.96 87.89,77.06 87.35,77.06 86.56,77.85 86.05,77.85 85.32,78.58 RH1145.1
  BOTTOM w0.089: v2(93.16,75.59) 93.22,75.65 93.22,77.74 92.93,78.03 UH2.AL9
DDI3_DDPD_CTRLDAT: length 5.4
  BOTTOM w0.089: 98.88,77.24 98.88,77.57 98.64,77.81 97.66,77.81 97.19,77.34 96.11,77.34 95.78,77 UH2.AR3
  BOTTOM w0.14: 98.88,77.24 99.17,76.94 v1(99.26,76.94) 100,76.94 RH1146.1
DDR4_DRAMRST#: length 5.5
  TOP w0.14: v2(132.16,85.06) 132.09,84.99 RD31.1 CD3326.1 CD3327.1
  BOTTOM w0.102: v2(208.66,85.04) 208.19,85.51 JDIMM2.108 ; v2(132.16,85.06) 131.89,85.34 JDIMM1.108
DDR_A_ACT#: length 7.3
  BOTTOM w0.076: UH1.AU3 148.6,128.15 148.6,127.97 148.52,127.9 148.31,127.9 148.24,127.82 148.24,126.8 148.35,126.69 148.35,125.71 v2(147.82,125.18)
  BOTTOM w0.221: JDIMM1.114 133.39,87.53 133.02,87.9 133.02,89.11 v2(133.55,89.64)
DDR_A_ALERT#: length 5.9
  BOTTOM w0.076: v2(147.38,126.06) 147.38,126.29 147.91,126.81 147.91,128.92 UH1.AU5
  BOTTOM w0.221: v2(133.53,88.2) 133.53,88.13 133.89,87.77 JDIMM1.116
DDR_A_BG0: length 14.1
  BOTTOM w0.076: UH1.AU1 148.52,126.36 148.52,126.36 148.52,125.37 147.16,124.01 146.87,124.01 144.74,121.88 v2(144.74,121.21)
  BOTTOM w0.221: JDIMM1.115 133.64,93.25 133.04,92.65 133.04,90.29 132.2,89.45 132.2,89.17 v2(131.7,88.67)
DDR_A_BG1: length 12.2
  BOTTOM w0.076: v2(145.49,122.1) 146.32,122.93 146.32,122.94 148.8,125.42 148.8,127.05 148.52,127.33 UH1.AU2
  BOTTOM w0.221: JDIMM1.113 133.14,93.6 132.51,92.98 132.51,90.65 131.82,89.96 v2(131.7,89.96)
DDR_A_BS0: length 9.4
  BOTTOM w0.076: v2(155.17,125.81) 155.57,126.2 155.57,129.33 155.76,129.53 UH1.AH5
  BOTTOM w0.221: JDIMM1.150 144.4,87.55 145.08,88.23 145.08,89.34 145.24,89.5 145.24,90.04 145.11,90.17 v2(144.23,90.17)
DDR_A_BS1: length 6.8
  BOTTOM w0.076: v2(155.17,123.84) 156.06,124.73 UH1.AH1
  BOTTOM w0.221: JDIMM1.145 143.14,93.7 142.57,93.13 v2(142.57,91.44)
DDR_A_CAS#: length 11.7
  BOTTOM w0.076: v2(158.34,120.99) 158.34,122.11 159.46,123.24 159.46,126.78 UH1.AD1
  BOTTOM w0.221: v2(148.5,90.14) 148.35,90.14 147.79,89.57 147.79,88.9 147.14,88.25 146.66,88.25 145.9,87.5 145.9,87.43 JDIMM1.156
DDR_A_D0: length 7.4
  BOTTOM w0.076: UH1.BR6 135.78,130.22 134.95,130.22 134.9,130.17 134.55,130.17 134.47,130.25 133.82,130.25 133.3,129.73 v2(133.3,129.09)
  BOTTOM w0.14: JDIMM1.8 106.89,88.41 105.77,89.52 v2(105.59,89.52)
DDR_A_D1: length 3.7
  BOTTOM w0.076: UH1.BT6 v2(134.7,130.52)
  BOTTOM w0.14: JDIMM1.7 106.64,93.53 105.84,92.73 105.84,92.59 105.38,92.13 v2(105.13,92.13)
DDR_A_D2: length 7.4
  BOTTOM w0.076: UH1.BP3 136.29,128.63 135.74,128.63 135.71,128.61 134.96,128.61 134.78,128.43 134.45,128.43 134.15,128.13 v2(134.15,127.59)
  BOTTOM w0.14: v2(107.95,89.78) 109.13,88.6 109.13,88.24 109.89,87.49 JDIMM1.20
DDR_A_D3: length 9.6
  BOTTOM w0.076: UH1.BN3 137,128.09 136.1,128.09 135.99,127.98 135.77,127.98 135.58,127.78 135.56,127.75 135.56,127.4 135.56,127.3 134.98,126.73 133.98,126.73 133.43,126.18 v2(133.03,126.18)
  BOTTOM w0.14: JDIMM1.21 110.14,93.69 108.48,92.03 108.48,91.59 v2(107.95,91.05)
DDR_A_D4: length 8.3
  BOTTOM w0.076: v2(132.88,128.74) 132.88,129.54 133.75,130.41 134.08,130.41 134.55,130.88 135.55,130.88 135.7,130.72 136.47,130.72 136.85,130.34 136.85,129.88 UH1.BN5
  BOTTOM w0.14: JDIMM1.4 105.89,87.95 v2(105.59,88.25)
DDR_A_D5: length 5.1
  BOTTOM w0.076: UH1.BP6 136.56,130.22 136.17,129.83 135.76,129.83 135.68,129.91 135.64,129.91 135.49,130.06 135.08,130.06 135.02,130 134.48,130 134.4,130.08 133.89,130.08 133.69,129.89 v2(133.69,129.49)
  BOTTOM w0.14: v2(105.17,93.31) 105.64,93.78 JDIMM1.3
DDR_A_D6: length 8.3
  BOTTOM w0.076: UH1.BP2 136.84,127.48 136.84,126.79 136.64,126.6 136.56,126.6 135.9,125.94 135.63,125.94 134.64,124.95 v2(132.97,124.95)
  BOTTOM w0.14: JDIMM1.16 108.89,87.5 107.95,88.44 v2(107.95,88.51)
DDR_A_D7: length 5.4
  BOTTOM w0.076: v2(133.86,127.13) 133.91,127.17 134.26,127.17 134.93,127.84 135.35,127.84 135.82,128.31 UH1.BR3
  BOTTOM w0.14: JDIMM1.17 109.14,93.18 108.29,92.32 v2(107.95,92.32)
DDR_A_D8: length 4.9
  BOTTOM w0.089: UH1.BK5 139.27,129.53 v2(139.65,129.15)
  BOTTOM w0.14: JDIMM1.28 111.89,87.21 111.7,87.4 111.55,87.4 110.61,88.35 110.61,89.48 v2(110.18,89.91)
DDR_A_D9: length 4.7
  BOTTOM w0.076: v2(138.85,128.55) 138.53,128.88 UH1.BL4
  BOTTOM w0.14: v2(110.18,91.18) 112.14,93.14 JDIMM1.29
DDR_A_D10: length 7.7
  BOTTOM w0.076: UH1.BL2 138.17,127.58 137.58,126.99 137.58,126.76 137.38,126.56 136.95,126.56 136.26,125.87 v2(136.26,125.22)
  BOTTOM w0.14: v2(113.41,91.18) 114.25,92.02 114.25,92.79 115.14,93.68 JDIMM1.41
DDR_A_D11: length 6.5
  BOTTOM w0.076: UH1.BM1 137.98,126.93 137.45,126.4 137.02,126.4 136.71,126.09 v2(136.71,125.62)
  BOTTOM w0.14: JDIMM1.42 115.39,87.61 114.39,88.61 114.39,88.93 v2(113.41,89.91)
DDR_A_D12: length 3.1
  BOTTOM w0.076: UH1.BK4 v2(139.64,128.55)
  BOTTOM w0.14: v2(110.18,88.64) 110.18,88.29 110.89,87.58 JDIMM1.24
DDR_A_D13: length 3
  BOTTOM w0.076: UH1.BL5 138.53,129.53 v2(138.85,129.2)
  BOTTOM w0.14: v2(110.18,92.45) 111.14,93.41 JDIMM1.25
DDR_A_D14: length 4.1
  BOTTOM w0.076: UH1.BK1 138.66,126.93 138.12,126.39 138.01,126.39 v2(137.78,126.15)
  BOTTOM w0.14: v2(113.41,88.64) 114.39,87.66 JDIMM1.38
DDR_A_D15: length 10.7
  BOTTOM w0.076: UH1.BK2 139.53,127.3 139.53,126.33 135.94,122.75 134.64,122.75 v2(134.25,123.13)
  BOTTOM w0.14: JDIMM1.37 114.14,93.18 v2(113.41,92.45)
DDR_A_D16: length 9.9
  BOTTOM w0.076: v2(139.26,125.3) 139.92,125.3 140.57,125.94 140.57,126.51 140.5,126.57 140.5,127.16 140.58,127.23 140.58,128.35 140.82,128.59 141.1,128.59 141.27,128.77 141.27,129.23 UH1.BG5
  BOTTOM w0.14: v2(115.77,89.78) 116.73,88.83 116.73,88.02 117.39,87.36 JDIMM1.50
DDR_A_D17: length 9.1
  BOTTOM w0.076: v2(138.03,123.95) 139.12,123.95 139.85,124.68 140.08,124.68 141.06,125.66 141.06,126.71 140.97,126.8 UH1.BG1
  BOTTOM w0.14: JDIMM1.49 117.14,93.6 116.2,92.67 116.2,91.49 v2(115.77,91.05)
DDR_A_D18: length 4.8
  BOTTOM w0.076: v2(142.16,127.25) 141.83,127.58 UH1.BF2
  BOTTOM w0.14: v2(118.51,89.78) 119.17,89.13 119.17,88.46 120.39,87.23 JDIMM1.62
DDR_A_D19: length 4.9
  BOTTOM w0.076: v2(142.16,129.2) 141.83,129.53 UH1.BF5
  BOTTOM w0.14: JDIMM1.63 120.64,93.18 v2(118.51,91.05)
DDR_A_D20: length 6.6
  BOTTOM w0.076: UH1.BG4 140.74,128.88 140.38,128.51 140.38,127.32 140.27,127.22 140.27,126.49 140.4,126.37 140.4,126.01 140.14,125.75 v2(139.65,125.75)
  BOTTOM w0.14: JDIMM1.46 116.39,87.89 v2(115.77,88.51)
DDR_A_D21: length 7.3
  BOTTOM w0.076: v2(138.48,124.4) 139.03,124.4 139.6,124.96 140.08,124.96 140.86,125.75 140.86,126.52 140.67,126.71 140.67,127.04 140.78,127.15 140.78,127.39 UH1.BG2
  BOTTOM w0.14: JDIMM1.45 116.14,93.09 115.77,92.72 v2(115.77,92.32)
DDR_A_D22: length 3.1
  BOTTOM w0.076: UH1.BF1 141.83,126.93 v2(142.16,126.6)
  BOTTOM w0.14: v2(118.51,88.51) 119.39,87.64 JDIMM1.58
DDR_A_D23: length 3.2
  BOTTOM w0.076: UH1.BF4 141.87,128.88 v2(142.14,128.6)
  BOTTOM w0.14: v2(118.51,92.32) 119.64,93.45 JDIMM1.59
DDR_A_D24: length 9.4
  BOTTOM w0.076: UH1.BD2 143.49,127.34 143.21,127.06 143.21,126.68 143.27,126.62 143.27,125.43 142.46,124.62 142,124.62 141.37,123.98 v2(140.81,123.98)
  BOTTOM w0.14: v2(120.92,89.78) 121.64,89.07 121.64,88.04 122.39,87.29 JDIMM1.70
DDR_A_D25: length 9.8
  BOTTOM w0.076: UH1.BD1 143.49,125.04 142.73,124.28 142.24,124.28 141.49,123.53 v2(140.36,123.53)
  BOTTOM w0.14: JDIMM1.71 122.64,92.77 v2(120.92,91.05)
DDR_A_D26: length 4.7
  BOTTOM w0.076: v2(144.72,128.55) 144.4,128.88 UH1.BC4
  BOTTOM w0.14: v2(124.18,91.05) 125.64,92.52 JDIMM1.83
DDR_A_D27: length 4.8
  BOTTOM w0.076: UH1.BC5 144.41,129.53 v2(144.73,129.2)
  BOTTOM w0.14: v2(124.18,89.78) 125.43,88.54 125.43,87.98 125.89,87.52 JDIMM1.84
DDR_A_D28: length 7.1
  BOTTOM w0.076: v2(142.16,125.33) 142.53,125.71 142.53,125.92 142.85,126.23 142.85,126.78 142.88,126.81 142.88,127.39 142.97,127.48 142.97,129.01 UH1.BD5
  BOTTOM w0.14: v2(120.92,88.51) 120.99,88.45 120.99,87.72 121.39,87.32 JDIMM1.66
DDR_A_D29: length 7.6
  BOTTOM w0.076: UH1.BD4 143.2,128.59 143.2,127.39 143.04,127.23 143.04,126.52 143.11,126.46 143.11,125.72 142.27,124.88 v2(141.71,124.88)
  BOTTOM w0.14: v2(120.92,92.32) 121.64,93.04 JDIMM1.67
DDR_A_D30: length 3.1
  BOTTOM w0.076: UH1.BC1 144.42,126.93 v2(144.76,126.59)
  BOTTOM w0.14: v2(124.18,92.32) 124.64,92.79 JDIMM1.79
DDR_A_D31: length 3.1
  BOTTOM w0.076: v2(144.72,127.25) 144.4,127.58 UH1.BC2
  BOTTOM w0.14: JDIMM1.80 124.9,87.58 124.9,87.79 v2(124.18,88.51)
DDR_A_D32: length 6.3
  BOTTOM w0.076: v2(160.68,123.32) 161.11,123.74 161.11,126.91 UH1.AB1
  BOTTOM w0.14: v2(151.05,88.62) 150.39,87.95 JDIMM1.174
DDR_A_D33: length 8.4
  BOTTOM w0.076: UH1.AB2 160.94,127.58 160.81,127.45 160.81,126.81 160.94,126.68 160.94,123.96 160.82,123.84 160.32,123.84 160.18,123.99 v2(160.18,124.12)
  BOTTOM w0.14: v2(151.05,92.43) 150.83,92.2 150.49,92.2 150.14,92.56 150.14,92.8 150.28,92.94 150.33,92.94 150.46,93.06 150.46,93.29 150.33,93.42 150.27,93.42 150.14,93.55 JDIMM1.173
DDR_A_D34: length 3.3
  BOTTOM w0.076: v2(162.27,128.55) 161.94,128.88 UH1.AA4
  BOTTOM w0.14: v2(154.23,92.43) 154.09,92.29 153.92,92.29 153.78,92.43 153.78,93.43 153.64,93.58 JDIMM1.187
DDR_A_D35: length 3.2
  BOTTOM w0.076: UH1.AA5 v2(162.26,129.1)
  BOTTOM w0.14: v2(154.23,88.62) 153.39,87.78 JDIMM1.186
DDR_A_D36: length 8.4
  BOTTOM w0.076: UH1.AB5 160.48,128.92 160.48,126.62 160.56,126.54 160.56,126.19 v2(160.2,125.84)
  BOTTOM w0.14: v2(151.05,89.89) 149.39,88.22 JDIMM1.170
DDR_A_D37: length 9.6
  BOTTOM w0.076: v2(160.2,125.29) 160.65,125.29 160.72,125.36 160.72,126.63 160.65,126.71 160.65,128.79 160.74,128.88 UH1.AB4
  BOTTOM w0.14: JDIMM1.169 149.14,91.54 149.52,91.16 v2(151.05,91.16)
DDR_A_D38: length 4.9
  BOTTOM w0.076: UH1.AA2 162.05,127.58 v2(162.28,127.35)
  BOTTOM w0.14: v2(154.23,91.16) 153.74,91.16 153.61,91.29 153.61,91.93 153.33,92.21 153.33,92.83 152.64,93.51 JDIMM1.183
DDR_A_D39: length 4.8
  BOTTOM w0.076: v2(162.27,126.74) 162.08,126.93 UH1.AA1
  BOTTOM w0.14: JDIMM1.182 152.39,87.21 152.81,87.63 152.81,88.46 v2(154.23,89.89)
DDR_A_D40: length 9.9
  BOTTOM w0.076: UH1.V4 163.28,128.88 163.16,128.76 163.16,127.39 163.16,124.93 162.95,124.73 v2(162.27,124.73)
  BOTTOM w0.14: v2(156.64,92.43) 155.76,92.43 155.64,92.54 155.64,92.67 155.78,92.81 156.43,92.81 156.55,92.94 156.55,93.24 156.43,93.37 155.78,93.37 155.64,93.51 JDIMM1.195
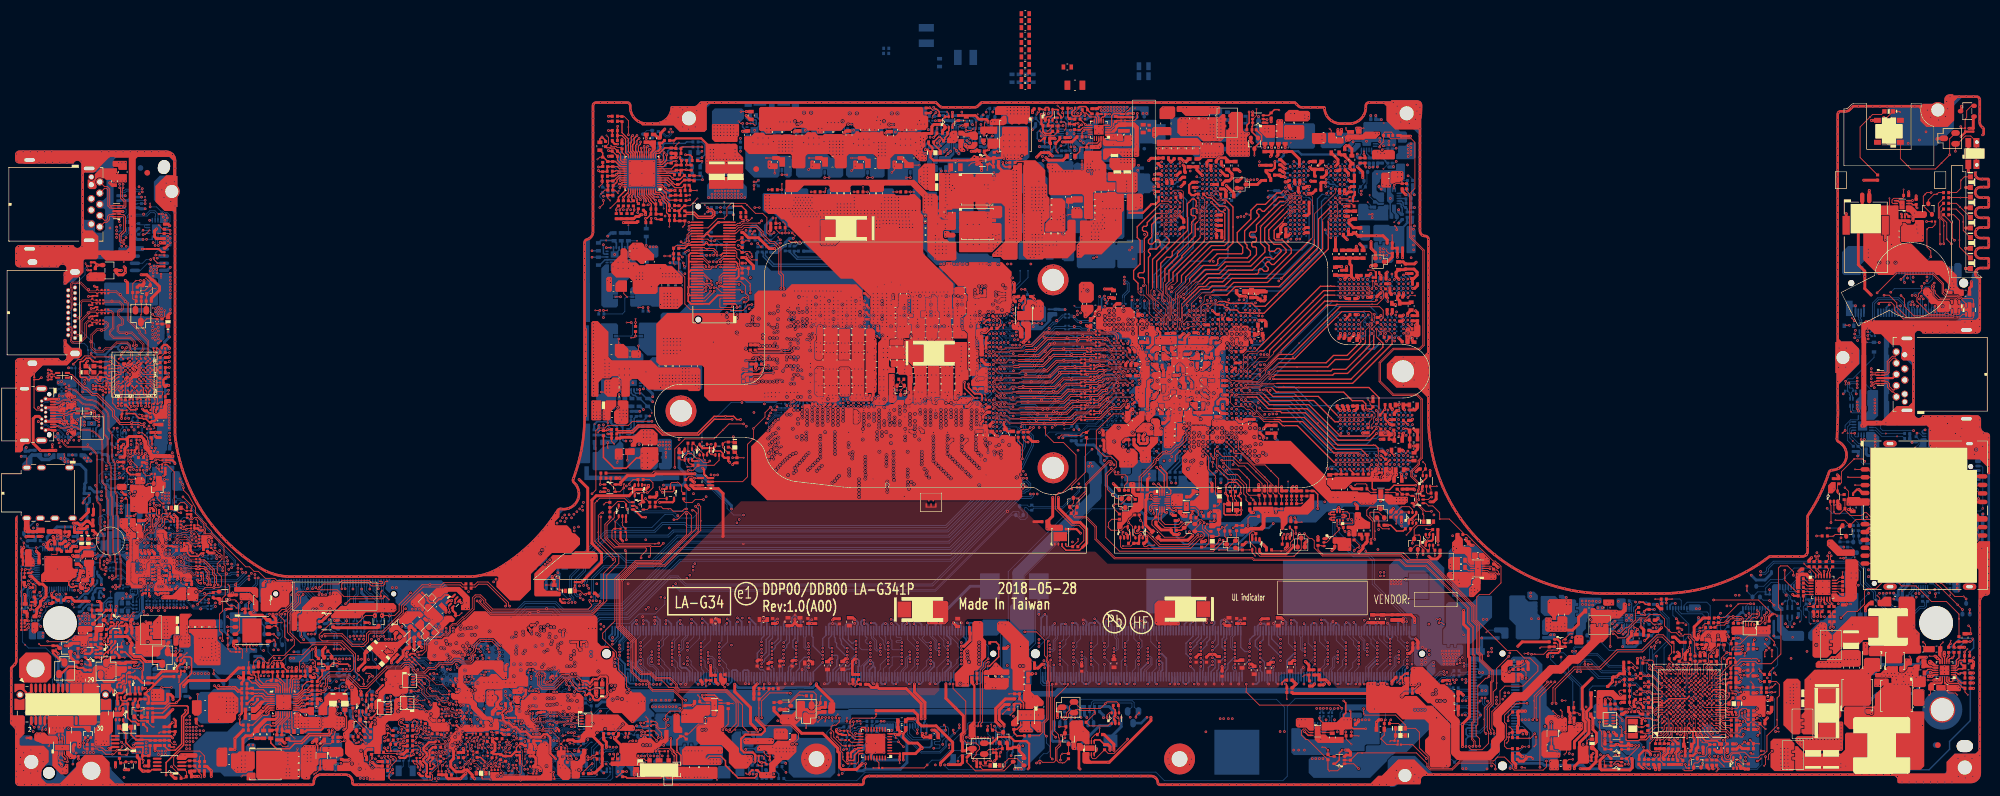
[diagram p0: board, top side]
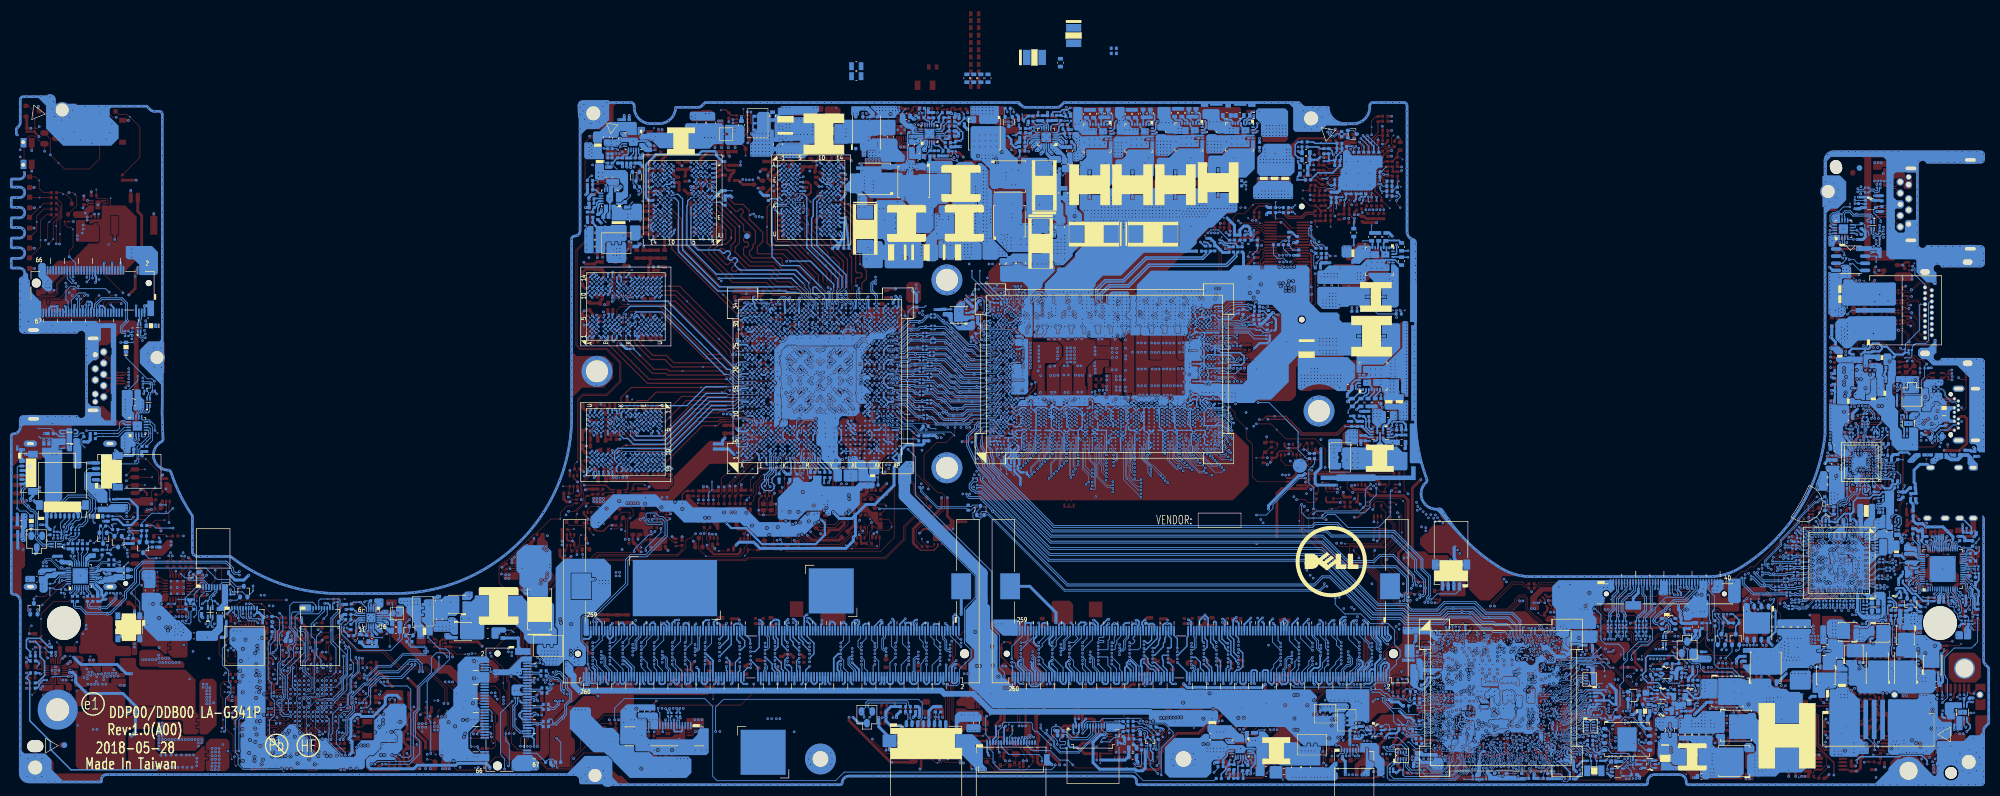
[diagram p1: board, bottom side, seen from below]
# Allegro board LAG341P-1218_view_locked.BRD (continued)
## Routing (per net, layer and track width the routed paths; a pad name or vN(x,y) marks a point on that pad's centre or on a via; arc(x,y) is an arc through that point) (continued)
DDR_A_D41: length 6.3
  BOTTOM w0.076: UH1.V1 163.6,123.39 v2(163.62,123.38)
  BOTTOM w0.14: v2(156.64,88.62) 155.39,87.36 JDIMM1.194
DDR_A_D42: length 3
  BOTTOM w0.076: UH1.U5 164.46,129.53 v2(164.79,129.2)
  BOTTOM w0.14: v2(159.43,92.43) 158.64,93.22 JDIMM1.207
DDR_A_D43: length 3
  BOTTOM w0.076: UH1.U1 164.56,126.93 v2(164.77,126.71)
  BOTTOM w0.14: v2(159.43,88.62) 159.43,87.81 158.89,87.26 JDIMM1.208
DDR_A_D44: length 9.9
  BOTTOM w0.076: UH1.V5 162.99,128.92 162.99,128.76 162.99,128.76 162.99,128.34 162.99,128.34 162.99,128.11 162.99,128.11 162.99,127.69 162.99,127.69 162.99,127.46 162.99,127.46 162.99,127.04 162.99,127.04 162.99,126.09 162.27,125.36 v2(162.27,125.36)
  BOTTOM w0.14: JDIMM1.191 154.64,93.07 154.89,92.82 154.89,91.28 155.02,91.16 v2(156.64,91.16)
DDR_A_D45: length 9.3
  BOTTOM w0.076: v2(163.17,123.83) 163.33,123.98 163.33,127.3 UH1.V2
  BOTTOM w0.14: v2(156.64,89.89) 155.05,89.89 154.92,89.76 154.92,88.39 154.52,87.99 154.52,87.98 154.39,87.86 JDIMM1.190
DDR_A_D46: length 4.7
  BOTTOM w0.076: UH1.U4 164.46,128.88 v2(164.79,128.55)
  BOTTOM w0.14: JDIMM1.203 157.64,92.95 v2(159.43,91.16)
DDR_A_D47: length 4.8
  BOTTOM w0.076: UH1.U2 164.49,127.58 v2(164.79,127.28)
  BOTTOM w0.14: v2(159.43,89.89) 158.94,89.39 158.94,88.27 157.89,87.21 JDIMM1.204
DDR_A_D48: length 6.2
  BOTTOM w0.076: v2(166.98,123.76) 166.98,124.71 166.4,125.29 166.4,125.95 166.12,126.23 UH1.R1
  BOTTOM w0.14: JDIMM1.216 160.89,87.27 161.77,88.15 v2(161.77,88.62)
DDR_A_D49: length 8
  BOTTOM w0.076: UH1.R4 166.02,128.97 165.8,128.97 165.67,128.85 165.67,126.04 165.98,125.74 165.98,125.18 165.87,125.07 v2(165.68,125.07)
  BOTTOM w0.14: v2(161.77,92.43) 160.99,92.43 160.27,93.14 160.27,93.27 160.64,93.63 JDIMM1.215
DDR_A_D50: length 3.2
  BOTTOM w0.076: UH1.P1 166.98,126.93 v2(167.3,126.61)
  BOTTOM w0.14: v2(164.82,88.62) 163.89,87.69 JDIMM1.228
DDR_A_D51: length 3
  BOTTOM w0.076: v2(167.3,129.2) 166.98,129.53 UH1.P5
  BOTTOM w0.14: JDIMM1.229 164.14,93.23 164.82,92.55 v2(164.82,92.43)
DDR_A_D52: length 8.6
  BOTTOM w0.076: v2(165.23,125.52) 165.23,125.98 165.51,126.26 165.51,128.92 UH1.R5
  BOTTOM w0.14: v2(161.77,91.16) 159.64,93.29 JDIMM1.211
DDR_A_D53: length 8.2
  BOTTOM w0.076: UH1.R2 165.84,127.3 165.84,126.74 165.9,126.68 165.9,126.04 166.14,125.8 166.14,125.17 166.58,124.73 v2(166.58,124.17)
  BOTTOM w0.14: JDIMM1.212 159.89,87.14 161.01,88.26 161.01,89.13 v2(161.77,89.89)
DDR_A_D54: length 4.9
  BOTTOM w0.076: v2(167.3,127.25) 166.98,127.58 UH1.P2
  BOTTOM w0.14: v2(164.82,89.89) 162.89,87.96 JDIMM1.224
DDR_A_D55: length 4.7
  BOTTOM w0.076: UH1.P4 166.98,128.88 v2(167.3,128.55)
  BOTTOM w0.14: JDIMM1.225 163.14,93.72 164.11,92.75 164.11,91.87 v2(164.82,91.16)
DDR_A_D56: length 6.6
  BOTTOM w0.076: v2(168.64,125.25) 168.64,125.87 168.39,126.12 168.39,126.37 168.19,126.58 168.19,128.43 UH1.M4
  BOTTOM w0.14: v2(167.23,92.43) 166.14,93.52 JDIMM1.237
DDR_A_D57: length 6.5
  BOTTOM w0.076: v2(169.99,123.9) 169.99,124.87 169.33,125.54 169.33,125.8 168.75,126.39 168.75,126.54 168.63,126.66 UH1.M1
  BOTTOM w0.14: JDIMM1.236 165.89,87.47 167.03,88.62 v2(167.23,88.62)
DDR_A_D58: length 3.7
  BOTTOM w0.089: v2(169.83,128.58) 169.67,128.58 UH1.L4
  BOTTOM w0.14: JDIMM1.249 169.14,92.91 169.62,92.43 v2(170.41,92.43)
DDR_A_D59: length 3.2
  BOTTOM w0.089: UH1.L1 169.59,126.7 v2(169.82,126.7)
  BOTTOM w0.14: JDIMM1.250 169.39,87.36 170.41,88.38 v2(170.41,88.62)
DDR_A_D60: length 8.8
  BOTTOM w0.076: v2(168.19,125.7) 168.19,126.27 168.02,126.44 168.02,128.92 UH1.M5
  BOTTOM w0.14: JDIMM1.232 164.89,87.25 166.45,88.81 166.45,89.35 166.98,89.89 v2(167.23,89.89)
DDR_A_D61: length 8.1
  BOTTOM w0.076: v2(169.54,124.35) 169.54,124.94 169.05,125.44 169.05,125.78 168.56,126.27 168.56,126.44 168.35,126.64 168.35,127.3 UH1.M2
  BOTTOM w0.14: JDIMM1.233 165.14,93.66 166.61,92.19 166.61,91.78 v2(167.23,91.16)
DDR_A_D62: length 4.9
  BOTTOM w0.089: UH1.L5 169.45,129.53 v2(169.82,129.15)
  BOTTOM w0.14: v2(170.41,91.16) 168.14,93.42 JDIMM1.245
DDR_A_D63: length 5.1
  BOTTOM w0.089: v2(169.81,127.25) 169.7,127.25 UH1.L2
  BOTTOM w0.14: v2(170.41,89.89) 169.98,89.46 169.98,88.44 168.96,87.42 168.71,87.42 168.39,87.1 JDIMM1.246
DDR_A_DQS0: length 8.8
  BOTTOM w0.076: UH1.BP5 136.45,129.3 136.1,129.65 135.67,129.65 135.45,129.43 134.46,129.43 134.26,129.23 133.94,129.23 133.64,128.93 133.64,128.29 133.54,128.19 v2(133.54,128.15)
  BOTTOM w0.14: v2(106.42,90.74) 106.58,90.9 106.81,90.9 107.18,91.26 107.18,92.48 108,93.3 108,93.59 108.14,93.73 JDIMM1.13
DDR_A_DQS1: length 12.2
  BOTTOM w0.076: UH1.BK3 138.95,127.94 138.95,127.46 139.32,127.1 139.32,126.64 136.46,123.78 135.53,123.78 135.31,124 v2(135,124)
  BOTTOM w0.14: JDIMM1.34 113.39,87.23 113.32,87.3 113.32,87.61 112.41,88.52 111.96,88.52 111.71,88.77 111.71,89.49 111.97,89.75 111.98,89.75 v2(112.14,89.59)
DDR_A_DQS2: length 12.9
  BOTTOM w0.076: UH1.BF3 141.59,128.11 141.59,127.87 141.43,127.72 141.43,126.64 141.7,126.37 141.7,125.64 138.68,122.61 137.41,122.61 v2(137.4,122.6)
  BOTTOM w0.14: JDIMM1.55 118.64,93.78 118.54,93.69 118.54,93.46 117.78,92.7 117.78,91.34 117.4,90.96 117.26,90.96 v2(117.04,90.74)
DDR_A_DQS3: length 11.5
  BOTTOM w0.076: UH1.BC3 144.11,128.11 144.11,128.07 143.94,127.9 143.94,126.79 144.25,126.49 144.25,124.77 142.73,123.24 142.43,123.24 142.24,123.43 v2(141.95,123.43)
  BOTTOM w0.14: JDIMM1.76 123.89,87.2 123.79,87.3 123.79,87.68 123.41,88.06 123.41,89.44 122.92,89.93 122.37,89.93 v2(122.19,90.1)
DDR_A_DQS4: length 11.2
  BOTTOM w0.076: UH1.AB3 161.25,128.23 161.38,128.1 161.38,126.56 161.53,126.41 161.53,122.32 161.33,122.12 161.18,122.12 v2(161.03,122.28)
  BOTTOM w0.14: v2(152.83,91.47) 152.83,91.39 152.68,91.24 152.3,91.24 152.15,91.39 152.15,92.77 151.55,93.37 151.55,93.55 151.64,93.64 JDIMM1.179
DDR_A_DQS5: length 10.8
  BOTTOM w0.076: v2(164.52,122.48) 164.79,122.48 164.94,122.62 164.94,124.2 164,125.14 164,126.51 163.9,126.61 163.9,128.14 163.81,128.23 UH1.V3
  BOTTOM w0.14: v2(158.09,89.57) 157.98,89.68 157.82,89.68 157.65,89.5 157.65,88.1 156.89,87.34 JDIMM1.200
DDR_A_DQS6: length 11.3
  BOTTOM w0.076: v2(167.99,122.82) 168.12,122.69 168.27,122.69 168.45,122.87 168.45,123.52 167.05,124.93 167.05,125.76 166.41,126.39 166.41,128.04 166.51,128.14 166.51,128.22 166.43,128.3 166.19,128.3 UH1.R3
  BOTTOM w0.14: v2(163.3,91.47) 163.12,91.3 162.99,91.3 162.86,91.43 162.86,92.81 162.1,93.57 162.1,93.63 162.14,93.66 JDIMM1.221
DDR_A_DQS7: length 7.8
  BOTTOM w0.076: UH1.M3 168.93,127.94 168.93,126.69 169.05,126.56 169.05,126.39 169.9,125.54 170.3,125.54 170.46,125.7 v2(170.72,125.7)
  BOTTOM w0.14: JDIMM1.242 167.39,87.25 168.15,88.01 168.15,89.41 v2(168.34,89.6)
DDR_A_DQS#0: length 8.4
  BOTTOM w0.076: UH1.BR5 135.8,129.03 135.8,128.92 135.9,128.82 136.2,128.82 136.29,128.91 136.29,129.09 136.2,129.18 136.2,129.27 136.01,129.46 135.76,129.46 135.56,129.26 134.54,129.26 134.31,129.04 134.02,129.04 133.83,128.85 133.83,128.67 133.93,128.56 v2(134.01,128.56)
  BOTTOM w0.14: JDIMM1.11 107.64,93.72 107.7,93.67 107.7,93.43 106.87,92.6 106.87,91.39 106.68,91.2 106.59,91.2 v2(106.42,91.37)
DDR_A_DQS#1: length 12.2
  BOTTOM w0.076: v2(135.45,124.45) 135.45,124.2 135.63,124.02 136.36,124.02 139.14,126.8 139.14,127.03 138.76,127.41 138.76,128.04 138.78,128.07 138.62,128.23 UH1.BL3
  BOTTOM w0.14: v2(112.14,90.23) 111.96,90.06 111.84,90.06 111.4,89.62 111.4,88.65 111.84,88.22 112.28,88.22 113.02,87.48 113.02,87.34 112.89,87.21 JDIMM1.32
DDR_A_DQS#2: length 12.3
  BOTTOM w0.076: UH1.BG3 140.97,128.32 141.07,128.42 141.33,128.42 141.41,128.34 141.41,127.93 141.27,127.79 141.27,126.52 141.51,126.27 141.51,125.79 138.58,122.85 137.98,122.85 v2(137.84,122.99)
  BOTTOM w0.14: JDIMM1.53 118.14,93.79 118.24,93.69 118.24,93.59 117.48,92.83 117.48,91.47 117.27,91.26 117.15,91.26 v2(117.04,91.37)
DDR_A_DQS#3: length 10.8
  BOTTOM w0.076: v2(142.4,123.88) 142.4,123.61 142.53,123.48 142.63,123.48 144.01,124.87 144.01,126.39 143.78,126.62 143.78,128 143.89,128.11 143.89,128.23 143.8,128.33 143.59,128.33 UH1.BD3
  BOTTOM w0.14: v2(122.19,89.47) 122.35,89.63 122.79,89.63 123.1,89.32 123.1,87.94 123.48,87.56 123.48,87.29 123.39,87.19 JDIMM1.74
DDR_A_DQS#4: length 11.5
  BOTTOM w0.076: v2(161.49,121.79) 161.49,121.91 161.77,122.19 161.77,126.51 161.54,126.74 161.54,127.95 UH1.AA3
  BOTTOM w0.14: v2(152.83,90.84) 152.76,90.91 152.75,90.91 152.73,90.93 152.17,90.93 151.84,91.26 151.84,92.65 151.24,93.25 151.24,93.57 151.14,93.67 JDIMM1.177
DDR_A_DQS#5: length 11.5
  BOTTOM w0.076: UH1.U3 164.06,127.95 164.06,126.79 164.24,126.61 164.24,125.24 165.18,124.3 165.18,122.52 164.97,122.31 v2(164.97,122.03)
  BOTTOM w0.14: JDIMM1.198 156.39,87.13 156.58,87.33 156.58,87.46 157.35,88.22 157.35,89.63 157.7,89.98 157.87,89.98 v2(158.09,90.2)
DDR_A_DQS#6: length 11.5
  BOTTOM w0.076: UH1.P3 166.58,127.95 166.58,126.57 167.29,125.86 167.29,125.03 168.69,123.62 168.69,122.77 168.44,122.52 v2(168.44,122.37)
  BOTTOM w0.14: v2(163.3,90.84) 163.14,91 162.87,91 162.56,91.3 162.56,92.68 161.64,93.61 JDIMM1.219
DDR_A_DQS#7: length 8.1
  BOTTOM w0.076: UH1.L3 169.27,128.23 169.09,128.05 169.09,126.79 169.24,126.64 169.24,126.54 170,125.78 170.2,125.78 170.27,125.85 v2(170.27,126.15)
  BOTTOM w0.14: v2(168.34,90.19) 168.3,90.19 167.84,89.73 167.84,88.14 166.89,87.18 JDIMM1.240
DDR_A_MA0: length 9.5
  BOTTOM w0.076: UH1.AH3 156.34,127.95 156.34,124.61 155.69,123.96 155.69,123.09 v2(155.17,122.57)
  BOTTOM w0.221: v2(142.57,88.9) 140.89,87.22 JDIMM1.144
DDR_A_MA1: length 7.4
  BOTTOM w0.076: v2(150.16,124.25) 150.71,124.8 150.71,126.55 150.59,126.68 150.59,127.62 150.74,127.77 150.74,128.59 UH1.AP4
  BOTTOM w0.221: JDIMM1.133 138.14,92.7 v2(137.84,92.41)
DDR_A_MA2: length 5.4
  BOTTOM w0.076: UH1.AN4 151.94,128.88 v2(152.27,128.55)
  BOTTOM w0.221: JDIMM1.132 137.89,87.31 138.45,87.88 138.45,88.94 139.32,89.81 v2(140.07,89.81)
DDR_A_MA3: length 9
  BOTTOM w0.076: v2(150.16,124.88) 150.54,125.26 150.54,125.76 150.42,125.88 150.42,127.69 150.48,127.75 150.48,128.98 UH1.AP5
  BOTTOM w0.221: v2(137.84,91.14) 137.74,91.14 137.26,91.62 137.26,92.78 137.64,93.16 JDIMM1.131
DDR_A_MA4: length 8
  BOTTOM w0.076: v2(150.16,122.86) 150.32,122.86 150.59,123.12 150.59,124.2 150.92,124.53 150.92,126.65 150.75,126.81 150.75,127.3 UH1.AP2
  BOTTOM w0.221: JDIMM1.128 136.89,87.64 v2(137.85,88.6)
DDR_A_MA5: length 9.4
  BOTTOM w0.076: UH1.AP1 151.12,126.84 151.12,124.28 150.83,123.99 150.83,122.81 150.24,122.22 v2(150.19,122.22)
  BOTTOM w0.221: JDIMM1.126 136.39,87.31 136.47,87.4 136.47,88.02 137.29,88.84 137.29,89.45 137.71,89.87 v2(137.85,89.87)
DDR_A_MA6: length 12.9
  BOTTOM w0.076: UH1.AP3 151.31,127.95 151.31,126.81 151.31,126.81 151.31,126.64 151.35,126.6 151.35,124 151.14,123.79 151.14,122.08 150.3,121.23 149.26,121.23 v2(149.02,121.47)
  BOTTOM w0.221: v2(135.61,91.06) 136.16,91.61 136.16,91.97 136.64,92.46 JDIMM1.127
DDR_A_MA7: length 11
  BOTTOM w0.076: UH1.AN1 151.77,121.79 v1(151.53,121.55) 149.54,119.56 v2(149.05,119.56)
  BOTTOM w0.221: JDIMM1.122 135.39,88.22 v2(135.61,88.44)
DDR_A_MA8: length 11.9
  BOTTOM w0.076: v2(149.05,120.2) 149.73,120.2 150.73,121.2 150.73,121.2 151.55,122.02 151.55,126.63 151.48,126.7 151.48,127.94 UH1.AN3
  BOTTOM w0.221: v2(135.62,92.42) 136.14,92.94 JDIMM1.125
DDR_A_MA9: length 4.8
  BOTTOM w0.076: UH1.AT4 149.37,128.88 v2(149.7,128.55)
  BOTTOM w0.221: v2(133.55,90.93) 134.14,91.52 134.14,91.85 135.14,92.85 JDIMM1.121
DDR_A_MA10: length 6.5
  BOTTOM w0.076: v2(155.17,124.41) 155.77,125.01 155.77,127.29 UH1.AH2
  BOTTOM w0.221: JDIMM1.146 143.39,88.21 144.07,88.9 v2(144.23,88.9)
DDR_A_MA11: length 14.4
  BOTTOM w0.076: v2(149.06,118.31) 152.12,121.37 152.12,127.23 UH1.AN2
  BOTTOM w0.221: JDIMM1.120 134.89,89.08 135.52,89.71 v2(135.61,89.71)
DDR_A_MA12: length 5.7
  BOTTOM w0.076: v2(147.9,126.3) 148.06,126.46 148.06,126.73 148.07,126.74 148.07,128.43 UH1.AU4
  BOTTOM w0.221: v2(133.55,92.28) 133.83,92.28 134.64,93.09 JDIMM1.119
DDR_A_MA13: length 10
  BOTTOM w0.076: v2(157.69,122.57) 158.85,123.74 158.85,128.08 158.71,128.23 UH1.AE3
  BOTTOM w0.221: v2(148.5,88.87) 147.33,87.69 146.89,87.69 146.4,87.21 JDIMM1.158
DDR_A_PAR: length 12.2
  BOTTOM w0.076: v2(155.17,121.94) 156.07,122.84 156.07,123.9 156.51,124.33 156.51,127.94 UH1.AG3
  BOTTOM w0.221: JDIMM1.143 140.65,93.56 140.85,93.36 140.85,91.8 142.48,90.17 v2(142.57,90.17)
DDR_A_RAS#: length 5
  BOTTOM w0.076: UH1.AH4 156.37,128.57 157.09,128.57 v2(157.24,128.42)
  BOTTOM w0.221: JDIMM1.152 144.9,87.29 146.51,88.9 v2(146.94,88.9)
DDR_A_WE#: length 6.1
  BOTTOM w0.076: UH1.AG4 157.04,128.88 v2(157.24,129.08)
  BOTTOM w0.221: v2(146.94,90.17) 146.58,90.17 145.04,91.71 145.04,92.31 144.8,92.55 144.79,93.23 144.64,93.39 JDIMM1.151
DDR_B_ACT#: length 2.5
  BOTTOM w0.089: v2(149.87,132.46) 149.74,132.46 UH1.AT9
  BOTTOM w0.221: JDIMM2.114 209.7,88.07 v2(209.83,88.2)
DDR_B_ALERT#: length 4.2
  BOTTOM w0.076: v2(150.77,131.08) 150.36,131.49 UH1.AR8
  BOTTOM w0.221: JDIMM2.116 210.19,87.35 210.31,87.47 210.31,89.18 v2(209.85,89.64)
DDR_B_BG0: length 4.9
  BOTTOM w0.076: UH1.AR9 150.2,132.14 v2(149.88,131.82)
  BOTTOM w0.221: v2(208,91.02) 208.06,91.02 209.14,92.1 209.14,92.46 209.94,93.25 JDIMM2.115
DDR_B_BG1: length 3.8
  BOTTOM w0.076: UH1.AR7 150.13,130.84 v2(149.74,130.45)
  BOTTOM w0.221: JDIMM2.113 209.44,93.48 208.24,92.28 207.99,92.28 v2(207.99,92.29)
DDR_B_BS0: length 2.5
  BOTTOM w0.076: v2(156.27,131.81) 156.14,131.81 UH1.AH8
  BOTTOM w0.221: JDIMM2.150 220.69,87.16 220.41,87.44 v2(220.41,88.18)
DDR_B_BS1: length 3.3
  BOTTOM w0.076: UH1.AH9 155.71,132.14 v2(155.36,131.78)
  BOTTOM w0.221: v2(218.54,92.23) 218.54,92.99 219.17,93.62 219.28,93.62 219.44,93.78 JDIMM2.145
DDR_B_CAS#: length 4.2
  BOTTOM w0.076: v2(158.1,131.82) 157.76,131.49 UH1.AF8
  BOTTOM w0.221: JDIMM2.156 222.19,89.13 v2(222.76,89.7)
DDR_B_D0: length 5.5
  BOTTOM w0.076: v2(133.31,133.29) 133.38,133.22 134.32,133.22 134.48,133.38 UH1.BT11
  BOTTOM w0.14: JDIMM2.8 183.19,88.03 182.01,89.21 v2(181.92,89.21)
DDR_B_D1: length 7.1
  BOTTOM w0.076: v2(132.81,132.25) 133.01,132.25 133.81,133.05 134.8,133.05 134.83,133.09 135.58,133.09 UH1.BR11
  BOTTOM w0.14: JDIMM2.7 182.94,93.62 v2(181.04,91.72)
DDR_B_D2: length 6.8
  BOTTOM w0.076: UH1.BR8 135.76,131.91 135.12,131.91 134.71,131.5 134.29,131.5 133.82,131.03 v2(133.5,131.03)
  BOTTOM w0.14: v2(184.77,89.81) 186.19,88.39 JDIMM2.20
DDR_B_D3: length 6.9
  BOTTOM w0.076: v2(134.15,131.91) 134.39,131.66 134.64,131.66 135.07,132.1 136.23,132.1 UH1.BP8
  BOTTOM w0.14: JDIMM2.21 186.44,93.5 185.84,92.9 185.84,92.15 v2(184.77,91.08)
DDR_B_D4: length 5
  BOTTOM w0.076: v2(133.59,133.84) 134,133.42 134.29,133.42 134.54,133.67 136.23,133.67 UH1.BP11
  BOTTOM w0.14: JDIMM2.4 182.19,87.81 182.07,87.93 v2(182.07,87.94)
DDR_B_D5: length 5.3
  BOTTOM w0.076: UH1.BN11 136.67,133.87 134.24,133.87 v2(134.18,133.82)
  BOTTOM w0.14: v2(181.04,92.99) 181.3,92.99 181.94,93.63 JDIMM2.3
DDR_B_D6: length 6
  BOTTOM w0.14: v2(184.77,88.54) 185.19,88.12 JDIMM2.16 ; UH1.BT9 134.11,132.59 132.89,131.37 132.89,130.85 v2(133.08,130.66)
DDR_B_D7: length 5.2
  BOTTOM w0.076: UH1.BN8 136.88,132.1 136.52,132.1 136.36,132.26 134.73,132.26 v2(134.64,132.17)
  BOTTOM w0.14: v2(184.77,92.35) 185.44,93.02 JDIMM2.17
DDR_B_D8: length 4.5
  BOTTOM w0.089: v2(138.94,133.77) 138.85,133.77 UH1.BL11
  BOTTOM w0.14: JDIMM2.28 188.19,88.59 187.77,89.01 187.77,89.22 v2(187.18,89.81)
DDR_B_D9: length 4.5
  BOTTOM w0.089: v2(138.14,132.2) 138.14,132.13 UH1.BL8
  BOTTOM w0.14: v2(187.18,91.08) 187.79,91.68 187.79,92.46 188.44,93.11 JDIMM2.29
DDR_B_D10: length 4.5
  BOTTOM w0.089: v2(139.81,131.81) 139.48,131.49 UH1.BJ8
  BOTTOM w0.14: JDIMM2.41 191.44,92.19 v2(190.33,91.08)
DDR_B_D11: length 4.6
  BOTTOM w0.089: v2(139.81,132.46) 139.68,132.46 UH1.BJ10
  BOTTOM w0.14: v2(190.33,89.81) 191.69,88.45 JDIMM2.42
DDR_B_D12: length 2.7
  BOTTOM w0.089: v2(138.14,133.77) 138.14,133.84 UH1.BL12
  BOTTOM w0.14: JDIMM2.24 187.19,88.53 v2(187.18,88.54)
DDR_B_D13: length 2.9
  BOTTOM w0.089: UH1.BL7 138.19,131.19 v2(138.19,131.38)
  BOTTOM w0.14: v2(187.18,92.35) 187.44,92.6 JDIMM2.25
DDR_B_D14: length 2.9
  BOTTOM w0.089: v2(139.81,133.11) 139.68,133.11 UH1.BJ11
  BOTTOM w0.14: v2(190.33,88.54) 190.69,88.18 JDIMM2.38
DDR_B_D15: length 2.8
  BOTTOM w0.089: v2(139.81,131.16) 139.48,130.84 UH1.BJ7
  BOTTOM w0.14: JDIMM2.37 190.44,92.46 v2(190.33,92.35)
DDR_B_D16: length 4.5
  BOTTOM w0.089: v2(141.64,133.75) 141.49,133.75 UH1.BG11
  BOTTOM w0.14: JDIMM2.50 193.69,88.82 v2(192.7,89.81)
DDR_B_D17: length 4.4
  BOTTOM w0.089: UH1.BG10 141.51,133.11 v2(141.64,133.11)
  BOTTOM w0.14: v2(192.7,91.08) 193.44,91.82 JDIMM2.49
DDR_B_D18: length 2.9
  BOTTOM w0.089: v2(142.55,133.75) 142.4,133.75 UH1.BF11
  BOTTOM w0.14: v2(196.38,88.54) 196.69,88.23 JDIMM2.62
DDR_B_D19: length 3.1
  BOTTOM w0.089: v2(142.54,131.82) 142.43,131.82 UH1.BF8
  BOTTOM w0.14: JDIMM2.63 196.94,92.87 v2(196.38,92.31)
DDR_B_D20: length 2.8
  BOTTOM w0.089: UH1.BG7 141.51,131.16 v2(141.64,131.16)
  BOTTOM w0.14: JDIMM2.46 192.69,88.53 v2(192.7,88.54)
DDR_B_D21: length 2.9
  BOTTOM w0.089: v2(141.64,131.81) 141.51,131.81 UH1.BG8
  BOTTOM w0.14: v2(192.7,92.35) 192.44,92.61 JDIMM2.45
DDR_B_D22: length 4.3
  BOTTOM w0.089: UH1.BF10 142.42,133.11 v2(142.55,133.11)
  BOTTOM w0.14: JDIMM2.58 195.69,89.12 v2(196.38,89.81)
DDR_B_D23: length 4.2
  BOTTOM w0.089: v2(142.55,131.16) 142.42,131.16 UH1.BF7
  BOTTOM w0.14: v2(196.38,91.08) 195.94,91.52 JDIMM2.59
DDR_B_D24: length 2.8
  BOTTOM w0.089: v2(144.38,133.75) 144.23,133.75 UH1.BC11
  BOTTOM w0.14: JDIMM2.70 198.69,88.46 v2(198.77,88.54)
DDR_B_D25: length 4.5
  BOTTOM w0.089: v2(144.38,131.81) 144.25,131.81 UH1.BC8
  BOTTOM w0.14: v2(198.77,91.08) 199.37,91.68 199.37,92.76 198.94,93.19 JDIMM2.71
DDR_B_D26: length 3
  BOTTOM w0.089: UH1.BB11 145.16,133.77 v2(145.3,133.77)
  BOTTOM w0.14: JDIMM2.83 201.94,92.86 v2(202.44,92.35)
DDR_B_D27: length 2.9
  BOTTOM w0.089: UH1.BB7 145.16,131.16 v2(145.3,131.16)
  BOTTOM w0.14: JDIMM2.84 202.19,87.26 202.44,87.52 v2(202.44,88.54)
DDR_B_D28: length 4.5
  BOTTOM w0.089: v2(144.38,133.11) 144.25,133.11 UH1.BC10
  BOTTOM w0.14: JDIMM2.66 197.69,87.35 198.23,87.89 198.23,89.27 v2(198.77,89.81)
DDR_B_D29: length 3.2
  BOTTOM w0.089: v2(144.38,131.16) 144.25,131.16 UH1.BC7
  BOTTOM w0.14: v2(198.77,92.3) 197.94,93.13 JDIMM2.67
DDR_B_D30: length 4.7
  BOTTOM w0.089: UH1.BB10 145.16,133.11 v2(145.3,133.11)
  BOTTOM w0.14: v2(202.44,91.08) 200.94,92.59 JDIMM2.79
DDR_B_D31: length 4.6
  BOTTOM w0.089: v2(145.3,131.81) 145.16,131.81 UH1.BB8
  BOTTOM w0.14: JDIMM2.80 201.19,87.15 201.92,87.88 201.92,89.29 v2(202.44,89.81)
DDR_B_D32: length 2.9
  BOTTOM w0.089: v2(160.84,133.77) 160.71,133.77 UH1.AC11
  BOTTOM w0.14: v2(226.59,88.58) 226.69,88.48 JDIMM2.174
DDR_B_D33: length 2.8
  BOTTOM w0.089: UH1.AC7 160.71,131.16 v2(160.84,131.16)
  BOTTOM w0.14: JDIMM2.173 226.44,92.54 v2(226.59,92.39)
DDR_B_D34: length 2.8
  BOTTOM w0.089: v2(161.75,133.77) 161.62,133.77 UH1.AA11
  BOTTOM w0.14: v2(230.14,92.41) 229.94,92.61 JDIMM2.187
DDR_B_D35: length 3
  BOTTOM w0.089: UH1.AA7 161.62,131.16 v2(161.75,131.16)
  BOTTOM w0.14: JDIMM2.186 229.69,88.15 v2(230.14,88.6)
DDR_B_D36: length 4.5
  BOTTOM w0.076: UH1.AC10 160.52,132.79 v2(160.84,133.11)
  BOTTOM w0.14: JDIMM2.170 225.69,88.95 v2(226.59,89.85)
DDR_B_D37: length 4.5
  BOTTOM w0.089: UH1.AC8 160.71,131.81 v2(160.84,131.81)
  BOTTOM w0.14: JDIMM2.169 225.44,92.27 v2(226.59,91.12)
DDR_B_D38: length 4.5
  BOTTOM w0.089: v2(161.75,133.11) 161.62,133.11 UH1.AA10
  BOTTOM w0.14: v2(230.14,91.14) 228.94,92.34 JDIMM2.183
DDR_B_D39: length 4.7
  BOTTOM w0.089: v2(161.75,131.81) 161.62,131.81 UH1.AA8
  BOTTOM w0.14: JDIMM2.182 228.69,87.12 229.15,87.59 229.15,88.88 v2(230.14,89.87)
DDR_B_D40: length 2.9
  BOTTOM w0.089: UH1.W8 163.39,131.22 v2(163.58,131.22)
  BOTTOM w0.14: v2(232.42,92.41) 231.94,92.89 JDIMM2.195
DDR_B_D41: length 3.1
  BOTTOM w0.089: v2(163.58,130.67) 163.3,130.67 UH1.W7
  BOTTOM w0.14: JDIMM2.194 231.71,87.7 232.42,88.42 v2(232.42,88.6)
DDR_B_D42: length 3
  BOTTOM w0.089: v2(164.46,133.11) 164.37,133.11 UH1.V10
  BOTTOM w0.14: JDIMM2.207 234.94,93.08 235.61,92.41 v2(235.66,92.41)
DDR_B_D43: length 3
  BOTTOM w0.089: UH1.V11 164.37,133.77 v2(164.47,133.77)
  BOTTOM w0.14: JDIMM2.208 235.19,87.5 235.66,87.96 v2(235.66,88.6)
DDR_B_D44: length 4.6
  BOTTOM w0.076: UH1.W11 163.26,133.44 v2(163.58,133.11)
  BOTTOM w0.14: v2(232.42,91.14) 230.94,92.62 JDIMM2.191
DDR_B_D45: length 4.8
  BOTTOM w0.076: v2(162.68,132.57) 162.9,132.79 UH1.W10
  BOTTOM w0.14: v2(232.42,89.87) 231.87,89.32 231.87,88.51 230.7,87.35 JDIMM2.190
DDR_B_D46: length 4.7
  BOTTOM w0.089: v2(164.5,131.81) 164.37,131.81 UH1.V8
  BOTTOM w0.14: JDIMM2.203 233.94,92.86 v2(235.66,91.14)
DDR_B_D47: length 4.7
  BOTTOM w0.089: v2(164.5,131.16) 164.37,131.16 UH1.V7
  BOTTOM w0.14: v2(235.66,89.87) 235.07,89.28 235.07,88.38 234.19,87.5 JDIMM2.204
DDR_B_D48: length 3.2
  BOTTOM w0.089: v2(166.33,133.77) 166.19,133.77 UH1.R11
  BOTTOM w0.14: JDIMM2.216 237.19,87.3 237.94,88.05 v2(237.94,88.6)
DDR_B_D49: length 3.1
  BOTTOM w0.089: UH1.R7 166.19,131.16 v2(166.33,131.16)
  BOTTOM w0.14: JDIMM2.215 236.94,93.41 v2(237.94,92.41)
DDR_B_D50: length 3.4
  BOTTOM w0.089: UH1.P7 167.11,131.16 v2(167.24,131.16)
  BOTTOM w0.14: JDIMM2.228 240.19,87.8 240.99,88.6 v2(241.24,88.6)
DDR_B_D51: length 3.1
  BOTTOM w0.089: v2(167.24,133.77) 167.11,133.77 UH1.P11
  BOTTOM w0.14: JDIMM2.229 240.44,93.22 v2(241.24,92.41)
DDR_B_D52: length 4.8
  BOTTOM w0.089: v2(166.33,131.81) 166.19,131.81 UH1.R8
  BOTTOM w0.14: v2(237.94,91.14) 237.01,92.07 237.01,92.67 235.94,93.74 JDIMM2.211
DDR_B_D53: length 4.8
  BOTTOM w0.089: UH1.R10 166.19,133.11 v2(166.33,133.11)
  BOTTOM w0.14: v2(237.94,89.87) 236.87,88.8 236.87,88.05 236.19,87.37 JDIMM2.212
DDR_B_D54: length 5.1
  BOTTOM w0.089: v2(167.24,131.81) 167.11,131.81 UH1.P8
  BOTTOM w0.14: v2(241.24,89.87) 240.99,89.87 239.19,88.07 JDIMM2.224
DDR_B_D55: length 4.7
  BOTTOM w0.089: v2(167.24,133.11) 167.11,133.11 UH1.P10
  BOTTOM w0.14: v2(241.24,91.14) 240.12,92.26 240.12,92.98 239.44,93.66 JDIMM2.225
DDR_B_D56: length 3.5
  BOTTOM w0.076: UH1.M7 168.96,130.49 v2(169.01,130.49)
  BOTTOM w0.14: v2(243.53,92.41) 242.91,92.41 242.44,92.88 JDIMM2.237
DDR_B_D57: length 3.5
  BOTTOM w0.089: UH1.M11 168.94,133.77 v2(169.07,133.77)
  BOTTOM w0.14: v2(243.53,88.6) 243.37,88.6 242.19,87.42 JDIMM2.236
DDR_B_D58: length 3.5
  BOTTOM w0.089: v2(169.96,133.77) 169.85,133.77 UH1.L11
  BOTTOM w0.14: v2(246.58,92.41) 246.06,92.41 245.44,93.03 JDIMM2.249
DDR_B_D59: length 3.3
  BOTTOM w0.089: v2(169.94,131.27) 169.88,131.27 UH1.L7
  BOTTOM w0.14: v2(246.58,88.6) 246.57,88.59 246.51,88.59 245.69,87.77 JDIMM2.250
DDR_B_D60: length 5.2
  BOTTOM w0.089: UH1.M10 168.94,133.11 v2(169.07,133.11)
  BOTTOM w0.14: JDIMM2.232 241.19,87.69 243.37,89.87 v2(243.53,89.87)
DDR_B_D61: length 4.8
  BOTTOM w0.089: v2(169,131.14) 168.97,131.14 UH1.M8
  BOTTOM w0.14: v2(243.53,91.14) 241.44,93.23 JDIMM2.233
DDR_B_D62: length 4.9
  BOTTOM w0.089: UH1.L10 169.85,133.11 v2(169.96,133.11)
  BOTTOM w0.14: JDIMM2.245 244.44,93.81 244.87,93.38 244.87,92.85 v2(246.58,91.14)
DDR_B_D63: length 4.9
  BOTTOM w0.089: v2(169.96,131.81) 169.83,131.81 UH1.L8
  BOTTOM w0.14: v2(246.58,89.87) 245.93,89.22 245.93,88.49 244.69,87.25 JDIMM2.246
DDR_B_DQS0: length 5.2
  BOTTOM w0.089: v2(136.24,133) 136.52,132.72 UH1.BP9
  BOTTOM w0.14: JDIMM2.13 184.44,93.64 184.35,93.55 184.35,93.12 183.9,92.68 183.9,91.21 183.58,90.89 183.12,90.89 v2(182.99,90.76)
DDR_B_DQS1: length 5.4
  BOTTOM w0.076: UH1.BJ9 139.23,132.02 138.93,132.02 138.85,132.11 138.85,132.35 v2(138.96,132.46)
  BOTTOM w0.14: JDIMM2.34 189.69,87.22 189.55,87.35 189.55,89.52 189.17,89.9 188.88,89.9 v2(188.66,90.13)
DDR_B_DQS2: length 5
  BOTTOM w0.089: v2(142.53,132.46) 142.42,132.46 UH1.BF9
  BOTTOM w0.14: v2(194.37,90.76) 194.59,90.98 194.84,90.98 195.15,91.3 195.15,93.08 194.84,93.4 194.84,93.58 194.94,93.68 JDIMM2.55
DDR_B_DQS3: length 5.3
  BOTTOM w0.089: UH1.BB9 145.16,132.46 v2(145.3,132.46)
  BOTTOM w0.14: v2(200.41,90.13) 200.58,89.96 200.89,89.96 201.15,89.7 201.15,88.48 200.09,87.42 200.09,87.32 200.19,87.22 JDIMM2.76
DDR_B_DQS4: length 4.4
  BOTTOM w0.089: UH1.AA9 161.62,132.46 v2(161.75,132.46)
  BOTTOM w0.14: JDIMM2.179 227.94,93.49 227.87,93.42 227.87,91.38 227.99,91.25 228.18,91.25 v2(228.37,91.44)
DDR_B_DQS5: length 5.1
  BOTTOM w0.076: UH1.V9 164.09,132.09 164.09,131.86 164.02,131.78 163.65,131.78 v2(163.6,131.83)
  BOTTOM w0.14: JDIMM2.200 233.2,87.17 233.08,87.3 233.08,87.5 233.57,88 233.57,89.51 233.76,89.7 234.05,89.7 v2(234.2,89.55)
DDR_B_DQS6: length 4.5
  BOTTOM w0.089: v2(167.24,132.46) 167.11,132.46 UH1.P9
  BOTTOM w0.14: JDIMM2.221 238.44,93.71 238.36,93.63 238.36,93.52 239.03,92.85 239.03,91.42 239.11,91.34 239.35,91.34 v2(239.47,91.46)
DDR_B_DQS7: length 4.9
  BOTTOM w0.076: UH1.L9 169.4,132.14 v2(169.02,131.76)
  BOTTOM w0.14: v2(245.05,89.55) 244.85,89.75 244.69,89.75 244.56,89.63 244.56,88.26 243.69,87.39 JDIMM2.242
DDR_B_DQS#0: length 4.7
  BOTTOM w0.089: UH1.BN9 137.17,132.66 v2(136.84,132.99)
  BOTTOM w0.14: JDIMM2.11 183.94,93.74 184.04,93.64 184.04,93.25 183.6,92.8 183.6,91.34 183.45,91.2 183.19,91.2 v2(182.99,91.4)
DDR_B_DQS#1: length 4.5
  BOTTOM w0.076: UH1.BL9 v2(138.92,133.11)
  BOTTOM w0.14: v2(188.66,89.49) 188.76,89.6 189.04,89.6 189.25,89.4 189.25,87.23 189.19,87.17 JDIMM2.32
DDR_B_DQS#2: length 4.5
  BOTTOM w0.089: v2(141.64,132.46) 141.51,132.46 UH1.BG9
  BOTTOM w0.14: v2(194.37,91.4) 194.48,91.29 194.71,91.29 194.85,91.43 194.85,92.95 194.53,93.27 194.53,93.61 194.44,93.7 JDIMM2.53
DDR_B_DQS#3: length 4.8
  BOTTOM w0.089: v2(144.38,132.46) 144.25,132.46 UH1.BC9
  BOTTOM w0.14: v2(200.41,89.49) 200.57,89.65 200.76,89.65 200.84,89.57 200.84,88.61 199.78,87.55 199.78,87.32 199.69,87.23 JDIMM2.74
DDR_B_DQS#4: length 4.9
  BOTTOM w0.089: UH1.AC9 160.71,132.46 v2(160.84,132.46)
  BOTTOM w0.14: JDIMM2.177 227.44,93.52 227.56,93.39 227.56,91.25 227.87,90.95 228.23,90.95 v2(228.37,90.81)
DDR_B_DQS#5: length 5.3
  BOTTOM w0.076: UH1.W9 163.27,132.14 v2(163.6,132.47)
  BOTTOM w0.14: v2(234.2,90.19) 234.02,90.01 233.63,90.01 233.27,89.64 233.27,88.13 232.77,87.63 232.77,87.21 232.7,87.15 JDIMM2.198
DDR_B_DQS#6: length 5.1
  BOTTOM w0.089: v2(166.33,132.46) 166.19,132.46 UH1.R9
  BOTTOM w0.14: v2(239.47,90.82) 239.25,91.03 238.98,91.03 238.73,91.29 238.73,92.72 238.06,93.39 238.06,93.53 237.94,93.65 JDIMM2.219
DDR_B_DQS#7: length 5.4
  BOTTOM w0.076: UH1.M9 168.77,132.14 v2(169.06,132.43)
  BOTTOM w0.14: JDIMM2.240 243.19,87.32 244.26,88.39 244.26,89.75 244.56,90.06 244.92,90.06 v2(245.05,90.19)
DDR_B_MA0: length 4.1
  BOTTOM w0.076: v2(155.35,132.46) 155.22,132.46 UH1.AJ9
  BOTTOM w0.221: v2(218.49,89.31) 217.19,88.01 JDIMM2.144
DDR_B_MA1: length 2.8
  BOTTOM w0.076: v2(153.89,129.87) 154.03,129.87 UH1.AK6
  BOTTOM w0.221: JDIMM2.133 214.44,93.12 214.14,92.83 v2(214.14,92.41)
DDR_B_MA2: length 4.7
  BOTTOM w0.076: v2(154.67,129.2) 154.62,129.2 UH1.AK5
  BOTTOM w0.221: v2(215.91,89.81) 215.82,89.81 214.65,88.64 214.65,87.75 214.19,87.29 JDIMM2.132
DDR_B_MA3: length 4.3
  BOTTOM w0.076: UH1.AL5 153.43,129.53 v2(153.1,129.2)
  BOTTOM w0.221: JDIMM2.131 213.94,93.37 213.62,93.05 213.62,91.64 214.12,91.14 v2(214.14,91.14)
DDR_B_MA4: length 3.2
  BOTTOM w0.076: v2(153.1,129.85) 153.43,130.18 UH1.AL6
  BOTTOM w0.221: JDIMM2.128 213.19,87.12 213.68,87.61 213.75,87.61 214.13,87.98 214.13,88.58 v2(214.15,88.6)
DDR_B_MA5: length 4.7
  BOTTOM w0.076: UH1.AM6 152.59,130.18 v2(152.27,129.85)
  BOTTOM w0.221: JDIMM2.126 212.69,87.41 213.02,87.74 213.02,88.8 214.09,89.87 v2(214.15,89.87)
DDR_B_MA6: length 4.4
  BOTTOM w0.076: UH1.AN7 152.44,130.84 v2(152.61,130.67)
  BOTTOM w0.221: v2(211.91,91.06) 212.94,92.09 JDIMM2.127
DDR_B_MA7: length 4.5
  BOTTOM w0.076: v2(152.61,133.11) 152.48,133.11 UH1.AN10
  BOTTOM w0.221: JDIMM2.122 211.69,87.25 212.39,87.95 212.39,89.32 212,89.71 v2(211.91,89.71)
DDR_B_MA8: length 2.9
  BOTTOM w0.076: UH1.AN8 152.31,131.49 v2(152.59,131.21)
  BOTTOM w0.221: JDIMM2.125 212.44,92.94 v2(211.92,92.42)
DDR_B_MA9: length 4.9
  BOTTOM w0.076: UH1.AR11 150.39,133.44 v2(150.77,133.06)
  BOTTOM w0.221: JDIMM2.121 211.44,93.01 210.91,92.47 210.91,91.99 v2(209.85,90.93)
DDR_B_MA10: length 3
  BOTTOM w0.076: v2(156.27,131.16) 156.14,131.16 UH1.AH7
  BOTTOM w0.221: JDIMM2.146 219.69,87.26 219,87.95 v2(218.47,87.95)
DDR_B_MA11: length 3.2
  BOTTOM w0.076: UH1.AN11 152.48,133.77 v2(152.61,133.77)
  BOTTOM w0.221: JDIMM2.120 211.19,87.99 211.65,88.44 v2(211.92,88.44)
DDR_B_MA12: length 3.3
  BOTTOM w0.076: v2(150.78,132.45) 150.45,132.79 UH1.AR10
  BOTTOM w0.221: v2(209.85,92.28) 210.94,93.38 JDIMM2.119
DDR_B_MA13: length 2.5
  BOTTOM w0.076: v2(158.1,132.46) 157.77,132.14 UH1.AF9
  BOTTOM w0.221: v2(222.79,88.18) 222.79,87.5 222.69,87.4 JDIMM2.158
DDR_B_PAR: length 5.4
  BOTTOM w0.076: UH1.AJ7 155.22,131.16 v2(155.35,131.16)
  BOTTOM w0.221: JDIMM2.143 216.95,91.56 217.68,90.83 v2(218.51,90.83)
DDR_B_RAS#: length 4.3
  BOTTOM w0.076: v2(156.27,133.11) 156.14,133.11 UH1.AH10
  BOTTOM w0.221: v2(220.41,89.7) 221.19,88.92 JDIMM2.152
DDR_B_WE#: length 3
  BOTTOM w0.076: v2(156.27,133.77) 156.14,133.77 UH1.AH11
  BOTTOM w0.221: v2(220.42,92.4) 220.4,92.4 220.94,92.94 JDIMM2.151
DDR_CKE0_DIMMA: length 7.8
  BOTTOM w0.076: UH1.AT1 149.25,125.41 147.79,123.94 147.79,122.63 v2(147.3,122.14)
  BOTTOM w0.221: JDIMM1.109 132.14,93.63 131.67,93.16 v2(131.67,92.56)
DDR_CKE1_DIMMA: length 11.3
  BOTTOM w0.076: UH1.AT2 148.96,127.29 148.96,125.35 147.27,123.66 v2(147.27,123.26)
  BOTTOM w0.221: v2(131.69,91.23) 131.59,91.23 130.92,90.56 130.92,88.16 131.52,87.56 131.98,87.56 132.39,87.16 JDIMM1.110
DDR_CKE2_DIMMB: length 6.3
  BOTTOM w0.089: UH1.AT8 149.7,131.2 v2(149.87,131.2)
  BOTTOM w0.221: JDIMM2.109 208.44,93.54 207.21,92.31 207.21,90.43 v2(208,89.64)
DDR_CKE3_DIMMB: length 2.7
  BOTTOM w0.089: UH1.AT10 149.74,133.11 v2(149.87,133.11)
  BOTTOM w0.221: v2(208,88.2) 208.69,87.51 JDIMM2.110
DDR_CS0_DIMMA#: length 4.3
  BOTTOM w0.076: UH1.AD5 159.27,129.53 v2(158.95,129.2)
  BOTTOM w0.221: v2(144.23,91.44) 143.82,91.44 143.64,91.62 143.64,93.16 144.14,93.66 JDIMM1.149
DDR_CS1_DIMMA#: length 13.1
  BOTTOM w0.076: v2(157.7,120.35) 157.6,120.25 157.49,120.25 157.31,120.43 157.31,123.97 158.28,124.94 158.28,125.57 158.41,125.7 158.41,126.68 158.3,126.79 158.3,127.52 158.41,127.63 158.53,127.63 UH1.AE2
  BOTTOM w0.221: JDIMM1.157 146.14,93.16 148.13,91.18 148.28,91.18 v2(148.5,91.41)
DDR_CS2_DIMMB#: length 4.9
  BOTTOM w0.076: UH1.AF11 157.72,133.44 v2(158.08,133.08)
  BOTTOM w0.221: v2(220.42,91.13) 220.18,91.13 219.53,91.78 219.53,92.77 220.44,93.68 JDIMM2.149
DDR_CS3_DIMMB#: length 4.2
  BOTTOM w0.076: v2(158.95,130.49) 158.9,130.49 UH1.AE7
  BOTTOM w0.221: v2(224.02,91.5) 222.44,93.09 JDIMM2.157
DDR_RCOMP0: length 3.9
  BOTTOM w0.305: 172.2,126.45 172.2,126.86 UH1.G1
  BOTTOM w0.381: RH148.2 172.33,123.77 172.89,124.33 172.89,125 172.54,125.34 172.54,125.35 172.2,125.7 172.2,126.45
DDR_RCOMP1: length 2.9
  BOTTOM w0.381: UH1.H1 171.7,126.63 171.7,125.44 172.15,124.99 RH149.2
DDR_RCOMP2: length 6.2
  BOTTOM w0.381: UH1.J2 170.83,127.31 170.83,126.68 171.23,126.27 171.23,125.49 170.68,124.94 v1(170.68,124.89) 170.68,124.12 170.95,123.85 170.95,123.21 170.44,122.7 RH150.2
DDR_VTT_PG_CTRL: length 23.2
  TOP w0.127: 130.23,128.73 v4(130.23,130.5) 132.31,132.58
  TOP w0.14: 130.23,128.73 129.21,127.71 129.21,121.94 128.32,121.05 UC1.2 ; 132.31,132.58 132.31,133.33 v2(133.29,134.31)
  BOTTOM w0.102: UH1.BT13 134.4,134.95 133.76,134.31 v2(133.29,134.31)
DEBUG_TX: length 8.8
  TOP w0.14: RE298.2 301.29,96.89 RE299.1 303.06,96.89 v1(305.5,99.33) v2(307.64,99.33)
  BOTTOM w0.14: JDEG1.9 306.78,98.85 307.26,99.33 v2(307.64,99.33)
DGPU_HOLD_RST#: length 17.5
  TOP w0.14: v2(206.38,113.88) 205.92,113.43 203.5,113.43 202.77,114.16 202.77,115.11 202.94,115.27 U33.9 ; v2(136.82,83.4) 136.75,83.47 v1(136.23,83.47) 133.15,83.47 131.71,82.03 v2(131.71,79.03) ; v2(224.65,111.71) 224.38,111.44 UV19.1 224.38,110 RV580.2
  BOTTOM w0.089: v2(87.04,74.14) 87.04,74.14 87.15,74.03 87.24,74.03 87.58,73.7 UH2.BB20
DGPU_PEX_RST#: length 61.3
  TOP w0.14: v1(201.6,109.75) 200.46,109.75 200.2,109.49 199.82,109.49 199.68,109.63 RV1131.2
  TOP w0.203: U33.10 203.34,115.67 203.44,115.56 203.77,115.56 v2(203.78,115.58)
  TOP w0.381: v2(221.06,109.78) 220.28,110.56 UV29.1
  TOP w0.508: RV1131.2 199.81,110.09 200.22,110.5 v2(200.22,111.14) ; v2(221.06,109.78) 221.51,109.33 RV587.2 ; v2(217.91,110.28) 217.45,109.82 RV1084.1
  BOTTOM w0.508: RV589.1 186.8,128.33 RV577.1 187.65,127.86 187.92,127.59 190.8,127.59 191.63,126.76 191.63,126.05 192.05,125.63 192.05,124.56 192.96,123.65 192.96,120.41 196.37,117.01 197.94,117.01 199.84,115.11 ; v2(221.06,109.78) 220.56,110.28 v2(217.91,110.28) 216.81,109.19 201.55,109.19 200.22,110.52 v2(200.22,111.14) 199.84,111.52 199.84,115.11 ; 199.84,115.11 200.45,114.5 202.71,114.5 v2(203.78,115.58)
DGPU_PEX_RST#_R: length 13.8
  BOTTOM w0.102: 191.92,128.67 192.25,129 194.16,129 194.42,129.27 194.42,131.27 194.65,131.49 196.67,131.49 196.88,131.7 196.88,133.96 UV18.AJ12
  BOTTOM w0.14: 191.92,128.67 v1(189.69,128.67) 188.91,128.67 RV577.2
DGPU_PWR_EN: length 71
  TOP w0.14: v2(262.02,76.24) 262.02,76.74 261.63,77.14 261.63,80.14 263.07,81.58 263.07,83.81 263.94,84.69 267.15,84.69 269.82,87.36 269.82,88.27 268.4,89.68 267.39,89.68 266.06,91 264.36,91 258.94,96.42 258.94,100.54 259.39,100.99 261.2,100.99 263.25,103.04 263.25,106 262.76,106.48 262.67,106.48 262.23,106.93 261.87,106.93 259.94,108.86 259.91,108.86 258.06,110.7 258.06,110.72 257.14,111.65 RH537.1 256.46,111.99 254.04,114.41 v1(252.34,114.41) 252.34,115.52 251.12,116.74 250.36,116.74 249.87,117.22 UZ31.1
  BOTTOM w0.089: v2(74.91,82.54) 74.63,82.82 74.01,82.82 73.78,82.59 UH2.AD48
  BOTTOM w0.14: v2(262.02,76.24) 262.02,74.97 261.42,74.36 261.42,70.62 v2(261.57,70.46)
  vias: v2(62.87,78.62)
DGPU_PWR_EN#: length 3.9
  TOP w0.14: QV3.6 246.78,115.66 RV657.2 244.6,114.75 RV399.2 v1(244.6,113.56)
DGPU_PWR_EN#_R: length 5.3
  TOP w0.14: CV499.1 244.56,115.65 RV399.1 245.54,116.59 v1(245.54,116.6) 246.94,116.6 247.51,116.03 QV3.5
DGPU_PWROK: length 6.9
  TOP w0.089: v2(98.42,76.41) 98.23,76.22 v1(98.23,75.86) 98.39,75.71 RH516.2
  TOP w0.14: UV20.2 196.19,111.31 195.85,111.65 195.85,111.93 v2(196,112.08)
  TOP w0.203: PR705.1 188.72,183.22 v2(189.04,183.53) 189.17,183.66 PU700.13
  BOTTOM w0.089: v3(89.04,77.08) 89.43,77.08 89.67,76.84 UH2.AV16
  vias: v2(180.49,86.9) v2(191.82,129.8)
DH1_NVVDD: length 1.1
  TOP w0.14: v2(163.39,181.71) 163.39,181.02 v1(163.66,180.74)
  vias: v2(162.93,181.3) v2(171.93,168.7) v2(171.93,168.04)
DH1_NVVDDS: length 0.5
  TOP w0.14: v2(190.4,176.34) v1(190.4,175.84)
  vias: v2(187.38,180.61) v2(187.38,179.98) v2(189.81,176.34)
DH2_NVVDD: length 0.7
  TOP w0.14: v2(171.98,173.86) v1(171.98,173.2)
  vias: v2(168.25,181.73) v2(168.72,181.33) v2(171.35,173.86)
DH_1.2V:
  vias: v2(268.52,101.26) v2(268.52,100.67) v2(283.07,95.78) v2(283.51,96.22)
DIFFOUT_2PH: length 4.8
  TOP w0.14: v1(106.16,172.37) 105.59,172.94 PR1138.1
  TOP w0.203: PU1100.35 106.38,175.11 105.97,174.71 105.97,174.39 105.84,174.26
  TOP w0.254: 105.84,174.26 105.33,173.75 PR1140.2 105.21,173.68 PR1138.1
DIFFOUT_4PH: length 6.2
  TOP w0.203: PR1137.2 117.96,173.8 117.53,173.37 116.26,173.37 114.92,174.71 v1(114.59,174.71) PU1100.4
  TOP w0.254: PC1116.2 118.08,173.75 PR1137.2
DIMM_CHA_SA0: length 3.9
  TOP w0.254: RD1.2 RD28.1 170.01,85.15 v2(169.98,85.11)
  BOTTOM w0.254: v2(169.98,85.11) 170.61,85.11 170.89,85.38 JDIMM1.256
DIMM_CHA_SA1: length 8.6
  TOP w0.254: v2(172.02,88.27) 172.27,88.27 173.88,89.89 RD29.1 173.88,92.04 v1(173.38,92.54) 172.46,92.54 RD2.2
  BOTTOM w0.254: JDIMM1.260 171.89,88.15 v2(172.02,88.27)
DIMM_CHA_SA2: length 3.5
  TOP w0.14: v2(148.63,85.06) 148.63,85.02 148.34,84.73 v1(148.34,84.64)
  TOP w0.254: RD3.2 148.69,85.01 v2(148.63,85.06) 148.63,85.51 RD30.1
  BOTTOM w0.254: JDIMM1.166 148.39,85.3 v2(148.63,85.06)
DIMM_CHB_SA0: length 6.1
  TOP w0.14: RD38.1 245.29,86.05 245.29,85.87 v1(244.73,85.31)
  TOP w0.254: RD4.2 246.15,86.91 RD38.1 245.73,85.99 245.73,85.32 v2(245.87,85.17)
  BOTTOM w0.254: v2(245.87,85.17) 246.82,85.17 247.19,85.54 JDIMM2.256
DIMM_CHB_SA1: length 3.9
  TOP w0.254: RD39.1 247.48,84.22 RD5.2 247.93,84.23 248.66,84.96 v2(248.66,84.98)
  BOTTOM w0.254: v2(248.66,84.98) 248.66,85.23 248.19,85.7 JDIMM2.260
DIMM_CHB_SA2: length 4.2
  TOP w0.14: RD6.2 v1(225.15,82.34)
  TOP w0.254: RD6.2 RD40.1 225.15,84.83 v2(224.93,85.05)
  BOTTOM w0.254: v2(224.93,85.05) 224.93,85.06 224.69,85.29 JDIMM2.166
DISPOFF#: length 16.5
  TOP w0.14: v2(53.54,100.93) 53.37,101.1 53.37,101.12 53.02,101.47 49.23,101.47 48.87,101.11 48.87,99.69 v1(47.29,98.11) 47.12,97.94 46.75,97.94 v2(46.3,97.48)
  BOTTOM w0.14: v2(46.3,97.48) 46.3,97.08 45.47,96.25 RV107.1 45.47,94.24 DV1.1 ; JEDP1.24 53.99,101.85 53.54,101.4 v2(53.54,100.93)
DL1_NVVDD: length 0.6
  TOP w0.14: v1(164.47,179.04) 164.86,179.43 v2(164.86,179.43)
  vias: v2(164.39,165.37) v2(164.39,164.74) v2(165.32,179.84)
DL1_NVVDDS: length 1.4
  TOP w0.14: v2(188.71,176.79) v2(188.71,177.42) v1(188.71,178.2)
  vias: v2(189.41,182.42) v2(190.04,182.39)
DL2_NVVDD: length 0.6
  TOP w0.14: v2(166.42,179.96) 166.41,179.96 v1(165.96,180.41)
  vias: v2(166.77,179.44) v2(172.6,185.09) v2(173.17,185.09) v2(179.41,185.3) v2(179.81,185.73)
DL_1.2V: length 0.6
  TOP w0.14: v2(284.72,94.95) v1(284.72,95.55)
  vias: v2(272.08,93.81) v2(272.72,93.81) v2(284.21,94.51)
DMI_CRX_PTX_N0: length 112.6
  BOTTOM w0.076: v2(173.57,131.64) 173.24,131.32 UH1.E8
  BOTTOM w0.089: 81.78,95.71 81.78,95.68 81.71,95.61 81.71,93.76 80.92,92.97 UH2.C33
  BOTTOM w0.152: v2(177.85,122.29) 177.57,122.01 177.57,121.27 165.3,109 116.91,109 106.91,99 102.01,99 101.05,98.04 96.31,98.04 94.98,99.37 89.62,99.37 87.74,97.48 83.04,97.48 81.78,96.22 81.78,95.71
DMI_CRX_PTX_N1: length 110.6
  BOTTOM w0.076: v2(172.92,130.85) 172.57,130.51 UH1.F6
  BOTTOM w0.089: UH2.C32 81.72,92.88 81.85,92.88 82.05,93.08 82.05,93.41 82.32,93.68 82.32,95.34 82.59,95.61 82.69,95.61 82.71,95.63
  BOTTOM w0.152: 82.71,95.63 83.76,96.68 88.08,96.68 89.84,98.44 v5(93.46,98.44) 94.63,98.44 95.83,97.25 101.46,97.25 102.36,98.15 107.21,98.15 116.98,107.92 165.34,107.92 177.45,120.03 178.05,120.03 v2(178.2,119.88)
DMI_CRX_PTX_N2: length 113.1
  BOTTOM w0.076: UH1.E5 173.24,129.73 v2(173.56,130.04)
  BOTTOM w0.089: UH2.C31 82.42,92.95 82.52,92.95 82.76,93.19 82.76,93.37 82.9,93.51 82.9,94.64 83.79,95.53 83.85,95.53 83.92,95.46 83.94,95.46
  BOTTOM w0.152: 83.94,95.46 86.02,95.46 86.41,95.85 88.39,95.85 90.16,97.62 v5(90.46,97.62) 94.29,97.62 95.45,96.46 101.78,96.46 102.68,97.36 107.75,97.36 117.3,106.91 165.45,106.91 177.56,119.02 178.53,119.02 178.86,119.35 179.1,119.35 179.58,119.83 179.58,120.69 178.87,121.4 v2(178.87,121.66)
DMI_CRX_PTX_N3: length 110.9
  BOTTOM w0.076: v2(171.62,132.43) 171.45,132.43 UH1.J9
  BOTTOM w0.089: 84.65,94.22 84.63,94.22 84.56,94.29 84.36,94.29 83.6,93.52 83.6,93.23 83.35,92.98 83.19,92.98 UH2.C29
  BOTTOM w0.152: v2(180.08,118.86) 180.02,118.8 180.02,118.4 179.69,118.06 177.72,118.06 v5(175.43,115.78) 162.16,102.51 118.13,102.51 116.68,103.95 115.48,103.95 110.71,99.19 108.09,96.57 103.01,96.57 102.11,95.67 95.12,95.67 93.99,96.8 90.49,96.8 88.38,94.7 86.86,94.7 86.38,94.22 84.65,94.22
DMI_CRX_PTX_P0: length 111.7
  BOTTOM w0.076: UH1.D8 174.14,131.25 174.22,131.32 v2(174.22,131.64)
  BOTTOM w0.089: UH2.B33 81.08,93.41 81.52,93.84 81.52,95.61 81.45,95.68 81.45,95.71
  BOTTOM w0.152: v2(177.09,121.81) 177.24,121.66 177.24,121.4 165.16,109.33 116.77,109.33 106.77,99.33 101.87,99.33 100.91,98.37 96.45,98.37 95.11,99.7 89.49,99.7 87.6,97.81 82.9,97.81 81.45,96.35 81.45,95.71
DMI_CRX_PTX_P1: length 110.9
  BOTTOM w0.076: v2(173.57,130.85) 173.53,130.85 173.24,130.57 UH1.E6
  BOTTOM w0.089: 82.47,95.86 82.46,95.85 82.46,95.75 82.13,95.42 82.13,93.76 81.86,93.49 81.86,93.16 81.77,93.07 81.65,93.07 81.58,93.15 81.58,93.23 UH2.B32
  BOTTOM w0.152: v2(178.2,120.47) 178.09,120.36 177.31,120.36 165.2,108.25 116.84,108.25 107.08,98.48 102.22,98.48 101.32,97.58 95.96,97.58 94.77,98.77 89.7,98.77 87.94,97.01 83.62,97.01 82.47,95.86
DMI_CRX_PTX_P2: length 113.2
  BOTTOM w0.076: UH1.D5 173.89,129.59 173.95,129.53 174.07,129.53 174.21,129.67 v2(174.21,130.04)
  BOTTOM w0.089: 83.94,95.79 83.92,95.79 83.85,95.72 83.72,95.72 82.71,94.72 82.71,93.59 82.57,93.45 82.57,93.27 82.44,93.14 82.34,93.14 UH2.B31
  BOTTOM w0.152: 83.94,95.79 85.88,95.79 86.27,96.18 88.26,96.18 90.02,97.95 v5(91.95,97.95) 94.43,97.95 95.58,96.79 101.64,96.79 102.55,97.69 107.61,97.69 117.16,107.24 165.32,107.24 177.42,119.35 178.39,119.35 178.72,119.68 178.96,119.68 179.25,119.97 179.25,120.55 178.78,121.02 178.3,121.02 178.13,121.2 178.13,121.51 v2(178.28,121.66)
DMI_CRX_PTX_P3: length 110.6
  BOTTOM w0.076: v2(171.62,131.64) 171.3,131.64 UH1.J8
  BOTTOM w0.089: UH2.B29 83.07,93.34 83.07,93.27 83.17,93.17 83.27,93.17 83.41,93.31 83.41,93.6 84.28,94.48 84.56,94.48 84.63,94.55 84.65,94.55
  BOTTOM w0.152: v2(179.5,118.86) 179.69,118.67 179.69,118.54 179.55,118.39 177.58,118.39 162.02,102.84 118.26,102.84 116.81,104.29 115.34,104.29 107.95,96.9 102.87,96.9 101.97,96 95.26,96 94.13,97.13 90.35,97.13 88.24,95.03 86.73,95.03 86.25,94.55 84.65,94.55
DMI_CTX_PRX_N0: length 102.7
  BOTTOM w0.076: UH1.A8 175.76,131.16 175.54,131.16 175.47,131.23 175.47,131.47 175.59,131.59 176,131.59 176.15,131.44 177.61,131.44 177.69,131.36 177.7,131.36
  BOTTOM w0.152: v2(81.18,89.6) 81.03,89.75 80.36,89.75 80.25,89.64 80.25,89.42 UH2.K34 ; 177.7,131.36 177.92,131.36 178.27,131.01 178.31,130.97 178.31,130.51 179.7,129.11 179.7,127.51 177.86,123.63 175.83,121.6 175.83,121.28 165.01,110.46 116.7,110.46 112.31,106.08 103.54,106.08 101.46,103.99 101.46,101.26 101.84,100.88 101.84,99.99 101.71,99.86 v2(101.68,99.86)
DMI_CTX_PRX_N1: length 98.7
  BOTTOM w0.076: 177.24,130.39 177.23,130.4 177.23,130.52 176.97,130.78 174.92,130.78 174.82,130.68 174.82,130.57 174.94,130.46 UH1.B6
  BOTTOM w0.152: v2(81.67,90.81) 81.62,90.87 81.31,90.87 UH2.G33 ; 177.24,130.39 178.28,129.35 178.28,127.35 176.91,124.61 176.91,123.79 175.04,121.93 175.04,121.62 164.96,111.53 116.66,111.53 112.15,107.03 107.68,107.03 106.63,108.07 104.08,108.07 100.38,104.37 100.38,103.36 100.18,103.16 100.18,102.74 v2(100.03,102.59)
DMI_CTX_PRX_N2: length 99.7
  BOTTOM w0.076: 177.21,128.48 177.21,128.5 177.28,128.57 177.28,129.38 176.65,130 175.8,130 175.68,129.88 175.68,129.78 175.76,129.7 UH1.A5
  BOTTOM w0.152: v2(99.44,100.39) 99.25,100.58 98.81,100.58 98.41,100.98 v5(98.41,102.11) 98.41,103.65 100.04,105.28 100.04,107.23 104.36,111.55 115.05,111.55 115.95,112.45 164.76,112.45 174.16,121.85 174.16,122.13 176,123.97 176,124.9 177.21,127.44 177.21,128.48 ; UH2.K32 81.8,89.27 v2(82.12,89.59)
DMI_CTX_PRX_N3: length 100.7
  BOTTOM w0.076: UH1.B4 174.81,129.02 174.63,129.02 174.56,128.96 174.56,128.84 174.75,128.65 175.05,128.65 175.63,129.23 175.97,129.23 176.2,129 176.2,127.34 175.94,127.09 175.83,127.09 175.81,127.07
  BOTTOM w0.152: UH2.G30 v2(83.23,90.75) ; v2(97.95,99.56) 97.95,100.3 97.55,100.7 97.55,104.25 98.88,105.58 98.88,107.31 103.96,112.39 112.59,112.39 113.98,113.77 118.12,113.77 118.64,113.25 164.44,113.25 175.18,123.99 175.18,125.24 175.44,125.76 175.44,126.7 175.81,127.07
DMI_CTX_PRX_P0: length 102.3
  BOTTOM w0.076: 177.7,131.69 177.69,131.69 177.61,131.61 176.22,131.61 176.07,131.75 175.5,131.75 175.3,131.55 175.3,131.35 UH1.B8
  BOTTOM w0.152: UH2.J35 80.3,90.09 v2(80.71,90.19) ; v2(102.32,99.86) 102.3,99.86 102.17,99.99 102.17,101.01 101.79,101.39 101.79,103.86 103.68,105.75 112.45,105.75 116.83,110.13 165.15,110.13 176.16,121.14 176.16,121.46 178.13,123.44 180.04,127.43 180.04,129.25 178.64,130.64 178.64,131.11 178.06,131.69 177.7,131.69
DMI_CTX_PRX_P1: length 99.2
  BOTTOM w0.076: UH1.C6 174.65,130.56 174.65,130.74 174.85,130.94 177.04,130.94 177.35,130.63 177.46,130.63 177.48,130.62
  BOTTOM w0.152: UH2.F34 81.25,91.39 v2(81.36,91.28) ; v2(100.66,102.59) 100.51,102.74 100.51,103.02 100.71,103.22 100.71,104.24 104.22,107.74 106.49,107.74 107.54,106.7 112.29,106.7 116.8,111.2 165.1,111.2 175.37,121.48 175.37,121.79 177.24,123.66 177.24,124.53 178.61,127.27 178.61,129.48 177.48,130.62
DMI_CTX_PRX_P2: length 99.7
  BOTTOM w0.076: UH1.B5 175.25,129.7 175.73,130.18 176.73,130.18 177.46,129.45 177.46,128.59 177.54,128.5 177.54,128.48
  BOTTOM w0.152: v2(99.44,100.97) 99.38,100.91 98.95,100.91 98.74,101.12 98.74,103.51 100.37,105.14 100.37,107.09 104.5,111.22 115.19,111.22 116.09,112.12 164.9,112.12 174.49,121.71 174.49,121.99 176.33,123.84 176.33,124.82 177.54,127.37 177.54,128.48 ; v2(81.96,90.18) 81.79,90.01 UH2.J32
DMI_CTX_PRX_P3: length 100.9
  BOTTOM w0.076: 176.05,126.84 176.06,126.85 176.06,126.97 176.36,127.27 176.36,129.07 176.04,129.39 175.56,129.39 175.43,129.27 174.63,129.27 UH1.D4
  BOTTOM w0.152: v2(82.97,91.25) 82.88,91.16 82.67,91.16 82.43,91.4 UH2.F30 ; v2(98.54,99.56) 98.28,99.92 98.28,100.44 97.88,100.84 97.88,104.12 99.21,105.44 99.21,107.17 104.1,112.06 112.73,112.06 114.11,113.44 117.98,113.44 118.5,112.92 164.58,112.92 175.51,123.86 175.51,125.16 175.77,125.68 175.77,126.56 176.05,126.84
DMIC_CLK_CODEC: length 10.4
  TOP w0.14: v2(11.73,102.89) 11.43,102.58 CA35.1
  BOTTOM w0.108: v2(11.73,102.89) 11.61,103.02 11.61,103.07 10.56,104.12 UA1.53
  BOTTOM w0.14: RE116.1 150.32,77.52 148.83,77.52 148.52,77.21 v1(148.25,77.21) 148.02,77.21 146.87,76.06 DE9.2 146.87,75.2 146.36,74.69 146.36,73.59 146.28,73.51 v2(146.28,73.36)
  vias: v2(8.38,77.13) v2(60.92,68.23) v2(112.05,68.92)
DMIC_CLK_CODEC_C: length 6.6
  TOP w0.14: v2(152.95,78.43) v4(153.53,78.43)
  BOTTOM w0.14: JKB.12 155.56,78.13 155.41,78.29 153.09,78.29 v2(152.95,78.43) 152.25,78.43 CE73.1 151.43,77.62 RE116.2 151.33,78.39 RE310.2
DMIC_DAT_CODEC: length 9
  BOTTOM w0.108: CA36.1 11.04,102.32 v2(11.04,102.81)
  BOTTOM w0.14: RE117.1 149.91,76.73 149.49,77.15 148.98,77.15 148.64,76.8 148.16,76.8 147.87,76.51 DE9.3 147.74,75.59 146.7,74.55 146.7,73.63 v2(146.85,73.48) ; UA1.54 10.44,103.72 11.04,103.12 v2(11.04,102.81)
  vias: v2(6.4,80.31) v2(61.5,68.25) v2(111.38,68.91)
DMIC_DAT_CODEC_C: length 12.3
  TOP w0.14: v2(156.06,74.77) v4(156.95,73.88)
  BOTTOM w0.14: JKB.11 156.06,76.94 155.66,76.54 155.36,76.54 155.07,76.24 155.07,75.75 155.36,75.46 155.77,75.46 156.06,75.16 v2(156.06,74.77) 154.6,74.77 153.85,75.52 153.28,75.52 CE74.1 152.07,76.73 RE117.2 151.2,76.59 RE309.2
DOCK_TNY_SMB_CLK: length 33.6
  TOP w0.14: v2(53.44,93.54) 53.44,93.58 53.86,94 57.07,94 58.94,92.13 60.77,92.13 61.39,92.75 61.39,93.98 61.87,94.46 64.26,94.46 67.61,97.8 67.61,99.02 71.3,102.71 v5(72.68,102.71) 74.78,102.71 75.15,103.08 78.23,103.08 78.62,102.69 78.91,102.69 RE109.1
  BOTTOM w0.14: v2(17.06,130.57) 16.93,130.45 16.93,130.14 RT184.1
DOCK_TNY_SMB_DAT: length 32.8
  TOP w0.14: v2(54.04,93.58) 54.07,93.61 56.98,93.61 58.85,91.74 60.93,91.74 61.78,92.59 61.78,93.81 62.08,94.11 64.4,94.11 67.95,97.66 67.95,98.8 71.46,102.32 v5(74.69,102.32) 74.94,102.32 75.31,102.68 78.07,102.68 78.45,102.3 78.91,102.3 RE108.1
  BOTTOM w0.14: v2(16.47,130.57) 16.54,130.51 16.54,130.26 RT185.1
DPM_REXT: length 2.6
  TOP w0.14: v1(317.8,98.82) RI23.1 318.82,98.95 319.24,99.37 UI3.7
DPSRC_RBIAS: length 4.2
  TOP w0.089: RT2.1 27.61,108.81 26.65,107.85 v1(26.11,107.85) 25.58,107.85 25.37,108.06 25.37,108.46 25.76,108.85 v2(25.76,108.86)
  BOTTOM w0.102: v2(25.76,108.86) 25.76,108.88 UT1.N6
DRON: length 14.2
  TOP w0.14: v1(127.6,185.16) 127.95,184.8 v2(128.32,184.8)
  TOP w0.203: v2(111.75,180.21) 111.61,180.08 PU1100.17
  BOTTOM w0.254: PU1200.16 128.85,183.64 128.32,184.17 v2(128.32,184.8) ; v2(110.67,137.56) 110.79,137.69 110.79,138.32 110.52,138.6 PU1700.16 ; v2(153.47,185.18) 153.72,184.93 153.72,183.91 154.19,183.45 PU1252.16 ; v2(146.1,185.18) 146.42,184.87 146.42,183.72 146.69,183.45 PU1251.16 ; v2(103.56,163.21) 103.56,161.69 103.7,161.54 PU1701.16
  BOTTOM w0.305: PU1201.16 137.84,183.64 137.46,184.02 137.46,184.99 v2(137.66,185.18)
DTH_CSCL: length 4.1
  TOP w0.14: RM14.2 24.87,134.73 25.07,134.93 T4936.1 24.68,135.23 24.35,134.9 RM18.1 24.19,135.9 v2(23.8,136.29) ; v2(19.34,140.11) 19.32,140.11 18.92,140.5 UM1.E6
DTH_CSDA: length 4.5
  TOP w0.14: RM17.1 22.97,133.89 23.16,134.08 23.16,134.78 23.29,134.9 RM16.2 23.77,135.12 23.77,135.69 T4937.1 23.29,136.17 23.29,136.54 v2(23.67,136.92) ; UM1.F6 v2(19.34,140.88)
DTH_PDB: length 4.6
  TOP w0.14: UM1.C3 v2(20.94,139.27) ; RM27.2 25.58,144.06 RM5.1 ; RM27.2 24.71,143.15 RV561.1 ; RM27.2 v2(26.34,144.04)
  BOTTOM w0.14: v2(67.04,80.19) 67.04,79.76 67.26,79.55 RH5895.1
  vias: v2(41.25,91.97)
DTH_PDB_R: length 7.4
  BOTTOM w0.089: UH2.AU47 74.2,76.53 74.04,76.69 73.67,76.69 72.97,77.39 72.9,77.39 72.66,77.63 72.07,77.63 71.48,78.22 71.04,78.22
  BOTTOM w0.14: RH5895.2 68.43,79.32 68.71,79.04 70.23,79.04 71.04,78.22
DTH_RST#: length 6.6
  TOP w0.14: UM1.B8 17.32,137.84 16.26,136.78 v1(16.26,135.7) 16.26,135.02 16.8,134.48 16.8,134.35 17.13,134.02 17.44,134.02 17.7,133.75 CM41.1 18.73,133.75 RM6.2
DTH_SPI_CK_OUT: length 6.1
  TOP w0.14: UM1.D2 22.55,139.27 23.13,139.27 23.52,138.88 v2(23.91,138.88) 24.09,138.7 RM9.1
  BOTTOM w0.14: UM2.6 21.54,159.91 22.2,160.57 v2(23.01,160.57)
DTH_SPI_CS: length 5
  TOP w0.14: RM7.2 25.38,161.38 v1(24.59,161.38) v2(23.9,161.38) ; UM1.C1 23.02,138.9 23.62,138.3 v2(23.94,138.3)
  BOTTOM w0.14: UM2.1 24.56,162.45 23.9,161.79 v2(23.9,161.38)
DTH_SPI_D_IN: length 1.9
  TOP w0.14: UM1.C2 v2(21.72,139.3)
  BOTTOM w0.14: UM2.2 24.53,161.18 v2(24.17,160.82)
DTH_SPI_D_OUT: length 3.8
  TOP w0.14: v2(23.58,139.68) 23.55,139.7 UM1.D1
  BOTTOM w0.14: v2(22.83,159.76) 22.77,159.82 22.34,159.82 21.16,158.64 UM2.5
DTH_SPI_WR_PROT: length 5.3
  TOP w0.14: UM1.E2 21.7,140.91 v2(21.7,140.92) ; v2(23.58,160.84) 23.58,160.57 v1(24.21,159.95) RM28.1
  BOTTOM w0.14: v2(23.58,160.84) 23.58,160.57 24.24,159.91 UM2.3
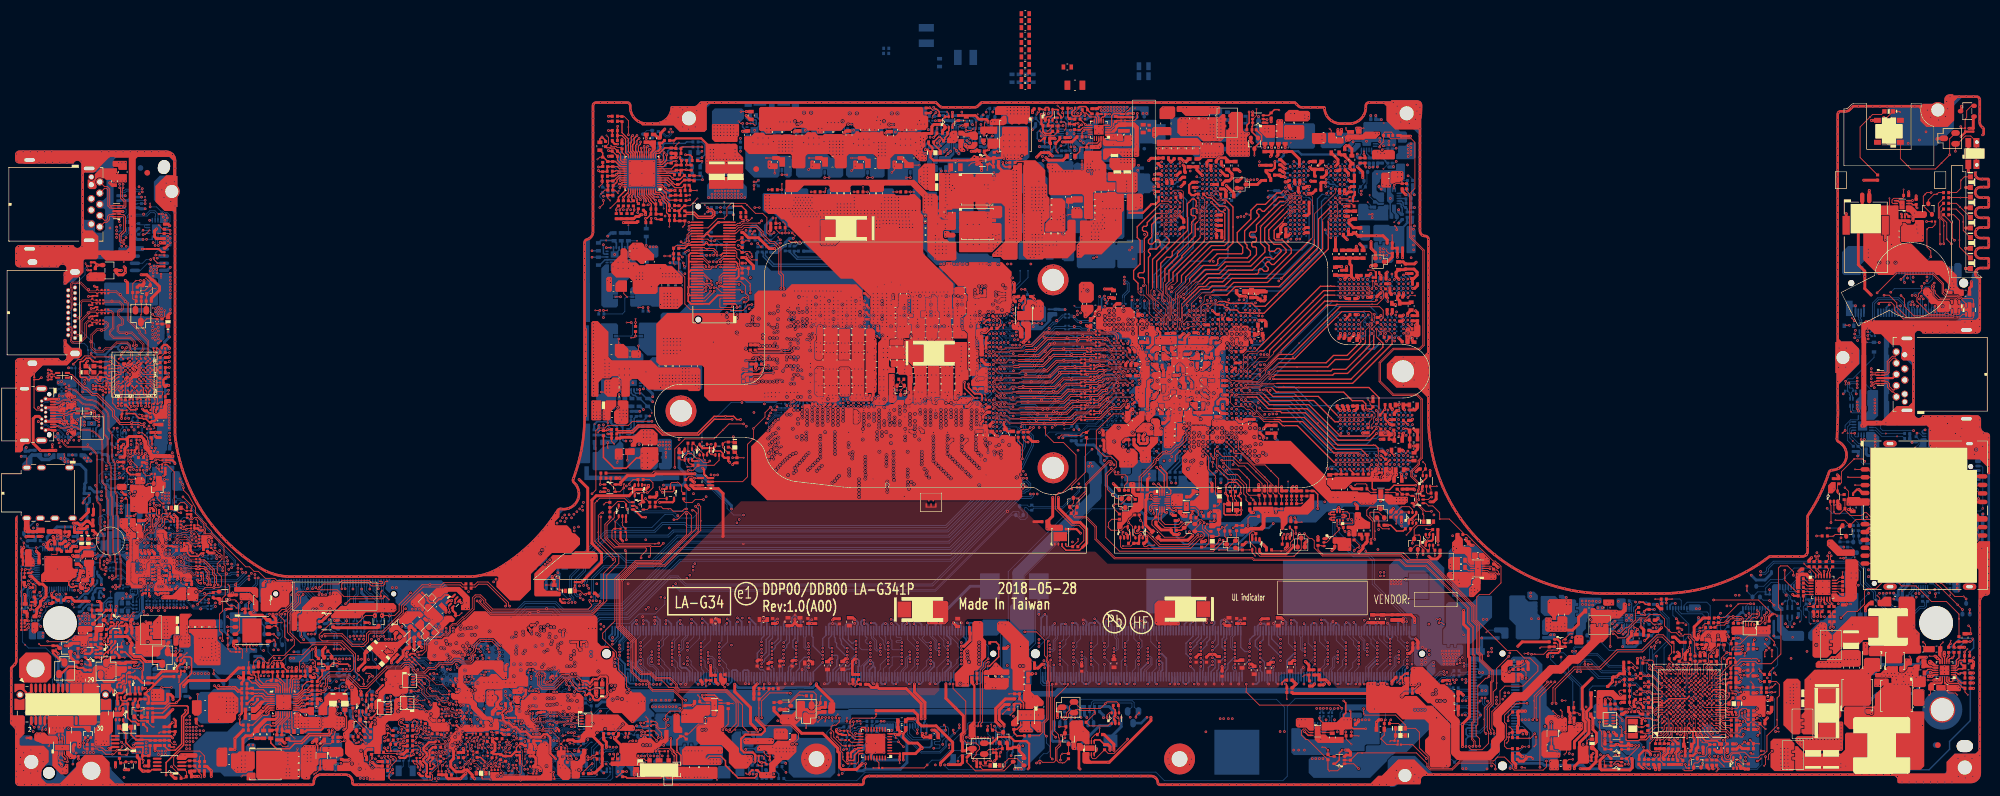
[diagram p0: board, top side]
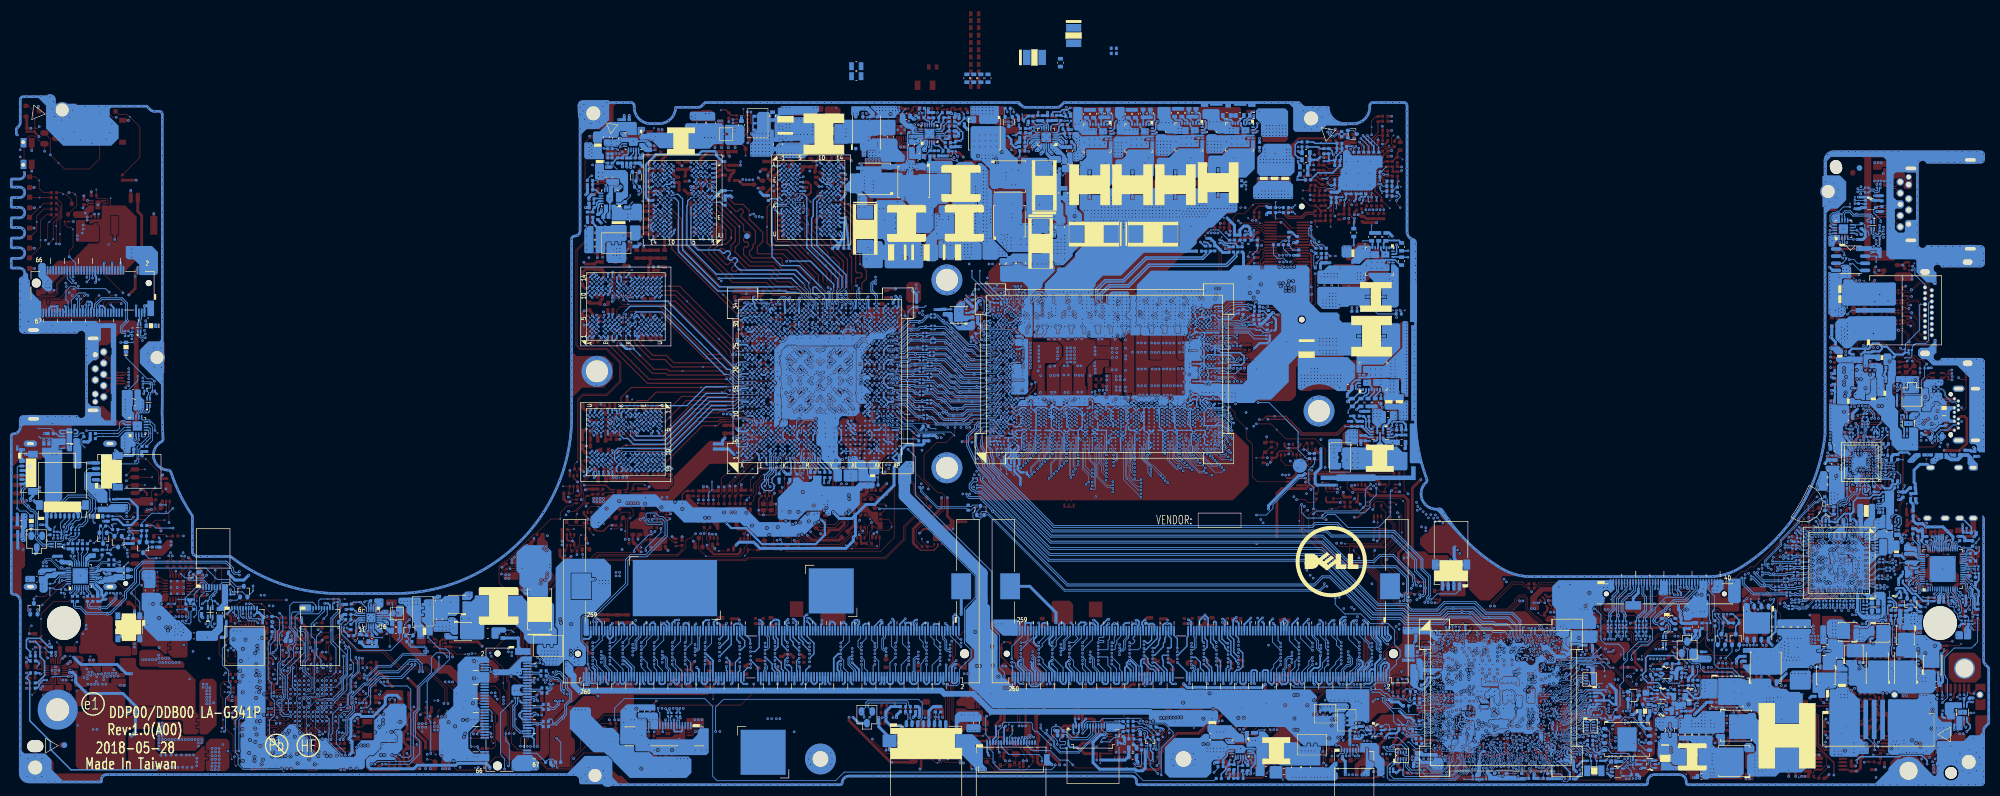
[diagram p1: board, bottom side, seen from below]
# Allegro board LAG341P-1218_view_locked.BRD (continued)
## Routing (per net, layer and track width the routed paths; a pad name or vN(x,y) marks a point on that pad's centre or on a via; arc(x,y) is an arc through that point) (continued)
DTH_VDD12:
  vias: v2(18.52,139.3) v2(20.12,140.9)
DTH_VDD12_ON: length 22.5
  TOP w0.14: v2(9.22,141.97) 9.53,142.27 9.57,142.27 10.07,142.77 10.61,142.77 11.27,143.43 12.65,143.43 12.82,143.25 v1(15.47,143.25) 16.16,143.25 UM1.G8
  BOTTOM w0.14: v2(9.22,141.97) 9.61,141.58 RM21.2 9.61,139.66 10.18,139.09 10.18,136.71 10.3,136.58 13.09,136.58 13.64,136.04 13.64,134.13 12.75,133.24 UZ25.3
DTH_VDD33: length 2.3
  TOP w0.254: UM1.G4 20.89,142.47 v2(20.9,142.47) ; v2(22.51,142.49) UM1.G2 ; UM1.B2 v2(22.53,137.69)
  BOTTOM w0.381: CM4.2 v2(22.53,137.69)
  vias: v1(21.62,142.35)
DTH_VDDA12:
  vias: v1(20.04,142.36) v2(20.12,141.7)
DTH_VDDRX12: length 1.2
  TOP w0.254: UM1.B5 19.72,138.09 v2(20.12,137.69) 20.52,138.09 UM1.B4
  vias: v1(22.86,140.19) v2(22.52,140.89)
DTH_VDDTX12:
  vias: v1(16.95,137.98) v2(17.72,137.7) v2(18.52,141.7) v2(19.32,141.7)
DTH_XTLI: length 5.1
  TOP w0.152: RM103.1 15.47,139.88 RM1834.1 14.21,140.41 CM43.1 14.03,140.55 13.63,140.15 13.63,140.04 13.41,139.81 12.24,139.81 11.55,140.51 YM1.1
DTH_XTLI_R: length 1.8
  TOP w0.14: RM103.2 15.82,140.63 17.18,140.63 UM1.E8
DTH_XTLO: length 3.1
  TOP w0.152: RM102.1 15.34,141.73 RM1834.2 14.18,141.32 CM44.1 13.9,141.61 YM1.3
DTH_XTLO_R: length 1.7
  TOP w0.14: RM102.2 17.16,141.15 UM1.F8
EC_SLP_S0IX#: length 4.1
  TOP w0.089: RH535.1 82.85,75.71 82.4,75.25 81.77,75.25 v1(81.75,75.23) 81.45,74.92 81.45,74.69 81.13,74.37 81.13,73.88 v2(81.33,73.67)
  BOTTOM w0.089: v2(81.33,73.67) 81.22,73.56 UH2.BC33
EC_SMB_CK2_PX: length 3
  TOP w0.14: RV326.2 198.88,114.79 199.1,114.57 v2(199.1,114.17) 199.51,113.76 QV21.1
  BOTTOM w0.14: v2(206.93,127.27) UV18.T4
EC_SMB_DA2_PX: length 5.7
  TOP w0.14: QV21.4 198.21,111.25 197.68,111.78 197.68,113.09 v2(196.98,113.79) 196.98,114.22 v1(197.18,114.42) 197.9,115.14 RV325.2
  BOTTOM w0.14: UV18.T3 v2(206.95,126.49)
EDP_AUXN: length 5.1
  BOTTOM w0.076: v2(176.91,145.36) 177.04,145.5 177.18,145.5 177.26,145.41 177.26,145.17 176.99,144.89 176.46,144.89 176.42,144.86 176.31,144.86 176.07,145.09 174.97,145.09 174.82,145.24 174.82,145.38 174.91,145.47 175.14,145.47 UH1.B26
  BOTTOM w0.152: v2(59.72,93.58) 59.52,93.78 59.52,94.32 59.59,94.39 CV166.1
EDP_AUXN_C: length 0.8
  BOTTOM w0.152: CV166.2 59.59,95.13 59.59,95.46 RV528.1
EDP_AUXN_R: length 7.6
  BOTTOM w0.152: RV528.2 59.59,96.35 59.59,96.94 58.41,98.12 58.41,100.89 58.41,101.47 58.41,101.53 58.41,101.53 58.41,101.6 58.41,101.6 58.41,102.35 58.49,102.44 JEDP1.15
EDP_AUXP: length 4.8
  BOTTOM w0.076: UH1.C26 174.64,145.32 174.64,145.17 174.9,144.91 176,144.91 176.24,144.68 176.42,144.68 176.44,144.66 176.47,144.66 176.49,144.68 176.56,144.68 176.6,144.72 177.17,144.72 177.52,145.06 177.52,145.25 v2(177.62,145.36)
  BOTTOM w0.152: v2(59.12,93.59) 59.19,93.66 59.19,94.3 CV167.1
EDP_AUXP_C: length 0.8
  BOTTOM w0.152: RV529.1 59.26,95.46 59.26,95.13 CV167.2
EDP_AUXP_R: length 7.6
  BOTTOM w0.152: RV529.2 59.26,96.35 59.26,96.81 58.08,97.99 v5(58.08,98.25) 58.08,100.89 58.08,101.47 58.08,102.37 57.99,102.46 JEDP1.16
EDP_COMP: length 2.4
  TOP w0.089: v2(173.93,153.04) 173.49,153.04 v1(173.28,153.24)
  TOP w0.508: RH30.1 174.42,153.53 v2(173.93,153.04)
  BOTTOM w0.381: v2(173.93,153.04) 173.93,152.6 UH1.D37
EDP_DISP_UTIL: length 7.9
  BOTTOM w0.14: v1(180.17,154.2) 179.39,153.41 RH456.1 178.45,153.41 178.04,153.82 177.45,153.82 176.94,153.31 176.94,151.29 177.18,151.05 177.18,150.87 176.89,150.59 UH1.A33
EDP_HPD: length 4.7
  BOTTOM w0.089: v2(94,77.88) 94,78.06 UH2.AN6
  BOTTOM w0.14: v2(48.06,92.86) 48.31,93.11 RV113.1 RV114.1
EDP_HPD_S: length 7.6
  BOTTOM w0.152: v2(48.09,100.93) 47.88,100.72 v1(47.88,97.25) 47.88,96.41 47.73,96.26 RV113.2 ; v2(54.13,100.93) 54.49,101.3 JEDP1.23
EDP_PANEL_CLK: length 11.1
  TOP w0.14: v3(57,101.97) 57,102.86 57.2,103.05 61.08,103.05 61.08,103.05 61.73,103.05 62.27,102.52 64.33,102.52 64.66,102.85 64.66,103.09 64.74,103.26 64.74,103.26 64.8,103.32 T5994.1
  BOTTOM w0.14: v3(57,101.97) 56.99,101.98 JEDP1.18
EDP_PANEL_DAT: length 13.7
  TOP w0.14: v3(53.01,102.23) 53.14,102.23 53.77,102.85 56.44,102.85 57.04,103.45 61.07,103.45 61.08,103.45 61.9,103.45 62.43,102.91 64.16,102.91 64.27,103.02 64.27,103.18 64.27,103.18 64.13,103.32 T5995.1
  BOTTOM w0.14: JEDP1.26 52.99,102.24 v3(53.01,102.23)
EDP_TXN0: length 1.6
  BOTTOM w0.076: UH1.E29 173.45,147.78 173.53,147.7 v2(173.53,147.39)
  BOTTOM w0.152: v2(60.95,93.59) 60.77,93.77 60.77,94.15 CV159.1
EDP_TXN0_C: length 0.8
  BOTTOM w0.152: RV521.1 60.85,95.45 60.85,95.14 CV159.2
EDP_TXN0_R: length 7.9
  BOTTOM w0.152: JEDP1.12 59.99,102.47 59.91,102.38 59.91,100.94 59.44,100.47 59.44,98.25 v5(60.55,97.14) 60.86,96.83 60.86,96.34 RV521.2
EDP_TXN1: length 1.5
  BOTTOM w0.076: v2(173.58,146.58) 173.58,146.66 UH1.E28
  BOTTOM w0.152: v2(63.3,93.54) 63.17,93.67 63.17,94.26 CV161.1
EDP_TXN1_C: length 0.8
  BOTTOM w0.152: CV161.2 63.12,95.16 63.12,95.43 RV523.1
EDP_TXN1_R: length 8.4
  BOTTOM w0.152: RV523.2 63.14,96.35 63.14,97.53 63.6,97.99 63.6,99.8 62.28,101.12 62.04,101.12 61.41,101.75 61.41,102.38 61.49,102.47 JEDP1.9
EDP_TXN2: length 3.3
  BOTTOM w0.076: v2(177.04,147.11) 176.85,147.3 176.61,147.3 176.5,147.4 176.14,147.4 176.02,147.28 175.53,147.28 175.3,147.51 175.3,147.68 UH1.B29
  BOTTOM w0.152: CV163.1 64.35,94.17 64.35,93.64 v2(64.47,93.52)
EDP_TXN2_C: length 0.8
  BOTTOM w0.152: RV525.1 64.41,95.45 64.41,95.13 CV163.2
EDP_TXN2_R: length 7.7
  BOTTOM w0.152: JEDP1.6 62.99,102.48 62.91,102.39 62.91,101.8 64.41,100.3 64.41,96.35 RV525.2
EDP_TXN3: length 4.9
  BOTTOM w0.076: UH1.B28 175.11,147.08 174.97,147.08 174.89,146.99 174.89,146.9 175.11,146.68 176.02,146.68 176.23,146.47 176.32,146.47 176.54,146.69 176.88,146.69 176.96,146.61 176.96,146.4 176.87,146.32 v2(176.68,146.32)
  BOTTOM w0.152: v2(65.93,93.01) 65.73,93.21 65.73,94.16 CV165.1
EDP_TXN3_C: length 0.8
  BOTTOM w0.152: RV527.1 65.82,95.46 65.82,95.12 CV165.2
EDP_TXN3_R: length 7.7
  BOTTOM w0.152: RV527.2 65.81,96.35 65.81,97.64 65.21,98.24 65.21,100.72 64.41,101.52 64.41,102.39 64.49,102.47 JEDP1.3
EDP_TXP0: length 1.4
  BOTTOM w0.076: v2(174.27,147.4) 174.27,147.41 UH1.D29
  BOTTOM w0.152: v2(60.36,93.59) 60.44,93.66 60.44,94.33 CV158.1
EDP_TXP0_C: length 0.8
  BOTTOM w0.152: CV158.2 60.52,95.12 60.52,95.47 RV520.1
EDP_TXP0_R: length 7.9
  BOTTOM w0.152: RV520.2 60.53,96.35 60.53,96.69 v5(59.37,97.85) 59.11,98.11 59.11,100.6 59.58,101.07 59.58,102.37 59.49,102.46 JEDP1.13
EDP_TXP1: length 1.5
  BOTTOM w0.076: UH1.F28 172.94,146.65 v2(172.94,146.58)
  BOTTOM w0.152: CV160.1 62.84,94.22 62.84,93.66 v2(62.71,93.54)
EDP_TXP1_C: length 0.8
  BOTTOM w0.152: RV522.1 62.84,95.43 62.84,95.16 CV160.2
EDP_TXP1_R: length 8.4
  BOTTOM w0.152: JEDP1.10 60.99,102.45 61.08,102.36 61.08,101.61 61.9,100.79 62.15,100.79 63.27,99.67 63.27,98.12 62.81,97.67 v5(62.81,97.19) 62.81,96.35 RV522.2
EDP_TXP2: length 3.5
  BOTTOM w0.076: v2(177,147.7) 177,147.58 176.9,147.48 176.68,147.48 176.58,147.58 176.07,147.58 175.95,147.46 175.6,147.46 175.48,147.59 175.48,147.82 175.55,147.89 175.74,147.89 UH1.A29
  BOTTOM w0.152: v2(63.88,93.52) 64.02,93.66 64.02,94.31 CV162.1
EDP_TXP2_C: length 0.8
  BOTTOM w0.152: RV524.1 64.08,95.46 64.08,95.12 CV162.2
EDP_TXP2_R: length 7.7
  BOTTOM w0.152: RV524.2 64.08,96.35 v5(64.08,97.22) 64.08,100.16 62.58,101.67 62.58,102.4 62.49,102.48 JEDP1.7
EDP_TXP3: length 4.8
  BOTTOM w0.076: v2(177.3,146.31) 176.95,145.96 176.49,145.96 175.95,146.5 175.04,146.5 UH1.C28
  BOTTOM w0.152: v2(65.35,93.01) 65.4,93.06 65.4,94.32 CV164.1
EDP_TXP3_C: length 0.8
  BOTTOM w0.152: RV526.1 65.49,95.45 65.49,95.13 CV164.2
EDP_TXP3_R: length 7.7
  BOTTOM w0.152: JEDP1.4 63.99,102.49 64.08,102.4 64.08,101.39 64.88,100.58 64.88,98.1 65.48,97.5 v5(65.48,97.17) 65.48,96.35 RV526.2
EN_1V: length 8.4
  TOP w0.14: v1(132.16,72.99) 132.16,72.76 132.77,72.15 PR505.1
  TOP w0.254: PR505.1 v2(133.15,71.51)
  BOTTOM w0.254: PR503.2 133.91,70.21 133.91,69.87 134.73,69.04 PR1950.2 ; PR503.2 133.35,71.31 v2(133.15,71.51) ; PR503.2 132.9,70.77 132.85,70.72 PC511.1 132.46,71.45 132.21,71.71 PU500.11
EN_1VS_VCCIO: length 5.5
  BOTTOM w0.14: PR803.2 v1(112.75,130.88)
  BOTTOM w0.254: PR803.2 PR804.1 PC806.1 109.65,130.76 108.32,129.44 PU800.5
EN_INVPWR: length 7.6
  TOP w0.14: QV12.2 34.27,101.48 RV135.1 33.97,101.19 33.22,101.19 31.35,99.31 v2(31.35,99.22) ; v2(108.78,74.95) 108.24,74.95 v1(108.08,74.78) ; v2(291.7,76.44) 292.28,77.02 292.28,77.62 UE3.B2
EN_PD_HV_1: length 24.1
  TOP w0.14: v2(52.03,86.9) 52.4,86.9 v1(52.81,86.49)
  TOP w0.254: PQ212.5 28.37,89.35 28.91,89.88 30,89.88 30.28,89.6 30.28,86.96 28.22,84.9 28.22,82.39 v2(27.58,81.75) 27.43,81.6 26.31,81.6 25.42,80.71 PR247.1 PR248.1 21.84,80.71 21.4,80.28 20.26,80.28 19.85,80.68 PR262.2 19.85,81.61 20.24,82 PR250.1
  BOTTOM w0.14: RT178.2 14.96,121.97 v2(15.09,121.84)
  BOTTOM w0.254: v2(52.03,86.9) 52.15,87.02 PR277.1
EN_PD_HV_1#: length 2.8
  TOP w0.14: v1(28.06,85.32) 28.06,85.77 28.07,85.77 PR231.2
  TOP w0.254: PQ212.3 PQ212.2 28.37,86.68 PR231.2
ENVDD: length 8.2
  TOP w0.508: UZ8.4 55.62,95.06 v1(59.74,95.06) RZ40.1 63.28,95.06 DV7.1
ENVDD_PCH: length 29.2
  TOP w0.14: DV7.3 61.2,97.23 59.74,95.78 54.91,95.78 52.99,93.85 52.99,93.26 53.53,92.73 57.12,92.73 59.43,90.42 59.43,87.3 v1(60.09,86.64) 60.9,85.82 v2(60.9,85.02)
  BOTTOM w0.089: UH2.AV44 75.43,75.5 75.01,75.08 74.27,75.08 74.15,75.2 72.67,75.2 72.42,75.44 v2(72.44,75.42)
ESPI_ALERT#: length 7.7
  TOP w0.089: RH5883.2 79.4,76.24 RH5882.2 80.3,75.99 v3(79.81,75.5)
  TOP w0.14: UE3.H7 297.13,82.46 v2(297.13,82.47) ; RH1943.1 118.69,76.17 v1(119.32,76.79) 120.45,77.92 121.39,77.92 121.73,78.26 v2(121.73,78.91)
ESPI_ALERT#_R: length 3.6
  TOP w0.089: RH5883.1 79.34,75.44 80.01,74.77 80.45,74.77 v3(80.54,74.86) 80.73,74.67 v1(80.73,73.91)
  BOTTOM w0.089: v3(80.54,74.86) 80.18,74.86 UH2.BA36
ESPI_CLK: length 2.3
  TOP w0.089: v2(79.02,74.38) 79.07,74.38 79.2,74.25 v1(79.2,73.91) 79.2,73.3 RH168.1
  BOTTOM w0.089: v2(79.02,74.38) 79.39,74.01 UH2.BB36
ESPI_CLK_5105: length 26.5
  TOP w0.089: RH168.2 78.91,71.95 CH198.1 78.66,71.64 79.48,70.83 79.48,70.43 v2(79.91,70)
  TOP w0.14: v2(297.12,81.66) UE3.G7
  BOTTOM w0.076: v2(297.12,81.66) 297.48,82.02 297.48,82.7 297.29,82.89 295.36,82.89 295.12,83.12 295.12,84.3 294.96,84.46 294.47,84.46 294.32,84.61 294.32,85.98 293.99,86.31 293.12,86.31 292.61,86.82
  BOTTOM w0.14: 292.61,86.82 v1(292.26,87.17) 292.26,91.46 293.15,92.35 293.15,96.79 291.95,97.99 RE313.2
ESPI_CLK_5105_JLPDE: length 3.5
  TOP w0.14: v1(293.74,100.16) RE62.1 292.67,99.47 v2(292.66,99.46)
  BOTTOM w0.14: RE313.1 292.49,99.62 v2(292.66,99.46) 292.82,99.3 JLPDE1.10
ESPI_CS#: length 23.5
  TOP w0.14: v2(297.92,80.86) UE3.H6
  BOTTOM w0.076: v2(297.92,80.86) 298.28,81.22 298.28,82.6 298.07,82.82 297.74,82.82 297.27,83.29 296.34,83.29
  BOTTOM w0.089: UH2.BE38 78.72,72.14 78.52,71.94 78.52,71.62 78.65,71.48 78.65,70.36 v2(78.7,70.32)
  BOTTOM w0.14: JLPDE1.7 294.32,98.05 296.66,95.71 296.66,93.61 295.99,92.94 295.99,89.75 296.13,89.61 296.13,83.5 296.34,83.29
ESPI_IO0: length 28.5
  TOP w0.14: v2(113.05,75) 112.09,75.96 112.06,75.96 ; v2(299.52,80.06) UE3.K5
  BOTTOM w0.076: v2(299.52,80.06) 299.92,79.66 300.7,79.66
  BOTTOM w0.14: JLPDE1.3 296.32,98.03 296.47,97.88 299.9,97.88 300.14,97.64 300.14,95.06 299.37,94.29 299.37,92.11 299.83,91.65 299.83,89.72 301.91,87.64 301.91,87.03 301.29,86.41 301.29,82.59 301.88,82.01 301.88,80.15 301.38,79.66 300.7,79.66
ESPI_IO0_R: length 1.9
  TOP w0.14: v2(110.26,75.85) 110.45,76.04 111.1,76.04 111.18,75.96 RC5831.1
  BOTTOM w0.089: UH2.BB39 77.82,73.8 77.68,73.94 v3(77.61,73.94)
ESPI_IO1: length 34.4
  TOP w0.14: v2(300.32,79.27) UE3.L4 ; v2(113.92,75.52) 113.92,76.37 112.94,77.34 112.94,77.73 v1(112.86,77.81) 112.8,77.87 112.27,77.87 RC5832.2
  BOTTOM w0.14: v2(300.32,79.27) 301.71,79.27 302.2,79.75 302.2,80.87 302.76,81.43 302.76,81.95 302.47,82.24 302.03,82.24 301.58,82.69 301.58,83.24 301.73,83.4 301.73,86.34 302.2,86.81 302.2,88.64 301.73,89.12 301.47,89.12 300.6,90 300.6,90.89 300.79,91.08 300.79,91.74 300.41,92.12 300.01,92.12 299.64,92.49 299.64,94.15 300.47,94.98 300.47,99 299.86,99.61 296.38,99.61 295.82,99.05 JLPDE1.4
ESPI_IO1_R: length 2.5
  TOP w0.14: RC5832.1 111.26,77.45 v1(110.49,77.45) 110.17,77.77 v2(110.17,78.12)
  BOTTOM w0.089: v2(78.54,75.61) 78.54,75.51 78.95,75.1 UH2.AW37
ESPI_IO2: length 36
  TOP w0.14: v2(297.12,80.86) 297.08,80.86 296.72,81.21 UE3.G6 ; v2(115.01,78.74) 115.01,78.71 114.69,78.39 114.69,77.31 114.54,77.15 113.51,77.15 113.22,77.44 113.22,77.98 112.83,78.38 112.06,78.38
  BOTTOM w0.076: 295.34,82.21 295.68,82.21 297.03,80.86 v2(297.12,80.86)
  BOTTOM w0.14: 295.34,82.21 294.6,82.21 294.34,82.48 292.84,82.48 291.2,84.12 291.2,86.04 290.45,86.79 290.45,90.33 292.81,92.69 292.81,96.64 291.52,97.93 291.52,99.94 291.76,100.18 295.05,100.18 295.32,99.91 JLPDE1.5
ESPI_IO2_R: length 3
  TOP w0.14: v2(110.76,78.12) 111.02,78.38 RC5833.1 111.48,78.83 v1(111.05,79.27)
  BOTTOM w0.089: v3(78.48,76.55) 78.62,76.55 79.27,75.9 UH2.AV37
ESPI_IO3: length 27.4
  TOP w0.14: v2(300.32,80.06) UE3.L5 ; 112.06,76.73 112.61,76.73 v1(112.98,76.36) 113.32,76.01 v2(113.32,75.53)
  BOTTOM w0.14: JLPDE1.6 294.82,98.1 295.38,97.54 299.05,97.54 299.53,97.06 299.53,95.06 299.1,94.63 299.1,93.58 297.92,92.4 297.92,90.61 300.32,88.2 300.32,87.25 300.91,86.66 300.91,82.48 300.72,82.29 300.72,80.46 v2(300.32,80.06)
ESPI_IO3_R: length 3
  TOP w0.14: RC5834.1 111.19,76.73 v2(110.93,76.47) 110.52,76.88 109.43,76.88 v1(109.33,76.79)
  BOTTOM w0.089: v2(78.28,74.86) 78.53,74.61 UH2.BA38
ESPI_RESET#: length 12.5
  TOP w0.089: v2(81.95,68.6) 81.95,69.23 81.71,69.48 81.71,70.12 80.91,70.91 80.5,70.91 80.18,71.23 80.18,71.58 80.38,71.77 RH5839.2 80.81,72.92 RH5838.1
  TOP w0.14: UE3.K6 299.52,80.86 303.52,80.86 303.69,80.69 v2(303.72,80.69) ; v2(81.95,68.6) 81.95,68.26 82.05,68.15 83.3,68.15 v1(83.41,68.04)
ESPI_RESET#_R: length 5.8
  TOP w0.089: RH5839.1 80.08,73.07 79.68,73.47 79.68,74.55 v3(79.41,74.81)
  BOTTOM w0.089: UH2.BF38 78.75,71.89 78.96,72.1 78.96,72.47 79.68,73.19 79.68,74.06 79.48,74.26 79.48,74.74 v3(79.41,74.81)
FB_2PH: length 6.6
  TOP w0.14: PC1118.2 103.8,172.94 v1(103.14,172.28)
  TOP w0.203: PU1100.34 106.31,175.51 105.36,174.57
  TOP w0.254: PC1118.2 104.37,172.99 PR1140.1 104.27,173.86 PR1141.1 104.32,174.57 PC1119.1 105.36,174.57
FB_3V: length 6
  TOP w0.14: v2(345.73,90.75) 345.73,90.77 v1(346.23,91.27)
  TOP w0.203: PR403.2 345.59,89.3 344.88,89.3 344.6,89.02 344.6,88.32 344.18,87.9 PU400.4
  TOP w0.254: PR403.2 PR401.2 345.72,90.73 v2(345.73,90.75)
  BOTTOM w0.254: v2(345.73,90.75) PC401.2
FB_4PH: length 7.1
  TOP w0.203: PC1115.2 116.24,173.93 v1(115.83,174.34) 115.06,175.11 PU1100.5
  TOP w0.254: PC1115.2 117.07,173.93 117.86,174.72 PR1137.1 PR1134.1 119.53,174.72 PC1117.2
FB_5V: length 4.1
  TOP w0.203: PR404.1 345,87.01 v2(344.82,86.84) 344.54,86.84 344.29,87.1 PU400.2
  TOP w0.254: PR404.1 PR402.1
  BOTTOM w0.254: PC402.1 345,87.01 v2(344.82,86.84)
FBA_ABI#_H: length 28.5
  TOP w0.102: v2(204.89,148.65) 204.89,150.53 204.65,150.77 204.65,152.96 204.61,152.99 204.61,153.79 203.81,154.59 203.81,155.77 204.52,156.48 204.65,156.48 204.9,156.74 ; v2(210.92,170.77) 210.92,169.71 210.5,169.29 210.5,165.01 210.47,164.98 210.47,164.11
  TOP w0.221: 204.9,156.74 204.9,158.31 v1(208.26,161.67) 210.47,163.88 210.47,164.11
  BOTTOM w0.102: UV24.J4 210.52,171.35 210.62,171.45 210.89,171.45 210.99,171.34 210.99,170.85 v2(210.92,170.77) ; UV18.Y29 204.53,149.17 204.76,149.17 204.91,149.03 204.91,148.66 v2(204.89,148.65)
FBA_ABI#_L: length 43.3
  TOP w0.102: v2(205.32,148.2) 205.73,148.61 205.73,150.07 205.98,150.32 205.98,153.73 205.85,153.85 205.85,154.16 208.43,156.74 208.59,156.74 ; v2(227.38,171.57) 227,171.19 226.42,171.19 226.17,171.43 226.17,171.71 225.93,171.95 225.62,171.95 225.4,171.73 225.4,171.45 224.89,170.94 224.54,170.94
  TOP w0.221: 208.59,156.74 210.65,158.8 212.83,158.8 214.17,160.14 218.43,160.14 219.74,161.45 219.74,162.6 219.52,162.82 219.11,162.82 218.89,163.04 218.89,163.48 219.11,163.7 219.52,163.7 219.74,163.92 219.74,164.37 219.52,164.59 218.71,164.59 218.51,164.79 218.51,165.23 218.75,165.47 219.52,165.47 219.74,165.69 219.74,166.75 v1(222.04,169.04) 223.93,170.94 224.54,170.94
  BOTTOM w0.102: v2(205.32,148.2) 205.7,147.82 UV18.V28 ; UV23.J4 v2(227.38,171.57)
FBA_CAS#_H: length 32.6
  TOP w0.102: v2(205.3,150.7) 204.9,151.1 204.9,152.47 205.37,152.94 205.37,154.78 207.13,156.53 207.13,156.74 ; v2(210.92,172.37) 211.31,171.98 211.99,171.98 212.8,171.17 213.74,171.17
  TOP w0.221: 213.74,171.17 213.75,171.17 214.32,171.17 215.56,169.92 v1(215.56,166.39) 215.56,163.54 214.35,162.33 212.03,162.33 207.13,157.42 207.13,156.74
  BOTTOM w0.102: UV24.G3 211.37,172.72 211.37,172.52 211.14,172.29 210.99,172.29 v2(210.92,172.37) ; UV18.V31 205.78,150.37 205.78,150.52 205.54,150.77 205.37,150.77 v2(205.3,150.7)
FBA_CAS#_L: length 40.5
  TOP w0.102: 224.54,172.84 224.63,172.93 225.14,172.93 225.71,172.36 v2(226.56,172.36)
  TOP w0.221: 224.54,172.84 224.12,172.42 223.35,172.42 221.33,170.39 219.82,170.39 218.74,169.32 218.74,167.81 216.32,165.39 216.32,163.78 217.29,162.82 217.29,161.77 217.12,161.6 212.75,161.6 v2(211.44,160.29)
  BOTTOM w0.102: 203.7,155.6 203.7,154.99 203.95,154.74 203.95,153.75 203.89,153.69 203.89,153.04 203.67,152.83 203.67,152.55 203.7,152.53 203.7,152.05 203.67,152.03 203.67,151.75 203.7,151.73 203.7,151.4 UV18.Y32 ; UV23.L3 226.97,172.77 v2(226.56,172.36)
  BOTTOM w0.221: 203.7,155.6 203.7,156.16 v1(206.83,159.3) 207.82,160.29 v2(211.44,160.29)
FBA_CKE_H: length 29.7
  TOP w0.102: 206.4,156.53 204.7,154.83 v2(204.61,154.83)
  TOP w0.221: 206.4,156.53 206.4,157.73 211.73,163.06 214.05,163.06 214.83,163.84 214.83,169.41 214.15,170.09 213.2,170.09 v2(211.72,171.57) 210.97,171.57 RV607.2
  BOTTOM w0.102: UV24.J3 v2(211.72,171.57) ; v2(204.61,154.83) 204.46,154.68 204.46,154.52 204.41,154.47 204.41,153.2 204.42,153.18 204.42,153.05 204.39,153.02 204.39,152.47 204,152.09 UV18.Y33
FBA_CKE_L: length 40.4
  TOP w0.102: v2(206.76,154.37) 208.97,156.58 209.47,156.58 209.62,156.74 ; RV605.2 227.81,170.39 226.87,170.39 226.58,170.68 v2(226.58,170.77) 226.32,170.77 225.9,171.18 225.51,171.18 224.54,170.21
  TOP w0.221: 209.62,156.74 210.95,158.07 213.13,158.07 214.47,159.41 218.73,159.41 221.25,161.93 221.25,162.71 220.47,163.49 v1(220.47,166.44) 224.24,170.21 224.54,170.21
  BOTTOM w0.102: 205.67,153.46 205.67,153.21 205.32,152.86 205.32,152.27 UV18.V33 ; UV23.J3 v2(226.58,170.77)
  BOTTOM w0.221: v2(206.76,154.37) 207.11,154.37 207.39,154.65 207.39,155.53 207.23,155.69 206.87,155.69 205.3,154.12 205.3,153.83 205.67,153.46
FBA_CLK0: length 3
  TOP w0.102: RV622.1 236.02,171.42 234.72,171.42 v2(234.58,171.57)
  BOTTOM w0.102: UV23.J12 v2(234.58,171.57)
  BOTTOM w0.114: UV18.R30 208.2,149.38 v2(208.51,149.07)
  vias: v2(218.7,174.76)
FBA_CLK0#: length 3.9
  TOP w0.102: v2(233.78,171.57) 234.18,171.16 236.12,171.16 RV621.1
  BOTTOM w0.114: UV18.R31 208.2,150.28 v2(208.59,149.9) ; UV23.J11 v2(233.78,171.57)
  vias: v2(219.29,174.76)
FBA_CLK1: length 2.7
  TOP w0.102: v2(204.49,170.8) 204.39,170.9 203.44,170.9 203.38,170.96 RV627.1
  BOTTOM w0.102: v2(204.49,170.8) 204.46,170.83 204.45,170.83 UV24.J12
  BOTTOM w0.114: v2(201.93,150.69) 202.33,150.29 UV18.AB31
  vias: v2(216.97,168.23)
FBA_CLK1#: length 3.1
  TOP w0.102: v2(204.52,171.53) 204.15,171.16 203.5,171.16 RV626.1
  BOTTOM w0.114: UV18.AC31 201.54,150.29 v2(201.94,149.89) ; UV24.J11 204.55,171.53 v2(204.52,171.53)
  vias: v2(217.55,168.23)
FBA_CS#_H: length 29.3
  TOP w0.102: 198.67,155.24 198.67,154.69 199.1,154.26 199.76,154.26 200.65,153.36 200.65,151 201.38,150.27 202.4,150.27 v2(202.78,149.89) ; v2(204.52,169.97) 204,170.49 202.61,170.49 202.43,170.31
  TOP w0.221: 198.67,155.24 198.67,156.35 197.88,157.14 197.88,158.63 v1(199.04,159.79) 199.04,163.98 198.52,164.5 198.52,166.4 202.43,170.31
  BOTTOM w0.102: UV24.L12 v2(204.52,169.97) ; UV18.AA31 203.19,150.29 v2(202.78,149.89)
FBA_CS#_L: length 41.1
  TOP w0.102: 209.04,149.81 208.73,149.5 207.3,149.5 v2(206.87,149.07) ; v2(233.78,169.17) 233.36,168.75 232.6,168.75 231.51,167.66 231.51,167.3
  TOP w0.119: 212.99,153.11 212.7,152.83 211.02,152.83 210.74,152.55 210.29,152.55 209.89,152.14 209.89,150.6 209.57,150.28 209.26,150.28 209.04,150.05 209.04,149.81
  TOP w0.221: 231.51,167.3 231.51,162.48 v1(223.34,154.31) 221.29,152.27 219.5,152.27 218.97,152.8 214.88,152.8 214.71,152.97 214.34,152.97 214.19,153.11 212.99,153.11
  BOTTOM w0.102: UV18.U30 206.5,149.44 v2(206.87,149.07)
  BOTTOM w0.107: UV23.G12 v2(233.78,169.17)
FBA_D0: length 1.3
  BOTTOM w0.102: UV18.L28 211.58,147.79 211.91,147.46 v2(211.91,147.42) ; v2(227.46,164.23) 227.78,164.55 UV23.A4
FBA_D1: length 1.3
  BOTTOM w0.102: UV18.M29 v2(210.28,148.22) ; UV23.A2 225.86,164.46 v2(225.86,164.21)
FBA_D2: length 1.2
  BOTTOM w0.102: UV18.L29 211.5,148.64 v2(211.93,148.21) ; UV23.B4 227.4,165.19 v2(227.36,165.19)
FBA_D3: length 1.2
  BOTTOM w0.102: v2(226.6,165.17) 226.2,165.57 UV23.B2 ; UV18.M28 v2(210.24,147.33)
FBA_D4: length 1.2
  BOTTOM w0.102: UV18.N31 209.83,150.29 v2(209.43,150.69) ; UV23.E4 v2(227.38,167.57)
FBA_D5: length 1.2
  BOTTOM w0.102: UV18.P29 v2(209.43,149.07) ; UV23.E2 v2(226.58,167.57)
FBA_D6: length 1.2
  BOTTOM w0.102: UV18.R29 208.2,148.61 v2(208.61,148.21) ; v2(227.37,169.17) 227.38,169.17 UV23.F4
FBA_D7: length 1.1
  BOTTOM w0.102: v2(226.57,169.14) 226.54,169.14 UV23.F2 ; UV18.P28 v2(209.43,148.22)
FBA_D8: length 1.1
  BOTTOM w0.102: v2(212.79,147.4) 213.18,147.79 UV18.J28 ; v2(232.97,164.45) 233.06,164.45 UV23.A11
FBA_D9: length 1.2
  BOTTOM w0.102: v2(214.4,149.06) 214.4,149.04 UV18.H29
  BOTTOM w0.107: UV23.A13 v2(234.58,165.17)
FBA_D10: length 1.1
  BOTTOM w0.102: UV18.J29 213.2,148.57 v2(213.55,148.22)
  BOTTOM w0.107: UV23.B11 v2(233.78,165.17)
FBA_D11: length 1.2
  BOTTOM w0.102: UV18.H28 v2(214.43,148.22)
  BOTTOM w0.107: UV23.B13 v2(235.38,165.97)
FBA_D12: length 1.3
  BOTTOM w0.102: UV18.G29 214.85,148.64 215.26,149.05 v2(215.42,149.05)
  BOTTOM w0.107: UV23.E11 v2(232.98,167.57)
FBA_D13: length 1.1
  BOTTOM w0.102: v2(216.1,150.69) UV18.E31
  BOTTOM w0.107: UV23.E13 v2(235.38,167.57)
FBA_D14: length 1.3
  BOTTOM w0.102: UV18.E32 216.53,151.09 216.97,150.65 v2(216.97,150.58)
  BOTTOM w0.107: UV23.F11 v2(233.78,168.37)
FBA_D15: length 1.1
  BOTTOM w0.102: UV18.F30 v2(216.1,149.89)
  BOTTOM w0.107: UV23.F13 v2(234.58,168.37)
FBA_D16: length 2.1
  BOTTOM w0.102: v2(219.57,152.86) 219.38,153.05 218.81,153.05 218.45,152.69 UV18.C34 ; v2(233.65,177.99) 233.65,177.84 UV23.U11
FBA_D17: length 1.3
  BOTTOM w0.102: UV18.D32 217.35,151.16 217.78,151.58 v2(217.78,151.59) ; v2(235.41,177.16) 235,177.57 UV23.U13
FBA_D18: length 1.1
  BOTTOM w0.102: v2(233,177.12) 233.35,176.77 UV23.T11 ; UV18.B33 v2(219.4,151.49)
FBA_D19: length 1.1
  BOTTOM w0.102: UV23.T13 234.62,177.13 v2(234.62,177.16) ; UV18.C33 218.2,151.95 v2(218.58,152.33)
FBA_D20: length 4
  BOTTOM w0.102: v2(232.14,174.83) 232.91,174.83 UV23.N11 ; v2(216.68,153.4) 216.38,153.4 216,153.02 215.56,153.02 215.37,152.83 215.37,152.55 215.7,152.22 UV18.F33
FBA_D21: length 3.3
  BOTTOM w0.102: UV23.N13 234.98,174.3 v2(234.62,173.94) ; UV18.F32 215.7,151.14 215.37,151.47 215.37,152.11 215.14,152.34 215.14,152.66 214.81,152.99 v2(214.81,153.44)
FBA_D22: length 1.3
  BOTTOM w0.102: UV18.H33 214.49,152.38 214.49,152.47 v2(214.52,152.5) ; v2(233.02,173.21) UV23.M11
FBA_D23: length 1.2
  BOTTOM w0.102: UV18.H32 214,151.04 v2(213.6,150.64) ; v2(235.38,173.94) 235.35,173.94 UV23.M13
FBA_D24: length 1.1
  BOTTOM w0.102: v2(208.58,152.29) 208.98,152.69 UV18.P34
  BOTTOM w0.221: v2(228.14,177.95) 227.78,177.58 UV23.U4
FBA_D25: length 1
  BOTTOM w0.102: UV18.P32 209,151.12 v2(209.35,151.47) ; v2(226.53,177.21) 226.53,177.22 UV23.U2
FBA_D26: length 1.1
  BOTTOM w0.102: UV18.P31 209,150.35 v2(208.62,150.74)
  BOTTOM w0.221: UV23.T4 227.79,176.77 v2(228.14,177.12)
FBA_D27: length 1.2
  BOTTOM w0.102: UV23.T2 225.82,177.12 v2(225.73,177.12) ; v2(208.58,151.48) 208.59,151.48 UV18.P33
FBA_D28: length 1.9
  BOTTOM w0.102: v2(210.3,149.94) 211.06,149.94 211.41,150.29 UV18.L31 ; v2(228.14,174.02) 228.13,174.02 UV23.N4
FBA_D29: length 2.1
  BOTTOM w0.102: UV23.N2 226.18,174.58 226.56,174.96 226.56,175.47 v2(226.57,175.48) ; v2(211,153.32) 211.05,153.32 211.5,152.87 UV18.L34
FBA_D30: length 2.1
  BOTTOM w0.102: v2(229.05,172.99) 229.03,172.99 228.84,173.18 228.16,173.18 UV23.M4 ; v2(211.12,151.47) 211.13,151.47 UV18.L32
FBA_D31: length 2.8
  BOTTOM w0.102: UV23.M2 226.18,173.88 225.98,174.07 225.6,174.07 225.48,173.94 225.16,173.94 224.84,173.63 224.84,173.44 v2(224.9,173.37) ; v2(211.07,152.32) UV18.L33
FBA_D32: length 2
  BOTTOM w0.102: v2(210.92,165.17) UV24.U4 ; UV18.AG28 198.63,148.22 198.63,149 198.66,149.04 v2(198.66,149.05)
FBA_D33: length 1.2
  BOTTOM w0.102: UV24.U2 v2(211.72,164.37) ; UV18.AF29 v2(199.43,149.07)
FBA_D34: length 1.2
  BOTTOM w0.102: v2(197.7,148.22) 198.13,148.64 UV18.AG29 ; UV24.T4 v2(210.12,165.17)
FBA_D35: length 1.2
  BOTTOM w0.102: UV24.T2 v2(211.72,165.17) ; UV18.AF28 v2(199.43,148.22)
FBA_D36: length 1.2
  BOTTOM w0.102: UV18.AD30 200.29,149.08 v2(200.28,149.08) ; v2(210.92,168.37) UV24.N4
FBA_D37: length 1.2
  BOTTOM w0.102: UV18.AD29 200.54,148.48 v2(200.14,148.48) ; UV24.N2 v2(211.72,168.37)
FBA_D38: length 1.2
  BOTTOM w0.102: v2(210.92,169.17) UV24.M4
  BOTTOM w0.127: v2(201.08,149.07) 201.5,148.65 UV18.AC29
FBA_D39: length 1.2
  BOTTOM w0.102: UV18.AD28 200.68,147.79 200.27,147.38 v2(200.27,147.34) ; UV24.M2 v2(212.52,169.17)
FBA_D40: length 1.2
  BOTTOM w0.102: UV18.AJ29 196.35,148.64 v2(195.98,149.02) ; UV24.U11 v2(205.32,165.17)
FBA_D41: length 1.1
  BOTTOM w0.102: UV24.U13 v2(203.72,165.17) ; UV18.AK29 v2(195.2,148.99)
FBA_D42: length 1.2
  BOTTOM w0.102: UV18.AJ30 v2(196.93,149.07) ; UV24.T11 v2(205.32,165.97)
FBA_D43: length 1.2
  BOTTOM w0.102: UV24.T13 v2(203.72,165.97) ; UV18.AK28 v2(196.03,148.17)
FBA_D44: length 1.1
  BOTTOM w0.102: UV18.AM29 194,148.6 v2(194.39,148.99) ; UV24.N11 v2(205.32,168.37)
FBA_D45: length 1.1
  BOTTOM w0.102: UV18.AM31 194,150.24 v2(193.6,149.84) ; UV24.N13 v2(203.72,168.37)
FBA_D46: length 1.2
  BOTTOM w0.102: UV24.M11 204.97,168.77 205.33,169.13 v2(205.33,169.16) ; v2(192.8,148.99) 192.8,148.99 193.2,148.59 UV18.AN29
FBA_D47: length 1.2
  BOTTOM w0.102: UV24.M13 v2(203.72,169.17) ; UV18.AM30 194,149.37 v2(193.6,148.97)
FBA_D48: length 1.1
  BOTTOM w0.102: v2(192.76,150.52) 192.92,150.52 UV18.AN31 ; v2(204.52,177.18) 204.91,177.57 UV24.A11
FBA_D49: length 1.1
  BOTTOM w0.102: UV24.A13 203.31,177.57 202.93,177.94 v2(202.87,177.94) ; UV18.AN32 193.54,151.42 193.54,151.47 v2(193.55,151.48)
FBA_D50: length 2.2
  BOTTOM w0.102: v2(205.34,177.19) UV24.B11 ; v2(191.73,150.7) 192.4,150.03 UV18.AP30
FBA_D51: length 3.8
  BOTTOM w0.102: v2(202.93,176.39) UV24.B13 ; UV18.AP32 192.39,151.09 191.69,151.78 191.69,153.85 v2(191.85,154.01)
FBA_D52: length 2.5
  BOTTOM w0.102: v2(194.39,151.5) 194,151.89 UV18.AM33 ; UV24.E11 204.56,174.37 204.07,173.88 203.99,173.88 203.7,173.59 v2(203.7,173.18)
FBA_D53: length 1.1
  BOTTOM w0.102: v2(202.92,174.77) UV24.E13 ; UV18.AL31 v2(194.43,150.66)
FBA_D54: length 1.1
  BOTTOM w0.102: v2(204.52,173.18) 204.53,173.18 UV24.F11 ; v2(196.1,152.29) UV18.AK33
FBA_D55: length 1.1
  BOTTOM w0.102: UV18.AK32 v2(196.08,151.47) ; v2(202.93,173.94) 203.31,173.57 UV24.F13
FBA_D56: length 2.6
  BOTTOM w0.102: v2(202.25,153.75) 202.04,153.75 200.98,152.69 UV18.AD34 ; UV24.A4 210.13,177.18 v2(210.11,177.18)
FBA_D57: length 5.4
  BOTTOM w0.102: UV24.A2 v2(212.51,177.17) ; UV18.AD32 200.17,151.62 200.17,151.75 200.18,151.75 200.18,152.03 200.08,152.13 200.08,152.42 200.17,152.51 200.17,152.91 200.48,153.22 200.72,153.22 201.22,153.72 201.22,154.58 201.54,154.89 v2(201.54,154.91)
FBA_D58: length 1.2
  BOTTOM w0.102: v2(201.09,149.88) 201.48,149.49 UV18.AC30 ; UV24.B4 210.93,176.36 v2(210.93,176.36)
FBA_D59: length 4.3
  BOTTOM w0.102: v2(202.43,154.32) 202.32,154.22 202.13,154.22 200.93,153.02 200.56,153.02 200.37,152.83 200.37,152.22 UV18.AD33 ; UV24.B2 212.12,176.76 v2(212.52,176.36)
FBA_D60: length 5.2
  BOTTOM w0.102: UV18.AF31 198.67,150.62 198.19,150.62 197.81,151 197.81,152.88 198.04,153.11 198.04,153.51 v2(197.6,153.95) ; v2(210.16,174.01) UV24.E4
FBA_D61: length 1.4
  BOTTOM w0.102: v2(198.55,153.37) 198.55,153.04 UV18.AG34 ; v2(211.72,174.77) UV24.E2
FBA_D62: length 1.2
  BOTTOM w0.102: v2(198.62,151.53) 198.62,151.5 UV18.AG32 ; UV24.F4 v2(210.12,173.17)
FBA_D63: length 1.1
  BOTTOM w0.102: v2(198.58,152.27) UV18.AG33 ; v2(212.52,173.25) 212.2,173.57 UV24.F2
FBA_DBI0#: length 1.2
  BOTTOM w0.102: UV18.P30 209.03,149.49 v2(209.43,149.89) ; UV23.D2 v2(225.78,166.77)
FBA_DBI1#: length 1.2
  BOTTOM w0.102: UV18.F31 215.68,150.29 v2(215.28,150.69)
  BOTTOM w0.107: UV23.D13 v2(234.58,166.77)
FBA_DBI2#: length 2.9
  BOTTOM w0.102: v2(217.52,153.43) 217.47,153.39 217.47,153.26 217.04,152.83 216.83,152.83 216.64,153.02 216.36,153.02 216.11,152.77 216.11,152.77 216.03,152.69 UV18.F34
  BOTTOM w0.107: UV23.P13 v2(235.38,174.77)
FBA_DBI3#: length 1.2
  BOTTOM w0.102: v2(210.35,151.51) 210.36,151.49 210.36,151.43 UV18.M32 ; v2(225.73,175.6) 226.16,175.17 UV23.P2
FBA_DBI4#: length 1.2
  BOTTOM w0.102: UV18.AD31 200.68,150.29 200.26,149.87 v2(200.21,149.87) ; UV24.P2 v2(211.72,166.77)
FBA_DBI5#: length 1.2
  BOTTOM w0.102: v2(194.4,148.17) 194.8,148.57 UV18.AL29 ; UV24.P13 v2(203.72,167.57)
FBA_DBI6#: length 1.1
  BOTTOM w0.102: v2(193.6,150.7) 193.99,151.09 UV18.AM32
  BOTTOM w0.107: UV24.D13 v2(203.72,175.57)
FBA_DBI7#: length 2.8
  BOTTOM w0.102: v2(199.18,154.86) 199.18,154.82 199.18,153.84 199,153.65 UV18.AF34
  BOTTOM w0.107: UV24.D2 v2(212.52,175.57)
FBA_EDC0: length 1.2
  BOTTOM w0.102: v2(210.28,150.69) 210.68,150.29 UV18.M31 ; UV23.C2 v2(226.58,166.77)
FBA_EDC1: length 2.6
  BOTTOM w0.102: UV18.G31 214.82,150.26 214.38,149.82 213.86,149.82 213.58,149.54 v2(213.58,149.05)
  BOTTOM w0.107: UV23.C13 v2(234.58,165.97)
FBA_EDC2: length 1.1
  BOTTOM w0.102: v2(234.6,175.6) UV23.R13 ; v2(216.09,152.3) UV18.E33
FBA_EDC3: length 2.8
  BOTTOM w0.102: v2(226.57,176.28) 226.27,175.97 UV23.R2 ; v2(209.79,153.75) 210.24,153.31 210.24,152.23 210.57,151.89 UV18.M33
FBA_EDC4: length 1.1
  BOTTOM w0.102: v2(200.27,150.65) 199.92,150.29 UV18.AE31 ; UV24.R2 v2(211.72,165.97)
FBA_EDC5: length 1.2
  BOTTOM w0.102: v2(195.25,149.97) 195.6,149.62 UV18.AK30 ; UV24.R13 v2(203.72,166.77)
FBA_EDC6: length 1.2
  BOTTOM w0.107: UV18.AN33 192.83,152.26 v2(192.77,152.26) ; UV24.C13 v2(203.72,176.37)
FBA_EDC7: length 4.7
  BOTTOM w0.102: v2(199.21,155.44) 199.21,155.42 199.61,155.01 199.61,153.8 199.21,153.39 199.21,153.01 199.35,152.87 199.35,152.22 199.02,151.89 UV18.AF33
  BOTTOM w0.107: UV24.C2 v2(211.72,175.57)
FBA_MA0_MA10_H: length 30.9
  TOP w0.102: 201.98,155.59 201.98,155.3 202.81,154.48 202.81,153.3 203.98,152.13 203.98,150.31 203.78,150.11 203.78,149.26 v2(203.6,149.08)
  TOP w0.221: v2(209.03,170.12) 209.03,170.99 208.68,171.34 208.3,171.34 v1(207.84,170.89) 207.47,170.52 207.47,165.75 201.98,160.27 201.98,155.59
  BOTTOM w0.102: UV18.Y30 204.08,149.42 204.08,149.19 203.97,149.08 v2(203.6,149.08) ; v2(209.03,170.12) 209.03,170.64 209.16,170.77 210.42,170.77 210.52,170.67 UV24.K4
FBA_MA0_MA10_L: length 42.8
  TOP w0.102: v2(205.32,149.88) 205.32,150.18 205.68,150.54 205.68,153.74 205.65,153.76 205.65,154.44 207.86,156.64 207.86,156.74 ; 224.54,171.74 224.95,172.15 226.02,172.15 226.22,171.95 227.53,171.95 227.76,171.73 227.76,171.19 v2(227.35,170.78)
  TOP w0.221: 224.54,171.74 224.47,171.67 223.63,171.67 221.11,169.15 220.8,169.15 220.4,169.55 220.09,169.55 219.77,169.24 219.77,168.93 220.18,168.53 220.18,168.21 217.63,165.66 217.63,163.6 218.06,163.17 218.06,162.68 218.67,162.06 218.67,161.42 218.13,160.87 213.18,160.87 212.86,160.55 212.86,159.86 212.53,159.53 210.27,159.53 207.86,157.12 207.86,156.74
  BOTTOM w0.102: v2(205.32,149.88) 205.7,149.5 UV18.V30 ; UV23.H4 227.41,170.74 227.39,170.74 v2(227.35,170.78)
FBA_MA1_MA9_H: length 24.7
  TOP w0.102: v2(203.4,153.24) 203.01,153.64 203.01,154.92 202.71,155.22 202.71,155.52
  TOP w0.221: 202.71,155.52 202.71,159.91 202.87,160.07 203.78,160.98 204.45,160.98 204.76,161.29 204.76,161.96 208.2,165.4 v1(208.2,166.83) 208.2,167.2 208.94,167.94 208.94,168.19 208.74,168.39 208.31,168.39 208.12,168.58 208.12,169.45 208.36,169.69 208.91,169.69 209.15,169.46 v2(209.15,168.94)
  BOTTOM w0.102: UV24.K5 209.72,170.11 209.34,169.73 208.93,169.73 208.84,169.63 208.84,169.25 v2(209.15,168.94)
  BOTTOM w0.127: UV18.AA34 203.25,152.69 203.47,152.91 203.47,153.14 203.4,153.21 v2(203.4,153.24)
FBA_MA1_MA9_L: length 38.3
  BOTTOM w0.102: 208.12,156.36 208.12,155.5 207.86,155.24 207.86,154.05 UV18.U34 ; UV23.H5 228.98,169.96
  BOTTOM w0.221: 208.12,156.36 208.12,156.46 210.36,158.7 v1(215.98,158.7) 220.39,158.7 221.23,159.54 221.23,159.85 220.84,160.24 220.84,160.55 221.15,160.86 221.46,160.86 221.85,160.48 222.16,160.48 222.48,160.79 222.48,161.1 222.09,161.49 222.09,161.8 222.4,162.11 222.71,162.11 223.1,161.73 223.41,161.73 223.96,162.27 227.84,162.27 229.1,163.53 229.1,169.85 228.98,169.96
FBA_MA2_BA0_H: length 31.7
  TOP w0.102: 199.8,156.43 199.8,156.28 200.2,155.88 200.2,154.45 201.35,153.31 201.35,151.88 203.17,150.06 203.17,149.7 202.95,149.48 202.6,149.48 202.36,149.24 202.36,148.9 202.78,148.48 v2(202.78,148.23) ; 202.67,168.78 203.86,168.78 204.12,169.04 204.12,169.26 204.37,169.5 204.85,169.5 v2(205.32,169.97)
  TOP w0.221: 202.67,168.78 201.93,168.78 200.31,167.16 200.31,166.7 200.09,166.48 199.68,166.48 199.46,166.26 199.46,165.82 199.68,165.6 200.09,165.6 200.36,165.33 200.36,164.87 199.8,164.31 v1(199.8,162.02) 199.8,158.45 199.58,158.23 198.91,158.23 198.69,158.01 198.69,157.57 198.91,157.35 199.58,157.35 199.8,157.13 199.8,156.43
  BOTTOM w0.102: v2(202.78,148.23) 202.78,148.21 UV18.AA28 ; UV24.K11 v2(205.32,169.97)
FBA_MA2_BA0_L: length 44.8
  TOP w0.102: v2(233.78,170.77) 234.18,170.37 234.18,168.23 234.16,168.21 234.16,168.21 233.94,167.99 233.93,167.99 233.9,167.95 232.82,167.95 232.47,167.6 232.47,167.3 ; v2(207.5,148.39) 207.67,148.39 207.94,148.66 208.68,148.66 209.04,149.02 209.04,149.22 209.33,149.51 210.44,149.51 210.74,149.81 210.74,151.62 211.05,151.94 211.35,151.94 211.91,152.51 212.75,152.51
  TOP w0.221: 232.47,167.3 232.52,167.26 232.52,162.46 221.08,151.02 220.36,151.02 220.34,151.04 219.62,151.04 219.6,151.02 219.21,151.02 219.18,151.05 218.45,151.05 218.38,151.12 216.74,151.12 216.26,151.61 215.05,151.61 214.62,152.04 214.24,152.04 213.77,152.51 v1(213.37,152.51) 212.75,152.51
  BOTTOM w0.102: UV18.U29 207.25,148.64 v2(207.5,148.39)
  BOTTOM w0.107: UV23.H11 v2(233.78,170.77)
FBA_MA3_BA3_H: length 33
  TOP w0.102: 200.53,156.41 200.53,156.24 200.56,156.2 200.56,154.42 201.8,153.18 201.8,151.93 203.44,150.29 203.44,149.52 203.19,149.27 203.19,148.64 v2(203.6,148.23) ; v2(206.12,169.97) 205.71,169.56 205.71,168.99 205.47,168.75 205.16,168.75 204.9,168.49 204.9,168.21 204.67,167.99 202.67,167.99
  TOP w0.221: 200.53,156.41 200.53,160.97 200.87,161.31 200.87,161.6 200.53,161.95 200.53,162.24 200.75,162.46 201.91,162.46 202.65,163.2 202.65,163.77 202.33,164.09 201.98,164.09 201.23,163.34 200.75,163.34 200.53,163.56 200.53,164 201.09,164.57 v1(201.09,165.2) 201.09,166.79 202.28,167.99 202.67,167.99
  BOTTOM w0.102: UV18.AA29 203.2,148.63 v2(203.6,148.23) ; UV24.K10 v2(206.12,169.97)
FBA_MA3_BA3_L: length 38.7
  TOP w0.102: v2(207.81,150.64) 208.13,150.32 208.74,150.32 209,150.58 209,151.29 208.97,151.32 208.97,151.63 210.44,153.1 210.44,153.95 210.74,154.26 211.85,154.26
  TOP w0.221: 211.85,154.26 214.47,154.26 215.98,155.77 223.76,155.77 230.78,162.79 230.78,167.77 v2(232.98,169.97)
  BOTTOM w0.107: UV23.H10 v2(232.98,169.97)
  BOTTOM w0.17: v2(207.81,150.64) 207.8,150.64 207.7,150.64 UV18.T31
FBA_MA4_BA2_H: length 23.9
  BOTTOM w0.102: 206.3,171.26 206.03,171.53 205.35,171.53 UV24.H11 ; UV18.AC34 202.06,153.25 202.29,153.25 202.81,153.77 202.81,154.48 202.42,154.87 202.2,154.87 201.51,155.56 201.51,155.6
  BOTTOM w0.221: 206.3,171.26 206.71,170.86 206.71,163.06 v1(205.8,162.16) 201.51,157.86 201.51,156.61 201.51,156.61 201.51,155.6
FBA_MA4_BA2_L: length 38.7
  BOTTOM w0.102: 210.39,154.77 209.84,154.77 209.35,154.27 209.35,153.84 UV18.R34 ; 232.16,171.53 232.94,171.53 UV23.K11
  BOTTOM w0.221: 232.16,171.53 231.95,171.53 231.32,170.89 231.32,161.95 v1(227.95,158.59) 224.34,154.98 212.32,154.98 212.11,154.77 210.39,154.77
FBA_MA5_BA1_H: length 24.8
  BOTTOM w0.102: 202.24,155.6 202.24,155.49 203.01,154.72 203.01,153.69 203,153.67 203,153.66 202.82,153.49 202.82,153.22 202.59,152.99 202.17,152.99 201.83,152.65 201.83,152.55 201.64,152.36 201.54,152.36 201.5,152.32 UV18.AC33
  BOTTOM w0.221: UV24.H10 205.89,171.97 205.93,171.93 206.55,171.93 207.33,171.15 207.33,168.3 207.65,167.99 207.65,162.93 v1(204.76,160.05) 203.82,159.11 202.24,157.53 202.24,155.6
FBA_MA5_BA1_L: length 39.5
  BOTTOM w0.102: 231.57,172.18 231.59,172.2 231.85,172.2 232.09,171.97 UV23.K10 ; 210.96,155.71 210.4,155.71 208.96,154.26 208.96,153.98 207.87,152.89 207.87,152.55 208.06,152.36 208.07,152.36 208.2,152.23 UV18.R33
  BOTTOM w0.221: 231.57,172.18 231.4,172.18 230.59,171.37 230.59,162.25 v1(229.16,160.83) 224.04,155.71 210.96,155.71
FBA_MA6_MA11_H: length 28.4
  TOP w0.102: 209.21,167.26 209.53,167.57 209.53,171.36 v2(209.32,171.57) ; 203.44,156.74 203.21,156.51 203.21,154.26 203.84,153.64 203.84,153.19 204.19,152.84 204.19,150.22 204.01,150.05 204.01,148.62 v2(204.38,148.25)
  TOP w0.221: 209.21,167.26 208.84,166.89 208.84,164.79 v1(208.29,164.24) 205.68,161.63 205.68,161.18 203.44,158.94 203.44,156.74
  BOTTOM w0.102: v2(204.38,148.25) 204.31,148.32 204.17,148.32 203.95,148.1 203.95,147.84 UV18.Y28 ; UV24.H5 209.74,171.95 209.74,171.62 209.62,171.49 209.39,171.49 v2(209.32,171.57)
FBA_MA6_MA11_L: length 42.2
  TOP w0.102: v2(228.19,172.38) 228.62,171.96 229.5,171.96 229.73,171.72 229.73,164.52 229.44,164.23 ; 211.76,154.81 211.59,154.64 210.05,154.64 208.14,152.74 208.14,151.37 207.92,151.15 207.77,151.15 207.38,150.75 207.38,150.2 206.43,149.24 206.43,148.72 v2(206.93,148.22)
  TOP w0.221: 229.44,164.23 221.71,156.5 215.68,156.5 214.34,155.16 v1(213.42,155.16) 212.11,155.16 211.76,154.81
  BOTTOM w0.102: v2(206.93,148.22) 206.5,147.79 UV18.U28
  BOTTOM w0.13: UV23.K5 228.58,172 v2(228.19,172.38)
FBA_MA7_MA8_H: length 24.9
  BOTTOM w0.102: 202.97,155.6 202.97,155.3 203.21,155.05 203.21,153.6 203.2,153.59 203.2,153.58 203.02,153.4 203.02,153.11 202.84,152.93 202.84,152.25 UV18.AA33 ; 209.22,172.36 210.13,172.36 UV24.H4
  BOTTOM w0.221: 202.97,155.6 202.97,157.16 v1(203.77,157.97) 208.48,162.68 208.48,171.62 209.22,172.36
FBA_MA7_MA8_L: length 39.2
  BOTTOM w0.102: 228.98,171.6 228.15,171.6 UV23.K4 ; 209.16,156.36 208.82,156.02 208.82,155.56 208.17,154.91 208.17,154.07 206.87,152.77 206.87,152.55 206.5,152.18 UV18.U33
  BOTTOM w0.221: 228.98,171.6 229.1,171.6 229.69,171 229.69,170.29 229.82,170.15 229.82,163.23 224.57,157.97 v1(219.61,157.97) 210.77,157.97 209.16,156.36
FBA_MA12_RFU_H: length 27.9
  TOP w0.102: 209.73,164.49 209.73,169.32 210,169.59 210.28,169.59 210.5,169.81 210.5,171.19 v2(210.12,171.57) ; v2(204.39,149.83) 204.39,149.83 204.39,152.92 204.22,153.1 204.22,153.89 203.53,154.58 203.53,156.1 204.17,156.74
  TOP w0.221: 204.17,156.74 204.17,158.64 204.23,158.7 v1(205.05,159.52) 206.48,160.94 206.48,161.23 209.73,164.49
  BOTTOM w0.102: v2(210.12,171.57) 210.19,171.49 210.19,171.1 210.09,171 209.82,171 209.72,171.1 UV24.J5 ; v2(204.39,149.83) 204.33,149.9 204.33,150.35 204.59,150.61 204.78,150.61 204.88,150.51 204.88,150.32 UV18.W31
FBA_MA12_RFU_L: length 42.7
  TOP w0.102: v2(228.21,169.94) 227.83,169.56 227.23,169.56 227.19,169.52 226.41,169.52 226.19,169.29 226.19,169.04 225.93,168.79 225.66,168.79 v1(224.82,167.95) 224.54,167.67 224.54,167.42 ; v2(206.1,148.22) 206.1,149.33 206.57,149.8 206.57,152.06 207.31,152.8
  TOP w0.17: 207.31,152.8 207.32,152.8 209.78,155.27
  TOP w0.221: 224.54,167.42 222.89,165.78 222.89,164.31 223.15,164.05 224.37,164.05 225.94,162.49 225.94,161.76 221.41,157.22 215.38,157.22 214.04,155.89 211.85,155.89 211.23,155.27 209.78,155.27
  BOTTOM w0.102: v2(206.1,148.22) 205.7,148.62 UV18.V29 ; v2(228.21,169.94) 228.21,170.8 UV23.J5
FBA_RAS#_H: length 29.4
  BOTTOM w0.102: 205.91,155.6 204.61,154.3 204.61,153.28 204.63,153.27 204.63,152.42 204.33,152.13 204.33,150.64 204,150.31 UV18.Y31 ; UV24.L3 211.76,170.01 213.62,170.01
  BOTTOM w0.221: 213.62,170.01 214.45,170.01 214.67,169.79 v1(214.67,162.27) 214.67,161.12 213.05,159.5 209.81,159.5 206.62,156.31 205.91,155.6
FBA_RAS#_L: length 41.2
  TOP w0.102: v2(226.57,169.92) 226.27,169.92 225.93,169.59 225.63,169.59 225.16,169.12 ; 206.83,153.08 206.36,152.61 206.36,150.13 v2(206.11,149.88)
  TOP w0.221: 225.16,169.12 225.16,169.07 221.93,165.84 v1(221.93,164.5) 221.93,164.25 222.89,163.29 224.11,163.29 225.01,162.38 225.01,161.86 222.84,159.69 222.46,159.69 221.99,160.17 221.67,160.17 221.36,159.86 221.36,159.55 221.84,159.07 221.84,158.75 221.57,158.49 221.11,158.49 220.63,158.97 220.35,158.97 220.12,158.73 220.12,158.25 219.82,157.95 215.07,157.95 213.73,156.61 211.51,156.61 210.67,155.77 209.52,155.77 208.34,154.59 206.83,153.08
  BOTTOM w0.102: v2(226.57,169.92) 226.62,169.92 UV23.G3 ; UV18.U31 206.11,149.9 v2(206.11,149.88)
FBA_RST#_H: length 29.4
  TOP w0.102: v2(204.2,155.34) 204.2,155.65 204.63,156.08 205.05,156.08 205.63,156.65 205.63,156.74
  TOP w0.221: v2(211.72,170.77) 213.34,169.14 213.74,169.14 214.11,168.78 214.11,164.14 213.75,163.79 211.41,163.79 205.63,158.01 205.63,156.74
  BOTTOM w0.102: UV18.Y34 204.19,152.88 204.19,153.1 204.21,153.12 204.21,155.34 v2(204.2,155.34) ; 213.62,171.17 213.22,170.77 212.65,170.77 212.25,171.17 UV24.J2 v2(211.72,170.77)
  BOTTOM w0.221: 213.62,171.17 213.84,171.39 215,171.39 RV613.1
FBA_RST#_L: length 39.6
  TOP w0.102: 210.14,156.23 209.35,156.23 v2(206.81,153.69) ; v2(225.78,170.77) 224.54,169.53 224.54,169.48
  TOP w0.221: 210.14,156.23 211.26,157.34 213.43,157.34 214.77,158.68 219.03,158.68 221.32,160.97 222.22,160.97 222.5,160.69 222.81,160.69 224.12,161.99 224.12,162.25 223.82,162.54 223.4,162.54 222.89,162.02 222.17,162.02 221.98,162.2 221.98,163.07 221.2,163.85 221.2,166.14 224.54,169.48
  BOTTOM w0.102: UV23.J2 v2(225.78,170.77) 224.41,170.77 ; v2(206.81,153.69) 206.7,153.69 UV18.V34
  BOTTOM w0.221: RV614.1 223.34,170.24 223.87,170.77 224.41,170.77
FBA_WCK0: length 1.1
  BOTTOM w0.114: v2(211.94,149.89) 212.34,150.29 UV18.K31 ; UV23.D4 v2(228.18,166.77)
FBA_WCK0_N: length 1.2
  BOTTOM w0.114: v2(211.94,149.07) 211.53,149.49 UV18.L30 ; UV23.D5 v2(228.18,167.57)
FBA_WCK1: length 4.1
  BOTTOM w0.102: v2(228.14,175.53) 228.14,175.53 UV23.P4 ; v2(211.51,153.82) 211.72,153.6 211.84,153.6 212.26,154.01 213.02,154.01 213.73,153.3 213.73,152.79 213.83,152.69 UV18.H34
FBA_WCK1_N: length 3.5
  BOTTOM w0.102: UV18.J34 213.37,152.69 213.47,152.79 213.47,153.2 212.91,153.75 212.37,153.75 211.83,153.22 v2(211.69,153.22) ; UV23.P5 228.86,175.45 228.86,175.5 228.91,175.56 v2(228.93,175.56)
FBA_WCK2: length 1.3
  BOTTOM w0.102: UV24.P4 v2(210.12,167.57)
  BOTTOM w0.114: UV18.AG30 198.15,149.49 197.71,149.05 v2(197.67,149.05)
FBA_WCK2_N: length 1.9
  BOTTOM w0.102: UV18.AG31 198.27,150.29 198.38,150.18 198.38,150.01 198.24,149.87 197.93,149.87 ; v2(210.12,166.8) 210.18,166.86 210.18,167.01 209.96,167.22 209.77,167.22 UV24.P5
  BOTTOM w0.114: 197.93,149.87 v2(197.77,149.87)
FBA_WCK3: length 5.8
  BOTTOM w0.102: UV24.D4 v2(210.16,174.81) ; UV18.AJ34 196.33,152.69 196.23,152.79 196.23,153.76 196.27,153.8 196.27,153.82
  BOTTOM w0.17: 196.27,153.82 196.27,154.08 197.09,154.91 197.09,156.36 196.73,156.73 196.38,156.73 v2(196.23,156.87)
FBA_WCK3_N: length 5.4
  BOTTOM w0.102: UV24.D5 209.27,175.17 v2(209.12,175.31) ; UV18.AK34 195.87,152.69 195.97,152.79 195.97,153.76 195.94,153.8 195.94,153.82
  BOTTOM w0.17: v2(196.23,156.28) 196.24,156.28 196.35,156.39 196.59,156.39 196.76,156.22 196.76,155.04 195.94,154.22 195.94,153.82
FBA_WE#_H: length 30.9
  TOP w0.102: v2(204.54,172.4) 205.08,172.93 206.43,172.93 206.74,172.61 206.74,169.26 206.27,168.79 205.96,168.79 205.7,168.52 205.7,168.21 205.44,167.95 205.16,167.95 204.9,167.69 204.9,167.41 204.67,167.19 203.55,167.19 203.32,166.96 203.32,165 203.67,164.65 ; 201.25,155.62 201.25,155.37 200.96,155.08 200.96,154.31 203.6,151.67 v2(203.6,150.69)
  TOP w0.221: 201.25,155.62 201.25,160.61 204.21,163.57 204.21,164.11 203.67,164.65
  BOTTOM w0.102: UV18.AA32 v2(203.6,150.69) ; UV24.G12 204.49,172.4 v2(204.54,172.4)
FBA_WE#_L: length 41.5
  TOP w0.102: 230.05,164.11 230.05,168.68 233.79,172.42 v2(233.79,173.12)
  TOP w0.221: 230.05,164.11 230.05,163.09 v2(224.14,157.18)
  BOTTOM w0.102: v2(233.79,173.12) 233.83,173.12 UV23.L12 ; UV18.U32 206.5,151.16 207,151.66 207,152.38 207.07,152.46 207.07,152.68 208.53,154.14 208.53,154.6 210.29,156.36
  BOTTOM w0.221: v2(224.14,157.18) 224.09,157.24 v1(212.95,157.24) 211.17,157.24 210.77,156.83 210.29,156.36
FBC_ABI#_H: length 33.2
  TOP w0.102: 221.31,140.76 221.31,140.23 219.94,138.86 216.02,138.86 v2(215.33,138.17)
  TOP w0.147: 223.8,142.93 223.49,142.93 221.31,140.76 ; 234.95,151.34 v1(238.9,151.34) 239.89,151.34 240.28,150.95 v2(240.28,149.83)
  TOP w0.221: 234.95,151.34 226.55,142.93 223.8,142.93
  BOTTOM w0.102: UV26.J4 v2(240.28,149.83) ; UV18.G17 v2(215.33,138.17)
FBC_ABI#_L: length 33.8
  TOP w0.102: v2(215.33,137.32) 215.7,137.69 217.19,137.69 217.31,137.58 218.1,137.58 218.27,137.75 220.34,137.75 220.87,138.28 222.83,138.28 223.29,137.81 223.6,137.81 ; 241.53,134.07 241.53,133.53 241.33,133.33 241.33,132.39 241.46,132.26 241.46,131.68 v2(241.08,131.3)
  TOP w0.221: 223.6,137.81 v1(227.3,137.81) 239.74,137.81 241.53,136.02 241.53,134.07
  BOTTOM w0.102: UV18.F15 v2(215.33,137.32) ; UV25.J4 v2(241.08,131.3)
FBC_CAS#_H: length 36.1
  TOP w0.102: 243.87,146.2 243.87,147.23 243.26,147.85 242.52,147.85 242.26,148.11 242.26,148.65 v2(241.88,149.03) ; 223.34,138.54 220.84,138.54 220.34,138.04 218.27,138.04 218.02,137.78 217.43,137.78 v2(217,138.22)
  TOP w0.221: 243.87,146.2 243.87,145.58 236.84,138.54 223.34,138.54
  BOTTOM w0.102: v2(217,138.22) 216.63,138.59 216.6,138.59 UV18.E17 ; UV26.G3 v2(241.88,149.03)
FBC_CAS#_L: length 28.3
  BOTTOM w0.102: UV25.L3 242.28,131.98 242.59,132.29 242.59,132.63 242.23,132.99 242.15,132.99 241.85,133.29 241.85,133.65 ; UV18.C17 218.53,138.26 219.22,138.26 219.53,137.96 222.75,137.96
  BOTTOM w0.221: 241.85,133.65 241.85,133.86 241.12,134.59 229.82,134.59 226.45,137.96 v1(224.57,137.96) 222.75,137.96
FBC_CKE_H: length 33
  TOP w0.102: 241.24,146.69 241.08,146.84 v2(241.08,148.23) 241.16,148.23 241.6,147.78 242.18,147.78 242.3,147.66 242.3,146.94 RV608.2
  TOP w0.221: 241.24,146.69 242.24,145.69 242.24,144.97 236.56,139.29 222.81,139.29 v2(222.75,139.35)
  BOTTOM w0.102: UV26.J3 v2(241.08,148.23) ; v2(222.75,139.35) 221.6,138.21 219.56,138.21 219.18,138.59 UV18.B17
FBC_CKE_L: length 31
  TOP w0.102: 239.26,134.07 239.26,133.84 239.54,133.56 240.4,133.56 240.84,133.11 240.84,132.61 240.59,132.35 240.59,131.53 240.27,131.21 v2(240.27,130.57) 240.33,130.57 240.65,130.89 241.39,130.89 RV606.2 ; v2(220.97,137.39) 221.35,137.77 222.47,137.77
  TOP w0.221: 222.47,137.77 223.25,136.99 v1(223.62,136.99) 235.25,136.99 236.78,135.46 238.62,135.46 239.19,134.89 239.19,134.14 239.26,134.07
  BOTTOM w0.102: v2(220.97,137.39) 220.56,136.98 220.23,136.98 219.95,137.26 219.37,137.26 UV18.B15 ; UV25.J3 240.26,131.28 240.26,130.57 v2(240.27,130.57)
FBC_CLK0: length 2.1
  TOP w0.102: RV629.1 241.53,123.47 241.22,123.79 241.22,123.95 v2(241.08,124.09)
  BOTTOM w0.102: v2(241.08,124.09) 240.68,124.49 UV25.J12
  BOTTOM w0.114: v2(217.02,134.79) 217.4,134.4 UV18.D12
FBC_CLK0#: length 3.4
  TOP w0.102: v2(241.08,124.91) 241.48,124.51 241.48,123.89 242.1,123.27 RV628.1
  BOTTOM w0.102: UV25.J11 240.69,125.3 v2(241.08,124.91)
  BOTTOM w0.114: v2(216.08,134.96) 216.14,134.89 216.14,134.84 216.59,134.39 UV18.E12
FBC_CLK1: length 2.6
  TOP w0.102: v2(240.28,155.4) 240.28,155.42 240.42,155.56 RV638.1
  BOTTOM w0.102: UV26.J12 240.28,155.43 v2(240.28,155.4)
  BOTTOM w0.114: v2(216.98,140.68) 216.6,141.06 UV18.E20
FBC_CLK1#: length 2.8
  TOP w0.102: v2(241.08,155.42) 240.69,155.81 240.69,156.38 241,156.69 RV637.1
  BOTTOM w0.102: v2(241.08,155.42) UV26.J11
  BOTTOM w0.114: v2(216.13,140.67) 215.75,141.04 UV18.F20
FBC_CS#_H: length 31.6
  TOP w0.102: v2(217.9,139.82) 218.18,140.1 218.18,141.09 220.3,143.21 221.86,143.21 222.08,143.44 222.08,144.09 ; 233.68,154.25 239.31,154.25 239.32,154.25 239.63,154.25 239.86,154.48 239.86,154.84 239.48,155.21 v2(239.48,155.43)
  TOP w0.221: 222.08,144.09 222.08,144.41 v1(224.08,146.41) 231.92,154.25 233.68,154.25
  BOTTOM w0.102: UV18.D18 217.4,139.44 217.77,139.82 v2(217.9,139.82) ; UV26.L12 v2(239.48,155.43)
FBC_CS#_L: length 26.5
  TOP w0.102: 237.95,126.16 238.36,125.76 238.36,125.26 v2(238.71,124.9) ; 222.9,132.16 220.97,132.16 218.77,134.36 218.26,134.36 v2(217.79,134.83)
  TOP w0.221: 222.9,132.16 222.95,132.11 223.88,132.11 224.24,131.75 227.93,131.75 v1(233.04,126.64) 233.52,126.16 237.95,126.16
  BOTTOM w0.107: UV25.G12 239.08,124.53 v2(238.71,124.9)
  BOTTOM w0.17: UV18.D13 217.79,134.85 v2(217.79,134.83)
FBC_D0: length 1.2
  BOTTOM w0.102: UV18.G9 214.9,131.92 214.51,132.31 v2(214.51,132.32) ; UV25.A4 v2(234.68,131.3)
FBC_D1: length 1.2
  BOTTOM w0.102: UV18.E9 216.6,131.95 216.6,131.95 v2(216.98,132.33) ; UV25.A2 v2(234.68,132.9)
FBC_D2: length 1.2
  BOTTOM w0.102: UV25.B4 v2(234.68,130.5) ; UV18.G8 214.9,131.07 v2(215.34,130.63)
FBC_D3: length 1.2
  BOTTOM w0.102: UV25.B2 v2(235.48,132.9) ; v2(215.43,132.37) 215.75,132.04 UV18.F9
FBC_D4: length 1.2
  BOTTOM w0.102: UV18.F11 v2(216.18,133.17) ; UV25.E4 v2(237.08,131.3)
FBC_D5: length 1.2
  BOTTOM w0.102: UV18.G11 v2(215.33,133.17) ; UV25.E2 v2(237.08,132.1)
FBC_D6: length 1.1
  BOTTOM w0.102: v2(215.33,134.04) 215.69,134.39 UV18.F12 ; UV25.F4 v2(238.68,131.3)
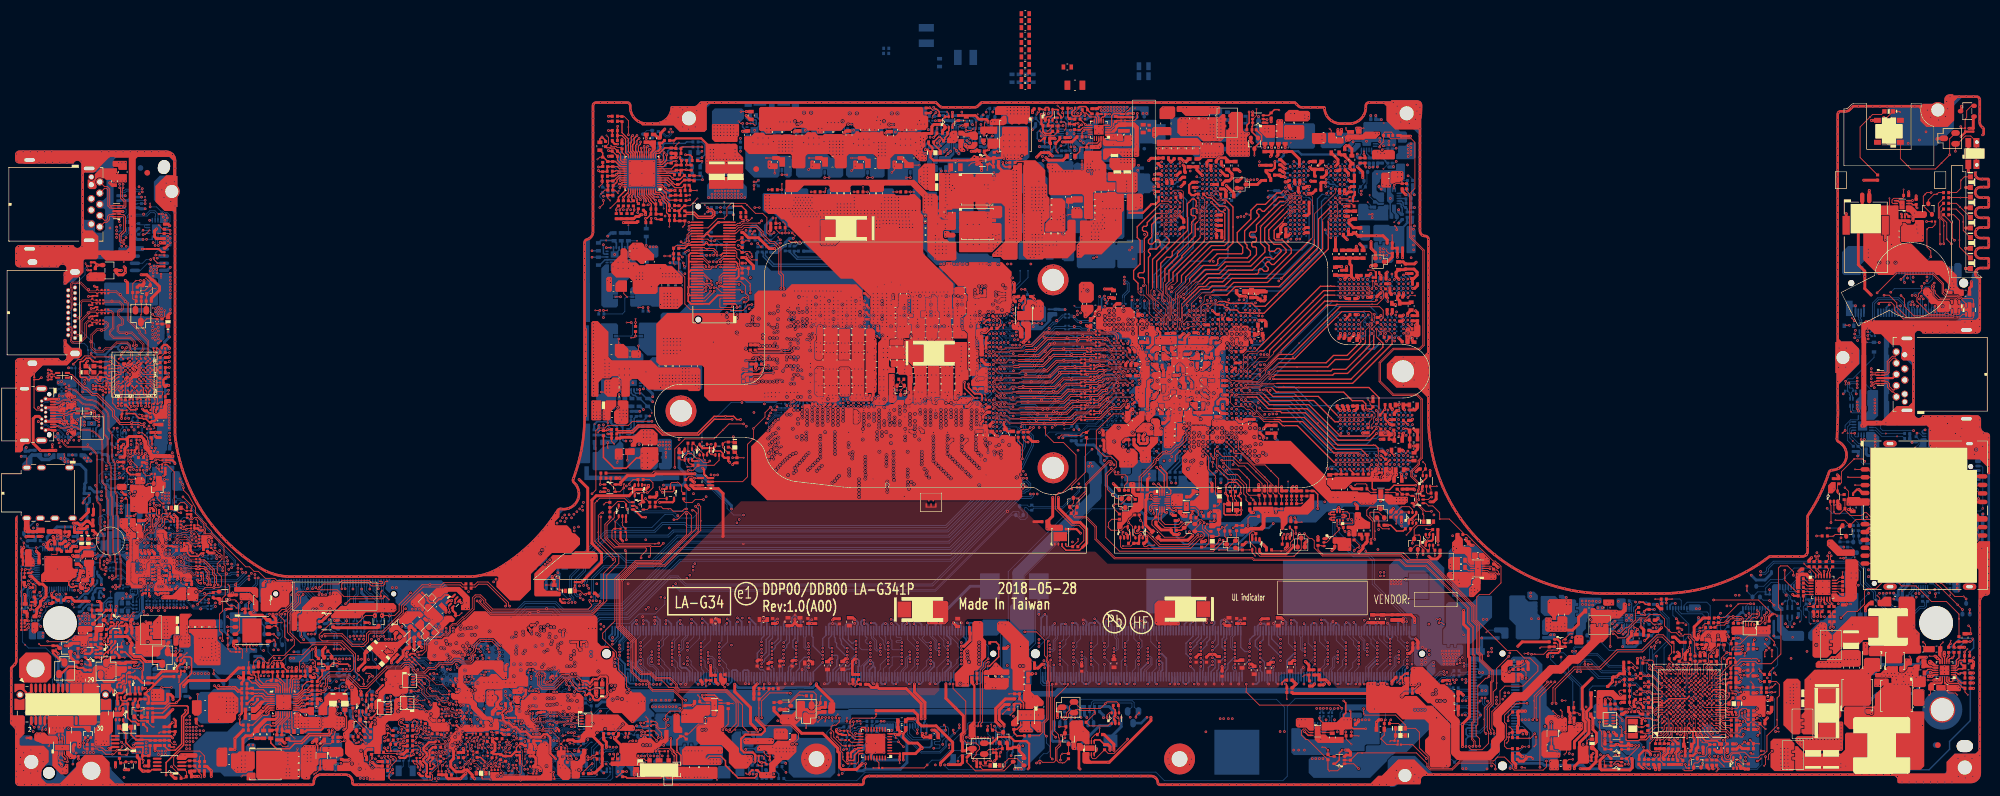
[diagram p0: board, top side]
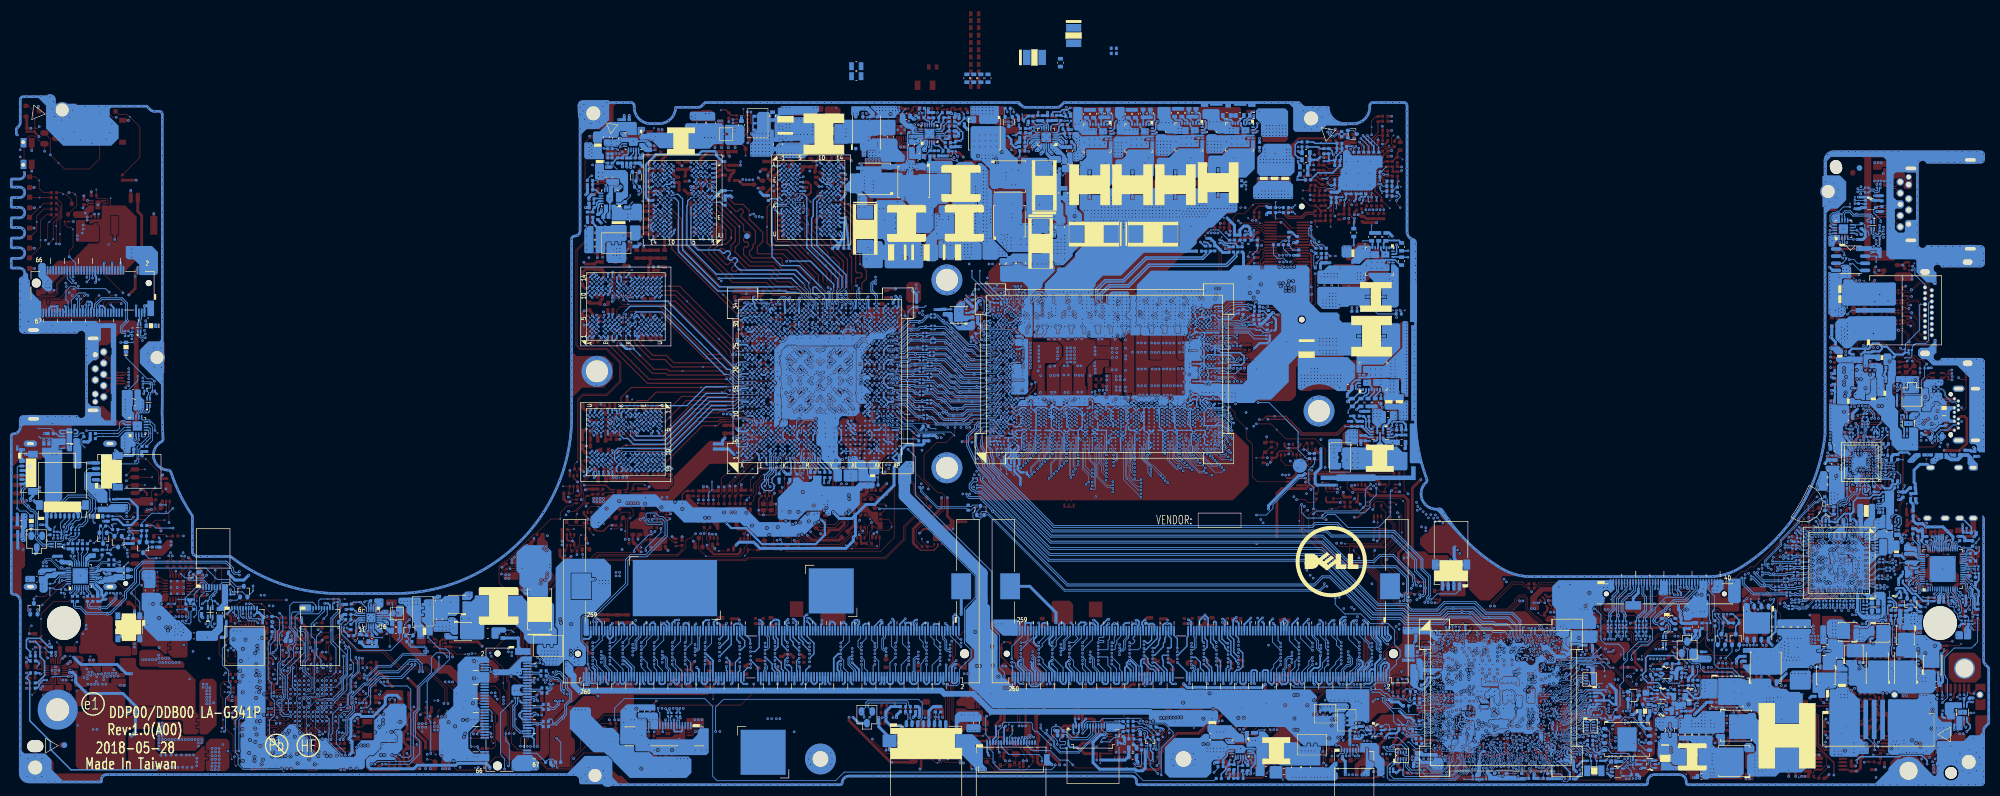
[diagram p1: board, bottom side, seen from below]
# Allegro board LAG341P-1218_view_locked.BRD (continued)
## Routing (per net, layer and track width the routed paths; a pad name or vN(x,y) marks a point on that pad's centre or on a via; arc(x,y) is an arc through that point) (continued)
FBC_D7: length 1.1
  BOTTOM w0.102: UV18.G12 214.9,134.36 v2(214.51,133.97) ; UV25.F2 v2(237.88,132.9)
FBC_D8: length 1.2
  BOTTOM w0.102: UV18.G6 214.9,129.34 v2(215.33,129.77)
  BOTTOM w0.107: v2(233.91,124.92) 233.91,124.93 UV25.A11
FBC_D9: length 2.6
  BOTTOM w0.102: UV25.A13 233.56,123.7 ; UV18.F5 v2(216.13,128.07)
  BOTTOM w0.221: 233.56,123.7 233.42,123.7 233.32,123.79 232.91,123.79 v2(232.47,123.35)
FBC_D10: length 1.1
  BOTTOM w0.102: UV25.B11 234.7,124.91 v2(234.7,124.93) ; UV18.E6 v2(217,129.79)
FBC_D11: length 1.2
  BOTTOM w0.102: v2(216.18,128.93) 215.77,129.34 UV18.F6 ; v2(234.65,124.09) 234.69,124.09 UV25.B13
FBC_D12: length 1.1
  BOTTOM w0.102: UV25.E11 v2(237.08,125.7) ; UV18.F4 v2(216.11,127.29)
FBC_D13: length 1.2
  BOTTOM w0.102: UV18.G4 214.86,127.69 v2(215.27,128.11) ; UV25.E13 v2(237.08,123.3)
FBC_D14: length 1.2
  BOTTOM w0.102: v2(237.86,124.92) 238.24,125.3 UV25.F11
  BOTTOM w0.127: v2(216.1,125.63) 216.1,125.69 216.5,126.09 UV18.E2
FBC_D15: length 1.2
  BOTTOM w0.102: v2(237.86,124.07) 237.87,124.07 237.87,124.1 UV25.F13 ; UV18.F3 v2(216.1,126.49)
FBC_D16: length 1.2
  BOTTOM w0.102: v2(247.59,125.44) 247.56,125.44 247.56,125.45 247.23,125.45 UV25.U11 ; v2(218.55,125.68) 218.49,125.68 218.2,125.97 UV18.C2
FBC_D17: length 2.6
  BOTTOM w0.102: UV25.U13 247.4,123.38 ; UV18.D4 217.4,127.67 v2(217.79,127.28)
  BOTTOM w0.221: 247.4,123.38 247.45,123.33 247.45,123.06 247.45,123.05 247.45,122.65 v2(248.05,122.06)
FBC_D18: length 1.2
  BOTTOM w0.102: v2(246.68,125.68) 246.67,125.68 UV25.T11 ; UV18.D3 217.35,126.82 v2(217.76,126.41)
FBC_D19: length 4.2
  BOTTOM w0.102: v2(219.89,124.8) 219.82,124.86 218.63,124.86 UV18.C1 ; UV25.T13 246.28,123.5 245.92,123.14 245.92,122.48 245.94,122.47 245.94,122.19 246,122.13
  BOTTOM w0.221: v2(246.32,121.73) 246.28,121.77 246,122.05 246,122.13
FBC_D20: length 1.2
  BOTTOM w0.102: UV25.N11 244.26,124.92 v2(244.34,124.92) ; UV18.B3 219.06,126.89 v2(219.44,126.51)
FBC_D21: length 1.2
  BOTTOM w0.102: UV18.C4 218.28,127.74 218.55,127.46 v2(218.55,127.34) ; v2(244.3,124.13) 244.3,124.12 UV25.N13
FBC_D22: length 2.5
  BOTTOM w0.102: v2(243.45,125.75) 243.08,125.38 UV25.M11 ; v2(220.52,127.72) 220.01,128.22 219.6,128.22 219.24,128.59 UV18.B5
FBC_D23: length 2.3
  BOTTOM w0.102: UV25.M13 243.09,123.7 v2(243.45,123.34) ; UV18.C5 218.57,128.59 218.67,128.49 218.67,128.45 219.05,128.07 219.14,128.07 219.49,127.72 v2(219.57,127.72)
FBC_D24: length 3.6
  BOTTOM w0.102: UV18.A11 222.19,133.59 v2(222.67,133.11) ; UV25.U4 247.15,130.9
  BOTTOM w0.221: v2(247.51,131.21) 247.2,130.9 247.15,130.9
FBC_D25: length 1.1
  BOTTOM w0.102: v2(218.58,133.21) UV18.C11 ; UV25.U2 247.15,132.56
  BOTTOM w0.221: v2(247.43,132.9) 247.43,132.84 247.15,132.56
FBC_D26: length 3.2
  BOTTOM w0.102: v2(246.37,129.3) 246.68,129.62 246.68,130.51 246.3,130.9 UV25.T4 ; UV18.D11 217.05,133.94 v2(216.2,133.94)
FBC_D27: length 1.1
  BOTTOM w0.102: v2(246.68,132.86) 246.65,132.86 UV25.T2 ; v2(219.38,133.18) 219,133.56 UV18.B11
FBC_D28: length 1.9
  BOTTOM w0.102: v2(243.51,130.51) 243.88,130.88 UV25.N4 ; v2(218.62,131.53) 218.11,131.53 217.67,131.09 UV18.D8
FBC_D29: length 1.4
  BOTTOM w0.102: v2(243.51,132.92) 243.51,132.87 UV25.N2 ; v2(220.33,130.51) 219.8,131.04 UV18.A8
FBC_D30: length 1.3
  BOTTOM w0.102: UV18.C8 218.62,130.67 218.62,130.6 v2(218.61,130.58) ; v2(242.66,130.47) UV25.M4
FBC_D31: length 2.1
  BOTTOM w0.102: UV18.B8 219.51,130.58 v2(219.51,130.57) ; v2(242.75,131.27) 242.75,132.16 243.08,132.5 UV25.M2
FBC_D32: length 1.1
  BOTTOM w0.102: v2(215.32,144.04) 215.67,144.39 UV18.F24 ; v2(234.67,149.03) 234.67,149.03 UV26.U4
FBC_D33: length 1.2
  BOTTOM w0.102: UV26.U2 v2(233.88,148.23) ; UV18.G23 v2(215.33,143.17)
FBC_D34: length 1.2
  BOTTOM w0.102: v2(216.18,144.88) 216.6,144.47 UV18.E24 ; UV26.T4 v2(234.68,149.83)
FBC_D35: length 1.2
  BOTTOM w0.102: UV18.G24 214.9,144.42 v2(214.5,144.82) ; UV26.T2 v2(234.68,148.23)
FBC_D36: length 1.2
  BOTTOM w0.102: v2(217.8,142.32) 217.4,141.92 UV18.D21 ; UV26.N4 v2(237.88,149.03)
FBC_D37: length 1.1
  BOTTOM w0.102: UV18.E21 216.99,141.5 v2(217,141.5) ; UV26.N2 v2(237.88,148.23)
FBC_D38: length 1.1
  BOTTOM w0.102: UV18.G21 214.5,142.29 v2(214.5,142.32) ; v2(237.92,149.77) 237.94,149.77 UV26.M4
FBC_D39: length 1.1
  BOTTOM w0.102: UV18.F21 215.7,141.89 215.34,141.53 v2(215.34,141.51) ; v2(238.68,147.43) 238.68,147.43 UV26.M2
FBC_D40: length 1.2
  BOTTOM w0.102: v2(215.33,146.49) 214.93,146.89 UV18.G27 ; UV26.U11 v2(234.68,154.63)
FBC_D41: length 1.2
  BOTTOM w0.102: v2(216.95,147.27) 217.02,147.27 UV18.D27 ; UV26.U13 v2(234.68,156.23)
FBC_D42: length 1.2
  BOTTOM w0.102: v2(215.3,145.63) 215.3,145.69 UV18.G26 ; UV26.T11 v2(235.48,154.63)
FBC_D43: length 1.1
  BOTTOM w0.102: UV18.E27 216.6,146.94 216.27,147.27 216.27,147.28 v2(216.24,147.3) ; UV26.T13 v2(235.48,156.23)
FBC_D44: length 1.1
  BOTTOM w0.102: UV26.N11 v2(237.88,154.63) ; UV18.E29 v2(217,148.99)
FBC_D45: length 1.2
  BOTTOM w0.102: v2(216.18,149.06) 215.76,148.64 UV18.F29 ; UV26.N13 v2(237.88,156.23)
FBC_D46: length 1.1
  BOTTOM w0.102: UV18.E30 v2(217,149.89) ; UV26.M11 v2(238.68,154.63)
FBC_D47: length 1.1
  BOTTOM w0.102: UV18.D30 217.4,149.42 217.72,149.74 v2(217.79,149.74) ; UV26.M13 v2(238.68,156.23)
FBC_D48: length 2
  BOTTOM w0.102: v2(247.45,154.66) UV26.A11 ; UV18.A32 220.61,151.09 220.78,150.92 v2(220.78,150.51)
FBC_D49: length 1.1
  BOTTOM w0.102: v2(218.61,150.58) 218.27,150.24 UV18.C31 ; UV26.A13 v2(246.73,156.27)
FBC_D50: length 1.2
  BOTTOM w0.102: v2(246.68,154.64) 246.67,154.64 UV26.B11 ; v2(218.6,151.55) 218.2,151.15 UV18.C32
FBC_D51: length 2
  BOTTOM w0.102: UV26.B13 246.68,157.03 v2(246.68,157.12) ; UV18.B32 219,151.08 219.51,150.58 v2(220.14,150.58)
FBC_D52: length 1.1
  BOTTOM w0.102: UV18.D29 217.39,148.59 v2(216.97,148.16) ; v2(244.24,155.38) UV26.E11
FBC_D53: length 1.6
  BOTTOM w0.102: v2(220.64,148.14) 220.25,148.14 UV18.A29 ; v2(244.29,157.04) UV26.E13
FBC_D54: length 3
  BOTTOM w0.102: UV26.F11 242.62,154.57 242.62,153.43 242.94,153.12 v2(243.13,153.12) ; UV18.C29 218.57,148.22 v2(218.6,148.22)
FBC_D55: length 1.1
  BOTTOM w0.102: v2(219.32,148.16) 219,148.48 UV18.B29 ; UV26.F13 243.08,156.63 v2(243.44,156.98)
FBC_D56: length 2.3
  BOTTOM w0.102: UV26.A4 247.4,149.11 v2(247.4,149.01) ; UV18.B21 219.2,141.89 219.53,142.22 220.12,142.22 220.46,141.88 v2(220.46,141.83)
FBC_D57: length 2.5
  BOTTOM w0.102: v2(219.44,143.16) 219.33,143.27 219.33,143.73 219.14,143.92 218.57,143.92 218.24,143.59 UV18.C23 ; UV26.A2 v2(246.68,147.43)
FBC_D58: length 1.8
  BOTTOM w0.102: UV26.B4 v2(246.67,149.81) ; v2(220.4,140.86) 220.13,141.13 220.13,141.23 219.8,141.56 UV18.A21
FBC_D59: length 3.9
  BOTTOM w0.102: v2(221.16,141.88) 220.71,142.32 220.33,142.32 220.27,142.39 220.24,142.39 220.2,142.42 219.29,142.42 219.19,142.32 218.74,142.32 218.31,141.89 UV18.C21 ; v2(245.92,147.47) UV26.B2
FBC_D60: length 1.1
  BOTTOM w0.102: v2(219.41,144.81) 219.41,144.8 UV18.B24 ; UV26.E4 v2(243.51,149.8)
FBC_D61: length 1.2
  BOTTOM w0.102: v2(244.27,148.23) 243.88,147.84 UV26.E2 ; UV18.C24 218.21,144.39 v2(218.66,144.84)
FBC_D62: length 2.3
  BOTTOM w0.102: UV26.F4 243.07,149.43 v2(242.65,149.85) ; v2(220.4,146.07) 220.4,146.07 220.08,145.75 219.51,145.75 219.17,146.09 UV18.B26
FBC_D63: length 1.1
  BOTTOM w0.102: v2(217.79,146.51) 218.2,146.1 UV18.C26 ; v2(242.7,147.43) 242.7,147.45 UV26.F2
FBC_DBI0#: length 1.1
  BOTTOM w0.102: UV18.E11 216.6,133.57 v2(217,133.17) ; UV25.D2 v2(236.28,132.9)
FBC_DBI1#: length 1.2
  BOTTOM w0.102: v2(216.96,127.28) 216.58,126.89 UV18.E3 ; v2(236.29,124.07) 236.3,124.07 236.3,124.08 UV25.D13
FBC_DBI2#: length 2
  BOTTOM w0.102: UV18.A3 220.5,126.19 v2(220.9,126.19) ; UV25.P13 v2(245.08,124.1)
FBC_DBI3#: length 4
  BOTTOM w0.102: UV18.C9 218.35,131.89 218.68,132.23 219.06,132.23 219.32,132.48 220.65,132.48 v2(221.22,133.05) ; UV25.P2 244.68,132.45 v2(245.03,132.1)
FBC_DBI4#: length 1.4
  BOTTOM w0.102: v2(215.79,142.8) 215.75,142.84 UV18.F23 ; UV26.P2 v2(236.28,148.23)
FBC_DBI5#: length 1.2
  BOTTOM w0.102: UV26.P13 v2(237.08,156.23) ; v2(215.35,147.35) 215.35,147.32 215.75,146.92 UV18.F27
FBC_DBI6#: length 1.1
  BOTTOM w0.102: UV18.C30 218.2,149.42 v2(218.6,149.82)
  BOTTOM w0.13: v2(245.09,156.26) 244.72,156.63 UV26.D13
FBC_DBI7#: length 2.7
  BOTTOM w0.102: v2(221.69,143.66) 221.67,143.68 221.67,143.72 221.22,144.16 220.03,144.16 UV18.A24
  BOTTOM w0.107: v2(244.31,147.47) 244.32,147.47 UV26.D2
FBC_EDC0: length 1.2
  BOTTOM w0.102: UV18.D10 217.4,132.77 v2(217.8,133.17) ; UV25.C2 v2(236.28,132.1)
FBC_EDC1: length 5.7
  BOTTOM w0.102: UV25.C13 235.48,124.1 v2(235.48,124.09) ; v2(221.6,128.8) 221.16,129.24 220.69,129.24 220.21,129.72 218.86,129.72 218.67,129.53 218.67,129.36 218.32,129.01 217.82,129.01 UV18.D5
FBC_EDC2: length 1.2
  BOTTOM w0.102: UV18.C3 218.59,126.5 v2(218.59,126.48) ; v2(245.87,124.17) 245.87,124.17 245.48,123.78 UV25.R13
FBC_EDC3: length 4.2
  BOTTOM w0.102: UV18.B9 219.11,131.89 219.44,132.23 221.35,132.23 222.05,132.92 v2(222.05,133.05) ; v2(245.88,132.9) UV25.R2
FBC_EDC4: length 1.1
  BOTTOM w0.102: v2(216.21,143.21) 216.21,143.21 216.22,143.21 216.22,143.21 UV18.E23 ; UV26.R2 v2(235.48,148.23)
FBC_EDC5: length 1.2
  BOTTOM w0.102: UV18.E28 216.18,148.17 v2(216.14,148.17) ; UV26.R13 v2(236.28,156.23)
FBC_EDC6: length 1.2
  BOTTOM w0.102: v2(219.42,149.81) 219.42,149.81 UV18.B30
  BOTTOM w0.107: UV26.C13 v2(245.88,156.23)
FBC_EDC7: length 1.4
  BOTTOM w0.102: v2(220.51,143.71) 220.39,143.59 UV18.A23
  BOTTOM w0.107: UV26.C2 v2(245.9,148.25)
FBC_MA0_MA10_H: length 30.1
  TOP w0.102: 239.86,147.13 239.86,148.34 240.28,148.77 v2(240.28,149.03) ; 223.49,140.75 223.2,140.75 222.3,139.85 221.86,139.85 220.34,138.33 217.96,138.33 v2(217.8,138.17)
  TOP w0.221: 239.86,147.13 239.86,145.26 235.64,141.04 233.27,141.04 232.98,140.75 v1(230.59,140.75) 223.49,140.75
  BOTTOM w0.102: UV26.K4 v2(240.28,149.03) ; v2(217.8,138.17) 217.4,137.77 UV18.D16
FBC_MA0_MA10_L: length 26.9
  BOTTOM w0.102: UV25.H4 239.57,130.59 239.57,130 238.94,129.37 ; 222.75,136.76 222.53,136.54 217.76,136.54 UV18.D15
  BOTTOM w0.221: 238.94,129.37 238.74,129.17 233.98,129.17 v1(226.74,136.41) 226.39,136.76 222.75,136.76
FBC_MA1_MA9_H: length 27.3
  TOP w0.102: 223.85,142.21 223.66,142.21 v2(221.94,140.49) ; v2(239.63,150.73) 238.3,149.4 238.3,146.2
  TOP w0.221: 223.85,142.21 232.14,142.21 233.45,143.52 235.86,143.52 238.3,145.96 238.3,146.2
  BOTTOM w0.102: UV18.A18 219.98,139.21 220.66,139.21 v2(221.94,140.49)
  BOTTOM w0.107: UV26.K5 239.64,150.47 239.64,150.73 v2(239.63,150.73)
FBC_MA1_MA9_L: length 24.4
  BOTTOM w0.102: UV18.A14 220.78,136.09 220.84,136.03 222.75,136.03 ; UV25.H5 239.88,129.37
  BOTTOM w0.221: 222.75,136.03 226.09,136.03 v1(230.67,131.45) 233.68,128.44 239.04,128.44 239.88,129.28 239.88,129.37
FBC_MA2_BA0_H: length 35.1
  TOP w0.102: v2(215.33,139.82) 215.96,139.82 216.59,140.44 216.59,140.86 216.85,141.12 217.16,141.12 217.42,141.38 217.42,143.6 218.05,144.23 219.52,144.23 219.84,144.54 ; v2(240.27,154.64) 240.27,154.71 239.86,155.12 239.86,155.59 239.63,155.82 233.68,155.82
  TOP w0.221: 233.68,155.82 v1(232.94,155.82) 231.11,155.82 219.84,144.54
  BOTTOM w0.102: UV18.F18 v2(215.33,139.82) ; UV26.K11 v2(240.27,154.64)
FBC_MA2_BA0_L: length 32.6
  TOP w0.102: 216.86,134.4 215.81,134.4 215.12,135.09 215.12,136.22 v2(215.37,136.47) ; v2(240.28,124.9) 239.91,124.52 233.68,124.52
  TOP w0.119: 218.99,132.91 218.99,133.47 218.52,133.93 217.93,133.93 217.46,134.4 216.86,134.4
  TOP w0.147: 222,131.73 221.08,131.73 220.13,132.68 219.21,132.68 218.99,132.91
  TOP w0.221: 222,131.73 223.7,131.73 224.41,131.02 v1(224.74,131.02) 227.03,131.02 233.53,124.52 233.68,124.52
  BOTTOM w0.102: UV25.H11 v2(240.28,124.9) ; UV18.F14 v2(215.37,136.47)
FBC_MA3_BA3_H: length 31.6
  TOP w0.102: 220.5,144.34 220.34,144.34 219.91,143.91 218.55,143.91 218.21,143.57 218.21,141.62 217.36,140.77 217.36,140.18 v2(217,139.82) ; 233.68,155.05 239.06,155.05 v2(239.48,154.63)
  TOP w0.221: 220.5,144.34 220.98,144.34 v1(229.77,153.13) 231.69,155.05 233.68,155.05
  BOTTOM w0.102: v2(217,139.82) 216.6,139.42 UV18.E18 ; UV26.K10 v2(239.48,154.63)
FBC_MA3_BA3_L: length 28.2
  TOP w0.102: v2(217.06,135.67) 217.44,135.28 218.97,135.28 219.74,134.52 219.74,133.77 221.03,132.48 223.38,132.48
  TOP w0.221: v2(239.48,125.7) 238.38,126.8 233.92,126.8 228.23,132.48 223.38,132.48
  BOTTOM w0.102: v2(217.06,135.67) 217.03,135.67 UV18.E14
  BOTTOM w0.107: UV25.H10 v2(239.48,125.7)
FBC_MA4_BA2_H: length 28.3
  BOTTOM w0.102: UV26.H11 241.1,154.64 241.1,154.2 240.59,153.69 ; UV18.A20 219.8,140.92 220.24,140.48 220.58,140.48 221.61,141.5
  BOTTOM w0.221: 240.59,153.69 240.08,153.18 233.28,153.18 v1(224.14,144.04) 221.61,141.5
FBC_MA4_BA2_L: length 27.5
  TOP w0.102: 241.42,126.51 241.42,126.19 241.5,126.11 241.5,125.28 v2(241.86,124.92) ; 223.25,133.55 220.93,133.55 v2(220.31,134.16)
  TOP w0.221: 241.42,126.51 241.42,127.02 240.91,127.52 v1(240.58,127.52) 234.22,127.52 228.43,133.31 224.23,133.31 223.99,133.55 223.25,133.55
  BOTTOM w0.102: UV25.K11 241.86,124.92 v2(241.86,124.92) ; v2(220.31,134.16) 220.08,134.39 UV18.A12
FBC_MA5_BA1_H: length 28.4
  TOP w0.102: v2(219.4,141.49) 220.33,142.42 221.38,142.42 222.81,143.85 222.81,144.11
  TOP w0.147: 234.16,153.17 234.23,153.09 240.81,153.09 v2(241.09,153.38)
  TOP w0.221: 222.81,144.11 231.87,153.17 v1(233.15,153.17) 234.16,153.17
  BOTTOM w0.102: v2(241.09,153.38) 241.09,153.74 241.48,154.13 UV26.H10
  BOTTOM w0.107: UV18.B20 v2(219.4,141.49)
FBC_MA5_BA1_L: length 26.3
  BOTTOM w0.102: 222.75,133.85 222.52,134.08 221.16,134.08 220.52,134.72 219.33,134.72 UV18.B12 ; 233.74,126.26 234,126.26 234.15,126.41 241.17,126.41 UV25.K10
  BOTTOM w0.221: 222.75,133.85 225.19,133.85 v1(227.45,131.58) 232.78,126.26 233.74,126.26
FBC_MA6_MA11_H: length 36.9
  TOP w0.102: 221.01,140.82 220.53,140.33 220.21,140.33 218.94,139.07 215.25,139.07 v2(214.5,139.82)
  TOP w0.147: v2(241.88,149.83) 242.29,150.23 242.29,151.55 241.65,152.18 234.64,152.18 234.62,152.16 ; 221.01,140.82 222.26,142.06 222.26,142.15
  TOP w0.221: 234.62,152.16 v1(233.1,150.64) 226.14,143.69 223.79,143.69 222.26,142.15
  BOTTOM w0.102: v2(214.5,139.82) 214.9,139.42 UV18.G18 ; UV26.H5 v2(241.88,149.83)
FBC_MA6_MA11_L: length 32.1
  TOP w0.102: 218.1,136.11 216.07,136.11 215.81,136.37 215.81,136.57 215.45,136.93 215.17,136.93 214.79,137.32 v2(214.5,137.32)
  TOP w0.221: 218.1,136.11 219.76,136.11 221.83,134.04 228.74,134.04 234.34,128.43 v1(237.78,128.43) 239.93,128.43 v2(241.12,129.62)
  BOTTOM w0.102: UV25.K5 241.12,129.73 v2(241.12,129.62) ; UV18.G15 214.9,136.92 v2(214.5,137.32)
FBC_MA7_MA8_H: length 29.9
  BOTTOM w0.102: 222.12,140.99 222,140.87 221.78,140.87 220.88,139.96 220.88,139.85 220.6,139.57 220.21,139.57 220.06,139.72 219.94,139.72 219.94,139.72 219.66,139.72 219.66,139.72 219.32,139.72 219,139.4 UV18.B18 ; UV26.H4 241.17,149.74 241.17,151.01 240.68,151.5
  BOTTOM w0.221: 222.12,140.99 222.16,141.02 222.68,141.02 v1(227.35,145.68) 233.93,152.27 239.92,152.27 240.68,151.5
FBC_MA7_MA8_L: length 28.6
  BOTTOM w0.102: 221.59,135.3 221.2,135.3 220.78,135.72 219.37,135.72 UV18.B14 ; UV25.K4 241.79,130.59 241.79,129.43 241.73,129.37
  BOTTOM w0.221: 241.73,129.37 241.09,128.73 240.36,128.73 239.35,127.71 233.38,127.71 v1(227.24,133.86) 225.79,135.3 221.59,135.3
FBC_MA12_RFU_H: length 33.2
  TOP w0.102: 223.75,141.48 223.47,141.48 222.1,140.1 221.62,140.1 220.15,138.64 216.65,138.64 v2(216.18,138.17) ; 239.13,146.2 239.13,147.98 239.9,148.75 239.9,149.18 240.12,149.41 240.4,149.41 240.72,149.72 v2(240.72,150.83)
  TOP w0.221: 223.75,141.48 v1(226.99,141.48) 232.44,141.48 233.75,142.79 236.16,142.79 239.13,145.76 239.13,146.2
  BOTTOM w0.102: v2(240.72,150.83) 240.68,150.8 UV26.J5 ; UV18.F17 v2(216.18,138.17)
FBC_MA12_RFU_L: length 29.7
  TOP w0.102: 220.43,136.36 220.26,136.53 v2(216.19,136.53)
  TOP w0.221: 220.43,136.36 222.02,134.77 229.04,134.77 234.63,129.17 239.84,129.17 240.46,129.79 240.46,129.88 v2(241.08,130.5)
  BOTTOM w0.102: UV18.E15 216.55,136.89 216.19,136.53 v2(216.19,136.53) ; UV25.J5 v2(241.08,130.5)
FBC_RAS#_H: length 30
  BOTTOM w0.102: UV18.D17 217.73,138.92 219.98,138.92 220.07,138.83 220.99,138.83 222.3,140.14 222.75,140.14 ; 239.11,150.91 239.19,150.83 239.19,150.56 239.39,150.36 239.39,150.08 239.05,149.74 238.95,149.74 238.77,149.56 238.77,148.94 UV26.L3
  BOTTOM w0.221: 222.75,140.14 223.16,140.14 v1(226.23,143.21) 234.27,151.25 238.77,151.25 239.11,150.91
FBC_RAS#_L: length 26.1
  TOP w0.102: v2(238.68,132.1) 238.3,131.72 234.37,131.72 ; v2(217.04,137.31) 217.49,136.86 220.84,136.86 221.12,136.59
  TOP w0.221: 221.12,136.59 222.2,135.5 229.9,135.5 v1(232.94,132.46) 233.68,131.72 234.37,131.72
  BOTTOM w0.102: v2(217.04,137.31) 217.04,136.48 217.4,136.12 UV18.D14 ; UV25.G3 v2(238.68,132.1)
FBC_RST#_H: length 29
  TOP w0.102: v2(222.11,139.37) 222.52,139.78 222.84,139.78 ; 240.59,147.01 240.66,147.08 240.66,147.85 v2(240.28,148.23) 241.22,149.17 RV615.1
  TOP w0.221: 240.59,147.01 240.59,144.96 235.94,140.31 233.61,140.31 233.32,140.02 223.07,140.02 222.84,139.78
  BOTTOM w0.102: UV26.J2 v2(240.28,148.23) ; UV18.A17 221.33,138.59 v2(222.11,139.37)
FBC_RST#_L: length 26.2
  TOP w0.102: 234.09,132.89 234.46,132.52 239.9,132.52 v2(240.28,132.9) 240.28,132.24 239.89,131.84 239.89,130.97 RV616.1
  TOP w0.221: v2(221.55,137.39) 221.55,137.3 222.63,136.23 230.75,136.23 234.09,132.89
  BOTTOM w0.102: v2(221.55,137.39) 221.6,137.34 221,136.74 219.95,136.74 UV18.A15 ; UV25.J2 v2(240.28,132.9)
FBC_WCK0: length 1.2
  BOTTOM w0.102: UV25.D4 v2(236.28,130.5)
  BOTTOM w0.114: v2(216.17,130.61) 215.75,131.03 UV18.F8
FBC_WCK0_N: length 1.2
  BOTTOM w0.102: UV25.D5 v2(237.08,130.5)
  BOTTOM w0.114: UV18.E8 216.6,131.02 216.98,130.64 216.98,130.62 v2(216.99,130.61)
FBC_WCK1: length 1.3
  BOTTOM w0.102: UV18.A5 219.82,128.61 219.82,128.86 219.7,128.99 v2(219.38,128.99) ; v2(245.05,130.56) 244.94,130.56 244.68,130.81 UV25.P4
FBC_WCK1_N: length 1.4
  BOTTOM w0.102: v2(245.13,129.7) 245.08,129.7 UV25.P5 ; UV18.A6 v2(220.36,128.83)
FBC_WCK2: length 1.1
  BOTTOM w0.102: UV26.P4 v2(236.28,149.83)
  BOTTOM w0.114: UV18.D24 217.4,144.45 v2(217.03,144.82)
FBC_WCK2_N: length 1.1
  BOTTOM w0.102: UV26.P5 v2(237.08,149.83)
  BOTTOM w0.114: UV18.D25 217.4,145.26 v2(217.02,145.65)
FBC_WCK3: length 1.1
  BOTTOM w0.102: UV18.B27 219.38,146.51 v2(219.38,146.45) ; v2(244.31,149.79) UV26.D4
FBC_WCK3_N: length 1.1
  BOTTOM w0.102: v2(217.8,147.27) 217.82,147.27 UV18.C27 ; v2(244.53,150.7) 244.53,150.38 UV26.D5
FBC_WE#_H: length 32.6
  TOP w0.102: v2(218.59,139.78) 220.05,141.24 221.06,141.24 221.94,142.12 221.94,142.2 224.15,144.41
  TOP w0.147: v2(241.88,155.43) 241.88,155.3 242.36,154.83 242.36,153.73 241.23,152.61 v1(240.31,152.61) 234.19,152.61
  TOP w0.221: 224.15,144.41 232.18,152.44 233.87,152.44 234.03,152.61 234.19,152.61
  BOTTOM w0.102: v2(218.59,139.78) UV18.C18 ; UV26.G12 v2(241.88,155.43)
FBC_WE#_L: length 30.6
  BOTTOM w0.102: 222.75,134.57 221.45,134.57 220.5,135.52 219.28,135.52 219.23,135.57 218.72,135.57 UV18.C14
  BOTTOM w0.221: 222.75,134.57 225.49,134.57 v1(229.51,130.55) 233.08,126.98 242.12,126.98 242.68,126.42 242.68,124.9 UV25.L12
FBVDD/Q_ENP: length 3.5
  TOP w0.203: PC710.1 194.34,184.76 v1(194.34,184.21) 194.34,184.19 193.8,183.66 PU700.3
  TOP w0.254: PC710.1 194.88,185.31 PR709.2
FBVDD_EN: length 9.8
  TOP w0.203: v2(198.55,186.58) 198.55,185.82 198.04,185.31 v1(197.28,185.31) PR709.1 ; v2(202.31,120.68) 202.94,120.06 U33.19
  TOP w0.254: QZ6.5 249.99,121.73 v2(249.25,121) ; RV550.1 206.43,112.41 DV13.1 206.92,112.86 208.04,113.98 208.1,113.98 v2(208.11,113.99)
  vias: v2(160.83,167.12)
FBVDD_PSI: length 6.7
  TOP w0.14: v1(197.28,187.47) 196.9,187.09 196.77,187.09 196.23,186.54 PR703.2
  TOP w0.203: PU700.4 193.67,184.06 193.98,184.37 193.98,186.2 194.36,186.58
  TOP w0.254: 194.36,186.58 195.54,186.58 PR708.1 195.94,186.49 195.97,186.45 PR703.2
FBVDDQ_SENSE: length 1.9
  TOP w0.254: v2(188.64,184.55) 188.48,184.55 PR718.2
  BOTTOM w0.254: v2(215.57,124.1) 215.7,124.23 UV18.F1
FFS_INT2: length 33.8
  TOP w0.14: v2(186.19,85.05) 186.19,84.84 185.97,84.63 183.82,82.47 183.82,76.74 184.53,76.03 184.53,75.54 184.63,75.44 184.63,74.31 184,73.68 184,71.41 183.71,71.12 181.68,71.12 181.32,71.48 181.09,71.48 v2(180.61,70.99) ; UF1.11 234.08,113.11 v2(234.44,112.74) 234.44,112.46 232.23,110.25 QF1.2 ; RF5.2 238.02,109.76 v4(238.02,109.34) 237.67,109.34 v2(237.13,108.8)
  BOTTOM w0.089: UH2.BE14 90.85,72.16 90.85,71.66 90.7,71.51 90.7,71.19 v3(90.7,71.18)
  BOTTOM w0.14: v2(237.13,108.8) 237.13,109.32 234.44,112.01 v2(234.44,112.74)
FFS_INT2_Q: length 59.6
  TOP w0.14: v2(260.58,76.23) 260.27,76.54 v1(260.27,78.77) 260.27,80.77 261.37,81.88 261.37,85.4 261.63,85.66 261.63,87.3 259.68,89.25 259.68,90.15 259.15,90.68 259.15,95.53 258.31,96.38 258.31,98.91 250.26,106.96 246.67,106.96 245.56,108.07 231.57,108.07 230.7,108.95 RF2.2 231.24,109.72 231.36,109.6 QF1.3
  BOTTOM w0.14: v2(234.12,76.54) JHDD.11
FGND: length 8
  BOTTOM w0.14: JFP.4 314.36,101.76 314.63,101.49 315.52,101.49 316.53,100.48 316.53,98.87 316.18,98.52 ; 316.18,98.52 RE255.2 ; 316.18,98.52 316.66,98.04 316.66,96.41 v1(316.41,96.16)
FPR_DET#: length 5.7
  TOP w0.076: UE3.B3 292.35,79.23 v2(292.29,79.23)
  TOP w0.14: RE284.1 293.07,71.68 293.07,72.12 v2(293.21,72.26)
  BOTTOM w0.14: v2(319.58,96.28) 319.07,95.78 v1(318.31,95.78) 318.06,96.03 318.06,97.88 317.58,98.37 RE274.1
FPR_GPIO_DET#: length 6.7
  BOTTOM w0.14: JFP.1 316.25,102.28 317.49,101.05 MD3.1 317.49,99.34 RE274.2 317.5,99.28 317.04,98.82 317.04,97.43 v1(317.55,96.92)
FPR_GPIO_SCAN#: length 7.9
  BOTTOM w0.14: MD4.1 319.01,100.41 316.28,103.14 315.77,103.14 315.36,102.73 JFP.2 ; MD4.1 v1(320.34,100.09) ; MD4.1 319.01,99.34 RE273.2
FPR_SCAN#: length 5.4
  TOP w0.076: UE3.E5 v2(295.52,80.06)
  TOP w0.14: v2(293.88,72.26) 293.83,72.2 RE283.1
  BOTTOM w0.14: v2(318.95,96.28) 318.44,96.79 318.44,97.86 RE273.1 320.42,98.37 v1(320.6,98.19)
FRM_LCK: length 2.3
  TOP w0.14: v1(211.45,114.02) 212.15,114.02 v2(212.23,114.1) 212.23,114.1 RV564.1
  BOTTOM w0.14: UV18.L7 211.59,130.19 v2(211.99,130.59)
GC5_MODE: length 2.7
  TOP w0.14: v2(210.98,113.5) 210.62,113.14 T210.1 211.2,112.21 RV1839.1
  BOTTOM w0.14: v2(208.62,127.28) 209,127.66 UV18.P4
GC6_EVENT#: length 30.1
  TOP w0.14: DV14.1 212.31,109.59 v1(212.97,110.26) 212.97,110.51 v2(213.22,110.76) ; v2(183.41,71.71) 183.06,72.06 183.06,82.67 182.92,82.8 182.92,85.36 183.03,85.46 183.03,89.21 v2(183.16,89.35)
  BOTTOM w0.089: v2(99.19,69.74) 98.52,69.07 95.66,69.07 95.54,68.95 93.61,68.95 93.15,69.41 93.15,70.17 92.26,71.07 92.26,71.48 92.56,71.78 92.56,72.16 92.8,72.39 UH2.BE9
GC6_EVENT#_D: length 3.9
  TOP w0.14: v2(213.66,112.95) 213.28,112.57 RV551.1 212.98,111.96 213.16,111.78 v1(213.16,111.61) 212.84,111.29 DV14.2
  BOTTOM w0.14: v2(211.97,129.81) UV18.L6
GPIO0: length 4.7
  TOP w0.14: UM1.C4 20.92,138.5 23.04,138.5 23.72,137.81 24.5,137.81 24.64,137.95 RM13.2
GPIO2: length 3.8
  TOP w0.14: RM12.2 24.39,139.46 23.74,140.11 21.7,140.11 UM1.E3
GPIO4: length 2.8
  TOP w0.14: v2(18.52,140.88) 18.5,140.88 UM1.E7 ; v1(20.97,133.01) 21.31,133.01 v2(21.5,132.82) 21.59,132.73 RM11.2 22.8,132.73 RM20.2
GPP_H12: length 4.6
  TOP w0.089: RH5881.2 74.72,83.2 74.14,83.78 v1(73.66,83.78) v2(73.13,83.78)
  BOTTOM w0.089: v2(73.13,83.78) 73.38,84.03 74.08,84.03 UH2.AB47
GPP_H15: length 8.1
  TOP w0.089: v1(76.31,85.76) 76.37,85.76 76.84,85.29 RH42.2 76.84,84.65 v2(77.36,84.13)
  BOTTOM w0.089: UH2.AC47 74.57,83.28 74.75,83.47 75.07,83.47 75.29,83.26 75.29,83.12 75.53,82.88 78.05,82.88 78.28,83.11 78.28,83.29 78.1,83.47 77.57,83.47 77.35,83.69 77.35,84.12 v2(77.36,84.13)
GPP_J4: length 5
  TOP w0.089: RH5853.2 90.81,76.76 92.46,76.76 92.64,76.57 93.17,76.57 93.27,76.68 93.81,76.68 v2(94.14,76.35)
  BOTTOM w0.089: v2(94.14,76.35) 94.56,75.92 UH2.AV4
GPP_J6: length 7.2
  TOP w0.089: v2(95.21,73.55) 95.67,74.01 95.67,75.37 v1(95.59,75.45) 94.18,76.85 93.2,76.85 93.09,76.75 92.71,76.75 92.38,77.08 RH5854.2
  BOTTOM w0.089: UH2.BA4 95.32,73.66 v2(95.21,73.55)
GPP_J9: length 6.5
  TOP w0.089: v2(92.2,76.17) 92.2,76.32 91.95,76.58 90.31,76.58 89.45,77.43 88.7,77.43 88.42,77.72 RH5855.2 RH5890.1
  BOTTOM w0.089: v2(92.2,76.17) 92.92,76.17 UH2.AU9
GPPJ_RCOMP: length 1.1
  BOTTOM w0.14: RH5834.1 99.92,72.76 v1(100.56,73.4)
GPU_CORE_PG: length 3.7
  TOP w0.127: v2(248.35,108.1) v1(248.35,107.55)
  TOP w0.254: v2(248.35,108.1) 248.45,108.2 DV16.3 ; UV28.2 170.36,178.39 170.74,178.77 v2(170.74,178.83)
  BOTTOM w0.254: PR1017.2 170.6,178.97 v2(170.74,178.83)
GPU_CORE_VDDS_PG: length 4.5
  TOP w0.14: v2(200.93,115.92) 200.71,116.13 200.71,116.65 201.25,117.19 U33.5
  BOTTOM w0.14: PR905.1 242.32,180.31 v2(242.11,180.1) ; PR1518.2 188.47,187.14 v2(187.92,186.59)
  vias: v2(203.29,124.75)
GPU_GC6_FB_EN: length 48.3
  TOP w0.076: UE3.M4 301.12,79.27 301.61,79.27 301.67,79.21 302.06,79.21
  TOP w0.14: v2(182.38,75.77) 182.04,76.11 182.04,78.12 182.68,78.76 182.68,85.46 182.78,85.56 182.78,88.96 182.6,89.15 182.6,89.91 182.53,89.97 182.53,92.51 v2(182.71,92.69) ; U33.7 201.85,116.12 201.96,116.01 201.96,114.88 RV1844.1 201.14,114.06 201.14,113.38 203.35,111.17 206.83,111.17 v2(207.82,112.16) ; 302.06,79.21 302.62,79.21 v2(302.75,79.08) ; QV98.1 241.53,116.54 239.93,116.54 239.37,115.98 239.37,115.04 v1(239.88,114.53) 240.43,113.98 240.43,111.1 v2(240.12,110.79) 240.12,110.14 RV1133.1
  BOTTOM w0.089: v2(93.42,70.44) 93.43,70.45 93.43,70.67 92.8,71.3 UH2.BF9
  BOTTOM w0.14: v2(182.38,75.77) 182.38,74.54 182.98,73.94 182.98,73.17 182.45,72.65 181.85,72.65 181.21,72.01 v2(181.21,70.99)
GPU_GC6_FB_EN_GPU: length 21.4
  TOP w0.14: v2(201.46,115.41) 201.46,116.01 201.14,116.33 201.14,116.69 201.24,116.79 U33.6 ; QV98.3 241.49,115.63 240.03,115.63 239.93,115.52 239.93,114.98 240.79,114.12 v1(240.79,112.25) v2(240.79,110.79) ; RV566.1 210.6,109.42 211.25,110.07 211.25,111.57 210.16,112.67 210.16,113.46 v2(210.44,113.74) 210.44,113.8 209.97,114.27 209.53,114.27 DV13.3 ; QV105.2 227.06,111.48 v2(227.39,111.81)
  BOTTOM w0.14: v2(211.1,126.49) UV18.M3
GPU_GC6_FB_EN_GPU#: length 17
  TOP w0.14: UV29.2 RV1842.2 219.3,112.16 218.92,112.16 218.52,111.75 218.52,110.36 219.63,109.24 219.63,108.52 220.37,107.78 v1(226.43,107.78) 227.71,109.06 227.71,111.03 QV105.1
GPU_GPIO0: length 1.2
  BOTTOM w0.14: UV18.P6 208.94,129.34 208.58,128.99 v2(208.58,128.92) ; RV1095.1 v2(162.63,185.27)
  vias: v2(179.6,159.78)
GPU_GPIO3: length 1.7
  BOTTOM w0.14: v2(181.64,178.92) 181.98,179.25 RV1098.1 ; UV18.P5 208.98,128.49 v2(208.58,128.1)
GPU_GPIO8: length 2.5
  TOP w0.14: v2(226.57,114.65) 226.76,114.46 RV1086.1 v1(227.79,113.84)
  BOTTOM w0.14: UV18.L3 211.48,126.89 v2(211.1,127.27)
GPU_GPIO21: length 4
  BOTTOM w0.14: UV18.P1 209,124.69 208.79,124.48 208.79,123.64 208.34,123.2 208.34,122.28 RV1840.1
GPU_GPIO22: length 2.1
  TOP w0.14: T4978.1 209.6,129.29 v2(209.6,129.7)
  BOTTOM w0.14: UV18.P8 209.44,130.55 209.44,129.85 v2(209.6,129.7)
GPU_GPIO25: length 1.5
  TOP w0.14: v2(207.77,127.28) 207.77,126.77 T4995.1
  BOTTOM w0.14: UV18.R4 208.18,127.69 v2(207.77,127.28)
GPU_GPIO26: length 1.4
  TOP w0.14: v2(207.75,128.07) 207.75,128.6 207.77,128.62 T4996.1
  BOTTOM w0.14: UV18.R5 208.17,128.49 v2(207.75,128.07)
GPU_ID: length 3.7
  TOP w0.076: UE3.J10 298.32,84.49 v2(297.93,84.89)
  TOP w0.14: v2(277.25,79.61) 276.93,79.93 276.25,79.93 RE301.2 276.19,79.98 CE3319.1 v1(276.19,81.87)
GPU_JTAG_TCK: length 13.4
  BOTTOM w0.102: UV18.AM10 193.92,132.74 193.49,132.31 193.08,132.31 192.91,132.48 192.47,132.48 191.12,131.13 189.6,131.13 188.35,129.89 182.87,129.89 T201.1
GPU_JTAG_TDI: length 12.9
  BOTTOM w0.102: UV18.AM11 194.37,133.22 194.37,132.59 194.04,132.26 193.85,132.26 193.57,131.98 193.57,131.74 193.33,131.49 192.28,131.49 191.63,130.84 189.73,130.84 188.56,129.67 184.29,129.67 T202.1
GPU_JTAG_TDO: length 2.8
  BOTTOM w0.14: T203.1 191.05,133.04 UV18.AP12
GPU_JTAG_TMS: length 3.5
  BOTTOM w0.14: UV18.AP11 190.67,131.86 189.65,131.86 T204.1
GPU_JTAG_TRST#: length 9
  BOTTOM w0.102: RV593.1 187.4,131.45 191.15,131.45 192.69,132.99 192.69,133.08 UV18.AN11
  BOTTOM w0.14: RV593.1 186.44,130.49 v1(185.57,130.49)
GPU_LEVEL: length 12.2
  TOP w0.14: v2(210.28,126.49) 211.2,125.57 211.2,123.31 212.44,122.06 v1(212.44,121.61) 212.44,118.85 213.16,118.13 DV15.2 213.16,117.05 212.85,116.74 RV554.1
  BOTTOM w0.14: v2(210.28,126.49) 210.26,126.49 209.86,126.89 UV18.N3
GPU_MF_BALL_A: length 4.3
  BOTTOM w0.14: RV617.1 v1(221.78,172.83)
  BOTTOM w0.254: UV23.J1 224.98,171.57
  BOTTOM w0.508: 224.98,171.57 223.72,172.83 RV617.1
GPU_MF_BALL_B: length 2.8
  TOP w0.102: v1(212.13,172.78) 212.81,172.78 213.36,172.23 RV618.1
  TOP w0.254: RV618.1 213.36,171.64 v2(213.41,171.6)
  BOTTOM w0.254: UV24.J1 213.34,171.6 v2(213.41,171.6)
GPU_MF_BALL_C: length 3.9
  TOP w0.14: RV631.1 239.94,134.89 239.94,135.27 v1(239.53,135.68)
  TOP w0.254: v2(239.7,133.94) 240.14,133.94 240.46,134.27 RV631.1
  BOTTOM w0.254: UV25.J1 240.04,133.94 v2(239.7,133.94)
GPU_MF_BALL_D: length 4.6
  BOTTOM w0.102: UV26.J1 240.68,146.96
  BOTTOM w0.14: 240.68,146.96 240.68,146.42 239.29,145.03 239.29,144.67 ; 239.29,144.67 v1(238.1,143.48) ; 239.29,144.67 RV630.1
GPU_PEX_RST_HOLD#: length 4
  TOP w0.14: RV563.1 218.61,114.89 218.23,114.52 v2(218.23,113.24)
  BOTTOM w0.14: v2(206.88,130.58) 207.29,130.99 UV18.T8
  vias: v2(195.12,122.7)
GPU_PSI: length 9
  BOTTOM w0.14: PR1001.2 v2(161.68,182.33) ; RV552.1 195.81,121.8 v2(195.86,121.85) ; v2(209.82,132.19) 210.3,131.7 210.3,130.64 210.7,130.24 UV18.M7 ; v2(181.79,178.2) 182.42,178.2 182.71,178.49 185.72,178.49 185.82,178.59 PR1501.2
  vias: v2(160.83,168.29)
GPU_PWR_LEVEL: length 11
  TOP w0.076: UE3.E12 294.8,86.38 294.8,87.52
  TOP w0.14: v2(294.48,87.89) 294.8,87.56 294.8,87.52 ; v2(212.86,120.03) 212.84,120.01 212.84,119.61 DV15.1 ; v2(294.92,94.34) 294.92,94.34 v1(295.31,93.95)
  BOTTOM w0.14: v2(294.48,87.89) 294.71,87.89 294.93,88.11 294.93,89.41 295.72,90.2 295.72,93.53 v2(294.92,94.34)
GPU_SMBCLK: length 27.4
  TOP w0.14: QV21.6 199.51,111.39 199.69,111.57 200.41,111.57 202.42,109.56 207.71,109.56 209.37,111.22 209.7,111.22 v2(209.96,111.47) ; v2(295.52,81.66) UE3.F7 ; v2(287.5,81.68) 287.5,81.73 RE296.1 ; v2(278.76,88.55) v1(279.44,88.55)
  BOTTOM w0.14: v2(278.76,88.55) 278.76,88.3 280.71,86.35 284.54,86.35 286.47,84.42 286.47,82.99 287.5,81.96 v2(287.5,81.68)
GPU_SMBDAT: length 35.9
  TOP w0.14: v2(209.35,111.65) 209.34,111.65 209.25,111.56 209.23,111.56 207.56,109.9 202.56,109.9 200.29,112.17 199.09,112.17 198.74,111.83 198.28,111.83 198.04,112.07 198.04,112.79 QV21.3 ; RE295.1 287.05,80.23 287.62,80.81 v2(287.78,80.81) 287.8,80.81 288.37,80.24 290.36,80.24 291.03,80.92 292.38,80.92 UE3.B6 ; v2(278.17,88.55) v1(278.17,89.08)
  BOTTOM w0.14: v2(287.78,80.81) 286.76,80.81 286.13,81.44 286.13,84.28 284.4,86.01 280.54,86.01 278.17,88.38 v2(278.17,88.55)
GPU_VREFD_BALL_A: length 2.5
  TOP w0.102: TV3.1 232.56,176.79 v2(232.18,177.17)
  BOTTOM w0.14: v2(232.18,177.17) UV23.U10
  BOTTOM w0.254: v2(231.97,165.88) 232.11,165.73 232.11,165.23 UV23.A10
GPU_VREFD_BALL_B: length 1.8
  TOP w0.102: TV4.1 206.13,177.83 v2(206.14,177.83)
  BOTTOM w0.254: UV24.U10 v2(206.12,165.17) ; UV24.A10 205.88,177.57 v2(206.14,177.83)
GPU_VREFD_BALL_C: length 1.7
  TOP w0.102: TV6.1 246.29,126.1 v2(246.68,126.5)
  BOTTOM w0.254: UV25.U10 v2(246.68,126.5) ; UV25.A10 234.28,126.04 v2(233.95,125.72)
GPU_VREFD_BALL_D: length 2.5
  TOP w0.102: 247.78,154.17 247.03,154.17 v2(246.68,153.83)
  TOP w0.14: TV5.1 247.78,154.17
  BOTTOM w0.254: UV26.A10 v2(246.68,153.83) ; UV26.U10 v2(234.68,153.83)
GPU_ZQ_BALL_A: length 3.5
  TOP w0.102: v2(234.58,170.77) 234.58,170.68 234.87,170.39 v1(234.98,170.39) 235.09,170.5 236.6,170.5
  TOP w0.14: RV619.1 236.68,170.5 236.6,170.5
  BOTTOM w0.107: UV23.J13 v2(234.58,170.77)
GPU_ZQ_BALL_B: length 1.9
  TOP w0.14: RV620.1 205.4,171.39 v2(206.16,170.63)
  BOTTOM w0.14: UV24.J13 v2(203.72,171.57)
GPU_ZQ_BALL_C: length 2.6
  TOP w0.102: RV633.1 239.65,122.69 239.89,122.93 v1(239.89,123.65) 239.89,123.76 v2(240.23,124.09)
  BOTTOM w0.102: v2(240.23,124.09) 240.28,124.09 UV25.J13
GPU_ZQ_BALL_D: length 2.6
  TOP w0.102: RV632.1 242.28,155.81 241.5,155.81 v2(241.08,156.23)
  BOTTOM w0.102: UV26.J13 v2(241.08,156.23)
GT_B+: length 0.9
  TOP w0.14: v4(103.16,137) v2(104.06,137)
  vias: v2(104.06,138.83) v2(104.06,138.22) v2(104.06,137.61) v2(104.67,138.83) v2(104.67,138.22) v2(104.67,137.61) v2(104.67,137) v2(106.35,138.96) v2(106.35,138.35)
GT_SW1: length 1.1
  TOP w0.14: v2(109.78,144.16) v4(109.78,145.24)
  vias: v2(109.78,143.4)
H_CATERR#: length 11.7
  BOTTOM w0.076: 132.38,147.85 134.02,147.85 134.3,148.13 134.99,148.13 135.12,148.01 137.49,148.01 UH1.BM30
  BOTTOM w0.14: RH570.2 v1(127.51,147.08) 128.88,147.08 129.65,147.85 132.38,147.85
H_CPUPWRGD: length 8.1
  TOP w0.14: v2(130.53,148.95) v4(131.1,148.95)
  BOTTOM w0.076: UH1.BT31 135.1,149.22 134,149.22 133.89,149.1 132.49,149.1 132.38,148.99
  BOTTOM w0.089: UH2.AE3 95.75,81.9 95.81,81.83 96.9,81.83 97.08,81.65 97.32,81.65 97.8,82.14 v2(97.91,82.14)
  BOTTOM w0.14: v2(130.53,148.95) 130.59,148.89 132.28,148.89 132.38,148.99
  vias: v2(123.29,122.22)
H_DRAMRST#: length 21.6
  TOP w0.14: RD35.2 RD31.2 133.01,83.95 131.44,82.39 CD69.1 131.21,82.36 v1(131.21,80.74) 131.21,78.72 132.32,77.62 136.89,77.62 138.25,76.25 138.25,75.31 137.28,74.34 v2(137.15,74.34)
  BOTTOM w0.089: UH2.BB46 74.05,73.47 73.91,73.6 73.51,73.6 72.96,73.6 72.91,73.55 72.82,73.55
  BOTTOM w0.14: 72.82,73.55 72.76,73.55 72.28,73.07 71.3,73.07 70.89,72.66 v2(70.89,72.46)
H_PECI: length 2.4
  TOP w0.14: v2(301.87,93.68) 301.87,93.17 301.93,93.11 RE48.2
  BOTTOM w0.089: RH539.2 99.24,81.67 v2(98.88,82.03)
  BOTTOM w0.14: v2(131.17,150.07) 130.86,150.38 RH190.1
H_PECI_R: length 6
  BOTTOM w0.14: v1(129.93,151.54) 130.35,151.54 130.54,151.73 RH190.2 131.03,151.57 RH200.1 132,151.57 133.19,150.37 134.96,150.37 UH1.BT34
H_PM_DOWN: length 2.1
  BOTTOM w0.089: v2(97.28,82.13) 97.21,82.06 UH2.AE2
  BOTTOM w0.14: RH155.1 127.71,149.88 127.4,150.18 v2(127.29,150.18)
  vias: v2(123.88,122.26)
H_PM_DOWN_R: length 9
  TOP w0.14: v4(130.12,150.42) 130.05,150.35 v2(130.05,149.44)
  BOTTOM w0.076: UH1.BP31 136.23,149.42 135.75,149.42 135.71,149.38 134.35,149.38 134.34,149.4 132.38,149.4
  BOTTOM w0.14: 132.38,149.4 132.16,149.4 132,149.24 130.85,149.24 130.66,149.44 v2(130.05,149.44) 129.39,149.44 RH155.2
H_PM_SYNC: length 4.3
  BOTTOM w0.089: RH189.1 98.77,82.44 97.8,81.48 96.93,81.48 96.78,81.63 95.93,81.63 UH2.AF3
H_PM_SYNC_R: length 43.8
  TOP w0.089: v2(133.87,150.99) v4(133.13,150.99)
  TOP w0.14: v2(108.13,84.08) 107.65,84.56 107.65,86.23 106.2,87.68 106.2,89.51 105.85,89.86 105.85,90.72 103.43,93.14 103.43,94.1 105.59,96.26 105.59,103.82 107.59,105.82 107.59,108.67 v2(107.44,108.82)
  BOTTOM w0.076: UH1.BM34 137.82,150.79 v2(137.49,151.12)
  BOTTOM w0.14: RH189.2 100.43,82.44 101.06,81.81 101.41,81.81 102,82.4 104.27,82.4 105.26,83.39 105.69,83.39 106.37,84.07 108.13,84.07 v2(108.13,84.08) ; v2(129.5,151.82) 129.8,152.13 130.21,152.13 130.3,152.21 132.03,152.21 132.53,151.71 133.15,151.71 v2(133.87,150.99)
H_PROCHOT#: length 57.9
  TOP w0.127: v2(105.84,169.44) 105.84,169.74 PR1113.2
  TOP w0.14: v2(50.13,100.98) 49.64,100.48 49.64,99.48 47.8,97.64 47.8,94.25 49.67,92.38 56.97,92.38 59.07,90.29 59.07,87.72 58.6,87.24 54.84,87.24 53.16,85.57 53.16,85.2 52.69,84.73 PR1919.1 ; RE96.2 297.79,90.59 297.64,90.74 297.64,92.71 297.05,93.3 297.05,93.77 296.91,93.91 295.92,93.91 295.61,93.59 295.02,93.59 294.43,94.18 293.55,94.18 v4(293.12,94.62) 292.34,95.4 292.34,96.6 291.54,97.4 289.74,97.4 289.13,96.8 287.98,96.8 285.89,94.7 285.89,93.95 285.2,93.26 284.17,93.26 283.43,93.99 v2(283.19,93.99) ; PR1104.2 v2(105.84,169.44)
  BOTTOM w0.14: RH165.2 126.21,147.58 v2(127.28,147.58) 127.73,148.04 RH158.1
  vias: v2(119.58,118.92) v2(127.72,114.33)
H_PROCHOT#_EC: length 2.4
  TOP w0.14: UE3.H13 297.79,87.13 RE96.1
H_PROCHOT#_R: length 9.1
  TOP w0.089: v2(133.85,148.44) 133.55,148.44 v4(132.93,149.05)
  BOTTOM w0.076: 132.38,148.24 133.65,148.24 v2(133.85,148.44) 134.29,148.87 134.64,148.87 134.9,148.62 135.38,148.62 135.66,148.34 UH1.BR30
  BOTTOM w0.14: RH158.2 128.7,148.24 132.38,148.24
H_THERMTRIP#: length 10.2
  BOTTOM w0.089: UH2.AD3 95.74,82.66 95.46,82.66 95.32,82.52 95.32,82.38 95.39,82.31 96.93,82.31 97.13,82.52 97.49,82.52 97.59,82.62 97.59,82.72 97.7,82.82 97.84,82.82 97.95,82.72 97.95,82.62 98.05,82.52 98.39,82.52 98.87,83 98.93,83 99.03,83.1 99.03,83.3 98.87,83.46 98.87,83.61 98.98,83.71 99.28,83.71 99.39,83.61 99.39,83.31 99.49,83.2 99.69,83.2 99.75,83.25
  BOTTOM w0.14: 99.75,83.25 RH191.1 100.68,84.19 101.87,84.19 v1(102.35,83.71)
H_THERMTRIP#_R: length 81
  TOP w0.14: v2(299.07,70.92) 299.07,70.45 QE10.3
  TOP w0.254: v2(170.46,149.34) 170.27,149.15 RH163.2
  BOTTOM w0.076: UH1.J31 170.8,149 v2(170.46,149.34)
  BOTTOM w0.14: v2(190.49,126.83) 189.15,125.49 189.15,118.64 175.58,105.07 175.58,95.16 174.23,93.81 174.23,88.03 173.34,87.14 v2(173.34,86.39) ; v2(101.19,82.28) 101.19,82.64 101.12,82.72 RH191.2 ; v2(272.46,89.92) 273.14,90.61 274.4,90.61 275.27,89.73 275.27,87.11 277.67,84.71 277.67,80.66 278.43,79.9 278.43,72.03 279.21,71.25 284.87,71.25 v2(285.33,70.79)
H_VCCST_PWRGD: length 6.4
  TOP w0.14: RH482.1 128.66,157.24 129.67,156.24 v1(129.67,155.83) v2(129.67,154.62) ; RH154.1 RH164.2 179.39,129.88 180.08,130.57 v2(180.08,130.7) ; UE7.4 v2(122.73,127.71)
  vias: v2(176.35,157.31)
H_VCCST_PWRGD_GATE: length 7.6
  TOP w0.14: UZ19.4 119.32,127.72 RZ82.2 120.07,127.35 v2(120.07,126.76) 120.57,126.76 121.34,126 UE7.2 121.34,125.19 v1(121.68,124.85)
  BOTTOM w0.14: RZ1955.2 RZ1957.2 119.74,126.76 v2(120.07,126.76)
HD_SOC_SEL: length 4.1
  BOTTOM w0.108: RA15.2 8.89,100.39 RA16.2 7.8,100.45 7.8,100.56 7.55,100.81 7.55,100.87 7,101.42 UA1.6
  BOTTOM w0.14: v1(9.94,100.59) 9.79,100.44 RA15.2
HDA_BITCLK: length 17.2
  BOTTOM w0.089: UH2.BD11 91.69,72.99 92.02,72.66 92.02,72.26 91.9,72.13 91.9,70.9 92.71,70.08 92.71,69.35 93.46,68.6 99.75,68.6
  BOTTOM w0.14: 99.75,68.6 102.11,68.6 v1(102.44,68.93) CH50.2 102.34,69.86 RP15.3
HDA_BITCLK_AUDIO: length 9.9
  BOTTOM w0.14: UA1.13 4.2,101.57 3.43,100.8 v2(3.43,100.73) 3.43,100.6 3,100.17 CA33.1 CA120.2 ; v2(104.87,75.5) v1(103.9,75.5) 103.22,75.5 101.42,73.7 101.42,72.42 101.52,72.32 102.03,72.32 102.34,72.63 RP15.6
HDA_RST#: length 15
  BOTTOM w0.089: 99.75,69.21 98.93,69.21 98.5,68.78 93.53,68.78 92.98,69.33 92.98,70.09 92.08,70.98 92.08,71.55 92.36,71.83 92.36,72.47 UH2.BE10
  BOTTOM w0.14: 99.75,69.21 100.83,69.21 v1(101.4,69.78) 102,70.38 102,71.3 101.84,71.46 RP15.4
HDA_SDIN0: length 5.6
  TOP w0.089: v1(90.18,69.27) 90.32,69.13 RH96.2 91.05,69.46 v2(91.23,69.64) 90.52,70.35 CD3324.1
  BOTTOM w0.089: v2(91.23,69.64) 91.7,70.12 91.7,72.4 UH2.BE11
HDA_SDIN0_AUDIO: length 20.5
  TOP w0.089: RH96.1 91.63,69.51 v2(91.77,69.65)
  BOTTOM w0.14: RA6.1 0.18,92.54 v1(0.68,92.04) 1.26,91.46 4.34,91.46 6.11,89.69 6.11,86.73 5.85,86.48 5.85,86.19 5.55,85.89 5.55,82.63 v2(6.45,81.73)
HDA_SDOUT: length 27.4
  TOP w0.14: v2(116.1,70.58) 116.14,70.62 v1(116.14,72.26) 115.75,72.65 115.75,73.04 115.24,73.55 113.33,73.55 112.93,73.14 RH454.2
  BOTTOM w0.089: UH2.BF12 91.52,71.53 91.52,70.46 90.87,69.8 90.87,69.45 91.07,69.25 92.24,69.25 92.89,68.6
  BOTTOM w0.14: 92.89,68.6 93.27,68.22 104.06,68.22 104.75,68.9 CD3325.1 CH51.2 104.75,70.11 v2(104.03,70.83) 103.11,70.83 102.84,71.1 RP15.2
HDA_SDOUT_AUDIO: length 6.6
  TOP w0.14: CA38.1 1.79,98.48 v2(1.57,98.27) 2.17,98.27 v1(2.19,98.24)
  BOTTOM w0.14: v2(105.29,73.81) 104.82,73.35 103.78,73.35 103.63,73.5 103.19,73.5 102.84,73.15 RP15.7 ; v2(1.26,102.76) 1.36,102.76 2.31,103.72 UA1.17
HDA_SYNC: length 22.2
  BOTTOM w0.089: 92.45,68.6 92.01,69.04 91.02,69.04 90.88,69.18 90.88,69.18 90.69,69.38 90.69,69.92 91.31,70.54 91.31,71.17 91.21,71.28 UH2.BG13
  BOTTOM w0.14: 92.45,68.6 93.1,67.95 104.81,67.95 105.22,68.36 105.22,70.32 v1(104.71,70.83) 104.27,71.27 103.45,71.27 103.34,71.38 RP15.1
HDA_SYNC_AUDIO: length 4.7
  BOTTOM w0.14: UA1.14 3.8,101.75 3.58,101.53 3.43,101.53 v2(3.27,101.37) 2.88,100.98 CA34.1 ; RP15.8 103.78,72.87 103.99,73.08 105.24,73.08 105.88,73.72 v2(105.88,73.83)
HDD_DET#: length 31.6
  TOP w0.14: v2(234.94,80.73) 234.37,81.3 220.26,81.3 v1(217.92,83.63) v2(217.92,85.04)
  BOTTOM w0.089: 70.97,82.05 72.75,80.26 73.12,80.26 73.8,79.59 74.16,79.59 74.28,79.71 UH2.AK47 74.69,79.71 74.8,79.59 74.89,79.56 75.08,79.56 75.24,79.71 75.72,79.71 v2(76.06,79.38)
  BOTTOM w0.14: JHDD.12 234.62,79.91 234.94,80.22 v2(234.94,80.73) ; 70.97,82.05 70.97,82.3 70.7,82.57 69.63,82.57 69.38,82.82 RH513.1
  vias: v2(174.39,86.39)
HDD_DEVSLP: length 3.4
  TOP w0.14: v2(235.64,76.54) 235.64,75.89 RD100.1 235.69,75.28 v1(236.65,74.31)
  BOTTOM w0.089: UH2.AH40 78.14,80.88 v2(78.14,81.24)
HDD_FALL_INT: length 62.8
  TOP w0.14: v2(257.64,73.94) 257.64,73.69 257.97,73.36 259.89,73.36 261.01,74.48 261.01,76.61 260.81,76.81 v1(260.81,80.52) 260.81,80.85 261.61,81.65 261.61,85.3 261.87,85.56 261.87,87.4 259.95,89.32 259.95,90.22 259.39,90.78 259.39,95.63 258.62,96.4 258.62,98.98 250.4,107.2 247.11,107.2 245.83,108.48 239.34,108.48 v2(239.19,108.63) ; v2(235.5,112.21) 235.19,112.51 RF4.2 234.58,113.53 UF1.12
  BOTTOM w0.089: v2(83.86,76.01) 84.43,75.43 UH2.AW26
  BOTTOM w0.14: v2(235.5,112.21) 236.05,111.65 236.55,111.65 239.19,109 v2(239.19,108.63)
HDMI_CEC: length 11.7
  TOP w0.14: RM19.2 26.15,142.26 v2(26.34,142.45)
  BOTTOM w0.14: JHDMI1.13 10.36,152.62 10.49,152.49 10.49,148.06 13.01,145.54 13.01,144.71 CV182.2 13.71,144.61 v2(13.92,144.82)
HDMI_CLKN: length 16.1
  TOP w0.102: RV532.1 15.61,155 16.93,155 v5(17.6,154.34) 19.1,152.84 19.1,149.92 21.19,147.84 21.19,147.56 22.65,146.1 22.65,143.17 UM1.H1
HDMI_CLKP: length 16.2
  TOP w0.102: UM1.H2 21.94,142.9 21.87,142.96 21.87,143.15 21.99,143.26 22.28,143.26 22.38,143.37 22.38,145.99 20.92,147.45 20.92,147.73 18.83,149.81 18.83,152.73 v5(18.48,153.08) 17.41,154.15 16.82,154.74 15.61,154.74 RV533.1
HDMI_HPLUG: length 11.5
  TOP w0.14: v1(11.42,159.9) 11.42,159.75 11.73,159.43 v2(11.73,159.4) 12.28,159.4 CV180.2 ; v2(23.65,143.61) 24.09,144.05 RH5894.2 24.27,144.8 24.69,144.38 RM27.1 24.69,144.01 24.23,143.56 24.23,142.82 23.99,142.57 23.39,142.57 UM1.G1
  BOTTOM w0.14: JHDMI1.19 9.53,156.08 11.33,157.87 11.33,159 v2(11.73,159.4)
HDMI_ID: length 5.2
  TOP w0.127: v1(13.09,139.03) 13.58,138.55 14.34,138.55 14.77,138.98 15.33,138.98 RM24.1
  TOP w0.14: RM24.1 16.07,138.57 17.04,139.54 17.16,139.54 UM1.D8
HDMI_R_CLKN: length 12.6
  TOP w0.076: 8.73,155.62 8.73,155.6 8.77,155.56 8.77,155.42 8.88,155.31 8.88,154.93 8.81,154.87 8.81,154.38 8.86,154.33 8.86,153.92 8.75,153.8 8.75,153.45 8.85,153.34 8.85,152.91 8.84,152.89 8.84,152.35 8.88,152.3 8.88,152.03 8.72,151.87 8.51,151.87 8.33,152.04 JHDMI1.12
  TOP w0.102: 8.73,155.62 8.73,156.25 9.05,156.57 10.59,156.57 11.04,156.13 v5(11.96,155.2) 12.17,155 13.23,155 DT175.1 13.79,155 14.12,155 RV539.1 14.43,155 14.71,155 RV532.2
HDMI_R_CLKP: length 12.5
  TOP w0.076: JHDMI1.10 8.83,151.62 8.83,151.72 9.06,151.95 9.06,152.38 9.01,152.42 9.01,152.81 9.03,152.83 9.03,153.41 8.92,153.52 8.92,153.72 9.04,153.84 9.04,154.4 8.99,154.45 8.99,154.79 9.06,154.86 9.06,155.39 8.95,155.49 8.95,155.56 9,155.6 9,155.62
  TOP w0.089: 13.21,154.73 13.25,154.73
  TOP w0.102: 13.21,154.73 12.06,154.73 11.77,155.01 10.48,156.3 9.16,156.3 9,156.14 9,155.62 ; 13.25,154.73 13.46,154.51 DT176.1 13.74,154.74 14.12,154.74 RV539.2 14.43,154.74 14.71,154.74 RV533.2
HDMI_R_TX_N0: length 7.6
  TOP w0.089: 12.89,153.36 DT177.1
  TOP w0.102: JHDMI1.9 9.88,150.27 10.06,150.27 10.39,150.6 10.39,152.97 10.8,153.38 12.38,153.38 DT177.1 ; 12.89,153.36 12.9,153.35 RV540.1 13.56,153.17 13.81,153.17 RV534.2
HDMI_R_TX_N1: length 12.1
  TOP w0.089: JHDMI1.6 8.33,148.84 8.46,148.72 8.8,148.72 8.99,148.52 9.08,148.26 9.08,147.98 8.98,147.64 8.98,147.57 9.07,147.34 9.07,147.01 8.93,146.61 8.93,146.33 8.97,146.28
  TOP w0.102: RV536.2 13.85,149.61 13.56,149.61 RV541.1 13.24,149.64 13.05,149.64 DT179.1 12.36,149.8 11.88,149.8 11.29,149.21 11.29,146.87 10.4,145.98 9.13,145.98 8.97,146.13 8.97,146.28
HDMI_R_TX_N2: length 8.9
  TOP w0.102: RV531.2 14.68,151.46 14.38,151.46 RV538.1 14.16,151.45 13.78,151.45 DT181.1 13.21,151.41 12.2,151.41 v5(11.89,151.1) 10.52,149.73 10.52,147.53 10.22,147.23 9.92,147.23 JHDMI1.3
HDMI_R_TX_P0: length 7.6
  TOP w0.102: JHDMI1.7 9.92,150.01 10.17,150.01 10.66,150.49 10.66,152.86 10.91,153.12 12.37,153.12 DT178.1 12.74,152.98 13.17,152.98 RV540.2 13.53,152.91 13.84,152.91 RV535.2
HDMI_R_TX_P1: length 12.1
  TOP w0.089: JHDMI1.4 8.33,148.38 8.48,148.53 8.68,148.53 8.83,148.42 8.89,148.23 8.89,148.01 8.79,147.67 8.79,147.53 8.88,147.3 8.88,147.04 8.74,146.65 8.74,146.31 8.71,146.28
  TOP w0.102: 8.71,146.28 8.71,146.02 9.02,145.71 10.51,145.71 11.56,146.75 11.56,149.1 11.99,149.54 12.39,149.54 DT180.1 12.77,149.45 12.86,149.45 12.94,149.38 13.22,149.38 RV541.2 13.53,149.35 13.75,149.35 RV537.2
HDMI_R_TX_P2: length 9
  TOP w0.102: JHDMI1.1 9.53,146.68 9.82,146.97 10.33,146.97 10.78,147.42 10.78,149.62 12.31,151.15 13.32,151.15 DT182.1 13.74,151.19 14.07,151.19 RV538.2 14.49,151.19 14.7,151.19 RV530.2
HDMI_RESERVED: length 13.7
  BOTTOM w0.14: JHDMI1.14 8.58,153.12 8.91,152.79 8.91,146.15 9.45,145.61 11.24,145.61 11.81,145.05 11.81,144.53 CV181.2 11.87,143.4 12.18,143.1 v1(13.09,143.1)
HDMI_TX_N0: length 18.4
  TOP w0.102: UM1.H3 21.19,143.02 21.19,143.91 21.81,144.52 21.81,145.57 19.69,147.68 17.53,147.68 17.3,147.92 17.3,148.58 17.51,148.8 17.87,148.8 18.15,149.08 18.15,149.94 17.36,150.73 17.36,151.28 17.49,151.41 17.79,151.41 18.15,151.76 18.15,152.55 17.51,153.19 v5(16.12,153.19) 14.72,153.19 RV534.1
HDMI_TX_N1: length 17.9
  TOP w0.102: RV536.1 14.74,149.58 15.13,149.58 15.55,149.16 15.55,148.67 14.86,147.98 v5(14.27,147.98) 13.52,147.98 12.64,147.1 12.64,144.96 13.22,144.38 14.43,144.38 14.96,144.91 15.9,144.91 16.91,145.91 18.88,145.91 19.44,145.36 19.44,144.54 19.72,144.26 UM1.H5
HDMI_TX_N2: length 13.4
  TOP w0.102: v2(20.5,145.28) 20.25,145.54 20.25,145.98 19.46,146.77 16.47,146.77 15.89,147.35 15.89,147.72 16.45,148.29 16.45,151.04 16.02,151.47 15.64,151.47 RV531.1 ; v2(18.72,144.93) 18.6,144.81 18.6,144.4 17.85,143.65 17.85,143.17 UM1.H7
HDMI_TX_P0: length 18.4
  TOP w0.102: UM1.H4 20.39,143.03 20.39,143.2 20.47,143.28 20.84,143.28 20.93,143.38 20.93,144.02 21.54,144.63 21.54,145.46 19.58,147.42 v5(18.72,147.42) 17.42,147.42 17.03,147.81 17.03,148.69 17.4,149.07 17.76,149.07 17.88,149.19 17.88,149.83 17.1,150.62 17.1,151.39 17.38,151.67 17.68,151.67 17.88,151.87 17.88,152.44 17.4,152.93 14.73,152.93 RV535.1
HDMI_TX_P1: length 17.9
  TOP w0.102: RV537.1 14.77,149.31 15.02,149.31 15.28,149.05 15.28,148.78 14.75,148.25 13.41,148.25 12.37,147.21 v5(12.37,145.94) 12.37,144.85 13.11,144.11 14.54,144.11 15.07,144.64 16.01,144.64 17.02,145.65 18.77,145.65 19.17,145.25 19.17,144.43 19.45,144.15 19.45,143.27 19.37,143.19 19.03,143.19 18.92,143.07 UM1.H6
HDMI_TX_P2: length 13.2
  TOP w0.102: v2(19.89,145.26) 19.98,145.35 19.98,145.87 19.35,146.51 16.36,146.51 15.62,147.24 15.62,147.83 16.19,148.4 16.19,150.93 15.91,151.21 15.64,151.21 RV530.1 ; UM1.H8 17.58,143.17 17.58,143.76 18.34,144.51 18.34,144.76 18.17,144.93 v2(17.96,144.93)
HOST_DEBUG_TX: length 4.3
  TOP w0.14: v1(306.04,92.96) 305.74,93.27 v2(305.37,93.27) 304.7,93.27 RE64.2 304.19,92.75 RE297.1 ; v2(297.12,85.66) UE3.G11
  BOTTOM w0.14: JDEG1.8 307.36,98.49 v2(307.36,97.61)
HOST_SD_WP#: length 15.3
  TOP w0.14: RH563.2 99.97,69.39 101.47,70.88 v2(101.56,70.88) ; v2(346.65,98.29) v1(346.65,97.66)
  BOTTOM w0.089: 99.75,69.73 99.71,69.73 99.14,70.29 98.25,70.29 97.83,69.87 97.83,69.85 97.24,69.26 95.35,69.26 94.16,70.45 94.16,70.89 93.83,71.22 93.83,71.9 93.51,72.22 UH2.BE8
  BOTTOM w0.14: v2(101.56,70.88) 101.56,70.44 100.85,69.73 99.75,69.73 ; QR1.2 v2(346.65,98.29)
HP_JD#: length 14.8
  TOP w0.14: v4(3.71,76.81) 3.71,77.26 4.16,77.71 JAUDIO.8 4.16,79.3 4.36,79.49 4.73,79.49 5.12,79.89 5.12,80.58 v2(3.28,82.43)
  BOTTOM w0.108: v2(3.99,98.85) 3.89,98.95 3.89,99.61 RA14.1
  BOTTOM w0.254: v2(2.15,112.82) RA82.2 DA3.1 1.29,112.91 2.94,114.56 JHP1.6
HP_LINE1_JD: length 7.2
  BOTTOM w0.108: UA1.9 5.8,100.94 RA14.2 RA13.2
  BOTTOM w0.14: RA13.2 5.42,99.16 5.09,98.82 v1(4.55,98.82) 4.36,98.63 4.36,98.09 3.7,97.44 3.7,97.04 3.62,96.96 3.62,96.74 3.22,96.34 CA23.1
HPD_IFPA: length 1.2
  TOP w0.14: v2(209.45,128.12) 209.47,128.09 T4973.1
  BOTTOM w0.14: UV18.N4 209.85,127.71 209.45,128.11 v2(209.45,128.12)
HPD_IFPB: length 3.4
  BOTTOM w0.14: T4974.1 209.03,124.38 209.39,124.74 209.39,125.46 209,125.85 UV18.P2
HPD_IFPC: length 2.7
  TOP w0.14: T4980.1 205.3,125.68 v2(206.1,126.49)
  BOTTOM w0.14: v2(206.1,126.49) 206.1,126.49 UV18.U3
HPD_IFPD: length 1.2
  TOP w0.14: v2(211.07,129.76) 211.07,129.8 211.47,130.19 T4975.1
  BOTTOM w0.14: UV18.M6 210.7,129.39 v2(211.07,129.76)
HPD_IFPE: length 1.2
  TOP w0.14: T4976.1 208.19,124.8 v2(208.51,124.8)
  BOTTOM w0.14: v2(208.51,124.8) 208.51,124.99 UV18.R1
HPD_IFPF: length 2.3
  TOP w0.14: v2(212.14,125.11) 211.63,125.62 T4979.1
  BOTTOM w0.14: UV18.L2 212.14,125.45 v2(212.14,125.11)
HPOUT_D_L_C: length 10.6
  TOP w0.127: v1(9.28,125.1) 9.28,124.33 8.56,123.61 JHP1.1
  BOTTOM w0.508: JHP1.1 9.14,124.14 10.45,124.14 11.48,123.11 11.48,120.9 11.27,120.69 DA2.1 11.19,119.85 CA42.2 11.19,118.95 LA6.2
HPOUT_D_R_C: length 5.3
  TOP w0.508: v2(9.22,113.68) 10,113.68 10.37,113.31 v1(10.73,113.31) 10.83,113.31 11.53,114.01 CA43.1 11.92,114.01 DA9.1 12.73,113.21 LA7.2
HPOUT_L: length 14.5
  TOP w0.508: v2(8.5,110.02) 8.02,109.54 RA30.2 ; v2(9.43,113.01) 9.44,113 RA75.2 9.54,112.02 10.69,112.02 RA28.2
  BOTTOM w0.203: 4.57,110.84 4.57,110.53 4.78,110.33 4.78,109.7 5,109.48 UA1.32
  BOTTOM w0.508: 4.57,110.84 4.57,111.24 6.34,113.01 v1(8.8,113.01) v2(9.43,113.01) 10.01,113.59 11.13,113.59 11.65,114.11 RA52.1
HPOUT_L_R1: length 2.4
  BOTTOM w0.508: RA52.2 v1(11.65,117) 12.13,117.48 LA6.1
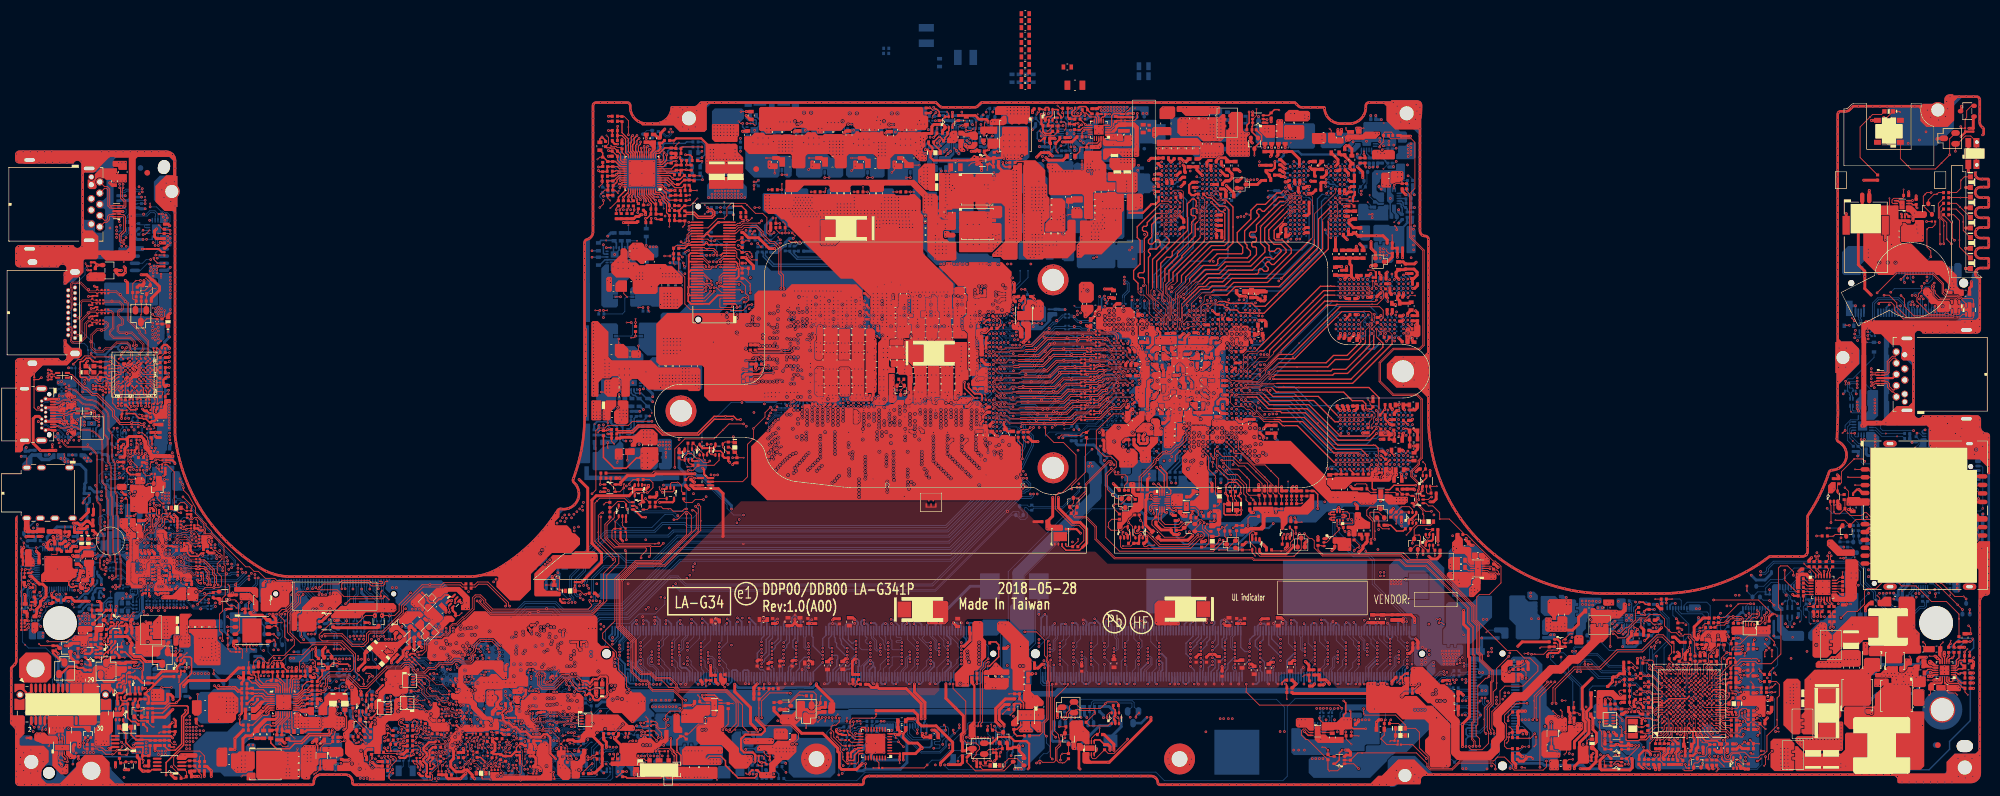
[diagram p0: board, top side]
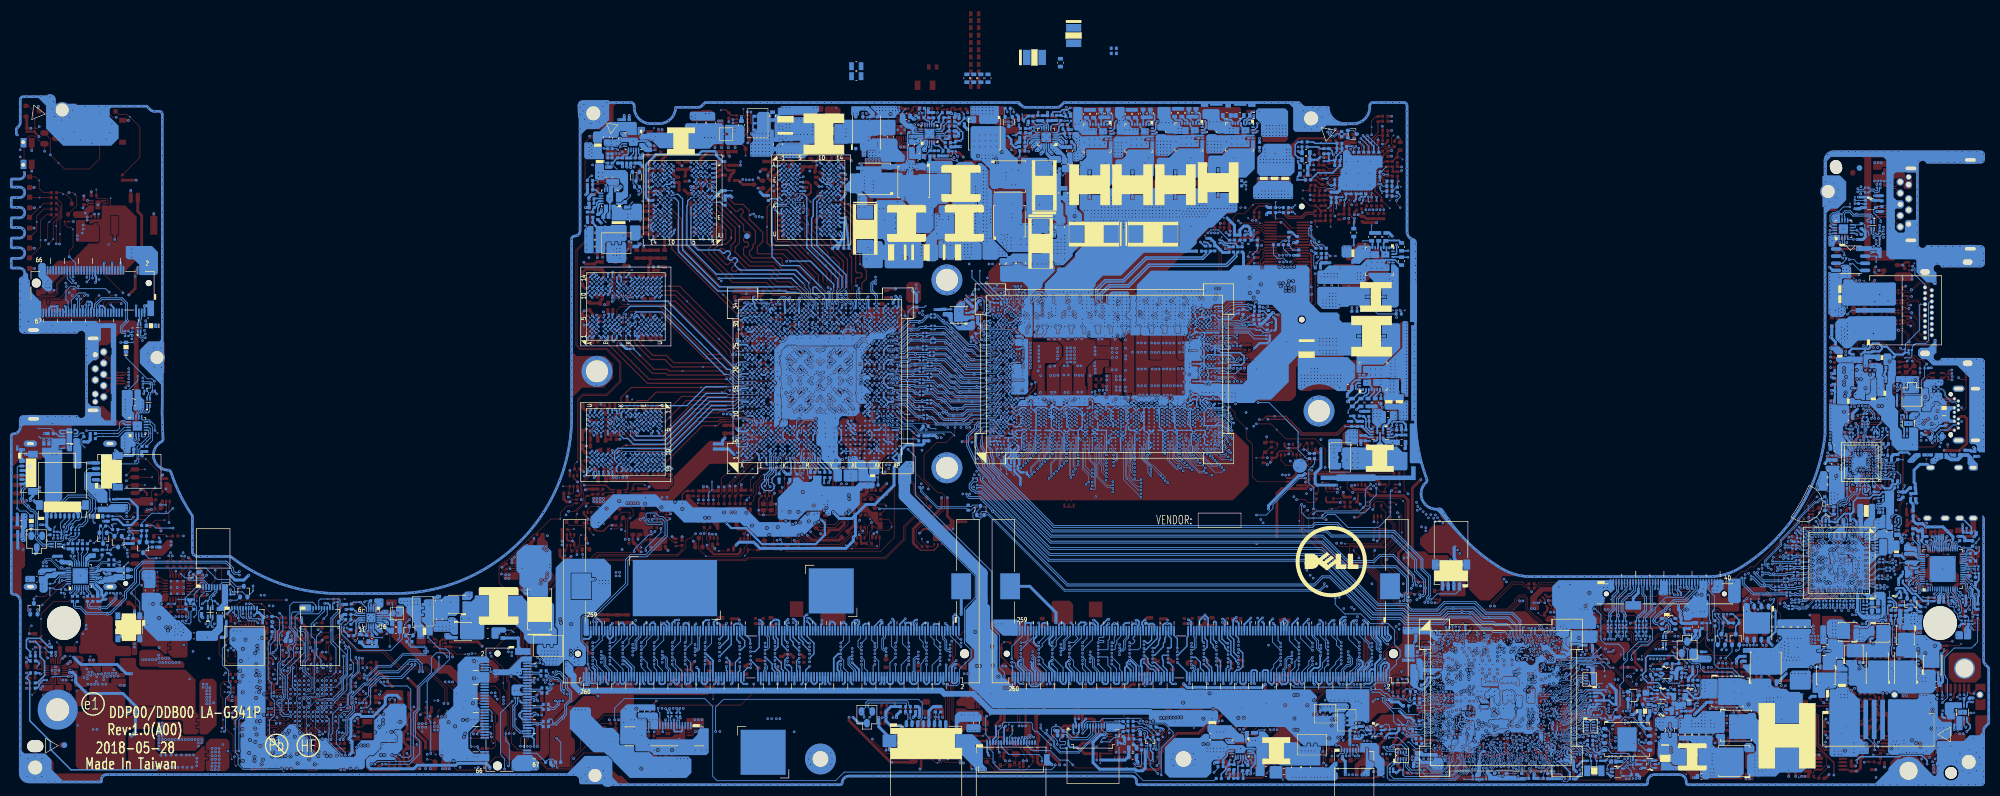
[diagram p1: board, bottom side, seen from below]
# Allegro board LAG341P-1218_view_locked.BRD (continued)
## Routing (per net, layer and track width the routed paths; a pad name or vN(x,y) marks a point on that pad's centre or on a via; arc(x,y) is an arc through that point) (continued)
HPOUT_R: length 5.7
  TOP w0.508: v2(9.86,109.48) 9.79,109.54 RA29.2 8.8,109.15 RA27.2 RA31.2 ; RA51.1 11.92,115.65 v2(10.59,114.32)
  BOTTOM w0.203: v2(5.3,109.92) 5.4,109.82 UA1.33
HPOUT_R_R2: length 2.1
  TOP w0.127: v1(12.79,117.14) 12.83,117.09 RA51.2
  TOP w0.508: LA7.1 12.83,115.21 RA51.2
HW_ACAVIN_NB: length 30.1
  TOP w0.14: DI14.1 305.51,80.96 305.21,80.66 v2(304.3,80.66) ; v2(26.7,70.33) 28.41,68.63 PR208.2 29.05,68.29 PC207.1 29.39,68.63 29.39,69.44 29,69.82 PU200.1 27.94,69.82 27.1,70.67 27.1,72 28.22,73.12 31.72,73.12 32.61,72.23 PR207.2 ; v2(59.23,75.02) 59,75.24 PR1939.1
  BOTTOM w0.14: v2(50.02,88.15) 50.02,86.84 50.85,86.01 PR285.1 PR284.1 ; PR214.1 14.78,96.65 14.97,96.46 14.97,95.54 15.31,95.21 15.31,91.85 15.49,91.67 15.49,90.32 v2(15.19,90.01)
  vias: v2(121.75,76.93)
HW_ACAVIN_NB_P: length 3.8
  TOP w0.14: RE142.1 303.81,81.86 DI14.2 303.01,81.55 302.68,81.22 301.56,81.22 UE3.N6
I2C0_IRQ_TS_R: length 9.9
  BOTTOM w0.14: JTS1.4 341.31,115.6 340.69,116.22 338.28,116.22 337.54,115.49 337.54,114.58 337.93,114.19 338.45,114.19 v1(339.09,113.55) 339.43,113.55 339.84,113.14 339.84,112.5 RR41.2
I2C0_SCK_DSP: length 8.2
  TOP w0.14: v2(282.4,76.54) 282.65,76.28 RE136.2 282.65,74.88 QE18.4 ; JAUDIO.5 v2(3.36,83.15)
  BOTTOM w0.14: UA1.12 4.6,101.6 4.04,101.04 4.04,100.7 3.24,99.9 3.24,99.29 3.07,99.13 3.07,97.95 v2(3.34,97.69)
  vias: v2(10.72,88.58) v2(57.73,84.57)
I2C0_SCK_TS: length 6.9
  BOTTOM w0.089: v3(86.69,69.61) 86.66,69.61 86.22,70.06 86.22,70.18 86.09,70.31 86.09,70.53 86.09,70.54 86.09,71.06 86.19,71.17 86.19,71.5 86.44,71.76 86.44,72.12 86.6,72.28 86.6,73.1 86.62,73.12 UH2.BC22
  BOTTOM w0.14: RC184.2 339.56,110.36 339.56,110.64 v2(339.69,110.76) 339.69,110.98 339.39,111.27 338.84,111.27 338.63,111.48 RR45.1
  vias: v2(306.76,72.03)
I2C0_SCK_TS_R: length 15.2
  BOTTOM w0.14: RR45.2 338.58,112.5 338.58,112.81 337.95,113.44 v1(337.73,113.44) 337.48,113.44 336.8,114.12 336.8,115.19 335.97,116.01 335.97,117.8 336.46,118.29 339.75,118.29 342.32,115.73 342.32,115.63 342.11,115.42 JTS1.3
I2C0_SDA_DSP: length 8.5
  TOP w0.14: v2(287.19,74.1) 287.19,73.86 286.8,73.47 RE137.2 285.86,73.41 QE18.1 ; JAUDIO.3 v2(2.56,83.15)
  BOTTOM w0.14: v2(3.54,98.25) 3.47,98.33 3.47,98.96 3.63,99.13 3.63,99.74 v5(3.99,100.1) 4.43,100.54 4.43,100.87 4.99,101.44 4.99,101.96 UA1.11
  vias: v2(10.73,89.19) v2(57.12,84.6)
I2C0_SDA_TS: length 4.3
  BOTTOM w0.089: v3(85.74,70.39) 85.75,70.39 85.74,70.4 85.74,71.04 85.96,71.26 85.96,71.63 86.21,71.88 UH2.BF23
  BOTTOM w0.14: RR42.1 338,111.52 v1(338.56,110.97) 338.76,110.76 v2(339.1,110.76) 339.17,110.7 339.17,110.1 RC183.2
  vias: v2(306.76,71.39)
I2C0_SDA_TS_R: length 16.4
  BOTTOM w0.14: JTS1.2 342.91,115.42 342.71,115.63 342.71,115.89 339.91,118.69 336.3,118.69 335.58,117.97 v1(335.58,117.23) 335.58,115.85 336.4,115.02 336.4,113.96 337.31,113.05 337.79,113.05 338,112.84 RR42.2
I2C1_SCK_TP: length 4.8
  TOP w0.14: v2(106.08,72.6) 105.9,72.42 105.9,71.92 RH119.2 ; v2(195.05,79.08) 195.28,78.85 QE2.3
  BOTTOM w0.089: UH2.BE21 86.9,72.28 86.65,72.03 86.65,71.67 86.41,71.43 86.41,71.05 86.35,70.98 86.35,70.38 86.5,70.22 86.65,70.22 v2(86.69,70.19)
I2C1_SCK_TP_C: length 16.5
  TOP w0.14: QE2.4 195.28,81.13 RE9.1 195.18,81.6 194.9,81.88 193.16,81.88 v4(192.86,81.57) 192,80.71 188.44,80.71 DE5.3 187.25,81.88 186.49,81.12 186.49,80.46 185.9,79.87 185.9,79.29 185.78,79.16 185.6,79.16 v2(185.59,79.17)
  BOTTOM w0.14: CE79.1 185.52,80.01 185.52,79.24 v2(185.59,79.17) 185.59,78.7 185.76,78.53 JTP.6
I2C1_SDA_TP: length 4.7
  TOP w0.14: RH120.2 105.5,72.02 105.5,72.45 v2(105.37,72.59) ; QE2.6 193.55,79.92 193.16,79.52 v2(193.16,79.07)
  BOTTOM w0.089: UH2.BF21 86.88,71.43 86.95,71.37 86.95,71.11 87.06,70.99 87.06,70.22 87.2,70.08 v2(87.61,70.08)
I2C1_SDA_TP_C: length 17.5
  TOP w0.14: QE2.1 193.73,78.02 193.31,77.6 190.07,77.6 RE7.1 v4(191,79.82) 191,80.19 190.87,80.32 188.28,80.32 188.08,80.52 187.63,80.52 187.27,80.17 DE5.2 186.54,79.95 186.3,79.71 186.3,79.13 185.94,78.77 185.94,78.76 185.87,78.69 185.44,78.69 185.42,78.71 185.42,78.71 185.17,78.96 185.17,79 v2(185.01,79.15)
  BOTTOM w0.14: CE80.1 185,79.76 185,79.16 v2(185.01,79.15) 185.01,78.8 184.76,78.56 JTP.7
I2C2_IRQ_TS: length 3.6
  TOP w0.14: v1(61.33,86.95) 62.03,86.95 62.49,86.49 v2(62.49,86.42)
  BOTTOM w0.089: v2(83.6,77.71) 83.41,77.53 UH2.AP29
  BOTTOM w0.14: v2(340.27,110.98) 340.27,111.49 RR41.1 339.71,111.55 RH5891.1
I2C_EN8723: length 3.3
  TOP w0.14: v1(317.13,106.49) 317.69,105.94 RI25.1 318.06,105.81 319.24,104.63 UI3.24
I2CB_SCL: length 16.3
  TOP w0.14: RV570.1 198.86,119.79 198.86,121.92 201.46,124.51 201.46,124.85 203,126.38 v5(203.71,126.38) 204.34,126.38 205.52,127.56 205.85,127.56 206.79,128.5 206.79,128.94 207.37,129.51 207.37,130.13 v2(207.78,130.54)
  BOTTOM w0.102: UV18.R7 208.13,130.19 v2(207.78,130.54)
I2CB_SDA: length 15.3
  TOP w0.14: RV571.1 199.26,119.79 199.26,121.75 201.85,124.35 201.85,124.68 v5(202.15,124.98) 203.16,125.99 204.51,125.99 205.69,127.17 206.02,127.17 207.19,128.34 207.19,128.77 207.76,129.34 207.76,129.72 v2(207.79,129.75)
  BOTTOM w0.102: UV18.R6 207.79,129.75 v2(207.79,129.75)
I2S_BCLK: length 2.7
  TOP w0.14: JAUDIO.9 4.96,83.24 5,83.21 v2(5,83.19)
  BOTTOM w0.108: UA1.56 10.15,102.92 10.26,102.81 10.26,101.87 v2(10.11,101.72)
I2S_IN: length 2.4
  TOP w0.14: JAUDIO.15 7.36,83.1 v2(7.37,83.1)
  BOTTOM w0.108: UA1.5 7.4,101.53 7.86,101.07 v2(7.92,101.07)
I2S_LRCK: length 2.8
  TOP w0.14: JAUDIO.13 6.56,83.13 v2(6.46,83.02)
  BOTTOM w0.14: v2(9.46,101.75) 9.31,101.59 9.13,101.59 9,101.72 UA1.1 ; v2(6.46,83.02) v1(6.46,83.6)
I2S_MCLK: length 4.9
  TOP w0.14: JAUDIO.11 5.76,82.98 6.34,82.4 v2(6.49,82.4)
  BOTTOM w0.108: v2(10.53,101.3) 10.62,101.4 10.62,103.05 10.36,103.32 UA1.55
I2S_OUT: length 3.8
  TOP w0.14: JAUDIO.17 8.16,83.23 v2(7.38,82.44)
  BOTTOM w0.108: UA1.3 8.2,102.47 8.56,102.82 v2(9.15,102.82)
I2S_RST_AUDIO#: length 6.7
  BOTTOM w0.14: v2(3.22,97.11) 3.2,97.1 RA93.1 1.96,97.1 1.8,96.94 RA17.2 CA37.1 ; RP15.5 101.84,73.42 102.67,74.25 104.29,74.25 v2(104.7,73.85)
  vias: v2(60.82,81.34)
I2S_RST_AUDIO#_R: length 6.1
  BOTTOM w0.14: RA93.2 2.34,98.15 v1(1.46,99.03) 1.43,99.06 1.43,100.14 1.76,100.47 1.76,101.35 2.28,101.87 2.28,102.73 2.47,102.92 UA1.15
I2S_SDIN0_AUDIO_R: length 7.8
  BOTTOM w0.14: UA1.16 2.49,103.32 1.99,102.82 1.99,102.06 1.49,101.57 1.49,100.58 1.11,100.2 1.11,97.93 1.21,97.83 v1(1.21,97.76) 1.21,97.68 0.86,97.34 RA6.2
I_ADP: length 2
  TOP w0.14: v2(44.93,88.71) 44.93,88.35 PR1933.2 ; UE3.B11 292.7,85.26 v2(292.31,85.66) ; v1(142.96,78.38) 143.08,78.5 v2(143.08,79.08)
I_BATT: length 17
  TOP w0.14: v2(57.42,91.27) 56.66,92.04 51.81,92.04 50.09,90.32 47.45,90.32 46.35,89.22 45,89.22 44.95,89.17 44.75,89.17 44.51,88.93 44.51,88.75 PR1932.2 ; RE55.2 306.89,74.44 v2(306.6,74.74) 306.55,74.74 v1(306.15,74.34)
  vias: v2(109.37,74.92)
I_BATT_R: length 3.3
  TOP w0.14: RE55.1 308.15,74.49 v2(307.57,75.07) ; RE55.1 C3320.1 ; RE55.1 v1(309.16,74.44) ; v2(298.72,79.27) UE3.J4
  vias: v2(306.32,78.39)
I_SYS_R: length 7
  TOP w0.14: v2(306.12,79.9) 306.12,79.22 306.76,78.57 306.76,78.29 RE126.1 307.73,78.28 309.01,78.28 C3321.1 310.25,77.04 v1(310.36,77.04) ; v2(298.72,80.06) UE3.J5
ILIM_1PH: length 5.4
  TOP w0.203: v2(112.83,171.14) 112.71,171.14 111.61,172.24 PU1100.49
  BOTTOM w0.14: v2(112.83,171.14) v1(112.83,170.11)
  BOTTOM w0.254: PR1119.2 PC1107.2 112.55,171.42 v2(112.83,171.14)
ILIM_2PH: length 2.3
  TOP w0.203: PU1100.32 106.25,176.31 v1(106.19,176.38) 105.68,176.38 105.59,176.28 PR1143.1
ILIM_4PH: length 2.8
  TOP w0.203: PU1100.7 v1(115.14,175.91) 115.93,175.91 PR1142.2
ILIM_HI1: length 6.5
  BOTTOM w0.14: RI12.1 334.68,129.11 v1(333.72,129.11) 330.97,129.11 329.88,130.21 UI2.16
ILIM_HI3: length 3.1
  TOP w0.14: v2(26.48,165.16) 26.43,165.21 RI7.1 v1(24.32,165.21)
  BOTTOM w0.14: UI1.16 25.95,165.26 26.05,165.16 v2(26.48,165.16)
ILIM_LO1: length 6.4
  BOTTOM w0.14: RI11.1 v1(331.71,129.62) 331,129.62 329.92,130.71 UI2.15
ILIM_LO3: length 3.3
  TOP w0.14: v2(26.47,165.76) 26.26,165.97 RI6.1 25.17,165.97 v1(24.41,166.73)
  BOTTOM w0.14: UI1.15 v2(26.47,165.76)
ILIM_SEL_L: length 8.3
  TOP w0.14: v2(59.92,89.4) v1(59.92,90.07)
  BOTTOM w0.14: RI31.2 328.35,111.7 328.8,112.16 v2(329.18,112.16) 329.01,112.34 RI33.1 326.82,111.47 RI34.2 326.9,110.63 DI12.3 ; v2(22.28,164.18) 23.18,164.18 23.3,164.31 UI1.4
ILIM_SEL_R: length 7.4
  TOP w0.14: v2(326.18,129.67) v1(325.53,129.67)
  BOTTOM w0.14: UI2.4 326.83,129.13 326.72,129.02 326.36,129.02 326.18,129.2 v2(326.18,129.67) ; RI32.1 325.93,111.45 RI34.1 325.98,110.38 DI12.2 325.9,110.33 RI35.2 RI30.2 323.56,110.88 v2(323.75,111.07)
ILMT_1.8VSP: length 2.1
  BOTTOM w0.254: PU1600.13 246.26,171.44 PR1606.2 PR1607.1
ILMT_1V: length 5.1
  TOP w0.14: v1(132.12,71.7) 132.12,72.04 131.88,72.28 PR506.2
  TOP w0.254: PR506.2 131.15,71.37 131.42,71.09 v2(131.72,71.09) 132.26,71.09 PR508.1
  BOTTOM w0.14: v2(131.72,71.09) 131.31,71.51 PU500.13
ILMT_1VSP: length 2.4
  BOTTOM w0.203: PU900.13 239.32,179.47 239.83,178.96 239.83,178.71 ; 239.83,178.66 239.83,178.71 ; 239.83,178.71 PR910.1
  BOTTOM w0.508: PR909.2 239.83,178.66
IMON_1PH: length 4.5
  TOP w0.203: PU1100.46 110.41,171.98 111.09,171.3 v2(111.09,170.97)
  BOTTOM w0.254: PR1112.2 PC1106.2 110.77,171.29 v2(111.09,170.97)
IMVP_VR_ON: length 37.1
  TOP w0.14: v2(165.76,85.06) 165.76,84.24 168.02,81.98 168.02,76.24 167.64,75.86 167.64,75.12 168.19,74.57 169.85,74.57 170.48,73.93 170.48,73.5 169.88,72.89 169.88,72.45 169.36,71.93 v2(169.36,71.4) ; UE3.N7 301.92,82.06 v2(302.33,81.65) ; v2(105.28,107.21) 102.03,110.45 102.03,117.23 v1(102.41,117.61) 102.92,118.11 107.31,118.11 108.02,117.4 UZ21.1
  vias: v2(118.92,104.41) v2(302.77,75.05)
IMVP_VR_PG: length 50.8
  TOP w0.127: PR1117.2 110.67,171.34 110.01,172 PU1100.45
  TOP w0.14: v2(81.67,99.86) 81.67,99.59 83.57,97.69 101.6,97.69 103.57,99.65 103.57,104.73 105.71,106.88 105.71,107.38 102.64,110.45 v1(102.64,112.03) 102.64,115.05 103.13,115.53 v2(103.4,115.53) ; v2(111.56,170.33) 111.51,170.27 PR1117.2
  BOTTOM w0.14: UH14.1 58.03,70.13 58.34,70.44 58.34,71.05 58.82,71.52 58.82,71.88 60.12,73.18 v2(60.44,73.18)
  vias: v2(57.2,89.53)
INTRUDER#: length 5.5
  TOP w0.089: v2(76.02,75.13) 76.02,74.77 75.72,74.47 74.65,74.47 RH531.1 73.83,75.29 73.01,75.29 v1(72.91,75.19)
  BOTTOM w0.089: v2(76.02,75.13) 75.96,75.07 75.96,74.88 76.2,74.64 76.2,74.25 75.93,73.98 UH2.BB44
INV_PWM: length 7.2
  BOTTOM w0.254: v2(52.95,100.94) 52.95,101.3 53.49,101.85 JEDP1.25 ; v2(44.15,97.48) 43.69,97.48 v1(43.41,97.2) 42.65,96.44 RV109.1 43.23,95.32 DV2.1
IRQ_SERIRQ: length 2.2
  TOP w0.089: RH5882.1 80.89,75.71 v3(80.61,75.43) 80.43,75.43 v1(80.11,75.11)
  BOTTOM w0.089: v3(80.61,75.43) 80.32,75.14 UH2.AW35
IST_TRIG_T: length 1.5
  TOP w0.089: T40.1 173.73,127.36 v2(173.92,127.55)
  BOTTOM w0.076: v2(173.92,127.55) 173.37,128.1 UH1.E3
JTAG_CLK: length 6.7
  TOP w0.14: RP20.3 307.27,96.1 308.03,96.87 v2(308.71,96.87) 308.79,96.87 309.26,97.34 309.26,97.74 v4(308.84,98.16) ; v2(293.12,83.26) UE3.C8
  BOTTOM w0.14: v2(308.71,96.87) 308.97,96.87 309.28,97.19 JDEG1.4
JTAG_RST#: length 8.3
  TOP w0.14: v1(296.61,93.49) 296.61,93.25 296.93,92.93 RE59.2 296.77,92.32 v2(296.77,91.53) 296.96,91.34 296.96,90.33 RE61.1 CE44.1 297.23,89.15 297.23,88.47 296.78,88.02 296.78,86.92 UE3.G13
  BOTTOM w0.14: v2(300.18,93.67) 300.09,93.58 300.09,92.94 JTAG1.1
JTAG_TDI: length 5.7
  TOP w0.14: v4(310.55,97.8) 310.11,97.35 v2(310.11,97.25) 310.11,96.37 309.32,95.59 RP20.1 ; v2(294.72,84.06) UE3.E9
  BOTTOM w0.14: JDEG1.2 310.28,97.42 v2(310.11,97.25)
JTAG_TDO: length 4.9
  TOP w0.14: v2(295.52,80.86) UE3.F6 ; RP20.4 306.77,96.34 v4(307.45,97.02) 307.95,97.52 v2(308.82,97.52)
  BOTTOM w0.14: JDEG1.5 308.78,97.56 v2(308.82,97.52)
JTAG_TMS: length 5.1
  TOP w0.14: v2(309.64,96.79) 309.64,96.49 v4(309.42,96.27) 309.3,96.14 308.05,96.14 307.77,95.86 RP20.2 ; v2(293.92,80.06) UE3.C5
  BOTTOM w0.14: JDEG1.3 309.78,98.22 309.64,98.08 v2(309.64,96.79)
KB_DET#: length 15
  TOP w0.14: v2(148.67,78.43) v4(149.25,78.43) ; RH557.1 64.69,72.67 66.84,72.67 v2(66.88,72.62)
  BOTTOM w0.089: v2(89.58,74.81) 89.58,74.81 UH2.AW15
  BOTTOM w0.14: v2(148.67,78.43) 149.17,78.93 155.82,78.93 156.39,78.35 158.66,78.35 159.06,77.95 JKB.5
LAN_WAKE#: length 5.4
  TOP w0.076: v2(300.63,76.73) 300.44,76.93 300.44,78.35 UE3.L3
  TOP w0.089: RH545.1 74.79,70.45 v2(74.94,70.6) 74.94,70.66 v1(75.5,71.23)
  BOTTOM w0.089: UH2.BG44 v2(74.94,70.6)
  vias: v2(277.86,74.3)
LCD_BL_PWM: length 9.8
  TOP w0.14: v2(194.54,122.83) 194.54,122.39 194.66,122.27 196.41,122.27 196.77,121.91 v1(196.77,120.93) 196.77,120.92 196.24,120.39 RV1841.1 RV1834.1
  BOTTOM w0.14: UV18.N8 209.84,130.99 208.8,132.03 207.5,132.03 v2(206.93,131.46)
LCD_BLEN: length 2.1
  TOP w0.14: v2(210.28,127.29) 210.65,126.91 v1(210.65,126.84) ; v2(209.98,115.66) 209.98,115.27 RV1838.1
  BOTTOM w0.14: UV18.M4 210.7,127.68 210.31,127.29 v2(210.28,127.29)
LCD_DBC: length 38.2
  TOP w0.14: v1(65.39,100.08) 64.83,100.65 RV1843.1 64.54,100.45 64.3,100.22 58.55,100.22 v3(57.66,99.33)
  BOTTOM w0.089: UH2.AP48 73.44,77.67 73.3,77.81 73,77.81 72.79,78.02 72.36,78.02 71.34,79.04 71.04,79.04
  BOTTOM w0.14: v2(58.47,93.5) 58.47,92.95 58.88,92.55 60.53,92.55 62.51,90.57 62.51,89.3 63.2,88.61 63.2,85.5 63.8,84.89 63.8,81.22 RH527.1 64.92,80.1 64.92,79.83 65.58,79.16 RH528.1 66.28,79.84 66.28,80.64 66.71,81.07 67.63,81.07 68.09,80.61 68.73,80.61 69.08,80.25 69.08,79.68 69.2,79.56 70.4,79.56 70.91,79.04 71.04,79.04
LCD_DBC_R: length 14.4
  TOP w0.14: v1(64.2,101.68) 63.95,101.43 RV1843.2 57.36,100.65 56.19,101.81 52.77,101.81 v2(52.37,102.21)
  BOTTOM w0.14: JEDP1.27 52.49,102.33 v2(52.37,102.21)
LCD_TST: length 20
  TOP w0.14: UE3.M2 301.1,77.68 301.83,77.68 302.59,76.92 303.39,76.92 303.96,76.35 305.59,76.35 305.8,76.56 305.8,76.84 v1(306.09,77.13) v2(306.64,77.13) 306.79,76.98 RE32.2
  BOTTOM w0.14: v3(42.61,86.51) 42.62,86.52 42.62,86.68 43.79,87.85 46.3,87.85 47.04,88.59 47.04,92.29 46.91,92.42 RV110.1
  vias: v2(63.61,72.25) v2(111.25,74.17)
LCD_VCC_TEST_EN: length 28.2
  TOP w0.14: v2(290.58,91.86) v1(290.58,91.28) ; DV7.2 66.41,97.23 67.21,98.04 67.21,99.24 v2(69.25,101.28) ; UE3.E1 295.18,77.2 v2(295.18,76.56)
  BOTTOM w0.076: v2(295.18,76.56) 295.18,76.59 295.92,77.33 295.92,80.22 295.68,80.46 295.27,80.46 295.12,80.61 295.12,81.04 294.89,81.27 294.47,81.27 294.28,81.46 294.28,81.84 293.94,82.19
  BOTTOM w0.14: 293.94,82.19 292.61,82.19 290.91,83.9 290.91,85.96 290.17,86.69 290.17,91.17 290.58,91.57 v2(290.58,91.86)
  vias: v2(113.77,100.5) v2(250.41,95.7)
LCD_VDD: length 4.1
  TOP w0.14: v2(211.95,124.53) v1(211.95,123.72)
  BOTTOM w0.14: UV18.M5 210.64,128.49 v2(210.28,128.13) ; RV1837.1 213.41,122.83 212.56,123.68 212.56,123.92 v2(211.95,124.53)
LDO1_CAP: length 5
  BOTTOM w0.203: CA30.1 11.73,111.73 v1(11.73,110.76) 11.72,110.76 10.74,109.79 10.74,108.1 10.36,107.72 UA1.44
LDO2_CAP: length 4.8
  TOP w0.14: CA27.1 0.5,104.41 0.58,104.5 CA26.1 0.58,105.31 v2(0.7,105.43) 1.5,105.43 v1(1.7,105.63)
  BOTTOM w0.14: UA1.22 2.43,105.72 2.38,105.67 2.37,105.67 2.36,105.66 0.93,105.66 v2(0.7,105.43)
LDO3_CAP: length 4.8
  TOP w0.14: v2(1.26,103.4) 1.38,103.4 1.98,102.8 CA130.1 2.3,102.8 2.59,102.51 2.59,101.76 CA77.1
  BOTTOM w0.14: v2(1.26,103.4) 1.42,103.4 v1(1.7,103.68) 2.14,104.12 UA1.18
LDO_3V: length 7.6
  TOP w0.14: v2(129.56,69.01) 129.06,69.01 v1(128.91,69.17)
  TOP w0.254: PC505.1 129.98,69.72 129.56,69.3 v2(129.56,69.01)
  BOTTOM w0.254: 129.09,72.83 129.23,72.69 PU500.16 ; 129.09,72.83 129.09,72.92 129.31,73.14 PU500.17 ; 129.09,72.83 128.73,72.47 128.73,70.86 129.43,70.15 129.43,69.13 v2(129.56,69.01)
LDO_IN: length 0.9
  TOP w0.508: v2(71.06,93.26) 70.67,93.65 PR276.1
  vias: v1(63.68,90.3) v2(66.39,91.32)
LG1_ISL88738: length 2.5
  TOP w0.14: v2(45.95,74.41) 46.02,74.41 46.47,73.97 v1(47.46,73.97)
  TOP w0.203: v2(44.78,79.39) 45.15,79.39 45.28,79.52 PU1900.9
LG2_ISL88738: length 5.5
  TOP w0.203: PU1900.7 44.21,80.8 43.58,80.17 v3(43.58,79.99)
  BOTTOM w0.508: PQ1904.4 48.34,81.81 48.4,81.74 48.41,81.74 v1(48.79,81.36) v2(50.58,79.57)
LG_3V: length 0.7
  TOP w0.14: v2(336.12,89.33) 336.12,89.78 v1(335.94,89.96)
  vias: v2(335.43,89.33) v2(339.52,89.05) v2(339.97,88.66)
LG_5V: length 2.9
  BOTTOM w0.14: v2(339.86,86.42) 342.53,86.42 v1(342.68,86.26)
  vias: v2(329.95,84.82) v2(330.59,84.82) v2(339.27,86.42)
LID_CL_SIO#: length 37.3
  TOP w0.14: v2(315.26,104.41) 315.26,105.05 314.25,106.06 312.98,106.06 312.6,105.68 312.6,98.7 313.04,98.25 313.04,90.38 311.33,88.66 308.91,88.66 308.53,89.05 305.99,89.05 305.36,88.41 304.6,88.41 304.14,87.95 RE41.2 RE45.2 CE31.1 303.95,86.19 303.7,85.93 v2(303.16,85.93) 302.76,85.93 302.41,85.59 301.85,85.59 UE3.N11
  BOTTOM w0.14: v2(315.26,104.41) 315.77,103.9 316.92,103.9 317.59,104.58 R5841.1
  vias: v2(310.71,82.83)
LID_FPR#: length 7.1
  BOTTOM w0.14: R5841.2 317.73,103.94 D323.1 ; D323.1 318.44,103.65 318.31,103.52 315.71,103.52 314.86,102.68 JFP.3 ; D323.1 319.11,103.94 v1(319.84,104.67)
LID_SW_IN#: length 7.4
  TOP w0.14: v4(306.04,86.09) 305.86,86.27 v2(305.86,86.62) 305.71,86.62 305.32,87.01 RE45.1 ; UE2.3 346.95,187.92 346.11,187.08 346.11,185.83 345.82,185.55 CE16.1 345.35,183.93 v2(345.05,184.23)
LINE1-VREFO: length 6.6
  TOP w0.127: v1(13.08,109.53) 12.9,109.35 DA7.2
  TOP w0.508: v2(11.73,110.06) 11.8,110.06 11.93,109.94 DA7.2 DA14.2 10.72,109.16 10.22,108.67 RA27.1
  BOTTOM w0.203: UA1.40 8.2,109.55 8.04,109.71 8.04,110.22 8.51,110.69 v2(8.55,110.69)
LINE1_L: length 3.9
  TOP w0.508: CA45.1 5.94,110.45 5.79,110.6 5.79,111.14 v2(5.64,111.3)
  BOTTOM w0.203: v2(5.64,111.3) 5.79,111.14 v1(5.79,110.79) 5.79,110.66 6.2,110.25 UA1.35
LINE1_L_C: length 2.8
  TOP w0.127: v1(5.38,108.1) 6.25,108.1 6.35,108.2 CA119.2
  TOP w0.508: RA31.1 6.77,109.05 CA119.2
LINE1_R: length 4.5
  TOP w0.508: v2(5.14,110.62) 4.69,110.16 4.69,109.75 v1(4.5,109.56) 4.5,109.43 4.88,109.05 CA119.1
  BOTTOM w0.203: UA1.34 5.8,110.22 5.4,110.62 v2(5.14,110.62)
LINE1_R_C: length 1.2
  TOP w0.508: RA30.1 7.7,110.46 7.25,110 CA45.2
LPC_PD#: length 2.8
  TOP w0.076: UE3.N3 302.06,78.86
  TOP w0.14: 302.06,78.86 302.36,78.86 302.65,78.58 v1(303.17,78.58) 304.16,78.58 RE286.1
LPS_PROTECT#: length 1.5
  TOP w0.254: PT202.1 22.42,77.17 PR260.2
LX1_ISL88738: length 5.4
  TOP w0.508: 39.42,72.97 39.42,75.33 39.93,75.84 40.88,75.84 PC1913.2
  vias: v1(37.93,69.87) v2(38.48,70.16) v2(38.5,69.54) v2(39.21,72.23) v2(39.18,71.51) v2(39.18,70.81) v2(39.17,70.18) v2(39.19,69.57) v2(39.8,71.52) v2(39.81,70.83) v2(39.79,70.2) v2(39.81,69.58) v2(39.84,72.25)
LX1_NVVDD:
  vias: v1(172.67,162.15) v2(164.18,179.78) v2(164.64,180.17) v2(168.28,166.82) v2(168.28,164.22) v2(168.28,163.24) v2(169.34,166.83) v2(169.34,164.23) v2(169.35,163.23) v2(170.41,166.82) v2(170.41,163.24) v2(170.42,164.22) v2(172.13,164.47) v2(172.13,163.89) v2(172.14,163.2) v2(172.14,162.62) v2(172.83,165.04) v2(172.85,164.47) v2(172.85,163.88) v2(172.92,163.2) v2(172.92,162.62) v2(173.38,164.83) v2(173.36,164.19) v2(173.51,163.01) v2(173.64,163.63) v2(173.93,165.04) v2(173.93,164.19)
LX1_NVVDDS: length 1.9
  TOP w0.14: v1(186.13,168.42) 186.32,168.61 PR1512.1
  vias: v2(187.55,169.63) v2(188.14,169.63) v2(188.44,181.7) v2(188.95,181.37)
LX2_ISL88738:
  vias: v1(35.06,78.75) v2(35.17,82.74) v2(35.77,82.71) v2(36.5,82.57) v2(36.5,81.93) v2(36.5,81.3) v2(36.5,80.66) v2(36.5,80.03) v2(37.13,82.57) v2(37.13,81.93) v2(37.13,81.3) v2(37.13,80.66) v2(37.13,80.03) v2(37.77,82.57) v2(37.77,81.93) v2(37.77,81.3) v2(37.77,80.66) v2(37.77,80.03) v2(38.34,81.68) v2(38.34,81.04) v2(38.34,80.41) v2(42.66,80.22)
LX2_NVVDD: length 0.5
  TOP w0.14: v2(173.02,175.41) v1(173.02,174.9)
  vias: v2(167.12,180.29) v2(167.62,179.95) v2(173.02,176.04) v2(174.78,182.76) v2(174.77,181.7) v2(174.78,180.63) v2(174.8,179.17) v2(175.43,179.17) v2(175.44,178.55) v2(175.76,182.76) v2(175.77,181.69) v2(175.77,180.63) v2(176.07,179.17) v2(176.07,178.55) v2(176.7,179.17) v2(176.71,178.55) v2(176.76,182.76) v2(176.75,181.7) v2(176.76,180.63) v2(177.34,179.17) v2(177.34,178.55) v2(177.74,182.76) v2(177.75,181.69) v2(177.75,180.63) v2(178.74,181.69) v2(178.74,180.63)
LX_1.8VSP: length 0.5
  TOP w0.14: v2(240.33,168.62) v1(239.79,168.62)
  vias: v2(240.33,168.04) v2(241.53,173.58) v2(241.93,173.12)
LX_1V:
  vias: v1(131.04,74.82) v2(128.69,75.01) v2(129.27,75.01) v2(133.04,75.01) v2(133.63,75.01)
LX_1VSP:
  vias: v1(235.38,182.47) v2(231.39,182.58) v2(231.39,181.95) v2(235.76,181.82) v2(236.4,182.01) v2(240.89,183.05) v2(241.48,183.05)
LX_3V:
  vias: v2(336.71,95.52) v2(336.72,94.87) v2(342.13,90.72) v2(342.13,90.12) v4(337.26,93.97)
LX_5V:
  vias: v2(334.78,76.99) v2(335.46,76.95) v2(344.41,84.66) v2(344.79,84.22) v4(338.23,77.69)
M2280_DEVSLP: length 5.6
  TOP w0.14: RD7.2 264.52,79.27 v1(264.52,79.13) v2(264.52,78.51)
  BOTTOM w0.089: UH2.AH35 80.22,80.09 v2(80.05,79.91)
  BOTTOM w0.14: v2(264.52,78.51) 264.52,80.07 264.94,80.49 JNGFF2.38
M2280_PCIE_SATA#: length 7.4
  TOP w0.089: v2(77.41,81.32) 77.39,81.34 RH508.1
  BOTTOM w0.089: UH2.AJ43 76.62,80.2 76.75,80.07 77.23,80.07 77.41,80.25 v2(77.41,81.32)
  BOTTOM w0.14: RD58.1 252.26,74.67 v2(253,75.4)
M_CLK_DDR0: length 13.3
  BOTTOM w0.076: UH1.AG1 156.8,127.1 156.87,127.18 157.01,127.18 157.1,127.09 157.1,126.75 156.98,126.64 156.98,124.53 156.7,124.24 156.7,122.02 154.99,120.31 154.22,120.31 v2(154.05,120.48)
  BOTTOM w0.14: JDIMM1.137 139.14,93.51 139.24,93.41 139.24,91.52 139.55,91.2 139.94,91.2 v2(140.07,91.08)
M_CLK_DDR1: length 6.8
  BOTTOM w0.089: UH1.AK2 153.87,127.16 153.87,126.74 153.16,126.03 153.16,124.97 153.38,124.75 153.66,124.75 v2(153.91,124.5)
  BOTTOM w0.14: JDIMM1.138 139.39,87.13 139.56,87.3 139.56,87.35 139.38,87.53 139.38,88.11 139.64,88.37 139.9,88.37 v2(140.07,88.54)
M_CLK_DDR2: length 4.7
  BOTTOM w0.076: v2(152.61,131.82) 152.93,132.14 UH1.AM9
  BOTTOM w0.14: v2(215.91,91.08) 215.76,91.23 215.47,91.23 215.16,91.54 215.16,93.45 215.45,93.74 JDIMM2.137
M_CLK_DDR3: length 3.2
  BOTTOM w0.076: v2(153.52,131.16) 153.2,130.84 UH1.AM7
  BOTTOM w0.14: JDIMM2.138 215.69,87.16 215.78,87.25 215.78,87.43 215.47,87.75 215.47,88.15 v2(215.91,88.59)
M_CLK_DDR#0: length 13.5
  BOTTOM w0.076: v2(154.05,119.84) 154.29,120.07 155.09,120.07 156.94,121.92 156.94,124.14 157.23,124.43 157.23,126.58 157.31,126.66 157.31,127.19 157.1,127.39 156.89,127.39 156.8,127.48 UH1.AG2
  BOTTOM w0.14: JDIMM1.139 139.64,93.51 139.54,93.41 139.54,91.64 139.67,91.51 139.86,91.51 v2(140.07,91.71)
M_CLK_DDR#1: length 6
  BOTTOM w0.089: v2(153.91,125.14) 153.77,125 153.49,125 153.41,125.08 153.41,125.92 154.02,126.54 154.16,126.54 154.34,126.36 154.49,126.36 154.61,126.47 154.61,126.87 154.54,126.93 154.28,126.93 UH1.AK1
  BOTTOM w0.14: v2(140.07,87.9) 139.9,88.06 139.76,88.06 139.64,87.94 139.64,87.64 139.8,87.48 139.8,87.35 139.89,87.26 JDIMM1.140
M_CLK_DDR#2: length 4.2
  BOTTOM w0.076: v2(152.61,132.46) 152.3,132.14 UH1.AN9
  BOTTOM w0.14: JDIMM2.139 215.95,93.81 215.46,93.32 215.46,91.67 215.6,91.53 215.73,91.53 v2(215.91,91.71)
M_CLK_DDR#3: length 2.3
  BOTTOM w0.076: UH1.AM8 153.2,131.49 v2(153.52,131.81)
  BOTTOM w0.14: v2(215.91,87.95) 215.91,87.74 216.1,87.55 216.1,87.29 216.19,87.21 JDIMM2.140
M_ODT0: length 11.2
  BOTTOM w0.076: UH1.AD3 159.08,128.23 159.03,128.18 159.03,126.6 159.3,126.33 159.3,123.55 v2(157.69,121.94)
  BOTTOM w0.221: JDIMM1.155 145.64,93.13 145.77,93 145.77,92.79 145.91,92.65 145.91,92.1 146.57,91.44 v2(146.94,91.44)
M_ODT1: length 14.2
  BOTTOM w0.076: v2(157.9,119.77) 157.82,119.69 157.25,119.69 157.1,119.84 157.1,124 158.06,124.96 158.06,125.75 158.24,125.93 158.24,126.6 158.13,126.71 158.13,128.63 158.38,128.88 UH1.AE4
  BOTTOM w0.221: v2(148.5,92.68) 148.33,92.68 147.94,92.29 147.76,92.29 147.14,92.91 JDIMM1.161
M_ODT2: length 6
  BOTTOM w0.076: v2(158.1,131.19) 157.75,130.84 UH1.AF7
  BOTTOM w0.221: JDIMM2.155 221.94,92.06 v2(224.02,89.98)
M_ODT3: length 2.4
  BOTTOM w0.076: UH1.AE8 v2(158.98,131.06)
  BOTTOM w0.221: v2(224.02,93.03) 223.44,93.61 JDIMM2.161
ME_EN: length 2.7
  TOP w0.14: SW4.2 113.46,71.8 113.59,71.93 113.59,72.79 113.51,72.87 RH454.1 113.54,73.09 RH487.1
ME_FWP: length 7
  TOP w0.14: UE3.G12 297.21,86.54 297.21,87.57 297.23,87.6 v2(297.23,87.71) ; v1(310.06,70.5) 310.32,70.76 v2(310.32,72.12) ; RH487.2 v2(115.05,72.23) 115.05,71.57 SW4.3 ; v2(298.36,91.35) 298.12,91.59 RE68.2 RE70.2
ME_SUS_PWR_ACK: length 28.4
  TOP w0.076: UE3.B13 292.72,87 292.61,87.11 292.61,87.34 292.43,87.52
  TOP w0.089: RH5873.1 97.92,72.08 v2(97.92,71.74) 97.88,71.74 97.28,71.14 RH506.1
  TOP w0.14: v2(288.13,89.7) 288.53,89.3 v1(289.53,89.3) 290.14,89.3 290.4,89.05 290.4,88.46 290.72,88.14 291.81,88.14 292.43,87.52
  BOTTOM w0.127: v2(288.13,89.7) 288.13,87.24 289.53,85.85 289.53,83.5 290.02,83.01 290.02,81.27 289.74,80.99 289.74,80.47 290.03,80.18 290.91,80.18 291.74,79.34 291.74,77.15 292.19,76.7 292.19,74.43 290.63,72.87 290.63,72.41 v2(290.58,72.36)
ME_SUS_PWR_ACK_R: length 3.2
  TOP w0.089: v1(96.25,72.1) 96.43,72.28 RH5873.2 97.13,71.89 97.26,71.76 v2(97.32,71.76)
  BOTTOM w0.089: v2(78.08,74.26) 78.23,74.11 78.65,74.11 79.02,73.74 UH2.BC37
MEC_XTAL1: length 6
  TOP w0.076: UE3.A1 290.75,77.26
  TOP w0.14: 290.75,77.26 290.65,77.26 289.68,76.29 288.51,76.29 CE42.1 287.36,76.53 YE1.1
MEC_XTAL2: length 3.2
  TOP w0.14: YE1.2 287.65,77.39 CE43.1 288.63,77.39 288.92,77.69 RE51.2
MEC_XTAL2_R: length 3.5
  TOP w0.076: UE3.A3 291.92,78.66 291.01,77.74 290.75,77.74
  TOP w0.14: 290.75,77.74 290.5,77.74 289.53,76.78 RE51.1
MEDIACARD_IRQ#: length 3.4
  TOP w0.089: RH546.1 85.52,75.18 v2(85.07,74.73)
  TOP w0.14: v2(340.54,101.11) v1(340.54,100.48)
  BOTTOM w0.089: v2(85.07,74.73) 85.07,74.68 84.43,74.04 UH2.BB26
  BOTTOM w0.14: v2(340.54,101.11) 340.72,101.29 RR10.1
  vias: v2(312.53,77.2)
MEM_SMBCLK: length 4.9
  BOTTOM w0.089: UH2.BE26 84.5,72.53 84.7,72.73 84.7,72.85 84.94,73.09 v2(84.94,73.63)
  BOTTOM w0.14: QH4.6 106.03,77.5 105.7,77.83 v1(105.26,77.83) 105.08,77.83 104.83,77.58 RH458.2 104.62,77.06 v2(103.86,77.06)
MEM_SMBDATA: length 5.5
  BOTTOM w0.089: UH2.BF26 84.48,72.26 84.87,72.65 84.87,72.78 85.3,73.21 85.3,73.95 v2(85.1,74.16)
  BOTTOM w0.14: v2(110.34,76.46) 109.97,76.83 v1(109.8,76.83) 109.63,76.83 109.07,76.27 RH459.2 108.79,75.96 108.55,76.2 QH4.3
MEM_VDD_CTL: length 42.4
  TOP w0.14: v2(193.92,123.4) 192.93,122.41 192.93,111.12 195.36,108.68 212.09,108.68 213.79,110.38 v2(213.79,110.64) ; v2(226.76,111.83) RV1086.2 ; v2(185.34,184.42) 185.27,184.35 PR717.1 RV1836.1 184.4,183.36 183.71,182.66 181.99,182.66 v1(181.18,183.47)
  vias: v2(194.41,137.24) v2(198.62,176.46)
MEM_VREF: length 8.7
  TOP w0.508: QV101.2 216.6,174.58 v2(217.13,175.11) ; QV102.2 240.89,161.82 v1(240.26,162.45) 240.13,162.58 v2(240.13,163.76)
  BOTTOM w0.254: UV18.L1 211.5,124.75 211.29,124.54 211.29,122.61 RV567.1
  BOTTOM w0.508: RV567.1 212.11,122.4 v2(212.62,122.91)
  vias: v2(231.89,117.47)
MIC1-VREFO_L: length 3.8
  BOTTOM w0.203: UA1.38 7.4,110.45 7.54,110.59 7.54,111.28 v2(7.68,111.42)
  BOTTOM w0.508: RA21.1 v2(9.08,125.81) RA20.1
MIC1-VREFO_R: length 5.3
  TOP w0.127: v1(7.75,113.1) RA19.1
  TOP w0.508: RA19.1 7.78,112.12 RA75.1 8.52,111.61 8.29,111.38 v2(8.29,111.27)
  BOTTOM w0.203: v2(8.29,111.27) 8.18,111.27 7.86,110.95 7.86,110.48 7.73,110.35 7.73,109.59 7.8,109.52 UA1.39
MONO_IN: length 2.4
  BOTTOM w0.14: UA1.23 2.48,106.12 2.28,105.91 2.27,105.91 2.26,105.9 1.82,105.9 1.71,106 CA16.2
MONO_IN_R: length 11.4
  TOP w0.14: v2(0.11,105.43) 0,105.31 v1(0,101.45) CA19.1 RA57.1 RA4.2 RA7.2
  BOTTOM w0.14: v2(0.11,105.43) 0.01,105.53 CA16.1
MSCLK: length 11.7
  TOP w0.14: RE288.2 301.91,95.95 RE299.2 302.89,95.98 303.96,97.05 v5(304.55,97.05) 306.03,97.05 306.33,96.75 306.33,96.11 v2(306.14,95.91) 305.55,95.91 RE63.2
  BOTTOM w0.14: v2(306.14,95.91) 306.5,96.27 307.77,96.27 308.23,96.73 308.23,98.52 JDEG1.6
MSCLK_R: length 17
  TOP w0.076: UE3.H10 297.52,84.44 v2(297.89,84.07)
  TOP w0.14: RE288.1 300.05,95.83 299.54,95.83 299.18,95.47 299.18,95.16 299.05,95.03 v2(298.63,95.03)
  BOTTOM w0.076: v2(297.89,84.07) 297.49,83.66 297.01,83.66 296.34,84.33 296.34,86.05 v1(297.12,86.82)
  BOTTOM w0.14: v1(297.12,86.82) 297.73,87.43 297.73,89.01 297.24,89.49 297.24,94.18 297.87,94.82 298.42,94.82 v2(298.63,95.03)
MSDATA: length 11.5
  TOP w0.14: RE287.2 301.3,95.12 RE27.1 301.7,95.52 302.99,95.52 v5(303.46,95.99) 304.12,96.65 305.81,96.65 v2(305.89,96.57) 305.7,96.38 304.87,96.38 304.6,96.11 RE65.2
  BOTTOM w0.14: v2(305.89,96.57) 305.91,96.57 306,96.67 307.61,96.67 307.84,96.89 307.84,98.52 JDEG1.7
MSDATA_R: length 14.4
  TOP w0.076: v2(297.15,84.08) 296.73,83.66 UE3.G9
  TOP w0.14: RE287.1 299.65,94.88 299.28,94.51 298.68,94.51 v2(298.59,94.41)
  BOTTOM w0.076: 297.68,86.82 297.39,86.54 297.34,86.54 297.27,86.46 297.22,86.46 296.67,85.91 296.67,84.35 296.94,84.08 v2(297.15,84.08)
  BOTTOM w0.14: v2(298.59,94.41) 298.58,94.42 298.04,94.42 297.64,94.02 297.64,89.66 298.15,89.14 298.15,87.3 297.68,86.82
NB_MUTE#: length 7.1
  TOP w0.14: v2(291.26,79.2) 291.72,79.66 UE3.A4 ; JAUDIO.4 2.56,79.29 2.26,79.6 1.72,79.6 v2(1.42,79.9)
  BOTTOM w0.14: v2(1.42,79.9) 0.82,79.9 v1(0.75,79.96) ; RA12.2 12.67,103.46 12.17,103.97 11.7,103.97 RA68.1 11.34,103.92 v2(11.04,104.22) 10.74,104.52 UA1.52
  vias: v2(56.24,79.8)
NRB_BIT: length 4.3
  TOP w0.089: v1(99.56,74.11) 99.16,73.72 RH524.2 98.48,73.12 v2(98.39,73.21)
  BOTTOM w0.089: v2(82.35,70.46) 82.35,70.7 82.14,70.91 82.14,71.38 82.65,71.88 UH2.BE30
NVVDD_EN: length 15.2
  TOP w0.203: U33.18 v1(203.34,121.14) 203.34,122.26 v2(201.98,123.61)
  TOP w0.254: DA56.2 163.46,179.99 162.32,181.13 RV1130.1 163.24,182.4 v2(163.31,182.4) 163.44,182.4 163.86,181.98 163.86,181.89 PC1015.1 164.27,181.9 164.27,182.22 164.78,182.73 CV919.1 164.78,183.23 165,183.45 QZ15.2
  BOTTOM w0.254: PR1004.1 163.19,182.4 v2(163.31,182.4) 163.38,182.4 163.44,182.35 PU1001.3
NVVDD_PGOOD: length 4.1
  BOTTOM w0.203: PR1017.1 PR1019.1 169.49,180.7 169.19,180.99 169.19,181.74 168.85,182.09 v1(168.69,182.09) 168.66,182.09 168.5,182.24 168.05,182.24 167.94,182.35 PU1001.13
NVVDD_PWM_VID: length 1
  BOTTOM w0.14: RV1095.2 161.49,185.17 PR1003.1
NVVDD_VID: length 2.4
  BOTTOM w0.254: PR1003.2 163.29,184.56 163.66,184.19 163.66,183.45 163.96,183.15 PU1001.5
NVVDDS_EN: length 9.3
  TOP w0.203: U33.17 204.35,118.79 204.5,118.94 204.5,119.52 203.84,120.18 203.84,122.55 v2(202.64,123.74)
  TOP w0.254: v2(221.64,185.47) 221.6,185.51 221.02,185.51 QZ14.2 ; v2(173.81,179.7) 173.61,179.89 RV1807.1
  BOTTOM w0.203: PU1501.3 186.66,180.69 v2(186.73,180.62)
  BOTTOM w0.254: v2(244.6,180.4) 244.51,180.31 PR902.1
NVVDDS_PGOOD: length 3.8
  BOTTOM w0.203: PU1501.13 186.66,185.11 186.8,185.26 187.14,185.26 187.68,185.79 PR1522.1 187.38,186.12 187.38,187.29 PR1518.1
NVVDDS_PSI: length 5
  BOTTOM w0.14: PR1502.1 186.59,179.93 187.44,179.08 v1(187.44,178.48)
  BOTTOM w0.203: PU1501.4 186.26,180.43 186.59,180.1 PR1502.1 PR1501.1 PR1500.2
NVVDDS_PWM_VID: length 2.7
  BOTTOM w0.14: RV1098.2 182.56,179.24 v1(182.84,178.96)
  BOTTOM w0.254: RV1098.2 PR1503.1 183.33,180.16 RV1835.1
NVVDDS_VID: length 2.6
  BOTTOM w0.203: PR1503.2 184.25,180.11 v2(184.96,180.82) 185.63,180.82 185.86,181.05 PU1501.5
OTGEN/CMIN: length 3.4
  TOP w0.203: PU1900.20 49.23,81.6 49.87,82.24 v1(49.97,82.24) 50.67,82.24 PR1912.2 51.64,82.47 PR1909.2
P_SYS: length 31.4
  TOP w0.14: PR1929.2 41.33,88.97 42.06,89.71 42.72,89.71 43.69,88.74 v2(43.87,88.74) 44.06,88.92 44.06,89.31 44.88,90.14 46.74,90.14 48.56,91.97 48.56,92.98 47.33,94.22 47.33,97.65 49.3,99.62 v2(49.3,100.94) ; v2(308.94,75.91) v1(309.31,76.28) 309.31,77.25 309.06,77.5 308.88,77.5 308.57,77.81 RE126.2
  TOP w0.203: v2(108.76,182.64) 108.51,182.39 108.51,181.37 108.38,181.25 108.38,179.87 108.81,179.44 PU1100.24
  BOTTOM w0.14: PR1157.1 106.73,180.61 v2(108.76,182.64)
  vias: v2(99.12,113.01)
PANEL_BKEN_EC: length 7.9
  TOP w0.14: v2(298.72,84.06) UE3.J9 ; v2(142.49,79.11) 142.49,79.09 v1(141.68,78.28)
  BOTTOM w0.14: v2(46.9,97.48) 46.9,97.14 46.17,96.41 46.17,94.82 46.42,94.57 46.42,93.45 46.05,93.08 46.05,92.4 DV1.2
  vias: v2(91.53,83.83)
PANEL_BKEN_PCH: length 6.2
  TOP w0.14: v2(61.9,86.38) 61.9,86.13 61.62,85.84 61.62,85.53 v1(61.58,85.49)
  BOTTOM w0.089: UH2.AU46 74.7,76.14 74.75,76.09 ; 74.75,76.09 73.57,76.09 73.39,76.26 73.08,76.26 72.93,76.4 72.93,76.61 72.65,76.88 72.34,76.88 71.94,77.29 v2(71.92,77.29) ; 74.75,76.09 UH2.AV46
  BOTTOM w0.14: v2(45.71,91.13) 45.12,91.71 DV1.3
PARSVD1: length 1.3
  TOP w0.089: v2(91.04,87.55) 91.36,87.23 T4951.1
  BOTTOM w0.089: v2(91.04,87.55) 91.04,87.28 UH2.R13
PARSVD2: length 1.5
  TOP w0.089: T4950.1 90.17,87.29 v2(90.46,87.58)
  BOTTOM w0.089: UH2.R15 89.93,87.05 v2(90.46,87.58)
PBAT_CHARGER_SMBCLK: length 56.9
  TOP w0.14: PD101.2 11.36,75.34 11.08,75.06 v2(11.08,74.56) 11.08,73.67 11.25,73.5 PR106.2 ; PR1917.1 52.64,83.94 52.85,83.72 53.06,83.72 v2(53.27,83.93) 53.36,83.84 53.71,83.84 53.84,83.97 53.84,84.55 54.09,84.8 54.09,85.95 54.8,86.66 58.28,86.66 60.35,84.59 61.34,84.59 65,88.24 67.46,88.24 68.1,88.88 69.02,88.88 69.87,88.03 69.87,87.63 70.31,87.19 71.62,87.19 72.43,88 73.49,88 74.32,88.83 76.48,88.83 77.12,89.46 77.86,89.46 78.18,89.13 79.87,89.13 80.12,89.39 80.12,89.73 80.05,89.81 79.97,89.99 79.97,90.54 80.43,91 80.43,91.36 80.66,91.59 80.66,92.05 81.56,92.94 83.87,92.94 83.87,92.94 83.92,92.94 84.97,91.89 v2(85.23,91.89) ; v2(272.14,85.44) 269.51,82.81 v1(269.51,80.82) 269.51,78.8 v2(269.65,78.66) ; RE23.1 303.81,77.31 302.81,77.31 302.18,77.93 v2(302.18,78.06) UE3.N2
  vias: v2(105.64,84.75)
PBAT_CHARGER_SMBDAT: length 56.5
  TOP w0.14: PD101.3 12.32,75.52 v2(11.83,75.03) 11.71,74.91 PR108.2 ; PR1913.1 52.64,83.22 52.8,83.38 53.18,83.38 v2(53.27,83.29) 53.48,83.5 53.85,83.5 54.19,83.83 54.19,84.41 54.43,84.66 54.43,85.81 54.94,86.31 58.14,86.31 60.21,84.24 61.48,84.24 65.14,87.9 67.6,87.9 68.24,88.54 68.88,88.54 69.53,87.89 69.53,87.48 70.17,86.85 71.76,86.85 72.57,87.66 73.63,87.66 74.46,88.49 76.62,88.49 77.26,89.12 77.71,89.12 78.04,88.79 80.01,88.79 80.47,89.25 80.47,89.87 80.34,90 80.31,90.06 80.31,90.4 80.77,90.86 80.77,91.22 81,91.45 81,91.9 81.7,92.6 83.73,92.6 84.86,91.47 v2(84.86,91.26) ; UE3.M3 301.08,78.5 302.35,78.5 302.79,78.06 v2(302.88,78.06) 302.88,77.82 303.03,77.67 304.19,77.67 RE22.1 ; v2(268.88,78.68) 269.15,78.95 v1(269.15,82.07) 269.15,82.95 271.53,85.32 v2(271.53,85.44)
  vias: v2(105,84.78)
PBAT_PRES#: length 21.8
  TOP w0.14: v2(51.8,91.26) 49.51,88.98 49.51,87.47 PR1924.1 ; v2(295.52,84.06) UE3.F9 ; PR111.2 17.45,71.21 PR112.1 18.21,71.01 18.4,71.2 PD102.3 PD102.2 20.27,71.2 v2(20.35,71.13) ; v2(144.28,79.07) v1(144.28,78.51)
  BOTTOM w0.14: v3(43.17,86.48) 43.85,87.17 48.83,87.17 49.47,87.81 49.47,88.41 49.72,88.66 51.04,88.66 51.8,89.42 v2(51.8,91.26)
PBRSVD1: length 1.1
  TOP w0.089: T4964.1 90.73,86.36 v2(90.71,86.39)
  BOTTOM w0.089: v2(90.71,86.39) 90.67,86.35 UH2.U13
PBTN_SW#: length 70
  TOP w0.14: SW1.1 334.3,178.54 336.16,176.69 340.55,176.69 v1(341.63,177.77) v2(343.08,179.22) 343.08,182.06 DL1.3 ; v2(284.3,85.43) 284.42,85.43 284.86,85.87 CE29.1 RE36.2
  BOTTOM w0.14: v2(284.3,85.43) 284.3,85.41 283.59,84.7 279.55,84.7 278.94,84.09 278.94,72.28 279.2,72.02 280.52,72.02 v2(280.95,72.45) ; JAPS.11 171.39,75.44 171.38,75.45 v2(171.38,75.46) ; SW_BOT.1 327.16,99.67 v2(328.66,101.19) 328.66,101.43 327.2,102.89 327.2,105.05 326.57,105.68 315.39,105.68 313.36,103.65 311.2,103.65 309.99,102.44 Q6.1
PBTN_SW#_R: length 10.2
  TOP w0.14: v2(307.01,102.51) v1(307.01,101.62)
  BOTTOM w0.14: JFP.7 312.86,102.75 312.47,103.14 311.33,103.14 310.31,102.13 D324.1 308.92,101.45 Q6.3 307.01,101.54 v2(307.01,102.51)
PCH_3.3V_TS_EN: length 7.3
  BOTTOM w0.089: UH2.BD30 82.72,73.01 82.72,74.11 82.91,74.3 82.91,74.86 83.11,75.07 83.11,75.38 v2(83.22,75.48)
  BOTTOM w0.14: v1(336.97,127.15) 337.63,127.81 337.63,128.53 RZ39.1 337.11,129.53 v2(337.26,129.69) 337.72,129.69 338.29,129.11 UZ5.3
PCH_ALW_ON: length 95.8
  TOP w0.14: UZ23.2 104.01,119.91 v2(104.44,119.47) ; v2(302.76,82.82) 302.29,83.29 301.88,83.29 301.8,83.2 301.07,83.2 UE3.M8 ; v2(120.45,116.98) 120.52,116.98 120.87,116.64 v1(120.87,114.08) 120.87,112.37 114.51,106.02 109.64,106.02 106.9,103.27 106.9,95.5 109.48,92.91 109.48,88.11 110.4,87.2 112.08,87.2 113.05,86.22 115.46,86.22 116.68,85 116.68,84.54 117.14,84.09 125.52,84.09 128.3,81.31 128.3,77.52 129.29,76.53 131.05,76.53 v2(131.5,76.98)
  BOTTOM w0.14: v2(104.44,119.47) 104.68,119.24 104.68,115.03 106.79,112.91 112.19,112.91 114.5,115.23 115.86,115.23 116.51,114.58 119.49,114.58 120.45,115.54 v2(120.45,116.98)
PCH_ALW_ON_R: length 4.8
  TOP w0.14: v4(55.74,76.54) 55.74,76.03 55.4,75.68 RZ46.2 RZ1133.2 54.99,74.41 53.85,74.41 53.2,73.77 UZ4.3
PCH_BATLOW#: length 2.9
  TOP w0.089: v2(75.41,72.87) 75.6,73.06 75.6,73.36 v1(75.56,73.4) 75.46,73.5 74.9,73.5 RH515.1
  BOTTOM w0.089: UH2.BF44 75.62,72.66 v2(75.41,72.87)
PCH_CPU_BCLK_N: length 1.2
  BOTTOM w0.076: v2(176.3,149.6) 176.05,149.6 UH1.A32
  BOTTOM w0.089: UH2.C8 93.95,93.34 v2(93.95,93.36)
PCH_CPU_BCLK_P: length 1.6
  BOTTOM w0.076: UH1.B31 175.39,149.55 175.55,149.55 v2(175.84,149.27)
  BOTTOM w0.089: UH2.B8 93.48,93.43 93.98,93.93 v2(93.98,93.93)
PCH_CPU_PCIBCLK_N: length 2.4
  BOTTOM w0.076: UH1.C36 174.46,151.59 v2(174.48,151.57)
  BOTTOM w0.089: 94.74,94.51 94.74,94.49 94.68,94.43 94.68,93.67 UH2.B6
  BOTTOM w0.152: v2(94.78,95.15) 94.74,95.12 94.74,94.51
PCH_CPU_PCIBCLK_P: length 1.9
  BOTTOM w0.076: UH1.D35 173.98,151.67 v2(173.67,151.98)
  BOTTOM w0.089: UH2.A6 94.41,94.51
  BOTTOM w0.152: 94.41,94.51 94.41,94.82 94.19,95.04 v2(94.19,95.17)
PCH_DMIC_CLK: length 8.4
  BOTTOM w0.089: v2(89.53,69.88) 89.45,69.97 89.45,71.58 89.66,71.79 89.66,72.12 89.8,72.26 89.8,72.68 UH2.BD16
  BOTTOM w0.14: RA103.2 145.83,75.09 145.83,70.91 v2(146.21,70.53)
PCH_DMIC_CLK_R: length 5.5
  BOTTOM w0.14: RE310.1 149.75,78.4 v1(149.32,77.97) 148.48,77.97 148.3,77.79 147.65,77.79 CE3321.1 146.35,76.49 146.35,76.35 146.16,76.15 RA103.1
PCH_DMIC_DAT: length 7.5
  TOP w0.14: v2(150.19,70.88) v1(150.19,70.13)
  BOTTOM w0.089: v3(90.08,69.88) 90.08,70.24 89.65,70.67 89.65,71.53 89.84,71.72 89.84,71.89 UH2.BF15
  BOTTOM w0.14: RA102.2 148.94,70.68 149.26,70.35 149.8,70.35 150.19,70.75 v2(150.19,70.88)
PCH_DMIC_DAT_R: length 2.2
  BOTTOM w0.14: RE309.1 150.11,75.13 CE3322.1 148.94,74.93 RA102.1
PCH_DP1_HPD: length 4.2
  BOTTOM w0.089: v2(94.54,77.72) 94.31,77.49 UH2.AT6 ; UT1.AA2 29.17,111.43 29.17,111.81 29.31,111.94 29.71,111.94 29.76,112 v2(30.21,112) 30.43,112.21 31.39,112.21 31.42,112.25
  BOTTOM w0.17: RT41.2 31.42,112.25
PCH_DP2_HPD: length 13.7
  TOP w0.14: v2(31.74,101.55) 32.05,101.55 32.69,102.19 35.17,102.19 35.61,102.63 v1(35.61,103.56) 35.61,104.16 34.85,104.92 34.85,106.44 35.7,107.29 35.7,107.89 35.33,108.26 35.15,108.26 34.58,108.84 34.2,108.84 RT42.2
  BOTTOM w0.089: v2(91.82,77.59) 92.17,77.94 UH2.AN10
  BOTTOM w0.102: v2(28.37,109.52) UT1.Y6
PCH_DP3_HPD: length 45.1
  TOP w0.089: v1(92.6,77.72) 92.86,77.46 v2(92.86,77.12) 92.87,77.13 94.6,77.13 RM1145.2
  TOP w0.14: v2(28.82,120) 28.87,119.95 28.87,119.51 29.73,118.65 30.97,116.41 30.97,115.4 32.86,113.51 32.86,113.21 33.86,112.21 33.86,111.98 39.93,105.91 40.58,105.91 41.4,105.1 42.16,105.1 43.41,103.85 45.09,103.85 45.47,103.47 48.09,103.47 48.52,103.04 48.52,99.84 46.98,98.29 46.35,98.29 45.85,97.79 45.85,97.29 46.85,96.28 46.85,93.43 v2(47.42,92.86) ; RM3.2 25.6,136.4 25.9,136.69 v2(26.14,136.69)
  BOTTOM w0.089: UH2.AP9 92.93,77.25 92.86,77.18 92.86,77.12 v2(92.86,77.12)
PCH_DP3_HPD_R: length 3.7
  TOP w0.14: UM1.B1 23.46,137.56 23.71,137.56 24.21,137.06 v1(25.15,137.06) 25.15,136.62 RM3.1
PCH_DPWROK_EC: length 1.9
  TOP w0.14: UE3.F8 295.57,83.22 v2(295.57,83.25) ; v1(291.21,92.94) 290.87,92.61 v2(290.87,92.43) ; v3(64.61,74.88) 64.8,75.08 RH309.1
  vias: v2(61.8,78.29)
PCH_DPWROK_R: length 5.1
  TOP w0.14: RH309.2 65.68,74.59 RH5859.2 65.68,73.14 RH401.2 v4(67.14,73.12) 67.62,73.12 v3(67.9,73.4)
  BOTTOM w0.089: UH2.AW41 v2(77.19,75.64)
PCH_GPP_A11_BALL: length 3.4
  BOTTOM w0.089: UH2.BE36 79.43,72.37 79.16,72.11 79.16,71.18 79.49,70.86 79.49,69.6 T17.1
PCH_GPP_A18: length 1.5
  TOP w0.089: v2(79.57,71.29) 79.57,71.37 T124.1
  BOTTOM w0.089: v2(79.57,71.29) 79.64,71.36 79.64,71.36 80.09,71.8 UH2.BF35
PCH_GPP_C10: length 1.3
  TOP w0.089: T4989.1 86.45,74.89 86.25,74.7 v2(86.24,74.7)
  BOTTOM w0.089: UH2.BA24 85.81,74.69 86.24,74.69 v2(86.24,74.7)
PCH_GPP_C11: length 1.3
  TOP w0.089: v2(86.16,77.49) 85.92,77.73 T4988.1
  BOTTOM w0.089: v2(86.16,77.49) 86.12,77.53 UH2.AP24
PCH_GPP_D7_BALL: length 1.5
  TOP w0.089: T121.1 88.1,76.42 v2(88.1,75.48)
  BOTTOM w0.089: v2(88.1,75.48) 88.14,75.43 88.25,75.43 UH2.AW18
PCH_GPP_H23_BALL: length 10.1
  BOTTOM w0.089: 70.16,83.31 70.27,83.2 70.99,83.2 71.81,82.39 71.81,81.71 72.84,80.68 73.29,80.68 73.74,80.23 UH2.AJ47
  BOTTOM w0.14: 70.16,83.31 69.61,83.86 66.45,83.86 T8.1
PCH_GPP_K2_BALL: length 9.5
  BOTTOM w0.089: 72.82,88.34 73.25,88.34 73.53,88.61 74.51,88.61 UH2.L46
  BOTTOM w0.14: 72.82,88.34 72.6,88.34 71.67,89.27 68.93,89.27 68.39,89.81 67.56,89.81 67.27,89.51 T94.1
PCH_GPP_K8_BALL: length 8.8
  BOTTOM w0.089: 72.82,87.83 73.6,87.83 UH2.P48
  BOTTOM w0.14: 72.82,87.83 72.35,87.83 71.41,88.77 68.58,88.77 68.53,88.72 67.3,88.72 66.57,87.99 T91.1
PCH_GPP_K9_BALL: length 8.5
  BOTTOM w0.089: 72.45,85.88 72.69,85.63 74.3,85.63 UH2.V47
  BOTTOM w0.14: 72.45,85.88 72.45,86.26 71.08,87.62 71.08,88.33 70.89,88.53 68.69,88.53 68.4,88.24 T92.1
PCH_GPP_K23_BALL: length 11.2
  BOTTOM w0.089: 72.82,88.07 73.25,88.07 73.61,88.44 74.58,88.44 74.68,88.54 75.11,88.54 UH2.M45
  BOTTOM w0.14: 72.82,88.07 72.45,88.07 71.51,89.01 68.48,89.01 68.43,88.96 66.58,88.96 65.55,87.93 T4.1
PCH_ITP_PMODE: length 1.4
  TOP w0.14: v2(117.62,161.02) 117.07,161.57 RH479.1
  BOTTOM w0.089: UH2.AL3 95.41,79.2 v2(95.27,79.34)
  vias: v2(111.17,85)
PCH_JTAG_TCK: length 11.9
  TOP w0.14: v2(131.71,167.47) v4(131.3,167.05) 128.39,167.05 127.94,166.6 127.45,166.6 127.04,166.2 JXDP.55
  BOTTOM w0.089: RH95.2 99.09,78.48 v2(98.95,78.63) 98.95,79.78 98.68,80.05 97.03,80.05 96.6,80.48 95.97,80.48 95.96,80.47 95.79,80.47 95.63,80.31 UH2.AJ3
  vias: v2(98.56,86.88) v2(111.09,110.71) v2(130.33,133.37)
PCH_JTAG_TDI: length 16.7
  TOP w0.14: v2(115.4,161.21) v4(114.41,161.21)
  BOTTOM w0.089: 99.75,79.62 99.72,79.62 98.99,80.35 97.01,80.35 96.63,80.72 UH2.AH2
  BOTTOM w0.14: v2(107.81,83.58) 106.57,83.58 105.99,83.01 105.79,83.01 105.62,82.85 105.62,82.01 104.33,80.71 102.87,80.71 101.77,79.62 99.75,79.62 ; v2(115.4,161.21) 115.87,161.68 RH477.2 116.09,161.65 RH100.2
PCH_JTAG_TDO: length 5.8
  TOP w0.14: v2(118.73,162.2) 118.37,162.2 118.12,161.95 v4(118.12,161.85)
  BOTTOM w0.089: UH2.AH3 95.64,80.69 95.61,80.72 95.61,80.87 95.26,81.22 v2(95.26,81.48)
  BOTTOM w0.14: RH97.2 118.29,159.38 118.29,161.3 RH478.2 118.1,161.87 118.4,161.87 v2(118.73,162.2)
PCH_JTAG_TMS: length 4.7
  TOP w0.14: v2(117.78,159.96) 117.78,159.55 v4(117.98,159.35)
  BOTTOM w0.089: UH2.AJ4 94.64,80.79 94.07,80.79 v2(93.55,81.31)
  BOTTOM w0.14: RH12.2 116.93,161.65 RH98.2 117.78,160.03 v2(117.78,159.96)
PCH_JTAGX: length 2.7
  TOP w0.14: RH491.1 128.91,167.84 v2(129.21,167.53) 129.53,167.53 v1(129.97,167.98)
  BOTTOM w0.089: v2(94.66,81.38) 94.85,81.38 95.14,81.09 95.14,80.96 UH2.AH4
  vias: v2(110,85)
PCH_PCIE_WAKE#: length 32.2
  TOP w0.14: RT5843.1 71.06,71.9 71.46,72.31 v2(71.46,72.61) 70.98,73.09 70.98,73.7 70.62,74.06 RH453.1 ; v2(303.75,93.43) 303.75,93.65 v1(303.49,93.91) ; UE3.L1 299.92,76.61 300.84,75.7 302.04,75.7 302.44,76.09 303.02,76.09 v2(303.54,75.57)
  BOTTOM w0.089: 72.94,73.27 73.09,73.42 73.55,73.42 UH2.BB47
  BOTTOM w0.14: RE322.1 303.64,93.54 v2(303.75,93.43) 303.75,93.06 304.32,92.5 304.32,85.85 303.77,85.3 303.77,82.63 303.23,82.09 303.23,79.45 304.08,78.6 304.08,76.1 v2(303.54,75.57) ; v2(71.46,72.61) 72.16,72.61 72.82,73.27 72.94,73.27
PCH_PECI: length 6.7
  BOTTOM w0.089: UH2.AF2 96.72,81.4 96.82,81.3 98.47,81.3 98.51,81.25 99.71,81.25 99.74,81.22 99.75,81.22
  BOTTOM w0.14: 99.75,81.22 99.92,81.22 RH539.1 100.54,81.67 101.05,81.17 RH5836.1 v1(101.4,80.13)
PCH_PLTRST#: length 8
  TOP w0.14: CH3327.1 62.29,72.33 62.4,72.23 v2(62.4,71.93) 62.4,71.75 61.93,71.28 61.93,70.78 v1(62.06,70.64)
  BOTTOM w0.089: v2(82.23,75.61) 82.23,75.67 82.47,75.91 UH2.AV29
  BOTTOM w0.14: UH7.2 65.41,69.35 65.53,69.47 65.53,69.87 65.41,70 UH7.1 64.09,70 62.4,71.69 62.4,71.7 v2(62.4,71.93)
PCH_PLTRST#_5105: length 13.3
  TOP w0.14: UE5.4 305.88,72.39 305.61,72.66 304.47,72.66 304.09,72.28 304.09,71.9 303.83,71.65 303.33,71.65 302.99,71.98 302.99,73.86 RE183.1 303.19,74.71 303.19,75.26 302.92,75.53 302.56,75.53 302.27,75.24 300.65,75.24 v1(300.51,75.38) 299.45,76.43 299.45,76.93 UE3.K1
PCH_PLTRST#_EC: length 99.4
  TOP w0.14: RE31.2 306.3,70.83 305.54,71.6 v2(305.26,71.6) 304.98,71.32 304.98,70.5 305.23,70.25 UE5.2 ; RT1135.2 295.15,95 v2(295.44,94.71) ; v2(228.28,111.8) 229.13,110.95 229.6,110.95 230.02,110.53 230.02,109.28 231.47,107.83 245.46,107.83 246.57,106.71 250.15,106.71 258.06,98.8 258.06,96.28 258.91,95.43 258.91,90.58 259.42,90.06 259.42,89.17 261.13,87.46 261.13,86.44 v2(261.11,86.42) 260.78,86.09 260.51,86.09 259.12,84.7 259.12,77.85 v1(258.82,77.55) 258.82,75.94 259.44,75.33 v2(259.44,73.99) ; v2(225.29,111.72) 225.03,111.46 UV19.2 ; U33.8 202.54,115.63 202.33,115.43 202.33,113.98 203.38,112.92 206.04,112.92 206.75,113.63 v2(206.98,113.63) ; U32.17 148.47,76.19 v2(148.4,76.26)
  BOTTOM w0.14: v2(339.04,157.49) 339.07,157.51 JNGFF1.44 ; v2(146.03,69.13) 147.4,70.49 147.4,71.51 147.83,71.94 147.83,74.67 148.4,75.25 v2(148.4,76.26) ; JNGFF2.50 267.12,77.49 268.29,76.32 268.29,74.02 v2(268.2,73.93) ; v2(62.46,70.21) 61.79,69.54 RH77.1 62.01,68.7 UH7.4 ; RR43.1 342.44,111.07 v2(342.54,110.97) ; v2(14.83,113.16) 14.27,113.72 RT435.1 ; v2(340.44,101.88) 340.3,101.75 339.29,101.75 339.14,101.89 UR1.1
  vias: v2(56.59,89.53)
PCH_PLTRST#_EC_AR: length 2
  TOP w0.089: RT5857.2 86.25,72.83 v2(86.16,72.92)
  BOTTOM w0.089: v2(86.16,72.92) 86.21,72.87 UH2.BE23
  BOTTOM w0.14: v2(14.85,112.53) 14.76,112.44 RT5855.1
  vias: v2(65.14,82.57)
PCH_PLTRST#_EC_R: length 4
  TOP w0.14: v2(294.44,96.67) 294.72,96.39 RT1135.1 v1(295.72,95.92)
  BOTTOM w0.14: JLPDE1.8 293.82,97.28 v2(294.44,96.67)
PCH_PRIM_EN: length 133.6
  TOP w0.14: RH5870.1 244.91,74.32 RH5871.1 242.92,74.27 v1(241.86,75.33) 242.48,75.95 CZ2154.1 RZ1951.2 242.48,78.48 v2(242.67,78.68)
  BOTTOM w0.14: PR1950.1 136.04,67.85 148.63,67.85 150.15,69.37 201.84,69.37 203.37,67.85 224.43,67.85 225.22,68.64 225.22,81.04 226.62,82.44 240.97,82.44 242.67,80.74 v2(242.67,78.68) ; PR1602.1 247.52,174.86 246.91,175.47 v2(246.72,175.47)
  vias: v2(247.85,166.55)
PCH_PWROK: length 11.6
  TOP w0.089: v4(77.7,74.68) 77.53,74.52 v2(77.13,74.52)
  BOTTOM w0.089: v2(77.13,74.52) 76.96,74.69 UH2.AY42
  BOTTOM w0.14: v2(67.28,73.7) 67.24,73.75 67.02,73.75 66.83,73.93 66.16,73.93 65.82,73.58 65.82,73.28 65.21,72.67 62.36,72.67 61.91,72.22 61.91,71.26 61.78,71.14 61.04,71.14 60.93,71.24 RH529.1 60.08,71.52 59.99,71.43 UH14.4
PCH_RSMRST#: length 4.8
  TOP w0.14: v1(308.18,72.59) 307.86,72.59 v2(307.68,72.76) ; UE3.M5 300.74,80.46 301.17,80.03 301.7,80.03 301.79,79.94 303.05,79.94 303.42,79.57 v2(303.79,79.57)
  BOTTOM w0.14: v2(70.2,74.6) 70.19,74.6 69.76,75.02 RT1136.1
  vias: v2(162.61,70.66)
PCH_RSMRST#_EC: length 5.2
  TOP w0.14: RH5859.1 67.01,74.72 67.79,74.72 67.94,74.87 v2(67.98,74.87) ; v1(272.47,80.28) v2(273.48,79.27) ; RH481.1 v2(128.88,159.94)
  BOTTOM w0.14: v2(67.98,74.87) 68.13,75.02 RT1136.2 RH133.1
  vias: v2(60.04,85.8) v2(98.36,112.29)
PCH_RSMRST#_R: length 7
  TOP w0.089: v1(71.5,74.3) 71.21,74.6 71.04,74.6
  TOP w0.14: 71.04,74.6 v2(70.82,74.6)
  BOTTOM w0.089: 71.04,74.67 71.42,74.67 71.53,74.57 73.26,74.57 73.49,74.34 73.86,74.34 UH2.BA47
  BOTTOM w0.14: 71.04,74.67 70.89,74.67 v2(70.82,74.6) 70.82,74.59 70.23,74.01 69.8,74.01 RH133.2 69.38,74.05 69.38,73.84 RH5841.2
PCH_RTCRST#: length 22.8
  TOP w0.089: v2(73.83,72.85) 73.22,72.85 CH53.1 73.77,72.27 73.77,71.5 73.99,71.28 73.99,70.19 73.11,69.31 72.82,69.31
  TOP w0.14: v2(66.07,69.84) 65.66,69.44 65.66,69.26 65.41,69 v4(65.41,68.55) 65.41,68.27 65.72,67.95 73.04,67.95 73.16,68.07 73.16,68.83 72.85,69.14 RH84.2 72.69,69.21 72.8,69.31 72.82,69.31 ; v2(171.94,77.56) 171.88,77.5 RT1133.1
  BOTTOM w0.089: UH2.BE47 74.15,72.53 v2(73.83,72.85)
  BOTTOM w0.14: v2(66.07,69.84) 66.08,69.86 66.08,70.47 65.43,71.12 CLRP1.1 ; v2(171.94,77.56) 171.94,76.16 172.39,75.71 JAPS.9
PCH_RTCRST#_R: length 3.2
  TOP w0.14: QR104.1 173.63,76.47 173.25,76.85 RT1133.2 172.55,77.09 v1(172.55,77.87)
PCH_RTCX1: length 9.1
  BOTTOM w0.089: UH2.BA49 73.11,74.36 71.23,74.36
  BOTTOM w0.14: YH1.1 67.94,70.43 CH45.1 68.12,71.57 RH70.1 68.2,72.28 68.74,72.81 69,72.81 69.79,73.6 70.47,73.6 71.23,74.36
PCH_RTCX2: length 8.6
  BOTTOM w0.089: 71.55,74.15 71.58,74.17 72.89,74.17 73.08,73.98 73.61,73.98 UH2.BA48
  BOTTOM w0.14: YH1.2 68.94,70.31 CH46.1 69.04,71.49 RH70.2 69.04,72.37 69.92,73.26 70.6,73.26 71.49,74.15 71.55,74.15
PCH_RTD3_USB_PWR_EN: length 3.9
  TOP w0.089: v1(87.6,73.84) 88.11,74.35 v2(88.11,74.45)
  TOP w0.14: v2(22.89,116.97) 22.89,117.49 23.25,117.86 RT5841.1
  BOTTOM w0.089: UH2.BC17 88.51,73.24 88.15,73.6 88.15,74.18 88.09,74.24 88.09,74.43 v2(88.11,74.45)
  vias: v2(31.07,101.43) v3(56.06,85.49)
PCH_SLP_LAN#: length 2.8
  BOTTOM w0.089: T20.1 77.79,69.4 77.79,70.37 77.68,70.49 77.68,71.48 77.89,71.69 UH2.BF40
PCH_SMB_ALERT#: length 2.8
  TOP w0.089: v2(84.36,70.95) 84.98,71.57 RH505.2
  BOTTOM w0.089: UH2.BE25 85.01,72.23 84.71,71.93 84.71,71.85 84.42,71.56 84.42,71.01 v2(84.36,70.95)
PCH_SMBCLK: length 82.7
  TOP w0.14: v2(236.65,114.32) 236.88,114.09 236.88,113.77 236.76,113.66 235.25,113.66 235.13,113.78 UF1.1 ; v2(170.14,77.59) 170.25,77.69 170.25,78.1 170.59,78.43 170.59,87.62 171.19,88.23 171.19,88.82 171.69,89.32 171.79,89.32 v2(172.01,89.54) ; RH463.2 108.13,76.18 107.94,75.99 107.94,75.57 v2(107.94,75.57) ; v2(135.69,155.42) 135.58,155.53 135.58,157.82 135.14,158.27 135.14,162.68 134.01,163.81 133.29,163.81 131.97,165.13 131.97,165.54 130.83,166.67 128.5,166.67 128.07,166.25 127.58,166.25 127.04,165.7 JXDP.53
  BOTTOM w0.127: JDIMM1.253 170.14,93.62
  BOTTOM w0.14: QH4.1 107.89,77.5 107.42,77.03 107.42,76.24 107.94,75.71 v2(107.94,75.57) ; 170.14,93.62 172.01,91.75 v2(172.01,89.54) ; JDIMM2.253 246.44,96.13 v2(246.47,96.16) 246.47,96.66 240.33,102.79 240.33,107.03 239.68,107.69 236.97,107.69 233.32,111.34 233.32,114.08 234.07,114.83 234.69,114.83 235.34,115.48 236.92,115.48 237.08,115.32 237.08,113.69 236.81,113.42 234.29,113.42 234.16,113.55 234.16,113.73 234.3,113.87 236.55,113.87 236.65,113.97 v2(236.65,114.32)
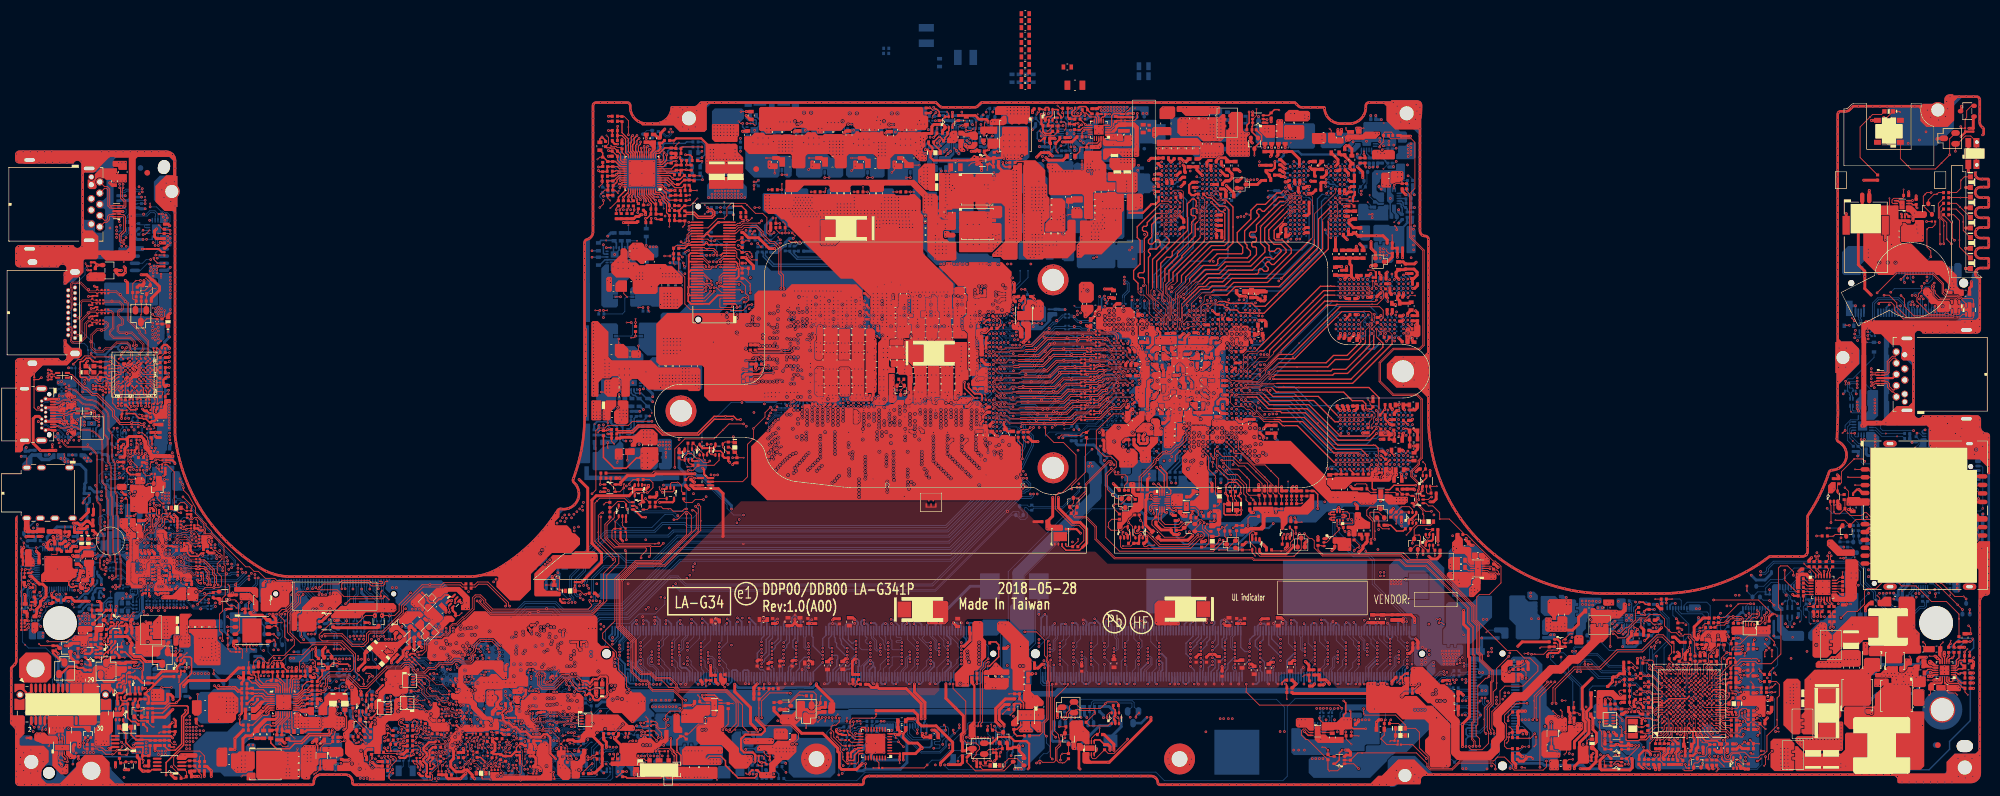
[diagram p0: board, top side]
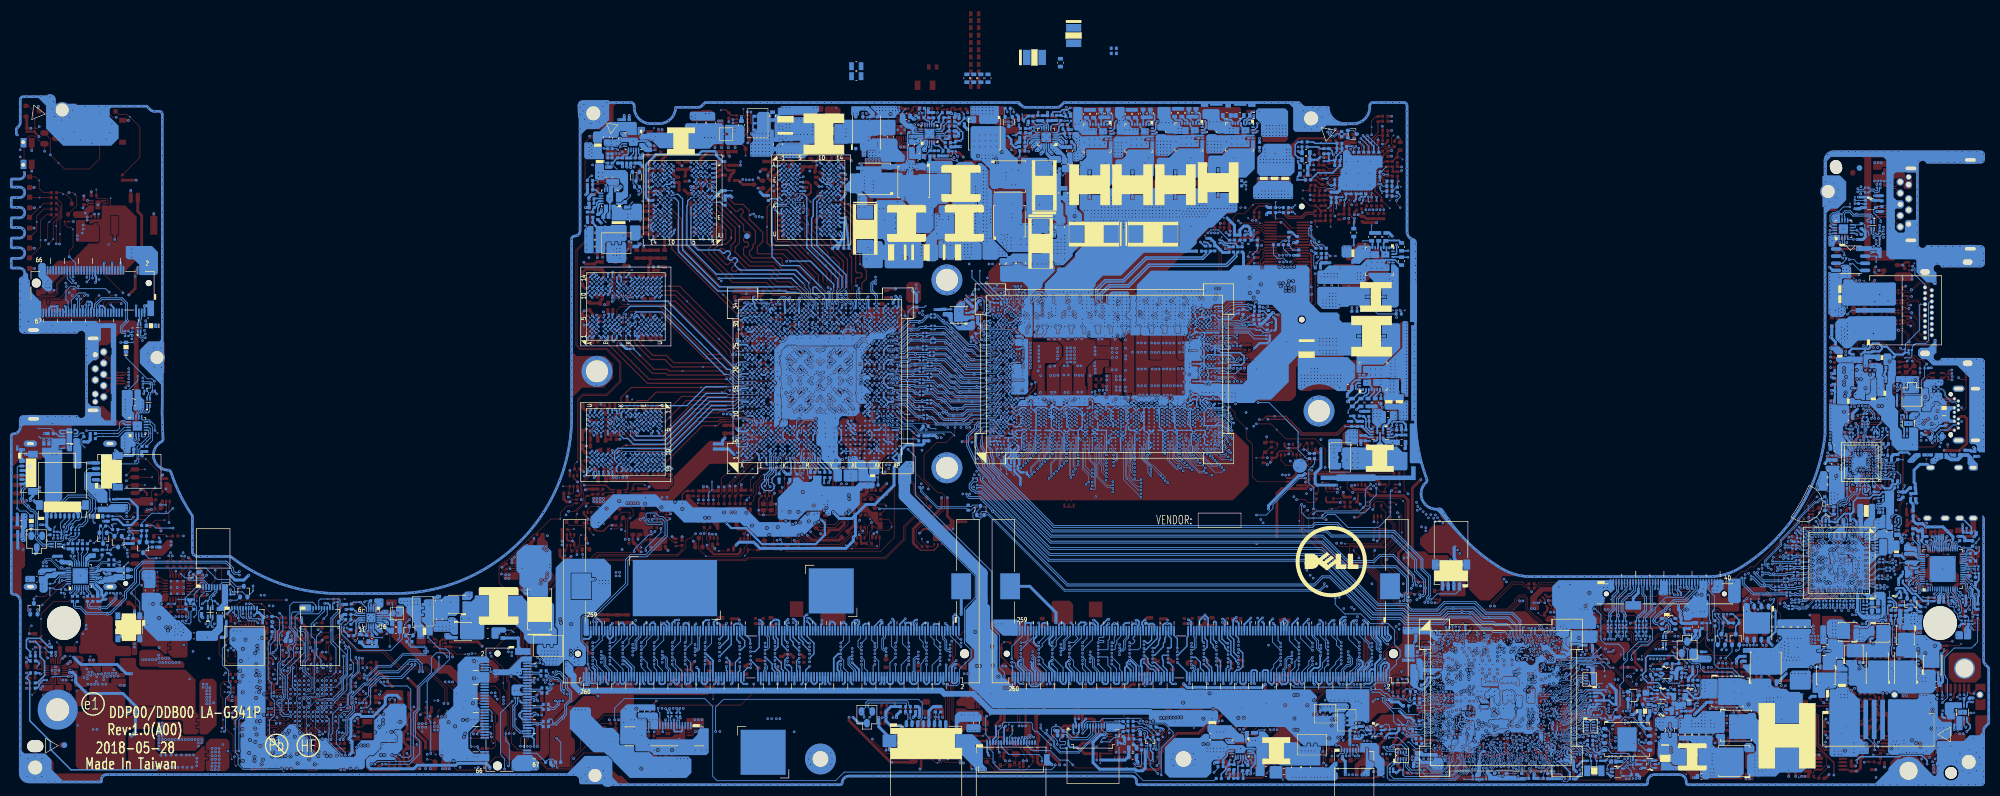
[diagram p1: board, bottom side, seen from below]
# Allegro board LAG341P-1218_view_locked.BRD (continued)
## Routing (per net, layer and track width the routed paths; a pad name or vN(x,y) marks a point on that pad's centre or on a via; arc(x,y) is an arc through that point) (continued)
PCH_SMBDATA: length 78.2
  TOP w0.14: v2(170.73,77.59) 170.64,77.68 170.64,77.93 170.98,78.27 170.98,87.46 171.58,88.07 171.58,88.65 171.85,88.92 v2(172.05,88.92) ; v2(107.36,75.57) 107.54,75.75 107.54,76.28 RH462.2 ; v2(236.02,114.32) 236.27,114.57 236.27,115.33 235.91,115.69 UF1.4 ; JXDP.51 127.01,165.2 127.11,165.31 127.2,165.31 127.75,165.85 128.24,165.85 128.66,166.27 130.74,166.27 131.62,165.4 131.62,164.99 133.15,163.47 133.79,163.47 134.75,162.51 134.75,158.1 135.19,157.66 135.19,155.5 v2(135.11,155.42)
  BOTTOM w0.14: JDIMM2.254 246.69,87.22 247.22,87.76 247.22,88.16 247.42,88.36 v2(247.42,88.62) 247.45,88.65 247.45,91.69 248.49,92.73 248.49,96.85 248.16,97.18 246.5,97.18 240.73,102.95 240.73,107.19 239.84,108.08 237.13,108.08 233.71,111.5 233.71,113.92 234.23,114.44 235.9,114.44 v2(236.02,114.32) ; v2(107.36,75.57) 107.36,75.74 106.89,76.2 QH4.4 ; v2(172.05,88.92) 171.61,88.92 171.31,88.62 171.31,88.12 170.39,87.2 JDIMM1.254
PCH_SPI_CLK: length 12.4
  TOP w0.14: RH577.2 69.6,78.28 v1(69.9,78.58) 70.07,78.58 v2(70.42,78.23)
  BOTTOM w0.089: UH2.AW47 74.06,75.71 73.44,75.71 73.36,75.79 73.09,75.79
  BOTTOM w0.14: JSPI1.4 111.83,72.35 v2(111.93,72.26) ; 73.09,75.79 72.9,75.79 72.55,76.14 72.03,76.14 71.48,76.68 71.48,77.49 71.29,77.69 70.96,77.69 70.42,78.23 v2(70.42,78.23) 70.29,78.36 69.74,78.36 RP4.1 69.2,78.28 68.82,78.66 68.58,78.66 68.07,79.16 67.34,79.16 RH5892.1
PCH_SPI_CLK_R: length 5.2
  TOP w0.14: v4(59.52,74.53) 59.54,74.54 59.87,74.54 v2(60.06,74.73)
  BOTTOM w0.089: v2(68.17,76.34) 68.17,76.34 68.21,76.37 68.74,76.37 68.9,76.53
  BOTTOM w0.14: UH8.6 59.52,74.57 59.69,74.73 v2(60.06,74.73) ; 68.9,76.53 69.06,76.69 69.06,77.93 68.72,78.28 RP4.8
PCH_SPI_CLK_TPM: length 2.2
  TOP w0.14: v2(67.57,78.24) 67.66,78.24 68.06,77.84 68.46,77.84 RH577.1 ; v2(145.6,76.76) 145.89,76.76 145.93,76.73 RE115.1
PCH_SPI_CLK_TPM_R: length 3.3
  TOP w0.14: RE115.2 146.99,76.41 147.28,76.12 C135.1 147.52,75.96 v1(148.08,75.41) 148.3,75.19 U32.19
PCH_SPI_CS#0: length 12.1
  TOP w0.089: v2(71.89,75.43) 71.28,75.43 71.04,75.66
  TOP w0.14: v4(70.98,75.72) 71.04,75.66
  BOTTOM w0.089: UH2.AY47 74.29,74.81 74.08,75.02 72.28,75.02 71.89,75.4 v2(71.89,75.43) 71.66,75.43 71.1,75.99 71.04,75.99
  BOTTOM w0.14: JSPI1.5 111.33,72.54 111.02,72.23 v2(110.88,72.23) ; 71.04,75.99 71.04,75.99 70.65,75.99 70.54,76.09 69.6,76.09 RH74.2 ; UH8.1 66.22,77.11 65.63,76.52 65.63,74.63 65.42,74.41 65.42,73.91 v2(65.22,73.72)
PCH_SPI_CS#1: length 4.3
  BOTTOM w0.089: UH2.AW48 72.93,75.47 72.5,75.9 72.24,75.9
  BOTTOM w0.14: 72.24,75.9 71.71,75.9 v2(71.43,76.19) ; v2(114.28,74.14) 113.72,74.14 113.33,73.75 JSPI1.1
PCH_SPI_CS#2: length 2.4
  TOP w0.14: RE133.1 v1(145.72,75.08) 145.59,75.08 145.43,75.24 145.43,75.46 145.3,75.58 145.2,75.58 v2(145.14,75.65)
  BOTTOM w0.089: UH2.AT40 77.59,76.82 v2(77.39,77.01)
PCH_SPI_CS#2_R: length 2.3
  TOP w0.14: U32.20 147.63,74.69 RE133.2
PCH_SPI_HOLD#: length 8.4
  TOP w0.14: v2(64.61,75.53) 64.83,75.53 65.18,75.88 RH78.2 65.39,76.35 65.87,75.86 RH576.2
  BOTTOM w0.089: UH2.BA46 74.7,74.12 74.31,73.74 74.1,73.74 74.03,73.81 72.69,73.81 72.52,73.98 71.79,73.98 71.58,73.78
  BOTTOM w0.14: 71.58,73.78 70.62,72.81 v2(70.38,72.81) ; JSPI1.7 110.33,73.88 v2(110.62,74.16)
PCH_SPI_HOLD#_R: length 10.6
  TOP w0.14: RH576.1 65.81,76.78 65.63,76.95 65.63,77.18 65.19,77.63 v3(65.12,77.63)
  BOTTOM w0.14: v3(65.12,77.63) 64.53,78.22 63.89,78.22 v1(62.97,79.15) 61.46,79.15 60.77,78.47 60.77,77.98 59.38,76.59 59.38,76.17 59.04,75.84 58.54,75.84
PCH_SPI_SI: length 8
  TOP w0.089: RH489.1 74.56,76.19 RH5860.2 75.29,75.47 75.79,75.47 v1(76.2,75.88) 76.46,76.13 v2(76.46,76.32)
  TOP w0.14: v2(70.41,77.65) 70.15,77.4 70.15,77.09 69.89,76.82 RH578.2
  BOTTOM w0.089: UH2.AU41 76.76,76.18 76.59,76.35 76.49,76.35 v2(76.46,76.32)
  BOTTOM w0.14: JSPI1.2 112.83,72.81 112.95,72.69 113.56,72.69 113.99,72.26 v2(114.02,72.26) ; v2(70.41,77.65) 70.27,77.65 70.06,77.86 69.74,77.86 RP4.2
PCH_SPI_SI_R: length 6.6
  TOP w0.14: v2(60.48,75.15) 60.67,75.15 v4(61.33,74.49)
  BOTTOM w0.089: 67.25,77.25 67.48,77.48 68,77.48 68.3,77.78 RP4.7
  BOTTOM w0.14: 67.25,77.25 67.23,77.23 67.23,76.88 67.04,76.69 v2(67.04,76.46) ; UH8.5 59.28,73.3 60.55,74.57 60.55,75.08 v2(60.48,75.15)
PCH_SPI_SI_TPM: length 10.8
  TOP w0.14: v2(145.52,79.01) 145.52,78.31 144.94,77.73 144.33,77.73 144.07,77.47 v1(144.07,76.95) 144.53,76.49 144.53,75.63 146.1,74.06 RE114.1 ; RH578.1 68.57,76.82 67.94,77.45 67.53,77.45 67.13,77.85 67.13,78.4 67.44,78.71 v2(67.91,78.71)
PCH_SPI_SI_TPM_R: length 2.2
  TOP w0.14: U32.21 148.62,74.19 148.49,74.06 v1(148.17,74.06) RE114.2
PCH_SPI_SO: length 10.9
  TOP w0.089: v2(75.45,74.83) 75.32,74.83 74.57,75.58 72.93,75.58 72.69,75.82 72.31,75.82 71.29,76.84 71.29,76.98 71.16,77.1 v2(71.08,77.1) 71.04,77.07
  TOP w0.14: 71.04,77.07 70.82,76.85 70.82,76.45 70.52,76.14 69.99,76.14 69.63,75.78 RH579.2
  BOTTOM w0.089: UH2.BA45 75.16,74.54 v2(75.45,74.83) ; v2(71.08,77.1) 71.04,77.1
  BOTTOM w0.14: 71.04,77.1 70.23,77.1 69.97,77.37 69.74,77.37 RP4.3 ; JSPI1.3 112.33,72.93 112.55,72.71 v2(112.55,72.25)
PCH_SPI_SO_R: length 3.7
  TOP w0.14: v4(67.6,76.31) 67.6,76.93 v2(67.68,77.01)
  BOTTOM w0.089: RP4.6 68.41,77.37 68.25,77.37 67.89,77.01 v2(67.68,77.01) 67.61,76.94 67.61,76.37 67.37,76.13
  BOTTOM w0.14: 66.54,75.84 67.08,75.84 67.37,76.13
PCH_SPI_SO_TPM: length 8.8
  TOP w0.14: v3(144.01,76.37) 144.05,76.33 144.05,75.5 145.71,73.84 145.71,73.21 146.15,72.77 v1(146.15,72.1) 146.15,71.64 146.91,70.88 RE113.1 ; RH579.1 68.69,75.77 68.21,75.3 67.07,75.3 v2(66.98,75.21)
PCH_SPI_SO_TPM_R: length 3.1
  TOP w0.14: U32.24 149.23,72.69 148.96,72.42 148.96,71.27 v1(148.58,70.88) RE113.2
PCH_SPI_WP#: length 9.1
  TOP w0.14: v2(70.3,75.64) 70.3,75.38 69.87,74.95 RH573.2 ; v2(70.39,76.68) 70.55,76.84 v1(70.55,77.16) 70.55,77.19 71.11,77.74 RH75.2
  BOTTOM w0.089: 71.72,75.05 72,75.05 72.25,74.8 73.81,74.8 UH2.AY48
  BOTTOM w0.14: RP4.4 69.74,76.87 69.93,76.87 70.11,76.68 v2(70.39,76.68) ; v2(70.3,75.64) 70.36,75.58 71.19,75.58 71.72,75.05 ; JSPI1.6 110.83,72.91 110.3,72.37 v2(110.3,72.25)
PCH_SPI_WP#_R: length 3.7
  BOTTOM w0.089: 67.74,76.11 67.8,76.17 67.8,76.55 68.02,76.78 RP4.5
  BOTTOM w0.14: UH8.3 66.71,74.73 67.21,74.73 67.61,75.14 v1(67.61,75.28) 67.54,75.36 67.54,75.91 67.74,76.11
PCH_SPI_WP#_XDP: length 45.3
  TOP w0.14: v2(67.37,74.29) 67.51,74.43 68.19,74.43 68.68,74.92 RH573.1 ; v2(81.08,99.84) 83.47,97.45 101.7,97.45 104.16,99.91 104.16,104.39 106.3,106.53 106.3,107.83 v1(103.71,110.41) 103.11,111.02 v2(103.11,114.79) ; JXDP.60 118.73,167.2 v2(118.73,167.2)
  vias: v2(57.81,87.68)
PCH_SRTCRST#: length 3.2
  TOP w0.14: v2(69.81,72.52) 69.81,72.52 69.57,72.28 RH83.2 69.27,72.84 CH52.1 69.79,73.36 v1(70.57,73.36)
  BOTTOM w0.089: v2(74.34,73.05) 74.34,72.81 UH2.BD46
PCH_SYS_PWROK_XDP: length 20.5
  TOP w0.089: RH489.2 72.92,76.04 72.34,76.04 71.96,76.42 71.96,76.73 v2(71.97,76.74) 71.66,76.74 71.5,76.9 71.5,77.63 RH493.2
  TOP w0.14: JXDP.47 123.6,164.2 v2(123.31,163.91)
  BOTTOM w0.14: v2(123.31,163.91) 123.86,163.91 RH490.2 ; v2(68.38,98.44) 68.21,98.44 67.21,97.44 67.21,92.97 66.39,92.15 64.05,92.15 63.14,91.24 63.14,89.56 v2(63.02,89.44)
  vias: v2(102.36,102.89)
PCH_TBT_PERST#: length 5.8
  BOTTOM w0.089: UT1.L4 24.1,110.49 v6(23.82,110.77)
  BOTTOM w0.14: RT435.2 14.55,115.21 14.91,115.21 v1(15.42,114.7) ; RT435.2 14.27,114.91 13.98,114.91 13.77,114.7 13.77,113.47 RT5855.2 ; RT435.2 14.43,114.93 14.84,114.51 v2(14.84,113.84)
PCH_TP_BALL: length 1.3
  TOP w0.089: v2(79.86,78.78) 80.12,78.52 T4947.1
  BOTTOM w0.089: v2(79.86,78.78) 80.12,79.04 UH2.AL35
PCH_TRIGGER: length 6.6
  TOP w0.14: RH167.1 177.34,128.33 178.09,127.59 v2(178.09,125.13)
  BOTTOM w0.089: UH2.AK3 95.84,79.44 96.34,79.44 96.51,79.28 97.07,79.28 97.45,79.66 v2(97.66,79.66)
  vias: v2(105.38,84.19)
PCH_TRIGGER_R: length 3
  TOP w0.14: RH167.2 177.48,129.86 177.98,130.36 179.14,130.36 v2(179.49,130.71)
  BOTTOM w0.076: v2(171.62,142.66) 171.24,143.04 UH1.H23
PCH_XDP_CLK_N: length 5.6
  TOP w0.152: JXDP.42 121.52,162.7 121.69,162.53 123.2,162.53 123.78,161.95 v2(123.78,161.34)
  BOTTOM w0.089: UH2.Y3 95.77,84.44 95.77,84.21 95.26,83.7 v2(95.26,83.59)
PCH_XDP_CLK_P: length 5.1
  TOP w0.152: v2(123.15,161.34) 123.18,161.34 123.43,161.58 123.43,161.83 123.06,162.2 JXDP.40
  BOTTOM w0.089: UH2.Y4 95.4,84.34 95.4,84.22 95.15,83.97 95,83.97 94.69,83.66 v2(94.69,83.65)
PCI_CLK_LPC1: length 3.1
  TOP w0.089: RH428.1 82.97,73.18 v1(82.47,73.67) 82.15,73.99 81.77,73.99 v2(81.56,74.2)
  BOTTOM w0.089: v2(81.56,74.2) 81.31,74.2 81.29,74.17 81.26,74.17 80.88,73.8 UH2.BB34
PCI_CLK_LPC1_R: length 0.9
  TOP w0.089: T4945.1 82.15,72.24 RH428.2
PCIE_PRX_C_DTX_N5: length 1.9
  BOTTOM w0.152: UR1.8 336.34,101.78 335.86,101.3 335.86,101.02 CR13.2
PCIE_PRX_C_DTX_P5: length 1.9
  BOTTOM w0.152: CR10.2 336.19,100.96 336.19,101.16 336.67,101.64 336.67,101.82 336.74,101.89 UR1.7
PCIE_PRX_C_TTX_N17: length 7.4
  BOTTOM w0.089: UT1.V22 27.56,101.99 27.78,101.76 27.78,101.38 28.26,100.89 28.75,100.89 29.64,100.01 29.64,99.75 30.3,99.09 30.4,99.09 30.41,99.07
  BOTTOM w0.152: 30.41,99.07 v5(30.56,98.93) 30.74,98.75 32.03,98.75 32.18,98.9 32.84,98.9 32.84,98.9 CT181.2
PCIE_PRX_C_TTX_N18: length 3.3
  BOTTOM w0.089: UT1.P22 25.95,101.76 25.95,101.76 25.96,101.75 25.96,101.22 26.52,100.65 27.06,100.65 27.5,100.22 27.5,99.97 CT180.2
PCIE_PRX_C_TTX_N19: length 3
  BOTTOM w0.089: CT7.2 24.93,100.13 24.53,100.52 24.26,100.52 24.03,100.76 24.03,101.23 24.12,101.32 24.12,101.75 24.11,101.76 24.11,101.76 UT1.K22
PCIE_PRX_C_TTX_N20: length 2.5
  BOTTOM w0.089: UT1.F22 22.27,101.76 22.27,101.76 22.28,101.75 22.28,100.69 22.69,100.27 22.69,99.96 CT3.2
PCIE_PRX_C_TTX_P17: length 7.4
  BOTTOM w0.089: 30.18,98.84 30.16,98.86 30.16,98.96 29.45,99.67 29.45,99.93 28.67,100.7 28.16,100.7 27.56,101.31 UT1.V23
  BOTTOM w0.152: 30.18,98.84 30.33,98.7 30.6,98.42 v5(31.9,98.42) 32.16,98.42 32.31,98.57 32.98,98.57 CT179.2
PCIE_PRX_C_TTX_P18: length 3.3
  BOTTOM w0.089: UT1.P23 25.72,101.61 25.65,101.68 25.56,101.68 25.48,101.61 25.48,101.32 26.41,100.38 26.95,100.38 27.23,100.11 27.23,99.96 CT178.2
PCIE_PRX_C_TTX_P19: length 2.9
  BOTTOM w0.089: CT5.2 24.64,100.04 24.42,100.26 24.15,100.26 23.76,100.65 23.76,101.19 23.63,101.32 23.63,101.7 23.68,101.74 23.81,101.74 23.88,101.67 UT1.K23
PCIE_PRX_C_TTX_P20: length 2.5
  BOTTOM w0.089: CT1.2 22.42,99.98 22.42,100.16 22.01,100.58 22.01,101.11 21.8,101.32 21.8,101.61 21.88,101.68 21.97,101.68 22.04,101.61 UT1.F23
PCIE_PRX_DTX_N1: length 2.1
  BOTTOM w0.089: UH2.G17 89.12,90.73 v2(89.32,90.52)
  BOTTOM w0.152: v2(336.75,152.55) 336.68,152.47 336.68,152.02 336.82,151.88 JNGFF1.35
  vias: v2(262.44,81.55)
PCIE_PRX_DTX_N5: length 8.7
  BOTTOM w0.089: v2(88.03,91.03) 87.9,90.91 87.7,90.91 87.57,91.04 87.44,91.04 87.35,91.12 87.35,91.39 87.45,91.49 UH2.F20
  BOTTOM w0.152: CR13.1 335.58,99.76 336.14,99.2 336.14,98.97 335.97,98.8 333.11,98.8 331.56,100.34 331.56,100.92 v2(331.86,101.21)
PCIE_PRX_DTX_N09: length 2.4
  BOTTOM w0.089: UH2.G36 79.65,90.85 79.65,91.03 v2(79.83,91.22)
  BOTTOM w0.152: JNGFF2.5 257.56,88.74 257.39,88.57 256.88,88.57 256.67,88.77 v2(256.64,88.77)
PCIE_PRX_DTX_N10: length 1.9
  BOTTOM w0.089: UH2.K37 79.41,89.35 v2(79.69,89.63)
  BOTTOM w0.152: JNGFF2.17 257.5,85.74 257.45,85.79 257.07,85.79 v2(256.98,85.88)
PCIE_PRX_DTX_N11: length 3.1
  BOTTOM w0.089: UH2.G38 78.3,90.49 78.3,90.39 v2(78.47,90.21)
  BOTTOM w0.152: JNGFF2.29 257.54,82.74 257.43,82.85 256.91,82.85 256.53,82.46 256.53,82.21 v2(256.37,82.06)
PCIE_PRX_DTX_P1: length 2.1
  BOTTOM w0.089: v2(89.63,90.99) UH2.F16
  BOTTOM w0.152: JNGFF1.33 336.32,151.99 336.35,152.02 336.35,152.37 v2(336.17,152.55)
  vias: v2(262.44,82.14)
PCIE_PRX_DTX_P5: length 8.7
  BOTTOM w0.089: UH2.G20 v2(88.03,90.45)
  BOTTOM w0.152: v2(331.23,101.21) 331.23,100.21 332.98,98.47 v5(334.3,98.47) 336.1,98.47 336.47,98.84 CR10.1
PCIE_PRX_DTX_P09: length 2.3
  BOTTOM w0.089: UH2.F36 79.28,91.27 79.28,90.94 v2(79.17,90.84)
  BOTTOM w0.152: JNGFF2.7 256.69,88.24 v2(256.64,88.19)
PCIE_PRX_DTX_P10: length 2.1
  BOTTOM w0.089: v2(79.5,90.26) 79.21,89.98 79.11,89.98 UH2.J37
  BOTTOM w0.152: v2(256.98,85.29) 257.15,85.46 257.31,85.46 257.53,85.24 JNGFF2.19
PCIE_PRX_DTX_P11: length 2.6
  BOTTOM w0.089: UH2.F39 v2(78,90.71)
  BOTTOM w0.152: v2(257.01,82.06) 256.86,82.21 256.86,82.32 257.05,82.52 257.29,82.52 257.57,82.24 JNGFF2.31
PCIE_PRX_TTX_N17: length 1.5
  BOTTOM w0.089: v2(76.21,89.8) 76.21,89.56 UH2.K43
  BOTTOM w0.152: v2(34.53,99.48) 34,98.95 CT181.1
PCIE_PRX_TTX_N18: length 1.9
  BOTTOM w0.089: v2(77.38,88.54) 77,88.16 77,87.67 UH2.P41
  BOTTOM w0.152: CT180.1 27.51,99.07 27.51,98.77 v2(27.65,98.63)
PCIE_PRX_TTX_N19: length 1.6
  BOTTOM w0.089: v2(75.77,87.68) 76.03,87.94 76.03,88.11 75.89,88.25 UH2.M44
  BOTTOM w0.152: CT7.1 25.07,99.09 25.07,98.79 v2(25.22,98.64)
PCIE_PRX_TTX_N20: length 1.5
  BOTTOM w0.089: v2(79.6,86.35) 79.62,86.37 79.62,86.47 UH2.R35
  BOTTOM w0.152: v2(22.83,98.65) 22.72,98.76 22.72,99.11 CT3.1
PCIE_PRX_TTX_P17: length 1.5
  BOTTOM w0.089: v2(75.95,89.27) 75.95,89.45 UH2.K44
  BOTTOM w0.152: CT179.1 33.92,98.57 34.09,98.57 34.37,98.85 v2(34.53,98.85)
PCIE_PRX_TTX_P18: length 1.6
  BOTTOM w0.089: UH2.R40 77.83,87.7 v2(77.54,87.99)
  BOTTOM w0.152: v2(27.06,98.63) 27.18,98.75 27.18,99.11 CT178.1
PCIE_PRX_TTX_P19: length 1.2
  BOTTOM w0.089: v2(76.32,87.63) 76.32,87.88 UH2.N42
  BOTTOM w0.152: CT5.1 24.74,99.11 24.74,98.75 v2(24.64,98.64)
PCIE_PRX_TTX_P20: length 1.4
  BOTTOM w0.089: UH2.R37 79.33,86.84 78.92,86.43 v2(78.92,86.37)
  BOTTOM w0.152: v2(22.25,98.65) 22.39,98.78 22.39,99.11 CT1.1
PCIE_PTX_C_DRX_N1: length 14.2
  BOTTOM w0.152: JNGFF1.29 335.32,151.94 335.22,152.04 335.22,152.59 334.04,153.77 330.27,153.77 329.34,152.83 v5(329.34,149.67) 329.34,149.47 330.28,148.53 330.28,147.9 330.17,147.8 329.83,147.8 CN20.2
PCIE_PTX_C_DRX_N5: length 1.9
  BOTTOM w0.152: UR1.4 337.94,101.88 338.01,101.81 338.01,101.55 338.51,101.06 338.51,100.93 CR9.2
PCIE_PTX_C_DRX_N09: length 2.6
  BOTTOM w0.152: CD43.2 256.02,87.15 257.23,87.15 257.31,87.24 JNGFF2.11
PCIE_PTX_C_DRX_N10: length 2.8
  BOTTOM w0.152: JNGFF2.23 257.54,84.24 257.42,84.12 255.85,84.12 CD45.2
PCIE_PTX_C_DRX_N11: length 3
  BOTTOM w0.152: CD53.2 255.64,81.15 257.16,81.15 257.24,81.24 JNGFF2.35
PCIE_PTX_C_DRX_P1: length 14.2
  BOTTOM w0.152: CN21.2 329.67,147.07 329.67,147.34 329.79,147.47 330.31,147.47 330.61,147.76 330.61,148.67 329.67,149.61 329.67,152.7 330.41,153.44 333.9,153.44 334.89,152.46 334.89,152.04 334.82,151.97 JNGFF1.27
PCIE_PTX_C_DRX_P5: length 1.9
  BOTTOM w0.152: CR7.2 338.84,100.98 338.84,101.19 338.34,101.69 UR1.3
PCIE_PTX_C_DRX_P09: length 2.6
  BOTTOM w0.152: JNGFF2.13 257.31,86.74 257.23,86.82 256.09,86.82 CD44.2
PCIE_PTX_C_DRX_P10: length 2.8
  BOTTOM w0.152: JNGFF2.25 257.5,83.74 257.45,83.79 255.96,83.79 CD46.2
PCIE_PTX_C_DRX_P11: length 3
  BOTTOM w0.152: CD51.2 255.66,80.82 257.16,80.82 257.24,80.74 JNGFF2.37
PCIE_PTX_C_TRX_N17: length 4.6
  BOTTOM w0.076: UT1.Y22 28.69,101.78 28.69,101.4 28.84,101.24 29.06,101.24 29.57,100.73 30.08,100.73 30.37,100.44 30.46,100.44
  BOTTOM w0.152: CT177.1 31.8,100.04 31.8,100.04 v5(31.18,100.04) 30.86,100.04 30.46,100.44
PCIE_PTX_C_TRX_N18: length 3.6
  BOTTOM w0.089: UT1.T22 26.85,101.77 26.85,101.28 26.96,101.17 27.31,101.17 27.95,100.52 28.43,100.52 28.75,100.2 28.75,99.96 CT174.1
PCIE_PTX_C_TRX_N19: length 3
  BOTTOM w0.089: CT8.1 26.32,99.94 26.32,100.19 25.4,101.11 25.14,101.11 25.04,101.22 25.04,101.75 25.03,101.76 25.03,101.76 UT1.M22
PCIE_PTX_C_TRX_N20: length 2.7
  BOTTOM w0.089: CT4.1 23.91,99.89 23.91,100.18 23.51,100.58 23.51,100.94 23.2,101.25 23.2,101.75 23.19,101.76 23.19,101.76 UT1.H22
PCIE_PTX_C_TRX_P17: length 4.5
  BOTTOM w0.076: UT1.Y23 28.48,101.36 28.77,101.06 28.98,101.06 29.49,100.56 30.01,100.56 30.23,100.34 30.23,100.22
  BOTTOM w0.152: CT176.1 31.84,99.71 30.73,99.71 30.23,100.21 30.23,100.22
PCIE_PTX_C_TRX_P18: length 3.6
  BOTTOM w0.089: CT175.1 28.48,99.94 28.48,100.09 28.32,100.26 27.84,100.26 27.19,100.9 26.85,100.9 26.4,101.36 26.4,101.64 26.45,101.69 26.57,101.69 26.64,101.63 UT1.T23
PCIE_PTX_C_TRX_P19: length 3
  BOTTOM w0.089: CT6.1 26.05,99.97 26.05,100.08 25.29,100.84 25.03,100.84 24.56,101.32 24.56,101.61 24.64,101.68 24.73,101.68 24.8,101.61 UT1.M23
PCIE_PTX_C_TRX_P20: length 2.7
  BOTTOM w0.089: UT1.H23 22.96,101.61 22.89,101.68 22.8,101.68 22.72,101.61 22.72,101.35 23.24,100.83 23.24,100.47 23.65,100.07 23.65,99.9 CT2.1
PCIE_PTX_DRX_N1: length 1.5
  BOTTOM w0.089: UH2.A17 88.89,94 v2(89.27,94.38)
  BOTTOM w0.152: CN20.1 328.89,147.54 328.68,147.54 v2(328.5,147.72)
  vias: v2(263.94,83.48)
PCIE_PTX_DRX_N5: length 38.9
  BOTTOM w0.089: UH2.B21 86.88,93.42 87.19,93.73 87.8,93.73 v2(87.94,93.59)
  BOTTOM w0.152: v2(309.43,105.07) 309.58,104.92 310.18,104.92 310.49,105.22 310.49,105.69 311.7,106.9 326.75,106.9 328.09,105.56 328.09,103.23 329.87,101.45 329.87,100.38 332.45,97.8 336.65,97.8 337.69,98.84 338.47,98.84 338.63,99 338.63,99.53 338.4,99.76 CR9.1
PCIE_PTX_DRX_N09: length 6.9
  BOTTOM w0.089: v2(80.12,93.81) 80.28,93.66 80.28,93.34 80.43,93.19 80.43,92.73 UH2.C34
  BOTTOM w0.152: v2(251.65,83.94) 251.82,83.94 251.99,84.12 251.99,85.5 252.72,86.23 253.35,86.23 253.57,86.44 254.27,86.44 254.39,86.56 254.39,86.92 CD43.1
PCIE_PTX_DRX_N10: length 4
  BOTTOM w0.089: v2(79.49,95) 79.49,93.62 79.65,93.38 79.82,93.21 79.82,93.19 79.84,93.18 79.84,92.74 UH2.C35
  BOTTOM w0.152: v2(254.25,85.07) 254.17,84.99 254.17,84.34 254.33,84.18 254.54,84.18 CD45.1
PCIE_PTX_DRX_N11: length 4
  BOTTOM w0.089: UH2.B36 79.29,93.02 79.23,92.97 79.15,92.81 79.15,92.67 v2(79.32,92.3)
  BOTTOM w0.152: v2(253.25,82.05) 253.02,82.05 252.89,81.92 252.89,81.47 253.49,80.87 253.94,80.87 254.46,81.39 CD53.1
PCIE_PTX_DRX_P1: length 1.4
  BOTTOM w0.089: UH2.B17 89.08,93.61 v2(89.29,93.82)
  BOTTOM w0.152: v2(328.5,147.06) 328.65,147.21 328.94,147.21 CN21.1
  vias: v2(263.94,82.9)
PCIE_PTX_DRX_P5: length 39.5
  BOTTOM w0.089: v2(87.97,94.18) 87.71,93.92 87.11,93.92 86.98,93.79 86.81,93.79 UH2.A22
  BOTTOM w0.152: v2(309.43,104.44) 309.58,104.59 310.32,104.59 310.82,105.09 310.82,105.56 311.84,106.57 326.61,106.57 327.76,105.42 327.76,103.09 329.54,101.31 329.54,100.24 332.31,97.47 v5(332.93,97.47) 336.79,97.47 337.83,98.51 338.61,98.51 338.96,98.87 338.96,99.5 CR7.1
PCIE_PTX_DRX_P09: length 7.1
  BOTTOM w0.089: v2(80.7,93.79) 80.54,93.63 80.54,93.45 80.7,93.3 80.7,92.53 80.54,92.38 UH2.D34
  BOTTOM w0.152: v2(251.65,83.36) 251.7,83.36 252.32,83.98 252.32,85.36 252.86,85.9 253.49,85.9 253.7,86.11 254.4,86.11 254.8,86.51 CD44.1
PCIE_PTX_DRX_P10: length 4.4
  BOTTOM w0.089: UH2.B35 80.09,93.32 79.86,93.55 79.75,93.7 79.75,94.74 80.01,95 v2(80.06,95)
  BOTTOM w0.152: v2(253.62,85.07) 253.71,85.07 253.84,84.95 253.84,84.2 254.19,83.85 254.57,83.85 254.71,83.7 CD46.1
PCIE_PTX_DRX_P11: length 4.1
  BOTTOM w0.089: v2(79.65,91.85) 79.75,91.95 79.75,92.46 UH2.C36
  BOTTOM w0.152: CD51.1 253.35,80.54 252.56,81.33 252.56,81.95 v2(252.46,82.05)
PCIE_PTX_TRX_N17: length 2.9
  BOTTOM w0.089: UH2.A42 76.79,93.83 76.79,93.78 76.71,93.7 76.51,93.7 76.41,93.79 76.41,94.56 76.5,94.65 76.75,94.65 76.83,94.56 v2(76.83,94.42)
  BOTTOM w0.152: v2(33.32,100.13) 33.12,99.93 32.77,99.93 CT177.2
PCIE_PTX_TRX_N18: length 4.8
  BOTTOM w0.076: UH2.C42 76.52,92.76 76.57,92.7 76.65,92.7 76.8,92.85 76.8,93.48 77.17,93.85 77.17,93.91 77.19,93.93
  BOTTOM w0.089: 77.19,93.93 77.26,94 77.26,94.66 77.63,95.04 77.63,95.37 77.73,95.46 v2(78.16,95.46)
  BOTTOM w0.152: CT174.2 28.99,99.21 29.47,98.73 v2(29.47,98.64)
PCIE_PTX_TRX_N19: length 1.4
  BOTTOM w0.089: UH2.C44 75.92,92.72 75.8,92.6 75.67,92.6 v2(75.53,92.74)
  BOTTOM w0.152: v2(26.43,98.62) 26.32,98.72 26.32,99.09 CT8.2
PCIE_PTX_TRX_N20: length 2.4
  BOTTOM w0.089: UH2.A44 75.61,93.78 75.48,93.64 75.39,93.64 75.33,93.7 75.33,94.05 75.2,94.18 75.2,94.34 75.31,94.45 75.48,94.45 v2(75.57,94.37)
  BOTTOM w0.152: v2(24.05,98.62) 23.86,98.82 23.86,99.08 23.94,99.17 CT4.2
PCIE_PTX_TRX_P17: length 3.1
  BOTTOM w0.089: UH2.B42 76.53,93.43 76.4,93.43 76.15,93.68 76.15,94.67 76.39,94.91 76.75,94.91 v2(76.84,95)
  BOTTOM w0.152: CT176.2 32.66,99.6 33.23,99.6 v2(33.32,99.5)
PCIE_PTX_TRX_P18: length 4.1
  BOTTOM w0.076: 77.52,94 77.52,93.95 76.98,93.41 76.98,92.78 UH2.D42
  BOTTOM w0.089: 77.52,94 77.52,94.55 77.85,94.88 v2(78.13,94.88)
  BOTTOM w0.152: CT175.2 28.33,99.13 28.83,98.64 v2(28.88,98.64)
PCIE_PTX_TRX_P19: length 1.2
  BOTTOM w0.089: UH2.D43 76.09,92.44 v2(75.7,92.2)
  BOTTOM w0.152: CT6.2 25.99,99.11 25.99,98.77 v2(25.84,98.62)
PCIE_PTX_TRX_P20: length 2.5
  BOTTOM w0.089: v2(75.57,94.99) 75.93,94.62 75.93,93.72 UH2.B44
  BOTTOM w0.152: CT2.2 23.53,99.13 23.53,98.68 v2(23.47,98.62)
PCIE_RCOMPN: length 3.4
  TOP w0.14: v1(91.78,95.96) v2(91.33,95.51)
  TOP w0.381: RH108.1 90.72,95.51 v2(91.33,95.51)
  BOTTOM w0.089: 91.31,94.51 91.31,93.44 UH2.B12
  BOTTOM w0.14: 91.31,94.51 91.31,94.62 91.33,94.67
  BOTTOM w0.381: 91.33,94.67 v2(91.33,95.51)
PCIE_RCOMPP: length 2.1
  TOP w0.089: v1(90.79,93.95) 90.56,94.18 v2(90.56,94.51)
  TOP w0.381: v2(90.56,94.51) 90.56,94.77 RH108.2
  BOTTOM w0.178: UH2.A13 90.56,94.43 v2(90.56,94.51)
PCIE_WAKE#: length 25.2
  TOP w0.14: RT5849.1 69.74,71.06 69.97,70.82 70.27,70.82 70.5,70.59 70.5,70.33 v2(70.57,70.26) ; RD59.2 266.31,75.4 v1(268.24,75.4) 268.5,75.4 269.24,76.14 v2(269.24,76.22)
  BOTTOM w0.14: RE323.1 RE322.2 303.6,95.28 303.08,94.76 303.08,92.85 303.87,92.05 303.87,90.5 v2(302.95,89.57) ; JNGFF1.47 339.82,151.96 339.91,152.06 339.91,153.03 340.3,153.42 340.3,154.98 339.47,155.82 338.71,155.82 338.28,155.39 333.22,155.39 v2(332.6,154.77)
  vias: v2(104.69,72.56)
PCIE_WAKE#_R: length 13.2
  TOP w0.14: UE3.N13 302.44,87.78 302.44,89.66 v2(303.43,90.66) 303.87,90.66 RE19.1
  BOTTOM w0.14: RE323.2 302.86,97.06 v1(302.3,96.5) 302.3,94.8 302.63,94.46 302.63,91.45 v2(303.43,90.66)
PD_DEBUG_CTRL1: length 3.1
  TOP w0.14: v2(19.42,124.25) 19.39,124.25 18.97,124.67 18.97,126.13 19.01,126.17 RT226.2
  BOTTOM w0.081: v2(19.42,124.25) 19.44,124.22 19.72,124.22 UT4.E4
PD_DEBUG_CTRL2: length 4.7
  TOP w0.14: RT227.2 23.2,127.11 22.63,127.68 22.63,128.31 22.44,128.5 22.44,128.86 v1(21.97,129.33) 21.54,129.76 v2(20.88,129.76)
  BOTTOM w0.081: UT4.D5 20.29,123.57 v2(19.94,123.22)
PD_EE_CLK: length 3.2
  TOP w0.14: v1(45.64,93.19) 44.91,93.92 v2(44.91,93.93) 44.9,93.92 UT5.6
  BOTTOM w0.081: 19.52,121.14 19.3,121.36 19.3,121.99 UT4.A3
  BOTTOM w0.14: 19.52,121.14 v2(19.61,121.05)
PD_EE_CS#: length 5.9
  TOP w0.14: UT5.1 37.26,96.46 v2(36.69,97.04)
  BOTTOM w0.081: UT4.B3 19.63,122.32 19.63,121.87 20.07,121.43 20.07,121.14
  BOTTOM w0.14: v2(19.28,118.97) 19.23,119.02 19.23,120.11 19.35,120.24 19.48,120.24 RT168.2 19.61,120.44 20.07,120.9 20.07,121.14
PD_EE_DI: length 3
  TOP w0.14: UT5.5 44.7,92.65 v2(44.93,92.88) 45.16,92.65 v1(45.16,91.78)
  BOTTOM w0.081: v2(19.36,123.14) 19.36,123.08 UT4.B4
PD_EE_DO: length 5.9
  TOP w0.14: v2(36.67,95.23) 38.03,95.23 UT5.2
  BOTTOM w0.14: UT4.A4 20.17,121.77 20.17,121.63 20.35,121.46 20.35,120.67 20.24,120.57 RT169.2 20.47,120.36 20.68,120.16 20.68,119.05 20.39,118.77 20.07,118.77 v2(19.95,118.65)
PD_EE_WP#: length 8.4
  TOP w0.14: RT170.2 23.85,126.73 v2(23.85,127.06) ; v2(37.05,100.08) 37.11,100.02 38.01,100.02 v1(38.16,99.86) 38.66,99.37 38.66,96.85 38.82,96.69 38.82,94.67 UT5.3
PD_GPIO2: length 3.4
  TOP w0.14: RT437.1 24.7,122.83 24.49,123.04 v2(24.49,123.34) 24.3,123.34 v1(24,123.63)
  BOTTOM w0.081: UT4.D10 23.13,123.82 24,123.82 24.32,123.5
  BOTTOM w0.14: 24.32,123.5 v2(24.49,123.34)
PD_HOLD#: length 2.4
  TOP w0.14: v1(45.64,94.57) 45.64,95.03 RT171.2 44.83,95.41 44.62,95.19 UT5.7
PD_PGPIO7: length 2.9
  TOP w0.14: RT182.1 22.86,122.14 v1(22.2,122.14) 21.68,122.66 v2(21.68,123.11)
  BOTTOM w0.081: v2(21.68,123.11) 21.68,123.27 UT4.D7
PD_PMRESET: length 4.1
  TOP w0.14: RT186.1 RT245.1 ; RT245.1 24.57,124.1 v2(24.43,123.96) ; RT245.1 25.03,124.17 25.33,124.47 26.35,124.47 v1(26.49,124.33)
  BOTTOM w0.081: 24.32,124.02 23.53,124.02 23.49,124.07 UT4.E11
  BOTTOM w0.14: v2(24.43,123.96) 24.37,124.02 24.32,124.02
PD_SS: length 2.1
  TOP w0.14: v1(21.47,126.69) v2(21.47,126.07) 21.47,126.01 CT158.1
  BOTTOM w0.081: v2(21.47,126.07) 21.38,125.98 UT4.H7
PD_VDDIO_VIN_3V3: length 5.3
  BOTTOM w0.254: UT4.H1 18.04,125.57 17.73,125.88 17.4,125.88 17.35,125.82 16.89,125.82 v2(16.87,125.8) ; RT1095.2 15.63,121.51 17.22,121.51 v2(17.47,121.75) 17.51,121.75 18.33,122.57 UT4.B1
PECI_EC_R: length 8.7
  TOP w0.076: 299.26,87.52 299.26,87 UE3.K13
  TOP w0.14: v1(302.95,91.01) CE39.1 RE48.1 301.93,91.93 301.1,91.1 300.94,91.1 300.15,90.31 300.15,88.92 299.95,88.72 299.57,88.72 299.26,88.41 299.26,87.52
PEG_GTX_C_HRX_N0: length 17.3
  TOP w0.076: v2(173.57,132.43) 173.43,132.43 173.29,132.28 173.29,132.13 173.38,132.05 173.69,132.05 173.88,132.24 174.13,132.24 174.31,132.06 175.06,132.06 175.77,131.35 177.88,131.35 177.97,131.26 177.99,131.26
  TOP w0.152: 177.99,131.26 v5(185.5,131.26) 187.12,131.26 188.05,132.2 188.41,132.2 CV819.2
  BOTTOM w0.076: UH1.E10 v2(173.57,132.43)
PEG_GTX_C_HRX_N1: length 18.1
  TOP w0.076: 177.78,132.1 177.76,132.1 177.67,132.19 175.84,132.19 175.35,132.68 174.58,132.68 174.42,132.84 174.11,132.84 173.72,133.22 v2(173.53,133.22)
  TOP w0.152: CV821.2 190.15,133.12 187.66,133.12 186.64,132.1 v5(183.1,132.1) 177.78,132.1
  BOTTOM w0.076: UH1.E11 v2(173.53,133.22)
PEG_GTX_C_HRX_N2: length 17.5
  TOP w0.076: 177.87,133.4 177.85,133.4 177.76,133.31 175.92,133.31 175.4,133.83 173.83,133.83 173.24,134.43 173.03,134.43 172.92,134.54 v2(172.92,134.79)
  TOP w0.152: CV823.2 188.49,134.56 187.07,134.56 185.91,133.4 v5(184.24,133.4) 177.87,133.4
  BOTTOM w0.076: v2(172.92,134.79) 172.92,134.72 UH1.E12
PEG_GTX_C_HRX_N3: length 18.4
  TOP w0.076: 178.65,133.96 178.63,133.96 178.54,134.05 177.57,134.05 177.38,133.86 176.05,133.86 175.68,134.23 173.99,134.23 173.76,134.46 173.76,134.57 v2(173.53,134.79)
  TOP w0.152: 178.65,133.96 v5(182.56,133.96) 185.69,133.96 186.92,135.2 190.11,135.2 CV825.2
  BOTTOM w0.076: v2(173.53,134.79) 173.53,134.83 173.24,135.12 UH1.E13
PEG_GTX_C_HRX_N4: length 18
  TOP w0.076: v2(172.92,135.58) 172.92,135.88 173.01,135.97 173.19,135.97 173.28,135.88 173.28,135.47 173.41,135.34 175.14,135.34 175.49,134.99 176.85,134.99 177.14,135.28 177.83,135.28 177.92,135.37 177.94,135.37
  TOP w0.152: CV827.2 188.45,136.56 186.62,136.56 185.43,135.37 v5(184.45,135.37) 177.94,135.37
  BOTTOM w0.076: v2(172.92,135.58) 172.92,135.75 173.14,135.97 UH1.E14
PEG_GTX_C_HRX_N5: length 18.5
  TOP w0.076: v2(173.52,136.36) 173.68,136.36 173.74,136.3 173.74,136.06 173.93,135.86 175.73,135.86 176.07,135.51 176.64,135.51 177.09,135.97 177.64,135.97 177.73,135.88 177.75,135.88
  TOP w0.152: 177.75,135.88 185.03,135.88 186.31,137.16 v5(187.2,137.16) 190.18,137.16 CV829.2
  BOTTOM w0.076: v2(173.52,136.36) 173.52,136.42 173.24,136.69 UH1.E15
PEG_GTX_C_HRX_N6: length 17.5
  TOP w0.076: 177.09,137.13 177.07,137.13 176.98,137.04 176.38,137.04 176.24,136.91 173.89,136.91 173.17,137.63 173.01,137.63 172.92,137.72 v2(172.92,137.94)
  TOP w0.152: 177.09,137.13 v5(183.63,137.13) 184.33,137.13 185.76,138.57 188.43,138.57 CV831.2
  BOTTOM w0.076: v2(172.92,137.94) 172.92,137.87 UH1.E16
PEG_GTX_C_HRX_N7: length 18.6
  TOP w0.076: 177.46,137.63 177.44,137.63 177.35,137.72 176.89,137.72 176.71,137.91 176.23,137.91 175.72,137.39 174.05,137.39 173.77,137.67 173.77,137.87 173.7,137.94 v2(173.57,137.94)
  TOP w0.152: 177.46,137.63 183.9,137.63 185.46,139.19 v5(186.82,139.19) 190.18,139.19 CV833.2
  BOTTOM w0.076: UH1.E17 173.57,138.01 v2(173.57,137.94)
PEG_GTX_C_HRX_N8: length 18
  TOP w0.076: 178.22,138.63 178.2,138.63 178.11,138.72 177.66,138.72 177.45,138.52 174.04,138.52 173.83,138.3 172.77,138.3 172.64,138.36 v2(172.27,138.73)
  TOP w0.152: CV835.2 188.45,140.29 185.1,140.29 183.45,138.63 v5(182.32,138.63) 178.22,138.63
  BOTTOM w0.076: UH1.F18 172.59,139.05 v2(172.27,138.73)
PEG_GTX_C_HRX_N9: length 19.1
  TOP w0.076: 178.47,139.87 178.46,139.87 178.37,139.79 178.02,139.79 177.88,139.64 174.87,139.64 174.39,139.16 173.46,139.16 173.4,139.21 173.32,139.3 173.32,139.38 173.45,139.52 v2(173.61,139.52)
  TOP w0.152: 178.47,139.87 182.85,139.87 184.53,141.56 v5(187.43,141.56) 190.02,141.56 CV837.2
  BOTTOM w0.076: UH1.D19 173.73,139.91 173.61,139.78 v2(173.61,139.52)
PEG_GTX_C_HRX_N10: length 17.5
  TOP w0.076: v2(172.92,140.3) 173.23,140.62 173.34,140.62 173.72,140.23 177.59,140.23 178.02,140.67 178.17,140.67 178.26,140.58 178.28,140.58
  TOP w0.152: CV839.2 188.44,142.32 184.28,142.32 182.54,140.58 178.28,140.58
  BOTTOM w0.076: UH1.F20 172.92,140.37 v2(172.92,140.3)
PEG_GTX_C_HRX_N11: length 19.3
  TOP w0.076: v2(174.24,141.07) 174.03,141.07 173.96,141.14 173.96,141.35 174.09,141.48 176.48,141.48 176.57,141.39 176.59,141.39
  TOP w0.152: CV841.2 190.98,143.34 183.66,143.34 181.86,141.53 177.64,141.53 177.5,141.39 176.59,141.39
  BOTTOM w0.076: UH1.D21 174.24,141.13 v2(174.24,141.07)
PEG_GTX_C_HRX_N12: length 18.7
  TOP w0.076: 177.42,142.43 177.41,142.43 177.32,142.52 176.9,142.52 176.74,142.67 175.74,142.67 175.14,142.07 173.44,142.07 173.33,142.19 173.23,142.19 v2(172.92,141.88)
  TOP w0.152: 177.42,142.43 181.43,142.43 183.37,144.37 189.51,144.37 CV843.2
  BOTTOM w0.076: v2(172.92,141.88) 172.92,141.94 UH1.F22
PEG_GTX_C_HRX_N13: length 19.6
  TOP w0.076: v2(174.27,142.66) 173.99,142.66 173.92,142.74 173.92,142.97 174.24,143.29 176.83,143.29 176.94,143.4 177.36,143.4 177.45,143.31 177.47,143.31
  TOP w0.152: CV845.2 191.04,145.38 183.09,145.38 181.03,143.31 177.47,143.31
  BOTTOM w0.076: UH1.D23 174.27,142.69 v2(174.27,142.66)
PEG_GTX_C_HRX_N14: length 18.8
  TOP w0.076: 178.66,144.57 178.64,144.57 178.55,144.48 178.27,144.48 178.17,144.38 175.95,144.38 175.73,144.17 173.39,144.17 173.12,143.9 173.12,143.66 v2(172.92,143.45)
  TOP w0.152: CV847.2 189.54,146.66 v5(186.07,146.66) 182.42,146.66 180.33,144.57 178.66,144.57
  BOTTOM w0.076: UH1.F24 172.92,143.52 v2(172.92,143.45)
PEG_GTX_C_HRX_N15: length 19.8
  TOP w0.076: v2(174.27,145.01) 174.01,145.01 173.89,144.88 173.89,144.75 173.98,144.66 174.81,144.66 175.11,144.96 177.81,144.96 178.23,145.38 178.65,145.38 178.74,145.47 178.76,145.47
  TOP w0.152: CV849.2 191.07,147.68 v5(182.63,147.68) 181.93,147.68 179.72,145.47 178.76,145.47
  BOTTOM w0.076: UH1.D25 v2(174.27,145.01)
PEG_GTX_C_HRX_P0: length 17.3
  TOP w0.076: v2(172.92,132.43) 173.17,132.67 173.44,132.79 173.65,132.79 173.77,132.74 173.9,132.68 174.17,132.42 174.37,132.22 175.12,132.22 175.83,131.51 177.88,131.51 177.97,131.59 177.99,131.59
  TOP w0.152: CV818.2 188.49,132.53 187.92,132.53 186.99,131.59 177.99,131.59
  BOTTOM w0.076: UH1.F10 v2(172.92,132.43)
PEG_GTX_C_HRX_P1: length 18.1
  TOP w0.076: v2(174.26,133.22) 174.65,132.83 175.41,132.83 175.9,132.34 177.67,132.34 177.76,132.43 177.78,132.43
  TOP w0.152: 177.78,132.43 186.51,132.43 187.52,133.45 190.04,133.45 CV820.2
  BOTTOM w0.076: UH1.D11 173.89,133.81 173.98,133.9 174.13,133.9 174.26,133.77 174.26,133.51 174.29,133.48 174.29,133.25 v2(174.26,133.22)
PEG_GTX_C_HRX_P2: length 17.5
  TOP w0.076: 177.87,133.07 177.85,133.07 177.76,133.15 175.86,133.15 175.33,133.68 173.77,133.68 173.18,134.28 173,134.28 172.92,134.2 v2(172.92,134)
  TOP w0.152: CV822.2 188.4,134.23 187.21,134.23 186.04,133.07 v5(180.85,133.07) 177.87,133.07
  BOTTOM w0.076: v2(172.92,134) 172.87,134 172.59,134.28 UH1.F12
PEG_GTX_C_HRX_P3: length 18.4
  TOP w0.076: v2(174.25,134.8) 174.02,134.8 173.91,134.69 173.91,134.52 174.05,134.38 175.74,134.38 176.11,134.01 177.31,134.01 177.51,134.2 178.54,134.2 178.63,134.29 178.65,134.29
  TOP w0.152: 178.65,134.29 185.55,134.29 186.78,135.53 190.09,135.53 CV824.2
  BOTTOM w0.076: UH1.D13 173.89,135.12 174.21,134.8 v2(174.25,134.8)
PEG_GTX_C_HRX_P4: length 18
  TOP w0.076: v2(172.22,135.57) 172.59,135.19 175.07,135.19 175.43,134.83 176.91,134.83 177.2,135.13 177.83,135.13 177.92,135.04 177.94,135.04
  TOP w0.152: 177.94,135.04 185.57,135.04 186.76,136.23 188.44,136.23 CV826.2
  BOTTOM w0.076: v2(172.22,135.57) 172.59,135.94 UH1.F14
PEG_GTX_C_HRX_P5: length 18.5
  TOP w0.076: v2(174.25,136.38) 173.96,136.38 173.89,136.31 173.89,136.12 174,136.01 175.79,136.01 176.13,135.67 176.58,135.67 177.03,136.12 177.64,136.12 177.73,136.21 177.75,136.21
  TOP w0.152: CV828.2 190.02,137.49 186.17,137.49 184.89,136.21 177.75,136.21
  BOTTOM w0.076: UH1.D15 173.89,136.69 174.21,136.38 v2(174.25,136.38)
PEG_GTX_C_HRX_P6: length 17.5
  TOP w0.076: v2(172.92,137.15) 172.92,137.39 173.01,137.48 173.1,137.48 173.82,136.75 176.31,136.75 176.44,136.89 176.98,136.89 177.07,136.8 177.09,136.8
  TOP w0.152: 177.09,136.8 184.46,136.8 185.9,138.24 188.47,138.24 CV830.2
  BOTTOM w0.076: v2(172.92,137.15) 172.92,137.22 UH1.F16
PEG_GTX_C_HRX_P7: length 18.6
  TOP w0.076: v2(174.26,137.94) 173.99,137.94 173.92,137.87 173.92,137.73 174.11,137.54 175.65,137.54 176.17,138.06 176.77,138.06 176.96,137.87 177.35,137.87 177.44,137.96 177.46,137.96
  TOP w0.152: 177.46,137.96 183.76,137.96 185.32,139.52 190.02,139.52 CV832.2
  BOTTOM w0.076: v2(174.26,137.94) 174.26,137.94 174.22,137.94 173.89,138.27 UH1.D17
PEG_GTX_C_HRX_P8: length 18
  TOP w0.076: v2(172.92,138.73) 172.92,139.04 172.98,139.1 173.06,139.1 173.28,138.88 173.28,138.52 173.34,138.46 173.76,138.46 173.98,138.67 177.39,138.67 177.59,138.87 178.11,138.87 178.2,138.96 178.22,138.96
  TOP w0.152: CV834.2 188.45,140.62 184.97,140.62 183.31,138.96 178.22,138.96
  BOTTOM w0.076: UH1.E18 172.92,138.79 v2(172.92,138.73)
PEG_GTX_C_HRX_P9: length 19.1
  TOP w0.076: v2(172.92,139.52) 173.16,139.27 173.16,139.23 173.29,139.1 173.39,139.01 174.45,139.01 174.93,139.49 177.95,139.49 178.09,139.63 178.37,139.63 178.46,139.54 178.47,139.54
  TOP w0.152: 178.47,139.54 182.98,139.54 184.66,141.23 v5(185.67,141.23) 190.18,141.23 CV836.2
  BOTTOM w0.076: v2(172.92,139.52) 173.24,139.84 UH1.E19
PEG_GTX_C_HRX_P10: length 17.5
  TOP w0.076: v2(172.92,141.09) 173.24,140.77 173.4,140.77 173.79,140.39 177.52,140.39 177.96,140.82 178.17,140.82 178.26,140.91 178.28,140.91
  TOP w0.152: 178.28,140.91 182.4,140.91 184.14,142.65 v5(185.47,142.65) 188.45,142.65 CV838.2
  BOTTOM w0.076: v2(172.92,141.09) 172.92,141.02 UH1.E20
PEG_GTX_C_HRX_P11: length 19.3
  TOP w0.076: 176.59,141.72 176.57,141.72 176.48,141.63 174.02,141.63 173.81,141.42 173.81,141.33 v2(173.57,141.09)
  TOP w0.152: 176.59,141.72 177.36,141.72 177.51,141.86 181.72,141.86 183.53,143.67 v5(186.86,143.67) 191.12,143.67 CV840.2
  BOTTOM w0.076: v2(173.57,141.09) 173.57,141.16 UH1.E21
PEG_GTX_C_HRX_P12: length 18.7
  TOP w0.076: 177.42,142.76 177.41,142.76 177.32,142.67 176.96,142.67 176.8,142.83 175.67,142.83 175.07,142.23 173.51,142.23 173.39,142.34 173.24,142.34 v2(172.92,142.66)
  TOP w0.152: CV842.2 189.54,144.7 v5(185.45,144.7) 183.23,144.7 181.29,142.76 177.42,142.76
  BOTTOM w0.076: UH1.E22 172.92,142.59 v2(172.92,142.66)
PEG_GTX_C_HRX_P13: length 19.6
  TOP w0.076: 177.47,143.64 177.45,143.64 177.36,143.55 176.88,143.55 176.77,143.44 174.17,143.44 173.77,143.04 173.77,142.86 v2(173.57,142.66)
  TOP w0.152: CV844.2 191.06,145.71 v5(183.79,145.71) 182.96,145.71 180.89,143.64 177.47,143.64
  BOTTOM w0.076: UH1.E23 173.57,142.73 v2(173.57,142.66)
PEG_GTX_C_HRX_P14: length 18.8
  TOP w0.076: 178.66,144.24 178.64,144.24 178.55,144.33 178.33,144.33 178.23,144.23 176.01,144.23 175.8,144.02 173.45,144.02 173.28,143.84 173.28,143.52 173.34,143.45 v2(173.57,143.45)
  TOP w0.152: 178.66,144.24 180.47,144.24 182.56,146.33 v5(188.07,146.33) 189.52,146.33 CV846.2
  BOTTOM w0.076: v2(173.57,143.45) 173.43,143.45 173.24,143.64 UH1.E24
PEG_GTX_C_HRX_P15: length 19.8
  TOP w0.076: v2(173.55,145.01) 173.73,144.83 173.73,144.69 173.92,144.5 174.87,144.5 175.18,144.81 177.87,144.81 178.29,145.23 178.65,145.23 178.74,145.14 178.76,145.14
  TOP w0.152: 178.76,145.14 179.86,145.14 182.07,147.35 v5(184.47,147.35) 191.04,147.35 CV848.2
  BOTTOM w0.076: UH1.E25 173.24,144.69 173.55,145 v2(173.55,145.01)
PEG_GTX_HRX_N0: length 9.9
  TOP w0.076: v2(196.75,135.49) 196.56,135.31 196.56,135.05 196.35,134.84 196.35,134.71 196.33,134.7
  TOP w0.152: 196.33,134.7 195.56,133.93 193.78,133.93 192,132.15 189.33,132.15 CV819.1
  BOTTOM w0.102: v2(196.75,135.49) 196.75,135.8 UV18.AJ14
PEG_GTX_HRX_N1: length 8.9
  TOP w0.076: v2(197.66,135.69) 197.35,135.99 194.53,135.99 193.86,135.32 193.86,135.2 193.85,135.18
  TOP w0.152: CV821.1 191,133.18 191.84,133.18 v5(191.99,133.33) 193.85,135.18
  BOTTOM w0.102: UV18.AG14 198.06,136.09 v2(197.66,135.69)
PEG_GTX_HRX_N2: length 8.7
  TOP w0.076: 193.67,136.25 194.26,136.85 195.43,136.85 195.52,136.94 195.95,136.94 196.02,137.01 v2(196.02,137.25)
  TOP w0.089: 193.27,136.07 193.28,136.08 193.32,136.08 193.49,136.25 193.67,136.25
  TOP w0.152: CV823.1 189.33,134.53 191.58,134.53 v5(191.78,134.72) 192.94,135.88 193.08,135.88 193.27,136.07
  BOTTOM w0.102: UV18.AJ15 196.38,136.89 v2(196.02,137.25)
PEG_GTX_HRX_N3: length 6.2
  TOP w0.076: 192.75,136.35 192.77,136.36 192.77,136.49 192.89,136.61 193.26,136.61 194.28,137.63 194.93,137.63 v2(195.22,137.34)
  TOP w0.152: 192.75,136.35 191.61,135.2 190.99,135.2 CV825.1
  BOTTOM w0.102: v2(195.22,137.34) 195.22,137.36 UV18.AK16
PEG_GTX_HRX_N4: length 9.5
  TOP w0.076: 193.05,137.76 193.07,137.78 193.19,137.78 194.14,138.73 v5(195,138.73) 196.28,138.73 196.53,138.47 196.53,138.26 196.61,138.19 v2(196.85,138.19)
  TOP w0.152: 193.05,137.76 192.71,137.42 192.24,137.42 191.37,136.55 189.34,136.55 CV827.1
  BOTTOM w0.102: v2(196.85,138.19) UV18.AJ17
PEG_GTX_HRX_N5: length 8.7
  TOP w0.076: v2(197.72,138.2) 197.41,138.51 197.07,138.51 196.54,139.04 193.93,139.04 193.39,138.5 193,138.5 192.82,138.32 192.82,138.19 192.81,138.18
  TOP w0.152: 192.81,138.18 192.54,137.92 192.08,137.92 191.4,137.24 190.99,137.24 CV829.1
  BOTTOM w0.102: v2(197.72,138.2) 197.72,138.21 UV18.AG17
PEG_GTX_HRX_N6: length 8.2
  TOP w0.076: 192.4,139.29 192.41,139.31 192.54,139.31 192.68,139.45 192.91,139.45 192.98,139.51 193.61,139.51 193.72,139.63 194.5,139.63 195,140.13 195.35,140.13 195.72,139.76 v2(196.05,139.76)
  TOP w0.152: 192.4,139.29 192.17,139.06 191.63,139.06 191.23,138.66 189.26,138.66 CV831.1
  BOTTOM w0.102: UV18.AJ18 196.42,139.39 196.05,139.76 196.05,139.76 v2(196.05,139.76)
PEG_GTX_HRX_N7: length 5.5
  TOP w0.076: v2(195.18,140.6) 195.15,140.6 194.5,139.96 192.83,139.96 192.74,139.87 192.73,139.87
  TOP w0.152: 192.73,139.87 192.36,139.87 192.04,139.55 v5(191.77,139.55) 191.46,139.55 191.22,139.32 191.04,139.32 CV833.1
  BOTTOM w0.102: UV18.AK19 195.24,140.6 v2(195.18,140.6)
PEG_GTX_HRX_N8: length 9.5
  TOP w0.076: 192.97,140.68 192.99,140.68 193.08,140.77 193.79,140.77 194.04,141.02 195.31,141.02 195.55,140.78 195.55,140.47 195.87,140.15 196.39,140.15 v2(196.93,140.69)
  TOP w0.152: 192.97,140.68 v5(192.63,140.68) 191.77,140.68 191.43,140.34 189.39,140.34 CV835.1
  BOTTOM w0.102: v2(196.93,140.69) 196.53,141.09 UV18.AJ20
PEG_GTX_HRX_N9: length 9
  TOP w0.076: 192.64,141.86 192.66,141.86 192.75,141.77 193.38,141.77 193.57,141.59 195.11,141.59 195.16,141.64 195.75,141.64 196.13,141.26 198.1,141.26 198.29,141.06 198.29,140.9 v2(198.5,140.69)
  TOP w0.152: 192.64,141.86 v5(191.85,141.86) 191.37,141.86 191.15,141.64 190.98,141.64 CV837.1
  BOTTOM w0.102: UV18.AG20 v2(198.5,140.69)
PEG_GTX_HRX_N10: length 8.2
  TOP w0.076: 192.85,142.37 192.87,142.37 192.96,142.46 193.25,142.46 v5(193.56,142.16) 193.86,141.85 195.64,141.85 195.82,142.03 195.82,142.17 v2(196.05,142.39)
  TOP w0.152: CV839.1 189.39,142.37 192.85,142.37
  BOTTOM w0.102: v2(196.05,142.39) 196.45,141.99 UV18.AJ21
PEG_GTX_HRX_N11: length 4.5
  TOP w0.076: v2(195.16,143.19) 194.74,142.76 193.67,142.76 193.09,143.35 192.95,143.35 192.86,143.26
  TOP w0.152: CV841.1 191.93,143.26 v5(192.66,143.26) 192.86,143.26
  BOTTOM w0.102: UV18.AK22 195.6,142.74 v2(195.16,143.19)
PEG_GTX_HRX_N12: length 7
  TOP w0.076: v2(196.02,143.16) 195.74,143.44 195.51,143.44 195.22,143.72 193.99,143.72 193.27,144.44 193.07,144.44 192.98,144.35
  TOP w0.152: CV843.1 190.42,144.35 192.98,144.35
  BOTTOM w0.102: UV18.AJ23 v2(196.02,143.16)
PEG_GTX_HRX_N13: length 9.3
  TOP w0.076: v2(198.5,143.19) 197.99,142.68 197.27,142.68 196.57,143.38 196.57,144.05 196.34,144.29 195.71,144.29 195.61,144.19 194.04,144.19 193.63,144.6 193.63,144.68 192.85,145.45 192.76,145.45 192.67,145.37
  TOP w0.152: 192.67,145.37 191.94,145.37 CV845.1
  BOTTOM w0.102: UV18.AG23 v2(198.5,143.19)
PEG_GTX_HRX_N14: length 7.4
  TOP w0.076: 193.49,146.37 193.5,146.35 193.5,146.23 193.78,145.95 193.78,145.77 194.21,145.35 195.49,145.35 196.01,144.82 v2(196.02,144.82)
  TOP w0.152: CV847.1 190.41,146.65 193.21,146.65 193.49,146.37
  BOTTOM w0.102: UV18.AJ24 v2(196.02,144.82)
PEG_GTX_HRX_N15: length 5.9
  TOP w0.076: 195.18,146.54 195.18,146.52 195.09,146.43 195.09,146.26 194.98,146.15 194.98,145.93 v2(195.19,145.73)
  TOP w0.152: CV849.1 191.94,147.67 v5(193.34,147.67) 194.58,147.67 195.18,147.07 195.18,146.54
  BOTTOM w0.102: UV18.AK25 195.6,145.31 v2(195.19,145.73)
PEG_GTX_HRX_P0: length 10
  TOP w0.076: v2(196.07,135.47) 196.27,135.47 196.41,135.33 196.41,135.11 196.24,134.95 196.11,134.95 196.1,134.93
  TOP w0.152: 196.1,134.93 195.42,134.26 v5(194.08,134.26) 193.64,134.26 191.86,132.48 189.37,132.48 189.2,132.64 CV818.1
  BOTTOM w0.102: v2(196.07,135.47) 196.07,135.88 195.86,136.09 UV18.AK14
PEG_GTX_HRX_P1: length 8.9
  TOP w0.076: v2(197.68,136.5) 197.68,136.24 197.59,136.14 194.46,136.14 193.75,135.43 193.63,135.43 193.61,135.42
  TOP w0.152: CV820.1 190.98,133.51 191.71,133.51 191.88,133.68 193.61,135.42
  BOTTOM w0.102: UV18.AH14 197.3,136.12 v2(197.68,136.5)
PEG_GTX_HRX_P2: length 8.7
  TOP w0.076: 193.67,136.07 193.68,136.07 193.69,136.08 193.74,136.08 193.84,136.18 193.84,136.19 194.33,136.68 195.5,136.68 195.59,136.78 195.78,136.78 v2(196.03,136.52)
  TOP w0.089: 193.44,135.9 193.45,135.91 193.45,135.96 193.56,136.07 193.67,136.07
  TOP w0.152: 193.44,135.9 v5(193.23,135.69) 191.73,134.2 189.35,134.2 CV822.1
  BOTTOM w0.102: UV18.AK15 195.66,136.89 v2(196.03,136.52)
PEG_GTX_HRX_P3: length 6.2
  TOP w0.076: 192.52,136.58 192.53,136.59 192.66,136.59 192.78,136.71 192.83,136.76 193.2,136.76 194.23,137.79 195.09,137.79 195.18,137.89 v2(195.18,138.13)
  TOP w0.152: CV824.1 190.99,135.53 191.47,135.53 v5(191.96,136.01) 192.52,136.58
  BOTTOM w0.102: v2(195.18,138.13) 194.8,137.75 UV18.AL16
PEG_GTX_HRX_P4: length 9.5
  TOP w0.076: 193.29,137.53 193.3,137.54 193.3,137.67 194.2,138.57 194.63,138.57 194.69,138.51 195.31,138.51 195.36,138.56 196.23,138.56 196.38,138.41 196.38,138.26 196.31,138.19 v2(196,138.19)
  TOP w0.152: 193.29,137.53 v5(193.05,137.29) 192.85,137.09 192.38,137.09 191.5,136.22 189.34,136.22 CV826.1
  BOTTOM w0.102: UV18.AK17 v2(196,138.19)
PEG_GTX_HRX_P5: length 8.7
  TOP w0.076: v2(197.7,138.99) 197.7,138.76 197.6,138.66 197.13,138.66 196.6,139.19 193.87,139.19 193.33,138.65 192.93,138.65 192.85,138.56 192.71,138.43 192.59,138.43 192.57,138.41
  TOP w0.152: 192.57,138.41 192.41,138.25 191.94,138.25 v5(191.75,138.05) 191.26,137.57 190.99,137.57 CV828.1
  BOTTOM w0.102: UV18.AH17 v2(197.7,138.99)
PEG_GTX_HRX_P6: length 8.2
  TOP w0.076: v2(195.2,139.76) 195.42,139.76 195.49,139.69 195.49,139.5 195.39,139.39 195.04,139.39 194.82,139.62 194.7,139.62 194.56,139.47 193.79,139.47 193.61,139.3 v5(193.27,139.3) 192.74,139.3 192.65,139.2 192.65,139.07 192.63,139.06
  TOP w0.152: CV830.1 189.41,138.33 191.37,138.33 191.77,138.73 192.3,138.73 192.63,139.06
  BOTTOM w0.102: v2(195.2,139.76) 195.23,139.76 UV18.AK18
PEG_GTX_HRX_P7: length 5.5
  TOP w0.076: v2(194.39,140.6) 194.5,140.71 194.63,140.71 194.77,140.57 194.77,140.44 194.44,140.11 192.83,140.11 192.74,140.2 192.73,140.2
  TOP w0.152: 192.73,140.2 192.22,140.2 191.9,139.88 191.32,139.88 191.09,139.65 190.94,139.65 CV832.1
  BOTTOM w0.102: UV18.AL19 194.44,140.6 v2(194.39,140.6)
PEG_GTX_HRX_P8: length 9.5
  TOP w0.076: 192.97,141.01 192.99,141.01 193.08,140.92 193.73,140.92 193.98,141.17 195.38,141.17 195.71,140.84 195.71,140.53 195.93,140.31 196.33,140.31 196.52,140.5 196.52,140.62 196.45,140.69 v2(196.08,140.69)
  TOP w0.152: 192.97,141.01 191.63,141.01 191.29,140.67 189.28,140.67 CV834.1
  BOTTOM w0.102: UV18.AK20 195.68,141.09 v2(196.08,140.69)
PEG_GTX_HRX_P9: length 9
  TOP w0.076: 192.64,141.53 192.66,141.53 192.74,141.61 193.32,141.61 193.5,141.42 v5(195.45,141.42) 195.73,141.42 196.06,141.09 198.03,141.09 198.13,140.99 198.13,140.78 198.04,140.69 v2(197.7,140.69)
  TOP w0.152: 192.64,141.53 191.51,141.53 191.28,141.31 190.99,141.31 CV836.1
  BOTTOM w0.102: UV18.AH20 v2(197.7,140.69)
PEG_GTX_HRX_P10: length 8.2
  TOP w0.076: 192.85,142.7 192.87,142.7 192.96,142.61 193.41,142.61 194.02,142.01 195.58,142.01 195.67,142.1 195.67,142.25 195.53,142.39 v2(195.2,142.39)
  TOP w0.152: 192.85,142.7 v5(190.17,142.7) 189.28,142.7 CV838.1
  BOTTOM w0.102: v2(195.2,142.39) 195.6,141.99 UV18.AK21
PEG_GTX_HRX_P11: length 4.5
  TOP w0.076: v2(194.36,143.19) 194.36,143.39 194.28,143.48 193.91,143.48 193.82,143.39 193.82,143.26 193.99,143.09 193.99,142.97 193.95,142.93 193.74,142.93 193.16,143.51 192.97,143.51 192.89,143.59 192.84,143.59
  TOP w0.152: CV840.1 191.95,143.59 192.84,143.59
  BOTTOM w0.102: v2(194.36,143.19) 194.8,142.74 UV18.AL22
PEG_GTX_HRX_P12: length 7
  TOP w0.076: 193,144.68 193.08,144.61 193.34,144.61 194.06,143.89 195.29,143.89 195.59,143.59 195.72,143.59 v2(196.04,143.92)
  TOP w0.152: CV842.1 190.41,144.68 v5(192.7,144.68) 193,144.68
  BOTTOM w0.102: v2(196.04,143.92) 195.72,143.59 UV18.AK23
PEG_GTX_HRX_P13: length 9.3
  TOP w0.076: 192.72,145.7 192.74,145.7 192.82,145.62 192.92,145.62 v5(193.99,144.55) 194.18,144.36 195.54,144.36 195.64,144.46 196.4,144.46 196.74,144.12 196.74,143.43 197.33,142.84 197.93,142.84 198.09,143 198.09,143.14 197.96,143.27 197.76,143.27 v2(197.71,143.22)
  TOP w0.152: 192.72,145.7 191.94,145.7 CV844.1
  BOTTOM w0.102: v2(197.71,143.22) 197.67,143.22 UV18.AH23
PEG_GTX_HRX_P14: length 7.4
  TOP w0.076: 193.26,146.13 193.26,146.13 193.28,146.13 193.28,146.13 193.39,146.13 193.4,146.12 193.63,145.88 193.63,145.71 194.15,145.2 195.43,145.2 195.6,145.02 195.6,144.78 195.51,144.69 195.36,144.69 v2(195.23,144.82)
  TOP w0.152: CV846.1 190.42,146.32 v5(192.77,146.32) 193.07,146.32 193.26,146.13
  BOTTOM w0.102: v2(195.23,144.82) 195.29,144.82 195.6,144.51 UV18.AK24
PEG_GTX_HRX_P15: length 5.9
  TOP w0.076: 194.85,146.54 194.85,146.52 194.94,146.43 194.94,146.32 194.83,146.21 194.83,145.65 194.75,145.57 194.58,145.57 v2(194.4,145.75)
  TOP w0.152: CV848.1 191.94,147.34 194.45,147.34 194.85,146.93 194.85,146.54
  BOTTOM w0.102: UV18.AL25 194.8,145.35 v2(194.4,145.75)
PEG_HTX_C_GRX_N0: length 7.5
  BOTTOM w0.076: UV18.AM12 193.62,134.77 192.86,134.77 192.72,134.91 192.18,134.91 192.09,135 192.07,135
  BOTTOM w0.152: CH36.2 187.71,132.86 188.83,132.86 190.97,135 192.07,135
PEG_HTX_C_GRX_N1: length 6.5
  BOTTOM w0.076: UV18.AM14 193.5,135.59 192.67,135.59 192.63,135.55 192.25,135.55 192.16,135.46 192.14,135.46
  BOTTOM w0.152: CH34.2 188.55,133.93 189.25,133.93 190.78,135.46 192.14,135.46
PEG_HTX_C_GRX_N2: length 6
  BOTTOM w0.152: CH32.2 187.15,135.48 v5(187.93,135.48) 189.14,135.48 190.29,136.62 192.13,136.62 UV18.AP15
PEG_HTX_C_GRX_N3: length 6.6
  BOTTOM w0.076: UV18.AM15 193.66,136.55 193,136.55 192.86,136.69 192.86,137.11 192.83,137.14 192.71,137.25 192.16,137.25 192.07,137.17 192.05,137.17
  BOTTOM w0.152: CH30.2 188.42,136.53 189.14,136.53 189.78,137.17 192.05,137.17
PEG_HTX_C_GRX_N4: length 7.8
  BOTTOM w0.076: 191.9,138.32 191.92,138.32 192.01,138.23 192.7,138.23 192.85,138.38 192.85,138.69 193.14,138.98 193.61,138.98 193.81,138.78 UV18.AM17
  BOTTOM w0.152: 191.9,138.32 189.28,138.32 189.06,138.1 187,138.1 CH28.2
PEG_HTX_C_GRX_N5: length 6
  BOTTOM w0.076: 191.65,138.88 191.97,139.2 192.05,139.2 192.13,139.13 192.13,139.06 192.06,138.99 192.06,138.92 192.12,138.86 192.23,138.86 192.29,138.92 192.52,138.92 192.73,139.14 192.73,139.48 192.61,139.6 192.47,139.6 192.4,139.54 UV18.AP18
  BOTTOM w0.152: CH26.2 188.46,138.58 188.76,138.88 v5(189.26,138.88) 191.65,138.88
PEG_HTX_C_GRX_N6: length 7.7
  BOTTOM w0.076: 191.64,140.1 191.66,140.1 191.75,140.01 191.83,140.01 192.07,140.25 192.73,140.25 193.08,139.91 193.64,139.91 193.8,139.75 193.8,139.59 UV18.AM18
  BOTTOM w0.152: 191.64,140.1 v5(189.64,140.1) 187.16,140.1 CH24.2
PEG_HTX_C_GRX_N7: length 6.1
  BOTTOM w0.076: UV18.AM20 193.76,140.85 193.76,140.76 193.58,140.58 192.17,140.58 192.09,140.66 191.76,140.66 191.67,140.58 191.65,140.58
  BOTTOM w0.152: CH22.2 188.52,140.76 189.08,140.76 189.27,140.58 191.65,140.58
PEG_HTX_C_GRX_N8: length 6.1
  BOTTOM w0.076: 191.71,141.79 191.73,141.79 191.82,141.7 192.01,141.7 192.15,141.55 192.33,141.55 192.4,141.63 UV18.AP21
  BOTTOM w0.152: 191.71,141.79 190.26,141.79 189.92,142.13 187.03,142.13 CH20.2
PEG_HTX_C_GRX_N9: length 6.3
  BOTTOM w0.076: 191.79,142.58 191.81,142.58 191.9,142.49 192.9,142.49 192.99,142.4 193.59,142.4 193.75,142.24 193.75,142.14 UV18.AM21
  BOTTOM w0.152: CH18.2 188.52,143.12 190.07,143.12 v5(190.31,142.88) 190.61,142.58 191.79,142.58
PEG_HTX_C_GRX_N10: length 8.2
  BOTTOM w0.076: 191.75,143.03 191.77,143.03 191.85,143.12 192.05,143.12 192.21,142.96 192.87,142.96 192.98,143.07 193.48,143.07 UV18.AM23
  BOTTOM w0.152: CH16.2 186.77,143.71 v5(189.15,143.71) 190.16,143.71 190.83,143.03 191.75,143.03
PEG_HTX_C_GRX_N11: length 5.2
  BOTTOM w0.076: 191.76,144.18 191.77,144.18 191.86,144.09 192.1,144.09 UV18.AP24
  BOTTOM w0.152: 191.76,144.18 191.29,144.18 190.47,145 v5(188.79,145) 187.97,145 CH14.2
PEG_HTX_C_GRX_N12: length 8.9
  BOTTOM w0.076: 191.96,144.64 191.98,144.64 192.07,144.73 192.61,144.73 192.84,144.5 192.84,144.3 193.07,144.07 193.68,144.07 UV18.AM24
  BOTTOM w0.152: 191.96,144.64 191.48,144.64 190.05,146.07 v5(187.86,146.07) 187.53,146.07 187.39,145.94 186.49,145.94 CH12.2
PEG_HTX_C_GRX_N13: length 7.6
  BOTTOM w0.076: UV18.AM26 193.68,146.41 193.08,146.41 192.85,146.19 192.85,145.87 192.61,145.63 192.28,145.63 192.19,145.72 192.17,145.72
  BOTTOM w0.152: CH10.2 187.95,147.38 190.32,147.38 191.98,145.72 192.17,145.72
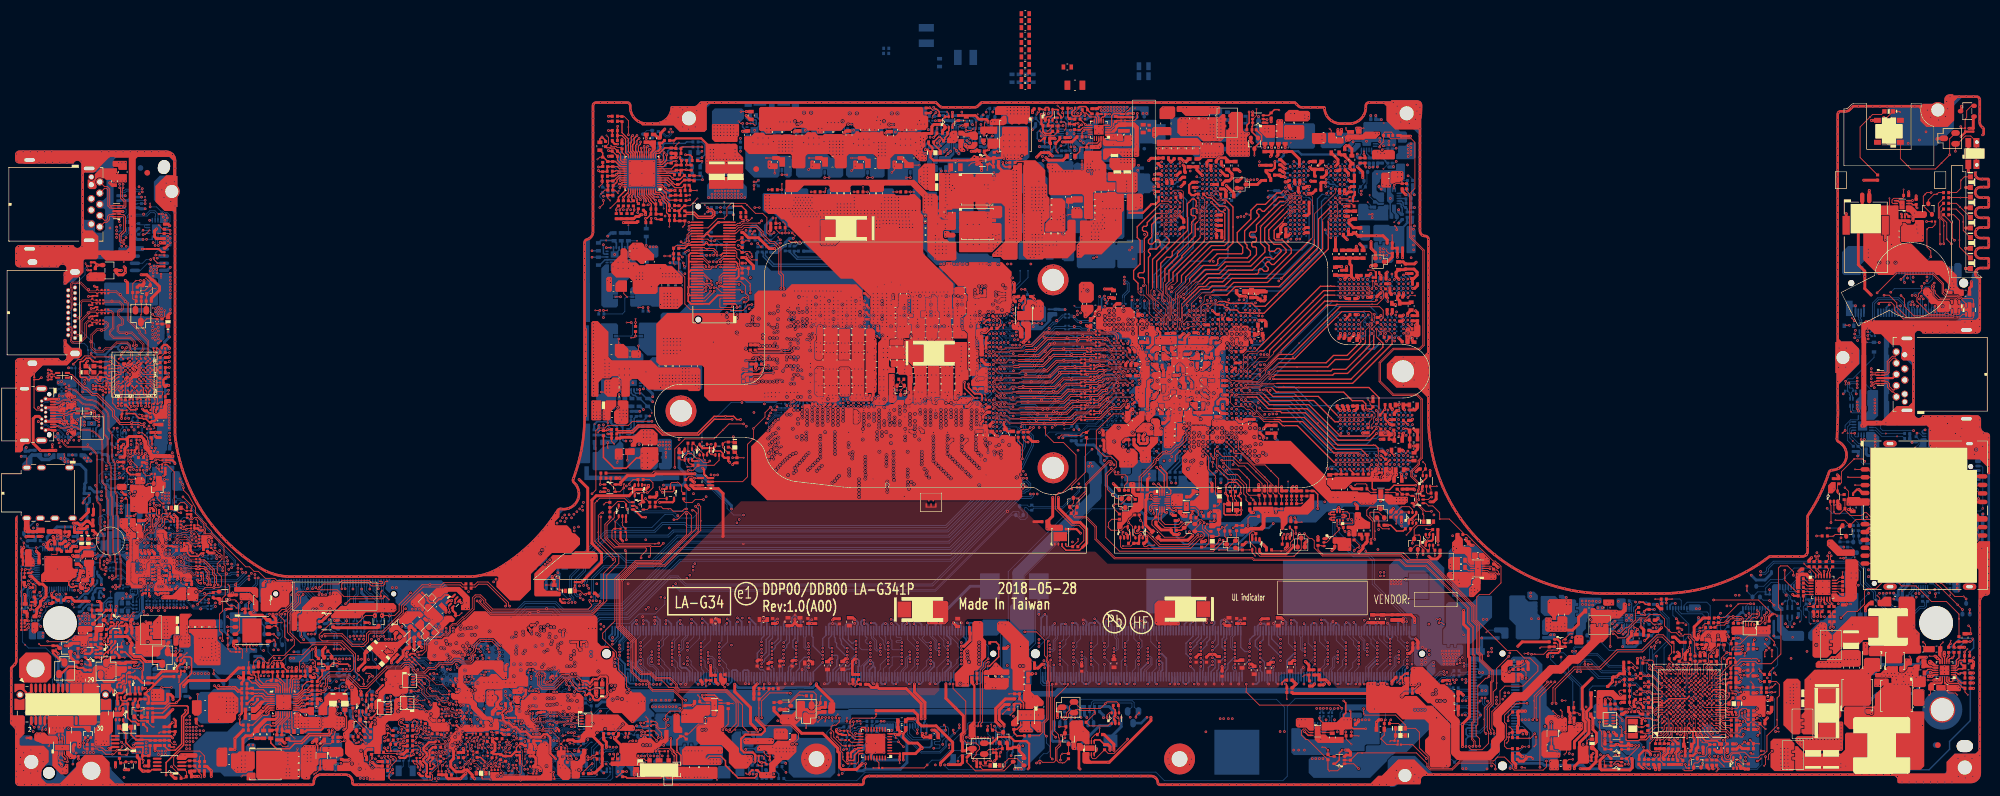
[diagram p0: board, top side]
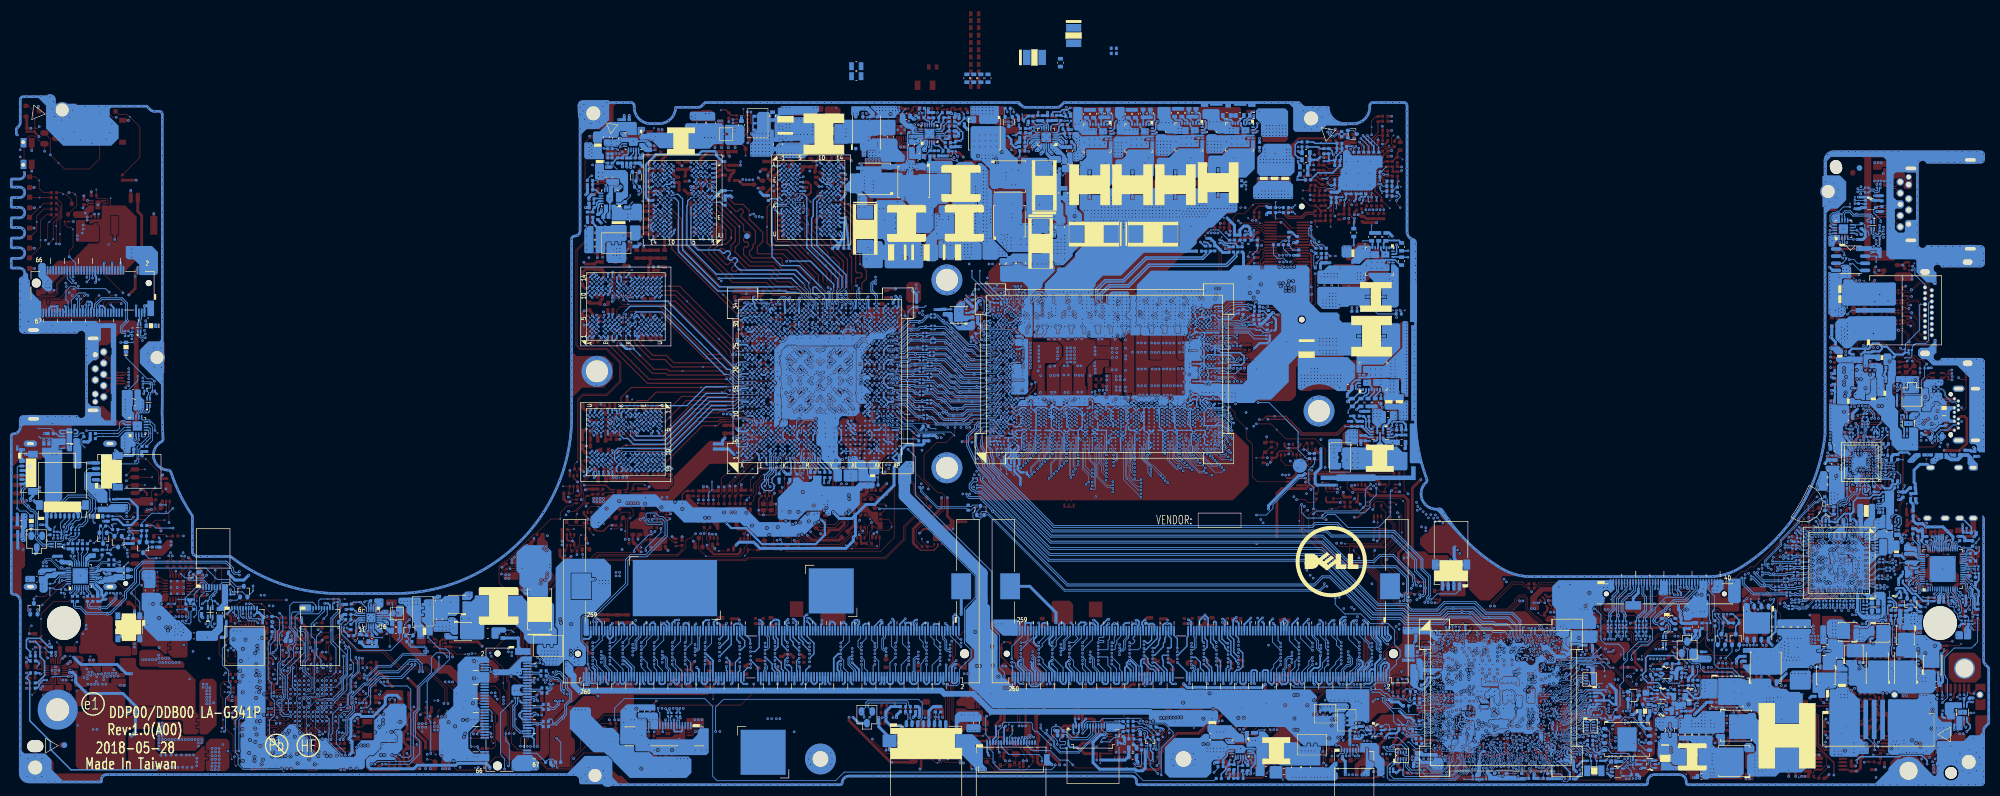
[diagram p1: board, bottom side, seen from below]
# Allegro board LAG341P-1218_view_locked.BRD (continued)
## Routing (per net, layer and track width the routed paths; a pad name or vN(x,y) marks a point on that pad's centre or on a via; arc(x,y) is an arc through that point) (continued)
PEG_HTX_C_GRX_N14: length 7.2
  BOTTOM w0.076: 191.87,146.95 191.88,146.94 191.88,146.81 192.06,146.64 192.31,146.64 192.4,146.73 UV18.AP27
  BOTTOM w0.152: CH8.2 186.49,148.65 v5(187.32,148.65) 188.42,148.65 188.71,148.35 190.47,148.35 191.87,146.95
PEG_HTX_C_GRX_N15: length 9.5
  BOTTOM w0.076: UV18.AM27 193.84,147.05 193.84,147.2 193.66,147.38 192.85,147.38 192.64,147.59 192.25,147.59 192.08,147.76 192.08,147.89 192.07,147.9
  BOTTOM w0.152: 192.07,147.9 190.24,149.73 188.01,149.73 v5(187.31,150.42) 187.05,150.69 186.51,150.69 CH6.2
PEG_HTX_C_GRX_P0: length 7.5
  BOTTOM w0.076: 192.07,134.67 192.09,134.67 192.18,134.76 192.66,134.76 192.81,134.6 192.81,134.1 192.89,134.02 193.12,134.02 193.2,134.1 UV18.AN12
  BOTTOM w0.152: CH35.2 187.93,132.53 v5(188.49,132.53) 188.97,132.53 191.11,134.67 192.07,134.67
PEG_HTX_C_GRX_P1: length 6.5
  BOTTOM w0.076: UV18.AN14 193.51,136.09 193.59,136.01 193.59,135.89 193.44,135.74 192.61,135.74 192.57,135.7 192.25,135.7 192.16,135.79 192.14,135.79
  BOTTOM w0.152: 192.14,135.79 190.64,135.79 v5(189.64,134.79) 189.12,134.26 188.62,134.26 CH33.2
PEG_HTX_C_GRX_P2: length 6
  BOTTOM w0.152: UV18.AP14 192.2,136.29 190.42,136.29 v5(190.23,136.1) 189.28,135.15 187.22,135.15 CH31.2
PEG_HTX_C_GRX_P3: length 6.6
  BOTTOM w0.076: UV18.AN15 193.33,136.76 193.57,136.76 193.67,136.86 193.67,137.08 193.47,137.27 192.9,137.27 192.77,137.41 192.16,137.41 192.07,137.5 192.05,137.5
  BOTTOM w0.152: CH29.2 188.62,136.86 189,136.86 v5(189.2,137.06) 189.64,137.5 192.05,137.5
PEG_HTX_C_GRX_P4: length 7.8
  BOTTOM w0.076: 191.9,137.99 191.92,137.99 192.01,138.08 192.76,138.08 192.94,138.25 193.37,138.25 193.65,138.53 193.65,138.67 193.53,138.79 193.4,138.79 UV18.AN17
  BOTTOM w0.152: CH27.2 187.24,137.77 189.19,137.77 189.42,137.99 v5(190.18,137.99) 191.9,137.99
PEG_HTX_C_GRX_P5: length 6
  BOTTOM w0.076: UV18.AP17 192.88,139.07 192.88,139.54 192.68,139.75 192.3,139.75 191.76,139.21 191.6,139.21
  BOTTOM w0.152: CH25.2 v5(190.59,139.21) 191.6,139.21
PEG_HTX_C_GRX_P6: length 7.7
  BOTTOM w0.076: UV18.AN18 193.51,139.39 193.65,139.53 193.65,139.68 193.58,139.76 193.01,139.76 192.67,140.1 192.13,140.1 191.89,139.86 191.75,139.86 191.66,139.77 191.64,139.77
  BOTTOM w0.152: 191.64,139.77 187.08,139.77 CH23.2
PEG_HTX_C_GRX_P7: length 6.1
  BOTTOM w0.076: 191.65,140.91 191.67,140.91 191.76,140.82 192.15,140.82 192.24,140.73 193.52,140.73 193.61,140.82 193.61,141 193.51,141.09 UV18.AN20
  BOTTOM w0.152: CH21.2 188.52,141.09 189.22,141.09 189.4,140.91 191.65,140.91
PEG_HTX_C_GRX_P8: length 6.1
  BOTTOM w0.076: 191.71,141.46 191.73,141.46 191.82,141.55 191.94,141.55 192.09,141.4 192.33,141.4 192.4,141.33 UV18.AP20
  BOTTOM w0.152: CH19.2 187.08,141.8 v5(189.22,141.8) 189.78,141.8 190.12,141.46 191.71,141.46
PEG_HTX_C_GRX_P9: length 6.3
  BOTTOM w0.076: 191.79,142.25 191.81,142.25 191.9,142.33 192.84,142.33 192.93,142.25 193.53,142.25 193.6,142.17 193.6,141.96 193.52,141.89 UV18.AN21
  BOTTOM w0.152: 191.79,142.25 190.48,142.25 189.93,142.79 188.52,142.79 CH17.2
PEG_HTX_C_GRX_P10: length 8.2
  BOTTOM w0.076: UV18.AN23 193.29,143.68 193.46,143.68 193.59,143.54 193.59,143.4 193.42,143.22 192.92,143.22 192.8,143.11 192.28,143.11 192.11,143.27 191.85,143.27 191.77,143.36 191.75,143.36
  BOTTOM w0.152: CH15.2 186.59,144.04 190.3,144.04 190.97,143.36 191.75,143.36
PEG_HTX_C_GRX_P11: length 5.2
  BOTTOM w0.076: UV18.AP23 192.05,143.94 191.86,143.94 191.77,143.85 191.76,143.85
  BOTTOM w0.152: 191.76,143.85 191.15,143.85 190.33,144.67 v5(190.09,144.67) 187.92,144.67 CH13.2
PEG_HTX_C_GRX_P12: length 8.9
  BOTTOM w0.076: 191.96,144.97 191.98,144.97 192.07,144.88 192.67,144.88 192.8,144.75 193.5,144.75 193.63,144.62 193.63,144.34 193.54,144.26 193.34,144.26 UV18.AN24
  BOTTOM w0.152: 191.96,144.97 191.61,144.97 190.19,146.4 v5(189.98,146.4) 187.39,146.4 187.26,146.27 186.48,146.27 CH11.2
PEG_HTX_C_GRX_P13: length 7.6
  BOTTOM w0.076: UV18.AN26 193.37,146.26 193.51,146.26 193.64,146.13 193.64,145.82 193.53,145.72 192.91,145.72 192.67,145.48 192.28,145.48 192.19,145.39 192.17,145.39
  BOTTOM w0.152: 192.17,145.39 191.84,145.39 190.18,147.05 v5(188.82,147.05) 187.95,147.05 CH9.2
PEG_HTX_C_GRX_P14: length 7.2
  BOTTOM w0.076: UV18.AP26 192.4,146.4 192.31,146.49 191.99,146.49 191.78,146.7 191.65,146.7 191.64,146.72
  BOTTOM w0.152: 191.64,146.72 190.33,148.02 v5(189.9,148.02) 188.57,148.02 188.28,148.32 186.49,148.32 CH7.2
PEG_HTX_C_GRX_P15: length 9.4
  BOTTOM w0.076: 191.83,147.67 191.85,147.65 191.97,147.65 192.19,147.44 192.58,147.44 192.78,147.23 193.6,147.23 193.69,147.14 193.69,146.98 193.55,146.84 193.38,146.84 UV18.AN27
  BOTTOM w0.152: 191.83,147.67 190.1,149.4 v5(188.48,149.4) 187.91,149.4 187.36,149.94 186.95,150.36 186.49,150.36 CH5.2
PEG_HTX_GRX_N0: length 13.9
  BOTTOM w0.076: UH1.B10 175.15,132.87 174.9,132.87 174.82,132.79 174.82,132.62 174.93,132.52 176.11,132.52 176.27,132.36 178.79,132.36 179.14,132.01 179.27,132.01 179.28,131.99
  BOTTOM w0.152: CH36.1 186.86,132.68 186.22,132.68 185.02,131.47 v5(181.97,131.47) 179.8,131.47 179.28,131.99
PEG_HTX_GRX_N1: length 14.3
  BOTTOM w0.076: UH1.B11 175.67,133.13 176.21,133.13 176.25,133.17 176.71,133.17 177.01,132.87 178.95,132.87 179.04,132.78 179.06,132.78
  BOTTOM w0.152: 179.06,132.78 179.35,132.78 180.2,131.93 v5(180.59,131.93) 184.14,131.93 186.14,133.94 187.72,133.94 CH34.1
PEG_HTX_GRX_N2: length 13.6
  BOTTOM w0.076: 177.7,133.94 177.68,133.94 177.59,133.85 176.37,133.85 176.14,134.07 175.08,134.07 174.89,134.26 174.89,134.38 174.98,134.46 175.13,134.46 UH1.B12
  BOTTOM w0.152: 177.7,133.94 179.94,133.94 180.81,133.06 183.18,133.06 v5(183.64,133.52) 185,134.88 185.4,134.88 185.97,135.45 186.31,135.45 CH32.1
PEG_HTX_GRX_N3: length 14.5
  BOTTOM w0.076: 177.79,134.45 177.77,134.45 177.68,134.54 176.96,134.54 176.72,134.78 176.23,134.78 176.13,134.68 175.57,134.68 175.32,134.93 175.32,135.05 UH1.B13
  BOTTOM w0.152: 177.79,134.45 180.24,134.45 180.76,133.93 v5(181.74,133.93) 182.79,133.93 184.53,135.67 185.28,135.67 186.27,136.66 187.6,136.66 CH30.1
PEG_HTX_GRX_N4: length 13.3
  BOTTOM w0.076: 177.77,135.58 177.75,135.58 177.66,135.49 176.33,135.49 176.19,135.63 174.96,135.63 174.84,135.75 174.84,135.87 174.95,135.97 UH1.B14
  BOTTOM w0.152: 177.77,135.58 v5(181.48,135.58) 182.76,135.58 184.23,137.04 185.02,137.04 185.92,137.95 186.2,137.95 CH28.1
PEG_HTX_GRX_N5: length 14.3
  BOTTOM w0.076: 177.62,136.06 177.6,136.06 177.52,136.15 176.95,136.15 176.66,136.44 176.25,136.44 176.07,136.26 175.56,136.26 175.32,136.5 175.32,136.63 UH1.B15
  BOTTOM w0.152: 177.62,136.06 v5(180.17,136.06) 182.09,136.06 182.69,136.66 183.2,136.66 184.44,137.9 185.18,137.9 186.03,138.75 187.6,138.75 CH26.1
PEG_HTX_GRX_N6: length 13.5
  BOTTOM w0.076: 177.4,137.22 177.38,137.22 177.29,137.13 176.27,137.13 176.15,137.25 174.95,137.25 174.82,137.38 174.82,137.48 174.89,137.55 UH1.B16
  BOTTOM w0.152: 177.4,137.22 v5(179.55,137.22) 181.5,137.22 182.2,137.92 182.85,137.92 185.1,140.18 186.27,140.18 CH24.1
PEG_HTX_GRX_N7: length 14.4
  BOTTOM w0.076: 177.66,137.67 177.64,137.67 177.55,137.76 176.98,137.76 176.77,137.97 176.32,137.97 176.17,137.83 175.55,137.83 175.31,138.07 175.31,138.22 UH1.B17
  BOTTOM w0.152: 177.66,137.67 181.31,137.67 182.23,138.6 182.83,138.6 v5(184.72,140.48) 185.03,140.8 187.59,140.8 CH22.1
PEG_HTX_GRX_N8: length 13.8
  BOTTOM w0.076: UH1.C18 174.85,139.42 175.31,139.42 175.51,139.22 175.51,138.96 175.63,138.84 176.24,138.84 176.34,138.73 177.82,138.73 177.91,138.82 177.93,138.82
  BOTTOM w0.152: CH20.1 186.17,142.11 184.76,142.11 182.67,140.01 182.06,140.01 180.86,138.82 v5(179.65,138.82) 177.93,138.82
PEG_HTX_GRX_N9: length 14.5
  BOTTOM w0.076: UH1.A19 175.77,139.98 175.64,139.98 175.56,139.9 175.56,139.76 175.77,139.55 176.09,139.55 176.2,139.67 176.76,139.67 176.9,139.53 177.89,139.53 177.98,139.62 178,139.62
  BOTTOM w0.152: 178,139.62 180.54,139.62 v5(181.95,141.03) 183.83,142.91 185.6,142.91 185.7,143.01 187.02,143.01 187.14,143.12 187.63,143.12 CH18.1
PEG_HTX_GRX_N10: length 13.2
  BOTTOM w0.076: UH1.C20 174.69,140.55 174.69,140.43 174.88,140.25 177.39,140.25 177.48,140.16 177.5,140.16
  BOTTOM w0.152: CH16.1 185.79,143.62 183.9,143.62 180.44,140.16 v5(178.71,140.16) 177.5,140.16
PEG_HTX_GRX_N11: length 14.1
  BOTTOM w0.076: UH1.A21 175.58,141.48 175.46,141.36 175.46,141.24 175.56,141.15 176.03,141.15 176.19,141.31 176.87,141.31 176.96,141.23 177.36,141.23 177.45,141.32 177.47,141.32
  BOTTOM w0.152: CH14.1 187.07,145.04 183.59,145.04 v5(180.28,141.73) 179.87,141.32 177.47,141.32
PEG_HTX_GRX_N12: length 13.5
  BOTTOM w0.076: UH1.C22 174.66,142.16 174.66,141.95 174.84,141.77 176.02,141.77 176.1,141.7 176.65,141.7 176.82,141.87 177.4,141.87 177.49,141.78 177.5,141.78
  BOTTOM w0.152: 177.5,141.78 179.68,141.78 v5(182.16,144.25) 183.88,145.97 185.56,145.97 CH12.1
PEG_HTX_GRX_N13: length 14.4
  BOTTOM w0.076: UH1.A23 175.57,143.06 175.49,142.98 175.49,142.83 175.61,142.72 176.18,142.72 176.3,142.83 178.53,142.83 178.62,142.92 178.64,142.92
  BOTTOM w0.152: CH10.1 187.06,147.38 186.83,147.38 186.69,147.52 v5(184.26,147.52) 183.84,147.52 179.25,142.92 178.64,142.92
PEG_HTX_GRX_N14: length 14
  BOTTOM w0.076: UH1.C24 174.85,144.15 175.29,144.15 175.51,143.93 175.51,143.78 175.73,143.56 176.13,143.56 176.25,143.43 178.06,143.43 178.49,143.87 178.49,144 178.51,144.01
  BOTTOM w0.152: CH8.1 185.6,148.65 183.86,148.65 v5(181.97,146.76) 179.84,144.63 179.13,144.63 178.51,144.01
PEG_HTX_GRX_N15: length 13.5
  BOTTOM w0.076: 178.06,144.92 178.05,144.91 178.05,144.78 177.85,144.58 177.65,144.39 176.21,144.39 176.11,144.29 175.7,144.29 175.65,144.35 175.57,144.43 175.57,144.55 175.65,144.63 UH1.A25
  BOTTOM w0.152: CH6.1 185.61,150.7 185.19,150.7 v5(184.22,149.72) 183.94,149.45 183.54,149.45 179.53,145.43 178.57,145.43 178.06,144.92
PEG_HTX_GRX_P0: length 13.9
  BOTTOM w0.076: 179.05,131.76 179.03,131.77 179.03,131.9 178.88,132.05 178.73,132.2 176.21,132.2 176.05,132.37 174.87,132.37 174.67,132.56 174.67,132.69 UH1.C10
  BOTTOM w0.152: CH35.1 187,132.35 186.36,132.35 185.16,131.14 v5(183.95,131.14) 179.66,131.14 179.05,131.76
PEG_HTX_GRX_P1: length 14.3
  BOTTOM w0.076: UH1.A11 175.77,133.68 175.66,133.68 175.56,133.58 175.56,133.46 175.74,133.28 176.15,133.28 176.19,133.32 176.77,133.32 177.07,133.03 178.95,133.03 179.04,133.11 179.06,133.11
  BOTTOM w0.152: CH33.1 187.67,134.27 186.01,134.27 v5(184.87,133.14) 184,132.26 180.33,132.26 179.48,133.11 179.06,133.11
PEG_HTX_GRX_P2: length 13.7
  BOTTOM w0.076: 177.7,133.61 177.68,133.61 177.59,133.7 176.3,133.7 176.08,133.92 175.02,133.92 UH1.C12
  BOTTOM w0.152: CH31.1 186.28,135.12 186.11,135.12 185.53,134.55 185.13,134.55 183.32,132.73 v5(182.41,132.73) 180.68,132.73 179.8,133.61 177.7,133.61
PEG_HTX_GRX_P3: length 14.5
  BOTTOM w0.076: UH1.A13 175.55,135.18 175.48,135.11 175.48,134.99 175.64,134.83 176.07,134.83 176.17,134.93 176.79,134.93 177.03,134.69 177.68,134.69 177.77,134.78 177.79,134.78
  BOTTOM w0.152: CH29.1 187.66,136.99 186.13,136.99 185.14,136 184.39,136 v5(183.87,135.47) 182.65,134.26 180.9,134.26 180.38,134.78 177.79,134.78
PEG_HTX_GRX_P4: length 13.2
  BOTTOM w0.076: UH1.C14 174.69,135.82 174.69,135.69 174.9,135.48 176.12,135.48 176.27,135.34 177.66,135.34 177.75,135.25 177.77,135.25
  BOTTOM w0.152: 177.77,135.25 v5(179.1,135.25) 182.9,135.25 184.36,136.71 185.15,136.71 186.06,137.62 186.27,137.62 CH27.1
PEG_HTX_GRX_P5: length 14.3
  BOTTOM w0.076: UH1.A15 175.56,136.76 175.47,136.68 175.47,136.56 175.62,136.42 176.01,136.42 176.18,136.59 176.72,136.59 177.01,136.3 177.52,136.3 177.6,136.39 177.62,136.39
  BOTTOM w0.152: 177.62,136.39 181.96,136.39 182.55,136.99 183.06,136.99 184.3,138.23 v5(184.7,138.23) 185.04,138.23 185.89,139.08 187.66,139.08 CH25.1
PEG_HTX_GRX_P6: length 13.5
  BOTTOM w0.076: UH1.C16 174.67,137.42 174.67,137.32 174.89,137.1 176.08,137.1 176.21,136.97 177.29,136.97 177.38,136.89 177.4,136.89
  BOTTOM w0.152: 177.4,136.89 v5(181.18,136.89) 181.63,136.89 182.34,137.59 182.98,137.59 185.24,139.85 186.19,139.85 CH23.1
PEG_HTX_GRX_P7: length 14.4
  BOTTOM w0.076: 177.66,138 177.64,138 177.55,137.91 177.04,137.91 176.83,138.12 176.25,138.12 176.11,137.98 175.62,137.98 175.46,138.14 175.46,138.23 175.56,138.33 UH1.A17
  BOTTOM w0.152: 177.66,138 v5(178.22,138) 181.17,138 182.1,138.93 182.7,138.93 184.89,141.13 187.67,141.13 CH21.1
PEG_HTX_GRX_P8: length 13.8
  BOTTOM w0.076: UH1.B18 175.06,139.26 174.96,139.26 174.83,139.13 174.83,138.89 174.91,138.81 175.44,138.81 175.57,138.68 176.17,138.68 176.28,138.58 177.82,138.58 177.91,138.49 177.93,138.49
  BOTTOM w0.152: 177.93,138.49 181,138.49 182.2,139.68 182.8,139.68 v5(182.99,139.87) 184.89,141.78 186.17,141.78 CH19.1
PEG_HTX_GRX_P9: length 14.5
  BOTTOM w0.076: UH1.B19 175.7,139.4 176.15,139.4 176.26,139.51 176.7,139.51 176.84,139.38 177.89,139.38 177.98,139.29 178,139.29
  BOTTOM w0.152: CH17.1 187.63,142.79 187.27,142.79 187.16,142.68 185.84,142.68 185.74,142.58 183.97,142.58 v5(181.11,139.71) 180.68,139.29 178,139.29
PEG_HTX_GRX_P10: length 13.2
  BOTTOM w0.076: 177.5,140.49 177.48,140.49 177.39,140.4 174.94,140.4 174.85,140.5 174.85,140.63 174.91,140.69 UH1.B20
  BOTTOM w0.152: CH15.1 185.79,143.95 183.76,143.95 v5(182.98,143.17) 180.3,140.49 177.5,140.49
PEG_HTX_GRX_P11: length 14.1
  BOTTOM w0.076: UH1.B21 175.31,141.37 175.31,141.18 175.5,140.99 176.09,140.99 176.26,141.16 176.81,141.16 176.89,141.08 177.36,141.08 177.45,140.99 177.47,140.99
  BOTTOM w0.152: CH13.1 187.05,144.7 183.72,144.7 181.6,142.59 v5(181.6,142.57) 181.59,142.57 180.01,140.99 177.47,140.99
PEG_HTX_GRX_P12: length 13.5
  BOTTOM w0.076: 177.5,142.11 177.49,142.11 177.4,142.02 176.75,142.02 176.58,141.85 176.16,141.85 176.09,141.93 174.9,141.93 174.81,142.02 174.81,142.18 174.9,142.27 UH1.B22
  BOTTOM w0.152: CH11.1 185.64,146.3 183.74,146.3 v5(182.94,145.5) 179.55,142.11 177.5,142.11
PEG_HTX_GRX_P13: length 14.4
  BOTTOM w0.076: 178.64,142.59 178.62,142.59 178.53,142.68 176.36,142.68 176.25,142.56 175.54,142.56 175.34,142.77 175.34,142.92 UH1.B23
  BOTTOM w0.152: CH9.1 187.06,147.05 186.69,147.05 186.55,147.19 183.98,147.19 v5(180.22,143.43) 179.38,142.59 178.64,142.59
PEG_HTX_GRX_P14: length 14
  BOTTOM w0.076: UH1.B24 175.2,143.94 175.14,144 174.91,144 174.83,143.91 174.83,143.64 174.91,143.56 175.5,143.56 175.66,143.4 176.07,143.4 176.19,143.28 178.12,143.28 178.6,143.76 178.73,143.76 178.74,143.78
  BOTTOM w0.152: CH7.1 185.6,148.32 183.99,148.32 v5(180.43,144.75) 179.98,144.3 179.27,144.3 178.74,143.78
PEG_HTX_GRX_P15: length 13.4
  BOTTOM w0.076: UH1.B25 175.41,144.41 175.41,144.36 175.54,144.24 175.64,144.14 176.18,144.14 176.27,144.23 177.71,144.23 178.16,144.68 178.28,144.68 178.29,144.69
  BOTTOM w0.152: 178.29,144.69 178.71,145.1 179.67,145.1 v5(182.85,148.28) 183.68,149.12 184.07,149.12 185.33,150.37 185.61,150.37 CH5.1
PEG_RCOMP: length 7
  BOTTOM w0.076: RH24.2 172.16,122.78 v1(171.63,122.26)
  BOTTOM w0.254: UH1.G2 172.65,127.15 172.65,126.2 173.02,125.82
  BOTTOM w0.381: RH24.2 172.42,123.2 173.43,124.21 173.43,125.41 173.02,125.82
PEX_TERMP: length 7.2
  BOTTOM w0.102: UV18.AP29 192.22,148.59 190.49,150.32
  BOTTOM w0.14: 190.49,150.32 190.49,151.28 189.67,152.09 RV578.2 187.62,152.09 v1(187.35,152.35)
PEX_TSTCLK_OUT: length 1.2
  TOP w0.14: T4991.1 197.02,145.8 v2(196.84,145.62)
  BOTTOM w0.102: v2(196.84,145.62) 196.45,146.01 UV18.AJ26
PEX_TSTCLK_OUT#: length 1.6
  TOP w0.14: v2(196.08,145.56) 195.64,145.99 T4992.1
  BOTTOM w0.102: UV18.AK26 195.6,146.03 v2(196.08,145.56)
PEX_VDD_EN: length 3
  TOP w0.14: U33.20 202.54,119.73 201.6,120.67 v2(201.41,120.67)
  BOTTOM w0.14: v2(244.6,178.03) 244.31,177.74 PR907.1
PIN5_PD#: length 1.4
  TOP w0.14: RI36.1 317.05,101.48 UI3.5
PJRSVD1: length 1.3
  TOP w0.089: T4960.1 91.07,81.25 90.63,81.25 v2(90.43,81.04)
  BOTTOM w0.089: UH2.AH14 90.58,80.9 v2(90.43,81.04)
PJRSVD2: length 1.2
  TOP w0.089: T4959.1 90.22,80.27 v2(89.87,79.92)
  BOTTOM w0.089: UH2.AH15 89.8,79.98 v2(89.87,79.92)
PJRSVD3: length 1.8
  TOP w0.089: v2(82.61,87.19) 82.71,87.29 T4957.1
  BOTTOM w0.089: UH2.N32 82.04,87.75 v2(82.61,87.19)
PJRSVD4: length 1.3
  TOP w0.089: T4958.1 82.28,86.76 v2(82.35,86.69)
  BOTTOM w0.089: v2(82.35,86.69) 82.05,86.69 UH2.R32
PJRSVD5: length 2.1
  TOP w0.089: v2(79.53,85.37) 80.13,85.97 T4956.1
  BOTTOM w0.089: v2(79.53,85.37) 79.53,85.54 79.84,85.85 UH2.U35
PJRSVD6: length 1.2
  TOP w0.089: T4955.1 79.2,85.62 v2(78.98,85.41)
  BOTTOM w0.089: UH2.U37 79.36,85.78 v2(78.98,85.41)
PJRSVD7: length 2.1
  TOP w0.089: T4953.1 91.34,84.22 v2(90.96,83.84)
  BOTTOM w0.089: UH2.Y14 90.96,84.22 v2(90.96,83.84)
PJRSVD8: length 1.9
  TOP w0.089: T4954.1 90.38,84.26 v2(90.38,83.82)
  BOTTOM w0.089: v2(90.38,83.82) 89.8,84.4 UH2.Y15
PLTRST_CPU#: length 29.6
  TOP w0.14: v2(129.94,152.57) 129.44,152.57 v4(129.36,152.49) 128.4,151.53 126.28,151.53 126.12,151.69 119.02,151.69 118.03,152.67 118.03,157.46 116.95,158.54 RH480.1
  BOTTOM w0.076: 132.38,152.47 133.08,152.47 134.47,151.07 135.41,151.07 135.5,151.16 136.19,151.16 UH1.BP35
  BOTTOM w0.089: v2(94.11,81.31) 94.11,81.2 94.32,80.99 UH2.AG5
  BOTTOM w0.14: 132.38,152.47 132.28,152.57 v2(129.94,152.57)
  vias: v2(122.69,122.27)
PM_LANPHY_ENABLE: length 4.3
  BOTTOM w0.089: 77.47,68.6 77.47,69.01 77.27,69.21 77.27,69.59 76.56,70.3 76.56,70.51 77.1,71.05 77.14,71.09 77.14,71.82 UH2.BF41
  BOTTOM w0.14: 77.47,68.6 RH5842.1
PMRSVD1: length 5.3
  BOTTOM w0.089: UH2.BC1 97.28,73.58 99.75,73.58
  BOTTOM w0.14: T4961.1 101.28,74.69 100.17,73.58 99.75,73.58
PMRSVD2: length 1.7
  TOP w0.089: v2(80.73,83.97) 80.31,84.38 T4963.1
  BOTTOM w0.089: UH2.Y35 80.22,84.47 v2(80.73,83.97)
PMRSVD3: length 1.7
  TOP w0.089: v2(80.14,83.91) 80.39,83.66 T4962.1
  BOTTOM w0.089: v2(80.14,83.91) 79.45,84.6 UH2.Y36
POWER_SW_IN#: length 6.6
  TOP w0.14: v2(294.72,80.06) UE3.D5 ; v2(286.39,80.08) 286.56,80.26 286.56,80.84 286.13,81.27 CE30.1 RE34.2 RE110.1 RE36.1 v1(287.15,84.85)
PP_HV: length 1.2
  TOP w0.14: 20.35,121.48 v1(19.19,121.48)
  vias: v2(21.35,121.6) v2(21.66,121.08)
PROC_DETECT#: length 41.9
  TOP w0.127: v2(70.46,90.78) 70.93,90.78 v1(71.11,90.95) 71.42,90.95 71.7,91.22 71.7,92.53 72.68,93.51 74.6,93.51 75.07,93.97 75.79,93.97 76.15,94.33 76.15,95.28 76.68,95.81 77.34,95.81 78.5,96.97 78.69,96.97 80.22,98.51 80.22,100.39 80.74,100.91
  TOP w0.14: 80.74,100.91 81.72,100.91 82.62,100 82.62,99.61 83.86,98.37 100.84,98.37 101.42,98.95 101.42,99.23 101.1,99.55 v2(101.1,99.93)
  BOTTOM w0.089: v2(77.42,78.38) 77.39,78.36 77.39,77.91 UH2.AP41
  BOTTOM w0.14: RH519.1 128,150.64 127.88,150.77 v2(127.29,150.77)
PROC_DETECT#_R: length 8.4
  BOTTOM w0.076: UH1.BR33 135.51,149.56 134.52,149.56 134.34,149.74 132.44,149.74 132.43,149.75 132.38,149.75
  BOTTOM w0.14: RH1958.2 128.98,151.28 RH519.2 129.55,150.64 v1(129.95,150.25) 130.33,149.87 130.73,149.87 130.96,149.64 131.41,149.64 131.53,149.75 132.38,149.75
PROCHOT#_ISL88738: length 6.3
  TOP w0.203: PU1900.23 49.14,82.8 50.38,84.05 v2(51.05,84.05) 51.05,84.35 51.42,84.73 PR1919.2
  BOTTOM w0.14: v2(60.63,82.32) 61.25,81.7 v1(61.25,81.03)
  BOTTOM w0.254: PQ224.1 60.64,82.86 60.64,82.33 v2(60.63,82.32)
PS8713_PD#: length 6
  TOP w0.14: v2(313.74,105.3) v1(313.74,103.9) 313.74,103.52 315.77,101.49 RI36.2 ; v2(319.39,111.4) RI46.2
PS8713_PD#_R: length 3.6
  TOP w0.14: QI10.1 324.35,111.65 322.69,111.65 v1(322.38,111.34) 321.37,111.34 RI46.1
PS_ID: length 7.5
  TOP w0.076: UE3.J6 v2(298.72,80.86)
  TOP w0.14: PQ100.3 20.29,152.92 20.42,153.04 PR100.2 20.42,153.43 19.99,153.43 19.81,153.61 PR101.2 19.81,156.28 v1(20.34,156.81) 20.38,156.85 v2(21.19,156.85)
  vias: v2(57.81,89.53) v2(61.22,78.31)
PSID: length 9
  TOP w0.14: v2(23.34,150.85) 23.69,150.5 24.41,150.5 24.89,150.02 PR102.1 25.11,150.02 25.49,150.4 v4(25.49,151.49)
  BOTTOM w0.14: v2(23.34,150.85) 22.64,151.54 ADP100.4
PSID-1: length 5.2
  TOP w0.14: PR103.2 20.42,154.55 PR105.1 21.01,154.75 21.28,155.03 21.95,155.03 PQ101.2 22.93,156.51 v1(22.21,157.22)
PSID-2: length 5.1
  TOP w0.14: v1(24.03,155.42) 23.28,155.42 PQ101.1 22.28,153.76 22.2,153.69 PR104.1 22.2,152.82 22.22,152.8 PQ100.2
PTP_DIS#: length 46.5
  TOP w0.14: v2(295.52,79.26) UE3.F4
  BOTTOM w0.14: v2(224.71,76.6) 224.71,80.92 223.3,82.33 188.59,82.33 187.96,81.71 187.96,78.93 188.76,78.13 JTP.3
  vias: v2(278.38,80.97)
PTP_INT#: length 5
  TOP w0.089: DH1.1 82.65,69.46 82.26,69.85 v2(82.26,69.89)
  TOP w0.14: QE13.1 186.31,73.76 186.31,73.75 186.31,73.14 186.3,73.13 RE138.1 v1(185.22,72.67) 184.86,72.32 v2(184.86,71.52)
PTP_INT#_R: length 7.8
  TOP w0.14: v2(185,75.94) 185.3,75.94 QE13.3 185.66,76.91 185.85,77.1 RE87.2 v4(184.65,77.44)
  BOTTOM w0.14: JTP.4 187.76,76.42 187.37,76.02 185.08,76.02 v2(185,75.94)
PWM1_1PH/ICCMAX1: length 5.4
  TOP w0.14: v2(104.06,162.69) v1(104.89,162.69)
  TOP w0.203: PU1100.44 109.61,171.91 110.16,171.37 v2(110.16,171.21)
  BOTTOM w0.254: PR1123.1 109.05,171.9 109.22,171.73 109.87,171.73 110.16,171.44 v2(110.16,171.21)
  BOTTOM w0.305: PU1701.1 v2(104.06,162.69)
PWM1_2PH/ICCMAX2: length 9.2
  TOP w0.14: v2(110.03,137.44) v1(110.03,136.71)
  TOP w0.254: v2(109.52,182.64) 109.02,182.14 109.02,181.25 108.76,180.99 108.76,179.96 109.21,179.51 PU1100.23
  BOTTOM w0.254: PU1700.1 v2(110.03,137.44) ; v2(109.52,182.64) 107.62,180.74 PR1158.1
PWM1_4PH/ICCMAX4: length 5.1
  TOP w0.14: v1(130.48,184.45) 130.14,184.79 v2(129.08,184.79)
  TOP w0.203: PU1100.18 111.21,180.5 v2(111.43,180.72)
  BOTTOM w0.254: v2(111.43,180.72) 112.41,180.72 PR1161.1 ; PU1200.1 v2(129.08,184.79)
PWM2_2PH/ROSC1: length 6.6
  TOP w0.203: PU1100.22 109.61,179.57 109.27,179.91 v1(109.27,180.6) 109.27,180.87 109.52,181.12 109.52,181.76 v2(109.91,182.14)
  BOTTOM w0.14: PR1165.1 108.51,180.74 v2(109.91,182.14)
PWM2_4PH/ADDR: length 4.4
  TOP w0.14: v1(138.76,184.98) 138.46,184.68 v2(138.1,184.68)
  TOP w0.203: PU1100.19 110.81,180.71 v2(110.8,180.72)
  BOTTOM w0.14: PR1162.1 111.18,180.34 v2(110.8,180.72)
  BOTTOM w0.305: v2(138.1,184.68) 138.65,184.68 PU1201.1
PWM3_4PH/VBOOT: length 3.4
  TOP w0.14: v2(147.12,184.6) v1(147.76,184.6)
  TOP w0.203: PU1100.20 110.41,179.7 110.29,179.83 v2(110.29,180.4)
  BOTTOM w0.14: v2(110.29,180.4) 110.29,180.4 PR1163.1
  BOTTOM w0.254: PU1251.1 v2(147.12,184.6)
PWM4_4PH/ROSCM: length 6.4
  TOP w0.14: v2(154.42,184.6) v1(155.19,184.6)
  TOP w0.203: v2(110.16,181.5) 110.16,181.12 109.78,180.74 109.78,179.88 110.01,179.64 PU1100.21
  BOTTOM w0.14: PR1164.1 109.4,180.74 v2(110.16,181.5)
  BOTTOM w0.254: PU1252.1 v2(154.42,184.6)
PWM_FAN1: length 24.7
  TOP w0.14: RE100.2 97.5,100.14 v2(97.53,100.12) ; v2(252.35,96.56) v4(251.78,96.56) ; UE3.L10 300.32,84.86 301.68,84.86 301.93,85.11 v2(302.79,85.11)
  BOTTOM w0.14: v2(302.31,97.66) 301.7,97.05 301.7,94.54 302.29,93.95 302.29,92.2 302.14,92.04 302.14,89.22 302.64,88.71 302.64,85.26 v2(302.79,85.11) ; v2(97.53,100.12) 97.3,100.12 96.33,101.09 93.02,101.09 92.36,101.75 JFAN1.1
  vias: v2(111.57,98.7)
PWM_FAN2: length 13.7
  TOP w0.14: UE3.L11 300.41,85.74 300.41,87.42 300.75,87.76 300.75,87.92 v2(300.75,87.93)
  BOTTOM w0.14: JFAN2.1 334.37,121.39 332.5,119.53 RE101.2 332.5,117.63 332.21,117.34 329.29,117.34 328.94,117 v1(328.94,116.48) 328.94,116.05 v2(329.51,115.48)
PWR_BTN_DOCK1#: length 3.2
  TOP w0.14: RT182.2 23.75,121.93 RT194.2 23.63,121.47 23.53,121.36 QV89.3 22.55,120.73 v1(22.24,120.41)
PWR_DEBUG#_XDP: length 4.8
  TOP w0.14: v1(129.5,163.91) 128.85,163.91 128.56,163.62 RH488.1 128.23,164.47 RH483.2 127.75,164.01 127.38,164.01 127.07,163.7 JXDP.45
PWR_TB_DOCK#: length 2.5
  TOP w0.14: v2(25.71,115.93) 25.29,116.36 RT195.2 ; RE110.2 285.1,83.95 284.49,83.95 v1(284.26,83.72) 284.26,83.45 v2(284.51,83.21)
  vias: v2(92.06,83.68) v2(141.88,79.11)
PWR_VGA_CORE_BOOT1:
  vias: v1(194.26,182.53)
PWR_VGA_CORE_BOOT1_1: length 1.2
  TOP w0.635: PR706.1 PC708.2
PWR_VGA_CORE_LGATE1:
  vias: v1(198.17,187.47) v2(191.19,180.61) v2(191.82,180.61) v2(199.57,186.58) v2(200.2,186.58)
PWR_VGA_CORE_PHASE1:
  vias: v1(194.27,181.09) v2(197.56,182.39) v2(197.56,181.76) v2(201.51,183.79) v2(201.53,183.18) v2(201.54,182.46)
PWR_VGA_CORE_SS: length 2.3
  TOP w0.203: PC713.1 v2(189.31,184.59) 189.45,184.46 PU700.11
PWR_VGA_CORE_TON: length 3.8
  TOP w0.203: PR704.1 188.76,186.99 189.1,186.64 189.43,186.64 190.13,185.95 191.08,185.95 191.29,185.74 PU700.9
PWR_VGA_CORE_TON_1: length 4.5
  TOP w0.14: v1(187.34,186.64) 188.05,187.36 PR701.1
  TOP w0.254: PR701.1 188.24,187.79 189.37,187.79 189.67,187.48 PR704.2 190.39,186.5 PC707.2
PWR_VGA_CORE_UGATE1: length 6.5
  TOP w0.762: 195.76,184.61 197.88,184.61 198.42,184.07 v1(198.42,181.12) 198.42,180.42
  vias: v2(198.3,179.66) v2(198.3,179.09)
PWRBTN#_XDP: length 16.4
  TOP w0.089: v2(72.11,73.53) 72.87,74.29 75.67,74.29 75.9,74.06 75.9,72.66 75.69,72.46 75.13,72.46 74.93,72.66 74.27,72.66 73.95,72.34 73.95,71.57 74.21,71.32 RH6.1 74.57,70.86 74.21,70.49 RH2.2
  TOP w0.14: JXDP.41 126.97,162.7 127.1,162.58 127.34,162.33 127.71,162.33 128.2,161.84 CH174.1 128.69,161.84 128.88,162.03 129.5,162.03 v1(129.69,161.84) 129.96,161.57 v2(129.96,161.08)
  vias: v2(58.42,89.54) v2(98.37,112.88)
RC_ID0: length 2.9
  TOP w0.076: UE3.F2 295.92,77.74 296.22,77.45 296.22,76.3 296.3,76.22
  TOP w0.14: 296.3,76.22 296.35,76.16 T4982.1
REFADJ_NVVDD: length 2.7
  BOTTOM w0.203: PR1007.2 163.28,185.21 163.87,184.62 164.72,184.62 165.09,184.25 PU1001.6
REFADJ_NVVDDS: length 1.6
  BOTTOM w0.203: PR1507.2 183.99,181.38 184.79,182.18 PU1501.6
REFIN_NVVDD: length 3.1
  BOTTOM w0.203: PC1017.1 165.66,184.74 165.49,184.57 PU1001.7
  BOTTOM w0.508: PC1017.1 164.86,185.27 PR1008.1 PR1006.1
REFIN_NVVDDS: length 6.3
  TOP w0.14: PR1509.1 v1(183.11,180.1)
  TOP w0.508: PR1509.1 183.1,181.25 182.96,181.38 PR1508.1 183.8,182.17 v2(183.92,182.05)
  BOTTOM w0.203: PC1518.1 183.17,182.58 PU1501.7
  BOTTOM w0.381: PC1518.1 183.14,182.25 183.35,182.05 v2(183.92,182.05)
REM_DIODE1_N: length 12.5
  TOP w0.127: v2(155.78,137.32) QE15.3 156.31,138.65 156.31,139.06 CE69.1 ; UE3.A8 291.66,82.59 290.39,82.59 290.17,82.36 289.76,82.36 CE32.1 289.1,82.26 288.88,82.26 v2(288.72,82.43)
  BOTTOM w0.127: v2(115.23,183.27) 115.4,183.09 115.4,182.91 115.13,182.64 114.71,182.64 114.33,183.03 113.66,183.03 CE45.1 113,183.03 112.38,183.03 112.23,183.17 QE7.2 111.28,183.55 QE7.1
  vias: v2(260.98,90.09)
REM_DIODE1_P: length 12.1
  TOP w0.127: QE15.1 v2(156.43,137.31) 157.08,137.96 QE15.2 156.65,138.56 156.65,138.92 CE69.2 ; v2(288.72,81.79) 288.93,82.01 289.2,82.01 CE32.2 289.86,82.11 290.27,82.11 290.5,82.34 291.64,82.34 UE3.A7
  BOTTOM w0.127: v2(115.84,183.27) 115.66,183.09 115.66,182.81 115.24,182.39 114.6,182.39 114.22,182.77 113.66,182.77 CE45.2 113,182.77 112.38,182.77 112.23,182.62 QE7.3
  vias: v2(260.98,90.71)
REM_DIODE2_N: length 126.1
  TOP w0.127: v2(193.74,124.05) 193.88,124.19 193.88,124.42 193.75,124.55 193.55,124.55 189.54,120.54 189.54,119.17 189.43,119.07 189.35,118.97 189.35,118.91 189.29,118.85 187.82,117.37 QE6.3 187.51,116.25 187.51,115.61 CE47.2 187.42,115.17 187.42,114.97 187.52,114.86 189.48,114.86 191.26,113.09 191.26,110.89 194.58,107.57 219.07,107.57 219.37,107.27 245.29,107.27 246.36,106.2 249.94,106.2 257.55,98.59 257.55,96.06 258.39,95.22 258.39,90.36 258.61,90.15 258.61,78.38 258.24,78.01 258.24,75.29 258.65,74.87 258.65,74.14 v2(258.83,73.97) ; v2(288.73,85.26) 288.73,85.24 288.88,85.08 289.13,85.08 CE33.1 289.79,85.13 290.25,85.13 291.19,84.19 291.66,84.19 UE3.A10
  BOTTOM w0.127: QE5.1 172.06,184.34 171.55,184.85 171.55,185.32 171.91,185.68 QE5.2 172.29,186.33 CE46.2 171.91,187.47 171.65,187.22 v2(171.65,186.81)
  vias: v2(191.31,161.05)
REM_DIODE2_P: length 125.4
  TOP w0.127: v2(194.38,124.05) 194.13,124.29 194.13,124.52 193.85,124.8 193.44,124.8 189.29,120.65 189.29,119.28 189.25,119.24 189.16,119.15 189.1,119.15 189.04,119.09 188.11,118.16 QE6.1 187.17,117.21 QE6.2 187.11,115.96 187.11,115.78 CE47.1 187.16,115.04 187.16,114.86 187.41,114.61 189.38,114.61 191.01,112.98 191.01,110.78 194.47,107.32 218.96,107.32 219.27,107.02 245.18,107.02 246.25,105.95 249.83,105.95 257.3,98.48 257.3,95.96 258.14,95.11 258.14,90.26 258.35,90.04 258.35,78.49 257.98,78.12 257.98,75.18 258.4,74.76 258.4,74.14 v2(258.23,73.97) ; UE3.A9 291.64,83.94 291.08,83.94 290.14,84.88 289.84,84.88 CE33.2 289.18,84.83 288.95,84.83 v2(288.74,84.62)
  BOTTOM w0.127: v2(172.84,186.83) 172.84,187.1 CE46.1 173.34,187.33 173.34,186.08 QE5.3
  vias: v2(190.75,160.85)
REM_DIODE3_N: length 110.7
  TOP w0.076: 290.75,83.39 290.77,83.39 290.8,83.36 292.42,83.36 UE3.B9
  TOP w0.127: v2(287.4,83.74) 287.83,84.17 CE35.1 288.42,83.84 289.77,83.84 290.22,83.39 290.75,83.39
  BOTTOM w0.127: v2(116.41,102.91) 116.41,102.66 117.23,101.83 162.55,101.83 176.46,115.75 177.37,115.75 177.5,115.62 177.5,114.93 177.68,114.75 177.99,114.75 178.24,115.01 QE8.2 178.24,115.72 177.59,116.37 QE8.1 177.75,116.89 178.96,116.89 179.21,116.64 179.52,116.64 CE49.2 180.06,116.59 185.2,116.59 188.01,119.4 188.01,119.88 v2(187.83,120.06) ; v2(37.4,105.76) 37.62,105.97 37.8,105.97 38.09,106.26 38.09,107.07 35.31,109.85 35.31,110.67 32.17,113.81 32.17,114.53 29.16,117.54 28.74,117.54 28.24,118.04 27.72,118.04 CE68.2 26.89,117.89 26.89,116.86 26.61,116.58 QE11.3
  vias: v2(92.69,108.9) v2(261.57,91.4)
REM_DIODE3_P: length 110.7
  TOP w0.076: UE3.B8 292.42,83.16 290.8,83.16 290.77,83.13 290.75,83.13
  TOP w0.127: v2(286.92,83.36) 287.19,83.09 287.92,83.09 CE35.2 288.42,83.58 v5(289.28,83.58) 289.66,83.58 290.11,83.13 290.75,83.13
  BOTTOM w0.127: v2(188.42,120.06) 188.26,119.9 188.26,119.29 185.31,116.33 180.13,116.33 CE49.1 179.27,115.97 178.76,116.48 178.59,116.48 178.45,116.35 178.45,115.99 178.94,115.5 178.94,114.71 178.58,114.34 177.73,114.34 QE8.3 176.2,115.13 162.65,101.58 117.13,101.58 116.28,102.43 v2(115.95,102.43) ; QE11.2 26.2,115.28 26.85,115.93 QE11.1 27.36,116.29 27.17,116.48 27.17,117.25 CE68.1 27.7,117.79 28.14,117.79 28.63,117.29 29.05,117.29 31.92,114.43 31.92,113.7 35.05,110.57 35.05,109.75 37.83,106.96 37.83,106.37 37.69,106.23 37.57,106.23 v2(37.4,106.39)
  vias: v2(92.33,108.29) v2(261.59,90.77)
REM_DIODE4_N: length 30.4
  TOP w0.127: v2(287.22,86.76) 287.37,86.61 287.73,86.61 CE36.1 288.42,86.63 v5(289.47,86.63) 290.27,86.63 291.71,85.2 291.86,85.2 UE3.A11
  BOTTOM w0.127: v2(238.39,172.75) CE72.1 239.14,173.83 239.4,174.08 239.4,176.04 QE9.3 ; QE12.1 279.2,94.36 QE12.2 279.32,93.18 279.32,92.93 CE50.1 279.34,92.28 279.34,91.98 278.9,91.54 276.55,91.54 276.36,91.34 276.36,91.07 v2(276.55,90.88) 276.35,90.69 276.35,90.54 276.45,90.44 280.43,90.44 282.55,88.32 284.9,88.32 286.67,86.56 287.02,86.56 v2(287.22,86.76)
REM_DIODE4_P: length 31.1
  TOP w0.127: v2(287.27,86.13) 287.49,86.35 287.78,86.35 CE36.2 288.42,86.38 290.17,86.38 291.69,84.85 292.4,84.85 292.72,84.54 UE3.B10
  BOTTOM w0.127: v2(238.38,172.15) 238.25,172.15 237.87,172.53 237.87,173.14 CE72.2 238.87,174.15 QE9.1 238.87,175.52 QE9.2 ; QE12.3 279.07,93.18 279.07,92.93 CE50.2 279.08,92.26 279.08,92.08 278.79,91.79 276.44,91.79 276.1,91.45 276.1,91.03 v2(275.94,90.87) 276.1,90.71 276.1,90.44 276.35,90.19 280.32,90.19 282.44,88.07 284.8,88.07 286.56,86.3 287.09,86.3 v2(287.27,86.13)
RESET_IN#: length 4.1
  TOP w0.14: UE3.C1 293.46,77.2 293.46,76.08 292.28,74.9 RE145.2 292.28,74.44 RE311.2
RING2: length 0.8
  TOP w0.127: v2(7.65,125.18) v1(7.65,125.94)
  vias: v2(6.4,111.44) v2(6.4,110.85) v2(7.02,125.19) v2(7.73,124.61) v2(8.32,124.64)
RING2_L: length 1.6
  TOP w0.127: JHP1.3 v1(0.96,125.19)
ROM_CS: length 1.2
  TOP w0.14: v2(214.43,128.85) 214.55,128.85 T205.1
  BOTTOM w0.102: v2(214.43,128.85) 214,129.28 UV18.H6
ROM_SCLK: length 2.2
  TOP w0.14: v2(227.77,117.82) RV644.2 227.77,118.5 RV641.1
  BOTTOM w0.102: UV18.H4 214,127.69 v2(214.43,127.26)
ROM_SI: length 15.8
  TOP w0.14: v2(214.45,128.1) 215.68,126.88 215.68,126.31 215.92,126.07 217,126.07 v1(221.21,121.85) 222.68,120.38 222.68,119.02 RV642.2 RV639.1
  BOTTOM w0.102: UV18.H5 214.07,128.49 v2(214.45,128.1)
ROM_SO: length 20.6
  TOP w0.102: v2(213.61,130.62) 214.06,130.18 214.06,129.59 214.31,129.34
  TOP w0.14: RV640.1 RV643.2 223.7,119.02 223.7,121.59 v1(222.35,122.93) 221.25,124.03 219.37,124.03 216.54,126.87 216.54,127.45 216.56,127.48 216.56,128.25 216.31,128.5 215.81,128.5 215.71,128.61 215.71,129.08 215.45,129.34 214.31,129.34
  BOTTOM w0.102: UV18.H7 213.61,130.58 v2(213.61,130.62)
RREF:
  vias: v1(334.63,101.62)
RT8812_PVCC: length 6.5
  TOP w0.203: PU700.18 191.69,181.63 191.38,181.31 189.85,181.31 189.53,180.99 PC706.1 188.37,180.56 v1(188.3,180.49) 188.3,179.82 PR700.1
RTCRST_ON: length 29.5
  TOP w0.076: UE3.F11 296.21,85.55 296.21,87.52
  TOP w0.14: D321.1 173.36,70.57 172.53,71.39 v2(172.42,71.39) 171.89,71.39 R3.2 171.3,71.23 QRTC.2 172.14,73.42 R277.1 C4.1 173.74,73.42 173.86,73.55 RE143.2 174.52,74.07 QR104.2 ; v2(270.18,70.23) 270.18,82.78 v1(270.8,83.41) v2(272.83,85.44) ; v2(295.61,88.49) 296.21,87.88 296.21,87.52
RTCRST_ON_R: length 12.4
  TOP w0.14: QRTC1.2 177.16,71.77 175.66,71.77 v1(175.03,71.15) 175.03,70.42 174.45,69.84 171.05,69.84 C2.1 R3.1 171.12,70.49 172.29,70.49 D321.2
RTD3_CIO_PWR_EN: length 6.5
  TOP w0.089: v1(86.72,78.61) 86.77,78.61 87.47,77.91 v2(87.68,77.91)
  BOTTOM w0.089: v2(87.68,77.91) 87.3,77.53 UH2.AP21
  BOTTOM w0.14: RT5842.2 16.99,117.59 17.43,117.15 18.04,117.15 18.22,116.97 18.22,116.38 17.97,116.13 v2(17.75,116.13) 17.48,116.13 17.35,116.26 RT39.2 RT5850.2
  vias: v2(18.8,92.28)
RTD3_CIO_PWR_EN_AR: length 2.8
  BOTTOM w0.089: UT1.F1 22.04,111.86 22.37,112.19 v2(22.37,112.48)
  BOTTOM w0.14: v1(18.66,117.94) 18.44,118.15 v2(17.88,118.15) 17.77,118.15 17.68,118.24 17.18,118.24 RT5842.1
RTD3_USB_PWR_EN: length 10.5
  TOP w0.089: 23.58,113.05 23.43,112.89 23.43,112.06 23.32,111.96 22.48,111.96 21.97,111.45 21.97,110.97 21.17,110.17 v6(20.61,110.17)
  TOP w0.14: 23.58,113.05 23.64,113.1 23.64,113.44 v1(23.94,113.75) 24.01,113.75 24.41,114.14 24.41,114.54 24.5,114.64 RT40.2 24.33,114.81 24.04,115.1 24.04,116.22 23.56,116.7 RT5841.2
  BOTTOM w0.089: UT1.D4 20.9,110.48 20.61,110.2 v6(20.61,110.17)
RUN_ON#: length 2.8
  TOP w0.14: v1(281.64,71.47) 281.64,70.58 RE56.2 281.82,70.49 QE4.6 QE4.5
RUN_ON_EC: length 127.1
  TOP w0.076: UE3.E8 v2(294.72,83.26)
  TOP w0.14: RE35.1 300.66,90.26 301.04,90.63 v2(301.08,90.63) ; v2(126.03,76.91) 126.04,76.91 127.15,78.03 127.15,81.77 125.32,83.6 116.94,83.6 116.08,84.46 115.2,84.46 113.92,85.74 112.85,85.74 111.88,86.71 110.2,86.71 109,87.91 109,92.71 106.41,95.3 106.41,103.47 109.44,106.5 113.87,106.5 120.08,112.71 120.08,115.53 119.64,115.97 v2(119.37,115.97) ; v2(237.92,70) 237.05,70.87 UZ6.1 234.16,69.61 v1(232.71,69.61) 232.46,69.87 RZ1956.1 228.83,75.2 228.52,75.2 227.76,75.96 227.76,76.73 228.08,77.04 228.46,77.04 229.09,76.41 UZ33.3 ; v2(110.97,120.44) 110.94,120.47 UZ20.1 ; QE4.2 284.47,71.14 284.26,71.34 283.8,71.34 283.43,70.97 v2(283.43,70.78) ; UZ1.5 261.48,106.01 261.92,105.57 RZ43.2 262.06,105.35 262.51,105.35 262.81,105.05 v2(262.81,104.62) 262.59,104.62 262.24,104.96 261.15,104.96 260.9,105.21 UZ1.3
  BOTTOM w0.076: 292.34,84.45 294.09,84.45 294.32,84.22 294.32,83.88 294.72,83.48 v2(294.72,83.26)
  BOTTOM w0.14: v2(273.93,89.85) 273.93,87.96 277.33,84.57 277.33,80.52 278.09,79.76 278.09,75.71 277.36,74.97 277.36,72.62 279.2,70.78 v2(283.43,70.78) ; v2(290.92,90.02) 290.92,86.69 291.52,86.1 291.52,85.28 292.34,84.45
  vias: v2(178.17,74.06)
RUN_ON_EC_GATE: length 16.3
  TOP w0.14: RZ58.1 105.65,110.79 106.43,110.01 v1(112.71,110.01) 113.28,110.01 v2(113.4,110.13) ; UZ20.4 109.13,118.86 109.39,119.13 v2(111.37,119.13) 111.51,119.13 112.37,119.98 112.37,120.83 111.77,121.43 RZ59.2
RUN_ON_P: length 49.2
  TOP w0.14: RZ58.2 v1(105.65,113.94) 106.28,114.57 UZ26.1 ; RZ58.2 105.37,112.68 105.08,112.39 105.08,110.93 106.24,109.77 111.88,109.77 112.11,109.54 113.66,109.54 v2(114.22,110.1) ; RZ58.2 RZ50.1 ; v2(101.52,118.89) 102.21,119.58 102.21,130.14 102.67,130.6 103.84,130.6 104.32,131.08 108,131.08 108.71,131.79 v2(112.19,131.79) ; PR610.2 287.67,98.68 287.15,98.16 287.15,96.45 285.78,95.08 285.46,95.08 284.42,94.04 284.01,94.04 283.57,94.48 282.94,94.48 282.68,94.21 v2(282.68,91.74)
  BOTTOM w0.381: PR803.1 v2(112.19,131.79)
  vias: v2(119.51,105.3)
RUNPWROK: length 7.4
  TOP w0.076: v2(297.16,77.67) 297.01,77.83 297.01,78.18 296.72,78.46 UE3.G3
  TOP w0.14: QE4.3 284.73,71.77 RE52.2 ; v2(285.94,70.78) 285.94,71.43 RE52.2 ; RE52.2 285.65,71.77 287.79,73.92 287.79,74.1 v2(287.77,74.12)
  BOTTOM w0.14: v2(56.84,70.95) 56.84,70.94 57,70.78 UH14.2
S5_1.2V: length 5.6
  TOP w0.14: v4(291.59,95.7) 290.31,95.7 PC613.1
  TOP w0.254: v2(288.9,96.32) 288.97,96.38 289.57,96.38 PC613.1
  BOTTOM w0.203: PR606.2 289.55,95.67 v2(288.9,96.32) 288.71,96.32 288.2,96.83 PU600.8
SA_B+:
  vias: v2(108.25,161.82) v2(108.25,161.18) v2(108.89,162.58) v2(109.52,162.58) v4(109.21,163.33)
SA_SW:
  vias: v1(104.25,156.84) v2(104.83,157.12) v2(104.83,156.48)
SATA_PRX_C_DTX_N2: length 1.7
  BOTTOM w0.152: JHDD.8 232.62,78.45 232.71,78.54 232.71,79.17 CS20.2
SATA_PRX_C_DTX_P2: length 1.7
  BOTTOM w0.152: CS19.2 233.04,79.17 233.04,78.54 233.12,78.45 JHDD.9
SATA_PRX_DTX_N1A: length 2.1
  BOTTOM w0.089: v2(76.87,90.81) 76.87,90.62 76.75,90.49 UH2.H42
  BOTTOM w0.152: JNGFF2.43 257.22,79.24 v2(256.91,79.55)
SATA_PRX_DTX_N2: length 1.9
  BOTTOM w0.089: v2(75.24,91.39) 75.35,91.51 75.72,91.51 UH2.F44
  BOTTOM w0.152: v2(232.89,80.69) 233.03,80.56 233.03,80.47 232.78,80.22 232.78,79.99 232.69,79.91 CS20.1
SATA_PRX_DTX_P1A: length 2.8
  BOTTOM w0.089: UH2.J41 77.19,90.42 v2(77.42,90.65)
  BOTTOM w0.152: v2(256.32,79.55) 256.32,79.58 256.77,80.03 257.09,80.03 257.38,79.74 JNGFF2.41
SATA_PRX_DTX_P2: length 1.9
  BOTTOM w0.089: v2(74.69,91.5) 75.03,91.85 UH2.E45
  BOTTOM w0.152: v2(233.6,80.69) 233.36,80.45 233.36,80.33 233.11,80.08 233.11,79.99 CS19.1
SATA_PTX_C_DRX_N1A: length 3
  BOTTOM w0.152: CD37.2 255.62,78.13 257.2,78.13 257.31,78.24 JNGFF2.47
SATA_PTX_C_DRX_N2: length 1.7
  BOTTOM w0.152: JHDD.6 231.62,78.49 231.54,78.57 231.54,79.2 CS18.2
SATA_PTX_C_DRX_P1A: length 3
  BOTTOM w0.152: CD42.2 255.71,77.82 v5(256.35,77.82) 257.39,77.82 257.47,77.74 JNGFF2.49
SATA_PTX_C_DRX_P2: length 1.8
  BOTTOM w0.152: CS17.2 231.21,79.15 231.21,78.57 231.12,78.49 JHDD.5
SATA_PTX_DRX_N1A: length 14.3
  BOTTOM w0.089: v2(78.57,91.8) 78.61,91.84 78.61,92.22 UH2.D38
  BOTTOM w0.152: v2(253.19,86.72) 252.92,86.72 252.69,86.95 252.51,86.95 251.41,85.85 251.41,84.33 250.65,83.57 250.65,82.26 251.56,81.35 251.56,79.73 253.18,78.11 253.66,78.11 253.76,78.21 253.76,78.66 253.92,78.81 254.34,78.81 254.46,78.69 CD37.1
SATA_PTX_DRX_N2: length 1.8
  BOTTOM w0.089: UH2.B40 78,93.19 78.14,93.33 78.14,93.61 78.05,93.7 v2(77.9,93.7)
  BOTTOM w0.152: v2(231.66,80.72) 231.54,80.6 231.54,80.04 CS18.1
SATA_PTX_DRX_P1A: length 14.4
  BOTTOM w0.089: UH2.E37 79.02,91.46 v2(78.87,91.31)
  BOTTOM w0.152: v2(253.05,87.29) 253.04,87.28 252.37,87.28 251.08,85.99 251.08,84.46 250.32,83.7 250.32,82.13 251.23,81.21 251.23,79.59 v5(251.79,79.04) 253.05,77.78 254.17,77.78 CD42.1
SATA_PTX_DRX_P2: length 2.4
  BOTTOM w0.089: v2(78.5,93.78) 78.5,93.55 78.41,93.46 78.41,93.22 77.84,92.65 UH2.C40
  BOTTOM w0.152: v2(231.07,80.72) 231.21,80.58 231.21,80.09 CS17.1
SATAGP0: length 6.9
  TOP w0.089: v2(76.71,80.66) 76.96,80.41 RH5844.1
  TOP w0.14: RH5894.1 23.51,144.35 v2(23.65,144.21)
  BOTTOM w0.089: UH2.AH41 76.98,80.39 v2(76.71,80.66)
  BOTTOM w0.14: v2(67.46,80.61) 67.71,80.36 68.63,80.36 68.84,80.15 68.84,79.58 69.1,79.32 70.3,79.32 70.97,78.64 v1(71.17,78.64)
  vias: v2(11.25,138.51) v2(41.83,91.98)
SATAGP3: length 5.2
  BOTTOM w0.089: UH2.AN47 74.26,77.89 73.46,77.89 73.36,78 73.07,78 72.85,78.21 72.49,78.21 71.29,79.42 71.04,79.42
  BOTTOM w0.14: RH5845.1 70.37,79.94 70.89,79.42 71.04,79.42
SATAGP4: length 5.8
  BOTTOM w0.089: 71.04,79.74 71.22,79.74 72.53,78.43 72.89,78.43 73.11,78.2 73.41,78.2 73.49,78.12 73.92,78.12 74.05,78.25 74.38,78.25 UH2.AM46
  BOTTOM w0.14: RH5846.1 70.18,80.52 70.97,79.74 71.04,79.74
SATAGP5: length 2.7
  TOP w0.089: v2(76.6,79.46) 77.01,79.05 v1(77.37,79.05) 77.91,79.05 RH5847.1
  BOTTOM w0.089: UH2.AM43 76.6,78.97 v2(76.6,79.46)
SATAGP6: length 5.7
  BOTTOM w0.089: 71.04,80.14 71.07,80.14 72.61,78.61 72.96,78.61 73.19,78.38 73.48,78.38 73.56,78.3 73.85,78.3 74.05,78.49 UH2.AM47
  BOTTOM w0.14: 71.04,80.14 70.58,80.6 70.58,80.64 70.13,81.09 RH5848.1
SATALED#: length 6.6
  BOTTOM w0.089: 71.42,82.01 71.42,81.84 72.83,80.44 73.24,80.44 73.82,79.86 UH2.AK48
  BOTTOM w0.14: RH512.1 69.46,83.41 v1(69.94,82.92) 70.75,82.92 71.42,82.25 71.42,82.01
SBIOS_TX: length 26.8
  TOP w0.14: RE297.2 305.8,92.22 307.2,93.62 310.82,93.62 311.87,92.56 v2(311.87,92) ; v2(312.12,76.58) v1(312.66,76.58)
  BOTTOM w0.089: v2(86.48,74.19) 86.41,74.25 86.12,74.25 UH2.BB24
  BOTTOM w0.14: v2(311.87,92) 312.47,91.4 312.47,88.48 311.35,87.35 311.35,85.4 310.95,85 310.95,83.38 311.91,82.41 311.91,76.78 v2(312.12,76.58)
SD_1P8_RCOMP: length 9
  BOTTOM w0.089: UH2.BE5 94.64,72.38 94.14,71.88 94.14,71.16 94.34,70.96 94.34,70.52 95.42,69.44 97.17,69.44 97.65,69.92 97.65,69.95 98.18,70.47 99.75,70.47
  BOTTOM w0.14: 99.75,70.47 99.78,70.47 RH5832.1
SD_3P3_RCOMP: length 8.6
  BOTTOM w0.089: UH2.BE4 95.11,72.1 95.1,72.09 94.86,72.09 94.69,71.93 94.69,71.62 94.67,71.6 94.67,71.09 94.51,70.93 94.51,70.6 95.44,69.67 95.46,69.67 95.51,69.61 97.1,69.61 97.48,69.99 97.48,70.02 98.11,70.65 99.51,70.65 99.75,70.88
  BOTTOM w0.14: 99.75,70.88 RH5833.1
SD_CD#: length 6.7
  TOP w0.14: v2(333.29,110.93) 333.05,110.69 JCR.8
  BOTTOM w0.14: v2(340.98,103.48) 340.46,103.48 340.25,103.69 UR1.30
SD_CLK: length 3.3
  TOP w0.14: v2(329.35,113.87) 328.97,113.49 JCR.6
  BOTTOM w0.14: RR4.2 CR8.1 v2(332.92,109.75)
SD_CLK_R: length 3.7
  BOTTOM w0.14: RR4.1 333.87,107.51 v1(334.29,107.09) 334.42,106.96 336.06,106.96 336.34,106.68 UR1.17
SD_CMD: length 4.1
  TOP w0.14: v1(326.24,120.44) JCR.3 329.2,120.44 v2(329.49,120.15)
  BOTTOM w0.14: RR5.2 v2(335.96,110.53)
SD_CMD_R: length 3
  BOTTOM w0.14: UR1.19 337.14,107.76 336.47,108.43 RR5.1
SD_D2: length 4.5
  TOP w0.14: v1(326.23,123.24) JCR.1 328.53,123.24 v2(329.55,122.22)
  BOTTOM w0.14: RR8.2 337.96,110.3 v2(337.96,110.64)
SD_D2_R: length 2.9
  BOTTOM w0.14: RR8.1 338.25,108.5 338.12,108.37 338.12,106.99 337.94,106.82 UR1.21
SD_D3: length 5.5
  TOP w0.14: v2(329.55,121.2) 328.91,121.84 JCR.2 v1(324.95,121.84)
  BOTTOM w0.14: RR7.2 v2(337.36,110.64)
SD_D3_R: length 2.8
  BOTTOM w0.14: RR7.1 337.36,108.5 337.54,108.32 v1(337.54,108.07) UR1.20
SD_LN0_M: length 10.1
  TOP w0.102: JCR.14 348.35,118.97 347.73,119.59 345.11,119.59 v2(344.92,119.4)
  BOTTOM w0.102: UR1.25 340.28,105.69 340.35,105.62 340.67,105.62 340.81,105.76 v5(341.12,105.76) 341.38,105.76 342.98,107.36 343.93,107.36 344.21,107.07 344.21,106.78 v2(344.34,106.66)
SD_LN0_P: length 9.7
  TOP w0.102: JCR.13 348.2,120.47 347.58,119.86 345.1,119.86 v2(344.92,120.03)
  BOTTOM w0.102: UR1.26 340.2,105.29 340.27,105.35 340.78,105.35 340.92,105.49 341.49,105.49 343.09,107.09 343.82,107.09 343.94,106.96 343.94,106.85 v2(343.75,106.66)
SD_LN1_M: length 4.1
  TOP w0.102: JCR.17 348.19,112.97 348.02,112.8 348.02,112.32 347.84,112.14 347.46,112.14 v2(347.32,112.28)
  BOTTOM w0.102: UR1.23 338.74,106.75 338.68,106.82 338.68,106.89 339.23,107.45 339.23,107.65 v2(339.42,107.84)
SD_LN1_P: length 3.7
  TOP w0.102: JCR.18 348.31,111.47 347.9,111.88 347.56,111.88 v2(347.32,111.64)
  BOTTOM w0.102: UR1.22 338.34,106.76 338.41,106.83 338.41,107 338.97,107.56 338.97,107.66 v2(338.79,107.84)
SD_RCLK_M: length 3
  TOP w0.102: v2(329.41,108.33) 329.27,108.46 329.05,108.46 328.49,107.89 JCR.10
  BOTTOM w0.102: RR2.2 331.45,106.56 331.34,106.56 331.14,106.37 330.92,106.37 v2(330.73,106.18)
SD_RCLK_M_R: length 3.7
  BOTTOM w0.102: RR2.1 332.99,106.56 333.82,106.56 v5(334.57,105.81) 334.73,105.65 334.97,105.65 335.34,105.29 UR1.15
SD_RCLK_P: length 3
  TOP w0.102: JCR.9 328.43,109.29 328.99,108.73 329.22,108.73 v2(329.41,108.91)
  BOTTOM w0.102: RR3.2 331.45,106.83 331.23,106.83 331.03,106.64 330.91,106.64 v2(330.73,106.82)
SD_RCLK_P_R: length 3.6
  BOTTOM w0.102: UR1.16 335.32,105.69 335.08,105.92 334.84,105.92 333.93,106.83 332.99,106.83 RR3.1
SD_REG2: length 1.1
  BOTTOM w0.14: v1(342.09,107.18) 341.78,106.88 CR16.1
SHD_CLK: length 2.1
  TOP w0.076: v3(298.74,82.48) 298.36,82.86 UE3.J8
  TOP w0.14: v1(309.09,87.8) 309.36,87.53 v2(309.36,87.35) 309.95,86.76 R5831.1
SHD_CLK_R1: length 1.4
  TOP w0.14: R5831.2 311.02,87.22 T5999.1
SHD_IO0: length 1.8
  TOP w0.14: v2(310.44,91.08) 310.18,90.82 T5997.1 ; v2(298.72,81.66) UE3.J7
SHD_IO1: length 1.6
  TOP w0.14: v2(300.32,81.66) UE3.L6 ; v2(310.95,91.46) T5998.1
SHD_IO3: length 1.7
  TOP w0.14: v2(311.45,91.08) T5996.1 ; v2(301.12,81.66) UE3.M6
SIO_EXT_SCI#: length 4.4
  TOP w0.089: v1(98.26,74.3) 98.04,74.52 v2(97.57,74.52) ; RH383.2 83.78,76.4 v2(83.64,76.54)
  BOTTOM w0.089: v2(83.64,76.54) 83.68,76.54 83.77,76.45 83.99,76.45 UH2.AU26 ; RE291.2 99.07,74.45 98.16,74.45 98.08,74.53 97.59,74.53 v2(97.57,74.52)
SIO_EXT_SCI#_R: length 2.7
  TOP w0.076: v2(301.78,76.39) 301.78,76.41 300.92,77.26 UE3.M1
  BOTTOM w0.14: v2(100.78,75.17) 100.78,74.78 100.44,74.44 RE291.1
SIO_EXT_SMI#: length 3.1
  TOP w0.076: UE3.K7 v2(299.52,81.66)
  TOP w0.14: v2(305.93,83.65) 305.8,83.52 v1(305.42,83.52) 305.14,83.81 304.33,83.81 304.14,84 RE285.1
SIO_EXT_SMI#_R: length 5.8
  TOP w0.089: v2(88.16,70.08) 88.16,69.79 v1(88.52,69.42)
  TOP w0.14: RE285.2 305.54,84.47 v2(305.7,84.31)
  BOTTOM w0.089: UH2.BF18 88.57,71.74 88.57,71.33 88.4,71.15 88.4,70.31 v2(88.16,70.08) 88.16,69.23 87.64,68.71 87.64,68.6
  BOTTOM w0.14: RH110.1 87.64,68.6
  vias: v2(306.47,82.57)
SIO_EXT_WAKE#: length 5.6
  TOP w0.089: RH523.2 86.99,76.05 v3(87.63,76.7)
  TOP w0.14: UE3.M12 300.72,86.34 301.21,86.82 301.21,86.99 301.47,87.26 v2(301.47,87.47)
  BOTTOM w0.089: v3(87.63,76.7) 87.19,76.26 86.93,76.26 86.29,75.62 85.97,75.62 UH2.AU24
SIO_PWRBTN#: length 3.3
  TOP w0.089: RH6.2 75.06,71.75 v2(75.16,71.75) 75.67,71.75 v1(76.21,72.29)
  TOP w0.14: v2(298.74,84.87) UE3.K11
  BOTTOM w0.089: v2(75.16,71.75) 74.8,72.1 UH2.BE46
  vias: v2(298.58,72.76)
SIO_RCIN#: length 4.4
  TOP w0.14: v2(305.74,78.46) 305.53,78.66 305.16,78.66 RE286.2 ; v2(107.67,69.47) RH518.1 106.05,68.53 v1(105.87,68.53)
  BOTTOM w0.089: UH2.BE39 78.25,71.29 v3(78.04,71.07)
SIO_SLP_A#: length 17.1
  TOP w0.14: RH1152.2 304.98,89.38 RE290.1 305.23,88.92 305.88,89.57 v1(307.82,89.57) 308.78,89.57 v2(309.17,89.17)
  BOTTOM w0.089: v2(77.14,70.57) 77.32,70.76 77.32,71.62 77.44,71.75 77.44,72.24 UH2.BE40
  BOTTOM w0.14: JAPS.6 173.89,73.9 172.52,72.54 167.26,72.54 166.64,71.91 v2(166.64,71.33)
  vias: v2(301.25,72.23)
SIO_SLP_A#_R: length 5.5
  TOP w0.076: 302.06,86.53 301.4,86.53 301.17,86.3 301.17,85.64 300.79,85.26 UE3.M11
  TOP w0.14: RE290.2 304.06,88.59 v1(303.1,87.62) 302.78,87.31 302.78,87.21 302.1,86.53 302.06,86.53
SIO_SLP_S0#: length 25.9
  TOP w0.14: RZ61.1 117.86,117.63 118.15,117.34 119.34,117.34 119.91,117.91 120.91,117.91 120.96,117.86 v2(121.36,117.86) ; RE125.1 160.62,70.12 v2(161.15,70.66)
  BOTTOM w0.089: v2(83.11,73.9) 83.11,73.54 UH2.BC28
  BOTTOM w0.14: v2(168.12,75.58) 168.56,76.01 168.91,76.01 169.16,75.76 169.16,75.25 169.39,75.03 JAPS.15 169.39,74.21 168.39,73.21 165.16,73.21 163.46,71.51 162,71.51 v2(161.15,70.66)
  vias: v2(112.95,98.47) v2(116.26,82.19)
SIO_SLP_S0#_TPM: length 2.9
  TOP w0.14: U32.29 152.19,71.41 152.58,71.03 RE125.2 v1(151.57,70.12)
SIO_SLP_S3#: length 108
  TOP w0.14: v2(250.91,118.32) 250.75,118.32 250.3,117.87 UZ31.2 ; RT433.1 18.85,117.92 RZ1150.2 18.5,118.16 17.91,117.58 v2(17.75,117.58) ; v2(114.42,78.77) 114.62,78.96 114.62,79.46 115.38,80.23 117.22,80.23 117.58,80.59 117.58,82.23 116,83.8 112.27,83.8 111.6,84.48 111.6,85.18 111.32,85.45 110.18,85.45 108.45,87.18 108.45,92.58 105.93,95.1 105.93,103.67 109.24,106.99 113.67,106.99 118.34,111.65 v1(118.34,114.57) v2(118.34,115.32) ; v2(109.51,116.43) 109.19,116.75 UZ21.2 ; v2(108.15,120.57) 108.15,120.74 108.84,121.43 RZ59.1 109.78,121.35 UZ20.2 ; v2(299.52,84.06) UE3.K9 ; RE35.2 299.83,88.19 v2(299.83,87.97)
  BOTTOM w0.089: UH2.BF42 76.27,71.49 76.27,70.97 76.03,70.74 76.03,70 v2(75.53,69.5)
  BOTTOM w0.14: v2(108.15,120.57) 109.12,119.6 109.12,116.82 v2(109.51,116.43) 110.1,115.84 117.81,115.84 v2(118.34,115.32) ; v2(164.26,70.67) 164.26,70.51 164.97,69.8 174.1,69.8 175.36,71.06 175.36,72.9 175.89,73.43 JAPS.2 175.89,75.3 176.66,76.07 176.66,79.17 v2(176.5,79.33) ; v2(299.52,84.06) 299.97,84.51 299.97,87.64 299.83,87.78 v2(299.83,87.97)
  vias: v2(15.07,91.45) v2(296.15,95.59) v2(299.58,75.69)
SIO_SLP_S3#_AR: length 1.6
  TOP w0.14: v1(20.42,115.38) 20.42,115.36 v2(20.07,115) 20.02,114.95 RT433.2
  BOTTOM w0.089: UT1.D2 21.12,110.88 v6(21.22,110.77)
SIO_SLP_S4#: length 96.4
  TOP w0.127: v2(302.18,86.06) UE3.N12
  TOP w0.14: v2(174.24,72.92) 174.07,72.74 RZ1151.2 ; RZ1954.1 112.19,122.57 112.55,122.93 118.52,122.93 v2(118.67,123.08) 119.51,123.08 RZ81.1 123.24,123.97 124.13,124.86 UZ22.2 ; v2(306.37,87.39) 306.5,87.52 RE38.2 ; v2(303.43,86.78) 302.75,86.78 302.18,86.21 302.18,86.06 v2(302.18,86.06) ; v2(119.95,116.66) 120.42,116.18 v1(120.42,112.62) 120.42,112.27 114.41,106.26 109.54,106.26 106.65,103.37 106.65,95.4 109.24,92.81 109.24,88.01 110.3,86.95 111.98,86.95 112.95,85.98 115.36,85.98 116.44,84.9 116.44,84.44 117.04,83.85 125.42,83.85 127.54,81.72 127.54,77.71 126.32,76.49 125.85,76.49 v2(125.41,76.93)
  BOTTOM w0.089: UH2.BE42 75.93,71.69 75.93,71.16 75.72,70.95 75.72,70.52 v2(75.67,70.46)
  BOTTOM w0.14: v2(174.24,72.92) 174.24,73.06 174.39,73.2 JAPS.5
SIO_SLP_S5#: length 16.6
  TOP w0.14: v2(302.12,82.8) 302.06,82.86 UE3.N8 ; v2(165.07,74.24) v1(165.07,73.61)
  BOTTOM w0.089: UH2.BC42 76.41,73.24 v2(76.3,73.12)
  BOTTOM w0.14: JAPS.4 174.89,74.92 174.37,75.44 174.37,76.75 173.69,77.44 173.69,77.97 173.41,78.25 168.64,78.25 168.36,77.97 168.36,77.07 167.88,76.59 167.42,76.59 v2(165.07,74.24)
  vias: v2(301.88,72.15)
SIO_SLP_SUS#: length 15.1
  TOP w0.14: v2(308.77,80.66) 308.77,80.57 308.48,80.28 RE111.2 ; v2(124.8,76.9) 124.8,76.97 125.75,77.92 RZ1952.1 ; v2(57.47,74.96) 57.33,74.82 RZ1133.1 ; RH5871.2 v1(247.07,74.27) 247.51,74.27 v2(249.98,71.8)
  BOTTOM w0.089: v2(77.43,70.11) 77.5,70.18 77.5,71.55 77.64,71.69 77.64,72.11 77.78,72.25 77.84,72.25 77.98,72.39 77.98,72.63 UH2.BD39
  vias: v2(114.03,69.98)
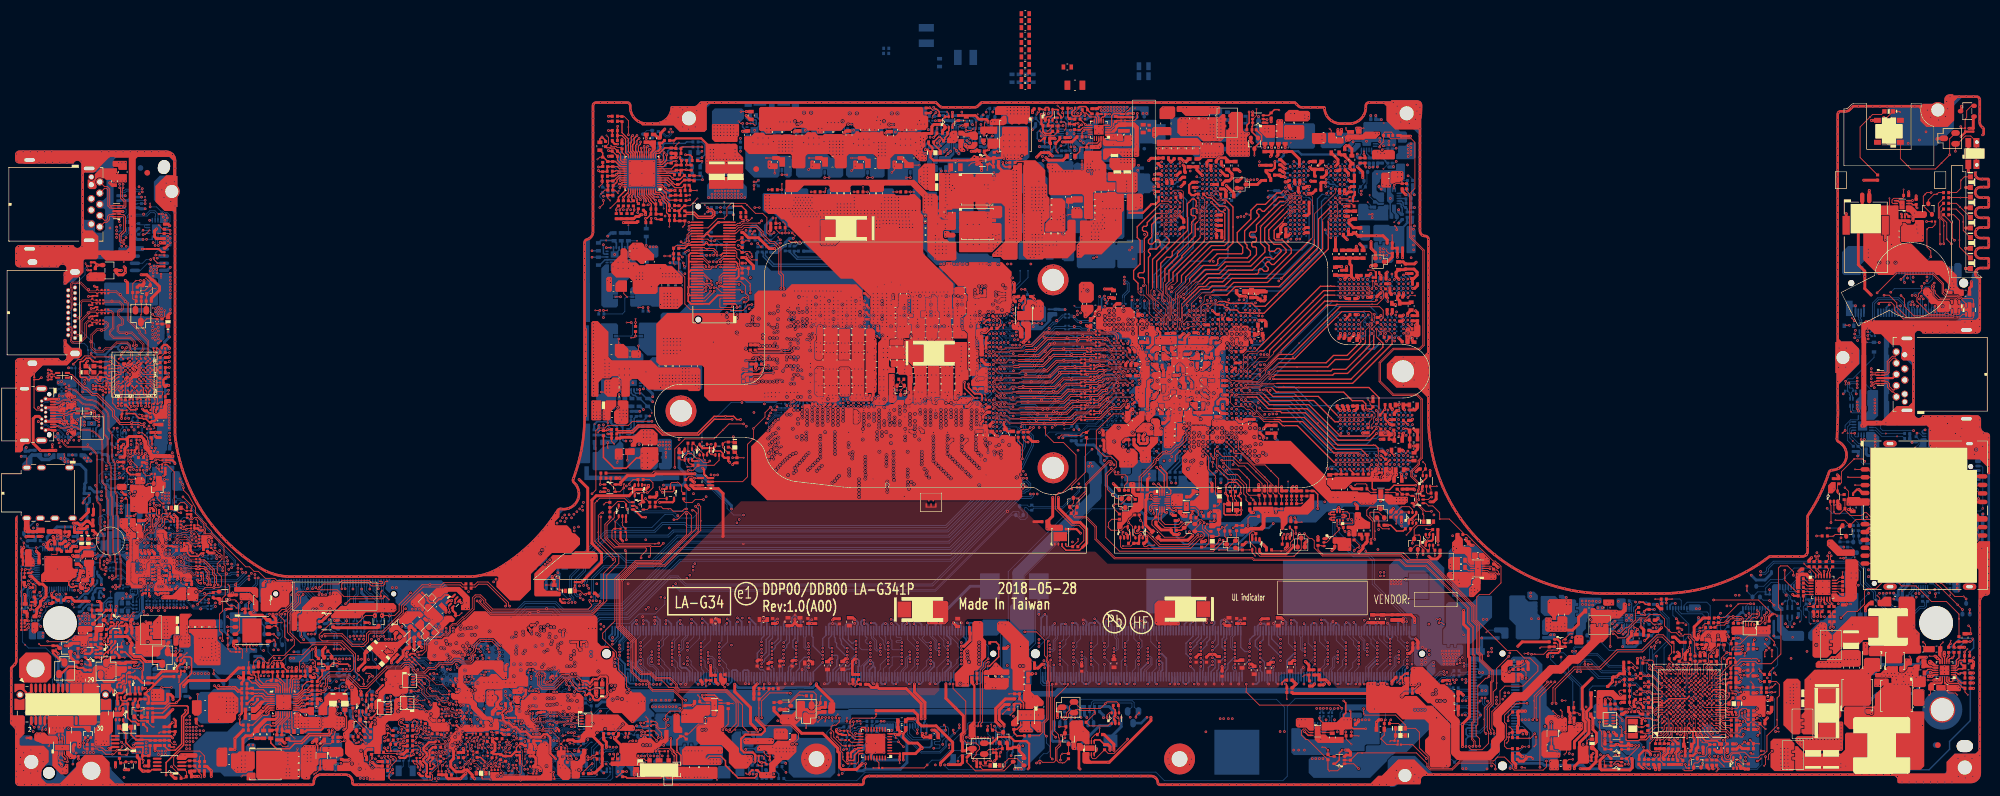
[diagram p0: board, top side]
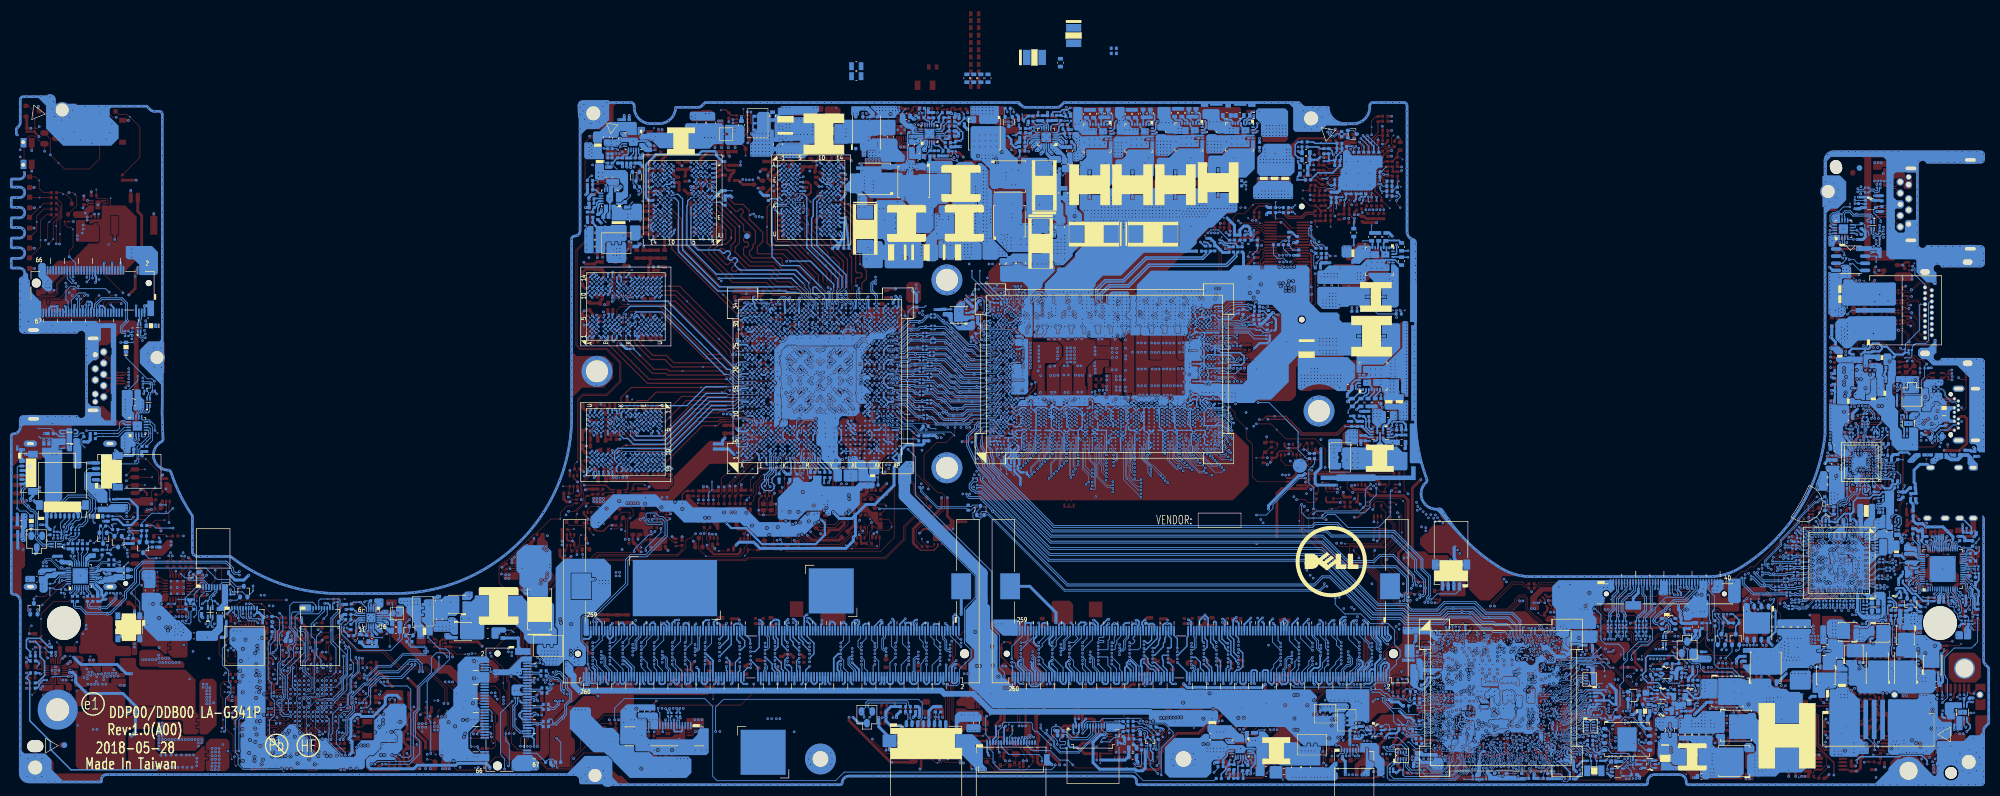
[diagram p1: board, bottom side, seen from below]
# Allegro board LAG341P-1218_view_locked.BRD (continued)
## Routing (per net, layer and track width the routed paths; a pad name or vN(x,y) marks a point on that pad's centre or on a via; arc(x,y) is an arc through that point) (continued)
SIO_SLP_SUS#_R: length 8
  TOP w0.14: UE3.N4 301.66,79.52 302.91,79.52 303.31,79.12 305.37,79.12 305.63,79.38 305.63,80.18 v1(305.87,80.41) 306.12,80.66 306.88,80.66 RE111.1 RE300.2
SIO_SLP_WLAN#: length 21.4
  TOP w0.089: RZ1149.2 77.35,72.37 77.35,73.48 v3(77.34,73.49)
  TOP w0.14: v2(293.92,84.06) UE3.D9 ; v2(308.81,71.37) 309.06,71.37 v1(309.51,71.81)
  BOTTOM w0.076: v2(293.92,84.06) 293.92,83.98 294.32,83.59 294.32,83.06 294.56,82.82 295.14,82.82 295.26,82.7 296.6,82.7 296.72,82.57 296.72,81.55 297.01,81.27 297.3,81.27 297.52,81.05 297.52,77.88 297.56,77.84 297.56,76.43 297.41,76.28
  BOTTOM w0.089: v3(77.34,73.49) 77.34,73.46 77.08,73.2 77.08,73 76.86,72.78 UH2.BD42
  BOTTOM w0.14: v2(332.38,108.89) 331.84,109.43 QR105.1 ; 297.41,76.28 296.75,75.62 296.75,73.6 295.4,72.26 v2(295.4,72.23)
SIO_SLP_WLAN#_R: length 4.3
  BOTTOM w0.14: DN3.2 332.3,111.97 QR105.3 331.06,111.93 RZ1141.1 v1(329.9,112.54)
SLEEVE:
  vias: v1(5.69,112.17) v2(7.04,111.44) v2(7.04,110.85) v2(11.23,125.28) v2(11.68,124.72) v2(11.86,125.27) v2(12.33,124.76)
SLEEVE_L: length 2
  TOP w1.016: JHP1.4 0.96,112.58
  vias: v4(0.72,112.3)
SLP_WLAN#_GATE: length 3.5
  TOP w0.14: v2(311.9,87.03) 311.9,86.97 v1(312.23,86.63) ; RE305.2 308.18,92.81 308.31,92.94 v2(308.34,92.94)
  BOTTOM w0.14: QR105.2 330,110.97 RE275.1 329.23,111.38 v2(329.03,111.59)
SLP_WLAN#_GATE_R: length 2.9
  TOP w0.076: UE3.K10 v2(299.54,84.87)
  TOP w0.14: RE305.1 307.22,92.05 RE306.1 307.22,91.14 v2(306.63,90.54) 306.63,90.1 v1(306.57,90.04)
SM_PG_CTRL: length 34.5
  TOP w0.14: RH525.2 118.71,121.93 119.45,121.93 119.7,121.68 v2(119.78,121.68) 119.79,121.67 120.79,121.67 UC1.4
  BOTTOM w0.127: v2(119.78,121.68) 120.81,121.68 125.55,116.93 125.55,116.3 126.73,115.12 v2(128.48,115.12)
  BOTTOM w0.14: PR608.1 291.3,95.75 291.3,94.01 288.34,91.05 282.5,91.05 280.45,93.09 280.45,93.94 280.1,94.29 280.1,95.59 v2(279.15,96.54)
SML0_SMBCLK: length 3.6
  TOP w0.089: v3(84.42,70.42) 84.33,70.42 84,70.76 84,71.24 84.51,71.75 RH501.2
  BOTTOM w0.089: UH2.BF25 85.01,71.78 84.72,71.49 84.72,70.69 84.45,70.42 v3(84.42,70.42)
SML0_SMBDATA: length 3.3
  TOP w0.089: RH502.2 84.81,70.2 v3(84.93,70.32)
  BOTTOM w0.089: v3(84.93,70.32) 85.01,70.32 85.02,70.33 85.16,70.33 85.54,70.71 85.54,71.29 85.71,71.46 85.71,71.77 85.77,71.83 85.77,72.47 UH2.BE24
SML0ALERT#: length 4.5
  TOP w0.089: v1(85.82,69.25) 85.29,69.78 85.29,70.66 v2(85.1,70.84) 85.37,71.11 85.69,71.11 85.89,71.32 RH503.2
  BOTTOM w0.089: v2(85.1,70.84) 85.13,70.84 85.24,70.94 85.24,71.24 85.49,71.5 85.49,71.93 UH2.BF24
SML1_SMBCLK: length 2.9
  TOP w0.076: UE3.D8 v2(293.92,83.26)
  TOP w0.089: v2(83.62,70.25) 83.66,70.21 RH460.2
  BOTTOM w0.089: v2(83.62,70.25) 83.62,70.39 83.9,70.67 83.9,71.27 83.82,71.35 UH2.BF27
  vias: v2(284.28,72.41)
SML1_SMBDAT: length 3.6
  TOP w0.089: RH461.2 84.23,70.01 84.02,70.21 84.02,70.38 v2(83.54,70.86)
  TOP w0.14: v2(295.52,85.66) UE3.E11
  BOTTOM w0.089: UH2.BE27 83.82,72.31 83.59,72.07 83.59,70.91 v2(83.54,70.86)
  vias: v2(283.64,72.41)
SML1ALERT#: length 5.6
  TOP w0.089: v2(80.54,71.42) 80.55,71.43 81.39,71.43 v1(81.81,71.01) 81.98,70.83 82.84,70.83 83.74,71.73 RH504.2
  BOTTOM w0.089: v2(80.54,71.42) 80.52,71.45 80.52,71.98 80.68,72.14 80.68,72.44 81,72.76 UH2.BD33
SNB_1.8VSP: length 0.7
  BOTTOM w0.14: 238.42,164.62 v1(237.76,164.62)
SNB_1V: length 0.6
  BOTTOM w0.14: 124.12,68.5 124.12,68.37 v1(123.76,68.01)
SNB_1VSP: length 1.7
  TOP w0.14: PR901.2 233.03,183.57 v1(232.74,183.86)
SNUB_1.2V: length 2.1
  BOTTOM w0.14: v1(260.65,94.25) 261.04,94.63 PC611.1
SNUB_1VS_VCCIO: length 1.5
  TOP w0.14: PR801.2 v4(107.81,124.85)
SNUB_3V: length 1.5
  TOP w0.14: PC414.1 330.63,100.35 v1(330.19,100.79)
SNUB_5V:
  vias: v1(338.42,83.86)
SNUB_CHG1:
  vias: v1(35.17,73.44)
SNUB_CHG2: length 2
  TOP w0.14: PR1916.2 v4(31.36,83.25)
SP7_SDWP: length 9
  TOP w0.14: v2(341.48,103.14) 343.98,100.64 v1(345.55,100.64) v2(346,100.19)
  BOTTOM w0.14: v2(346,100.19) QR1.1 ; UR1.29 340.36,104.08 340.44,104.01 341.24,104.01 341.48,103.76 v2(341.48,103.14)
SP7_SDWP_C: length 21.7
  TOP w0.14: v2(345.35,98.29) v4(344.5,99.14) 341.01,102.63 340.95,102.63 338.55,105.03 337.19,105.03 336.98,104.83 336.19,104.83 335.99,105.03 331.05,105.03 329.59,106.49 JCR.11
  BOTTOM w0.14: v2(345.35,98.29) QR1.3
SPK_DET#: length 12.7
  TOP w0.14: v2(308.82,78.98) 308.6,78.76 RE139.1 ; v2(309.52,73.14) v1(310.1,73.14) ; RH572.1 65.27,70.45 65.72,70.91 65.72,71.48 65.2,72 65.2,72.19 v2(65.21,72.2) ; v2(4.06,80.39) 3.36,79.69 JAUDIO.6
  BOTTOM w0.089: v2(87.58,75.76) 87.55,75.8 87.55,75.84 87.48,75.91 UH2.AV21
  BOTTOM w0.14: v2(309.52,73.14) 309.52,78.59 309.13,78.98 v2(308.82,78.98)
  vias: v3(80.15,74.15)
SPK_DET#_EC: length 3.8
  TOP w0.076: 302.06,83.53 301.66,83.53 UE3.N9
  TOP w0.14: v2(306.65,80.16) 306.65,79.21 307.11,78.76 RE139.2 ; v2(303.34,82.89) 302.69,83.53 302.06,83.53
SPKR: length 7.3
  TOP w0.14: v2(65.79,72.14) 65.82,72.11 66.41,72.11 66.69,71.84 66.69,71.4 65.63,70.35 65.63,70.08 65.23,69.68 RH82.2 ; RA7.1 0.65,94.67 1.08,95.11 v2(1.31,95.11)
  BOTTOM w0.089: UH2.AW29 82.74,75.24 81.99,75.24 81.62,74.87 81.21,74.87 v3(81.07,75.01)
  BOTTOM w0.14: v2(1.31,95.11) 1.31,95.03 v1(0.97,94.68)
SRCCLKREQ1#: length 8.8
  TOP w0.14: v2(306.25,91.84) 306.06,91.65 304.66,91.65 304.43,91.42 RT5856.1
  BOTTOM w0.089: UH2.BE31 82.12,72.27 82.04,72.19 82.04,71.8 81.78,71.53 81.78,70.44 81.61,70.27 81.61,69.69 82.16,69.14 v1(82.41,69.14) RH549.2 84.29,69.14 84.71,68.72 v2(84.71,68.66)
  vias: v2(310.62,86.14)
SRCCLKREQ2#: length 3.2
  TOP w0.089: v1(80.7,79.49) 81.06,79.49 81.76,78.8 RH550.2 81.76,78.03 v2(82.2,77.6)
  BOTTOM w0.089: UH2.AR32 82.04,77.44 v2(82.2,77.6)
SRCCLKREQ8#: length 11.9
  TOP w0.089: v2(76.81,81.44) 76.45,81.8 76.05,81.8 75.79,82.07 74.83,82.07 73.93,82.97 72.72,82.97 72.1,83.59 72.1,84.23 72.63,84.75 72.63,85.5 v1(72.6,85.52) 72.35,85.78
  TOP w0.14: RP22.7 69.85,85.88 70.19,86.21 71.91,86.21 72.35,85.78
  BOTTOM w0.089: UH2.AE41 77.16,81.79 v2(76.81,81.44)
SRCCLKREQ9#: length 6.2
  TOP w0.089: v2(72.54,81.86) 72.54,82.03 71.25,83.32 v1(71.25,84.07) 71.24,84.07 71.08,84.23
  TOP w0.14: 71.08,84.23 70.43,84.88 RP22.5
  BOTTOM w0.089: v2(72.54,81.86) 72.92,81.86 73.38,81.4 UH2.AF48
SRCCLKREQ10#: length 9
  TOP w0.089: 72.67,86.1 73.77,85 v1(74.91,85) v2(76.12,83.79)
  TOP w0.14: RP22.8 70.01,86.38 70.14,86.51 72.27,86.51 72.67,86.1
  BOTTOM w0.089: UH2.AC41 77.05,83.17 76.43,83.79 v2(76.12,83.79)
SRCCLKREQ11#: length 9.7
  BOTTOM w0.076: UH2.AC39 77.59,83.17 76.16,84.6 74.89,84.6 74.58,84.72 73.49,84.72 73.16,85.04 72.5,85.04 72.06,85.49
  BOTTOM w0.14: RP23.5 71.23,86.61 72.03,85.81 72.03,85.51 72.06,85.49
SRCCLKREQ12#: length 11.2
  TOP w0.089: v2(76.19,81.42) 75.9,81.71 v1(75.31,81.71) 74.94,81.71 73.89,82.76 72.31,82.76 71.65,83.41 71.65,84.47 71.42,84.7
  TOP w0.14: v2(70.68,85.45) 71.42,84.7
  BOTTOM w0.089: v2(76.19,81.42) 76.23,81.42 76.73,81.92 76.73,82.07 76.97,82.32 77.6,82.32 77.91,82.01 UH2.AE39
  BOTTOM w0.14: RP23.8 70.18,85.11 70.18,85.1 70.33,85.1 70.43,85.21 v2(70.68,85.45)
SRCCLKREQ13#: length 6.2
  BOTTOM w0.089: UH2.AB48 73.38,83.34 72.81,83.34 71.42,84.73
  BOTTOM w0.14: 71.42,84.73 71.37,84.78 71.37,85.92 71.03,86.26 70.22,86.26 70.06,86.11 RP23.6
SRCCLKREQ14#: length 12.1
  BOTTOM w0.089: 71.29,84.44 72.61,83.12 73.52,83.12 73.93,83.53 74.55,83.53 74.68,83.66 75.33,83.66 75.64,83.35 UH2.AC44
  BOTTOM w0.14: 71.29,84.44 71.11,84.62 71.11,85.71 70.87,85.96 70.43,85.96 70.08,85.61 RP23.7 69.36,85.61 69.24,85.49 69.24,84.87 69.05,84.68 68.07,84.68 67.59,85.16 v1(67.02,85.16)
SRCCLKREQ15#: length 8.1
  TOP w0.089: v2(71.76,85.1) 71.72,85.15
  TOP w0.14: RP22.6 69.97,85.38 70.49,85.9 70.97,85.9 v1(71.09,85.77) 71.72,85.15
  BOTTOM w0.076: UH2.AC43 76.18,83.17 75.47,83.89 74.58,83.89 74.24,84.22 73.6,84.22 73.25,84.57 73.25,84.58
  BOTTOM w0.089: v2(71.76,85.1) 72.12,84.75 73.08,84.75 73.25,84.58
SSD_EN: length 4.1
  TOP w0.14: UZ6.4 233.02,72.17 233.01,72.17 232.78,72.17 RZ1956.2 v2(232.46,73.3) 231.95,73.81 v1(231.44,73.81) ; v2(272.22,78.25) UZ32.3
SSD_PCIE_WAKE#: length 4.2
  TOP w0.127: v2(264.67,76.22) 264.68,76.21 264.73,76.21 265,76.47 RD8.1 RD59.1
  TOP w0.14: RD8.1 265.28,76.94 v1(264.76,77.46)
  BOTTOM w0.127: v2(264.67,76.22) 264.67,76.36 264.8,76.49 JNGFF2.54
SSD_SCP#: length 3.2
  TOP w0.076: UE3.H5 v2(297.92,80.06)
  TOP w0.14: RD101.2 267.14,87.65 RE307.1 267.7,87.12 v2(267.7,86.06)
SSD_SCP#_R: length 5.1
  TOP w0.14: v2(264.72,87.23) 265.14,87.65 RD101.1 265.46,87.65 265.94,88.13 266.76,88.13 266.94,88.31 267.09,88.31 v1(267.45,88.66)
  BOTTOM w0.14: v2(264.72,87.23) 264.72,87.86 264.85,87.99 JNGFF2.8
SSD_SCP_PWR_EN: length 44.1
  TOP w0.076: UE3.H8 v2(297.93,82.46)
  TOP w0.14: v2(262.24,69.92) 262.24,70.53 261.78,70.99 255.84,70.99 254.61,69.77 250.65,69.77 250.08,70.34 250.08,70.92 248.2,72.79 238.55,72.79 ; 238.55,72.79 237.75,72.79 RZ1958.1 235.43,71.51 UZ6.2 ; 238.55,72.79 v1(238.56,72.79)
  BOTTOM w0.14: v2(262.24,69.92) 262.24,71.77 262.99,72.52 262.99,79.88 v2(260.87,82.01)
SSD_SUSCLK: length 3.4
  TOP w0.14: v1(267.6,73.91) v2(267.06,73.91) 266.7,73.55 RD9.1
  BOTTOM w0.127: JNGFF2.60 266.46,72.99 267.03,73.55 267.03,73.88 v2(267.06,73.91)
STRAP0: length 14.1
  TOP w0.14: v2(213.56,124.86) 215.5,124.86 216.52,123.84 217.6,123.84 v1(218.16,123.28) 220.74,120.71 220.74,118.97 RV651.2 221.21,118.06 221.23,118.05 RV645.1
  BOTTOM w0.107: UV18.J2 213.2,125.81 213.35,125.66 213.35,125.66 213.57,125.44 213.57,125.44 213.62,125.4 213.62,124.97 213.56,124.92 v2(213.56,124.86)
STRAP1: length 5.5
  TOP w0.14: RV652.2 v2(225.99,117.82) RV646.1
  BOTTOM w0.102: v2(212.75,130.55) 213.11,130.19 UV18.J7
  BOTTOM w0.14: v1(225.36,121.09) 225.36,119.6 225.99,118.97 v2(225.99,117.82)
STRAP2: length 2
  TOP w0.14: RV647.1 v2(225.1,117.82) RV653.2
  BOTTOM w0.102: v2(213.61,129.77) 213.61,129.72 213.24,129.34 UV18.J6
STRAP3: length 3
  TOP w0.14: RV654.2 v2(226.88,117.82) RV648.1 227.75,117.13 v1(227.9,117.28)
  BOTTOM w0.102: UV18.J5 213.22,128.49 v2(213.61,128.89)
STRAP4: length 15.7
  TOP w0.14: v2(212.78,126.49) 213.71,125.56 215.51,125.56 216.71,124.35 218.17,124.35 v1(219.67,122.85) 221.7,120.82 221.7,118.98 RV655.2 RV649.1
  BOTTOM w0.102: v2(212.78,126.49) 213.18,126.89 UV18.J3
STRAP5: length 13.3
  TOP w0.14: v2(213.13,123.81) 214.6,122.33 v1(216.06,122.33) 216.31,122.33 216.85,121.79 216.85,121.61 217.96,120.5 217.96,119.11 218.44,118.64 RV656.2 220.21,118.13 220.33,118 RV650.1
  BOTTOM w0.102: UV18.J1 212.97,125.06 212.97,124.25
  BOTTOM w0.14: 212.97,124.25 212.97,123.96 v2(213.13,123.81)
SUS_ON_EC: length 3.4
  TOP w0.14: UE3.D2 294.75,77.63 294.75,76.31 v2(294.6,76.16) ; RE39.2 307.18,88.55 v2(306.44,88.55) 306.26,88.55 v1(305.99,88.28)
SUS_ON_EC_P: length 38.4
  TOP w0.14: DZ59.1 126.81,128.11 ; 126.81,128.11 RZ1966.1 125.18,128.11 UZ22.4 124.78,127.13 125.7,126.21 RZ87.1 ; 126.81,128.11 126.67,128.25 v2(126.67,129.05) ; Q5.2 273.1,92.35 273.35,92.09 273.35,91.2 273.23,91.08 271.58,91.08 270.85,90.35 v1(269.24,90.35) v2(268.67,90.35) ; UZ23.1 v2(102.98,120.56) 102.98,121.57 RZ91.1 RZ1954.2 ; PR1801.1 181.07,75.84 181.74,76.51 181.74,78.2 182.44,78.9 182.44,85.56 182.54,85.66 182.54,88.86 182.35,89.05 182.35,89.81 182.04,90.12 182.04,92.89 180.6,94.33 v2(178.51,94.33)
  vias: v2(117.02,128.54) v2(132.19,134.89) v2(136.84,134.56) v2(183.41,130.71)
SUS_ON_EC_R: length 56.9
  TOP w0.14: UZ22.1 123.05,125.81 122.86,126 v2(122.73,126) ; RE39.1 RE38.1 308.1,87.42 RE30.1 307.06,86.63 v2(306.46,86.63) ; v2(116.09,114.29) 116.7,114.29 118.18,115.77 118.49,115.77 119.2,115.06 v1(119.2,113.16) 119.2,112.17 113.77,106.74 109.34,106.74 106.17,103.57 106.17,95.2 108.69,92.68 108.69,87.28 110.24,85.74 111.37,85.74 111.84,85.28 111.84,84.58 112.32,84.09 116.05,84.09 118,82.15 v2(118.2,82.15)
SUS_ON_EC_ST: length 19.9
  TOP w0.089: v2(177.54,152.57) 177.51,152.57 177.38,152.44 UZ15.4
  TOP w0.14: v1(107.24,120.66) 107.18,120.59 v2(107.18,119.93) 106.5,119.26 UZ23.4 105.65,119.78 104.88,120.55 CZ588.1 RZ91.2
  BOTTOM w0.14: v2(107.18,119.93) 107.18,118.7 108.28,117.59 108.28,116.47 109.25,115.5 116.3,115.5 v2(116.79,115.01)
  vias: v2(115.28,112.82) v2(128.98,130.93) v2(138.16,136.16)
SUSACK#: length 16.9
  TOP w0.14: v2(299.52,85.61) 299.52,85.67 UE3.K12 ; v2(297,71.64) 296.69,71.33 RH5872.1
  BOTTOM w0.076: 298.12,76.28 299.13,77.29 299.13,81.86 299.29,82.02 299.29,82.74 299.13,82.89 v1(299.13,84.43) 299.13,85.29 299.45,85.61 v2(299.52,85.61)
  BOTTOM w0.14: v2(297,71.64) 297,75.16 298.12,76.28
SUSACK#_R: length 3.8
  TOP w0.14: v2(266.94,70.24) 267.02,70.16 v1(267.56,70.16) ; RH5872.2 296.33,70.08 296.09,70.31 296.09,70.69 v2(296.04,70.74)
  BOTTOM w0.089: UH2.BE35 79.93,72.5 80.34,72.09 80.34,71.79 80.18,71.63 80.18,71.22 79.96,71.01 v2(79.96,70.83)
SUSCLK: length 13.9
  TOP w0.14: RD9.2 264.33,73.55 263.86,74.02 263.86,74.91 264.19,75.24 264.19,77.95 263.87,78.26 263.87,79.5 266,81.63 v1(266.6,81.63) v2(267.88,81.63) ; v2(338.96,167.34) RN1.2
  BOTTOM w0.089: v2(74.89,73.04) 74.89,73 74.89,72.54 UH2.BE45
  vias: v2(210.74,76.55) v2(333.5,124.07)
SUSCLK_R: length 10.4
  TOP w0.14: v2(339.72,161.07) 339.72,162.12 339.03,162.81 v1(339.03,165.94) 339.34,166.26 339.97,166.26 340.49,166.78 RN1.1
  BOTTOM w0.14: v2(339.72,161.07) 338.57,159.92 JNGFF1.42
SW1_2PH: length 8.4
  TOP w0.14: v2(108.51,149.37) v1(107.68,149.37)
  TOP w0.254: v2(103.3,182.39) 103.43,182.26 ; 103.43,182.26 103.17,182.26 102.92,182.01 PR1151.2 ; 103.43,182.26 103.94,181.76 PR1166.2
  BOTTOM w0.14: PL1702.2 108.51,146.96 108.76,147.21 108.76,149.12 v2(108.51,149.37)
SW1_4PH: length 3.6
  TOP w0.14: v2(135.31,175.66) v4(136.22,175.66)
  BOTTOM w0.14: PL1202.2 v2(135.31,175.66)
  BOTTOM w0.254: PR1159.1 120.38,180.6 PR1147.1 120.83,179.6 v2(121.08,179.85)
SW2_4PH: length 6.5
  TOP w0.14: v2(142.93,175.15) v4(143.71,175.15)
  BOTTOM w0.14: PL1203.2 v2(142.93,175.15)
  BOTTOM w0.254: PR1167.1 121.08,181.5 121.59,180.99 121.59,179.22 v2(121.08,178.71) 120.76,178.71 PR1150.1
SW3_4PH: length 4.5
  TOP w0.14: v2(150.55,175.15) v4(151.45,175.15)
  BOTTOM w0.14: PL1251.2 v2(150.55,175.15)
  BOTTOM w0.254: PR1152.1 121.18,175.37 v2(121.18,174.77) PR1169.1
SW4_4PH: length 3.7
  TOP w0.14: v2(158.17,175.15) v4(157.39,175.15)
  TOP w0.254: v2(121.08,178.07) 120.4,178.07 PR1171.1
  BOTTOM w0.14: PL1252.2 v2(158.17,175.15)
  BOTTOM w0.254: v2(121.08,178.07) 121.08,177.75 120.76,177.44 PR1155.1
SW_1.2V:
  vias: v2(268.66,96.67) v2(269.93,96.67) v2(283.45,95.14) v2(283.9,95.52)
SW_1PH: length 3.3
  TOP w0.14: v2(106.6,153.94) v1(105.7,153.94)
  BOTTOM w0.14: v2(106.6,153.94) PL1704.2
  BOTTOM w0.254: v2(111.18,163.09) PR1101.2
SYS_PEX_RST_MON#: length 2.1
  TOP w0.14: RV557.1 219.51,117.46 v2(219.16,117.8) v1(218.72,118.24)
  BOTTOM w0.14: v2(207.76,131.4) 207.79,131.4 UV18.R8
SYS_PEX_RST_MON#_L: length 7.7
  TOP w0.14: RV587.1 222.62,108.73 v1(224.14,108.73) 225.04,108.73 225.77,109.45 225.77,110.22 226.31,110.76 226.31,112.29 UV19.4
SYS_PWROK: length 13.1
  TOP w0.14: v2(300.34,72.15) 300.34,71.92 300.73,71.53 RE33.2 300.79,71.53 RE303.2 301.8,71.53 v1(302.95,70.38)
  BOTTOM w0.076: v2(97.86,76.39) 97.86,76.41 97.52,76.75 96.67,76.75 96.48,76.56 96.14,76.56 95.88,76.3 UH2.AU3
  BOTTOM w0.089: 99.75,76.5 98.95,76.5 98.59,76.85 98.32,76.85 v2(97.86,76.39)
  BOTTOM w0.14: RH490.1 125.48,161.51 124.76,160.8 123.7,160.8 v2(123.08,160.18) ; 99.75,76.5 RH91.2
  vias: v2(223.95,76.6) v2(294.68,75.32) v3(97.95,86.83)
SYS_PWROK_R: length 19.4
  TOP w0.076: UE3.G4 v2(296.33,79.27)
  TOP w0.14: v1(301.59,69.5) 301.88,69.8 v2(301.88,70) 301.59,70.3 RE303.1
  BOTTOM w0.14: v2(309.27,79.4) 310.18,78.49 310.18,72.92 309.68,72.41 309.68,70.76 308.79,69.87 302.02,69.87 v2(301.88,70)
SYS_RESET#: length 10.9
  TOP w0.089: v2(96.33,75.86) 96.64,75.86 v1(96.81,76.03)
  BOTTOM w0.089: UH2.AU2 v2(96.33,75.86) 96.37,75.82 98.49,75.82 98.8,76.12 99.75,76.12
  BOTTOM w0.14: v2(122.53,161.34) 123.7,162.5 RH8.2 ; RH571.1 102.21,77.02 101.8,76.61 101.5,76.61 101.01,76.12 99.75,76.12 ; JAPS.13 170.39,75.24 170.25,75.37 170.25,75.51 v2(170.18,75.59)
  vias: v3(96.45,80.13)
TACH_FAN1: length 22.7
  TOP w0.14: UE3.E3 295.12,78.86 v2(294.69,78.44) ; v1(253.16,95.65) 253.03,95.65 252.73,95.95 v2(252.22,95.95) ; CE66.1 100.58,101.2 v2(100.38,101) 100.05,101 99.43,101.62 DE7.2 98.48,101.64 RE81.2
  BOTTOM w0.076: v2(294.69,78.44) 295.12,78.86 295.12,80.27 294.93,80.46 294.61,80.46 294.32,80.75 294.32,81.11 294.18,81.25 292.91,81.25 292.51,81.65
  BOTTOM w0.14: v2(289.99,91.64) 289.99,91.61 289.69,91.3 289.69,89.34 289.16,88.82 289.16,87.21 290.31,86.06 290.31,84.01 292.51,81.81 292.51,81.65
  vias: v2(111.11,98.34)
TACH_FAN2: length 6.7
  TOP w0.14: UE3.D1 294.32,76.71 v2(294.16,76.55)
  BOTTOM w0.14: DE8.2 333.74,114.93 CE67.1 332.02,114.93 RE83.2 v1(330.68,114.91) 330.48,114.91 329.9,114.33 328.73,114.33 v2(328.3,114.76)
TB_HDMI_HPLUG: length 3.8
  TOP w0.089: 23.26,113.05 23.25,113.04 23.25,112.6 v2(23,112.35)
  TOP w0.14: 23.26,113.05 23.37,113.16 23.37,114.36 23.53,114.53 RT1134.1
  BOTTOM w0.102: v2(23,112.35) 22.5,111.85 UT1.G1
TBT_BATLOW#: length 4.5
  TOP w0.14: RT25.2 22.73,114.52 22.73,114.09 v1(22.33,113.68) 21.89,113.25 v6(21.89,112.21)
  BOTTOM w0.089: UT1.F2 21.79,111.43 21.79,112.11 v6(21.89,112.21)
TBT_CIO_PLUG_EVENT#: length 7.9
  TOP w0.14: v2(94.68,69.35) 94.68,68.72 94.83,68.57 RH5889.1 ; v2(28.94,114) RT23.2
  BOTTOM w0.089: 28.5,113.05 28.5,112.08 28.24,111.83 28.24,111.42 UT1.W2 ; v2(94.68,69.35) 93.98,70.05 93.98,70.81 93.65,71.14 93.65,71.42 93.48,71.59 UH2.BF8
  BOTTOM w0.14: 28.5,113.05 28.5,113.37 28.64,113.51 28.64,113.63 28.94,113.94 v2(28.94,114)
  vias: v2(47.54,88)
TBT_CONFIG: length 3.2
  TOP w0.14: v2(20.88,126.08) 20.9,126.1 20.9,127.65 20.68,127.88 RT183.1 20.5,127.89 RT1093.2
  BOTTOM w0.081: v2(20.88,126.08) UT4.H6
TBT_DDC_CLK: length 3.8
  TOP w0.14: RT33.2 29.51,112.73 v2(29.32,112.54) 28.66,112.54 RT5848.2
  BOTTOM w0.076: v2(29.32,112.54) 29.26,112.48 29.26,112.38 28.7,111.82 28.7,111.42 UT1.Y2
TBT_DDC_DATA: length 4.2
  TOP w0.14: RT5847.2 28.44,113.43 v2(28.91,112.96) 29.25,113.3 RT34.2
  BOTTOM w0.076: UT1.Y1 28.48,111.82 28.85,112.19 28.85,112.9 v2(28.91,112.96) 28.99,113.05
  BOTTOM w0.14: v1(29.36,113.23) 29.17,113.23 28.99,113.05
TBT_FORCE_PWR: length 5.8
  TOP w0.089: v1(89.43,70.41) 90,70.98 v3(90,71.25)
  TOP w0.14: RT5846.1 26.42,115.32 25.98,114.89 RT38.2 25.4,114.83 25.13,114.56 25.13,113.79 24.56,113.23 v2(24.56,113.19)
  BOTTOM w0.089: v3(90,71.25) 90.02,71.27 90.02,71.71 90.26,71.95 90.26,72.34 90.1,72.5 UH2.BE15
  vias: v2(29.79,88.04)
TBT_FORCE_PWR_R: length 9.2
  TOP w0.089: v1(21.89,109.49) 21.89,109.54 v2(22.53,110.18) 22.14,110.56 22.14,111.38 22.55,111.78 23.4,111.78 23.67,112.06 23.67,112.5 23.95,112.78 23.95,113.05
  TOP w0.14: RT5846.2 25.16,115.4 24.87,115.11 24.87,114.54 24.65,114.31 24.65,113.96 23.95,113.26 23.95,113.05
  BOTTOM w0.089: UT1.H4 22.85,110.44 22.58,110.18 v2(22.53,110.18)
TBT_I2C_CLK: length 4.6
  BOTTOM w0.089: UT1.U2 27.33,111.43 27.33,112.1 26.66,112.77 v2(26.27,112.77) 26.27,113.02 26.29,113.05
  BOTTOM w0.14: 26.29,113.05 RT36.2 ; v2(15.11,123.28) 15.32,123.49 16.13,123.49 16.21,123.41 RT5837.1
TBT_I2C_CLK_R: length 1.9
  BOTTOM w0.081: RT5837.2 17.24,123.32 18.68,123.32 18.88,123.52 UT4.D2
TBT_I2C_DATA: length 4.4
  BOTTOM w0.089: 25.4,113.05 25.61,112.84 v2(25.66,112.84) 26.22,112.29 26.8,112.29 27.1,111.99 UT1.U1
  BOTTOM w0.14: 25.4,113.05 25.12,113.33 RT35.2 ; RT5836.1 16.21,123.97 16.13,123.89 v2(15.11,123.89)
TBT_I2C_DATA_R: length 1.4
  BOTTOM w0.081: UT4.D1 18.32,123.51 17.6,123.51 RT5836.2
TBT_JTAG_TCK: length 7.3
  TOP w0.089: 31.42,111.6 31.33,111.69 31.33,111.84 30.79,112.37 29.97,112.37 29.57,111.97 28.56,111.97 28.37,111.78 26.67,111.78 T198.1 26.42,111.53 26.42,110.8 v2(26.41,110.79)
  TOP w0.14: RT7.2 31.65,111.37 31.42,111.6
  BOTTOM w0.102: UT1.T4 26.45,110.79 26.43,110.79 26.42,110.79 v2(26.41,110.79)
TBT_JTAG_TDI: length 5.7
  TOP w0.089: 31.42,110.13 31.36,110.13 31.33,110.1 30.39,110.1 29.29,111.19 T196.1 28.12,111.19 v6(27.72,110.79)
  TOP w0.14: RT9.2 31.58,110.13 31.42,110.13
  BOTTOM w0.089: v6(27.72,110.79) 28.32,110.79 28.62,110.49 UT1.Y4
TBT_JTAG_TDO: length 5.3
  TOP w0.089: v2(27.71,110.18) 28.25,110.71 29.53,110.71 30.8,109.44 T199.1 31.06,109.57 31.42,109.57
  TOP w0.14: 31.42,109.57 RT6.2
  BOTTOM w0.102: UT1.W4 28.02,110.49 v2(27.71,110.18)
TBT_JTAG_TMS: length 6.4
  TOP w0.089: v6(27.09,110.19) 27.09,110.2 27.34,110.45 27.34,111.06 T197.1 28.55,111.49 28.73,111.66 29.25,111.66 29.88,111.04 30.63,111.04 30.8,110.86 31.42,110.86
  TOP w0.14: RT8.2 31.6,110.86 31.42,110.86
  BOTTOM w0.102: UT1.V4 27.37,110.49 27.09,110.21 v6(27.09,110.19)
TBT_LSRX: length 3.9
  BOTTOM w0.076: 19.54,110.15 19.65,110.27 UT1.A4
  BOTTOM w0.081: v2(19.52,127.66) 19.63,127.55 19.63,126.85 19.88,126.6 UT4.K4
  BOTTOM w0.089: 19.54,110.15 19.35,110.15 18.91,109.72 18.83,109.72 v2(18.81,109.73) 18.72,109.65 18.39,109.65 18.36,109.67 18.34,109.67
  BOTTOM w0.14: 18.34,109.67 18.12,109.67 RT45.2 ; v2(19.05,130.24) 19.02,130.27 19.02,130.38 RT232.1
TBT_LSTX: length 4.5
  BOTTOM w0.081: RT233.1 19.81,128.61 v2(19.53,128.33) 19.95,127.91 19.95,127.41 19.88,127.34 UT4.L4
  BOTTOM w0.089: UT1.A5 19.5,109.81 19.06,109.37 18.88,109.37 18.81,109.31 v2(18.81,109.12) 18.63,109.3 18.39,109.3 18.36,109.28 18.34,109.28
  BOTTOM w0.14: RT44.2 18.12,109.28 18.34,109.28
TBT_PCIE_RBIAS: length 1.1
  TOP w0.381: RT1.1 25.14,104.34 v2(25.12,104.32)
  BOTTOM w0.089: UT1.N16 v2(25.12,104.32)
TBT_PCIE_WAKE#: length 51.4
  TOP w0.14: RT5843.2 70.31,71.34 RT5849.2 70.32,71.21 70.99,70.53 70.99,69.92 70.94,69.86 70.94,69.77 v2(70.94,69.76) ; v2(306.22,91.2) RT5856.2
  BOTTOM w0.089: UT1.W1 28.02,111.84 28.32,112.15 28.32,112.72 27.99,113.05
  BOTTOM w0.14: 27.99,113.05 27.86,113.18 RT22.2 27.98,113.35 28.24,113.61 28.24,114.12 28.81,114.69 29.07,114.69 29.08,114.7 29.36,114.7 30.02,114.04 30.2,113.86 v2(30.24,113.86) ; v2(122.45,85.08) 121.87,84.5 108.06,84.5 107.3,85.26 105.23,85.26 104.85,85.64 104.85,87.32 103.56,88.61 103.56,89.3 102.93,89.92 102.93,91.09 103.94,92.09 103.94,94.74 104.98,95.79 108.18,95.79 109.91,97.52 112.77,97.52 114.48,99.23 v2(114.48,100.4)
  vias: v2(59.17,86.38) v2(79.55,101.49)
TBT_POC_RST#: length 5.7
  TOP w0.14: v2(28.75,118.35) 30.3,116.79 v1(30.34,116.79) 30.34,116.41 30.21,116.29 RT202.2 30.2,115.87 RT244.2 29.17,115.87 28.75,116.29 28.5,116.29 DT29.2
  BOTTOM w0.089: v2(21.88,110.18) 21.88,110.18 UT1.F4
TBT_PWR_EN: length 1.2
  TOP w0.089: T5990.1 73.46,86.84 73.36,86.94 v2(73.36,86.95)
  BOTTOM w0.089: v2(73.36,86.95) 73.65,86.66 UH2.T48
TBT_RBIAS: length 1.2
  TOP w0.508: v2(22.54,108.86) 22.54,108.61 22.78,108.36 RT10.1
  BOTTOM w0.203: UT1.H6 22.85,109.17 v2(22.54,108.86)
TBT_RESET_N_EC: length 14.2
  TOP w0.14: RT245.2 25.9,124.1 27.2,122.79 27.2,117.07 v3(27.57,116.7) 27.64,116.7 28.26,117.32 28.99,117.32 29.45,116.86 RT244.1 ; v2(274.12,82.11) v1(274.74,82.11) ; RZ41.1 286.44,88.92 287.43,87.93 v2(287.48,87.93) ; UE3.L8 v2(299.52,83.26)
  vias: v2(38.51,106.24) v2(77.39,92.32)
TBT_ROM_CLK: length 4.7
  TOP w0.14: v2(40.07,91.98) 40.09,91.95 40.09,90.86 v1(40.06,90.82)
  BOTTOM w0.089: v2(31.04,111.22) 30.74,110.92 30.74,110.38 30.64,110.29 30.22,110.29 30.02,110.49 29.61,110.49 UT1.AB4
  BOTTOM w0.14: v2(40.07,91.98) 40.07,92.18 39.93,92.32 UT2.6
TBT_ROM_CS#: length 5.1
  TOP w0.14: v1(38.28,98.57) 37.86,98.99 RT18.2 37,98.99 36.45,99.54 v2(36.45,100.12)
  BOTTOM w0.089: UT1.AC3 30.31,110.73 v2(30.37,110.67)
  BOTTOM w0.14: v2(36.45,100.12) 36.45,99.64 37.23,98.85 UT2.1
TBT_ROM_DI: length 4.6
  TOP w0.14: v1(41.38,91.15) 41.04,91.15 40.65,91.53 v2(40.65,91.98)
  BOTTOM w0.076: UT1.AB3 29.62,110.95 30,110.95 30.07,111.02 30.58,111.02 30.67,111.12 30.67,111.69 v2(30.73,111.76)
  BOTTOM w0.14: v2(40.65,91.98) 41.2,92.52 UT2.5
TBT_ROM_DO: length 4
  TOP w0.14: RT16.2 36.7,94.46 v2(36.78,94.54)
  BOTTOM w0.089: UT1.AC4 29.99,110.27 30.18,110.09 30.71,110.09 31.1,110.48 v2(31.1,110.5)
  BOTTOM w0.14: UT2.2 38.66,99.32 38.91,99.57 v2(39.13,99.57) v1(39.13,100.23)
TBT_ROM_HOLD#: length 4
  TOP w0.14: v1(39.31,89.69) 39.31,91.18 39.14,91.34 RT15.2 38.81,91.5 v2(38.37,91.94)
  BOTTOM w0.14: UT2.7 38.66,92.23 v2(38.37,91.94)
TBT_ROM_WP#: length 3.7
  TOP w0.14: RT17.2 40.42,99.47 v2(40.52,99.57)
  BOTTOM w0.076: v2(27.74,112.35) 27.56,112.16 UT1.V1
  BOTTOM w0.14: v1(40.52,100.18) v2(40.52,99.57) 40.21,99.57 39.93,99.29 UT2.3
TBT_RSENSE: length 1.3
  TOP w0.508: RT10.2 23.7,108.34 v2(23.18,108.86)
  BOTTOM w0.203: v2(23.18,108.86) 23.5,109.18 UT1.J6
TBT_SRC_CFG1: length 5.5
  TOP w0.14: v1(31.1,114.35) 31.37,114.08 RT107.2 31.59,113.31 v2(31.94,112.96)
  BOTTOM w0.089: 31.42,112.81 31.22,112.6 30.82,112.6 30.61,112.39 29.79,112.39 29.52,112.12 29.23,112.12 28.94,111.82 UT1.AA1
  BOTTOM w0.14: 31.42,112.81 31.8,112.81 31.94,112.95 v2(31.94,112.96)
TBT_TEST_EN: length 4.6
  TOP w0.14: RT3.2 22.86,114.88 23.04,114.7 23.04,113.16 v2(22.83,112.95)
  BOTTOM w0.102: v2(22.83,112.95) 22.73,112.84 22.15,112.84 21.96,112.65 21.78,112.65 21.51,112.39 21.51,112.03 21.58,111.97 UT1.E1
TBT_TEST_PWRG: length 3.2
  BOTTOM w0.089: 31.42,109.83 31.38,109.79 v1(31.38,109.71) 31.27,109.59 29.62,109.59 29.4,109.81 UT1.AB5
  BOTTOM w0.14: 31.42,109.83 31.97,110.38 RT4.2
TBT_TMU_CLK_OUT: length 3
  BOTTOM w0.089: UT1.V2 27.79,111.42 27.79,111.88 28.12,112.21 28.12,112.54 27.86,112.79 27.48,112.79 27.23,113.05
  BOTTOM w0.14: 27.23,113.05 RT37.2
TBT_USB2_D+: length 1
  BOTTOM w0.089: v6(21.87,102.4) 21.58,102.69 UT1.E20
  BOTTOM w0.152: RT1141.1 19.69,130.84 v2(19.63,130.79)
TBT_USB2_D-: length 1
  BOTTOM w0.089: v2(21.22,103.02) UT1.D20
  BOTTOM w0.152: v2(20.78,130.79) 20.73,130.84 RT1142.1
TBT_USB3_RX0_N: length 48.3
  TOP w0.097: v2(16.75,102.65) 16.75,102.58 arc(16.79,102.47) 16.87,102.4 arc(16.94,102.38) 17.02,102.37 17.18,102.37 arc(17.26,102.39) 17.32,102.43 17.48,102.58 arc(17.54,102.68) 17.57,102.8 17.57,107 arc(17.54,107.37) 17.46,107.73 17.11,108.89 arc(17.08,109.02) 17.07,109.14 17.07,114.93 arc(17.06,114.95) 17.05,114.97 arc(16.93,115.16) 16.88,115.37 16.88,118.66 arc(16.86,118.78) 16.79,118.88 16.73,118.94 arc(16.64,119.08) 16.6,119.25 16.6,124.04 arc(16.56,124.25) 16.44,124.43 arc(16.17,124.84) 16.07,125.33 16.07,128.95 arc(15.96,129.52) 15.64,130 15.54,130.09 arc(15.44,130.25) 15.4,130.43 15.4,132.65 arc(15.29,133.19) 14.98,133.65 13.79,134.84 arc(13.09,135.31) 12.27,135.48 12.17,135.48 arc(11.39,135.63) 10.73,136.07 9.91,136.89 arc(9.34,137.28) 8.66,137.41 8.46,137.41 8.39,137.41 arc(8.22,137.38) 8.08,137.28 v2(7.95,137.16)
  BOTTOM w0.097: v2(7.95,137.16) 7.74,137.38 arc(7.71,137.4) 7.67,137.4 7.48,137.4 arc(7.39,137.39) 7.32,137.34 DT21.1 7,137.34 arc(6.94,137.39) 6.86,137.4 6.57,137.4 arc(6.46,137.38) 6.37,137.32 6.22,137.16 arc(6.15,137.06) 6.13,136.94 6.13,136.94 6.13,136.66 arc(6.08,136.42) 5.94,136.21 5.05,135.32 arc(4.87,135.2) 4.65,135.16 4.24,135.16 arc(4.17,135.14) 4.12,135.1 JUSBC1.B10 ; RT5835.1 17.48,102.53 arc(17.44,102.44) 17.34,102.4 16.9,102.4 arc(16.8,102.44) 16.75,102.54 v2(16.75,102.65)
TBT_USB3_RX0_N_R: length 2.4
  BOTTOM w0.089: RT5835.2 18.12,102.57 arc(18.29,102.46) 18.5,102.42 18.95,102.42 arc(18.96,102.42) 18.96,102.42 arc(19.11,102.52) 19.29,102.56 19.35,102.56 arc(19.42,102.57) 19.48,102.61 arc(19.57,102.67) 19.67,102.69 19.83,102.69 arc(19.88,102.68) 19.92,102.65 19.92,102.65 arc(19.94,102.62) 19.95,102.58 19.95,102.56 arc(19.94,102.52) 19.92,102.49 19.92,102.49 arc(19.88,102.46) 19.83,102.45 UT1.A21
TBT_USB3_RX0_P: length 48.4
  TOP w0.097: v2(7.95,137.83) 8.05,137.74 arc(8.2,137.64) 8.39,137.6 8.46,137.6 8.66,137.6 arc(9.41,137.45) 10.04,137.02 10.86,136.2 arc(11.46,135.8) 12.17,135.66 12.27,135.66 arc(13.16,135.48) 13.92,134.98 15.12,133.79 arc(15.46,133.26) 15.59,132.65 15.59,130.43 arc(15.61,130.32) 15.67,130.22 15.77,130.13 arc(16.13,129.59) 16.26,128.95 16.26,125.33 arc(16.34,124.91) 16.57,124.56 16.57,124.56 arc(16.73,124.32) 16.79,124.04 16.79,119.25 arc(16.81,119.15) 16.86,119.07 16.92,119.01 arc(17.03,118.85) 17.07,118.66 17.07,115.37 arc(17.1,115.23) 17.18,115.1 arc(17.23,115.02) 17.25,114.93 17.25,109.14 arc(17.26,109.04) 17.28,108.95 17.64,107.78 arc(17.73,107.39) 17.75,107 17.75,102.8 arc(17.72,102.61) 17.61,102.45 17.58,102.43 17.46,102.3 arc(17.33,102.21) 17.18,102.18 17.04,102.18 arc(16.94,102.16) 16.85,102.1 v2(16.75,102.01)
  BOTTOM w0.097: 7.16,137.81 7.33,137.64 arc(7.39,137.6) 7.46,137.59 7.64,137.59 arc(7.71,137.6) 7.76,137.64 v2(7.95,137.83) ; 7.16,137.81 DT20.1 ; 7.16,137.81 6.98,137.63 arc(6.93,137.6) 6.86,137.58 6.57,137.58 arc(6.39,137.55) 6.24,137.45 6.09,137.3 arc(5.98,137.13) 5.94,136.94 5.94,136.66 arc(5.91,136.49) 5.81,136.34 4.92,135.46 arc(4.8,135.37) 4.65,135.34 3.88,135.34 arc(3.88,135.34) 3.88,135.34 JUSBC1.B11 ; v2(16.75,102.01) 16.91,102.16 arc(16.96,102.2) 17.02,102.21 17.25,102.21 arc(17.32,102.2) 17.38,102.16 RT5834.1
TBT_USB3_RX0_P_R: length 2.4
  BOTTOM w0.089: UT1.B21 20.02,102.28 arc(19.97,102.24) 19.9,102.23 19.64,102.23 arc(19.58,102.24) 19.53,102.27 19.45,102.35 arc(19.42,102.37) 19.38,102.38 19.29,102.38 arc(19.18,102.36) 19.09,102.3 arc(19.02,102.25) 18.95,102.24 18.3,102.24 arc(18.24,102.23) 18.19,102.19 RT5834.2
TBT_USB3_RX1_N: length 34.5
  TOP w0.097: v2(15.26,106.57) 15.4,106.71 arc(15.47,106.75) 15.55,106.77 arc(15.68,106.79) 15.79,106.87 15.84,106.92 arc(15.92,107.03) 15.95,107.17 15.95,107.26 arc(15.87,107.63) 15.66,107.94 15.66,107.94 arc(15.57,108.09) 15.53,108.26 15.53,114.37 arc(15.53,114.54) 15.51,114.7 15.5,114.82 arc(15.49,114.97) 15.49,115.12 15.49,117.71 arc(15.45,117.92) 15.33,118.09 15.33,118.09 arc(15.24,118.23) 15.21,118.38 15.21,120.02 arc(15.17,120.21) 15.06,120.37 14.59,120.84 arc(14.52,120.94) 14.5,121.06 14.5,127.74 arc(14.35,128.49) 13.93,129.13 13.48,129.57 arc(12.57,130.18) 11.5,130.39 10.6,130.39 arc(10.37,130.44) 10.17,130.57 10.1,130.64 arc(9.79,130.84) 9.43,130.92 9.13,130.92 9.1,130.92 arc(9.08,130.93) 9.06,130.95 DT18.1 8.87,131 arc(8.72,130.89) 8.53,130.86 8.19,130.86 arc(8.08,130.83) 7.99,130.77 arc(7.93,130.73) 7.87,130.72 7,130.72 arc(6.91,130.74) 6.83,130.79 6.62,131 arc(6.53,131.06) 6.42,131.08 6.4,131.08 arc(6.33,131.1) 6.28,131.13 6.23,131.18 arc(6.15,131.23) 6.05,131.25 JUSBC1.A10
  BOTTOM w0.097: v2(15.26,106.57) 16,106.57 arc(16.12,106.59) 16.23,106.66 arc(16.29,106.7) 16.36,106.72 RT5833.1
TBT_USB3_RX1_N_R: length 3.4
  BOTTOM w0.097: UT1.B15 20.08,105.1 arc(19.96,105.01) 19.81,104.99 19.68,104.99 arc(19.58,105.01) 19.49,105.06 17.87,106.69 arc(17.84,106.71) 17.81,106.72 17.81,106.72 arc(17.8,106.72) 17.79,106.72 RT5833.2
TBT_USB3_RX1_P: length 34.5
  TOP w0.097: JUSBC1.A11 6.11,130.75 arc(6.16,130.76) 6.21,130.79 6.29,130.87 arc(6.32,130.89) 6.35,130.9 6.42,130.9 arc(6.46,130.89) 6.48,130.87 6.69,130.66 arc(6.84,130.57) 7,130.53 7.87,130.53 arc(8,130.56) 8.12,130.64 8.12,130.64 arc(8.15,130.66) 8.19,130.67 8.49,130.67 arc(8.64,130.64) 8.77,130.56 DT19.1 9.2,130.64 arc(9.21,130.65) 9.22,130.66 9.32,130.73 9.43,130.73 arc(9.72,130.67) 9.97,130.51 10.04,130.44 arc(10.29,130.27) 10.6,130.21 11.5,130.21 arc(12.5,130.01) 13.35,129.44 13.79,129 arc(14.18,128.42) 14.32,127.74 14.32,121.06 arc(14.35,120.87) 14.46,120.71 14.93,120.24 arc(15,120.14) 15.02,120.02 15.02,118.38 arc(15.07,118.15) 15.2,117.96 arc(15.27,117.84) 15.3,117.71 15.3,115.12 arc(15.31,114.96) 15.32,114.8 15.33,114.68 arc(15.34,114.53) 15.35,114.37 15.35,108.26 arc(15.39,108.02) 15.53,107.81 arc(15.7,107.56) 15.76,107.26 15.76,107.17 arc(15.75,107.1) 15.71,107.05 15.66,107 arc(15.61,106.96) 15.55,106.95 15.4,106.95 arc(15.3,106.99) 15.26,107.09 v2(15.26,107.2)
  BOTTOM w0.097: RT5832.1 16.69,106.95 arc(16.64,106.92) 16.58,106.9 16.36,106.9 arc(16.22,106.88) 16.1,106.79 16.09,106.79 arc(16.05,106.76) 16,106.75 15.76,106.75 arc(15.72,106.76) 15.68,106.78 v2(15.26,107.2)
TBT_USB3_RX1_P_R: length 3.4
  BOTTOM w0.097: UT1.A15 19.82,105.24 arc(19.9,105.36) 19.79,105.45 19.42,105.45 arc(19.37,105.46) 19.33,105.48 18.03,106.79 17.98,106.89 arc(17.96,106.92) 17.94,106.95 arc(17.93,106.96) 17.92,106.97 RT5832.2
TBT_USB3_TX0_N: length 42
  TOP w0.097: JUSBC1.A3 6.1,134.75 6.21,134.86 arc(6.27,134.9) 6.33,134.91 6.59,134.91 arc(6.76,134.94) 6.9,135.04 6.97,135.11 arc(7.4,135.4) 7.92,135.5 8.64,135.5 arc(8.71,135.48) 8.77,135.44 DT13.1 9.21,135.54 arc(9.24,135.56) 9.28,135.57 9.91,135.57 arc(10.06,135.54) 10.19,135.45 10.61,135.03 arc(11,134.77) 11.45,134.68 12.1,134.68 arc(12.77,134.55) 13.34,134.17 14.43,133.07 arc(14.55,132.9) 14.59,132.7 14.59,129.67 arc(14.62,129.48) 14.73,129.32 15.17,128.88 arc(15.23,128.79) 15.26,128.67 15.26,124.73 arc(15.29,124.58) 15.37,124.45 15.54,124.29 arc(15.74,123.98) 15.81,123.63 15.81,118.74 arc(15.85,118.56) 15.95,118.41 arc(16.05,118.25) 16.09,118.07 16.09,115.18 arc(16.1,115.05) 16.14,114.93 16.19,114.81 arc(16.24,114.67) 16.25,114.52 16.25,108.58 arc(16.31,108.31) 16.46,108.07 arc(16.53,107.97) 16.56,107.85 16.56,106.95 arc(16.58,106.79) 16.66,106.65 arc(16.67,106.64) 16.69,106.63 16.7,106.62 arc(16.7,106.62) 16.71,106.62 arc(16.75,106.57) 16.77,106.5 16.77,104.29 arc(16.76,104.21) 16.71,104.14 16.68,104.11 arc(16.63,104.08) 16.56,104.06 16.31,104.06 arc(16.27,104.07) 16.24,104.1 16.17,104.18 v2(16.17,104.34)
  BOTTOM w0.097: v2(16.17,104.34) 16.17,104.27 16.47,103.98 arc(16.66,103.9) 16.85,103.98 CT40.2
TBT_USB3_TX0_N_C: length 2.7
  BOTTOM w0.097: UT1.B19 20.07,103.5 arc(19.96,103.57) 19.84,103.59 19.46,103.59 arc(19.37,103.6) 19.28,103.63 arc(19.28,103.63) 19.28,103.63 arc(19.26,103.64) 19.25,103.64 arc(19.19,103.66) 19.13,103.67 18.85,103.67 arc(18.7,103.7) 18.58,103.78 18.36,104 arc(18.35,104.01) 18.34,104.02 arc(18.25,104.08) 18.14,104.11 arc(18.11,104.11) 18.08,104.11 18.08,104.11 arc(18.02,104.13) 17.97,104.16 CT40.1
TBT_USB3_TX0_P: length 42.1
  TOP w0.097: v2(16.17,103.7) 16.31,103.84 16.37,103.88 16.56,103.88 arc(16.7,103.9) 16.81,103.98 16.84,104.01 16.84,104.01 arc(16.93,104.14) 16.96,104.29 16.96,106.5 arc(16.92,106.66) 16.8,106.77 arc(16.76,106.85) 16.74,106.95 16.74,107.85 arc(16.7,108.04) 16.59,108.21 16.59,108.21 arc(16.48,108.38) 16.44,108.58 16.44,114.52 arc(16.42,114.7) 16.36,114.88 16.31,115.01 arc(16.29,115.09) 16.28,115.18 16.28,118.07 arc(16.22,118.32) 16.08,118.54 arc(16.02,118.63) 16,118.74 16,123.63 arc(15.91,124.05) 15.67,124.42 15.5,124.58 arc(15.46,124.65) 15.44,124.73 15.44,128.67 arc(15.41,128.86) 15.3,129.01 14.86,129.46 arc(14.8,129.55) 14.77,129.67 14.77,132.7 arc(14.72,132.97) 14.56,133.21 13.47,134.3 arc(12.84,134.72) 12.1,134.87 11.45,134.87 arc(11.07,134.94) 10.74,135.16 10.32,135.58 arc(10.13,135.71) 9.91,135.76 9.49,135.76 arc(9.31,135.77) 9.14,135.82 9.05,135.86 DT12.1 8.94,135.91 8.77,135.73 arc(8.71,135.7) 8.65,135.68 7.92,135.68 arc(7.33,135.57) 6.84,135.24 6.77,135.17 arc(6.69,135.11) 6.59,135.09 6.33,135.09 arc(6.27,135.11) 6.23,135.14 6.11,135.25 JUSBC1.A2
  BOTTOM w0.097: CT39.2 17.15,103.7 v2(16.17,103.7)
TBT_USB3_TX0_P_C: length 2.7
  BOTTOM w0.097: CT39.1 17.91,103.88 arc(17.97,103.92) 18.04,103.93 18.08,103.93 arc(18.1,103.93) 18.11,103.93 arc(18.17,103.91) 18.22,103.88 arc(18.23,103.87) 18.23,103.86 18.45,103.65 arc(18.63,103.53) 18.85,103.48 19.13,103.48 arc(19.15,103.48) 19.17,103.48 arc(19.18,103.47) 19.2,103.46 arc(19.3,103.39) 19.36,103.3 19.36,103.28 arc(19.44,103.18) 19.57,103.14 19.77,103.14 arc(19.88,103.26) 19.77,103.37 UT1.A19
TBT_USB3_TX1_N: length 36.2
  TOP w0.097: v2(7.8,128.35) 7.6,128.15 arc(7.58,128.11) 7.57,128.08 7.57,128.01 arc(7.59,127.89) 7.66,127.79 7.94,127.51 arc(8.13,127.38) 8.37,127.34 11.79,127.34 arc(12.18,127.26) 12.5,127.04 13.23,126.31 arc(13.44,126) 13.51,125.64 13.51,117.99 arc(13.58,117.65) 13.77,117.36 14,117.14 arc(14.12,116.96) 14.16,116.75 14.16,112.33 arc(14.18,112.22) 14.24,112.12 14.48,111.89 arc(14.66,111.62) 14.72,111.3 14.72,108.44 arc(14.63,108) 14.38,107.63 14.27,107.51 arc(14.1,107.26) 14.04,106.97 14.04,106.09 arc(14.09,105.84) 14.23,105.62 14.3,105.56 arc(14.36,105.52) 14.43,105.5 14.74,105.5 arc(14.77,105.51) 14.79,105.53 v2(15.07,105.8)
  BOTTOM w0.097: v2(7.8,128.35) 7.66,128.49 arc(7.59,128.58) 7.57,128.69 7.57,128.71 arc(7.59,128.82) 7.66,128.91 7.8,129.05 ; CT38.2 15.65,105.61 arc(15.63,105.59) 15.59,105.58 15.37,105.58 arc(15.3,105.6) 15.23,105.64 v2(15.07,105.8) ; 7.8,129.05 7.59,129.25 arc(7.56,129.3) 7.55,129.36 7.55,129.37 arc(7.52,129.52) 7.43,129.65 6.83,130.26 arc(6.67,130.36) 6.49,130.4 5.63,130.4 arc(5.45,130.43) 5.3,130.54 4.77,131.07 arc(4.61,131.17) 4.42,131.21 4.08,131.21 arc(3.83,131.26) JUSBC1.B3 ; 7.8,129.05 DT26.1
TBT_USB3_TX1_N_C: length 4.3
  BOTTOM w0.097: UT1.B17 20.09,104.4 arc(19.96,104.48) 19.81,104.51 19.13,104.51 arc(19.01,104.54) 18.91,104.61 18.11,105.4 arc(17.91,105.54) 17.67,105.59 16.67,105.59 arc(16.59,105.6) 16.53,105.65 CT38.1
TBT_USB3_TX1_P: length 36.1
  TOP w0.097: v2(7.16,128.35) 7.34,128.17 arc(7.37,128.12) 7.38,128.06 7.38,128.01 arc(7.42,127.82) 7.53,127.66 7.81,127.38 arc(8.06,127.21) 8.37,127.15 11.79,127.15 arc(12.1,127.09) 12.37,126.91 13.1,126.18 arc(13.27,125.93) 13.33,125.64 13.33,117.99 arc(13.41,117.58) 13.64,117.23 13.87,117 arc(13.94,116.89) 13.97,116.75 13.97,112.33 arc(14.01,112.15) 14.11,111.99 14.34,111.76 arc(14.48,111.55) 14.53,111.3 14.53,108.44 arc(14.46,108.07) 14.25,107.76 14.14,107.64 arc(13.93,107.33) 13.86,106.97 13.86,106.09 arc(13.92,105.76) 14.1,105.49 14.17,105.43 arc(14.29,105.35) 14.43,105.32 14.78,105.32 arc(14.87,105.3) 14.95,105.26 v2(15.07,105.17)
  BOTTOM w0.089: CT37.2 15.78,105.24
  BOTTOM w0.097: v2(15.07,105.17) 15.24,105.34 arc(15.3,105.38) 15.37,105.4 15.55,105.4 arc(15.61,105.39) 15.67,105.35 15.78,105.24 ; JUSBC1.B2 3.89,130.88 arc(4.05,130.99) 4.24,131.02 4.42,131.02 arc(4.54,131) 4.63,130.94 5.17,130.4 arc(5.38,130.26) 5.63,130.21 6.49,130.21 arc(6.6,130.19) 6.7,130.13 7.3,129.52 arc(7.35,129.45) 7.37,129.37 7.37,129.35 arc(7.35,129.26) 7.3,129.19 DT27.1 7.3,128.91 arc(7.37,128.82) 7.39,128.71 7.39,128.69 arc(7.37,128.58) 7.3,128.49 v2(7.16,128.35)
TBT_USB3_TX1_P_C: length 4.3
  BOTTOM w0.097: CT37.1 16.52,105.32 arc(16.61,105.38) 16.72,105.4 17.67,105.4 arc(17.84,105.37) 17.98,105.27 18.78,104.47 arc(18.94,104.37) 19.13,104.33 19.29,104.33 arc(19.38,104.29) 19.42,104.2 arc(19.46,104.09) 19.56,104.05 19.77,104.05 arc(19.85,104.1) 19.83,104.2 UT1.A17
TBTA_AUX_N: length 4.9
  TOP w0.152: RT432.2 17.18,127.17 v2(17.22,126.88) ; v2(31.92,102.98) 31.53,102.98 31.42,103.08 31.42,103.33 31.57,103.48 31.9,103.48 32.08,103.66 32.08,104.17 CT42.2
  BOTTOM w0.081: v2(17.22,126.88) 17.29,126.81 17.75,126.81 18.04,126.53 18.04,126.5 18.23,126.32 18.63,126.32 UT4.J2
TBTA_AUX_N_C: length 4.8
  TOP w0.089: CT42.1 30.66,104.29 30.04,104.91 29.59,104.91 29.15,105.35 28.87,105.35 28.76,105.24 28.1,105.24 v2(27.72,105.62)
  BOTTOM w0.102: UT1.W15 v2(27.72,105.62)
TBTA_AUX_P: length 5
  TOP w0.152: v2(32.6,102.98) 32.51,102.98 32.41,103.08 32.41,104.62 32.17,104.86 CT41.2 ; RT431.2 17.5,126.28 v2(17.22,126.28)
  BOTTOM w0.081: UT4.J1 18.38,125.89 18.32,125.83 18.16,125.83 18.07,125.92 18.07,126.18 17.91,126.34 17.86,126.34 17.65,126.55 17.35,126.55 17.22,126.43 v2(17.22,126.28)
TBTA_AUX_P_C: length 4.6
  TOP w0.089: CT41.1 31.19,105.04 31.07,105.04 31.01,104.98 31.01,104.62 30.95,104.55 30.77,104.55 30.15,105.17 29.71,105.17 29.26,105.62 28.76,105.62 28.65,105.5 28.48,105.5 v2(28.37,105.62)
  BOTTOM w0.089: UT1.Y15 28.55,105.29 28.37,105.47 v2(28.37,105.62)
TBTA_BOT_C_N: length 2
  TOP w0.14: v2(4.76,140.33) 4.96,140.13 5.19,140.13 DT23.1 5.51,140.16 5.92,140.16 6.15,140.4 LT13.3
TBTA_BOT_C_P: length 2.2
  TOP w0.14: v2(4.7,139.75) 4.82,139.88 5.13,139.88 DT24.1 5.6,139.85 5.85,139.85 6.14,139.55 LT13.2
TBTA_BOT_N: length 23
  TOP w0.152: v2(21.87,131.42) 21.81,131.36 21.3,131.36 21.09,131.57 v5(19.58,131.57) 17.66,131.57 17.34,131.89 17.34,132.02 16.56,132.8 16.56,133.72 13.53,136.75 12.7,136.75 11.63,137.81 11.29,137.81 8.99,140.11 8.75,140.11 8.46,140.4 LT13.4
  BOTTOM w0.081: 21.32,129.47 21.32,128.87 21.71,128.48 21.71,127.74 21.51,127.53 21.51,127.44 21.38,127.31 UT4.L7
  BOTTOM w0.14: 21.32,129.47 21.32,130.92 21.83,131.42 v2(21.87,131.42)
TBTA_BOT_P: length 22.9
  TOP w0.152: LT13.1 8.43,139.55 8.66,139.78 8.86,139.78 11.15,137.48 11.49,137.48 12.56,136.42 13.39,136.42 16.23,133.58 16.23,132.66 17.01,131.88 17.01,131.76 17.53,131.24 20.96,131.24 21.16,131.03 21.68,131.03 v2(21.87,130.84)
  BOTTOM w0.081: 21.56,129.47 21.56,128.92 21.98,128.5 21.98,127.62 21.78,127.42 21.78,127.32 21.63,127.17 21.63,126.82 UT4.K7
  BOTTOM w0.14: v2(21.87,130.84) 21.56,130.53 21.56,129.47
TBTA_CC1: length 1
  TOP w0.508: v2(23.8,129.19) 24.08,128.91 CT160.1
  vias: v2(7.3,133.62)
TBTA_CC2: length 10.8
  TOP w0.254: CT159.1 23.1,128.66 23.24,128.52 v2(23.24,127.72)
  TOP w0.508: 4.85,126.58 v1(3.42,126.58) 3.23,126.76 3.23,126.76 2.11,127.88 2.11,132.26 2.51,132.67 3.15,132.67 JUSBC1.B5
  vias: v2(6.13,126.66)
TBTA_DEBUG1: length 3.4
  BOTTOM w0.081: 18.17,128.51 18.29,128.51 18.8,128.01 18.8,127.15 UT4.L2
  BOTTOM w0.14: RT184.2 17.13,129.02 17.64,128.52 18.14,128.52 18.15,128.51 18.17,128.51
TBTA_DEBUG2: length 4.5
  BOTTOM w0.081: UT4.K2 18.63,126.82 18.63,127.17 18.63,127.17 18.63,127.93 18.47,128.1 17.57,128.1 17.51,128.16
  BOTTOM w0.14: RT185.2 16.31,129.35 17.51,128.16
TBTA_DEBUG3_LSTX: length 2.9
  BOTTOM w0.081: UT4.L3 19.38,127.16 19.12,127.42 19.12,128.33 18.63,128.82 RT187.2
  BOTTOM w0.14: RT233.2 19.19,129.04 RT187.2
TBTA_DEBUG4_LSRX: length 6.4
  BOTTOM w0.081: 18.17,128.86 18.27,128.86 18.96,128.17 18.96,127.34 19.13,127.17 19.13,126.82 UT4.K3
  BOTTOM w0.14: 18.17,128.86 RT188.2 17.83,129.04 17.61,129.26 17.61,130.25 RT232.2 18.08,130.87 v1(17.36,131.59)
TBTA_HPD: length 13.8
  TOP w0.089: 25.11,113.05 24.85,112.79 24.46,112.79 23.99,112.32 23.99,111.26 24.26,111 24.26,110.66 24.47,110.45 v2(24.47,110.17)
  TOP w0.14: RT43.2 26.47,113.94 26.02,114.38 v2(25.55,114.38) 25.46,114.29 25.46,113.4 25.11,113.05
  BOTTOM w0.089: UT1.M4 24.8,110.46 24.5,110.17 v2(24.47,110.17)
  BOTTOM w0.14: RT181.2 23.41,118.46 23.63,118.23 23.63,117.86 23.84,117.66 24.45,117.66 25.06,117.05 25.06,114.88 v2(25.55,114.38)
TBTA_HRESET: length 1.5
  TOP w0.14: v2(21.09,123.11) 21.09,123.54 RT429.1
  BOTTOM w0.14: v2(21.09,123.11) 20.88,123.32 UT4.D6
TBTA_I2C_INT#: length 7.9
  TOP w0.089: v1(22.47,111.18) 22.82,110.82 v6(23.17,110.82)
  BOTTOM w0.081: 16.96,122.46 17.04,122.55 v2(17.42,122.55)
  BOTTOM w0.089: UT1.J4 23.5,110.5 v6(23.17,110.82)
  BOTTOM w0.14: RT167.2 14.36,120.41 13.85,120.92 13.85,122.21 14.44,122.8 15.84,122.8 16.4,122.24 RT5838.1 16.73,122.24 16.96,122.46
TBTA_I2C_INT#_R: length 2
  BOTTOM w0.081: 16.94,122.9 17.96,122.9 18.12,123.07 UT4.C1
  BOTTOM w0.14: 16.94,122.9 16.59,122.9 RT5838.2
TBTA_LDO_BMC: length 5.5
  BOTTOM w0.081: 16.73,124.38 16.83,124.27 17.31,124.27 17.48,124.45 17.84,124.45 17.96,124.33 18.03,124.33 18.21,124.16 18.24,124.16 18.33,124.07 UT4.E1
  BOTTOM w0.14: v1(13.44,124.99) CT144.1 15.01,124.38 15.84,124.38 15.88,124.41 16.15,124.41 16.19,124.38 16.73,124.38
TBTA_PD_SBU1: length 3
  BOTTOM w0.081: 22.69,128.54 22.69,128.53 22.31,128.15 22.31,127.48 22.13,127.29 22.13,126.82 UT4.K8
  BOTTOM w0.14: 22.69,128.54 22.76,128.61 22.76,128.88 RT176.1
TBTA_PD_SBU2: length 2.3
  BOTTOM w0.081: 22.52,128.72 22.52,128.63 22.15,128.26 22.15,127.55 21.97,127.37 21.97,127.16 UT4.L8
  BOTTOM w0.152: 22.52,128.72 22.52,128.92 RT177.1
TBTA_RESET_N: length 3.4
  TOP w0.089: v2(23.18,109.5) 23.19,109.52 v1(23.19,110.11)
  TOP w0.14: v2(28.37,115.52) 27.99,115.52 27.55,115.97 27.12,115.97 DT29.1
  BOTTOM w0.081: UT4.F11 23.84,124.57 v2(24.03,124.38)
TBTA_SBU1: length 4.5
  TOP w0.152: JUSBC1.A8 7.06,132.25 7.43,131.88 7.68,131.88 DT17.1 7.74,132.15 7.61,132.28 v2(7.61,132.4)
  BOTTOM w0.152: RT176.2 22.87,129.74 22.87,130.3 v2(23,130.43) 23.53,130.43 v1(23.67,130.57)
TBTA_SBU2: length 8.9
  TOP w0.152: v2(3.57,139.56) 3.45,139.45 3.33,139.45 3.09,139.21 DT22.1 2.25,139.18 2.25,134.21 2.66,133.8 JUSBC1.B8
  BOTTOM w0.152: RT177.2 22.54,129.83 22.54,130.3 v2(22.38,130.46)
TBTA_TOP_C_N: length 4.7
  TOP w0.14: LT12.2 9.7,133.2 9.53,133.36 9.3,133.36 8.99,133.05 DT16.1 8.4,133.05 8.19,132.84 v5(7.56,132.84) 6.18,132.84 6.09,132.75 JUSBC1.A7
TBTA_TOP_C_P: length 4.8
  TOP w0.14: JUSBC1.A6 6.07,133.25 6.16,133.17 8.06,133.17 8.47,133.59 8.78,133.59 DT15.1 9,133.69 9.46,133.69 9.82,134.05 LT12.3
TBTA_TOP_N: length 4.9
  TOP w0.14: LT12.1 11.96,133.2 12.28,133.52 12.49,133.52 12.89,133.11 12.89,132.31 13.24,131.96 13.48,131.96 13.74,131.69 v2(13.79,131.69)
  BOTTOM w0.081: v2(21.06,128.46) 21.06,128.31 20.94,128.19 20.94,127.4 20.88,127.34 UT4.L6
TBTA_TOP_P: length 4.8
  TOP w0.14: v2(13.79,132.28) 13.37,132.28 13.22,132.42 13.22,133.25 v5(12.96,133.51) 12.63,133.85 12.15,133.85 11.95,134.05 LT12.4
  BOTTOM w0.081: UT4.K6 21.13,126.82 21.13,127.29 21.25,127.41 21.25,127.79 v2(21.3,127.84)
TBTB_HPD: length 4.3
  BOTTOM w0.089: UT1.G2 22.73,111.43 22.73,111.83 22.87,111.97 23.15,111.97 23.48,112.3 23.48,112.98 23.42,113.05
  BOTTOM w0.14: 23.42,113.05 23.42,113.11 23.36,113.16 RT209.2 23.36,114.45 v1(23.66,114.75)
TBTB_I2C_INT#: length 3.3
  BOTTOM w0.089: 22.06,113.05 21.85,112.83 21.65,112.83 21.33,112.51 21.33,111.43 UT1.E2
  BOTTOM w0.14: 22.06,113.05 22.14,113.12 22.3,113.12 22.66,113.48 RT1145.2
TBTB_LSRX: length 3
  BOTTOM w0.089: UT1.B5 19.98,109.59 19.56,109.59 19.43,109.47 19.43,108.99 19.17,108.72 18.4,108.72 18.34,108.66
  BOTTOM w0.14: RT208.2 18.26,108.59 18.34,108.66
TBTB_LSTX: length 2.5
  BOTTOM w0.089: 18.34,110.19 19.06,110.19 19.19,110.33 19.41,110.33 19.57,110.49 19.91,110.49 20.13,110.27 UT1.B4
  BOTTOM w0.14: 18.34,110.19 18.18,110.19 RT207.2
TESTMODE: length 9.5
  BOTTOM w0.102: UV18.AK11 195.19,133.17 195.19,132.6 194.93,132.35 194.74,132.35 194.37,131.98 194.37,131.74 194.09,131.46 193.85,131.46 193.57,131.18 193.57,130.94 193.29,130.66 192.04,130.66 191.8,130.41
  BOTTOM w0.14: RV592.1 188.94,129.22 v1(189.84,130.12) 190.13,130.41 191.8,130.41
THERMAL_ALERT#: length 4.2
  BOTTOM w0.14: RV553.1 210.59,122.75 210.59,124.63 211.09,125.13 211.09,125.7 UV18.M2
THERMATRIP_GPU#: length 4.4
  TOP w0.14: RV594.1 RV1082.1 216.01,113.25 v2(215.6,112.83) ; v2(201.03,118.64) 201.03,118.48 201.52,117.99 U33.3
  BOTTOM w0.102: v2(209.97,124.36) 209.97,124.56 UV18.M1
THERMATRIP_GPU#_R: length 5.5
  TOP w0.14: RV1082.2 216.2,110.75 QV91.3 214.35,108.9 v1(213.06,108.9)
THERMDA: length 0.5
  BOTTOM w0.089: UT1.AB23 UT1.AC23
THERMTRIP1#: length 8.5
  TOP w0.14: U33.4 201.5,117.59 201.13,117.96 200.93,117.96 v2(200.91,117.98) ; UE3.B12 292.4,86.38 292.4,87.11 291.64,87.88 290.3,87.88 289.78,88.39 v2(289.67,88.39) 289.27,88.79 RE25.1 ; RV1083.2 215.01,111.73 v2(215.16,111.58) ; v2(268.08,90.47) v1(267.43,90.47)
THERMTRIP2#: length 11.2
  TOP w0.076: 298.29,76.22 298.29,76.68 297.87,77.11 297.87,78.69 297.7,78.86 UE3.H3
  TOP w0.14: RE66.2 CE52.1 ; RE66.2 300.06,74.59 299.17,74.59 v1(298.95,74.81) 298.69,75.08 298.69,75.72 298.29,76.12 298.29,76.22 ; RE66.2 299.85,73.75 299.85,72.55 299.45,72.15 298.53,72.15 QE10.1
TOUCH_SCREEN_PD#: length 12.2
  BOTTOM w0.089: 71.64,80.12 71.96,79.8 72.34,79.8 72.62,80.08 73.06,80.08 73.52,79.61 73.52,79.1 73.71,78.91 73.93,78.91 74.02,78.82 75.13,78.82 UH2.AM45 75.16,79 v2(75.51,79.35)
  BOTTOM w0.14: JTS1.6 339.71,114.27 v1(340.42,113.56) 340.69,113.29 v2(340.69,112.98) ; v2(346.51,112.54) 346.51,112.8 346.44,112.87 DI1.1 ; 71.64,80.12 71.64,80.28 70.93,80.99 70.93,81.4 70.62,81.71 69.41,81.71 RH510.1
TOUCHPAD_INTR#: length 4.7
  TOP w0.089: v1(80.63,70.43) 80.77,70.43 v2(81.23,69.97) 80.95,69.69 DH1.2
  BOTTOM w0.089: RH547.1 81.23,69.22 v2(81.23,69.97) 81.23,70.43 81.6,70.8 81.6,71.61 81.62,71.63 UH2.BF32
TOUCHPAD_INTR#_EC: length 9.9
  TOP w0.14: v2(185.66,75.48) 184.91,74.73 184.91,74.12 184.24,73.45 184.24,71.43 184.63,71.04 v1(185.23,71.04) 185.58,71.04 RE138.2 ; UE3.G2 296.41,77.74 296.41,76.73 v2(296.79,76.35) ; v2(283.87,78.63) 283.75,78.51 RP19.2
TP_PWR_EN: length 10.4
  TOP w0.076: UE3.H9 297.52,83.63 v2(297.89,83.26)
  TOP w0.14: v1(283.57,84.8) 283.71,84.95 v2(283.71,85.42) ; UE6.3 190.37,72.02 190.61,71.77 191.13,71.77 RZ32.2 193.36,72.71 194.41,72.71 196.81,75.11 v2(196.81,75.25)
TPM_PIRQ#: length 25.9
  TOP w0.14: RE86.2 152.07,79.3 151.75,78.99 v1(151.35,78.99) 147.9,78.99 147.45,78.53 v2(147.45,78.25) 147.45,76.57 148.33,75.69 U32.18
  BOTTOM w0.089: UH2.BD29 82.89,72.48 82.89,71.07 82.72,70.9 82.72,70.13 v2(82.78,70.07)
  BOTTOM w0.14: v2(145.44,68.88) 145.44,73.7 143.31,75.84 143.31,76.47 144.8,77.96 147.16,77.96 v2(147.45,78.25)
TS_DETECT#: length 16.3
  BOTTOM w0.089: UH2.AM48 73.7,78.67 73.33,79.04 73.33,79.23 v2(72.85,79.71) 72.58,79.71 72.49,79.62 71.85,79.62 71.35,80.12 71.35,80.24 71.04,80.55
  BOTTOM w0.14: RH5849.1 68.63,81.47 70.12,81.47 71.04,80.55 ; RC5835.2 343.46,111.6 343.73,111.33 v2(343.73,110.62) 343.73,110.55 343.63,110.45 340.99,110.45 340.72,110.72 340.72,111.3 340.63,111.38 340.63,112.39 340.21,112.81 340.21,113.12 338.91,114.41 JTS1.7
  vias: v2(288.6,73.8)
TS_I2C_RST#: length 17.6
  TOP w0.14: v2(261.43,76.25) 261.43,76.83 261.18,77.09 261.18,80.73 261.85,81.41 261.85,83.63 262.48,84.26 v1(262.48,85.24) 262.48,87.83 v2(264.63,89.98)
  BOTTOM w0.089: v2(83.66,73.66) 83.66,73.62 83.76,73.52 83.76,72.98 83.11,72.33 UH2.BE29
  BOTTOM w0.14: v2(341.73,110.98) 341.73,111.47 RR44.1
  vias: v2(187.43,79.06)
TSENSE_2PH: length 7.6
  TOP w0.203: PR1173.1 106.86,183.15 108,182.01 v1(108,181.49) 108,179.79 108.41,179.37 PU1100.25
  TOP w0.254: PR1173.1 106.78,185.18 PC1131.1
TSENSE_4PH: length 5.7
  TOP w0.14: v1(116.97,181.39) 116.43,180.85 PR1172.1
  TOP w0.203: PU1100.14 112.81,179.3 112.98,179.47 113.51,179.47
  TOP w0.254: 113.51,179.47 114.48,180.43 PC1129.1 116.1,180.43 116.18,180.36 PR1172.1
UART2_RXD: length 4.6
  TOP w0.152: RH562.2 102.08,72.38 101.67,72.38 101.31,72.03 100.88,72.03 v2(100.76,72.15)
  BOTTOM w0.089: v2(87.44,70.61) 87.49,70.66 87.49,71.14 87.15,71.48 87.15,72.85 UH2.BD20
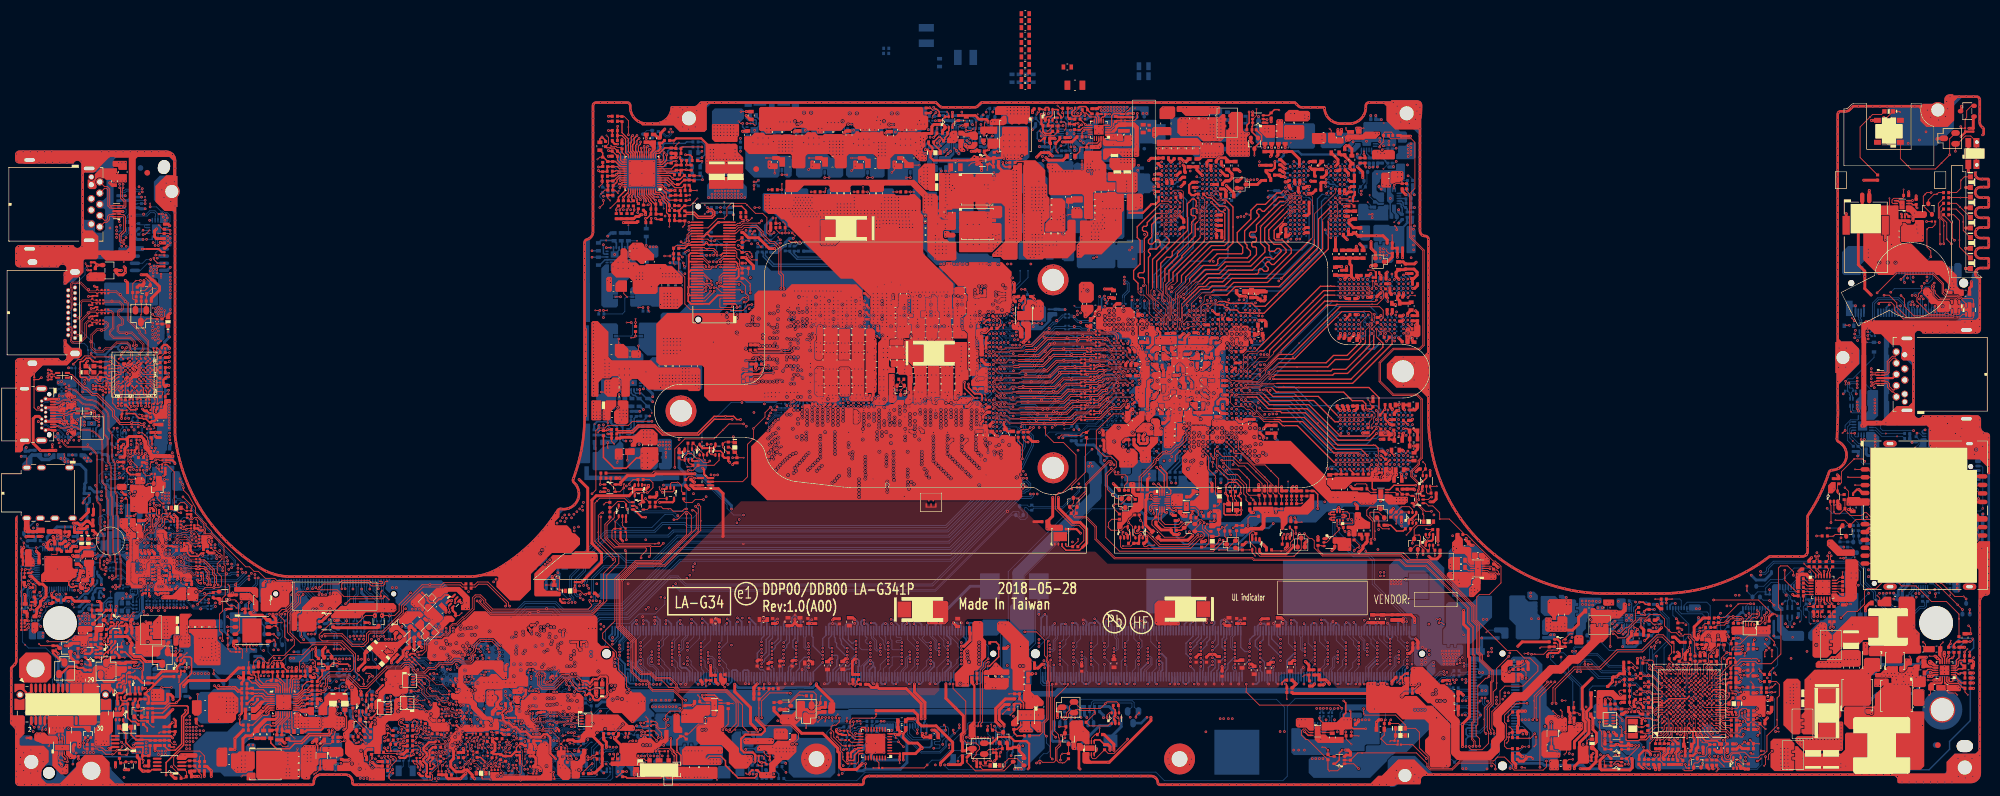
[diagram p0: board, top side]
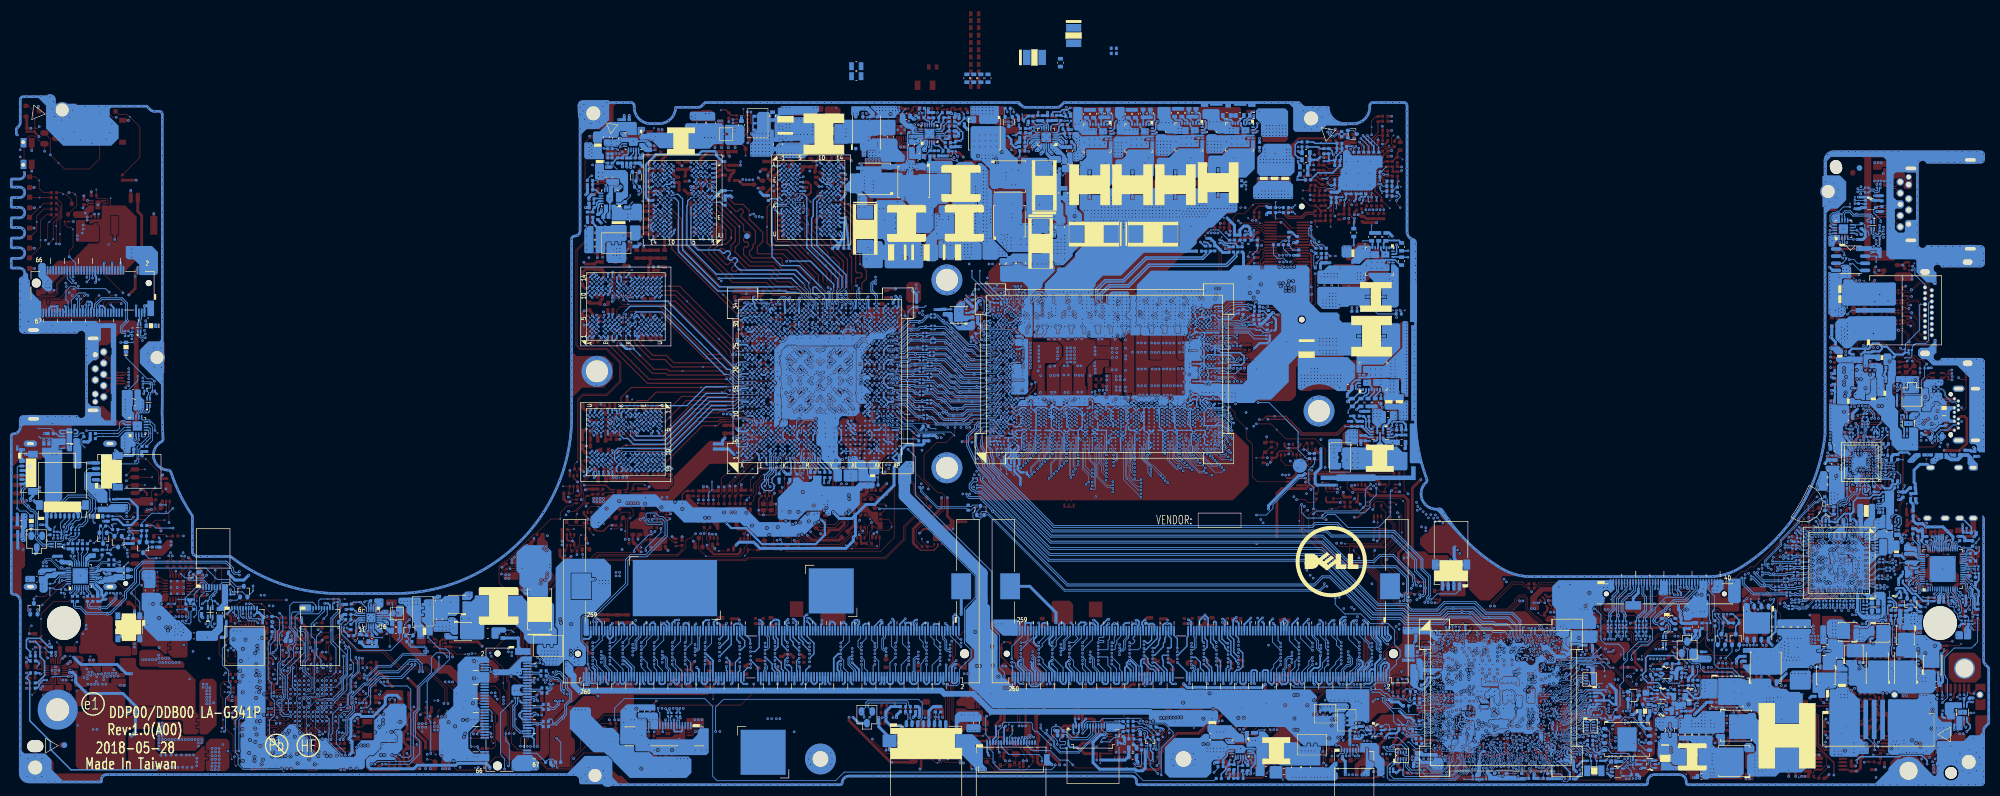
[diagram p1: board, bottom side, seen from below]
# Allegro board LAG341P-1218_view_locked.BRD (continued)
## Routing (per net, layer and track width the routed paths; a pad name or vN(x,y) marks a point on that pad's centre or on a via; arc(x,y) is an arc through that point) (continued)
UART2_TXD: length 4.6
  TOP w0.152: RH561.2 102.08,72.05 101.8,72.05 101.45,71.7 100.89,71.7 v2(100.76,71.56)
  BOTTOM w0.089: UH2.BE20 87.48,72.57 87.59,72.57 87.66,72.5 87.66,72.28 87.44,72.05 87.44,71.57 87.76,71.25 87.76,70.86 v2(88,70.62)
UG1_ISL88738: length 3.9
  TOP w0.14: v1(39.17,68.6) 39.42,68.85 PQ1900.4
  TOP w0.203: PU1900.11 46.08,79.04 45.14,78.1 v2(44.78,78.1)
  vias: v2(40.44,74.19) v2(40.72,68.18) v2(41.2,74.19) v2(41.37,68.18)
UG2_ISL88738: length 5
  TOP w0.14: v2(34.23,86.88) v1(34.23,87.54)
  TOP w0.203: v3(43.02,80.79) 43.83,81.6 PU1900.5
  BOTTOM w0.508: v2(34.23,86.88) 35.81,85.3 PQ1901.4
UG_3V: length 1
  TOP w0.14: v1(339.5,90) v2(340.47,90)
  vias: v2(328.1,92.23) v2(328.11,91.63) v2(340.92,89.62)
UG_5V: length 1.1
  TOP w0.14: v4(339.18,85.74) v2(340.26,85.74)
  vias: v2(329.18,80.42) v2(329.18,79.78) v2(340.86,85.74)
UPD1_ALERT#: length 9.6
  TOP w0.076: 296.47,87.52 296.47,87.2 296.36,87.1 296.36,84.9 UE3.F10
  TOP w0.14: 296.47,87.52 296.47,88.31 296.7,88.54 v2(296.7,88.6) 296.7,88.82 296.58,88.93 295.11,88.93 RE99.1 295.54,89.69 v1(295.54,91.25)
  BOTTOM w0.081: v2(20.51,123.08) 20.88,122.71 UT4.B6
  vias: v2(14.66,115.97) v2(58.81,70.88) v2(314.85,89.61)
UPD_SMBCLK: length 36.2
  TOP w0.076: UE3.C3 293.24,78.57 293.24,76.61 292.96,76.33 292.96,76.22
  TOP w0.14: RE294.1 291.55,74.48 v2(291.55,75.14) 291.59,75.18 292.03,75.18 292.96,76.12 292.96,76.22
  BOTTOM w0.14: v2(276.8,87.25) 276.92,87.37 276.92,88.68 277.7,89.45 279.22,89.45 281.28,87.39 284.61,87.39 286.79,85.22 287.3,85.22 289.57,82.94 289.57,81.47 289.34,81.24 289.34,80.29 290.49,79.15 290.49,76.35 291.31,75.52 291.31,75.51 291.55,75.27 v2(291.55,75.14) ; v2(24.61,116.84) 24.61,117 24.3,117.32 23.7,117.32 23.29,117.72 23.29,118.09 22.17,119.21 21.77,119.21 21.64,119.34 RT201.1
  vias: v2(51.02,93.93) v2(119.81,106.47)
UPD_SMBCLK_R: length 2.8
  BOTTOM w0.081: 20.92,121.14 20.81,121.25 20.81,121.65 20.63,121.83 20.63,122.32 UT4.B5
  BOTTOM w0.14: 20.92,121.14 21.64,120.41 RT201.2
UPD_SMBDAT: length 36
  TOP w0.076: 292.7,76.34 292.7,76.36 293.03,76.69 293.03,78.66 293.1,78.73 293.1,79.28 UE3.B4
  TOP w0.14: 292.7,76.34 291.94,75.57 291.43,75.57 291.42,75.56 291.36,75.56 290.97,75.17 v2(290.97,75.14) 290.97,75.14 290.75,74.92 RE293.1
  BOTTOM w0.14: v2(24.03,116.85) 23.9,116.97 23.56,116.97 22.95,117.58 22.95,117.95 22.08,118.82 21.48,118.82 21.21,119.08 21.21,119.36 21.07,119.5 RT200.1 ; v2(290.97,75.14) 290.97,75.38 290.14,76.21 290.14,79.01 289,80.15 289,81.39 289.23,81.61 289.23,82.8 287.15,84.87 286.64,84.87 284.46,87.05 281.14,87.05 279.08,89.11 277.91,89.11 277.32,88.51 277.32,87.37 v2(277.44,87.25)
  vias: v2(51.6,93.93) v2(119.51,105.94)
UPD_SMBDAT_R: length 2
  BOTTOM w0.081: 20.6,121.14 20.6,121.54 20.38,121.76 UT4.A5
  BOTTOM w0.14: 20.6,121.14 20.6,121.08 21.07,120.61 RT200.2
USB2_COMP: length 4.4
  BOTTOM w0.089: 99.75,90.85 99,91.6 96.24,91.6 96.12,91.72 UH2.F4
  BOTTOM w0.14: 99.75,90.85 RH109.1
USB2_VBUSSENSE: length 3.7
  BOTTOM w0.089: UH2.F3 96.33,91.9 96.46,91.78 99.75,91.78
  BOTTOM w0.14: 99.75,91.78 99.92,91.78 RH580.1
USB3_PRX_C_RD_DTX_N1: length 2
  TOP w0.152: CI8.2 319.29,105.57 319.29,105.27 319.83,104.73 319.83,104.61 319.74,104.52 UI3.23
USB3_PRX_C_RD_DTX_P1: length 2
  TOP w0.152: UI3.22 320.24,104.51 320.16,104.59 320.16,104.87 319.62,105.41 319.62,105.57 CI7.2
USB3_PRX_DTX_N1: length 3.1
  TOP w0.152: v2(319.16,107.81) 319.32,107.65 319.32,107.2 CI8.1
  BOTTOM w0.089: v2(91.69,93.99) 91.69,93.98 91.69,93.69 91.56,93.56 91.56,92.4 91.68,92.29 UH2.D11
USB3_PRX_DTX_N2: length 12.9
  TOP w0.152: JUSB1.5 14.77,167.22 15.21,167.22 15.66,167.67 15.66,168.13 15.79,168.25 16.1,168.25 16.18,168.18 DI7.9 DI7.1 17.74,168.18 17.83,168.27 18.03,168.27 18.21,168.09 18.21,165.8 17.42,165.02 17.42,163.86 17.74,163.54 18.09,163.54 v2(18.24,163.39)
  BOTTOM w0.089: UH2.B9 92.8,93.17 92.85,93.11 92.93,93.11 93.02,93.2 93.02,93.45 92.8,93.67 92.8,94.39 92.92,94.51
  BOTTOM w0.152: 92.92,94.51 v2(92.98,94.57)
USB3_PRX_DTX_P1: length 2.9
  TOP w0.152: CI7.1 319.65,107.14 319.65,107.73 v2(319.76,107.85)
  BOTTOM w0.089: v2(92.16,93.69) 92.07,93.69 91.83,93.45 91.83,93.1 92.06,92.87 92.06,92.66 91.96,92.56 91.85,92.56 91.77,92.64 UH2.C11
USB3_PRX_DTX_P2: length 13
  TOP w0.152: v2(18.25,164.01) 18.11,163.87 17.88,163.87 17.75,164 17.75,164.88 18.54,165.66 18.54,168.22 18.16,168.6 17.74,168.6 17.66,168.68 DI7.2 DI7.8 16.16,168.68 16.07,168.59 15.65,168.59 15.33,168.26 15.33,167.8 15.07,167.55 14.79,167.55 JUSB1.6
  BOTTOM w0.089: 92.45,94.51 92.54,94.42 92.54,93.04 UH2.C9
  BOTTOM w0.152: v2(92.4,94.57) 92.4,94.56 92.45,94.51
USB3_PRX_L_DTX_N1: length 8.6
  TOP w0.152: RI40.2 319.74,97.75 319.74,97.21 v2(319.57,97.05) ; JUSB2.5 333.58,143.53 333.42,143.37 332.89,143.37 331.97,142.45 331.97,140.59 331.78,140.41 331.56,140.41 331.48,140.49 DI9.9 DI9.1 330.02,140.49 329.93,140.4 329.28,140.4 v2(329.12,140.57)
USB3_PRX_L_DTX_P1: length 8.7
  TOP w0.152: JUSB2.6 333.58,142.84 333.39,143.04 333.02,143.04 332.3,142.31 332.3,140.46 331.92,140.08 331.57,140.08 331.48,139.99 DI9.8 DI9.2 329.95,139.99 329.87,140.07 329.21,140.07 v2(329.12,139.99) ; v2(320.2,97.04) 320.07,97.17 320.07,97.63 RI39.2
USB3_PRX_RD_DTX_N1: length 1.5
  TOP w0.152: UI3.8 319.74,99.81 319.81,99.74 319.81,99.06 RI40.1
USB3_PRX_RD_DTX_P1: length 1.5
  TOP w0.152: UI3.9 320.24,99.83 320.14,99.73 320.14,99.02 RI39.1
USB3_PTX_C_DRX_N1: length 1.1
  TOP w0.14: CI16.2 321.93,97.59 321.93,97.24 RI37.1
USB3_PTX_C_DRX_N2: length 14.3
  TOP w0.152: JUSB1.8 14.8,173.25 15.13,173.25 15.39,172.98 15.39,170.11 15.75,169.75 16.07,169.75 16.14,169.68 DI7.7 DI7.4 17.88,169.68 17.97,169.77 18.32,169.77 18.59,170.04 18.59,171.02 17.96,171.66 17.96,173.23 v2(18.08,173.35)
  BOTTOM w0.152: v2(18.08,173.35) 17.95,173.23 17.95,172.94 18.08,172.81 18.3,172.81 18.58,173.09 19.33,173.09 CI9.2
USB3_PTX_C_DRX_P1: length 1.1
  TOP w0.14: RI38.1 322.25,97.3 322.25,97.66 CI20.2
USB3_PTX_C_DRX_P2: length 14.3
  TOP w0.152: JUSB1.9 14.76,173.58 15.27,173.58 15.72,173.12 15.72,170.25 15.89,170.08 16.03,170.08 16.13,170.18 DI7.6 DI7.5 17.88,170.18 17.97,170.1 18.18,170.1 18.26,170.18 18.26,170.88 17.63,171.52 17.63,173.22 v2(17.49,173.35)
  BOTTOM w0.152: CI10.2 19.33,172.76 18.72,172.76 18.44,172.48 17.94,172.48 17.62,172.8 17.62,173.23 v2(17.49,173.35)
USB3_PTX_C_RD_DRX_N1: length 1.9
  TOP w0.152: CI6.2 321.52,105.49 321.52,105.26 321.33,105.06 321.33,104.77 321.24,104.68 UI3.20
USB3_PTX_C_RD_DRX_P1: length 1.9
  TOP w0.152: UI3.19 321.74,104.65 321.66,104.74 321.66,104.92 321.85,105.12 321.85,105.51 CI5.2
USB3_PTX_DRX_N1: length 1.8
  TOP w0.152: CI6.1 321.51,107.23 321.51,107.72 v2(321.37,107.86)
  BOTTOM w0.089: UH2.F9 v2(93.04,90.8)
USB3_PTX_DRX_N2: length 2
  BOTTOM w0.089: UH2.C3 v2(96.08,92.4)
  BOTTOM w0.152: v2(21.51,173.2) 21.39,173.07 20.5,173.07 CI9.1
USB3_PTX_DRX_P1: length 1.9
  TOP w0.152: CI5.1 321.84,107.23 321.84,107.72 v2(321.99,107.87)
  BOTTOM w0.089: UH2.F7 93.52,91.5 93.52,91.18 v2(93.6,91.09)
USB3_PTX_DRX_P2: length 2.6
  BOTTOM w0.089: UH2.D4 95.31,92.58 95.17,92.44 95.17,92.16 95.26,92.07 v2(95.52,92.07)
  BOTTOM w0.152: CI10.1 20.19,172.67 20.26,172.74 21.39,172.74 v2(21.51,172.61)
USB3_PTX_L_DRX_N1: length 7.4
  TOP w0.152: RI37.2 321.95,95.92 321.95,95.26 v2(321.8,95.1) ; v2(329.13,138.75) 329.29,138.6 329.43,138.6 329.73,138.9 330.02,138.9 330.11,138.99 DI9.4 DI9.7 331.55,138.99 331.64,138.9 331.95,138.9 332.36,138.5 332.36,137.98 332.98,137.35 333.16,137.35 333.58,137.78 JUSB2.8
USB3_PTX_L_DRX_P1: length 7.4
  TOP w0.152: v2(322.44,95.14) 322.28,95.31 322.28,95.91 RI38.2 ; v2(329.13,138.12) 329.29,138.27 329.56,138.27 329.87,138.57 330.02,138.57 330.11,138.49 DI9.5 DI9.6 331.5,138.49 331.58,138.57 331.82,138.57 332.03,138.36 332.03,137.84 332.84,137.02 333.07,137.02 333.58,136.51 JUSB2.9
USB3_PTX_RD_DRX_N1: length 1.7
  TOP w0.152: CI16.1 321.82,99.03 321.82,99.25 321.24,99.82 UI3.11
USB3_PTX_RD_DRX_P1: length 1.7
  TOP w0.152: UI3.12 321.74,99.79 322.15,99.38 322.15,99.18 CI20.1
USB20_FP_N7_CONN: length 4.2
  BOTTOM w0.152: JFP.6 313.36,101.87 313.45,101.78 313.45,101.4 v5(313.98,100.88) 314.46,100.39 314.46,100.1 DI17.1 314.2,98.66 ML17.3
USB20_FP_P7_CONN: length 4.2
  BOTTOM w0.152: JFP.5 313.86,101.87 313.78,101.78 313.78,101.54 314.79,100.52 314.79,100.1 DI13.1 315.06,98.66 ML17.2
USB20_N1: length 3.3
  BOTTOM w0.089: v2(97.76,90.07) 97.56,90.07 97.47,90.17 96.09,90.17 95.79,89.87 UH2.J3
  BOTTOM w0.152: v2(327.91,128.54) 327.75,128.71 327.75,128.92 327.83,129.01 UI2.2
USB20_N2: length 2.2
  BOTTOM w0.089: v2(90.63,88.61) 90.46,88.45 90.46,88.27 UH2.N13
  BOTTOM w0.152: UI1.2 24.3,164.07 24.22,163.99 24.22,163.24 v2(24.38,163.09)
USB20_N4: length 2.8
  BOTTOM w0.089: v2(92.61,88.05) 92.3,88.37 UH2.M10
  BOTTOM w0.152: v2(326.17,146.65) 327.06,146.65 327.52,147.11 LN1.1
USB20_N4_R: length 2.2
  BOTTOM w0.152: LN1.2 327.52,149.33 327.43,149.42 327.43,149.82 327.23,150.02 327.23,150.28 327.32,150.37 JNGFF1.5
USB20_N5: length 4.8
  BOTTOM w0.089: UH2.M1 96.89,88.63 97.28,88.63 v2(97.71,88.19)
  BOTTOM w0.152: v2(18.48,132.29) 18.48,133.19 19.25,133.95 19.95,133.95 20.37,133.54 20.37,133.24 RT1143.1
USB20_N5_R: length 6.6
  BOTTOM w0.081: UT4.K5 20.63,126.82 20.63,127.28 20.49,127.41 20.49,128.32 20.57,128.39 20.57,128.42
  BOTTOM w0.152: RT1143.2 20.73,132.3 RT1142.2 20.56,131.91 20.37,131.72 20.37,129.5 20.57,129.31 20.57,128.42
USB20_N7: length 5.5
  BOTTOM w0.089: v2(98.44,88.87) 98.35,88.87 98.12,89.1 97.32,89.1 97.07,89.35 96.02,89.35 95.81,89.13 95.65,89.13 UH2.L4
  BOTTOM w0.152: v2(314.23,95.23) 314.48,95.48 314.48,96.18 314.2,96.46 ML17.4
  vias: v2(213.91,78.89)
USB20_N9: length 1.9
  BOTTOM w0.089: v2(93.77,87.66) 93.77,87.82 94.2,88.25 UH2.M6
  BOTTOM w0.152: v2(340.6,109.81) 340.91,109.81 341.1,110 LI1.4
USB20_N9_R: length 18.2
  BOTTOM w0.152: 345.11,111.42 345.33,111.64 345.33,115.32 346.12,116.11 346.38,116.11 v5(346.99,116.72) 347.86,117.6 347.86,119.52 347.24,120.15 346.95,120.15 346.55,120.55 346.55,121.6 346.95,122 347.33,122 347.57,122.24 JTS.4 ; 345.11,111.42 DI3.2 ; 345.11,111.42 345.34,111.19 345.34,110.92 344.34,109.92 343.38,109.92 343.31,110 LI1.3
USB20_N12: length 3.5
  BOTTOM w0.089: v2(98.32,90.92) 98.1,90.7 97.27,90.7 97.16,90.81 97.16,91.17 97.08,91.24 96.73,91.24 96.66,91.18 96.66,91.08 UH2.G1
  BOTTOM w0.152: LV22.1 56.16,91.88 56.06,91.78 56.06,91.42 v2(56.21,91.27)
USB20_N12_R: length 18.2
  BOTTOM w0.152: JEDP1.31 50.49,102.51 50.41,102.43 50.41,101.88 52.25,100.04 54.31,100.04 56.35,97.99 56.59,97.99 57.88,96.71 v5(57.88,96.28) 57.88,95.98 57.53,95.63 57.18,95.63 DV12.3 55.85,94.82 55.68,94.99 55.68,95.5 55.56,95.62 55.38,95.62 55.19,95.44 55.19,94.69 55.47,94.42 55.75,94.42 56.08,94.08 56.08,93.74 56.16,93.67 LV22.2
USB20_P1: length 2.9
  BOTTOM w0.089: v2(97.76,89.49) 97.36,89.9 96.2,89.9 96.12,89.82 UH2.J2
  BOTTOM w0.152: v2(327.33,128.54) 327.42,128.63 327.42,128.92 327.33,129.01 UI2.3
USB20_P2: length 2.2
  BOTTOM w0.089: v2(90.04,88.61) 90.05,88.61 90.19,88.47 90.19,88.29 UH2.N15
  BOTTOM w0.152: UI1.3 23.8,164.1 23.89,164.01 23.89,163.24 23.89,163.24 23.89,163.19 v2(23.79,163.09)
USB20_P4: length 2.6
  BOTTOM w0.089: v2(92.93,88.53) 92.78,88.53 92.68,88.63 92.68,88.85 92.84,89.01 UH2.L9
  BOTTOM w0.152: LN1.4 327.02,147.46 327.09,147.39 327.09,147.15 326.92,146.98 326.53,146.98 v2(326.17,147.34)
USB20_P4_R: length 2.2
  BOTTOM w0.152: LN1.3 327.02,149.34 327.1,149.42 327.1,149.68 326.9,149.88 326.9,150.31 326.82,150.39 JNGFF1.3
USB20_P5: length 3.9
  BOTTOM w0.089: UH2.L2 96.33,88.58 96.71,88.19 v2(97.08,88.19)
  BOTTOM w0.152: v2(19.1,132.31) 18.81,132.59 18.81,133.05 19.39,133.62 19.82,133.62 20.04,133.4 20.04,133.24 RT1144.1
USB20_P5_R: length 6.2
  BOTTOM w0.081: 20.24,128.42 20.24,128.39 20.31,128.32 20.31,127.39 20.15,127.23 20.15,127.11 20.19,127.07 UT4.L5
  BOTTOM w0.152: 20.24,128.42 20.24,129.17 20.04,129.37 v5(20.04,130.27) 20.04,131.74 19.88,131.91 RT1141.2 19.69,132.3 RT1144.2
USB20_P7: length 5.3
  BOTTOM w0.089: v2(98.44,88.28) 98.33,88.18 98.18,88.18 98.07,88.28 98.07,88.77 98.01,88.83 97.21,88.83 96.96,89.08 96.13,89.08 95.94,88.89 UH2.L3
  BOTTOM w0.152: ML17.1 315.05,96.46 314.81,96.21 314.81,95.48 v2(315.06,95.23)
  vias: v2(214.74,78.89)
USB20_P9: length 2.9
  BOTTOM w0.089: UH2.N8 93.41,87.95 93.41,87.51 93.62,87.29 93.97,87.29 v2(94.34,87.67)
  BOTTOM w0.152: v2(340.6,109.23) 340.64,109.23 340.91,109.5 LI1.1
USB20_P9_R: length 18.2
  BOTTOM w0.152: JTS.5 347.52,121.44 347.28,121.67 347.09,121.67 346.88,121.46 346.88,120.69 347.09,120.48 347.37,120.48 348.2,119.66 v5(348.2,118.01) 348.2,117.46 346.51,115.78 346.25,115.78 345.66,115.18 345.66,111.66 345.9,111.42 ; 345.9,111.42 345.67,111.19 345.67,110.79 344.48,109.59 343.32,109.59 343.22,109.5 LI1.2 ; 345.9,111.42 DI3.3
USB20_P12: length 3.4
  BOTTOM w0.089: v2(98.32,90.34) 98.22,90.44 97.16,90.44 96.96,90.63 96.65,90.63 96.42,90.86 UH2.G2
  BOTTOM w0.152: LV22.4 55.66,91.88 55.73,91.8 55.73,91.37 55.64,91.27 v2(55.63,91.27)
USB20_P12_R: length 18.2
  BOTTOM w0.152: LV22.3 55.66,93.65 55.75,93.74 55.75,93.95 55.61,94.09 55.33,94.09 54.86,94.56 54.86,95.57 55.25,95.95 55.25,96.49 55.52,96.77 56.06,96.77 56.11,96.72 DV12.1 57.11,95.96 57.4,95.96 57.55,96.12 57.55,96.57 56.46,97.66 56.22,97.66 v5(55.73,98.16) 54.95,98.93 54.17,99.71 52.11,99.71 50.08,101.74 50.08,102.41 49.99,102.49 JEDP1.32
USB8723_TEST: length 1.7
  TOP w0.14: UI3.14 323.18,101.48 323.68,100.98 RI24.1
USB_DET#_L: length 2.3
  TOP w0.14: v1(282.24,82.57) 282.5,82.31 v2(282.7,82.31) CE71.1 282.71,81.5 RE89.2
  vias: v2(35.36,93.24) v2(143.68,79.08)
USB_DET#_R: length 18.8
  TOP w0.14: v1(322.76,114.19) 324.36,114.19 QI10.2 326.39,114.32 330.25,114.32 333.53,117.59 v2(333.53,121.2) ; v2(289.69,69.97) 289.35,69.97 288.69,70.64 CE37.1 289.43,70.78 RE54.2
USB_DET_EC#_L: length 3.9
  TOP w0.14: v2(294.68,79.25) 295.09,79.66 UE3.E4 ; RE90.2 282.78,80.59 RE89.1 284.7,80.59 CE70.1 284.73,80.62 v2(286.08,80.62)
USB_DET_EC#_R: length 12.7
  TOP w0.14: v2(293.92,79.26) UE3.D4 ; v2(291.21,72.43) 291.21,72.33 290.53,71.65 CE38.1 RE54.1 289.47,71.63 RE50.2 288.74,71.93 288.98,72.17 v1(288.98,72.75)
  BOTTOM w0.14: v2(293.92,79.26) 293.48,78.82 293.48,76.29 293.56,76.22 293.56,74.81 291.21,72.46 v2(291.21,72.43)
USB_ILIM_SEL: length 6
  TOP w0.076: UE3.M10 300.68,84.46 v2(300.33,84.11)
  TOP w0.14: v2(324.22,107.44) v1(323.6,107.44)
  BOTTOM w0.14: RI35.1 325.57,109.42 DI12.1 325.59,107.44 v2(324.22,107.44)
  vias: v2(323.27,99.33)
USB_L_CTL: length 5.6
  BOTTOM w0.14: 22.06,166.76 21.92,166.62 21.92,166.36 22.02,166.26 UI1.7 ; 22.06,166.76 21.09,166.76 RI4.2 20.5,166.97 20.24,166.72 20.24,166.13 19.56,165.44 v1(19.56,164.98) ; 22.06,166.76 UI1.8
USB_OC0#: length 11.2
  TOP w0.089: RH552.1 79.55,81.01 v1(79.55,80.28) v2(79.18,79.91)
  BOTTOM w0.089: v2(79.18,79.91) 79.45,80.18 UH2.AH36
  BOTTOM w0.14: v2(336.65,130.14) 331.17,130.14 330.76,130.55 330.76,131.53 330.32,131.97 329.97,131.97 329.7,131.71 UI2.13
USB_OC1#: length 11
  TOP w0.089: v2(77.93,79.9) 77.77,80.06 76.52,80.06 76.32,80.26 75.08,80.26 RH553.1
  TOP w0.14: v2(22.91,169.94) v1(22.91,170.54)
  BOTTOM w0.089: v2(77.93,79.9) 77.83,79.81 UH2.AL40
  BOTTOM w0.14: v2(22.91,169.94) 24.05,169.94 24.82,169.18 25.2,169.18 25.44,168.94 25.95,168.94 26.44,168.45 26.44,167.32 25.88,166.76 UI1.13
USB_OC2#: length 3.8
  TOP w0.089: v1(73.86,82.31) 74.35,81.83 RH554.1 74.47,81.43 74.85,81.04 75.6,81.04 v2(75.98,80.66)
  BOTTOM w0.089: v2(75.98,80.66) 75.98,80.6 75.68,80.31 75.68,80.07 UH2.AJ44
USB_OC3#: length 3.4
  TOP w0.089: v2(77.39,79.63) 77.15,79.88 75.88,79.88 75.81,79.81 v1(75.67,79.81) 74.82,79.81 RH555.1
  BOTTOM w0.089: v2(77.39,79.63) 77.39,79.65 77.1,79.35 UH2.AL41
USB_OC4#: length 5.2
  TOP w0.089: v1(71.74,82.24) 71.64,82.14 v2(70.46,82.14) 70.46,81.96 70.18,81.68 70.07,81.68
  TOP w0.14: RP8.3 69.45,81.93 69.7,81.68 70.07,81.68
  BOTTOM w0.089: UH2.AV47 74.34,75.89 74.02,75.89 73.51,75.89 73.32,76.08 72.93,76.08
  BOTTOM w0.14: 72.93,76.08 72.5,76.51 v2(72.5,76.52)
USB_OC5#: length 2.4
  TOP w0.089: 70.07,82.32 70.07,82.36 70.09,82.39 70.1,82.39 v1(70.6,82.89)
  TOP w0.14: RP8.4 69.59,82.43 v2(69.88,82.14) 70.07,82.32
  BOTTOM w0.089: v2(80.14,77.66) 80.09,77.62 UH2.AR35
USB_OC6#: length 4.3
  TOP w0.14: v2(71.36,81.11) 71.04,81.43 v1(70.7,81.43) RP8.2
  BOTTOM w0.089: v2(79.17,78.8) 79.23,78.8 79.65,78.38 79.65,77.47 UH2.AR37
USB_OC7#: length 4.1
  TOP w0.089: v2(72.08,80.2) v1(71.71,80.57) 71.64,80.64 71.04,80.64 70.75,80.93 70.68,80.93
  TOP w0.14: RP8.1 70.68,80.93
  BOTTOM w0.089: v2(75.72,76.35) 76.24,75.83 UH2.AV43
USB_POWERSHARE_EN_L#: length 3.1
  TOP w0.14: v2(146.86,78.43) v1(146.86,79.05) ; v2(298.72,78.46) UE3.J3
  BOTTOM w0.14: RI5.2 21.61,165.8 v2(21.65,165.8) 21.69,165.76 UI1.6
  vias: v2(20.69,95.77)
USB_POWERSHARE_EN_R#: length 12
  TOP w0.076: UE3.K3 v2(299.52,78.46)
  BOTTOM w0.14: v2(331.08,124.22) 327.65,124.22 327.33,124.54 327.33,126.79 RI10.2 v1(325.82,128.3) 325.3,128.82 325.3,130.45 325.56,130.71 UI2.6
USB_POWERSHARE_VBUS_EN_L: length 3.4
  TOP w0.14: v1(147.8,77.5) 148.03,77.73 v2(148.03,78.35) ; v2(298.71,77.63) 298.32,78.01 UE3.J2
  BOTTOM w0.14: v2(22.02,170.53) RI8.2 20.7,170.53 20.62,170.45 UI4.2
  vias: v2(39.48,91.98) v2(76.3,92.06)
USB_POWERSHARE_VBUS_EN_R: length 12.8
  TOP w0.076: UE3.G5 v2(297.12,80.06)
  TOP w0.14: v2(329.5,114.88) 328.93,114.88 328.27,115.54 327.91,115.54 327.39,115.02 325.42,115.02 324.44,116 324.44,116.26 ; 324.44,116.26 RI13.2 324.44,117.72 RI28.1 ; 324.44,116.26 323.52,115.33 322.76,115.33 322.48,115.62 v1(322.48,115.72) UI5.2
USB_PWR_EN: length 42.3
  TOP w0.089: v3(85.33,69.23) 85.6,68.97 88.75,68.97 88.95,69.17 88.95,70.32 89.18,70.54 89.18,73.09 88.71,73.56 88.71,73.78 v3(88.75,73.82)
  TOP w0.14: v2(64.61,72.16) 64.61,71.89 65.16,71.34 RH544.1 ; v2(321.96,113.78) 321.96,116.83 321.83,116.97 UI5.1
  BOTTOM w0.089: UH2.BD17 89.07,72.82 89.07,73.37 88.75,73.69 v3(88.75,73.82)
  BOTTOM w0.14: v2(275.4,72.69) 275.39,72.7 275.39,78.38 276.02,79.01 276.02,85.49 272.03,89.48 272.03,90.7 272.65,91.32 273.86,91.32 v2(275.89,93.35) ; v1(22.02,171.72) v2(22.02,171.11) 22.01,171.1 UI4.1
  vias: v2(22.16,96.14) v2(78.16,70.15)
USB_PWR_EN_L: length 6.7
  TOP w0.14: v1(22.78,165.78) 22.03,165.02 v2(21.66,165.02)
  BOTTOM w0.14: UI1.5 21.89,165.26 v2(21.66,165.02) ; RI26.1 18.08,170.02 UI4.4 18.65,169.46 18.65,168.87 17.42,167.65 v2(17.42,167.34)
USB_PWR_EN_R: length 17.9
  TOP w0.14: RI28.2 324.23,118.7 323.46,118.7 323.13,119.03 UI5.4 323.13,120.45 RI27.1 323.64,120.68 323.85,120.88 323.85,122.87 v1(326.09,125.1) 327.53,125.1 v2(327.96,124.67)
  BOTTOM w0.14: UI2.5 325.72,130.21 325.6,130.08 325.6,129.13 326.91,127.82 327.12,127.82 327.65,127.28 327.65,124.99 v2(327.96,124.67)
USB_R_CTL: length 6.3
  BOTTOM w0.14: UI2.8 325.48,131.71 325.3,131.53 325.3,131.21 ; 325.3,131.21 UI2.7 ; 325.3,131.21 324.92,130.82 v1(324.92,129.66) 324.92,128.36 RI9.2
USB_STATUS#_L: length 5.9
  TOP w0.14: v2(321.23,112.79) v1(321.77,112.79)
  BOTTOM w0.14: RI32.2 324.76,113.25 324.31,112.79 v2(321.23,112.79) ; UI1.9 v2(22.82,167.56)
  vias: v2(60.5,89.47)
USB_STATUS#_R: length 11.8
  TOP w0.14: v2(324.47,130.17) v1(324,129.7)
  BOTTOM w0.14: v2(324.47,130.17) 324.47,131.08 325.44,132.05 326.68,132.05 326.83,132.2 UI2.9 ; v2(321.27,116.32) 322.16,115.43 325.06,115.43 326.82,113.66 RI33.2
USBC_MCP23008_SMBCLK: length 44.2
  TOP w0.14: v2(86.87,98.91) 86.66,99.12 86.66,99.56 83.02,103.21 81.14,103.21 80.63,102.69 80.19,102.69 RE109.2 ; v2(273.05,81.58) 272.88,81.75 272.88,84.2 276.39,87.7 280.96,87.7 284.02,90.77 288.46,90.77 291.1,93.41 291.93,93.41 293.57,91.77 293.57,90.52 293.17,90.11 RE21.1 293.17,89.34 293.87,88.64 v2(293.87,88.24) ; UE3.A12 291.92,86.25 290.65,87.52 289.94,87.52 v2(289.65,87.8)
USBC_MCP23008_SMBDAT: length 39.7
  TOP w0.076: UE3.N10 302.06,84.46
  TOP w0.14: v2(86.13,98.91) 86.27,99.05 86.27,99.4 82.86,102.81 81.3,102.81 80.79,102.3 80.19,102.3 RE108.2 ; v2(302.18,84.54) 302.11,84.46 302.06,84.46 ; v2(294.02,90.72) 294.02,92.25 RE20.1 293.42,92.47 292.09,93.8 290.94,93.8 288.29,91.16 283.86,91.16 280.79,88.09 276.22,88.09 272.49,84.36 272.49,81.73 v2(272.33,81.58)
VCORE_B+: length 7.6
  TOP w0.381: PR1154.1 116.13,181.76 116.51,182.14 120.95,182.14 122.22,180.87
  vias: v2(121.97,178.4) v2(121.97,177.82) v2(122.56,180.15) v2(122.56,179.57) v2(122.56,178.99) v2(122.56,178.4) v2(122.56,177.82) v2(123.14,180.15) v2(123.14,179.57) v2(123.14,178.99) v2(123.14,178.4) v2(123.14,177.82) v2(123.72,178.4) v2(123.72,177.82) v2(124.31,178.4) v2(124.31,177.82) v2(124.89,178.4) v2(124.89,177.82) v2(125.48,178.4) v2(125.48,177.82) v2(126.06,178.4) v2(126.06,177.82) v2(126.64,178.4) v2(126.64,177.82) v2(126.97,180.15) v2(126.97,179.57) v2(126.97,178.99) v2(127.23,178.4) v2(127.23,177.82) v2(127.69,178.96) v2(127.81,178.38) v2(127.81,177.79) v2(132.64,183.91) v2(132.64,183.28) v2(133.27,183.91) v2(133.27,183.28) v2(134.92,185.06) v2(135.56,185.06) v2(136.19,185.06) v2(136.83,185.06) v2(141.78,183.91) v2(141.78,183.28) v2(142.42,183.91) v2(142.42,183.28) v2(143.43,184.93) v2(144.07,184.93) v2(144.7,184.93) v2(145.34,184.93) v2(149.78,183.66) v2(150.42,183.66) v2(151.05,183.66) v2(151.82,183.66) v2(152.2,185.31) v2(152.32,185.95) v2(152.83,185.31) v2(152.83,184.68) v2(157.15,183.66) v2(157.78,183.66) v2(158.42,183.66) v2(159.05,183.66) v2(159.44,184.68) v2(159.82,185.31) v2(160.07,184.68) v2(160.71,184.68) v4(125.16,179.46)
VGA_EDID_CLK: length 4.1
  BOTTOM w0.102: 207.95,124.73 207.95,124.76 207.93,124.78 207.93,125.03 207.82,125.14 207.82,125.48 208.2,125.87 UV18.R2
  BOTTOM w0.14: 207.95,124.73 207.95,124.43 206.85,123.33 206.85,122.94 RV572.1
VGA_EDID_DATA: length 5.1
  BOTTOM w0.102: 207.56,124.73 207.56,124.76 207.58,124.78 207.58,124.88 207.46,124.99 207.46,125.63 207.79,125.96 207.79,126.48 UV18.R3
  BOTTOM w0.14: RV573.1 206.45,122.99 206.45,123.49 207.56,124.59 207.56,124.73
VGA_IDENTIFY: length 1.9
  TOP w0.14: RE112.1 v2(309.42,85.49) 309.42,85.58 v1(309.07,85.93) ; UE3.L9 299.94,83.66 v2(300.34,83.27)
VID0_VCCIO: length 4.4
  BOTTOM w0.254: PR808.1 109.47,132.73 PR806.2 109.02,132.28 109.02,130.7 108.25,129.93 PU800.4
VID1_VCCIO: length 2.6
  BOTTOM w0.254: PU800.3 108.17,130.44 108.46,130.73 PR807.1 108.46,132.61 PR805.2
VR_ON: length 19.7
  TOP w0.14: UZ12.4 113.53,118.06 112.87,117.4 RZ71.1 112.76,117.35 RZ60.2 113.83,116.59 114.18,116.24 v1(115.1,116.24) 115.53,116.24 115.97,115.8 117.55,115.8 117.95,116.2 v2(118.34,116.2) ; PR1125.2 109.78,169.36 109.66,169.24 v2(109.66,168.93)
  BOTTOM w0.14: v2(118.34,116.2) 118.29,116.25 118.29,119.96 119.18,120.85 119.18,123.21 118.16,124.22 RZ1955.1
  vias: v2(127.3,113.73)
VR_SVID_ALERT#: length 4
  TOP w0.127: v2(107.75,169.44) 108,169.69 PR1118.2
  TOP w0.14: v2(107.75,169.44) PR1106.2 ; v1(134.3,168.01) 134.24,167.95 RH152.2 v2(134.92,167.02) 134.98,166.97 RH153.1
VR_SVID_ALERT#_R: length 2.6
  TOP w0.14: v2(135.94,165.31) 135.89,165.36 RH153.2 135.89,166.91 v1(135.55,167.25)
  BOTTOM w0.076: UH1.BH31 139.85,149.33 v2(139.78,149.33)
VR_SVID_CLK: length 2.1
  TOP w0.14: PR1116.2 109.02,169.99 v2(109.02,169.44) 109.02,169.13 PR1107.2
  BOTTOM w0.076: v2(139.78,149.98) 140.1,149.65 UH1.BH32
  vias: v2(136.52,165.32)
VR_SVID_DATA: length 5.3
  TOP w0.089: v2(140.64,146.7) 140.64,147.33 v1(140.77,147.45)
  TOP w0.14: PR1105.1 106.48,169 v2(106.48,169.44) 107.11,170.07 PR1120.2 ; RH151.2 134.24,165.93 134.88,165.29 v2(135.36,165.29)
  BOTTOM w0.076: v2(140.64,146.7) 140.64,147.18 140.3,147.53 UH1.BH29
VRALERT#: length 4.8
  BOTTOM w0.089: UH2.BE32 81.62,72.32 81.39,72.08 81.39,70.94 80.85,70.4 80.85,69.69 80.02,68.86 80.02,68.6
  BOTTOM w0.14: 80.02,68.6 RH5837.2
VREF_NVVDD: length 2.5
  BOTTOM w0.203: PU1001.8 165.89,184.5 166.55,185.16 PC1005.1
  BOTTOM w0.508: PC1005.1 PR1005.1
VREF_NVVDDS: length 3
  BOTTOM w0.203: PU1501.8 v1(184.02,182.98) 183.95,182.98 183.5,183.44 PC1501.1
  BOTTOM w0.254: PC1501.1 PR1505.1
VSET_5085: length 3.1
  TOP w0.14: v1(287.12,87.46) 286.74,87.84 v2(286.74,87.98) 286.08,87.98 CE41.1 286,87.46 286.13,87.33 RE58.1 ; v2(293.12,84.06) UE3.C9
VSN_1PH: length 8.1
  TOP w0.14: PC1100.2 v1(115.29,166.43)
  TOP w0.203: PU1100.51 112.41,172.42 112.64,172.19 113.5,172.19 113.98,171.71 113.98,171.23 114.78,170.43 114.78,168.93 PR1109.2 PC1100.2
VSN_2PH: length 3.8
  TOP w0.203: v2(106.35,174.01) 106.58,174.01 106.89,174.31 PU1100.37
  BOTTOM w0.14: PR1131.1 PC1114.1 105.97,173.63 v2(106.35,174.01) v1(106.91,174.01)
VSN_4PH: length 5
  TOP w0.203: PU1100.2 113.94,173.91 114.02,173.83
  TOP w0.254: 114.02,173.83 v2(114.64,173.21) 114.99,172.87 PC1112.2 PR1127.2
  BOTTOM w0.14: v2(114.64,173.21) 115.86,173.21 v1(116.23,172.84)
VSP_1PH: length 5
  TOP w0.203: PR1111.2 PC1108.2 115.29,170.48 v1(114.45,171.32) 114.35,171.42 114.35,171.98 113.8,172.53 113.02,172.53 112.81,172.73 PU1100.52
VSP_2PH: length 3.7
  TOP w0.203: v2(106.48,173.37) 106.48,173.44 106.95,173.91 PU1100.38
  BOTTOM w0.14: v2(106.48,173.37) 106.48,172.97 v1(106.25,172.74) PC1113.1 PR1130.1
VSP_4PH: length 5.4
  TOP w0.203: PU1100.1 113.82,173.51 114,173.33 114,173.13 v1(114.51,172.62) 114.73,172.4 114.73,171.6 115.19,171.14 PC1111.2 117.27,171.14 PR1124.2
WLAN_PWR_EN: length 8.7
  TOP w0.254: v2(337.27,169.77) 337.11,169.93 RN33.2 337.05,170.32 336.54,170.32 336.31,170.55 UN3.3
  BOTTOM w0.14: DN3.1 333.68,110.62 333.75,110.69 333.75,112.65 RZ1142.2 332.79,113.18 332.16,112.54 RZ1141.2 331.98,113.21 v2(332.09,113.33) 331.84,113.58 v1(331.44,113.58)
WLAN_WIGIG60GHZ_DIS#: length 5.2
  TOP w0.14: UE3.L13 299.92,87.42 300.29,87.79 300.29,88.07 300.67,88.45 301.57,88.45 301.58,88.47 301.66,88.47 v2(301.67,88.48) 301.67,88.56 301.68,88.56 301.68,88.97 RE71.2 ; v2(325.23,148.89) v1(324.54,148.89)
  BOTTOM w0.14: DN1.1 325.15,148.8 v2(325.23,148.89)
WLAN_WIGIG60GHZ_DIS#_R: length 5
  TOP w0.14: v1(325.64,150.17) v2(326.12,149.69)
  BOTTOM w0.14: DN1.2 326.02,149.59 v2(326.12,149.69) ; JNGFF1.48 340.07,157.14 339.29,156.37 v2(338.55,156.37)
XCLK_BIASREF: length 4.5
  BOTTOM w0.305: UH2.T3 95.83,86.55 96.05,86.33 96.39,86.33 96.62,86.1 96.95,86.1
  BOTTOM w0.381: RH71.2 98.93,84.85 98.22,85.57 98.22,85.97 97.97,86.23 97.33,86.23 97.2,86.1 96.95,86.1
XDP_BPM#0: length 6.3
  TOP w0.14: JXDP.21 124.84,157.7 124.49,157.35 124.49,156.46 v2(124.38,156.36)
  BOTTOM w0.076: UH1.BR27 135.59,145.7 135.11,145.7 135.08,145.74 133.13,145.74 v2(132.61,145.22)
XDP_BPM#1: length 7.2
  TOP w0.14: v2(123.77,156.36) 124.14,156.72 124.14,157.49 124.86,158.2 JXDP.23
  BOTTOM w0.076: UH1.BT27 135.14,145.9 132.38,145.9
  BOTTOM w0.14: 132.38,145.9 132.22,145.9 131.92,145.61 v2(131.92,145.21)
XDP_DBRESET#: length 6.3
  TOP w0.14: JXDP.48 122.13,164.2 122.42,163.91 v2(122.73,163.91)
  BOTTOM w0.14: CH175.1 122.73,164.53 v2(122.73,163.91) 122.73,163.27 RH8.1 122.78,163.19 122.35,162.76 122.35,162.58 122.05,162.27 v1(121.97,162.27) RH5.2
XDP_PLTRST#: length 7.6
  TOP w0.14: v1(116.23,159.7) 116.04,159.89 RH480.2 RH479.2 RH492.2 116.52,163.07 118.08,163.07 118.45,163.44 118.92,163.44 119.19,163.7 JXDP.46
XDP_PRDY#: length 10.1
  TOP w0.089: v2(133.81,145.19) 133.81,145.4 v4(134.09,145.67)
  TOP w0.14: JXDP.5 124.41,153.7 124.27,153.56 124.27,152.16 124.4,152.03 126.31,152.03 v2(126.48,152.2)
  BOTTOM w0.076: v2(133.81,145.19) 134.04,145.42 135.06,145.42 135.11,145.47 136.01,145.47 UH1.BP27
  BOTTOM w0.089: v2(94.12,79.33) 94.66,78.79 UH2.AM5
  vias: v2(110.58,85)
XDP_PREQ#: length 18.9
  TOP w0.089: v4(133.96,147.59) 134.12,147.75 v2(134.54,147.75)
  TOP w0.14: v2(128.98,153.8) 128.4,153.8 127.8,153.2 JXDP.3
  BOTTOM w0.076: 132.38,147.51 134.3,147.51 v2(134.54,147.75) 134.63,147.84 138.08,147.84 UH1.BL30
  BOTTOM w0.089: UH2.AL2 96.3,79.1 97.21,79.1 97.37,79.26 97.83,79.26 98.21,79.64 v2(98.21,79.65)
  BOTTOM w0.14: 132.38,147.51 129.92,147.51 128.86,146.45 RH156.2
  vias: v2(113.05,85)
XDP_PWRGOOD: length 7.8
  TOP w0.14: RH481.2 CD3328.1 v1(129.34,157.9) ; RH481.2 RH482.2 ; RH481.2 127.75,159.5 127.75,160.49 127.29,160.95 127.29,161.88 126.96,162.2 JXDP.39
XDP_TDI: length 27.6
  TOP w0.14: v2(118.75,165.89) 118.85,165.89 119.15,166.2 JXDP.56 122.16,166.2 123.88,167.91 125.02,167.91 125.53,168.42 125.53,169.82 126.29,170.58 128.83,170.58 v1(129.15,170.26) 130.61,168.8 131.88,168.8 132.64,168.04 132.64,165.37 132.89,165.12 133.65,165.12 v2(133.91,165.37)
  BOTTOM w0.14: RH541.1 133.48,164.94 v2(133.91,165.37) ; v2(118.75,165.89) 118.75,164.86 118.04,164.16 118.04,163.71 117.61,163.28 116.76,163.28 RH477.1
XDP_TDO: length 6.4
  TOP w0.14: v4(129.98,165.08) 130.17,165.26 130.17,165.54 130.27,165.64 v2(130.5,165.64) ; v2(118.74,163.86) 118.74,164.79 119.16,165.2 JXDP.52
  BOTTOM w0.14: RH478.1 118.74,163.43 v2(118.74,163.86) ; RH540.1 130.29,164.94 130.17,165.07 130.17,165.54 130.27,165.64 v2(130.5,165.64)
XDP_TMS: length 10.9
  TOP w0.14: v2(118.78,166.49) 118.99,166.7 JXDP.58 ; v1(130.86,160.51) 129.92,160.51 129.44,160.98 129.44,161.17 v2(129.1,161.52)
  BOTTOM w0.14: v2(129.1,161.52) 128.32,162.3 RH542.1 ; v2(118.78,166.49) 119.17,166.1 119.17,164.95 118.3,164.08 118.3,163.62 117.72,163.04 117.41,163.04 RH12.1
XDP_TRST#: length 5.5
  TOP w0.14: JXDP.54 119.16,165.7 118.43,164.97 118.43,164.38 118.29,164.23 118.29,163.77 v1(118,163.48) 117.62,163.48 v2(117.36,163.74)
  BOTTOM w0.14: RH543.1 126.16,149.38 125.77,149.38 v2(125.77,149.38)
XTAL24_IN: length 11.7
  TOP w0.089: RA96.2 98.06,85.58 98.06,85.75 97.75,86.05 97.53,86.05 97.36,86.23 96.61,86.23 v1(96.56,86.18) 94.83,84.45 92.63,84.45 92.14,84.93 v2(92.14,86.74)
  BOTTOM w0.089: UH2.U10 92.14,85.9 v2(92.14,86.74)
XTAL24_IN_R: length 4.2
  TOP w0.14: RA96.1 RH72.1 100.89,83.97 CH47.1 101.29,83.97 101.55,84.07 101.74,84.27 101.93,84.35 102.85,84.35 103.34,83.85 YH2.1
XTAL24_OUT: length 10.8
  TOP w0.089: RA97.2 99.29,85.53 v1(98.86,85.96) 98.59,86.23 97.61,86.23 97.36,86.48 96.38,86.48 94.65,84.74 92.76,84.74 92.53,84.97 92.53,86.25 92.67,86.39 v2(92.67,86.54)
  BOTTOM w0.089: v2(92.67,86.54) 92.67,86.35 UH2.U9
XTAL24_OUT_R: length 2.9
  TOP w0.14: YH2.3 101.63,85.05 101.53,84.95 101.53,84.8 101.29,84.56 CH48.1 101.05,84.56 100.69,84.93 RH72.2 100.36,85.08 100.02,85.08 RA97.1
XTAL_25_IN: length 1.7
  BOTTOM w0.152: YT1.1 19.36,99.46 19.55,99.27 19.64,99.27 19.84,99.08 CT43.1 20.45,99.08 RA98.2
XTAL_25_IN_R: length 2.5
  BOTTOM w0.102: UT1.D22 20.89,101.76 20.89,100.71 20.5,100.32 RA98.1
XTAL_25_OUT: length 3.1
  BOTTOM w0.152: YT1.3 18.38,98.56 18.38,98.61 18.5,98.74 19.42,98.74 19.72,98.44 CT44.1 20.5,98.44
XTAL_25_OUT_R: length 4.1
  BOTTOM w0.089: UT1.D23 21.12,100.22
  BOTTOM w0.152: RA99.1 20.8,97.86 21.03,98.09 21.03,100.14 21.12,100.22
XTAL_OUT: length 12
  TOP w0.14: YV1.3 215.45,115.98 215.56,116.09 215.56,117.85 215.49,117.91 215.49,118.24 CV858.1 215.32,118.6 215.32,119.07 RV1833.2 215.34,119.49 215.34,119.82 v2(215,120.16)
  BOTTOM w0.14: UV18.H2 214,125.84 214.41,125.43 v5(214.41,123.12) 214.41,122.71 215.32,121.81 215.32,120.48 v2(215,120.16)
XTALIN: length 11.2
  TOP w0.14: v2(215.95,120.29) 215.67,120 215.67,119.63 RV1833.1 215.82,119.07 215.82,118.6 CV857.1 215.82,118.42 215.82,118.05 216.21,117.67 YV1.1
  BOTTOM w0.14: v2(215.95,120.29) 215.65,120.59 v5(215.65,121.33) 215.65,121.95 214.74,122.85 214.74,125.62 214.36,126 214.36,126.53 UV18.H3
XTALOUT: length 14.6
  TOP w0.14: RV581.1 217.88,117.8 217.88,118.46 217.48,118.86 217.48,120.38 216.39,121.47 214.68,121.47 v1(213.92,122.24) 212.69,123.47 212.69,125.2 212.27,125.62 212.27,126.78 v2(212.78,127.28)
  BOTTOM w0.102: v2(212.78,127.28) 213.18,127.69 UV18.J4
XTALSSIN: length 8.7
  TOP w0.14: RV579.1 218.48,119.6 218.48,121.38 v1(218.03,121.82) 216.58,123.28 214.99,123.28 v2(213.89,124.38)
  BOTTOM w0.102: v2(213.89,124.38) 214,124.5 UV18.H1
N01897: length 4.2
  TOP w0.14: 104.34,132.15 v4(104.34,131.54)
  BOTTOM w0.381: PU800.1 105.98,130.82 105.71,131.08 105.33,131.08 104.88,131.54 PC800.1
  BOTTOM w0.508: PC802.1 104.38,132.34 PC800.1
  vias: v2(103.68,133.43) v2(103.68,132.85) v2(103.68,132.26)
N02057: length 3.3
  BOTTOM w0.254: PC810.1 103.72,129.35 104.14,128.93 PU800.10
  BOTTOM w0.381: PC810.1 PR809.1 PR819.2
N02113: length 3.4
  TOP w0.14: v1(105.46,127.79) 105,128.25 PR839.1
  TOP w0.254: v2(104.32,129.56) PR841.1 PR839.1
  BOTTOM w0.254: v2(104.32,129.56) 104.44,129.44 PU800.11
N02121: length 2.1
  BOTTOM w0.254: PU800.6 108.56,128.93 108.88,129.25 PR802.2 PR818.2
N02167: length 1
  TOP w0.14: v2(104.32,128.01) v1(104.32,127.01)
N02175: length 1.1
  BOTTOM w0.508: PR800.2 101.97,127.03 PC804.1
N02213: length 0.9
  TOP w0.14: v2(106.12,125.27) 106.12,124.59 v4(105.99,124.47)
  vias: v2(106.71,125.27)
N02305: length 3.5
  TOP w0.14: v1(102.57,129.8) 102.91,130.14 PR840.1
  TOP w0.254: PR838.1 v2(104.32,130.32) 104.14,130.14 PR840.1
  BOTTOM w0.254: v2(104.32,130.32) 104.7,129.93 PU800.12
N04748: length 5.4
  TOP w0.203: PU1900.3 v1(43.27,82.4)
  TOP w0.254: v1(43.27,82.4) 42.75,82.92 41.55,82.92 41.11,82.48 PR1922.1 40.95,82.32 40.18,81.55 PC1935.1
N16357: length 5.2
  BOTTOM w0.14: CA20.1 0.59,110.07 0.59,110.12 -0.13,110.84 v1(-0.13,110.97)
  BOTTOM w0.203: CA20.1 1.4,109.26 3.02,109.26 3.31,109.56 3.6,109.56 3.8,109.35 UA1.29
N16361: length 2.4
  BOTTOM w0.152: UA1.31 4.6,109.48 4.39,109.69 4.39,110.16 v1(4.34,110.21) 4.2,110.34 3.58,110.34 CA21.1
N16389: length 1.5
  BOTTOM w0.203: CA15.1 1.61,107.1 2.14,107.1 2.32,106.92 UA1.25
N16393: length 1.6
  BOTTOM w0.203: UA1.27 2.4,107.72 1.83,108.29 CA18.1
N35186: length 1.7
  TOP w0.14: DA14.1 10.07,110.85 9.68,110.46 RA29.1
N35194: length 2.6
  TOP w0.14: v1(13.06,110.98) 12.64,110.98 12.52,110.85 DA7.1 11.93,111.35 11.77,111.5 11.67,111.5 11.62,111.56 RA28.1
N3514407: length 3
  TOP w0.203: PR405.2 v1(344.73,89.74) 344.27,89.29 344.27,88.51 344.06,88.3 PU400.5
N3514423: length 4.9
  TOP w0.203: 344.61,87.75 344.36,87.5 PU400.3
  TOP w0.254: 344.61,87.75 345.36,87.75 PC400.1 345.67,88.11 345.07,88.7 v2(345.07,88.8)
  BOTTOM w0.14: v2(345.07,88.8) 345.07,88.47 v1(345.41,88.13)
  BOTTOM w0.254: PR400.2 345.44,89.17 v2(345.07,88.8)
N3514453: length 2.4
  TOP w0.203: PC419.1 339.2,87.65 v1(339.6,87.65) 339.85,87.65 340,87.5 PU400.13
N16399093: length 1.6
  TOP w0.14: PD1902.1 57.55,83.77 v1(57.85,84.07)
N16404606: length 6.5
  TOP w0.14: PR1937.2 62.08,75.61 PD1903.3 60.91,77.12 58.98,79.05 v1(58.98,79.27) PR1936.1
N16404788: length 4.5
  TOP w0.14: PR1943.2 60.26,78.42 PD1903.1 60.04,78.9 PU1901.1
N17034077: length 2.9
  TOP w0.203: PR406.1 345.14,85.24 v1(344.82,85.55) 344.25,86.13 344.25,86.51 344.06,86.7 PU400.1
N17509431: length 4.3
  TOP w0.14: PR1927.2 43.69,85.65 v1(43.5,85.46)
  TOP w0.254: PR1927.2 44.69,85.91 PR1933.1 PR1932.1 PC1940.1
N17509921: length 1.2
  TOP w0.14: PD1903.2 59.61,76.23 59.92,75.93 PR1939.2
N17522701: length 1.4
  TOP w0.14: PR1941.2 60.69,79.57 PU1901.2
N17670003: length 7.3
  TOP w0.203: PR1934.1 42.15,86.2 v1(42.32,86.04) 42.32,85.79 43.04,85.07 45.62,85.07 46.08,84.61 PU1900.30
  TOP w0.254: PR1934.1 41.38,87.19 PR1929.1
N17765266: length 3.5
  TOP w0.203: PU1900.26 47.68,84.32 47.84,84.49 v1(47.84,85.18) 47.84,85.88 48.12,86.16 PR1928.2 PR1926.2
N18278782: length 2.7
  TOP w0.14: v1(40.47,75.23) 40.64,75.39 PC1913.1
  TOP w0.508: PR1905.1 PC1913.1
N18278998: length 3.6
  TOP w0.203: PR1917.2 51.61,83.97 51.21,83.56 v1(50.75,83.56) 50.33,83.56 49.17,82.4 PU1900.22
N18290168: length 2.5
  TOP w0.203: PU1900.29 46.48,84.95 v1(46.28,85.15) 45.77,85.65 PR1927.1
N19473413: length 4.4
  TOP w0.14: PR1804.1 v1(175.72,83.3)
  TOP w0.254: PR1804.1 176.72,83.29 PC1802.2 177.6,83.28 PR1803.2 178.29,81.72 PU1800.4
N19473637:
  vias: v1(179.86,82.75)
N20816750: length 2.1
  BOTTOM w0.254: PU1700.5 107.5,136.98 PR1701.1
N20816752: length 2
  BOTTOM w0.254: PC1706.2 107.37,136.29 106.5,137.16 PU1700.7
N20816771: length 1.3
  BOTTOM w0.635: PR1701.2 PC1706.1
N20816775: length 6
  BOTTOM w0.14: v1(112.15,133.29) 112.15,133.72 PR1700.2
  BOTTOM w0.254: PR1700.2 110.03,135.84 PC1705.2 109.78,135.84 109.21,136.42 108.89,136.42 108.5,136.81 PU1700.3
N20816793: length 2.7
  TOP w0.14: PR1702.1 v2(109.27,146.96) 108.98,146.66 v1(108.47,146.66)
  BOTTOM w0.14: v2(109.27,146.96) PL1702.3
N20816800: length 1.9
  TOP w0.14: PR1703.1 v4(106.29,146.46)
N20816821: length 2.8
  BOTTOM w0.14: PC1715.2 v1(109.52,163.91)
  BOTTOM w0.305: PU1701.7 107.85,163.76 PC1715.2
N20816822: length 1.3
  BOTTOM w0.305: PR1705.1 106.85,163.79 PU1701.5
N20816832: length 4.4
  BOTTOM w0.305: PU1701.3 105.85,163.52 PC1713.2 105.4,163.98 v1(104.04,163.98) 103.11,163.98 PR1704.2
N20816859: length 2.6
  BOTTOM w0.14: PC1715.1 v1(108,166.68)
  BOTTOM w0.635: PR1705.2 PC1715.1
N20816888: length 2.1
  TOP w0.14: v1(107.8,153.89) 107.18,154.51 PR1706.1
N20820556: length 2.8
  TOP w0.14: v1(135.31,174.06) v2(135.31,172.99) PR1202.1
  BOTTOM w0.14: v2(135.31,172.99) PL1202.3
N20820665: length 2.5
  TOP w0.14: v1(143.1,173.25) 143.1,172.79 v2(142.93,172.61) PR1206.1
  BOTTOM w0.14: PL1203.3 v2(142.93,172.61)
N20820729: length 2.7
  TOP w0.14: v2(150.55,172.61) PR1253.1 v1(149.73,173.58)
  BOTTOM w0.14: v2(150.55,172.61) PL1251.3
N20820776: length 2.4
  TOP w0.14: v1(158.84,172.61) v2(158.17,172.61) PR1257.1
  BOTTOM w0.14: v2(158.17,172.61) PL1252.3
N26813293: length 6.4
  TOP w0.254: RV641.2 RV1080.2 230.02,119.41 230.63,118.8 v1(230.63,117.16) v2(230.63,116.22) ; RV640.2 RV639.2 223.2,115.59 v2(223.19,115.59)
N27076067: length 0.8
  TOP w0.203: PC1941.1 46.51,87.24 PR1930.2
N27182711: length 2.1
  TOP w0.14: v1(102.82,173.54) 103.35,174.07 PR1141.2
  TOP w0.254: PR1141.2 PC1121.1
N27933518: length 1.5
  BOTTOM w0.305: PC1270.2 158.08,185.16 PU1252.7
N27933520: length 1.4
  BOTTOM w0.305: PR1256.1 157.08,185.43 PU1252.5
N27933540: length 2.6
  BOTTOM w0.254: PU1252.3 156.08,185.83 PC1268.2
  BOTTOM w0.635: PR1255.2 PC1268.2
N27933602: length 1.3
  BOTTOM w0.635: PC1270.1 PR1256.2
N27933660: length 4
  TOP w0.14: PR1258.1 v4(159.77,177.37)
  TOP w0.635: PC1272.2 156.64,178.64 PR1258.1
N28152235: length 4.2
  BOTTOM w0.14: v1(103.17,174.5) 103.43,174.25 PR1132.1 103.61,173.45 104.32,172.74 PC1113.2 PC1114.2 PR1131.2
N28152401: length 4.1
  TOP w0.203: PU1100.15 112.41,179.37 112.92,179.88 113.31,179.88
  TOP w0.381: PR1154.2 113.94,181.3 PC1130.2 113.59,180.79 113.69,180.69 v1(113.69,180.26) 113.31,179.88
N28152437: length 4.3
  TOP w0.203: PU1100.3 114.66,174.31 v2(115.21,173.75)
  BOTTOM w0.14: v2(115.21,173.75) 115.43,173.75 v1(115.77,174.1)
  BOTTOM w0.254: PR1135.2 PC1120.2 114.68,173.75 v2(115.21,173.75)
N28152465: length 3.8
  TOP w0.203: PU1100.36 106.63,174.71 v2(106.54,174.63)
  BOTTOM w0.14: v1(105.46,177.03) 106.32,176.17 PC1122.1
  BOTTOM w0.203: v2(106.54,174.63) 106.53,174.64 106.53,175.27 ; 106.53,175.27 PR1139.1 ; 106.53,175.27 106.53,176.16 PC1122.1
N28152729: length 6
  TOP w0.14: v1(120.29,171.46) 118.97,170.15 PR1110.2
  TOP w0.254: PR1110.2 117.88,170.15 117.63,169.89 117.63,169.87 117.55,169.79 117.55,169.79 117.4,169.64 117.4,169.64 117.02,169.26 PR1115.1 ; PR1115.1 117.02,168.8 117.14,168.67 PC1103.1 ; PR1115.1 116.28,169.23 PR1111.1
N28152747: length 4
  TOP w0.14: PR1108.2 118.03,166.76 v1(117.67,166.39)
  TOP w0.254: PR1108.2 PC1103.2 116.28,167.45 PC1100.1 PR1109.1
N28152784:
  vias: v1(112.38,180.24)
N28152844: length 5.6
  TOP w0.14: v2(108,182.77) v1(108,184.14) 108,185.29 107.26,186.02 PR1173.2
  TOP w0.254: PR1176.1 106.81,186.07 PR1173.2
  BOTTOM w0.14: PH1104.1 106.35,134.51 v2(106.1,134.26)
N28152958: length 3
  TOP w0.14: v1(111.73,151.33) 111.51,151.55 v2(111.51,152.04)
  TOP w0.254: v2(102.67,177.06) 103.35,177.06 PR1145.2 PR1149.1
  BOTTOM w0.14: PH1102.2 v2(111.51,152.04)
N28153073: length 2.3
  TOP w0.14: v2(102.92,151.53) v1(102.11,151.53)
  TOP w0.254: PR1100.1 112.06,167.2 v2(112.06,167.91)
  BOTTOM w0.14: PH1100.2 102.72,151.33 v2(102.92,151.53)
N28153459: length 5.4
  TOP w0.14: v2(121.08,180.61) v1(119.55,180.61) 117.6,180.61 PR1172.2
  TOP w0.254: PR1175.1 PR1172.2
  BOTTOM w0.254: PH1103.1 v2(127.94,179.85)
N28153589: length 3.2
  TOP w0.203: PU1100.43 109.21,171.63 109.52,171.32 v2(109.52,171.21) 109.52,170.78 PR1125.1
  BOTTOM w0.14: v1(109.83,170.64) 109.52,170.95 v2(109.52,171.21)
N28153954: length 1.9
  TOP w0.14: PC1117.1 v1(120.76,175.48)
  TOP w0.254: PC1117.1 119.63,175.53 PR1136.2
N28154016: length 2.8
  TOP w0.254: PC1112.1 116.28,171.95 PC1111.1 116.46,171.98 PR1126.2 117.32,172.76 PR1127.1
N28154283: length 3.6
  TOP w0.14: v4(131.11,174.72) 130.78,174.39 v2(130.35,174.39)
  TOP w0.254: PR1144.2 v2(118.29,177.39) 118.36,177.46 PR1148.1
  BOTTOM w0.14: v2(130.35,174.39) 130.48,174.26 130.78,174.26 PH1101.2
N28180064: length 2.2
  BOTTOM w0.14: v1(115.75,169.7) 115.19,170.26 PC1109.1
  BOTTOM w0.254: PR1122.2 PC1109.1
N28185893: length 2
  TOP w0.14: v1(104.78,171.07) 104.32,171.53 PC1118.1
  TOP w0.254: PC1118.1 PR1138.2
N28185971: length 2.2
  TOP w0.14: PC1116.1 v1(120.21,172.87)
  TOP w0.254: PC1116.1 119,173.6 PR1134.2
N31483113: length 3.2
  TOP w0.14: v1(182.54,183.46) 182.7,183.46 183.49,184.26 PR717.2
  TOP w0.254: PQ701.2 182.8,184.92 182.68,184.79 PC725.1 183.43,184.41 PR717.2
N31483116: length 1.3
  TOP w0.254: PQ701.3 183.45,185.61 183.67,185.82 PR713.2
N31483118: length 3.6
  TOP w0.14: v1(180.62,186.35) 181.1,186.84 PR715.2
  TOP w0.254: PQ701.5 182.8,187.5 182.66,187.64 182.28,187.64 182.15,187.51 PQ701.6 181.6,187.26 181.48,187.38 PR715.2
N32073814: length 2.2
  TOP w0.203: PU700.8 191.69,185.87 191.44,186.12 PC711.1
  TOP w0.254: PC711.1 191.99,186.5 192.04,186.45 PR710.1
N32073817: length 6.7
  TOP w0.14: v1(184.34,187.98) 184.85,187.47 PC712.1 185.27,186.76 v2(185.22,186.71) 185.42,186.5 185.42,186.01 185.23,185.82 PR713.1
  TOP w0.203: v2(193.6,186.45) PR710.2 192.81,186.17 192.58,185.95 192.33,185.95 192.09,185.71 PU700.7
  TOP w0.254: PR713.1 184.96,186.06 PR712.1
N32074224:
  vias: v1(203.25,187.6)
N32086652: length 3
  TOP w0.203: PR711.1 187.46,183.62 PR718.1 188.42,183.62 188.86,184.06 v1(189.03,184.06) PU700.12
N35924928: length 3.3
  TOP w0.102: RV600.2 213.13,149.73 v1(213.13,148.75) 213.13,148.07 213.54,147.66 v2(213.54,147.39)
  BOTTOM w0.102: UV18.J27 213.2,147.05 v2(213.54,147.39)
N35928308: length 4.7
  TOP w0.102: RV601.2 213.99,149.72 213.99,147.9 v2(214.5,147.39)
  TOP w0.14: v1(214.17,151.01) 214.17,150.58 213.69,150.09 RV601.2
  BOTTOM w0.102: v2(214.5,147.39) 214.1,146.99 UV18.H27
N35950826: length 3.4
  TOP w0.102: v2(214.53,145.67) 214.9,145.3 214.9,144.42 v1(214.93,144.39) 215.13,144.39 215.17,144.44 215.84,144.44 RV602.2
  BOTTOM w0.102: v2(214.53,145.67) 214.1,145.24 UV18.H25
N42077965: length 2.7
  BOTTOM w0.305: PU1200.7 132.75,185.14 133.07,185.46 134.06,185.46 134.48,185.88 PC1210.2
N42077969: length 1.8
  BOTTOM w0.305: PU1200.5 131.75,185.06 130.73,186.07 PR1201.1
N42077993: length 5
  TOP w0.14: v2(128.96,186.9) v4(128.02,186.9)
  TOP w0.508: PR1200.2 v2(128.96,186.9)
  BOTTOM w0.254: v2(128.96,186.9) 129.02,186.84 129.34,186.84 129.65,186.52 PC1208.2 129.65,186.14 130.35,185.44 130.61,185.44 130.75,185.3 PU1200.3
N42078041: length 2.2
  BOTTOM w0.305: PU1201.7 141.76,185.14 142,185.37 142.8,185.37 143.05,185.63 PC1228.2
N42078055: length 1.8
  BOTTOM w0.305: PU1201.5 140.76,185.18 140.96,185.37 141.15,185.37 PR1205.1
N42078421: length 1
  BOTTOM w0.635: PR1201.2 PC1210.1
N42078543: length 3.1
  TOP w0.14: PC1217.2 v4(132.52,178.64)
  TOP w0.635: PR1203.1 134.67,178.64 PC1217.2
N42078657: length 1.3
  BOTTOM w0.635: PR1205.2 PC1228.1
N42078671: length 2.8
  BOTTOM w0.254: PU1201.3 139.76,185.07 140.51,185.82 PC1227.2
  BOTTOM w0.635: PR1204.2 PC1227.2
N42078715: length 3.2
  TOP w0.14: PC1230.2 v4(140.12,178.64)
  TOP w0.635: PR1207.1 142.29,178.64 PC1230.2
N42079748: length 1.4
  BOTTOM w0.305: PR1252.1 149.65,185.43 PU1251.5
N42079752: length 1.5
  BOTTOM w0.305: PU1251.7 150.65,185.16 PC1259.2
N42079902: length 1.3
  BOTTOM w0.635: PR1252.2 PC1259.1
N42079910: length 2.6
  BOTTOM w0.254: PU1251.3 148.65,185.87 PC1257.2
  BOTTOM w0.635: PR1251.2 PC1257.2
N42079960: length 3.5
  TOP w0.14: PC1261.2 v4(147.69,178.64)
  TOP w0.635: PC1261.2 149.97,178.64 150.61,178.01 PR1254.1
N48708347: length 1.8
  BOTTOM w0.14: PC600.2 280.91,93.27 v1(281.24,92.94)
N48708367: length 5.8
  TOP w0.14: PR610.1 287.76,97.77 288.15,97.38 288.4,97.38 288.41,97.39 v2(288.84,97.39)
  BOTTOM w0.14: v1(290.61,95.6) 290.49,95.6 289.92,96.17 289.83,96.17 289.6,96.4 PR608.2
  BOTTOM w0.203: PU600.7 288.68,97.23 v2(288.84,97.39) 289.1,97.39 289.14,97.43 PC614.1 PR608.2
N48708425: length 3.8
  BOTTOM w0.203: PR605.2 288.67,94.05 v1(288.67,95.83) 288.67,95.9 288.15,96.43 PU600.9
N49570918: length 6.2
  TOP w0.14: v1(131.03,70.69) 131.23,70.49 v2(131.74,70.49)
  BOTTOM w0.14: PU500.14 130.86,71.52 130.96,71.42 PC506.2 131.68,70.55 v2(131.74,70.49)
  BOTTOM w0.254: PR507.1 131.79,68.28 PR504.2 131.78,70.46 v2(131.74,70.49)
N52218840: length 4.3
  TOP w0.14: v1(104.9,180.83) 105.03,180.7 105.82,180.7 105.99,180.52 106.62,180.52 PR1146.2
  TOP w0.203: PR1146.2 106.86,179.67 107.34,179.19 PU1100.27
N52997531: length 3.2
  TOP w0.14: v1(26.09,147.66) PD100.1 25.73,149.1 PR102.2 25.02,149.13 PL104.1
N52999986: length 10
  TOP w0.14: PL104.2 24.09,150.04 22.31,150.04 21.74,149.47 PQ100.1 ; PQ100.1 21.26,150.77 21.34,150.84 PR100.1 PR103.1 ; PQ100.1 21.26,148.75 22.09,147.92 v1(22.09,147.52)
N55155823: length 1.2
  TOP w0.14: RV120.1 v1(38.28,103.07)
N55155843: length 3.3
  TOP w0.14: QV12.1 37.07,102.46 v1(36.78,102.75)
  TOP w0.508: RV120.2 37.57,100.91 37.49,100.83 QV12.1
N108873638: length 4.1
  TOP w0.203: PU400.20 342.96,85.61 343.08,85.49 343.46,85.49 v2(343.71,85.74)
  BOTTOM w0.254: v2(343.71,85.74) 344.34,85.74 v1(344.6,85.48) 345.12,84.96 345.12,84.61 345.4,84.33 PR409.1
N109970739: length 5.5
  TOP w0.14: PR410.1 345.8,83.63 v1(346.29,83.14)
  TOP w0.203: PR410.1 345.62,84.46 345.33,84.46 344.61,85.17 342.91,85.17 342.56,85.52 PU400.19
N110703687: length 1
  TOP w0.14: v1(171.81,170.43) 172.29,169.94 172.61,169.94
N116496514: length 1
  TOP w0.14: v1(171.44,185) 171.34,184.9 171.34,184
N119328643: length 7.2
  TOP w0.14: v1(50.14,88.74) 50.44,88.44 50.44,87.34 PR1923.1
  TOP w0.203: PU1900.25 48.08,84.24 48.22,84.38 48.22,85.78 48.39,85.95 49.44,85.95 49.64,86.15 PR1924.2 50.51,86.43 PC1934.1 50.52,87.27 PR1923.1
N119942216: length 1.7
  BOTTOM w0.14: PL105.1 23.83,152.89 23.38,152.44 v1(23.38,151.97)
N121033373: length 2.2
  TOP w0.203: PR408.2 343.84,90 v2(343.53,89.69) 343.43,89.59 343.15,89.59 342.96,89.4 PU400.6
N121033408: length 4
  TOP w0.203: PR407.2 v2(342.89,90.06) 342.89,89.93 342.56,89.61 PU400.7
  BOTTOM w0.14: PR407.2 343.32,90.68 v1(344.14,91.51)
  BOTTOM w0.254: v2(342.89,90.06) PR407.2
N121616283: length 3.3
  TOP w0.127: UE6.6 190.37,75.38 190.55,75.57
  TOP w0.14: v1(191.83,77.2) 191.83,76.47 CE65.1 191.05,76.07 190.55,75.57
N121617744: length 1.6
  TOP w0.14: CZ37.1 233.09,76.41 UZ33.6
N121718437: length 6.3
  TOP w0.14: DE7.1 96.17,101.62 95.96,101.82 95.73,101.82 RE82.2 95.72,103.69 v4(95.44,103.97) v2(95.02,104.39)
  BOTTOM w0.14: v2(95.02,104.39) 95.02,103.95 94.36,103.3 JFAN1.3
N121718548: length 12.4
  BOTTOM w0.14: JFAN2.3 336.21,123.39 337.01,122.6 337.01,119.78 335.04,117.81 RE84.2 335.04,115.69 335.48,115.25 DE8.1 335.48,113.97 v4(335.23,113.72)
N122282431: length 4.1
  BOTTOM w0.14: RR9.1 342.57,102.89 v1(342.28,103.18) 342.28,103.37 341.36,104.29 340.5,104.29 340.3,104.48 UR1.28
N122463812: length 4.4
  TOP w0.14: v1(127.85,152.34) 127.53,152.02 v2(127.3,152.02) 127.3,152.45 127.05,152.7 JXDP.1
  BOTTOM w0.14: RH474.1 127.44,152.16 v2(127.3,152.02) 127,152.02 126.48,151.5 RH475.1
N122528028:
  vias: v4(236.25,109.4)
N122712620: length 7.3
  BOTTOM w0.14: v1(252.86,70.13) 252.98,70.26 252.98,70.95 RD58.2 253.7,71.66 254.43,71.66 RD10.2 256.55,72.74 JNGFF2.61
N122739099: length 7.1
  TOP w0.14: v1(113.54,120.08) 113.54,119.65 114.06,119.13 v2(114.1,119.13) 114.22,119.25 115.9,119.25 116.12,119.46 UZ12.1 ; v2(111.02,118.05) 111.02,118.05 111.67,117.4 RZ86.1 111.84,117.35 RZ60.1 111.35,116.1 UZ21.4
N122739340: length 4.6
  TOP w0.14: RZ61.2 117.48,119.31 117.48,120.35 116.92,120.91 v1(116.73,120.91) 115.72,120.91 115.47,120.66 UZ12.2
N123360127: length 2.4
  TOP w0.089: RT12.1 22.72,102.57 v2(23.17,103.02) 23.22,103.02 23.55,102.68 v1(23.56,102.68)
  BOTTOM w0.102: v2(23.17,103.02) UT1.H19
N123360144: length 2.2
  TOP w0.089: RT5.1 28.7,102.76 v1(28.48,102.98) 28.37,103.09 v2(28.37,103.65)
  BOTTOM w0.076: v2(28.37,103.65) 28.37,103.66 28.7,103.98 UT1.Y18
N124211085: length 2.8
  TOP w0.089: v2(22.52,103.02) 22.31,102.8 22.31,101.94 RT164.2 21.41,101.78 v1(21.23,101.61)
  BOTTOM w0.102: v2(22.52,103.02) UT1.F19
N124494273: length 2.8
  BOTTOM w0.081: 23.41,121.14 23.41,121.69 23.13,121.97 23.13,122.67 23.13,122.67 23.13,122.82 UT4.C10
  BOTTOM w0.14: 23.41,121.14 RT181.1
N124494892: length 4.2
  BOTTOM w0.081: v1(16.14,126.74) 16.18,126.7 RT191.1 16.66,125.27 16.79,125.27 16.86,125.2 17.26,125.2 17.53,124.94 18.08,124.94 18.2,124.82 18.63,124.82 UT4.G2
N124539694: length 2.3
  BOTTOM w0.081: 24.32,125.32 23.63,125.32 UT4.G11
  BOTTOM w0.14: 24.32,125.32 24.83,125.32 25.2,125.68 RT5844.1
N124607348: length 2.3
  TOP w0.14: RT195.1 25.04,117.16 v1(24.45,117.75) 24.18,118.03 QV89.1
N124730498: length 4.1
  BOTTOM w0.081: UT4.C2 18.87,123.07 18.62,122.82 18.2,122.82 17.53,122.14 17.43,122.14
  BOTTOM w0.14: RT178.1 16.09,121.84 16.84,121.84 17.15,122.14 17.43,122.14
N124730527: length 3.3
  BOTTOM w0.081: 18.63,121.14 18.63,122.32 UT4.B2
  BOTTOM w0.14: T185.1 17.46,119.85 18.63,121.02 18.63,121.14
N124752685: length 1.9
  TOP w0.14: RH211.1 v1(121.79,84.7)
  TOP w0.254: CH101.2 RH211.1
N124753277: length 2.2
  TOP w0.14: v1(228.08,86.4) 228.34,86.66 CH100.2
  TOP w0.254: RH212.1 229.07,85.72 CH100.2
N124754324: length 4.7
  TOP w0.14: RT199.1 24.56,124.86 24.46,124.96 v2(23.91,124.96) 23.48,124.53 RT189.1 22.94,124.3 22.94,123.51 v1(22.76,123.34)
  BOTTOM w0.081: 23.87,124.96 23.73,124.82 23.13,124.82 UT4.F10
  BOTTOM w0.152: 23.87,124.96 v2(23.91,124.96)
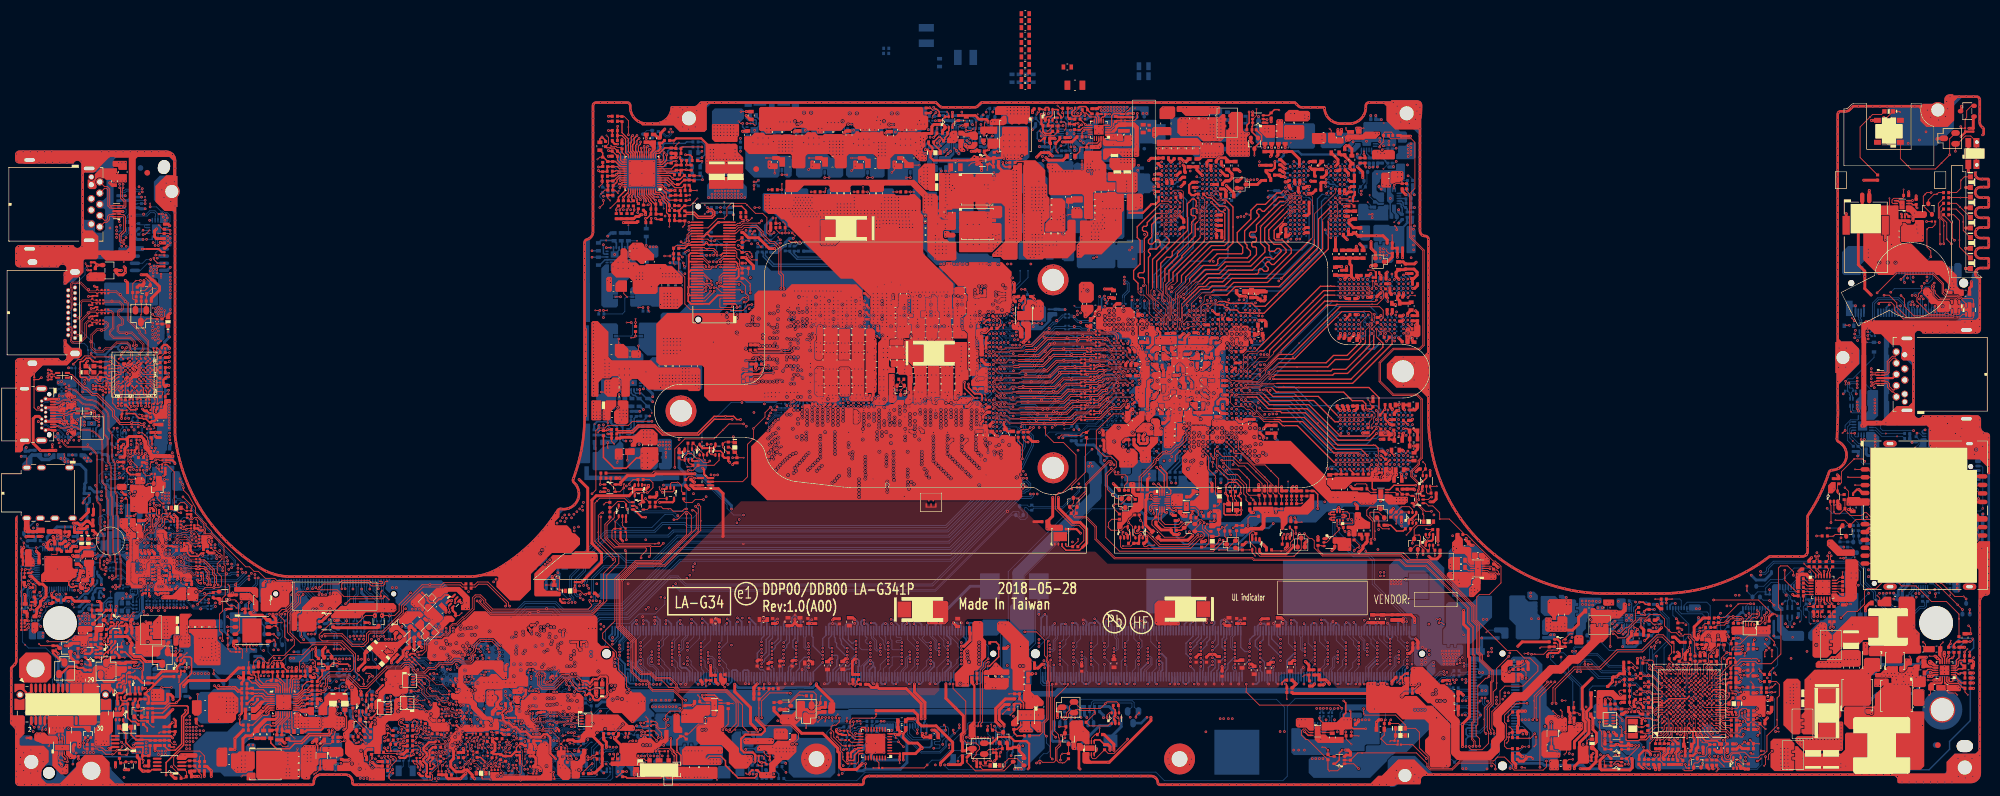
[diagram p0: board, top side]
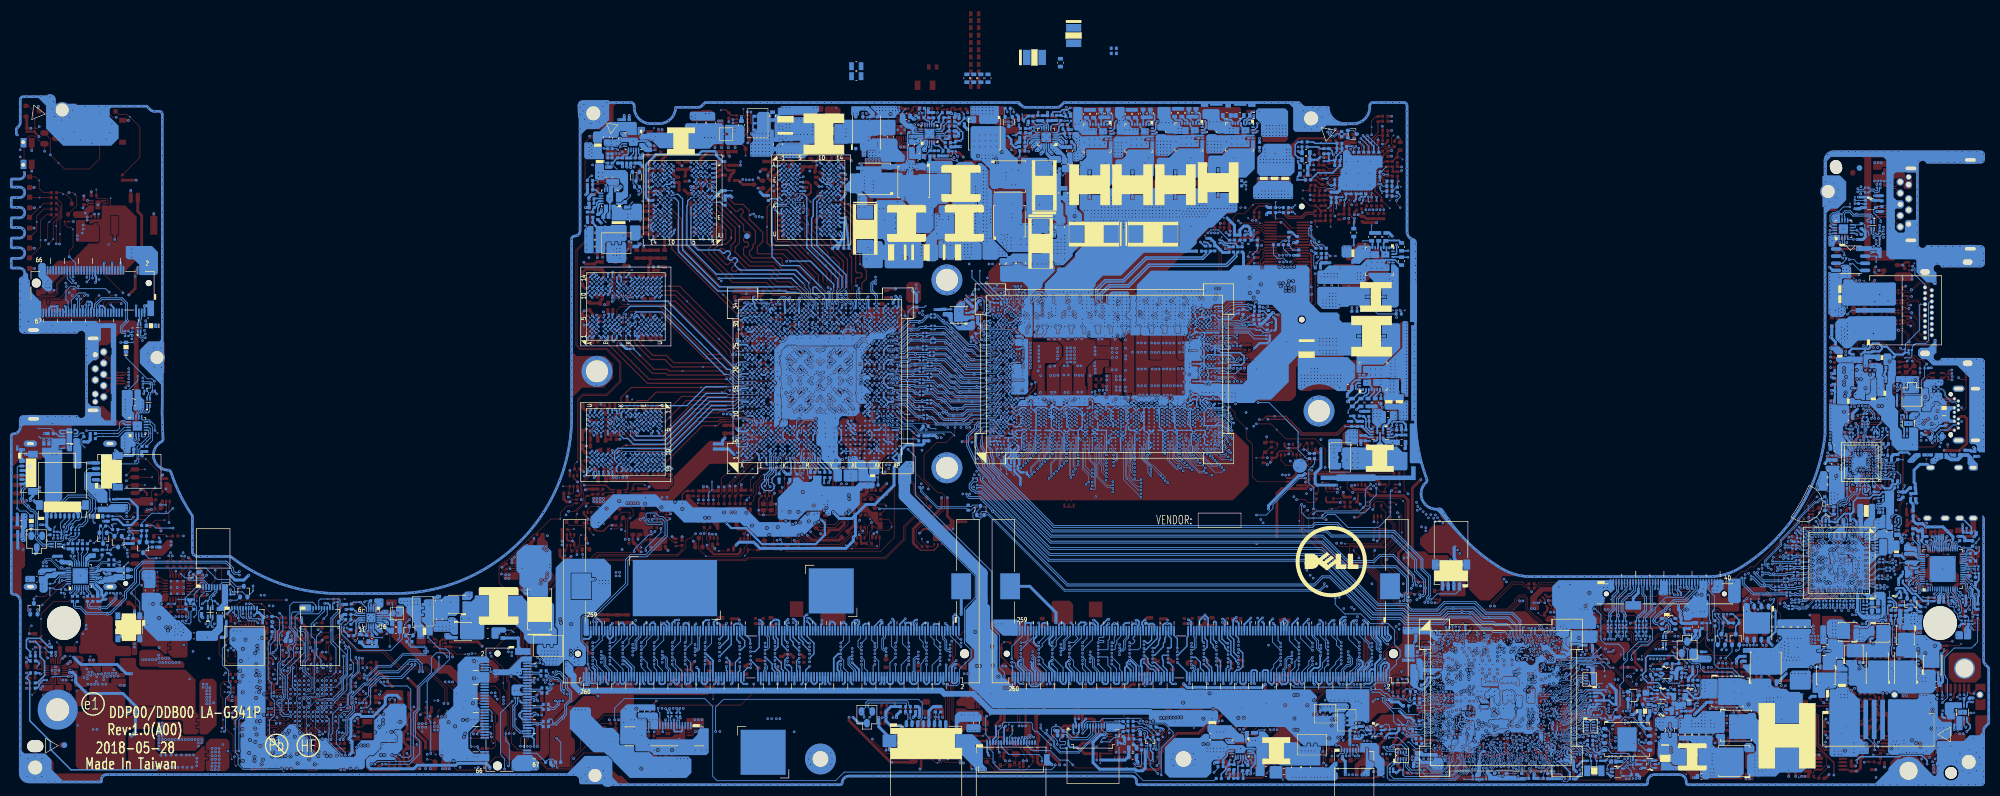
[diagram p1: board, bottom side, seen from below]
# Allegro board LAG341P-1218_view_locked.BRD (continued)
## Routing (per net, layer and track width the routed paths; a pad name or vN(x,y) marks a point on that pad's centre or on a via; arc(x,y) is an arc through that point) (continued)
N124755351: length 1.2
  TOP w0.14: T193.1 19.7,125.7 v2(19.42,125.42)
  BOTTOM w0.081: v2(19.42,125.42) 19.77,125.07 UT4.G4
N124755352: length 2.3
  TOP w0.14: T194.1 20.57,123.78 19.52,124.83 v2(19.44,124.83)
  BOTTOM w0.081: UT4.F4 19.71,124.57 v2(19.44,124.83)
N124817429: length 6.8
  TOP w0.089: v2(95.45,91.49) 95.45,91 v4(95.9,90.56)
  BOTTOM w0.089: 99.75,90.06 99.15,90.06 98.84,90.37 98.84,91.09 98.52,91.42 96.06,91.42 UH2.G3 95.51,91.49 v2(95.45,91.49)
  BOTTOM w0.14: 99.75,90.06 RH581.1
N125173025: length 2.2
  BOTTOM w0.081: RT190.1 16.61,125.04 17.2,125.04 17.46,124.77 18.02,124.77 18.13,124.66 18.29,124.66 UT4.F1
N125742089: length 3.3
  BOTTOM w0.14: UH7.5 62.98,70 62.9,70.07 62.9,70.39 62.67,70.63 62.01,70.63 61.9,70.74 RH586.1 61.52,70.19 v1(61.23,69.89)
N125814346: length 4.9
  TOP w0.14: v1(334.87,173.04) CN22.1 334.87,171.6 334.74,171.47 333.11,171.47 332.81,171.16 332.81,170.71 332.97,170.55 UN3.6
N125960908: length 2.6
  TOP w0.14: UZ19.2 118.67,124.53 119,124.2 119.25,124.2 RZ81.2 119.21,123.7 v1(118.47,123.7)
N126843005: length 15.3
  TOP w0.14: RE3.2 327.14,178.73 327.14,184.17 v1(328.92,185.95) 329.36,186.39 330.96,186.39 331.47,186.9 LED6.2
N127291407: length 5.3
  BOTTOM w0.14: v1(345.24,130.51) 342.96,130.51 342.56,130.11 CZ31.1
  BOTTOM w0.254: UZ5.6 341.53,129.11 342.04,129.62 CZ31.1
N128723349: length 1.2
  TOP w0.14: v1(186.28,169.78) 186.3,169.79 PC1521.1
N128725561: length 5.3
  TOP w0.254: PR1016.2 175.03,177.06 v1(174.82,177.27) 174.61,177.47 v2(174.61,177.85)
  BOTTOM w0.203: PC1054.1 168.55,184.14 v2(168.05,184.14) 167.87,183.96 167.28,183.96 166.97,184.28 166.76,184.28 166.69,184.21 PU1001.10
  BOTTOM w0.254: PC1054.1 168.8,183.9 PR1018.2
N128725563: length 1
  BOTTOM w0.14: v1(162.97,175.49) 162.46,176 162.46,176.24
N128725569: length 1.9
  TOP w0.14: 169.68,183.15 169.68,183.61 169.85,183.77 v1(169.85,184.99)
N128725595: length 3.3
  BOTTOM w0.203: PR1022.1 PC1055.1 169.43,182.55 168.26,182.55 168.06,182.75 PU1001.12
N128725605: length 3.1
  BOTTOM w0.14: PR1014.2 170.14,185.62 v1(170.14,186.42)
  BOTTOM w0.254: PR1013.1 PC1041.1 169.17,186.11 PR1014.2
N128725802: length 5.6
  TOP w0.14: PR1002.1 v1(162.9,184.08)
  TOP w0.254: PR1002.1 162.9,182.9 v2(162.29,182.3)
  BOTTOM w0.254: v2(162.29,182.3) 162.6,182.6 PR1001.1 ; PU1001.4 163.7,182.75 163.46,182.98 PR1001.1 ; PR1000.2 162.6,183.47 PR1001.1
N128726001: length 4.3
  TOP w0.14: v2(162.71,186.73) 162.1,186.12 v1(162.1,185.82)
  BOTTOM w0.254: PR1006.2 PR1007.1 163.28,186.2 163.15,186.06 PC1018.1 162.45,186.47 v2(162.71,186.73) ; PR1005.2 167.39,186.75 v2(167.32,186.81)
N128726023: length 3.7
  TOP w0.14: v1(166.9,184.23) 167.11,184.43 v2(167.49,184.43)
  BOTTOM w0.203: PR1013.2 168.24,184.98 167.69,184.43 v2(167.49,184.43) 167.3,184.63 166.51,184.63 166.29,184.4 PU1001.9
N128726049: length 5.4
  TOP w0.14: v2(161.62,187.57) 161.75,187.57 v1(162.18,187.14)
  TOP w0.381: v2(161.62,187.57) 161.59,187.55 PR1011.1
  BOTTOM w0.254: PR1008.2 164.81,186.6 164.55,186.86 163.37,186.86 163.02,187.22 162.48,187.22 162.43,187.17 162.12,187.17 161.71,187.57 v2(161.62,187.57)
N128726112: length 4.5
  TOP w0.14: v2(168.07,183.54) 168.99,183.54 v1(169.27,183.81)
  TOP w0.254: PR1023.2 v2(175.22,177.82)
  BOTTOM w0.203: PR1021.2 169.47,183.04 PC1054.2 168.24,183.54 v2(168.07,183.54) 167.68,183.15 PU1001.11
N128727409: length 2.3
  BOTTOM w0.203: PR1519.1 186.3,185.81 186.29,185.8 185.92,185.8 ; 185.92,185.8 185.92,185.48 186.26,185.14 PU1501.12 ; 185.92,185.8 PC1532.1
N128727430: length 7.6
  TOP w0.14: PR1508.2 v1(182.05,181.18)
  TOP w0.254: PR1508.2 181.85,182.17 181.39,181.71 v2(181.14,181.71)
  BOTTOM w0.254: PR1507.1 182.22,181.38 PC1517.1 181.89,181.71 v2(181.14,181.71) 180.75,182.1 180.75,183.18 181.9,184.33 PR1505.2
N128727456: length 3.2
  TOP w0.14: PR1509.2 184.07,181.2 ; 184.07,181.2 184.07,181.3 ; 184.07,181.2 184.07,179.98 v1(184.45,179.6)
  TOP w0.381: 184.07,181.3 184.76,181.98 PR1511.1
N128727528: length 3.6
  BOTTOM w0.14: PC1522.1 180.49,186.5 v1(180.79,186.8)
  BOTTOM w0.254: PC1522.1 180.49,185.61 PR1514.2 181.61,184.73 181.97,185.09 PR1515.1
N128727776: length 4.7
  BOTTOM w0.203: PU1501.10 184.78,183.78 184.66,183.9
  BOTTOM w0.254: PR1517.2 204.33,121.34 204.62,121.05 v2(204.62,120.85) ; PR1516.2 184.07,185.85 PC1531.1 184.2,185.72 v2(184.2,185.06) 184.66,184.6 184.66,183.9
N128727796: length 6.5
  TOP w0.127: v2(184.96,185.06) 185.53,185.06 185.85,184.74 185.85,183.91 v1(185.6,183.66)
  BOTTOM w0.203: 185.49,185.06 185.6,185.06 185.86,184.79 PU1501.11
  BOTTOM w0.254: v2(205.4,120.8) 205.4,121.68 PR1520.2 ; PR1521.2 185.01,186.08 PC1531.2 185.01,185.1 v2(184.96,185.06) 185.49,185.06
N128727911: length 3
  BOTTOM w0.203: PU1501.9 184.52,183.38 184.07,183.83 v1(184.07,184.36) 184.07,184.43 183.41,185.09 PR1515.2
N128727995: length 1.5
  BOTTOM w0.14: v1(190.93,187.34) 191.5,186.77 PR1513.1
N128735760: length 1.5
  TOP w0.14: CA125.1 7.7,75.65 7.7,75.18 7.65,75.13 UA4.10
N128735764: length 1.4
  TOP w0.14: UA4.12 6.85,75.13 6.78,75.2 6.78,75.58 6.65,75.71 CA124.1
N128958711: length 3.6
  TOP w0.14: v2(238.87,179.27) v1(238.87,179.82)
  TOP w0.254: PR904.2 PC906.2 239.06,179.07 v2(238.87,179.27)
  BOTTOM w0.203: PR908.1 238.87,178.8 v2(238.87,179.27) PU900.14
N128958713: length 1.7
  TOP w0.254: v2(239.22,177.03) 239.06,177.18 PC906.1 PR904.1
  vias: v1(225.83,181.37) v2(224.87,182.24) v2(225.46,182.27) v2(226.05,182.28) v2(226.68,182.29)
N128967490: length 12.7
  TOP w0.14: v2(18.49,73.32) 18.36,73.2 17.09,73.2 16.45,72.55 v4(16.19,72.55) 15.04,72.55 14.36,73.22 13.8,73.22 13.53,73.5 PR106.1
  BOTTOM w0.14: v2(18.49,73.32) 18.49,74.21 20.09,75.81 BAT100.5
N128967591: length 11.3
  TOP w0.14: v2(17.91,73.91) 17.91,73.74 17.6,73.44 16.99,73.44 16.73,73.17 14.97,73.17 14.5,73.64 v4(14.33,73.64) 14.12,73.84 13.25,73.84 12.83,74.26 PR108.1
  BOTTOM w0.14: BAT100.6 18.59,74.7 17.91,74.02 v2(17.91,73.91)
N128967644: length 8.6
  TOP w0.14: v2(17.83,74.69) 18.97,73.55 18.97,72.7 v4(18.72,72.45) 17.74,72.45 PR111.1
  BOTTOM w0.14: BAT100.7 17.09,75.44 v2(17.83,74.69)
N130300854: length 2.6
  TOP w0.14: CZ98.1 209.4,115.05 v1(209.4,115.6) 209.4,115.79 208.82,116.37 UZ24.6
N130500830: length 5.5
  TOP w0.127: RV1132.1 197.41,109.61 v1(195.99,109.61)
  TOP w0.381: v2(199.16,111.64) 198.86,111.33 QV21.5 198.86,110.18 RV1131.1 RV1132.1 ; v2(198.53,112.27) 198.86,112.6 QV21.2
N130775721: length 2.9
  TOP w0.14: RT430.2 18.17,123.65 v2(17.96,123.87) 17.64,123.87 17.44,123.67 v1(17.31,123.67)
  BOTTOM w0.081: v2(17.96,123.87) 18.21,123.87 18.26,123.82 18.6,123.82 18.85,124.07 UT4.E2 UT4.F2
N130798734: length 3.7
  TOP w0.14: v1(214.5,113.34) 214.1,112.93 RV1083.1 214.1,111.33 214.41,111.02 QV91.1
N132000604: length 1.3
  TOP w0.508: PC1929.2 PR1914.1
N132009758: length 6.6
  TOP w0.254: v2(34.37,84.75) 34.95,84.17 v1(36.07,84.17) 37.95,84.17 38.48,83.63 39.04,83.63 PR1931.2
  BOTTOM w0.254: v2(27.48,91.46) 27.56,91.46 28.07,90.95 PR1910.2
N132009765: length 5.4
  TOP w0.254: PR1935.2 38.99,83.99 38.63,83.99 38.04,84.57 v1(37.41,84.57) 35.28,84.57 v2(35.08,84.78)
  BOTTOM w0.254: PR1910.3 27.36,90.95 v2(27.46,90.85)
N132121209: length 2.7
  TOP w0.14: RV621.2 v1(237.79,170.96)
  TOP w0.381: RV621.2 RV622.2 237.24,172.05 CV925.1
N132122697: length 6.8
  TOP w0.381: CV928.1 199.53,168.89 v1(201.09,170.45) 201.85,170.45 RV627.2 RV626.2
N132123770: length 2.3
  TOP w0.127: 241.83,122.05 242.1,122.32 RV628.2
  TOP w0.14: v1(241.83,121.76) 241.83,122.05
  TOP w0.381: CV987.1 241.2,122.34 RV629.2 RV628.2
N132124417: length 3.1
  TOP w0.14: v1(239.59,158.7) 240.61,158.7 CV990.1
  TOP w0.381: CV990.1 RV637.2 RV638.2
N132190190: length 3.8
  TOP w0.14: PR1851.1 176.61,80.18 v1(175.96,79.53)
  TOP w0.254: PR1851.1 176.62,80.55 PR1800.1 176.81,81.58 177.66,81.58 177.79,81.45 PU1800.5
N132908405: length 6
  TOP w0.127: QZ14.5 219.11,185.58 219.75,186.21 v1(219.75,187.39)
  TOP w0.254: QZ18.2 218.95,183.28 RV103.2 218.95,184.24 219.05,184.35 QZ14.6 QZ14.5
N132908425: length 3.3
  TOP w0.254: QZ14.3 221.91,186.23 RV1808.2 222.93,187.25 223.68,187.25 v1(223.81,187.12)
N132908471: length 3
  TOP w0.127: QZ15.5 165,186.57 v1(164.67,186.9)
  TOP w0.254: RV1809.2 163.66,185.3 QZ15.6 QZ15.5
N132908541: length 4
  TOP w0.14: v1(249.92,112.63) 250.09,112.63 250.18,112.54 RV111.2 250.51,111.95 QZ17.5 250.51,111.16 250.39,111.04 250.09,111.04 249.86,111.27 QZ17.6
N132908575: length 3
  TOP w0.127: RV1810.2 v1(167.88,185.3)
  TOP w0.254: RV1810.2 166.37,185.3 165.65,184.58 QZ15.3
N132908582: length 5.5
  TOP w0.254: v1(219.38,179.08) QZ18.1 219.38,180.49 220.65,181.76 220.65,182.69 RV112.2
N132908588: length 2
  TOP w0.14: v1(251.49,107.88) RV1811.2 251.16,109.18 QZ17.3
N132951149: length 2.9
  TOP w0.14: QZ6.6 249.34,122.81 249.81,123.28 RV8.2 249.81,124.14 v1(249.33,124.62)
N132951151: length 4.5
  TOP w0.14: v1(251.83,120.23) QZ6.3 250.64,119.89 250.8,119.73 RV12.2 250.67,118.89 250.24,118.89 249.99,119.14 QZ6.2
N132951302: length 2.9
  TOP w0.14: QV3.3 248.16,113.51 247.32,112.67 RV11.2 247.14,112.3 v1(246.43,111.59)
N132958139: length 13.4
  TOP w0.14: v1(168.58,177.31) 169,177.73 RH5893.1
  TOP w0.254: RH5893.1 169,178.49 169.55,179.04 UV28.1
N132958145: length 4.8
  TOP w0.14: v1(171.86,176.51) UV28.4
  TOP w0.254: UV28.4 172.24,177.74 172.65,177.33 CV918.1 172.89,178.19 RV1128.1 172.87,178.82 RV1807.2
N132961365: length 5.1
  TOP w0.14: RV590.1 194.36,116.29 v1(194.36,116.79) 194.64,117.07 195.72,117.07 196.68,118.04 QV103.2
N134346262: length 3.5
  TOP w0.14: v1(243.31,112.67) 242.15,112.67 RV1112.2 241.52,114.3 QV98.2
N134965433: length 1.2
  BOTTOM w0.14: UZ25.6 12.75,129.12 CZ100.1
N134966636: length 3.5
  TOP w0.14: UM1.C6 18.5,138.48 18.5,135.62 RM4.1
N134966683: length 3
  TOP w0.14: UM1.F2 22.52,141.7 23.37,141.7 23.68,142.01 24.44,142.01 RM19.1
N134967484: length 3
  BOTTOM w0.14: UM2.7 18.34,161.18 RM10.2 v1(18.21,160.14)
N135073509: length 1.3
  TOP w0.089: T2.1 78.68,78.01 v2(78.3,77.63)
  BOTTOM w0.089: v2(78.3,77.63) 78.18,77.63 77.87,77.94 UH2.AN40
N135670058: length 3.7
  BOTTOM w0.254: PR521.1 134.42,71.14 PR500.2 134.41,71.59 v1(133.9,72.1) 133.67,72.33 133.67,72.87 133.41,73.14 PU500.9
N135676145: length 5.8
  BOTTOM w0.14: v1(242.33,176.73) 243.13,177.53 243.13,177.74
  BOTTOM w0.254: 243.13,177.74 242.99,177.74 242.7,178.03 242.7,178.17 242.21,178.66 PC911.1 PR906.1 241.3,178.88 240.97,179.22 240.46,179.22 240.22,179.46 PU900.11
N135676149: length 2.2
  BOTTOM w0.254: PR903.1 243.13,179.39 PR902.2 PR907.2
N135676155: length 1
  BOTTOM w0.14: v1(235.41,180.03) PC905.1
N135689071: length 0.9
  BOTTOM w0.508: PR1605.2 247.53,167.26 PR1603.2
N135689238: length 3.9
  BOTTOM w0.254: PR1605.1 247.51,169.02 PC1606.2 246.56,169.56 PR1608.1 246.19,169.82 245.83,170.17 245.83,170.7 245.54,170.99 PU1600.14
N135689294: length 4.5
  BOTTOM w0.14: PR1602.2 245.85,174.64 v1(245.61,174.4)
  BOTTOM w0.254: PR1602.2 PR1604.1 PC1611.1 246.05,172.99 245.4,172.34 PU1600.11
N135689304: length 1.2
  BOTTOM w0.14: v1(244.26,167.21) 244.6,167.56 244.61,167.56 244.73,167.68 PC1605.1
N135767612: length 13.1
  TOP w0.381: PQ202.1 7.13,89.44 6.77,89.44 5.64,90.57 PR205.1 6.07,90.95 v2(6.56,90.46)
  BOTTOM w0.14: v2(6.56,90.46) 6.16,90.86 v1(6.16,91.25)
  BOTTOM w0.381: PQ201.4 7.22,86.08 PR201.2
  BOTTOM w0.508: PR201.2 7.14,85.21 PC202.2 6.4,85.49 6.4,86.32 6.56,86.48 v2(6.56,90.46)
N135767628: length 6.4
  TOP w0.381: PQ202.2 7.05,86.81 8.39,88.16 9.83,88.16 10.06,87.93 v1(10.22,87.93) 10.97,87.93 PR200.2 12.22,87.55 PR204.1
N135767648: length 2.7
  TOP w0.14: v1(11.32,88.65) 11.53,88.44 PR204.2
  TOP w0.381: PQ203.6 12.24,88.92 PR204.2
N135767654: length 4
  TOP w0.14: PR205.2 3.45,91.86 v1(3.1,92.22)
  TOP w0.381: PQ204.1 6.4,91.86 PR205.2
N135767682: length 2.3
  TOP w0.254: PQ203.3 13.66,91.09 13.79,91.23 13.97,91.23 PR210.2 13.92,91.64 13.56,91.64 PR206.2
N135767749: length 2.7
  TOP w0.508: PQ204.2 8.72,89.85 9.61,88.96 PR213.1
N135767765: length 1.1
  BOTTOM w0.508: PQ205.1 12.29,98.41 12.63,98.06 PR209.2
N135767870: length 4.4
  BOTTOM w0.381: PR216.1 10.61,97.89 10.97,98.25 10.97,98.43 11.75,99.21 12.62,99.21 12.77,99.06 PU201.4
N135767884: length 3.7
  TOP w0.14: PQ206.1 14.72,96.66 v1(15.32,97.26)
  TOP w0.254: PQ206.1 15.39,95.74 v2(15.4,95.74)
  BOTTOM w0.254: v2(15.4,95.74) 15.4,96.22 PR224.1 15.6,96.79 15.54,96.84 PR215.1
N135767963: length 2.7
  TOP w0.381: PR218.1 12.37,91.76 12.62,91.51 12.62,90.85 12.22,90.44 PQ203.5
N135767967: length 5.1
  TOP w0.14: PR221.2 v1(15.85,99.19)
  TOP w0.254: PR221.2 PR222.1 12.82,95.89 PQ206.3
N135767977: length 2.2
  TOP w0.14: v1(12.55,99.18) PR223.1
  TOP w0.254: PQ206.2 12.55,97.33 PR223.1
N135768200: length 0.9
  TOP w0.254: PQ203.2 13.77,90.44 13.82,90.49 PR210.1
N135770596: length 3.9
  BOTTOM w0.14: PR274.1 57.52,86.76 v1(58.48,87.72)
  BOTTOM w0.254: PQ223.2 56.17,87.05 56.03,86.91 56.03,86.76 56.39,86.4 PQ223.3 56.76,86.4 57.12,86.76 PR274.1
N135770632: length 19.6
  BOTTOM w0.254: PQ223.6 54.52,87.81 PR273.1 53.41,88.66 PR283.2 53.33,89.27 54.18,90.11 58.85,90.11 59.23,89.73 v1(59.23,89.07) 59.23,87.33 59.78,86.78 59.78,86.22 58.85,85.29 57.08,85.29 56.57,84.77 56.57,83.56 55.65,82.64 PQ220.4
N135770638: length 1.6
  BOTTOM w0.14: v1(51.85,87.6) 52.25,87.6 52.47,87.82 PR283.1
N135770716: length 3.3
  TOP w0.14: PR242.1 17.83,92.44 v1(18.05,92.65)
  TOP w0.254: PR242.1 16.89,91.66 16.05,90.83 16.05,90.71
N135770748: length 2.3
  TOP w0.254: 16.05,92.61 16.05,92.45 15.65,92.05 14.57,92.05 14.43,92.19 PR239.2
N135770768: length 5.3
  TOP w0.14: v1(31.88,72.26) 31.7,72.08 PR207.1 ; PR207.1 31.7,71.24 PR211.2 ; PR207.1 30.99,71.25 PR219.1 PC206.1 29.51,71.39 29.25,71.12 PU200.3
N135770796: length 29
  TOP w0.14: v1(21.58,70.97) 21.69,71.09 v2(21.69,71.47)
  TOP w0.254: PR251.2 21.54,72.81 21.62,72.89 21.62,73.7 21.47,73.85 PU203.1 20.41,73.85 20.17,73.61 19.59,73.61 18.59,74.61 18.59,76.17 PD202.2 ; PR251.2 PC216.1 22.9,72.52 PR245.2 ; PR251.2 21.54,71.62 v2(21.69,71.47) ; v2(17.13,96.06) 16.92,95.85 16.92,95.47 15.85,94.4 PR253.1
  BOTTOM w0.254: v2(21.69,71.47) 21.03,72.13 14.07,72.13 13.84,72.37 10.09,72.37 9.17,71.44 v2(9.17,70.81)
N135770798: length 7.3
  TOP w0.254: PR242.2 18.46,90.75 19.78,89.43 21.01,89.43 21.7,88.73 21.7,87.54 v1(21.53,87.37) PU202.4
N135770815: length 12.7
  TOP w0.508: PR237.1 18.87,93.49 19.33,93.03 v2(19.33,92.65) 19.66,92.32 PR229.2 19.42,91.72 PC211.2 19.42,90.62 20.1,89.94 21.26,89.94 22.15,89.05 v1(22.39,89.05) 24.69,89.05 PQ210.1
  BOTTOM w0.381: v2(19.33,92.65) 19.33,92.98 19.12,93.19 PQ208.4
N135770837: length 3.1
  TOP w0.254: PR253.2 PC217.1 17.63,94.58 17.32,94.89 17.32,95.57 17.79,96.03 PQ215.5
N135770888: length 6.6
  TOP w0.14: PR228.2 19.66,93.64 20.15,93.15 v1(20.16,93.15)
  TOP w0.508: PR240.1 19.47,96.32 v2(19.47,95.78) 19.47,95.2 PC210.1 PR228.2
  BOTTOM w0.381: PQ207.4 21.32,95.31 21.2,95.19 19.88,95.19 19.47,95.6 v2(19.47,95.78)
N135770896: length 6.9
  TOP w0.254: PQ216.2 17.45,80.89 PR261.1 18.08,81.51 PR262.1 18.93,79.01 19.57,78.38 20.29,78.38 PR260.1
N135770915: length 4.7
  TOP w0.14: PR232.1 27.46,90.21 28.17,90.92 v1(28.17,91.19)
  TOP w0.508: PR225.2 26.03,92.27 PQ210.2 26.57,90.21 PR232.1
N135770919: length 2.5
  TOP w0.14: PR232.2 29.06,90.21 v1(29.44,90.59)
  TOP w0.254: PQ212.6 27.72,89.61 PR232.2
N135770992: length 4.3
  TOP w0.14: PR258.1 22.45,78.25 23.28,77.42 v1(23.56,77.42)
  TOP w0.254: PR258.1 22.33,78.5 20.83,78.5 PQ217.2
N135771010: length 12.3
  TOP w0.14: v1(27.55,74.29) 27.03,74.29 26.33,74.98 PR234.2
  TOP w0.254: PQ216.6 18.1,78.38 19.11,77.36 PD202.1 19.54,75.97 20.36,75.15 PU203.3 22.77,75.15 PR245.1 23.8,75.01 PC214.1 24.68,75.01 PR254.1 25.41,75.02 PR249.2 25.47,75.02 PR234.2
N135771120: length 8.1
  TOP w0.508: PR235.1 16.05,89.81 PQ211.1 17.5,88.82 PC212.2 PR230.2 18.47,88.79 18.61,88.93 v1(19.53,88.93) 20.38,88.93 v2(20.4,88.92)
  BOTTOM w0.381: v2(20.4,88.92) PQ209.4
N135771130: length 2.3
  TOP w0.254: PR259.2 PR252.1 20.75,81.98 PQ217.1
N135771134: length 1.9
  TOP w0.254: PQ217.3 21.5,79.14 PR257.1 PR256.2
N135771193: length 2.5
  TOP w0.254: PQ215.2 16.28,96.03 16.48,95.83 16.48,95.58 16.28,95.38 PQ215.3 15.37,94.76 PR246.1
N135771203: length 2.9
  TOP w0.14: PR240.2 18.86,96.54 19.43,97.11 19.43,97.3 19.9,97.77 v1(20.15,97.77)
  TOP w0.381: PQ215.6 18.15,96.68 18.29,96.54 PR240.2
N135771219: length 5
  TOP w0.14: PC215.1 24.67,76.52 v1(24.43,76.28)
  TOP w0.254: v2(27.17,75.98) 27.36,76.17 PR244.2 26.42,76.6 PR255.1 25.41,76.54 PC215.1 ; PU203.2 20.3,74.5 v2(19.94,74.13)
N135771268: length 4.9
  TOP w0.14: v1(32.02,68.42) 32.02,68.92 31.64,69.3 PR212.2 30.86,70.39 PR220.1 30.38,70.48 30.34,70.44 PC205.1 29.94,70.44 29.91,70.47 PU200.2
N135771321: length 1.1
  TOP w0.254: PQ213.6 15.4,93.04 PR237.2
N135771386: length 5.5
  TOP w0.381: PR233.1 17.84,86.14 17.77,86.14 PR226.2 16.74,85.79 16.35,85.41 14.77,85.41 14.1,86.08 PQ211.2
N135771412: length 1.8
  TOP w0.254: PR233.2 18.08,85.57 17.96,85.44 17.96,85.43 17.81,85.29 17.32,85.29 17.05,85.02 PQ214.6
N135771419: length 2.3
  TOP w0.14: v1(18.4,89.73) 18.33,89.81 PR235.2
  TOP w0.381: PQ213.3 16.75,90.71 17.4,90.07 PR235.2
N135771459: length 3.6
  TOP w0.254: PQ214.3 18.35,82.91 18.72,83.28 PR238.2 19.35,84.63 19.23,84.75 PR236.2
N135771494: length 1
  BOTTOM w0.14: PR272.2 58.1,83.29 PQ220.2
N135771851: length 5.8
  TOP w0.14: v1(53.73,85.2) 53.33,84.79 v2(53.33,84.7)
  BOTTOM w0.14: PQ221.1 55.68,79.88 56.24,80.43 v2(56.24,80.97) ; v2(53.33,84.7) 53.21,84.81 PR279.1 51.61,84.83 PR285.2 50.38,84.36 PQ227.6
N135772460: length 1
  BOTTOM w0.14: PQ227.3 53.16,82.56 v1(53.24,82.63)
N135772468: length 1
  TOP w0.254: PR250.2 20.23,83.29 PU202.1
N135772472: length 2.2
  TOP w0.254: PR238.1 19.02,82.36 18.72,82.06 17.93,82.06 17.7,82.29 PQ214.2
N135772484: length 4.8
  TOP w0.14: PR243.1 19.86,87.06 v1(20.23,87.43)
  TOP w0.203: PQ214.5 17.7,84.7 18.08,85.08 18.56,85.08 18.72,85.24 18.72,86.84 18.95,87.06 PR243.1
N135772492: length 1.1
  TOP w0.254: PR252.2 20.88,83.53 PU202.2
N135776099: length 4.1
  BOTTOM w0.14: PU201.1 v1(15.86,101.5)
  BOTTOM w0.254: PU201.1 15.54,100.36 14.63,99.46 14.63,98.32 PR214.2
N135776158: length 2.3
  BOTTOM w0.254: PR215.2 15.54,98.37 15.09,98.83 15.09,99.38 15.42,99.71 PU201.2
N135776395: length 3
  BOTTOM w0.14: v1(9.32,98.67) 9.4,98.75 10.27,98.75 PR216.2
  BOTTOM w0.508: PQ205.2 11.42,99.9 PR216.2
N135782958: length 2.1
  BOTTOM w0.14: PR284.2 49.76,84.63 49.76,83.57 50.12,83.21 PQ227.5
N135788915: length 3.5
  TOP w0.203: PU1900.21 49.2,82 50.15,82.95 51.47,82.95 PR1913.2
N135795991: length 15
  TOP w0.254: v2(55.34,76.93) 55.19,76.78 55.19,76.3 54.76,75.86 51.33,75.86 v1(50.19,74.73) 49.93,74.47 48.64,74.47 47.73,73.55 45.39,73.55 44.37,74.57 PR1902.1
  BOTTOM w0.254: v2(55.34,76.93) 55.34,76.79 54.91,76.37 PR1900.3
N135796052: length 9.7
  TOP w0.254: v2(54.66,76.85) 54.79,76.72 54.79,76.4 54.61,76.22 51.1,76.22 v1(50.94,76.05) 49.77,74.88 47.8,74.88 PR1901.1
  BOTTOM w0.254: v2(54.66,76.85) 54.66,76.97 54.91,77.23 PR1900.2
N135896425: length 9.9
  TOP w0.14: R276.2 168.22,71.11 v1(168.94,70.38) 169.73,69.6 174.84,69.6 QRTC1.1
N137529606: length 5.6
  TOP w0.14: v1(295.71,69.84) 295.92,69.63 297.23,69.63 297.53,69.93 QE10.2 297.53,70.81 297.74,71.01 298.25,71.01 298.77,71.53 RE69.2
N137781553: length 5.7
  BOTTOM w0.14: JTS1.5 340.51,114.47 341.25,113.73 341.25,112.68 341.11,112.54 D74.1 341.16,112.05 341.44,112.05 341.53,112.13 RR44.2 RR43.2 342.44,112.83 v1(342.2,113.07)
N137787212: length 11.4
  BOTTOM w0.14: JTS.2 348.75,123.84 348.97,123.62 v4(348.97,116.3) 348.5,115.83 347.36,115.83 DI1.2
N137827497: length 2.6
  TOP w0.076: UE3.H2 297.52,78.28 297.12,78.68 v2(297.12,79.27)
  TOP w0.14: v2(274.12,79.27) 274.12,80.16 T6004.1
N137853671: length 2.6
  BOTTOM w0.14: v1(1.98,83.52) 1.98,83.05 CZ104.1
  BOTTOM w0.254: CZ104.1 2.6,82.43 UA3.6
N138188578: length 7.6
  BOTTOM w0.14: RV110.2 47.35,96.74 47.35,97.91 v1(47.01,98.25) 47.01,100.7 47.99,101.68 JEDP1.36
N138408347: length 1.2
  TOP w0.076: UE3.D6 v2(293.92,80.86)
  BOTTOM w0.076: v2(293.92,80.86) 294.32,80.46 T4948.1
N138608845: length 3.8
  TOP w0.14: PR1651.1 PR1643.2 244.54,174.08 v2(244.24,173.78) v1(244.24,173.21)
  BOTTOM w0.14: v2(244.24,173.78) 243.99,173.54 PU1600.9
N138923567: length 2.5
  TOP w0.076: v2(296.32,80.08) 295.94,80.46 UE3.F5
  BOTTOM w0.076: v2(296.32,80.08) 296.72,79.68 296.72,78.82 T6000.1
N139113922: length 2.7
  TOP w0.089: T6002.1 85.52,73.55 85.78,73.3 86.54,73.3 v2(86.86,73.61)
  BOTTOM w0.089: UH2.BD21 86.91,72.86 86.91,73.5 86.86,73.56 v2(86.86,73.61)
N139274499: length 2.3
  TOP w0.14: PU1901.4 61.34,82.98 PR1940.1 61.44,83.5 v1(62.05,84.1)
N139308180: length 6.1
  TOP w0.14: v2(241.67,180.59) 241.67,180.85 v1(242.34,181.52) PR952.1 242.34,183.01 242.57,183.25 243.76,183.25 244,183.01 PR951.2
  BOTTOM w0.14: v2(241.67,180.59) 241.67,180.83 241.33,181.18 PU900.9
N139527854: length 2.9
  TOP w0.14: v1(120.35,83.06) 120.7,82.71 CZ105.1 120.97,81.66 UZ29.6
N139871071: length 4.9
  TOP w0.14: v1(142.29,82.95) 142.14,82.8 R5832.2
  TOP w0.254: R5832.2 142.14,81.48 141.88,81.22 QH1.2 RH5868.2
N139871074: length 4
  TOP w0.14: QE20.1 136.89,81.74 138.23,83.08 v1(138.48,83.08) 138.99,83.08 139.12,82.95 RH5868.1
N140262314: length 2.4
  TOP w0.14: v1(126.71,81.59) RZ1952.2 125.68,81.66 UZ29.3
N140286428:
  vias: v1(75.5,97.03)
N140286440: length 3
  TOP w0.14: v1(78.33,97.71) 77.86,97.23 PR263.2
  TOP w0.406: PQ219.3 76.74,98.13 77.25,97.62 PR263.2
N140286558: length 3.2
  TOP w0.14: v2(70.04,90.34) 70.04,90.27 70.68,89.63 v1(70.85,89.63)
  TOP w0.305: PR295.1 69.08,90.24 69.3,90.46 69.91,90.46 v2(70.04,90.34)
  TOP w0.508: v2(71.26,91.59) 71.2,91.59 70.8,91.99 PQ225.2
N140286564: length 8.7
  TOP w0.508: PR276.2 69.37,95.26 PU204.4 69,95.11 PQ225.1 68.48,91.48 v1(67.92,90.92) 67.92,90.04 PC222.1 67.5,89.58 PR280.1
N140286576:
  vias: v1(68.5,97.72)
N140286584:
  vias: v1(73.11,96.51)
N140286624: length 4.1
  TOP w0.14: v2(76.15,97.81) 76.15,98.34 76.02,98.47 76.02,98.94 PQ219.2 ; v1(70.24,88.35) 69.62,88.97 PR271.2 69.44,88.97 PC221.1 68.82,89.42 68.69,89.29 68.31,89.29 v2(68.22,89.38)
N140286634: length 0.9
  TOP w0.254: PQ219.5 77.18,100.09 v2(77.18,99.5)
  vias: v1(69.57,99.38) v2(69.92,98.97)
N140583188: length 4.4
  TOP w0.14: v1(219.52,107.89) 218.98,108.43 UV29.4 218.49,108.92 218.48,108.91 RV1084.2 216.37,108.91 QV91.2
N140796616: length 4.3
  TOP w0.076: UE3.L2 299.92,77.87 300.24,77.56 300.24,76.57 300.58,76.23 v2(300.94,76.23)
  TOP w0.14: v2(269.47,75.63) 269.47,74.24 T6003.1
N141287628: length 7.5
  TOP w0.305: PQ219.6 76.72,100.55 76.24,100.55 75.89,100.9 v1(75.39,100.9) 74.63,100.13 74.27,100.13 73.66,99.52 72.67,99.52 72.26,99.93 72.26,100.33 PR290.2
N141348246: length 1.1
  BOTTOM w0.14: PC1601.1 240.06,170.24 v1(239.52,170.77)
N142820714: length 3.2
  TOP w0.14: v1(237.92,75.84) RD100.2 236.6,75.96 236.62,75.99 v2(236.62,76.54)
  BOTTOM w0.14: v2(236.62,76.54) JHDD.16
N143232395: length 1.9
  TOP w0.14: CE48.1 291.76,99.42 RE62.2 v1(290.69,100.16)
N143234416: length 4.6
  TOP w0.14: v1(237.29,120.41) 237.54,120.67 239.19,120.67 239.4,120.46 CZ2155.1 240.03,119.14 UZ30.6
N143234582: length 2
  TOP w0.14: UZ30.3 244.45,119.14 RZ1964.2
N143441212: length 0.8
  TOP w0.254: PR1115.2 116.26,170.15 PC1108.1
N143489306: length 4.2
  TOP w0.14: R5842.2 275.44,92.35 Q5.5 274.38,92.35 274.24,92.49 274.24,92.86 274.39,93 Q5.6 274.69,93.17 275.51,94 v1(275.89,94)
N143489317: length 2.7
  TOP w0.14: R5843.1 270.36,91.64 v1(270.18,91.46)
  TOP w0.381: Q5.3 271.89,91.7 R5843.1
N143674886: length 2.5
  TOP w0.14: UZ26.2 v1(106.93,113.8) 106.93,113.27 RZ1953.2
N144550342: length 3.4
  TOP w0.14: v1(188.01,110.89) 188.01,110.46 RZ72.2 185.98,109.49 185.81,109.66 UZ16.4
N144805281: length 2.8
  TOP w0.14: v1(273.32,73.18) 272.71,73.18 CZ39.1
  TOP w0.254: UZ32.6 272.22,73.68 CZ39.1
N146950564: length 5.1
  BOTTOM w0.254: 102.29,131.59 102.41,131.72 104.06,131.72 104.32,131.46 104.32,131.01 104.89,130.44 PU800.13
  BOTTOM w0.381: 102.29,131.59 v1(102,131.3) 101.9,131.21 PR819.1
N12449474450: length 3.7
  BOTTOM w0.081: 22.63,121.14 22.63,121.3 22.63,121.31 22.63,122.32 UT4.B9
  BOTTOM w0.14: T191.1 22.95,119.42 22.95,120.82 22.63,121.14
N12449474451: length 1.6
  BOTTOM w0.081: 22.38,121.14 UT4.A9
  BOTTOM w0.14: 22.38,121.14 22.38,120.68 T192.1
N14929602318: length 2.6
  TOP w0.203: PR1925.1 47.28,86.35 PU1900.27

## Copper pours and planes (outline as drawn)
1.2V_B+ on TOP (solid shape): 274.65,100.16 274.86,100.09 275.07,100.16 275.77,100.16 275.89,100.03 275.89,97.94 275.32,97.36 273.29,97.36 273.04,97.11 273.04,96.54 272.97,96.47 272.47,96.47 272.41,96.53 272.41,96.95 271.55,97.81 271.55,99.84 271.87,100.16
1.2V_B+ on BOTTOM (solid shape): 273.42,100.19 273.42,100.16 273.45,100.16 273.49,100.12 273.74,100.12 273.74,100.12 273.94,100.12 273.99,100.07 274.86,100.07 274.96,100.08 275.05,100.12 276.39,100.12 276.63,99.88 276.63,99.48 276.97,99.48 277.01,99.44 277.01,98.94 276.55,98.94 276.54,98.92 276.48,98.92 276.48,98.9 276.46,98.88 276.46,98.2 276.49,98.16 277,98.16 277.01,98.15 277.01,97.73 276.55,97.73 276.54,97.72 276.48,97.72 276.48,97.7 276.46,97.68 276.46,96.98 276.48,96.96 277,96.96 277.01,96.96 277.01,96.28 276.23,95.5 276.23,93.92 276.02,93.72 275.08,93.72 275.04,93.76 275.04,95.99 274.65,96.38 274.58,96.38 274.56,96.4 272.52,96.4 272.42,96.51 272.42,96.97 272.21,97.17 270.94,97.17 270.31,97.81 270.31,100.6 270.43,100.73 272.88,100.73
5VS_FAN2 on BOTTOM (solid shape): 336.81,122.41 336.81,119.86 334.84,117.89 334.84,117.64 334.51,117.31 333.01,117.31 332.92,117.4 332.92,119.17 334.54,120.8 335.64,120.8 335.84,121 335.84,121.26 335.84,121.27 335.86,121.39 335.84,121.52 335.84,121.53 335.84,121.86 335.61,122.09 334.26,122.09 334.11,122.24 334.11,122.59 334.28,122.75 336.47,122.75
+0.6VS on TOP (solid shape): 280.13,95.22 280.64,95.22 280.64,95.75 280.93,95.75 280.93,95.22 281.44,95.22 281.44,95.75 282.21,95.75 282.37,95.59 282.37,93.48 281.37,92.47 280.37,92.47 280.36,92.48 279.47,92.48 279.15,92.79 279.15,95.59 279.31,95.75 280.13,95.75
+0.6VS on TOP (solid shape): 172.32,86.12 173.11,86.12 173.34,86.03 173.57,86.12 174.16,86.12 174.39,86.03 174.63,86.12 175.51,86.12 175.66,85.97 175.66,85.04 175.65,85.04 175.65,84.57 175.17,84.08 171.45,84.08 171.26,84.27 171.26,86.43 171.32,86.49 171.95,86.49
+0.6VS on TOP (solid shape): outline of 274 points within 247.09,78.81 255.07,88.14
+0.6VSP on TOP (solid shape): 285.59,99.37 285.59,99.37 285.63,99.33 285.63,98.02 284.33,96.73 283.07,96.73 282.22,95.88 281.31,95.88 281.31,95.34 281.06,95.34 281.06,95.88 280.51,95.88 280.51,95.34 280.26,95.34 280.26,95.88 279.3,95.88 279.2,95.98 279.2,96.18 279.24,96.19 279.51,96.54 279.24,96.88 279.2,96.89 279.2,98.45 279.29,98.55 279.91,98.55 280.21,98.25 283.9,98.25 284.02,98.13 284.64,98.13 284.9,98.39 284.9,99.37 285.08,99.54 285.41,99.54
+0.6VSP on BOTTOM (solid shape): 284.38,97.77 284.98,97.77 285.05,97.69 285.05,97.58 284.98,97.51 283.11,97.51 282.94,97.68 282.94,98.19 283.01,98.25 283.9,98.25
+0.95VS_VCCIOP on TOP (solid shape): 113.33,127.02 113.33,124.61 111.94,123.21 110.41,123.21 110.16,123.46 110.16,124.99 109.87,125.28 109.87,125.46 110.16,125.75 110.16,126.89 110.44,127.17 113.18,127.17
+0.95VS_VCCIOP on BOTTOM (solid shape): 113.24,126.87 113.24,123.62 112.83,123.21 108.25,123.21 107.83,123.63 107.83,126.85 108.13,127.15 112.96,127.15
+1.2V_DDR on BOTTOM (solid shape): 12.39,132.87 12.39,132.19 12.29,132.1 11.48,132.1 10.57,133 10.57,133.22 10.74,133.39 11.87,133.39
+1.2V_DDR on BOTTOM (solid shape): outline of 363 points within 243.32,88.22 256.53,107.33
+1.2V_DDR on TOP: outline of 144 points within 107,83.05 257.2,117.56 ; 1 cut-out
+1.2V_DTH on BOTTOM (solid shape): outline of 210 points within 10.76,126.6 22.86,143.86
+1.2V_MEN_P on BOTTOM (solid shape): 281.57,98.84 281.57,97.84 281.04,97.84 281.04,97.4 281.57,97.4 281.57,97.11 281.52,97.05 280.64,97.05 280.2,97.49 280.2,98.88 280.34,99.01 281.4,99.01
+1.2V_MEN_P on BOTTOM (solid shape): 261.66,100.65 261.66,96.89 260.91,96.14 260.89,96.14 258.81,94.07 258.81,93.11 257.92,92.22 255.33,92.22 255.33,92.16 255.32,92.16 255.32,91.64 254.87,91.64 254.87,92.16 254.85,92.16 254.85,92.16 254.14,92.16 254.14,92.16 254.12,92.16 254.12,91.64 253.67,91.64 253.67,92.16 253.65,92.16 253.65,92.16 252.96,92.16 252.96,94.77 253.44,95.25 253.44,98.15 256.24,98.15 256.24,98.1 256.25,98.05 256.26,98 256.29,97.95 256.32,97.9 256.35,97.86 256.4,97.83 256.44,97.8 256.49,97.78 256.54,97.77 256.6,97.77 256.65,97.77 256.7,97.78 256.75,97.8 256.8,97.83 256.84,97.86 256.88,97.9 256.91,97.95 256.93,98 256.95,98.05 256.95,98.1 256.95,98.15 256.95,98.2 256.93,98.26 256.91,98.3 256.88,98.35 256.84,98.39 256.8,98.42 256.75,98.45 256.7,98.47 256.65,98.48 256.6,98.48 256.54,98.48 256.49,98.47 256.44,98.45 256.4,98.42 256.35,98.39 256.32,98.35 256.29,98.3 256.26,98.26 256.25,98.2 256.24,98.15 253.44,98.15 253.44,99.17 253.92,99.65 258.19,99.65 259.07,100.53 259.07,100.71 259.13,100.76 261.54,100.76
+1.2V_VCCPLL_OC on TOP (solid shape): 183.07,114.16 183.07,113.59 183.28,113.39 185.1,113.39 185.32,113.16 185.32,112.5 185.17,112.35 182.44,112.35 182.19,112.6 182.19,114.21 182.29,114.3 182.92,114.3
+1.8V_3.3V_ALW_VTR3 on TOP (solid shape): 275.01,71.52 275.01,70.88 275.13,70.76 275.64,70.76 275.77,70.63 275.77,69.84 275.6,69.68 274.43,69.68 274.24,69.88 274.24,71.5 274.39,71.65 274.88,71.65
+1.8V_GFX_AON on TOP (solid shape): 213.47,115.86 213.47,113.39 213.18,113.1 212.61,113.1 212.28,112.76 211.44,112.76 211.34,112.86 211.34,113.56 211.5,113.71 212.43,113.71 212.67,113.95 212.67,115.32 212.44,115.54 211.99,115.54 211.95,115.59 211.95,116.1 212.01,116.16 213.16,116.16
+1.8V_GFX_AON on TOP (solid shape): 206.69,118.79 206.69,117.67 206.59,117.57 206.59,116.85 206.49,116.75 205.09,116.75 204.99,116.77 204.89,116.75 204.71,116.75 204.56,116.91 204.56,118.53 204.95,118.93 206.55,118.93
+1.8V_GFX_AON on TOP (solid shape): 198.2,120.77 198.2,119.19 198.32,119.07 199.59,119.07 199.69,118.97 199.69,117.97 199.67,117.94 199.67,116.38 198.86,115.56 198.42,115.56 198.39,115.59 198.04,115.59 197.97,115.53 197.67,115.53 197.67,115.23 197.66,115.22 197.66,115.18 197.18,114.7 197.16,114.7 196.98,114.62 196.9,114.44 196.9,114.42 196.78,114.3 196.78,114.08 196.75,114.06 196.72,114.04 195.92,113.24 195.92,112.91 195.62,112.61 194.99,112.61 194.97,112.63 194.97,113.84 195.07,113.94 195.73,113.94 195.77,113.98 195.77,114.04 195.77,114.75 195.77,114.9 195.77,115.59 195.92,115.74 196.95,115.74 196.95,115.75 197.51,116.31 197.51,116.55 197.76,116.81 197.76,117.14 197.94,117.32 198.53,117.32 198.65,117.44 198.65,118.26 198.58,118.33 198.12,118.33 197.41,119.04 197.41,119.93 197.09,120.25 197.09,120.79 197.28,120.99 197.98,120.99
+1.8V_GFX_AON on TOP (solid shape): 230.02,118.75 230.02,116.32 228.91,115.22 225.65,115.22 225.26,114.82 225.26,113.6 224.68,113.03 224.68,112.69 224.45,112.45 224.2,112.45 224.06,112.59 224.06,114.44 223.73,114.77 221.54,114.77 221.34,114.57 221.34,112.85 220.85,112.36 218.69,112.36 218.16,111.83 216.97,111.83 216.85,111.96 216.85,112.56 216.95,112.67 217.49,112.67 217.81,113 217.97,113 218.23,112.88 218.5,113 220.29,113 220.65,113.36 220.65,115.3 220.05,115.91 219.33,115.91 219.27,115.92 219.2,115.92 219.13,115.99 219.13,116.5 219.22,116.59 220.09,116.59 220.1,116.6 222.63,116.6 222.78,116.45 222.78,115.94 222.79,115.93 222.79,115.83 222.85,115.78 222.85,115.7 222.84,115.64 222.83,115.57 223.04,115.27 223.4,115.3 223.52,115.46 223.54,115.66 223.56,115.75 223.64,115.78 224.59,115.78 224.64,115.83 224.64,116.33 224.91,116.6 227.66,116.6 229.17,118.12 229.17,118.73 229.27,118.83 229.94,118.83
+1.8V_GFX_AON on TOP (solid shape): outline of 1448 points within 211.52,116.99 241.17,132.14
+1.8V_GFX_AON on BOTTOM (solid shape): 213,131.95 213,131.83 213.21,131.62 213.21,131.27 213.39,131.09 213.39,130.9 213.26,130.77 213,130.77 212.75,130.88 212.5,130.77 212.32,130.77 211.83,131.26 211.83,131.97 211.99,132.13 212.82,132.13
+1.8V_GFX_AON on BOTTOM (solid shape): outline of 455 points within 196.46,114.29 213.68,122.13
+1.8V_GFX_RUN on TOP (solid shape): 190.8,156.1 190.8,153.4 190.3,152.89 188.62,152.89 188.14,153.36 188.14,155.09 189.31,155.09 189.31,155.03 189.31,154.98 189.33,154.93 189.35,154.88 189.38,154.84 189.42,154.8 189.46,154.76 189.51,154.74 189.56,154.72 189.61,154.71 189.66,154.7 189.71,154.71 189.77,154.72 189.82,154.74 189.86,154.76 189.9,154.8 189.94,154.84 189.97,154.88 189.99,154.93 190.01,154.98 190.02,155.03 190.02,155.09 190.01,155.14 189.99,155.19 189.97,155.24 189.94,155.28 189.9,155.32 189.86,155.35 189.82,155.38 189.77,155.4 189.71,155.41 189.66,155.42 189.61,155.41 189.56,155.4 189.51,155.38 189.46,155.35 189.42,155.32 189.38,155.28 189.35,155.24 189.33,155.19 189.31,155.14 189.31,155.09 188.14,155.09 188.14,156.16 188.59,156.61 190.3,156.61
+1.8V_GFX_RUN on TOP (solid shape): outline of 266 points within 192.88,123.57 199.82,133.57
+1.8V_GFX_RUN on TOP (solid shape): outline of 943 points within 206.5,116.06 211.33,131.02
+1.8V_GFX_RUN on BOTTOM (solid shape): 197.73,124.29 197.73,123.84 197.41,123.53 197.41,122.57 197.15,122.32 195.76,122.32 195.57,122.51 195.57,124.54 195.88,124.86 197.15,124.86
+1.8V_GFX_RUN_R on TOP (solid shape): outline of 1393 points within 191.22,134.31 200.76,152.1
+1.8V_GFX_RUN_R on BOTTOM (solid shape): outline of 486 points within 192.57,134.9 200.01,148.49
+1.8V_PCH on TOP (solid shape): 122.59,81.22 122.59,79.76 122.25,79.43 121.66,79.43 121.34,79.1 121.34,78.15 121.3,78.12 117.53,78.12 117.4,78.25 117.4,80.13 117.77,80.5 117.77,80.54 118.29,80.54 118.29,80.54 119.36,80.54 120.11,81.3 122.51,81.3
+1.8V_PCH on TOP (solid shape): outline of 893 points within 87.79,76.89 100.03,83.46
+1.8V_PCH on BOTTOM (solid shape): outline of 152 points within 89.68,73.64 92.04,78.45
+1.8V_PCH_I_LDO on BOTTOM (solid shape): 88.82,81.17 88.82,80.85 88.63,80.66 87.49,80.66 87.17,80.98 87.17,81.17 87.3,81.3 88.7,81.3
+1.8V_PCH_LDO on TOP (solid shape): 88.84,82.78 88.84,82.51 88.65,82.32 88.65,81.59 88.57,81.51 88.06,81.51 87.46,82.11 87.46,82.85 87.6,82.99 88.63,82.99
+1.8V_PCH_LDO on BOTTOM (solid shape): 88.84,82.78 88.84,82.16 88.82,82.11 88.81,82.07 88.34,81.61 87.18,81.61 87.09,81.69 87.09,81.89 87.64,82.44 87.86,82.44 87.99,82.3 88.27,82.3 88.37,82.4 88.37,82.76 88.47,82.86 88.77,82.86
+1.8V_PLLVDD on TOP (solid shape): 202.23,128.99 202.23,128.03 200.96,126.76 200.96,124.67 200.71,124.41 199.31,124.41 199,124.73 199,126.13 197.66,127.46 197.66,128.8 197.73,128.86 198.17,128.86 198.23,128.8 198.23,127.91 198.87,127.27 200.2,127.27 200.77,127.84 200.77,128.99 200.84,129.05 202.17,129.05
+1.8V_PLLVDD on BOTTOM (solid shape): 200.38,125.62 200.47,125.57 200.46,125.46 200.7,125 200.94,125.46 200.93,125.57 201.02,125.62 201.09,125.62 201.22,125.49 201.22,125.37 201.21,125.29 201.22,125.21 201.22,123.52 201.03,123.34 199.45,123.34 199.44,123.32 199.42,123.32 199.31,123.21 199.31,121.3 199.11,121.1 196.31,121.1 196.21,121.19 196.21,122.01 196.39,122.19 197.21,122.19 197.22,122.19 197.6,122.57 197.6,123.46 197.92,123.78 197.92,124.54 198.3,124.92 199.25,124.92 199.38,125.05 199.38,125.3 199.69,125.62
+1.8VALW on TOP (solid shape): 273.51,71.49 273.51,70.2 273.57,70.13 273.57,69.83 273.43,69.69 271.96,69.69 271.86,69.78 271.86,71.42 272.08,71.65 273.35,71.65
+1.8VALW on TOP (solid shape): 244.14,118.38 246.56,118.38 246.68,118.26 246.68,117.56 246.11,116.99 243.26,116.99 242.56,117.68 242.56,118.7 242.62,118.76 243.76,118.76
+1.8VALW on TOP (solid shape): outline of 130 points within 120.1,70 130.1,81.3
+1.8VALW on BOTTOM (solid shape): 3.96,79.25 3.96,77.61 3.96,77.6 3.96,76.97 3.82,76.84 2.98,76.84 2.86,76.95 2.86,79.25 2.97,79.36 3.85,79.36
+1.8VALW on BOTTOM (solid shape): 241.39,163.67 241.39,163.12 242.14,163.12 242.14,163.67 242.15,163.68 242.58,163.68 242.59,163.67 242.59,163.12 243.34,163.12 243.34,163.67 243.35,163.68 243.87,163.68 244.12,163.42 244.12,160.34 243.74,159.96 240.89,159.96 240.61,160.24 240.61,162.98 240.62,162.99 240.62,163.46 240.84,163.68 241.38,163.68
+1.8VALW on BOTTOM (solid shape): 250.65,80.28 250.65,77.13 246.44,72.93 244.54,72.93 244.01,72.4 243.84,72.4 242.96,71.51 242.96,71.35 239.95,68.34 229.92,68.34 229.03,69.23 229.03,70.02 237.57,70.02 237.57,69.97 237.57,69.92 237.59,69.86 237.61,69.82 237.64,69.77 237.68,69.73 237.72,69.7 237.77,69.67 237.82,69.65 237.87,69.64 237.92,69.64 237.97,69.64 238.03,69.65 238.08,69.67 238.12,69.7 238.16,69.73 238.2,69.77 238.23,69.82 238.25,69.86 238.27,69.92 238.28,69.97 238.28,70.02 238.27,70.07 238.25,70.13 238.23,70.17 238.2,70.22 238.16,70.26 238.12,70.29 238.08,70.32 238.03,70.34 237.97,70.35 237.92,70.35 237.87,70.35 237.82,70.34 237.77,70.32 237.72,70.29 237.68,70.26 237.64,70.22 237.61,70.17 237.59,70.13 237.57,70.07 237.57,70.02 229.03,70.02 229.03,71.65 229.54,72.15 235.76,72.15 236.52,72.92 239,72.92 239.19,73.11 239.19,73.93 239.43,74.17 241.68,74.17 241.86,74.35 241.86,76.11 243,77.25 244.71,77.25 246.88,79.43 246.88,80.57 247.23,80.92 250.01,80.92
+1.8VS_AUDIO on BOTTOM (solid shape): 6.02,81.55 6.02,79.7 5.91,79.58 5.91,79.58 5.58,79.25 5.58,78.81 5.54,78.76 4.33,78.76 4.22,78.87 4.22,79.91 4.43,80.12 4.43,80.61 4.26,80.79 3.83,80.79 3.76,80.72 3.04,80.72 2.96,80.8 2.96,81.73 3.04,81.81 5.77,81.81
+1.35VS_B+ on TOP (solid shape): 197.66,180.23 197.66,178.96 197.54,178.83 195.88,178.83 195.38,179.34 193.98,179.34 193.03,178.39 192.52,178.39 192.46,178.45 192.46,180.1 192.71,180.36 197.54,180.36
+1.35VS_B+ on BOTTOM (solid shape): 196.88,182.07 196.88,181.62 196.86,181.59 195.91,181.59 195.91,180.07 196.01,179.98 196.47,179.98 196.47,179.98 197.54,179.98 197.66,179.85 197.66,178.83 197.54,178.71 197.51,178.71 197.35,178.75 197.19,178.71 197.18,178.71 196.94,178.71 196.93,178.71 196.77,178.75 196.62,178.71 196.61,178.71 196.36,178.71 196.35,178.71 196.2,178.75 196.05,178.71 196.04,178.71 195.88,178.71 195.85,178.67 195.82,178.69 195.38,178.64 195.33,178.2 195.35,178.17 195.12,177.95 191.31,177.95 191.06,178.2 191.06,179.09 192.33,180.36 192.33,181.68 192.76,182.11 196.84,182.11
+1.35VS_VGAP on TOP (solid shape): 214.2,186.3 214.2,182.42 213.41,181.63 210.24,181.63 209.34,182.52 206.29,182.52 205.66,183.15 205.66,185.44 206.11,185.88 213.09,185.88 213.66,186.45 214.05,186.45
+1.35VS_VGAP on BOTTOM (solid shape): 214.2,186.3 214.2,182.36 213.55,181.7 207.52,181.7 206.93,181.12 204.52,181.12 204.39,181.25 204.39,185.76 204.52,185.88 212.84,185.88 213.41,186.45 214.05,186.45
+1.35VSDGPU on TOP (solid shape): 209.6,180.5 209.6,179.26 209.56,179.23 202.12,179.23 202.01,179.34 202.01,180.42 202.17,180.59 209.52,180.59
+1.35VSDGPU on TOP (solid shape): 211.21,146.94 211.21,145.84 210.87,145.5 207.62,145.5 207.57,145.55 207.57,146.65 207.89,146.97 211.19,146.97
+1.35VSDGPU on TOP (solid shape): 217.34,186.47 217.34,183.55 217.68,183.2 218.47,183.2 218.54,183.13 218.54,182.85 218.03,182.34 218.03,181.65 218.57,181.12 218.57,179.06 218.39,178.88 215.01,178.88 214.36,179.54 214.36,183.69 214.9,183.69 214.91,183.7 214.91,186.43 215.32,186.84 216.97,186.84
+1.35VSDGPU on TOP (solid shape): 221.46,155.15 221.67,155.15 221.75,155.07 221.75,154.64 221.64,154.54 220.39,154.54 220.1,154.25 219.44,154.25 219.44,154.26 219.05,154.26 218.98,154.33 218.1,154.33 217.98,154.45 217.29,154.45 217.21,154.53 217.21,155.15 217.21,155.15 217.21,155.29 217.23,155.31 221.3,155.31
+1.35VSDGPU on TOP (solid shape): 205.57,146.86 205.57,145.64 205.43,145.5 204.79,145.5 204.72,145.43 202.61,145.43 202.54,145.44 202.48,145.43 201.86,145.43 201.69,145.61 201.69,146.69 201.79,146.78 202.06,146.78 202.23,146.96 205.47,146.96
+1.35VSDGPU on TOP (solid shape): 243.68,129.79 243.97,129.79 244.12,129.65 244.12,129.33 243.9,129.11 241.67,129.11 241.49,129.29 241.49,129.72 242.35,129.72 242.35,129.67 242.36,129.62 242.38,129.57 242.4,129.52 242.43,129.48 242.47,129.45 242.51,129.41 242.56,129.39 242.6,129.37 242.66,129.37 242.71,129.37 242.76,129.37 242.81,129.39 242.86,129.41 242.9,129.45 242.93,129.48 242.96,129.52 242.99,129.57 243,129.62 243.01,129.67 243.01,129.72 243,129.77 242.99,129.82 242.96,129.87 242.93,129.91 242.9,129.95 242.86,129.98 242.81,130 242.76,130.02 242.71,130.03 242.66,130.03 242.6,130.02 242.56,130 242.51,129.98 242.47,129.95 242.43,129.91 242.4,129.87 242.38,129.82 242.36,129.77 242.35,129.72 241.49,129.72 241.49,129.91 241.59,130.02 242.32,130.02 242.49,130.19 242.55,130.16 242.6,130.15 242.66,130.14 242.71,130.15 242.76,130.16 242.82,130.18 242.84,130.2 243.28,130.2
+1.35VSDGPU on TOP (solid shape): outline of 83 points within 246.24,145.5 248.91,149.18
+1.35VSDGPU on BOTTOM (solid shape): 217.34,186.47 217.34,183.55 217.68,183.2 218.47,183.2 218.54,183.13 218.54,182.85 218.03,182.34 218.03,181.65 218.57,181.12 218.57,179.06 218.39,178.88 215.01,178.88 214.36,179.54 214.36,183.69 214.9,183.69 214.91,183.7 214.91,186.43 215.32,186.84 216.97,186.84
+1.35VSDGPU on BOTTOM (solid shape): outline of 142 points within 197.9,130.73 214.33,147.22
+1V_MPHY_MPHYPLL on BOTTOM (solid shape): outline of 88 points within 67.8,91.65 73.36,94.59
+1V_PCH on TOP (solid shape): outline of 3973 points within 72.21,78.17 111.05,98
+1V_PCH on BOTTOM (solid shape): 84.62,86.21 84.62,85.99 84.73,85.89 85.07,85.89 85.19,85.76 85.19,85.43 84.93,85.17 82.52,85.17 82.1,84.76 81.82,84.76 81.71,84.87 81.71,85.74 82.32,86.35 84.49,86.35
+1V_PCH on BOTTOM (solid shape): 88.44,85.85 88.44,84.83 88.27,84.66 85.57,84.66 85.52,84.71 85.52,85.15 85.81,85.44 85.83,85.44 85.89,85.46 85.95,85.49 86.25,85.49 86.38,85.36 86.65,85.36 86.75,85.47 87.12,85.47 87.21,85.38 87.46,85.38 88.05,85.97 88.31,85.97
+1V_PCH on BOTTOM (solid shape): 82.46,83.14 82.46,82.81 82.4,82.75 82.4,82.36 82.47,82.29 82.47,82.08 82.3,81.91 82.3,81.13 81.99,80.82 81.48,80.82 81.25,81.05 81.25,82.15 81.1,82.3 81.1,82.78 81.31,82.99 81.85,82.99 81.97,83.12 81.98,83.12 82.05,83.15 82.1,83.19 82.41,83.19
+1V_PCH on BOTTOM (solid shape): 102.44,95.17 102.44,94.13 102.21,93.9 100.55,93.9 100.55,94.04 99.71,94.04 99.71,93.9 97.89,93.9 96.87,92.87 96.76,92.87 96.52,92.63 96.32,92.63 96.14,92.81 96.14,93.11 95.99,93.26 95.65,93.26 95.55,93.36 95.55,93.55 95.65,93.64 96.6,93.64 96.74,93.79 96.74,94.17 97.28,94.71 97.28,95.06 97.43,95.22 102.3,95.22 102.34,95.26
+1V_PCH on BOTTOM (solid shape): 116.14,83.94 116.14,82.52 116.11,82.51 115.95,82.37 115.9,82.17 115.9,82.15 115.55,81.8 112.07,81.8 111.71,81.43 111.71,80.79 112.64,79.86 112.64,79.23 112.11,79.23 112.11,78.73 112.64,78.73 112.64,78.43 112.11,78.43 112.11,77.93 112.64,77.93 112.64,77.54 111.78,77.54 111.66,77.66 110.82,77.66 110.76,77.72 110.8,77.76 110.82,77.77 111.08,78.26 110.53,78.39 110.47,78.37 110.4,78.39 110.19,78.48 109.97,78.41 109.45,78.41 109.2,78.17 108.62,78.17 108.41,78.38 108.41,83.85 108.46,83.94 108.48,84.04 108.49,84.06 108.54,84.12 115.96,84.12
+1V_PCH_CLK5 on BOTTOM (solid shape): 100.03,89.56 100.03,88.68 99.87,88.52 99.87,87.73 99.5,87.36 99.5,85.92 99.44,85.86 98.91,85.86 98.83,85.93 98.83,86.69 98.76,87.15 98.3,87.09 98.23,87.05 98.16,87.07 97.8,87.11 97.64,86.78 97.61,86.7 97.54,86.67 96.95,86.67 96.29,87.33 95.8,87.33 95.74,87.39 95.68,87.39 95.42,87.64 95.42,87.74 95.53,87.85 98.55,87.85 98.77,88.07 98.77,89.07 99.32,89.62 99.97,89.62
+1V_PCH_PRIM on TOP (solid shape): 84.1,83.84 84.1,83.83 84.15,83.78 84.15,83.17 84.27,83.05 84.41,83.05 84.66,82.79 84.66,82.25 84.1,81.68 84.1,81.17 83.97,81.04 83.16,81.04 82.73,81.48 82.73,83.71 82.93,83.91 84.02,83.91
+1V_PCH_PRIM on BOTTOM (solid shape): 83.38,83.86 83.64,83.86 83.76,83.98 84.02,83.98 84.14,83.86 84.56,83.86 84.69,83.73 84.69,81.81 84.4,81.53 84.09,81.53 83.75,81.86 83.75,81.95 83.59,82.11 83.29,82.11 82.76,81.58 82.6,81.58 82.44,81.74 82.44,81.88 82.57,82.01 82.6,82.04 82.6,82.43 82.53,82.5 82.53,82.64 82.57,82.69 82.57,83.19 82.51,83.25 82.51,83.55 82.96,83.99 83.25,83.99
+1V_PCH_PRIM on BOTTOM (solid shape): 87.05,83.97 87.05,83.95 87.31,83.69 87.54,83.69 87.83,83.39 87.83,82.87 87.39,82.43 87.26,82.43 86.98,82.7 86.98,82.71 86.84,82.85 86.32,82.85 86.17,82.69 86.17,81.91 85.56,81.29 85.31,81.29 85.18,81.42 85.18,81.6 85.28,81.7 85.28,82.07 85.16,82.19 85.16,82.38 85.25,82.51 85.26,82.67 85.25,82.69 85.2,82.76 85.15,82.81 85.15,83.02 85.31,83.19 85.31,83.27 85.32,83.28 85.32,83.53 85.16,83.69 85.16,83.83 85.7,84.37 86.64,84.37
+1V_PCH_PRIM on BOTTOM (solid shape): 117.4,81.43 117.4,81.18 117.35,81.1 117.26,81.08 116.78,80.75 117.26,80.42 117.35,80.41 117.4,80.32 117.4,80.03 117.14,79.77 117.02,79.77 117.02,80.16 116.98,80.19 115.53,80.19 115.49,80.16 115.49,79.77 115.37,79.77 115.14,80 112.85,80 112.04,80.82 112.04,81.26 112.42,81.64 117.18,81.64
+1VALW on TOP (solid shape): 180.01,153.21 180.06,153.18 180.1,153.15 180.15,153.13 180.21,153.12 180.26,153.12 180.31,153.12 180.37,153.13 180.42,153.15 180.46,153.17 180.51,153.2 180.55,153.24 180.58,153.28 180.61,153.33 180.63,153.38 180.64,153.44 181.32,153.44 181.89,152.86 181.89,150.26 181.38,149.75 177.2,149.75 177.18,149.77 177.15,149.8 177.14,149.82 177.14,151.31 177.22,151.39 178.4,151.39 178.53,151.52 178.53,152.27 179.6,152.27 179.6,152.22 179.61,152.16 179.62,152.11 179.65,152.06 179.68,152.02 179.71,151.98 179.75,151.95 179.8,151.92 179.85,151.9 179.9,151.89 179.95,151.89 180.01,151.89 180.06,151.9 180.11,151.92 180.16,151.95 180.2,151.98 180.23,152.02 180.26,152.06 180.29,152.11 180.3,152.16 180.31,152.22 180.31,152.27 180.3,152.32 180.29,152.37 180.26,152.42 180.23,152.46 180.2,152.5 180.16,152.54 180.11,152.56 180.06,152.58 180.01,152.59 179.95,152.6 179.9,152.59 179.85,152.58 179.8,152.56 179.75,152.54 179.71,152.5 179.68,152.46 179.65,152.42 179.62,152.37 179.61,152.32 179.6,152.27 178.53,152.27 178.53,152.32 178.87,152.66 178.87,153.23 178.9,153.27 178.91,153.27 179.07,153.44 179.79,153.44
+1VALW on BOTTOM (solid shape): 192.22,123.38 192.22,120.68 191.88,120.35 190.36,120.35 189.92,120.8 189.92,122.38 189.47,122.83 189.47,124.56 189.64,124.73 190.87,124.73
+1VALW on BOTTOM (solid shape): 182.3,152.06 182.3,149.58 182.27,149.55 180.63,149.55 180.56,149.61 179.9,149.61 179.53,149.98 178.77,149.98 178.67,150.08 178.67,150.59 178.74,150.66 179.36,150.66 179.44,150.58 180.46,150.58 180.62,150.74 180.62,151.89 180.35,152.16 180.35,152.22 180.33,152.23 180.33,152.34 180.34,152.35 180.34,153 180.45,153.1 181.26,153.1
+1VALW on BOTTOM (solid shape): outline of 1214 points within 112.78,74.07 180.24,99.97
+1VS_GFX on TOP (solid shape): 223.09,184.43 223.09,182.45 222.87,182.23 221.49,182.23 220.27,183.45 220.27,184.17 220.62,184.52 223,184.52
+1VS_GFX on BOTTOM (solid shape): 221.47,184.56 221.63,184.52 221.79,184.56 221.8,184.57 222.92,184.57 223.06,184.42 223.06,183.22 223,183.15 222.44,183.15 222.44,182.64 223,182.64 223.06,182.58 223.06,181.31 222.72,180.97 220.07,180.97 219.58,181.46 219.58,184.18 219.97,184.57 221.46,184.57
+1VSP on TOP (solid shape): 124.83,73.61 124.83,72.85 124.59,72.61 122.1,72.61 121.74,72.26 121.74,71.72 121.82,71.65 122.3,71.65 122.53,71.87 124.28,71.87 124.54,71.62 124.54,70.96 124.53,70.96 124.53,70.81 124.35,70.63 117.78,70.63 117.61,70.8 117.61,72.43 117.53,72.51 117.53,73.32 118.17,73.97 124.47,73.97
+1VSP on BOTTOM (solid shape): 124.83,74.12 124.83,71.13 124.29,70.6 124,70.6 123.98,70.57 123.79,70.57 123.77,70.55 117.36,70.55 117.12,70.8 117.12,73.21 117,73.33 117,73.83 117.11,73.94 117.7,73.94 117.75,73.94 117.76,73.94 117.76,74 117.76,74.47 117.77,74.48 118.21,74.48 118.23,74.47 118.23,73.95 118.24,73.94 118.94,73.94 118.95,73.95 118.95,74.48 119.41,74.48 119.42,74.47 119.42,73.94 119.43,73.93 120.51,73.93 121.26,74.69 124.26,74.69
+2.5V_MEM on TOP (solid shape): outline of 87 points within 173.6,83.9 179.72,96.2
+2.5V_MEM on BOTTOM (solid shape): 248.21,96.86 248.21,93.81 248.03,93.63 247.38,93.63 247.27,93.74 247.27,95.33 247.29,95.35 247.29,96.57 247.64,96.92 248.15,96.92
+2.5V_MEM on BOTTOM (solid shape): 175.31,96.41 175.31,95.37 173.59,93.65 171.07,93.65 170.97,93.74 170.97,96.37 171.15,96.54 175.18,96.54
+3.3V_1.8V_PGPPA on TOP (solid shape): 117.14,79.52 117.14,77.62 117.57,77.19 117.57,76.39 117.53,76.35 116.26,76.35 116,76.6 116,76.6 116,79.63 116.18,79.81 116.86,79.81
+3.3VDX_SSD on TOP (solid shape): 277.8,78.12 277.8,76.98 275.77,74.95 275.77,73.36 275.64,73.23 273.71,73.23 273.44,73.51 272.91,73.51 272.78,73.64 272.78,74.12 272.58,74.32 272.58,75.5 272.66,75.58 273.23,75.58 274.12,76.47 275.01,76.47 275.13,76.6 275.13,77.62 275.26,77.74 275.97,77.74 276.39,77.64 276.63,78 276.63,78.23 276.66,78.25 277.67,78.25
+3.3VDX_SSD on BOTTOM (solid shape): outline of 573 points within 264.97,71.18 273.94,89.93
+3V_LDOP on TOP (solid shape): 71.65,96.07 71.65,95.12 72.61,94.17 72.61,93.7 71.97,93.07 71.67,93.07 71.44,93.3 71.43,93.36 71.41,93.42 71.41,93.75 71.41,93.75 71.41,94.05 69.98,95.48 69.98,95.61 70.96,96.59 71.14,96.59
+3V_PCH on TOP (solid shape): outline of 82 points within 97.71,68.25 100.53,73.53
+3V_PCH on TOP (solid shape): outline of 187 points within 83.45,67.86 94.46,74.83
+3V_PCH on TOP (solid shape): outline of 212 points within 104.83,68.59 115.14,76.9
+3V_PCH on TOP (solid shape): outline of 217 points within 76.45,78.22 86.41,89.25
+3V_PCH on TOP (solid shape): outline of 801 points within 56.23,67.86 76.2,83.19
+3V_PCH on BOTTOM (solid shape): 93.78,74.99 93.78,73.48 93.7,73.4 93.56,73.4 93.31,73.65 93.31,73.92 92.67,74.57 92.67,75.14 92.74,75.21 93.55,75.21
+3V_PCH on BOTTOM (solid shape): 79.59,84.17 79.59,84.16 79.68,84.07 79.68,83.51 79.86,83.33 80.31,83.33 80.43,83.22 80.43,82 80.08,81.65 79.1,81.65 78.97,81.78 78.97,82.31 78.82,82.45 78.82,82.71 78.97,82.86 78.97,84.09 79.07,84.19 79.57,84.19
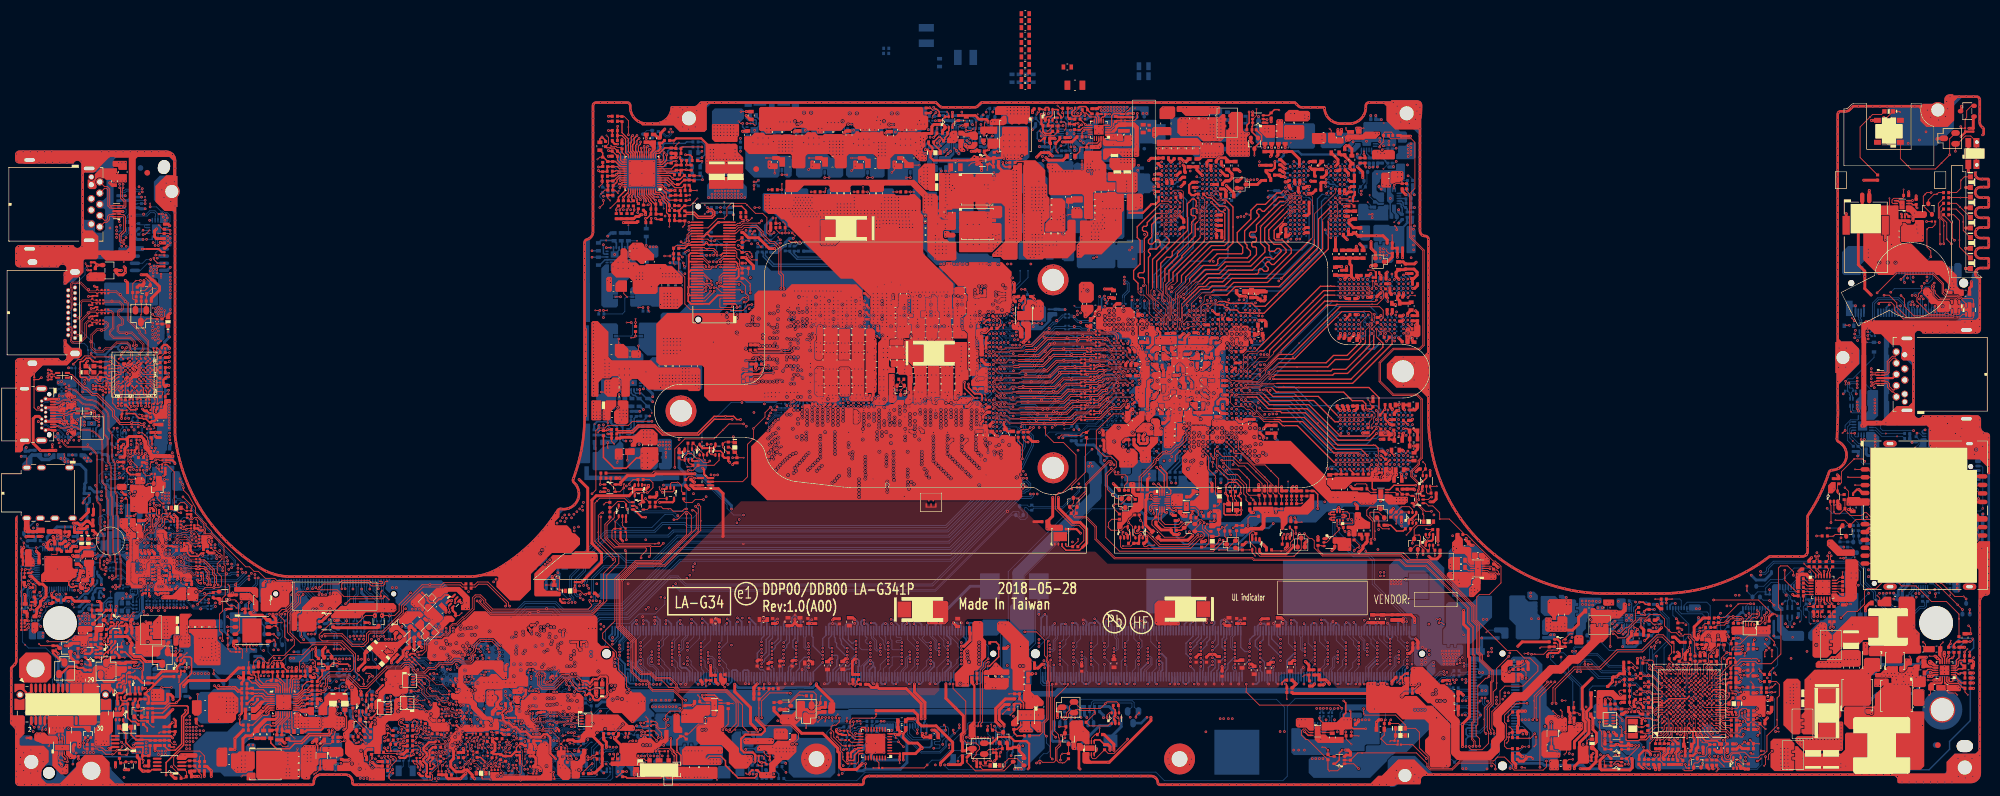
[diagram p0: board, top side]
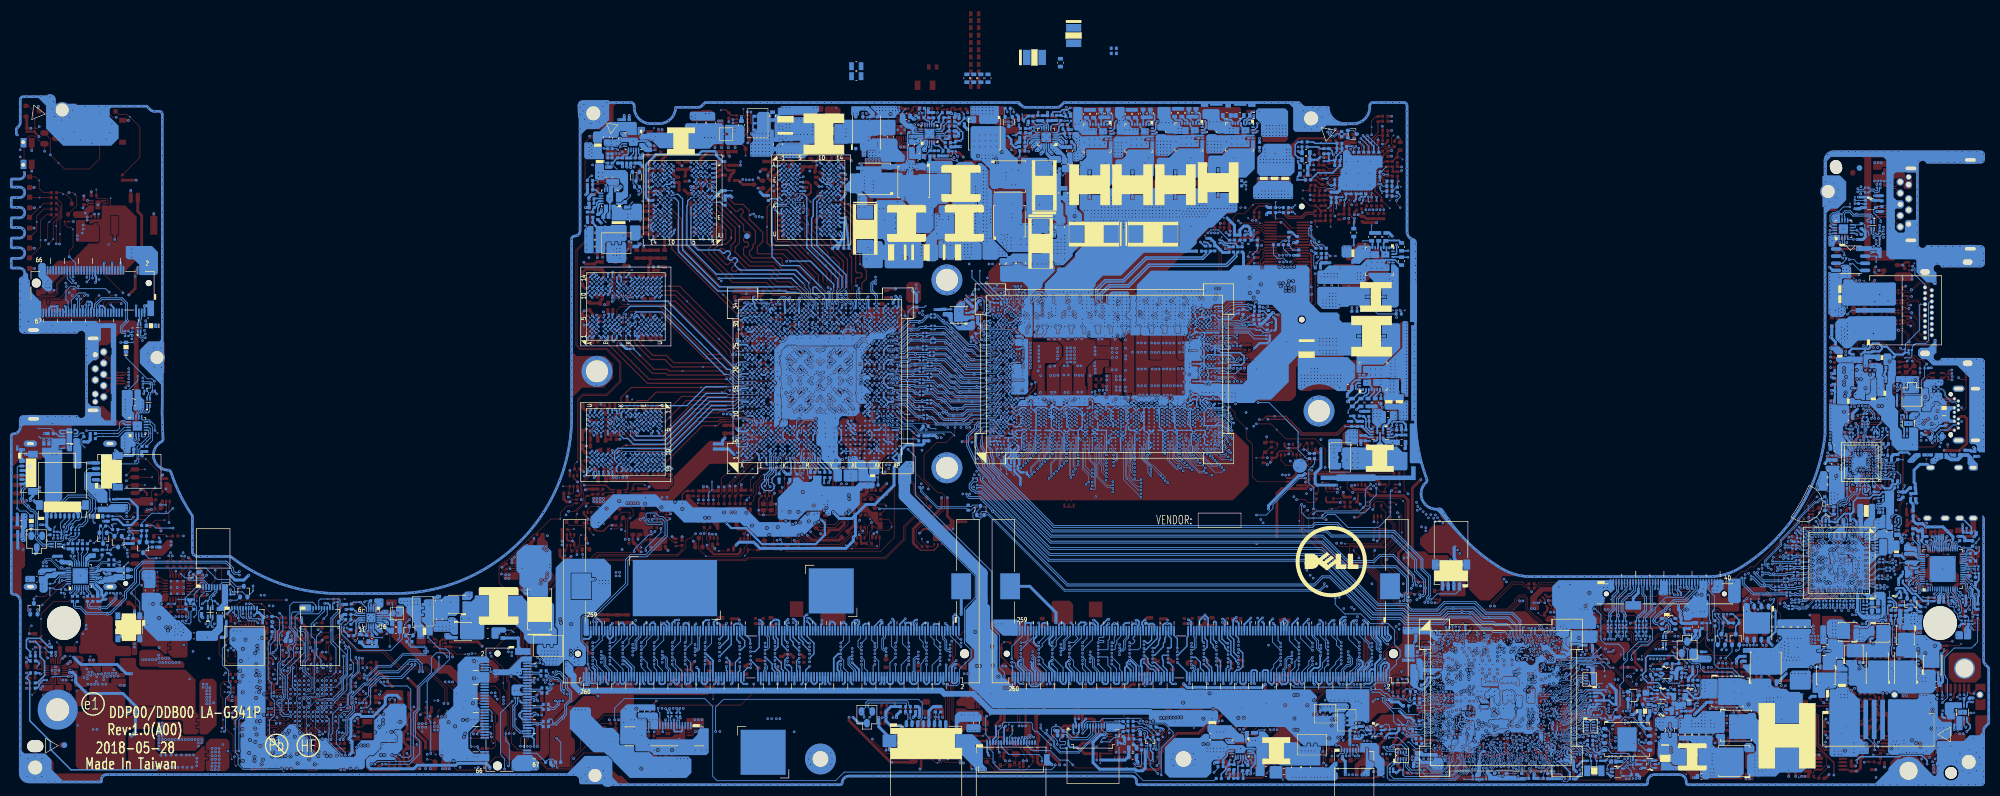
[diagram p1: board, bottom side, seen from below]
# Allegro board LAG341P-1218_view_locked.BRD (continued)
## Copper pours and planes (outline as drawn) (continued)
+3V_PCH on BOTTOM (solid shape): 109.94,76.1 109.94,76 110.2,75.5 110.61,75.9 110.63,75.98 110.71,76.01 111.1,76.01 111.26,75.86 111.26,75.25 111.1,75.09 109.84,75.09 109.4,75.54 109.4,76.13 109.45,76.19 109.85,76.19
+3V_PCH on BOTTOM (solid shape): 85.27,78.69 86.92,78.69 87.19,78.42 87.19,78.24 87.1,78.14 86.72,78.14 86.34,77.76 86.1,77.81 85.89,77.68 85.87,77.66 85.81,77.66 85.39,77.68 85.53,77.28 85.53,77.14 83.79,77.14 83.69,77.24 83.66,77.33 83.72,77.41 83.91,77.81 83.53,78.03 83.44,78.06 83.4,78.13 83.4,78.62 83.48,78.69 84.66,78.69 84.83,78.87 85.1,78.87
+3V_PCH_AZIO on TOP (solid shape): 90.82,74.54 90.83,74.54 90.83,74.3 91.11,74.02 91.11,73.83 91.01,73.74 91.01,73.19 91.06,73.14 91.39,73.14 91.47,73.07 91.47,72.65 91.41,72.6 91.24,72.6 91.23,72.6 91.11,72.62 90.99,72.6 90.98,72.6 90.36,72.6 90.36,72.6 90.12,72.6 89.89,72.83 89.89,73.23 89.99,73.33 90.04,73.48 90.04,73.5 90.2,73.65 90.2,74.41 90.32,74.54 90.62,74.54 90.62,74.58 90.82,74.58
+3V_PCH_BR on TOP (solid shape): 56.09,71.55 56.09,70.99 56.01,70.91 55.78,70.91 55.53,70.66 55.53,69.7 55.52,69.69 53.87,69.69 53.58,69.98 53.58,71.58 53.64,71.65 56,71.65
+3V_PCH_DSW on TOP (solid shape): 144.78,81.68 144.78,80.15 144.41,79.78 143.66,79.78 143.56,79.88 143.56,81.24 143.66,81.34 143.66,81.68 143.79,81.81 144.65,81.81
+3V_PCH_DSW_RR on TOP (solid shape): 143.23,80.39 143.23,79.83 143.16,79.77 141.93,79.77 141.44,79.28 141.44,78.42 141.41,78.34 140.93,77.86 139.42,77.86 139.06,78.23 139.06,78.91 139.08,78.93 139.08,79.8 139.27,80 139.75,80 140.05,79.7 141.12,79.7 141.7,80.28 142.17,80.28 142.32,80.43 143.18,80.43
+3V_PS8723 on TOP (solid shape): 316,104.87 316.27,104.75 316.54,104.87 317.74,104.87 318.91,103.69 318.91,103.32 318.88,103.29 318.04,103.29 317.96,103.38 317.96,103.67 317.4,104.23 316.64,104.23 316.51,104.11 316.51,101.97 316.43,101.9 315.87,101.9 315.7,102.08 315.7,104.72 315.84,104.87
+3V_PS8723 on TOP (solid shape): 326.83,106.84 326.83,105.59 326.85,105.58 326.85,103.51 326.58,103.24 326.58,102.89 326.47,102.63 326.58,102.38 326.58,100.29 325.98,99.69 325.47,99.69 325.45,99.67 323.39,99.67 323.38,99.67 323.27,99.69 323.15,99.67 323.15,99.67 322.4,99.67 322.12,99.95 322.12,100.18 322.1,100.31 322.04,100.43 322.04,101.05 322.17,101.19 322.93,101.19 323.56,100.57 324.28,100.57 324.29,100.58 324.41,100.58 324.41,100.7 324.5,100.79 324.5,105.18 324.5,105.18 324.5,107.19 324.56,107.25 326.41,107.25
+3V_PS8723 on BOTTOM (solid shape): 326.82,104.99 326.82,103.78 326.38,103.34 326.38,102.29 326.25,102.15 324.5,102.15 324.34,102.31 324.34,105.06 324.63,105.35 326.46,105.35
+3V_ROM on BOTTOM (solid shape): 110.01,74.43 110.01,72.92 109.25,72.92 109.18,72.98 109.18,73.72 109.05,73.84 109.01,73.84 108.99,73.86 108.66,73.86 108.65,73.84 108.64,73.84 108.42,73.63 108.42,71.65 108.2,71.43 107.62,71.43 107.51,71.32 107.49,71.3 107.49,71.19 107.49,70.46 107,69.97 107,68.8 106.83,68.64 106.08,68.64 105.7,69.02 105.7,71.55 106.66,72.51 106.66,73.98 107.23,74.56 109.87,74.56
+3V_TBT on BOTTOM (solid shape): 17.21,112.45 17.82,112.45 18.97,111.3 18.98,111.3 19.87,111.3 19.94,111.23 19.94,111.1 20.09,110.95 20.27,110.95 20.33,110.89 20.33,110.66 20.27,110.59 20.05,110.59 19.98,110.66 19.5,110.66 19.34,110.5 18.5,110.5 18.33,110.67 18.01,110.67 17.64,111.04 16.37,111.04 16.1,110.77 16.1,108.34 15.99,108.22 15.41,108.22 15.29,108.34 15.29,108.47 14.97,108.79 14.2,108.79 14.08,108.91 14.08,109.46 14.08,109.47 14.08,110.53 14.15,110.59 15.01,110.59 15.23,110.81 15.23,112.17 15.31,112.25 16.15,112.25 16.58,112.69 16.98,112.69
+3V_TBT_S0 on TOP (solid shape): 29.31,102.18 29.31,100.04 29.21,99.94 27.86,99.94 27.69,100.12 25.02,100.12 24.89,100.25 24.89,100.55 25.22,100.88 26.87,100.88 27.65,101.66 27.69,101.66 27.69,101.69 28.24,102.25 29.24,102.25
+3V_VC on TOP (solid shape): 14.88,95.64 14.88,95.3 14.74,95.17 14.73,95.17 14.73,95.15 14.66,95.08 14.66,94.63 14.31,94.29 13.8,94.29 13.64,94.13 13.64,92.86 13.44,92.65 12.89,92.65 12.81,92.73 12.81,93.42 13,93.62 13,95.14 13.26,95.39 13.27,95.39 13.71,95.83 14.69,95.83
+3V_VC on TOP (solid shape): outline of 99 points within 57.65,81.3 60.3,86.04
+3V_VC on BOTTOM (solid shape): 59.77,83.96 59.77,83.08 59.65,82.95 58.75,82.95 58.6,83.1 58.6,83.94 58.68,84.02 59.72,84.02
+3V_VC on BOTTOM (solid shape): 53.07,81.93 53.37,81.75 53.68,81.93 54.5,81.93 54.63,81.81 54.63,81.3 54.53,81.2 54.16,81.2 53.96,81 53.96,80.44 53.94,80.42 53.38,80.42 53.33,80.47 53.33,80.58 53.29,80.61 52.27,80.61 52.07,80.81 52.07,81.86 52.14,81.93
+3VA_TBT on TOP (solid shape): 25.01,121.9 25.01,121.37 25.32,121.06 25.53,121.06 25.68,120.92 25.68,120.03 25.07,119.42 24,119.42 23.65,119.07 23.65,118.5 23.3,118.15 23.19,118.15 22.51,117.47 22.51,115.5 22.4,115.38 20.85,115.38 20.55,115.69 19.46,115.69 19.35,115.8 19.35,118.62 19.4,118.64 19.45,118.66 19.55,118.66 19.6,118.59 20.04,118.31 20.29,118.76 20.3,118.84 20.35,118.89 20.37,119.54 19.88,119.11 19.88,119.03 19.82,118.98 19.78,118.96 19.68,118.96 19.63,119.03 19.53,119.22 19.35,119.32 19.35,120.46 19.41,120.52 20.1,120.52 20.18,120.44 21.77,120.44 22.09,120.11 22.38,120.11 22.53,120.27 23.22,120.27 23.74,120.2 24.01,120.64 24.01,120.82 24,120.92 23.97,121.02 23.97,121.99 24.06,122.07 24.84,122.07
+3VA_TBT on BOTTOM (solid shape): 16.68,119.28 16.68,117.53 16.73,117.48 16.83,117.48 17.35,116.95 17.95,116.95 18.02,116.89 18.02,116.57 17.94,116.49 17.4,116.49 17.31,116.58 16.66,116.58 16.45,116.36 16.45,112.73 16.24,112.52 15.35,112.52 15.22,112.66 15.22,113.34 15.53,113.65 15.53,114.3 15.71,114.48 15.71,114.87 15.54,115.03 15.37,115.03 15.05,115.35 15.05,119.22 15.28,119.45 16.51,119.45
+3VA_TBT_LC on TOP (solid shape): 32.88,111.54 33.68,111.54 34.13,111.09 34.13,110.95 33.96,110.78 33.94,110.78 33.85,110.78 33.78,110.76 33.71,110.76 33.65,110.81 33.13,110.92 33.09,110.39 33.09,110.17 33.41,109.84 33.41,109.33 33.35,109.26 32.83,109.26 32.65,109.09 32.65,108.76 32.6,108.7 32.25,108.7 32.14,108.81 32.14,109.87 32.02,109.99 32.02,111.41 32.08,111.47 32.4,111.47 32.47,111.54 32.87,111.54
+3VALW on TOP (solid shape): 322.8,120.9 322.8,119.69 322.71,119.6 322.71,119.49 322.19,118.97 321.58,118.97 321.44,119.11 321.44,120.38 322.05,120.99 322.71,120.99
+3VALW on TOP (solid shape): 190.02,72.88 190.02,71.67 190.55,71.14 190.55,71.01 190.42,70.88 189.03,70.88 188.77,71.14 188.77,72.79 188.94,72.95 189.95,72.95
+3VALW on TOP (solid shape): 261.24,107.27 261.24,106.44 261.11,106.32 259.83,106.32 259.77,106.38 259.77,106.58 259.77,106.58 259.77,107.16 259.26,107.67 259.26,108.24 259.4,108.37 260.14,108.37
+3VALW on TOP (solid shape): 9.24,72.4 9.76,72.4 9.77,72.39 9.77,72.01 9.46,71.7 8.7,71.7 7.94,72.46 7.94,73.04 8.02,73.11 8.53,73.11
+3VALW on TOP (solid shape): 179.48,78.38 179.48,77.34 179.93,76.89 179.93,76.52 179.85,76.44 177.71,76.44 177.44,76.71 177.44,76.92 177.84,77.32 177.97,77.32 178.11,77.46 178.11,78.37 178.2,78.46 179.4,78.46
+3VALW on TOP (solid shape): 66.7,98.98 66.7,98.16 66.34,97.81 61.26,97.81 60.21,96.75 55.29,96.75 55.08,96.97 55.08,97.21 56.82,98.95 57.84,98.95 58.34,99.46 66.22,99.46
+3VALW on TOP (solid shape): 57.28,73.42 57.28,72.43 57.24,72.37 57.22,72.31 57.06,72.15 56.55,72.15 56.55,72.15 56.4,72 54.97,72 54.76,72.2 54.76,72.57 54.34,72.99 53.72,72.99 53.57,73.14 53.57,73.78 53.64,73.86 56.85,73.86
+3VALW on TOP (solid shape): 18.69,120.54 18.69,119.62 18.64,119.56 18.02,119.56 17.85,119.61 17.67,119.57 17.24,119.57 16.99,119.82 16.99,120.49 17.17,120.67 18.56,120.67
+3VALW on TOP (solid shape): 337.3,169.18 338.76,169.18 339.01,168.93 339.01,168.29 338.7,167.98 336.9,167.98 336.82,167.89 336.82,167.37 336.73,167.28 336.48,167.28 336.48,167.28 336.28,167.48 336.28,168.61 335.88,169.02 335.53,169.02 335.28,169.27 335.28,170.11 335.37,170.2 336.28,170.2
+3VALW on TOP (solid shape): 79.79,100.54 79.79,98.39 79.6,98.2 78.26,98.2 78.22,98.24 78.22,99.04 78.25,99.11 78.32,99.14 78.63,99.38 78.54,99.76 78.54,100.34 77.39,101.48 75.98,101.48 75.68,101.18 75.39,101.18 75.28,101.16 75.19,101.1 74.56,100.46 74.17,100.46 73.56,99.85 72.86,99.85 72.54,100.17 72.54,100.83 73.83,102.12 75.02,102.12 75.25,102.34 77.99,102.34
+3VALW on TOP (solid shape): 139.42,81.88 139.42,80.51 138.95,80.04 138.95,78.98 137.81,77.84 135.33,77.84 134.92,78.24 134.92,78.25 134.92,78.92 137.58,78.92 137.58,78.86 137.58,78.81 137.6,78.76 137.62,78.71 137.65,78.67 137.69,78.63 137.73,78.59 137.78,78.57 137.83,78.55 137.88,78.54 137.93,78.53 137.99,78.54 138.04,78.55 138.09,78.57 138.13,78.59 138.17,78.63 138.21,78.67 138.24,78.71 138.26,78.76 138.28,78.81 138.29,78.86 138.29,78.92 138.28,78.97 138.26,79.02 138.24,79.07 138.21,79.11 138.17,79.15 138.13,79.18 138.09,79.21 138.04,79.23 137.99,79.24 137.93,79.25 137.88,79.24 137.83,79.23 137.78,79.21 137.73,79.18 137.69,79.15 137.65,79.11 137.62,79.07 137.6,79.02 137.58,78.97 137.58,78.92 134.92,78.92 134.92,79.39 135.18,79.65 137.08,79.65 137.97,80.54 137.97,81.81 138.23,82.06 139.24,82.06
+3VALW on TOP (solid shape): 321.26,95.64 321.26,94.63 322.11,93.78 322.11,93.54 322.12,93.52 322.12,92.99 321.58,92.99 321.57,92.98 321.57,92.25 321.58,92.24 322.12,92.24 322.12,91.79 322.12,91.79 321.59,91.79 321.57,91.78 321.57,91.06 321.59,91.04 321.63,91.04 322.12,91.04 322.13,91.03 322.13,90.57 321.3,89.73 318.98,89.73 318.67,90.04 318.67,92.03 318.99,92.03 318.99,91.98 319,91.93 319.02,91.88 319.04,91.83 319.07,91.78 319.1,91.75 319.15,91.71 319.19,91.69 319.24,91.67 319.29,91.65 319.35,91.65 319.4,91.65 319.45,91.67 319.5,91.69 319.55,91.71 319.59,91.75 319.63,91.78 319.66,91.83 319.68,91.88 319.7,91.93 319.7,91.98 319.7,92.03 319.7,92.09 319.68,92.14 319.66,92.18 319.63,92.23 319.59,92.27 319.55,92.3 319.5,92.33 319.45,92.35 319.4,92.36 319.35,92.36 319.29,92.36 319.24,92.35 319.19,92.33 319.15,92.3 319.1,92.27 319.07,92.23 319.04,92.18 319.02,92.14 319,92.09 318.99,92.03 318.67,92.03 318.67,94.5 318.7,94.53 318.7,94.64 320.08,96.01 320.88,96.01
+3VALW on TOP (solid shape): 273.13,79.34 273.13,79.31 273.32,78.95 273.73,79.01 273.8,79.04 273.87,79.01 274.18,78.92 274.44,79.11 274.45,79.14 274.75,79.14 275.01,78.89 275.01,77.67 275.01,76.85 274.75,76.6 274.06,76.6 273.86,76.6 273.48,76.98 272.67,76.98 272.59,77.06 272.59,78.25 272.57,78.27 272.57,78.29 272.19,78.61 271.86,78.24 271.86,78.22 271.83,78.19 271.83,77.04 271.77,76.98 271.64,76.98 271.58,77.04 271.58,77.62 271.07,78.12 271.07,78.95 271.64,79.52 272.95,79.52
+3VALW on TOP (solid shape): outline of 248 points within 338.31,150.3 346.98,155.6
+3VALW on BOTTOM (solid shape): 180.1,77.78 180.1,76.63 179.95,76.48 177.67,76.48 177.59,76.57 177.59,77.74 177.75,77.91 179.97,77.91
+3VALW on BOTTOM (solid shape): 338.96,128.67 338.96,123.61 338.73,123.39 337.79,123.39 337.57,123.61 337.57,127.46 337.83,127.72 337.83,128.61 337.98,128.76 338.87,128.76
+3VALW on BOTTOM (solid shape): outline of 240 points within 317.93,92.73 326.83,101.28
+3VALW_5105 on TOP (solid shape): 306.53,95.29 306.72,95.14 306.95,95.21 306.98,95.22 307.02,95.22 307.1,95.17 307.18,95.15 307.27,95.13 307.35,95.15 307.44,95.17 307.52,95.22 307.55,95.22 307.59,95.21 307.77,95.13 308.02,95.23 308.09,95.2 308.32,95.14 308.5,95.29 308.52,95.32 311.07,95.32 311.2,95.19 311.2,94.07 311,93.87 304.5,93.87 304.24,94.13 304.24,95.17 304.39,95.32 306.52,95.32
+3VALW_5105 on TOP (solid shape): outline of 154 points within 305.17,79.2 310.31,83.84
+3VALW_5105 on BOTTOM (solid shape): outline of 3384 points within 279.7,69.87 311.2,95.08
+3VALWP on TOP (solid shape): 330.44,96.9 330.44,93.23 330.09,92.89 327.76,92.89 326.64,91.77 324.17,91.77 322.81,90.4 322.38,90.4 322.27,90.51 322.27,90.57 322.27,90.57 322.27,91.18 322.26,91.2 321.72,91.2 321.72,91.64 322.26,91.64 322.27,92.38 322.26,92.39 321.72,92.39 321.72,92.4 321.72,92.84 322.26,92.84 322.27,92.86 322.27,93.76 325.58,97.07 330.27,97.07
+3VS on TOP (solid shape): 323.96,109.01 326.05,109.01 326.19,108.87 326.19,107.98 326.06,107.85 323.06,107.85 321.23,109.68 321.23,110.51 321.49,110.76 322.21,110.76
+3VS on TOP (solid shape): 255.88,111.85 255.88,111.45 256.08,111.25 256.08,111.24 256.45,110.88 256.45,109.84 256.45,109.83 256.45,109.67 256.69,109.44 257.66,109.44 257.96,109.13 257.96,107.41 258.5,106.87 258.5,106.37 258.44,106.3 257.78,106.3 257.3,106.78 257.3,107.65 256.75,108.21 255.03,108.21 254.55,108.69 254.55,110.24 255.12,110.81 255.12,111.78 255.27,111.93 255.8,111.93
+3VS on TOP (solid shape): outline of 158 points within 62.79,79.63 69.07,88.26
+3VS on TOP (solid shape): outline of 216 points within 99.32,74.66 109.16,79.63
+3VS on TOP (solid shape): outline of 298 points within 239.26,70.2 254.31,86.34
+3VS on TOP (solid shape): outline of 477 points within 166.03,84.59 171.65,96.26
+3VS on TOP (solid shape): outline of 479 points within 76.02,72.87 84.99,78.89
+3VS on BOTTOM (solid shape): 298.83,98.98 298.83,98.25 298.66,98.08 296.81,98.08 296.66,98.22 296.66,99.09 296.81,99.23 298.57,99.23
+3VS on BOTTOM (solid shape): 347.54,104.11 347.54,103.28 347.43,103.17 345.91,103.17 345.84,103.25 345.84,104.17 345.95,104.29 347.35,104.29
+3VS on BOTTOM (solid shape): 109.18,77.33 109.18,76.89 108.89,76.6 108,76.6 107.87,76.73 107.87,76.98 108,77.11 108.51,77.11 108.64,77.23 108.64,77.39 108.71,77.47 109.05,77.47
+3VS on BOTTOM (solid shape): 51.45,91.11 51.46,91.07 51.46,89.49 50.88,88.9 47.78,88.9 47.53,89.15 47.53,89.79 47.86,90.12 49.68,90.12 49.9,90.33 49.9,91.07 50.18,91.35 51.22,91.35
+3VS on BOTTOM (solid shape): 69.84,88.28 69.84,87.97 69.79,87.92 69.25,87.92 69.03,87.7 69.03,86.7 68.95,86.62 68.95,85.04 68.86,84.96 68.21,84.96 68.12,85.04 68.12,86.89 68.25,87.01 68.25,87.94 68.36,88.05 68.48,88.05 68.77,88.33 69.79,88.33
+3VS on BOTTOM (solid shape): 15.02,111.96 15.02,111.29 14.96,111.23 14.12,111.23 13.94,111.05 13.94,110.15 13.83,110.04 13.48,110.04 13.36,110.16 13.36,111.08 13.56,111.27 13.58,111.28 13.74,111.37 13.84,111.54 13.84,111.55 13.86,111.57 13.86,111.92 13.96,112.01 14.97,112.01
+3VS on BOTTOM (solid shape): 87.71,69.5 87.71,69.11 87.29,68.69 87.29,68.04 87.14,67.89 80.58,67.89 80.4,68.06 80.4,68.35 80.59,68.53 81.63,68.53 81.64,68.5 82.03,68.28 82.28,68.64 82.3,68.73 82.38,68.76 84.28,68.76 84.35,68.73 84.38,68.66 84.79,68.34 85,68.81 84.99,68.85 85,68.89 85.57,68.89 85.74,68.73 86.46,68.73 86.52,68.79 86.53,68.79 86.62,68.88 86.62,68.96 87.05,69.4 87.05,69.74 87.16,69.85 87.36,69.85
+3VS on BOTTOM (solid shape): outline of 202 points within 280.43,70.49 286.93,76.87
+3VS_AUDIO on TOP (solid shape): 3.01,95.86 3.01,94.58 2.52,94.09 2.07,94.09 1.8,94.35 1.8,95.86 1.94,95.99 2.88,95.99
+3VS_AUDIO on TOP (solid shape): 13.79,84.88 13.79,82.69 13.61,82.52 11.05,82.52 10.83,82.74 10.83,83.13 11.05,83.36 11.05,84.96 11.25,85.15 13.51,85.15
+3VS_AUDIO on TOP (solid shape): 10.69,76.42 10.69,73.86 10.41,73.58 10.13,73.58 9.91,73.81 9.91,74.67 9.73,74.85 9.15,74.85 8.69,74.38 8.01,74.38 7.95,74.43 7.95,76.58 8.07,76.7 10.41,76.7
+3VS_AUDIO on BOTTOM (solid shape): 2.02,95.91 2.02,95.55 2.62,94.96 2.62,93.08 2.52,92.99 1.5,92.99 1.31,93.17 1.31,94.75 1.36,94.75 1.65,94.99 1.57,95.36 1.56,95.37 1.56,95.49 1.62,95.66 1.6,95.85 1.6,95.93 1.62,95.95 1.98,95.95
+3VS_CR on BOTTOM (solid shape): 332,104.34 332.64,104.34 332.82,104.16 333.53,104.16 333.63,104.06 333.63,103.83 333.83,103.62 334.24,103.62 334.44,103.42 334.44,102.96 334.31,102.84 333.63,102.84 333.38,103.09 331.5,103.09 331.06,103.53 330.04,103.53 329.98,103.57 329.91,103.6 329.77,103.74 329.77,104.55 329.87,104.65 331.69,104.65
+3VS_CR on BOTTOM (solid shape): 342.82,104.73 343.71,104.73 344.22,104.22 345.09,104.22 345.14,104.17 345.14,103.18 344.98,103.02 344.98,101.62 344.67,101.3 343.9,101.3 343.55,101.66 343.55,103.69 343.33,103.91 342.19,103.91 341.57,104.52 340.55,104.52 340.32,104.75 339.41,104.75 339.34,104.82 339.34,104.97 339.42,105.05 342.51,105.05
+3VS_DTH on TOP (solid shape): 26.59,135.61 26.59,135.07 26.54,134.99 26.45,134.98 26.01,134.88 26.01,134.44 26.04,134.37 25.93,134.08 26.04,133.79 25.93,133.5 26.04,133.2 25.93,132.91 26.04,132.62 26.01,132.55 25.96,132.47 25.93,132.34 25.87,132.28 23.83,132.28 23.67,132.43 23.67,132.73 23.44,132.96 23.44,133.2 23.51,133.27 23.68,133.27 23.99,133.14 24.27,133.34 24.29,133.37 24.43,133.37 24.56,133.5 24.56,133.88 24.69,134 25.11,134 25.25,134.14 25.25,134.56 25.38,134.69 25.38,135.57 25.56,135.75 26.44,135.75
+3VS_DTH on BOTTOM (solid shape): 25.45,145.09 25.55,145.1 26.34,145.1 26.47,144.98 26.47,144.57 26.31,144.42 25.98,144.42 25.3,143.73 24.23,143.73 24.13,143.83 24.13,144.47 24.77,145.1 25.35,145.1
+3VS_DTH on BOTTOM (solid shape): 21.81,162.87 21.81,162.16 21.73,162.08 19.4,162.08 19.23,162.26 18.22,162.26 18.16,162.2 18.16,161.74 17.82,161.39 17.82,160.87 17.81,160.85 17.3,160.85 17.26,160.9 17.26,162.64 17.39,162.78 17.48,162.81 17.55,162.76 17.86,162.59 18.16,162.76 18.25,162.81 18.33,162.76 18.72,162.59 19,162.91 19,162.96 21.72,162.96
+3VS_FFS on TOP (solid shape): 238.35,115.46 238.35,114.9 239.07,114.29 239.92,113.88 239.93,113.87 239.98,113.82 239.98,112.83 239.85,112.71 238.9,112.71 238.8,112.6 237.83,112.6 237.57,112.34 237.57,111.46 237.43,111.32 236.8,111.32 236.64,111.48 236.64,112.38 236.41,112.6 235.84,112.6 235.79,112.65 235.79,113.15 235.88,113.24 236.98,113.24 237.19,113.45 237.19,115.45 237.36,115.62 238.2,115.62
+3VS_FP on BOTTOM (solid shape): 312.53,102.76 312.53,99.65 312.54,99.65 312.54,99.47 313.25,98.75 313.43,98.75 313.49,98.7 313.49,98.11 313.43,98.06 312.09,98.06 311.45,98.7 311.45,102.51 311.77,102.82 312.47,102.82
+3VS_FP_R on BOTTOM (solid shape): 313.48,97.3 313.48,95.4 314.38,94.51 316.92,94.51 317.17,94.25 317.17,92.86 317.04,92.73 313.49,92.73 313.23,92.98 313.23,93.62 312.34,94.51 312.34,97.25 312.48,97.39 313.4,97.39
+3VS_TP on TOP (solid shape): 188.86,78.47 188.86,78.07 188.86,77.66 190.03,76.5 190.03,74.39 189.96,74.32 189.3,74.32 188.74,74.88 187.88,74.88 187.69,74.69 187.69,73.43 187.58,73.32 187.05,73.32 186.83,73.53 186.83,74.89 186.48,75.25 186.48,78.13 186.93,78.58 188.76,78.58
+3VS_TS on BOTTOM (solid shape): 348.6,126.95 348.6,124.49 348.47,124.35 347.78,124.35 347.59,124.54 347.59,124.92 348.09,125.43 348.09,126.32 347.97,126.45 347.65,126.45 347.52,126.57 347.52,126.89 347.65,127.02 348.54,127.02
+3VS_TS on BOTTOM (solid shape): 342.87,128.61 342.87,127.2 342.99,127.08 344.47,127.08 344.54,127.02 344.54,125.68 344.04,125.19 344.04,114.6 343.87,114.42 343.61,114.42 343.38,114.65 343.38,115.54 340.97,117.95 340.97,126.65 341.01,126.69 341.57,126.69 341.59,126.71 341.59,127.45 341.46,127.58 340.49,127.58 340.36,127.7 340.36,128.64 340.46,128.75 342.73,128.75
+3VS_WLAN on TOP (solid shape): outline of 194 points within 327.71,154.13 345.58,170.2
+3VS_WLAN on BOTTOM (solid shape): 329.63,160.94 329.31,160.62 328.21,160.62 327.24,159.66 327.24,157.93 327.13,157.81 324.28,157.81 323.93,158.17 323.93,161.92 324.99,162.98 329.63,162.98
+3VS_WLAN on BOTTOM (solid shape): 345.22,159.62 345.22,157.53 344.82,157.14 344.61,156.92 344.61,156.83 344.6,156.82 344.51,156.39 344.6,155.97 344.61,155.96 344.61,155.76 343.76,154.91 343.08,154.91 342.76,155.23 342.74,155.3 342.74,156.8 343.88,157.94 343.88,159.71 344.14,159.97 344.87,159.97
+5V_CHGUSB_1 on BOTTOM (solid shape): 330.35,137.25 330.35,132.78 329.62,132.05 328.3,132.05 328.19,132.15 328.19,132.38 328.21,132.44 328.22,132.51 328.22,133.07 328.19,133.09 328.19,133.32 328.54,133.66 328.54,134.45 328.41,134.57 328.41,137.14 328.64,137.37 330.24,137.37
+5V_CHGUSB_2 on TOP (solid shape): 17.02,176.73 17.02,176.19 17.25,175.96 17.25,175.79 17.31,175.74 18.76,175.74 18.76,174.37 18.69,174.31 18.17,174.31 18.05,174.32 17.95,174.29 17.94,174.29 17.63,174.29 17.62,174.29 17.48,174.32 17.34,174.29 17.33,174.29 16.36,174.29 15.88,174.77 15.04,174.77 14.78,175.02 14.42,175.02 13.35,174.91 13.39,173.84 13.39,173.37 13.13,173.12 12.12,173.12 11.8,173.44 11.8,174.73 11.86,174.82 11.97,174.8 12.81,174.71 13.05,175.52 13.04,175.55 13.04,175.75 14.08,176.79 16.97,176.79
+5V_CHGUSB_2 on BOTTOM (solid shape): 25.36,168.74 25.81,168.74 26.19,168.37 26.19,167.43 25.83,167.07 24.69,167.07 24.61,167.15 24.61,167.33 24.67,167.44 24.69,167.56 24.69,168.9 24.77,168.98 25.12,168.98
+5VALW on TOP (solid shape): 181.5,78.22 181.5,76.56 181.38,76.45 180.75,76.45 179.65,77.54 179.65,78.31 179.77,78.43 181.29,78.43
+5VALW on TOP (solid shape): 229.92,78.82 229.92,76.85 229.86,76.79 229.1,76.79 228.59,77.3 227.06,77.3 226.75,77.62 226.75,78.76 227,79.01 229.73,79.01
+5VALW on TOP (solid shape): 261.07,104.76 262.16,104.76 262.45,104.47 262.45,104 262.44,104 262.44,103.79 262.25,103.6 259.92,103.6 259.77,103.75 259.77,104.86 259.89,104.98 260.85,104.98
+5VALW on TOP (solid shape): 206.57,115.91 206.57,115.75 206.86,115.46 207.31,115.46 207.49,115.28 207.49,114.74 207.37,114.61 206.6,114.61 205.71,115.5 205.71,115.73 205.75,115.82 205.77,115.91 205.77,115.93 205.84,116.01 206.48,116.01
+5VALW on TOP (solid shape): 6.55,73.05 6.55,72.4 6.45,72.3 6.45,71.62 6.48,71.59 6.48,70.75 7.05,70.17 7.38,70.17 7.78,70.57 7.78,70.72 7.9,70.84 8.27,70.84 8.35,70.76 8.35,69.28 8.07,69 7.01,69 5.52,70.49 5.52,72.85 5.78,73.11 6.49,73.11
+5VALW on TOP (solid shape): 315.44,74.52 315.44,73.38 315.41,73.36 314.93,73.36 314.91,73.36 314.91,72.65 314.92,72.63 315.43,72.63 315.43,72.63 315.43,72.17 315.42,72.16 314.93,72.16 314.91,72.16 314.91,71.45 314.93,71.43 315.43,71.43 315.44,71.43 315.44,69.84 315.16,69.56 311.89,69.56 311.2,70.25 311.2,72.57 311.41,72.78 311.44,72.78 311.84,73.18 311.34,73.46 311.25,73.47 311.2,73.55 311.2,74.82 311.71,75.33 314.63,75.33
+5VALW on BOTTOM (solid shape): 26.26,164.86 26.29,164.86 26.44,164.8 26.6,164.82 26.63,164.83 26.71,164.75 26.71,163 26.62,162.91 25.81,162.91 25.62,163.1 25.62,163.44 25.07,163.98 24.73,163.98 24.69,164.03 24.69,164.46 24.67,164.54 24.64,164.63 24.64,164.64 24.64,164.81 24.74,164.91 26.21,164.91
+5VALW on BOTTOM (solid shape): 330.19,129.42 330.19,129.41 330.56,129.04 330.56,127.09 330.02,126.54 330.02,126.44 330.02,126.44 330.02,126.19 329.91,126.07 328.97,126.07 328.78,126.27 328.78,127.09 328.64,127.23 328.64,127.26 328.6,127.26 328.59,127.27 328.08,127.27 327.91,127.44 327.91,128.11 327.97,128.16 327.98,128.17 328.27,128.41 328.22,128.78 328.22,129.41 328.21,129.56 328.21,129.57 328.21,129.77 328.36,129.93 329.68,129.93
+5VALW on BOTTOM (solid shape): outline of 101 points within 23.25,117.03 27.2,123.9
+5VALW on BOTTOM (solid shape): outline of 1141 points within 206.17,111.27 246.95,118.8
+5VALWP on TOP (solid shape): 329.23,75.84 329.23,70.06 328.73,69.55 315.84,69.55 315.58,69.81 315.58,71.59 315.04,71.59 315.04,72.03 315.58,72.03 315.58,72.78 315.03,72.78 315.03,73.23 315.58,73.23 315.58,73.93 315.65,74 315.96,74 317.3,72.66 323.77,72.66 324.47,73.36 324.47,76.15 324.73,76.41 328.66,76.41
+5VS on TOP (solid shape): 257.38,104.92 258.46,104.92 258.5,104.88 258.5,104.17 258.5,104.16 258.5,104.07 257.91,103.48 257.91,102.79 257.35,102.23 255.65,102.23 253.61,104.27 253.61,104.68 253.91,104.99 257.31,104.99
+5VS on TOP (solid shape): 102.55,108.03 102.55,107.06 101.07,105.59 95.24,105.59 92.95,103.3 92.95,102.08 93.39,101.64 95.28,101.64 95.43,101.5 95.83,101.5 95.96,101.36 95.96,100.78 95.83,100.64 91.46,100.64 91.26,100.84 91.26,104.71 92.74,106.18 92.82,106.21 92.89,106.16 93.3,106.02 93.55,106.37 93.56,106.4 93.6,106.42 93.84,106.52 93.94,106.76 93.96,106.8 94,106.81 94.35,107.06 94.2,107.47 94.15,107.54 94.18,107.63 94.55,107.99 97.83,107.99 98.5,108.66 101.91,108.66
+5VS on BOTTOM (solid shape): 165.4,177.29 165.4,176.19 165.3,176.09 164.27,176.09 164.14,176.22 164.14,177.24 164.27,177.37 165.32,177.37
+5VS on BOTTOM (solid shape): 332.8,116.59 334.56,116.59 334.64,116.5 334.64,115.66 334.59,115.61 329.84,115.61 329.83,115.64 329.71,115.77 329.56,115.83 329.54,115.84 329.29,116.09 329.29,116.95 329.4,117.07 332.32,117.07
+5VS_AUDIO on TOP (solid shape): 4.69,75.86 6.14,75.86 6.53,75.47 6.53,74.45 6.49,74.4 3.71,74.4 3.15,74.68 2.55,74.87 2.3,75.11 2.3,76.09 2.64,76.42 4.13,76.42
+5VS_AUDIO on TOP (solid shape): 12.81,107.11 12.81,104.3 12.58,104.07 12.32,104.07 12.32,104.05 12.27,104.05 12.04,103.81 12.04,103.3 11.99,103.21 11.9,103.21 11.64,103.23 11.44,103.09 11.36,103.04 11.28,103.07 10.71,102.95 11.03,102.46 11.1,102.43 11.12,102.35 11.12,101.75 10.57,101.75 10.42,101.9 10.37,101.97 10.3,102.03 10.24,102.09 10.24,102.92 10.46,103.14 10.57,103.25 10.57,103.7 10.73,103.86 11.25,103.86 11.47,104.09 11.47,105.78 11.15,106.1 11.15,107.1 11.21,107.16 12.76,107.16
+5VS_AUDIO on BOTTOM (solid shape): 13.19,105.98 13.19,105.37 13.08,105.27 13.08,104.03 13.01,103.95 12.58,103.95 12.34,104.2 11.96,104.2 11.88,104.27 11.88,104.27 11.77,104.38 11.77,105.17 11.93,105.33 12.4,105.33 12.51,105.44 12.51,105.97 12.59,106.05 13.12,106.05
+5VS_AUDIO_PVDD1 on BOTTOM (solid shape): 13.14,106.85 13.14,106.4 13.05,106.31 11.78,106.31 11.48,106.01 11.1,106.01 11.02,106.09 11.02,106.3 10.49,106.82 9.55,106.82 9.51,106.86 9.51,106.99 9.55,107.03 12.96,107.03
+5VS_AUDIO_PVDD2 on TOP (solid shape): 11.28,105.26 11.28,104.74 11.21,104.67 10.78,104.67 10.66,104.54 10.66,103.98 10.41,103.74 10.41,103.37 10.32,103.27 9.85,103.27 9.85,103.86 10.16,104.16 10.16,104.83 10.22,104.9 10.22,105.37 10.3,105.44 11.1,105.44
+5VS_AUDIO_PVDD2 on BOTTOM (solid shape): 11.43,105.18 11.43,104.76 11.31,104.64 10.94,104.64 10.75,104.82 9.52,104.82 9.48,104.86 9.48,104.97 9.52,105.02 10.51,105.02 10.75,105.26 11.34,105.26
+5VS_HDD on TOP (solid shape): 236.78,78.89 236.78,77.23 236.52,76.98 235.51,76.98 235.25,76.73 235.25,76.09 235.16,76 234.58,76 234.52,76.06 234.52,76.76 234.37,76.92 233.6,76.92 233.48,76.79 231.38,76.79 231.32,76.85 231.32,77.93 231.64,78.26 233.99,78.26 234.87,79.14 236.52,79.14
+5VS_HDD on BOTTOM (solid shape): 238.56,79.77 238.56,79.2 238.4,79.04 237.06,79.04 236.78,78.76 236.78,78.59 236.65,78.46 236.59,78.45 236.54,78.44 236.47,78.44 236.28,78.26 236.28,77.06 236.23,77 235.02,77 234.96,77.07 234.96,79.73 235.19,79.96 238.37,79.96
+AVDD1 on TOP (solid shape): 12.81,108.73 12.81,107.71 12.75,107.65 12.75,107.64 11.22,107.64 10.92,107.34 10.63,107.34 10.55,107.42 10.55,107.91 10.93,108.3 10.93,108.61 11.12,108.8 12.75,108.8
+AVDD1 on BOTTOM (solid shape): 13.23,108.49 13.23,107.95 13.17,107.9 11.51,107.9 10.82,107.21 9.56,107.21 9.5,107.26 9.5,107.37 9.56,107.43 10.36,107.43 10.42,107.49 10.5,107.49 10.97,107.96 10.97,108.41 11.01,108.45 11.48,108.45 11.61,108.58 13.14,108.58
+AVDD2 on TOP (solid shape): 1.84,108.87 1.84,107.67 2.34,107.17 2.34,106.08 2.21,105.95 0.73,105.95 0.61,106.07 0.61,108.85 0.8,109.03 1.67,109.03
+DVDD on BOTTOM (solid shape): 3.95,94.45 4.04,94.28 4.14,94.12 4.14,93.22 3.94,93.02 2.87,93.02 2.79,93.1 2.79,94.22 3.02,94.46 3.94,94.46
+DVDD on BOTTOM (solid shape): 6.74,102.38 6.74,101.35 7.38,100.71 7.38,99.41 7.3,99.33 6.75,99.33 6.7,99.38 6.7,100.08 6.62,100.15 6.62,100.98 6.59,101.02 6.59,101.05 6.57,101.26 6.47,101.4 6.47,102.39 6.52,102.44 6.68,102.44
+DVDDIO on BOTTOM (solid shape): 3.31,104.6 3.31,104.45 3.26,104.4 2.4,104.4 2.31,104.31 2.05,104.31 1.7,103.96 1.38,103.96 1.25,104.1 1.25,104.41 1.44,104.6 2.39,104.6 2.43,104.64 3.27,104.64
+VBUS_1 on TOP (solid shape): 7.83,135.13 7.83,134.9 7.35,134.42 7.01,134.42 6.64,134.04 4.66,134.04 4.51,133.89 4.34,133.89 4.08,134.15 4.07,134.16 4.07,134.48 4.16,134.56 4.48,134.56 4.58,134.46 6.4,134.46 6.5,134.55 6.7,134.55 6.7,134.56 7.03,134.89 7.12,134.89 7.46,135.23 7.52,135.25 7.59,135.27 7.69,135.27
+VBUS_1 on TOP (solid shape): 4.71,131.97 6.38,131.97 6.47,132.06 6.92,132.06 7.12,131.85 7.16,131.85 7.52,131.5 7.82,131.5 7.87,131.45 7.87,131.16 7.81,131.09 7.38,131.09 7.15,131.32 6.81,131.32 6.61,131.52 4.58,131.52 4.52,131.45 4.16,131.45 4.03,131.58 4,131.65 4.04,131.73 4.18,131.91 4.24,132.12 4.25,132.17 4.51,132.17
+VBUS_1 on TOP (solid shape): 30.26,97.44 30.26,97.22 29.67,96.63 29.67,96.35 29.65,96.33 29.65,95.05 29.67,95.04 29.67,94.85 29.67,94.84 29.67,94.16 29.67,94.09 30.09,93.67 30.09,92.42 30.09,92.42 30.09,92 30.09,91.99 30.09,91.83 29.8,91.54 28.18,91.54 28.09,91.63 28.09,91.93 28.09,92.82 28.09,92.85 28.26,93.01 28.26,93.09 28.27,93.11 28.27,93.25 28.28,93.26 28.32,93.43 28.28,93.6 28.27,93.61 28.27,93.72 28.26,93.73 28.26,93.84 28.17,93.93 28.17,96.99 28.17,97 28.17,97.39 28.35,97.57 30.14,97.57
+VBUS_1 on BOTTOM (solid shape): outline of 204 points within 22.73,125.42 26.59,134.96
+VBUS_1 on BOTTOM (solid shape): outline of 384 points within 3.98,130.32 13.44,137.65
+VBUS_DC_SS on BOTTOM (solid shape): 18.21,95.4 18.21,93 18.54,92.67 18.57,92.6 18.54,92.53 18.62,91.97 19.14,92.18 19.15,92.22 22.3,92.22 22.31,92.21 22.48,92.18 22.64,92.21 22.65,92.22 23.33,92.22 23.46,92.09 23.46,89.97 23.29,89.81 16.03,89.81 15.8,90.04 15.8,91.69 15.63,91.86 15.63,95.36 15.83,95.56 18.06,95.56
+VCC0V9_CIO on BOTTOM (solid shape): 26.08,108.62 26.12,108.65 26.17,108.65 26.3,108.56 26.46,108.54 26.48,108.54 26.52,108.51 26.54,108.44 26.56,108.4 26.6,108.37 26.65,108.33 26.65,108.12 26.58,108.05 26.46,107.93 26.46,107.43 26.31,107.27 26.31,106.62 26.16,106.47 25.82,106.47 25.67,106.61 25.67,106.63 25.64,106.72 25.57,106.78 25.57,107.05 25.67,107.24 25.57,107.43 25.57,107.54 26.01,107.99 26.03,108.01 26.1,108.22 26.03,108.43 26.01,108.44 26.01,108.56
+VCC0V9_DP on TOP (solid shape): outline of 360 points within 24.08,103.78 30.4,111.85
+VCC0V9_DP on BOTTOM (solid shape): 24.33,109.18 24.61,109.18 24.75,109.33 24.83,109.33 25.01,109.15 25.17,109.15 25.28,109.03 25.34,108.98 25.34,108.79 24.99,108.43 24.05,108.43 24,108.47 24,109.24 24.1,109.33 24.18,109.33
+VCC0V9_DP on BOTTOM (solid shape): 26.94,107.25 27.21,107.25 27.45,107.38 27.47,107.35 27.5,107.32 27.54,107.29 27.54,107.19 27.39,106.92 27.54,106.64 27.54,106.55 27.39,106.38 27.39,106.15 27.4,106.12 27.46,106.04 27.54,105.98 27.5,105.86 27.44,105.8 27.32,105.8 27.12,106 26.99,106 26.95,106.04 26.95,106.04 26.91,106.1 26.85,106.15 26.84,106.15 26.52,106.47 26.52,107.29 26.61,107.38 26.81,107.38
+VCC0V9_PCIE on TOP (solid shape): outline of 143 points within 23.56,101.57 26.95,105.89
+VCC0V9_PCIE on BOTTOM (solid shape): 24.94,106.02 24.96,105.96 24.95,105.9 24.79,105.61 24.97,105.32 25,105.31 25,104.99 25,104.99 24.93,104.91 24.93,104.59 24.79,104.45 24.79,104.18 24.99,103.98 25.25,103.98 25.4,104.13 25.49,104.13 25.53,104.08 25.57,104.04 25.57,103.28 25.54,103.25 25.49,103.2 25.36,103.2 25.12,103.44 25.04,103.44 24.89,103.58 24.71,103.58 24.54,103.42 24.41,103.42 24.21,103.22 24.08,103.22 24.05,103.26 24.05,103.42 24.15,103.67 24.05,103.91 24.05,104.07 24.12,104.19 24.15,104.32 24.15,104.34 24.24,104.43 24.3,104.47 24.34,104.52 24.37,104.71 24.25,104.85 24.21,104.92 24.23,105 24.3,105.07 24.3,105.12 24.37,105.29 24.3,105.46 24.3,105.77 24.36,105.87 24.37,105.98 24.4,106.05 24.47,106.08 24.87,106.08
+VCC_CORE on TOP (solid shape): outline of 1119 points within 132.13,134.7 169.3,172.23
+VCC_CORE on BOTTOM (solid shape): outline of 499 points within 151.03,134.51 170.94,136.4
+VCC_CORE on BOTTOM (solid shape): outline of 2245 points within 131.88,146.66 168.09,173.25
+VCCGT on TOP (solid shape): outline of 5267 points within 112.95,134.83 151.19,156.19
+VCCGT on BOTTOM (solid shape): 145.61,136.36 145.84,136.17 146.14,136.25 146.21,136.27 146.28,136.24 146.52,136.14 146.76,136.26 146.84,136.29 146.91,136.27 147.2,136.18 147.44,136.36 147.45,136.39 147.61,136.39 147.63,136.36 147.9,136.14 148.22,136.25 148.3,136.29 148.37,136.25 148.62,136.14 148.88,136.23 148.94,136.25 149.01,136.23 149.33,136.15 149.58,136.36 149.59,136.39 150.54,136.39 150.73,136.21 150.73,135.85 150.58,135.71 150.07,135.71 149.71,135.36 149.63,135.3 149.55,135.2 149.29,135.2 148.97,135.45 148.64,135.2 148.35,135.2 148.06,135.38 147.76,135.2 147.44,135.2 147.29,135.42 147.02,135.45 146.95,135.45 146.9,135.5 146.78,135.62 146.62,135.64 146.6,135.64 146.54,135.69 146.54,135.71 146.07,136.02 146,135.46 146.04,135.38 146,135.3 145.88,135.06 145.98,134.81 146.01,134.74 145.98,134.67 145.94,134.62 145.91,134.57 145.59,134.57 145.3,134.75 145,134.57 144.65,134.57 144.28,134.94 144.28,134.94 144.13,135.09 144.13,135.24 144.18,135.39 144.13,135.54 144.13,135.97 144.26,136.1 144.41,136.11 144.54,136.18 144.61,136.2 144.68,136.17 145.03,136.07 145.28,136.35 145.29,136.39 145.6,136.39
+VCCGT on BOTTOM (solid shape): outline of 2699 points within 109.84,134.53 149.77,159.56
+VCCIO on TOP (solid shape): 171.92,141.24 171.92,137.01 171.81,136.9 171.42,136.9 171.34,136.98 171.34,137.94 171.2,138.08 169.1,138.08 168.97,138.21 168.97,139.04 169.04,139.11 169.73,139.11 169.73,139.06 169.75,139.01 169.77,138.96 169.79,138.92 169.83,138.88 169.87,138.84 169.91,138.82 169.96,138.8 170.01,138.78 170.06,138.78 170.11,138.78 170.16,138.79 170.21,138.8 170.25,138.83 170.3,138.86 170.31,138.88 170.48,139.05 171.34,139.05 171.34,139.76 170.55,139.76 170.55,139.74 170.21,139.74 169.83,139.36 169.81,139.34 169.78,139.3 169.76,139.26 169.74,139.21 169.73,139.16 169.73,139.11 169.04,139.11 169.77,139.84 169.85,139.84 169.85,139.91 169.85,140.7 169.97,140.82 170.29,140.82 170.8,141.34 170.86,141.38 171.77,141.38
+VCCIO on BOTTOM (solid shape): 115.75,128.42 115.75,123.59 115.37,123.21 113.72,123.21 113.39,123.53 113.39,124.39 113.94,124.39 113.94,126.34 113.39,126.34 113.39,126.96 113.21,127.15 113.21,128.42 113.46,128.67 115.49,128.67
+VCCIO on BOTTOM (solid shape): outline of 357 points within 169.11,136.57 172.13,146.48
+VCCSA on TOP (solid shape): 117.65,155.47 117.65,152.67 116.76,151.78 113.69,151.78 113.5,151.97 113.5,155.54 113.68,155.72 117.4,155.72
+VCCSA on TOP (solid shape): outline of 1312 points within 163.25,139.9 176.31,160.11
+VCCSA on BOTTOM (solid shape): 117.65,155.47 117.65,152.67 116.76,151.78 113.97,151.78 113.59,152.16 112.19,152.16 111.94,152.42 110.41,152.42 110.16,152.16 108.51,152.16 108.33,152.34 108.33,153.54 109.25,153.54 109.25,154.35 108.33,154.35 108.33,155.42 108.64,155.72 117.4,155.72
+VCCSA on BOTTOM (solid shape): outline of 362 points within 164.39,146.76 174.09,159.99
+VCCST on TOP (solid shape): 179.64,149.25 179.64,146.75 179.21,146.31 179.19,146.31 179.1,146.22 179.03,146.17 178.97,146.09 178.46,145.58 178.09,145.58 177.91,145.76 177.91,145.94 178.55,146.58 178.55,148.29 177.87,148.97 177.87,149.41 177.98,149.52 179.37,149.52
+VCCST on TOP (solid shape): 172.06,148.36 172.06,148.21 171.55,147.7 171.5,147.68 171.47,147.67 171.13,147.67 170.81,147.77 170.56,147.54 170.66,147.2 171,147.14 171.1,147.13 171.14,147.05 171.14,145.48 171.25,145.37 171.25,143.4 171.19,143.35 170.55,143.35 170.44,143.46 170.44,145.32 170.47,145.36 170.47,145.91 170.38,145.99 170.38,146.01 170.29,146.23 170.07,146.32 170.06,146.32 169.83,146.55 169.83,148.03 170.09,148.3 171.08,148.3 171.28,148.51 171.91,148.51
+VCCSTG on BOTTOM (solid shape): 184.32,151.08 184.32,150.53 184.23,150.45 183.59,150.45 183.26,150.11 183.26,149.71 181.54,147.99 178.94,147.99 178.59,148.34 178.59,149.61 178.67,149.7 179.25,149.7 179.47,149.48 180.41,149.48 181.1,148.79 181.71,148.79 182.54,149.63 182.54,151.08 182.71,151.24 184.15,151.24
AGND on BOTTOM (solid shape): 13.29,109.72 13.29,108.87 13.16,108.74 11.53,108.74 11.37,108.58 10.99,108.58 10.98,108.6 10.98,109.21 11.29,109.52 11.9,109.52 12.17,109.78 12.17,110.03 12.42,110.28 12.73,110.28
DV12S on BOTTOM (solid shape): 336.14,103.35 336.14,103.23 336.09,103.18 335.32,103.18 335.11,102.98 335.11,102.55 334.86,102.29 334.63,102.29 334.51,102.42 334.51,102.62 334.8,102.91 334.8,102.91 335.27,103.38 336.11,103.38
DV12S on BOTTOM (solid shape): 331.42,105.81 331.62,105.71 331.85,105.7 331.88,105.7 331.91,105.69 334.14,105.69 334.37,105.46 334.82,105.46 335.25,105.02 336.09,105.02 336.16,104.96 336.16,104.79 336.11,104.74 334.86,104.74 334.61,105 334.14,105 333.91,105.22 333.3,105.22 333.12,105.05 331.39,105.05 331.2,104.86 329.85,104.86 329.76,104.94 329.76,105.71 329.85,105.81
DV33_18 on BOTTOM (solid shape): 336.05,108.3 336.17,108.3 336.88,107.59 336.88,105.94 336.82,105.87 336.65,105.87 336.59,105.94 336.59,106.77 335.9,107.46 335.09,107.46 335,107.55 335,108.25 335.05,108.3 336.05,108.3
GND on TOP (solid shape): 15.68,178.7 8.68,178.7 8.68,179.5 15.68,179.5
GND on TOP (solid shape): 15.68,161.38 8.68,161.38 8.68,162.18 15.68,162.18
GND on TOP (solid shape): 20.06,166.94 19.26,166.94 19.26,173.94 20.06,173.94
GND on TOP (solid shape): 328.21,136.63 327.41,136.63 327.41,143.63 328.21,143.63
GND on TOP (solid shape): 338.79,148.39 331.79,148.39 331.79,149.19 338.79,149.19
GND on TOP (solid shape): 338.79,131.07 331.79,131.07 331.79,131.87 338.79,131.87
GND on TOP (solid shape): 20.06,176 19.26,176 19.26,178.7 16.56,178.7 16.56,179.5 20.06,179.5
GND on TOP (solid shape): 20.06,161.38 16.56,161.38 16.56,162.18 19.26,162.18 19.26,164.88 20.06,164.88
GND on TOP (solid shape): 328.21,131.87 330.91,131.87 330.91,131.07 327.41,131.07 327.41,134.57 328.21,134.57
GND on TOP (solid shape): 128.45,175.15 128.45,173.25 128.38,173.18 122.42,173.18 122.35,173.25 122.35,175.15 122.48,175.28 128.32,175.28
GND on TOP (solid shape): 142.71,141.25 142.71,136.34 142.59,136.22 141.62,136.22 141.11,136.73 141.11,140.97 141.6,141.46 142.5,141.46
GND on TOP (solid shape): 147.51,141.1 147.51,136.57 147.13,136.19 145.78,136.19 145.51,136.46 145.51,141.28 145.66,141.42 147.18,141.42
GND on TOP (solid shape): 149.16,133.29 149.16,131.73 148.79,131.36 148.13,131.36 148.04,131.45 148.04,133.74 148.11,133.81 148.65,133.81
GND on TOP (solid shape): 164.93,99.56 164.93,96.26 164.34,95.66 161.32,95.66 161.1,95.88 161.1,99.24 161.72,99.87 164.63,99.87
GND on TOP (solid shape): 206.08,99.6 206.08,95.64 205.92,95.47 201.97,95.47 201.6,95.84 201.6,99.32 202.18,99.9 205.78,99.9
GND on TOP (solid shape): 210.93,139.48 210.93,138.19 210.87,138.13 210.37,138.13 209.73,138.77 209.73,139.29 209.92,139.48 210.93,139.48
GND on TOP (solid shape): 224.49,185.35 224.49,182.41 224.37,182.29 223.43,182.29 223.26,182.46 223.26,185.32 223.49,185.55 224.3,185.55
GND on TOP (solid shape): 283.38,99.98 283.38,99.05 283.34,99.01 281.6,99.01 281.43,99.18 281.43,100.04 281.49,100.09 283.26,100.09
GND on TOP (solid shape): 5.32,90 5.32,86.19 4.44,85.31 0.53,85.31 -0.41,86.25 -0.41,89.46 0.79,90.66 4.66,90.66
GND on TOP (solid shape): 12.64,95.14 12.64,94.51 12.53,94.4 12.06,94.4 11.48,93.82 10.26,93.82 10.03,94.05 10.03,95.14 10.26,95.37 12.41,95.37
GND on TOP (solid shape): 123.88,70.12 123.88,68.37 123.67,68.16 114.86,68.16 114.5,68.52 114.5,68.68 115.63,69.81 116.48,69.81 117,70.33 123.67,70.33
GND on TOP (solid shape): 127.69,184.55 127.69,182.64 127.43,182.39 127.43,181.63 127.3,181.5 123.37,181.5 122.86,182.01 122.86,184.55 122.99,184.68 127.56,184.68
GND on TOP (solid shape): 145.64,166.72 145.64,164.02 144.7,163.09 142.42,163.09 142.16,163.34 142.16,167.53 142.29,167.66 144.7,167.66
GND on TOP (solid shape): 185.72,170.9 185.72,165.75 185.53,165.56 182.23,165.56 182.17,165.63 182.17,166.96 183.06,167.85 183.06,171.28 183.25,171.47 185.15,171.47
GND on TOP (solid shape): 199.57,171.98 199.57,169.84 199.34,169.61 198.86,169.61 198.56,169.32 196.83,169.32 196.68,169.47 196.68,172.14 196.85,172.31 199.24,172.31
GND on TOP (solid shape): 255.95,107.6 255.95,107.18 255.95,107.17 255.95,105.46 255.85,105.36 254.17,105.36 253.86,105.67 253.86,107.21 254.31,107.67 255.88,107.67
GND on TOP (solid shape): 323.47,117.75 323.47,117.34 323.82,116.99 323.82,116.05 323.75,115.97 323.24,115.97 322.91,116.3 322.91,117.77 323.01,117.87 323.34,117.87
GND on TOP (solid shape): 330.91,148.39 328.21,148.39 328.21,148.15 328.07,148 328.07,146.77 328.21,146.62 328.21,145.69 327.41,145.69 327.41,149.19 330.91,149.19
GND on TOP (solid shape): 10.81,85.02 10.81,83.43 10.69,83.31 10.69,82.58 10.48,82.37 8.88,82.37 8.7,82.56 8.7,85.04 8.8,85.15 10.68,85.15
GND on TOP (solid shape): 18.76,176.58 18.72,176.55 17.4,176.55 17.27,176.68 17.27,176.93 17.13,177.07 16.43,177.07 16.23,177.27 16.23,178 16.36,178.13 18.76,178.13
GND on TOP (solid shape): 27.99,93.69 28.12,93.69 28.15,93.66 28.15,93.16 27.96,92.98 27.96,92.04 27.81,91.89 27.19,91.89 27.05,92.03 27.05,93.61 27.13,93.69 27.98,93.69
GND on TOP (solid shape): 31.33,72.55 31.33,72.11 31.16,71.95 29.61,71.95 29.22,71.56 27.79,71.56 27.64,71.71 27.63,71.71 27.63,71.99 28.4,72.76 31.12,72.76
GND on TOP (solid shape): 49.71,98.06 49.71,97.81 49.58,97.68 49.33,97.68 49.07,97.43 49.07,94.76 48.82,94.51 48.18,94.51 48.06,94.63 48.06,97.55 48.69,98.19 49.58,98.19
GND on TOP (solid shape): 89.36,84.37 89.36,84.27 89.36,83.67 88.97,83.28 87.49,83.28 87.36,83.41 87.36,84.05 87.5,84.2 88.27,84.2 88.59,84.51 89.22,84.51
GND on TOP (solid shape): 213.28,187.72 213.28,186.71 213.03,186.45 211.38,186.45 211.06,186.14 207.12,186.14 206.43,186.84 205.66,186.84 205.54,186.96 205.54,187.72 205.71,187.9 213.11,187.9
GND on TOP (solid shape): 246.11,96.79 246.11,95.97 245.99,95.84 245.67,95.84 245.41,96.09 243.64,96.09 243.57,96.16 243.57,96.73 243.64,96.79 245.61,96.79 245.73,96.92 245.99,96.92
GND on TOP (solid shape): 34.63,96.32 34.63,95.08 34.54,94.99 30.05,94.99 30.04,94.98 29.9,94.98 29.78,95.11 29.78,96.28 30,96.5 30.1,96.5 30.1,96.51 34.44,96.51
GND on TOP (solid shape): 227.31,187.03 228.95,187.03 229.27,186.71 229.27,185.54 229.26,185.54 228.88,185.16 224.94,185.16 224.79,185.3 224.79,186.48 225.5,187.19 227.15,187.19
GND on TOP (solid shape): 243.42,175.86 243.42,174.1 243.47,174.05 243.47,174.02 243.5,174.02 243.68,173.83 243.68,173.5 243.59,173.4 242.16,173.4 241.93,173.63 241.93,175.81 242.17,176.05 243.23,176.05
GND on TOP (solid shape): 324.13,78.21 324.13,75.02 324.1,75 324.1,73.37 323.9,73.17 317.23,73.17 315.67,74.73 315.67,75.48 315.96,75.77 319.39,75.77 319.76,76.14 319.76,78.11 320.03,78.38 323.96,78.38
GND on TOP (solid shape): 231.13,77.42 231.13,76.22 231.29,76.06 232.05,76.06 232.46,75.65 235.19,75.65 235.25,75.58 235.25,74.63 235.19,74.57 230.68,74.57 230.11,75.14 230.11,77.42 230.24,77.55 231,77.55
GND on TOP (solid shape): 4.69,135.96 6.73,135.96 6.84,135.85 6.84,135.64 6.72,135.52 4.92,135.52 4.85,135.45 4.13,135.45 4.02,135.56 3.98,135.63 3.94,135.68 3.94,135.98 4.14,136.18 4.47,136.18
GND on TOP (solid shape): 50.21,79.2 53.12,79.2 53.28,79.04 53.28,77.39 53.07,77.19 49.17,77.19 49.17,77.19 48.6,77.19 48.49,77.3 48.49,79.88 48.59,79.98 49.43,79.98
GND on TOP (solid shape): 182,80.54 182,78.96 181.7,78.66 177.56,78.66 177.35,78.45 177.35,77.79 177.08,77.52 176.25,77.52 176.08,77.69 176.08,78.39 177.12,79.42 177.12,80.26 177.24,80.38 179.91,80.38 180.23,80.7 181.84,80.7
GND on TOP (solid shape): 188.9,74.19 188.99,74.1 190.89,74.1 190.93,74.06 190.93,73.2 190.9,73.17 188.01,73.17 187.84,73.34 187.84,74.5 187.91,74.57 188.52,74.57
GND on TOP (solid shape): 8.65,130.28 8.65,130.14 9.23,130.14 9.41,130.32 9.6,130.32 9.74,130.18 9.74,129.44 9.41,129.11 9.23,129.11 8.42,129.92 8.39,129.96 8.29,129.96 8.16,130.09 8.16,130.27 8.31,130.42 8.51,130.42
GND on TOP (solid shape): 9.14,132.52 9.15,132.51 9.15,132.44 9.68,131.91 9.68,131.88 10.08,131.48 10.08,131.27 9.95,131.14 9.75,131.14 9.59,131.3 8.76,131.3 8.73,131.34 8.73,132.79 8.75,132.81 9.14,132.81
GND on TOP (solid shape): 29.21,110.28 29.21,109.8 29.29,109.72 29.62,109.72 29.69,109.64 29.69,108.7 29.54,108.55 28.3,108.55 28.22,108.63 28.22,109.06 28.32,109.16 28.58,109.16 28.75,109.34 28.75,110.28 28.8,110.33 29.16,110.33
GND on TOP (solid shape): 179.44,187.75 179.44,185.89 178.98,185.43 178.98,185 178.73,184.75 175.88,184.75 175.58,185.05 175.58,185.94 175.23,186.3 175.15,186.3 175.14,186.32 174.64,186.32 174.63,186.3 173.35,186.3 173.22,186.43 173.22,187.49 173.61,187.88 179.31,187.88
GND on TOP (solid shape): 327.27,90.77 327.27,88.45 326.95,88.13 323.9,88.13 323.73,87.96 319.37,87.96 319.24,88.09 319.24,88.76 319.64,89.17 321.15,89.17 322.02,90.04 322.76,90.04 323.77,91.05 326.99,91.05
GND on TOP (solid shape): 275.06,96.83 275.06,94.66 274.74,94.34 271.42,94.34 271.13,94.63 271.13,96.75 271.25,96.87 272.11,96.87 272.26,96.72 272.26,96.23 272.34,96.16 273.16,96.16 273.29,96.28 273.29,96.92 273.48,97.11 274.78,97.11
GND on TOP (solid shape): 123.77,82.29 123.77,80.57 123.7,80.51 123.7,79.52 123.48,79.31 122.94,79.31 122.77,79.47 122.77,81.83 122.65,81.95 121.72,81.95 121.42,82.26 121.42,82.51 121.65,82.74 121.68,82.74 121.76,82.73 121.84,82.75 123.31,82.75
GND on TOP (solid shape): 113.2,129.57 113.2,127.81 112.92,127.53 110.67,127.53 110.16,128.03 109.65,128.03 109.4,127.78 109.4,127.4 109.27,127.27 108.51,127.27 108.41,127.38 108.41,127.8 108.76,128.16 108.76,128.54 108.51,128.8 108.51,129.18 109.02,129.18 110.22,130.38 112.38,130.38
GND on TOP (solid shape): 177.56,149.42 177.56,148.97 178.3,148.23 178.3,146.64 178.17,146.51 177.66,146.51 177.47,146.7 177.47,147.9 177.31,148.06 176.5,148.06 176.2,148.36 176.2,149.07 176.34,149.21 177.1,149.21 177.21,149.32 177.21,149.41 177.32,149.52 177.46,149.52
GND on TOP (solid shape): 9.77,135.3 9.77,134.47 9.65,134.35 9.42,134.35 9.18,134.11 9.18,134.02 9.15,133.99 8.39,133.99 8.21,133.81 7.97,133.81 7.95,133.83 7.95,134.23 7.99,134.27 7.99,135.12 8.12,135.25 8.33,135.25 8.55,135.03 9.23,135.03 9.23,135.26 9.34,135.37 9.7,135.37
GND on TOP (solid shape): 210.05,181.37 213.54,181.37 213.92,180.99 213.92,179.34 213.66,179.09 212.92,179.09 212.47,178.63 210.06,178.63 209.73,178.96 209.73,180.61 209.6,180.74 202.11,180.74 201.98,180.87 201.98,181.76 202.11,181.89 204.24,181.89 204.56,182.21 209.21,182.21
GND on TOP (solid shape): 273.29,76.73 273.29,75.84 273.23,75.77 272.06,75.77 271.86,75.57 271.86,74.85 271.45,74.44 271.45,73.17 271.64,72.98 273,72.98 273.12,72.86 273.67,72.86 273.8,72.74 273.8,72.09 273.67,71.96 270.81,71.96 270.43,72.34 270.43,76.41 270.81,76.79 273.23,76.79
GND on TOP (solid shape): 9.25,136.42 9.59,136.42 9.77,136.25 9.77,136.05 9.65,135.93 9.49,135.93 9.41,135.94 9.33,135.95 9.23,136.05 9.23,136.21 8.65,136.21 8.65,135.97 8.54,135.86 8.22,135.86 7.71,136.37 7.71,136.59 7.86,136.75 8,136.75 8.02,136.75 8.38,137.11 8.56,137.11
GND on TOP (solid shape): 25.8,112.16 25.9,112.16 25.95,112.1 25.95,111.3 26.04,111.21 26.02,111.2 26.02,110.7 25.86,110.54 25.66,110.54 25.53,110.67 25.53,110.94 25.31,111.16 25.31,111.75 25.31,111.8 25.2,111.91 25.16,111.91 25.11,111.95 24.2,111.95 24.16,111.99 24.16,112.25 24.47,112.56 25.39,112.56
GND on TOP (solid shape): 166.51,183.33 166.51,182.69 166.6,182.6 166.61,182.59 166.74,182.46 166.74,182.22 166.6,182.08 166.6,181.76 166.52,181.68 166.52,181.67 166.14,181.28 164.79,181.28 164.71,181.36 164.71,182.14 165.15,182.58 165.15,182.67 165.16,182.67 165.16,183.1 165.57,183.5 166.33,183.5
GND on TOP (solid shape): 338.51,167.45 338.51,163.9 338.33,163.72 336.21,163.72 336.21,163.72 336.18,163.7 334.54,163.7 334.42,163.82 334.42,166.42 334.7,166.7 334.7,167.1 334.74,167.13 335.15,167.13 335.51,166.77 336.6,166.77 336.96,167.12 336.96,167.58 336.98,167.61 338.35,167.61
GND on TOP (solid shape): 169.37,86.42 169.37,85.67 169.51,85.54 169.51,85.11 169.65,84.97 169.69,84.9 169.74,84.84 169.74,78.35 169.78,78.31 169.78,75.87 169.81,75.84 169.81,75.27 169.76,75.22 168.68,75.22 168.54,75.36 168.54,77.68 169.36,78.49 169.36,84.69 168.81,85.23 168.81,86.39 168.88,86.46 169.34,86.46
GND on TOP (solid shape): 9.25,79.26 9.25,77.75 9.4,77.6 12.27,77.6 12.36,77.51 12.36,76.64 12.2,76.48 11.79,76.48 11.02,77.25 8.78,77.25 8.54,77.5 8.09,77.5 7.59,77.01 7.59,76.52 7.49,76.42 6.35,76.42 5.99,76.07 4.8,76.07 4.7,76.17 4.7,79.23 4.76,79.3 4.81,79.3 4.87,79.36 9.14,79.36
GND on TOP (solid shape): 52.37,74.06 52.37,73.04 52.63,72.79 54.28,72.79 54.28,71.9 53.14,71.9 52.84,71.6 52.84,70.74 52.5,70.4 52.5,69.59 52.43,69.52 52.14,69.52 51.41,68.79 51.41,68.29 51.18,68.06 50.17,68.06 49.7,68.54 49.7,73.54 50.34,74.19 52.25,74.19
GND on TOP (solid shape): 85.57,83.89 85.57,82.21 85.01,81.65 85.01,81.18 85.21,80.98 85.54,80.98 85.66,80.86 85.66,80.59 85.51,80.44 84.75,80.44 84.15,79.84 84.15,79.49 84.07,79.42 83.63,79.42 83.53,79.52 83.53,80.26 84.33,81.06 84.33,81.73 84.99,82.39 84.99,82.73 84.51,83.21 84.33,83.21 84.26,83.27 84.26,83.81 84.37,83.93 85.54,83.93
GND on TOP (solid shape): 107.8,162.22 107.8,160.62 108.38,160.04 109.4,160.04 109.91,159.53 110.92,159.53 111.18,159.78 114.6,159.78 114.99,159.4 115.75,159.4 117.65,157.5 117.65,156.48 117.4,156.23 113.59,156.23 113.21,155.85 113.21,154.83 112.83,154.45 109.14,154.45 108.76,154.83 108.76,156.74 108.13,157.37 105.84,157.37 104.95,158.26 104.95,159.78 106.6,161.44 106.6,162.32 106.86,162.58 107.44,162.58
GND on TOP (solid shape): 147.49,148.18 147.49,142.97 147.26,142.74 145.45,142.74 145.38,142.82 145.38,143.81 145.44,144.01 145.38,144.21 145.38,145.51 145.44,145.71 145.38,145.91 145.38,148.01 145.65,148.28 147.39,148.28
GND on TOP (solid shape): 5.29,107.83 5.38,107.82 5.48,107.83 5.49,107.84 8.57,107.84 9.07,107.33 9.07,105.8 9.32,105.56 10.01,105.56 10.05,105.52 10.05,105.1 9.81,104.86 9.81,104.22 9.45,103.86 9.21,103.86 8.55,103.21 4.23,103.21 4.21,103.23 3.63,103.23 3.5,103.36 3.5,104.5 4.11,105.11 4.11,107.33 4.12,107.34 4.12,107.74 4.21,107.84 5.28,107.84
GND on TOP (solid shape): 18.33,80.83 18.33,79.64 17.92,79.23 16.47,79.23 16.29,79.05 16.29,76.59 15.69,75.99 15.69,74.15 15.57,74.03 14.22,74.03 14.2,74.04 14.07,74.04 14.03,74.09 14.02,74.08 13.28,74.08 13.01,74.36 13.01,74.67 13,74.67 13,75.18 13.03,75.2 13.03,77.08 14.02,78.07 14.02,79.79 14.36,80.12 17.71,80.12 17.84,80.26 17.84,80.79 17.99,80.94 18.22,80.94
GND on TOP (solid shape): 259.13,108.27 259.13,107.56 259.64,107.06 259.64,104.29 259.63,104.27 259.63,101.78 258.37,100.53 257.76,100.53 257.56,100.73 257.56,102.08 258.17,102.68 258.17,103.42 258.65,103.9 258.65,105.42 258.65,105.48 258.63,105.5 257.83,105.5 257.78,105.56 257.78,105.66 257.84,105.72 258.61,105.72 258.65,105.76 258.65,106.9 258.1,107.45 258.1,108.38 258.17,108.45 258.95,108.45
GND on TOP (solid shape): 241.76,180.06 242.11,179.75 242.47,180.06 242.47,180.1 244.04,180.1 244.37,179.77 244.37,178.55 244.22,178.4 240.49,178.4 240.28,178.61 240.28,179.82 240.56,180.1 241.75,180.1
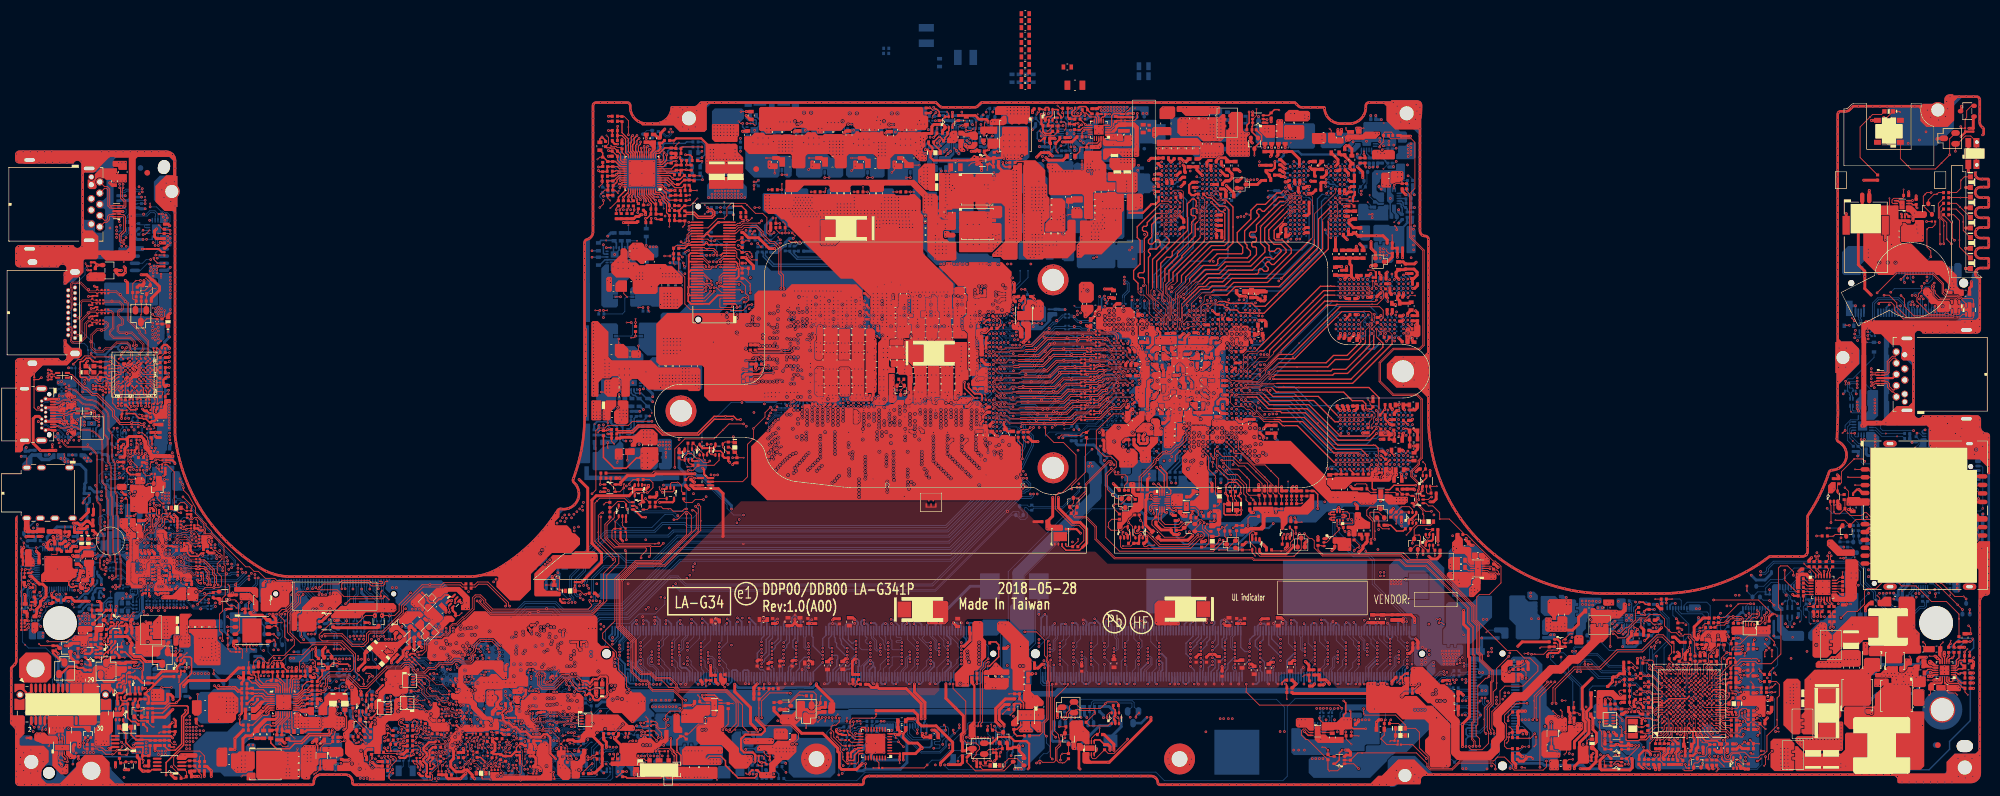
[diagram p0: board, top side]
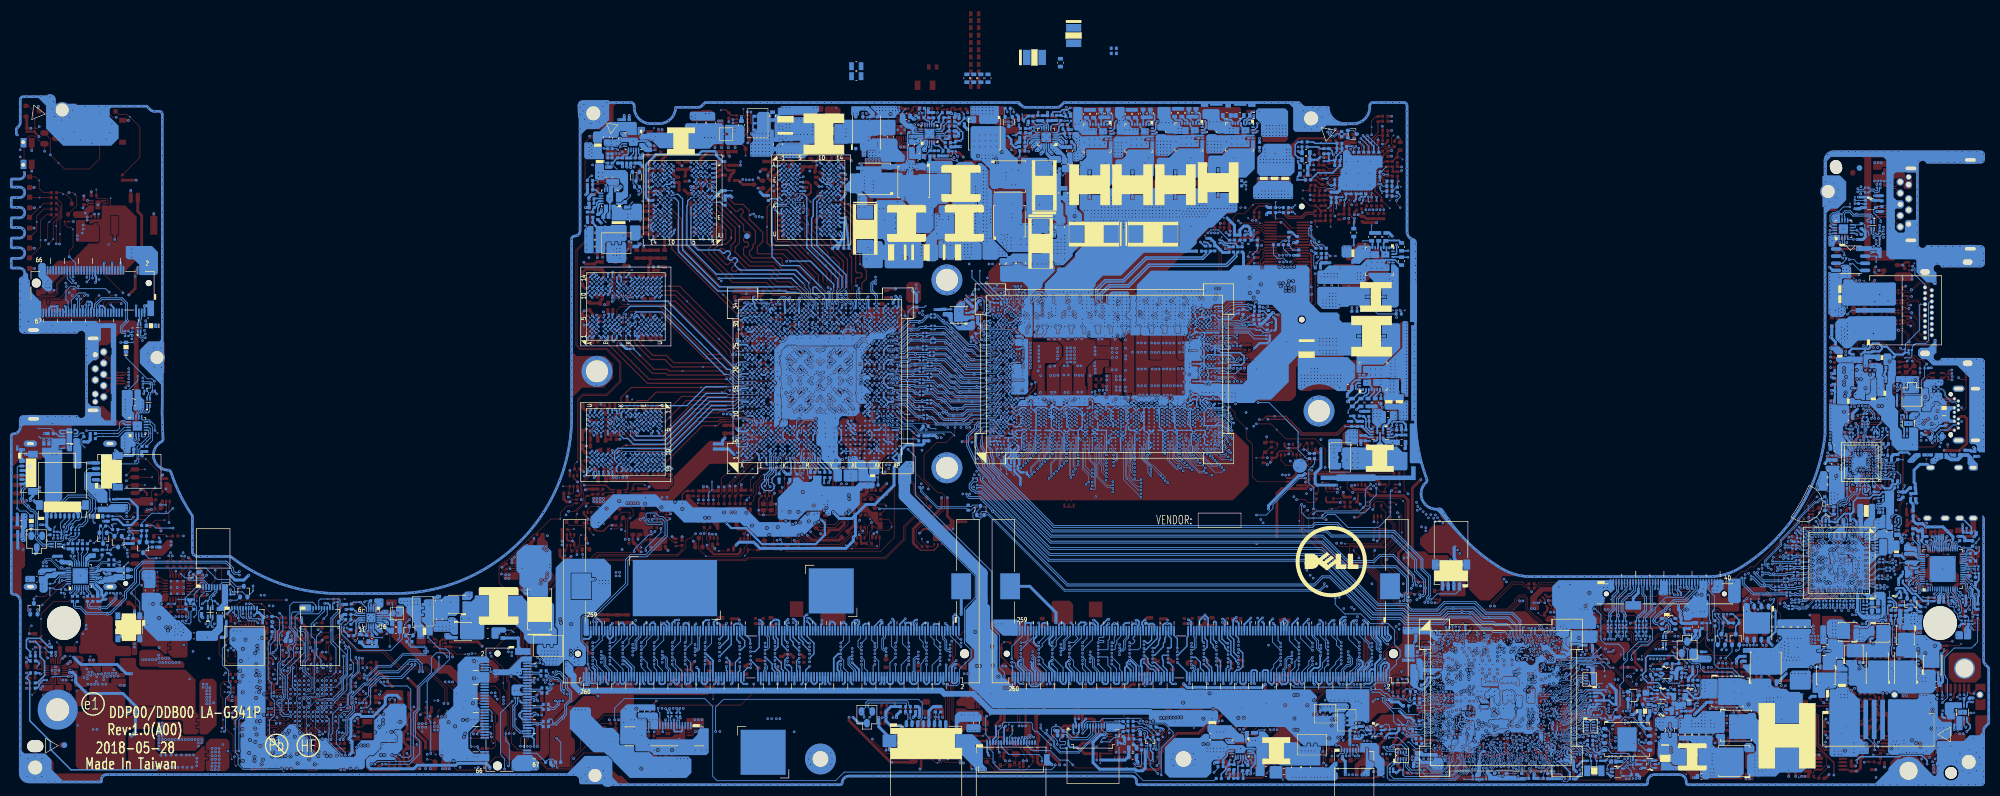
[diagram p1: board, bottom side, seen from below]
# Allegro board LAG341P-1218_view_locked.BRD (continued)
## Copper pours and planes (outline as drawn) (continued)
GND on TOP (solid shape): 104.44,147.72 104.44,143.27 105.08,142.64 112.06,142.64 113.33,141.37 120.45,141.37 120.83,140.99 120.83,137.43 120.57,137.18 118.8,137.18 118.54,137.43 111.56,137.43 109.65,139.34 108.64,139.34 108.25,138.96 108.25,136.42 108,136.16 106.86,136.16 106.78,136.24 106.78,139.16 106.1,139.85 105.1,139.85 104.7,139.44 103.4,139.44 102.67,138.7 102.67,136.29 102.54,136.16 101.52,136.16 101.4,136.29 101.4,149.37 101.65,149.62 102.54,149.62
GND on TOP (solid shape): 163.36,141.52 163.36,138.31 163.37,138.3 163.37,136.1 162.55,136.1 162.36,135.91 162.36,135.75 162.36,135.71 162.36,135.53 162.57,135.31 162.79,135.31 162.89,135.21 162.89,134.9 162.86,134.88 162.19,134.88 162.04,135.03 162.04,135.75 162.05,135.82 162.04,135.89 162.04,136.04 161.91,136.16 161.23,136.16 161.23,137.14 161.28,137.2 161.28,141.76 161.41,141.89 162.98,141.89
GND on TOP (solid shape): 201.35,139.21 201.35,139.02 200.77,138.45 200.77,137.69 201.28,137.18 201.28,136.99 201.19,136.9 201.17,136.9 201.17,136.87 201.09,136.8 201.03,136.8 200.9,136.67 200.9,136.16 200.65,135.91 200.65,133.81 200.52,133.69 200.14,133.69 200.08,133.75 200.08,134.36 200.08,134.37 200.12,134.52 200.08,134.67 200.08,134.69 200.08,137.63 200.23,137.78 200.23,138.94 200.65,139.36 201.2,139.36
GND on TOP (solid shape): 5.11,130.41 6.11,130.41 6.25,130.26 6.25,130.04 6.17,129.95 5.4,129.95 5.1,130.11 4.77,130.09 4.76,130.09 4.71,130.09 4.68,130.06 4.55,129.97 4.44,129.85 4.15,129.85 3.97,130.03 3.97,130.36 4,130.42 4.03,130.49 4.08,130.54 4.98,130.54
GND on TOP (solid shape): 108,135.27 108,131.59 107.69,131.28 105.9,131.28 105.46,131.72 105.46,133.5 105.91,133.95 105.95,133.93 106.44,134.16 106.14,134.61 106.1,134.62 106.1,135.4 106.22,135.53 107.75,135.53
GND on TOP (solid shape): 174.72,87.65 175.63,87.65 175.76,87.52 175.76,86.83 175.6,86.67 174.61,86.67 174.39,86.74 174.17,86.67 173.57,86.67 173.34,86.75 173.12,86.67 171.3,86.67 171.18,86.79 171.18,87.27 171.48,87.56 172.11,87.56 172.96,88.41 172.96,88.6 173.24,88.89 173.48,88.89
GND on TOP (solid shape): 142.57,148.72 142.57,148.7 142.58,148.61 142.61,148.52 142.61,148.51 142.61,143.06 142.28,142.73 141.47,142.73 141.17,143.02 141.17,145.91 141.55,146.29 141.55,146.41 141.55,147.03 141.61,147.21 141.55,147.4 141.55,148.42 141.66,148.56 141.68,148.73 141.67,148.76 141.86,148.95 142.34,148.95
GND on TOP (solid shape): 155.36,140.13 155.36,137.07 155.33,137.05 155.14,136.62 155.58,136.44 155.61,136.46 155.73,136.33 155.73,135.56 155.25,135.07 154.54,135.07 154.3,135.3 154.3,137.19 154.31,137.19 154.31,137.75 154.3,137.75 154.3,140.12 154.39,140.21 155.27,140.21
GND on TOP (solid shape): 265.33,89.25 265.33,88.37 265.19,88.23 264.66,88.23 264.42,88 264.42,87.43 264.38,87.15 264.55,86.92 264.59,86.88 264.92,86.88 265.11,87.07 265.73,87.07 265.78,87.01 265.78,85.44 265.62,85.28 263.81,85.28 263.28,85.81 263.28,88.2 264.45,89.37 265.22,89.37
GND on TOP (solid shape): 337.72,88.46 337.72,87.52 337.51,87.32 337.51,86.58 337.67,86.43 338.63,86.43 338.82,86.23 338.82,84.71 338.61,84.5 336.67,84.5 336.46,84.7 332.88,84.7 332.73,84.86 332.73,85.11 332.73,85.11 332.73,86 332.54,86.19 331.84,86.19 331.81,86.22 329.93,86.22 329.81,86.35 329.81,86.89 329.93,87.01 330.82,87.01 332.03,88.22 333.81,88.22 333.87,88.16 333.87,87.27 334.06,87.08 335.01,87.08 335.6,87.67 335.6,88.03 335.67,88.09 336.47,88.09 336.89,88.51 337.67,88.51
GND on TOP (solid shape): 96.81,73.19 96.81,72.41 96.38,72.41 96.31,72.35 96.29,72.36 96.06,71.94 96.51,72.1 96.51,72.15 96.81,72.15 96.81,71.74 96.51,71.44 96.51,70.94 97.72,69.74 97.72,68.35 97.33,67.96 96.32,67.96 95.34,68.94 95.34,71.25 95.6,71.51 95.6,71.94 95.25,72.29 95.25,73.07 95.44,73.26 96.74,73.26
GND on TOP (solid shape): 31.5,101.82 31.5,101.78 31.46,101.74 31.44,101.71 31.37,101.65 31.29,101.68 30.75,101.33 31.39,101.33 31.43,101.37 31.48,101.35 31.5,101.33 31.5,100.27 31.06,99.84 29.9,99.84 29.49,100.25 29.49,101.87 29.87,102.25 31.06,102.25
GND on TOP (solid shape): 158.52,141.4 158.52,140.31 158.58,140.25 158.58,138.61 158.5,138.53 158.5,137.38 158.57,137.31 158.57,135.33 158.02,134.78 157.32,134.78 157.23,134.87 157.23,135.68 157.66,136.12 157.66,136.52 157.69,136.59 157.76,136.62 158.09,136.95 157.76,137.28 157.69,137.31 157.66,137.38 157.66,139.82 157.41,140.07 156.78,140.07 156.76,140.09 156.16,140.09 155.8,140.44 155.8,141.25 155.58,141.47 154.82,141.47 154.69,141.6 154.69,142.63 154.84,142.78 157.14,142.78
GND on TOP (solid shape): 150.67,148.35 150.8,148.33 150.93,148.35 150.94,148.35 151.44,148.35 151.89,147.9 151.89,147.06 151.89,147.05 151.86,146.93 151.89,146.8 151.89,146.79 151.89,146.65 152.15,146.39 152.15,137.1 151.81,136.77 151.81,136.27 151.74,136.2 151.72,136.19 151.5,135.96 151.59,135.65 151.59,135.45 151.49,135.35 151.15,135.35 151.05,135.46 151.05,135.93 151.27,136.15 151.29,136.18 151.29,136.78 151.23,136.83 150.66,136.83 150.62,136.79 150.62,136.53 150.62,136.53 150.62,136.29 150.57,136.24 150.18,136.24 150.11,136.31 150.11,137 150.2,137.09 150.2,146.83 150.21,146.84 150.21,148 150.56,148.35 150.66,148.35
GND on TOP (solid shape): 161.31,172.3 162.6,172.3 163.06,171.84 163.06,168.36 163.73,167.68 164.81,167.68 164.92,167.79 164.92,168.34 164.77,168.5 164.77,168.9 164.9,169.03 166.19,169.03 166.27,168.95 166.27,166.05 166.05,165.83 164.2,165.83 163.98,165.61 163.98,164.46 164.26,164.18 164.64,164.18 165.1,163.72 166.07,163.72 166.34,163.44 166.34,160.88 166.36,160.86 166.36,160.67 166.08,160.4 162.88,160.4 161.21,162.07 161.21,168.55 160.96,168.8 160.52,168.8 160.34,168.98 160.34,171.66 158.24,173.75 153.59,173.75 153.47,173.63 153.47,172.87 153.21,172.61 151.05,172.61 150.93,172.74 150.93,173.5 150.67,173.75 149.95,173.75 149.73,173.86 149.52,173.75 147.75,173.75 147.5,173.5 147.5,172.74 147.37,172.61 144.07,172.61 143.81,172.87 143.81,173.5 143.56,173.75 139.24,173.75 138.1,172.61 136.07,172.61 135.94,172.74 135.94,174.64 136.06,174.76 158.85,174.76
GND on TOP (solid shape): 8.08,146.3 8.08,145.74 8.94,144.87 10.34,144.87 10.77,144.44 10.77,143.53 10.25,143.01 9.38,143.01 8.13,141.75 3.81,141.75 1.65,139.59 1.65,128.03 1.35,127.73 0.61,127.73 0.28,127.4 0.28,126.66 -0.1,126.28 -0.67,126.28 -1.13,126.28 -1.13,142.27 -0.9,142.83 -0.34,143.07 6.64,143.07 7.81,142.77 7.52,143.95 7.52,146.39 7.99,146.39
GND on TOP (solid shape): 168.29,145.83 168.29,141.03 168.54,140.78 168.54,139.29 168.33,139.08 167.84,139.08 167.82,139.07 167.8,139.07 167.58,138.97 167.49,138.75 167.49,138.73 167.45,138.7 167.45,136.54 167.2,136.29 167.1,136.27 167.03,136.35 166.47,136.55 166.66,135.99 166.75,135.92 166.72,135.81 166.46,135.54 166.07,135.54 165.89,135.72 165.89,137.11 166.15,137.37 166.15,142.05 166.05,142.15 164.17,142.15 163.08,143.25 163.08,145.14 163.84,145.91 168.21,145.91
GND on TOP (solid shape): 343.71,187.19 340.96,184.44 338.21,187.19 338.21,188.29 339.33,188.29 339.35,188.29 342.11,188.29 342.11,188.99 342.41,189.7 343.11,189.99 343.71,189.99
GND on TOP (solid shape): 248.96,188.66 249.26,187.94 249.21,186.59 247.29,183.97 244.21,185.02 243.87,185.73 243.72,186.5 243.71,186.59 243.71,188.94 244.71,188.94 244.77,188.94 248.24,188.94
GND on TOP (solid shape): 153.59,182.64 155.56,182.64 155.94,183.03 155.94,183.22 161.02,183.22 161.21,183.03 161.21,182.14 160.83,181.76 160.83,180.74 160.32,180.23 160.32,179.85 160.52,179.66 160.5,179.63 160.58,179.24 160.97,179.17 161,179.18 161.09,179.09 161.09,178.33 160.83,178.07 159.82,178.07 158.55,179.34 155.37,179.34 154.61,178.58 154.61,176.93 154.36,176.68 152.45,176.68 152.2,176.93 152.2,178.71 151.56,179.34 147.24,179.34 146.86,178.96 146.86,177.06 146.61,176.8 144.96,176.8 144.7,177.06 144.7,178.45 143.81,179.34 139.88,179.34 139.5,178.96 139.5,177.06 139.24,176.8 137.34,176.8 137.08,177.06 137.08,179.09 136.83,179.34 129.46,179.34 128.57,180.23 128.57,182.39 128.7,182.52 129.84,182.52 130.48,183.15 132,183.15 132.38,182.77 139.37,182.77 139.8,183.2 141.22,183.2 141.78,182.64 142.54,182.64 142.8,182.9 146.02,182.9 146.3,182.71 146.62,182.82 146.7,182.9 148.13,182.9 148.45,183.22 153.02,183.22
GND on TOP (solid shape): 137.9,76.1 137.9,75.23 137.32,74.65 137.29,74.67 136.81,74.23 137.45,74.15 137.53,74.2 137.62,74.16 137.72,74.06 137.85,74.01 137.9,74.01 137.9,72.99 136.45,71.54 135.43,71.54 134.19,70.3 134.19,69.43 134.14,69.34 134.04,69.34 133.5,69.03 134.04,68.72 134.14,68.72 134.19,68.63 134.19,68.52 133.97,68.3 131.48,68.3 131.24,68.53 131.24,69.13 131.49,69.38 132.9,69.38 133.04,69.52 133.04,70.97 133.21,71.15 133.33,71.15 134,71.81 134,72.32 133.78,72.54 132.89,72.54 132.73,72.7 132.73,72.98 132.54,73.17 132.37,73.17 132.16,73.27 131.94,73.17 131.03,73.17 130.89,73.31 130.89,73.75 131.32,74.18 133.73,74.18 134.5,74.95 136.44,74.95 136.96,75.47 136.96,76.07 137.07,76.18 137.82,76.18
GND on TOP (solid shape): 303.47,94.42 303.47,94.19 303.43,94.18 303.21,93.94 303.37,93.66 303.41,93.61 303.42,93.54 303.4,93.37 303.47,93.22 303.47,92.69 303.34,92.56 302.34,92.56 302.34,93.31 302.24,93.31 302.15,93.37 302.16,93.47 301.87,94.04 301.58,93.47 301.59,93.38 301.52,93.32 301.52,92.56 301.44,92.56 301.41,92.6 300.84,92.6 300.72,92.72 300.72,93.18 300.67,93.23 300.67,93.24 300.55,93.36 300.54,93.36 300.46,93.44 300.26,94.02 299.84,93.59 299.82,93.5 299.74,93.46 299.53,93.46 299.42,93.36 299.38,93.36 299.38,93.31 299.35,93.29 299.35,92.74 299.28,92.66 298.72,92.66 298.69,92.69 298.69,93.01 298.72,93.05 298.72,93.65 299.68,94.61 303.28,94.61
GND on TOP (solid shape): 21.53,142.17 21.53,142.01 21.29,141.77 21.29,141.6 21.25,141.59 21.02,141.3 21.25,141.01 21.29,141 21.29,140.8 21.25,140.79 21.02,140.5 21.25,140.21 21.29,140.2 21.29,140.06 21.21,139.98 21.2,139.97 21.11,139.91 21.04,139.82 21.04,139.81 20.85,139.62 20.83,139.61 20.73,139.56 20.64,139.47 19.95,139.47 19.68,139.2 19.66,139.19 19.42,138.94 19.59,138.63 19.62,138.61 19.62,138.46 19.06,137.91 18.8,137.91 18.72,137.99 18.72,138.22 19.17,138.68 19.17,138.8 19.18,138.81 19.19,138.9 19.18,138.99 19.17,138.99 19.17,139.06 19.1,139.14 19.1,139.4 19.12,139.44 19.24,139.56 19.34,139.56 19.49,139.71 19.49,139.78 19.69,140.11 19.49,140.43 19.49,140.56 19.58,140.62 19.64,140.7 19.78,140.7 19.81,140.67 19.85,140.63 19.89,140.59 19.96,140.51 20.28,140.51 20.51,140.75 20.51,140.79 20.67,140.95 20.67,141.02 20.82,141.16 20.82,141.44 20.7,141.56 20.7,141.68 20.7,141.68 20.7,141.85 20.91,142.06 21,142.06 21.25,142.32 21.39,142.32
GND on TOP (solid shape): 18.97,114.46 18.97,113.05 18.97,113.04 20,112.01 20.25,112.01 20.42,111.85 20.42,111.08 20.36,111.02 19.86,111.02 19.65,110.81 19.65,106.91 19.45,106.72 19.45,106.65 19.45,103.29 19.46,103.29 19.46,103.19 19.55,103.19 19.99,102.76 20.74,102.76 20.75,102.76 21.01,102.76 21.55,103.02 21.01,103.27 20.9,103.26 20.84,103.35 20.84,103.76 21.02,103.94 21.94,103.94 22.12,103.75 22.12,102.68 22.08,102.67 22.03,102.68 21.64,102.62 21.6,102.23 21.6,102.13 21.51,102.08 19.66,102.08 19.45,102.3 19.45,102.52 19.34,102.63 18.68,102.63 18.56,102.75 18.56,103.08 18.61,103.13 18.61,106.8 19.22,107.42 19.22,109.31 19.17,109.36 19.22,109.4 19.22,109.46 19.23,109.47 19.24,109.57 19.23,109.66 19.22,109.67 19.22,110.07 19.23,110.08 19.24,110.18 19.23,110.27 19.22,110.28 19.22,110.35 19.05,110.53 19.02,110.62 19.07,110.7 19.23,111.14 18.79,111.29 18.69,111.3 18.64,111.38 18.64,111.92 17.45,113.11 17.45,114.28 17.71,114.54 18.89,114.54
GND on TOP (solid shape): outline of 169 points within 232.31,119.69 244.17,123.69
GND on TOP (solid shape): outline of 170 points within 182.42,167.76 194.67,179.91
GND on TOP (solid shape): outline of 217 points within 160.04,146.14 163.33,154.36
GND on TOP (solid shape): outline of 231 points within 169.74,160.57 178.05,177.74
GND on TOP (solid shape): outline of 238 points within 154.46,145.27 158.66,154.52
GND on TOP (solid shape): outline of 250 points within 198.82,146.92 202.11,150.07
GND on TOP (solid shape): outline of 242 points within 205.52,128.16 211.9,134.19
GND on TOP (solid shape): outline of 271 points within 165.52,146.54 168.31,155.72
GND on TOP (solid shape): outline of 146 points within -2.03,66.9 350.26,115.08
GND on TOP (solid shape): outline of 660 points within 327.19,122.38 350.26,176.22
GND on TOP (solid shape): outline of 2017 points within -1.13,99.91 349.36,189.79
GND on BOTTOM (solid shape): 13.72,178.56 6.72,178.56 6.72,179.36 13.72,179.36
GND on BOTTOM (solid shape): 13.72,161.26 6.72,161.26 6.72,162.06 13.72,162.06
GND on BOTTOM (solid shape): 16.03,166.81 15.23,166.81 15.23,173.81 16.03,173.81
GND on BOTTOM (solid shape): 100.96,131.89 100.16,131.89 100.16,148.89 100.96,148.89
GND on BOTTOM (solid shape): 129.96,187.74 128.66,187.74 128.66,188.54 129.96,188.54
GND on BOTTOM (solid shape): 138.36,187.74 137.06,187.74 137.06,188.54 138.36,188.54
GND on BOTTOM (solid shape): 332.31,136.64 331.51,136.64 331.51,143.64 332.31,143.64
GND on BOTTOM (solid shape): 340.91,148.39 333.91,148.39 333.91,149.19 340.91,149.19
GND on BOTTOM (solid shape): 340.91,131.09 333.91,131.09 333.91,131.89 340.91,131.89
GND on BOTTOM (solid shape): 16.03,175.76 15.23,175.76 15.23,178.56 14.03,178.56 14.03,179.36 16.03,179.36
GND on BOTTOM (solid shape): 16.03,161.26 14.03,161.26 14.03,162.06 15.23,162.06 15.23,164.86 16.03,164.86
GND on BOTTOM (solid shape): 332.31,131.89 333.51,131.89 333.51,131.09 331.51,131.09 331.51,135.39 332.31,135.39
GND on BOTTOM (solid shape): 333.51,148.39 332.31,148.39 332.31,144.89 331.51,144.89 331.51,149.19 333.51,149.19
GND on BOTTOM (solid shape): 33.59,87.03 33.59,84.16 33.48,84.05 30.07,84.05 29.85,84.28 29.85,87.23 30.06,87.44 33.18,87.44
GND on BOTTOM (solid shape): 49.47,85.64 49.47,82.79 49.18,82.49 46.61,82.49 46.45,82.65 46.45,85.85 46.55,85.95 49.16,85.95
GND on BOTTOM (solid shape): 100.96,123.79 100.96,122.14 117.06,122.14 117.06,121.34 100.16,121.34 100.16,123.79 100.61,123.79
GND on BOTTOM (solid shape): 145.61,166.34 145.61,164.02 144.7,163.11 142.43,163.11 142.36,163.17 142.36,166.51 142.54,166.68 145.27,166.68
GND on BOTTOM (solid shape): 261.01,71.34 261.01,69.85 260.82,69.66 256.45,69.66 256.14,69.97 256.14,71.11 257.43,72.4 259.96,72.4
GND on BOTTOM (solid shape): 340.16,130.52 340.16,126.7 339.9,126.45 339.27,126.45 339.2,126.51 339.2,130.47 339.32,130.58 340.1,130.58
GND on BOTTOM (solid shape): 102.1,92.03 102.1,89.92 101.93,89.75 100.46,89.75 100.35,89.85 100.35,92.01 100.44,92.1 102.03,92.1
GND on BOTTOM (solid shape): 198.59,162.86 198.59,159.5 198.13,159.05 195.2,159.05 194.97,159.28 194.97,163.57 195.25,163.85 197.6,163.85
GND on BOTTOM (solid shape): 201.92,123.14 201.92,121.25 201.76,121.09 199.55,121.09 199.44,121.21 199.44,123.14 199.5,123.21 201.85,123.21
GND on BOTTOM (solid shape): 112.7,129.81 112.7,127.97 112.26,127.53 111.75,127.53 111.56,127.72 110.67,127.72 110.41,127.97 110.41,130.19 110.6,130.38 112.13,130.38
GND on BOTTOM (solid shape): 128.57,187.09 128.57,185.69 127.69,184.8 127.69,182.64 127.43,182.39 123.11,182.39 122.86,182.64 122.86,186.96 123.37,187.47 128.19,187.47
GND on BOTTOM (solid shape): 187.17,177.89 187.17,176.12 187.02,175.96 182.83,175.96 182.55,176.24 182.55,177.94 182.73,178.12 186.94,178.12
GND on BOTTOM (solid shape): 213.03,187.72 213.03,186.71 212.78,186.45 211.25,186.45 211.12,186.33 206.93,186.33 206.3,186.96 206.3,187.72 206.47,187.89 212.86,187.89
GND on BOTTOM (solid shape): 213.94,180.81 213.94,179.37 213.66,179.09 212.99,179.09 212.5,178.6 208.94,178.6 208.2,179.34 208.2,181.25 208.33,181.37 213.37,181.37
GND on BOTTOM (solid shape): 229.32,186.66 229.32,185.65 229.01,185.34 224.81,185.34 224.78,185.37 224.78,186.57 225.08,186.87 229.11,186.87
GND on BOTTOM (solid shape): 318.74,99.89 318.44,99.59 318.44,99.21 318.31,99.08 318.06,99.08 318,99.14 318,99.65 317.76,99.89 317.76,100.28 318.74,100.28
GND on BOTTOM (solid shape): 34.9,96.56 35.63,96.56 35.81,96.38 35.81,95.06 35.74,94.99 29.95,94.99 29.83,95.11 29.83,96.43 29.96,96.56 34.9,96.56
GND on BOTTOM (solid shape): 6.73,129.73 6.73,129.59 6.91,129.41 6.91,128.64 6.82,128.55 6.82,128.45 6.67,128.3 6.46,128.3 5.81,128.95 5.81,129.18 6.24,129.61 6.24,129.73 6.4,129.89 6.57,129.89
GND on BOTTOM (solid shape): 285.74,95.79 285.74,94.32 285.1,93.68 284.78,93.68 284.72,93.74 284.72,94 285.52,94.79 285.52,95.79 285.58,95.85 285.67,95.85
GND on BOTTOM (solid shape): 25.21,89.31 25.21,87.9 25.45,87.66 25.45,87.35 25.37,87.27 23.4,87.27 23.32,87.35 23.32,87.93 23.43,88.03 23.57,88.03 24.14,88.6 24.14,89.14 24.33,89.32 25.19,89.32
GND on BOTTOM (solid shape): 345.24,105.17 345.24,104.6 345.11,104.48 344.28,104.48 343.78,104.98 342.82,104.98 342.63,105.17 342.13,105.17 342.06,105.24 342.06,105.56 342.13,105.62 344.79,105.62
GND on BOTTOM (solid shape): 159.71,148.77 159.71,148.58 159.32,148.2 159.32,147.56 159.2,147.43 158.98,147.43 158.88,147.53 158.88,148.41 159.06,148.59 159.06,148.61 159.36,148.91 159.56,148.91
GND on BOTTOM (solid shape): 247.52,166.44 247.6,166.3 247.74,166.22 248.08,165.87 248.08,161.88 247.91,161.71 246.54,161.71 246.43,161.82 246.43,166.37 246.59,166.54 247.42,166.54
GND on BOTTOM (solid shape): 328.08,137.29 328.08,134.66 328.31,134.43 328.31,133.83 328.21,133.74 327.64,133.74 327.55,133.83 327.43,133.83 327.43,133.84 326.47,133.84 326.36,133.95 326.36,135.54 327,136.19 327,137.37 327.1,137.46 327.9,137.46
GND on BOTTOM (solid shape): 137.4,182.52 137.4,179.66 137.21,179.47 134.62,179.47 133.45,180.64 129.75,180.64 129.75,181.79 130.6,181.79 130.6,182.15 130.26,182.49 129.08,182.49 129.08,182.79 131.03,182.79 131.16,182.66 135.51,182.66 135.69,182.83 137.08,182.83
GND on BOTTOM (solid shape): 146.42,182.52 146.42,179.22 146.23,179.02 144.08,179.02 142.46,180.64 138.76,180.64 138.76,181.79 139.61,181.79 139.61,182.15 139.27,182.49 138.1,182.49 138.1,182.79 140.04,182.79 140.17,182.66 144.53,182.66 144.7,182.83 146.1,182.83
GND on BOTTOM (solid shape): 149.06,182.47 153.51,182.47 153.91,182.07 153.91,178.9 153.72,178.71 152.45,178.71 152.2,178.96 152.2,179.61 151.35,180.45 147.65,180.45 147.65,181.6 148.5,181.6 148.5,181.96 148.16,182.3 146.99,182.3 146.99,182.6 148.93,182.6
GND on BOTTOM (solid shape): 152.59,148.8 152.59,148.61 152.21,148.24 152.21,147.62 152.08,147.49 151.89,147.49 151.77,147.61 151.77,148.2 151.39,148.58 151.39,148.77 151.51,148.89 151.7,148.89 151.85,148.75 152.12,148.75 152.28,148.91 152.47,148.91
GND on BOTTOM (solid shape): 154.94,148.79 154.94,148.59 154.56,148.21 154.56,147.5 154.5,147.43 154.24,147.43 154.12,147.56 154.12,148.2 154.11,148.2 154.11,148.35 154.44,148.68 154.44,148.74 154.63,148.93 154.8,148.93
GND on BOTTOM (solid shape): 272.26,96.72 272.26,96.41 272.4,96.27 274.51,96.27 274.88,95.9 274.88,94.48 274.78,94.38 272.04,94.38 271.51,93.85 270.71,93.85 270.56,94 270.56,96.28 271.2,96.92 272.06,96.92
GND on BOTTOM (solid shape): 8.43,129.68 8.43,129.34 8.55,129.22 8.93,129.22 9.12,129.04 9.12,128.86 8.78,128.52 8.78,128.36 8.65,128.23 8.46,128.23 8.31,128.37 8.31,128.47 8.11,128.66 8.11,129.36 7.95,129.52 7.95,129.74 8.06,129.85 8.26,129.85
GND on BOTTOM (solid shape): 179.38,187.77 179.38,186.42 179.23,186.27 178.95,186.27 178.87,186.35 178.34,186.35 178.33,186.33 178.29,186.33 178.22,186.27 177.92,186.27 177.72,186.08 177.72,184.91 177.53,184.72 174.79,184.72 174.32,185.19 174.32,187.79 174.43,187.91 179.25,187.91
GND on BOTTOM (solid shape): 28.17,95.35 28.17,93.03 28.17,93.03 28.15,92.92 28.17,92.81 28.17,92.8 28.17,92.23 28.08,92.15 27.98,92.15 27.98,92.14 27.13,92.14 27.04,92.23 27.04,93.64 27.15,93.74 27.15,95.32 27.33,95.5 28.02,95.5
GND on BOTTOM (solid shape): 113.08,179.72 113.08,176.98 113.51,176.55 113.51,175.59 113.9,175.2 113.9,173.63 113.15,172.88 107.98,172.88 107.19,173.68 107.19,176.47 106.73,176.93 106.22,176.93 106.07,177.08 106.07,178.81 106.35,179.09 111.48,179.09 111.77,179.38 111.77,179.66 112.14,180.03 112.78,180.03
GND on BOTTOM (solid shape): 152.78,78.11 152.84,78.09 152.9,78.08 152.91,78.07 152.97,78.01 155.24,78.01 155.24,76.75 155.04,76.54 153.41,76.54 152.9,77.06 152.02,77.06 151.89,77.18 151.89,77.69 152.02,77.82 152.43,77.82 152.61,78 152.62,78 152.62,78.01 152.74,78.13
GND on BOTTOM (solid shape): 178.05,177.68 178.05,163.89 177.98,163.82 177.7,163.82 177.22,163.34 177.22,160.72 177.04,160.55 174.71,160.55 174.23,161.03 172.87,161.03 172.72,161.18 172.72,161.54 175.5,164.32 175.5,172.78 176.2,173.48 176.2,176.34 176.2,176.58 177.36,177.74 177.99,177.74
GND on BOTTOM (solid shape): 190.87,178.14 190.87,177.88 191.19,177.56 195.12,177.56 195.25,177.44 195.25,176.93 195,176.68 192.33,176.68 191.95,176.29 190.93,176.29 190.8,176.42 190.8,176.61 190.68,176.74 189.47,176.74 189.28,176.93 189.28,178.07 189.47,178.26 190.23,178.26 190.3,178.33 190.67,178.33
GND on BOTTOM (solid shape): 106.26,160.56 108.93,160.56 109.97,159.53 115.62,159.53 116.51,158.64 117.4,158.64 117.65,158.39 117.65,156.48 117.4,156.23 109.65,156.23 108.99,156.89 108.99,158.11 108.55,158.54 104.85,158.54 104.85,159.69 105.7,159.69 105.7,160.05 105.36,160.39 104.19,160.39 104.19,160.69 106.13,160.69
GND on BOTTOM (solid shape): 50.28,79.09 50.85,79.09 50.98,79.22 50.98,79.55 51.05,79.62 52.32,79.62 52.4,79.55 52.4,79 52.53,78.87 53.14,78.87 53.26,78.75 53.26,77.13 53.37,77.03 53.37,76.38 53.21,76.22 46.86,76.22 46.74,76.35 45.39,76.35 45.16,76.57 45.16,80.18 45.22,80.23 49.13,80.23
GND on BOTTOM (solid shape): 52.44,74 52.44,73.74 52.31,73.61 51.93,73.61 51.8,73.49 51.8,70.57 51.93,70.44 54.34,70.44 55.04,71.14 56.38,71.14 56.48,71.04 56.48,69.72 56.44,69.68 50.85,69.68 50.47,70.06 50.47,71.82 50.05,72.24 50.05,73.88 50.28,74.11 50.9,74.11 50.91,74.12 52.31,74.12
GND on BOTTOM (solid shape): 106.79,134 107.75,134 107.87,133.88 107.87,131.59 107.12,130.83 107.12,129.56 107.03,129.48 106.92,129.48 106.84,129.56 106.84,130.59 105.97,131.46 105.59,131.46 105.46,131.59 105.46,133.5 105.59,133.62 105.97,133.62 106.35,134 106.79,134
GND on BOTTOM (solid shape): 109.02,73.65 109.02,72.75 109.03,72.73 109.03,71.4 109.04,71.4 109.04,69.94 109.97,69.01 109.97,68.74 109.87,68.64 108.45,68.64 108.33,68.76 108.33,69.64 107.62,70.35 107.62,71.14 107.77,71.29 108.27,71.29 108.6,71.62 108.6,72.67 108.61,72.69 108.61,73.63 108.71,73.73 108.94,73.73
GND on BOTTOM (solid shape): 185.77,168.69 185.77,165.96 187.31,164.41 187.31,160.49 187.09,160.27 185.57,160.27 185.37,160.47 185.37,163.98 185.22,164.13 182.26,164.13 182.24,164.15 182.24,167.43 182.26,167.44 182.26,168.19 182.58,168.52 185.01,168.52 185.13,168.64 185.13,168.68 185.28,168.83 185.63,168.83
GND on BOTTOM (solid shape): 41.83,99.21 41.83,94.38 41.45,94 37.33,94 37.11,94.22 37.11,94.39 37.11,94.4 37.14,94.54 37.11,94.68 37.11,94.69 37.11,97.25 37.04,97.32 37.04,97.68 37.17,97.81 40.31,97.81 40.69,98.19 40.69,99.21 40.94,99.46 41.58,99.46
GND on BOTTOM (solid shape): 44.57,103.48 44.57,101.28 44.57,101.27 44.54,101.09 44.57,100.91 44.57,100.91 44.57,99.83 44.18,99.45 42.65,99.45 42.4,99.7 42.33,99.7 42.33,103.62 42.41,103.68 42.47,103.77 42.48,103.79 44.26,103.79
GND on BOTTOM (solid shape): 261.02,84.65 261.02,83.21 260.77,82.96 259.17,82.96 259.06,83.08 257.53,83.08 257.45,83.16 257.45,83.32 257.54,83.41 259.13,83.41 259.56,83.84 259.56,84.19 259.18,84.58 257.55,84.58 257.46,84.66 257.46,84.83 257.55,84.91 258.99,84.91 259.04,84.95 260.72,84.95
GND on BOTTOM (solid shape): 161.25,148.82 161.34,148.74 161.53,148.74 161.56,148.77 161.61,148.77 161.74,148.89 161.93,148.89 162.05,148.77 162.05,148.58 161.67,148.2 161.67,147.56 161.55,147.43 161.29,147.43 161.23,147.5 161.23,148.17 160.83,148.56 160.83,148.78 160.98,148.92 161.16,148.92
GND on BOTTOM (solid shape): 142.43,148.73 142.64,148.73 142.81,148.9 143.05,148.9 143.18,148.77 143.18,148.56 143.11,148.5 143.06,148.43 143.05,148.42 142.96,148.33 142.96,147.64 142.74,147.43 142.21,147.43 142.06,147.58 142.06,148.42 141.89,148.59 141.89,148.76 142.03,148.9 142.25,148.9
GND on BOTTOM (solid shape): 115.68,70.17 116.37,70.17 116.46,70.26 123.2,70.26 123.32,70.15 123.32,68.32 122.89,67.89 114.38,67.89 114.02,68.24 114.02,69.15 114.33,69.45 114.33,69.79 114.38,69.97 114.33,70.16 114.33,70.17 114.33,70.27 114.07,70.53 114.07,71.11 114.18,71.22 114.63,71.22
GND on BOTTOM (solid shape): 102.54,149.37 102.54,144.85 105.8,141.59 109.5,141.59 109.5,140.44 108.65,140.44 108.65,140.09 108.99,139.75 110.16,139.75 110.16,139.44 108.22,139.44 108.09,139.57 104.83,139.57 104.72,139.46 102.92,139.46 102.72,139.26 102.72,136.89 102.63,136.8 102.29,136.8 102.03,136.54 102.03,136.29 101.9,136.16 101.65,136.16 101.52,136.29 101.52,149.37 101.78,149.62 102.29,149.62
GND on BOTTOM (solid shape): 200.84,175.68 200.84,174.67 201.73,173.78 201.73,172.79 201.64,172.7 201.56,172.7 201.56,172.7 201.38,172.7 201.37,172.71 201.04,172.71 200.71,172.38 199.8,172.38 199.47,172.05 199.47,169.66 199.13,169.32 197.88,169.32 197.75,169.45 197.75,171.66 198.7,172.61 198.7,175.84 198.76,175.9 200.62,175.9
GND on BOTTOM (solid shape): 244.14,174.82 244.14,174.22 243.74,173.81 243.74,172.44 244.17,172.01 244.17,171.02 243.68,170.53 243.68,169.06 243.72,169.02 243.72,169.02 244.09,168.65 244.09,167.89 244.04,167.84 243.47,167.84 243.41,167.91 243.41,170.51 242.95,170.97 242.95,173.37 242.72,173.6 242.18,173.6 241.87,173.9 241.87,174.74 242.02,174.9 244.07,174.9
GND on BOTTOM (solid shape): 164.43,148.8 164.43,148.6 164.02,148.19 164.02,147.5 163.96,147.43 163.71,147.43 163.58,147.56 163.58,148.2 163.2,148.58 163.2,148.77 163.32,148.89 163.52,148.89 163.64,148.77 163.7,148.77 163.71,148.76 163.79,148.75 163.88,148.76 163.88,148.77 163.94,148.77 164.09,148.93 164.3,148.93
GND on BOTTOM (solid shape): 101.12,88.45 101.12,84.96 100.44,84.28 100.01,84.28 99.85,84.12 99.82,84.12 99.82,84.09 99.64,83.9 98.67,83.9 98.58,83.99 98.42,84.09 98.42,84.37 98.55,84.5 98.7,84.5 98.8,84.4 99.51,84.4 99.78,84.67 99.78,85.17 99.62,85.32 99.62,86.79 99.62,86.79 99.62,87.31 100.03,87.71 100.03,88.46 100.16,88.6 100.97,88.6
GND on BOTTOM (solid shape): 161.21,183.15 161.21,182.14 160.83,181.76 160.83,181.5 160.43,181.09 160.43,180 160.66,179.77 160.9,179.77 161.08,179.59 161.08,178.21 160.89,178.02 160.25,178.02 159.94,178.33 159.56,178.33 158.99,178.9 158.99,180.24 158.78,180.45 155.08,180.45 155.08,181.6 155.93,181.6 155.93,181.96 155.59,182.3 154.42,182.3 154.42,182.6 156.36,182.6 156.49,182.47 159.64,182.47 160.07,182.9 160.07,183.15 160.2,183.28 161.09,183.28
GND on BOTTOM (solid shape): 165.93,148.89 165.98,148.82 166.07,148.76 166.15,148.75 166.24,148.76 166.25,148.77 166.31,148.77 166.44,148.89 166.63,148.89 166.75,148.77 166.75,148.58 166.37,148.2 166.37,147.56 166.72,147.22 167.45,147.22 167.58,147.09 167.58,146.86 167.46,146.75 166.68,146.75 165.93,147.5 165.93,148.19 165.56,148.55 165.56,148.82 165.68,148.94 165.87,148.94
GND on BOTTOM (solid shape): 285.41,100.14 285.41,99.56 285.4,99.53 285.36,99.51 285.04,99.19 285.29,98.81 285.33,98.8 285.33,97.86 285.27,97.81 285.19,97.81 284.68,98.32 284.4,98.32 283.81,98.91 283.81,100.14 283.95,100.28 285.27,100.28
GND on BOTTOM (solid shape): 17.23,115.12 17.23,114.92 17.6,114.55 18.1,114.55 18.58,114.06 18.58,113.09 18.75,112.92 19.17,112.92 19.4,112.7 19.43,112.66 19.46,112.63 19.93,112.16 19.93,112.16 20.33,111.77 20.33,111.12 20.27,111.06 20.13,111.06 20.05,111.14 20.05,111.3 19.95,111.4 19.09,111.4 17.75,112.74 17.14,112.74 17.02,112.86 16.6,112.86 16.57,112.88 16.57,115.08 16.7,115.2 17.15,115.2
GND on BOTTOM (solid shape): 261.5,87.66 264.16,87.66 264.37,87.45 264.37,87.23 264.37,86.9 264.08,86.62 261.41,86.62 261.11,86.77 260.82,86.62 259.44,86.62 259.16,86.9 259.16,87.58 259.36,87.78 259.36,88.79 259.11,89.04 257.51,89.04 257.39,89.16 257.39,89.87 257.48,89.96 259.21,89.96
GND on BOTTOM (solid shape): 145.5,148.8 145.5,148.53 145.45,148.49 145.41,148.42 145.17,148.18 145.17,147.57 145.02,147.41 144.61,147.41 144.43,147.59 144.43,148.34 144.39,148.39 144.38,148.4 144.33,148.49 144.26,148.56 144.23,148.57 144.23,148.76 144.37,148.9 144.64,148.9 144.74,148.8 144.76,148.79 144.96,148.76 145.12,148.88 145.12,148.89 145.16,148.93 145.37,148.93
GND on BOTTOM (solid shape): 147.03,148.9 147.03,148.89 147.19,148.76 147.39,148.79 147.42,148.8 147.54,148.93 147.74,148.93 147.86,148.8 147.86,148.61 147.48,148.23 147.48,147.59 147.35,147.47 146.95,147.47 146.83,147.58 146.83,148.33 146.73,148.43 146.73,148.43 146.67,148.51 146.59,148.57 146.59,148.78 146.65,148.82 146.7,148.89 146.73,148.93 147,148.93
GND on BOTTOM (solid shape): 242.29,181.96 244.58,181.96 244.6,181.94 244.6,180.96 244.32,180.69 242.72,180.69 242.72,180.66 242.21,180.66 241.4,181.48 240.23,181.48 240.13,181.37 240.13,180.92 240,180.79 238.71,180.79 238.58,180.92 238.58,181.3 238.38,181.5 237.36,181.5 237.34,181.5 237.11,181.27 237.11,181.12 236.65,180.66 236.13,180.66 236.09,180.7 236.09,181.2 236.47,181.58 236.55,181.58 236.78,181.81 238.43,181.81 238.58,181.96 238.58,182.21 238.63,182.26 241.35,182.26 241.5,182.42 241.83,182.42
GND on BOTTOM (solid shape): 157.32,148.79 157.32,148.54 157.26,148.48 157.22,148.4 157.21,148.39 156.99,148.17 156.99,147.56 156.84,147.41 156.43,147.41 156.26,147.59 156.26,148.33 156.2,148.4 156.19,148.41 156.14,148.5 156.05,148.56 156.05,148.75 156.19,148.89 156.46,148.89 156.5,148.85 156.52,148.83 156.58,148.79 156.77,148.76 156.92,148.87 156.97,148.92 157.2,148.92
GND on BOTTOM (solid shape): 24.46,159.46 24.46,159.26 24.31,159.11 24.31,158.39 24.5,158.19 26.23,158.19 26.41,158.37 26.59,158.37 26.72,158.23 26.72,157.06 26.72,150.96 26.13,150.38 24.2,150.38 23.69,150.89 23.68,150.96 23.65,151.01 23.65,151.92 23.66,151.97 23.65,152.03 23.65,152.11 23.77,152.23 24.22,152.23 24.43,152.44 24.43,156.13 24.29,156.28 24.29,157.04 24.1,157.23 22.87,157.23 22.66,157.45 22.66,158.74 22.68,158.77 22.68,159.12 23,159.45 23.01,159.45 23.09,159.51 23.14,159.58 23.15,159.59 23.21,159.65 24.26,159.65
GND on BOTTOM (solid shape): 73.86,71.84 73.86,71.45 73.82,71.38 73.8,71.3 73.8,71.28 73.63,71.11 73.56,71.08 73.48,71.11 73.13,71.19 72.92,70.89 72.83,70.8 72.57,70.8 72.44,70.93 72.44,71.21 72.49,71.26 72.52,71.29 72.54,71.33 73,71.78 73.21,71.78 73.21,71.79 73.44,71.79 73.6,71.94 73.76,71.94
GND on BOTTOM (solid shape): 121.13,142.94 121.13,137.67 120.82,137.36 120.34,137.36 120.32,137.37 118.96,138.13 117.43,138.4 117.35,138.4 117.13,138.4 116.9,138.38 115.52,138.04 114.3,137.3 114.17,137.18 112.57,137.18 112.45,137.31 112.45,138.07 110.92,139.59 110.92,141.88 112.27,143.22 120.85,143.22
GND on BOTTOM (solid shape): 28.11,122.88 28.53,121.67 29,120.49 28.99,120.38 28.89,120.35 28.47,120.01 28.86,119.64 28.96,119.59 28.94,119.47 28.92,119.45 27.05,119.45 26.85,119.65 26.85,122.56 27.2,122.92 28.1,122.92
GND on BOTTOM (solid shape): 9.55,138.96 9.55,138.94 9.81,138.68 9.81,137.95 9.64,137.78 8.96,137.78 8.94,137.76 8.92,137.76 8.88,137.72 8.88,137.7 8.81,137.63 8.81,136.75 8.69,136.62 8.69,136.6 8.69,135.73 8.69,135.65 9,135.34 9.07,135.34 9.08,135.34 9.57,135.34 9.77,135.14 9.77,134.45 10.08,134.13 10.08,133.69 9.96,133.56 8.62,133.56 8.56,133.62 8.56,134.04 7.99,134.61 7.99,135.22 7.8,135.41 7.25,135.41 7.24,135.4 7.23,135.4 6.53,134.7 5.77,134.7 5.72,134.75 5.72,135.25 6.49,136.03 6.49,136.67 6.73,136.9 7.54,136.9 7.64,136.81 8.19,136.81 8.3,136.92 8.3,137.94 8.24,138 8.19,138.07 8.12,138.12 8.07,138.17 7.44,138.17 7.42,138.14 6.53,138.14 6.27,138.4 6.27,139.13 6.4,139.26 9.25,139.26
GND on BOTTOM (solid shape): 100.4,72.1 100.4,71.55 100.4,71.54 100.4,71.52 100.51,71.31 100.72,71.21 100.74,71.21 100.83,71.11 100.83,70.19 100.72,70.08 100.29,70.08 100.19,70.19 100.19,71.33 100.16,71.36 99.73,71.36 99.72,71.35 99.57,71.35 99.52,71.3 99.52,70.99 99.35,70.82 98.03,70.82 97.3,70.09 97.3,70.07 97.03,69.79 95.58,69.79 95.53,69.84 95.51,69.84 95.2,70.15 95.2,70.54 95.21,70.55 95.21,71.22 95.21,71.28 95.21,71.34 95.21,71.41 95.24,71.42 95.39,71.56 95.43,71.76 95.42,71.78 95.52,71.88 95.56,71.9 95.59,71.93 96.68,71.93 96.69,71.92 96.77,71.88 96.86,71.88 96.88,71.88 96.96,71.81 96.96,71.57 97.11,71.41 98.96,71.41 99.74,72.19 100.3,72.19
GND on BOTTOM (solid shape): 88.84,72.68 88.85,72.67 88.88,72.61 88.94,72.57 88.97,72.56 88.97,72.44 88.96,72.43 88.93,72.38 88.92,72.32 88.92,72.24 88.93,72.18 88.96,72.13 88.97,72.12 88.97,71.97 88.91,71.9 88.89,71.81 88.89,71.74 88.92,71.64 89,71.57 89,71.56 89.1,71.46 89.1,71 89.2,70.91 89.2,69.49 89.59,69.11 89.59,68.6 89.46,68.47 88.82,68.47 88.54,68.75 88.54,70.59 88.56,70.61 88.56,71.13 88.7,71.27 88.7,71.79 88.59,71.9 88.59,71.94 88.59,71.99 88.56,72.05 88.56,72.25 88.57,72.26 88.6,72.32 88.61,72.38 88.61,72.43 88.56,72.56 88.45,72.63 88.44,72.63 88.24,72.83 87.72,72.83 87.61,72.94 87.61,73.17 87.73,73.28 88.06,73.28 88.06,73.28 88.24,73.28
GND on BOTTOM (solid shape): 7.98,145.84 8.94,144.87 10.34,144.87 10.77,144.44 10.77,143.53 10.08,142.84 9.22,142.84 8.13,141.75 3.81,141.75 1.65,139.59 1.65,128.03 1.35,127.73 0.61,127.73 0.28,127.4 0.28,126.66 -0.1,126.28 -1.08,126.28 -1.13,126.29 -1.13,142.27 -0.9,142.83 -0.34,143.07 6.64,143.07 7.81,142.77 7.52,143.95 7.52,146.45 7.98,146.45
GND on BOTTOM (solid shape): 197.09,187.79 197.09,187.66 196.14,186.71 196.08,186.71 195.88,186.52 195.88,185.95 195.69,185.76 192.84,185.76 192.58,186.01 192.58,186.2 192.3,186.48 193.24,186.48 193.24,186.43 193.25,186.37 193.27,186.32 193.29,186.28 193.32,186.23 193.36,186.19 193.4,186.16 193.44,186.13 193.49,186.11 193.55,186.1 193.6,186.1 193.65,186.1 193.7,186.11 193.75,186.13 193.8,186.16 193.84,186.19 193.88,186.23 193.91,186.28 193.93,186.32 193.95,186.37 193.95,186.43 193.95,186.48 193.95,186.53 193.93,186.58 193.91,186.63 193.88,186.68 193.84,186.72 193.8,186.75 193.75,186.78 193.7,186.79 193.65,186.81 193.6,186.81 193.55,186.81 193.49,186.79 193.44,186.78 193.4,186.75 193.36,186.72 193.32,186.68 193.29,186.63 193.27,186.58 193.25,186.53 193.24,186.48 192.3,186.48 191.82,186.96 191.82,187.22 191.95,187.34 191.98,187.34 192,187.33 192.05,187.31 192.11,187.31 192.16,187.3 192.21,187.31 192.27,187.33 192.3,187.34 192.33,187.34 192.46,187.47 192.46,187.5 192.47,187.53 192.49,187.58 192.49,187.64 192.49,187.69 192.48,187.74 192.47,187.8 192.58,187.91 196.96,187.91
GND on BOTTOM (solid shape): 182.15,79.46 182.15,76.07 182.06,75.98 182.06,75.94 182.05,75.91 182.03,75.85 182.02,75.8 182.02,75.75 182.03,75.69 182.05,75.64 182.06,75.6 182.06,73.61 178.68,70.23 178.68,69.81 178.44,69.57 176.56,69.57 176.45,69.67 176.45,70.09 177.17,70.81 177.17,74.08 177.81,74.08 177.81,74.03 177.82,73.98 177.84,73.93 177.86,73.88 177.89,73.83 177.93,73.8 177.97,73.76 178.01,73.74 178.06,73.72 178.12,73.7 178.17,73.7 178.22,73.7 178.27,73.72 178.32,73.74 178.37,73.76 178.41,73.8 178.45,73.83 178.48,73.88 178.5,73.93 178.52,73.98 178.52,74.03 178.52,74.08 178.52,74.14 178.5,74.19 178.48,74.23 178.45,74.28 178.41,74.32 178.37,74.35 178.32,74.38 178.27,74.4 178.22,74.41 178.17,74.41 178.12,74.41 178.06,74.4 178.01,74.38 177.97,74.35 177.93,74.32 177.89,74.28 177.86,74.23 177.84,74.19 177.82,74.14 177.81,74.08 177.17,74.08 177.17,74.31 178.97,76.11 181.22,76.11 181.55,76.44 181.55,77.98 181.2,78.33 177.67,78.33 177.39,78.61 177.39,79.44 178.08,80.13 181.48,80.13
GND on BOTTOM (solid shape): 243.46,68.79 246.16,71.49 248.86,68.79 248.86,67.27 248.85,67.26 248.78,67.25 248.71,67.24 247.79,67.24 247.78,67.23 244.85,67.23 244.5,66.87 244.01,66.74 243.46,66.74
GND on BOTTOM (solid shape): 343.46,187.19 340.96,184.69 338.46,187.19 338.46,188.29 339.33,188.29 339.43,188.29 342.11,188.29 342.11,188.99 342.41,189.7 343.11,189.99 343.46,189.99
GND on BOTTOM (solid shape): 248.96,188.66 249.26,187.94 249.21,186.59 246.46,183.84 243.71,186.59 243.71,188.94 244.71,188.94 244.79,188.94 244.79,188.94 248.24,188.94
GND on BOTTOM (solid shape): 18.34,101.46 18.43,101.4 18.42,101.3 18.55,100.8 19.01,101.02 19.43,101.02 19.67,101.26 20.03,101.26 20.27,101.01 20.27,100.88 19.65,100.26 19.65,100.26 19.47,100.09 18.53,100.09 18.53,100.09 17.47,100.09 17.3,99.92 17.3,99.91 17.27,99.88 17.27,97.5 17.37,97.4 20.68,97.4 21.26,97.98 21.26,100.08 21.32,100.19 21.29,100.32 21.29,100.33 21.29,101.09 21.34,101.14 21.69,101.14 21.81,101.02 21.81,98.5 22.02,98.28 22.02,97.91 21.83,97.72 21.6,97.62 21.5,97.39 20.62,96.51 17.76,96.51 17.45,96.83 17.42,96.83 17.41,96.82 17.06,96.82 16.9,96.99 16.9,97.01 16.83,97.28 16.58,97.42 16.54,97.42 16.54,97.53 16.54,97.58 16.54,101.12 16.88,101.46
GND on BOTTOM (solid shape): outline of 107 points within -1.13,66.9 7.36,74.69
GND on BOTTOM (solid shape): outline of 127 points within 128.63,68.39 144.81,76.18
GND on BOTTOM (solid shape): 150.99,154.08 150.99,153.82 150.92,153.75 150.92,151.61 150.94,151.59 150.98,151.46 151.09,151.37 151.09,151.31 151.5,150.89 151.69,150.89 151.77,150.82 151.79,150.78 151.82,150.75 151.82,150.51 151.78,150.46 151.74,150.4 151.69,150.34 151.44,150.34 151.23,150.13 151.21,150.13 151.07,149.99 151.07,149.89 150.92,149.75 150.92,148.43 150.9,148.41 150.9,147.17 150.82,147.09 149.31,147.09 149.16,147.25 149.16,148.43 149.02,148.57 149.02,148.79 149.16,148.94 149.32,148.94 149.37,148.89 149.49,148.74 149.76,148.74 149.79,148.8 149.81,148.83 149.84,148.87 149.88,148.9 149.88,149.14 149.85,149.17 149.78,149.32 149.84,149.48 149.87,149.51 149.87,149.65 149.87,149.7 149.87,150.26 149.87,150.31 149.87,150.44 149.84,150.47 149.78,150.63 149.84,150.78 149.87,150.81 149.87,150.96 149.87,151 149.87,151.56 149.87,151.61 149.87,151.74 149.84,151.77 149.78,151.93 149.84,152.08 149.87,152.11 149.87,152.26 149.87,152.3 149.87,152.86 149.87,152.91 149.87,153.04 149.84,153.07 149.78,153.23 149.84,153.38 149.87,153.41 149.87,153.56 149.87,153.6 149.87,154.08 149.95,154.17 150.91,154.17
GND on BOTTOM (solid shape): outline of 156 points within 10.59,136.78 14.73,139.85
GND on BOTTOM (solid shape): outline of 164 points within 225.94,72.41 241.65,81.43
GND on BOTTOM (solid shape): outline of 183 points within 48.08,96.39 52.6,103.42
GND on BOTTOM (solid shape): outline of 232 points within 159.22,159.56 174.17,172.65
GND on BOTTOM (solid shape): 20.54,126.25 20.54,125.98 20.69,125.83 20.69,125.65 20.68,125.64 20.78,125.38 21.05,125.45 21.13,125.48 21.21,125.45 21.45,125.37 21.59,125.57 21.59,125.64 21.79,125.84 21.79,126.18 21.93,126.31 22.25,126.31 22.39,126.17 22.39,125.86 22.37,125.84 22.35,125.83 22.08,125.45 22.49,125.24 22.52,125.25 22.62,125.15 22.62,124.07 22.62,123.01 22.41,122.81 22.31,122.81 22.15,122.66 22.15,122.45 22.1,122.4 21.74,122.4 21.67,122.47 21.67,122.75 21.71,122.8 21.74,122.8 22,123.11 21.73,123.42 21.7,123.42 21.59,123.53 21.59,123.59 21.43,123.77 21.21,123.69 21.13,123.65 21.05,123.69 21.01,123.73 20.97,123.76 20.83,123.77 20.71,123.69 20.63,123.65 20.55,123.69 20.44,123.77 20.31,123.76 20.3,123.76 20.23,123.71 20.19,123.65 20.18,123.64 20.08,123.54 19.8,123.54 19.72,123.45 19.41,123.45 19.32,123.54 19.32,123.83 19.42,123.93 19.72,123.93 20.03,123.92 20,124.24 19.96,124.32 20.09,124.57 19.96,124.82 20,124.9 20.07,125.14 19.86,125.27 19.78,125.3 19.74,125.38 19.74,126.2 19.88,126.33 20.45,126.33
GND on BOTTOM (solid shape): outline of 235 points within 18.41,135.58 22.2,141.95
GND on BOTTOM (solid shape): outline of 247 points within 253.92,100.58 260.12,109.76
GND on BOTTOM (solid shape): outline of 292 points within 23.46,110.57 26.83,114.62
GND on BOTTOM (solid shape): outline of 370 points within 4.72,72.45 16.14,83.23
GND on BOTTOM (solid shape): outline of 1247 points within -2.03,66.9 350.26,176.27
GND on BOTTOM (solid shape): outline of 1927 points within -1.13,100.93 349.36,189.79
GND on BOTTOM (solid shape): outline of 2578 points within 16.26,101.86 29.51,111.8
GND on BOTTOM (solid shape): outline of 7054 points within 64.74,72.77 95.78,103.53
VBATT on BOTTOM (solid shape): 29.54,86.87 29.54,83.56 29.48,83.49 28.7,83.49 28.55,83.34 28.55,82.72 28.4,82.57 27.43,82.57 27.36,82.64 27.36,84.04 27.16,84.24 25.66,84.24 25.22,84.68 23.63,84.68 23.62,84.69 23.44,84.69 23.35,84.78 23.35,87.03 23.41,87.09 29.32,87.09
VCC0V9_LVR_OUT on TOP (solid shape): 24.09,106.99 24.09,106.66 24.05,106.58 23.95,106.57 23.75,106.59 23.57,106.48 23.5,106.45 23.42,106.48 22.94,106.5 22.95,106.02 22.95,104.22 22.78,104.05 20.92,104.05 20.74,103.87 20.74,102.92 20.72,102.9 19.99,102.9 19.56,103.33 19.56,106.61 19.6,106.65 20.24,106.65 20.28,106.61 20.28,105.1 20.28,105.09 20.41,104.68 20.83,104.75 20.9,104.77 20.97,104.75 21.38,104.68 21.54,105.06 21.53,105.09 21.7,105.27 22.07,105.27 22.29,105.48 22.29,106.38 23.11,107.2 23.88,107.2
VCC0V9_SVR on TOP (solid shape): 20.35,114.47 20.35,113.77 20.43,113.69 20.44,113.68 20.56,113.56 21.07,113.56 21.51,113.12 21.51,112.14 21.72,111.93 21.72,110.95 21.66,110.9 21.58,110.87 21.5,110.92 20.97,110.98 21.13,110.47 21.14,110.47 21.18,110.42 21.1,110.34 20.88,110.34 20.3,110.17 20.88,110 20.98,110 21.03,109.97 21.02,109.91 20.89,109.78 20.89,108.73 20.89,108.73 20.89,107.6 20.89,107.6 21.09,107.26 21.47,107.35 21.55,107.38 21.62,107.35 21.86,107.24 22.11,107.34 22.19,107.37 22.26,107.34 22.64,107.25 22.86,107.57 22.86,107.73 22.95,107.82 24.61,107.82 24.72,107.7 24.72,107.44 24.58,107.3 23.06,107.3 22.19,106.42 22.19,105.6 21.96,105.38 21.75,105.38 21.55,105.57 21.55,105.6 21.53,105.74 21.44,105.86 21.4,105.94 21.44,106.02 21.52,106.4 21.19,106.6 21.16,106.59 20.92,106.84 20.89,107.05 20.74,107.2 20.65,107.23 20.41,107.23 20.27,107.09 20.27,106.91 20.22,106.86 19.83,106.86 19.77,106.92 19.77,110.73 19.82,110.78 20.4,110.78 20.6,110.99 20.6,112.02 20.4,112.22 19.99,112.22 19.29,112.92 19.29,114.54 20.28,114.54
VCC0V9_SVR on BOTTOM (solid shape): 19.43,116.97 19.43,114.88 20.4,113.91 20.4,113.3 20.5,113.2 20.5,112.4 20.34,112.24 20.04,112.24 19.54,112.73 19.52,112.75 19.49,112.78 19.17,113.1 18.79,113.1 18.75,113.14 18.75,114.11 18.41,114.45 18.41,116.92 18.53,117.04 18.53,117.05 18.59,117.11 19.29,117.11
VCC0V9_SVR on BOTTOM (solid shape): 24.94,107.99 24.94,107.54 24.86,107.46 24.82,107.47 24.69,107.45 24.6,107.35 24.38,107.35 24.21,107.52 24.07,107.52 23.94,107.4 23.94,107.39 23.89,107.33 23.75,107.33 23.6,107.49 23.4,107.49 23.35,107.54 23.35,107.99 23.41,108.05 24.87,108.05
VCC0V9_SVR on BOTTOM (solid shape): 22.27,107.35 22.31,107.31 22.4,107.23 22.4,105.07 22.2,104.87 22.18,104.87 22.08,104.84 22.01,104.77 21.99,104.75 21.75,104.75 21.72,104.79 21.69,104.82 21.64,104.85 21.64,105.04 21.78,105.18 21.78,105.4 21.59,105.59 21.59,105.72 21.42,105.9 21.42,106 21.55,106.29 21.38,106.56 21.38,106.85 21.55,107.01 21.56,107.01 21.61,107.02 21.66,107.04 21.73,107.11 21.77,107.19 21.77,107.21 21.81,107.24 21.83,107.24 21.99,107.26 22.12,107.35
VCC3V3_FLASH on TOP (solid shape): 22.43,128.22 22.43,127.6 22.83,127.2 22.83,126.79 22.95,126.67 23.18,126.67 23.23,126.62 23.23,126.2 23.44,125.98 24.07,125.98 24.26,125.93 24.45,125.98 25.86,125.98 26.05,125.93 26.24,125.98 26.44,125.98 26.56,125.86 26.78,125.86 26.86,125.85 26.94,125.86 27.15,125.86 27.15,125.86 27.21,125.63 27.21,125.39 27.04,125.22 24.15,125.22 23.92,125.32 23.68,125.23 23.66,125.22 23.35,124.91 22.85,124.91 22.76,125.01 22.76,125.73 22.45,126.04 22.45,126.22 21.72,126.95 21.72,128.42 21.82,128.52 22.14,128.52
VDDQ_DDR on TOP (solid shape): outline of 12662 points within 129.84,117.75 178.05,135.68
3S_BATT+ on BOTTOM (solid shape): 26.85,92.98 26.85,92.14 27.06,91.93 27.06,91.31 26.5,91.31 26.15,90.95 26.5,90.59 27.08,90.59 27.73,89.94 27.73,87.67 27.59,87.53 25.85,87.53 25.34,88.03 25.34,89.42 25.25,89.52 24.15,89.52 24.04,89.62 24.04,92.64 24.28,92.88 25.15,92.88 25.31,93.04 26.79,93.04
+1.8ALWP on BOTTOM (solid shape): 243.48,166.54 245.95,166.54 246.05,166.44 246.05,161.89 245.88,161.73 244.5,161.73 244.34,161.89 244.34,163.48 244.01,163.81 243.21,163.81 243.2,163.79 243.2,163.27 243.18,163.26 242.74,163.26 242.74,163.26 242.74,163.82 241.99,163.82 241.99,163.27 241.99,163.27 241.54,163.27 241.54,163.27 241.54,163.81 241.53,163.81 240.8,163.81 240.54,164.08 240.54,166.52 240.77,166.75 243.28,166.75
+AC_IN on TOP (solid shape): outline of 108 points within 20.29,89.96 25.63,96.17
+AC_IN on BOTTOM (solid shape): 19.7,94.87 21.33,94.87 21.39,94.93 22.13,94.93 22.28,94.79 22.28,92.98 21.83,92.53 20.35,92.53 19.27,93.61 18.68,93.61 18.55,93.73 18.55,95.23 18.71,95.39 18.73,95.4 19.18,95.4
+CHG_SRC_20V on TOP (solid shape): 46.87,72.99 49.31,72.99 49.54,72.77 49.54,68.35 49.28,68.09 42.12,68.09 41.82,68.39 41.82,73.08 41.91,73.17 46.69,73.17
+CHG_SRC_20V on BOTTOM (solid shape): 53.34,75.74 53.34,75.07 53.29,75.02 51.43,75.02 51.32,74.91 50.65,74.24 50.54,74.24 50.53,74.24 50.41,74.26 50.28,74.24 50.28,74.24 50.23,74.24 49.92,73.94 49.92,73.64 49.83,73.55 49.83,69.83 49.47,69.46 49.47,68.61 48.95,68.09 48.18,68.09 47.93,68.34 42.58,68.34 41.83,69.09 41.83,73.12 41.83,73.12 41.83,73.68 41.91,73.75 46.86,73.75 47.35,74.24 47.35,75.74 47.5,75.89 53.19,75.89
+DC_IN on BOTTOM (solid shape): 23.5,150.05 24.83,150.05 25.48,149.41 25.48,146.47 25.07,146.06 25.07,146.04 24.62,145.59 24.62,145.58 23.85,144.81 22.89,144.81 22.66,145.04 22.61,145.04 21.45,146.2 15.01,146.2 14.68,146.53 14.68,150.3 14.85,150.46 23.09,150.46
+DC_IN on BOTTOM (solid shape): 12.1,97.6 13.29,97.6 13.31,97.58 13.31,95.63 13.56,95.38 13.56,94.75 13.46,94.65 10.12,94.65 9.94,94.84 9.95,94.87 10.12,95.91 9.94,96.95 9.94,97.28 10.03,97.38 10.7,97.38 10.82,97.5 10.82,97.65 11.04,97.87 11.83,97.87
+DC_IN_SS on TOP (solid shape): 12.62,93.95 12.62,93.51 12.54,93.42 12.04,93.42 11.98,93.36 11.96,93.36 11.96,93.35 11.96,93.34 11.96,92.92 11.69,92.66 11.69,91.79 11.63,91.73 10.62,91.73 10.53,91.83 10.53,92.65 10.5,92.68 9.1,92.68 8.99,92.8 8.99,93.16 9.5,93.67 11.63,93.67 12.01,94.05 12.52,94.05
+DC_IN_SS on BOTTOM (solid shape): outline of 202 points within 6.59,87.96 14.66,94.17
+EDPVDD on TOP (solid shape): outline of 197 points within 49.33,94.38 57,101.52
+EDPVDD on BOTTOM (solid shape): 56.69,102.12 56.69,102.11 56.69,101.82 56.91,101.64 56.95,101.63 56.95,101.11 56.69,100.86 55.42,100.86 55.3,100.98 55.3,103.42 56.69,103.42
+FB_PLLAVDD on TOP (solid shape): 189.73,152.52 190.57,152.52 190.72,152.38 190.72,151.38 189.49,150.16 189.15,150.16 188.96,150.35 188.96,151.08 188.51,151.53 188.51,152.4 188.64,152.53 189.72,152.53
+GPCPLL_AVDD on TOP (solid shape): outline of 733 points within 212.32,143.47 218.75,148.82
+GPU_CORE on TOP (solid shape): 202.77,145.18 202.77,144.52 202.54,144.29 202.24,144.29 202.18,144.3 202.11,144.29 201.8,144.29 201.42,143.91 201.09,143.91 200.96,143.91 200.81,144.06 200.81,144.47 201.63,145.28 202.67,145.28
+GPU_CORE on TOP (solid shape): 182.17,176.47 182.17,174.16 182.49,173.84 182.49,171.97 182.9,171.56 182.9,168.01 181.98,167.09 181.98,165.56 182.17,165.37 185.06,165.37 185.38,164.84 185.67,165.38 186.11,165.82 186.11,167.4 186.36,167.66 187.38,167.66 187.57,167.47 187.57,162.26 186.11,160.8 181.88,160.8 181.71,160.63 178.9,160.63 178.23,161.3 178.23,177.33 178.33,177.43 178.33,178.03 178.53,178.23 180.42,178.23
+GPU_CORE on TOP (solid shape): outline of 835 points within 200,127.02 213.79,145.37
+GPU_CORE on BOTTOM (solid shape): 182.01,177.42 182.01,175.65 182.59,175.07 182.59,170.52 182.85,170.25 184.81,170.25 185.01,170.05 185.01,168.74 184.95,168.69 182.31,168.69 182.11,168.48 182.11,164.09 182.2,164 184.86,164 185.04,163.82 185.04,161.06 184.81,160.83 181.98,160.83 181.68,160.53 177.52,160.53 177.38,160.68 177.38,163.31 177.76,163.69 178.03,163.69 178.23,163.89 178.23,177.09 179.1,177.95 181.47,177.95
+GPU_CORE on BOTTOM (solid shape): outline of 3803 points within 199.11,121.09 213.35,145.29
+GPU_CORE_VDDS on TOP (solid shape): 204.18,143.29 204.34,143.29 204.45,143.18 204.45,142.79 204.28,142.62 203.01,142.62 202.84,142.79 202.84,144.02 202.95,144.14 203.33,144.14
+GPU_CORE_VDDS on TOP (solid shape): 209.31,135.05 209.31,133.91 209.19,133.8 208.87,133.8 207.95,134.72 207.95,135.08 208.07,135.2 209.15,135.2
+GPU_CORE_VDDS on TOP (solid shape): 202.35,142.03 202.35,141.39 202.6,141.13 202.6,140.74 202.53,140.68 202.07,140.68 200.92,141.82 200.92,142.15 200.99,142.22 202.15,142.22
+GPU_CORE_VDDS on TOP (solid shape): 207,139.7 207,138.9 207.32,138.59 207.32,137.78 207.32,137.77 207.32,137.65 207.26,137.6 206.5,137.6 206.48,137.62 206.48,138.28 205.88,138.88 205.88,139.24 206.42,139.79 206.92,139.79
+GPU_CORE_VDDS on TOP (solid shape): 209.3,144.21 209.67,143.84 209.67,142.77 209.6,142.7 207.96,142.7 207.8,142.86 207.8,143.11 207.96,143.27 208.47,143.27 208.86,143.67 208.86,144.08 208.98,144.2 209,144.2 209.02,144.22 209.3,144.22
+GPU_CORE_VDDS on TOP (solid shape): 202.42,137.14 202.42,136.75 202.01,136.33 202.01,136.06 201.54,135.59 201.03,135.59 200.9,135.72 200.9,135.91 201.25,136.26 201.25,136.72 201.31,136.77 201.54,136.77 202.05,137.29 202.28,137.29
+GPU_CORE_VDDS on TOP (solid shape): 211.59,142.29 211.59,141.85 210.92,141.19 210.86,141.19 210.86,141.19 210.75,141.19 210.31,140.75 209.86,140.75 209.67,140.95 209.67,141.29 209.75,141.37 209.96,141.37 210.22,141.64 210.22,142.35 210.39,142.52 211.36,142.52
+GPU_CORE_VDDS on TOP (solid shape): 194.92,172.29 196.09,172.29 196.14,172.24 196.14,169.31 195.82,168.99 195.82,165.15 192.17,161.49 189.18,161.49 188.58,160.9 187.86,160.9 187.75,161 187.75,163.2 188.33,163.77 188.33,167.34 188.52,167.53 190.49,167.53 190.68,167.72 190.74,167.72 190.74,167.79 190.8,167.85 190.8,172.24 191.02,172.45 193.06,172.45 193.22,172.61 194.59,172.61
+GPU_CORE_VDDS on TOP (solid shape): 210.13,137.25 210.13,137 210.17,137 210.17,136.92 210.35,136.75 210.63,136.75 210.64,136.75 210.73,136.75 211.38,136.1 211.38,135.84 211.25,135.72 211.06,135.72 210.81,135.97 210.48,135.97 209.66,136.79 209.66,137.07 209.67,137.08 209.68,137.12 209.71,137.16 209.73,137.2 209.73,137.24 209.8,137.31 210.08,137.31
+GPU_CORE_VDDS on BOTTOM (solid shape): outline of 95 points within 187.77,159.02 196.25,171.16
+INV_PWR_SRC on TOP (solid shape): outline of 86 points within 42.6,97.94 48.33,103.48
+INV_PWR_SRC on BOTTOM (solid shape): 45.68,103.66 46.42,103.53 47.17,103.45 47.17,102.51 47.55,102.13 47.55,101.52 47.27,101.24 46.15,101.24 45.39,102 45.39,103.4 45.65,103.66
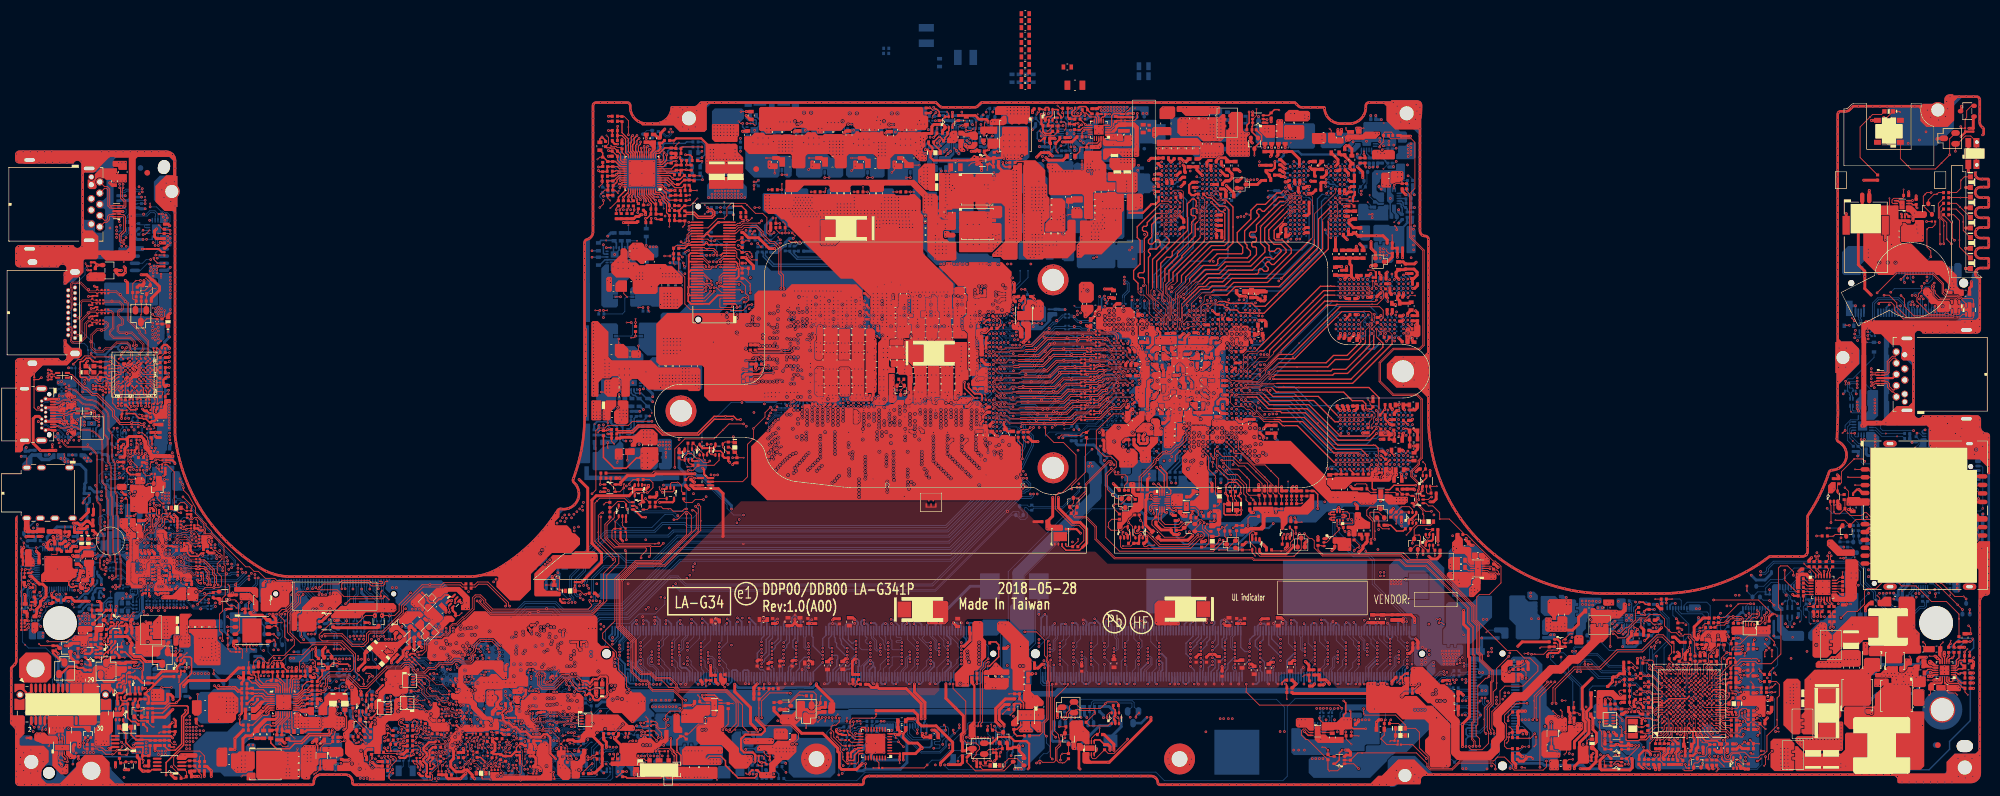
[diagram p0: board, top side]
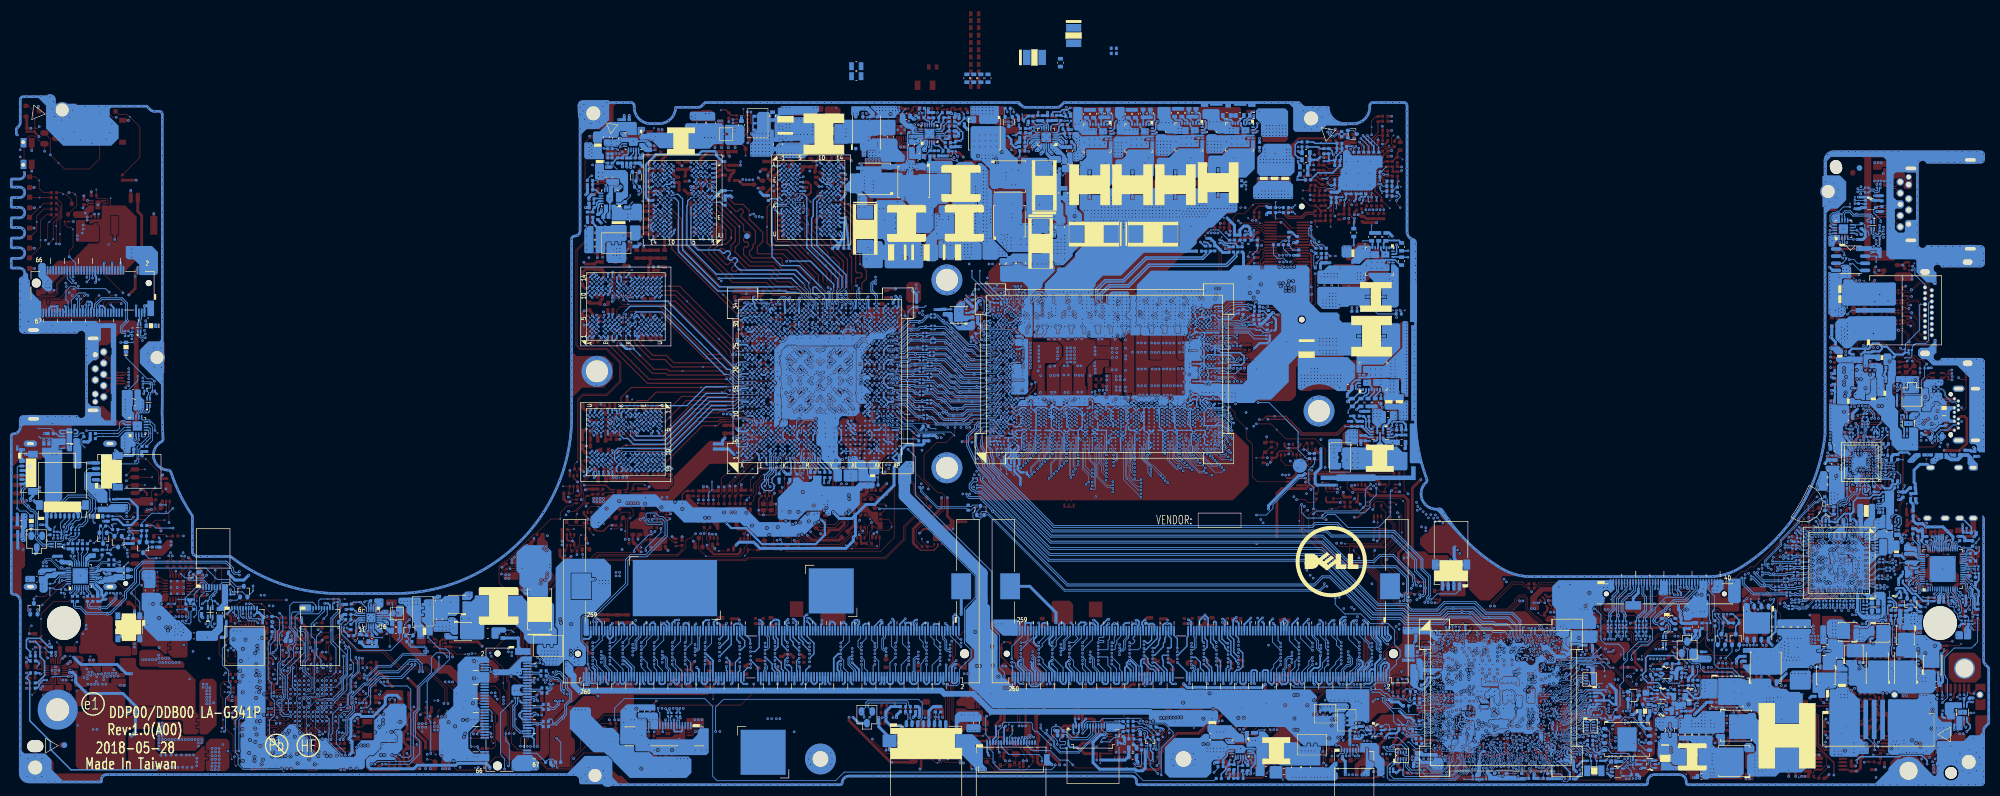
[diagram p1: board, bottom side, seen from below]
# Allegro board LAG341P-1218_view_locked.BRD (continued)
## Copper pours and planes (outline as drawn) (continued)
+NVVDDS_B+ on TOP (solid shape): 198.58,175.91 198.58,172.79 198.3,172.51 194.99,172.51 194.84,172.66 194.84,174.45 194.72,174.57 193.45,174.57 193.27,174.74 193.27,175.96 193.4,176.09 198.4,176.09
+NVVDDS_B+ on BOTTOM (solid shape): 198.55,175.9 198.55,172.84 197.21,171.49 191.52,171.49 191.43,171.58 191.43,175.93 191.54,176.04 198.41,176.04
+ODR_PWR on TOP (solid shape): 327.27,118.06 328.65,118.06 328.84,117.88 328.84,116.97 328.66,116.79 324.77,116.79 324.73,116.84 324.73,117.24 324.73,117.24 324.73,118.04 325.02,118.33 327,118.33
+PECI_VREF on TOP (solid shape): 300.08,93.33 300.18,93.32 300.29,93.33 300.3,93.33 300.39,93.33 300.6,93.13 300.6,92.67 300.62,92.64 300.62,92.47 300.79,92.47 300.79,92.47 301.35,92.47 301.48,92.34 301.48,91.77 301.35,91.65 301.26,91.65 300.91,91.3 300.86,91.3 300.47,90.9 300.27,90.9 300.19,90.94 300.16,91.01 300.12,91.17 300,91.28 299.97,91.29 299.97,91.4 300.06,91.48 300.06,91.64 300.1,91.68 300.19,91.68 300.19,92.45 300.06,92.45 299.91,92.6 299.57,92.6 299.48,92.69 299.48,93.23 299.58,93.33 300.07,93.33
+PEX_PLL_HVDD on TOP (solid shape): 197.98,134.17 197.98,133.79 197.95,133.78 197.85,133.71 197.79,133.61 197.78,133.57 197.61,133.57 197.37,133.33 197.37,133.24 197.36,133.15 197.37,133.05 197.37,132.15 196.7,131.47 196.56,131.47 196.15,131.88 196.12,131.98 196.18,132.05 196.4,132.38 196.19,132.71 196.18,132.71 196.14,132.75 196.21,132.83 196.25,132.86 196.29,132.9 196.39,133.01 196.39,133.56 196.46,133.62 196.97,133.62 197.16,133.8 197.16,133.94 197.5,134.28 197.87,134.28
+PWR_SRC_AC on BOTTOM (solid shape): outline of 120 points within 51.99,70.63 57.07,76.36
+RTC_CELL_VBAT on TOP (solid shape): 284.2,83.04 284.2,83.03 284.58,82.86 284.87,83.17 285.48,83.17 285.53,83.12 285.53,82.31 285.44,82.23 283.45,82.23 282.79,82.89 281.71,82.89 281.38,82.55 281.38,81.01 281.47,80.91 282.13,80.91 282.21,80.83 282.21,80.1 282.4,79.91 282.4,78.92 282.31,78.82 280.46,78.82 280.24,79.04 280.24,82.74 280.29,82.79 280.29,83.76 280.5,83.98 283.26,83.98
+RTCVCC_R on TOP (solid shape): 277.56,74.1 277.86,73.94 278.15,74.1 278.72,74.1 278.82,74.01 278.82,72.47 278.94,72.34 278.94,71.14 278.69,70.88 277.01,70.88 276.91,70.99 276.91,73.96 277.05,74.1
+SD_VDD2 on TOP (solid shape): 348.45,114.91 349.59,114.91 349.8,114.71 349.8,114.13 349.6,113.94 347.4,113.94 347.14,114.19 347.14,115.21 347.27,115.33 348.03,115.33
+SD_VDD2 on BOTTOM (solid shape): 348.31,115.28 348.31,112.03 348.39,111.96 348.39,110.64 348.08,110.34 347.63,110.34 347.48,110.5 347.48,111.32 347.67,111.56 347.61,111.86 347.61,112.06 347.68,112.27 347.62,112.48 347.61,112.49 347.61,112.53 347.22,112.92 347.22,114.12 347.18,114.16 347.18,115.21 347.4,115.44 348.16,115.44
+SDC_IN on TOP (solid shape): 55.78,81.04 55.85,81.02 55.88,80.95 55.93,80.78 56.06,80.66 56.06,80.11 55.89,79.71 56.24,79.44 56.26,79.44 56.44,79.27 57.33,79.27 57.58,79.01 57.58,77.49 57.43,77.34 57.03,77.34 56.49,76.8 56.45,76.77 56,76.77 55.65,77.12 55.42,77.28 55.15,77.23 53.52,77.23 53.4,77.35 53.4,79.14 54.41,79.14 54.66,79.39 54.66,80.79 54.91,81.04
+SDC_IN on TOP (solid shape): 17.18,88.21 18.67,88.21 18.76,88.11 18.76,87.35 18.43,87.02 17.88,87.02 17.76,86.9 17.76,86.51 17.7,86.45 16.79,86.45 16.23,85.9 14.94,85.9 14.81,86.02 14.81,87.16 14.61,87.37 14.55,87.44 14.4,87.58 14.33,87.58 14.32,87.58 14.1,87.62 13.87,87.58 13.86,87.58 13.68,87.58 13.39,87.29 13.39,85.41 13.28,85.29 8.33,85.29 8.03,85.6 8.03,87.24 8.56,87.78 9.07,87.78 9.08,87.76 9.59,87.76 9.8,87.55 10.49,87.55 11.02,87.01 12.5,87.01 12.62,87.14 12.65,87.14 12.65,87.17 12.68,87.19 12.68,87.88 13.13,88.33 14.4,88.33 14.56,88.18 14.61,88.11 14.75,87.98 14.8,87.98 14.81,87.98 15.06,87.93 15.31,87.98 15.35,87.98 15.37,88.01 15.51,88.11 15.62,88.25 15.62,88.26 15.77,88.41 16.98,88.41
+SDC_IN on BOTTOM (solid shape): 57.6,78.88 57.6,77.49 57.6,77.46 57.47,77.34 57.19,77.34 56.57,76.72 56.01,76.72 55.91,76.82 55.91,76.99 55.55,77.34 55.32,77.34 55.29,77.36 55.29,77.88 55.29,77.95 55.28,77.98 55.27,78.02 55.25,78.07 55.23,78.1 55.21,78.14 55.18,78.16 55.15,78.19 55.12,78.21 55.08,78.24 55.03,78.25 54.99,78.27 54.93,78.27 54.88,78.27 54.84,78.26 54.78,78.25 54.73,78.23 54.69,78.2 54.65,78.16 54.62,78.13 54.59,78.08 54.56,78.03 54.55,77.99 54.54,77.96 54.54,77.91 54.54,77.61 54.54,77.35 54.22,77.03 53.7,77.03 53.41,77.32 53.41,78.9 53.47,78.96 53.8,78.96 53.86,78.91 55.86,78.91 55.91,78.96 55.93,78.96 56.05,79.09 57.39,79.09
+SDC_IN on BOTTOM (solid shape): outline of 143 points within 7.65,83.38 23.57,89.31
+SP_PLLVDD on TOP (solid shape): 200.43,131.5 200.56,131.5 200.62,131.5 200.74,131.5 200.77,131.54 200.82,131.54 201.41,130.94 201.41,130.85 201.38,130.8 201.33,130.81 200.74,130.59 201.26,130.23 201.36,130.23 201.41,130.15 201.41,129.36 201.34,129.28 200.37,129.28 200.35,129.29 200.26,129.38 200.26,129.69 200.13,129.81 200.12,129.81 200.1,129.83 199.8,129.97 199.51,129.81 198.4,129.81 198.27,129.94 198.27,130.3 198.93,130.96 198.97,130.96 199.54,131.54 200.39,131.54
+TBTA_VBUS_1 on TOP (solid shape): 27.86,97.05 27.86,94 27.76,93.9 26.86,93.9 26.54,93.57 26.54,93.25 26.32,93.03 23.51,93.03 23.43,93.12 23.43,93.8 22.87,93.8 22.87,93.8 22.87,94.24 22.87,94.24 23.43,94.24 23.43,95 22.87,95 22.87,95.44 22.88,95.46 23.41,95.46 23.42,95.47 23.42,96.12 24.48,97.17 27.74,97.17
+TBTA_VBUS_1 on BOTTOM (solid shape): 27,96.1 27,93.87 26.77,93.64 26.77,93.36 26.6,93.2 25.11,93.2 25.02,93.11 22.89,93.11 22.86,93.14 22.86,95.67 23.09,95.9 23.62,95.9 24.23,96.52 26.58,96.52
+V_DDR_REFA on TOP (solid shape): 124.71,86.91 124.71,86.4 125.01,86.11 125.46,86.11 125.49,86.09 125.49,85.36 124.9,84.78 124.64,84.78 124.41,85.01 124.41,85.26 124.1,85.57 124.1,86.9 124.16,86.95 124.68,86.95
+VDISPLAY_VCC on TOP (solid shape): 14.99,157.96 14.99,157.07 14.64,156.72 11.8,156.72 11.57,156.95 11.57,157.76 12.1,158.29 14.65,158.29
+VGA_B+ on TOP (solid shape): 164.18,175.93 169.09,175.93 169.42,175.6 169.42,169.78 169.28,169.64 166.18,169.64 166.17,169.64 164.97,169.64 164.96,169.63 164.81,169.63 164.62,169.44 164.62,168.39 164.77,168.24 164.77,168.04 164.59,167.86 163.96,167.86 163.25,168.56 163.25,175.95 163.29,175.98 164.12,175.98
+VGA_B+ on BOTTOM (solid shape): 170.36,178.58 170.36,173.7 169.42,172.76 169.42,168.01 169.06,167.66 164.52,167.66 163.88,167.02 162.61,167.02 162.48,167.15 162.48,168.04 162.86,168.42 162.86,170.45 163.27,170.86 163.27,175.72 163.41,175.86 165.43,175.86 165.66,176.09 165.66,178.55 165.79,178.68 170.26,178.68
+VLDOIN_1.2V on BOTTOM (solid shape): 283.07,97.36 284.97,97.36 285.06,97.27 285.06,97.16 285.01,97.11 283.83,97.11 283.83,97.11 281.74,97.11 281.74,97.53 281.16,97.53 281.16,97.71 281.7,97.71 281.7,97.71 281.74,97.71 281.74,98.13 281.8,98.19 282.24,98.19
+XS_PLLVDD on TOP (solid shape): 202.58,131.94 202.58,131.19 202.68,131.1 202.68,131.07 202.71,131.07 202.81,130.96 202.77,130.92 202.75,130.91 202.49,130.48 202.92,130.22 203,130.2 203.04,130.12 203.04,129.34 202.87,129.17 202.23,129.17 202.22,129.18 201.58,129.18 201.55,129.2 201.54,129.2 201.54,131.07 200.96,131.65 200.96,132.04 201.24,132.32 202.2,132.32
B+ on TOP (solid shape): 103.17,135.4 103.17,132.1 103.05,131.97 101.52,131.97 101.4,132.1 101.4,135.4 101.52,135.53 103.05,135.53
B+ on TOP (solid shape): 277.93,93.49 277.93,92.22 277.8,92.09 276.4,92.09 276.28,92.22 276.28,93.49 276.53,93.74 277.67,93.74
B+ on TOP (solid shape): 198.23,178.45 198.23,177.27 197.38,176.42 197.23,176.42 194.23,176.42 193.6,177.06 193.6,178.45 193.79,178.64 198.04,178.64
B+ on TOP (solid shape): 13.43,80.18 13.43,78.09 13.06,77.73 10.4,77.73 10.29,77.84 10.29,79.25 9.89,79.65 8.13,79.65 7.87,79.9 7.87,80.69 8.08,80.89 12.71,80.89
B+ on TOP (solid shape): 162.58,177.55 162.58,177.05 162.58,177.04 162.58,172.9 162.44,172.75 161.59,172.75 161.34,173 160.85,173 159.55,174.31 159.55,176.54 160.68,177.67 162.46,177.67
B+ on TOP (solid shape): 34.88,94.74 34.88,92.74 35.43,92.18 35.43,88.54 35.28,88.38 31.34,88.38 30.71,89.02 30.71,92.04 30.69,92.06 30.69,92.79 30.68,92.79 30.68,93.58 30.12,94.15 29.86,94.15 29.79,94.22 29.79,94.79 29.83,94.83 34.78,94.83
B+ on TOP (solid shape): 316.53,85.49 316.53,78.82 317.09,78.82 317.09,78.37 316.57,78.37 316.57,77.65 316.57,77.62 317.09,77.62 317.09,77.18 316.53,77.18 316.53,76.35 316.28,76.09 315.14,76.09 313.49,77.74 313.49,85.36 314.12,86 316.03,86
B+ on TOP (solid shape): 42.15,99.78 42.15,98.07 42.05,97.97 41.68,97.97 41.67,98.02 41.56,98.22 41.34,98.32 41.32,98.32 41.2,98.44 41.2,99.46 40.71,99.95 38.97,99.95 38.84,100.09 38.84,101.16 38.92,101.25 40.68,101.25
B+ on BOTTOM (solid shape): 251.56,88.99 251.56,87.01 250.74,86.19 250.15,86.19 250.02,86.31 250.02,88.17 251,89.15 251.41,89.15
B+ on BOTTOM (solid shape): 113.33,162.83 113.33,161.18 113.08,160.93 111.81,160.93 111.56,161.18 111.56,162.96 111.68,163.09 113.08,163.09
B+ on BOTTOM (solid shape): 129.08,173.5 129.08,171.6 128.83,171.34 122.1,171.34 121.97,171.47 121.97,173.88 122.67,174.58 128,174.58
B+ on BOTTOM (solid shape): 248.08,181.26 248.08,178.77 247.74,178.43 244.65,178.43 244.59,178.49 244.59,179.23 244.96,179.6 244.96,180.76 245.03,180.84 246.22,180.84 246.8,181.42 247.92,181.42
B+ on BOTTOM (solid shape): 102.54,134.89 105.59,134.89 105.65,134.83 105.65,134.02 105.51,133.88 103.3,133.88 103.17,133.75 103.17,132.1 103.05,131.97 102.31,131.97 101.65,131.97 101.52,132.1 101.52,135.4 101.65,135.53 101.9,135.53
B+ on BOTTOM (solid shape): 279.45,100.41 280.95,100.41 281.17,100.19 281.17,99.54 280.9,99.27 280.28,99.27 279.7,98.68 279.7,97.75 278.61,96.67 278.61,96.2 278.35,95.95 278.35,94.89 277.74,94.28 277.74,93.21 277.66,93.13 276.65,93.13 276.56,93.22 276.56,95.36 277.15,95.95 277.15,97.14 277.14,97.14 276.6,97.14 276.6,97.6 276.61,97.61 277.14,97.61 277.15,97.61 277.15,98.33 277.13,98.34 276.58,98.34 276.58,98.79 276.6,98.81 277.09,98.81 277.13,98.85 277.13,100.26 277.31,100.43 279.43,100.43
B+ on BOTTOM (solid shape): 33.59,94.85 33.64,94.85 33.69,94.85 34.2,94.85 34.25,94.85 34.31,94.85 35.78,94.85 35.8,94.84 35.8,94.57 35.81,94.56 35.81,94.24 35.81,94.23 35.81,93.87 35.66,93.72 35.33,93.72 34.98,93.36 34.98,93.03 36.55,91.46 41.79,91.46 41.97,91.28 41.97,90.7 41.89,90.62 40.82,90.62 40.6,90.4 40.6,88.78 40.85,88.52 41.86,88.52 41.94,88.45 41.94,87.95 40.72,86.74 34.96,86.74 33.79,87.9 30.75,87.9 30.73,87.92 30.25,87.92 30.18,87.95 30.15,88.02 29.93,88.36 29.53,88.28 29.46,88.25 29.39,88.28 29.35,88.31 29.3,88.34 28.9,88.75 28.13,88.75 28.04,88.84 28.04,90.59 28.59,90.59 28.94,90.95 28.59,91.31 28.07,91.31 28.04,91.34 28.04,91.91 28.12,91.99 29.03,91.99 29.1,91.98 29.17,91.99 29.86,91.99 30.07,92.2 30.07,92.94 30.08,93 30.07,93.07 30.07,93.56 30.07,93.6 30.07,93.87 29.76,94.18 29.76,94.71 29.77,94.8 29.82,94.85 30.19,94.85 30.2,94.84 30.21,94.85
B+ on BOTTOM (solid shape): outline of 334 points within 135.31,77.46 147.62,80.41
B++ on TOP (solid shape): 330.73,89.46 330.73,87.42 330.55,87.24 329.86,87.24 329.11,86.49 329.11,84.67 329.11,84.67 329.11,84.35 329.11,84.35 329.11,81.55 328.73,81.17 324.41,81.17 323.77,80.54 323.77,79.27 323.14,78.63 319.84,78.63 319.46,78.25 319.46,76.35 319.2,76.09 317.04,76.09 316.7,76.44 316.7,77.05 317.22,77.05 317.22,77.75 316.7,77.75 316.7,78.25 317.22,78.25 317.22,78.95 316.7,78.95 316.7,79.58 317.24,80.13 317.24,85.82 319.02,87.59 327.1,87.59 327.8,88.3 327.8,89.43 328.09,89.71 330.48,89.71
B+_1.8VSP on TOP (solid shape): 245.88,176.09 245.88,174.81 245.54,174.47 245.26,174.47 245.26,174.28 244.46,174.28 244.31,174.13 244.29,174.14 244.19,174.14 244.09,174.11 244.08,174.1 243.69,174.1 243.58,174.21 243.58,176.02 243.87,176.32 245.66,176.32
B+_1.8VSP on BOTTOM (solid shape): 246.17,177.53 246.17,174.92 246.09,174.84 245.76,174.84 245.64,174.72 244.65,174.72 244.32,175.05 241.99,175.05 241.7,174.76 241.7,174.4 241.1,173.79 241.1,172.89 241.46,172.53 242.34,172.53 242.45,172.42 242.45,170.9 242.41,170.85 241.52,170.85 241.31,171.06 241.3,171.06 240.92,171.44 240.68,171.44 240.29,171.83 240.29,175.99 240.8,176.5 242.17,176.5 242.33,176.45 242.49,176.5 244.45,176.5 244.58,176.63 244.58,177.5 244.73,177.65 246.05,177.65
B+_1V on TOP (solid shape): 136.36,76.8 136.36,75.27 136.26,75.17 134.04,75.17 133.86,75.35 133.86,77.01 133.99,77.13 136.02,77.13
B+_1V on BOTTOM (solid shape): 137.21,77.58 137.21,76.62 136.88,76.29 136.88,76.17 136.83,76.12 136.83,75.52 136.54,75.23 134.46,75.23 134.2,75.48 132.99,75.48 132.2,74.69 130.76,74.69 130.71,74.75 130.71,75.81 131.1,76.2 131.14,76.22 131.52,76.22 133.03,77.73 137.06,77.73
B+_1VSP on BOTTOM (solid shape): 245.32,183.38 246.27,183.38 246.53,183.11 246.53,181.55 246.38,181.4 244.97,181.4 244.92,181.45 244.92,181.92 244.63,182.21 242.29,182.21 241.92,182.58 241.92,183.16 241.66,183.43 240.74,183.43 240.66,183.43 240.36,183.12 240.36,182.81 240.27,182.72 238.81,182.72 238.73,182.8 238.73,184.85 238.94,185.06 243.64,185.06
BATBTN# on BOTTOM (solid shape): 348.35,180.55 347.33,180.55 347.33,182.2 348.35,182.2
BATBTN# on BOTTOM (solid shape): 348.35,176.68 347.33,176.68 347.33,178.33 348.35,178.33
BATT++ on TOP (solid shape): 24.79,84.16 24.94,84.12 25.1,84.16 25.11,84.16 25.14,84.16 25.43,83.88 25.43,82.09 25.35,82.01 23.29,82.01 23.04,82.26 23.04,83.83 23.36,84.16 24.78,84.16
BATT++ on BOTTOM (solid shape): outline of 128 points within 19.53,72.13 26.51,84.47
BOOT2_ISL88738 on TOP (solid shape): 45.06,82.03 45.06,81.93 45.01,81.88 43.31,81.88 42.75,81.32 42.75,81.12 42.63,80.99 42.58,80.83 41.68,79.93 40.92,79.93 40.84,80 40.84,80.84 40.97,80.97 41.45,80.97 42.6,82.11 44.98,82.11
BOOT_1.2V on BOTTOM (solid shape): 285.05,96.87 285.05,96.78 285,96.73 283.2,96.73 282.63,96.17 282.63,95.4 282.58,95.35 281.93,95.35 281.88,95.4 281.88,96.55 282.26,96.94 284.99,96.94
BST1_3V on TOP (solid shape): 340.41,91.71 340.41,90.82 340.29,90.7 338.49,90.7 338.38,90.81 338.38,91.71 338.44,91.78 340.34,91.78
BST1_5V on TOP (solid shape): 342.32,83.97 342.25,83.9 340.79,83.9 340.73,83.97 340.73,84.85 342.32,84.85
BST1_NVVDD on BOTTOM (solid shape): 164.8,181.61 164.8,181.51 164.71,181.41 164.48,181.41 163.34,180.27 161.33,180.27 161.28,180.32 161.28,180.9 161.3,180.92 163.13,180.92 163.9,181.68 164.73,181.68
BST1_NVVDDS on BOTTOM (solid shape): 189,180.64 189,178.62 188.84,178.45 188.17,178.45 188.1,178.52 188.1,180.46 187.59,180.97 187.54,180.97 187.53,180.97 187.42,180.97 187.34,181.06 187.34,181.82 187.4,181.89 187.75,181.89
BST2_NVVDD on TOP (solid shape): 170.11,181.4 170.11,180.84 169.52,180.26 168.56,180.26 168.36,180.37 168.14,180.29 167.69,180.74 167.69,181.16 167.72,181.19 167.74,181.19 167.74,181.21 167.82,181.29 168.04,181.29 168.41,180.92 168.83,180.92 169.09,181.17 169.09,181.4 169.16,181.48 170.03,181.48
BST2_NVVDD on BOTTOM (solid shape): 168.5,180.92 168.51,180.92 168.59,180.84 168.59,180.5 168.45,180.36 167.96,180.36 166.97,181.35 166.97,181.59 167.02,181.64 167.78,181.64
BST_1.8VSP on BOTTOM (solid shape): 241.45,170.68 242.36,170.68 242.45,170.59 242.45,170.44 242.28,170.27 241.35,170.27 241.1,170.53 240.51,170.53 240.47,170.57 240.47,171.07 240.54,171.14 241,171.14
BST_1V on BOTTOM (solid shape): 130.56,76.57 130.56,74.76 130.47,74.68 130.33,74.68 130.2,74.81 130.2,75.38 129.81,75.77 129.81,76.67 129.84,76.7 130.43,76.7
BST_1VSP on TOP (solid shape): 238.43,184.07 238.43,183.08 238.33,182.97 237.54,182.97 237.46,183.05 237.46,183.63 237.34,183.76 237.34,184.07 237.49,184.22 238.28,184.22
BST_1VSP on BOTTOM (solid shape): 238.56,184.09 238.56,182.8 238.48,182.72 238.35,182.72 237.83,183.25 237.49,183.25 237.43,183.31 237.43,183.31 237.26,183.48 237.26,184.07 237.36,184.17 238.48,184.17
BST_3V on TOP (solid shape): 341.75,91.75 341.75,90.83 341.62,90.69 341.62,89.93 341.87,89.68 341.87,88.64 341.82,88.59 341.7,88.59 341.64,88.65 341.64,89.53 341.02,90.15 341.02,91.68 341.12,91.78 341.73,91.78
BST_5V on TOP (solid shape): 341.87,86.36 341.87,85.24 341.61,84.98 340.67,84.98 340.66,84.98 340.47,84.98 340.28,84.79 340.28,84.03 340.16,83.9 339.39,83.9 339.27,84.03 339.27,84.92 339.71,85.36 341.48,85.36 341.66,85.53 341.66,86.35 341.7,86.4 341.83,86.4
CORE_SW1 on TOP (solid shape): 133.4,178.07 133.4,177.82 133.53,177.69 134.42,177.69 134.54,177.56 134.54,176.8 134.42,176.68 133.02,176.68 132.77,176.93 132.77,178.07 132.89,178.2 133.27,178.2
CORE_SW1 on BOTTOM (solid shape): 129.4,180.55 129.65,180.29 133.4,180.29 134.61,179.09 136.83,179.09 137.06,178.86 137.06,175.51 136.7,175.15 136.07,175.15 135.71,175.51 135.71,177.02 134.9,177.02 134.9,175.51 134.54,175.15 130.35,175.15 128.79,176.71 128.79,181.79 129.4,181.79
CORE_SW2 on TOP (solid shape): 141.02,178.07 141.02,177.82 141.15,177.69 142.04,177.69 142.16,177.56 142.16,176.8 142.04,176.68 140.64,176.68 140.39,176.93 140.39,178.07 140.51,178.2 140.89,178.2
CORE_SW2 on BOTTOM (solid shape): 138.42,180.55 138.67,180.29 142.42,180.29 144.01,178.71 145.91,178.71 146.23,178.39 146.23,175.53 145.85,175.15 143.81,175.15 143.33,175.63 143.33,176.64 142.52,176.64 142.52,175.51 142.16,175.15 138.23,175.15 137.81,175.57 137.81,181.79 138.42,181.79
CORE_SW3 on TOP (solid shape): 148.64,178.07 148.64,177.82 148.77,177.69 149.66,177.69 149.78,177.56 149.78,176.8 149.66,176.68 148.26,176.68 148.01,176.93 148.01,178.07 148.13,178.2 148.51,178.2
CORE_SW3 on BOTTOM (solid shape): 147.31,180.36 147.56,180.1 151.31,180.1 151.69,179.72 151.69,179.09 152.39,178.39 153.34,178.39 153.59,178.14 153.59,175.47 153.28,175.15 151.31,175.15 150.95,175.51 150.95,176.64 150.14,176.64 150.14,175.51 149.78,175.15 147.12,175.15 146.7,175.57 146.7,181.6 147.31,181.6
CORE_SW4 on TOP (solid shape): 155.63,178.07 155.63,177.82 155.75,177.69 156.64,177.69 156.77,177.56 156.77,176.8 156.64,176.68 155.24,176.68 154.99,176.93 154.99,178.07 155.12,178.2 155.5,178.2
CORE_SW4 on BOTTOM (solid shape): 154.74,180.36 154.99,180.1 158.74,180.1 158.74,178.77 159.92,177.59 159.92,175.73 159.88,175.72 159.8,175.68 159.72,175.61 159.56,175.45 159.56,173.98 159.34,173.75 158.86,173.75 158.57,174.05 158.57,176.64 157.76,176.64 157.76,174.11 157.4,173.75 154.48,173.75 154.13,174.11 154.13,181.6 154.74,181.6
DCIN_ISL88738 on TOP (solid shape): 52.06,80.89 52.06,79.55 52.02,79.51 51.21,79.51 50.78,79.94 49.76,79.94 49.53,80.17 49.27,80.17 49.15,80.29 48.32,80.29 48.27,80.34 48.27,80.46 48.32,80.51 49.57,80.51 49.77,80.7 50.82,80.7 51.1,80.99 51.97,80.99
DH1_NVVDD on BOTTOM (solid shape): 172.19,168.83 172.19,167.66 172.03,167.51 170.41,167.51 170.15,167.76 170.15,168.49 170.16,168.49 170.16,168.68 170.46,168.98 172.03,168.98
DH1_NVVDD on BOTTOM (solid shape): 164.82,182.03 164.82,181.92 164.72,181.81 163.85,181.81 163.83,181.8 163.07,181.04 162.79,181.04 162.7,181.14 162.7,181.47 163.28,182.05 163.3,182.05 163.39,182.06 163.48,182.09 163.49,182.09 164.34,182.09 164.37,182.1 164.41,182.1 164.75,182.1
DH1_NVVDDS on BOTTOM (solid shape): 190.64,176.43 190.64,176.03 190.84,175.83 190.84,175.51 190.61,175.28 189.67,175.28 189.54,175.41 189.54,176.45 189.67,176.57 190.49,176.57
DH1_NVVDDS on BOTTOM (solid shape): 187.18,181.84 187.18,181.04 187.37,180.85 187.46,180.85 187.48,180.84 187.98,180.35 187.98,179.94 187.76,179.72 187.25,179.72 187.12,179.85 187.12,180.36 187.09,180.38 187.09,180.64 187.09,180.66 187.04,180.8 186.94,180.91 186.94,181.82 187,181.89 187.13,181.89
DH2_NVVDD on BOTTOM (solid shape): 172.39,174.67 172.39,173.71 172.28,173.6 171.93,173.6 171.92,173.61 171.06,173.61 170.87,173.8 170.87,174.67 171.12,174.92 172.14,174.92
DH2_NVVDD on BOTTOM (solid shape): 167.94,182.01 168.41,182.01 168.43,181.98 168.44,181.97 168.5,181.89 168.58,181.83 168.59,181.82 168.96,181.46 168.96,181.17 168.84,181.05 168.55,181.05 168.01,181.59 168,181.6 167.92,181.73 167.78,181.78 167.07,181.78 166.99,181.86 166.99,182.01 167.06,182.09 167.86,182.09
DH_1.2V on BOTTOM (solid shape): 269.8,100.86 269.8,100.09 269.7,99.99 268.38,99.99 267.93,100.44 267.93,101.4 268.02,101.49 269.16,101.49
DH_1.2V on BOTTOM (solid shape): 285.05,96.48 285.05,96.37 285,96.33 283.94,96.33 283.13,95.52 282.94,95.52 282.82,95.65 282.82,96.08 283.28,96.54 284.99,96.54
DL1_NVVDD on TOP (solid shape): 165.23,165.35 165.94,165.35 166.19,165.09 166.19,164.74 165.96,164.51 164.31,164.51 164.16,164.66 164.16,165.53 164.29,165.66 164.92,165.66
DL1_NVVDD on BOTTOM (solid shape): 165.63,181.19 165.63,179.81 165.01,179.19 164.75,179.19 164.61,179.33 164.61,179.59 165.33,180.31 165.33,181.16 165.41,181.24 165.57,181.24
DL1_NVVDD on BOTTOM (solid shape): 166.23,166.32 166.23,165.82 166.08,165.68 165.25,165.68 164.69,165.12 164.69,164.64 164.57,164.51 164.24,164.51 164.14,164.61 164.14,165.66 164.22,165.75 164.51,165.75 164.77,166.01 164.77,166.31 164.92,166.46 166.09,166.46
DL1_NVVDDS on BOTTOM (solid shape): 188.2,177.71 188.78,177.71 188.94,177.56 188.94,176.64 188.82,176.52 187.72,176.52 187.53,176.71 187.53,177.64 187.74,177.85 188.06,177.85
DL1_NVVDDS on BOTTOM (solid shape): 188.63,182.73 189.8,182.73 189.8,182.73 190.21,182.73 190.3,182.64 190.3,182.26 190.17,182.14 189,182.14 188.72,182.42 187.85,182.42 187.72,182.54 187.72,182.65 187.8,182.73 188.63,182.73
DL2_NVVDD on TOP (solid shape): 175.25,186.02 175.25,184.96 174.78,184.48 172.43,184.48 172.26,184.65 172.26,184.79 172.27,184.8 172.32,184.9 172.34,185.01 172.34,185.31 172.65,185.62 174.13,185.62 174.7,186.19 175.09,186.19
DL2_NVVDD on BOTTOM (solid shape): 180.06,185.92 180.06,185.21 179.71,184.86 178.51,184.86 178.35,185.01 178.35,185.97 178.47,186.09 179.9,186.09
DL2_NVVDD on BOTTOM (solid shape): 166.41,181.21 166.41,180.37 166.43,180.35 166.43,180.27 167.09,179.61 167.09,179.28 166.89,179.09 166.7,179.09 166.15,179.64 166.15,181.2 166.21,181.26 166.35,181.26
DL_1.2V on BOTTOM (solid shape): 272.97,94 272.97,93.36 272.59,92.98 270.69,92.98 270.56,93.11 270.56,93.47 270.69,93.59 271.55,93.59 272.08,94.13 272.85,94.13
DL_1.2V on BOTTOM (solid shape): 285.33,95.79 285.33,94.93 284.59,94.19 284.02,94.19 283.93,94.28 283.93,94.6 285.18,95.85 285.27,95.85
DTH_VDD12 on BOTTOM (solid shape): 19.2,138.93 19.2,136.92 19.61,136.52 20.01,136.52 20.02,136.51 20.07,136.47 20.07,135.63 20.02,135.58 19.35,135.58 18.9,136.04 18.27,136.04 18.18,136.12 18.18,136.41 18.18,136.41 18.18,139.4 18.35,139.56 18.57,139.56
DTH_VDD33 on BOTTOM (solid shape): 23.37,143.27 23.53,143.27 23.65,143.25 23.77,143.27 25.25,143.27 25.37,143.15 25.37,142.59 25.04,142.26 22.21,142.26 22.13,142.17 20.8,142.17 20.64,142.34 20.64,143.26 20.69,143.31 23.33,143.31
DTH_VDDA12 on BOTTOM (solid shape): 20.47,143.61 20.47,141.58 20.29,141.4 19.83,141.4 19.7,141.53 19.7,142.68 19.51,142.87 18.45,142.87 18.18,142.59 17.55,142.59 17.47,142.67 17.47,143.6 17.55,143.68 19.25,143.68 19.25,143.68 20.39,143.68
DTH_VDDRX12 on BOTTOM (solid shape): outline of 304 points within 22.17,134.79 25.2,142.13
DTH_VDDTX12 on TOP (solid shape): 18.67,142.22 18.66,142.19 18.84,141.84 19.18,142.03 19.19,142.04 19.27,142.13 19.29,142.13 19.47,142.16 19.61,142.29 19.81,142.29 19.89,142.21 19.89,142 19.75,141.86 19.75,141.79 19.41,141.45 19.2,141.45 19.04,141.61 18.78,141.61 18.63,141.46 18.37,141.46 18.32,141.51 18.26,141.56 18.21,141.61 18.12,141.61 17.92,141.81 17.92,142.18 18.03,142.29 18.6,142.29
DTH_VDDTX12 on BOTTOM (solid shape): 19.26,142.1 19.33,142.1 19.35,142.1 19.56,141.89 19.56,141.5 19.3,141.24 18.62,141.24 18.61,141.24 18.3,141.18 18.16,140.89 18.18,140.77 18.24,140.66 18.24,139.64 18.05,139.45 18.05,136.46 17.86,136.26 16.81,136.26 16.74,136.34 16.74,138.35 16.89,138.5 16.89,139.64 16.99,139.74 17,139.74 17.11,139.82 17.19,139.93 17.2,139.95 17.25,140 17.25,140.2 16.99,140.45 16.99,141.62 17.5,142.13 19.18,142.13
GPPJ_RCOMP on BOTTOM (solid shape): 100.3,73 100.3,72.46 100.16,72.31 99.39,72.31 99.24,72.15 97.08,72.15 96.92,71.99 96.89,72.03 96.44,72.03 96.19,72.28 96.19,72.54 96.44,72.79 98.73,72.79 99.09,73.15 100.15,73.15
GT_B+ on TOP (solid shape): 106.6,139.06 106.6,137.36 105.92,136.67 105.92,136.24 105.84,136.16 104.32,136.16 103.68,136.8 103.68,138.96 103.94,139.21 104.83,139.21 105.21,139.59 106.07,139.59
GT_B+ on BOTTOM (solid shape): 107.68,138.09 106.5,138.09 106.15,137.74 106.15,137.23 105.71,136.8 105.71,136.42 105.84,136.29 105.84,135.53 105.71,135.4 102.41,135.4 102.29,135.53 102.29,136.54 102.35,136.61 102.98,136.61 103.12,136.75 103.12,139.03 103.34,139.25 107.68,139.25
GT_SW1 on TOP (solid shape): 110.22,144.23 110.22,143.27 110.03,143.08 108.7,143.08 108.51,143.27 108.51,144.23 108.7,144.42 110.03,144.42
GT_SW1 on BOTTOM (solid shape): 106.16,148.93 106.16,147.36 105.24,147.36 105.24,146.55 106.16,146.55 106.16,146.13 107.11,145.18 109.14,145.18 110.67,143.66 110.67,140.45 109.84,140.45 109.84,141.69 109.59,141.94 105.84,141.94 102.92,144.86 102.92,148.99 103.17,149.24 105.84,149.24
LDO_IN on TOP (solid shape): outline of 99 points within 62.04,88.69 68.52,95.84
LG1_ISL88738 on BOTTOM (solid shape): 46.79,76.01 46.79,75.58 46.33,75.13 46.33,74.29 46.18,74.14 45.24,74.14 45.11,74.26 45.11,75.96 45.31,76.17 46.63,76.17
LG_3V on TOP (solid shape): 340.66,88.45 340.99,88.45 341.07,88.37 341.07,88.25 341.01,88.19 340.13,88.19 339.85,88.47 339.46,88.47 339.2,88.73 339.2,89.11 339.44,89.35 339.76,89.35
LG_3V on TOP (solid shape): 336.36,89.5 336.36,88.53 336.23,88.4 335.8,88.4 335.45,88.05 335.45,87.74 334.92,87.21 334.19,87.21 334.1,87.31 334.1,88.11 334.2,88.2 334.22,88.23 334.74,88.23 335.07,88.55 335.07,89.52 335.07,89.52 335.14,89.59 336.27,89.59
LG_5V on TOP (solid shape): 341.07,86.74 341.07,86.64 340.99,86.57 340.42,86.57 340.02,86.17 339.13,86.17 339.05,86.25 339.05,86.6 339.21,86.76 340.16,86.76 340.22,86.81 340.99,86.81
LG_5V on TOP (solid shape): 332.24,85.84 332.24,84.97 332.09,84.82 331.21,84.82 330.92,84.54 329.73,84.54 329.63,84.63 329.63,85.9 329.76,86.03 332.05,86.03
LX1_ISL88738 on TOP (solid shape): 41.52,72.84 41.52,70.07 41.02,69.57 40.32,69.57 39.99,69.24 38.2,69.24 37.3,70.14 37.3,72.54 37.48,72.72 38.39,72.72 38.74,73.07 41.29,73.07
LX1_ISL88738 on TOP (solid shape): 45.79,80.16 45.79,79.07 45.22,78.5 43.76,78.5 42.37,77.11 42.37,76.55 42.16,76.35 41.5,76.35 41.3,76.55 41.3,77.11 43.21,79.02 45.2,79.02 45.38,79.2 45.42,79.23 45.45,79.26 45.57,79.38 45.57,80.16 45.63,80.21 45.74,80.21
LX1_ISL88738 on BOTTOM (solid shape): 41.15,79.63 43.88,79.63 44.36,79.63 44.38,79.61 44.38,75.35 44.32,75.28 40.63,75.28 39.58,74.23 39.58,73.12 40.04,72.66 40.82,72.66 41.2,72.28 41.2,68.99 40.82,68.61 36.1,68.61 35.37,69.33 31.45,69.33 30.61,70.17 30.61,73.45 37.64,73.45 37.64,73.4 37.65,73.34 37.67,73.29 37.69,73.25 37.72,73.2 37.76,73.16 37.8,73.13 37.84,73.1 37.89,73.08 37.95,73.07 38,73.07 38.05,73.07 38.1,73.08 38.15,73.1 38.2,73.13 38.24,73.16 38.28,73.2 38.31,73.25 38.33,73.29 38.35,73.34 38.35,73.4 38.35,73.45 38.35,73.5 38.33,73.55 38.31,73.6 38.28,73.65 38.24,73.69 38.2,73.72 38.15,73.75 38.1,73.76 38.05,73.78 38,73.78 37.95,73.78 37.89,73.76 37.84,73.75 37.8,73.72 37.76,73.69 37.72,73.65 37.69,73.6 37.67,73.55 37.65,73.5 37.64,73.45 30.61,73.45 30.61,74.33 32.88,76.6 36.63,76.6 38.28,78.25 38.84,78.25 39.56,78.97 39.56,79.53 39.93,79.9 40.88,79.9
LX1_NVVDD on TOP (solid shape): 171.53,169.09 171.53,167.35 171.81,167.07 174.14,167.07 174.37,166.85 174.37,163.61 172.64,161.88 166.94,161.88 166.84,161.98 166.84,169.05 166.95,169.16 171.46,169.16
LX1_NVVDD on BOTTOM (solid shape): 165.21,181.22 165.21,181.22 165.21,180.38 164.05,179.23 163.37,179.23 163.05,178.91 163.05,177.71 162.88,177.54 162.26,177.54 162.12,177.68 162.12,178.58 162.47,178.93 162.47,179.17 164.58,181.28 165.16,181.28
LX1_NVVDD on BOTTOM (solid shape): 174.4,172.71 174.86,172.71 175.31,172.26 175.31,164.53 172.72,161.94 167.11,161.94 166.85,162.2 166.85,166.54 167.37,167.06 170.51,167.06 171.14,166.43 172,166.43 172.4,166.83 172.4,169.09 172.16,169.33 170.23,169.33 170.08,169.49 170.08,172.53 170.28,172.74 174.37,172.74
LX1_NVVDDS on TOP (solid shape): 188.77,169.37 188.77,168.04 188.65,167.91 186.99,167.91 186.8,168.1 186.8,169.44 187.25,169.88 188.26,169.88
LX1_NVVDDS on BOTTOM (solid shape): 189.05,181.88 190.17,181.88 190.29,181.77 190.29,181.11 190.17,180.99 188.83,180.99 187.81,182.01 187.78,182.01 187.76,182.04 187.76,182.25 187.8,182.29 188.64,182.29
LX1_NVVDDS on BOTTOM (solid shape): 189.56,174.74 190.68,174.74 190.93,174.49 190.93,171.11 189.73,169.91 189.73,169.89 189.58,169.74 189.58,165.55 189.41,165.37 186.61,165.37 185.92,166.07 185.92,169.59 185.32,170.19 185.32,170.22 185.04,170.5 183.57,170.5 183.08,170.99 183.08,175.56 183.31,175.79 188.52,175.79
LX2_ISL88738 on TOP (solid shape): 38.6,82.53 38.6,80.03 38.19,79.62 38.19,78.8 37.52,78.12 33.45,78.12 33.2,78.38 33.2,83.05 33.73,83.58 37.54,83.58
LX2_ISL88738 on TOP (solid shape): 45.09,81.26 45.09,81.14 45.04,81.09 44.18,81.09 43.35,80.26 43.35,80.25 43.3,80.2 42.84,79.74 42.83,79.74 42.69,79.66 42.62,79.53 42.62,79.51 41.73,78.63 40.89,78.63 40.84,78.68 40.84,79.6 40.94,79.7 41.71,79.7 42.6,80.59 42.67,80.62 42.75,80.58 43.12,80.46 43.36,80.77 43.36,80.79 43.88,81.31 45.03,81.31
LX2_ISL88738 on BOTTOM (solid shape): 46.3,86.05 46.3,81.37 46.26,81.32 42.79,81.32 42.68,81.21 42.66,81.21 41.68,80.23 39.67,80.23 39.4,79.96 38.52,79.96 38.08,79.52 38.08,79.24 36.87,78.03 31.91,78.03 31.29,78.65 31.29,81.45 40.59,81.45 40.59,81.4 40.6,81.35 40.61,81.29 40.64,81.25 40.67,81.2 40.7,81.16 40.74,81.13 40.79,81.1 40.84,81.08 40.89,81.07 40.94,81.07 41,81.07 41.05,81.08 41.1,81.1 41.15,81.13 41.19,81.16 41.22,81.2 41.25,81.25 41.28,81.29 41.29,81.35 41.3,81.4 41.3,81.45 41.29,81.5 41.28,81.56 41.25,81.6 41.22,81.65 41.19,81.69 41.15,81.72 41.1,81.75 41.05,81.77 41,81.78 40.94,81.78 40.89,81.78 40.84,81.77 40.79,81.75 40.74,81.72 40.7,81.69 40.67,81.65 40.64,81.6 40.61,81.56 40.6,81.5 40.59,81.45 31.29,81.45 31.29,83.06 31.9,83.66 33.73,83.66 34.26,84.19 35.28,84.19 35.53,84.45 36.42,84.45 36.88,84.91 36.88,85.79 37.11,86.02 40.27,86.02 40.57,85.71 41.54,85.71 41.76,85.94 42.25,85.94 42.38,86.07 46.29,86.07
LX2_NVVDD on TOP (solid shape): 166.85,182 167.6,182 167.67,181.93 167.67,181.32 167.54,181.19 167.54,180.47 167.95,180.06 167.95,179.9 167.81,179.76 167.16,179.76 166.74,180.18 166.74,181.99 166.76,182.01 166.84,182.01
LX2_NVVDD on TOP (solid shape): 179.01,184.07 179.01,179.44 178.57,179 178.46,178.98 178.4,179.06 177.79,179.28 178,178.67 178.09,178.6 178.06,178.5 177.9,178.33 175.24,178.33 175.16,178.37 175.15,178.46 174.89,178.9 174.46,178.64 174.39,178.56 174.29,178.59 174.27,178.61 174.27,180.13 173.91,180.49 172.01,180.49 171.91,180.59 171.91,181.93 172.09,182.11 173.98,182.11 174.49,182.62 174.49,184.03 174.64,184.19 178.89,184.19
LX2_NVVDD on BOTTOM (solid shape): 167.92,180.1 167.92,179.84 167.79,179.71 167.24,179.71 166.53,180.43 166.53,181.21 166.6,181.28 166.75,181.28
LX2_NVVDD on BOTTOM (solid shape): outline of 237 points within 170.92,173.3 179.35,184.32
LX_1.8VSP on BOTTOM (solid shape): 242.12,173.47 242.67,173.47 242.78,173.36 242.78,172.61 242.71,172.54 242.53,172.54 242.33,172.74 241.94,172.74 241.3,173.37 241.3,173.68 241.49,173.87 241.72,173.87
LX_1.8VSP on BOTTOM (solid shape): 239.67,170.15 239.67,169.61 239.79,169.49 241.16,169.49 241.31,169.64 241.31,169.93 241.48,170.1 242.34,170.1 242.58,170.34 243.16,170.34 243.23,170.27 243.23,169.51 243.18,169.46 243.18,167.55 237.93,167.55 237.82,167.66 237.82,170.27 238.05,170.5 239.32,170.5
LX_1V on TOP (solid shape): 133.87,75.14 133.87,74.55 133.64,74.32 128.73,74.32 128.47,74.57 128.47,75.12 128.77,75.42 133.6,75.42
LX_1V on BOTTOM (solid shape): 134.04,75.22 134.04,74.86 133.55,74.37 132.44,74.37 132.4,74.42 132.4,74.65 132.43,74.7 132.46,74.76 132.97,75.28 133.98,75.28
LX_1V on BOTTOM (solid shape): 128.08,76.58 128.08,75.88 128.35,75.61 129.72,75.61 129.84,75.48 129.84,74.99 130.27,74.56 130.27,73.98 130.2,73.9 128.68,73.9 128.46,73.68 128.46,70.11 128.45,70.11 128.45,68.81 128.33,68.68 127.19,68.68 127.04,68.83 127.04,71.29 126.36,71.97 126.36,75.95 127.01,76.6 127.07,76.6 127.12,76.62 128.04,76.62
LX_1VSP on TOP (solid shape): 232.14,182.9 232.14,181.5 231.76,181.12 229.86,181.12 229.6,181.37 229.6,182.96 229.73,183.09 231.95,183.09
LX_1VSP on TOP (solid shape): 241.73,183.23 241.73,182.82 240.97,182.06 239.06,182.06 238.91,181.91 236.68,181.91 236.35,181.58 235.64,181.58 235.51,181.7 235.51,182.47 235.86,182.82 238.58,182.82 239.09,183.33 241.63,183.33
LX_1VSP on BOTTOM (solid shape): 241.73,183.15 241.73,182.87 241.26,182.4 240.49,182.4 240.41,182.48 240.41,182.59 240.5,182.68 240.52,182.7 240.52,183.03 240.79,183.3 241.58,183.3
LX_1VSP on BOTTOM (solid shape): 237.03,182.93 237.88,182.93 238.23,182.59 238.23,182.04 238.14,181.95 236.67,181.95 236.5,181.78 236.06,181.78 234.67,180.38 231.42,180.38 231.14,180.66 231.14,182.92 231.37,183.15 236.81,183.15
LX_3V on TOP (solid shape): 342.38,90.82 342.38,89.93 342.28,89.84 342.28,88.65 342.22,88.59 342.12,88.59 342.05,88.65 342.05,89.75 341.81,90 341.81,90.69 341.88,90.77 341.88,90.86 341.97,90.95 342.25,90.95
LX_3V on TOP (solid shape): 336.48,100.6 336.95,100.13 336.95,94.89 337.74,94.1 337.74,92 338,91.74 338,90.68 337.77,90.45 335.04,90.45 334.65,90.06 334.65,88.97 334.43,88.75 331.8,88.75 331.58,88.97 331.58,89.87 331.46,90 328.87,90 328.66,90.22 328.66,91.46 329.04,91.84 331.14,91.84 331.97,92.66 331.97,96.86 332.61,97.5 333.3,97.5 333.98,98.18 333.98,100.39 334.2,100.6 334.57,100.6
LX_5V on TOP (solid shape): 342.27,86.34 342.27,85.47 342.82,84.92 344.54,84.92 345.05,84.41 345.05,83.9 344.92,83.77 342.89,83.77 342.51,84.16 342.51,84.85 342.38,84.98 342.19,84.98 342.06,85.11 342.06,86.34 342.12,86.4 342.21,86.4
LX_5V on TOP (solid shape): 332.83,84.57 335.91,84.57 336.16,84.33 336.16,80.72 336.72,80.16 338.39,80.16 338.55,79.99 338.55,70.45 337.9,69.79 330.33,69.79 329.67,70.45 329.67,76.24 328.88,77.03 325.2,77.03 324.28,77.95 324.28,80.54 327.94,80.54 327.94,79.95 328.23,79.66 328.3,79.59 328.77,79.59 328.94,79.42 329.36,79.42 329.65,79.71 329.65,79.8 329.65,79.8 329.65,80.57 329.45,80.77 329.22,80.77 329.14,80.77 328.17,80.77 327.94,80.54 324.28,80.54 324.28,80.79 324.54,81.04 328.78,81.04 329.57,81.04 329.77,81.25 329.77,81.68 329.77,81.69 329.77,83.12 331.25,84.6 332.81,84.6
Net_3041 on BOTTOM (solid shape): 239.45,97.13 224.45,97.13 224.45,107.13 239.45,107.13
Net_3315 on BOTTOM (solid shape): 220.26,68.9 212.26,68.9 212.26,76.9 220.26,76.9
Net_3757 on BOTTOM (solid shape): 208.14,97.62 200.14,97.62 200.14,105.62 208.14,105.62
PP_HV on TOP (solid shape): 22.02,121.42 22.02,120.76 21.84,120.58 20.34,120.58 20.27,120.64 20.27,121.52 20.62,121.87 21.58,121.87
PP_HV on BOTTOM (solid shape): 21.56,122.64 21.56,122.46 21.71,122.31 21.87,122.31 22.17,122.01 22.17,120.89 21.93,120.64 21.69,120.64 21.1,121.24 21.1,121.68 20.8,121.98 20.8,122.2 20.97,122.37 21.04,122.37 21.21,122.55 21.21,122.62 21.29,122.7 21.51,122.7
PWR_VGA_CORE_BOOT1 on TOP (solid shape): 196.05,182.61 196.05,181.79 195.94,181.68 195.01,181.68 194.81,181.88 193.58,181.88 192.78,182.68 192.78,182.9 192.86,182.98 195.68,182.98
PWR_VGA_CORE_LGATE1 on TOP (solid shape): 192.19,182.51 192.19,180.6 191.82,180.23 190.17,180.23 190.04,180.36 190.04,180.87 190.17,180.99 191.44,180.99 191.99,181.54 191.99,182.5 192.04,182.56 192.14,182.56
PWR_VGA_CORE_LGATE1 on BOTTOM (solid shape): 200.58,187.72 200.58,186.33 200.46,186.2 199.31,186.2 199.19,186.33 199.19,186.84 198.93,187.09 197.84,187.09 197.15,186.4 197.15,185.95 197.03,185.82 196.52,185.82 196.39,185.95 196.39,186.73 197.51,187.85 200.46,187.85
PWR_VGA_CORE_PHASE1 on TOP (solid shape): 204.61,183.92 204.61,182.76 204.55,182.7 202.28,182.7 201.76,182.18 201.47,182.18 201.16,182.49 201.16,183.85 201.47,184.16 204.38,184.16
PWR_VGA_CORE_PHASE1 on TOP (solid shape): 197.79,182.57 197.79,181.18 197.35,180.74 192.71,180.74 192.39,181.06 192.39,182.52 192.45,182.58 192.54,182.58 192.61,182.5 192.61,182.23 193.09,181.76 194.76,181.76 194.95,181.56 196,181.56 196,181.56 196.09,181.56 196.23,181.7 196.23,182.52 196.39,182.68 197.68,182.68
PWR_VGA_CORE_PHASE1 on BOTTOM (solid shape): 201.98,185.31 201.98,181.37 201.85,181.25 197.54,181.25 197.15,181.63 197.15,182.52 196.94,182.73 192.87,182.73 192.71,182.9 192.71,185.31 192.84,185.44 201.85,185.44
PWR_VGA_CORE_UGATE1 on TOP (solid shape): 198.87,180.36 198.87,179.02 198.68,178.83 198.04,178.83 197.92,178.96 197.92,180.36 198.11,180.55 198.68,180.55
PWR_VGA_CORE_UGATE1 on TOP (solid shape): 196.65,184.87 196.65,184.33 196.47,184.16 195.2,184.16 194.96,183.92 194.96,183.65 194.45,183.14 192.85,183.14 192.79,183.2 192.79,183.3 192.86,183.38 193.88,183.38 194.28,183.78 194.35,183.78 194.59,184.01 194.59,184.09 194.59,184.1 194.62,184.21 194.59,184.31 194.59,184.32 194.59,184.4 194.92,184.73 195.1,184.73 195.1,184.9 195.19,184.99 196.52,184.99
PWR_VGA_CORE_UGATE1 on BOTTOM (solid shape): 198.68,180.49 198.68,178.96 198.55,178.83 198.04,178.83 197.92,178.96 197.92,179.85 197.66,180.1 196.52,180.1 196.39,180.23 196.39,180.61 196.52,180.74 198.42,180.74
RING2 on BOTTOM (solid shape): 6.66,111.64 6.66,110.56 6.74,110.48 6.74,108.69 6.65,108.6 6.53,108.6 6.48,108.65 6.48,109.69 6.43,109.74 6.43,110.38 6.42,110.4 6.42,110.42 6.19,110.65 6.19,111.07 6.14,111.12 6.14,111.6 6.28,111.74 6.56,111.74
RING2 on BOTTOM (solid shape): 7.82,125.99 7.82,125.56 8.15,125.23 8.38,125.23 8.58,125.03 8.58,124.37 8.44,124.24 7.67,124.24 7.14,124.81 6.41,125.09 6.39,125.09 6.3,125.18 6.3,126.06 6.36,126.12 7.7,126.12
RING2_L on BOTTOM (solid shape): 2.06,126.08 2.8,126.08 2.9,126.17 3.53,126.17 3.7,126 3.7,125.5 3.85,125.35 4.92,125.35 5.41,125.84 5.41,125.95 5.55,126.09 6.04,126.09 6.08,126.05 6.08,125.1 5.52,124.98 5.02,124.68 3.52,124.68 2.69,125.51 2.12,125.51 1.96,125.35 1.96,124.21 1.76,124.01 1.76,123.31 1.51,123.06 0.31,123.06 0.16,123.21 0.16,124.25 1.11,125.2 1.11,125.46 1.82,126.17 1.97,126.17
RREF on BOTTOM (solid shape): 336.14,102.94 336.14,102.76 334.94,101.55 334.94,100.44 334.91,100.41 334.35,100.41 334.35,101.57 335.25,102.47 335.25,102.91 335.33,102.99 336.09,102.99
SA_B+ on TOP (solid shape): 110.83,163.18 110.83,163.15 110.92,162.83 111.24,162.74 111.27,162.74 112.57,161.44 112.57,160.55 112.45,160.42 111.3,160.42 110.68,159.8 110.14,159.8 109.52,160.42 108.66,160.42 108.03,161.05 108.03,162.86 108.76,163.59 110.41,163.59
SA_B+ on BOTTOM (solid shape): 110.92,162.45 110.92,161.18 111.59,160.51 111.59,159.86 110.12,159.86 109.07,160.91 106.67,160.91 106.67,162.04 107.97,162.04 108.2,162.27 108.2,162.91 108.36,163.06 110.31,163.06
SA_SW on TOP (solid shape): 105.06,157.31 105.06,155.07 104.83,154.83 104.32,154.83 104.06,155.09 104.06,157.24 104.32,157.5 104.87,157.5
SA_SW on BOTTOM (solid shape): 104.51,158.2 108.51,158.2 108.51,157.59 106.14,155.22 106.14,154.35 105.23,154.35 105.23,153.54 106.14,153.54 106.14,152.34 105.84,152.04 103.56,152.04 103.17,152.42 103.17,159.02 103.84,159.69 104.51,159.69
SD_REG2 on BOTTOM (solid shape): 341.45,107.09 341.45,106.62 341.15,106.32 340.58,106.32 340.58,106.32 339.62,106.32 339.18,105.88 339.1,105.88 339.04,105.94 339.04,106.73 339.38,107.07 340.6,107.07 340.74,107.21 341.34,107.21
SLEEVE on TOP (solid shape): 7.3,112.38 7.3,110.79 7.18,110.67 6.88,110.67 6.77,110.78 6.77,111.63 6.63,111.78 6.51,111.78 6.5,111.78 6.4,111.79 6.3,111.78 6.3,111.78 4.63,111.78 4.51,111.9 4.51,112.51 4.6,112.59 7.08,112.59
SLEEVE on BOTTOM (solid shape): 12.68,124.81 12.68,124.63 12.45,124.41 11.59,124.41 10.62,125.38 10.41,125.38 10.34,125.45 10.34,126.05 10.41,126.12 11.37,126.12
SLEEVE on BOTTOM (solid shape): 7.31,111.51 7.31,111.25 7.3,111.25 7.3,110.85 7.31,110.85 7.31,110.68 7.12,110.49 7.12,108.69 7.05,108.61 6.95,108.61 6.89,108.67 6.89,110.51 6.79,110.61 6.79,111.5 6.86,111.57 7.25,111.57
SLEEVE_L on TOP (solid shape): 1.48,112.96 1.48,112.77 1.79,112.46 2.5,112.46 2.92,112.88 4.05,112.88 4.17,112.76 4.17,111.95 4.11,111.89 0.83,111.89 0.42,112.3 0.42,112.91 0.5,112.99 1.44,112.99
SNB_1.8VSP on BOTTOM (solid shape): 239.95,166.52 239.95,164.23 239.7,163.98 238.43,163.98 238.05,164.36 238.05,166.52 238.18,166.64 239.83,166.64
SNB_1V on BOTTOM (solid shape): 125.98,70.45 126.15,70.28 126.15,68.35 126.05,68.25 124.04,68.25 123.88,68.41 123.88,70.3 124.06,70.47 125.98,70.47
SNB_1VSP on TOP (solid shape): 233.73,183.03 233.73,182.58 233.98,182.33 235.13,182.33 235.25,182.2 235.25,181.37 235.13,181.25 232.71,181.25 232.52,181.44 232.52,183.09 232.59,183.15 233.6,183.15
SNUB_1.2V on BOTTOM (solid shape): 264.59,94.95 264.59,93.3 264.4,93.11 263.45,93.11 263.32,93.24 263.32,93.93 263.07,94.19 262.18,94.19 261.99,94.38 261.99,94.95 262.18,95.14 264.4,95.14
SNUB_1VS_VCCIO on TOP (solid shape): 109.12,126.91 109.12,125.92 109,125.8 107.51,125.8 107.43,125.88 107.43,126.89 107.51,126.97 109.07,126.97
SNUB_3V on TOP (solid shape): 332.69,100.47 332.69,100.47 332.69,98.99 332.58,98.88 330.45,98.88 330.25,99.08 330.25,99.9 330.39,100.03 330.89,100.03 331.44,100.58 332.57,100.58
SNUB_5V on TOP (solid shape): 338.57,83.97 338.57,81.38 338.32,81.12 336.84,81.12 336.54,81.42 336.54,83.96 336.71,84.13 338.4,84.13
SNUB_CHG1 on TOP (solid shape): 36.63,73.6 36.63,70.6 36.37,70.35 34.95,70.35 34.72,70.58 34.72,73.32 35.13,73.73 36.5,73.73
SNUB_CHG2 on TOP (solid shape): 32.07,82.01 32.07,79.93 31.58,79.44 30.78,79.44 30.34,79.88 30.34,82.03 30.48,82.17 31.91,82.17
SW_1.2V on BOTTOM (solid shape): 285.05,96.07 285.05,95.98 284.91,95.84 284.53,95.84 282.69,94 282.05,94 281.93,94.13 281.93,95.01 281.99,95.08 282.94,95.08 284.01,96.14 284.98,96.14
SW_1.2V on BOTTOM (solid shape): 267.57,100.71 267.57,100.29 268.12,99.74 269.65,99.74 269.75,99.64 269.75,97.61 270.18,97.17 270.18,93.24 269.93,92.98 266.12,92.98 265.86,93.24 265.86,95.46 264.72,96.6 264.72,100.64 264.91,100.82 267.45,100.82
TBT_SVR_IND on BOTTOM (solid shape): 21.58,116.92 21.58,114.83 21.36,114.61 21.36,113.16 21.36,113.15 21.36,112.79 21.2,112.63 21.2,111.5 21.13,111.43 21.01,111.43 20.87,111.29 20.87,111.14 20.79,111.06 20.59,111.06 20.48,111.17 20.48,112.21 20.63,112.35 20.63,112.45 20.63,113.25 20.53,113.34 20.53,116.96 20.69,117.11 21.39,117.11
TBTA_CC1 on TOP (solid shape): 7.83,134.24 7.83,133.51 7.71,133.38 6.73,133.38 6.51,133.6 5.15,133.6 5.07,133.68 5.07,133.83 5.16,133.91 6.68,133.91 7.07,134.3 7.77,134.3
TBTA_CC1 on BOTTOM (solid shape): 24.04,129.3 24.04,129.06 22.91,127.93 22.91,127.42 22.54,127.06 22.54,126.47 22.5,126.43 22.3,126.43 22.25,126.48 22.25,127.02 22.33,127.1 22.33,127.19 22.53,127.4 22.53,128.11 23.28,128.86 23.28,129.26 23.43,129.42 23.93,129.42
TBTA_CC2 on BOTTOM (solid shape): 23.52,127.91 23.52,127.28 23.48,127.26 23.44,127.27 23.22,127.21 23.19,126.98 23.19,126.87 23.03,126.7 23.03,126.52 22.94,126.43 22.71,126.43 22.62,126.52 22.62,127.01 23.01,127.4 23.01,127.86 23.13,127.97 23.46,127.97
UG1_ISL88738 on TOP (solid shape): 41.65,69.15 41.65,67.96 41.6,67.91 40.14,67.91 40.08,67.98 40.08,69.02 40.34,69.29 41.51,69.29
UG1_ISL88738 on BOTTOM (solid shape): 41.71,74.22 41.71,73.17 41.45,72.92 40.04,72.92 39.88,73.08 39.88,73.98 40.47,74.56 41.36,74.56
UG_3V on TOP (solid shape): 328.58,92.43 328.58,91.56 328.53,91.51 328.53,90.19 328.52,90.18 327.74,90.18 327.59,90.32 327.59,92.49 327.64,92.54 328.47,92.54
UG_3V on TOP (solid shape): 341.46,89.45 341.46,88.64 341.41,88.58 341.29,88.58 341.21,88.66 341.21,89.2 341.11,89.3 340.86,89.3 340.22,89.93 340.22,90.12 340.35,90.25 340.66,90.25
UG_5V on TOP (solid shape): 329.53,80.51 329.53,79.86 329.52,79.85 329.52,79.76 329.31,79.55 328.99,79.55 328.83,79.71 328.35,79.71 328.07,80 328.07,80.49 328.22,80.65 329.39,80.65
UG_5V on TOP (solid shape): 341.47,86.34 341.47,85.56 341.4,85.49 340.09,85.49 340.03,85.55 340.03,85.87 340.22,86.06 341.17,86.06 341.24,86.12 341.24,86.34 341.3,86.4 341.41,86.4
VCORE_B+ on TOP (solid shape): 127.43,180.87 127.43,179.72 128.42,178.73 128.42,176.01 128.3,175.89 122,175.89 121.72,176.17 121.72,181.17 127.13,181.17
VCORE_B+ on TOP (solid shape): outline of 619 points within 131.24,183.03 161.34,187.72
VCORE_B+ on BOTTOM (solid shape): 127.43,180.61 127.43,179.72 128.32,178.83 128.32,175.91 127.88,175.47 122.42,175.47 121.72,176.17 121.72,178.58 122.22,179.09 122.22,180.66 122.73,181.17 126.88,181.17
VCORE_B+ on BOTTOM (solid shape): 161.09,187.47 161.09,184.3 160.96,184.17 160.96,183.79 160.71,183.53 160.25,183.53 159.53,182.82 156.9,182.82 156.9,183.95 158.07,183.95 158.43,184.31 158.43,184.94 158.84,185.35 159.31,185.35 159.44,185.48 159.44,187.47 159.69,187.72 160.83,187.72
VCORE_B+ on BOTTOM (solid shape): 153.66,187.53 153.66,186.01 153.09,185.44 153.09,184.93 153.34,184.68 153.34,182.94 153.22,182.82 149.47,182.82 149.47,183.95 150.64,183.95 151,184.31 151,184.81 151.54,185.35 151.85,185.35 151.94,185.44 151.94,187.53 152.13,187.72 153.47,187.72
VCORE_B+ on BOTTOM (solid shape): 146.1,187.53 146.1,185.82 145.72,185.44 145.72,184.93 146.1,184.55 146.1,183.72 145.91,183.53 144.96,183.53 144.44,183.01 140.58,183.01 140.58,184.14 141.75,184.14 142.11,184.5 142.11,185 142.2,185.09 143.09,185.09 143.75,185.76 143.75,187.53 143.94,187.72 145.91,187.72
VCORE_B+ on BOTTOM (solid shape): 138.1,187.09 138.1,185.82 137.85,185.57 137.34,185.57 137.15,185.37 137.15,183.72 137.08,183.66 136.13,183.66 135.5,183.03 134.18,183.03 134.16,183.01 131.57,183.01 131.57,184.14 132.74,184.14 133.09,184.5 133.09,185 133.27,185.18 134.67,185.18 135.05,185.57 135.05,187.09 135.31,187.34 137.85,187.34
N01897 on TOP (solid shape): 105.84,135.4 105.84,134.51 104.83,133.5 104.83,132.23 104.57,131.97 103.56,131.97 103.43,132.1 103.43,133.75 103.81,134.13 103.81,135.27 104.06,135.53 105.71,135.53
N01897 on BOTTOM (solid shape): 104.7,133.5 104.7,132.35 105.08,131.97 105.08,131.65 105.02,131.59 104.76,131.59 104.38,131.97 104.17,131.97 103.56,131.97 103.43,132.1 103.43,133.5 103.56,133.62 104.57,133.62
N02167 on BOTTOM (solid shape): 106.12,129.03 106.12,128.31 105.59,127.78 104.06,127.78 103.81,127.53 103.05,127.53 102.97,127.6 102.97,128.47 103.05,128.54 105.35,128.54 105.91,129.1 106.05,129.1
N02213 on TOP (solid shape): 106.98,126.76 106.98,125.11 106.86,124.99 105.71,124.99 105.59,125.11 105.59,126.76 105.79,126.97 106.78,126.97
N02213 on BOTTOM (solid shape): 106.6,129.85 106.6,128.29 107.11,127.78 107.11,123.46 106.73,123.08 101.83,123.08 101.63,123.28 101.63,126.24 101.72,126.32 102.48,126.32 103.43,127.27 103.94,127.27 104.19,127.53 105.71,127.53 106.35,128.16 106.35,129.84 106.4,129.9 106.56,129.9
N16399093 on TOP (solid shape): 58.09,83.08 58.09,81.71 58.05,81.7 57.97,81.67 57.9,81.61 56.88,81.61 56.79,81.67 56.8,81.77 56.52,82.34 56.23,81.77 56.24,81.67 56.15,81.61 54.97,81.61 54.41,81.04 54.41,79.65 54.28,79.52 52.88,79.52 52.88,80.92 53.9,81.93 53.9,82.7 54.79,83.58 57.58,83.58
N17034092 on TOP (solid shape): 338.97,89.35 338.97,88.78 339.41,88.33 339.8,88.33 340.11,88.03 340.98,88.03 341.07,87.94 341.07,87.86 341.01,87.79 340.07,87.79 339.91,87.95 338.79,87.95 338.68,87.85 338.11,87.85 338.07,87.89 338.07,89.42 338.09,89.44 338.88,89.44
N19473637 on TOP (solid shape): 179.63,84.98 179.63,83.71 180.26,83.08 180.77,83.08 181.85,82 181.85,81.39 181.58,81.12 180.42,81.12 179.9,80.6 178.71,80.6 178.64,80.68 178.64,81.74 178.22,82.16 178.22,83.61 178.59,83.98 178.59,84.96 178.65,85.02 179.59,85.02
N20816800 on TOP (solid shape): 108,144.67 108,143.15 107.87,143.02 106.1,143.02 105.59,143.53 105.59,145.43 105.71,145.56 107.11,145.56
N20816888 on TOP (solid shape): 107.75,156.74 107.75,154.96 107.62,154.83 105.84,154.83 105.71,154.96 105.71,156.36 106.22,156.86 107.62,156.86
N28152784 on TOP (solid shape): 112.89,180.21 112.13,179.45 112.13,178.63 112.07,178.56 111.94,178.56 111.88,178.63 111.88,179.71 112.13,179.96 112.13,180.61 111.62,181.12 110.73,181.12 110.73,181.76 112.89,181.76
N32074224 on TOP (solid shape): 205.28,187.6 205.28,186.07 204.77,185.57 202.62,185.57 202.49,185.69 202.49,187.34 203,187.85 205.03,187.85
N48708347 on BOTTOM (solid shape): 281.29,96.28 281.29,94.13 281.18,94.02 280.65,94.02 280.47,94.2 280.47,96.22 280.59,96.35 281.23,96.35
N55155823 on TOP (solid shape): 42.14,101.95 42.14,100.52 42.04,100.43 41.75,100.43 40.73,101.45 37.96,101.45 37.85,101.57 37.85,102.2 37.95,102.3 41.78,102.3
N110703687 on TOP (solid shape): 174.5,169.91 174.5,168.2 174.22,167.91 172.47,167.91 172.31,168.08 172.31,169.91 172.54,170.14 174.28,170.14
N116496514 on TOP (solid shape): 173.61,184.17 173.61,183.18 173.52,183.09 170.76,183.09 170.57,183.28 170.57,184.03 170.79,184.24 173.53,184.24
N119942216 on BOTTOM (solid shape): 24.06,156.93 24.06,156.29 24.31,156.04 24.31,152.52 24.15,152.37 14.99,152.37 14.72,152.63 14.72,156.28 14.9,156.46 15.96,156.46 15.99,156.43 21.84,156.43 21.88,156.47 21.89,156.47 22.06,156.57 22.16,156.74 22.16,156.75 22.44,157.03 23.96,157.03
N122528028 on TOP (solid shape): 235.76,110.99 236.52,110.99 236.6,110.91 236.6,108.91 236.41,108.72 234.4,108.72 234.19,108.93 234.19,109.88 234.07,110.01 233.47,110.01 233.29,110.19 233.29,110.96 233.48,111.15 235.59,111.15
N128723349 on TOP (solid shape): 188.79,171.76 188.79,170.78 188.78,170.76 187.24,170.76 186.99,170.52 186.04,170.52 185.85,170.71 185.85,171.4 186.04,171.6 186.74,171.6 186.94,171.79 188.76,171.79
N128725563 on BOTTOM (solid shape): 162.23,179.52 162.23,178.91 161.99,178.67 161.99,177.63 161.99,177.62 162.2,177.41 162.92,177.41 163.09,177.25 163.09,176.27 163.08,176.27 163.08,176.15 163.05,176.12 161.74,176.12 161.64,176.22 161.64,176.96 161.13,177.47 161.13,178.08 161.2,178.15 161.2,179.55 161.28,179.62 162.13,179.62
N128725569 on TOP (solid shape): 167.92,183.14 168.59,183.14 168.8,183.34 169.07,183.34 169.09,183.35 169.84,183.35 170.18,183.01 170.18,182.03 170.01,181.85 169.17,181.85 168.6,182.43 167.58,182.43 167.37,182.64 166.81,182.64 166.72,182.73 166.72,183.45 166.79,183.52 167.54,183.52
N128726031 on BOTTOM (solid shape): 166.01,181.21 166.01,179.25 165.42,178.66 165.42,178.2 165.04,177.82 163.27,177.82 163.19,177.89 163.19,178.8 163.41,179.02 165.04,179.02 165.77,179.75 165.77,181.21 165.82,181.27 165.95,181.27
N128727405 on BOTTOM (solid shape): 190.29,180.35 190.29,178.57 190.17,178.45 189.41,178.45 189.26,178.6 189.26,180.35 189.35,180.44 190.2,180.44
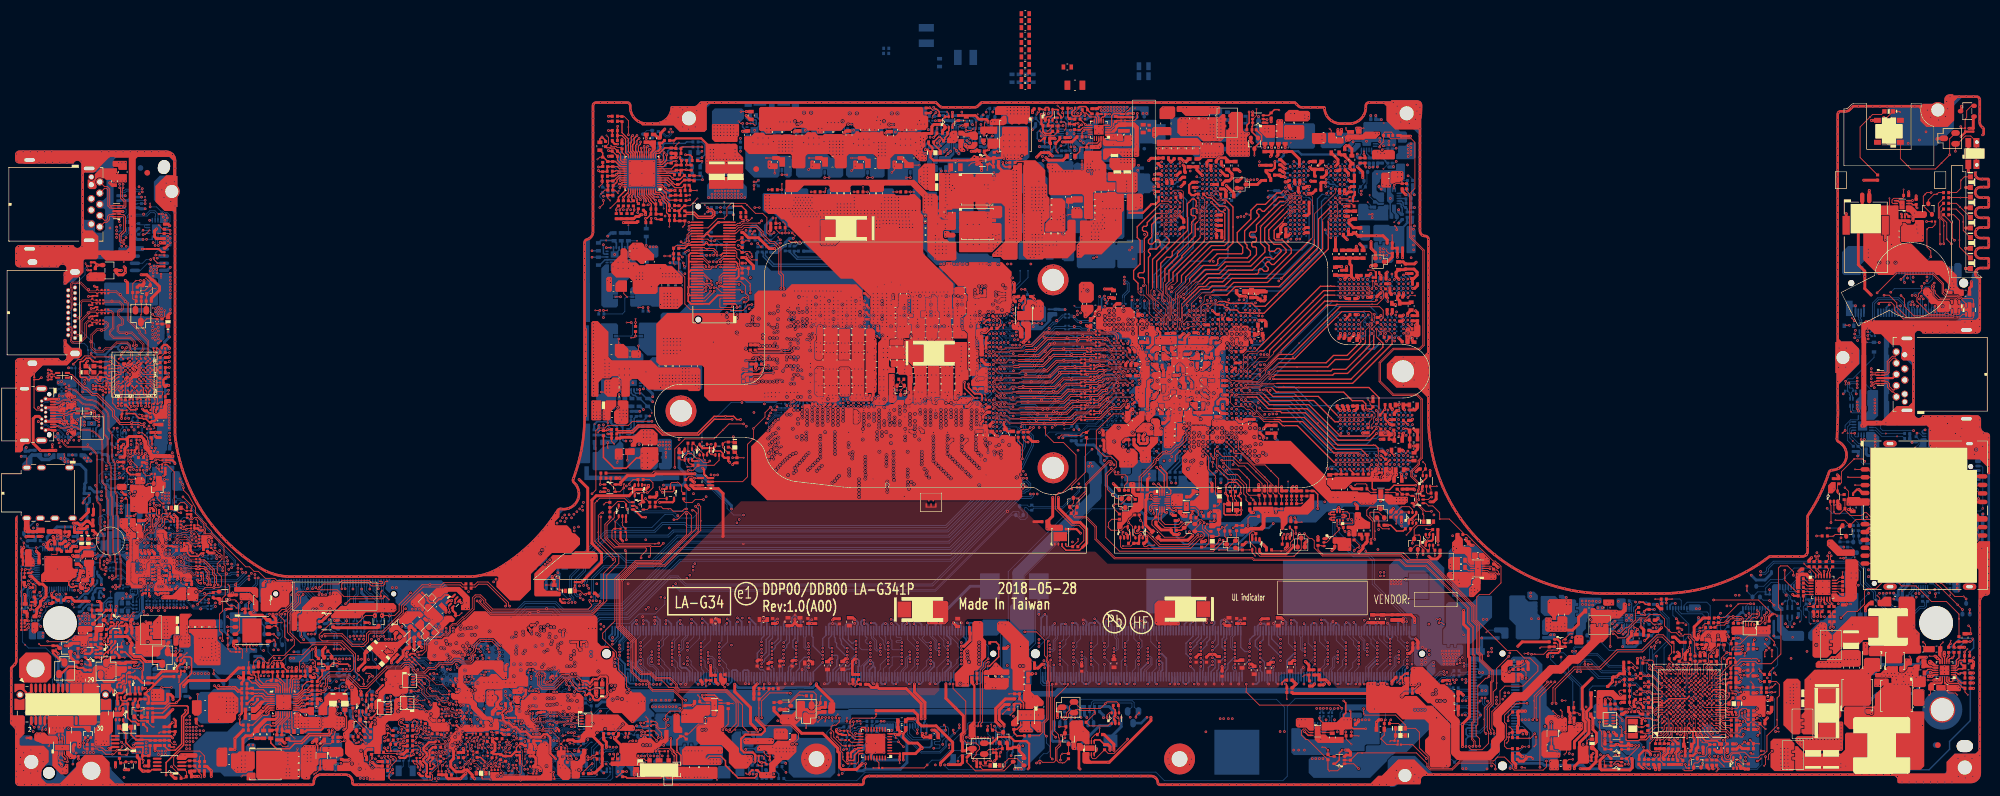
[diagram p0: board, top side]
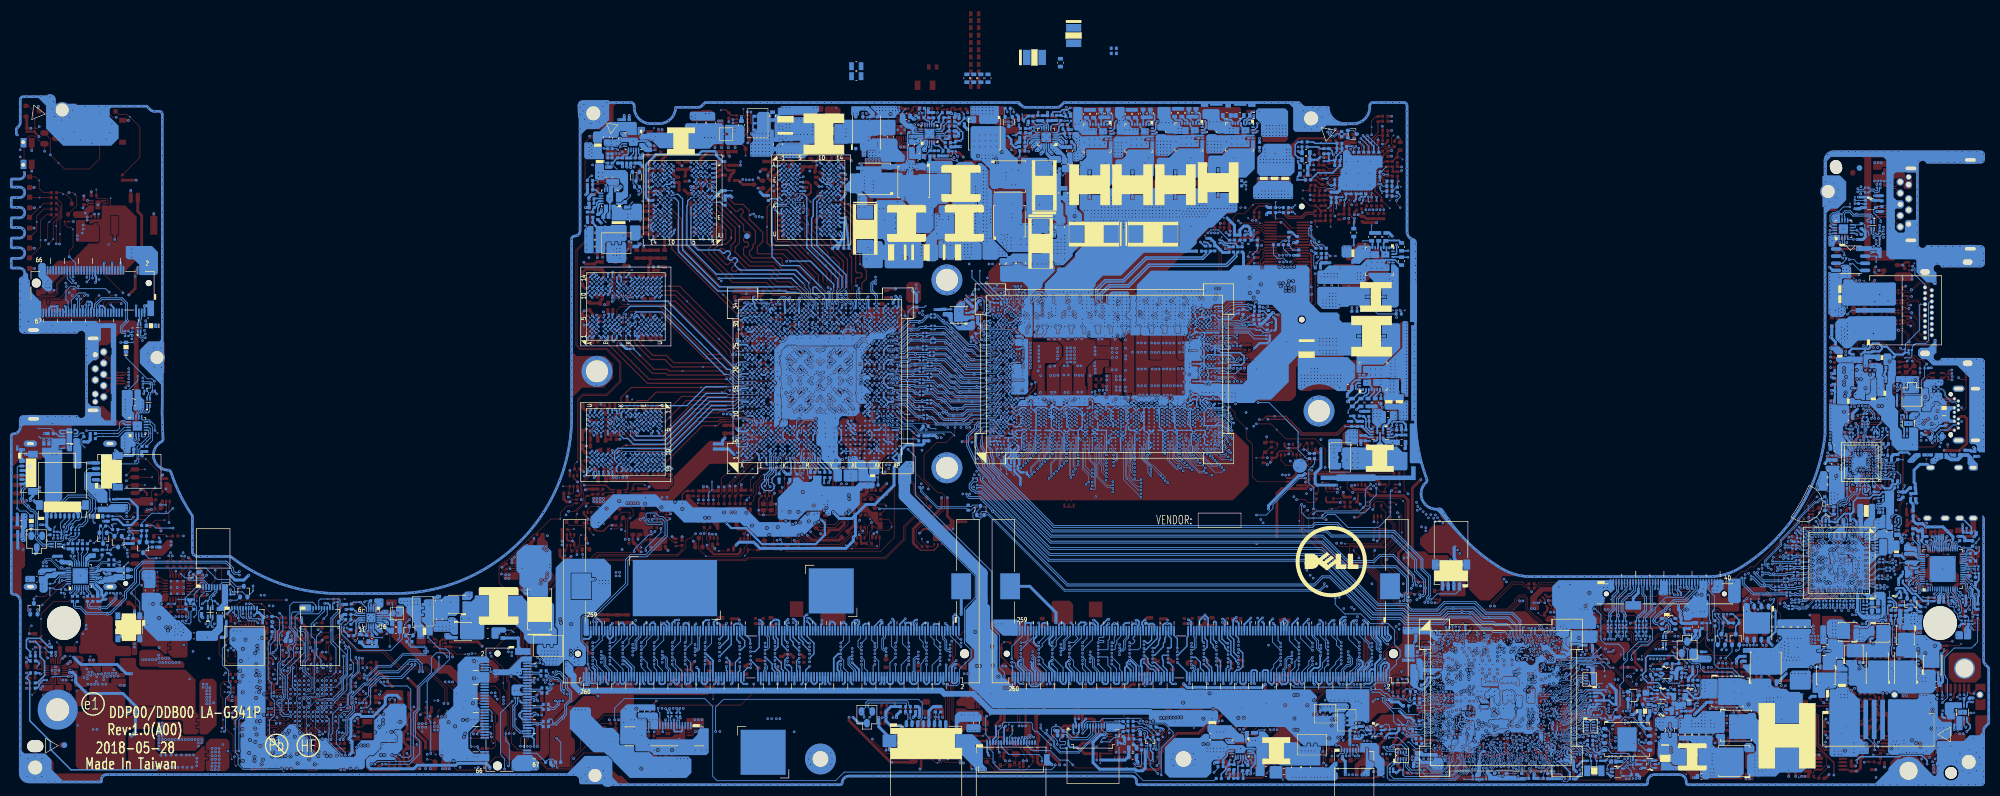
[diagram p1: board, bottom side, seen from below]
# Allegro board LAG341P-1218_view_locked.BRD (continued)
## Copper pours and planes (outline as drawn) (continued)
N128727995 on BOTTOM (solid shape): 191.95,186.45 191.95,185.06 190.8,183.91 190.17,183.91 189.85,183.6 189.85,182.96 189.74,182.85 188.68,182.85 188.68,182.86 187.81,182.86 187.76,182.91 187.76,183.05 187.82,183.11 188.7,183.11 188.78,183.19 188.94,183.19 188.95,183.19 189.39,183.47 189.08,183.89 189.04,183.89 189.04,184.22 189.08,184.26 189.18,184.26 189.55,184.33 189.65,184.69 189.76,184.8 190.47,184.8 190.93,185.26 190.93,186.33 191.19,186.58 191.82,186.58
N128958713 on TOP (solid shape): 228.24,184.3 228.24,182.24 227.95,181.95 224.78,181.95 224.64,182.08 224.64,184.28 224.86,184.5 228.04,184.5
N128958713 on BOTTOM (solid shape): 230.17,184.55 230.17,180.61 229.86,180.29 225.81,180.29 224.98,181.12 223.57,181.12 223.25,181.44 223.25,184.38 223.7,184.83 229.9,184.83
N135676155 on BOTTOM (solid shape): 238.3,181.21 238.3,180.74 237.29,179.72 236.12,179.72 236.03,179.81 236.03,180.37 236.17,180.51 236.7,180.51 237.26,181.07 237.26,181.22 237.36,181.32 238.19,181.32
N135689304 on BOTTOM (solid shape): 244.58,170.27 244.58,168.95 245.05,168.48 245.05,167.91 244.95,167.81 244.42,167.81 244.33,167.9 244.33,168.59 243.85,169.07 243.85,170.26 243.94,170.35 244.51,170.35
N135767755 on BOTTOM (solid shape): 14.32,98.32 14.32,96.91 14.47,96.76 14.47,95.85 14.21,95.6 14.21,95.4 14.21,95.35 14.21,94.86 14.11,94.76 13.86,94.76 13.76,94.86 13.76,95.51 13.56,95.71 13.56,98.33 13.65,98.42 14.22,98.42
N135770638 on BOTTOM (solid shape): 54.03,87.79 54.03,87.48 54.17,87.35 54.84,87.35 54.95,87.23 54.95,86.95 54.8,86.79 54.37,86.79 54.12,86.54 54.12,85.81 54.05,85.74 53.53,85.74 53.47,85.81 53.47,86.52 53.4,86.59 53.4,87.28 53.2,87.48 52.64,87.48 52.59,87.53 52.59,88.15 52.65,88.2 53.62,88.2
N135770664 on BOTTOM (solid shape): 55.15,80.76 55.78,80.76 55.89,80.65 55.89,80.38 55.8,80.29 55.1,80.29 54.95,80.14 54.95,79.57 54.88,79.51 54.36,79.51 54.27,79.6 54.27,80.18 54.14,80.31 54.14,80.96 54.23,81.05 54.85,81.05
N135770666 on BOTTOM (solid shape): 55.56,83.42 55.56,83.16 55.43,83.03 54.83,83.03 54.64,82.84 54.64,82.24 54.55,82.15 53.96,82.15 53.8,82.3 53.8,83.41 53.87,83.48 54.44,83.48 54.5,83.54 55.44,83.54
N135772460 on BOTTOM (solid shape): 52.69,83.32 52.69,82.18 52.63,82.12 52.08,82.12 51.92,81.95 51.92,81.32 51.84,81.24 51.12,81.24 51.05,81.3 51.05,82.08 51.7,82.72 51.7,83.22 51.94,83.46 52.55,83.46
N140286428 on TOP (solid shape): 77.11,96.66 77.11,96.39 76.79,96.07 76.21,96.07 75.43,95.29 75.42,95.28 75.33,95.22 75.27,95.13 75.27,95.13 75.12,94.98 75.12,94.78 75,94.66 74.97,94.68 74.59,94.61 74.53,94.24 74.55,94.2 74.05,93.7 73.23,93.7 72.97,93.96 72.97,94.3 73.3,94.63 73.41,94.64 73.51,94.69 73.59,94.7 73.65,94.66 74,94.54 74.24,94.83 74.28,94.9 74.34,94.92 74.67,95.21 74.44,95.57 74.44,95.87 75.19,96.63 75.19,96.97 75.43,97.21 76.56,97.21
N140286576 on TOP (solid shape): 71.55,97.41 71.55,97.29 71.1,96.84 70.75,96.84 70.44,97.15 69.45,96.16 69.53,96.08 69.55,95.97 69.46,95.9 69,95.9 68.82,95.72 67.42,95.72 67.16,95.98 67.16,96.6 68.15,97.58 68.15,97.69 68.44,97.99 70.98,97.99
N140286584 on TOP (solid shape): 72.56,99.24 72.81,99.24 75.06,96.98 75.06,96.68 74.38,96 74,96 73.77,95.76 73.75,95.76 73.55,95.67 73.46,95.47 73.46,95.45 73.3,95.29 73.28,95.29 73.1,95.2 73,95.01 73,95 72.63,94.63 72.32,94.63 72.01,94.94 72.01,95.43 72.44,95.86 72.44,96.05 72.48,96.05 72.79,96.47 72.41,96.81 72.3,96.81 71.68,97.44 71.68,97.59 71.53,97.73 71.53,97.78 71.82,98.07 71.82,99.04 72.09,99.31 72.49,99.31
N140286634 on TOP (solid shape): 71.86,100.22 71.86,99.48 71.68,99.3 71.68,98.17 71.4,97.9 71.37,97.9 71.1,98.16 71.12,98.19 71.04,98.63 70.59,98.65 70.39,98.65 70.18,98.72 69.97,98.66 69.96,98.65 69.86,98.65 69.27,99.23 69.27,99.77 70.68,101.18 70.9,101.18

Small or netless copper shapes (teardrops, artwork): 84 on TOP, 42 on BOTTOM
